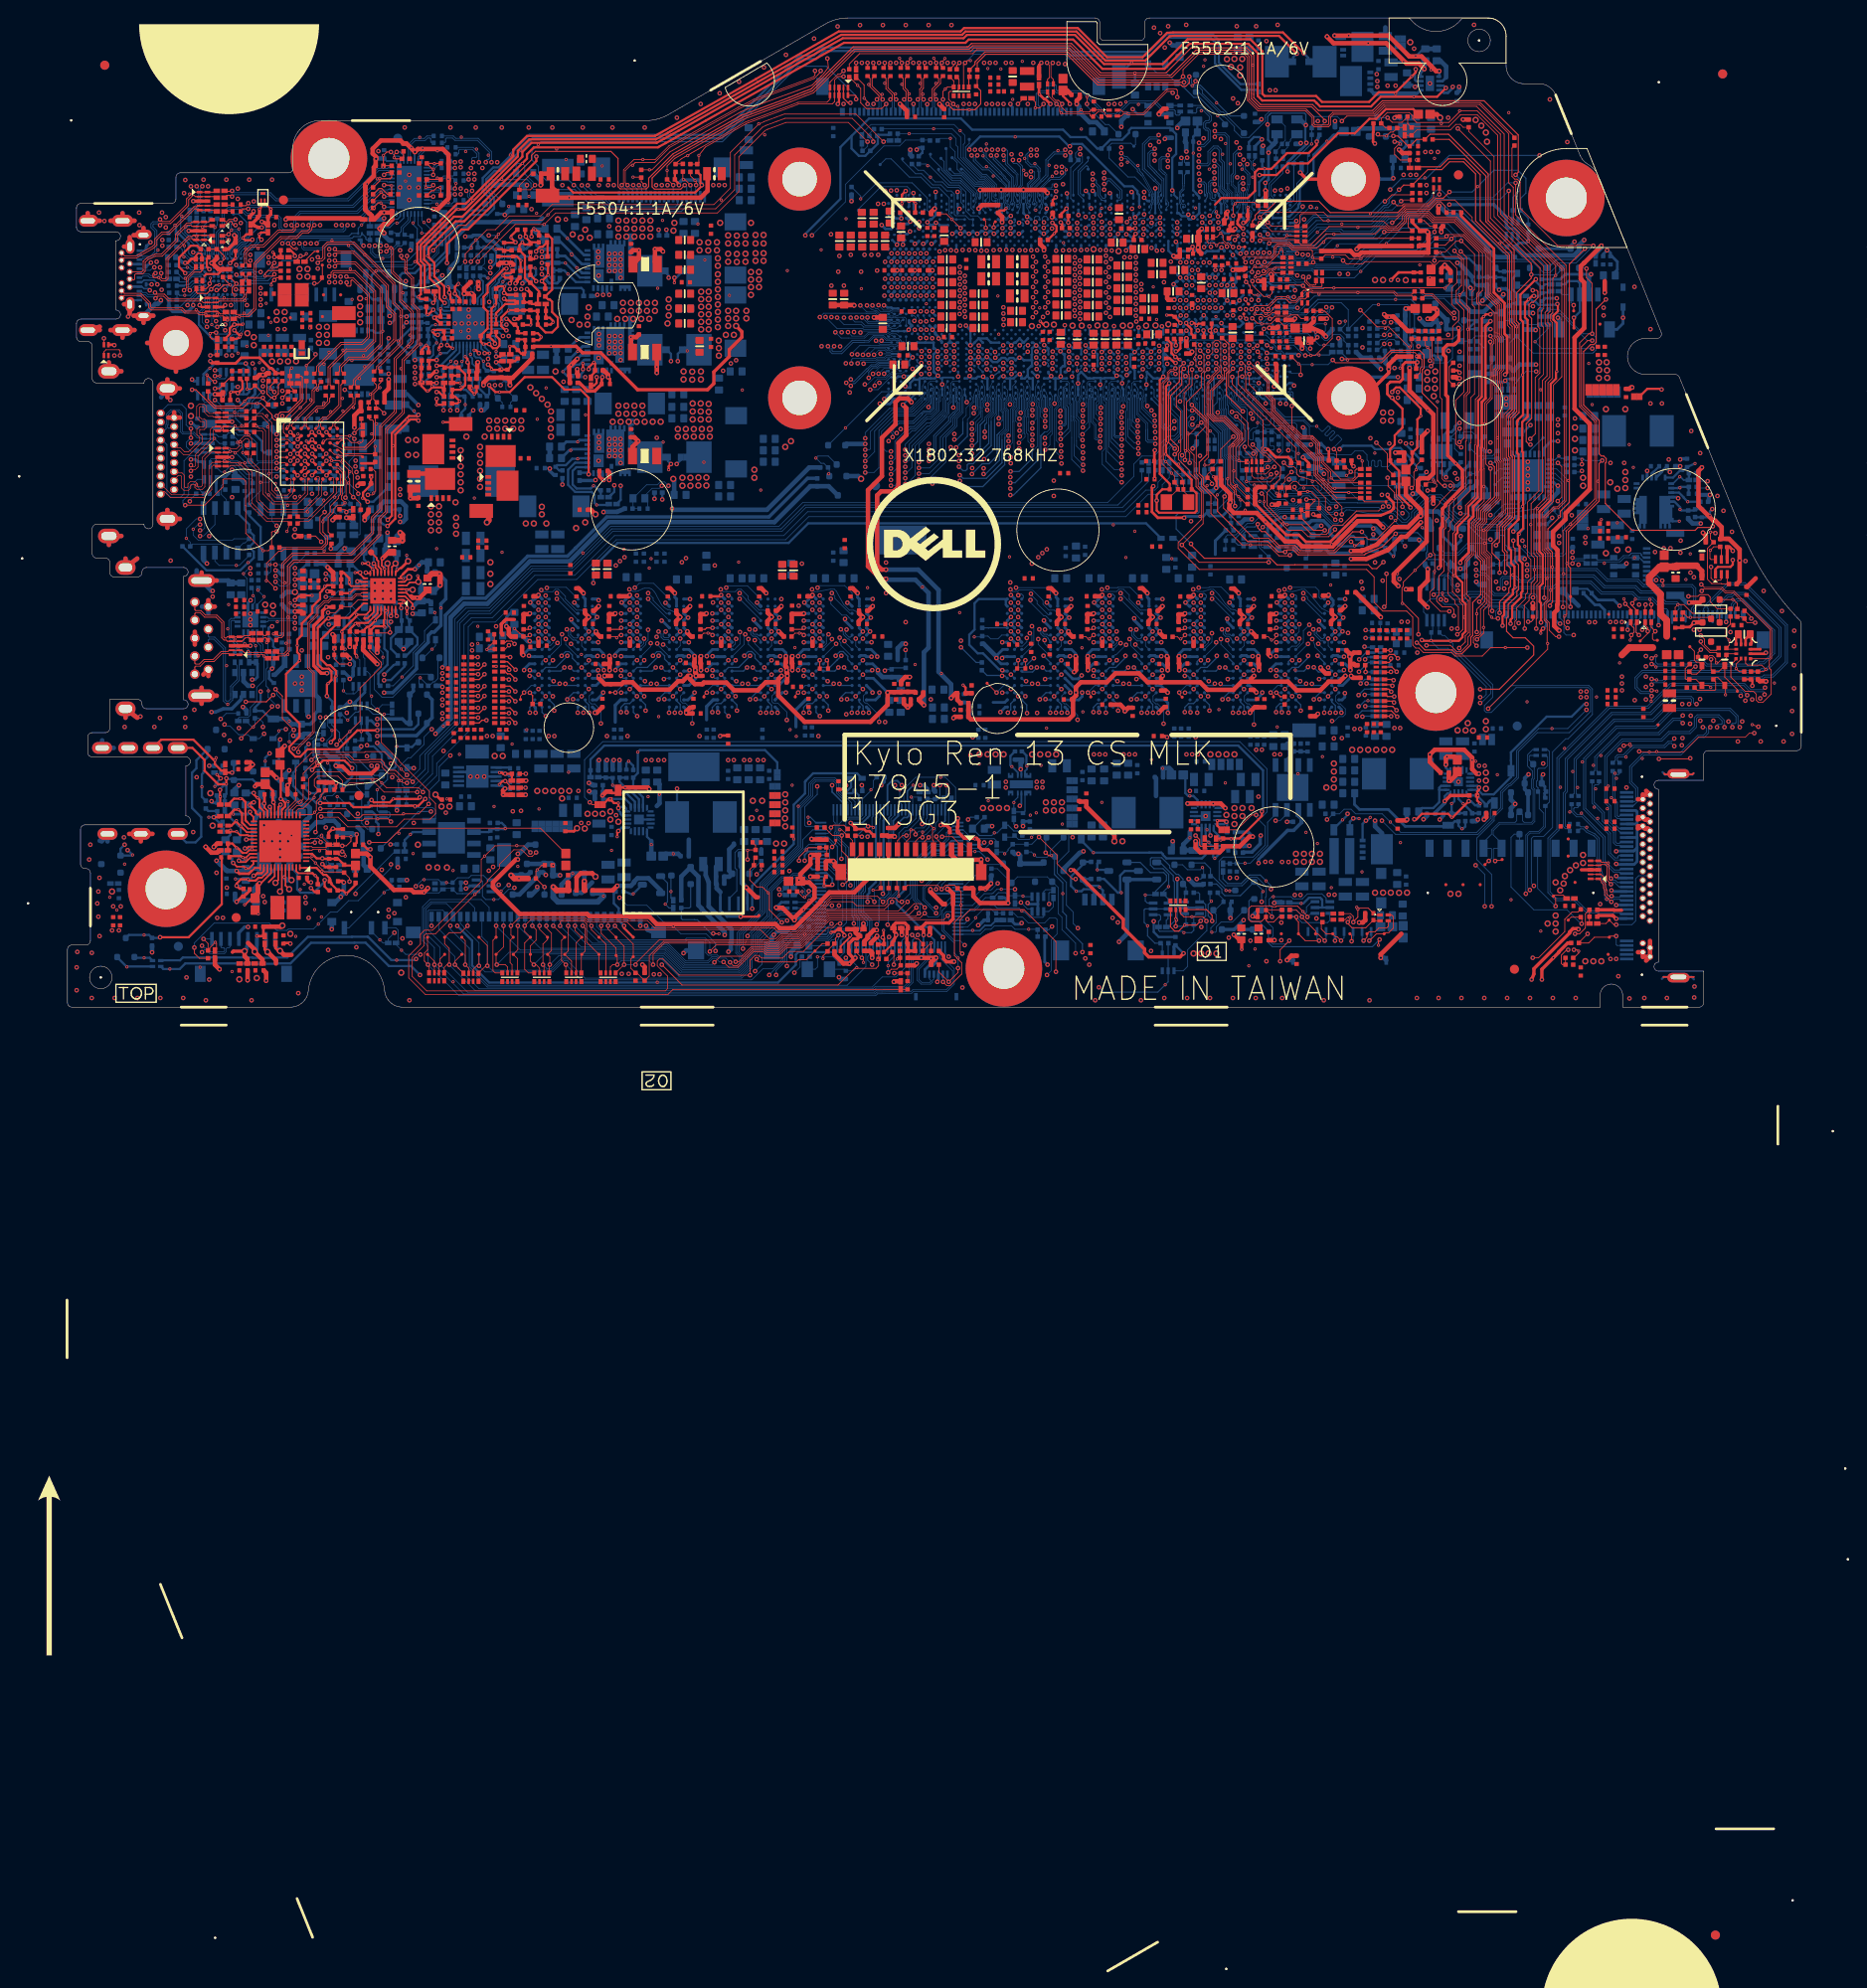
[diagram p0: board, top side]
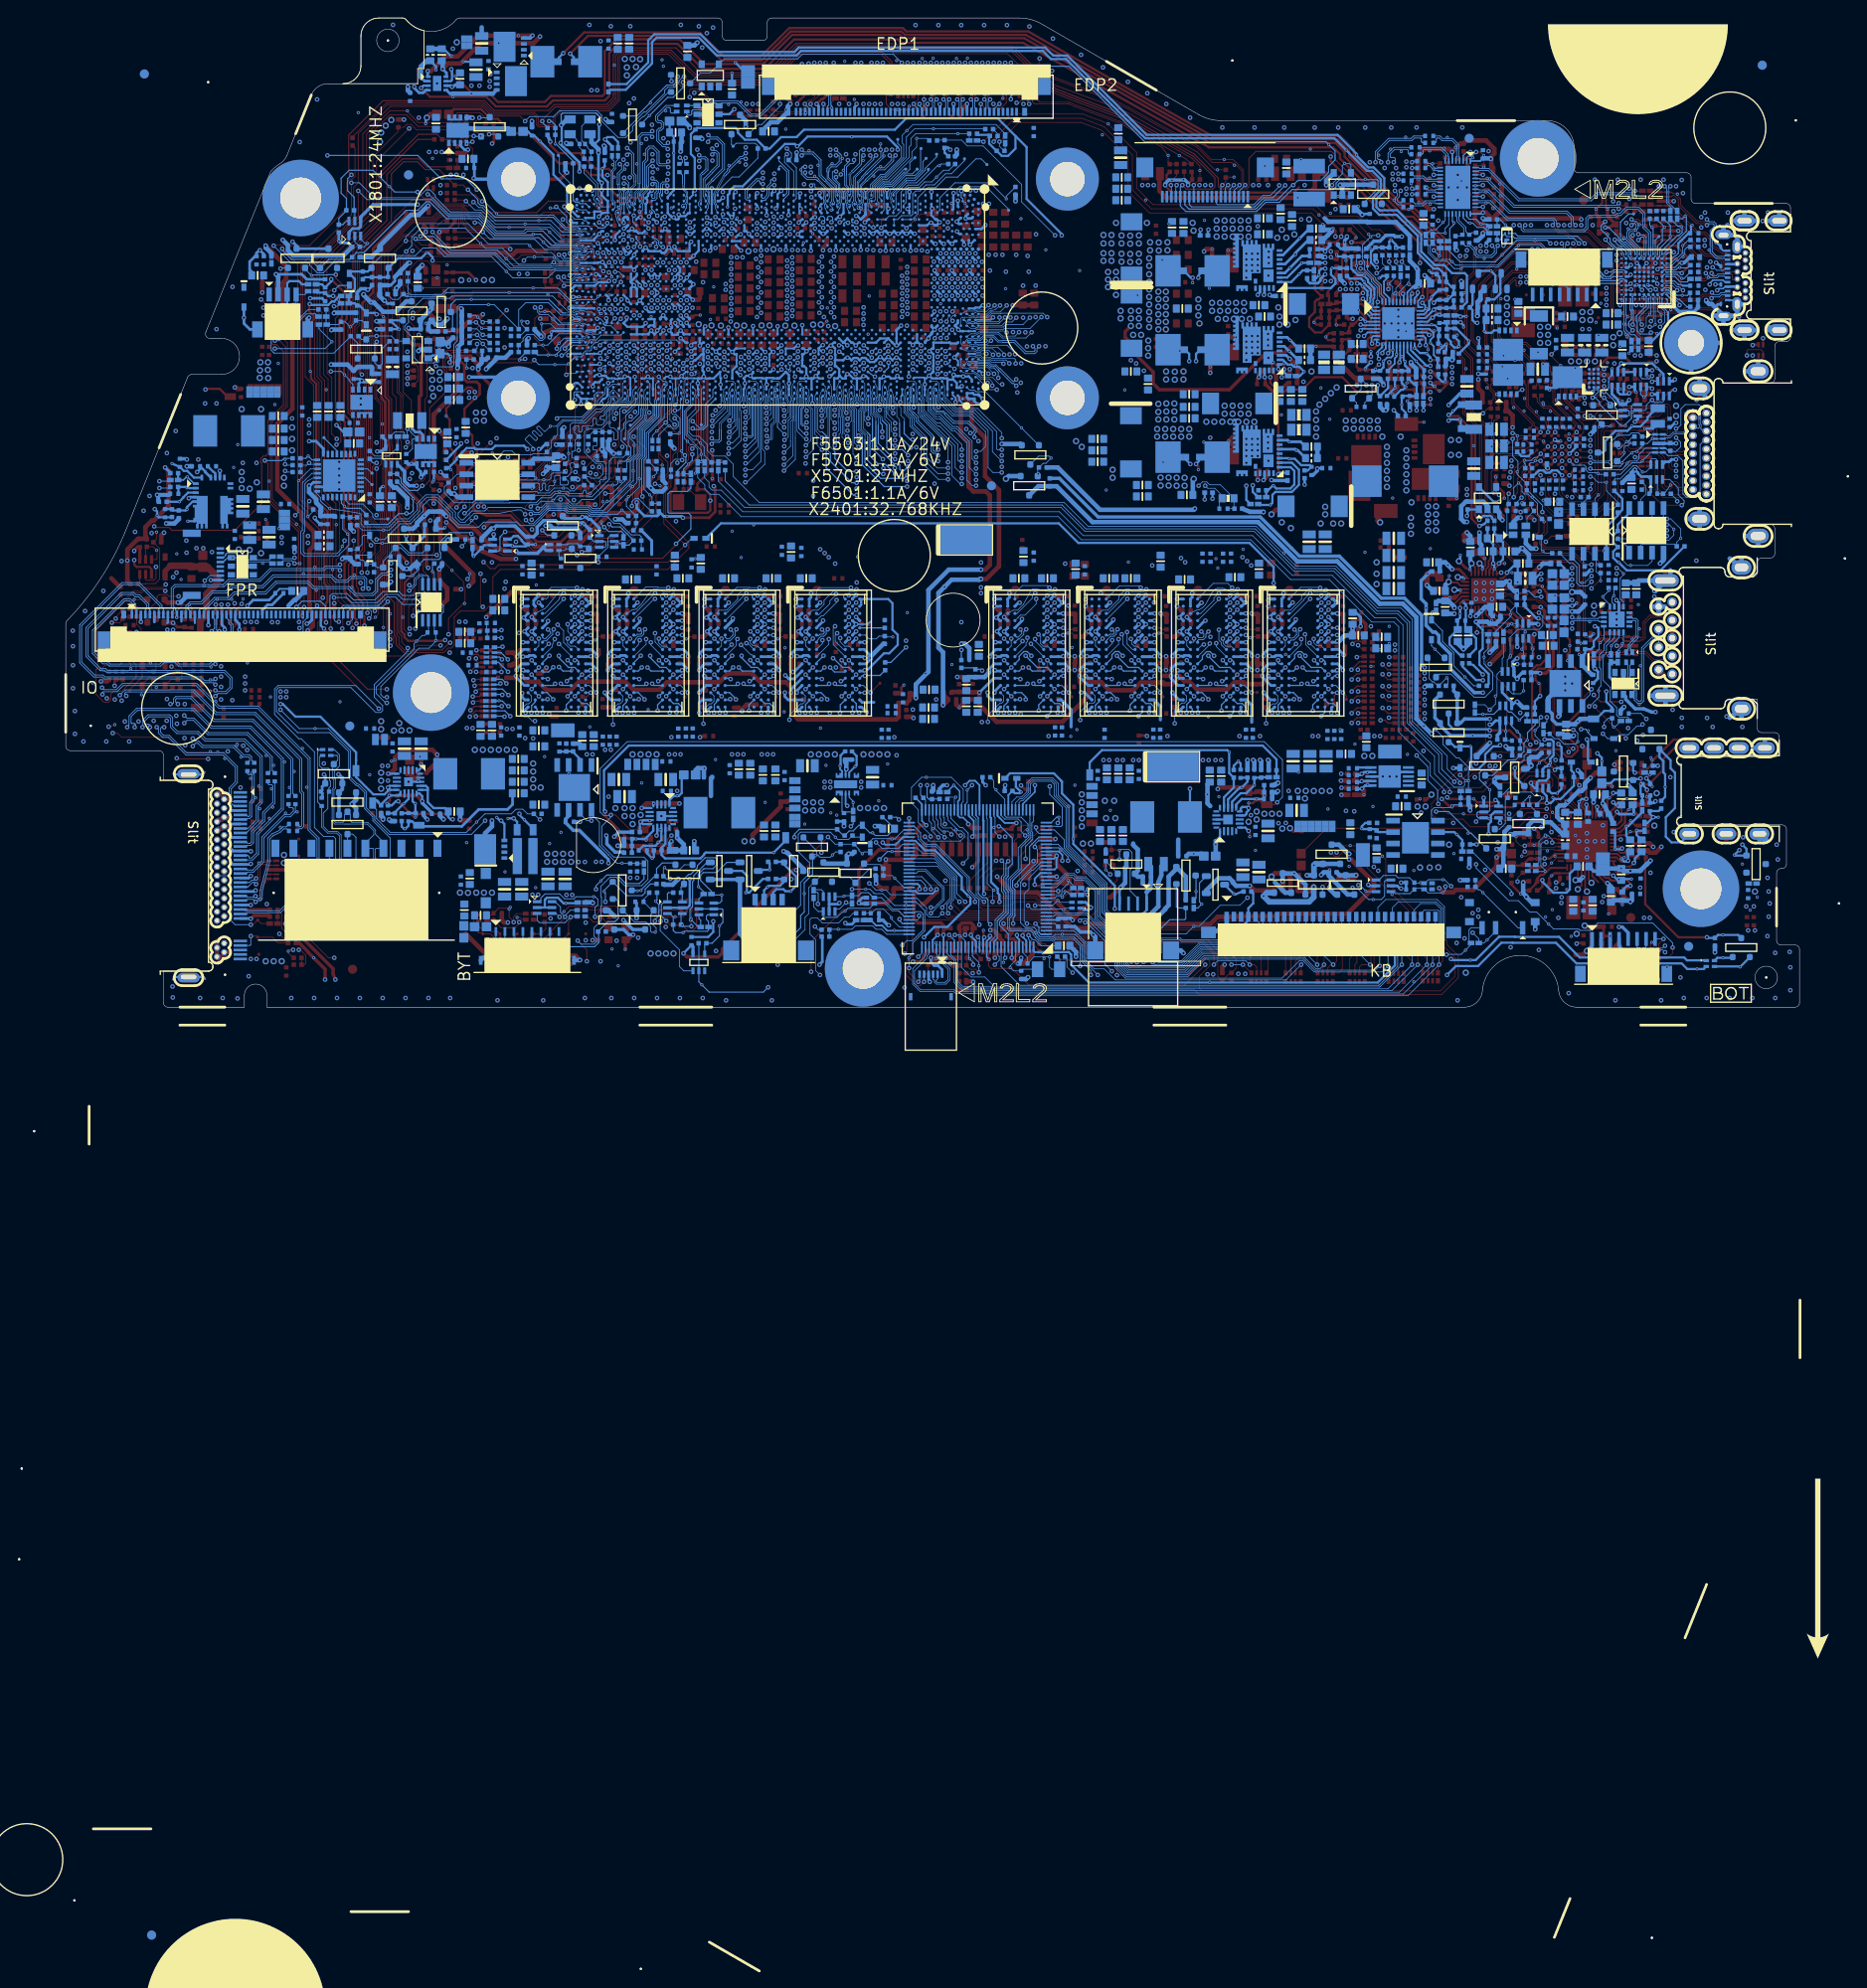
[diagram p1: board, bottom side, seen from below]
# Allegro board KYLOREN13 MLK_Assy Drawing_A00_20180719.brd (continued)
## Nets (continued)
3D3V_S0: C2601.1 C2602.1 C4005.1 C5748.1 D5702.A D9201.A DB1.10 F5502.1 F5504.1 L5701.1 PR4609.1 Q2414.G Q2601.2 Q2601.5 R402.1 R507.1 R1606.2 R1608.2 R1718.1 R1818.2 R1820.1 R2005.1 R2010.1 R2035.1 R2038.1 R2043.1 R2044.1 R2045.1 R2046.1 R2048.1 R2049.1 R2053.1 R2107.1 R2109.1 R2110.1 R2430.1 R2489.1 R2603.1 R2604.1 R2609.1 R2749.1 R2751.1 R2914.1 R4005.1 R5504.1 R5505.2 R5509.1 R5515.1 R5517.1 R5518.1 R5752.2 R6113.1 R6302.1 R6305.1 R6306.1 R6405.1 R6502.1 R7001.1 R9127.1 R9211.1 RN401.1(A) RN401.2(A) RN403.1(A) RN403.2(A) RN1602.3(B) RN1602.4(B) RN1802.1(A) RN1802.2(A) RN1813.1(A) RN1813.2(A) RN1813.3(A) RN1813.4(A) RN2007.3(B) RN2007.4(B) RN2008.3(B) RN2008.4(B) RN2602.1(A) RN2602.2(A) RN2703.1(A) RN2703.2(A) U2601.1 U4001.13 U4001.14
3D3V_S5: AFTP6607.1 C2416.1 C2421.1 C5502.1 C6102.1 C6103.1 C6502.1 C6702.1 C7208.1 D4302.2 EC8921.1 EC8922.1 EC8923.1 EC8924.1 EC8925.1 EC8926.1 ED4304.2 ED4305.2 ED4306.2 FC8938.1 FC8940.1 FC8941.1 FC8942.1 FC8943.1 G5701.2 HALL1.3 IOBD1.38 IOBD1.39 L7101.1 PC5110.1 PC5303.1 PC5314.1 PG4507.2 PG4508.2 PG4509.2 PG4520.2 PG4521.2 PG4526.2 PR4435.1 PR4450.2 PR4472.1 PR4479.1 PR4486.2 PR5104.1 PR5208.1 PR5302.1 PR5310.1 PU5101.15 PU5301.5 PU5301.9 PU5303.5 PU5303.9 Q2416.2 Q2416.5 Q6101.S Q6502.S R506.1 R1703.1 R1910.1 R2003.1 R2050.1 R2406.2 R2416.2 R2434.1 R2442.1 R2446.1 R2456.2 R2465.1 R2496.2 R2514.1 R2520.1 R2522.1 R2607.1 R4004.1 R4031.1 R4042.1 R4304.1 R4378.1 R6101.1 R6111.1 R7215.2 R7224.1 R7243.1 R7424.1 R7427.1 R9126.1 R9143.1 RN2405.5(B) RN2405.6(B) RN2405.7(B) RN2405.8(B) RN7206.1(A) RN7206.2(A) U2502.5 U4001.1 U4001.2 U4008.5 U4302.2 U5501.5 U7201.B1 U7201.H1
3D3V_S5_KBC: C2410.1 C2411.1 C2412.1 C2413.1 C2414.1 C2420.1 C2422.1 C2429.1 DB3.1 EC2402.1 EC2403.1 Q2417.2 Q2417.5 R2407.2 R2414.1 R2415.2 R2424.1 R2443.1 R2446.2 R2452.2 R2480.1 R2608.1 R4032.1 RN2402.1(A) RN2402.2(A) RN2403.1(A) RN2403.2(A) RN2403.3(A) RN2403.4(A) RN2404.1(A) RN2404.2(A) RN2404.3(A) RN2404.4(A) RN2409.1(A) RN2409.2(A) RN2409.3(A) RN2409.4(A) RN2410.1(A) RN2410.2(A) RN2410.3(A) RN2410.4(A) RN2411.1(A) RN2411.2(A) RN2411.3(A) RN2411.4(A) RN2412.1(A) RN2412.2(A) RN2412.3(A) RN2412.4(A) RN2413.1(A) RN2413.2(A) U2401.5 U2401.19 U2401.22 U2401.43 U2401.65 U2401.82 U2401.103 U2401.115
3D3V_S5_PCH: BIOS1.8 C2501.1 C2502.1 R303.1 R405.1 R406.1 R1103.1 R1502.1 R1504.1 R1506.1 R1508.1 R1510.1 R1522.1 R1526.1 R1551.1 R1554.1 R1801.2 R2041.1 R2516.2 R2519.1 R2522.2 R9148.1 R9805.1 RN1601.1(A) RN1601.2(A) RN1601.3(A) RN1601.4(A) RN1807.1(A) RN1807.2(A) RN1807.3(A) RN1807.4(A) RN1811.3(B) RN1811.4(B)
3D3V_SEN_S0: C5515.1 EC5506.1 F5504.2 R5515.2 TCBD1.1
3D3V_SSD: AFTP6304.1 C6304.1 C6305.1 C6306.1 C6307.1 C6308.1 C6317.1 C6318.1 R6302.2 R6303.1 R6306.2 R6307.1 SSD1.2 SSD1.4 SSD1.12 SSD1.14 SSD1.16 SSD1.18 SSD1.70 SSD1.72 SSD1.74
3D3V_TBT: C7210.1 U7201.H2
3D3V_TP_VDD: AFTP6531.1 C6505.1 Q6502.D R6502.2 R6503.1 R6511.1 RN6501.1(A) RN6501.2(A) RN6503.1(A) RN6503.2(A) TP1.8
3D3V_TPAN_VDD: C5516.1 C5517.1 C5518.1 R5508.2 TCBD1.20
3D3V_TPM_VHIO: C9109.1 C9112.1 C9113.1 R9126.2 R9127.2 R9140.1 R9149.2 U9102.8 U9102.22
3D3V_TPM_VSB: C9106.1 C9108.1 R9143.2 U9102.1
3D3V_VCCDSW: C2224.1 CPU1.BR24 CPU1.BT23 R1519.1 R1524.1 R1707.1 R1721.1 R2516.1 RN1701.1(A) RN1701.2(A) U2502.1
3D3V_VCCPRIM: C1113.1 C1123.1 C2202.1 C2203.1 C2204.1 C2205.1 C2206.1 C2207.1 CPU1.BP23 CPU1.BT20 CPU1.BV23 CPU1.BW23 CPU1.CB16 CPU1.CB22 CPU1.CB23 CPU1.CC22 CPU1.CC23 CPU1.CD22 CPU1.CD23 CPU1.CP29 R1103.2 R1701.1 R1731.1
3D3V_VCCPRTC: C2221.1 C2222.1 CPU1.BR23 R2204.2
3D3V_WLAN: AFTP6113.1 C6101.1 C6104.1 C6105.1 C6106.1 FC6101.1 IOBD1.32 IOBD1.33 IOBD1.34 IOBD1.35 IOBD1.36 Q6101.D R6101.2 R6106.1 R6109.1 R6113.2
65982D_BUSPWR: R7204.2 R7236.1 U7201.F10
65982D_DBG_CTL1: RN7202.2(A) U7201.E4
65982D_DBG_CTL2: RN7202.1(A) U7201.D5
65982D_DEBUG1: R7220.2 U7201.L2
65982D_DEBUG2: R7221.2 U7201.K2
65982D_DIG_AUD_N: R7241.2 U7201.K3
65982D_DIG_AUD_P: R7242.2 U7201.L3
65982D_GND: C7212.2 U7201.H7
65982D_GPIO2: R7231.2 U7201.D10
65982D_GPIO3: R7208.2 U7201.G11
65982D_GPIO5: R7213.2 U7201.E10
65982D_GPIO8: R7222.2 R7223.1 U7201.H6
65982D_HPD_CON: R7227.2 U7201.C10
65982D_HRESET: R7202.1 U7201.D6
65982D_I2C_ADDR: R7201.2 U7201.F1
65982D_LDO_1V8A: C7203.2 U7201.K1
65982D_LDO_1V8D: C7202.2 U7201.A2
65982D_LDO_BMC: C7201.2 U7201.E1
65982D_LSRX: TP7202.1 U7201.K4
65982D_LSTX: R7237.2 U7201.L4
65982D_MRESET: R7214.2 U7201.E11
65982D_RESET_N: R7229.1 U7201.F11
65982D_ROSC: R7206.1 U7201.G2
65982D_SBU1_R: TP7203.1 U7201.K8
65982D_SBU2_R: TP7204.1 U7201.L8
65982D_UART_RX: R7244.2 U7201.E2 U7201.F2
+DC_IN: C4301.1 C4302.1 EL4301.2 EL4302.2 PU4301.1 PU4301.2 PU4301.3 Q4305.2 R4307.1 R4376.1
+DC_IN_C: AFTP4303.1 AFTP4305.1 AFTP4316.1 D4301.K DCIN1.6 DCIN1.7 DCIN1.8 EC4301.1 EC4302.1 EC4312.1 EC4313.1 EL4301.1 EL4302.1
+RTC_VCC: D2501.2 IOBD1.41 Q2505.G R2504.1
+SDC_IN: C4343.1 C7401.1 PC4401.1 PG4401.1 PR4401.1 PU4302.1 PU4302.2 PU4302.3 PU4401.16 Q4348.S Q7401.S R4318.1 R4370.1 R7404.1 R7406.1 R7411.1 U7418.1 U7418.2 U7418.3
+SDC_IN_SW: C4343.2 PU4302.4 R4318.2 R4333.1 R4368.1
+SDC_IN_SW_R1: Q4349.6 R4333.2
+V_VREF_PATH1: C1202.2 R1203.1
+V_VREF_PATH2: C1302.2 R1303.1
A_ZQ_RAM1: R1205.1 RAM1.F9
A_ZQ_RAM2: R1234.1 RAM2.F9
A_ZQ_RAM3: R1204.1 RAM3.F9
A_ZQ_RAM4: R1201.1 RAM4.F9
AC_DIS: Q4304.B Q4349.5 R4303.1 U2401.69
AC_IN#: D1701.K D4305.K PQ4415.6
AC_IN#_G: R4376.2 R4377.1 U4302.5
AC_PRESENT: CPU1.BU35 D1701.A EC1707.1 Q1702.6 RN1701.4(B)
ACOK#: PQ4415.2 PQ4415.3 PR4427.2
AD_IA: PC4432.1 PR4412.2 R2421.2 R2423.1
AD_OFF_L: Q4304.C Q4305.1
AD_OFF_R: C4301.2 PU4301.4 Q4305.3 R4307.2 R4308.1
ALERT#: R2603.2 U2601.6
ALWON: R4009.2 U2401.121
AMBER_LED_BAT: Q6402.C R6401.1
AUD_AGND: C2721.2 C2727.2 C2730.2 C2731.2 C2734.2 C2735.2 C2737.2 C2740.2 C2741.2 C2909.2 EC2709.1 EC2710.1 EC2711.1 EC2712.1 EC2713.1 EC2714.1 EC2905.2 EC2906.2 EC2907.2 EC2908.2 HPMIC1.MS R2739.1 R2747.2 R2905.2 U2701.22 U2701.37
AUD_HP1_JACK_L1: EC2907.1 R2907.2 R2911.1 R2922.2
AUD_HP1_JACK_L1_R: ED2903.2 HPMIC1.1 R2911.2
AUD_HP1_JACK_R1: EC2908.1 R2909.2 R2912.1 R2921.2
AUD_HP1_JACK_R1_R: ED2901.1 HPMIC1.2 R2912.2
AUD_HPJD_N: C2909.1 R2741.1 R2923.2
AUD_HPOUT_L: R2907.1 U2701.27
AUD_HPOUT_R: R2909.1 U2701.26
AUD_PC_BEEP_C: C2726.1 D2702.3 R2745.1
AUD_PC_BEEP_R: C2726.2 U2701.34
AUD_RING: R2908.1 RN2901.3(B) U2701.30
AUD_SELEEVE: R2910.1 RN2901.4(B) U2701.31
AUD_SENSE_A: C2746.1 R2741.2 R2742.2 U2701.48
AUD_SPK_L+: EC2904.1 ER2901.1 U2701.42
AUD_SPK_L+_C: AFTP2902.1 ER2901.2 SPK1.1
AUD_SPK_L-: EC2903.1 ER2902.1 U2701.43
AUD_SPK_L-_C: AFTP2901.1 ER2902.2 SPK1.2
AUD_SPK_R+: EC2902.1 ER2903.1 U2701.45
AUD_SPK_R+_C: AFTP2904.1 ER2903.2 SPK1.3
AUD_SPK_R-: EC2901.1 ER2904.1 U2701.44
AUD_SPK_R-_C: AFTP2903.1 ER2904.2 SPK1.4
AUD_VREF: C2737.1 U2701.38
AUDIO_47: R2744.2 U2701.47
AUX_EN_WOWL: CPU1.BT30 R2405.2 R6110.1
AUX_EN_WOWL_R: Q6102.G R6110.2
AUX_MODE: R2728.2 R2754.2 U2701.33
B_ZQ_RAM1: R1304.1 RAM5.F9
B_ZQ_RAM2: R1301.1 RAM6.F9
B_ZQ_RAM3: R1306.1 RAM7.F9
B_ZQ_RAM4: R1305.1 RAM8.F9
BAT1_LED#: Q2416.4 R2498.2 RN2405.2(A) U2401.106
BAT2_LED#: Q2416.1 R2495.1 RN2405.1(A) U2401.1
BAT_AMBER: ED6401.2 LED1.2 R6401.2
BAT_WHITE: ED6401.1 LED1.3 R6402.2
BATT_WHITE_LED#: Q2416.6 Q6403.D Q6404.4 R2495.2 R6422.2
BATT_WHITE_LED_R#: Q6401.B Q6404.3 R6422.1
BEEP: RN2702.1(A) U2401.45
BKLT_CTRL: D5502.3 R5502.1 R5545.2 RN5502.5(B)
BKLT_IN_EC: R2440.1 U2401.67
BLON_OUT_C: LCD1.23 R5544.1 RN5502.7(B)
BLUETOOTH_EN: AFTP6112.1 CPU1.CP14 D6101.K IOBD1.48 R2109.2 R6107.2
BLUETOOTH_EN_R: D6101.A R6106.2 R6107.1
BOARD_ID: C2408.1 R2443.2 R2444.1 R2494.1 U2401.111
BOARD_ID1: CPU1.CG12 R2009.1 R2010.2
BOARD_ID2: CPU1.CM14 R2005.2 R2008.1
BPM_CPU_N0: CPU1.U1 TP302.1
BPM_CPU_N1: CPU1.U2 TP303.1
BPM_CPU_N2: CPU1.U3 TP304.1
BPM_CPU_N3: CPU1.U4 TP307.1
BREATH_LED#: IOBD1.43 U2401.70
BT+: AFTP4312.1 AFTP4313.1 AFTP4314.1 BATT1.1 BATT1.2 BATT1.3 D4304.K EC4307.1 EC4308.1 PR4478.2 PR4495.2 PU4412.5 PU4412.6 PU4412.7 PU4412.8
BT_USB20_CON_N: AFTP6111.1 EL6603.4 IOBD1.19
BT_USB20_CON_P: AFTP6114.1 EL6603.1 IOBD1.20
BT_USB20_N: CPU1.CC3 EL6603.3
BT_USB20_P: CPU1.CC4 EL6603.2
CAD_SNK: R7118.2 U7101.29
CAP_LED: AFTP6538.1 KBBD1.4 R6513.2
CAP_LED#: Q2414.S R2489.2 U2401.93
CAP_LED#_R: Q2414.D R6512.1
CAP_LED_Q: Q6505.C R6513.1
CAP_LED_R#: Q6505.B R6512.2
CARD1_USB20_N: CPU1.CG8 IOBD1.17
CARD1_USB20_P: CPU1.CG9 IOBD1.16
CARD_CLKREQ_CPU_N: CPU1.CE31 RN1813.7(B)
CATERR#_CPU: CPU1.AA4 TP301.1
CBN: C2739.1 U2701.24
CBP: C2739.2 U2701.23
CCD_USB20_CON_N: ED5501.6 EL5501.1 LCD1.43
CCD_USB20_CON_P: ED5501.1 EL5501.4 LCD1.42
CCD_USB20_N: CPU1.CC1 EL5501.2
CCD_USB20_P: CPU1.CC2 EL5501.3
CFG3: CPU1.R3 R1517.1
CFG4: CPU1.J4 R1518.1
CFG_RCOMP: CPU1.AB5 R601.2
CHG_AMBER_LED#: Q2416.3 Q6404.1 R2498.1 R6421.1
CHG_AMBER_LED_R#: Q6402.B Q6404.6 R6421.2
CHGR_PSYS_IMVP: PR4413.1 PR4614.1 PU4401.30 PU4601.1
CLK_PCIE_PEG_REQ0_N: CPU1.CF32 RN1813.6(B)
CLK_PCIE_PEG_REQ2_N: CPU1.CF30 RN1802.4(B)
CLK_PCIE_PEG_REQ5_N: CPU1.CF31 RN1813.5(B)
CLK_TP_SIO: EC6501.1 RN6501.4(B) RN6502.1(A) U2401.78
CLKRUN#: CPU1.BY30 R1818.1
CMP_VIN0_R: C2612.1 C2613.1 R2494.2 R2608.2 R2609.2 R2610.1 U2401.20
CMP_VOUT0: R2602.2 R2607.2 R2615.2 U2401.85
CNV_RGI_DT: CPU1.CG19 R1515.2 R1516.1
CNV_WT_RCOMP: CPU1.CP32 CPU1.CR32 R2101.2
CPU_D4_TP: CPU1.CG23 TP1804.1
CPU_D6_TP: CPU1.CG20 TP1806.1
CPU_DP1_CTRL_CLK: CPU1.CC8 RN401.3(B)
CPU_DP1_CTRL_DATA: CPU1.CC9 RN401.4(B)
CPU_DP2_CTRL_CLK: CPU1.CH4 RN403.4(B)
CPU_DP2_CTRL_DATA: CPU1.CH3 RN403.3(B)
CPU_DP_HPD_P: Q401.2 Q401.3 R406.2
CPU_I2C_SCL_ISH: R2020.2 TCBD1.4 U7001.1
CPU_I2C_SCL_ISH0: CPU1.CH20 R2020.1 RN2007.2(A)
CPU_I2C_SCL_ISH1: CPU1.CJ22 RN2008.1(A)
CPU_I2C_SCL_P0: CPU1.CN11 EC6503.1 Q6504.1 R6505.1
CPU_I2C_SCL_P1: CPU1.CJ12 R5517.2 R5521.2 U5504.4 U5504.7
CPU_I2C_SCL_TP: AFTP6534.1 Q6504.6 R6505.2 RN6503.3(B) TP1.6
CPU_I2C_SCL_TS: R5521.1 TCBD1.18
CPU_I2C_SDA_ISH: R2021.2 TCBD1.3 U7001.4
CPU_I2C_SDA_ISH0: CPU1.CK22 R2021.1 RN2007.1(A)
CPU_I2C_SDA_ISH1: CPU1.CH22 RN2008.2(A)
CPU_I2C_SDA_P0: CPU1.CM11 EC6504.1 Q6504.4 R6506.1
CPU_I2C_SDA_P1: CPU1.CK12 R5518.2 R5522.2 U5504.5 U5504.6
CPU_I2C_SDA_TP: AFTP6535.1 Q6504.3 R6506.2 RN6503.4(B) TP1.7
CPU_I2C_SDA_TS: R5522.1 TCBD1.17
CPU_POPIRCOMP: CPU1.BP27 R304.2
CPU_SMB_ALERT#: CPU1.CJ15 R1551.2 R1552.1
CPU_SMB_ALERT#_P0: CPU1.CG15 R1504.2 R1505.1
CPU_SMB_ALERT#_P1: CPU1.CC34 R1555.1 R1801.1
CPU_SMB_SCL: CPU1.CK14 RN1807.7(B)
CPU_SMB_SCL_P0: CPU1.CH14 RN1807.5(B)
CPU_SMB_SCL_P1: CPU1.CN15 Q2601.3 R2459.2 RN1811.2(A)
CPU_SMB_SCL_THM: C2608.1 Q2601.4 RN2602.4(B) U2601.8
CPU_SMB_SDA: CPU1.CH15 RN1807.8(B)
CPU_SMB_SDA_P0: CPU1.CF15 RN1807.6(B)
CPU_SMB_SDA_P1: CPU1.CM15 Q2601.6 R2447.2 RN1811.1(A)
CPU_SMB_SDA_THM: C2609.1 Q2601.1 RN2602.3(B) U2601.7
CPVEE: C2741.1 U2701.25
CTL2: R3406.2 U3401.7
CTL3: R3402.2 U3401.8
DAT_TP_SIO: EC6502.1 RN6501.3(B) RN6502.2(A) U2401.79
DBC_EN_R: LCD1.6 R5503.1
DBC_PANEL_EN: CPU1.CA31 R2043.2 R5503.2
DC_IN_OFF: Q4349.3 R4369.2
DCBATOUT: EC4534.1 EC8908.1 EC8909.1 EC8910.1 EC8911.1 EC8912.1 EC8913.1 EC8914.1 EC8915.1 EC8916.1 EC8917.1 EC8943.1 EC8944.1 EC8945.1 EC8946.1 EC8947.1 EC8948.1 EC8949.1 EC8950.1 F5503.1 FC8906.1 FC8907.1 FC8914.1 FC8916.1 FC8917.1 FC8919.1 FC8920.1 PC4406.1 PC4407.1 PC4408.1 PC4409.1 PC4410.1 PC4411.1 PC4412.1 PC4413.1 PC4414.1 PC4418.1 PC4434.1 PC4437.1 PC4439.1 PD4407.A PG4405.2 PG4501.1 PG4502.1 PG4503.1 PG4504.1 PG4505.1 PG4506.1 PG4515.1 PG4516.1 PG4517.1 PG4518.1 PG5002.2 PG5003.2 PG5105.1 PG5110.1 PG5210.1 PG5212.1 PG5214.1 PL4702.1 PL4703.1 PL4803.1 PL4804.1 PR4407.1 PR4477.2 PR4509.1 PR4511.1 PR4612.1 PT4805.1 PU4401.3 PU4405.5 PU4405.6 PU4405.7 PU4405.8 R5511.1
DCBATOUT_CAMERA: C5521.1 C5522.1 LCD1.49 LCD1.50 R5511.2
DDR_VREF_S3: PC5123.1 PU5102.6
DMIC_SCL_CODEC: C2738.1 FC2701.1 R2721.1 RN5503.4(B)
DMIC_SCL_CODEC_R: R2721.2 U2701.5
DMIC_SCL_CON: EC5504.1 LCD1.46 RN5503.1(A) RN5504.2(A)
DMIC_SCL_PCH: CPU1.CP24 RN5504.3(B)
DMIC_SDA_CODEC: R2738.1 RN5503.3(B)
DMIC_SDA_CODEC_R: R2738.2 U2701.4
DMIC_SDA_CON: EC5503.1 LCD1.47 RN5503.2(A) RN5504.1(A)
DMIC_SDA_PCH: CPU1.CN24 RN5504.4(B)
DP1_AUX_ALS_N: C5741.2 U5701.C8
DP1_AUX_ALS_P: C5740.2 U5701.C7
DP1_AUX_C_N: C5739.2 C5741.1 R5763.1
DP1_AUX_C_P: C5738.2 C5740.1 R5752.1 R5762.1
DP1_AUX_CPU_N: C5739.1 CPU1.AC7
DP1_AUX_CPU_P: C5738.1 CPU1.AC6
DP1_HPD_CPU: Q401.5 R404.2 R7149.2 R7227.1
DP1_HPD_CPU_R: CPU1.CM6 Q401.6 R403.1 R404.1 R405.2
DP2_AUX_C2_N: R7239.2 U7201.J2
DP2_AUX_C2_P: R7238.2 U7201.J1
DP2_AUX_C_N: C7102.1 R7101.2 U7101.25
DP2_AUX_C_P: C7101.1 R7102.2 U7101.24
DP2_AUX_CPU_N: C7102.2 CPU1.AD4
DP2_AUX_CPU_P: C7101.2 CPU1.AD3
DP2_DDI_TX_C_N0: C7113.2 U7101.10
DP2_DDI_TX_C_N1: C7107.2 U7101.13
DP2_DDI_TX_C_N2: C7108.2 U7101.16
DP2_DDI_TX_C_N3: C7110.2 U7101.19
DP2_DDI_TX_C_P0: C7112.2 U7101.9
DP2_DDI_TX_C_P1: C7114.2 U7101.12
DP2_DDI_TX_C_P2: C7109.2 U7101.15
DP2_DDI_TX_C_P3: C7111.2 U7101.18
DP2_DDI_TX_N0: C7113.1 CPU1.AC4
DP2_DDI_TX_N1: C7107.1 CPU1.AC1
DP2_DDI_TX_N2: C7108.1 CPU1.AE4
DP2_DDI_TX_N3: C7110.1 CPU1.AE1
DP2_DDI_TX_P0: C7112.1 CPU1.AC3
DP2_DDI_TX_P1: C7114.1 CPU1.AC2
DP2_DDI_TX_P2: C7109.1 CPU1.AE3
DP2_DDI_TX_P3: C7111.1 CPU1.AE2
DPEQ0_A1: R7171.2 R7172.1 U7101.14
DPEQ1: R7147.2 R7170.1 U7101.2
EC_AGND: C2407.2 C2408.2 C2422.2 C2435.2 C2441.2 R2441.2 R2444.2 R2445.2 U2401.112
EDP_AUX_CON_N: C5511.1 LCD1.8
EDP_AUX_CON_P: C5510.1 LCD1.7
EDP_AUX_CPU_N: C5511.2 CPU1.AH4
EDP_AUX_CPU_P: C5510.2 CPU1.AH3
EDP_HPD_CON: LCD1.21 R5506.1 RN5502.8(B)
EDP_HPD_CPU: CPU1.CM7 R5506.2
EDP_RCOMP_CPU: CPU1.AM6 R401.2
EDP_TX_CON_N0: C5506.1 LCD1.19
EDP_TX_CON_N1: C5501.1 LCD1.16
EDP_TX_CON_N2: C5533.1 LCD1.13
EDP_TX_CON_N3: C5532.1 LCD1.10
EDP_TX_CON_P0: C5509.1 LCD1.20
EDP_TX_CON_P1: C5504.1 LCD1.17
EDP_TX_CON_P2: C5519.1 LCD1.14
EDP_TX_CON_P3: C5531.1 LCD1.11
EDP_TX_CPU_N0: C5506.2 CPU1.AG4
EDP_TX_CPU_N1: C5501.2 CPU1.AG2
EDP_TX_CPU_N2: C5533.2 CPU1.AJ4
EDP_TX_CPU_N3: C5532.2 CPU1.AJ2
EDP_TX_CPU_P0: C5509.2 CPU1.AG3
EDP_TX_CPU_P1: C5504.2 CPU1.AG1
EDP_TX_CPU_P2: C5519.2 CPU1.AJ3
EDP_TX_CPU_P3: C5531.2 CPU1.AJ1
EDP_VDD_EN: CPU1.CG11 D5501.1
EMMC_RCOMP: CPU1.CK15 R2108.1
EQ0: R7142.2 R7143.1 U7101.38
EQ1: R7140.2 R7141.1 U7101.35
ESPI_ALERT#: CPU1.BV28 R1821.2
ESPI_CLK: DB1.2 EC1801.1 R1805.2 U2401.57
ESPI_CPU_CLK_R: CPU1.BV32 R1805.1
ESPI_CPU_IO0: DB1.9 RN1806.1(A) U2401.59
ESPI_CPU_IO0_R: CPU1.CA29 RN1806.8(B)
ESPI_CPU_IO1: DB1.8 RN1806.4(A) U2401.60
ESPI_CPU_IO1_R: CPU1.BY29 RN1806.5(B)
ESPI_CPU_IO2: DB1.7 RN1806.3(A) U2401.61
ESPI_CPU_IO2_R: CPU1.BY27 RN1806.6(B)
ESPI_CPU_IO3: DB1.6 RN1806.2(A) U2401.62
ESPI_CPU_IO3_R: CPU1.BV27 RN1806.7(B)
ESPI_CS#: CPU1.CA28 DB1.5 U2401.58
ESPI_RESET#: CPU1.CA27 DB1.4 U2401.53
EXT_PWR_GATE#: CPU1.CC37 R1731.2
FAN1_PWM: EC2601.1 R2614.1 U2401.47
FAN1_TACH: D2403.A R2430.2 U2401.40
FAN_PWM1_C: AFTP2602.1 FAN1.4 R2614.2
FAN_TACH1: D2403.K EC2602.1 R2613.1
FAN_TACH1_C: AFTP2601.1 FAN1.3 R2613.2
FFS_INT1: CPU1.CG22 R7007.1
FFS_INT2: CPU1.CH12 R2044.2 R7008.1
FP1_USB20_CON_N: ED9202.6 FPR1.3 R9209.2
FP1_USB20_CON_P: ED9202.1 FPR1.4 R9210.2
FP1_USB20_N: CPU1.CG5 R9209.1
FP1_USB20_P: CPU1.CG6 R9210.1
FPR_SCAN#: FPR1.7 R2465.2 U2401.42
GPD11/LANPHYPC: CPU1.BU34 R1703.2
GPD_7: CPU1.BV35 R1524.2 R1525.1
GPP_B22_GSPI1_MOSI: CPU1.CA30 R1553.1
GPP_E0/SATAXPCIE0/SATAGP0: CPU1.CN8 RN1602.1(A)
GPP_E1/SATAXPCIE1/SATAGP1: CPU1.CM10 RN1602.2(A)
GPP_E3/CPU_GP0: CPU1.CE9 TP308.1
GPP_E23_STRAP: CPU1.CN4 TP402.1
GPP_H17_STRAP: CPU1.CP26 R1527.1
GPP_H21: CPU1.CF25 R1522.2 R1523.1
GPP_H23: CPU1.CM26 R1526.2 R1528.1
GPPC_H18_BOOTMPC: CPU1.CN27 R2119.1
GPPC_H18_VCCIO_LPM: R2119.2 R4040.2 R4042.2 U4008.2
GPU_THM_SMBCLK: R2459.1 U2401.12
GPU_THM_SMBDAT: R2447.1 U2401.11
GSEN2_INT1: R7005.2 R7007.2 U7001.12
GSEN2_INT1_C: R2001.2 R7005.1
GSEN2_INT1_ISH: CPU1.CA36 R2001.1
GSEN2_INT2: R7006.2 R7008.2 U7001.11
GSEN2_INT2_C: R2002.2 R7006.1
GSEN2_INT2_ISH: CPU1.CA35 R2002.1
GSEN_INT1: CPU1.BW34 TCBD1.5
GSEN_INT2: CPU1.CA37 TCBD1.6
GSENSOR_CS: R7004.1 U7001.2
GSENSOR_SDO: R7002.2 R7003.2 U7001.3
GYRO_DRDY: R2028.2 TCBD1.8
GYRO_DRDY_ISH: CPU1.BW37 R2028.1 R2051.1 R2052.2
GYRO_INT: R5524.1 TCBD1.7
GYRO_INT_C: R2027.2 R5524.2
GYRO_INT_ISH: CPU1.CA34 R2027.1
H_CPUPWRGD: CPU1.AR2 ED301.2 R1714.2
H_PECI: C2405.1 R2437.1 U2401.94
HDA_BITCLK_CODEC: EC1901.2 EC2701.1 R1920.1 U2701.14
HDA_BITCLK_CPU: CPU1.BN37 R1920.2
HDA_RST_N_CPU: CPU1.BL35 TP1903.1
HDA_SDIN0_CODEC: R2730.2 U2701.16
HDA_SDIN0_CPU: CPU1.BN35 R2730.1
HDA_SDOUT_CODEC: EC1903.1 R1921.1 U2701.17
HDA_SDOUT_CPU: CPU1.BN36 R1512.2 R1909.2 R1921.2
HDA_SPKR_R: D2702.2 RN2702.3(B)
HDA_SYNC_CODEC: R1908.1 U2701.15
HDA_SYNC_CPU: CPU1.BN34 R1908.2
HDMI_BOM_OPTION: R5703.2 U5701.C4 U5701.C5 U5701.D3 U5701.E3
HDMI_CEC: R5708.2 R5761.1 U5701.F2
HDMI_CEC_CON: ED5703.5 ED5703.6 HDMI1.13 R5761.2
HDMI_CEC_R: D5702.K R5708.1
HDMI_DDI_TX_ALS_N0: C5731.2 U5701.A7
HDMI_DDI_TX_ALS_N1: C5734.2 U5701.A5
HDMI_DDI_TX_ALS_N2: C5727.2 U5701.A3
HDMI_DDI_TX_ALS_N3: C5733.2 U5701.A1
HDMI_DDI_TX_ALS_P0: C5737.2 U5701.A8
HDMI_DDI_TX_ALS_P1: C5732.2 U5701.A6
HDMI_DDI_TX_ALS_P2: C5728.2 U5701.A4
HDMI_DDI_TX_ALS_P3: C5735.2 U5701.A2
HDMI_DDI_TX_CMC_N0: R5770.1 U5701.H3
HDMI_DDI_TX_CMC_N1: R5768.1 U5701.H5
HDMI_DDI_TX_CMC_N2: R5766.1 U5701.H7
HDMI_DDI_TX_CMC_N3: C5724.2 R5772.1 U5701.H1
HDMI_DDI_TX_CMC_P0: R5769.1 U5701.H4
HDMI_DDI_TX_CMC_P1: R5767.1 U5701.H6
HDMI_DDI_TX_CMC_P2: R5765.1 U5701.H8
HDMI_DDI_TX_CMC_P3: C5724.1 R5771.1 U5701.H2
HDMI_DDI_TX_CON_N0: ED5702.2 ED5702.9 HDMI1.9 R5770.2
HDMI_DDI_TX_CON_N1: ED5701.1 ED5701.10 HDMI1.6 R5768.2
HDMI_DDI_TX_CON_N2: ED5701.4 ED5701.7 HDMI1.3 R5766.2
HDMI_DDI_TX_CON_N3: ED5702.5 ED5702.6 HDMI1.12 R5772.2
HDMI_DDI_TX_CON_P0: ED5702.1 ED5702.10 HDMI1.7 R5769.2
HDMI_DDI_TX_CON_P1: ED5701.2 ED5701.9 HDMI1.4 R5767.2
HDMI_DDI_TX_CON_P2: ED5701.5 ED5701.6 HDMI1.1 R5765.2
HDMI_DDI_TX_CON_P3: ED5702.4 ED5702.7 HDMI1.10 R5771.2
HDMI_DDI_TX_N0: C5731.1 CPU1.AL5
HDMI_DDI_TX_N1: C5734.1 CPU1.AJ5
HDMI_DDI_TX_N2: C5727.1 CPU1.AF6
HDMI_DDI_TX_N3: C5733.1 CPU1.AE5
HDMI_DDI_TX_P0: C5737.1 CPU1.AL6
HDMI_DDI_TX_P1: C5732.1 CPU1.AJ6
HDMI_DDI_TX_P2: C5728.1 CPU1.AF5
HDMI_DDI_TX_P3: C5735.1 CPU1.AE6
HDMI_HPD_ALS: R5760.2 U5701.B1
HDMI_HPD_CON: ED5703.4 ED5703.7 HDMI1.19 R5749.1 R5764.1 U5701.G1
HDMI_HPD_CPU: CPU1.CN6 R5702.1 R5760.1
HDMI_SCL_CON: ED5703.1 ED5703.10 HDMI1.15 R5755.2 U5701.E1
HDMI_SCL_R: D5701.2 R5755.1
HDMI_SDA_CON: ED5703.2 ED5703.9 HDMI1.16 R5751.2 U5701.F1
HDMI_SDA_R: D5701.1 R5751.1
HOST_DEBUG_TX: DB3.5 R2480.2 R6801.1 U2401.81
HOST_DEBUG_TX_CON: DB1.11 R6801.2
HPDIN: R7121.2 U7101.32
HVA_GATE1: R7218.1 U7201.B9
HVA_GATE2: R7219.1 U7201.A9
HW_ACAV_IN: PG4408.2 PQ4415.5 U2401.128
HW_ACAVIN_NB: D4305.A Q4349.2 R4311.2 R4315.1 R4378.2 U2401.24 U4302.1
I2C_CLK_PD: R7114.2 RN7206.3(B) U7201.D2
I2C_CLK_PD_MUX: R7114.1 U7101.21
I2C_DATA_PD: R7116.2 RN7206.4(B) U7201.D1
I2C_DATA_PD_MUX: R7116.1 U7101.22
I2CEN: R7173.1 R7174.2 U7101.17
I_ADP: C2435.1 R2421.1 U2401.110
I_BATT: C2441.1 R2423.2 U2401.114
IC_DELAY: C4344.1 U4302.4
ICSP_CLK: DB3.2 U2401.101
ICSP_CLR: DB3.6 R2414.2 U2401.87
ICSP_DAT: DB3.3 U2401.102
ILIM_HI: R3404.2 U3401.16
ILIM_LO: R3403.2 U3401.15
ILIM_SEL: R3405.2 U3401.4
INPUT3VSEL: CPU1.BT27 R1519.2 R1520.1
IR_CAM_DET#: CPU1.CM22 R2046.2 R5510.2
IR_CAMERA_DET#_R: LCD1.44 R5510.1
ISH_KB_DISABLE: CPU1.BW35 Q2001.2
IST_TRIG: CPU1.CP36 TP620.1
ITP_PMODE: CPU1.W4 TP618.1
JACK_PLUG: ED2902.1 HPMIC1.5 R2923.1
JACK_PLUG_DET: ED2902.2 HPMIC1.6 R2905.1
JGND: AFTP4301.1 AFTP4302.1 DCIN1.1 DCIN1.2 DCIN1.3 EC4301.2 EC4302.2 EC4312.2 EC4313.2 EL4303.1 EL4304.1
KB_BL_CTRL#: AFTP6530.1 KBBL1.4 Q6501.D
KB_DET#: CPU1.CM12 KBBD1.30 R2045.2
KB_DISABLE_CPU_R: Q2001.5 Q2001.6 R2003.2
KB_LED_BL_DET: CPU1.CK36 R6507.1 R6508.1
KB_LED_DET_C: C6504.1 KBBL1.2 R6507.2
KB_LED_PWM: Q6501.G R6509.1 U2401.44
KBC_BEEP_R: D2702.1 RN2702.4(B)
KBC_PS2_SCL_TP: AFTP6532.1 RN6502.4(B) TP1.1
KBC_PS2_SDA_TP: AFTP6533.1 RN6502.3(B) TP1.2
KBC_PWRBTN#: AFTP6609.1 C6605.1 IOBD1.46 R2432.1
KBC_SMB_SCL_BAT: AFTP4311.1 BATT1.4 ED4306.3 RN4302.4(B)
KBC_SMB_SDA_BAT: AFTP4310.1 BATT1.5 ED4305.3 RN4302.3(B)
KSI0: AFTP6512.1 KBBD1.22 RN2403.8(B) U2401.98
KSI1: AFTP6501.1 KBBD1.24 RN2403.7(B) U2401.99
KSI2: AFTP6508.1 KBBD1.26 RN2404.6(B) U2401.6
KSI3: AFTP6509.1 KBBD1.23 RN2404.5(B) U2401.7
KSI4: AFTP6505.1 KBBD1.27 RN2403.6(B) U2401.104
KSI5: AFTP6506.1 KBBD1.25 RN2403.5(B) U2401.105
KSI6: AFTP6503.1 KBBD1.28 RN2404.8(B) U2401.107
KSI7: AFTP6502.1 KBBD1.29 RN2404.7(B) U2401.108
KSO0: AFTP6507.1 KBBD1.13 RN2411.8(B) U2401.2
KSO1: AFTP6511.1 KBBD1.15 RN2412.6(B) U2401.14
KSO2: AFTP6513.1 KBBD1.14 RN2412.5(B) U2401.15
KSO3: AFTP6518.1 KBBD1.16 RN2412.7(B) U2401.16
KSO4: AFTP6514.1 KBBD1.20 RN2409.7(B) U2401.37
KSO5: AFTP6510.1 KBBD1.21 RN2409.8(B) U2401.38
KSO6: AFTP6517.1 KBBD1.18 RN2409.5(B) U2401.39
KSO7: AFTP6515.1 KBBD1.19 RN2409.6(B) U2401.50
KSO8: AFTP6516.1 KBBD1.17 RN2412.8(B) U2401.46
KSO9: AFTP6504.1 KBBD1.7 R2452.1 R2453.2 U2401.68
KSO10: AFTP6523.1 KBBD1.5 RN2410.5(B) U2401.72
KSO11: AFTP6522.1 KBBD1.6 RN2410.6(B) U2401.74
KSO12: AFTP6519.1 KBBD1.12 RN2410.8(B) U2401.75
KSO13: AFTP6520.1 KBBD1.9 RN2411.5(B) U2401.76
KSO14: AFTP6521.1 KBBD1.8 RN2410.7(B) U2401.77
KSO15: AFTP6524.1 KBBD1.10 RN2411.6(B) U2401.86
KSO16: AFTP6539.1 KBBD1.11 RN2411.7(B) U2401.92
L_BKLT_CTRL: CPU1.CH11 D5502.1 R5502.2
L_BKLT_EN: CPU1.CK11 R2403.1 R2440.2 R2455.1
L_BKLT_EN_R: D2401.2 R2403.2
LAN_WAKE#: CPU1.BU32 R1707.2
LCD_BRIGHTNESS: EC5501.1 LCD1.22 R5545.1
LCD_TST: D5502.2 R5543.2 U2401.26
LCD_TST_C: LCD1.9 R5543.1
LCD_VCC_TEST_EN: D5501.2 U2401.113
LDO1_CAP: C2731.1 R2747.1 U2701.39
LDO2_CAP: C2734.1 U2701.21
LDO3_CAP: C2736.1 U2701.19
LID_CL_SIO#: D2402.K HALL1.4 RN2405.3(A) U2401.66 U6402.1
LID_CL_SIO_TAB#: C6701.1 HALL1.1 R2496.1 U2401.41
LINE1-L_C: C2907.2 R2922.1
LINE1-L_R: C2908.2 R2921.1
LINE1_L: C2907.1 U2701.36
LINE1_R: C2908.1 U2701.35
LPS_SW: C7401.2 R7402.1 R7403.1 R7404.2 U7418.4
LPS_SW_A: Q7406.6 R7402.2
LPS_SW_B: Q7401.D R7403.2
LPS_SW_C: Q7401.G R7405.1 R7406.2
LPS_SW_D: Q7406.3 R7405.2
LVDS_VDD_EN_R: D5501.3 RN5502.6(B) U5501.4
M2_PCIE_LED#: D6401.2 R6405.2 SSD1.10
M2_SSD_PEDET: AFTP6303.1 CPU1.CP10 R6305.2 SSD1.69
M_A_A0: CPU1.AC37 RAM1.P3 RAM2.P3 RAM3.P3 RAM4.P3 RN1203.3(A)
M_A_A1: CPU1.AC36 RAM1.P7 RAM2.P7 RAM3.P7 RAM4.P7 RN1205.4(A)
M_A_A2: CPU1.AC34 RAM1.R3 RAM2.R3 RAM3.R3 RAM4.R3 RN1203.4(A)
M_A_A3: CPU1.AC35 RAM1.N7 RAM2.N7 RAM3.N7 RAM4.N7 RN1206.3(A)
M_A_A4: CPU1.AA35 RAM1.N3 RAM2.N3 RAM3.N3 RAM4.N3 RN1206.2(A)
M_A_A5: CPU1.AB35 RAM1.P8 RAM2.P8 RAM3.P8 RAM4.P8 RN1205.2(A)
M_A_A6: CPU1.AA37 RAM1.P2 RAM2.P2 RAM3.P2 RAM4.P2 RN1205.1(A)
M_A_A7: CPU1.AA36 RAM1.R8 RAM2.R8 RAM3.R8 RAM4.R8 RN1204.3(A)
M_A_A8: CPU1.AB34 RAM1.R2 RAM2.R2 RAM3.R2 RAM4.R2 RN1203.1(A)
M_A_A9: CPU1.W36 RAM1.R7 RAM2.R7 RAM3.R7 RAM4.R7 RN1204.4(A)
M_A_A10: CPU1.Y31 RAM1.M3 RAM2.M3 RAM3.M3 RAM4.M3 RN1202.1(A)
M_A_A11: CPU1.W34 RAM1.T2 RAM2.T2 RAM3.T2 RAM4.T2 RN1203.2(A)
M_A_A12: CPU1.AA34 RAM1.M7 RAM2.M7 RAM3.M7 RAM4.M7 RN1206.4(A)
M_A_A13: CPU1.AC32 RAM1.T8 RAM2.T8 RAM3.T8 RAM4.T8 RN1204.2(A)
M_A_A14: CPU1.AC31 RAM1.L2 RAM2.L2 RAM3.L2 RAM4.L2 RN1202.2(A)
M_A_A15: CPU1.AB32 RAM1.M8 RAM2.M8 RAM3.M8 RAM4.M8 RN1207.2(A)
M_A_A16: CPU1.Y32 R1211.1 RAM1.L8 RAM2.L8 RAM3.L8 RAM4.L8
M_A_ACT_N: CPU1.V35 RAM1.L3 RAM2.L3 RAM3.L3 RAM4.L3 RN1207.3(A)
M_A_ALERT_N: CPU1.W37 R1208.1 RAM1.P9 RAM2.P9 RAM3.P9 RAM4.P9
M_A_BA0: CPU1.W32 RAM1.N2 RAM2.N2 RAM3.N2 RAM4.N2 RN1206.1(A)
M_A_BA1: CPU1.AB31 RAM1.N8 RAM2.N8 RAM3.N8 RAM4.N8 RN1205.3(A)
M_A_BG0: CPU1.V34 RAM1.M2 RAM2.M2 RAM3.M2 RAM4.M2 RN1202.3(A)
M_A_BG1: CPU1.W35 R1220.1
M_A_BG1_E9_1: R1212.1 RAM4.E9
M_A_BG1_E9_2: R1213.1 RAM3.E9
M_A_BG1_E9_3: R1214.1 RAM1.E9
M_A_BG1_E9_4: R1215.1 RAM2.E9
M_A_BG1_M9_R: R1220.2 R1221.2 R1224.1 RAM1.M9 RAM2.M9 RAM3.M9 RAM4.M9
M_A_CKE0: CPU1.U36 RAM1.K2 RAM2.K2 RAM3.K2 RAM4.K2 RN1207.1(A)
M_A_CLK: C1247.1 R1225.2 R1226.2
M_A_CLK0: C1285.1 CPU1.V31 R1225.1 RAM1.K7 RAM2.K7 RAM3.K7 RAM4.K7
M_A_CLK#0: C1285.2 CPU1.V32 R1226.1 RAM1.K8 RAM2.K8 RAM3.K8 RAM4.K8
M_A_CS#0: CPU1.AE32 RAM1.L7 RAM2.L7 RAM3.L7 RAM4.L7 RN1202.4(A)
M_A_DQ0: CPU1.A26 RAM4.C2
M_A_DQ1: CPU1.D26 RAM4.C8
M_A_DQ2: CPU1.D28 RAM4.D7
M_A_DQ3: CPU1.C28 RAM4.C7
M_A_DQ4: CPU1.B26 RAM4.A3
M_A_DQ5: CPU1.C26 RAM4.B8
M_A_DQ6: CPU1.B28 RAM4.C3
M_A_DQ7: CPU1.A28 RAM4.D3
M_A_DQ8: CPU1.B30 RAM4.H8
M_A_DQ9: CPU1.D30 RAM4.J7
M_A_DQ10: CPU1.B33 RAM4.H2
M_A_DQ11: CPU1.D32 RAM4.G2
M_A_DQ12: CPU1.A30 RAM4.H7
M_A_DQ13: CPU1.C30 RAM4.F7
M_A_DQ14: CPU1.B32 RAM4.J3
M_A_DQ15: CPU1.C32 RAM4.H3
M_A_DQ16: CPU1.J22 RAM3.J7
M_A_DQ17: CPU1.H25 RAM3.G2
M_A_DQ18: CPU1.G22 RAM3.H8
M_A_DQ19: CPU1.H22 RAM3.F7
M_A_DQ20: CPU1.F25 RAM3.J3
M_A_DQ21: CPU1.J25 RAM3.H2
M_A_DQ22: CPU1.G25 RAM3.H3
M_A_DQ23: CPU1.F22 RAM3.H7
M_A_DQ24: CPU1.D22 RAM3.C8
M_A_DQ25: CPU1.C22 RAM3.A3
M_A_DQ26: CPU1.C24 RAM3.D3
M_A_DQ27: CPU1.D24 RAM3.C3
M_A_DQ28: CPU1.A22 RAM3.C2
M_A_DQ29: CPU1.B22 RAM3.B8
M_A_DQ30: CPU1.A24 RAM3.D7
M_A_DQ31: CPU1.B24 RAM3.C7
M_A_DQ32: CPU1.H37 RAM2.C2
M_A_DQ33: CPU1.H34 RAM2.C8
M_A_DQ34: CPU1.K34 RAM2.C3
M_A_DQ35: CPU1.K35 RAM2.D7
M_A_DQ36: CPU1.H36 RAM2.B8
M_A_DQ37: CPU1.H35 RAM2.A3
M_A_DQ38: CPU1.K36 RAM2.C7
M_A_DQ39: CPU1.K37 RAM2.D3
M_A_DQ40: CPU1.N36 RAM2.H8
M_A_DQ41: CPU1.N34 RAM2.F7
M_A_DQ42: CPU1.R37 RAM2.G2
M_A_DQ43: CPU1.R34 RAM2.H2
M_A_DQ44: CPU1.N37 RAM2.H7
M_A_DQ45: CPU1.N35 RAM2.J7
M_A_DQ46: CPU1.R36 RAM2.H3
M_A_DQ47: CPU1.R35 RAM2.J3
M_A_DQ48: CPU1.G31 RAM1.C3
M_A_DQ49: CPU1.G32 RAM1.D3
M_A_DQ50: CPU1.H29 RAM1.B8
M_A_DQ51: CPU1.H28 RAM1.C8
M_A_DQ52: CPU1.G28 RAM1.C2
M_A_DQ53: CPU1.G29 RAM1.A3
M_A_DQ54: CPU1.H31 RAM1.C7
M_A_DQ55: CPU1.H32 RAM1.D7
M_A_DQ56: CPU1.L31 RAM1.H7
M_A_DQ57: CPU1.L32 RAM1.H8
M_A_DQ58: CPU1.N29 RAM1.H2
M_A_DQ59: CPU1.N28 RAM1.G2
M_A_DQ60: CPU1.L28 RAM1.J7
M_A_DQ61: CPU1.L29 RAM1.F7
M_A_DQ62: CPU1.N31 RAM1.H3
M_A_DQ63: CPU1.N32 RAM1.J3
M_A_DQS_DN0: CPU1.C27 RAM4.A7
M_A_DQS_DN1: CPU1.D31 RAM4.F3
M_A_DQS_DN2: CPU1.H24 RAM3.F3
M_A_DQS_DN3: CPU1.C23 RAM3.A7
M_A_DQS_DN4: CPU1.J35 RAM2.A7
M_A_DQS_DN5: CPU1.P34 RAM2.F3
M_A_DQS_DN6: CPU1.G30 RAM1.A7
M_A_DQS_DN7: CPU1.L30 RAM1.F3
M_A_DQS_DP0: CPU1.D27 RAM4.B7
M_A_DQS_DP1: CPU1.C31 RAM4.G3
M_A_DQS_DP2: CPU1.G24 RAM3.G3
M_A_DQS_DP3: CPU1.D23 RAM3.B7
M_A_DQS_DP4: CPU1.J34 RAM2.B7
M_A_DQS_DP5: CPU1.P35 RAM2.G3
M_A_DQS_DP6: CPU1.H30 RAM1.B7
M_A_DQS_DP7: CPU1.N30 RAM1.G3
M_A_ODT0: CPU1.AE31 RAM1.K3 RAM2.K3 RAM3.K3 RAM4.K3 RN1207.4(A)
M_A_PARITY: CPU1.W31 RAM1.T3 RAM2.T3 RAM3.T3 RAM4.T3 RN1204.1(A)
M_B_A0: CPU1.AG36 RAM5.P3 RAM6.P3 RAM7.P3 RAM8.P3 RN1304.4(A)
M_B_A1: CPU1.AG35 RAM5.P7 RAM6.P7 RAM7.P7 RAM8.P7 RN1306.2(A)
M_B_A2: CPU1.AF34 RAM5.R3 RAM6.R3 RAM7.R3 RAM8.R3 RN1307.3(A)
M_B_A3: CPU1.AG37 RAM5.N7 RAM6.N7 RAM7.N7 RAM8.N7 RN1306.4(A)
M_B_A4: CPU1.AE35 RAM5.N3 RAM6.N3 RAM7.N3 RAM8.N3 RN1303.3(A)
M_B_A5: CPU1.AF35 RAM5.P8 RAM6.P8 RAM7.P8 RAM8.P8 RN1303.2(A)
M_B_A6: CPU1.AE37 RAM5.P2 RAM6.P2 RAM7.P2 RAM8.P2 RN1303.1(A)
M_B_A7: CPU1.AC29 RAM5.R8 RAM6.R8 RAM7.R8 RAM8.R8 RN1307.4(A)
M_B_A8: CPU1.AE36 RAM5.R2 RAM6.R2 RAM7.R2 RAM8.R2 RN1307.1(A)
M_B_A9: CPU1.AB29 RAM5.R7 RAM6.R7 RAM7.R7 RAM8.R7 RN1304.3(A)
M_B_A10: CPU1.AG34 RAM5.M3 RAM6.M3 RAM7.M3 RAM8.M3 RN1305.2(A)
M_B_A11: CPU1.AC28 RAM5.T2 RAM6.T2 RAM7.T2 RAM8.T2 RN1307.2(A)
M_B_A12: CPU1.AB28 RAM5.M7 RAM6.M7 RAM7.M7 RAM8.M7 RN1306.3(A)
M_B_A13: CPU1.AK35 RAM5.T8 RAM6.T8 RAM7.T8 RAM8.T8 RN1304.2(A)
M_B_A14: CPU1.AJ35 RAM5.L2 RAM6.L2 RAM7.L2 RAM8.L2 RN1302.2(A)
M_B_A15: CPU1.AK34 RAM5.M8 RAM6.M8 RAM7.M8 RAM8.M8 RN1302.3(A)
M_B_A16: CPU1.AJ34 RAM5.L8 RAM6.L8 RAM7.L8 RAM8.L8 RN1305.3(A)
M_B_ACT_N: CPU1.W28 RAM5.L3 RAM6.L3 RAM7.L3 RAM8.L3 RN1305.4(A)
M_B_ALERT_N: CPU1.Y29 R1330.1 RAM5.P9 RAM6.P9 RAM7.P9 RAM8.P9
M_B_BA0: CPU1.AJ37 RAM5.N2 RAM6.N2 RAM7.N2 RAM8.N2 RN1306.1(A)
M_B_BA1: CPU1.AJ36 RAM5.N8 RAM6.N8 RAM7.N8 RAM8.N8 RN1303.4(A)
M_B_BG0: CPU1.W29 RAM5.M2 RAM6.M2 RAM7.M2 RAM8.M2 RN1302.1(A)
M_B_BG1: CPU1.Y28 R1339.1
M_B_BG1_E9_1: R1331.1 RAM6.E9
M_B_BG1_E9_2: R1332.1 RAM5.E9
M_B_BG1_E9_3: R1333.1 RAM8.E9
M_B_BG1_E9_4: R1334.1 RAM7.E9
M_B_BG1_M9_R: R1312.1 R1339.2 R1340.2 RAM5.M9 RAM6.M9 RAM7.M9 RAM8.M9
M_B_CKE0: CPU1.T28 RAM5.K2 RAM6.K2 RAM7.K2 RAM8.K2 RN1305.1(A)
M_B_CLK: C1370.1 R1313.2 R1314.2
M_B_CLK0: C1388.1 CPU1.AF29 R1313.1 RAM5.K7 RAM6.K7 RAM7.K7 RAM8.K7
M_B_CLK#0: C1388.2 CPU1.AF28 R1314.1 RAM5.K8 RAM6.K8 RAM7.K8 RAM8.K8
M_B_CS#0: CPU1.AL37 RAM5.L7 RAM6.L7 RAM7.L7 RAM8.L7 RN1302.4(A)
M_B_DQ0: CPU1.AN35 RAM6.A3
M_B_DQ1: CPU1.AN34 RAM6.B8
M_B_DQ2: CPU1.AR35 RAM6.D7
M_B_DQ3: CPU1.AR34 RAM6.C3
M_B_DQ4: CPU1.AN37 RAM6.C8
M_B_DQ5: CPU1.AN36 RAM6.C2
M_B_DQ6: CPU1.AR36 RAM6.D3
M_B_DQ7: CPU1.AR37 RAM6.C7
M_B_DQ8: CPU1.AU35 RAM6.J7
M_B_DQ9: CPU1.AU34 RAM6.H8
M_B_DQ10: CPU1.AW35 RAM6.H2
M_B_DQ11: CPU1.AW34 RAM6.F7
M_B_DQ12: CPU1.AU37 RAM6.J3
M_B_DQ13: CPU1.AU36 RAM6.H7
M_B_DQ14: CPU1.AW36 RAM6.G2
M_B_DQ15: CPU1.AW37 RAM6.H3
M_B_DQ16: CPU1.AJ29 RAM5.C8
M_B_DQ17: CPU1.AJ30 RAM5.B8
M_B_DQ18: CPU1.AM32 RAM5.C3
M_B_DQ19: CPU1.AM31 RAM5.D3
M_B_DQ20: CPU1.AM30 RAM5.C7
M_B_DQ21: CPU1.AM29 RAM5.D7
M_B_DQ22: CPU1.AJ31 RAM5.C2
M_B_DQ23: CPU1.AJ32 RAM5.A3
M_B_DQ24: CPU1.AR31 RAM5.J7
M_B_DQ25: CPU1.AR32 RAM5.H8
M_B_DQ26: CPU1.AV30 RAM5.H2
M_B_DQ27: CPU1.AV29 RAM5.G2
M_B_DQ28: CPU1.AR30 RAM5.H7
M_B_DQ29: CPU1.AR29 RAM5.F7
M_B_DQ30: CPU1.AV32 RAM5.H3
M_B_DQ31: CPU1.AV31 RAM5.J3
M_B_DQ32: CPU1.BA35 RAM8.C2
M_B_DQ33: CPU1.BA34 RAM8.D7
M_B_DQ34: CPU1.BC35 RAM8.C7
M_B_DQ35: CPU1.BC34 RAM8.A3
M_B_DQ36: CPU1.BA37 RAM8.B8
M_B_DQ37: CPU1.BA36 RAM8.C8
M_B_DQ38: CPU1.BC36 RAM8.D3
M_B_DQ39: CPU1.BC37 RAM8.C3
M_B_DQ40: CPU1.BE35 RAM8.J7
M_B_DQ41: CPU1.BE34 RAM8.F7
M_B_DQ42: CPU1.BG35 RAM8.H2
M_B_DQ43: CPU1.BG34 RAM8.J3
M_B_DQ44: CPU1.BE37 RAM8.H7
M_B_DQ45: CPU1.BE36 RAM8.H8
M_B_DQ46: CPU1.BG36 RAM8.G2
M_B_DQ47: CPU1.BG37 RAM8.H3
M_B_DQ48: CPU1.BA32 RAM7.C8
M_B_DQ49: CPU1.BA31 RAM7.B8
M_B_DQ50: CPU1.BD31 RAM7.D3
M_B_DQ51: CPU1.BD32 RAM7.C3
M_B_DQ52: CPU1.BA30 RAM7.C2
M_B_DQ53: CPU1.BA29 RAM7.A3
M_B_DQ54: CPU1.BD29 RAM7.D7
M_B_DQ55: CPU1.BD30 RAM7.C7
M_B_DQ56: CPU1.BG31 RAM7.H7
M_B_DQ57: CPU1.BG32 RAM7.J7
M_B_DQ58: CPU1.BK32 RAM7.J3
M_B_DQ59: CPU1.BK31 RAM7.H3
M_B_DQ60: CPU1.BG29 RAM7.F7
M_B_DQ61: CPU1.BG30 RAM7.H8
M_B_DQ62: CPU1.BK30 RAM7.H2
M_B_DQ63: CPU1.BK29 RAM7.G2
M_B_DQS_DN0: CPU1.AP35 RAM6.A7
M_B_DQS_DN1: CPU1.AV34 RAM6.F3
M_B_DQS_DN2: CPU1.AL31 RAM5.A7
M_B_DQS_DN3: CPU1.AU31 RAM5.F3
M_B_DQS_DN4: CPU1.BB35 RAM8.A7
M_B_DQS_DN5: CPU1.BF34 RAM8.F3
M_B_DQS_DN6: CPU1.BC31 RAM7.A7
M_B_DQS_DN7: CPU1.BH31 RAM7.F3
M_B_DQS_DP0: CPU1.AP34 RAM6.B7
M_B_DQS_DP1: CPU1.AV35 RAM6.G3
M_B_DQS_DP2: CPU1.AL30 RAM5.B7
M_B_DQS_DP3: CPU1.AU30 RAM5.G3
M_B_DQS_DP4: CPU1.BB34 RAM8.B7
M_B_DQS_DP5: CPU1.BF35 RAM8.G3
M_B_DQS_DP6: CPU1.BC30 RAM7.B7
M_B_DQS_DP7: CPU1.BH30 RAM7.G3
M_B_ODT0: CPU1.AL36 R1311.1 RAM5.K3 RAM6.K3 RAM7.K3 RAM8.K3
M_B_PARITY: CPU1.AE34 RAM5.T3 RAM6.T3 RAM7.T3 RAM8.T3 RN1304.1(A)
M_VREF_CA_DIMMA: C1201.1 C1203.1 C1236.1 C1286.1 R1202.1 R1222.2 R1223.2 RAM1.M1 RAM2.M1 RAM3.M1 RAM4.M1
M_VREF_CA_DIMMB: C1301.1 C1303.1 C1336.1 C1343.1 R1302.1 R1320.2 R1321.2 RAM5.M1 RAM6.M1 RAM7.M1 RAM8.M1
MASK_BASE_LEDS#: Q6404.2 Q6404.5 R6419.2 U6402.4
MASK_SATA_LED#: Q6403.G R6406.2 U2401.56
MCDP2800_D8: R5709.2 U5701.D8
MCDP2800_UART_TX: AFTP5701.1 U5701.D7
ME_FWP: FSW1.2 R1909.1 R9806.1
ME_FWP_EC: FSW1.3 R9806.2 U2401.80
ME_SUS_PWR_ACK_R: CPU1.BV34 R1708.1 R1738.2
MEC_XTAL1_R: C2425.1 U2401.123 X2401.1
MEC_XTAL2: C2424.1 R2461.2 U2401.125 X2401.2
MEM_CHA_EN: CPU1.CJ31 R2030.1 R2031.2
MEM_CHB_EN: CPU1.CJ27 R2032.1 R2033.2
MEM_CONFIG0: CPU1.CF27 R2015.1 R2016.2
MEM_CONFIG1: CPU1.CF29 R2017.1 R2018.2
MEM_CONFIG2: CPU1.CH27 R2022.1 R2029.2
MEM_CONFIG3: CPU1.CH28 R2011.2 R2012.1
MEM_CONFIG4: CPU1.CJ30 R2013.2 R2014.1
MESW1_B: FSW1.1 R9804.1 R9805.2
MIC2_VREFO_L: RN2901.2(A) U2701.28
MIC2_VREFO_R: RN2901.1(A) U2701.29
MIC_CAP: C2735.1 U2701.32
MIC_GND: LCD1.45 R5501.1
MODEL_ID: C2407.1 R2441.1 R2442.2 U2401.109
MSATA_DEVSLP_R: AFTP6301.1 R6301.2 SSD1.38
MUX_HPD_CON: R7149.1 U7101.23
NB_MODE#: Q2001.3 R2004.1 R2050.2 U2401.34
NB_MUTE#: R2743.2 U2401.119 U2701.2
NC_HDMI_RE_DRIVER_F7: C5701.1 U5701.F7
NC_SIO_SLP_S4#_EC: R2405.1 U2401.97
NC_U3_PD#_EC: R2404.1 R2406.1 U2401.96
NCT7718_DXN: C2606.2 C2607.2 Q2603.E U2601.3
NCT7718_DXP: C2606.1 C2607.1 Q2603.B Q2603.C U2601.2
NRB_BIT: CPU1.CE29 R1502.2 R1503.1
PANEL_BKEN: D2401.3 R5544.2
PANEL_BKEN_EC: D2401.1 U2401.117
PBAT_CHG_SMBCLK: EC4309.1 PU4401.22 RN2402.3(B) RN4302.1(A) U2401.9
PBAT_CHG_SMBDAT: EC4310.1 PU4401.21 RN2402.4(B) RN4302.2(A) U2401.8
PBAT_PRES1#: AFTP4309.1 BATT1.6 ED4304.3 R4327.2
PBAT_PRES#: EC4306.1 PR4409.2 R2415.1 R4327.1 U2401.29
PCH_BATLOW#: CPU1.BV36 R1721.2 R1722.1
PCH_DPWROK: CPU1.BP30 R1704.2
PCH_JTAG_TCK: CPU1.W6 TP315.1
PCH_PLTRST#: CPU1.BJ35 R1713.2
PCH_POPIRCOMP: CPU1.BW25 R305.2
PCH_RSMRST#: EC1712.1 R1702.2 TP2402.1 U2401.27
PCH_SATA_LED#: CPU1.CN7 D6401.1 R1606.1 R6420.1
PCIE_RCOMPN: CPU1.CE6 R1604.1
PCIE_RCOMPP: CPU1.CE5 R1604.2
PCIE_WAKE#: R2407.1 U2401.4
PCIE_WAKE#_CPU: CPU1.BU30 RN1701.3(B)
PD4403_A: PD4404.A PQ4408.B
PD4403_K: PD4404.K PR4477.1 PR4495.1
PD_IRQ1: R7224.2 U7201.C1
PD_OVP_TRIP_P1: R7209.2 R7243.2 U7201.C2
PD_VBUS_C_CTRL1: Q7405.2 Q7406.2 U7201.G10
PD_VBUS_C_CTRL1_A: Q7404.3 Q7405.1
PD_VBUS_C_CTRL1_R: Q7405.5 Q7405.6 R7407.1 R7426.2
PD_VBUS_C_EN#: Q7402.6 R7422.1 R7427.2 U7419.A3
PD_VBUS_C_EN_A: Q7402.2 Q7402.3 Q7405.3 R7409.1 R7425.2
PECI_CPU: CPU1.AR1 R2437.2
PIRQA#: CPU1.CC32 R2053.2 R9137.2
PLT_RST#_Q_TPM2: R9136.2 U9102.17
PLTRST#_CPU: AFTP6108.1 C1701.1 ED1701.1 IOBD1.44 R1713.1 R1715.1 R2616.1 R9136.1 SSD1.50
PM_PCH_PWROK: CPU1.BP31 R1706.2 RN1703.3(B)
PM_RSMRST#: CPU1.BR36 Q1701.6 Q1702.5 R1702.1 R1704.1 RN1703.4(B)
PM_RSMRST#_M: Q1702.2 Q1702.3 R1737.2
PM_SLP_S0#: CPU1.BJ37 R4040.1 R9141.2
PM_SLP_S3#: CPU1.BU36 D4003.K PR5126.1 Q4001.G R4010.1 R4018.1 U4008.1
PM_SLP_S4#: CPU1.BU27 PR5317.1 R4024.1
POWER_SW_IN#: C2427.1 R2432.2 R2451.2 U2401.127
PQ4302_B: Q4302.B R4302.2 R4309.1
PQ4348_D: Q4348.D R4368.2
PQ4405_2: PQ4405.2 PR4462.2 PR4463.1
PQ4405_3: PQ4405.3 PR4476.2
PQ4405_5: PC4438.1 PQ4405.5 PR4474.1
PQ4405_6: PC4438.2 PQ4405.6 PR4450.1
PQ4408_C: PQ4408.C PR4462.1 PR4475.1
PQ4408_E: PQ4408.E PR4436.1 PR4473.2
PQ4417_D: PQ4417.D PR4479.2 PR4483.1
PQ4418_2: PQ4418.2 PR4483.2 PR4488.1
PQ4418_3: PQ4418.3 PR4485.2
PQ4418_5: PC4445.1 PQ4418.5 PR4487.2
PQ4418_6: PC4445.2 PQ4418.6 PR4486.1
PRD_CC1: R7211.1 U7201.K9
PRD_CC2: R7212.1 U7201.K10
PRIM_PWRGD: PR5308.1 R4030.1 U2401.30
PROCHOT: Q2408.G R2417.1 R2418.1 U2401.83
PROCHOT#_CPU: ED2403.1 PQ4416.3 PR4476.1 PR4485.1 PR4603.2 PR4607.1 Q2408.D R301.2 R302.1 R2418.2
PROCHOT#_CPU_R: CPU1.Y4 R302.2
PROJECT_ID0: CPU1.CH23 R2113.2 R2114.1
PROJECT_ID1: CPU1.CK19 R2111.2 R2112.1
PROJECT_ID2: CPU1.CG17 R2117.2 R2118.1
PROJECT_ID3: CPU1.CN20 R2115.2 R2116.1
PS175_CEC_EN: R5756.2 R5757.2 U5701.E7
PS175_CSCL: R5739.2 U5701.E6
PS175_CSDA: R5738.2 U5701.F6
PS175_PD#: Q5705.3 R5736.2 R5744.1 U5701.C3
PS175_RST#: C5725.1 R5737.2 R5744.2 U5701.B8
PS_ID: D4302.3 R4304.2 R4305.2 U2401.36
PS_ID_R: AFTP4304.1 DCIN1.4 EC4311.1 R4317.1
PS_ID_R1: Q4301.S R4305.1 R4306.2
PS_ID_R2: D4303.1 D4303.2 Q4301.D R4306.1 R4309.2 R4317.2
PSID_DISABLE#_R_C: Q4301.G Q4302.C R4310.2
PTP_DIS#: AFTP6537.1 TP1.3 U2401.90
PU4348_G: Q4348.G R4369.1 R4370.2
PURE_HW_SHUTDOWN#: C2610.1 D4001.K Q2602.D R2615.1 R4014.2
PWR_0D6V_S3EN: PC5120.1 PR5125.2 PR5126.2 PU5102.7
PWR_0D6V_S5EN: PC5119.1 PR5114.2 PU5102.9
PWR_0D6V_VTT_CNTL: PC5121.1 PR5118.2 PU5102.10
PWR_1D0V_BT: PC5204.1 PU5201.20
PWR_1D0V_FB: PC5212.2 PR5202.2 PR5204.1 PU5201.5
PWR_1D0V_FB_A: PC5212.1 PG5223.2 PR5202.1
PWR_1D0V_PFM: PR5203.1 PU5201.3
PWR_1D0V_PG: PR5208.2 PR5209.2 PU5201.1
PWR_1D0V_PH: PC5204.2 PL5201.1 PU5201.10 PU5201.11 PU5201.16 PU5201.17 PU5201.18
PWR_1D0V_SS: PC5213.1 PU5201.22
PWR_1D0V_TON: PR5201.2 PU5201.6
PWR_1D8V_POK: PR5302.2 PR5308.2 PU5301.7
PWR_2D5V: PC5311.1 PC5312.1 PC5313.1 PR5319.1 PR5321.1 PU5303.3 PU5303.4
PWR_2D5V_FB: PC5311.2 PR5319.2 PR5320.1 PU5303.2
PWR_3D3V: PC4509.1 PC4510.1 PC4511.1 PC4512.1 PC4513.1 PC4525.1 PC4542.1 PC4543.1 PG4507.1 PG4508.1 PG4509.1 PG4520.1 PG4521.1 PG4526.1 PG4530.2 PL4501.2
PWR_3D3V_BOOT: PR4501.1 PU4501.1
PWR_3D3V_BOOT_A: PC4506.1 PR4501.2
PWR_3D3V_EN: PC4508.1 PR4508.1 PR4509.2 PU4501.11
PWR_3D3V_FB: PC4533.1 PU4501.13
PWR_3D3V_FB2: PC4533.2 PR4506.2
PWR_3D3V_LDO: PC4507.1 PG4519.1 PU4501.16 PU4501.17
PWR_3D3V_PH: PC4506.2 PL4501.1 PU4501.6 PU4501.19 PU4501.20
PWR_3D3V_VOUT: PG4530.1 PR4506.1 PU4501.14
PWR_3V_PG: PG4531.2 PR4505.2 PU4501.9 PU4501.10
PWR_5V: PC4514.1 PC4515.1 PC4516.1 PC4517.1 PC4518.1 PC4527.1 PC4528.1 PC4529.1 PG4510.1 PG4511.1 PG4512.1 PG4513.1 PG4522.1 PG4523.1 PG4524.1 PG4525.1 PG4527.2 PL4502.1
PWR_5V_BOOT: PR4502.1 PU4502.1
PWR_5V_BOOT_A: PC4521.1 PR4502.2
PWR_5V_EN: PC4530.1 PR4511.2 PR4512.1 PU4502.11
PWR_5V_EN1_R: PR4503.2 PR4504.1 PR4515.1 PR4530.1
PWR_5V_FB: PC4526.1 PR4551.1 PU4502.13
PWR_5V_FB_A: PC4526.2 PR4507.1
PWR_5V_LDO: PC4520.1 PG4528.1 PU4502.15
PWR_5V_PG: PG4529.2 PR4510.1 PU4502.9 PU4502.10
PWR_5V_PH: PC4521.2 PL4502.2 PU4502.6 PU4502.19 PU4502.20
PWR_5V_VCC: PC4524.1 PU4502.16 PU4502.17
PWR_5V_VOUT: PG4527.1 PR4507.2 PU4502.14
PWR_CHG_ACIN: PC4420.1 PR4404.2 PR4406.1 PU4401.19
PWR_CHG_ACOK: PG4408.1 PR4426.1 PR4429.2 PR4463.2 PR4488.2 PU4401.24
PWR_CHG_AIN: PD4408.3 PR4404.1
PWR_CHG_AMON: PR4412.1 PU4401.29
PWR_CHG_ASGATE: PU4401.13 TP4401.1
PWR_CHG_BATGONE: PC4430.1 PR4409.1 PU4401.25
PWR_CHG_BGATE: PC4429.1 PU4401.32 PU4412.4
PWR_CHG_BOOT1: PR4402.1 PU4401.12
PWR_CHG_BOOT2: PR4408.1 PU4401.4
PWR_CHG_BT1_R: PC4436.1 PR4402.2
PWR_CHG_BT2_R: PC4423.1 PR4408.2
PWR_CHG_COMP: PC4433.1 PR4411.1 PU4401.28
PWR_CHG_COMP_R: PC4431.1 PR4411.2
PWR_CHG_CSIN: PC4415.1 PC4417.2 PR4423.2 PU4401.14
PWR_CHG_CSIN_R: PG4402.2 PR4423.1
PWR_CHG_CSIP: PC4415.2 PC4416.2 PR4422.2 PU4401.15
PWR_CHG_CSIP_R: PG4401.2 PR4422.1
PWR_CHG_CSON: PC4425.2 PC4426.2 PR4425.1 PU4401.1
PWR_CHG_CSON_R: PG4406.1 PR4425.2
PWR_CHG_CSOP: PC4424.2 PC4425.1 PR4424.1 PU4401.2
PWR_CHG_CSOP_R: PG4405.1 PR4424.2
PWR_CHG_DCIN: PC4419.1 PR4403.1 PU4401.17
PWR_CHG_DCIN_R: PD4401.3 PD4407.K PR4403.2
PWR_CHG_HG1_R: PR4414.2 PU4403.4
PWR_CHG_HG2_R: PR4420.2 PU4405.4
PWR_CHG_LGATE1: PU4401.9 PU4404.4
PWR_CHG_LGATE2: PU4401.7 PU4406.4
PWR_CHG_OTGEN: PR4417.2 PU4401.20
PWR_CHG_OTGPG: PU4401.26 TP8304.1
PWR_CHG_PHASE1: PC4436.2 PL4401.1 PR4416.1 PU4401.10 PU4403.1 PU4403.2 PU4403.3 PU4404.5 PU4404.6 PU4404.7 PU4404.8
PWR_CHG_PHASE2: PC4423.2 PL4401.2 PU4401.6 PU4405.1 PU4405.2 PU4405.3 PU4406.5 PU4406.6 PU4406.7 PU4406.8
PWR_CHG_PROCHOT#: PQ4416.2 PR4435.2 PU4401.23
PWR_CHG_PROCHOT#_R: PQ4416.5 PQ4416.6 PR4472.2
PWR_CHG_PROG: PR4410.2 PU4401.27
PWR_CHG_SNB: PC4435.1 PR4416.2
PWR_CHG_UGATE1: PR4414.1 PU4401.11
PWR_CHG_UGATE2: PR4420.1 PU4401.5
PWR_CHG_VBAT1: PC4440.1 PR4478.1 PU4401.31
PWR_CHG_VBATIN: PC4427.1 PC4428.1 PG4406.2 PR4407.2 PU4412.1 PU4412.2 PU4412.3
PWR_CHG_VDDP: PC4421.1 PR4405.1 PU4401.8
PWR_DCBATOUT_1D0V: PC5209.1 PC5210.1 PC5211.1 PC5214.1 PC5216.1 PG5210.2 PG5212.2 PG5214.2 PR5201.1 PU5201.7 PU5201.8 PU5201.9
PWR_DCBATOUT_3D3V: PC4501.1 PC4502.1 PC4503.1 PC4504.1 PG4515.2 PG4516.2 PG4517.2 PG4518.2 PU4501.2 PU4501.3 PU4501.4 PU4501.5
PWR_DCBATOUT_5V: PC4505.1 PC4519.1 PC4522.1 PC4523.1 PG4501.2 PG4502.2 PG4503.2 PG4504.2 PG4505.2 PG4506.2 PU4502.2 PU4502.3 PU4502.4 PU4502.5
PWR_DCBATOUT_VCCGTA: PC4802.1 PC4803.1 PC4804.1 PC4805.1 PC4814.1 PC4815.1 PC4816.1 PC4817.1 PL4803.2 PL4804.2 PT4807.1 PU4801.8 PU4801.9 PU4801.10 PU4801.11 PU4801.33 PU4802.8 PU4802.9 PU4802.10 PU4802.11 PU4802.33
PWR_DCBATOUT_VCCSA: PC5002.1 PC5003.1 PC5004.1 PG5002.1 PG5003.1 PU5002.5 PU5002.6 PU5002.7 PU5002.8
PWR_DCBATOUT_VCORE: PC4702.1 PC4703.1 PC4704.1 PL4702.2 PL4703.2 PT4702.1 PU4701.8 PU4701.9 PU4701.10 PU4701.11 PU4701.33
PWR_DCBATOUT_VDDQ: PC5111.1 PC5115.1 PC5116.1 PG5105.2 PG5110.2 PU5101.2 PU5101.3 PU5101.4 PU5101.5
PWR_VCCGT_BOOTA: PR4804.2 PU4801.5
PWR_VCCGT_BOOTA_RC: PC4808.1 PR4804.1
PWR_VCCGT_BOOTB: PR4810.2 PU4802.5
PWR_VCCGT_BOOTB_RC: PC4811.1 PR4810.1
PWR_VCCGT_BOOTRA: PC4808.2 PU4801.7
PWR_VCCGT_BOOTRB: PC4811.2 PU4802.7
PWR_VCCGT_COMP: PC4610.2 PR4626.2 PU4601.4
PWR_VCCGT_COMP1: PC4612.1 PC4651.1 PR4626.1
PWR_VCCGT_FB: PR4630.2 PR4633.2 PR4636.2 PU4601.5
PWR_VCCGT_FB1: PC4614.1 PR4630.1
PWR_VCCGT_FB2: PC4615.2 PC4618.2 PC4619.1 PR4631.1 PR4633.1 PR4665.2
PWR_VCCGT_FB_RC: PC4618.1 PR4636.1
PWR_VCCGT_FCCM#: PR4806.1 PR4812.1 PU4601.11
PWR_VCCGT_FCCM#_RA: PR4806.2 PU4801.2
PWR_VCCGT_FCCM#_RB: PR4812.2 PU4802.2
PWR_VCCGT_IMON: PC4604.2 PR4608.2 PU4601.2
PWR_VCCGT_ISEN1: PC4625.1 PR4669.2 PR4821.1 PR4824.2 PU4601.9
PWR_VCCGT_ISEN2: PC4626.1 PR4669.1 PR4822.2 PR4823.1 PU4601.10
PWR_VCCGT_ISUMN: PC4625.2 PC4626.2 PC4630.2 PC4633.1 PR4642.2 PR4643.2 PR4645.2 PR4646.2 PR4647.2 PR4809.2 PR4815.2
PWR_VCCGT_ISUMN_GA: PG4809.2 PR4809.1 PR4822.1
PWR_VCCGT_ISUMN_GB: PG4815.1 PR4815.1 PR4824.1
PWR_VCCGT_ISUMN_P_1: PC4628.2 PC4653.2 PC4654.2 PR4647.1
PWR_VCCGT_ISUMN_P_2: PR4641.2 PR4646.1
PWR_VCCGT_ISUMN_RC: PC4623.1 PR4645.1
PWR_VCCGT_ISUMNB: PC4623.2 PR4642.1 PU4601.8
PWR_VCCGT_ISUMP: PC4628.1 PC4630.1 PC4653.1 PC4654.1 PR4641.1 PR4643.1 PR4808.1 PR4816.1 PU4601.7
PWR_VCCGT_ISUMP_GA: PG4808.2 PR4808.2 PR4821.2
PWR_VCCGT_ISUMP_GB: PG4813.1 PR4816.2 PR4823.2
PWR_VCCGT_NTC: PR4616.2 PU4601.3
PWR_VCCGT_NTC1: PR4616.1 PR4617.1 PR4621.2
PWR_VCCGT_PWMA: PR4802.1 PU4601.12
PWR_VCCGT_PWMA_RA: PR4802.2 PR4817.1 PU4801.1
PWR_VCCGT_PWMB: PR4811.1 PU4601.13
PWR_VCCGT_PWMB_RA: PR4811.2 PR4818.1 PU4802.1
PWR_VCCGT_RTN: PC4619.2 PC4622.1 PR4639.1 PR4666.2 PU4601.6
PWR_VCCGT_SNB1: PC4810.1 PR4805.2
PWR_VCCGT_SNB2: PC4813.1 PR4814.2
PWR_VCCGT_SWA: PG4808.1 PL4801.1 PR4805.1 PU4801.16 PU4801.17 PU4801.18 PU4801.19 PU4801.20 PU4801.21 PU4801.22 PU4801.23 PU4801.24 PU4801.25 PU4801.26
PWR_VCCGT_SWB: PG4813.2 PL4802.1 PR4814.1 PU4802.16 PU4802.17 PU4802.18 PU4802.19 PU4802.20 PU4802.21 PU4802.22 PU4802.23 PU4802.24 PU4802.25 PU4802.26
PWR_VCCGT_VCCDA: PC4809.1 PR4803.2 PU4801.3
PWR_VCCGT_VCCDB: PC4812.1 PR4813.2 PU4802.3
PWR_VCCSA_BST: PR5001.2 PU5001.2
PWR_VCCSA_BST_RC: PC5005.1 PR5001.1
PWR_VCCSA_COMP: PC4624.1 PR4640.1 PU4601.24
PWR_VCCSA_COMP_RC: PC4601.1 PR4640.2
PWR_VCCSA_DRVH: PU5001.1 PU5002.4
PWR_VCCSA_DRVL: PU5001.5 PU5003.4
PWR_VCCSA_FB: PR4632.2 PR4637.1 PR4638.2 PU4601.25
PWR_VCCSA_FB1: PC4621.2 PR4638.1
PWR_VCCSA_FB2: PC4616.2 PC4617.2 PC4620.1 PR4601.1 PR4637.2
PWR_VCCSA_FB_RC: PC4617.1 PR4632.1
PWR_VCCSA_FCCM: PU4601.29 PU5001.7
PWR_VCCSA_IMON: PC4629.2 PR4644.1 PU4601.23
PWR_VCCSA_ISUMN: PC4603.2 PC4605.1 PR4611.1 PR4613.1 PR4615.1 PR4618.2 PR4620.1 PR5004.2
PWR_VCCSA_ISUMN_P_1: PC4608.2 PR4613.2
PWR_VCCSA_ISUMN_P_2: PR4611.2 PR4625.2
PWR_VCCSA_ISUMN_R: PG5001.1 PR5004.1
PWR_VCCSA_ISUMN_RC: PC4611.1 PR4615.2
PWR_VCCSA_ISUMNB: PC4611.2 PR4620.2 PU4601.28
PWR_VCCSA_ISUMP: PC4605.2 PC4608.1 PR4618.1 PR4625.1 PR5003.2 PU4601.27
PWR_VCCSA_ISUMP_R: PG5011.1 PR5003.1
PWR_VCCSA_PWM: PU4601.30 PU5001.3
PWR_VCCSA_RTN: PC4613.1 PC4616.1 PR4602.1 PR4627.2 PU4601.26
PWR_VCCSA_SW: PC5005.2 PG5011.2 PL5001.1 PU5001.8 PU5002.1 PU5002.2 PU5002.3 PU5003.5 PU5003.6 PU5003.7 PU5003.8
PWR_VCORE_BOOT: PR4705.2 PU4701.5
PWR_VCORE_BOOT_RC: PC4707.1 PR4705.1
PWR_VCORE_BOOTR: PC4707.2 PU4701.7
PWR_VCORE_COMP: PC4639.1 PR4656.1 PU4601.16
PWR_VCORE_COMP1: PC4640.1 PR4656.2
PWR_VCORE_FB: PR4657.1 PR4658.1 PR4660.1 PU4601.17
PWR_VCORE_FB1: PC4641.1 PR4657.2
PWR_VCORE_FB2: PC4642.2 PC4643.2 PC4644.1 PR4660.2 PR4663.2 PR4667.1
PWR_VCORE_FB_RC: PC4643.1 PR4658.2
PWR_VCORE_FCCM#: PR4706.1 PU4601.21
PWR_VCORE_FCCM#_R: PR4706.2 PU4701.2
PWR_VCORE_IMON: PC4638.1 PR4661.1 PU4601.14
PWR_VCORE_ISUMN: PC4631.1 PC4634.1 PR4648.2 PR4649.1 PR4650.1 PR4651.2 PR4652.2 PR4701.2
PWR_VCORE_ISUMN_G: PG4708.1 PR4701.1
PWR_VCORE_ISUMN_P_1: PC4635.1 PC4652.1 PR4649.2
PWR_VCORE_ISUMN_P_2: PR4650.2 PR4653.2
PWR_VCORE_ISUMN_RC: PC4632.1 PR4651.1
PWR_VCORE_ISUMNA: PC4632.2 PR4648.1 PU4601.20
PWR_VCORE_ISUMP: PC4634.2 PC4635.2 PC4652.2 PR4652.1 PR4653.1 PR4708.2 PU4601.19
PWR_VCORE_ISUMP_G: PG4707.1 PR4708.1
PWR_VCORE_NTC: PR4662.1 PU4601.15
PWR_VCORE_NTC1: PR4654.1 PR4655.2 PR4662.2
PWR_VCORE_PROG1: PR4629.1 PU4601.32
PWR_VCORE_PROG2: PR4628.1 PU4601.31
PWR_VCORE_PWM: PR4702.1 PU4601.22
PWR_VCORE_PWM_R: PR4702.2 PR4712.1 PU4701.1
PWR_VCORE_RTN: PC4637.1 PC4642.1 PR4659.2 PR4668.1 PU4601.18
PWR_VCORE_SNB: PC4706.1 PR4703.2
PWR_VCORE_SW: PG4707.2 PL4701.1 PR4703.1 PU4701.16 PU4701.17 PU4701.18 PU4701.19 PU4701.20 PU4701.21 PU4701.22 PU4701.23 PU4701.24 PU4701.25 PU4701.26
PWR_VCORE_VCC: PC4607.1 PR4610.2 PU4601.34
PWR_VCORE_VCC_R: PC4708.1 PR4704.1 PU4701.3
PWR_VCORE_VIN: PC4606.1 PR4612.2 PU4601.33
PWR_VCORE_VRHOT#: PR4607.2 PU4601.38
PWR_VDDQ_BOOT: PR5102.1 PU5101.1
PWR_VDDQ_BOOT_A: PC5114.1 PR5102.2
PWR_VDDQ_FB: PC5113.2 PR5101.1 PR5107.2 PU5101.14
PWR_VDDQ_FB_A: PC5113.1 PG5113.1 PR5107.1
PWR_VDDQ_ILMT: PR5103.1 PR5106.2 PU5101.13
PWR_VDDQ_PG: PG5114.2 PR5104.2 PU5101.9 PU5101.10
PWR_VDDQ_PH: PC5114.2 PL5101.1 PU5101.6 PU5101.19 PU5101.20
PWR_VDDQ_VCC: PC5112.1 PR5103.2 PU5101.16 PU5101.17
Q502_G: Q501.D Q502.G R506.2
Q5705_2: C5777.1 Q5705.2 R5749.2
Q5705_5_6: Q5705.5 Q5705.6 R5747.1
Q6204_G: Q6504.2 Q6504.5 R6510.2
Q6205_Q: Q6503.D R6503.2
RESET_OUT#: C2614.1 ED1703.2 Q2602.G R1706.1 R2616.2 U2401.73
REXT: R5704.2 U5701.C6
REXT_R: R5704.1 R5705.2 R5734.1
RING2_R: EC2905.1 ED2901.2 HPMIC1.3 R2908.2
RSMRST_PWRGD#: D4002.K R4029.2 R4030.2 R4031.2 R4032.2 R4033.2
RTC_3P3_EN_D: Q2510.D R2511.1
RTC_3P3_EN_G: C2517.1 D2502.A Q2510.G R2567.2
RTC_AUX_S5: Q2507.D R1730.1 R2204.1 R2511.2 R2512.2 R2754.1 RN1801.1(A) RN1801.2(A)
RTC_DET#: CPU1.CP22 Q2505.D R1521.1 R1554.2
RTC_RST#: C1806.1 CPU1.BR34 ED1801.1 G1801.2 Q1802.D RN1801.4(B)
RTCRST_ON: D2502.K EC1804.1 Q1802.G Q2507.G R1816.1 R2518.1 R2567.1 U2401.31
SATA_PCIE_LED#: D6401.3 Q6403.S R6420.2
SD_RCOMP: CPU1.CK33 CPU1.CM34 R1901.1
SIO_EXT_SCI#: CPU1.CR8 R1608.1
SIO_EXT_SMI#: CPU1.CP7 R402.2
SIO_EXT_WAKE#: CPU1.CN12 R2041.2 U2401.116
SIO_PWRBTN#: CPU1.BU28 U2401.52
SIO_RCIN#: CPU1.BV29 R1820.2
SKTOCC#: CPU1.E1 TP619.1
SLEEVE_R: EC2906.1 ED2903.1 HPMIC1.4 R2910.2
SM_DRAMRST#: C501.1 R504.2 RAM1.P1 RAM2.P1 RAM3.P1 RAM4.P1 RAM5.P1 RAM6.P1 RAM7.P1 RAM8.P1
SM_DRAMRST#_CPU: CPU1.BU31 R504.1 R505.2
SM_INTRUDER#: CPU1.BR35 R1730.2
SM_PGCNTL: CPU1.C35 Q501.G
SM_RCOMP_0: CPU1.BN28 R501.1
SM_RCOMP_1: CPU1.BN27 R502.1
SM_RCOMP_2: CPU1.BN29 R503.1
SPI_CLK_CPU: CPU1.CH37 R2508.2 R9138.1
SPI_CLK_HDMI: R5743.1 U5701.D2 U5702.6
SPI_CLK_PD: U7201.A3 U7202.6
SPI_CLK_ROM: BIOS1.6 EC2503.1 R2508.1
SPI_CLK_TPM: R9138.2 U9102.19
SPI_CS2_TPM: R9130.2 R9140.2 R9148.2 U9102.20
SPI_CS_CPU_N0: BIOS1.1 CPU1.CG36 R2519.2
SPI_CS_CPU_N2: CPU1.CH34 R9130.1
SPI_CS_HDMI: R5740.2 U5701.C1 U5702.1
SPI_CS_PD: R7228.1 U7201.B3 U7202.1
SPI_HOLD_CPU: CPU1.CG34 R1510.2 R1511.1 R2503.2
SPI_HOLD_HDMI: R5742.2 U5702.7
SPI_HOLD_PD: R7226.1 U7202.7
SPI_HOLD_ROM: BIOS1.7 R2503.1
SPI_IRQ#_TPM2: R9137.1 R9139.2 R9149.1 U9102.18
SPI_SI_CPU: CPU1.CF36 R1506.2 R1507.1 R2509.2 R9133.1
SPI_SI_HDMI: U5701.D1 U5702.5
SPI_SI_PD: U7201.B4 U7202.5
SPI_SI_ROM: BIOS1.5 EC2501.1 R2509.1
SPI_SI_TPM: R9133.2 U9102.21
SPI_SO_CPU: CPU1.CF37 R2506.1 R9132.1
SPI_SO_HDMI: U5701.C2 U5702.2
SPI_SO_PD: R7230.1 U7201.A4 U7202.2
SPI_SO_ROM: BIOS1.2 EC2502.1 R2506.2
SPI_SO_TPM: R9132.2 U9102.24
SPI_WP_CPU: CPU1.CF34 R1508.2 R1509.1 R2507.1
SPI_WP_HDMI: R5741.1 U5701.E2 U5702.3
SPI_WP_PD: R7225.1 U7202.3
SPI_WP_ROM: BIOS1.3 R2507.2
SPK_DET#_CON: R2914.2 R2915.2 SPK1.8
SPK_ID: CPU1.CR14 R2110.2 R2915.1
SPK_SCL_CODEC: RN2703.3(B) SPK1.6 U2701.7
SPK_SDA_CODEC: RN2703.4(B) SPK1.7 U2701.6
SPKR: CPU1.CF35 R1501.1 RN2702.2(A)
SRTC_RST#: C1805.1 CPU1.BR37 ED1801.2 RN1801.3(B)
SSD_CLK_CPU_N: CPU1.BA1 SSD1.53
SSD_CLK_CPU_P: CPU1.BA2 SSD1.55
SSD_CLKREQ_CPU_N: CPU1.CE30 RN1802.3(B) SSD1.52
SSD_DEVSLP: CPU1.CM8 R6301.1 R6303.2 R6304.1
SSD_PCIE_RX_N1: CPU1.BG5 SSD1.29
SSD_PCIE_RX_N2: CPU1.BJ6 SSD1.17
SSD_PCIE_RX_N3: CPU1.BK6 SSD1.5
SSD_PCIE_RX_P1: CPU1.BG6 SSD1.31
SSD_PCIE_RX_P2: CPU1.BJ5 SSD1.19
SSD_PCIE_RX_P3: CPU1.BK5 SSD1.7
SSD_PCIE_TX_CON_N1: C6312.1 SSD1.35
SSD_PCIE_TX_CON_N2: C6314.1 SSD1.23
SSD_PCIE_TX_CON_N3: C6316.1 SSD1.11
SSD_PCIE_TX_CON_P1: C6311.1 SSD1.37
SSD_PCIE_TX_CON_P2: C6313.1 SSD1.25
SSD_PCIE_TX_CON_P3: C6315.1 SSD1.13
SSD_PCIE_TX_N1: C6312.2 CPU1.BL4
SSD_PCIE_TX_N2: C6314.2 CPU1.BL2
SSD_PCIE_TX_N3: C6316.2 CPU1.BM4
SSD_PCIE_TX_P1: C6311.2 CPU1.BL3
SSD_PCIE_TX_P2: C6313.2 CPU1.BL1
SSD_PCIE_TX_P3: C6315.2 CPU1.BM3
SSD_SATA_RX_N: CPU1.BE5 ED6301.4 ED6301.7 SSD1.43
SSD_SATA_RX_P: CPU1.BE6 ED6301.5 ED6301.6 SSD1.41
SSD_SATA_TX_CON_N: C6303.1 ED6301.2 ED6301.9 SSD1.47
SSD_SATA_TX_CON_P: C6302.1 ED6301.1 ED6301.10 SSD1.49
SSD_SATA_TX_N: C6303.2 CPU1.BJ4
SSD_SATA_TX_P: C6302.2 CPU1.BJ3
SSD_SCP#: R6307.2 R6308.1 U2401.21
SSD_SCP#_1: R6308.2 SSD1.8
SSEQ0_A0: R7145.2 R7146.1 U7101.11
SSEQ1: R7144.1 R7152.2 U7101.3
SUS_CLK: CPU1.BT32 EC1803.1 FC1801.1 R2461.1
SUSACK#_R: CPU1.BY32 R1708.2
SVID_ALERT#_CPU: PR4605.2 PR4623.1 R727.2 R728.2
SVID_ALERT#_CPU_R: CPU1.AA3 R728.1
SVID_ALERT#_VR: PR4623.2 PU4601.36
SVID_CLK_CPU: PR4606.2 PR4624.1 R723.2 R732.2
SVID_CLK_CPU_R: CPU1.AA1 R732.1
SVID_CLK_VR: PR4624.2 PU4601.37
SVID_DATA_CPU: PR4604.2 PR4622.1 R709.2
SVID_DATA_CPU_R: CPU1.AA2 R709.1 R726.2
SVID_DATA_VR: PR4622.2 PU4601.35
SYS_LED_MASK#: R2410.2 U2401.55
SYS_LED_MASK#_R: R2410.1 R2456.1 R6419.1 U6402.2
SYS_PRES1#: AFTP4315.1 BATT1.7 R4301.2
SYS_PWROK: CPU1.CR10 ED1702.1 R1717.2 U2401.28
SYSPWR_PRES: R2454.1 R2463.2 U2401.120
T_CRIT#: R2601.1 R2604.2 U2601.4
TBTA_SENSEN: R7217.2 U7201.A10
TBTA_SENSEP: R7216.2 U7201.B10
TCH_INTR#: ED5502.1 R5523.1 TCBD1.16
TCH_PNL_3D3V_5V: R5508.1 R5509.2 R5512.2 R5541.1 U5503.5
TEST_MODE_1: RAM4.N9 TP1201.1
TEST_MODE_2: RAM1.N9 TP1202.1
TEST_MODE_3: RAM3.N9 TP1203.1
TEST_MODE_4: RAM2.N9 TP1204.1
TEST_MODE_5: RAM6.N9 TP1301.1
TEST_MODE_6: RAM8.N9 TP1302.1
TEST_MODE_7: RAM5.N9 TP1303.1
TEST_MODE_8: RAM7.N9 TP1304.1
THERM_SYS_SHDN#: Q2602.S R2601.2 R2602.1
THERMTRIP#_CPU: CPU1.BJ1 ED301.1 R308.2 TP309.1
TOUCH_DETECT: R2102.1 R5504.2 TCBD1.13
TOUCH_DETECT_R: CPU1.CN14 R2102.2
TOUCH_PANEL_INTR#: CPU1.CN3 R5505.1 R5507.1 R5523.2 U5504.2 U5504.9
TOUCH_PANEL_PD#: CPU1.CC35 TCBD1.15 U5504.1 U5504.10
TOUCH_REPORT_SW: D2402.A TCBD1.14
TP_65982D_RESET_N: R7229.2 TP7205.1
TP_EN#: R6504.1 RN2405.4(A) U2401.49
TP_ON#_GATE: C6502.2 Q6502.G Q6503.G R6504.2
TP_TPM_GPIO1: TP9103.1 U9102.30
TP_TPM_GPIO3: TP9102.1 U9102.6
TP_TPM_PP: TP9101.1 U9102.4
TP_WAKE_KBC#: AFTP6536.1 CPU1.CB34 R303.2 R6511.2 TP1.4 U2401.33
TPM_GPIO0: R9141.1 U9102.29
TPM_GPIO4: TP9104.1 U9102.13
TPM_ID: CPU1.CK25 R1910.2 R1911.1
TPM_SPI_IRQ#: CPU1.CF20 R9139.1
TYPEC_DCIN1_EN#: Q7402.5 Q7406.5 R7401.1 U2401.63
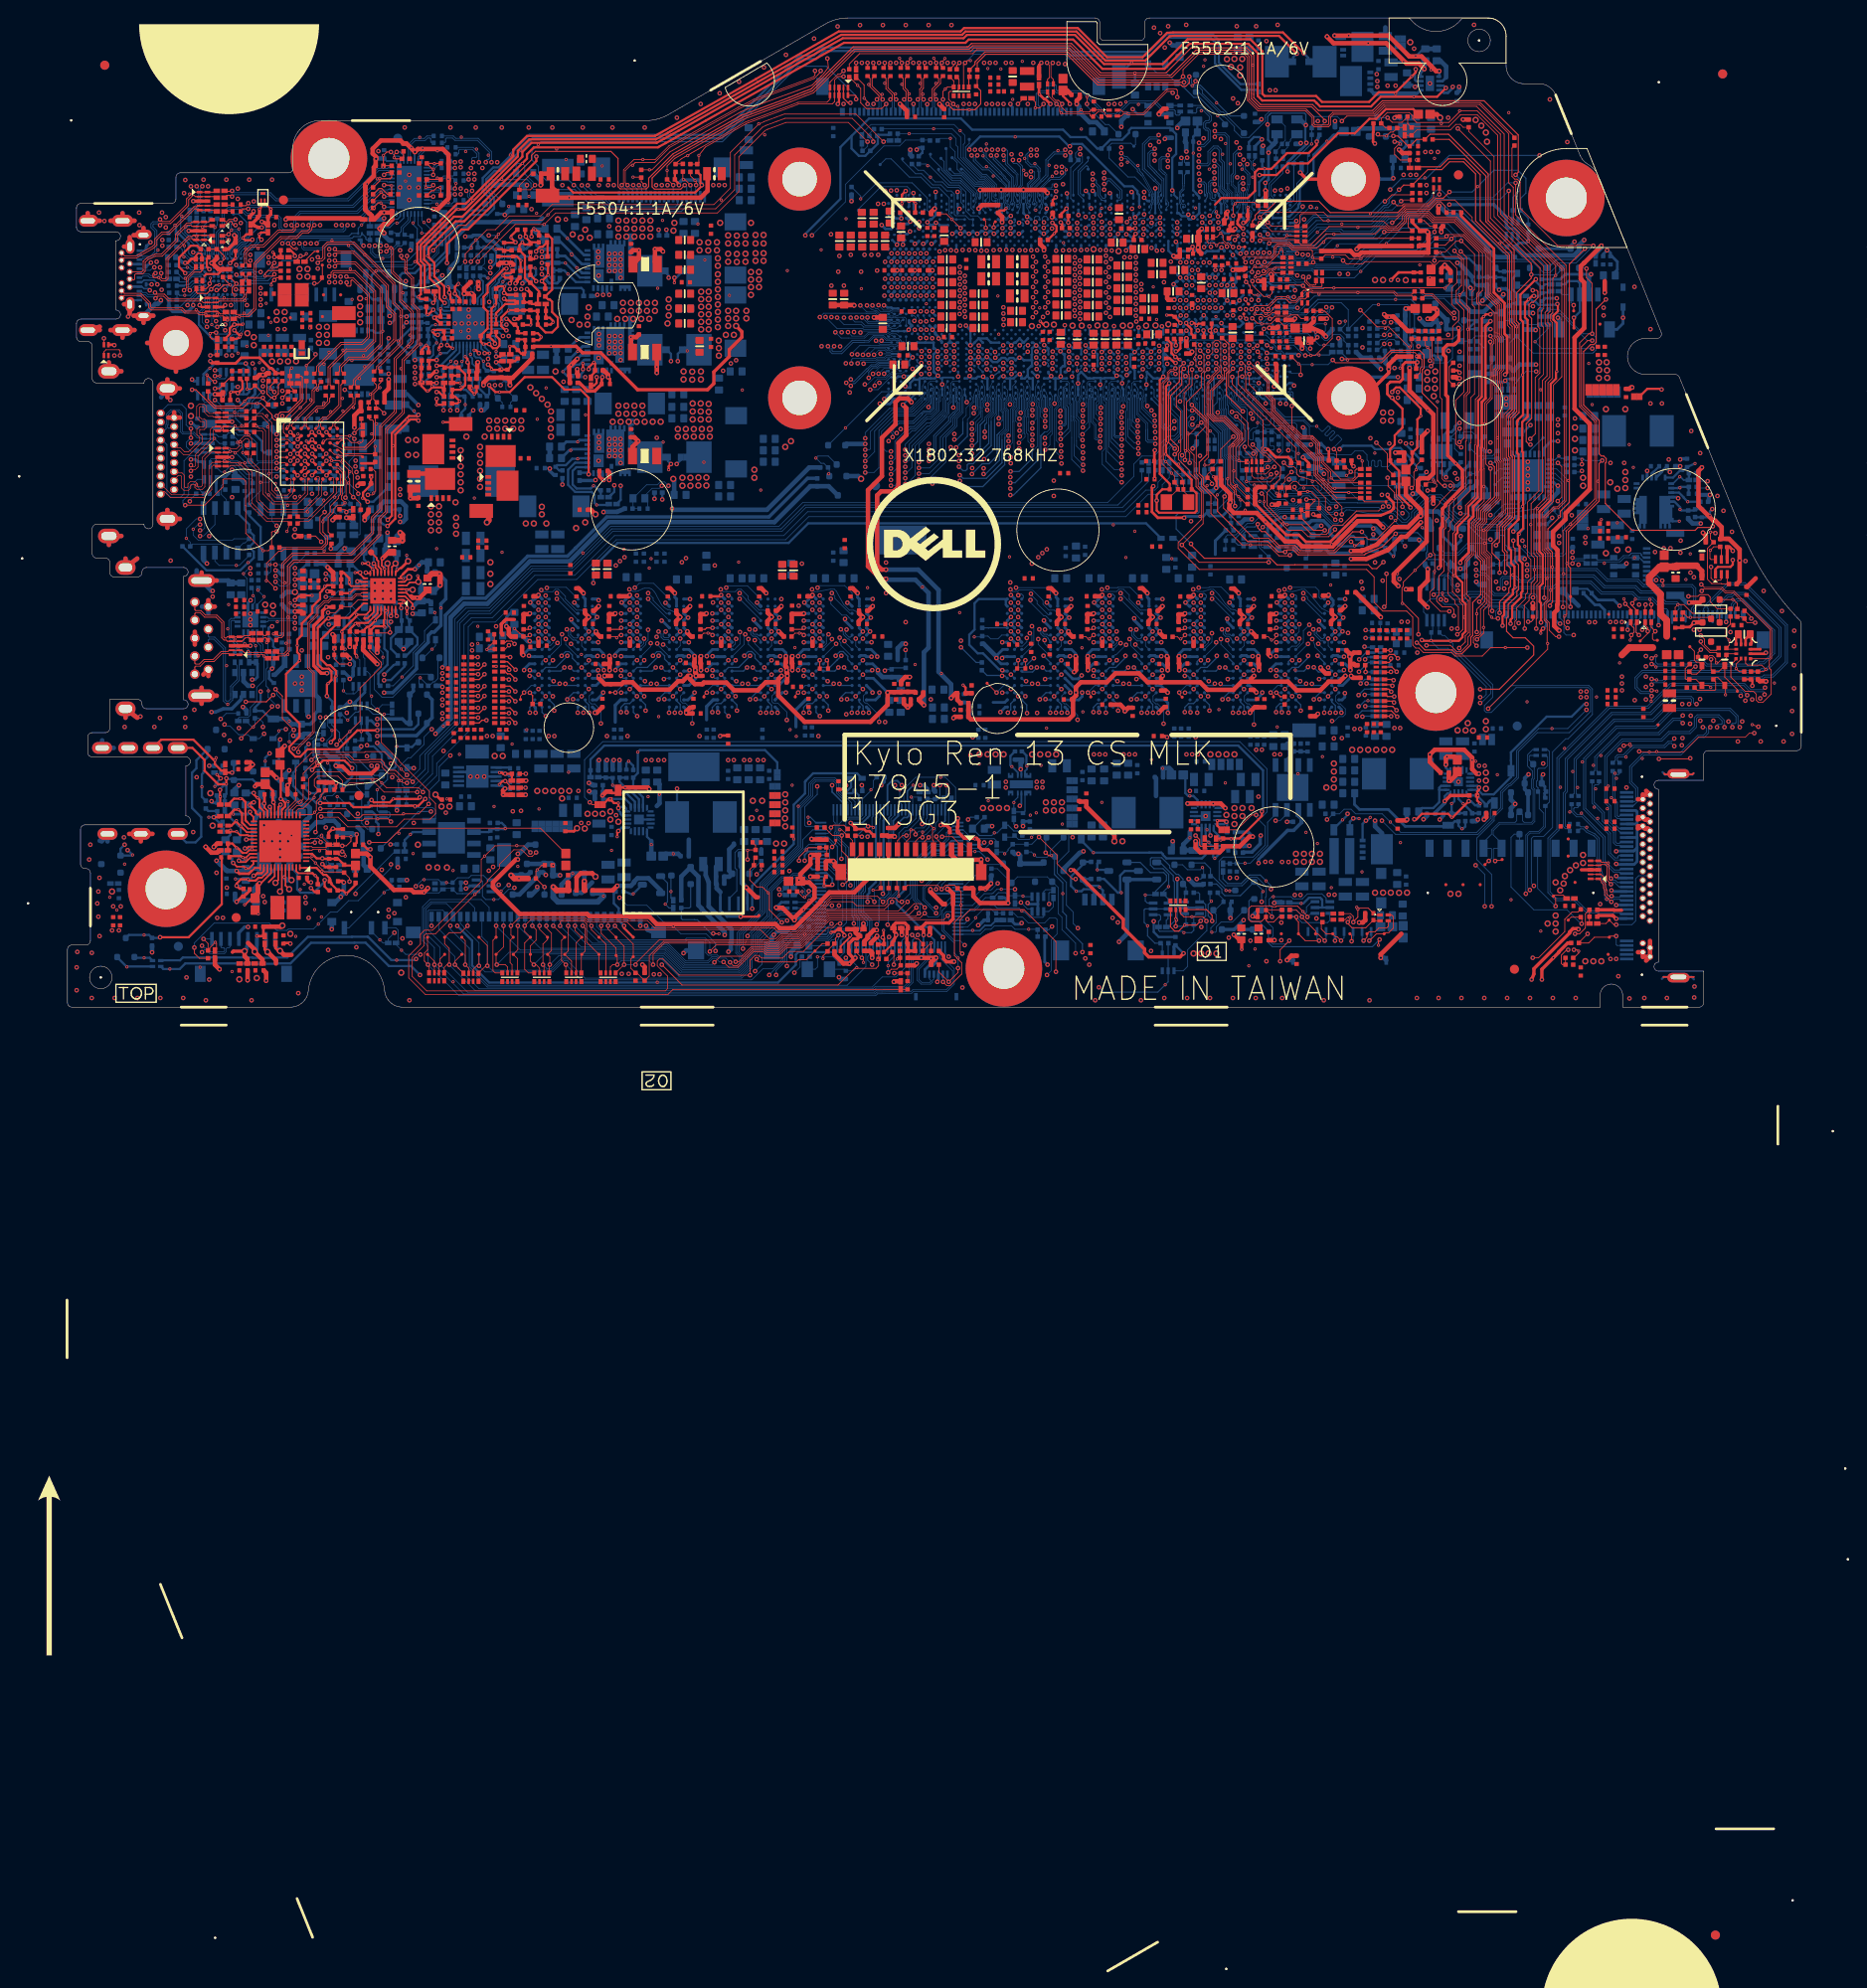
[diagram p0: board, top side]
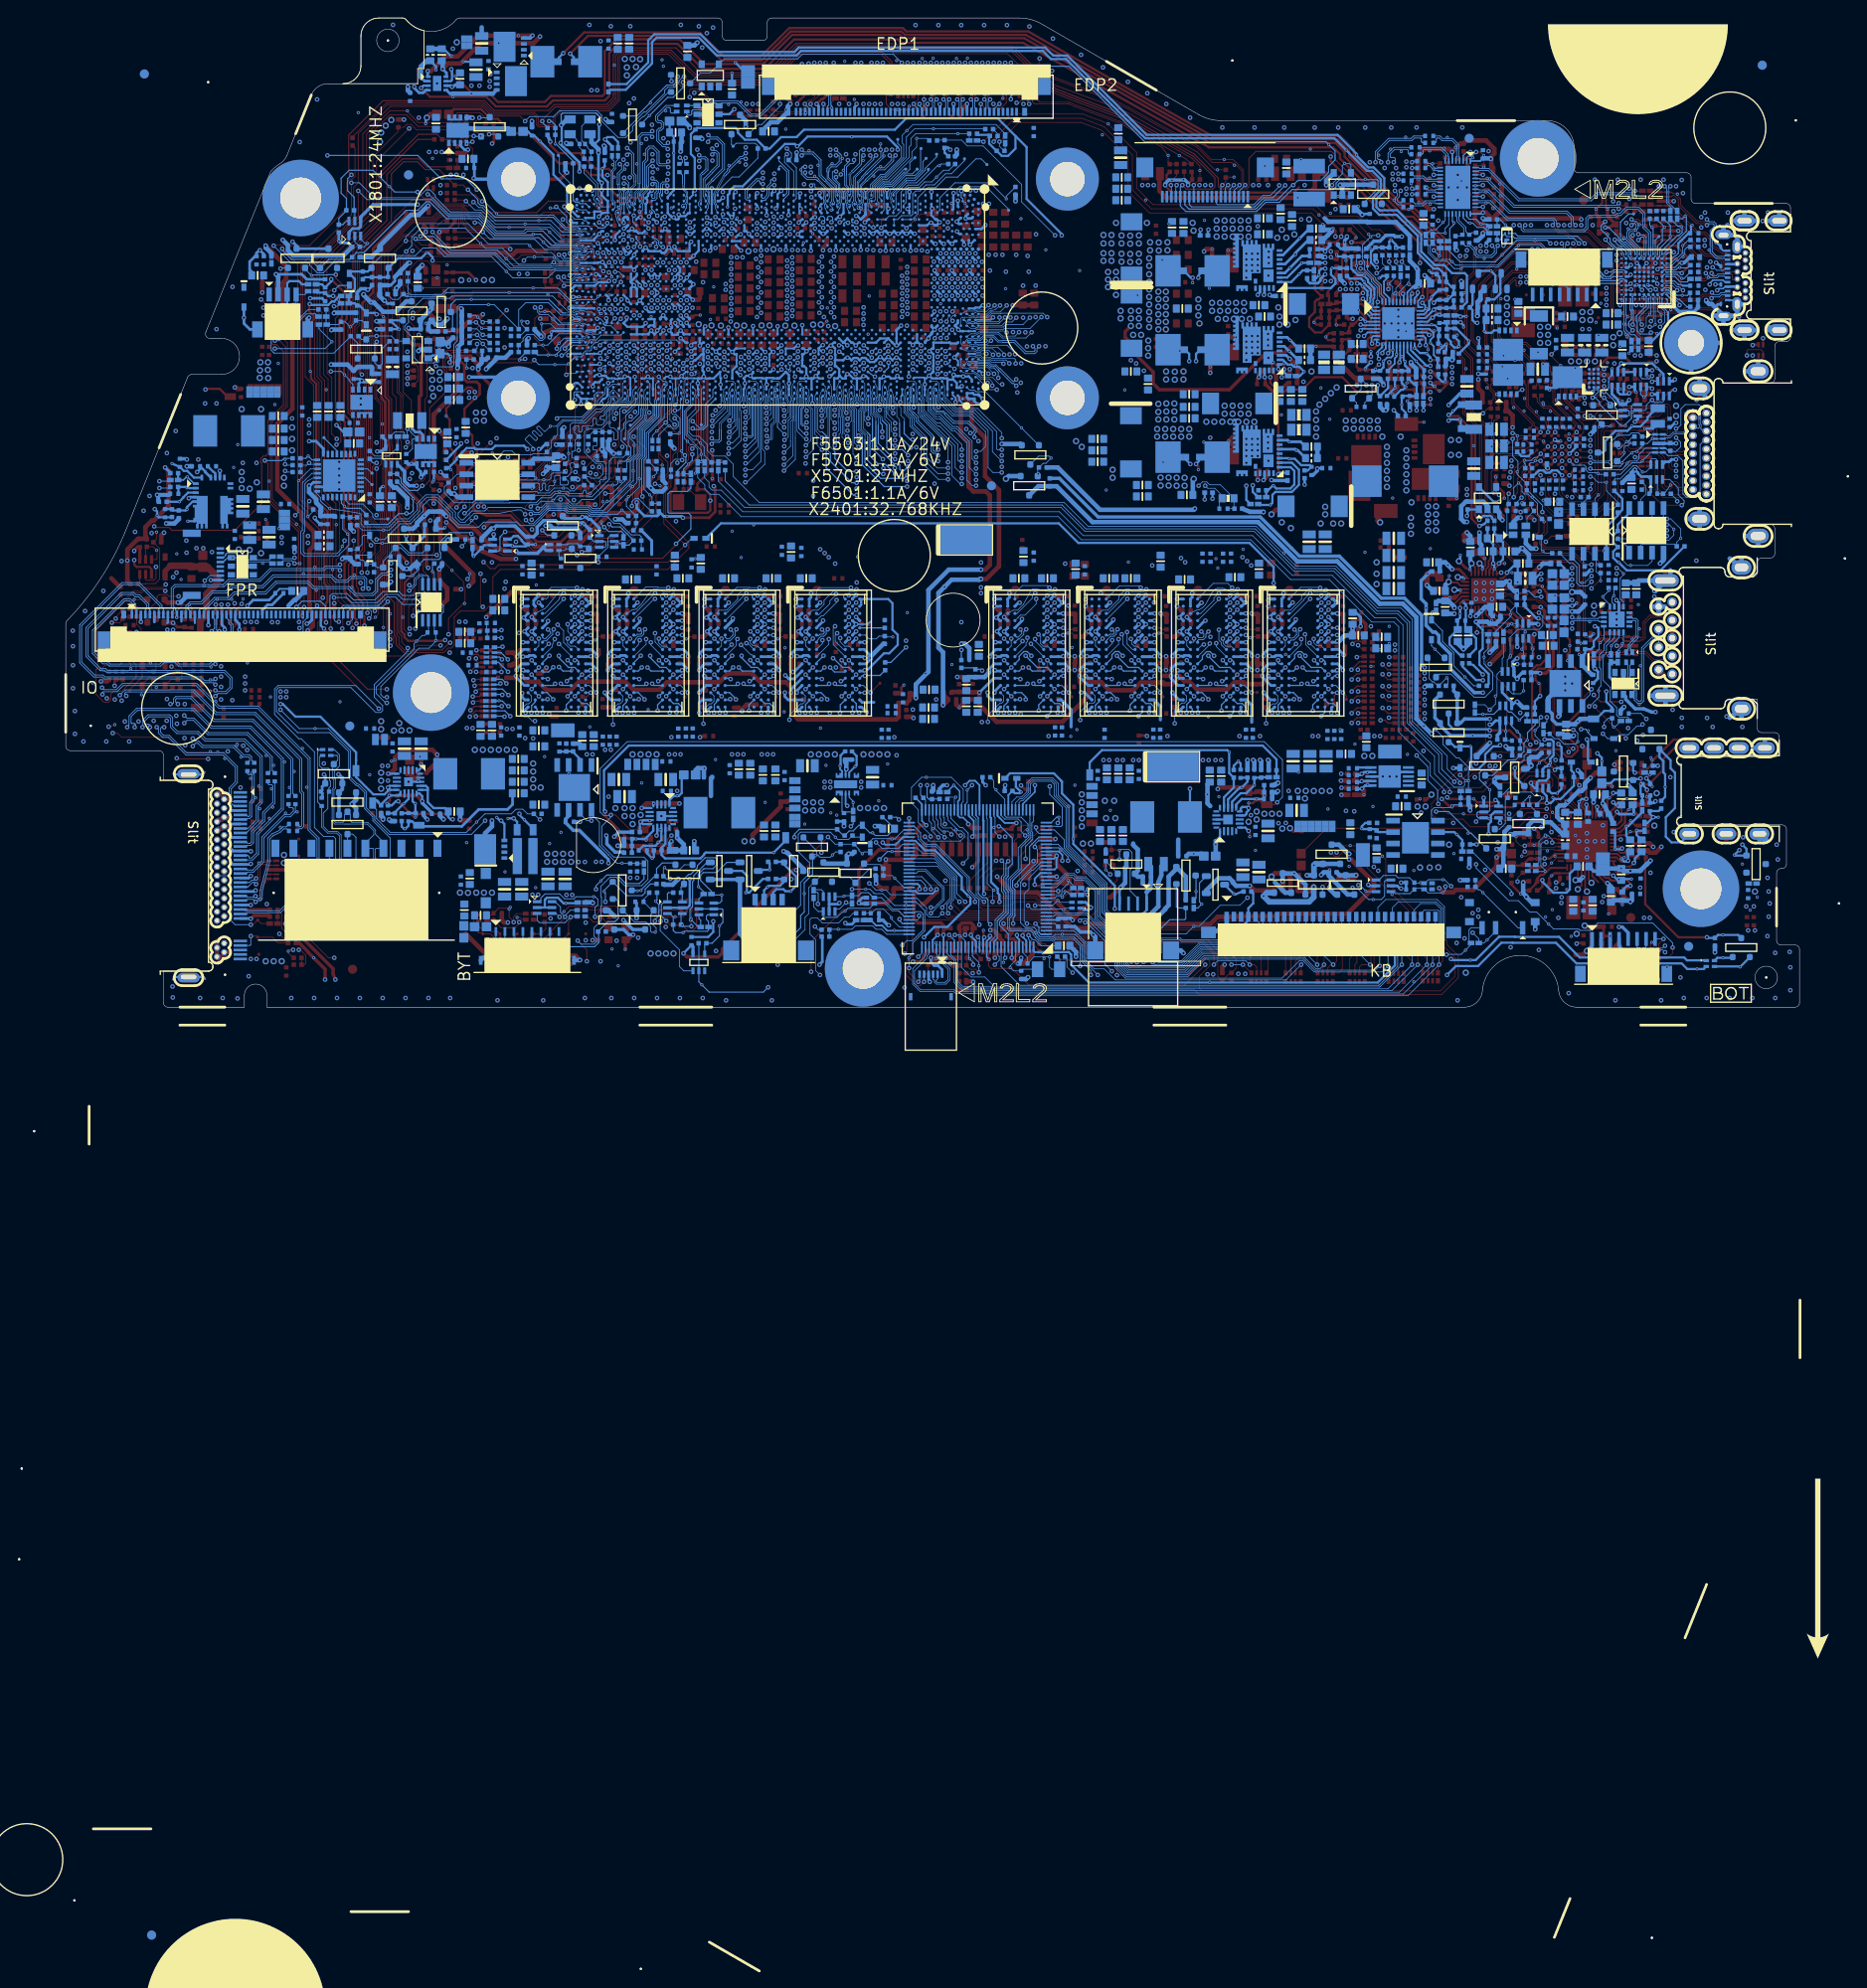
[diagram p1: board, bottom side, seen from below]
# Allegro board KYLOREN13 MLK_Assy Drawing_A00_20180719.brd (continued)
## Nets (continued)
TYPEC_SMBCLK: Q2417.1 R2468.2 RN2413.3(B) U2401.91
TYPEC_SMBCLK_Q: Q2417.6 R2468.1 R7220.1 U7201.B5
TYPEC_SMBDA: Q2417.4 R2467.2 RN2413.4(B) U2401.89
TYPEC_SMBDA_Q: Q2417.3 R2467.1 R7221.1 U7201.A5
U3_PD#_EC: IOBD1.40 R2404.2
UART_2_CRXD_DTXD: CPU1.CR12 R2048.2 R6803.1
UART_2_CRXD_DTXD_CON: DB1.14 R6803.2
UART_2_CTXD_DRXD: CPU1.CP12 R2049.2 R6802.1
UART_2_CTXD_DRXD_CON: DB1.13 R6802.2
UPD1_ALERT: R7215.1 R7235.1 U2401.32
UPD1_ALERT_R: R7235.2 U7201.B6
USB1_CC1: C7217.1 ED7304.2 R7211.2 U7201.L9 USB1.A5
USB1_CC2: C7218.1 ED7304.1 R7212.2 U7201.L10 USB1.B5
USB1_SBU1: ED7305.2 R7153.2 R7330.1 USB1.A8
USB1_SBU1_R: R7153.1 U7101.27
USB1_SBU2: ED7305.1 R7151.2 R7331.1 USB1.B8
USB1_SBU2_R: R7151.1 U7101.26
USB1_SSRX_CON_N1: ED7301.4 ED7301.7 R7120.2 USB1.B10
USB1_SSRX_CON_N2: ED7302.2 ED7302.9 R7123.2 USB1.A10
USB1_SSRX_CON_P1: ED7301.5 ED7301.6 R7119.2 USB1.B11
USB1_SSRX_CON_P2: ED7302.1 ED7302.10 R7122.2 USB1.A11
USB1_SSRX_MUX_N1: R7120.1 U7101.31
USB1_SSRX_MUX_N2: R7123.1 U7101.39
USB1_SSRX_MUX_P1: R7119.1 U7101.30
USB1_SSRX_MUX_P2: R7122.1 U7101.40
USB1_SSTX_CMC_N1: C7163.1 R7117.1
USB1_SSTX_CMC_N2: C7162.1 R7125.1
USB1_SSTX_CMC_P1: C7164.1 R7115.1
USB1_SSTX_CMC_P2: C7161.1 R7124.1
USB1_SSTX_CON_N1: ED7301.1 ED7301.10 R7117.2 USB1.A3
USB1_SSTX_CON_N2: ED7302.5 ED7302.6 R7125.2 USB1.B3
USB1_SSTX_CON_P1: ED7301.2 ED7301.9 R7115.2 USB1.A2
USB1_SSTX_CON_P2: ED7302.4 ED7302.7 R7124.2 USB1.B2
USB1_SSTX_MUX_N1: C7163.2 U7101.34
USB1_SSTX_MUX_N2: C7162.2 U7101.36
USB1_SSTX_MUX_P1: C7164.2 U7101.33
USB1_SSTX_MUX_P2: C7161.2 U7101.37
USB1_USB20_CON_N: EL6601.1 IOBD1.23
USB1_USB20_CON_P: EL6601.4 IOBD1.22
USB1_USB20_N: CPU1.CE3 EL6601.2
USB1_USB20_P: CPU1.CE4 EL6601.3
USB1_USB30_RX_N: CPU1.CB5 IOBD1.11
USB1_USB30_RX_P: CPU1.CB6 IOBD1.10
USB1_USB30_TX_N: CPU1.CA4 IOBD1.8
USB1_USB30_TX_P: CPU1.CA3 IOBD1.7
USB2_ID: CPU1.CE8 R1601.1
USB2_USB20_N: CPU1.CE1 U3401.2
USB2_USB20_P: CPU1.CE2 U3401.3
USB2_USB30_RX_CON_N: ED3501.1 ED3501.10 R3503.2 USB2.5
USB2_USB30_RX_CON_P: ED3501.2 ED3501.9 R3504.2 USB2.6
USB2_USB30_RX_N: CPU1.BY8 R3503.1
USB2_USB30_RX_P: CPU1.BY9 R3504.1
USB2_USB30_TX_CMC_N: C3501.2 R3501.1
USB2_USB30_TX_CMC_P: C3502.2 R3502.1
USB2_USB30_TX_CON_N: ED3501.4 ED3501.7 R3501.2 USB2.8
USB2_USB30_TX_CON_P: ED3501.5 ED3501.6 R3502.2 USB2.9
USB2_USB30_TX_N: C3501.1 CPU1.CA2
USB2_USB30_TX_P: C3502.1 CPU1.CA1
USB2_VBUSSENSE: CPU1.CC6 R1602.1
USB4_USB20_CMC_N1: EL7201.1 U7201.L6
USB4_USB20_CMC_N2: EL7202.1 U7201.L7
USB4_USB20_CMC_P1: EL7201.4 U7201.K6
USB4_USB20_CMC_P2: EL7202.4 U7201.K7
USB4_USB20_CON_N1: ED7303.1 ED7303.10 EL7201.2 USB1.A7
USB4_USB20_CON_N2: ED7303.4 ED7303.7 EL7202.2 USB1.B7
USB4_USB20_CON_P1: ED7303.2 ED7303.9 EL7201.3 USB1.A6
USB4_USB20_CON_P2: ED7303.5 ED7303.6 EL7202.3 USB1.B6
USB4_USB20_N: CPU1.CD3 U7201.K5
USB4_USB20_P: CPU1.CD4 U7201.L5
USB4_USB30_RX_C_N: C7106.2 U7101.4
USB4_USB30_RX_C_P: C7105.2 U7101.5
USB4_USB30_RX_N: C7106.1 CPU1.BW6
USB4_USB30_RX_P: C7105.1 CPU1.BW5
USB4_USB30_TX_C_N: C7104.2 U7101.7
USB4_USB30_TX_C_P: C7103.2 U7101.8
USB4_USB30_TX_N: C7104.1 CPU1.BW2
USB4_USB30_TX_P: C7103.1 CPU1.BW1
USB20_DN0_C: ED3503.1 EL3505.2 USB2.2
USB20_DP0_C: ED3503.6 EL3505.3 USB2.3
USB_ADT: PD4401.2 PD4408.2 R7410.1 U7418.5 U7418.6 U7418.7 U7418.8 U7419.A1 U7419.B1 U7419.C1 U7419.D1
USB_OC0#: CPU1.CK6 IOBD1.49 RN1601.5(B)
USB_OC1#: CPU1.CK5 RN1601.6(B) U3401.13
USB_OC2#: CPU1.CK8 RN1601.7(B)
USB_OC3#: CPU1.CK9 RN1601.8(B) U7201.B2
USB_PN0_R: EL3505.1 U3401.11
USB_POWERSHARE_VBUS_EN: U2401.71 U3401.5
USB_PP0_R: EL3505.4 U3401.10
USB_PWR_EN#: IOBD1.50 R2434.2 U2401.13
USB_PWR_SHR_EN#: R2401.1 U3401.6
USB_PWR_SHR_EN_L#: R2401.2 R2416.1 U2401.118
USBCOMP: CPU1.CC5 R1603.1
V_SM_VREF_CNTA: C1202.1 CPU1.F36 R1202.2
V_SM_VREF_CNTB: C1302.1 CPU1.E36 R1302.2
VCI_IN1#: R2497.1 U2401.126
VCREF0: C2409.1 R2424.2 R2448.1 U2401.25
VD_IN1_C: C2612.2 C2613.2 R2610.2 R2611.1
VR_CAP: C2418.1 U2401.18
VR_EN: PU4601.40 R4002.2
VR_RDY: PR4609.2 PU4601.39 TP4601.1
VRALERT#: CPU1.CC36 TP1708.1
VRAM_ID1: CPU1.CE27 R2034.1 R2035.2
VRAM_ID2: CPU1.CN23 R2037.1 R2038.2
VTT_CNTL: PR5125.1 Q502.D R507.2
WHITE_LED_BAT: Q6401.C R6402.1
WIFI_RF_EN: AFTP6110.1 CPU1.CG25 D6102.K IOBD1.47 R2107.2 R6108.2
WIFI_RF_EN_R: D6102.A R6108.1 R6109.2
WLAN_CLK_CPU_N: CPU1.BC1 IOBD1.14
WLAN_CLK_CPU_P: CPU1.BC2 IOBD1.13
WLAN_CLKREQ_CPU_N: AFTP6109.1 CPU1.CE32 IOBD1.45 RN1813.8(B)
WLAN_EN#: Q6102.D R6111.2 R6112.1
WLAN_EN_R#: C6102.2 Q6101.G R6112.2
WLAN_PCIE_RX_N: CPU1.BN6 IOBD1.4
WLAN_PCIE_RX_P: CPU1.BN5 IOBD1.5
WLAN_PCIE_TX_CON_N: C6107.1 IOBD1.2
WLAN_PCIE_TX_CON_P: C6108.1 IOBD1.1
WLAN_PCIE_TX_N: C6107.2 CPU1.BR4
WLAN_PCIE_TX_P: C6108.2 CPU1.BR3
XCLK_BIASREF: CPU1.CJ1 R1803.1
XDP_CLK_CPU_N: CPU1.AU1 TP1808.1
XDP_CLK_CPU_P: CPU1.AU2 TP1807.1
XDP_DBRESET#: CPU1.CN10 EC1706.1 R1701.2
XDP_PRDY#: CPU1.W1 TP306.1
XDP_PREQ#: CPU1.W2 TP305.1
XDP_TCLK: CPU1.P6 CPU1.T6 R317.1
XDP_TDI: CPU1.U5 CPU1.U6 TP311.1
XDP_TDO_CPU: CPU1.W5 CPU1.Y5 R310.1
XDP_TMS: CPU1.P5 CPU1.T5 TP313.1
XDP_TRST#: CPU1.AB6 CPU1.Y6 TP314.1
XTL_24M_X1_CPU: CPU1.CK3 R1839.1
XTL_24M_X1_R: C1807.1 R1839.2 R1841.1 X1801.3
XTL_24M_X2_CPU: CPU1.CK2 R1840.1
XTL_24M_X2_R: C1808.1 R1840.2 R1841.2 X1801.1
XTL_27M_X1_HDMI: C5729.1 R5750.1 U5701.E8 X5701.1
XTL_27M_X2_C: C5729.2 C5730.2 R5706.1 R5707.1
XTL_27M_X2_HDMI: R5748.1 R5750.2 U5701.F8
XTL_27M_X2_R: C5730.1 R5748.2 X5701.3
XTL_32K_X1_CPU: C1804.1 CPU1.BN31 R1815.1 X1802.1
XTL_32K_X2_CPU: C1803.1 CPU1.BN32 R1815.2 X1802.2

Pads without a net: CPU1 A34 A35 AA24 AA26 AB25 AC24 AC25 AC26 AD24 AD26 AE28 AE29 AF31 AF32 AG6 AG7 AH26 AJ27 AL1 AL2 AL3 AL4 AL34 AL35 AM3 AM4 AM7 AN1 AN2 AN3 AN4 AR3 AT3 AU3 AW2 AY3 AY9 B35 BB9 BB24 BC3 BC24 BC28 BD3 BE1 BE2 BH3 BH4 BJ34 BJ36 BK34 BK35 BK36 BL5 BL6 BL34 BL36 BL37 BN1 BN2 BN3 BN4 BN8 BN10 BP5 BP6 BP8 BP9 BP28 BP29 BP34 BP35 BR1 BR2 BR18 BT3 BT4 BT6 BT7 BT8 BT9 BT29 BT31 BU1 BU2 BU3 BU4 BU5 BU6 BU8 BU9 BU29 BU37 BV24 BV25 BV30 BW3 BW4 BW8 BW9 BW36 BY3 BY4 BY6 BY7 BY31 C34 CA32 CB8 CB9 CC27 CC29 CC30 CE28 CF12 CF17 CF22 CG1 CG2 CG3 CG4 CG14 CG35 CH5 CH6 CH7 CH8 CH9 CH17 CH19 CH25 CH29 CH30 CH32 CH35 CH36 CJ17 CJ20 CJ25 CJ29 CJ32 CK17 CK20 CK23 CK34 CL35 CL36 CM3 CM16 CM18 CM19 CM20 CM23 CM24 CM27 CM28 CM30 CM32 CM35 CN16 CN18 CN19 CN22 CN26 CN28 CN30 CN31 CN32 CN33 CN34 CN35 CN36 CP3 CP4 CP6 CP8 CP16 CP18 CP20 CP28 CP30 CP31 CP33 CP34 CR3 CR4 CR16 CR18 CR20 CR22 CR24 CR26 CR28 CR30 CR35 D34 D35 D37 F34 F37 G1 G2 G3 G4 H3 H4 J1 J2 J3 K12 K14 K15 K17 K18 K20 L1 L2 L3 L4 L5 L25 M3 M4 M24 M26 N1 N2 N3 N4 N5 P24 P26 R1 R2 R4 R24 R25 R26 T3 T4 T25 T29 T31 T32 U34 U35 U37 V24 V25 V28 V29 W3 W25 Y3 Y24 Y25; DB1 1 12; DCIN1 5; ED1701 2; ED1702 2; ED2403 2; ED3503 3 4; ED5501 3 4; ED5502 2; ED9202 3 4; HDMI1 14; IOBD1 25 31 37 42; KBBD1 2 3; KBBL1 3; LCD1 5 29 34 35 36 38 48; PU4501 15; PU4701 4 6 27 30 31 35; PU4801 4 6 27 30 31 35; PU4802 4 6 27 30 31 35; PU5101 12; RAM1 T7; RAM2 T7; RAM3 T7; RAM4 T7; RAM5 T7; RAM6 T7; RAM7 T7; RAM8 T7; SSD1 6 20 22 24 26 28 30 32 34 36 40 42 44 46 48 54 56 58 67 68; TCBD1 2 19; U2401 3 10 23 35; U2502 3; U2701 1 8 9 10 11 12; U3401 9; U5501 3; U5701 F3; U5704 7; U7201 F4 G4 L11; U9102 2 3 5 7 9 10 11 12 14 15 25 26 27 28 31

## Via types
v1: diameter 0.356, hole 0.178, TOP to BOTTOM, 1124 vias
v2: diameter 0.508, hole 0.254, TOP to BOTTOM, 3843 vias
v3: diameter 0.711, hole 0.406, TOP to BOTTOM, 466 vias

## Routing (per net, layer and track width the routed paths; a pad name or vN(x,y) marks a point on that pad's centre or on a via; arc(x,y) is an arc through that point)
1.8V_RUN_FB: length 4.9
  BOTTOM w0.254: PR5304.1 48.26,20.47 48.64,20.08 v1(48.64,19.83) 48.51,19.83 48.46,19.78 PC5305.2 47.14,19.78 PR5303.2 46.81,19.45 PU5301.2
1V_CPU_CORE: length 34.2
  TOP w0.381: v3(74.3,75.68) 74.93,75.05 74.93,74.44 73.53,73.04 73.53,72.28 71.82,70.57 71.82,69.3 71.12,68.6 63.36,68.6 59.25,72.7 57.24,72.7 56.52,73.42 v1(53.72,73.42) 51.82,73.42 PR4631.2
  BOTTOM w0.254: v2(113.16,90.7) 113.55,90.3 CPU1.AV2 ; v2(115.82,90.44) 115.99,90.28 CPU1.BB2 ; v2(111.05,90.42) 111.11,90.36 CPU1.AP2 ; v2(118.24,90.57) 118.43,90.37 CPU1.BF2 ; CPU1.BF9 CPU1.BE9
  vias: v1(70.82,83.03) v1(73.56,79.09) v1(86.51,87.6) v1(108.03,77.69) v1(110.67,84.93) v1(114.91,88.77) v2(107.28,83.39) v2(107.26,82.27) v2(107.28,81.18) v2(107.28,80.01) v2(107.28,78.87) v2(107.28,77.75) v2(107.26,76.66) v2(107.61,82.8) v2(107.61,81.74) v2(107.61,80.59) v2(107.61,79.45) v2(107.61,78.31) v2(107.61,77.19) v2(108.4,76.68) v2(108.63,83.39) v2(108.6,82.27) v2(108.63,81.18) v2(108.63,80.01) v2(108.63,78.87) v2(108.63,77.75) v2(108.91,77.14) v2(108.96,82.8) v2(108.96,81.74) v2(108.96,80.59) v2(108.96,79.45) v2(108.96,78.31) v2(109.39,86.51) v2(110.62,84.09) v2(111.3,84.1) v2(111.93,84.13) v2(112.18,87.15) v2(112.18,86.51) v2(112.18,85.88) v2(113.28,84.15) v2(113.99,87.17) v2(114.01,86.54) v2(113.99,85.88) v2(114.75,84.13) v2(114.93,87.25) v2(114.95,85.88) v2(115.39,83.49) v2(115.39,82.78) v2(115.36,81.66) v2(115.39,80.57) v2(115.39,79.4) v2(115.39,78.26) v2(115.39,77.14) v2(115.72,82.19) v2(115.72,81.13) v2(115.72,79.99) v2(115.72,78.84) v2(115.72,77.7) v2(115.84,87.12) v2(115.85,85.84) v2(115.84,76.68) v2(115.86,86.49) v2(115.94,83.13) v2(116.03,84.07) v3(68.45,70.63) v3(68.45,69.74) v3(69.42,70.6) v3(69.42,69.72) v3(70.23,84.98) v3(70.23,84.09) v3(70.41,79.49) v3(70.41,78.66) v3(70.41,77.82) v3(70.41,76.98) v3(70.41,76.14) v3(70.41,75.3) v3(70.38,70.63) v3(70.38,69.74) v3(71.2,84.96) v3(71.2,84.07) v3(71.25,79.49) v3(71.25,78.66) v3(71.25,77.82) v3(71.25,76.98) v3(71.25,76.14) v3(71.25,75.3) v3(72.16,84.98) v3(72.16,84.09) v3(72.26,83.2) v3(72.26,82.36) v3(72.26,81.43) v3(72.26,80.59) v3(72.26,79.75) v3(72.26,78.91) v3(72.26,78.07) v3(72.26,77.23) v3(72.26,76.4) v3(72.26,75.56) v3(73.41,85.74) v3(73.41,84.85) v3(73.41,83.71) v3(73.41,82.82) v3(73.41,77.36) v3(73.41,76.52) v3(73.41,75.68) v3(74.3,77.36) v3(74.3,76.52) v3(74.37,85.72) v3(74.37,84.83) v3(74.37,83.69) v3(74.37,82.8) v3(75.34,85.74) v3(75.34,84.85) v3(75.34,83.71) v3(75.34,82.82) v3(75.44,77.36) v3(75.44,76.52) v3(75.95,81.68) v3(75.95,80.84) v3(75.95,80) v3(75.95,79.14) v3(76.45,85.79) v3(76.45,84.85) v3(76.45,83.76) v3(76.45,82.92) v3(76.83,81.68) v3(76.83,80.84) v3(76.83,80) v3(77.34,85.79) v3(77.34,84.85) v3(77.34,83.76) v3(77.34,82.92) v3(111.68,75.72) v3(112.69,75.72) v3(114.01,84.2) v3(114.45,75.74) v3(115.33,75.74) v3(116.79,83.99) v3(117.26,75.72) v3(118.1,75.74)
1V_GT_CORE: length 11.1
  TOP w0.508: v2(108.88,90.46) 108.88,90.48 108.55,90.81 v2(106.23,90.81) v2(103.75,90.81) 101.42,90.81 v2(101.41,90.8)
  BOTTOM w0.203: CPU1.AF2 v2(106.23,90.81) ; CPU1.AB2 103.79,89.89 103.79,90.77 v2(103.75,90.81)
  BOTTOM w0.254: v2(108.88,90.46) 108.88,90.1 CPU1.AK2 ; CPU1.V2 101.41,89.96 v2(101.41,90.8)
  vias: v1(103.38,79.01) v1(107.59,88.56) v2(102.91,84.1) v2(103.6,84.15) v2(105,84.13) v2(105.79,84.09) v2(106.43,84.09) v2(107.74,84.1)
1V_VCCGT: length 32.9
  L4SGND w0.305: v2(45.09,66.31) 45.97,67.2 50.8,67.2 52.32,65.68 52.32,63.14 52.96,62.5 54.86,62.5 60.2,67.84 68.71,67.84 v3(69.47,67.07)
  BOTTOM w0.254: CPU1.K2 v2(96.46,90.58) ; CPU1.P2 v2(98.91,90.58) ; v2(45.09,66.31) 44.63,65.85 PR4663.1
  vias: v1(70.71,60.55) v1(74.98,68.57) v1(79.98,81.83) v1(83.74,84.14) v1(84.58,59.25) v1(88.21,79.82) v1(95.43,78.15) v2(84.88,80.16) v2(85.64,81.71) v2(85.77,83.46) v2(86.28,80.16) v2(87.04,83.59) v2(88.18,81.71) v2(88.56,83.59) v2(89.32,83.59) v2(89.96,81.84) v2(90.09,83.59) v2(90.85,82.81) v2(90.85,80.92) v2(90.77,79.99) v2(90.77,79.05) v2(91.56,83.75) v2(91.56,80.92) v2(91.56,79.99) v2(92.22,83.75) v2(92.2,82.81) v2(92.2,80.92) v2(92.22,79.99) v2(92.22,79.05) v2(92.86,83.75) v2(92.86,82.81) v2(92.86,80.92) v2(92.86,79.99) v2(92.86,79.05) v2(93.52,83.75) v2(93.52,80.92) v2(93.52,79.99) v2(94.16,83.74) v2(94.18,82.81) v2(94.18,80.92) v2(94.16,79.97) v2(94.16,79.03) v2(94.63,87.22) v2(94.63,86.54) v2(94.81,83.75) v2(94.81,82.81) v2(94.81,80.92) v2(94.81,79.99) v2(94.81,79.05) v2(95.45,83.75) v2(95.45,80.92) v2(95.45,79.99) v2(96.13,80.92) v2(96.13,79.05) v2(96.18,82.83) v2(96.16,79.99) v2(96.9,83.97) v2(97.53,84.1) v2(98.16,84.11) v2(99.46,84.13) v2(100.2,84.13) v2(100.88,84.1) v2(102.15,84.05) v3(67.82,64.23) v3(67.82,63.39) v3(68.33,58.82) v3(68.33,57.93) v3(68.71,64.23) v3(68.71,63.39) v3(69.22,58.82) v3(69.22,57.93) v3(69.47,66.19) v3(69.47,65.3) v3(69.6,64.23) v3(69.6,63.39) v3(70.1,58.84) v3(70.1,57.96) v3(70.36,67.07) v3(70.36,66.19) v3(70.36,65.3) v3(70.48,64.23) v3(70.48,63.39) v3(70.99,58.84) v3(70.99,57.96) v3(71.25,67.02) v3(71.25,66.13) v3(71.25,65.3) v3(71.37,64.23) v3(71.37,63.39)
1V_VCCIO: length 26.3
  TOP w0.254: v3(108.75,75.84) 108.45,75.84 v1(108.08,76.22)
  TOP w0.508: R401.1 108.07,84.79 108.5,84.35 v2(108.5,84.1)
  L6 w0.508: v2(108.5,84.1) 108.98,84.1 109.8,84.91 117.64,84.91 118.54,84.02 118.71,83.95 119.91,83.95 122.9,80.95 v2(122.9,80.32) 122.9,79.87 122.05,79.01 122.05,77.91 v3(119.86,75.72)
  BOTTOM w0.305: CPU1.BP16 123.22,80.63 v2(122.9,80.32) 123.34,79.88 CPU1.BP18
  vias: v1(151.13,66.31) v2(129.51,72.85) v2(132.94,75.36) v3(109.6,75.84) v3(146.18,66.06) v3(146.18,65.17) v3(147.07,66.06) v3(147.07,65.17)
1V_VCCIO_R:
  vias: v1(157.48,64.79)
1V_VCCSA:
  vias: v1(119.13,88.92) v1(120.65,80.03) v1(121.02,76.4) v1(125.35,88.79) v1(126.24,104.54) v1(131.7,104.67) v2(119.55,85.85) v2(120.49,85.85) v2(120.45,84.35) v2(121.41,85.85) v2(121.67,84.09) v3(120.9,75.74) v3(122.32,75.87) v3(128.83,105.33) v3(129.29,104.46) v3(129.67,105.35) v3(130.3,104.41) v3(130.3,103.52) v3(130.53,105.35)
1V_VCCST_CPU: length 162.7
  TOP w0.254: v2(132.45,92.45) 134.35,92.45 135.64,93.74 137.85,93.74 141.19,97.08 143.04,97.08 144.65,98.7 145.41,98.7 146.49,99.78 149.54,99.78 150.09,99.23 R4036.2 ; C806.1 125.06,84.43 v2(125.01,84.48) 124.68,84.15 C805.1
  L4SGND w0.127: v2(132.45,92.45) 131.17,91.17 131.17,85.06 130.84,84.73 130.43,84.73 130.13,85.03 130.13,85.42 129.88,85.66 128.83,85.66 127.16,83.99 125.45,83.99 125.01,84.42 v2(125.01,84.48)
  L4SGND w0.254: v2(123.16,85.03) 123.8,85.67 123.8,87.39 122.76,88.44 v2(122.76,90.75)
  L6 w0.254: v2(81.98,85.75) 81.14,86.6 78.73,86.6 76.72,88.61 54.7,88.61 52.77,86.68 49.76,86.68 48.64,85.56 48.64,85.01 47.62,83.99 47.62,82.44 47.37,82.19 v2(46.99,82.19)
  BOTTOM w0.203: CPU1.BP2 122.97,90.23 122.97,90.53
  BOTTOM w0.254: v2(46.99,82.19) 47.07,82.19 47.62,82.74 47.62,83.91 PC4602.1 47.09,84.4 PR4603.1 PR4606.1 45.59,85.06 v1(45.39,85.26) 44.83,84.7 PR4605.1 PR4604.1 ; R726.1 91.26,96.92 90.09,96.92 R727.1 90.04,96.72 90.04,95.95 89.24,95.14 R723.1 88.65,94.58 87.93,94.58 87.12,95.4 87.12,96.79 ; v2(125.01,84.48) 125.01,84.37 CPU1.BT11 CPU1.BR11 CPU1.BP11 123.34,84.86 v2(123.16,85.03) ; v2(81.98,85.75) 81.98,85.9 85.88,89.8 85.88,95.55 87.12,96.79 ; 87.12,96.79 89.06,98.73 99.28,98.73 100.52,97.49 110.62,97.49 111.44,96.67 113.16,96.67 114.43,95.4 R308.1 115.86,96.37 117.18,96.37 117.96,97.15 117.96,97.43 118.21,97.68 122.5,97.68 C801.2 123.19,97 123.19,94.79 122.76,94.36 v2(122.76,90.75) 122.97,90.53
1V_VCCST_CPU_R: length 2
  TOP w0.508: R4036.1 152.15,99.21 v3(152.53,98.82)
  BOTTOM w0.254: v1(152.65,98.16) 152.65,98.7 v3(152.53,98.82)
1V_VCCSTG: length 140.6
  TOP w0.254: v2(109.8,89.99) 109.47,89.67 C802.2
  L4SGND w0.254: v2(162.56,64.66) 163.8,65.91 163.8,75.96 163.17,76.6 162.63,76.6 162.14,77.09 162.14,82.99 158.47,86.66 158.47,97.43 156.18,99.71 142.93,99.71 142.34,100.3 132.46,100.3 132,100.75 132,106.39 130.38,108.02 122.3,108.02 121.93,107.64 v2(121.93,106.62) ; v2(100.2,95.28) 94.37,95.28 v2(94.36,95.27)
  L6 w0.254: v2(121.93,106.62) 121.81,106.62 121.74,106.54 121.68,106.54 119.81,104.67 116.88,104.67 112.65,100.43 112.65,96.92 v2(111.38,95.65) 111.51,95.65 112.01,95.14 112.01,90.58 111.24,89.81 109.98,89.81 v2(109.8,89.99)
  BOTTOM w0.254: v2(100.2,95.28) 100.2,95.52 101.41,96.73 105.27,96.73 v1(105.31,96.69) 105.35,96.73 110.21,96.73 111.28,95.65 v2(111.38,95.65) 111.63,95.9 112.73,95.9 117.43,91.2 118.36,91.2 118.89,90.68 118.89,90.41 CPU1.BG1 CPU1.BG2 CPU1.BG3 ; v2(162.56,64.66) 161.8,63.9 R4043.2 ; R310.2 94.95,94.9 95,94.9 R301.1 94.96,95.51 94.6,95.51 v2(94.36,95.27)
1V_VREF_CPU: length 5.5
  BOTTOM w0.203: U2401.95 100.55,8.49 v1(100.58,8.53) 100.62,8.49 101.36,8.49 101.94,9.07 102.6,9.07 C2406.1
  BOTTOM w0.508: R2402.2 C2406.1
3V5V_CT1: length 3
  BOTTOM w0.203: v1(106.6,26.79) 106.6,26.44 106.39,26.23 U4001.12
  BOTTOM w0.254: C4001.1 106.1,28.42 106.55,27.96 106.55,26.94 106.6,26.89 v1(106.6,26.79)
3V5V_CT2: length 3.2
  BOTTOM w0.203: 104.95,26.72 105.59,26.07 U4001.10
  BOTTOM w0.254: C4002.1 104.78,27.91 104.78,26.89 v1(104.94,26.73) 104.95,26.72
3V5V_S0_ON: length 5.6
  BOTTOM w0.127: U4001.3 106.39,21.78 C4003.1 106.05,21.68 105.26,21.68 R4010.2 v1(105.16,22.73) 105.16,22.87 105.59,23.31 U4001.5
3V_5V_DSW_OK: length 214.7
  TOP w0.102: v2(158.12,74.57) 158.12,74.49 158.5,74.1 158.5,73.76 158.31,73.57 158.31,70.09 158.31,67.64 157.68,67.01 157.68,62 157.61,61.92 157.61,60.34 v2(158.12,59.84) 158.12,56.58 156.79,55.26 156.79,54.29 156.24,53.73 156.24,50.28 155.6,49.64 155.6,49.63 155.5,49.53 155.5,45.81 155.87,45.45 155.87,41.36 155.63,41.12 155.63,40.3 154.81,39.49 154.38,39.49 153.67,40.2 151.01,40.2 v2(151,40.19)
  L4SGND w0.102: v2(40.48,30.88) 41.02,30.88 42.49,29.41 77,29.41 81.25,25.16 86.59,25.16 87.58,24.18 92.87,24.18 95.63,26.94 111.43,26.94 113.66,29.18 125.69,29.18 126.14,29.63 139.83,29.63 140.17,29.3 141.94,29.3 142.45,29.81 147.86,29.81 148.36,29.81 149.12,30.57 149.12,31.44 148.95,31.61 148.95,36.75 151,38.8 v2(151,40.19) ; v2(182.25,57.68) 182.07,57.5 182.07,56.64 183.57,55.13 183.57,54.94 183.58,54.94 183.58,54.6 183.57,54.59 183.57,54.53 182.89,53.85 182.64,53.85 182.09,53.31 180.87,53.31 180.12,54.06 171.16,54.06 170.95,54.27 169,56.22 167.72,56.22 166.83,57.1 166.41,57.1 160.85,57.1 v2(158.12,59.84)
  BOTTOM w0.102: v2(182.25,57.68) 181.15,57.68 PR5210.1 ; PR5306.1 v1(36.78,25.16) 36.78,26.64 37.85,27.7 38.14,27.7 39.62,29.19 39.62,30.02 v2(40.48,30.88) ; R2513.2 159.76,74.18 D2503.3 158.88,74.57 v2(158.12,74.57) 156.46,74.57 155.91,74.02 R2514.2 155.88,74 U2502.4
3V_5V_EN: length 34.6
  TOP w0.127: v2(125.35,19.07) 125.79,18.62 125.79,18 125.92,17.87 PR4516.1 PR4515.2
  L4SGND w0.127: v2(111.68,18.88) 113.05,18.88 114.64,17.29 125.22,17.29 125.79,17.86 125.79,18.62 125.35,19.06 v2(125.35,19.07)
  BOTTOM w0.127: v2(111.68,18.88) 111.68,19.21 111.14,19.75 R4006.1 106.25,19.07 R4014.1 105.59,19.58 105.16,19.58 104.52,20.21 D4001.A 103.3,19.37 v1(103,19.37) 102.69,19.07 101.32,19.07 C4009.1 101.83,21.1 R4009.1
3V_5V_POK#: length 6.1
  BOTTOM w0.254: R1726.2 141.55,51.2 143,51.2 143.13,51.33 Q1701.2 ; R1726.2 v1(140.46,51.4) ; R1726.2 141.55,51.4 141.99,51.83 141.99,51.92 142.4,52.34 142.88,52.34 143.24,51.98 Q1701.3
3V_5V_POK_C: length 3.6
  BOTTOM w0.254: Q1701.5 146.13,51.33 R1727.2 146.43,50.97 v1(147.32,50.08) 147.45,50.21 R1728.1
3V_5V_PWRGD: length 290.6
  TOP w0.102: v2(135.76,7.38) 134.75,6.37 v2(134.75,5.1) ; v2(166.17,44.45) 166.17,48.07 v1(166.24,48.15) 166.17,48.23 166.17,52.92 169.7,56.45 169.7,65.05 168.02,66.72 168.02,73.81 169.04,74.82 v2(169.42,74.82) 169.42,80.41 168.78,81.04 v2(168.78,82.06) ; v2(132.08,21.35) 131.57,21.35 129.92,19.7 PG4531.1 ; v2(58.04,22.75) 58.29,22.5 PG4529.1
  L4SGND w0.102: v2(148.62,51.21) 148.62,51.23 148.79,51.4 152.6,51.4 153.71,50.3 157.5,50.3 158.24,49.55 158.24,49.35 158.24,46.65 161.09,43.81 165.52,43.81 v2(166.17,44.45)
  L6 w0.102: v2(134.75,5.1) 136.33,3.51 162.43,3.51 162.48,3.56 165.15,3.56 165.15,3.56 169.32,7.72 169.32,10.06 167.74,11.64 167.74,13.6 168.64,14.5 169.11,14.5 170.82,16.21 170.82,16.83 170.82,17.77 171.51,18.47 171.51,26.22 173.74,28.44 173.74,30.75 172.26,32.23 172.26,37.56 167.51,42.31 167.51,42.91 166.24,44.18 166.24,44.38 v2(166.17,44.45)
  BOTTOM w0.102: ED1703.1 168.71,82.13 v2(168.78,82.06) ; D2503.1 160.22,73.78 R2513.1 162.86,72.66 169.48,72.66 169.58,72.76 169.59,72.76 169.82,73 169.82,74.41 v2(169.42,74.82) 168.4,74.82 165.71,77.51 R4033.1 ; v2(58.04,22.75) 57.45,23.34 57.45,27.48 59.47,29.49 130.27,29.49 133.27,26.49 133.27,21.68 132.89,21.3 132.13,21.3 v2(132.08,21.35) 132.08,21.1 133.08,20.1 133.08,18 131.75,16.67 128.4,16.67 127.97,16.23 127.97,14.19 128.66,13.49 130.53,13.49 131.47,14.43 132.18,14.43 133.2,13.41 133.2,12.29 133.12,12.21 133.12,11.25 133.17,11.21 133.17,9.6 133.96,8.81 133.96,7.89 133.68,7.61 133.68,7.26 133.93,7 135.38,7 v2(135.76,7.38) ; R1728.2 147.52,51.96 C1710.1 148.26,51.58 148.62,51.22 148.62,51.21 v2(148.62,51.21)
3V_S5_EN: length 0.9
  BOTTOM w0.254: PU4501.12 126.92,19.15 v2(127,19.07)
  vias: v1(126.62,19.7)
5V_AUX_S5: length 2
  TOP w0.305: PG4528.2 60.48,23.79 PR4510.2
  TOP w0.508: PR4510.2 59.87,23.94 v1(59.44,23.51)
5V_FAN_VCC: length 1.3
  TOP w0.508: AFTP2603.1 v2(170.81,79.39)
5V_HDMI_S0: length 3.5
  TOP w0.508: HDMI1.18 12.49,65.5 ; HDMI1.18 11.21,65.5 ; HDMI1.18 11.85,66.08
  BOTTOM w0.254: v1(17.2,64.28) 16.28,64.28 F5701.2
  vias: v3(13.72,65.68)
5V_KB_BL: length 10.1
  TOP w0.254: v2(74.8,10.05) 76.71,10.05 AFTP6529.1
  BOTTOM w0.254: KBBL1.1 72.55,10.78 73.28,10.05 v2(74.8,10.05)
  BOTTOM w0.279: 72.55,12.78 KBBL1.1
  BOTTOM w0.508: 72.55,12.78 72.14,13.2 72.14,13.66 C6501.1 C6506.1 72.06,15.59 F6501.2
5V_S0: length 342.8
  TOP w0.381: v2(167.89,8.65) 167.81,8.65 167.75,8.72 167.28,8.72 166.92,8.36 166.92,8.24 162.94,4.26 162.94,3.68 v2(162.69,3.07)
  TOP w0.508: v2(170.43,84.6) 170.43,84.59 168.54,82.7 168.52,82.7 168.15,82.32 168.15,80.92 168.22,80.84 168.22,80.81 168.53,80.51 168.53,75.46 167.46,74.39 167.46,66.49 169.14,64.81 169.14,57.54 166.46,54.87 166.46,54.21 165.07,52.82 165.07,51.27 165.56,50.79 165.56,50.17 165.58,50.14 165.58,44.77 165.53,44.72 165.53,44.14 165.2,43.81 165.2,42.36 165.71,41.85 v2(165.76,41.85)
  L3SGND w0.508: v2(31.03,32.7) 30.71,32.38 30.71,24.81 31.62,23.89 31.62,21.22 34.54,18.3 34.54,16.02 34.29,15.77 34.29,12.46 35.69,11.07 v2(35.69,10.81) ; v2(133.22,5.1) 133.22,6.57 133.2,6.6 133.2,10.69 v2(134.09,11.58) ; v2(172.49,28.57) 172.21,28.29 172.21,18.51 167.33,13.62 167.33,9.22 v2(167.89,8.65)
  L4SGND w0.508: v2(94.91,14.05) 95,14.14 98.19,14.14 98.72,13.61 100.04,13.61 101.1,12.54 103.83,12.54 105.02,13.73 105.69,13.73 106.25,13.18 110.36,13.18 111.49,12.04 118.05,12.04 119.06,11.03 122.1,11.03 122.11,11.04 127.99,11.04 128.83,11.88 131.95,11.88 132.41,12.34 133.32,12.34 v2(134.09,11.58) ; v2(31.03,32.7) 30.38,33.36 30.38,40.05 31.11,40.79 31.11,46.91 30.38,47.64 30.38,49.09 32.89,51.6 32.89,51.61 33.71,52.42 33.71,54.82 34.54,55.66 34.54,66.39 34.87,66.72 34.87,74.67 35.15,74.95 35.15,77.79 37.29,79.93 38.51,79.93 42.07,83.49 44.76,83.49 46.1,84.83 46.1,85.29 46.1,86.44 48.33,88.66 v2(51.56,88.66)
  L6 w0.305: v2(35.69,10.81) 34.92,11.58 33.77,11.58 32.03,13.32 30.49,13.32 30.17,13.64 30.17,14.06 29.49,14.75 29.49,18.78 28.85,19.42 28.48,19.42 25,22.9 25,25.16 23.29,26.87 22.56,26.87 20.57,28.85 20.57,31.01 17.95,33.63 17.95,48.79 15.75,50.99 v2(15.75,52.34)
  L6 w0.381: v2(133.22,5.1) 135.83,2.49 162.11,2.49 v2(162.69,3.07)
  L6 w0.508: v2(172.49,28.57) 171.17,29.89 171.17,36.62 165.99,41.79 165.82,41.79 v2(165.76,41.85)
  BOTTOM w0.254: D5701.3 21.84,61.61 21.59,61.87 21.59,62.88 20.45,64.03 19.12,64.03 18.63,64.51 17.68,64.51 16.89,65.3 16.89,65.53 15.88,66.54 F5701.1
  BOTTOM w0.508: v2(134.09,11.58) 134.16,11.65 134.88,11.65 R6510.1 ; F6501.1 70.91,15.61 70.91,14.66 71.25,13.86 71.25,11.18 73.79,8.64 73.79,7.22 73.7,7.14 73.7,6.41 v2(73.44,6.16) ; R2612.1 169.8,83.76 170.43,84.39 v2(170.43,84.6)
  vias: v1(28.22,10.02) v1(51.28,90.09) v1(52.12,88.21) v1(101.32,27.02) v2(35.69,10.05) v2(36.32,10.43) v3(13.72,66.82) v3(101.35,28.09) v3(102.23,28.09) v3(103.12,28.09) v3(104.01,28.09)
5V_S5: length 285
  TOP w0.305: v2(59.44,70) 59.36,69.92 PC4866.1
  TOP w0.381: PR4813.1 56.89,69.36 57.79,68.46 58.59,68.46 PC4866.1 ; PC4766.1 59.11,58.95 59.49,58.57 v2(59.56,58.57)
  TOP w0.508: v2(61.09,13.48) 60.58,12.97 R4310.1 ; v2(147.96,95.27) 148.34,94.89 C4031.1 ; PR5118.1 v2(50.9,23.59) ; PR4610.1 45.64,79.82 v2(45.69,79.77)
  L3SGND w0.508: v2(132.35,16) 132.35,15.37 128.96,11.98 121.56,11.98 v2(116.84,7.26) ; 173.62,49.8 179.57,49.8 180.69,50.92 180.69,52.63 179.78,53.54 179.78,58.49 178.82,59.45 v2(178.05,59.45) ; 55.63,79.77 51.95,79.77 49.92,77.74 48.39,77.74 46.35,79.77 v2(45.69,79.77) 45.19,80.28 38.11,80.28 37.32,79.49 31.6,79.49 31.11,79.01 ; 55.63,79.77 59.14,79.77 59.51,79.4 v2(59.51,79.14) ; 55.63,79.77 55.24,79.39 55.24,70.6 56.49,69.36 59.06,69.36 59.44,69.73 ; 55.63,79.77 55.56,79.84 55.56,82.12 53.72,83.97 v2(52.7,83.97) ; 59.44,69.73 59.44,65.42 54.99,60.98 v2(54.99,58.06) 55.12,57.93 59.05,57.93 59.56,58.44 v2(59.56,58.57) ; 59.44,69.73 v2(59.44,70) ; v2(147.96,95.27) 149.73,97.05 v2(149.73,102.25)
  L4SGND w0.305: v2(154.69,64.92) 155.06,64.92 155.27,65.12 161.67,65.12 162.66,66.11 162.66,69 162.06,69.61 v2(159.76,69.61)
  L4SGND w0.508: v2(149.73,102.25) 151.13,100.86 156.32,100.86 159.21,97.97 159.21,87.05 164.21,82.04 164.21,76.28 164.31,76.17 164.31,65.7 164.21,65.59 164.21,65.16 165.6,63.77 v2(165.61,63.77) ; v3(79.76,23.64) 77.47,25.93 57.28,25.93 56.64,26.56 50.66,26.56 50.26,26.15 50.26,24.11 50.78,23.59 v2(50.9,23.59)
  L6 w0.381: v2(21.46,79.27) 21.29,79.27 21.2,79.18 18.48,79.18 18.15,79.51 18.15,81.87 v2(18.75,82.47)
  BOTTOM w0.152: U7201.A11 20.03,78.67
  BOTTOM w0.203: v2(105.82,22.37) 105.99,22.55 U4001.4
  BOTTOM w0.279: 177.14,59.45 177.14,59.51 PC5202.1 177.72,59.78 v2(178.05,59.45)
  BOTTOM w0.305: R3406.1 21.11,38.17 21.11,36.67 20.83,36.39 v2(20.52,36.39) ; PC4877.1 52.2,84.59 52.7,84.08 v2(52.7,83.97) ; FC8933.1 C4043.1 159.6,69.45 v2(159.76,69.61) ; v2(132.35,16) 132.35,16.41 132.7,16.77 ; EC8929.1 168.45,45.97 169.72,44.7 170.23,44.7 170.8,44.13 IOBD1.30 ; v2(18.75,82.47) 19.04,82.17 U7201.H10 ; v2(22.73,37.61) 22.4,37.28 22.4,36.5 22.9,36.01 C5743.1 ; PR4704.2 v2(54.99,58.06) ; v2(159.76,69.61) 159.77,69.61 159.96,69.79 C4032.1 ; v2(159.76,69.61) 160.09,69.28 U4003.3 ; U4002.3 152.98,63.59 153.28,63.9 153.8,63.9 154.13,64.23 154.13,64.23 154.15,64.25 154.15,64.5 154.57,64.92 v2(154.69,64.92) ; v2(59.44,70) 59.45,70.01 PU4802.29 ; PC5001.1 149.38,102.48 149.61,102.25 v2(149.73,102.25) 149.86,102.38 PU5001.6 ; v2(59.56,58.57) 59.45,58.68 PU4701.29 ; v2(147.96,95.27) 148.34,95.27 148.77,95.7 U4006.3 ; 177.14,59.45 PU5201.21 ; v2(59.51,79.14) 59.45,79.2 PU4801.29
  BOTTOM w0.381: 132.7,16.77 135.57,19.64 136.25,19.64 137.11,20.5 PC5310.1 137.11,20.9 136.77,21.24 PU5303.6 ; R3405.1 22.86,37.74 v2(22.73,37.61) ; PR4803.1 52.96,84.22 v2(52.7,83.97) ; R3402.1 R3406.1 ; Q6402.E Q6401.E
  BOTTOM w0.508: v2(116.84,7.26) 117.73,8.15 Q6401.E ; U5704.6 26.67,32.4 v2(26.8,32.28) ; v2(61.09,13.48) 62.6,13.48 62.97,13.84 62.97,13.95 63.33,14.32 64.57,14.32 65.91,12.97 65.91,12.66
  vias: v1(22.07,78.2) v1(38.4,17.06) v1(80.52,24.66) v1(81.2,22.32) v1(102.31,22.93) v1(106.98,21.33) v1(131.27,4.59) v1(163.7,8.45) v2(21.46,79.9) v2(21.46,78.63) v2(21.46,78) v2(171.42,42.79) v2(172.06,42.79) v2(172.72,42.79) v3(21.97,44.72) v3(22.83,44.6) v3(22.83,43.72) v3(38.94,18.05) v3(79.73,20.97) v3(79.76,22.75) v3(79.76,21.86) v3(79.76,20.08) v3(101.73,22.12) v3(102.62,22.12) v3(103.5,22.12) v3(104.39,22.12) v3(164.47,9.29) v3(165.35,10.18) v3(165.35,9.29) v3(165.35,8.4)
5V_S5_EN: length 6.4
  BOTTOM w0.254: PR4504.2 59.77,25.55 PR4513.1 60.55,25.49 PC4531.1 v1(60.58,24.66) 61.47,23.77 62.1,23.77 63.05,22.82 PU4502.12
5V_USB30_VCCA: length 21.2
  TOP w0.508: 15.65,45.21 USB2.1 16.36,44.5
  L6 w0.381: v2(16,32.78) 16.72,33.5 16.72,43.43 USB2.1
  BOTTOM w0.381: v2(16,32.78) 16.43,32.78 17.32,33.15 18.26,33.15 19.3,34.19 19.3,34.49 ED3503.5
  BOTTOM w0.508: 14.94,44.5 USB2.1 ; USB2.1 15.65,43.79 ; USB2.1 16.36,44.5 ; USB2.1 15.65,45.21
  vias: v1(17.91,44.72) v2(16.13,45.61)
19V_AD+: length 56
  L6 w0.381: v2(35.69,70.38) 35.51,70.38 34.58,69.45 34.58,68.18 35.81,66.95 35.81,55.52 34.22,53.92 34.22,52.92 32.88,51.58 30.48,51.58 30.1,51.2 30.1,50.97 29.5,50.37 29.4,50.37 27.81,48.78 27.81,41.04 29.59,39.26 29.59,36.85 v2(34.42,32.02)
  BOTTOM w0.381: v2(34.42,32.02) 37.21,32.02 37.68,31.55 PD4401.1 PD4408.1 38.43,35.12 PR4473.1 ; v2(35.69,70.38) 35.64,70.33 34.78,70.33
  vias: v1(34.8,69.74)
19V_DCBATOUT:
  vias: v1(36.2,62.38) v3(37.85,63.01) v3(37.85,61.36) v3(38.73,63.01) v3(38.73,61.36)
19V_DCBATOUT_LCD:
  vias: v1(54.36,95.34) v1(77.47,96.92)
20V_VCCPD_VBUS: length 6.4
  L3SGND w0.508: USB1.B4 7.59,82.6 ; USB1.B4 7.33,83.01 ; USB1.B4 6.91,83.11 ; 7.44,80.24 USB1.B9 7.42,80
  BOTTOM w0.178: USB1.A4 8.28,80.05 8.5,79.83 8.96,79.83 v2(9.14,79.65)
  BOTTOM w0.305: USB1.B4 6.96,82.55 USB1.A9 ; USB1.A4 6.96,80.05 USB1.B9
  vias: v1(20.83,70.93) v1(21.34,71.61) v2(20.57,71.52) v3(22.73,71.75) v3(23.62,71.75) v3(24.51,71.75) v3(25.4,71.76)
20V_VCCPD_VBUS_L:
  vias: v1(19.94,73.42) v2(20.32,83.58) v2(20.32,82.95) v3(19.99,74.88) v3(20.7,74.44) v3(20.7,73.55)
+5V_AVDD: length 6.6
  TOP w0.203: v1(19.68,11.37) 19.74,11.37 20.47,12.11 R2705.1 ; v2(21.34,13.77) 21.5,13.77 22.62,14.89 U2701.40
  TOP w0.508: v2(21.34,13.77) 21.16,13.59 C2721.1 21.16,12.69 20.83,12.36 20.83,12.11
  BOTTOM w0.508: C2727.1 20.95,13.39 v2(21.34,13.77)
+5V_PVDD: length 1.9
  TOP w0.203: U2701.41 23.02,14.55 22.35,13.88
  vias: v1(25.86,13.07) v2(21.75,12.33) v2(21.92,11.68) v2(26.43,12.21) v2(26.47,11.58)
DVSS: length 4.7
  TOP w0.102: U2701.13 27.21,21.39 v1(27.46,21.65) 27.65,21.84 27.65,22.85 28.19,23.39 28.19,23.59 R2746.2
GND: length 1711.2
  TOP w0.203: 177.34,3.35 177.35,3.35 SSD1.77 180.69,3.35 180.7,3.35 ; 180.7,26 180.54,25.85 SSD1.76 177.52,25.85 177.42,25.95 ; C2428.2 85.9,6.75 86.96,7.81 v2(86.96,8)
  TOP w0.254: U5701.E4 26.76,61.09 26.39,61.45 v2(26.39,61.48) ; R720.2 110.36,88.07 v2(111.01,88.72) ; v2(14.68,78) 14.88,77.79 ED7301.3 ; U5701.D5 27.56,61.89 27.19,62.25 v2(27.19,62.28) ; v2(127.63,57.68) 127.68,57.73 127.68,58.43 127.58,58.52 EC1801.2 ; v2(185.04,49.68) 185.04,49.17 184.78,48.91 183.37,48.91 183.12,48.66 Q2001.1 ; v2(27.94,63.9) 28.35,63.49 U5701.B6 ; U5701.E5 27.56,61.09 27.19,61.45 v2(27.19,61.48) ; R7202.2 16.74,81.45 15.42,81.45 15.21,81.25 ; C2213.2 127.13,75.43 126.93,75.23 v2(126.93,75.17) 127.06,75.04 127.06,74.97 127.12,74.91 R305.1 ; U5504.3 U5504.8 85.72,100.48 v2(85.6,100.35) ; v2(33.66,17.54) 33.63,17.57 33.34,17.57 33.31,17.58 C4039.2 ; v2(25.58,63.09) U5701.B3 ; v2(121.76,70.05) 121.37,69.66 121.37,59.24 122.47,58.14 C1804.2 121.65,57.53 121.03,56.91 v2(121.03,56.28) 121.03,55.19 121.28,54.93 125.26,54.93 125.46,55.13 125.46,57.09 125.01,57.53 C1803.2 124.91,58.6 122.07,61.44 122.07,68.96 v2(122.42,69.32) ; U5701.D4 26.76,61.89 26.39,62.25 v2(26.39,62.28) ; U5701.G3 v2(26.39,59.9) ; v2(27.98,59.89) U5701.G6 ; C803.1 122.5,72.09 123,71.58 v2(123.13,71.58)
  TOP w0.305: v2(122.17,29.99) 122.05,29.99 121.92,30.12 EC8949.2 ; R5709.1 34.04,60.42 32.64,60.42 ; C2714.2 26.62,14.07 26.83,13.86 v2(27.06,13.86) ; EC8947.2 56.28,19.54 v3(56.62,19.88) ; R1511.2 142.67,60.32 v2(142.9,60.09) ; C1234.2 72.49,45.64 v2(72.63,45.79) ; EC8933.2 120.8,60.63 EC8934.2 120.77,61.82 v2(120.82,61.87) ; U7001.7 187.12,40.43 187.12,41.27 C7001.2 186.46,40.91 U7001.8 ; v2(28.32,15.89) 28.65,15.56 C2722.2 C2729.2 ; U7001.5 188.6,39.27 v2(188.72,39.39) ; v2(29.84,24.91) 29.82,24.88 29.82,24.33 EC2701.2 ; v3(40.89,23.61) 41.45,23.06 EC8946.2 ; v2(24.77,7.05) 24.69,7.13 24.08,7.13 EC2904.2 ; v2(147.07,80.79) 147.9,81.63 C1116.2 C1117.2 ; C5701.2 29.26,51.43 v2(29.26,50.95) ; EC6503.2 EC6504.2 132.22,9.99 131.79,9.99 v2(131.67,10.1) ; 107.95,104.44 107.95,104.67 v2(108.2,104.92) ; R1555.2 135.97,60.77 135.64,61.11 134.26,61.11 133.39,61.98 v2(133.09,61.98) ; v2(24.47,24.66) 24.71,24.9 C2744.2 ; 188.09,39.77 188.08,39.76 U7001.6 ; v2(86.51,24.63) 86.07,24.19 EC8950.2 ; v2(17.53,78) 17.32,77.79 ED7301.8 ; ED5701.8 v2(18.29,61.11) ; v2(60.07,70) 60.27,69.79 PC4866.2 ; FC2701.2 29.54,19.78 v2(29.49,19.83) 29.46,19.83 29.01,19.38 C2738.2 ; v2(72.52,30.12) 72.58,30.18 EC8948.2
  TOP w0.356: v2(185.04,50.69) 185.04,50.77 184.68,51.12 C6702.2 184.42,51.11 Q2001.4
  TOP w0.381: v2(147.45,98.8) 147.6,98.95 C2610.2 ; v2(49.66,76.47) 50.11,76.47 PC4614.2 ; ED6301.3 ED6301.8 168.22,15.26 ; C7212.1 18.58,84.93 17.86,84.22 R7223.2 ; C7217.2 20.24,87.85 20.68,88.28 v2(20.68,88.44) ; v2(20.32,40.15) ED3501.3 ED3501.8 ; C2414.2 98.04,19.83 97.66,20.21 v2(97.03,20.21) ; v2(172.09,9.82) 171.73,10.18 170.1,10.18 R6304.2 ; PR4417.1 29.35,46.18 29.13,46.18 29.12,46.2 v2(28.88,46.2) ; v2(51.05,79.77) 51.49,79.34 PC4633.2 ; v2(136.96,92.73) 137.69,92 H6.1 ; v2(18.29,65.04) ED5702.3 ED5702.8 ; v2(13.46,86.25) ED7303.8 ED7303.3 ; v2(30.71,13.86) 30.58,13.99 C2746.2 ; v2(13.97,89.55) ED7302.3 ED7302.8 ; v2(146.81,70.88) 146.81,70.48 144.03,67.7 H8.1 ; v2(49.78,80.41) 49.97,80.6 49.97,80.78 PC4610.1 ; v2(41.02,70.63) 40.85,70.63 40.34,70.12 PC4631.2 ; R1601.2 129.16,86.43 129.16,86.85 R1603.2
  TOP w0.508: C1268.2 77.8,43.81 78.23,43.38 v2(78.23,43.34) 77.77,42.88 C1229.2 ; R1212.2 50.68,43.63 C1206.2 51.29,43.66 v2(51.37,43.74) ; v2(29.84,24.91) 29.79,24.96 R2746.1 28.68,24.99 EC1901.1 ; v2(131.4,32.72) 131.4,32.82 131.91,33.33 C1323.2 132.19,33.32 EC8931.2 ; v2(79.03,41.74) 79.04,41.74 R1205.2 ; v2(31.88,64.41) 31.88,65.73 32.38,66.24 R5734.2 32.59,66.29 R5763.2 ; HDMI1.21 11.1,55.24 ; HDMI1.21 11.1,53.26 ; HDMI1.21 12.48,54.25 ; 16.08,82.67 16.59,83.18 C7210.2 ; 16.08,82.67 v2(16,82.67) ; 16.08,82.67 16.09,82.67 16.77,81.98 R7202.2 R7231.1 ; R7003.1 188.04,36.21 188.71,36.21 188.72,36.2 v2(188.73,36.2) ; v2(132.32,38.99) 132.32,38.17 C1324.2 132.4,38.09 v2(132.4,37.44) ; v2(109.84,46) 109.3,46.53 C1331.2 ; v2(125.13,45.79) 124.96,45.62 C1321.2 ; EC4306.2 30.99,39.13 v2(31.37,38.75) ; EC2714.2 20.32,27.2 v2(20.57,26.94) 20.07,26.43 EC2712.2 ; v2(102.62,13.73) 102.08,13.2 EC2402.2 ; v2(180.19,44.95) 181.35,44.95 Q6102.S ; C2602.2 v2(148.72,46.42) ; EC8903.2 93.27,99.58 v2(92.5,100.35) ; v2(25.27,43.96) 25.96,43.96 C5772.2 ; R601.1 101.64,89.12 v2(101.24,88.72) ; EC2902.2 22.07,3.8 v2(22.07,2.94) ; 3.58,75.23 USB1.13 3.58,75.6 ; 3.58,87.37 USB1.22 2.25,88.21 ; v2(89.61,76.64) 89.62,76.63 PC1056.2 ; v2(151.13,64.03) 150.5,63.39 R1553.2 ; v2(114.98,40.93) 114.98,40.93 C1314.2 ; R2448.2 83.59,18.61 C2409.2 82.73,18.64 v2(82.68,18.69) ; R1602.2 133.15,90.7 v2(133.11,90.74) ; USB2.11 14.9,35.49 ; USB2.11 14.9,33.71 ; USB2.11 16.58,34.6 ; R1523.2 v2(139.93,76.5) ; v2(142.47,38.94) 142.54,38.88 C1310.2 ; v2(142.47,38.94) 142.92,39.39 C1365.2 ; v2(142.47,38.94) 142.47,39.28 C1311.2 ; R5501.2 107.95,104.44 ; C1114.2 v2(124.96,77.67) ; v2(24.47,24.66) 24.43,24.62 EC1903.2 ; 4.78,75.23 USB1.14 ; USB1.14 7.45,75.23 ; USB1.14 6.12,74.39 ; v2(29.46,41.42) 29.64,41.24 PC4430.2 ; v2(70.39,38.99) 70.34,38.94 C1233.2 70.39,38.2 v2(70.39,37.44) ; v2(80.54,38.99) 80.54,38.94 80.49,38.89 C1227.2 80.54,38.2 v2(80.54,37.44) ; R1333.2 123.47,43.6 C1320.2 124.07,43.64 v2(124.17,43.74) ; R1505.2 132.98,80.78 R2108.2 132.84,80.68 v2(132.28,80.68) ; C1128.2 122.19,78.74 C2223.2 v2(122.98,78.59) ; v2(173.86,68.85) 173.74,68.85 173.58,68.7 PC5208.2 ; v2(30.99,54.37) 31.67,54.37 R5707.2 ; C2418.2 82.55,14.5 v2(82.55,14.49) ; v2(69.67,38.99) 69.67,38.3 C1217.2 69.63,37.94 69.75,37.81 v2(69.75,37.44) 69.75,37.18 69.83,37.1 v2(69.83,36.8) 69.83,36.81 C1236.2 ; EC8910.2 157.66,21.1 v2(157.4,20.85) ; EC8902.2 96.9,100.3 v2(96.9,100.35) ; v2(142.63,36.8) 142.84,36.59 C1357.2 ; v2(112.02,38.99) 112.02,38.94 112.06,38.9 C1332.2 112.06,37.44 v2(111.85,37.24) ; C1262.2 67.65,43.76 v2(68.08,43.34) 67.62,42.88 C1219.2 ; v2(122.9,83.46) 122.98,83.39 EC2201.2 C805.2 ; R5757.1 33.45,54.98 33.02,54.54 v2(33.02,54.12) ; C1313.2 120.11,42.87 v2(120.58,43.34) 120.23,43.68 C1341.2 ; C1305.2 140.05,45.72 v2(140.12,45.8) ; C1337.2 110.08,43.68 v2(110.43,43.34) 109.93,42.84 C1330.2 ; v2(72.64,40.94) 72.64,40.94 C1231.2 ; C802.1 109.47,87.84 v2(109.39,87.76) ; C1351.2 140.48,43.73 v2(140.88,43.34) 140.41,42.87 C1304.2 ; DB1.15 v2(101.52,16.4) 101.5,16.37 98.76,16.37 98.23,16.91 DB1.3 ; 17.22,68.24 R7408.2 ; 17.22,68.24 17.07,68.09 v2(16.38,68.09) ; 17.22,68.24 R7407.2 ; v2(91.91,18.94) 91.86,18.99 C2423.2 91.11,19.07 C2411.2 ; 8.86,73.8 HS1.1 12.05,70.61 ; v2(154.69,69.87) 154.42,69.87 154.3,70 153.97,70 ; 6.45,32.16 USB2.13 7.75,32.16 ; v2(91.82,2.81) 91.87,2.86 R2611.2 ; C2224.2 C2221.2 C2222.2 v2(147.55,61.61) ; v2(77.64,46) 77.1,46.53 C1228.2 ; 5.98,52.35 HDMI1.20 4.6,51.36 ; C1207.2 52.34,40.92 v2(52.33,40.93) ; v2(181.73,52.71) 182.04,52.4 R2004.2 ; 11.1,67.76 HDMI1.23 ; HDMI1.23 12.48,68.75 ; HDMI1.23 11.1,69.74 ; EC8932.2 143.16,46.09 v2(145.92,43.33) ; v2(60.2,58.57) 60.2,59.4 PC4766.2 ; 14.15,41.71 USB2.7 14.15,40.29 ; C6605.2 162.84,44.85 v2(162.81,44.87) ; v2(133.54,75.47) 134.39,75.47 R2114.2 ; v2(121.38,41.74) 121.38,41.56 121.79,41.15 R1305.2 ; v2(60.24,37.44) C1218.2 ; C1218.2 60.27,38.23 60.27,38.73 60.22,38.78 v2(60.22,39.01) ; C1218.2 60.16,38.13 C1211.2 ; C1208.2 58.81,32.72 v2(58.6,32.72) ; v2(94.11,77.3) 94.11,77.29 C1103.2 ; v2(113.36,38.99) 113.36,38.22 C1319.2 113.39,38.19 v2(113.39,37.44) ; C1315.2 119.45,46.53 v2(119.99,46) ; v2(20.02,2.99) EC2901.2 ; v2(122.25,37.44) 122.25,38.12 C1312.2 122.24,38.88 122.17,38.94 v2(122.17,38.99) ; USB1.21 6.12,88.21 ; USB1.21 7.45,87.37 ; USB1.21 4.78,87.37 ; 187.58,47.64 186.64,46.7 EC8924.2 ; PC1047.2 PC1063.2 87.38,78 v2(87.42,77.97) ; 6.45,49.84 USB2.12 7.75,49.84 ; C1303.2 131.82,35.26 v2(132.1,34.98) ; R1201.2 49.28,41.17 49.03,41.42 49.03,42.04 v2(48.77,42.31) ; v2(139.24,37.73) 139.24,37.63 139.8,37.08 C1301.2 ; PR4406.2 29.51,47.54 PC4420.2 v2(28.92,48.87) ; 8.45,86.56 USB1.20 7.36,85.78 ; C1325.2 130.26,42.87 v2(130.73,43.34) 130.26,43.81 C1346.2 ; v2(87.79,46) 87.25,46.53 C1222.2 ; 6.29,84.5 USB1.B1 6.91,85.54 ; v2(143.52,9.4) 143.93,9.4 EC6502.2 EC6501.2 ; 15.65,36.79 USB2.4 15.1,36.95 ; 4.6,71.64 HDMI1.22 5.98,70.65 ; v2(148.84,20.85) 148.74,20.74 EC8908.2 ; C1203.2 59.68,36.81 v2(59.68,36.8) ; v2(71,43.74) 70.92,43.66 C1235.2 70.33,43.63 R1215.2 ; 6.91,77.06 USB1.B12 6.29,78.1 ; EC8944.2 58.17,55.26 v3(58.67,54.76) ; C1213.2 62.34,45.64 v2(62.48,45.79) ; v2(52.33,45.79) 52.19,45.64 C1205.2 ; C1265.2 57.5,43.76 v2(57.93,43.34) 57.47,42.88 C1209.2 ; v2(82.78,40.93) 82.79,40.92 C1225.2 ; PC4651.2 48.08,82.7 v2(48.77,82.7) 49.33,82.7 PC4612.2 ; R1234.2 69.3,41.17 68.88,41.6 v2(68.88,41.74) ; C6505.2 v2(134.11,7.43) ; R2453.1 64.14,4.46 v2(63.88,4.72) ; EC8939.2 117.87,33.27 v2(117.49,32.89) 117.49,33.1 116.99,33.6 C1335.2 ; C1308.2 133.44,39.21 v2(133.66,38.99) ; v2(49.17,69.11) 49.15,69.13 49.15,69.66 PC4622.2 ; 14.9,48.29 USB2.10 16.58,47.4 ; v2(131.53,41.74) 132.08,41.19 R1306.2 ; C2218.2 137.19,73.62 v2(137.19,73.18) ; C806.2 125.71,83.99 125.71,84.12 125.62,84.2 v2(125.62,84.4) 125.67,84.46 PC1072.2 125.67,86.13 v2(126.03,86.49) ; USB1.15 9.54,76.83 ; USB1.15 8.45,76.04 ; USB1.15 7.36,76.83 ; EC8942.2 68.84,32.63 v2(68.75,32.72) 68.75,32.85 69.16,33.27 69.47,33.27 C1216.2 ; v2(122.24,34.95) 122.01,35.18 C1336.2 ; C1316.2 114.84,45.64 v2(114.98,45.79) ; PC4622.2 49.45,69.92 51.64,72.1 PC4615.1 ; PC4622.2 48.41,69.92 48.39,69.94 PR4639.2 46.8,69.94 46.23,69.37 v2(46.23,69.11) ; v2(123.51,38.99) 123.51,38.94 123.5,38.92 123.5,38.2 C1326.2 123.54,38.16 v2(123.54,37.44) ; v2(142.55,37.44) 142.55,38.11 C1310.2 ; C1210.2 50.51,39.24 v2(50.64,39.12) ; v2(146.81,70.88) 146.81,71.39 147.7,72.28 R1520.2 ; C1310.2 142.94,38.13 143.08,37.99 R1340.1 ; v2(125.13,40.93) 125.12,40.93 C1322.2 ; R1334.2 133.61,43.63 C1307.2 134.24,43.66 v2(134.32,43.74) ; v2(124.96,72.82) 124.75,72.61 R304.1 ; v2(121.28,99.21) 121.28,99.31 121.79,99.81 EC8907.2 ; C1201.2 79.98,36.17 v2(79.98,36.8) 79.98,37.1 79.9,37.18 v2(79.9,37.44) 79.9,37.75 79.78,37.87 C1230.2 79.82,38.3 v2(79.82,38.99) ; PC4812.2 56.72,70.29 56.64,70.36 v2(56.64,70.88) ; C5522.2 112.47,101.04 112.14,100.71 v2(112.14,100.35) ; R1214.2 80.48,43.66 C1220.2 81.77,43.69 v2(81.82,43.74) ; AFTP6525.1 145.92,5.86 v2(145.92,5.48) ; v2(138.94,32.58) 138.68,32.33 C1309.2 ; v2(130.14,46) 129.63,46.51 C1327.2 ; v3(116.33,18.43) 116.33,19.14 113.21,22.27 EC8917.2 112.5,22.83 EC8921.2 ; C1259.2 87.95,43.76 v2(88.38,43.34) 87.92,42.88 C1226.2 ; v2(129.48,81.9) 129.52,81.94 C2211.2 130.73,81.94 R2118.2 ; R1332.2 113.32,43.63 C1317.2 113.94,43.66 v2(114.02,43.74) ; C1106.2 v2(96.11,81.86) ; v2(152.65,86.12) 152.65,86.58 R2008.2 ; C2420.2 97.27,11.45 95.89,12.84 v2(95.89,13.1) ; v2(121.25,32.72) 121.89,33.35 C1318.2 ; C1104.2 v2(92.2,81.86) ; C2412.2 95.83,8.1 v2(95.76,8.02) ; v2(146.3,76.98) 146.56,76.73 147.33,76.73 148.21,75.85 148.21,75.84 148.92,75.13 R2034.2 ; PR4410.1 v2(31.37,40.02) ; R7409.2 21.01,69.92 21.34,70.25 v2(21.72,70.25) 21.98,70.25 22.16,70.43 R7422.2 ; DB1.16 85.27,15.67 85.27,16.07 v2(85.12,16.22) 85.09,16.24 84.37,16.24 C2429.2 C2410.2 ; PR4413.2 34.42,40.1 PC4432.2 34.42,39.95 v2(34.42,39.39) ; EC1706.2 152.32,88.97 v2(152.4,89.05) ; C1306.2 135.14,45.64 v2(135.28,45.79) ; v2(18.53,85.76) 18.67,85.62 C7212.1 ; R1304.2 111.64,41.17 111.23,41.59 v2(111.23,41.74) ; R1213.2 60.18,43.63 C1212.2 60.79,43.66 v2(60.87,43.74) ; v2(131.62,85.23) 131.67,85.27 R403.2 ; C1204.2 56.8,46.53 v2(57.34,46) ; v2(143.26,84.22) 143.59,84.56 R2009.2 ; v2(89.41,5.48) 89.41,6.04 C2413.2 89.2,6.24 R2454.2 ; R1601.2 129.55,86.3 v2(129.73,86.49) ; C1107.2 v2(94.18,81.86) ; R1516.2 v2(151.76,55.95) ; v2(62.48,40.93) 62.49,40.92 C1215.2 ; C1221.2 82.64,45.64 v2(82.78,45.79) ; v3(58.67,14.5) 58.29,14.88 57.02,14.88 56.57,14.42 R4302.1 ; v2(60.07,70) 60.07,70.26 59.7,70.63 59.69,70.63 59.56,70.76 PR4818.2 ; v2(135.51,5.23) 135.99,5.71 EC8920.2 ; v2(34.42,38.12) 32.84,39.69 PC4431.2 32.89,40.07 PC4433.2 ; PC4640.2 45.47,70.55 PC4639.2 45.54,71.6 v2(45.59,71.65) ; v2(35.69,69.74) 35.69,68.73 35.23,68.27 R5762.2 ; R317.2 95.96,88.32 v2(96.36,88.72) ; v2(67.49,46) 66.95,46.53 C1214.2 ; v2(58.73,41.74) 58.73,41.6 59.15,41.17 R1204.2 ; R2445.1 92.71,8.7 v2(92.71,8.02) ; C2216.2 152.65,82.06 v2(153.03,82.44) 153.67,81.81 R1552.2
  L2SGND w0.254: 180.64,26.23 180.26,25.85 SSD1.76 177.7,25.85 177.34,26.21 ; 177.42,3.12 177.65,3.35 SSD1.77 180.39,3.35 180.59,3.14
  L2SGND w0.508: 12.05,71.98 HS1.1 ; HS1.1 13.87,73.8 ; HS1.1 10.23,73.8 ; HS1.1 12.05,75.62 ; 14.9,46.51 USB2.10 ; USB2.10 14.9,48.29 ; USB2.10 16.58,47.4 ; USB1.14 7.45,75.23 ; USB1.14 4.78,75.23 ; USB1.14 6.12,74.39 ; 4.6,51.36 HDMI1.20 5.98,52.35 ; 6.91,83.53 USB1.B1 ; USB1.B1 6.29,84.5 ; USB1.B1 6.91,85.54 ; USB1.B12 6.91,79.07 ; USB1.B12 6.91,77.06 ; USB1.B12 6.29,78.1 ; USB2.4 15.65,38.21 ; USB2.4 14.94,37.5 ; USB2.4 15.65,36.79 ; USB2.4 16.36,37.5 ; USB1.21 6.12,88.21 ; USB1.21 7.45,87.37 ; USB1.21 4.78,87.37 ; 7.75,32.16 USB2.13 6.45,32.16 ; 11.85,56.92 HDMI1.2 ; HDMI1.2 12.49,57.5 ; HDMI1.2 11.21,57.5 ; 11.21,60.5 HDMI1.8 12.49,60.5 ; USB2.7 14.15,41.71 ; USB2.7 14.86,41 ; USB2.7 14.15,40.29 ; 3.58,75.23 USB1.13 3.58,75.6 ; USB1.20 9.54,85.78 ; USB1.20 8.45,86.56 ; USB1.20 7.36,85.78 ; 3.58,87.37 USB1.22 2.25,88.21 ; HDMI1.23 11.1,69.74 ; HDMI1.23 12.48,68.75 ; HDMI1.23 11.1,67.76 ; 14.9,33.71 USB2.11 ; USB2.11 14.9,35.49 ; USB2.11 16.58,34.6 ; 4.6,71.64 HDMI1.22 5.98,70.65 ; 10.99,65 HDMI1.17 10.99,65.29 ; 10.99,62 HDMI1.11 10.99,62.29 ; 7.36,76.83 USB1.15 ; USB1.15 8.45,76.04 ; USB1.15 9.54,76.83 ; 10.99,59 HDMI1.5 10.99,59.29 ; 11.1,53.26 HDMI1.21 ; HDMI1.21 11.1,55.24 ; HDMI1.21 12.48,54.25 ; 7.75,49.84 USB2.12 6.45,49.84
  L3SGND w0.254: SSD1.77 177.53,3.35 177.29,3.12 ; SSD1.77 179,2.17 179.02,2.15 ; SSD1.77 180.39,3.35 180.57,3.17 ; 180.62,26 180.47,25.85 SSD1.76 ; 178.99,26.94 179,26.94 SSD1.76 ; 177.24,25.93 177.32,25.85 SSD1.76
  L3SGND w0.381: H10.1 152.14,34.95 155.53,31.55 v3(155.59,31.55)
  L3SGND w0.508: 12.49,60.5 HDMI1.8 11.21,60.5 ; 6.45,32.16 USB2.13 7.75,32.16 ; 10.99,62 HDMI1.11 10.99,62.29 ; 7.36,85.78 USB1.20 8.45,86.56 ; 5.98,52.35 HDMI1.20 4.6,51.36 ; USB2.11 16.58,34.6 ; USB2.11 14.9,33.71 ; USB2.11 14.9,35.49 ; USB2.7 14.15,41.71 ; USB2.7 14.15,40.29 ; USB2.7 14.86,41 ; HDMI1.21 12.48,54.25 ; HDMI1.21 11.1,53.26 ; HDMI1.21 11.1,55.24 ; 5.98,70.65 HDMI1.22 4.6,71.64 ; 11.21,57.5 HDMI1.2 ; HDMI1.2 12.49,57.5 ; HDMI1.2 11.85,56.92 ; USB1.21 6.12,88.21 ; USB1.21 4.78,87.37 ; USB1.21 7.45,87.37 ; 6.45,49.84 USB2.12 7.75,49.84 ; USB2.4 16.36,37.5 ; USB2.4 15.65,38.21 ; USB2.4 14.94,37.5 ; USB2.4 15.65,36.79 ; 6.29,78.1 USB1.B12 ; USB1.B12 6.91,79.07 ; USB1.B12 6.91,77.06 ; 3.58,87.37 USB1.22 2.25,88.21 ; 7.36,76.83 USB1.15 8.45,76.04 ; 14.9,46.51 USB2.10 ; USB2.10 14.9,48.29 ; USB2.10 16.58,47.4 ; 3.58,75.6 USB1.13 3.58,75.23 ; 6.91,85.54 USB1.B1 6.29,84.5 ; 10.99,59 HDMI1.5 10.99,59.29 ; 10.41,67.76 HDMI1.23 11.1,67.76 ; 4.78,75.23 USB1.14 ; USB1.14 6.12,74.39 ; USB1.14 7.45,75.23 ; 10.99,65 HDMI1.17 10.99,65.29
  L4SGND w0.254: 180.85,25.9 180.8,25.85 SSD1.76 177.14,25.85 177.11,25.88 ; 180.75,3.14 180.54,3.35 SSD1.77 177.5,3.35 177.32,3.17
  L4SGND w0.508: 6.45,49.84 USB2.12 7.75,49.84 ; 3.58,75.23 USB1.13 3.58,75.6 ; HDMI1.21 12.48,54.25 ; HDMI1.21 11.1,55.24 ; HDMI1.21 11.1,53.26 ; USB1.21 7.45,87.37 ; USB1.21 6.12,88.21 ; USB1.21 4.78,87.37 ; 11.1,67.76 HDMI1.23 ; HDMI1.23 12.48,68.75 ; HDMI1.23 11.1,69.74 ; 14.9,48.29 USB2.10 14.9,46.51 ; 7.75,32.16 USB2.13 6.45,32.16 ; 15.65,36.79 USB2.4 ; USB2.4 14.94,37.5 ; USB2.4 15.65,38.21 ; USB2.7 14.86,41 ; USB2.7 14.15,41.71 ; USB2.7 14.15,40.29 ; HS1.1 12.05,75.62 ; HS1.1 10.23,73.8 ; HS1.1 12.05,71.98 ; 10.99,65.29 HDMI1.17 10.99,65 ; 12.49,60.5 HDMI1.8 11.21,60.5 ; USB1.20 9.54,85.78 ; USB1.20 8.45,86.56 ; USB1.20 7.36,85.78 ; HDMI1.2 12.49,57.5 ; HDMI1.2 11.21,57.5 ; HDMI1.2 11.85,56.92 ; 6.29,84.5 USB1.B1 6.91,85.54 ; 4.6,71.64 HDMI1.22 5.98,70.65 ; 4.78,75.23 USB1.14 4.78,74.39 ; 4.6,51.36 HDMI1.20 5.98,52.35 ; 3.58,87.37 USB1.22 2.25,88.21 ; 14.9,35.49 USB2.11 14.9,33.71 ; 6.29,78.1 USB1.B12 6.91,77.06 ; 10.99,62.29 HDMI1.11 10.99,62 ; 10.99,59 HDMI1.5 10.99,59.29
  L6 w0.254: 177.29,26.15 177.6,25.85 SSD1.76 180.49,25.85 180.75,26.1 ; 177.34,3.12 177.58,3.35 SSD1.77 180.51,3.35 180.77,3.09
  L6 w0.508: 6.29,84.5 USB1.B1 6.91,85.54 ; USB1.21 6.12,88.21 ; USB1.21 7.45,87.37 ; USB1.21 4.78,87.37 ; 4.6,51.36 HDMI1.20 5.98,52.35 ; 6.45,49.84 USB2.12 7.75,49.84 ; 14.94,37.5 USB2.4 ; USB2.4 15.65,36.79 ; USB2.4 15.65,38.21 ; 5.98,70.65 HDMI1.22 4.6,71.64 ; 2.25,88.21 USB1.22 3.58,87.37 ; 7.36,76.83 USB1.15 ; USB1.15 8.45,76.04 ; USB1.15 9.54,76.83 ; USB2.7 14.15,41.71 ; USB2.7 14.15,40.29 ; USB2.7 14.86,41 ; 10.99,62 HDMI1.11 10.99,62.29 ; 6.91,77.06 USB1.B12 ; USB1.B12 6.29,78.1 ; USB1.B12 6.91,79.07 ; 14.9,35.49 USB2.11 14.9,33.71 ; 10.41,67.76 HDMI1.23 11.1,67.76 ; 11.1,53.26 HDMI1.21 11.1,55.24 ; 3.58,75.23 USB1.13 3.58,75.6 ; 6.12,74.39 USB1.14 ; USB1.14 4.78,75.23 ; USB1.14 7.45,75.23 ; 10.23,73.8 HS1.1 ; HS1.1 12.05,75.62 ; HS1.1 12.05,71.98 ; 10.99,65.29 HDMI1.17 10.99,65 ; 7.36,85.78 USB1.20 ; USB1.20 8.45,86.56 ; USB1.20 9.54,85.78 ; 6.45,32.16 USB2.13 7.75,32.16 ; 14.9,48.29 USB2.10 14.9,46.51
  BOTTOM w0.076: CPU1.BP33 123.95,69.53 123.95,68.59 123.8,68.32 123.62,68.14 CPU1.BP36
  BOTTOM w0.09: CPU1.B29 90.34,72.59 v2(90.34,72.59)
  BOTTOM w0.102: CPU1.AB36 103.48,67.61 103.46,67.55 103.46,66.24 103.48,66.22 v2(103.48,65.43) ; v2(118.91,65.17) 118.58,65.5 CPU1.BF36 ; v2(112.78,63.65) 113.57,64.43 113.57,67.56 113.55,67.61 CPU1.AV36 ; v2(89.03,69.92) 89.03,70.56 89.5,71.03 89.93,71.03 90.24,71.34 91.55,71.34 CPU1.B31 ; CPU1.BB36 116.07,63.2 116.88,62.38 v2(117.14,62.38) ; CPU1.BD36 117.33,66.77 v2(117.31,66.75) ; CPU1.AP36 111.03,66.81 111.2,66.65 111.2,64.31 110.61,63.73 v2(110.35,63.73) ; CPU1.B27 90.65,73.85 v2(90.45,74.05) ; v2(105.91,66.03) 106,66.12 CPU1.AF36 ; CPU1.CL2 133.42,89.61 133.42,89.28 133.06,88.91 CPU1.CJ3
  BOTTOM w0.127: CPU1.J36 95.93,67.09 95.67,66.83 v2(95.67,66.67) ; v2(130.64,90.88) CPU1.CF2 CPU1.CF3 130.61,89.21 130.61,88.25 CPU1.CF4 ; CPU1.BL31 CPU1.BL30 ; v2(13.97,83.87) 14.57,83.87 U7201.L1 ; CPU1.G35 CPU1.G36 ; v2(9.35,80.3) USB1.17 ; v2(14.68,78) 14.68,78.58 U7201.A1
  BOTTOM w0.152: CPU1.BT33 CPU1.BT35 CPU1.BT36 ; v2(133.35,98.06) 133.35,98.34 133.35,98.95 133.56,99.16 133.56,99.17 133.72,99.33 137.45,99.33 137.6,99.18 v2(137.6,98) ; CPU1.T35 CPU1.T36 99.84,67.87 99.84,67.3 v2(99.92,67.21) ; v2(100.73,66.6) 100.95,66.82 100.95,67.89 CPU1.V36 ; v2(137.19,73.18) 137.18,73.18 136.5,73.86 CPU1.CP27 ; CPU1.BP3 CPU1.BP4
  BOTTOM w0.178: v2(104.84,42.54) 103.53,42.54 103.23,42.84 ; v2(97.03,20.21) 97.51,20.7 U2401.64 97.51,22.55 R7401.2 ; CPU1.CP15 135.64,81.42 135.66,81.45 135.99,81.45 136.5,81.45 v2(136.65,81.3) ; CPU1.CP11 136.44,83.94 v2(136.64,83.74)
  BOTTOM w0.18: CPU1.P36 98.45,66.62 v2(98.43,66.62) ; CPU1.AK36 108.65,67.77 108.65,66.35 v2(108.68,66.32) ; v2(89.61,76.64) 89.88,76.37 91.01,76.37 CPU1.B23
  BOTTOM w0.2: CPU1.C29 CPU1.B29 ; CPU1.B25 CPU1.C25 CPU1.D25
  BOTTOM w0.203: v2(124.23,70.11) 123.76,70.58 CPU1.BP32 ; v2(124.23,70.11) 124.23,70.06 124.03,69.86 CPU1.BP33 123.6,69.88 122.83,69.88 122.81,69.86 CPU1.BM33 122.42,69.8 v2(122.42,69.32) 122.42,68.72 CPU1.BM35 CPU1.BM36 ; v2(124.23,70.11) 124.48,69.86 CPU1.BT33 125.28,69.86 v2(125.47,70.05) 125.94,70.05 CPU1.BV33 ; CPU1.E31 93.51,71.8 v2(93.91,72.2) ; CPU1.BH28 120.06,73.18 v2(120.41,72.82) ; CPU1.BK4 CPU1.BK3 120.87,89.24 120.87,89.73 120.87,89.73 CPU1.BK2 120.87,90.98 v2(120.87,90.98) ; v2(90.73,70.37) 91.03,70.67 CPU1.A32 ; CPU1.AU29 CPU1.AU28 CPU1.AR28 ; v2(136.29,69.06) 136.29,69.14 136.09,69.34 CPU1.CR34 135.72,69.34 CPU1.CP35 ; CPU1.V30 100.51,72.16 v2(100.35,72.16) 100.16,72.16 CPU1.T30 ; v2(132.23,71.53) 131.93,71.23 CPU1.CH31 ; EC8929.2 168.88,46.47 167.77,46.47 C6104.2 ; 119.88,69.16 v2(119.89,69.17) ; 119.88,69.16 119.88,68.69 CPU1.BH35 ; 119.88,69.16 119.88,69.82 CPU1.BH33 119.93,69.95 CPU1.BH32 ; CPU1.BE29 CPU1.BE30 CPU1.BE31 ; CPU1.BY36 CPU1.BY35 CPU1.BY33 127.76,69.86 v2(127.96,70.05) 128.11,70.05 128.3,69.86 CPU1.CB33 ; CPU1.CJ35 132.43,68.37 132.44,68.36 132.44,68.09 132.43,68.09 CPU1.CJ36 132.43,67.92 132.77,67.59 CPU1.CK37 132.92,67.58 133.14,67.37 v2(133.14,67.08) ; v2(118.58,72.79) 118.61,72.79 119,73.18 CPU1.BG28 ; v2(91.91,18.94) 91.76,19.09 91.76,20.7 92.31,21.25 U2401.51 ; v2(96.72,70.16) 97.01,69.86 CPU1.L33 ; v2(126.75,71.52) 126.6,71.52 CPU1.BV31 ; v2(129.51,71.6) 129.14,71.23 CPU1.CC31 ; CPU1.AV25 v2(113.55,75.64) ; v2(82.55,14.49) U2401.17 ; CPU1.BY28 127.42,73.18 127.66,72.94 v2(127.67,72.94) ; v2(95.89,13.1) 96.04,12.95 96.04,12.9 96.32,12.62 97.94,12.62 98.22,12.89 U2401.84 ; v2(133.35,70.25) 133.38,70.28 133.71,70.28 CPU1.CM33 ; v2(95.76,8.02) 96.31,7.46 U2401.100 ; v2(124.96,72.82) 124.94,72.82 124.58,73.18 CPU1.BT28 ; CPU1.L33 97.28,69.95 98.36,69.95 CPU1.P33 ; CPU1.L33 v2(97.19,69.19) CPU1.L35 CPU1.L36 ; CPU1.AN25 v2(110.82,75.77) ; CPU1.AW31 CPU1.AW30 CPU1.AW29 114.2,72.8 114.08,72.8 ; CPU1.CF28 131,73.18 v2(131.31,72.87) ; v2(123.13,71.58) 122.83,71.88 CPU1.BN30 ; CPU1.BD36 CPU1.BD35 117.19,68.79 v2(117.19,69.32) 117.19,69.72 CPU1.BD33 ; v2(114.01,72.8) 114.08,72.8 ; 114.08,72.8 CPU1.AW28 ; CPU1.K30 96.23,71.88 CPU1.K29 ; v2(108.5,72.88) 108.53,72.92 108.73,72.92 CPU1.AL28 CPU1.AL29 ; USB1.19 8.74,84.5 8.74,84.32 8.47,84.05 USB1.A12 ; CPU1.AJ28 107.75,73.51 v2(107.64,73.51) ; v2(120.41,72.82) 120.77,73.18 CPU1.BK28 ; v2(120.41,72.82) 120.36,72.82 120.07,72.53 CPU1.BH29 ; CPU1.CN37 CPU1.CM37 ; CPU1.BD28 CPU1.BE28 ; CPU1.BC25 v2(116.28,75.67) ; CPU1.CC28 129.15,73.18 v2(129.5,73.53) ; CPU1.CE36 129.91,68.15 129.9,68.18 129.91,68.23 CPU1.CE35 CPU1.CE33 130.11,70.06 v2(130.53,70.06) 130.73,69.86 CPU1.CG33 131.24,69.79 131.59,69.79 131.68,69.88 131.96,69.88 131.98,69.86 CPU1.CJ33 ; CPU1.AH29 CPU1.AH28 ; USB1.A1 7.36,78.55 USB1.B12 ; CPU1.CN29 CPU1.CM29 133.44,72.6 133.34,72.7 v2(133.27,72.7) 132.78,73.18 CPU1.CJ28 ; v2(105.92,26.43) 105.99,26.36 U4001.11 ; U2401.124 86.71,7.51 86.96,7.76 v2(86.96,8) ; CPU1.AF27 106.12,73.83 v2(105.81,73.53) ; v2(133.32,71.48) 133.32,71.48 133.32,71.5 133.45,71.37 CPU1.CM31
  BOTTOM w0.254: v2(137.6,98) 137.54,97.94 137.54,96.16 v2(137.67,96.03) ; v2(101.54,84.05) CPU1.W10 ; v2(116.58,70.16) 117.03,70.16 CPU1.BD33 ; v2(116.58,70.16) 116.28,69.86 CPU1.BB33 116.02,69.9 115.26,69.9 115.22,69.86 CPU1.AY33 ; v2(116.58,70.16) 116.28,70.45 CPU1.BC32 ; v2(136.54,87.35) 136.32,87.13 CPU1.CR6 ; v2(97.61,73.53) 97.9,73.83 CPU1.N27 ; CPU1.BR16 123.64,80.98 v2(123.64,81.05) 123.34,81.36 CPU1.BP15 ; CPU1.Y35 CPU1.Y33 101.94,69.86 v2(101.75,70.05) 101.16,70.05 CPU1.V33 100.52,69.86 v2(100.25,70.13) 99.98,69.86 CPU1.T33 ; CPU1.AH29 107.13,72.49 107.13,71.92 CPU1.AH30 ; CPU1.BG4 119.09,88.21 v2(118.64,87.76) 118.43,87.96 CPU1.BF4 ; v2(110.36,70.08) 110.58,69.86 CPU1.AP33 ; v2(110.36,70.08) 110.36,70.98 110.61,71.23 CPU1.AN31 CPU1.AN30 110.79,71.9 110.79,72.51 CPU1.AN29 110.67,72.53 v2(110.33,72.87) ; v2(110.36,70.08) 110.14,69.86 CPU1.AM33 ; v2(121.76,70.05) 121.57,69.86 CPU1.BK33 120.65,69.86 CPU1.BH32 ; v2(121.76,70.05) 121.75,70.06 CPU1.BL32 121.9,70.73 121.9,71.09 CPU1.BL31 ; v2(121.76,70.05) 121.81,70.05 122.01,69.86 CPU1.BM33 ; CPU1.CB19 128.54,78.84 v2(128.87,78.51) ; CPU1.BA10 v2(115.4,84.1) ; CPU1.CC14 129.47,82.02 129.47,81.9 v2(129.48,81.9) 129.48,81.9 129.84,82.26 CPU1.CD14 129.92,82.23 CPU1.CF14 ; v2(115.84,72.82) 115.99,72.82 CPU1.BC29 ; 105.8,74.29 CPU1.AE27 105.19,73.83 v2(104.87,73.51) 104.55,73.83 CPU1.AC27 ; 105.8,74.29 CPU1.AE26 ; 105.8,74.29 CPU1.AF27 106.71,74.29 CPU1.AG26 ; CPU1.AB33 103.73,70.1 v2(104.01,70.1) 104.08,70.1 104.33,69.86 CPU1.AD33 ; v2(102.94,85.93) 102.65,86.22 CPU1.Y7 ; v2(113.12,85.88) 113.44,85.57 CPU1.AV8 ; CPU1.BY19 126.92,79.27 v2(126.92,79.38) 126.92,79.48 CPU1.BY18 ; CPU1.CC11 129.49,83.69 v2(129.49,83.57) 129.49,83.5 CPU1.CD12 ; 180.72,3.09 180.46,3.35 SSD1.77 177.37,3.35 177.16,3.14 ; CPU1.J6 96.12,86.87 96.39,87.14 96.49,87.14 v2(96.5,87.15) 96.51,87.15 96.52,87.14 96.65,87.14 CPU1.L6 CPU1.N6 ; CPU1.C9 92.3,84.84 v2(92.17,84.71) 91.67,85.2 CPU1.B9 ; v2(117.65,85.87) 117.76,85.87 117.82,85.8 117.93,85.8 CPU1.BE8 ; U5704.1 24.13,39.01 23.83,39.31 R5774.2 23.16,39.77 22.86,40.07 22.86,40.68 22.35,41.19 22.35,42.15 v2(22.73,42.31) ; CPU1.AC5 104.31,87.53 104.69,87.91 v2(104.82,87.91) ; CPU1.BW7 126.3,86.22 v2(126.03,86.49) 125.76,86.22 CPU1.BU7 ; CPU1.CE7 130,86.22 v2(129.73,86.49) 129.46,86.22 CPU1.CC7 129.03,86 128.55,86 CPU1.CB7 ; CPU1.AT36 CPU1.AT35 112.29,69.3 v2(112.29,69.3) 112.29,69.31 CPU1.AT33 112.29,70.23 CPU1.AU32 113.36,69.86 CPU1.AV33 114,69.86 114.05,69.9 114.77,69.9 CPU1.AY33 ; v2(128.87,78.51) 128.54,78.18 CPU1.CB20 ; v2(128.87,78.51) 129.19,78.19 CPU1.CC20 ; v2(113.92,90.7) 113.95,90.7 114.21,90.44 CPU1.AW1 ; CPU1.N27 98.25,73.83 v2(98.52,73.56) 98.79,73.83 CPU1.R27 ; CPU1.N27 CPU1.N25 ; v2(110.33,72.87) 110.64,73.18 CPU1.AN28 ; v2(110.33,72.87) 110.02,73.18 CPU1.AM28 ; CPU1.F4 94.02,88.68 CPU1.F3 CPU1.F2 94.02,90.43 v2(94,90.45) ; CPU1.CN5 134.9,87.68 CPU1.CM5 133.91,88.37 CPU1.CM4 133.24,88.4 CPU1.CK4 ; 181.36,42.69 181.3,42.75 IOBD1.9 ; CPU1.AV28 113.48,73.18 v2(113.12,73.53) ; CPU1.A36 91.69,68.04 CPU1.B36 CPU1.C36 92.51,67.75 CPU1.C37 ; PU4501.18 v2(126.47,21.23) ; CPU1.BN30 122.01,72.53 CPU1.BL29 ; CPU1.BF33 118.58,70.75 CPU1.BE31 ; CPU1.AN7 110.96,86.22 v2(111.3,85.88) 110.99,85.57 CPU1.AN8 ; 94.67,69.81 CPU1.G35 ; 94.67,69.81 94.57,69.72 94.08,69.72 CPU1.F33 ; 94.67,69.81 CPU1.G33 95.08,69.86 95.13,69.9 95.43,69.9 95.48,69.86 CPU1.J33 96.39,69.86 96.68,70.16 v2(96.72,70.16) 96.29,70.58 CPU1.K32 96.26,70.61 96.26,71.2 CPU1.K31 96.23,71.35 96.23,71.35 96.23,71.83 96.23,71.83 CPU1.K30 ; CPU1.CJ11 132.28,83.93 v2(132.28,83.82) ; CPU1.CR36 CPU1.CP37 ; CPU1.CP37 CPU1.CN37 v2(134.76,67.06) ; CPU1.CP37 135.41,67.04 v2(135.4,67.03) ; CPU1.BA6 115.11,86.58 v2(114.94,86.58) ; v2(109.3,70.11) 109.55,69.86 CPU1.AM33 ; v2(109.3,70.11) 109.22,70.11 108.97,69.86 CPU1.AK33 ; v2(109.3,70.11) 108.99,70.42 CPU1.AL32 ; CPU1.AY4 v2(114.77,87.99) ; CPU1.U7 100.91,85.93 v2(101.09,85.93) ; CPU1.AY33 114.81,69.22 v2(114.75,69.16) 114.81,69.11 CPU1.AY35 ; CPU1.CP13 CPU1.CN13 CPU1.CM13 133.57,82.68 133.52,82.73 133.52,82.74 133.42,82.74 133.05,82.74 v2(133.01,82.78) 132.61,82.38 CPU1.CJ14 ; CPU1.BW15 126.59,81.36 v2(126.89,81.05) 126.89,81.13 CPU1.BY15 127.54,81.17 v2(127.54,81.05) 127.89,81.4 CPU1.CA15 ; CPU1.F33 94.05,70.22 v2(94,70.27) 93.85,70.12 CPU1.E33 92.98,70.12 v2(92.93,70.07) CPU1.C33 91.97,69.74 CPU1.B34 ; CPU1.F33 93.64,69.34 CPU1.E35 ; CPU1.BL25 121.75,75.5 v2(121.61,75.64) ; v2(122.98,78.59) 122.98,78.6 CPU1.BP19 123.48,79.1 123.84,79.1 CPU1.BR19 ; CPU1.CJ23 132.51,76.1 132.51,76.46 v2(132.58,76.53) ; CPU1.CC25 CPU1.CB25 CPU1.CA25 127.89,74.87 v2(127.57,75.18) 127.57,75.09 CPU1.BY25 126.93,75.06 v2(126.93,75.17) 126.59,75.52 CPU1.BW24 ; CPU1.CC25 CPU1.CC24 ; CPU1.CC25 CPU1.CD25 ; v2(109.39,87.76) 109.41,87.78 109.59,87.78 CPU1.AM5 ; CPU1.AU10 v2(112.63,84.12) ; CPU1.BL29 121.81,72.59 121.81,73.12 CPU1.BL28 ; CPU1.BL29 121.79,72.49 121.79,71.88 CPU1.BL30 ; CPU1.CK4 133.03,88.27 CPU1.CJ4 CPU1.CJ3 CPU1.CJ2 132.46,89.56 CPU1.CK1 v2(133.11,90.74) 133.11,91.57 v2(133.1,91.59) ; CPU1.CK4 133.07,88.17 133.4,87.84 v2(133.41,87.84) ; CPU1.V30 101.15,72.24 v2(101.24,72.24) 101.34,72.24 CPU1.W30 102.06,72.24 v2(102.15,72.24) 102.26,72.24 CPU1.Y30 102.81,71.68 103.32,71.68 CPU1.AB30 103.55,71.88 103.8,72.14 104.18,72.14 CPU1.AC30 104.69,72.13 105.1,72.13 CPU1.AE30 105.6,72.14 105.76,72.14 v2(105.78,72.16) 105.81,72.14 106,72.14 CPU1.AF30 CPU1.AH30 ; 106.62,70.13 106.87,69.88 106.87,69.85 107.25,69.85 CPU1.AH33 CPU1.AH35 ; 106.62,70.13 106.62,70.1 106.37,69.85 106.01,69.85 CPU1.AF33 106,70.14 v2(105.81,70.33) 105.63,70.33 105.15,69.86 CPU1.AD33 ; 106.62,70.13 106.7,70.2 106.7,70.87 107.06,71.23 CPU1.AH31 CPU1.AH30 ; CPU1.V26 CPU1.Y26 102.61,73.84 CPU1.Y27 CPU1.AB27 ; CPU1.V26 101.25,74.29 CPU1.V27 100.49,73.53 v2(100.33,73.53) ; CPU1.V26 101.7,73.84 CPU1.W27 ; CPU1.CP19 v2(136.26,78.9) ; CPU1.V3 101.35,88.83 v2(101.24,88.72) 101.35,88.62 CPU1.V4 ; CPU1.D8 93.36,85.9 93.62,86.15 v2(93.62,86.18) ; CPU1.CN25 134.71,75.2 134,75.2 CPU1.CM25 133.89,75.12 v2(133.54,75.47) ; CPU1.AH27 107.32,73.83 v2(107.64,73.51) 107.5,73.51 CPU1.AH28 ; v2(127.53,90.74) 127.67,90.6 127.68,90.6 127.93,90.35 127.93,90.15 CPU1.CB2 128.05,89.74 128.05,89.38 CPU1.CB3 CPU1.CB4 ; CPU1.CB18 128.85,80.11 128.85,80.14 128.86,80.15 v2(128.86,80.19) 128.88,80.21 128.88,80.33 CPU1.CC16 ; CPU1.W7 101.72,86.22 v2(102.01,85.93) ; CPU1.E9 93.86,85.11 v2(94.16,84.81) ; v2(120.7,9.54) 120.7,8.35 121.26,7.79 C6401.2 ; CPU1.BA28 115.04,72.85 115,72.85 114.95,72.8 v2(114.93,72.8) ; v2(133.35,70.25) 133.28,70.25 133.19,70.16 132.68,70.16 CPU1.CJ33 ; CPU1.CC24 CPU1.CB24 128.21,75.92 v2(128.21,76) ; CPU1.CC24 CPU1.CD24 130.26,75.59 CPU1.CF23 130.31,76.35 v2(130.31,76.6) ; CPU1.K29 96.58,72.87 v2(96.69,72.87) 96.38,73.18 CPU1.K28 CPU1.K27 CPU1.H27 CPU1.G27 94.32,73.74 93.62,73.74 CPU1.E27 ; CPU1.AC10 v2(104.31,84.13) ; CPU1.CF19 130.27,78.72 130.27,78.56 v2(130.22,78.51) 129.84,78.13 CPU1.CD20 ; v2(108.53,73.56) 108.61,73.56 CPU1.AL28 ; CPU1.CN17 CPU1.CM17 133.84,80.16 133.46,80.54 132.42,80.54 v2(132.28,80.68) ; v2(128.22,84.4) 127.89,84.07 CPU1.CA11 ; 180.67,25.95 180.57,25.85 SSD1.76 177.5,25.85 177.24,26.1 ; 126.12,83.8 125.94,83.98 CPU1.BV11 125.94,84.09 v2(125.62,84.4) 125.29,84.07 CPU1.BU11 ; v2(29.84,24.91) 29.84,24.77 29.41,24.34 Q4349.1 29.17,24.95 28.96,25.16 28.19,25.16 27.87,25.48 Q4349.4 ; CPU1.BC8 116.45,85.57 116.73,85.85 v2(116.73,85.9) 116.73,85.93 117.02,86.22 CPU1.BD7 CPU1.BD6 ; CPU1.AF3 CPU1.AF4 v2(106.63,87.82) 106.78,87.82 CPU1.AG5 ; CPU1.BP25 CPU1.BR25 123.99,74.83 124.32,75.17 v2(124.33,75.17) 124.35,75.17 124.63,74.89 124.64,74.89 CPU1.BT25 124.69,74.7 125.23,74.7 CPU1.BU25 125.29,74.87 v2(125.6,75.18) 125.29,75.5 CPU1.BU24 125.42,75.73 125.42,76.3 CPU1.BU23 ; C1808.2 133.86,95.9 133.4,96.36 133.4,98.01 v2(133.35,98.06) ; CPU1.BY11 127.23,83.99 126.59,83.99 CPU1.BW11 ; v2(128.21,77.7) 128.21,77.6 CPU1.CA22 127.83,77.22 127.29,77.22 CPU1.BY22 ; PU4502.18 PU4502.21 ; CPU1.BU20 124.96,77.79 v2(124.96,77.67) ; v2(100.33,73.53) 100.18,73.53 CPU1.T27 ; v2(100.33,73.53) CPU1.U26 CPU1.U24 ; CPU1.AP3 111.11,88.83 v2(111.01,88.72) 111.11,88.62 CPU1.AP4 ; CPU1.CJ19 132.33,78.84 v2(132.33,78.54) ; v2(131.62,85.23) 131.62,85.23 131.59,85.27 131.59,85.73 CPU1.CG7 ; 9.32,77.69 9.32,77.85 9.06,78.1 USB1.16 ; CPU1.CP9 CPU1.CN9 CPU1.CM9 133.91,85.36 v2(133.38,85.9) 133.38,85.96 133.12,86.22 CPU1.CK7 ; CPU1.BB3 115.82,89.07 v2(115.82,88.74) ; CPU1.BN7 123.09,85.92 123.28,85.92 v2(123.29,85.9) 123.31,85.92 123.31,85.92 123.32,85.93 123.42,85.93 CPU1.BP7 ; CPU1.BT14 124.4,82.08 124.4,81.71 CPU1.BT15 ; CPU1.BR22 123.64,77.62 v2(123.64,77.7) ; CPU1.P4 98.91,88.48 v2(99.11,88.69) 98.91,88.9 CPU1.P3 ; CPU1.AD33 CPU1.AD35 ; CPU1.AT4 v2(112.33,88.01) ; CPU1.BT15 124.94,81.17 124.94,81.08 v2(124.96,81.06) 124.96,81.04 125.29,80.71 CPU1.BU16 ; CPU1.BT15 124.31,81.15 v2(124.31,81.03) 124.31,80.96 CPU1.BT16 ; CPU1.BE10 118.17,84.62 v2(117.62,84.07) ; CPU1.AV3 113.55,88.93 v2(113.73,88.75) ; PU5101.18 v2(154.56,25.04) ; CPU1.AM10 v2(109.85,84.04) ; v2(119.58,86.49) 119.75,86.49 CPU1.BJ7 ; CPU1.AM33 CPU1.AM35 ; CPU1.AG10 v2(107.08,84.1) ; CPU1.D25 93.31,75.11 v2(93.47,75.26) ; CPU1.K3 96.46,88.83 v2(96.36,88.72) 96.46,88.62 CPU1.K4 96.46,87.98 CPU1.J5 ; CPU1.AV6 113.43,86.87 v2(113.12,86.56) ; CPU1.P7 99.05,85.94 v2(99.23,85.94) ; v2(121.05,84.05) 120.94,84.16 CPU1.BK10 ; 178.3,42.68 IOBD1.15 ; v2(96.13,77.29) 96.13,77.14 CPU1.K22 ; CPU1.AK4 108.81,88.36 v2(108.81,88.72) 108.81,89.1 CPU1.AK3 ; v2(111.27,73.51) 111.4,73.51 CPU1.AR28 ; CPU1.CM21 CPU1.CN21 CPU1.CP21 135.45,77.64 135.61,77.7 136.26,77.7 136.27,77.7 v2(136.67,77.7) ; CPU1.BY5 127.29,87.52 v2(126.97,87.2) ; 179.8,42.85 IOBD1.12 ; CPU1.T7 99.98,85.93 v2(100.16,85.93) ; CPU1.AB3 CPU1.AB4 ; CPU1.C21 CPU1.B21 91.55,77.72 91.1,77.72 90.86,77.97 v2(90.72,77.97) ; CPU1.BL7 121.59,86.49 v2(121.43,86.49) 121.21,86.49 CPU1.BK7 ; CPU1.BP12 123.22,83.15 v2(122.9,83.46) 122.33,84.04 CPU1.BM9 ; CPU1.P10 v2(98.77,84.04) ; CPU1.BP4 123.48,88.23 123.82,87.89 124.32,87.89 124.46,88.03 124.51,88.03 v2(124.54,88.05) 124.54,87.98 124.54,87.98 124.54,87.62 CPU1.BT5 124.87,87.52 v2(125.09,87.74) 125.27,87.74 125.41,87.89 125.41,87.89 CPU1.BV4 CPU1.BV3 ; CPU1.BG25 v2(119.02,75.51) ; CPU1.BE28 118.19,73.18 v2(118.58,72.79) 118.32,72.53 CPU1.BE29
  BOTTOM w0.279: CPU1.BW11 126.39,83.8 126.12,83.8 ; PU5102.8 v2(46.3,25.62) ; PU5102.4 44.28,26.12 v2(44.78,25.62) ; CPU1.BY11 CPU1.CA11
  BOTTOM w0.305: DB3.4 96.77,3.05 96.75,3.03 96.75,2.91 v2(96.65,2.81) ; v2(113.39,37.44) 113.39,37.56 113.97,38.14 RAM5.K9 ; EC4309.2 164.13,23.34 164.13,23.77 EC4310.2 164.16,24.1 164.16,24.51 ED4305.1 163.81,25.71 v2(163.96,25.85) ; RAM6.H9 103.92,39.74 103.24,39.06 103.24,38.8 v2(103.22,38.79) 103.22,38.66 103.74,38.14 RAM6.K9 ; RAM8.K9 124.12,38.14 123.54,37.56 v2(123.54,37.44) ; RAM3.A8 62.48,45.74 v2(62.48,45.79) ; RAM5.A8 115.38,45.39 v2(114.98,45.79) ; RAM6.E1 v2(111.23,41.74) 111.23,41.74 RAM6.F1 ; v2(93.5,79.05) 93.5,79.18 CPU1.F18 ; RAM4.K1 59.02,38.14 59.6,37.56 v2(59.6,37.44) ; CPU1.CB11 128.54,84.07 128.32,84.29 128.32,84.3 v2(128.22,84.4) ; LCD1.15 v2(94,100.35) ; RAM5.H9 113.88,39.74 113.36,39.23 v2(113.36,38.99) ; PR4817.2 54.71,80.74 54.41,80.43 53.51,80.43 53.24,80.7 53.24,80.89 v2(52.7,81.43) ; CPU1.J15 96.11,81.72 v2(96.11,81.86) ; CPU1.U7 100.33,85.93 v2(100.16,85.93) ; RAM1.H1 89.29,39.74 89.97,39.06 v2(89.97,38.94) ; LCD1.18 95.5,100.29 v2(95.53,100.32) ; CPU1.B5 92,87.63 v2(92.65,87.63) 92.65,87.88 CPU1.C4 ; RAM8.E1 v2(131.53,41.74) 131.53,41.74 RAM8.F1 ; v2(119.99,46) 119.99,45.53 RAM5.A2 RAM5.B2 ; RAM4.E1 v2(58.73,41.74) 58.73,41.74 RAM4.F1 ; U9102.16 164.02,62.05 164.85,62.88 v2(165.61,62.88) ; 82.8,42.54 82.8,42.56 RAM1.D8 ; 82.8,42.54 v2(82.78,42.54) ; 82.8,42.54 82.8,42.52 RAM1.E8 ; v2(135.28,40.93) 135.29,40.93 RAM7.G8 ; RAM5.D8 115.04,42.6 115.04,42.59 v2(114.99,42.54) 114.99,42.53 RAM5.E8 ; RAM6.B2 RAM6.A2 109.84,45.53 v2(109.84,46) ; RAM4.N1 58.73,35.74 59.68,36.69 v2(59.68,36.8) ; RAM1.A8 83.18,45.39 v2(82.78,45.79) ; v2(86.4,43.13) 86.4,42.92 RAM1.E3 ; RAM1.K9 81.63,38.14 81.19,37.69 v2(81.19,37.44) ; v2(142.47,38.94) 142.47,39.06 141.79,39.74 RAM7.H1 ; RAM5.H1 121.77,39.74 122.17,39.34 v2(122.17,38.99) ; v2(69.83,36.8) 69.83,36.53 69.04,35.74 RAM3.N1 ; RAM3.D8 62.52,42.58 62.52,42.54 ; v2(50.74,37.44) 50.74,37.56 51.32,38.14 RAM4.K9 ; SSD1.45 171.75,12.85 171.63,12.97 v2(171.55,12.97) ; v2(93.5,82.82) 93.5,82.94 CPU1.F12 ; v2(99.83,75.72) CPU1.U24 ; v2(91.55,82.82) 91.55,82.94 CPU1.B12 ; C4013.2 147.29,93.29 FC8945.2 147.24,92.17 v2(147.32,92.09) ; EC2601.2 164.16,78.76 v2(165.48,78.76) ; RAM1.T1 89.05,33.07 v2(89.05,32.72) ; v2(157.23,78.5) 156.9,78.17 C2503.2 ; v2(71.04,37.44) 71.04,37.56 71.62,38.14 RAM2.K9 ; R4006.2 106.91,20.64 C4003.2 ; v2(162.27,59.06) 163.52,57.81 U9102.23 ; CPU1.C37 CPU1.B37 91.69,67.34 91.38,67.03 90.29,67.03 v2(90.26,67.06) ; v2(140.88,43.34) RAM7.D2 ; 33.29,30.5 PQ4418.4 33.76,31.83 34.21,31.39 v2(34.42,31.39) ; IOBD1.6 182.8,42.79 ; RAM7.B2 140.48,44.55 140.64,44.71 140.64,45.18 RAM7.A2 140.29,45.53 140.29,45.63 v2(140.12,45.8) ; v2(81.19,38.99) 81.19,39.13 81.8,39.74 RAM1.H9 ; v2(91.55,79.05) 91.55,79.18 CPU1.B18 ; v2(59.55,39.01) 59.55,39.28 59.08,39.74 RAM4.H1 ; IOBD1.18 v2(176.8,42.44) ; v2(79.98,36.8) 79.98,36.69 79.03,35.74 RAM2.N1 ; CPU1.AE7 104.95,85.93 v2(104.78,85.93) ; v2(90.47,86.89) 90.9,86.47 CPU1.B7 ; CPU1.AC5 103.79,88.04 CPU1.AB4 ; CPU1.CD11 130.11,83.72 v2(130.35,83.72) 130.47,83.85 130.47,84.01 130.66,84.2 CPU1.CF11 ; Q7404.4 v2(18.92,68.92) ; RAM7.T1 141.55,33.07 v2(141.55,32.72) ; v2(90.05,37.44) 90.05,37.56 89.47,38.14 RAM1.K1 ; v2(95.45,82.82) 95.45,82.94 CPU1.J12 ; v2(122.25,37.44) 122.25,37.56 121.67,38.14 RAM5.K1 ; v2(50.64,39.12) 50.64,39.17 51.21,39.74 RAM4.H9 ; v2(69.75,37.44) 69.75,37.65 69.26,38.14 RAM3.K1 ; v2(78.9,32.72) 78.9,33.07 RAM2.T1 ; v2(55.97,43.08) 55.97,42.9 RAM4.E3 ; RAM6.E8 104.84,42.53 v2(104.84,42.54) 104.89,42.59 104.89,42.6 RAM6.D8 ; RAM4.T1 58.6,33.07 v2(58.6,32.72) ; v2(18.29,59.71) 17.93,59.35 17.93,59.29 17.59,58.95 16.83,58.95 16.53,58.64 Q5705.1 16.53,57.23 C5777.2 ; RAM6.G8 104.84,40.93 v2(104.83,40.93) ; v2(172.09,9.82) 172.11,9.85 SSD1.57 ; v2(67.49,46) 67.49,45.53 RAM3.A2 RAM3.B2 ; v2(139.06,42.9) 139.06,42.76 RAM7.E3 ; EC8913.2 53.54,59.89 v2(53.59,59.84) ; RAM7.E8 135.29,42.53 v2(135.29,42.54) 135.34,42.59 135.34,42.6 RAM7.D8 ; v2(95.08,84.81) 95.24,84.81 CPU1.H9 ; CPU1.B15 92.2,81.71 v2(92.2,81.86) ; v2(93.47,75.26) 93.47,75.35 CPU1.F24 93.51,76.04 CPU1.E23 ; 174.41,20.34 174.41,18.81 ; 174.41,20.34 174.41,21.7 174.26,21.85 SSD1.9 ; 174.41,20.34 174.39,20.35 SSD1.15 ; 174.41,18.81 174.37,18.85 SSD1.21 ; 174.41,18.81 174.41,17.71 ; CPU1.D9 92.83,84.99 v2(92.83,84.71) ; CPU1.J6 95.88,86.87 v2(95.55,87.2) 95.87,87.52 CPU1.J5 ; RAM1.E1 v2(89.18,41.74) 89.18,41.74 RAM1.F1 ; v2(121.25,32.72) 121.25,33.07 RAM5.T1 ; v2(122.24,34.95) 122.27,34.95 121.48,35.74 RAM5.N1 ; RAM7.F1 141.68,41.74 v2(141.68,41.74) RAM7.E1 ; Q7404.1 16.81,70.76 v2(16.38,70.76) ; ED7305.3 32.64,85.14 32.64,84.85 v2(32.89,84.6) ; v2(62.48,42.54) 62.52,42.54 ; 62.52,42.54 62.52,42.5 RAM3.E8 ; Q7406.4 15.95,68.09 v2(16.38,68.09) ; v2(142.63,36.8) 142.63,36.69 141.68,35.74 RAM7.N1 ; RAM8.E8 125.14,42.53 v2(125.14,42.54) 125.19,42.59 125.19,42.6 RAM8.D8 ; v2(135.28,45.79) 135.68,45.39 RAM7.A8 ; v2(137.67,96.03) 137.67,95.89 137.01,95.23 136.96,95.23 135.57,93.84 v2(135.57,92.85) ; v2(69.67,38.99) 69.67,39.11 69.04,39.74 RAM3.H1 ; CPU1.Y7 102.18,85.93 v2(102.01,85.93) ; RAM4.B2 RAM4.A2 57.34,45.53 v2(57.34,46) ; v2(133.45,94.94) 133.45,91.94 v2(133.1,91.59) ; v2(60.07,70) 59.97,70.1 59.97,70.72 PU4802.28 ; C2604.2 171.98,81.7 172.21,81.93 172.21,82.82 171.6,83.43 C2603.2 171.45,83.79 171.15,84.09 v2(171.07,84.09) 170.64,83.66 C2605.2 ; CPU1.K9 96.16,84.81 v2(96.01,84.81) ; RAM5.G8 114.99,40.93 v2(114.98,40.93) ; CPU1.AB7 103.1,85.93 v2(102.94,85.93) ; v2(111.42,34.95) 111.42,35.15 RAM6.N1 ; SSD1.51 172.09,11.35 v2(172.09,11.34) ; v2(172.09,15.92) 172.15,15.85 SSD1.33 174.07,15.85 174.41,16.18 174.41,17.71 ; RAM8.E3 128.86,42.81 128.86,43.15 v2(128.86,43.15) ; v2(123.51,38.99) 123.51,39.24 124.01,39.74 RAM8.H9 ; 156.08,81.13 156.08,80.66 156.54,80.21 C1711.2 ; CPU1.D5 93.24,87.68 v2(93.64,87.27) 93.4,87.03 CPU1.D6 ; PU5001.4 152.65,101.88 152.94,101.59 153.39,101.59 153.92,102.13 v2(153.92,102.25) ; PC4877.2 51.28,84.57 50.98,84.27 PR4608.1 ; v2(79.82,38.99) 79.82,39.37 79.46,39.74 RAM2.H1 ; CPU1.P7 98.48,85.93 v2(98.32,85.93) ; RAM7.K9 134.27,38.14 133.69,37.56 v2(133.69,37.44) ; RAM6.A8 105.23,45.39 v2(104.83,45.79) ; CPU1.K24 96.43,75.59 v2(96.11,75.26) ; RAM3.E1 v2(68.88,41.74) 68.88,41.74 RAM3.F1 ; CPU1.AF7 105.87,85.93 v2(105.71,85.93) ; IOBD1.21 175.3,42.48 174.98,42.15 v2(174.98,41.94) ; R2030.2 146.38,72.03 R2014.2 ; RAM5.E1 v2(121.38,41.74) 121.38,41.74 RAM5.F1 ; v2(48.59,88.03) 48.49,88.13 EC8912.2 ; v2(95.45,79.05) 95.45,79.18 CPU1.J18 ; v2(94.18,81.86) 94.18,81.74 CPU1.F15 ; v2(132.1,34.98) 131.33,35.74 RAM8.N1 ; 174.41,17.71 174.05,17.35 SSD1.27 172.12,17.35 v2(172.09,17.31) ; v2(61.52,43.74) RAM3.C9 ; D2601.A v2(172.85,76.6) 172.85,75.96 172.18,75.3 FAN1.5 ; RAM1.B2 RAM1.A2 87.79,45.53 v2(87.79,46) ; v2(140.84,7.38) 140.85,7.39 TP1.5 ; PU5201.4 178.85,56.66 v2(178.97,56.54) ; v2(52.33,45.79) 52.58,45.54 52.58,45.49 RAM4.A8 ; v2(130.14,46) 130.14,45.53 RAM8.A2 RAM8.B2 ; v2(133.66,38.99) 133.66,39.18 134.22,39.74 RAM7.H9 ; RAM8.T1 131.4,33.07 v2(131.4,32.72) ; v2(125.13,45.79) 125.53,45.39 RAM8.A8 ; U4002.5 153.63,59.92 153.21,59.51 153.21,58.9 v2(153.18,58.87) ; CPU1.A36 91.23,68.04 v2(90.75,67.56) ; RAM8.H1 131.88,39.74 132.32,39.3 v2(132.32,38.99) ; C5736.2 14.29,64.46 13.84,64.92 v2(13.72,64.92) ; R1501.2 150.57,59.02 v2(151,59.45) ; RAM3.E3 66.12,42.9 66.06,42.9 66.06,42.94 v2(66.02,42.94) ; RAM6.K1 111.73,37.24 v2(111.85,37.24) ; v2(130.73,43.34) RAM8.D2 ; C1391.2 49.3,43.86 48.77,43.33 v2(48.77,42.31) ; EC8929.2 169.37,45.92 170.05,45.23 171.83,45.23 v2(172.47,44.6) ; v2(9.22,84.98) 8.79,84.55 8.79,84.5 ; v2(68.75,32.72) 68.75,33.07 RAM3.T1 ; RAM1.N1 89.45,35.07 v2(89.45,34.95) ; RAM4.G8 52.34,40.93 v2(52.33,40.93) ; PQ4416.4 33.04,34.96 31.99,33.91 PQ4418.1 31.54,33.93 v2(31.37,33.93) ; RAM7.C9 v2(134.32,43.74) ; v2(175.53,59.58) PU5201.19 ; LCD1.12 v2(92.5,100.35) ; Q401.1 161.18,86.11 160.78,86.51 160.09,86.51 159.88,86.72 Q401.4 ; v2(60.85,39.04) 60.85,39.24 61.35,39.74 RAM3.H9 ; SSD1.39 172.31,14.35 v2(172.09,14.57) ; CPU1.AL7 108.64,85.93 v2(108.48,85.93) 108.3,85.93 CPU1.AJ7 ; CPU1.E35 93.23,68.84 v2(93.08,68.99) ; RAM6.T1 111.1,33.07 v2(111.1,32.72) ; CPU1.T7 99.42,85.94 v2(99.23,85.94) ; v2(44.27,13.84) C2609.2 C2608.2 ; USB1.18 v2(9.27,82.72) ; v2(94.16,84.81) 94.31,84.81 CPU1.G9 ; CPU1.L27 97.14,73.94 v2(96.79,74.3) 96.79,74.45 CPU1.K25 96.43,74.93 v2(96.11,75.26) ; CPU1.E29 v2(93.91,72.2) ; PQ4416.1 31.73,37.73 31.9,37.9 31.9,38.34 31.49,38.75 v2(31.37,38.75) ; v2(96.11,75.26) 96.11,75.39 CPU1.J24 ; ED1702.3 ED1703.3 167,84.6 v2(167.45,85.04) ; v2(71.04,38.99) 71.04,39.11 71.67,39.74 RAM2.H9 ; RAM2.K1 79.32,38.14 79.9,37.56 v2(79.9,37.44) ; RAM4.D8 52.39,42.6 52.39,42.59 v2(52.34,42.54) 52.34,42.53 RAM4.E8 ; C9112.2 164.34,53.66 C9113.2 164.39,53.66 164.97,54.25 v2(164.97,54.37) ; v2(18.29,65.04) 17.97,65.36 Q7402.4 ; v2(62.48,40.93) 62.49,40.93 RAM3.G8 ; Q7406.1 14.03,69.55 v2(13.84,69.74) ; RAM5.C9 v2(114.02,43.74) ; v2(68.08,43.34) RAM3.D2 ; FPR1.8 v2(176.53,47.45) ; ED5703.8 14.4,62.63 R5764.2 14.3,62.63 v2(13.72,62.63) ; v2(120.58,43.34) RAM5.D2 ; v2(82.78,40.93) 82.79,40.93 RAM1.G8 ; v2(142.55,37.44) 142.55,37.56 141.97,38.14 RAM7.K1 ; Q7405.4 20.84,68.13 20.17,67.45 20.17,67.31 19.83,66.96 Q7402.1 19.42,66.96 v2(18.92,67.46) ; v2(112.02,38.99) 112.02,39.28 111.56,39.74 RAM6.H1 ; RAM8.K1 131.82,38.14 132.4,37.56 v2(132.4,37.44) ; v2(184.3,42.79) IOBD1.3 ; EC2602.2 165.86,80.87 166.42,81.43 v2(169.29,81.43) ; RAM6.E3 108.5,42.87 108.5,42.96 v2(108.5,42.96) ; PU4801.28 59.95,79.46 60.2,79.21 v2(60.2,79.14) ; RAM8.G8 125.14,40.93 v2(125.13,40.93) ; IOBD1.24 173.8,43.01 173.35,42.56 v2(173.35,41.93) ; v2(20.32,43.71) 20.07,43.96 U3401.14 20.07,44.93 v2(20.35,45.21) ; RAM8.C9 v2(124.17,43.74) ; v2(60.89,37.44) 60.89,37.56 61.47,38.14 RAM3.K9 ; CPU1.W7 101.25,85.93 v2(101.09,85.93) ; RAM4.C9 v2(51.37,43.74) ; v2(57.93,43.34) RAM4.D2 ; v2(110.43,43.34) RAM6.D2 ; v2(88.38,43.34) RAM1.D2 ; v2(13.72,60.85) 14.22,60.85 14.48,60.6 14.91,60.6 Q5705.4 ; v2(81.82,43.74) RAM1.C9
  BOTTOM w0.33: Q1702.1 133.36,53.24 134.33,54.21 134.56,54.21 134.8,54.45 v2(135.25,54.45) 135.41,54.3 137.16,54.3 ED1701.3 ; RAM2.C9 v2(71.65,43.74) ; RAM2.E8 v2(72.63,42.54) 73.03,42.93 RAM2.D8 ; v2(78.23,43.34) RAM2.D2 ; RAM2.G8 72.65,40.92 72.65,40.93 v2(72.64,40.94) ; RAM2.E1 78.63,42.13 v2(79.03,41.74) RAM2.F1 ; v2(76.25,43.05) 76.25,42.92 RAM2.E3 ; 127.54,50.28 127.54,51.82 R2051.2 ; v2(72.63,45.79) 72.63,45.74 RAM2.A8
  BOTTOM w0.356: v2(145.1,52.54) 145.1,52.1 Q1701.4 ; PQ4415.4 33.27,20.87 v2(33.27,20.48) ; PR4474.2 30.78,37.18 31.24,36.72 31.24,36.59 v2(31.37,36.47) 31.73,36.83 PQ4416.1 ; v2(153.54,89.17) 158.5,89.17 159.88,87.79 Q401.4 ; v2(20.07,8.91) 19.68,8.91 19.05,8.27 SPK1.5 ; PQ4405.4 31.38,40.17 31.37,40.15 v2(31.37,40.02) ; RAM5.E3 118.52,43 v2(118.52,43.19) ; 155.27,59.79 U4008.3 ; PQ4415.1 v2(35.09,23.26)
  BOTTOM w0.381: v2(34.8,84.6) 34.8,84.9 R7331.2 ; PQ4405.1 29.15,42.63 v2(29.03,42.51) ; PR4487.1 33.58,30.21 33.29,30.5 ; PC5213.2 179.27,60.93 v2(179.2,60.85) ; v2(46.23,69.11) 46.23,69.28 46.61,69.66 PC4638.2 ; EC2403.2 80.52,8.96 79.91,8.35 78.79,8.35 v2(78.49,8.04) ; v2(111.43,94.96) 111.46,94.94 R1714.1 ; H6.1 147.23,92 v2(147.32,92.09) ; PC5310.2 v2(135.51,20.59) ; C4007.2 153.18,58.93 v2(153.18,58.87) ; v2(86.49,5.48) 86.49,5.23 86.57,5.14 86.57,4.96 C2424.2 ; v2(153.67,57.93) 154.47,57.93 154.66,58.12 154.67,58.12 155,58.46 155,59.52 155.27,59.79 ; PR5101.2 152.91,21.3 152.72,21.1 152.72,21.09 v2(152.48,20.85) ; PC4708.2 54.05,59.12 53.59,59.58 v2(53.59,59.84) ; C2405.2 C2406.2 101.85,9.67 101.29,9.1 v2(101.19,9.1) ; v2(23.11,48.53) 23.29,48.53 23.72,48.1 R5743.2 ; PR4608.1 50.55,85.19 50.29,85.44 v2(50.29,85.62) ; PR4654.2 58.62,58.51 v2(58.67,58.57) ; v2(58.88,79.14) 58.8,79.14 58.67,79.01 PR4617.2 ; U4002.5 154.6,60.33 C4040.2 ; H8.1 144.65,70 v2(147.83,70)
  BOTTOM w0.457: PR5203.2 182.37,56.23 182.37,56.79 v2(182.5,56.91) 181.18,56.91 PC5215.2
  BOTTOM w0.508: R1803.2 132.76,95.62 v2(132.84,95.7) ; C5750.2 22.78,64.1 v2(23.24,63.65) ; 92.25,38.56 92.25,39.88 92.75,40.39 93.11,40.39 93.11,40.36 v2(93.14,40.36) ; ED6401.3 110.69,15.38 112.45,17.13 v2(112.89,17.32) ; v2(41.66,35.58) 41.53,35.71 PR4436.2 ; C2220.2 153.54,81.93 v2(153.03,82.44) ; 14.9,33.71 USB2.11 ; USB2.11 16.58,34.6 ; USB2.11 14.9,35.49 ; v2(124.33,95.06) 124.3,95.1 124.3,96.04 C2209.2 124.22,96.22 C2208.2 ; PC5002.2 146.43,108.86 ; PC4508.2 130.61,18.66 PR4508.2 v2(131.32,17.93) ; EC2501.2 132.7,61.52 132.95,61.77 132.95,61.78 132.95,61.84 v2(133.09,61.98) 133.01,62.05 R1507.2 ; KBBD1.1 v2(63.65,9.04) ; FSW1.5 29.73,11.62 v2(30.37,12.25) 30.37,12.33 30.71,12.67 v2(30.71,13.86) ; v2(30.78,50.97) 30.78,51 ; 30.78,51 30.94,51 31.29,50.64 PC4416.1 ; 30.78,51 30.07,50.28 PC4419.2 ; ED4306.1 160.39,23.04 v2(160.86,22.57) 160.39,22.11 ED4304.1 ; PC4641.2 45.85,66.44 v2(45.97,66.31) 46.23,66.31 46.61,66.69 PR4655.1 ; C3405.2 C3404.2 17.87,47.4 USB2.10 ; USB2.10 14.35,47.95 14.35,48.53 ; USB2.10 14.9,47.35 16,46.25 v2(16.13,46.25) ; 11.1,53.26 HDMI1.21 ; HDMI1.21 12.48,54.25 ; HDMI1.21 11.1,55.24 ; v2(37.59,80.66) 37.52,80.59 PC4603.1 ; PC4426.1 36.8,40.3 v2(37.34,39.77) 37.97,40.4 PC4424.1 ; PC4644.2 v2(43.31,66.31) ; Q4001.S 33.01,17.54 v2(33.66,17.54) ; Q4001.S 32.91,15.78 C2601.2 ; Q4001.S 32.91,18.03 32.78,18.15 32.78,19.48 C4037.2 ; v2(146.81,70.88) 146.81,71.21 146.45,71.58 R2014.2 145.94,71.96 FC8943.2 ; 10.41,67.76 HDMI1.23 11.1,69.74 ; C1807.2 136.93,95.9 v2(137.03,96) ; v2(136.96,92.73) 137.13,92.89 R5507.2 ; PC4507.2 122.81,17.57 v2(122.81,18.43) ; USB1.21 6.12,88.21 ; USB1.21 4.78,87.37 ; USB1.21 7.45,87.37 ; PC5301.2 36.68,15.58 v2(36.71,15.55) ; C2219.2 v2(140.84,98.44) ; KBBL1.6 78.26,7.82 v2(78.49,8.04) ; v2(19.49,33.36) 19.89,32.96 C6701.2 ; 6.12,74.39 USB1.14 ; USB1.14 7.45,75.23 ; USB1.14 4.78,75.23 ; v2(105.92,26.43) 105.92,27.1 106.05,27.22 C4001.2 C4002.2 ; v2(30.99,54.37) 31.31,54.37 31.82,53.87 X5701.4 ; v2(25.1,30.17) 25.15,30.12 C5742.2 26.04,30.12 26.29,30.37 C5744.2 ; 2.25,88.21 USB1.22 3.58,87.37 ; v2(36.6,21.86) 36.6,22.34 PC5306.2 36.78,22.52 PR5301.2 ; v2(102.74,20.11) 102.16,20.11 C4009.2 ; PR4621.1 51.05,80.92 v2(50.55,80.41) ; 7.75,49.84 USB2.12 6.45,49.84 ; U2502.2 153.28,73.05 153.42,72.92 v2(153.46,72.92) ; 6.29,84.5 USB1.B1 6.91,85.54 ; C1130.2 92.41,36.67 R1221.1 90.56,36.67 90.05,37.18 v2(90.05,37.44) ; X1801.2 136.96,98.63 v2(137.6,98) ; C5764.2 28.5,49.29 v2(28.92,48.87) ; KBBD1.31 65.43,8.2 64.46,8.6 v2(64.28,9.04) ; v2(161.93,49.8) 161.79,49.94 161.07,49.94 C2517.2 161.04,49.73 160.53,49.22 R2518.2 ; U4006.5 147.49,98.84 v2(147.45,98.8) ; C1711.2 157.71,80.21 R1719.2 157.73,79.25 R2116.2 157.78,79.01 157.27,78.5 v2(157.23,78.5) ; FAN1.2 169.05,81.18 v2(169.29,81.43) ; PR4475.2 33.73,40.07 v2(34.42,39.39) ; EC8925.2 132.36,98.34 v2(132.66,98.65) ; EC5505.1 49.23,88.66 v2(48.59,88.03) ; ED301.3 117.09,98.5 v2(117.09,97.81) ; v2(24.64,26.31) 24.21,25.88 R4315.2 ; PR4608.1 50.52,84.3 PC4604.1 49.05,84.3 PR4614.2 ; v2(180.19,44.95) 179.91,44.95 179.86,45.01 179.85,45.01 179.14,45.71 179.12,45.71 179.08,45.75 FPR1.9 ; 6.91,77.06 USB1.B12 6.29,78.1 ; PC4606.2 41,80.64 v2(41.66,81.3) ; R1509.2 137.46,64.23 v2(137.29,64.41) ; v2(150.67,20.87) 151.05,21.25 PC5110.2 ; v2(102.62,13.73) 102.62,14.57 R2417.2 ; PQ4417.S 35.87,27.9 v2(34.42,29.36) ; v2(46.99,82.82) 47.12,82.95 PC4602.2 ; v2(80.39,5.61) 80.39,6.14 C2427.2 ; v2(150.24,76.52) 150.24,76.46 150.87,75.84 151.55,75.84 Q2505.S 152.35,75.93 R2504.2 152.1,75.08 R1521.2 ; v2(139.32,53.49) 138.81,53.49 138.5,53.17 135.93,53.17 135.48,52.72 C1806.2 ; TP1.10 136.14,5.23 v2(135.51,5.23) ; v2(59.05,27.45) 58.98,27.37 PR4530.2 ; R7330.2 35.05,87.52 v2(35.18,87.65) ; EC1803.2 FC1801.2 126.31,58.51 125.98,58.18 ; v2(35.8,76.79) 35.8,76.81 35.76,76.85 R4303.2 35.76,78.35 R4308.2 35.44,78.68 35.44,79.4 Q4304.E ; PC5202.2 v2(179.2,60.09) ; PR4551.2 v2(61.34,27.45) ; PC4530.2 58.6,23.87 ; 58.6,23.87 58.09,23.87 v2(57.96,24) ; 58.6,23.87 PR4512.2 ; v2(18.29,59.71) 18.67,59.33 C7211.2 19.1,58.84 C7244.2 ; PC1065.2 67.41,58.59 v3(67.31,58.69) ; 7.75,32.16 USB2.13 6.45,32.16 ; 5.98,70.65 HDMI1.22 4.6,71.64 ; 7.36,76.83 USB1.15 ; USB1.15 8.45,76.04 ; USB1.15 9.75,78.12 10.04,78.12 10.38,78.46 v2(10.38,78.55) ; USB1.15 9.54,76.83 ; C801.1 122.06,96.59 v2(121.94,96.47) ; 125.98,57.68 126.36,57.3 127.24,57.3 v2(127.63,57.68) 127.89,57.94 R1722.2 ; v2(27.98,59.89) 28.07,59.98 C5755.2 ; R2517.2 v2(158.12,75.33) ; PC4531.2 60.58,27.32 v2(60.71,27.45) ; 5.98,52.35 HDMI1.20 4.6,51.36 ; C2501.2 139.12,59.94 C2502.2 139.19,59.67 v2(139.62,59.25) ; Q6503.S 132.34,10.76 v2(131.67,10.1) ; v2(43.18,71.65) 43.18,71.52 42.62,70.96 PC4637.2 42.6,70.73 PR4659.1 ; PC4621.1 38.53,71.98 v2(38.61,71.9) 38.73,72.03 PC4624.2 39.29,71.29 PC4601.2 ; U5704.1 24.13,37.99 23.06,36.92 C5743.2 ; D4303.3 51.18,18.05 50.16,17.04 v2(50.04,17.04) ; ED5502.3 51,91.38 v2(51.05,91.33) 50.8,91.08 U5503.2 ; 3.58,75.6 USB1.13 3.58,75.23 ; D4302.1 51.61,12.51 52.2,13.1 v2(52.2,13.35) ; FC8906.2 167.23,51.09 v2(167.23,50.56) ; v2(156.72,20.85) 156.59,20.72 156.56,20.72 156.51,20.67 PR5106.1 ; BIOS1.4 149.11,56.67 v2(149.48,57.04) 149.81,57.04 EC2502.2 ; v2(35.56,52.72) 35.56,51.56 35.36,51.36 PC4417.1 ; R7102.1 38.23,84.22 v2(38.1,84.09) ; G1801.1 154.38,48.71 v2(154.77,48.71) 155.12,48.71 155.63,49.22 EC1804.2 ; ED3503.2 19.56,36.21 20.07,35.71 v2(20.57,35.71) ; 7.36,85.78 USB1.20 8.45,86.56 ; PC4809.2 53.1,83.46 52.97,83.33 v2(52.7,83.33) ; R1527.2 141.4,74.14 v2(141.22,74.31) ; 58.29,13.86 57.14,12.71 Q4302.E ; 15.11,50.5 15.11,49.68 v2(15.49,49.29) ; 74.04,18.18 74.04,18.03 73.53,17.52 73.53,15.14 Q6501.S 73.53,14.5 C6506.2 C6501.2 ; C1710.2 150.14,51.96 v2(150.19,51.91) 150.56,51.54 Q2510.S ; v2(93.64,95.27) 93.64,94.72 R1517.2 ; 8.86,73.8 HS1.1 12.05,70.61 ; C1372.2 135.59,29.28 PR5320.2 ; FSW1.4 v2(29.37,8.65) ; v2(29.26,50.95) 29.84,50.95 30.41,51.52 X5701.2 ; v2(103.22,38.79) 103.22,38.94 101.8,40.36 R1301.2 ; v2(135.73,58.63) 135.76,58.63 135.82,58.69 135.93,58.69 135.96,58.73 EC2503.2 ; v2(157.4,20.85) 157.4,21.04 157.61,21.25 PR5105.2 ; PR5204.2 180.09,54.23 180.57,53.74 v2(181.48,53.74) ; v2(156.54,47.26) 156.54,47.26 156.54,47.26 156.85,46.95 Q1802.S ; v2(112.14,100.35) 112.39,100.09 112.39,99.97 112.4,99.97 LCD1.54 113.56,98.32 114.32,98.32 115.21,97.42 C5521.2 ; 156.08,81.13 155.65,81.56 R2112.2 155.49,81.76 154.56,82.7 v2(154.43,82.7) ; v2(31.37,33.93) 30.73,33.29 PR4426.2 ; PC4439.2 39.27,43.71 v2(38.35,43.71) ; v2(87.12,89.55) 87.12,90.26 R1518.2 ; v2(165.61,76.6) 165.75,76.45 FAN1.6 ; v2(68.45,6) 68.75,6.3 KBBL1.5 ; v2(88.64,62.58) 86.57,62.58 Q501.S ; v2(85.72,3.32) 85.93,3.12 C2425.2 ; v2(25.27,43.96) 24.56,43.96 24.05,44.47 24.05,44.52 C5748.2 ; X1801.4 134.24,96.82 134.24,96.11 C1808.2 133.45,95.32 v2(133.45,94.94) ; v2(163.17,71.39) 161.34,71.39 C4032.2 160.22,71.14 C2525.2 158.62,71.05 C4043.2 FC8933.2 ; C5502.2 122.79,106.85 v2(122.48,107.16) ; C4003.2 v2(106.17,20.11) ; v2(152.4,89.05) 153.42,88.03 154.31,88.03 157.73,84.6 ED1704.3 158.68,83.33 R1717.1 ; Q502.S 87.88,59 v3(88.18,58.7) ; PR4513.2 59.82,27.32 v2(59.94,27.45) ; R2455.2 105.23,17.04 v2(105.66,17.04) 105.85,16.85 Q2408.S 108.33,15.95 ED2403.3 ; v2(121.28,99.21) ED5501.2 ; R6509.2 77.09,17.54 ; v2(154.64,102.25) 154.64,101.85 EC8926.2 ; TP1.9 146.26,5.48 v2(145.92,5.48) ; U4302.3 33.35,54.96 33.35,54.51 33.27,54.43 33.27,54.37 v2(33.02,54.12) ; PR4661.2 46.63,69.82 PC4638.2 ; PC5112.2 148.82,20.87 v2(148.84,20.85) ; R2745.2 v2(9.4,6.09)
  vias: v1(14.73,4.44) v1(18.95,72.66) v1(20.4,28.49) v1(21.16,46.32) v1(21.21,10.36) v1(22.33,74.64) v1(24.89,19.07) v1(33.76,58.9) v1(37.06,70.93) v1(37.57,91.79) v1(41.02,50.95) v1(43.71,75.1) v1(47.4,22.29) v1(47.62,37.86) v1(49.02,88.97) v1(57.28,50.46) v1(61.82,50.87) v1(65.58,79.88) v1(66.12,87.42) v1(68.86,72.92) v1(70.05,87.01) v1(76.81,98.14) v1(77.04,57.45) v1(80.98,30.09) v1(97.1,37.08) v1(103.48,74.77) v1(103.71,104.23) v1(104.67,50.03) v1(118.59,52.88) v1(120.45,27.5) v1(122.71,49.83) v1(140.44,13.28) v1(143.26,11.09) v1(148.34,44.85) v1(151.89,94.3) v1(158.88,25.82) v1(160.15,99.38) v1(170.05,58.44) v1(172.21,53.82) v1(173.53,62.5) v2(1.02,4.42) v2(1.02,1.88) v2(1.09,6.14) v2(2.41,16.4) v2(2.7,6.03) v2(2.7,1.02) v2(3.31,11.52) v2(3.43,12.85) v2(3.43,10.05) v2(3.5,88.28) v2(3.56,14.37) v2(3.57,7.89) v2(4.1,87.35) v2(4.95,8.53) v2(5.21,72.4) v2(5.24,1.02) v2(5.71,8.53) v2(6.73,76.73) v2(7.78,1.02) v2(7.97,88.28) v2(8,86.89) v2(8.1,32.29) v2(10.29,82.19) v2(10.28,32.13) v2(10.32,1.02) v2(10.51,88.28) v2(10.54,85.24) v2(10.54,84.6) v2(10.46,79.7) v2(10.92,87.78) v2(10.92,86.63) v2(11.43,67.46) v2(11.46,49.61) v2(12.86,1.02) v2(12.95,90.44) v2(13.09,91.9) v2(13.08,32.14) v2(13.23,3.3) v2(13.72,91.2) v2(13.72,58.95) v2(14.1,33.04) v2(15.11,91.94) v2(15.38,0.76) v2(15.62,91.2) v2(15.75,3.07) v2(16.56,14.93) v2(16.64,9.92) v2(17.27,9.92) v2(17.4,30.24) v2(17.65,91.94) v2(17.65,72.41) v2(17.7,13.28) v2(18.03,29.61) v2(18.16,78) v2(18.29,72.41) v2(18.92,90.95) v2(18.92,89.81) v2(19.05,31.01) v2(19.26,87.13) v2(19.94,78) v2(20.19,91.94) v2(20.32,48.15) v2(20.32,43.07) v2(20.32,42.44) v2(20.46,0.76) v2(20.7,89.53) v2(21.72,70.88) v2(21.72,69.61) v2(21.72,68.98) v2(21.84,20.21) v2(21.84,18.43) v2(22.35,83.33) v2(22.35,82.7) v2(22.73,91.94) v2(22.73,18.43) v2(22.99,86.89) v2(23.37,75.33) v2(23.62,19.32) v2(23.62,18.43) v2(23.62,17.54) v2(23.62,16.66) v2(23.88,65.68) v2(24.13,75.33) v2(24.26,86.89) v2(24.51,18.43) v2(25.15,84.85) v2(25.27,56.66) v2(25.27,53.1) v2(25.27,48.79) v2(25.27,46.88) v2(25.27,42.06) v2(25.65,1.56) v2(26.16,86.89) v2(27.05,84.85) v2(27.18,83.08) v2(27.18,57.04) v2(28.07,86.89) v2(28.68,57.07) v2(28.96,38.88) v2(28.96,6.36) v2(29.08,84.22) v2(29.08,83.58) v2(29.08,82.95) v2(29.08,82.31) v2(29.08,80.54) v2(29.72,80.54) v2(29.84,86.89) v2(30.35,81.17) v2(30.35,80.54) v2(31.75,86.89) v2(32.02,60.72) v2(32,60.08) v2(32.11,59.45) v2(32.1,6.65) v2(32.24,58.83) v2(34.16,47.14) v2(34.16,46.25) v2(34.16,45.36) v2(34.54,95.11) v2(34.8,83.97) v2(35.05,47.14) v2(35.05,46.25) v2(35.05,45.36) v2(35.94,47.14) v2(35.94,46.25) v2(35.94,45.36) v2(36.96,91.08) v2(36.96,84.09) v2(36.96,57.55) v2(36.96,56.91) v2(37.22,7.64) v2(37.47,97.74) v2(37.59,12.21) v2(37.97,92.47) v2(37.97,91.08) v2(37.97,89.68) v2(38,0.76) v2(38.1,7.13) v2(38.61,71.14) v2(38.61,70.5) v2(38.61,69.87) v2(38.61,69.23) v2(38.99,91.08) v2(40.14,87.39) v2(41.66,37.1) v2(41.66,36.47) v2(41.66,34.94) v2(41.66,34.18) v2(41.66,33.55) v2(41.66,32.66) v2(41.66,32.02) v2(42.55,97.74) v2(43.05,75.96) v2(43.69,93.95) v2(43.69,93.31) v2(43.69,90.95) v2(43.69,90.32) v2(43.81,75.96) v2(44.58,77.49) v2(44.58,76.73) v2(44.58,75.96) v2(44.58,75.2) v2(44.58,74.44) v2(44.83,93.24) v2(44.96,91.33) v2(45.21,92.6) v2(45.21,91.97) v2(45.34,75.96) v2(45.36,97.73) v2(45.54,25.62) v2(46.1,93.24) v2(46.1,75.96) v2(46.61,30.12) v2(46.81,15.16) v2(47.24,30.12) v2(47.29,15.59) v2(47.62,42.31) v2(47.75,93.87) v2(48.26,97.73) v2(49.02,74.57) v2(49.15,79.77) v2(49.48,21.76) v2(49.78,79.77) v2(50.42,79.77) v2(50.39,21.81) v2(51.26,97.73) v2(53.47,30.12) v2(53.87,97.73) v2(54.1,30.12) v2(55.12,69.49) v2(55.37,87.52) v2(56.77,24.02) v2(57.08,20.46) v2(57.25,97.73) v2(57.53,70) v2(57.9,20.44) v2(59.02,81.28) v2(59.02,72.13) v2(59.02,60.7) v2(59.94,30.12) v2(60.07,91.33) v2(60.2,86.76) v2(60.2,83.71) v2(60.2,83.08) v2(60.2,82.44) v2(60.2,81.81) v2(60.2,74.57) v2(60.2,73.93) v2(60.2,73.3) v2(60.2,72.66) v2(60.2,63.14) v2(60.2,62.5) v2(60.2,61.87) v2(60.2,61.23) v2(60.55,97.73) v2(60.71,91.33) v2(60.83,83.71) v2(60.83,83.08) v2(60.83,82.44) v2(60.83,81.81) v2(60.83,74.57) v2(60.83,73.93) v2(60.83,73.3) v2(60.83,72.66) v2(60.83,63.14) v2(60.83,62.5) v2(60.83,61.87) v2(60.83,61.23) v2(60.93,49.07) v2(60.96,21.33) v2(61.38,49.56) v2(61.47,83.71) v2(61.47,83.08) v2(61.47,82.44) v2(61.47,81.81) v2(61.47,81.04) v2(61.47,74.57) v2(61.47,73.93) v2(61.47,73.3) v2(61.47,72.66) v2(61.47,71.9) v2(61.47,63.14) v2(61.47,62.5) v2(61.47,61.87) v2(61.47,61.23) v2(61.47,60.47) v2(61.89,49.99) v2(62.23,30.12) v2(64.14,97.73) v2(64.26,27.45) v2(64.9,27.45) v2(65.41,91.33) v2(65.66,27.45) v2(66.04,91.33) v2(66.29,27.45) v2(66.67,91.33) v2(67.72,98.82) v2(68.27,49.43) v2(68.73,49.89) v2(70.23,30.12) v2(70.36,100.35) v2(71.75,91.33) v2(71.92,49.07) v2(72.47,101.54) v2(72.85,70.71) v2(73.41,27.45) v2(73.71,71.52) v2(74.04,27.45) v2(74.3,71.87) v2(74.63,102.81) v2(75.18,27.45) v2(75.82,27.45) v2(76.71,27.45) v2(77.34,27.45) v2(77.39,104.41) v2(79.83,105.81) v2(81.6,49.28) v2(82.96,107.61) v2(83.44,30.12) v2(83.79,73.43) v2(84.84,85.87) v2(84.88,76.67) v2(85.57,108.96) v2(85.85,73.41) v2(86.02,74.98) v2(86.23,100.35) v2(86.28,76.61) v2(86.49,71.53) v2(86.53,69.37) v2(86.53,32.54) v2(86.92,68.29) v2(87.39,75.01) v2(87.67,76.63) v2(87.78,72.52) v2(88.06,109.11) v2(88.27,104.92) v2(88.64,61.31) v2(88.64,60.04) v2(89.56,100.35) v2(90.06,89.26) v2(90.17,104.92) v2(90.21,69.37) v2(90.6,109.11) v2(90.7,89.25) v2(90.85,90.7) v2(90.85,31.67) v2(90.95,49.4) v2(90.95,46.63) v2(90.95,46) v2(91.24,62.89) v2(91.51,90.73) v2(91.5,61.11) v2(91.5,59.84) v2(91.5,58.57) v2(92.08,104.92) v2(92.14,90.75) v2(92.58,64.24) v2(93.14,109.11) v2(93.09,61.31) v2(93.09,60.04) v2(93.09,58.77) v2(93.13,42.77) v2(93.98,104.92) v2(94.81,77.32) v2(95.47,77.29) v2(95.68,109.11) v2(95.72,62.58) v2(95.72,60.67) v2(95.89,104.92) v2(96.11,58.17) v2(97.79,104.92) v2(98.14,62.21) v2(98.22,109.11) v2(98.55,63.68) v2(98.53,33.06) v2(99.13,77.7) v2(99.13,77.01) v2(99.05,60.68) v2(99.15,82.25) v2(99.15,81.61) v2(99.15,80.95) v2(99.15,80.29) v2(99.15,79.63) v2(99.15,78.99) v2(99.15,78.33) v2(99.19,75.71) v2(99.15,58.47) v2(99.28,40.72) v2(99.57,100.35) v2(99.71,81.26) v2(99.71,80.59) v2(99.71,79.93) v2(99.71,79.3) v2(99.71,78.64) v2(99.71,77.98) v2(99.69,77.32) v2(99.74,76.68) v2(100.2,100.35) v2(100.5,64.24) v2(100.5,62.99) v2(100.5,61.52) v2(100.52,59.9) v2(100.58,29.99) v2(100.84,100.35) v2(100.84,95.27) v2(101.8,59.87) v2(101.92,63.32) v2(102.74,95.27) v2(103.38,95.27) v2(104.01,100.35) v2(103.99,77.75) v2(103.99,77.06) v2(104.02,76.43) v2(104.01,75.79) v2(104.27,104.92) v2(104.27,25.04) v2(104.27,24.4) v2(104.57,62.89) v2(104.82,60.43) v2(104.77,58.89) v2(104.77,57.62) v2(104.76,47.19) v2(104.9,104.92) v2(104.9,94.76) v2(105.75,62.06) v2(105.78,64.06) v2(105.94,94.76) v2(106.53,92.52) v2(106.71,100.35) v2(107.07,37.74) v2(107.21,65.74) v2(107.21,64.29) v2(107.21,63.01) v2(107.16,49.28) v2(107.7,95.27) v2(107.7,94.63) v2(107.74,32.69) v2(107.7,25.04) v2(107.7,24.4) v2(107.92,75.67) v2(107.87,49.99) v2(108.32,50.44) v2(108.33,25.04) v2(108.33,24.4) v2(108.63,64.49) v2(108.6,62.59) v2(108.82,50.87) v2(109.59,58.5) v2(109.59,56.79) v2(109.86,93.36) v2(109.86,92.73) v2(110.11,104.84) v2(110.45,60.41) v2(110.62,91.43) v2(111.93,83.31) v2(111.93,82.65) v2(111.93,81.99) v2(111.93,81.33) v2(111.93,80.7) v2(111.93,80.04) v2(111.91,79.4) v2(111.91,78.72) v2(111.93,78.08) v2(111.91,77.42) v2(111.93,76.78) v2(112.49,82.96) v2(112.49,82.3) v2(112.49,81.64) v2(112.49,81) v2(112.49,80.34) v2(112.49,79.68) v2(112.46,79.02) v2(112.52,78.38) v2(112.52,77.72) v2(112.52,77.09) v2(112.52,76.45) v2(112.82,62.31) v2(113.12,87.81) v2(113.09,5.42) v2(113.92,92.6) v2(113.97,87.82) v2(114.05,28.09) v2(114.2,0.76) v2(114.73,62.16) v2(114.68,28.09) v2(115.19,92.73) v2(115.19,90.82) v2(115.32,28.09) v2(115.7,100.35) v2(116.33,100.35) v2(116.73,72.8) v2(116.71,9.42) v2(117.09,95.52) v2(117.09,93.62) v2(117.35,28.09) v2(117.44,83.31) v2(117.98,28.09) v2(118.08,83.31) v2(118.29,88.71) v2(118.62,28.09) v2(118.71,83.34) v2(118.71,82.68) v2(118.71,82.02) v2(118.71,81.38) v2(118.71,80.72) v2(118.71,80.06) v2(118.71,79.43) v2(118.71,78.77) v2(118.71,78.13) v2(118.71,77.47) v2(118.71,76.81) v2(118.76,76.18) v2(119,61.47) v2(119.32,80.34) v2(119.32,79.71) v2(119.28,0.76) v2(120.32,95.78) v2(120.45,66.31) v2(120.4,6.24) v2(120.73,108.83) v2(120.8,94.06) v2(120.86,63.9) v2(121.84,80.54) v2(121.87,1.02) v2(122.3,108.98) v2(122.27,93.35) v2(122.47,95.28) v2(122.6,82.83) v2(124.3,109.14) v2(124.33,28.09) v2(124.41,1.02) v2(124.71,24.02) v2(124.84,53.99) v2(124.97,28.09) v2(125.35,29.99) v2(125.6,28.09) v2(125.73,94.63) v2(125.73,92.6) v2(125.88,90.59) v2(126.24,96.54) v2(126.95,1.02) v2(127.43,92.75) v2(127.51,98.04) v2(127.46,94.76) v2(127.81,66.07) v2(128.16,96.45) v2(129.16,14.37) v2(129.49,1.02) v2(129.92,108.98) v2(129.9,96.08) v2(129.92,14.37) v2(129.97,92.19) v2(130.68,94.16) v2(132.03,1.02) v2(132.08,108.98) v2(132.08,28.59) v2(132.33,23.39) v2(132.72,28.59) v2(133.22,107.33) v2(133.6,101.87) v2(134.11,28.09) v2(134.24,101.87) v2(134.17,90.73) v2(134.46,109.14) v2(134.75,28.09) v2(134.84,90.78) v2(134.97,1.02) v2(135.55,90.96) v2(136.19,56.34) v2(136.37,12.46) v2(137.01,12.46) v2(139.6,0.76) v2(140.16,12.49) v2(140.72,29.86) v2(140.79,12.49) v2(141.6,29.89) v2(143.89,75.46) v2(143.89,73.3) v2(144.68,0.76) v2(145.47,103.66) v2(145.54,102.89) v2(145.54,102.25) v2(146.69,102.38) v2(147.45,31.01) v2(147.57,102.38) v2(147.83,68.34) v2(147.83,67.71) v2(148.08,31.01) v2(148.23,42.82) v2(148.92,42.82) v2(149.94,1.02) v2(149.99,39.39) v2(150.88,95.01) v2(151.38,102.63) v2(151.51,95.01) v2(152.27,95.01) v2(152.35,1.02) v2(153.42,98.82) v2(154.89,1.02) v2(156.29,109.14) v2(156.49,49.29) v2(156.84,26.82) v2(156.84,25.16) v2(157.43,1.02) v2(157.48,26.82) v2(158.12,54.67) v2(158.74,47.26) v2(159.89,47.14) v2(159.97,1.02) v2(162.18,47.9) v2(162.27,60.58) v2(162.27,59.82) v2(162.27,58.3) v2(162.27,57.54) v2(162.51,1.02) v2(164.72,100.86) v2(165.05,1.02) v2(165.61,65.3) v2(165.61,64.66) v2(166.65,96.12) v2(167.5,65.41) v2(167.59,1.02) v2(167.89,49.17) v2(170.69,77.72) v2(170.69,76.85) v2(171.45,60.47) v2(171.45,5.35) v2(172.09,5.35) v2(172.32,3.43) v2(172.72,35.2) v2(172.97,60.47) v2(173.23,24.4) v2(173.56,0.97) v2(174.12,80.03) v2(174.62,44.72) v2(175.21,1.02) v2(175.39,39.01) v2(175.39,37.86) v2(175.39,36.72) v2(175.39,35.58) v2(175.39,34.18) v2(175.9,75.33) v2(175.9,67.07) v2(177.16,67.07) v2(177.72,1.02) v2(177.93,60.85) v2(179.22,50.49) v2(179.43,33.67) v2(179.37,29.1) v2(179.45,29.89) v2(180.29,31.49) v2(180.42,64.01) v2(180.37,32.37) v2(180.78,2.29) v2(180.75,1.07) v2(181.41,61.56) v2(181.41,34.23) v2(181.43,31.82) v2(182.88,31.82) v2(183.34,56.8) v2(184,55.15) v2(184.56,31.74) v2(184.95,52.81) v2(185.6,29.52) v2(186.08,31.74) v2(186.45,49.56) v2(186.44,34.05) v2(187.2,34.18) v2(188.09,34.31) v2(188.14,29.52) v2(188.47,46.25) v2(190.5,44.01) v2(190.68,29.52) v2(191.63,32.9) v2(191.63,30.36) v2(191.85,40.1) v2(191.85,37.99) v2(191.85,35.43) v2(191.87,41.83) v3(25.78,82.01) v3(25.78,81.17) v3(26.67,82.01) v3(26.67,81.17) v3(27.94,73.81) v3(28.83,73.81) v3(40.39,55.64) v3(40.39,54.76) v3(40.39,53.87) v3(40.39,52.98) v3(41.27,55.64) v3(41.27,54.76) v3(41.27,53.87) v3(41.27,52.98) v3(43.18,54.37) v3(43.18,53.49) v3(43.18,52.6) v3(46.86,65.17) v3(46.86,64.28) v3(47.75,65.17) v3(47.75,64.28) v3(48.64,65.17) v3(48.64,64.28) v3(49.53,65.17) v3(49.53,64.28) v3(50.42,65.17) v3(50.42,64.28) v3(56.52,53.23) v3(57.53,53.87) v3(57.47,19.84) v3(57.78,21.48) v3(58.62,21.48) v3(59.46,21.48) v3(60.33,21.74) v3(60.33,20.85) v3(60.58,65.04) v3(61.09,76.47) v3(61.21,87.39) v3(61.21,86.51) v3(61.21,85.62) v3(61.21,66.82) v3(61.21,65.93) v3(61.21,20.59) v3(61.47,65.04) v3(61.72,78.25) v3(61.72,77.36) v3(61.98,76.47) v3(62.1,87.39) v3(62.1,86.51) v3(62.1,85.62) v3(62.1,66.82) v3(62.1,65.93) v3(62.36,65.04) v3(62.61,78.25) v3(62.61,77.36) v3(62.87,76.47) v3(62.99,87.39) v3(62.99,86.51) v3(62.99,85.62) v3(62.99,66.82) v3(62.99,65.93) v3(63.25,65.04) v3(63.5,78.25) v3(63.5,77.36) v3(63.75,76.47) v3(63.88,87.39) v3(63.88,86.51) v3(63.88,85.62) v3(63.88,66.82) v3(63.88,65.93) v3(64.14,65.04) v3(64.39,78.25) v3(64.39,77.36) v3(64.64,76.47) v3(64.77,87.39) v3(64.77,86.51) v3(64.77,85.62) v3(65.02,65.04) v3(65.28,78.25) v3(65.28,77.36) v3(65.91,65.04) v3(66.67,75.96) v3(66.8,78.63) v3(66.8,77.74) v3(66.8,76.85) v3(67.33,86.27) v3(67.44,87.14) v3(72.36,74.06) v3(72.38,73.22) v3(72.38,72.38) v3(72.52,87.14) v3(73.15,74.69) v3(74.04,74.69) v3(75.95,87.14) v3(76.33,59.71) v3(76.33,58.82) v3(78.74,18.18) v3(79.63,18.18) v3(79.76,62.25) v3(80.39,62.88) v3(107.16,75.67) v3(117.22,18.43) v3(128.78,21.35) v3(129.67,22.12) v3(129.67,21.23) v3(129.67,20.34) v3(130.56,22.12) v3(130.56,21.23) v3(131.57,22.12) v3(139.88,24.4) v3(140.72,27.07) v3(140.72,26.18) v3(140.72,25.29) v3(140.72,24.4) v3(145.29,12.72) v3(146.18,12.72) v3(147.04,12.72) v3(147.96,12.71) v3(148.84,12.72) v3(154.46,30.75) v3(155.35,30.75) v3(156.18,30.72) v3(157.61,26.05) v3(157.61,25.16) v3(157.61,24.28) v3(165.35,13.86) v3(165.86,12.97) v3(166.24,13.73) v3(166.38,14.56) v3(166.96,15.22) v3(167.5,64.41) v3(167.5,63.14) v3(167.5,61.87) v3(167.61,15.75) v3(168.4,16.91) v3(168.4,16.02) v3(170.94,50.44) v3(171.42,58.31) v3(172.21,57.6) v3(172.21,50.81) v3(173.1,59.45) v3(173.1,58.57) v3(173.1,57.68) v3(173.43,50.84)
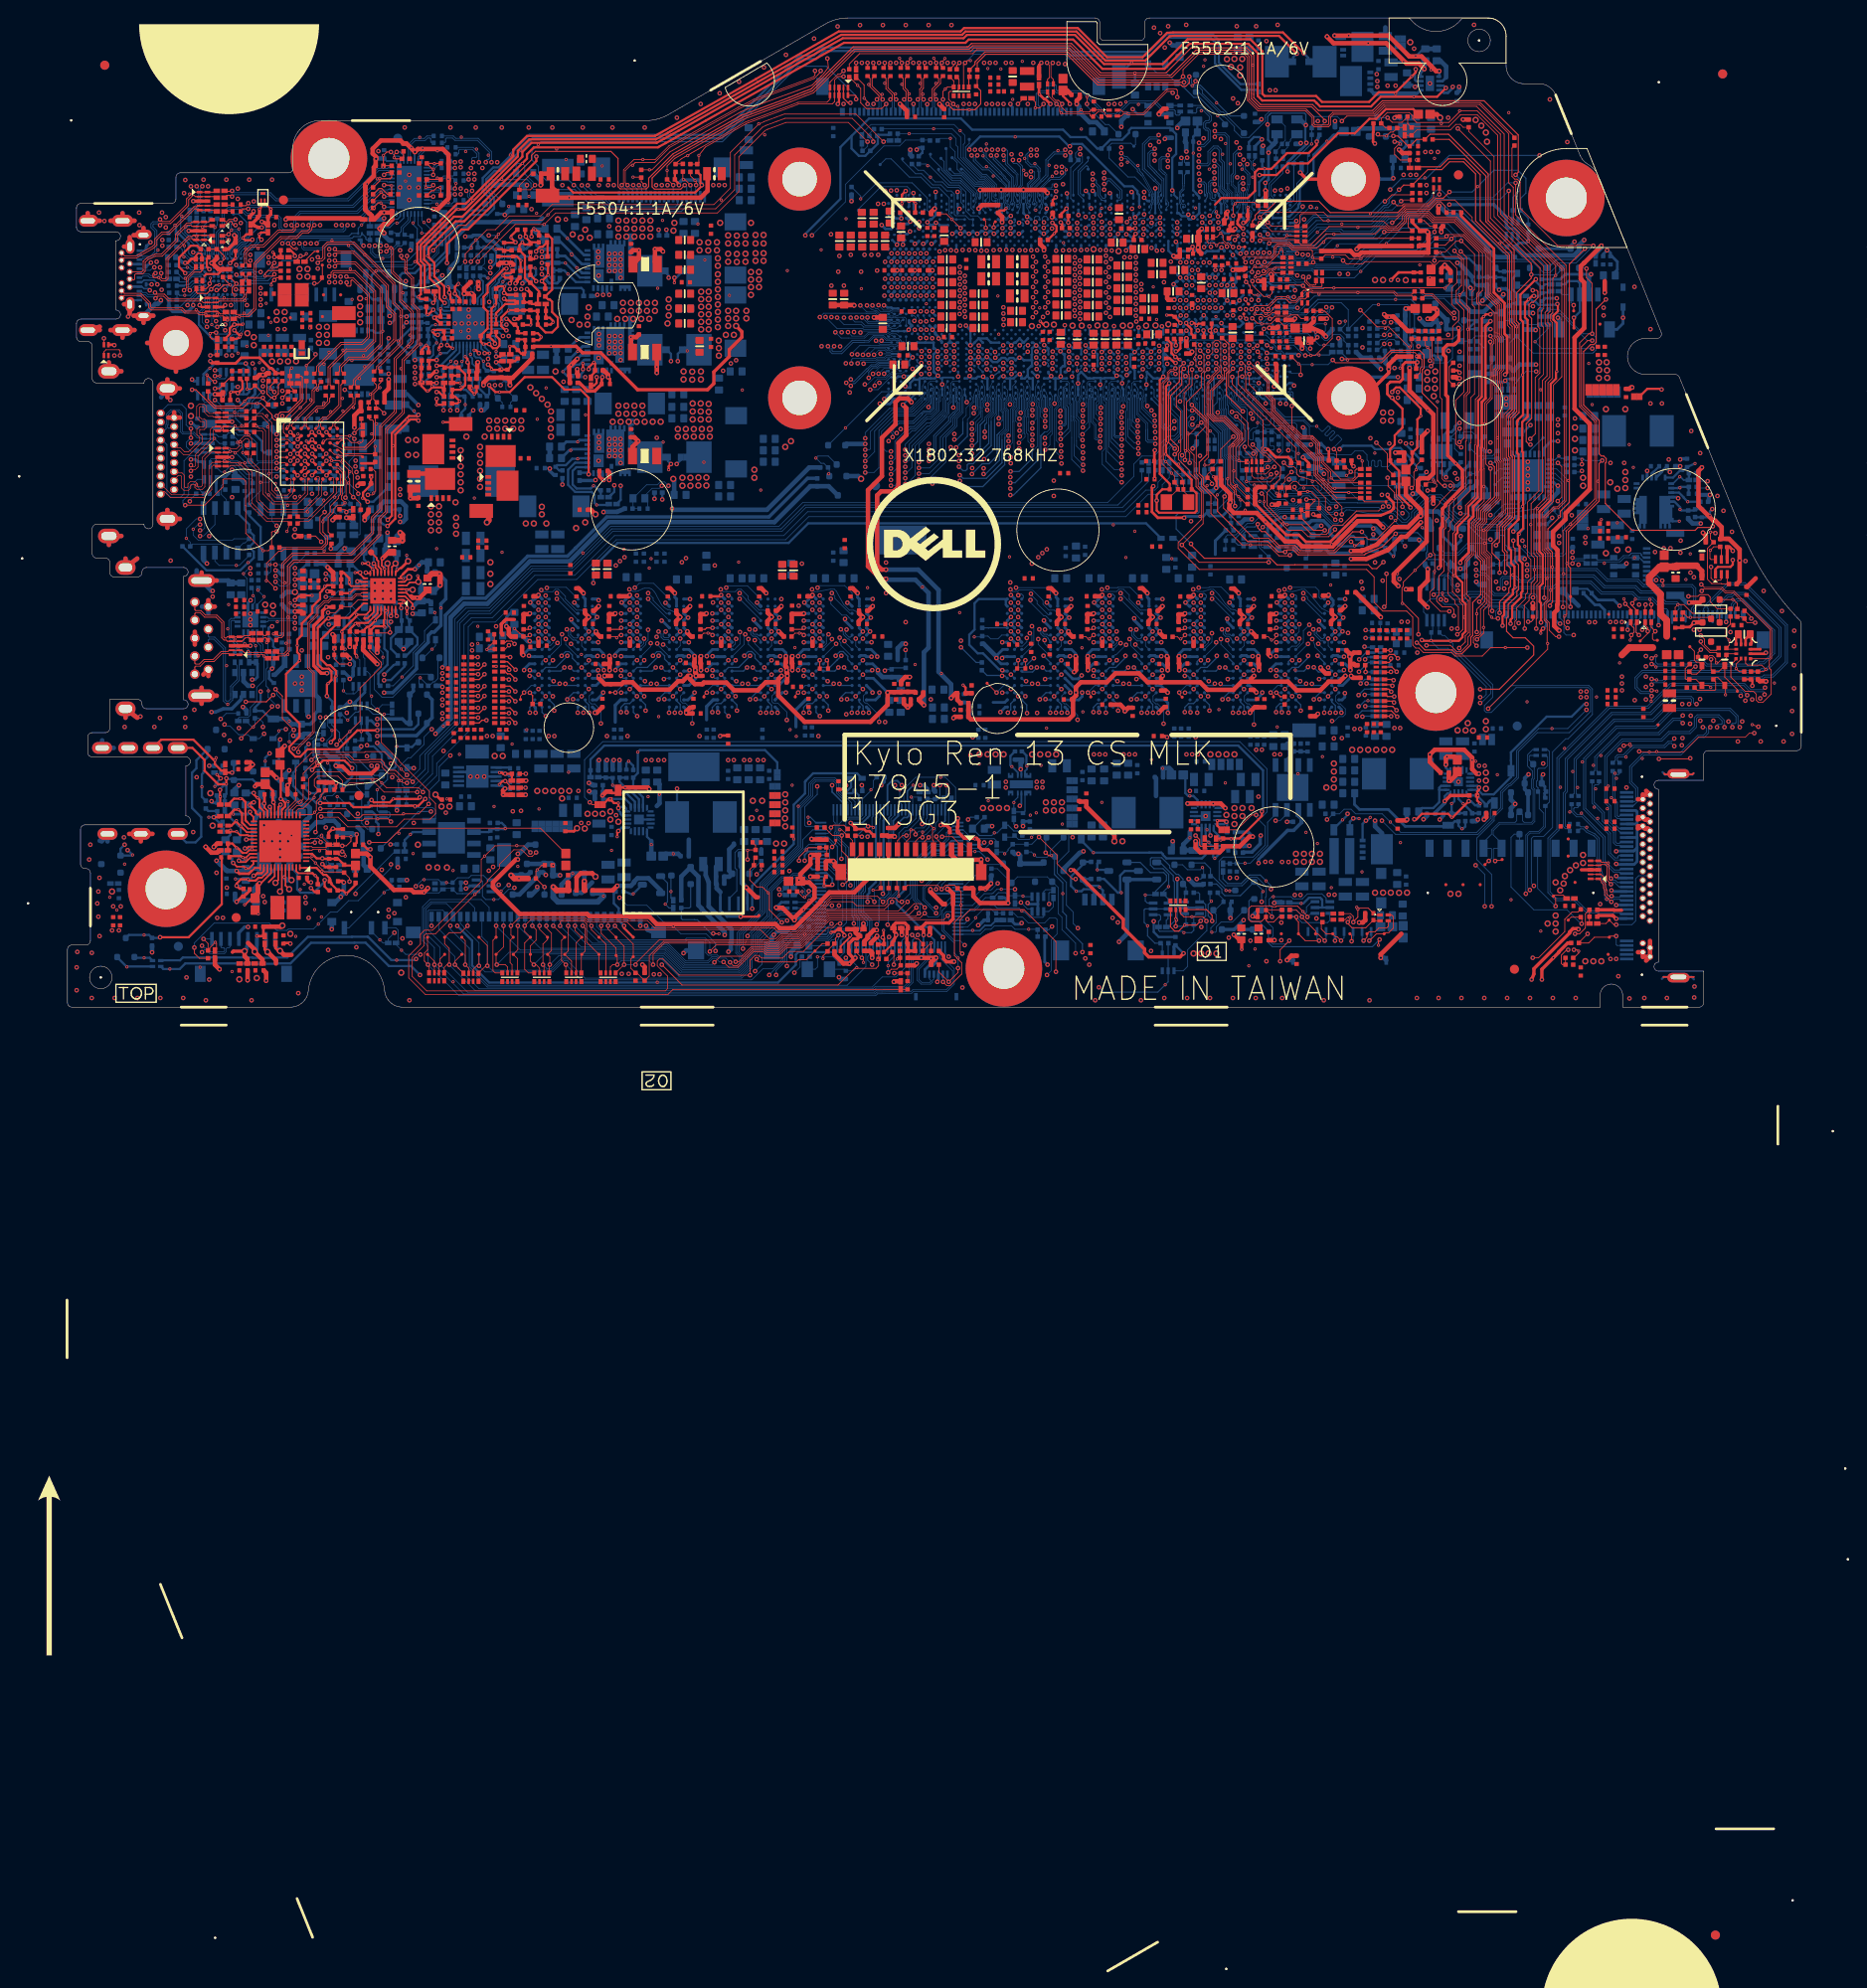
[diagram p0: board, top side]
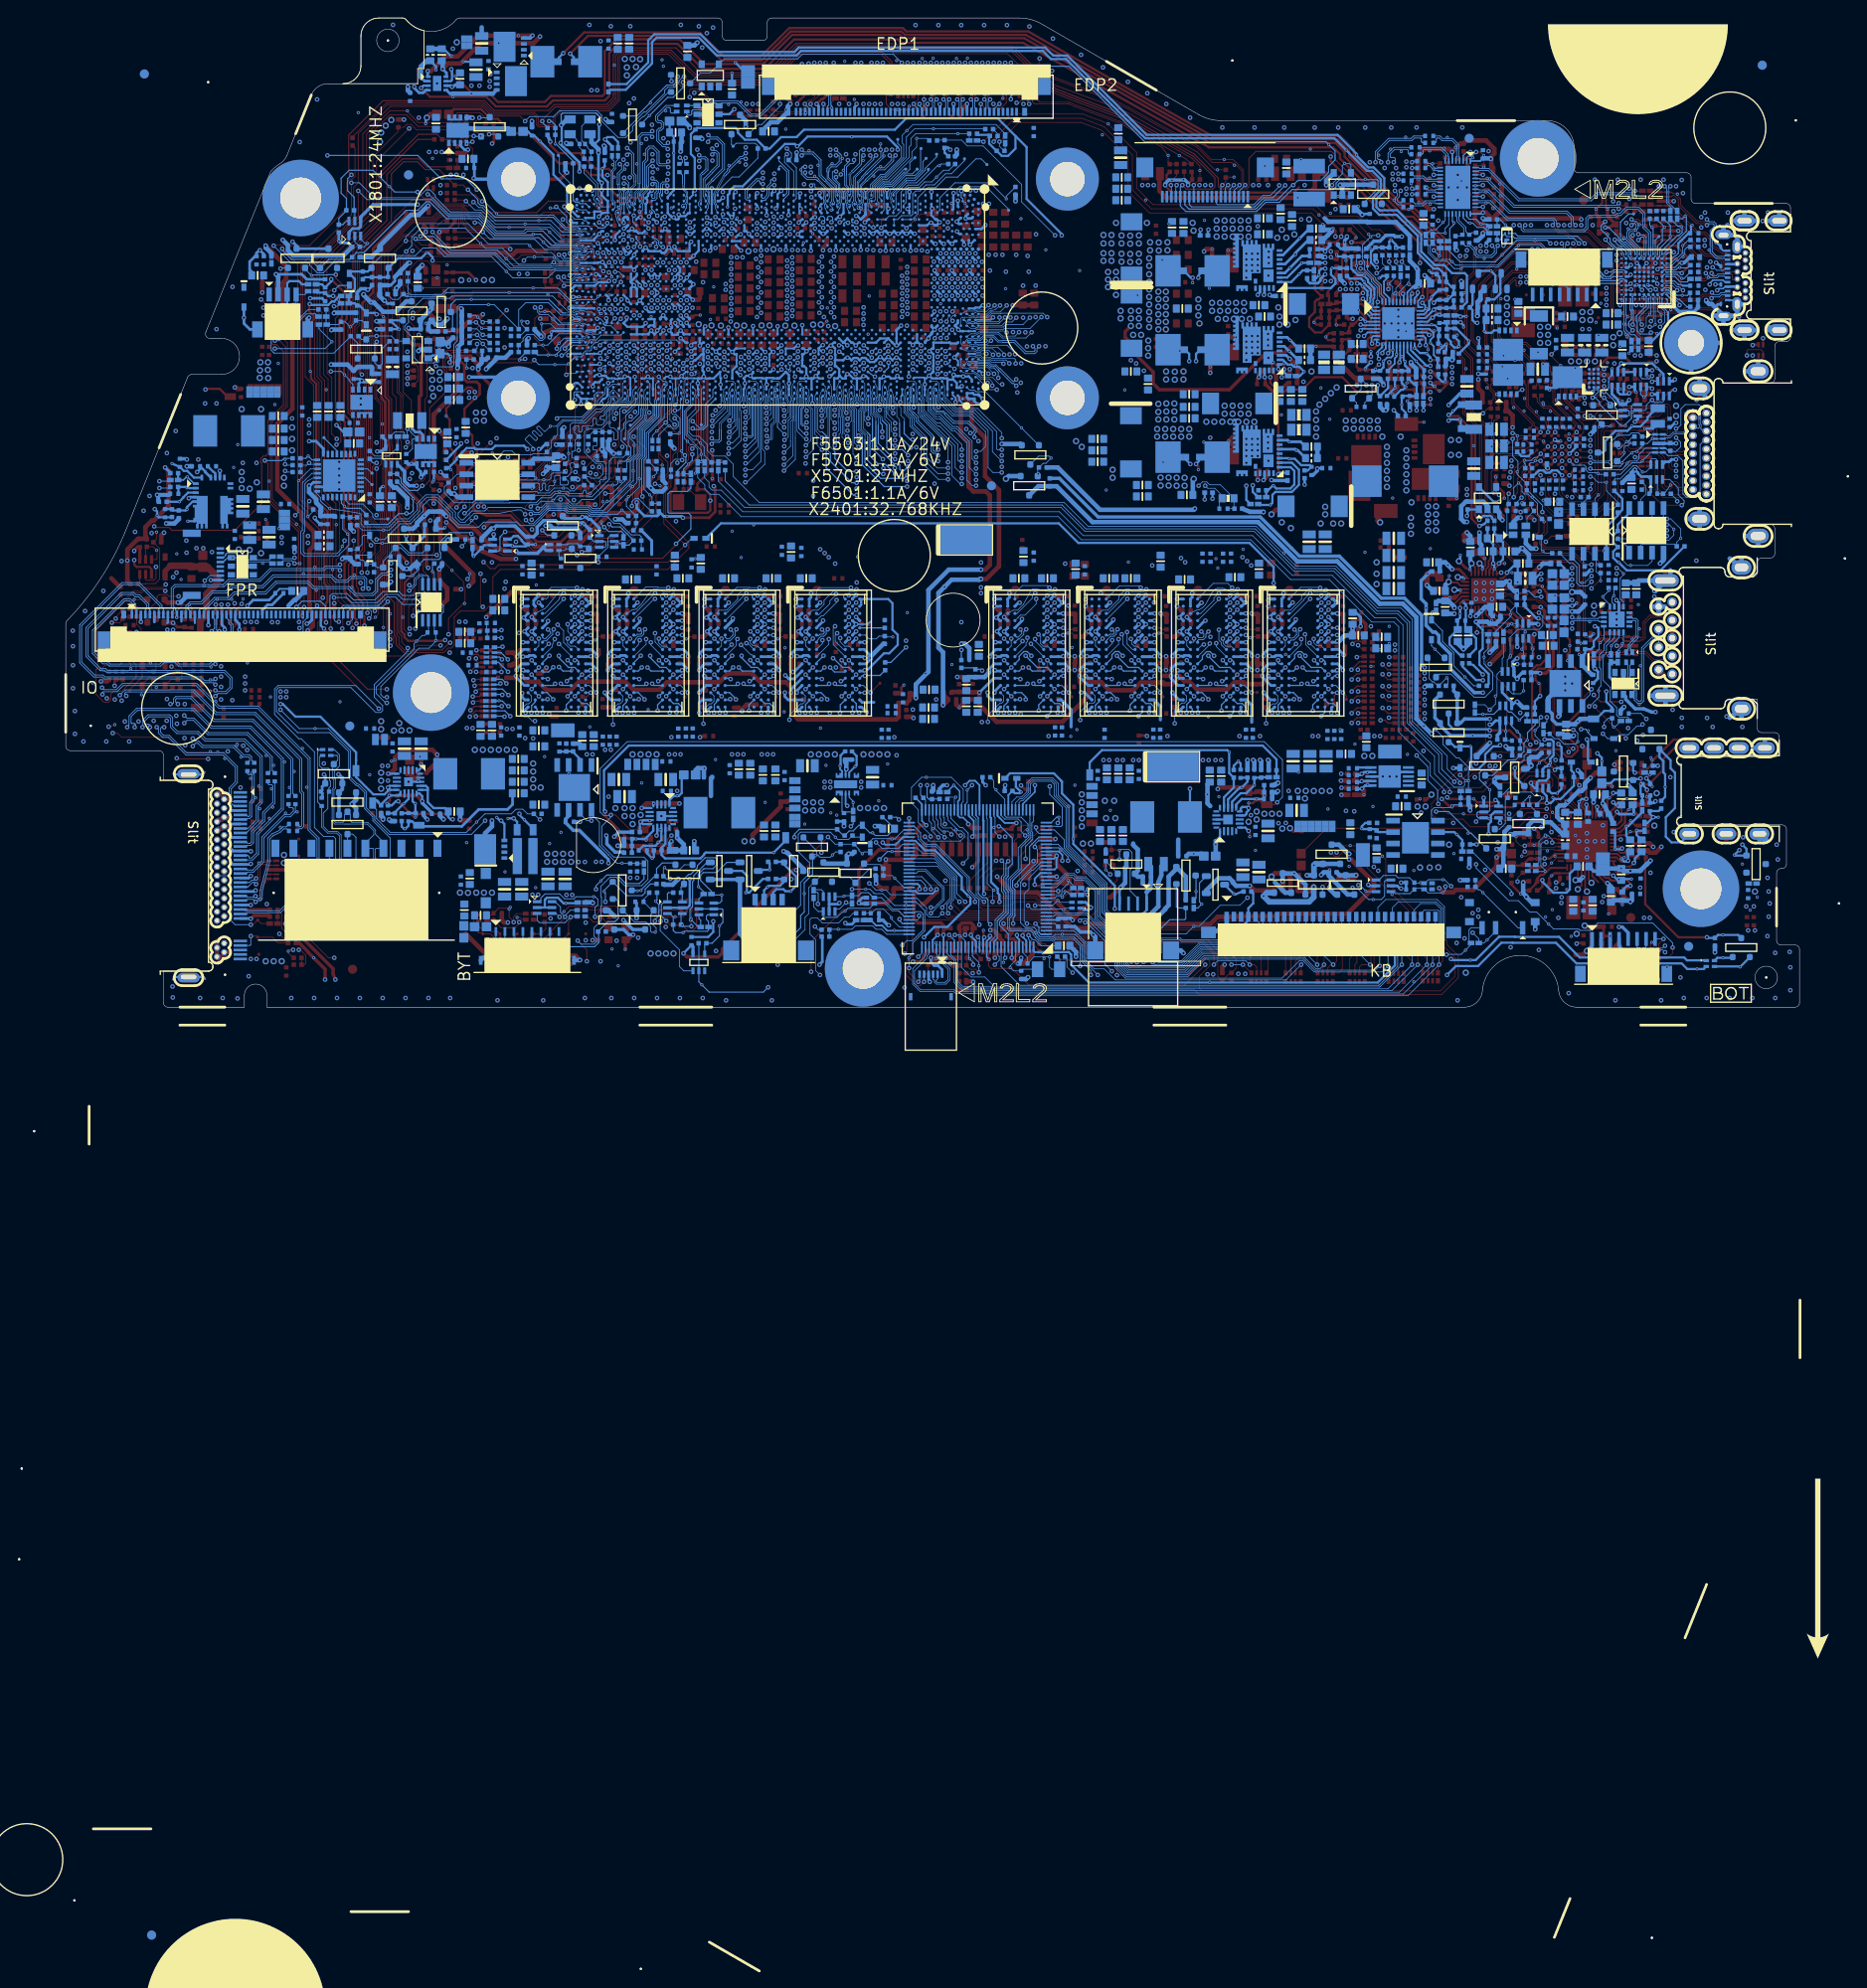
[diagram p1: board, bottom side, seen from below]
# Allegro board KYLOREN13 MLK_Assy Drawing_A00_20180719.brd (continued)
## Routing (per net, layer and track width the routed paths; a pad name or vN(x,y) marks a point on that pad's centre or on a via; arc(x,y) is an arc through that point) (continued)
V0.85A_VID0: length 3.8
  BOTTOM w0.102: CPU1.CB36 128.65,67.7 128.67,67.67 128.67,66.52 128.74,66.45 128.74,65.72 129.79,64.66 TP2201.1
V0.85A_VID1: length 6.4
  BOTTOM w0.076: CPU1.CB35 128.88,68.34 128.88,68.12 128.91,68.01 128.92,68 128.92,67.82 128.86,67.66 128.86,66.93
  BOTTOM w0.102: TP2202.1 130.45,63.25 130.45,64.77 130.09,65.13 129.8,65.13 128.98,65.94 128.98,66.81 128.86,66.93
VBUS_P_CTRL: length 13.8
  TOP w0.127: v1(16.92,70.12) v2(16.38,70.12)
  L4SGND w0.127: v2(16.38,70.12) 16.83,70.57 16.83,73.74 16.07,74.5 16.07,78.25 v2(17.5,79.69)
  BOTTOM w0.127: Q7404.2 17.65,70 17.48,69.82 16.69,69.82 v2(16.38,70.12) ; U7201.D7 17.77,79.96 v2(17.5,79.69)
VBUS_P_CTRL_R: length 5.7
  TOP w0.127: v2(16.38,68.73) 16.84,68.73 R7408.1 17.93,69.82 R7423.2
  BOTTOM w0.127: 17.27,67.84 17.4,67.84 17.65,68.09 Q7404.5 ; 17.27,67.84 v1(17.27,67.8) ; 17.27,67.84 17.14,67.84 17,67.98 Q7404.6 16.57,68.92 v2(16.38,68.73)
VCCCORE_SENSE: length 76.2
  TOP w0.254: R719.2 110.51,87.05 v2(110.37,87.19) ; PR4665.1 48.09,72.29 v2(47.62,72.29)
  L6 w0.254: v2(110.37,87.19) 110.37,86.63 109.75,86.02 109.5,86.02 108.87,85.4 97.66,85.4 97.38,85.67 91.33,85.67 90.37,84.71 85.59,84.71 71.25,70.37 71.25,69.14 70.33,68.22 55.57,68.22 51.63,72.16 47.75,72.16 v2(47.62,72.29)
  BOTTOM w0.254: CPU1.AN6 110.69,86.87 v2(110.37,87.19) ; v1(47.62,72.85) v2(47.62,72.29)
VCCDSW_ON: length 158.9
  TOP w0.102: v2(154.64,39.9) 155.32,40.57 155.32,41.26 155.66,41.61 155.66,45.14 155.3,45.51 155.3,49.61 155.4,49.72 155.4,49.73 156.03,50.36 156.03,53.82 156.59,54.37 156.59,55.41 157.42,56.24 157.42,59.82 157.4,59.84 157.4,62 157.48,62.08 157.48,67.09 158.11,67.72 158.11,70.01 158.1,70.01 158.1,73.63 158.09,73.64 v2(158.09,73.93)
  L6 w0.102: v2(158.24,11.19) 156.67,9.63 145.16,9.63 143.71,11.08 135.57,11.08 134.52,12.12 133.44,12.12 133.43,12.13 133.23,12.13 132.99,12.38 131.8,12.38 131.25,11.83 129.78,11.83 129.53,12.08 127.5,12.08 127.38,12.21 108.08,12.21 107.19,13.1 v2(105.28,13.1)
  BOTTOM w0.102: v2(158.09,73.93) 158.31,73.71 D2503.2 158.31,71.59 157.86,71.14 C2525.1 157.52,71.41 arc(157.49,71.45) 157.48,71.5 157.48,73.17 R2520.2 ; v2(105.28,13.1) v1(103.76,13.1) 103.27,13.1 102.87,12.7 102.86,12.69 102.73,12.6 101.87,12.6 100.56,11.29 U2401.88 ; v2(158.24,11.19) 158.24,14.75 156.59,16.4 156.59,18.78 158.52,20.71 158.52,21.13 159.44,22.04 159.44,23.83 160.17,24.56 160.42,24.67 161.21,25.46 161.21,28.39 163.32,30.5 166.88,30.5 169.23,32.85 169.23,35.26 168.97,35.51 160.97,35.51 158.2,32.75 157.65,32.75 157.44,32.95 157.44,33.51 158.37,34.44 158.37,35.83 154.64,39.56 v2(154.64,39.9)
VCCGT_SENSE: length 77.8
  TOP w0.254: v2(93.52,89.61) 93.93,89.61 v1(94.23,89.3) 94.23,89.29 94.23,88.33 R807.2
  L6 w0.254: v2(42.55,66.31) 42.04,66.82 40.51,66.82 40.01,67.33 40.01,78.33 43.69,82.02 43.69,83.03 43.99,83.33 45.71,83.33 47.75,85.37 47.75,85.93 49.39,87.57 52.4,87.57 54.33,89.5 77.37,89.5 78.89,87.97 87.03,87.97 88.9,89.84 93.28,89.84 v2(93.52,89.61)
  BOTTOM w0.254: v2(93.52,89.61) 93.52,88.96 CPU1.E3 ; v2(42.55,66.31) PR4667.2
VCCPD_VBUS_ACK: length 53.2
  TOP w0.127: v2(22.99,68.34) 22.91,68.34 v1(22.56,68.7) 22.56,69 R7424.2
  L6 w0.127: v2(33.27,27.88) 33.27,27.96 33.95,28.63 33.95,29.57 32.4,31.12 27.64,31.12 27.6,31.16 27.2,31.16 24.77,33.59 24.77,38.12 20.79,42.09 20.79,49.84 20.59,50.04 20.59,65.95 v2(22.99,68.34)
  BOTTOM w0.127: v2(22.99,68.34) 22.86,68.47 U7419.A2 ; v2(33.27,27.88) 33.32,27.88 33.33,27.88 PQ4417.G
VCCRTCEXT: length 2.4
  TOP w0.254: v2(123.67,76.02) 123.03,76.66 C2201.1 122.71,76.88 122.71,76.89 v1(122.14,76.89)
  BOTTOM w0.254: CPU1.BP24 123.34,75.69 v2(123.67,76.02)
VCCSA_SENSE: length 103
  TOP w0.254: v2(118.69,85.91) 118.62,85.85 118.62,85.81 118.48,85.67 R810.2
  L4SGND w0.254: v2(37.67,76.09) 37.8,76.22 38.38,76.22 40.13,77.97 40.13,78.76 40.64,79.27 40.97,79.27 43.26,81.55 45.73,81.55 46.48,82.3 46.48,83.03 48.01,84.56 48.01,85.98 49.14,87.11 51.9,87.11 52.81,88.03 53.96,88.03 54.44,88.51 69.57,88.51 70.54,89.48 73.47,89.48 74.65,90.66 74.65,90.91 80,96.26 86.18,96.26 87.17,95.27 92.05,95.27 93.09,96.31 114.06,96.31 116.08,94.29 116.08,93.41 116.76,92.73 116.76,86.81 117.21,86.36 118.05,86.36 118.5,85.91 118.62,85.91 118.62,85.91 v2(118.69,85.91)
  BOTTOM w0.254: PR4601.2 v2(37.67,76.09) 37.34,75.76 v1(37.34,75.56) ; v2(118.69,85.91) 118.79,85.91 CPU1.BG7
VCCST_PWRGD: length 127.9
  TOP w0.254: v2(158.12,76.98) 157.61,76.98 v1(157.35,76.73) 157.15,76.53 157.15,67.81 156.74,67.4 156.74,62.38 156.67,62.31 156.67,59.53 156.68,59.52 156.68,56.65 155.65,55.62 155.65,54.58 154.46,53.38 154.46,52.7 154.25,52.5 154.25,47.91 154.99,47.18 154.99,45.15 155.36,44.78 155.36,41.75 155,41.4 155,41.1 154.6,40.7 150.58,40.7 v2(150.5,40.79)
  L4SGND w0.254: v2(92.71,24.66) 95.3,27.25 111.3,27.25 113.53,29.48 125.56,29.48 126.02,29.94 139.65,29.94 140.23,30.52 142.21,30.52 142.62,30.12 147.98,30.12 148.23,30.12 148.82,30.7 148.82,31.31 148.65,31.48 148.65,36.88 150.5,38.73 v2(150.5,40.79)
  BOTTOM w0.203: v2(92.71,24.66) 92.21,25.15 91.61,25.15 91.11,24.66 U2401.48
  BOTTOM w0.254: ED1704.1 159.09,81.73 R1716.1 160.93,81.73 D4003.A 160.53,80.92 160.53,79.77 161.19,79.11 R4011.2 R4002.1 160.53,78.2 R4005.2 159.99,77.95 159.26,77.21 D4002.A 158.27,77.13 v2(158.12,76.98)
VCCST_PWRGD_R: length 50.7
  L4SGND w0.254: v2(119.63,89.93) 120.62,88.94 121.64,88.94 122.68,87.9 122.68,84.83 123.93,83.58 128.73,83.58 129.24,83.08 130.55,83.08 130.73,83.26 133.93,83.26 136.54,80.65 142.19,80.65 145.38,83.84 151.13,83.84 151.89,83.08 v2(151.89,82.95)
  BOTTOM w0.254: R1716.2 159.41,81.09 R1718.2 R1719.1 156.87,81.09 C1711.1 156.84,82.07 ED1704.2 155.71,83.2 153.16,83.2 v1(152.53,83.84) 152.4,83.84 151.89,83.33 v2(151.89,82.95) ; v2(119.63,89.93) 120,89.56 CPU1.BJ2
VCCSTG_EN_L1: length 4.9
  BOTTOM w0.102: R4018.2 158.32,61.23 156.75,61.23 U4008.4 155.75,62.22 R4039.1
VCCSTG_EN_R1: length 24.9
  L4SGND w0.102: v2(163.19,70.63) 163.3,70.53 163.3,66.13 161.93,64.76 155.8,64.76 155.32,64.28 v2(154.69,64.28)
  BOTTOM w0.102: U4003.4 160.74,69.19 161.16,69.61 161.16,69.74 v1(161.67,70.25) 162.05,70.63 v2(163.19,70.63) ; 156.59,63.39 156.08,63.9 155.12,63.9 155.02,63.8 155.02,63.52 R4039.2 154.71,63.57 154.71,64.25 v2(154.69,64.28) 153.63,63.22 U4002.4 154.03,63.15 154.13,63.05 154.13,62.05 154.72,61.46 C4040.1
VCCSTU_EN_R: length 5.8
  TOP w0.102: v2(147.46,96.16) 147.83,96.16 v1(148.08,95.9) 147.96,95.9 147.46,95.41 147.46,94.75 148.08,94.13 C4034.1 149.15,93.26 R4024.2
  BOTTOM w0.102: U4006.4 147.6,96.02 v2(147.46,96.16)
VDD: length 164.7
  TOP w0.203: PU4401.18 32.64,47.25 32.54,47.34 32.25,47.34 v2(32.21,47.3)
  TOP w0.254: v2(42.17,82.69) 42.17,84.79 43.79,86.4 44.5,86.4 52.1,94 v2(52.1,94.51)
  L4SGND w0.254: v2(118.36,99.76) 116.66,101.47 85.57,101.47 84.94,100.84 78.31,100.84 72.12,94.64 52.23,94.64 v2(52.1,94.51) ; v2(42.17,82.69) 36.53,77.04 36.53,66.16 35.22,64.85 35.22,55.33 34.42,54.53 34.42,52.14 31.5,49.21 31.5,47.77 31.96,47.3 v2(32.21,47.3)
  L6 w0.508: v2(35.18,34.94) 35.94,35.71 35.94,39.39 32.38,42.94 32.38,47.13 v2(32.21,47.3)
  BOTTOM w0.254: v2(118.36,99.76) 118.92,99.21 ED5501.5
  BOTTOM w0.381: v2(35.18,34.94) 36.13,34.94 38.79,37.6 38.79,39.23 40.08,40.53 40.08,41.29 40.46,41.67 40.75,41.67 41.49,42.41 v1(41.49,44.34) 41.49,44.81 42.04,45.36 42.04,47.39 41.02,48.41 PR4405.2
  BOTTOM w0.508: PC4422.1 32.87,47.03 32.6,47.3 v2(32.21,47.3) 32.21,46.75 31.7,46.25 PR4427.1 PR4429.1
VDDQ_EN: length 4
  BOTTOM w0.254: PG5112.2 158.17,22.98 158.14,22.95 158.06,22.95 157.91,22.81 157.91,22.73 PR5105.1 157.61,22.52 156.72,23.41 v1(156.72,23.51) 155.69,23.51 PU5101.11
VDDQ_PWRGD: length 66.1
  TOP w0.254: v2(163.73,42.74) 163.73,44.89 163.58,45.04 163.58,46.73 163.92,47.07 163.92,50.27 163.55,50.64 163.55,55.06 164.81,56.32 164.81,69.24 165.39,69.83 165.39,70.54 v1(165.48,70.63) 165.48,76.01 165.1,76.39 165.1,76.81 165.61,77.32 165.61,78.06 v2(165.54,78.13)
  L6 w0.254: v2(168.78,33.67) 167.89,33.67 167.16,34.41 167.16,37.31 162.69,41.77 162.69,42.26 163.17,42.74 v2(163.73,42.74)
  BOTTOM w0.254: PG5114.1 160.4,27.39 160.39,27.41 160.39,28.3 164.36,32.28 167.13,32.28 168.53,33.67 v2(168.78,33.67) ; v2(165.54,78.13) 165.44,78.02 163.47,78.02 163.09,78.4 162.83,78.4 162.22,79.01 R4011.1
VSSCORE_SENSE: length 77.4
  TOP w0.254: R720.1 111.2,87.89 v2(111.2,87.17) ; PR4666.1 48.29,71.72 47.69,71.72 v2(47.62,71.66)
  L6 w0.254: v2(111.2,87.17) 110.79,86.77 110.79,86.51 109.91,85.64 109.65,85.64 109.03,85.01 97.5,85.01 97.22,85.29 91.49,85.29 90.52,84.33 85.74,84.33 71.63,70.21 71.63,68.98 70.48,67.84 55.42,67.84 51.47,71.78 47.75,71.78 v2(47.62,71.66)
  BOTTOM w0.254: v1(48.26,70.91) 48.26,71.02 v2(47.62,71.66) ; v2(111.2,87.17) 110.85,87.52 CPU1.AN5
VSSGT_SENSE: length 79.2
  TOP w0.254: R808.1 92.71,88.46 v1(92.71,89.3) 92.71,90.25 v2(93.13,90.68)
  L6 w0.254: v2(41.78,66.31) 41.66,66.44 40.36,66.44 39.62,67.17 39.62,78.49 43.31,82.17 43.31,83.19 43.83,83.71 45.55,83.71 47.37,85.53 47.37,86.09 49.23,87.95 52.24,87.95 54.17,89.88 54.49,89.88 54.49,89.88 77.53,89.88 79.05,88.35 86.87,88.35 88.74,90.22 92.68,90.22 v2(93.13,90.68)
  BOTTOM w0.127: CPU1.D2 92.97,89.81 93.15,89.99 93.15,90.66 v2(93.13,90.68)
  BOTTOM w0.254: v2(41.78,66.31) PR4668.2
VSSSA_SENSE: length 102.9
  TOP w0.254: R809.1 118.61,86.51 118.62,86.53 v2(118.65,86.53)
  L4SGND w0.254: v2(37.67,76.73) 37.8,76.6 38.22,76.6 39.75,78.13 39.75,78.92 40.48,79.65 40.82,79.65 43.1,81.93 45.57,81.93 46.1,82.46 46.1,83.19 47.62,84.71 47.62,86.14 48.98,87.5 51.74,87.5 52.66,88.41 53.8,88.41 54.28,88.89 69.41,88.89 70.38,89.86 73.31,89.86 74.27,90.82 74.27,91.07 79.84,96.64 86.34,96.64 87.33,95.65 91.89,95.65 92.93,96.69 114.22,96.69 116.46,94.45 116.46,93.57 117.14,92.89 117.14,86.97 117.37,86.74 118.21,86.74 118.41,86.54 118.43,86.53 v2(118.65,86.53)
  BOTTOM w0.254: v1(37.03,76.75) 37.64,76.75 v2(37.67,76.73) 37.8,76.85 PR4602.2 ; CPU1.BE7 118.46,86.51 118.61,86.51 118.62,86.53 v2(118.65,86.53)
0D6V_PWR:
  vias: v1(43.56,28.09)
0D6V_VREF_S0:
  vias: v1(45.59,42.31) v1(45.59,40.4) v1(49.4,29.23) v1(51.03,30.83) v1(80.29,30.83) v1(108.79,31.01) v1(134.42,31.13) v1(144.5,34.05) v2(44.96,40.28) v2(44.96,39.64) v2(143,30.91) v2(143.64,30.91) v3(47.47,27.91) v3(48.36,27.91)
1D0V_PWR:
  vias: v1(169.42,66.95) v3(170.94,66.44) v3(173.1,66.44)
1D0V_S5: length 171.2
  L3SGND w0.381: v3(170.19,70.81) 170.13,70.81 169.82,70.5 169.77,70.5 168.43,69.16 168.43,62.02 169.16,61.28 169.16,56.71 171.92,53.95 178.06,53.95 179.19,52.82 179.19,51.89 v2(179.25,51.83)
  L4SGND w0.305: v2(106.02,9.34) 106.88,9.34 107.98,8.25 114.2,8.25 115.72,6.72 117.06,6.72 117.21,6.88 127.38,6.88 129.08,8.58 129.81,8.58 130.12,8.27 130.12,7.95 131.86,6.22 139.29,6.22 140.31,7.24 140.31,8.74 142.03,10.46 155.76,10.46 157.08,11.78 162.86,11.78 164.41,13.33 164.41,14.95 171.32,21.86 171.32,26.64 173.46,28.78 173.46,29.1 174.22,29.86 174.86,29.86 180.17,35.17 186.39,35.17 186.42,35.2 186.86,35.2 186.89,35.17 187.44,35.17 188.19,35.92 188.19,36.5 189.26,37.57 189.26,41.77 185.29,45.73 185.29,46.45 184.73,47 184.02,47 182.64,48.38 182.41,48.38 182.09,48.69 182.09,49.13 179.39,51.83 v2(179.25,51.83) ; 122.43,81.93 122.09,82.27 122.09,83.8 122.17,83.88 122.17,87.7 121.42,88.46 120.39,88.46 119.13,89.72 119.13,90.16 119.53,90.57 v2(119.63,90.57)
  BOTTOM w0.305: R2402.1 105.28,9.21 105.89,9.21 v2(106.02,9.34)
  BOTTOM w0.508: U4006.9 148.91,97.62 143.47,97.62 143.34,97.49 R2202.1 ; R2205.1 123.95,98.44 123.32,97.81 v2(123.32,97.68)
  vias: v1(125.6,82.7) v1(149.86,94.13) v1(152.22,67.28) v1(163.7,68.6) v1(169.04,71.52) v2(123.01,77.7) v2(123.64,78.54) v2(123.67,82.75) v2(124.31,82.76) v2(124.33,80.21) v2(124.34,79.37) v2(124.3,78.54) v2(124.96,82.75) v2(124.96,81.89) v2(124.96,80.19) v2(125.62,81.9) v2(125.6,78.54) v2(125.62,77.7) v2(126.23,78.54) v2(126.26,77.7) v2(126.89,80.21) v2(126.89,78.54) v2(126.92,77.7) v2(127.53,79.38) v2(127.54,78.54) v2(127.55,81.92) v2(127.58,80.21) v2(127.55,77.7) v2(128.23,81.91) v2(147.83,80.79) v2(148.46,92.47) v2(149.22,92.47) v2(149.86,92.47) v2(159.87,67.63) v2(159.87,66.95) v3(148.7,80.77) v3(151.1,70.53) v3(151.09,69.69) v3(151.11,68.75) v3(151.82,67.89) v3(151.92,69.7) v3(151.95,68.76) v3(151.99,70.63) v3(170.18,71.65) v3(170.15,69.89) v3(171.02,71.65) v3(171.07,70.76) v3(171.09,69.92)
1D0V_S5_EN: length 2.8
  BOTTOM w0.254: PC5215.1 180.14,57.78 PR5210.2 179.27,57.8 v1(179.17,57.7) 178.97,57.7 178.93,57.66 PU5201.2
1D0V_S5_PWRGD: length 34.6
  L4SGND w0.102: v2(169.42,73.17) 170.79,73.17 171.75,72.2 171.75,70.35 173.68,68.42 174.04,68.42 174.68,69.06 177.62,69.06 179.58,67.1 179.58,62.63 180.96,59.06 181.58,58.44 v2(182.25,58.44)
  BOTTOM w0.102: v2(182.25,58.44) 181.15,58.44 PR5209.1 ; v2(169.42,73.17) 163.83,73.17 v1(163.07,73.93) 164.52,75.38 R4029.1
1D0V_VCCA_XTAL: length 12.6
  BOTTOM w0.254: CPU1.CP5 135.78,87.84 136.77,88.83 136.77,89.15 136.93,89.31 136.93,90.98 138.46,92.5 138.46,94.71 v1(139.95,96.21) 140.59,96.84 C2219.1 141.3,97.3 R2202.2
1D0V_VCCAMPHYPLL: length 9
  BOTTOM w0.254: 125.09,94.88 C2209.1 125.09,96.72 C2208.1 125.55,98.44 R2205.2 ; 125.09,94.88 125.09,90.75 125.44,90.4 125.44,90.35 125.75,90.04 CPU1.BV2 ; 125.09,94.88 v1(125.09,94.89)
1D0V_VCCDSW: length 2.1
  TOP w0.254: v2(124.92,76.01) 125.2,76.01 125.43,75.79 v1(125.43,75.74) 125.48,75.74 125.68,75.94 C2213.1
  BOTTOM w0.254: v2(124.92,76.01) 124.91,76.01 124.91,75.85 124.66,75.59 CPU1.BT24
1D0V_VCCPRIM_MPHY:
  vias: v1(150.27,82.47) v1(151.38,81.04) v2(126.25,82.75) v2(126.89,82.73) v3(145.29,80.79) v3(146.18,80.79)
1D2V_HDMI: length 8.6
  TOP w0.508: v2(29.46,54.12) 29.79,54.45 R5706.2
  L4SGND w0.508: v2(29.46,54.12) 29.41,54.12 28.74,53.45 28.74,52.8 28.83,52.71 28.83,51.41 28.07,50.65 28.07,47.89 28.44,47.52 v2(28.7,47.52)
  vias: v1(28.57,46.75)
1D2V_HDMI_EN: length 37.5
  TOP w0.102: v2(23.11,46.53) 22.12,47.52 22.12,49.31 23.47,50.67 23.84,50.67 24.04,50.87 28.29,50.87 28.91,51.48 28.91,52.27 28.38,52.79 v1(28.38,53.93) 28.38,54.18 29.21,55.01 29.21,55.64 30.1,56.53 30.1,56.74 30.33,56.97 30.33,59.13 U5701.G8
  L6 w0.102: v2(28.08,32.2) 28.07,32.21 28.07,34.15 27.69,34.53 27.69,36.98 23.37,41.29 23.37,46.27 v2(23.11,46.53)
  BOTTOM w0.102: v2(28.08,32.2) 28.08,31.68 R5775.1
1D2V_HDMI_EN_R: length 13.7
  TOP w0.102: v2(25.15,30.8) 23.88,32.07 23.88,34.56 v2(23.11,35.32)
  BOTTOM w0.102: R5775.2 27.84,30.45 C5744.1 27.22,29.82 26.76,29.82 26.16,29.23 24.89,29.23 v1(24.64,29.48) 24.64,30.42 24.97,30.75 25.1,30.75 v2(25.15,30.8) ; v2(23.11,35.32) 23.26,35.17 23.26,34.74 24.13,33.88 U5704.8
1D2V_HDMI_FB:
  vias: v1(25.53,40.17)
1D2V_HDMI_R: length 0.6
  BOTTOM w0.254: v1(22.88,41.47) 23.19,41.17 23.37,41.17
1D2V_HDMI_VDD: length 22.1
  TOP w0.254: C5754.1 25.32,47.57 v2(25.27,47.52) ; v2(27.95,62.28) 27.98,62.28 U5701.D6 ; v2(27.19,60.72) 27.19,60.67 U5701.F5
  L6 w0.254: v2(27.95,62.28) 27.95,60.63 28.49,60.1 28.49,59.68 28.27,59.46 28.27,58.9 26.67,57.3 26.67,51.07 24.77,49.17 24.77,47.94 25.19,47.52 v2(25.27,47.52)
  BOTTOM w0.203: 30.1,61.23 29.77,61.56 C5756.1
  BOTTOM w0.254: 30.1,61.23 30.91,61.23 R5705.1 ; v2(25.27,47.52) 25.5,47.52 L5702.2
  vias: v1(28.45,62.88)
1D2V_HDMI_VDDA: length 21.4
  TOP w0.254: v2(25.27,45.23) 25.7,45.66 C5760.1 26.24,45.74 v1(27.18,45.74) ; U5701.F4 26.76,60.29 26.39,60.65 v2(26.39,60.68)
  L6 w0.254: v2(26.39,60.68) 27.69,59.38 27.69,58.85 26.29,57.45 26.29,51.3 24.38,49.39 24.38,46.12 v2(25.27,45.23)
  BOTTOM w0.254: L5703.2 25.88,45.23 v2(25.27,45.23)
1D2V_HDMI_VDDRX: length 21.7
  TOP w0.203: U5701.B4 27.16,63.86 v2(27.16,63.89)
  TOP w0.254: v2(27.16,63.89) 27.56,63.49 U5701.B5 ; v2(28.78,63.88) 29.17,63.49 U5701.B7
  L6 w0.254: v2(28.78,63.88) 29.29,63.37 29.29,58.4 27.08,56.18 27.08,49.83 25.4,48.15 v2(25.27,48.15)
  BOTTOM w0.254: v2(25.27,48.15) L5704.2 26.14,48.79 26.64,49.29 C5764.1
  vias: v1(25.61,63.67)
1D2V_HDMI_VDDTX: length 20.4
  TOP w0.254: U5701.G5 v2(27.18,59.09) ; C5772.1 25.35,44.67 v2(25.27,44.6) ; U5701.G7 v2(28.78,59.09)
  L6 w0.254: v2(25.27,44.6) 25.25,44.62 24.69,44.62 24,45.31 24,49.55 25.91,51.45 25.91,57.82 v2(27.18,59.09)
  BOTTOM w0.254: L5705.2 25.76,44.6 v2(25.27,44.6) 25.07,44.6 v1(24.77,44.9)
1D2V_HDMI_VIN: length 9.9
  BOTTOM w0.381: U5704.5 27.94,33.04 27.48,32.58 27.48,31.94 26.97,31.44 C5742.1
  BOTTOM w0.508: U5704.5 27.94,34.31 26.29,35.96 v2(26.04,35.96) ; G5701.1 24.38,32.02 v1(24.64,31.77) 24.97,31.44 C5742.1
  vias: v2(25.27,35.96) v2(26.04,36.72) v2(26.04,35.2)
1D2V_S3: length 188.7
  TOP w0.381: C1247.2 48.2,41.56 48.2,42.55 48.53,42.88 48.72,43.07 49.66,43.07
  TOP w0.508: R505.1 134.48,55.83 v2(133.83,55.83) ; R1222.1 92.63,36.22 93.08,36.68 v2(93.59,36.68) ; R1320.1 98.58,32.26 v2(98.45,32.12)
  L3SGND w0.508: 137.29,54.88 138.49,56.09 140.12,56.09 144.25,60.22 147.7,60.22 149.35,61.87 v2(149.35,62.63)
  L6 w0.254: v2(121.3,73.48) 121.4,73.48 122.2,72.69 v2(122.2,71.48) 122.24,71.43 122.24,69.85 121.96,69.57 121.56,69.57 121.06,70.07 v2(119.33,70.07)
  BOTTOM w0.09: CPU1.AD36 104.74,66.98 v2(104.72,66.96) ; CPU1.Y36 102.22,66.97 v2(102.21,66.96) ; CPU1.AH36 v2(107.26,66.99)
  BOTTOM w0.102: v2(114.83,66.61) 114.81,66.61 CPU1.AY36 ; CPU1.BH36 119.84,66.94 v2(119.99,66.79)
  BOTTOM w0.152: CPU1.AM36 109.68,67.91 v2(109.68,67.06)
  BOTTOM w0.203: CPU1.R32 v2(98.97,70.06)
  BOTTOM w0.254: CPU1.AH32 107.54,70.21 107.66,70.21 v2(107.79,70.08) ; RAM6.B9 104.27,44.7 104.27,45.18 RAM6.A9 101.25,45.34 100.79,44.87 100.79,41.95 100.2,41.37 100.2,40.25 101.14,39.31 101.73,39.31 103.5,37.53 103.78,37.53 v2(103.87,37.44) ; CPU1.AW32 114.3,70.58 v2(114.01,70.87) ; RAM5.B3 118.98,44.94 v2(118.98,44.94)
  BOTTOM w0.305: v2(125.13,41.75) 125.13,41.74 RAM8.F8 ; RAM7.R1 141.63,34.14 141.94,34.44 141.94,34.88 v2(141.94,34.88) ; v2(71.67,38.99) 71.72,38.94 RAM2.J9 ; RAM7.E7 136.1,42.52 136.09,42.52 v2(136.07,42.54) ; v2(52.01,32.71) 52.01,33.26 RAM4.T9 ; RAM8.E7 125.95,42.52 125.94,42.52 v2(125.92,42.54) ; RAM3.T9 62.08,32.81 v2(62.14,32.76) ; RAM7.D1 141.42,42.94 v2(141.76,43.28) 141.3,43.74 RAM7.C1 ; 111.23,43.36 110.85,43.74 RAM6.C1 ; 111.23,43.36 v2(111.31,43.28) ; 111.23,43.36 110.83,42.96 RAM6.D1 ; v2(141.97,45.34) RAM7.A1 ; RAM4.G1 v2(58.97,40.54) ; RAM8.B9 124.64,44.54 v2(124.23,44.96) 124.35,44.96 RAM8.A9 ; RAM3.L9 61.62,37.34 v2(61.52,37.44) ; RAM7.D9 v2(134.32,42.94) ; RAM3.L1 69.01,37.34 v2(69.12,37.44) ; v2(58.9,39.01) 58.82,38.94 RAM4.J1 58.2,39.07 57.66,39.07 RAM4.J2 ; RAM6.G9 v2(103.87,40.54) ; RAM5.C1 121,43.74 121.38,43.36 ; RAM7.L9 134.42,37.34 v2(134.32,37.44) ; RAM6.L9 103.97,37.34 v2(103.87,37.44) ; v2(125.93,40.95) 125.95,40.93 125.95,40.92 RAM8.G7 ; 68.88,43.36 68.5,43.74 RAM3.C1 ; 68.88,43.36 v2(68.96,43.28) ; 68.88,43.36 68.48,42.96 RAM3.D1 ; v2(69.67,34.95) 69.67,34.88 68.94,34.14 RAM3.R1 ; RAM6.E2 110.03,42.13 v2(110.43,41.73) 110.03,41.34 RAM6.F2 ; RAM5.G1 v2(121.54,40.54) ; RAM1.R1 89.78,34.14 90.21,34.57 v2(90.21,34.95) ; v2(52.33,41.75) 52.33,41.74 RAM4.F8 ; RAM7.T9 134.88,32.81 v2(134.93,32.76) ; RAM8.L9 124.27,37.34 v2(124.17,37.44) ; RAM6.G7 105.65,40.92 105.65,40.93 v2(105.63,40.95) ; RAM8.F2 130.33,41.34 v2(130.73,41.73) 130.33,42.13 RAM8.E2 ; RAM5.F2 120.18,41.34 v2(120.58,41.73) 120.18,42.13 RAM5.E2 ; RAM1.J2 88.11,39.07 88.65,39.07 RAM1.J1 v2(89.34,38.94) ; RAM1.B9 82.29,44.54 v2(81.88,44.96) 82,44.96 RAM1.A9 ; v2(122.27,32.7) 122.27,33.81 121.94,34.14 RAM5.R1 ; v2(83.57,42.54) 83.59,42.52 83.6,42.52 RAM1.E7 ; RAM3.G7 63.3,40.92 63.3,40.93 v2(63.28,40.95) ; v2(135.28,41.75) 135.28,41.74 RAM7.F8 ; RAM5.E7 115.8,42.52 115.79,42.52 v2(115.77,42.54) ; RAM4.L1 58.86,37.34 v2(58.97,37.44) ; RAM3.J8 RAM3.J9 61.56,38.94 v2(61.51,38.99) ; RAM8.G1 v2(131.69,40.54) ; v2(71.67,37.44) 71.77,37.34 RAM2.L9 ; RAM5.G9 v2(114.02,40.54) ; v2(53.12,42.54) 53.14,42.52 53.15,42.52 RAM4.E7 ; RAM3.E7 63.3,42.52 63.29,42.52 v2(63.27,42.54) ; RAM5.J2 120.31,39.07 120.85,39.07 RAM5.J1 121.49,38.94 v2(121.54,38.99) ; v2(59.52,34.95) 59.52,34.88 58.79,34.14 RAM4.R1 ; v2(140.08,44.94) RAM7.B3 ; v2(89.42,37.44) 89.31,37.34 RAM1.L1 ; v2(69.04,40.54) RAM3.G1 ; v2(51.35,40.67) 51.48,40.54 RAM4.G9 ; v2(129.12,44.95) RAM8.B3 ; 89.18,43.36 89.18,43.27 88.85,42.94 RAM1.D1 ; 89.18,43.36 v2(89.26,43.28) ; 89.18,43.36 88.8,43.74 RAM1.C1 ; v2(53.13,40.95) 53.15,40.93 53.15,40.92 RAM4.G7 ; RAM8.R1 132.08,34.14 132.76,34.82 v2(132.76,34.95) ; RAM1.E2 87.98,42.13 v2(88.38,41.73) 87.98,41.34 RAM1.F2 ; RAM6.F8 104.83,41.74 v2(104.83,41.75) ; RAM4.D1 58.45,42.94 v2(58.84,43.33) 58.84,43.38 58.49,43.74 RAM4.C1 ; RAM1.L9 81.92,37.34 v2(81.82,37.44) ; RAM5.A1 v2(121.67,45.34) ; v2(115.78,40.95) 115.8,40.93 115.8,40.92 RAM5.G7 ; RAM8.D1 131.13,42.96 131.53,43.36 ; RAM6.E7 105.65,42.52 105.64,42.52 v2(105.62,42.54) ; v2(114.98,41.75) 114.98,41.74 RAM5.F8 ; RAM7.B9 134.79,44.54 v2(134.38,44.96) 134.5,44.96 RAM7.A9 ; RAM4.L9 51.47,37.34 v2(51.37,37.44) ; 121.38,43.36 120.98,42.96 RAM5.D1 ; 121.38,43.36 v2(121.46,43.28) ; v2(112.69,36.86) 112.31,36.47 111.69,36.47 RAM6.L1 ; v2(79.82,34.95) 79.44,34.95 RAM2.R1 ; CPU1.AN32 110.97,70.58 v2(111.24,70.86) ; RAM5.T9 114.58,32.81 v2(114.64,32.76) ; 131.53,43.36 131.15,43.74 RAM8.C1 ; 131.53,43.36 v2(131.61,43.28) ; v2(89.47,45.34) RAM1.A1 ; RAM3.E2 67.68,42.13 v2(68.08,41.73) 67.68,41.34 RAM3.F2 ; v2(108.82,44.95) RAM6.B3 ; RAM1.G7 83.6,40.92 83.6,40.93 v2(83.58,40.95) ; RAM8.D9 v2(124.17,42.94) ; v2(124.78,32.76) 124.73,32.81 RAM8.T9 ; RAM1.F8 82.78,41.74 v2(82.78,41.75) ; RAM5.D9 v2(114.02,42.94) ; RAM3.B9 61.99,44.54 v2(61.58,44.96) 61.7,44.96 RAM3.A9 ; v2(62.48,41.75) 62.48,41.74 RAM3.F8 ; RAM6.R1 112.36,34.14 112.74,34.52 v2(112.74,34.95) ; RAM4.E2 57.53,42.13 v2(57.93,41.73) 57.53,41.34 RAM4.F2 ; RAM7.E2 140.48,42.13 v2(140.88,41.73) 140.48,41.34 RAM7.F2 ; RAM3.J2 67.81,39.07 68.35,39.07 RAM3.J1 68.53,38.99 v2(69.04,38.99) ; v2(79.27,37.44) 79.16,37.34 RAM2.L1 ; RAM7.G1 v2(141.84,40.54) ; RAM1.J8 RAM1.J9 81.87,38.94 v2(81.82,38.99) ; RAM5.A9 114.2,44.96 v2(114.08,44.96) 114.49,44.54 RAM5.B9 ; v2(111.52,45.34) RAM6.A1 ; RAM2.C1 78.65,43.74 v2(79.11,43.28) ; v2(141.84,38.94) RAM7.J1 141.15,39.07 140.61,39.07 RAM7.J2 ; RAM3.G9 v2(61.52,40.54) ; RAM2.J2 77.96,39.07 78.5,39.07 RAM2.J1 79.14,38.94 v2(79.19,38.99) ; v2(103.66,32.78) 104.22,33.34 RAM6.T9 ; RAM1.B3 86.79,44.93 v2(86.66,44.93) ; RAM7.L1 141.72,37.34 v2(141.83,37.46) ; RAM5.L1 121.51,37.34 v2(121.62,37.44) ; v2(131.69,38.99) 131.64,38.94 RAM8.J1 131,39.07 130.46,39.07 RAM8.J2 ; RAM8.L1 131.66,37.34 v2(131.77,37.44) ; v2(124.15,38.99) 124.2,38.94 RAM8.J9 RAM8.J8 ; RAM6.J8 RAM6.J9 104.01,38.94 v2(103.85,38.79) ; RAM1.G9 v2(81.82,40.54) ; v2(134.3,38.99) 134.35,38.94 RAM7.J9 RAM7.J8 ; v2(111.39,38.99) 111.34,38.94 RAM6.J1 110.7,39.07 110.16,39.07 RAM6.J2 ; PG5113.2 152.98,20.08 148.64,20.08 146.76,21.96 143.56,21.96 143,22.52 143,23.74 PC5104.1 ; RAM1.G1 v2(89.34,40.54) ; RAM7.G7 136.1,40.92 136.1,40.93 v2(136.08,40.95) ; RAM4.J8 RAM4.J9 51.38,38.94 v2(51.28,39.04) ; RAM3.A1 v2(69.17,45.34) ; RAM1.D9 v2(81.82,42.94) ; RAM6.D9 v2(104.83,43.34) ; RAM5.J8 RAM5.J9 114.05,38.94 v2(114,38.99) ; RAM7.G9 v2(134.32,40.54) ; RAM8.G9 v2(124.17,40.54) ; v2(117.7,70.23) 117.76,70.23 CPU1.BE32 ; v2(82.43,32.73) 82.38,32.79 RAM1.T9 ; RAM5.L9 114.12,37.34 v2(114.02,37.44) ; RAM3.D9 v2(61.52,42.94) ; RAM6.G1 v2(111.39,40.54) ; RAM4.D9 v2(52.33,43.34) ; v2(56.32,44.95) RAM4.B3 ; RAM8.A1 v2(131.82,45.34)
  BOTTOM w0.33: RAM2.D9 v2(71.67,42.94) ; v2(79.11,43.28) 78.77,42.94 RAM2.D1 ; RAM2.F8 73.04,41.34 v2(73.43,40.95) 73.83,40.55 RAM2.G7 ; RAM2.E2 77.83,42.13 v2(78.23,41.73) 77.83,41.34 RAM2.F2 ; v2(72.28,32.76) 72.23,32.81 RAM2.T9 ; RAM2.G9 v2(71.67,40.54) ; RAM2.J8 RAM2.J9 ; RAM2.G1 v2(79.21,40.54)
  BOTTOM w0.356: RAM4.A9 51.81,45.34 v2(51.43,44.96) 51.84,44.54 RAM4.B9 ; v2(66.45,44.93) 66.44,44.93 66.44,44.93 66.49,44.93 RAM3.B3 ; v2(59.02,45.21) 58.9,45.34 RAM4.A1 ; v2(76.62,44.95) RAM2.B3 ; RAM2.E7 73.82,42.14 v2(73.43,42.53)
  BOTTOM w0.508: C1391.1 49.66,41.32 C1394.1 50.52,41.29 51.15,40.67 v2(51.35,40.67)
  vias: v1(42.16,23.13) v1(57.1,39.18) v1(64.85,49.83) v1(65.68,32.28) v1(80.82,39.95) v1(88.9,46.6) v1(112.19,70.71) v1(112.73,39.92) v1(112.83,32.81) v1(115.75,70.76) v1(116.2,53.59) v1(127.94,33.06) v1(136.42,37.46) v1(140.36,46.91) v2(65.46,41.14) v2(71.73,44.96) v2(79.32,45.34) v2(81.25,44.6) v2(95.93,34.19) v2(110.32,65.65) v2(110.41,61.75) v2(112.84,60.96) v2(114.78,64.13) v2(114.98,43.33) v2(115.78,71.55) v2(115.78,41.75) v2(117.14,59.08) v2(117.17,64.32) v2(134.61,46.28) v2(135.28,43.34) v2(136.08,41.73) v2(137.99,41.48) v2(142.29,41.58) v2(143.89,46.5) v3(41.55,22.29) v3(42.44,22.29) v3(142.75,28.59) v3(143.64,28.59) v3(144.53,28.59) v3(145.41,28.59) v3(146.3,28.59) v3(147.19,28.59)
1D2V_VCCSFR_OC: length 40.9
  TOP w0.254: v2(122.19,73.51) 122.09,73.41 C803.2
  L4SGND w0.254: v2(148.72,62.63) 148.72,63.9 148.46,64.15 142.34,64.15 138.02,68.48 133.88,68.48 133.6,68.76 133.6,68.8 132.73,69.66 132.73,73.66 132.2,74.19 132.07,74.19 131.95,74.31 125,74.31 124.53,73.84 124.13,73.84 123.6,74.36 122.5,74.36 122.19,74.05 v2(122.19,73.51)
  BOTTOM w0.254: CPU1.BM26 122.21,73.52 v2(122.19,73.51) 121.87,73.83 CPU1.BL27 ; R4038.2 149.86,61.31 149.86,61.36 148.72,62.5 v2(148.72,62.63) ; C4007.1 151.74,58.59 v1(151.76,58.57)
1D8V_CPVDD: length 6
  TOP w0.203: v2(22.89,22.75) 22.89,22.65 23.02,22.51 U2701.20
  TOP w0.305: v2(22.89,22.75) 22.81,22.83 C2740.1 22.81,24.05 22.1,24.76 R2724.2
  TOP w0.508: v1(20.83,24.53) 21.06,24.76 R2724.2
  BOTTOM w0.508: C2730.1 v2(22.89,22.75)
1D8V_EN#: length 10.1
  BOTTOM w0.102: R4035.1 29.16,22.61 v1(28.55,23.22) 28.82,23.49 29.44,23.49 29.84,23.89 32.33,23.89 32.44,23.79 R4034.2 32.69,23.01 32.69,20.41 33.32,19.78 Q4001.D
1D8V_EN_R#: length 3.6
  BOTTOM w0.102: Q4002.G 29.17,21.62 R4035.2 29.97,22.52 v1(29.97,23.39) 30.1,23.39 30.48,23.01 30.48,23.01 30.73,22.75 C4038.2
1D8V_PWR:
  vias: v1(49.92,17.95)
1D8V_S0: length 222.4
  TOP w0.254: C4039.1 32.13,18.26 v2(32.13,19.2)
  TOP w0.508: R2724.1 22.62,26.08 v2(23.23,25.47)
  L4SGND w0.508: 124.58,14.25 123.51,15.32 113.04,15.32 112,16.37 108.18,16.37 106.88,17.67 104,17.67 103.45,17.11 92.58,17.11 91.76,16.3 90.78,16.3 90.06,15.58 87.25,15.58 86.79,15.12 85.81,15.12 85.64,14.95 85.44,14.95 83.64,13.16 83.64,12.39 82.96,11.7 68.53,11.7 67.21,10.38 48.62,10.38 44.54,14.47 44.25,14.47 39.9,18.81 35.87,18.81 34.81,19.87 33.57,19.87 32.89,19.2 v2(32.13,19.2) ; 124.58,14.25 125.21,14.88 125.81,14.88 127.59,16.66 131.06,16.66 132.18,17.77 139.99,17.77 140.65,17.11 145,17.11 145.53,17.11 146.8,18.39 160.63,18.39 166.76,24.53 166.76,25.41 166.76,25.41 166.76,28.98 157.95,37.79 156.75,37.79 155.28,39.26 155.28,40.16 154.91,40.53 154.42,40.53 153.16,41.79 153.16,41.83 151.21,43.78 150.07,43.78 149.54,44.32 149.21,44.32 v2(146.14,47.39) ; 124.58,14.25 v2(124.58,14.24)
  L6 w0.381: v2(131.59,54.22) 131.59,53.52 133.04,52.07 137.3,52.07 140.53,48.85 144.29,48.85 145.75,47.39 v2(146.14,47.39)
  BOTTOM w0.508: v2(124.58,14.24) 124.58,14.24 125.21,13.61 126.16,13.61 R6406.1 ; v2(23.23,25.47) 23.83,24.87 23.83,24.39 24.2,24.02 24.51,24.02 v1(25.78,22.75) 26.12,22.41 26.64,22.41 26.92,22.13 26.92,21.14 26.64,20.86 26.58,20.86 R2750.1 R2748.1 26.33,19.22 27.65,20.54 28.46,20.54 28.63,20.71 29.63,20.71 30.12,20.21 Q4002.D 31.63,19.32 31.75,19.2 v2(32.13,19.2) ; v2(131.59,54.22) 131.56,54.19 130.8,54.19 130.4,53.79 R2052.1
1D8V_S5: length 300.2
  TOP w0.381: v2(111.48,15.23) 111.84,15.23 117.31,9.76 117.31,8.82 119.68,6.44 119.68,6.04 120.14,5.58 123.62,5.58 v2(124.02,5.97)
  TOP w0.508: v2(50.04,16.4) 49.83,16.4 47.28,13.85 47.28,13.33 50.26,10.35 57.74,10.35 57.99,10.1 62.42,10.1 62.49,10.03 64.66,10.03 65.47,9.23 78.67,9.23 79.11,8.78 80.78,8.78 82.33,10.33 83.71,11.71 83.71,11.79 84.66,12.74 87.41,12.74 v2(89.17,14.5) ; R1104.2 v2(148.71,77.62) ; v2(147.87,46.8) 147.37,47.3 147.37,48.1 151.02,51.74 151.02,56.47 150.06,57.42 R1515.1 150.06,58.52 150.31,58.76 151.21,58.76 151.76,59.32 151.76,65.84 149.13,68.48 v2(149.13,71.01)
  L3SGND w0.254: v2(50.04,16.4) 49.95,16.4 49.07,17.29 37.97,17.29 33.78,21.48 v2(32.26,21.48)
  L4SGND w0.508: v2(89.17,14.5) 89.58,14.91 93,14.91 94.11,16.02 98.96,16.02 99.44,15.54 103.53,15.54 103.81,15.82 106.76,15.82 107.31,15.26 111.46,15.26 v2(111.48,15.23) 111.91,15.23 112.79,14.36 119.01,14.36 119.98,13.38 125.63,13.38 127.62,15.37 139.83,15.37 140.94,16.48 145.79,16.48 147.06,17.75 160.88,17.75 167.03,23.89 167.4,24.26 167.4,29.24 158.17,38.47 157,38.47 155.91,39.56 155.91,41.47 154.54,42.84 153.58,42.84 153.58,42.84 153.39,43.04 151.64,44.79 151.64,44.81 149.39,47.06 148.4,47.06 148.13,46.8 v2(147.87,46.8)
  L6 w0.305: 94.49,24.91 93.29,26.1 87.53,26.1 87.05,25.62 87.05,24.33 82.64,19.93 82.6,19.93 78.31,15.64 75.97,15.64 75.57,15.23 68.75,15.23 64.89,11.37 58.77,11.37 53.74,16.4 v2(50.04,16.4)
  L6 w0.381: v2(94.74,24.66) 94.49,24.91
  BOTTOM w0.254: v2(124.02,5.97) C6401.1
  BOTTOM w0.356: C6401.1 122.95,6.71 U6402.5
  BOTTOM w0.381: v2(94.74,24.66) 95.17,24.66 95.55,24.28 R2462.1
  BOTTOM w0.508: v2(148.71,77.62) 148.64,77.55 R2016.1 R2018.1 R2029.1 R2033.1 R2011.1 149.02,73.42 R2031.1 149.02,71.99 R2013.1 149.1,71.85 149.1,71.04 v2(149.13,71.01)
  vias: v1(50.04,15.64)
1D8V_S5_EN: length 6.7
  BOTTOM w0.102: PR5306.2 PR5301.1 37.67,23.23 PC5306.1 38.35,22.5 v1(38.61,22.24) 38.68,22.17 40.59,22.17 40.89,21.86 40.89,20.97 40.64,20.72 PU5301.8
1D8V_S5_KBC: length 7.8
  TOP w0.508: v2(92.37,20.34) 91.94,19.91 C2423.1
  BOTTOM w0.178: R2462.2 94.69,23.94 v1(93.98,24.66) 93.33,24 93.33,23.05 93.51,22.86 U2401.54 93.51,21.27 93.3,21.06 92.93,21.06 92.37,20.5 v2(92.37,20.34)
1D8V_VCCPRIM: length 82.3
  TOP w0.305: v2(124.08,54.37) 121.16,54.37 120.5,55.03 120.5,57.73 v2(120.65,57.88)
  TOP w0.508: v2(151.13,76.47) 151.66,76.47 152.2,77.01 v1(152.2,77.44) 152.01,77.62 R1104.1 ; v2(146.18,53.31) 145.5,53.99 143.36,53.99 140.54,51.17 137.19,51.17 136.65,51.71 136.61,51.71 136.58,51.73 135.31,51.73 132.14,54.91 129.61,54.91 129.1,55.41 129.1,55.98 v2(129.2,56.08) 129.2,56.48 129.2,56.48 129.2,57.01 128.19,58.02 128.19,58.64 128.14,58.68 R1821.1 ; R2113.1 136.24,76.35 v2(136.39,76.51)
  L4SGND w0.508: v2(146.18,53.31) 146.26,53.23 151.3,53.23 v2(152.15,54.07)
  L6 w0.508: v2(151.13,76.47) 150.75,76.09 150.75,71.47 150.01,70.73 150.01,64.29 150.48,63.82 150.48,61.76 150.24,61.51 150.24,59.2 151.76,57.68 151.76,57.09 152.4,56.45 152.4,54.5 152.15,54.25 v2(152.15,54.07)
  BOTTOM w0.254: v2(136.39,76.51) 136.36,76.47 135.73,76.47 135.57,76.4 CPU1.CP23 ; CPU1.CD19 CPU1.CD18 ; CPU1.CD15 CPU1.CD16 129.19,81.28 CPU1.CC15 ; 136.06,80.16 CPU1.CP17 ; CPU1.CC19 CPU1.CC18
  BOTTOM w0.305: v2(136.4,79.65) 136.4,79.83 136.06,80.16 ; v2(129.51,80.21) 129.51,80.12 CPU1.CC18 ; v2(129.51,80.21) 129.84,79.89 CPU1.CD18 ; v2(129.51,80.21) 129.84,80.54 CPU1.CD16 ; v2(124.08,54.37) 124.23,54.53 v1(125.83,54.53) 126.19,54.53 R1738.1 126.75,54.76 126.92,54.58 128.35,54.58 129.2,55.43 v2(129.2,56.08)
  BOTTOM w0.508: R2115.1 156,79.65 155.96,79.69 155.96,79.84 v2(155.89,79.9) 155.49,80.3 R2111.1
  vias: v1(120.8,58.72)
1D24V_VCCDPHY: length 2.3
  BOTTOM w0.254: CPU1.CA24 127.74,75.74 127.38,75.74 CPU1.BY24 CPU1.BY23 CPU1.CA23
1D24V_VCCDPHY_EC: length 4.9
  TOP w0.254: C2218.1 138.52,74.06 v2(138.88,74.42)
  BOTTOM w0.254: v2(138.88,74.42) 138.68,74.62 v1(138.68,75) 138.57,75.12 CPU1.CP25
2D5V_S3: length 20.9
  TOP w0.457: C1346.1 131.32,44.04 v2(131.82,44.54)
  TOP w0.508: C1341.1 121.17,44.04 v2(121.67,44.54) ; C1351.1 141.52,44.09 v2(141.97,44.54) ; C1262.1 68.69,44.06 v2(69.17,44.54) ; v2(79.32,44.54) 78.84,44.06 C1268.1 ; v2(59.02,44.54) 58.54,44.06 C1265.1 ; C1337.1 111.05,44.07 v2(111.52,44.54) ; C1259.1 88.99,44.06 v2(89.47,44.54)
  BOTTOM w0.305: v2(89.47,44.54) RAM1.B1 ; RAM8.B1 v2(131.82,44.54) ; v2(141.97,44.54) RAM7.B1 ; 102.84,33.86 104.15,33.86 RAM6.R9 ; v2(111.52,44.54) RAM6.B1
  BOTTOM w0.356: RAM2.R9 71.75,34.14 71.01,33.41 71.01,31.93 ; 60.86,31.66 60.86,33.54 61.46,34.14 RAM3.R9 ; RAM1.R9 82.04,34.14 80.94,33.05 80.94,31.14
  vias: v1(64.64,48.79) v1(74.57,49.45) v1(94.18,38.07) v1(99.14,43.83) v1(117.6,49.95)
2D5V_S3_EN: length 10.1
  BOTTOM w0.102: PU5303.8 134.23,21.42 133.35,20.54 133.35,17.94 132.33,16.92 132.33,16.91 131.42,15.99 v1(130.84,15.99) 130.81,15.97 PC5327.1 129.18,15.97 PR5309.1 PR5317.2
2D5V_S3_PWRGD: length 143.3
  TOP w0.102: PR5114.1 v2(50.89,24.38)
  L4SGND w0.102: v2(42.04,21.61) 45.9,17.75 52.32,17.75 54.89,15.18 75.76,15.18 76.67,16.1 80.88,16.1 81.14,15.84 82.19,15.84 83.44,17.09 83.44,19.13 84.67,20.36 85.98,20.36 86.39,19.96 87.94,19.96 89.08,21.1 98.45,21.1 98.75,21.41 100.48,21.41 101.07,20.82 107.72,20.82 107.97,20.57 108.89,20.57 111.02,18.43 113.16,18.43 114.54,17.05 125.54,17.05 126.98,18.48 128.57,18.48 130.88,20.8 134.16,20.8 v2(134.24,20.72) 134.62,21.1 139.7,21.1 v2(139.95,20.85)
  L6 w0.102: v2(50.89,24.38) 48,21.48 42.16,21.48 v2(42.04,21.61)
  BOTTOM w0.102: PU5303.7 135.5,21.47 134.75,20.72 v2(134.24,20.72) ; v2(139.95,20.85) 140,20.85 PR5310.2 141.35,21.48 141.86,21.99 142.62,21.99 143.13,21.48 146.08,21.48 v1(146.99,20.57) 148.16,19.4 156.57,19.4 158.12,20.95 158.12,21.94 PG5112.1
3D3V_1D8V_AVDD: length 8
  TOP w0.203: 27.1,17.03 U2701.3
  TOP w0.254: R2742.1 R2749.2 30.81,15.74 R2743.1 30.07,16.48 C2729.1 C2722.1 28.37,16.48 v2(28.32,16.53) 27.69,16.53 27.18,17.03 27.1,17.03 ; v2(27.05,13.23) 27.48,12.79 R2744.1
  vias: v1(26.31,13.66) v1(27.18,16.78)
3D3V_1D8V_AVDD_IO: length 9.6
  TOP w0.203: 23.88,21.99 23.82,21.93 U2701.18
  TOP w0.254: 23.88,21.99 23.88,21.99 24.18,22.29 24.18,22.71 23.81,23.08 23.75,23.08 v2(23.7,23.13) 23.7,25.19 C2744.1 23.8,26.74 R2751.2
  BOTTOM w0.254: v2(23.7,23.13) 24.21,23.13 v1(24.51,22.83) 24.51,21.76 C2745.1 R2750.2
3D3V_AUX_S5: length 272
  TOP w0.305: v2(158.12,76.22) 157.56,75.66 157.56,67.64 157.15,67.23 157.15,62.22 157.07,62.14 157.07,59.7 157.09,59.69 157.09,56.48 156.21,55.6 156.21,54.53 155.7,54.02 155.7,50.5 155.07,49.86 155.07,49.85 154.76,49.55 v2(154.76,49.37)
  TOP w0.508: R2728.1 16.63,18.18 v2(16.26,17.8) ; R2463.1 88.54,7.32 88.93,7.7 R2472.2 89.59,8.56 v2(89.92,8.56) ; v2(131.7,18.94) 131.32,18.94 130.25,17.87 PR4503.1 128.4,17.59 128.02,17.21 125.86,17.21 125.35,17.72 v2(125.35,18.43)
  L3SGND w0.508: v2(61.59,3.7) 60.83,2.94 38.61,2.94 37.82,3.73 37.82,4.13 37.39,4.56 37.25,4.56 33.16,8.65 31.88,8.65 29.84,10.69 18.51,10.69 15.92,13.27 15.92,17.47 v2(16.26,17.8) ; v2(116.13,9.92) 124.64,18.43 v2(125.35,18.43)
  L4SGND w0.305: 145.16,48.05 145.67,48.56 145.89,48.56 146.24,48.91 150.37,48.91 150.83,49.37 v2(154.76,49.37)
  L4SGND w0.508: v2(145.1,53.18) 144.84,53.18 144.46,52.8 144.46,52.54 144.42,52.5 144.42,48.51 145.16,47.77 ; 145.16,48.05 145.16,47.77 ; 145.16,47.77 145.16,47.47 148.95,43.68 149.28,43.68 149.81,43.15 150.95,43.15 152.53,41.57 152.53,41.53 153.02,41.04 153.02,40.62 156.54,37.1 157.74,37.1 166.13,28.71 166.13,25.15 166.13,24.79 160.37,19.03 146.54,19.03 145.26,17.75 140.92,17.75 140.23,18.43 132.21,18.43 v2(131.7,18.94) ; v2(61.59,3.7) 61.59,3.56 62.15,3.01 73.25,3.01 75.62,5.38 75.73,5.38 76.6,6.24 85.37,6.24 85.91,6.77 87.9,6.77 89.68,8.56 v2(89.92,8.56) 90.84,8.56 90.87,8.53 91.68,8.53 91.82,8.67 98.85,8.67 99.28,9.1 100.29,9.1 100.93,9.74 105.16,9.74 105.65,10.23 107.67,10.23 107.99,9.92 v2(116.13,9.92)
  BOTTOM w0.381: PG4519.2 125.53,18.26 v2(125.35,18.43) ; v2(131.7,18.94) 131.19,19.45 PR4505.1 ; v2(145.1,53.18) 144.81,53.46 142.71,53.46 141.52,52.27 R1726.1 140.65,52.27 140.27,52.65 140.27,53.34 139.56,54.06 138.23,54.06 137.98,53.8 135.18,53.8 v1(135.08,53.71) R1737.1
  BOTTOM w0.508: R2505.1 v2(158.12,76.22) ; R1727.1 146.43,52.1 145.35,53.18 v2(145.1,53.18)
3D3V_CAMERA_S0: length 1
  BOTTOM w0.279: LCD1.37 105,100 104.78,100.22 v2(104.78,100.35)
  vias: v1(105.03,100.86)
3D3V_ECVBAT: length 10.1
  TOP w0.381: R2472.1 87.74,7.57 87.34,7.57 86.82,7.05 C2428.1 86.82,5.96 87.3,5.48 v2(87.54,5.48)
  TOP w0.508: R2497.2 R2473.1 87.58,8.27 87.83,8.02 87.93,8.02 R2472.1 ; v2(87.54,5.48) v1(86.89,4.83) 86.87,4.84 86.22,4.84 85.22,5.85 R2451.1
  BOTTOM w0.178: U2401.122 87.51,5.5 v2(87.54,5.48)
3D3V_FLASH: length 67
  TOP w0.254: R7204.1 24.79,84.09 25.27,83.61 v2(25.27,83.46) ; v2(13.08,81.55) 12.39,82.24 12.39,83.28 13.72,84.6 14.43,84.6 R7222.1
  L6 w0.254: v2(18.29,56.66) 18.8,57.17 18.8,66.1 18.41,66.48 18.41,70.25 19.05,70.88 19.05,77.83 18.67,78.21 18.37,78.5 17.01,78.5 16.27,79.25 15.39,79.25 v2(13.08,81.55) 14.86,83.33 19.18,83.33 20.07,84.22 22.99,84.22 24.26,82.95 24.77,82.95 v2(25.27,83.46)
  BOTTOM w0.127: v2(13.08,81.55) 13.2,81.67 14.69,81.67 14.7,81.67 U7201.G1
  BOTTOM w0.254: R7230.2 15.44,48.53 19.2,48.53 v1(20.07,49.4) 20.09,49.42 20.19,49.42 20.7,49.93 20.7,50.61 R7225.2 20.7,51.63 20.7,52.39 R7228.2 20.19,53.61 18.92,54.88
3D3V_FPR_VDD: length 1.5
  BOTTOM w0.508: v2(173.23,49.29) 172.92,48.99 ED9202.5
  vias: v1(174.12,49.93) v1(180.31,50.36) v2(176.4,50.56)
3D3V_GSEN2: length 3
  TOP w0.254: 185.96,40.91 U7001.9 ; v2(187.22,35.71) 187.22,36.27 R7002.1 R7004.2 ; 185.4,41.17 U7001.10
  vias: v1(179.83,47.52) v2(180.34,48.28) v2(180.72,47.77) v2(184.78,41.67)
3D3V_HDMI_VDD: length 19.3
  TOP w0.254: U5701.B2 25.17,63.49 v2(24.78,63.88) ; U5701.G4 v2(26.38,59.09) ; U5701.G2 v2(25.58,59.09)
  L4SGND w0.254: v2(25.58,59.09) 24.26,60.41 24.26,63.36 v2(24.78,63.88)
  BOTTOM w0.254: 21.46,50.37 21.46,53.36 20.19,54.63 R5740.1 19.99,54.96 19.68,55.26 19.68,56.48 R5747.2 ; 29.57,59.02 29.29,59.3 29.29,59.3 28.99,59.6 28.99,59.6 28.96,59.63 28.44,59.63 28.19,59.38 27.77,59.38 27.51,59.63 26.92,59.63 v2(26.38,59.09)
  vias: v1(24.49,64.48)
3D3V_LCDVDD_R: length 1.1
  BOTTOM w0.254: v1(118.62,103.78) C5505.1
3D3V_LCDVDD_S0: length 1.6
  BOTTOM w0.254: 116.97,104.11 117.4,104.11 v1(118.24,104.95)
  vias: v1(102.26,104.29) v2(101.85,104.92) v2(102.11,100.35) v2(102.49,104.92) v2(102.74,100.35) v2(103.12,104.92) v2(103.38,100.35)
3D3V_LDO_SET: length 9.1
  TOP w0.102: R5541.2 51.51,92.6 50.22,91.31 R5542.1 51.44,90.82 v2(51.94,91.33)
  BOTTOM w0.102: U5503.4 49.85,93.55 50.04,93.74 v1(50.55,93.74) 50.8,93.49 50.8,92.6 51.94,91.46 v2(51.94,91.33)
3D3V_MUX: length 37.9
  TOP w0.508: v2(40.64,88.66) 41.15,88.66 42.34,89.86 R7174.1 R7171.1 R7145.1 42.34,94.71 41.71,95.34 C7117.2 38.94,95.34 v2(38.61,95.01) 37.67,95.95 R7152.1 37.01,96.28 34.82,96.28 33.91,95.37 33.91,94.84 34.29,94.46 v2(34.29,94.25) 34.24,94.2 R7147.1 34.04,93.29 34.04,92.35 33.1,91.41 R7142.1 R7140.1 R7121.1 R7118.1 33.1,88.58 33.52,88.16 33.58,88.16 33.81,87.93 33.81,87.87 33.83,87.85 L7101.2 34.09,87.52 34.85,88.28 v2(35.18,88.28) 35.89,88.28 C7116.2 36.07,87.52 35.56,87.01 35.18,87.01 v1(34.67,86.51) v2(35.18,86)
  BOTTOM w0.203: C7115.2 35.47,94.01 U7101.1 ; U7101.6 38.57,94.98 v2(38.61,95.01) ; v2(35.18,88.28) 35.32,88.14 U7101.28
  BOTTOM w0.508: R7101.1 35.74,85.18 35.18,85.74 v2(35.18,86) ; v2(34.29,94.25) 34.34,94.3 C7115.2
3D3V_RTC: length 211.1
  TOP w0.508: R2473.2 v2(88.44,9.29)
  L3SGND w0.508: v2(178.12,50.99) 178.1,51.01 178.1,51.35 178.08,51.37 178.08,52.88 177.57,53.38 171.69,53.38 166.73,58.34 166.73,65.94 165.62,67.05 164.77,67.05 160.43,71.39 160.43,78.33 v2(159.55,79.2)
  L4SGND w0.254: v2(88.44,9.29) 89.34,10.18 93.52,10.18 93.78,9.92 96.77,9.92 97.53,10.68 98.26,10.68 98.35,10.58 104.96,10.58 105.35,10.97 108.85,10.97 109.13,10.69 117.37,10.69 119.02,9.04 122.15,9.04 122.83,9.72 123.44,9.72 124.82,8.35 127.22,8.35 128.18,9.31 128.18,9.71 129.16,10.69 131.98,10.69 132.56,10.1 132.56,9.26 133.83,7.99 137.72,7.99 141.05,11.32 154.61,11.32 156.64,13.35 161.41,13.35 170.65,22.6 170.65,28.65 172.42,30.42 174.85,30.42 180.15,35.73 182.73,35.73 184.73,37.73 184.73,38.07 184.73,39.43 183.79,40.37 183.79,42.58 183.79,42.58 183.79,43.13 181.44,45.48 181.37,45.48 181.05,45.8 181.05,46.03 180.5,46.58 180.38,46.7 180.22,46.7 178.08,48.83 178.08,50.95 178.1,50.97 178.1,50.98 v2(178.12,50.99) 177.63,51.48 177.59,51.48 177.58,51.49 169.29,51.49 168.87,51.07 168.22,51.07 166.37,52.92 163.51,52.92 162.87,53.55 161.03,53.55 159.33,53.55 159.15,53.74 156.94,53.74 155.54,52.34 v2(154.81,52.34)
  BOTTOM w0.305: v2(154.81,52.34) 154.81,51.83 154.12,51.14 Q2507.S 152.79,52.35 152.79,53.55 R2512.1
  BOTTOM w0.508: D2501.3 154.81,78.42 155.97,77.26 C2503.1 157.38,77.26 158.43,78.31 v1(158.73,78.31) 159.55,79.13 v2(159.55,79.2)
3D3V_RTC_SYS: length 3.6
  BOTTOM w0.254: 155.61,75.33 156.5,76.22 R2505.2 156.45,76.3 D2501.1 ; 155.61,75.33 v1(155.6,75.32) ; 155.61,75.33 R2517.1
3D3V_S0: length 592
  TOP w0.254: v2(67.94,91.33) 67.82,91.46 67.82,91.58 67.49,91.91 R5504.1 67.49,92.73 R5518.1 ; 55.63,91.08 56.2,90.51 69.74,90.51 70.48,91.25 v2(70.48,91.33) 70.48,91.36 70.33,91.51 70.33,92.45 R5517.1 ; 127.51,89.17 128.23,89.9 131.15,89.9 131.95,90.7 131.95,92.75 132.33,93.13 133.76,93.13 135.51,94.89 137.92,94.89 138.81,95.78 v2(138.81,96.16)
  TOP w0.305: R2005.1 149.43,87.18 150.29,86.32 R2045.1 ; v2(145.27,95.95) 145.07,96.15 145.07,97.2 145.11,97.24 R2604.1 ; v2(146.69,56.91) 146.69,56.71 147.35,56.04 147.35,55.44 147.35,55.43 147.35,55.4 147.05,55.1 145.91,54.63 143.24,54.63 140.32,51.71 137.59,51.71 136.83,52.47 135.43,52.47 R1818.2
  TOP w0.381: DB1.10 91.23,16.23 v2(91.91,15.54) ; R6305.1 166.7,7.13 165.71,6.14 165.71,6.09 v1(165.1,5.48) 163.83,4.21 v2(163.83,3.07)
  TOP w0.508: 131.95,56.71 131.95,55.95 R1818.2 ; 131.95,56.71 131.95,57.47 R2043.1 132.26,57.78 R2053.1 ; 131.95,56.71 R1820.1 ; v2(94.36,4.84) 94.16,4.64 R2609.1 ; v2(24.14,29.01) 23.62,28.5 R2751.1 ; R2749.1 33.24,17.06 33.39,16.91 33.4,16.91 v2(33.66,16.66) 33.66,15.63 36.26,13.02 38.22,13.02 38.47,12.77 39.61,12.77 40.03,13.19 v2(40.03,13.23) ; R2010.1 150.24,84.64 151.21,84.64 ; 151.21,84.64 R2110.1 R2109.1 151.22,86.03 v2(151.13,86.12) 151,86.25 R2045.1 ; 151.21,84.64 R2048.1 151.21,83.84 143.77,83.84 143.52,83.58 142.99,83.58 142.56,84.02 R2044.1 ; v2(16.89,4.21) 16.38,4.72 R2914.1 ; v2(151.12,44.42) 150.27,45.27 C2602.1 150.27,46.53 151.15,47.41 v2(151.15,48.66) ; R5752.2 v3(25.27,52.34)
  TOP w0.559: 181.03,49.04 181.61,48.46 D9201.A
  TOP w0.762: 177.7,41.2 177.7,42.97 177.01,43.66 177.01,45.89 175.77,47.13 175.77,47.77 176.89,48.89 177.42,48.89 ; 181.03,49.04 178.79,49.04 R7001.1 177.52,48.94 177.47,48.89 177.42,48.89 ; 177.42,48.89 R9211.1 ; 172.72,39.13 173.53,39.95 176.15,39.95
  L3SGND w0.762: 24.1,28.98 24.1,28.35 26.86,25.6 26.95,25.6 28.96,23.59 28.96,20.38 28.7,20.13 v2(28.7,19.96) 28.7,19.58 28.73,19.55 28.73,19.52 29.17,19.07 30.6,19.07 33.02,16.66 v2(33.66,16.66) ; 24.1,28.98 v2(24.14,29.01) ; 24.1,28.98 22.16,28.98 18.73,32.4 18.73,44.72 19.75,45.74 19.8,45.74 20.03,45.97 20.66,45.97 20.89,45.74 24.7,45.74 24.96,45.99 25.15,45.99 v3(25.27,46.12)
  L4SGND w0.508: v2(41.66,37.74) 41.92,37.74 42.29,37.37 42.29,37.36 42.42,37.23 42.42,32.02 43.69,30.75 77.06,30.75 81.64,26.18 87,26.18 88.27,24.92 v2(88.27,24.66) 92.61,29 108.46,29 108.97,28.49 v3(108.97,28.09) ; v2(54.99,91.33) 54.84,91.18 53.51,91.18 52.9,90.57 47.54,90.57 44.2,87.23 44.2,87.17 44.2,87.17 v2(44.2,85.62) 44.18,85.63 40.53,85.63 38.73,83.84 38.73,83.57 37.98,82.82 36.92,82.82 33.25,79.15 33.25,75.74 32.79,75.28 32.79,67.73 32.74,67.68 32.74,67.68 31.11,66.05 31.11,58.61 28.94,56.43 27.97,56.43 26.04,54.5 26.04,53 25.84,52.81 25.84,52.78 25.41,52.34 v3(25.27,52.34) 26.04,51.58 26.04,46.63 25.53,46.12 v3(25.27,46.12) ; v2(44.27,13.18) 44.2,13.1 40.16,13.1 v2(40.03,13.23) ; 38.35,4.22 38.35,2.69 39.6,1.44 74.85,1.44 77.62,4.21 79,4.21 79.4,3.81 79.4,2.91 79.86,2.46 86.12,2.46 87.75,4.08 89.67,4.08 90.94,5.35 93.85,5.35 v2(94.36,4.84) ; 38.35,4.22 37.47,5.11 37.47,6.09 30.67,12.88 28.82,12.88 27.69,14.02 27.69,16.79 28.77,17.87 28.77,19.51 28.7,19.58 v2(28.7,19.96) ; 38.35,4.22 39.65,4.22 39.92,3.96 58.17,3.96 59.56,5.35 68.71,5.35 70.36,7 72.01,7 v2(73.03,8.02)
  L6 w0.381: v2(91.91,15.54) 87.79,15.54 87.35,15.98 87.35,19.93 88.27,20.85 v2(88.27,24.66)
  L6 w0.508: v3(125.12,5.96) 122.1,2.94 112.26,2.94 110.77,1.46 102.32,1.46 100.07,3.7 95.5,3.7 v2(94.36,4.84) ; v2(16.89,4.21) 19.14,1.96 22.73,1.96 27.03,6.26 27.03,9.7 v2(26.8,9.92) ; v2(44.27,13.18) 47.5,13.18 v2(47.92,13.59)
  BOTTOM w0.254: RN403.1 131.28,96.12 131.83,96.67 132.46,96.67 v2(132.72,96.41) 132.47,96.16
  BOTTOM w0.305: RN403.2 131.95,95.65 132.47,96.16 ; R1718.1 158.62,80.11 159.04,79.7 v2(159.08,79.7) ; v2(47.92,13.59) 47.81,13.48 Q2601.2 ; Q2601.5 44.7,13.48 44.4,13.18 v2(44.27,13.18)
  BOTTOM w0.381: v2(41.66,37.74) 42,38.08 42,43.55 43.89,45.43 46.46,45.43 51.13,50.11 55.57,50.11 56.46,51 56.46,51 58.77,53.31 59.92,54.46 77.94,54.46 82.23,58.76 83.3,58.76 R507.1 ; v2(159.08,79.7) 159.18,79.7 159.31,79.82 159.85,79.82 160.27,79.4 R4005.1 ; R2430.1 88.32,24.55 88.27,24.61 v2(88.27,24.66) ; PR4609.1 47.29,85.11 46.61,85.11 45.96,85.76 45.08,85.76 44.94,85.62 v2(44.2,85.62) ; R5505.2 139.12,96.91 v2(138.81,96.16) ; v2(67.94,91.33) 67.94,91.55 68.29,91.9 70.09,91.9 70.48,91.5 v2(70.48,91.33)
  BOTTOM w0.508: R2603.1 150.83,49.09 151.15,48.76 v2(151.15,48.66) ; R2489.1 68.2,14.5 69.24,15.55 ; 69.24,15.55 69.24,15.36 70.1,14.5 70.1,11.32 70.48,10.94 70.48,10.87 73.03,8.33 v2(73.03,8.02) ; 69.24,15.55 Q2414.G ; v3(25.27,46.12) 24.33,46.12 C5748.1
  vias: v1(27.47,10.83) v1(29.5,17.99) v1(55.4,94.18) v1(106.1,105.09) v1(108.18,26.87) v1(131.95,6.46) v1(145.26,61.56) v1(150.83,92.14) v1(152.65,75.99) v1(155.19,43.33) v1(172.47,38.25) v2(107.31,104.92) v2(131.44,7.38) v2(146.05,56.91) v2(151,91.33) v2(151,90.46) v2(153.42,74.69) v2(153.8,42.06) v2(165.74,51.58) v2(172.72,36.72) v2(172.72,35.96) v3(107.19,28.09) v3(108.08,28.09) v3(109.86,28.09) v3(125.96,5.96) v3(126.8,5.96) v3(127.66,5.96)
3D3V_S5: length 405.5
  TOP w0.178: RN7206.2 14.27,83.5 14.37,83.6 14.37,83.61 14.51,83.75 14.82,83.75 14.94,83.63 RN7206.1
  TOP w0.254: R7427.1 R7424.1
  TOP w0.305: R7424.1 23.11,70.54 22.67,70.99 22.5,70.99 21.34,72.15 19.3,72.15 18.67,71.52 16.71,71.52 R7215.2 ; C6102.1 179.35,42.16 R6111.1 180.26,42.23 v2(180.72,42.69) ; v2(5.21,73.55) 5.16,73.6 HALL1.3 ; RN7206.2 13.78,83.14 13.34,82.7 v2(13.08,82.7)
  TOP w0.381: R7215.2 16.05,71.6 v2(15.88,71.77) ; R2442.1 97.35,5.72 97.35,5.37 97.68,5.03 98.15,5.03 98.18,5.06 98.34,5.06 ; PR5104.1 153.67,23.51 v2(153.03,22.88) ; v2(28.83,37.1) 28.19,37.1 27.37,37.93 27.37,42.37 28.34,43.34 28.34,44.03 v2(28.76,44.45) 29.22,44.45 29.24,44.47 PR4435.1
  TOP w0.508: v2(180.72,42.69) 180.77,42.74 Q6101.S ; 183.67,52.04 C6702.1 184.61,52.04 185.8,50.85 v2(185.8,49.62) 185.8,47.34 R2050.1 ; 183.67,52.04 R2003.1 ; 183.67,52.04 183.77,52.14 183.77,52.35 183.8,52.38 183.8,53.33 183.08,54.06 182.87,54.06 181.23,55.69 181.23,59.58 v2(181.61,59.96) ; v2(142.62,49.8) 144.31,49.8 146.63,50.77 146.66,50.79 146.72,50.79 148.19,52.26 148.76,52.26 v2(150.37,53.87) ; L7101.1 32.64,87.52 32.51,87.65 24.38,87.65 v2(24.26,87.52) ; 98.34,5.06 v2(98.51,5.06) ; v2(155.07,98.62) 155.07,98.62 R2607.1
  L3SGND w0.508: v2(180.72,42.69) 182.47,42.69 183.95,44.16 183.95,47.19 185.8,49.04 v2(185.8,49.62) ; v2(125.98,8.91) 125.25,8.17 120.19,8.17 116.74,4.72 v2(113.54,4.72)
  L4SGND w0.381: v2(35.94,27.07) 34.8,28.21 33.75,28.21 33.43,28.53 33.04,28.53 32.64,28.93 v2(32.64,28.97)
  L4SGND w0.508: v2(98.51,5.06) 98.53,5.08 100.8,5.08 102.87,7.14 105.05,7.14 105.23,6.97 106.24,6.97 108.49,4.72 v2(108.9,4.72) v2(113.54,4.72) ; 156.21,71.39 156.21,69.74 157.43,68.52 158.97,68.52 158.97,68.52 161.17,68.52 161.52,68.16 161.52,66.54 161.01,66.03 151.59,66.03 148.27,69.36 148.21,69.36 148.2,69.37 147.11,69.37 146.33,70.15 145.95,70.53 145.95,70.88 v2(145.93,70.9) ; v2(13.08,82.7) 13.59,82.7 14.86,81.43 ; 13.72,76.6 11.05,76.6 8,73.55 v2(5.21,73.55) ; 19.81,81.54 20.95,82.69 20.95,82.83 22.09,83.97 24.54,83.97 24.67,84.09 27.82,84.09 28.32,84.59 28.32,85.5 27.95,85.87 24.37,85.87 23.62,86.62 23.62,87.15 23.99,87.52 v2(24.26,87.52) ; v2(32.64,28.97) 32.51,28.97 30.1,31.39 30.1,32.02 28.19,33.93 28.19,36.47 v2(28.83,37.1) ; v2(153.03,22.88) 153.92,21.99 158.47,21.99 v2(162.34,25.86) 163.55,27.07 v2(163.97,27.07) ; v2(35.89,18.08) 37.59,18.08 v3(40.13,15.54)
  L6 w0.381: v2(35.94,27.07) 37.76,28.89 37.76,35.57 42.04,39.85 42.51,39.85 54.36,51.71 63.5,51.71 v2(67.18,55.39)
  L6 w0.508: v2(142.62,49.8) 141.98,49.8 138.68,53.09 138.68,54.11 139.06,54.49 139.06,55.02 138.69,55.39 138.17,55.39 137.86,55.09 134.99,55.09 134.85,54.94 133.05,54.94 132.22,55.77 131.8,55.77 129.65,57.92 129.65,58.42 126,62.07 v2(125.02,62.07) ; v2(28.76,44.45) 29.59,45.28 29.59,47.33 31.93,49.68 32.88,49.68 33.14,49.93 33.66,49.93 35.81,52.09 35.82,52.09 36.2,52.46 36.2,53.15 v2(36.96,53.92) ; v2(21.46,35.07) 22.48,34.05 23.1,34.05 23.1,34.05 23.63,34.05 24,33.68 24,33.4 26.92,30.49 27.32,30.49 27.36,30.45 31.17,30.45 v2(32.64,28.97) 32.26,28.59 32.26,26.09 34.46,23.89 34.46,23 35.31,22.14 35.31,20.08 39.85,15.54 v3(40.13,15.54) ; v3(42.16,15.51) 42.88,16.22 48.94,16.22 50.28,14.88 52.96,14.88 v2(53.15,14.69)
  BOTTOM w0.127: U7201.H1 13.85,82.17 13.33,82.7 v2(13.08,82.7)
  BOTTOM w0.178: U7201.B1 13.97,78.37 v2(13.97,78)
  BOTTOM w0.254: v2(153.03,22.88) 153.03,23.44 153.34,23.74 PU5101.15 ; Q2416.2 Q2416.5 123.57,11.04 123.32,11.3 v2(123.32,14.24) ; v2(21.46,35.07) 21.46,33.93 20.83,33.29 R2416.2 20.88,32.91 21.69,32.91 G5701.2
  BOTTOM w0.305: PR5302.1 v2(35.89,18.08) ; v2(181.61,59.96) 181.03,59.38 PR5208.1 ; U4008.5 157.1,62.97 157.45,63.33 R4004.1 ; Q6502.S 129.22,11.56 C6502.1 ; v2(90.42,24.66) 90.78,25.01 R2496.2 ; v2(108.9,4.72) 108.58,5.03 108.58,7.77 R2406.2
  BOTTOM w0.381: v2(13.08,82.7) 12.83,82.7 12.19,83.33 C7208.1 ; R7243.1 R7224.1 11.35,77.64 11.71,77.28 13.4,77.28 13.97,77.86 v2(13.97,78) ; PR4479.1 PR4486.2 ; U4008.5 157.54,61.74 v2(158.04,61.74) ; v2(153.03,22.88) 153.03,22.67 151.97,21.61 PC5110.1 ; v2(28.83,37.1) 28.91,37.18 PR4450.2 29.79,37.13 PR4472.1
  BOTTOM w0.406: v2(162.34,25.86) 161.91,25.43 ED4305.2 161.91,24.22 ED4306.2 ED4304.2
  BOTTOM w0.508: v2(125.02,62.07) 125.48,62.53 R1703.1 ; v2(67.18,55.39) 67.31,55.26 77.72,55.26 82.42,59.96 R506.1 ; v2(32.64,28.97) 32.38,28.72 PR4486.2 ; v2(163.13,75.23) 163.08,75.28 R4031.1 ; v2(145.93,70.9) 144.83,72 FC8943.1 143.81,72.15 R1910.1 ; v2(53.15,14.69) 52.86,14.98 R4304.1 52.3,14.6 50.21,12.51 D4302.2 ; v2(36.96,53.92) 37.26,53.92 37.59,54.25 37.59,55.64 37.08,56.16 R4378.1 35.14,56.16 34.67,55.68 U4302.2 ; v2(96.27,24.66) 96.27,24.1 R2456.2 ; v2(154.7,55.51) 154.69,55.49 154.69,56.53 155.87,57.72 156.21,57.72 156.21,57.75 156.59,58.13 R4042.1 ; Q6502.S v2(129.22,9.89)
  vias: v1(42.11,13.84) v1(42.85,15.18) v1(107.65,21.58) v1(110.54,20.34) v1(126.39,105.25) v1(129.13,12.92) v1(137.62,19.42) v1(160.4,11.93) v1(169.9,34.46) v1(189.66,36.01) v2(80.21,15.13) v2(133.1,16.15) v2(133.73,16.15) v2(154.69,72.82) v2(154.69,71.27) v2(165.74,52.34) v2(166.73,42.79) v2(168.15,35.07) v2(168.15,34.44) v2(168.78,35.07) v2(168.78,34.44) v3(37.08,3.83) v3(41.1,15.51) v3(108.71,22.75) v3(108.71,21.86) v3(109.6,22.75) v3(109.6,21.86) v3(110.49,22.75) v3(110.49,21.86) v3(156.46,98.57) v3(157.1,97.94) v3(157.61,97.17) v3(157.73,96.16)
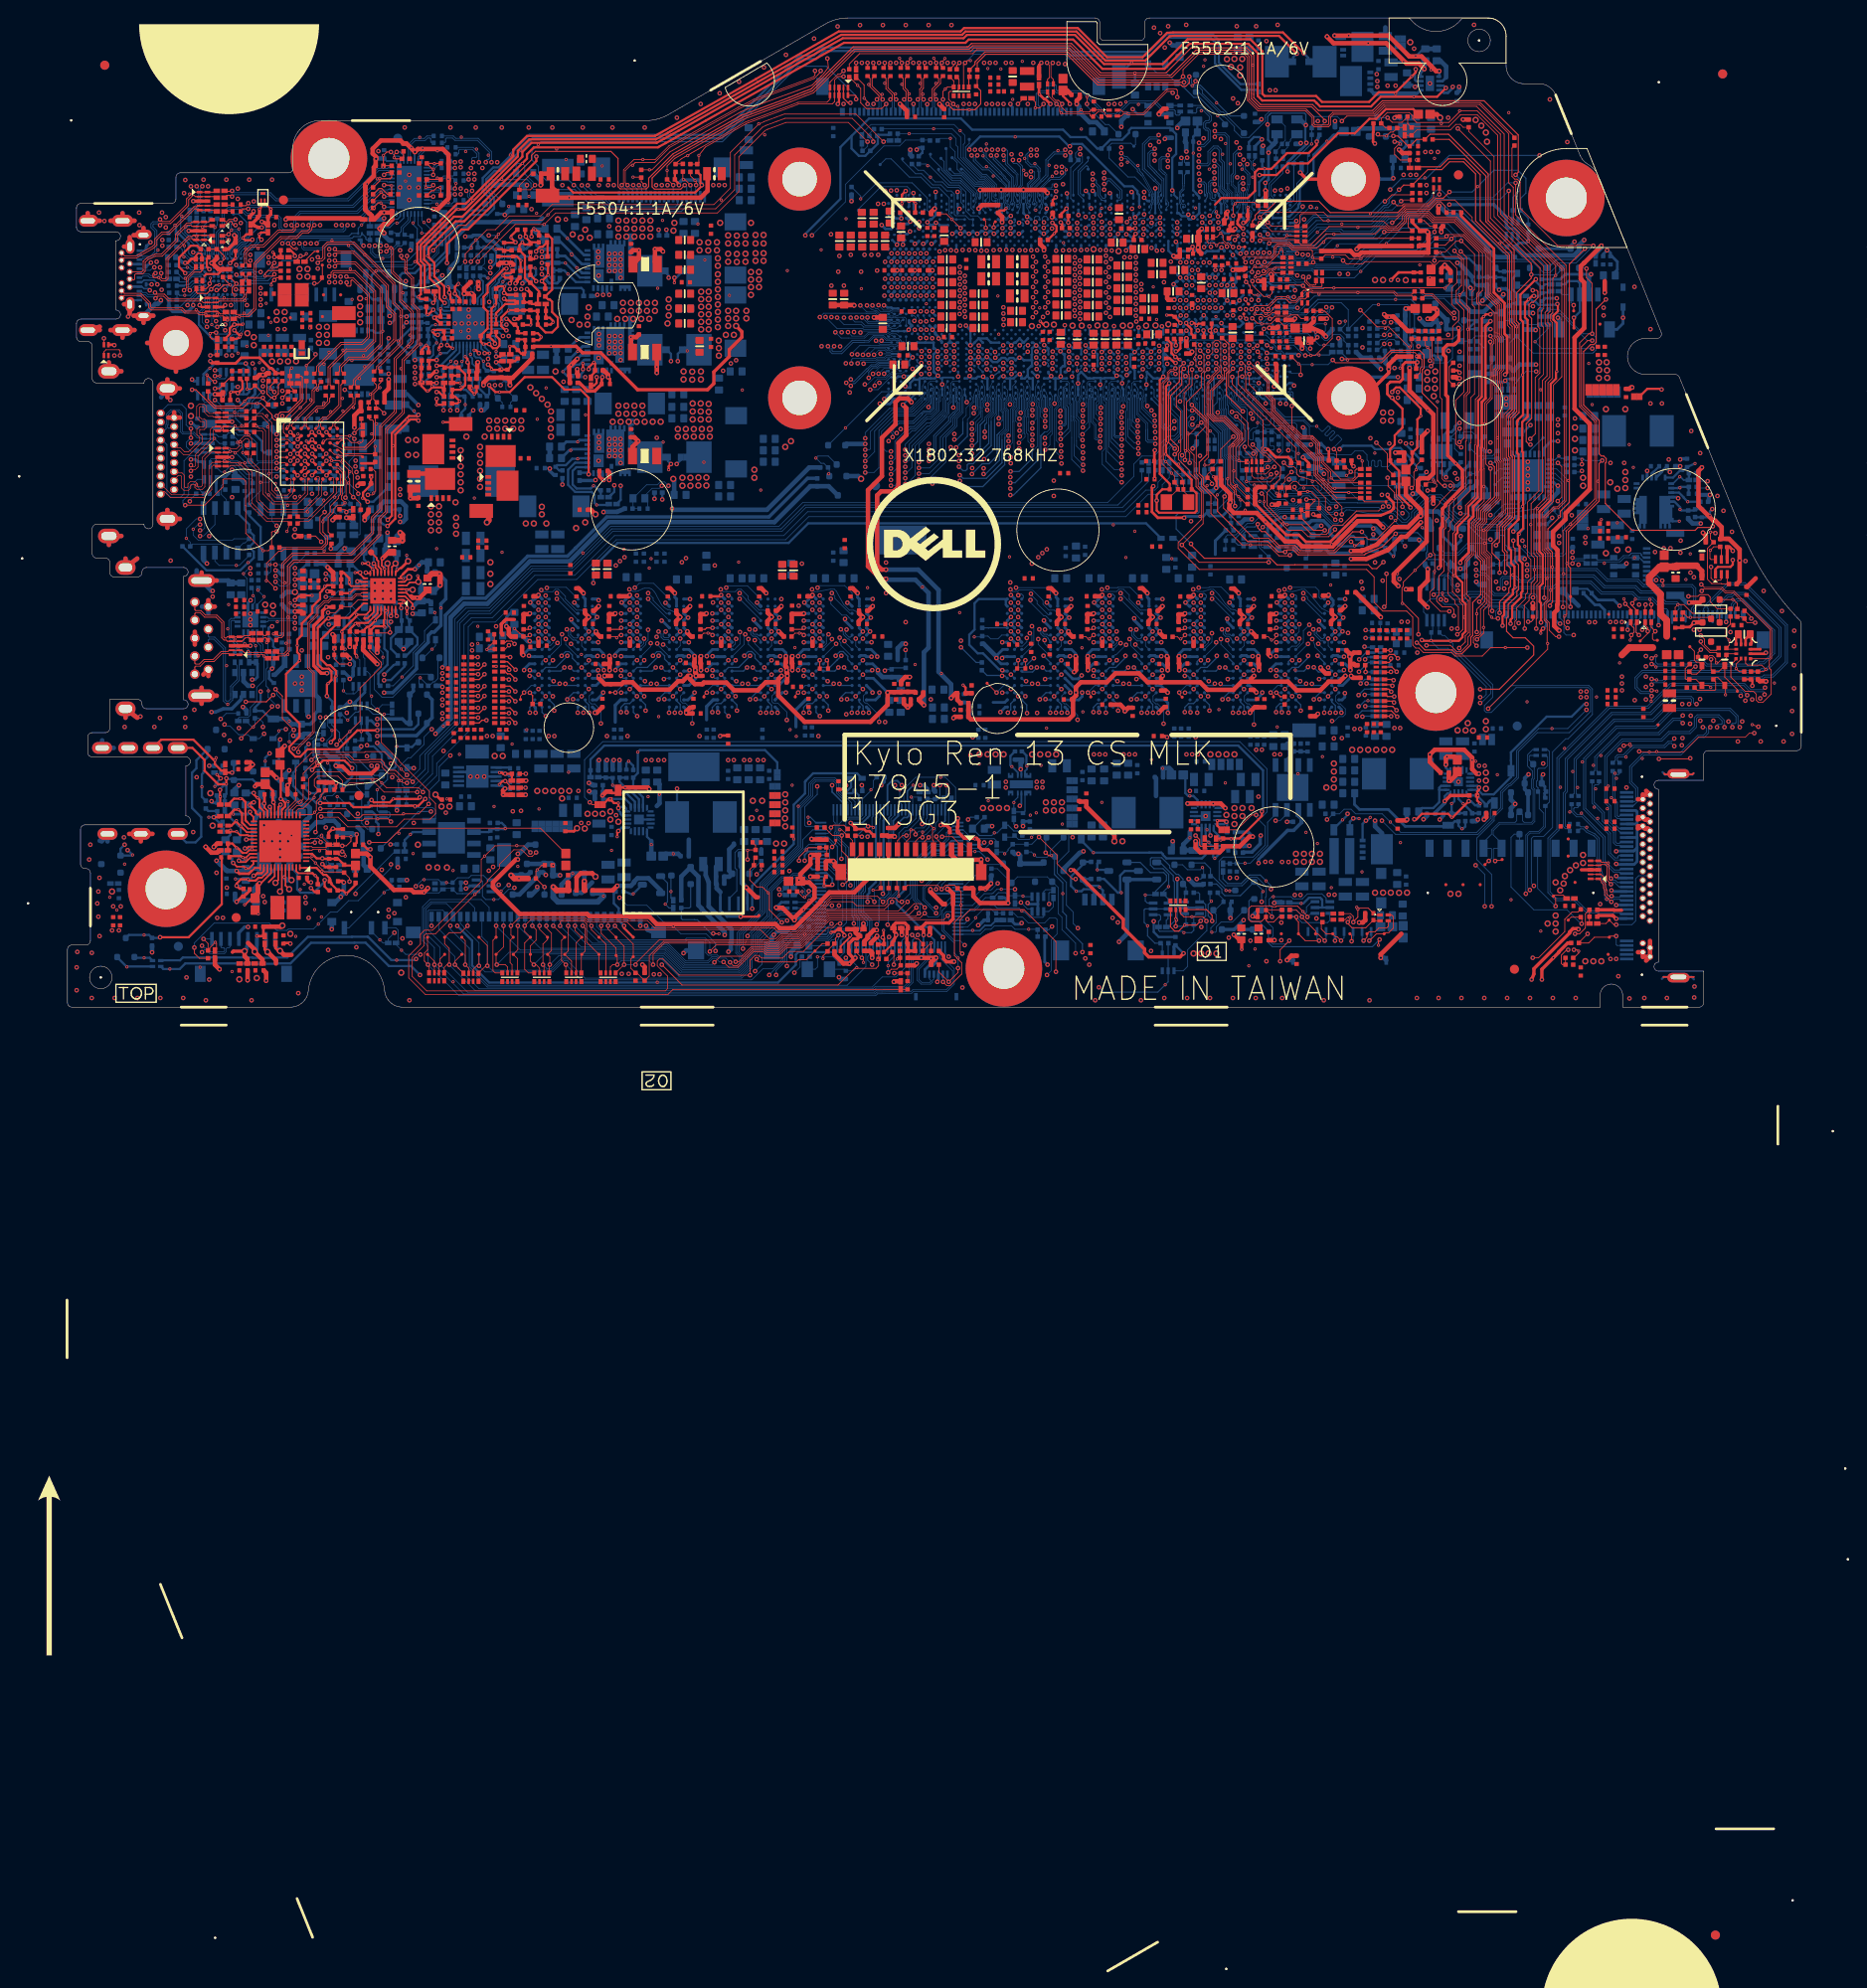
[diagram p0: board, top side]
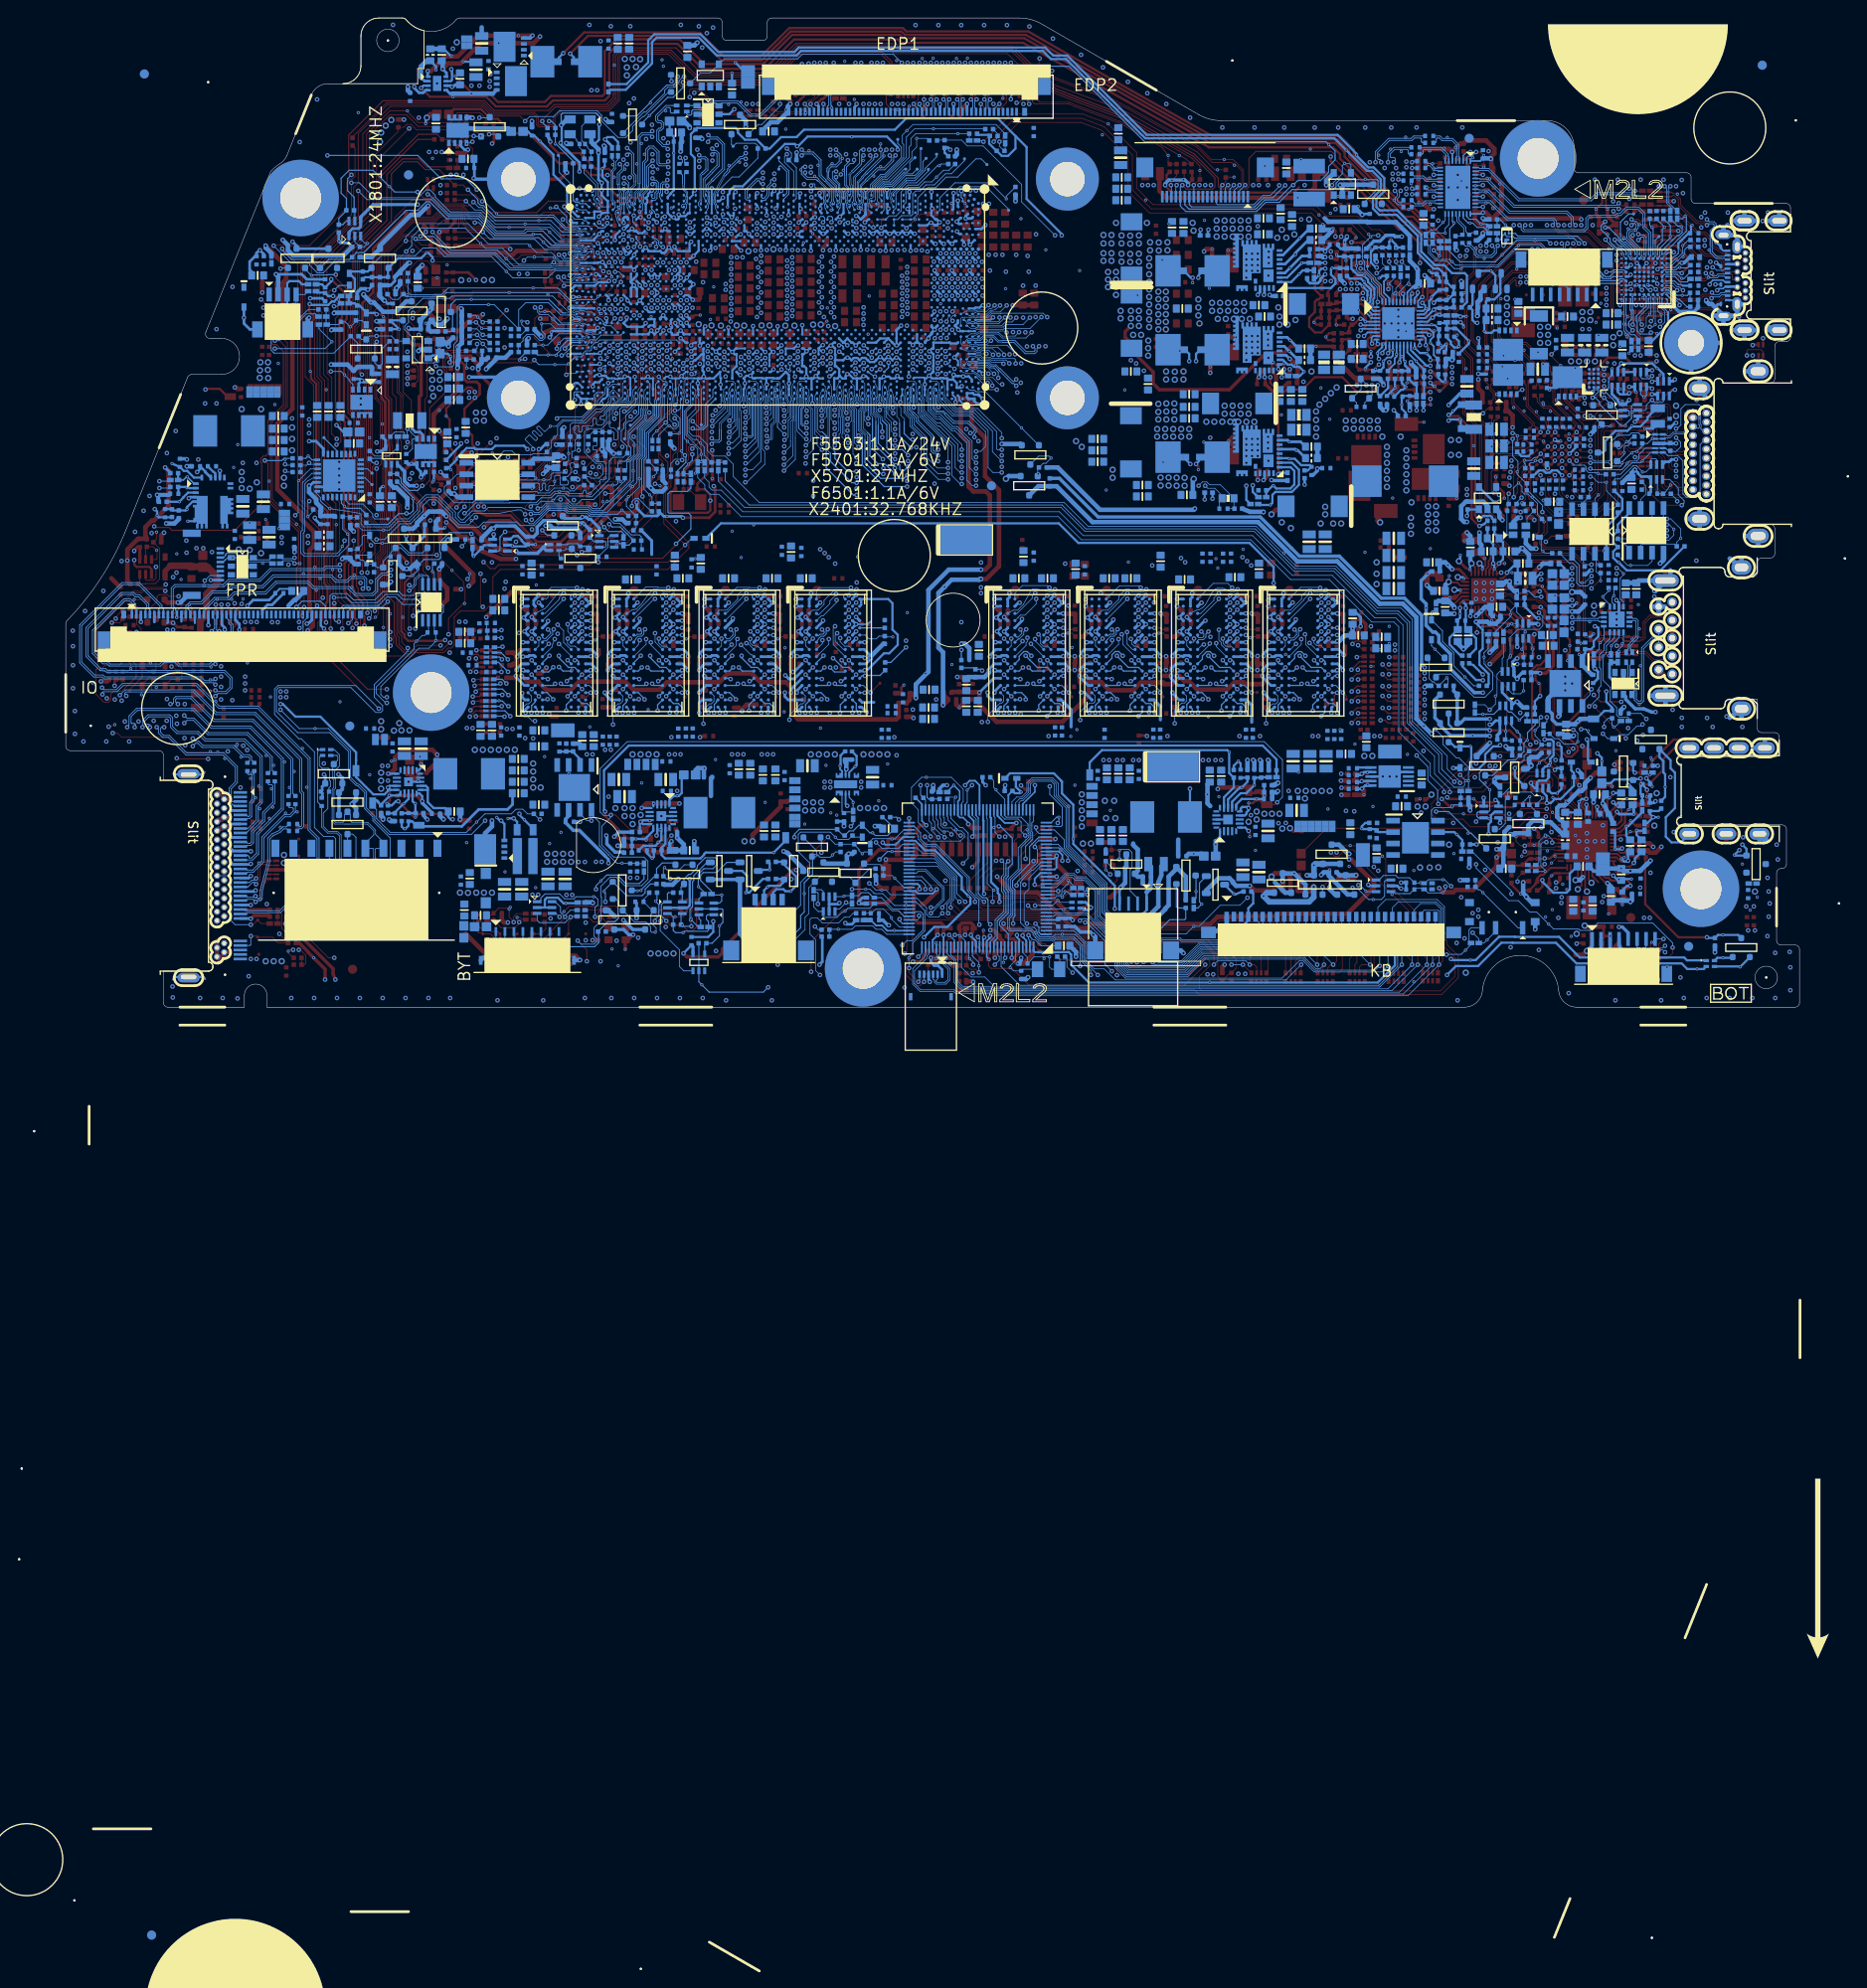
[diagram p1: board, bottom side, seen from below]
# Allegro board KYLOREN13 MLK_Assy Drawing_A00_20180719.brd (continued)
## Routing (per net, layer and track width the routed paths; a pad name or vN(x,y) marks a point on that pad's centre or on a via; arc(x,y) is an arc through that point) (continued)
3D3V_S5_KBC: length 438.6
  TOP w0.305: R2415.2 87.58,19.78 88.51,19.78 88.74,19.55 89.1,19.55 C2411.1
  TOP w0.381: v2(104.52,11.56) 104.52,15.26 102.3,17.48 101.62,17.48 101.28,17.82 101.28,18.5 101.02,18.76 99.64,18.76 C2414.1 98.88,19.53 98.88,20.02 98.93,20.07 v2(98.93,20.98) ; R2415.2 87.55,19.96 87.05,20.46 v2(87.02,20.46) ; C2420.1 98.4,9.8 97.96,9.35 95.4,9.35 94.92,8.87 C2412.1 ; v2(95.12,8.02) 95.12,8.58 C2412.1 ; C2412.1 C2422.1
  TOP w0.508: 80.77,9.7 80.77,9.92 83.01,12.16 83.01,13.28 82.42,13.86 81.56,13.86 R2446.2 81.43,14.78 82.55,15.89 v2(82.55,16.81) 82.65,16.91 R2424.1 83.36,16.76 C2429.1 C2410.1 ; 80.77,9.7 79.44,11.04 78.77,11.04 v2(78.74,11.07) ; 80.77,9.7 v2(80.77,9.67) ; R2443.1 v2(94.87,5.48) 96.47,5.48 ; v2(89.95,7.92) 89.95,7.82 89.28,7.16 C2413.1 ; v2(104.52,11.56) 101.41,11.56 100.66,12.31 100.66,13.12 100.56,13.23 100.53,13.2 EC2402.1 R2480.1 ; v2(96.52,5.48) 96.47,5.48 ; 96.47,5.48 95.96,4.97 R2414.1 ; v2(97.76,13.12) 97.79,13.12 97.81,13.1 97.89,13.1 98.4,12.59 C2420.1
  L3SGND w0.508: v2(97.76,13.12) 98.68,13.12 99.19,12.61 99.19,9.16 98.68,8.65 95.49,8.65 95.12,8.28 v2(95.12,8.02) 95.12,7.26 96.27,6.11 96.27,5.48 v2(96.52,5.48) ; v2(41.78,28.47) 41.78,27.7 42.38,27.1 48.93,27.1 51.31,29.48 100.19,29.48 100.32,29.36 100.85,29.36 101.61,30.12 114.94,30.12 116.2,28.85 116.2,27.58 115.52,26.89 115.52,16.84 112.16,13.48 108.58,13.48 v2(106.68,11.58) 106.68,11.46 106.21,10.99 105.09,10.99 v2(104.52,11.56) ; v2(80.77,9.67) 83.31,7.13 89.15,7.13 v2(89.95,7.92) 89.95,7.23 90.68,6.5 93.85,6.5 v2(94.87,5.48) ; v2(162.84,77.11) 167.44,72.51 171.11,72.51 171.14,72.48 171.43,72.48 171.86,72.05 171.86,71.17 171.96,70.92 171.96,69.11 173.1,67.96 177.67,67.96 179.45,66.19 179.45,63.77 180.42,62.81 180.42,55.82 182.18,54.06 182.18,53.16 182.37,52.97 182.37,52.46 182.25,52.33 182.25,51.58 178.56,47.9 178.56,31.01 173.81,26.25 173.81,25.49 173.85,25.27 173.86,25.24 173.86,18.19 172.32,16.66 171.44,16.66 168.09,13.31 168.09,11.25 169.54,9.8 169.54,7.63 163.59,1.67 115.82,1.67 115.55,1.4 113.93,1.4 113.7,1.16 97.16,1.16 95.89,2.43 95,2.43 94.49,1.92
  L4SGND w0.508: v2(82.55,16.81) 82.04,17.32 82.04,18.95 83.9,20.81 86.58,20.81 86.9,20.49 87,20.49 v2(87.02,20.46) ; v2(97.76,13.12) 98.3,12.59 99.53,12.59 100.59,11.52 104.48,11.52 v2(104.52,11.56) ; v2(41.78,28.47) 41.65,28.47 39.78,30.34 39.78,37.53 57.73,55.49 59.08,55.49 v2(59.56,55.01)
  BOTTOM w0.178: v1(90.04,5.29) 90.31,5.56 U2401.115
  BOTTOM w0.203: U2401.19 82.77,15.29 82.55,15.51 82.55,16.78 ; U2401.43 89.11,21.25 88.91,21.05 88.9,21.05 88.31,20.46 v2(87.02,20.46) ; v2(97.76,13.12) 97.76,13.47 97.99,13.69 U2401.82 ; 82.55,16.78 82.84,16.49 U2401.22 ; 82.55,16.78 v2(82.55,16.81) ; U2401.115 90.31,7.33 89.95,7.7 v2(89.95,7.92) ; U2401.5 82.47,9.69 R2407.2 ; v2(94.87,5.48) 94.91,5.48 95.11,5.68 U2401.103 95.11,8.01 v2(95.12,8.02) ; v2(98.93,20.98) U2401.65
  BOTTOM w0.305: RN2402.1 79.68,11 79.49,10.8 79,10.8 78.77,11.04 78.72,11.04 78.74,11.06 ; RN2413.2 104.31,11.49 104.38,11.56 v2(104.52,11.56) 104.52,11.77 104.12,12.16 RN2413.1 ; v2(78.74,11.07) 78.74,11.06 ; 78.74,11.06 79.33,11.65 RN2402.2 ; DB3.1 95.27,4.15 95.73,4.62 96.16,4.62 96.52,4.97 v2(96.52,5.48) ; v2(106.68,11.58) 106.81,11.45 107.82,11.45 ; Q2417.2 107.82,11.45 ; 107.82,11.45 Q2417.5
  BOTTOM w0.381: R2407.2 82.3,9.87 EC2403.1 80.98,9.87 v2(80.77,9.67)
  BOTTOM w0.508: v2(162.84,77.11) 162.79,77.16 R4032.1 ; v2(59.56,55.01) 59.59,55.03 61.07,55.03 R2608.1
  vias: v1(42.85,2.81) v1(65.53,2.76) v2(65.15,3.65) v2(65.79,3.65)
3D3V_S5_PCH: length 350.1
  TOP w0.254: v2(154.69,70.5) 154.46,70.73 R1526.1
  TOP w0.305: R1801.2 137.92,60.45 v2(137.29,61.09) ; v2(140.08,61.99) 140.16,61.92 R1510.1
  TOP w0.508: v2(139.83,74.52) 139.35,75 138.28,75.44 R1103.1 138.46,76.16 R1522.1
  L3SGND w0.305: v2(177.37,50.98) 177.37,51.38 177.29,51.45 177.29,52.55 176.99,52.85 171.46,52.85 166.18,58.13 166.18,65.73 165.65,66.26 164.69,66.26 157.27,73.69 153.2,73.69 152.94,73.42
  L3SGND w0.381: 152.35,73.86 152.35,74.92 153.49,76.07 153.49,77.38 153.83,77.72 154.6,77.72 156.53,79.64 156.53,80.41 155.96,80.98 153.56,80.98 152.46,82.08 152.46,83.91 150.77,85.61 150.56,85.83 150.56,86.57 151.64,87.65 152.76,87.65 152.82,87.71 164.81,87.71 165.4,87.12 166.65,87.12 v2(168.53,85.24)
  L3SGND w0.508: v2(154.69,70.5) 154.18,70.5 154.05,70.38 152.83,71.6 152.83,73.31 152.94,73.42 v2(150.11,73.42) 149.22,73.42 148.59,72.79 146.31,72.79 144.58,74.52 141.92,74.52 141.49,74.95 140.96,74.95 140.53,74.52 v2(139.83,74.52)
  L4SGND w0.305: v2(160.66,52.85) 162.56,52.85 164.36,51.05 165.96,51.05 166.01,51.1 167.45,51.1 168.74,49.8 172.98,49.8 173.01,49.83 176.63,49.83 176.94,50.13 176.94,50.67 177.24,50.97 177.35,50.97 v2(177.37,50.98) 177.62,50.73 177.62,48.72 180.16,46.18 180.33,46.18 180.65,45.87 180.65,45.64 181.2,45.08 181.27,45.08 183.39,42.96 183.39,40.2 184.3,39.29 184.3,37.97 182.64,36.31 180.16,36.31 174.68,30.83 172.25,30.83 170.19,28.77 170.19,23.36 160.89,14.06 143.15,14.06 139.73,10.64 133.05,10.64 132.56,11.12 129,11.12 128.26,10.37 118.43,10.37 117.67,11.13 111.11,11.13 110.08,12.16 105.72,12.16 105.05,11.49 105.05,11.34 104.7,10.99 100.37,10.99 99.76,11.6 94,11.6 93.16,10.76 88.09,10.76 85.89,8.55 85.22,8.55 84.16,7.49 76.73,7.49 76.1,8.12 76.1,8.13 75.79,8.44 74.23,8.44 73.83,8.84 69.27,8.84 66.64,6.22 40.36,6.22 38.96,4.82 38.51,4.82 38,5.33 38,6.27 39.24,7.51 43.68,7.51 44.98,8.81 44.98,9.26 43.81,10.43 40.51,10.43 37.72,13.23 v2(37.72,14.12)
  BOTTOM w0.305: R2519.1 139.35,62.55 139.91,61.99 v2(140.08,61.99) ; R406.1 161.28,84.92 162.12,84.92 v1(162.31,85.11) 162.27,85.15 162.31,85.18 R405.1 ; R303.1 131.72,61.54 v2(131.77,61.49)
  BOTTOM w0.508: v2(160.66,52.85) 161.03,53.22 161.04,53.22 R9148.1 ; R1502.1 140.54,75.23 v2(139.83,74.52) ; R1554.1 150.11,73.88 v2(150.11,73.42) 150.62,73.93 R2516.2 ; v2(137.29,61.09) 137.46,61.26 C2501.1 138.51,60.93 C2502.1 140.62,60.93 141.07,60.48 BIOS1.8 ; R406.1 161.78,83.52 167.39,83.52 167.96,84.1 167.96,84.67 v2(168.53,85.24) ; v2(131.77,61.49) 132.37,62.05 132.38,62.18 132.38,62.89 R1506.1 ; R1508.1 v2(138.18,62.5) ; R9805.1 v2(37.72,14.12)
  vias: v2(137.41,87.53) v2(141.35,81.48) v2(142.28,81.46)
3D3V_SEN_S0:
  vias: v1(59.41,93.46) v2(59.05,91.33)
3D3V_SSD: length 13.2
  TOP w0.381: 172.68,10.77 171.85,10.77 171.81,10.81 R6303.1
  TOP w0.508: 175.04,23.63 SSD1.4 174.51,23.1 ; SSD1.18 175.6,19.84 175.3,19.84 SSD1.16 ; SSD1.12 175.3,20.84 175.6,20.84 SSD1.14 ; SSD1.12 174.49,20.85 ; SSD1.12 174.51,21.1 ; 175.84,7.36 SSD1.70 SSD1.74 ; 175.04,5.57 SSD1.72 174.51,6.1 ; 175.41,5.17 SSD1.74 ; SSD1.74 175.31,5.6 ; SSD1.16 174.49,19.85 ; SSD1.16 174.51,20.1 ; 175.31,23.6 SSD1.2 175.41,24.03
  vias: v1(171.96,25.98) v3(168.66,5.1) v3(169.54,5.1) v3(170.43,5.1)
3D3V_TBT: length 2.1
  TOP w0.254: C7210.1 15.49,83.15 15.49,82.26 v2(15.77,81.98)
  BOTTOM w0.127: v2(15.77,81.98) 15.58,82.17 U7201.H2
3D3V_TP_VDD: length 6.9
  L4SGND w0.381: v2(134.87,9.39) 138.31,9.39 v2(138.78,9.86)
  BOTTOM w0.381: Q6502.D 129.64,8.63 v2(130.68,9.67)
  vias: v2(134.87,7.43)
3D3V_TPAN_VDD:
  vias: v1(72.64,89.68) v2(72.39,91.33) v2(73.03,91.33)
3D3V_TPM_VHIO: length 16.5
  L4SGND w1.016: v2(158.12,62.73) 158.78,62.73 160.03,61.47 162.78,61.47 165.61,58.64 v2(165.61,57.93)
  BOTTOM w0.305: v2(165.61,57.93) 165.52,57.93 165.14,58.31 U9102.22
  BOTTOM w0.508: v2(165.61,57.93) 165.61,57.21 164.82,56.41 164.82,56.04 164.29,55.51 R9149.2 164.29,55.11 164.34,55.06 C9113.1 164.34,54.58 C9112.1 162.81,54.58 R9140.1
  vias: v1(158.9,63.26) v1(162.59,53.61)
3D3V_TPM_VSB: length 1.2
  BOTTOM w0.254: C9106.1 157.73,57.6 157.48,57.85 v1(157.38,57.85)
3D3V_VCCDSW: length 84.4
  TOP w0.254: v2(147.19,67.71) 147.32,67.58 147.32,67.5 148.34,66.48 148.34,64.38 147.47,63.52 147.47,62.51 146.96,62 146.96,60.75 C2224.1 146.99,60.55 147.96,59.58 147.96,56.87 149.22,55.6 v2(149.22,55.52) ; v2(138.43,54.76) 138.61,54.58 R1524.1 ; v2(124.31,76.02) 124.31,75.91 124.88,75.34 124.88,74.8 R1707.1
  TOP w0.305: v2(147.19,67.71) 147.07,67.71 146.66,68.12 146.66,69.15 146.98,69.47 148.05,69.47 148.36,69.78 148.36,71.34 148.67,71.65 v2(149.99,71.65) 149.86,71.52 R1519.1
  L4SGND w0.254: v2(147.19,67.71) 146.43,67.71 143.76,70.38 137.59,70.38 137.23,70.74 137.2,70.74 133.41,74.53 132.22,74.53 132.06,74.69 125.41,74.69 125.09,75.01 125.09,75.12 124.31,75.89 v2(124.31,76.02) ; v2(138.43,54.76) 138.43,55.57 139.45,56.58 145.3,56.58 145.73,56.15 145.75,56.15 145.77,56.14 148.6,56.14 v2(149.22,55.52)
  L6 w0.254: v2(125.83,61.26) 126.1,61.26 129.14,58.21 129.14,57.71 131.59,55.26 132.01,55.26 133.33,53.94 137.62,53.94 v2(138.43,54.76)
  BOTTOM w0.254: 124.29,76 v2(124.31,76.02) ; 124.29,76 124.15,75.86 124.15,75.82 123.99,75.66 CPU1.BR24 ; 124.29,76 124.29,76.09 CPU1.BT23 ; U2502.1 152.2,72.1 151.89,72.41 151.24,72.41 R2516.1 150.21,72.6 149.91,72.31 v1(149.89,72.31) 149.89,71.75 v2(149.99,71.65)
3D3V_VCCPRIM: length 64.2
  TOP w0.305: v2(159.74,70.28) 159.97,70.51 159.97,74.52 159.68,74.81 159.68,78.22 158.5,79.4 158.5,84.27 154.86,87.9 R1701.1
  L4SGND w0.254: v2(159.74,70.28) 159.39,70.28 158.86,69.74 158.86,69.39 159.11,69.13 159.52,69.13 159.55,69.1 159.97,69.1 160,69.13 161.8,69.13 162.15,68.77 162.15,66.33 161.34,65.52 151.38,65.52 148.06,68.85 146.81,68.85 144.4,71.27 137.79,71.27 136.8,72.26 v2(136.8,72.43)
  L6 w0.305: v2(128.23,80.23) 128.23,80.22 128.21,80.2 128.21,78.42 128.82,77.81 128.82,76.93 128.87,76.88 v2(128.87,76.86)
  BOTTOM w0.254: v2(136.8,72.43) 136.63,72.43 136.46,72.6 CPU1.CP29
  BOTTOM w0.305: CPU1.BW23 126.59,76.54 v2(126.26,76.87) 126.26,76.81 125.94,76.49 CPU1.BV23 ; CPU1.CB16 128.24,80.33 128.24,80.24 v2(128.23,80.23) ; v2(123.7,76.86) 123.34,76.49 CPU1.BP23 ; v2(124.3,77.67) 124.3,77.78 CPU1.BT20
  vias: v1(127.61,76.73) v2(129.51,76.86)
3D3V_VCCPRTC: length 38.8
  TOP w0.254: R2204.2 149.43,60.44 C2221.1 C2222.1 149.99,62.17 149.99,65.3 v1(150.37,65.68) 150.37,66.52 148.04,68.85 147.62,68.85 147.19,68.43 v2(147.19,68.34)
  L4SGND w0.254: v2(124.32,76.84) 124.81,76.84 125.93,75.72 127.72,75.72 128.12,75.31 131.92,75.31 132.36,74.87 133.55,74.87 137.34,71.08 137.37,71.08 137.69,70.76 144.02,70.76 146.43,68.34 v2(147.19,68.34)
  BOTTOM w0.254: v2(124.32,76.84) 124.32,76.77 CPU1.BR23
3D3V_WLAN: length 2.4
  BOTTOM w0.508: C6104.1 166.22,46.14 167.13,45.23 167.26,45.23 167.89,44.6
  vias: v2(169.09,42.77) v2(169.72,42.77) v2(180.72,41.93) v2(181.36,41.93)
65982D_BUSPWR: length 8.2
  TOP w0.254: v1(22.83,83.87) 22.99,83.7 v2(22.99,83.33) R7236.1 R7204.2
  L6 w0.254: v2(22.99,83.33) 22.99,83.41 22.56,83.84 22.14,83.84 19.68,81.37 v2(18.77,81.37)
  BOTTOM w0.254: U7201.F10 18.97,81.17 v2(18.77,81.37)
65982D_DBG_CTL1: length 2.4
  TOP w0.127: RN7202.2 15.43,79.84 15.8,80.21 v2(15.8,80.38) 15.88,80.46 v1(15.88,80.99)
  BOTTOM w0.127: U7201.E4 16.09,80.67 v2(15.8,80.38)
65982D_DBG_CTL2: length 4.4
  TOP w0.127: RN7202.1 14.32,79.42 14.45,79.29 15.51,79.29 v2(15.97,79.75) 15.98,79.75 16.48,80.26 v1(16.87,80.26)
  BOTTOM w0.127: v2(15.97,79.75) 16.39,80.17 U7201.D5
65982D_DEBUG1: length 5.7
  BOTTOM w0.127: R7220.2 13.51,86.76 13.19,86.76 v1(13.15,86.71) 13.04,86.61 13.04,86.08 13.38,85.74 13.59,85.74 15.27,84.06 U7201.L2
65982D_DEBUG2: length 6.9
  BOTTOM w0.089: U7201.K2 15.05,83.39 15.05,83.74 15.03,83.75
  BOTTOM w0.127: R7221.2 13,87.6 v1(12.7,87.9) 12.57,87.78 12.57,86.21 15.03,83.75
65982D_DIG_AUD_N: length 5.3
  BOTTOM w0.127: U7201.K3 15.52,83.42 15.52,84.32 14.35,85.49 v1(14.35,85.62) 14.35,86.84 R7241.2
65982D_DIG_AUD_P: length 4.6
  BOTTOM w0.127: U7201.L3 15.77,84.58 15.24,85.11 15.24,86.43 v1(15,86.67) 15.88,87.55 R7242.2
65982D_GND: length 2.3
  TOP w0.254: C7212.2 v1(18.67,83.2) 18.53,83.07 18.49,83.07 18.08,82.67 v2(18.07,82.67)
  BOTTOM w0.254: U7201.H7 17.77,82.37 v2(18.07,82.67)
65982D_GPIO2: length 3.2
  TOP w0.127: v1(18.58,79.1) 18.58,79.12 18.3,79.41 18.3,79.92 18.76,80.38 v2(18.77,80.38) 18.03,81.11 R7231.2
  BOTTOM w0.127: v2(18.77,80.38) 18.97,80.17 U7201.D10
65982D_GPIO3: length 5.9
  TOP w0.127: v2(22.99,82.7) 22.73,82.44 v1(22.73,82.19) 23.32,82.19 R7208.2
  BOTTOM w0.127: U7201.G11 20.58,81.67 21.08,81.17 21.59,81.17 22.99,82.57 v2(22.99,82.7)
65982D_GPIO5: length 7.5
  TOP w0.127: R7213.2 23.66,81.84 22.31,81.84 21.95,81.48 v1(21.95,81.22) 22.78,81.22 v2(22.99,81.43)
  BOTTOM w0.127: v2(22.99,81.43) 22.28,80.71 20.2,80.71 19.99,80.92 19.52,80.92 U7201.E10
65982D_GPIO8: length 3.6
  TOP w0.127: v2(16.99,82.66) 17.4,83.07 v1(17.4,83.2) 17.4,83.47 16.65,84.22 R7223.1 R7222.2
  BOTTOM w0.127: v2(16.99,82.66) 17.27,82.38 U7201.H6
65982D_HPD_CON: length 25.1
  L6 w0.127: v2(18.72,79.75) 18.77,79.75 21.27,82.25 24.57,82.25 24.89,82.57 25.78,82.57 27.69,84.47 v2(27.69,84.85)
  BOTTOM w0.127: v2(27.69,84.85) 28.04,85.21 31.42,85.21 v1(33.03,83.59) 33.82,82.81 37.71,82.81 39.07,84.17 R7227.2 ; U7201.C10 18.8,79.67 v2(18.72,79.75)
65982D_HRESET: length 3.9
  TOP w0.127: R7202.1 17.27,81.04 v1(18.08,80.23) 17.35,80.23 16.78,79.67 v2(16.57,79.67)
  BOTTOM w0.127: U7201.D6 16.77,79.67 v2(16.57,79.67)
65982D_I2C_ADDR: length 3
  BOTTOM w0.127: R7201.2 12.46,80.57 13.25,80.57 13.84,81.17 U7201.F1
65982D_LDO_1V8A: length 5.4
  BOTTOM w0.127: 13.46,84.35 13.46,83.76 13.77,83.46 13.89,83.46 14.18,83.17 U7201.K1
  BOTTOM w0.254: v1(11.94,86.89) 12.06,86.76 12.06,86.07 C7203.2 12.32,86 13.46,84.85 13.46,84.35
65982D_LDO_1V8D: length 6
  BOTTOM w0.127: U7201.A2 15.27,77.88 14.61,77.21
  BOTTOM w0.254: C7202.2 16.31,74.08 14.78,75.61 14.78,75.63 14.61,75.81 14.61,77.21
65982D_LDO_BMC: length 2.8
  BOTTOM w0.127: 12.98,80.16 13.11,80.28 13.48,80.28 13.87,80.67 U7201.E1
  BOTTOM w0.254: C7201.2 12.98,80.16
65982D_LSRX: length 2.7
  BOTTOM w0.127: TP7202.1 16.03,85.21 16.03,83.42 U7201.K4
65982D_LSTX: length 4.1
  BOTTOM w0.127: U7201.L4 16.27,86.52 v1(16.38,86.63) 16.64,86.89 R7237.2
65982D_MRESET: length 5
  TOP w0.127: R7214.2 23.24,81.04 v2(22.99,80.79) 22.65,80.45 v1(22.65,80.22)
  BOTTOM w0.127: v2(22.99,80.79) 22.61,80.41 20.03,80.41 U7201.E11
65982D_RESET_N: length 8.8
  TOP w0.127: v1(26.54,83.71) 26.29,83.46 v2(25.91,83.46) 25.48,83.03 R7229.1
  BOTTOM w0.127: v2(25.91,83.46) 25.4,82.95 23.88,82.95 21.87,80.94 21.01,80.94 20.78,81.17 U7201.F11
65982D_ROSC: length 3.5
  BOTTOM w0.127: R7206.1 12.42,82.14 13.26,82.14 v1(13.31,82.19) 13.36,82.14 13.51,82.14 13.74,81.91 15.03,81.91 U7201.G2
65982D_SBU1_R: length 3
  BOTTOM w0.127: U7201.K8 18.03,83.41 18.03,84.04 19.36,85.36 TP7203.1
65982D_SBU2_R: length 6.3
  BOTTOM w0.127: TP7204.1 18.99,88.13 19.6,87.52 19.61,87.52 19.9,87.23 19.9,85.22 19.89,85.21 19.89,85.18 19.71,85.01 19.33,85.01 18.27,83.95 U7201.L8
65982D_UART_RX: length 4.3
  BOTTOM w0.127: U7201.E2 U7201.F2 15.03,81.41 13.58,81.41 13.13,80.97 v1(13.08,80.97) 13.04,80.93 12.86,80.93 R7244.2
+DC_IN: length 19.9
  TOP w0.508: v2(32.23,57.93) 32.46,58.16 32.84,58.16 R4376.1
  L6 w0.381: v2(32.23,57.93) 32.21,57.96 31.98,57.96 31.31,58.63 31.31,67.39 31.47,67.56 31.47,75.05 v3(32.51,76.09)
  vias: v1(31.62,78.63) v1(33.17,78.71) v3(32.51,78.76) v3(32.51,77.87) v3(32.51,76.98)
+DC_IN_C:
  vias: v1(26.92,75.46) v3(27.94,75.58) v3(27.94,74.69) v3(28.83,75.58) v3(28.83,74.69)
+RTC_VCC: length 54.5
  TOP w0.381: v2(152.37,48.81) 152.57,49.01 152.57,53.19 152.78,53.4 152.78,55.37 153.11,55.7 153.11,55.86 155,57.75 155,58.82 154.99,58.83 154.99,59.68 v1(154.25,60.42) 153.37,61.31 153.37,67.81 153.16,68.02 153.16,72.25 152.89,72.52 152.89,73.15 153.33,73.6 154.07,73.6 154.21,73.73 154.23,73.73 154.61,74.11 154.61,75.4 v2(154.56,75.46)
  L4SGND w0.381: v2(152.37,48.81) 153.05,48.14 155.03,48.14 155.97,47.2 155.97,47.03 156.78,46.22 157.15,46.22 157.9,45.47 157.9,44.55 157.73,44.38 157.73,43.3 159.56,41.48 164.4,41.48 165.51,42.59 165.84,42.59 v2(165.85,42.61)
  BOTTOM w0.305: v2(165.85,42.61) 165.71,42.61 165.3,43.02 IOBD1.41
  BOTTOM w0.381: R2504.1 154.43,75.33 v2(154.56,75.46)
  BOTTOM w0.508: R2504.1 153.21,76.24 D2501.2 152,77.58 Q2505.G
+SDC_IN: length 65.8
  TOP w0.203: v2(33.15,48.28) 33.22,48.2 PU4401.16
  TOP w0.457: v2(29.82,26.82) 29.87,26.76 30.52,26.76 31.33,25.95 33.78,25.95 34.42,26.59 v2(34.42,26.82)
  L4SGND w0.381: v2(38.99,66.9) 36.39,64.29 36.39,53.52 36.38,53.52 36.38,53.04 36.39,53.04 36.39,51.37 34.82,49.81 34.82,49.27 34.12,48.57 33.44,48.57 v2(33.15,48.28)
  L4SGND w0.508: v2(26.8,29.23) 26.88,29.15 27.62,29.15 29.73,27.04 29.73,26.93 29.82,26.84 v2(29.82,26.82)
  L6 w0.508: v2(34.42,26.82) 34.42,27.79 36.07,29.44 36.07,32.98 33.78,35.26 33.78,40.47 31.5,42.76 31.5,48.16 32.25,48.91 32.78,48.91 33.15,48.54 v2(33.15,48.28)
  BOTTOM w0.254: R4370.1 26.44,28.87 v2(26.8,29.23)
  BOTTOM w0.381: v2(38.99,66.9) 37.74,68.14 PC4401.1
  BOTTOM w0.508: C4343.1 29.11,27.78 29.84,27.78 R4318.1 30.05,27.15 29.82,26.92 v2(29.82,26.82) 29.86,26.82 30.21,26.47 Q4348.S
  vias: v1(28.45,66.95) v2(23.88,67.07)
+SDC_IN_SW: length 53.9
  L6 w0.102: v2(28.73,32.2) 28.73,33.77 28.07,34.43 28.07,36.98 25.4,39.64 25.4,39.9 25.84,40.34 25.84,48.14 27.38,49.68 27.38,55.21 28.8,56.63 28.86,56.63 30.81,58.59 v2(30.81,68.6)
  BOTTOM w0.102: v2(28.73,32.2) 28.83,32.1 28.83,32.09 28.88,32.04 28.88,31.26 v1(29.39,30.75) 29.39,30.17 28.83,29.61 28.83,29.33 C4343.2 ; C4343.2 27.86,29.15 R4333.1 ; C4343.2 29.29,28.52 29.97,28.52 R4318.2 30.61,27.88 30.61,27.45 30.86,27.2 31.75,27.2 32.13,26.82 32.13,24.45 32.94,23.64 R4368.1 ; v2(30.81,68.6) 30.99,68.6 31.41,68.18 PU4302.4
+SDC_IN_SW_R1: length 3
  BOTTOM w0.102: Q4349.6 29.17,26.87 v1(28.92,27.12) 28.53,27.51 28.26,27.51 27.84,27.93 R4333.2
+V_VREF_PATH1: length 2.1
  TOP w0.508: C1202.2 93.69,33.62 v1(93.36,33.29) 92.93,33.72 R1203.1
+V_VREF_PATH2: length 1.7
  TOP w0.254: C1302.2 99.8,35.5 v1(99.52,35.78)
  TOP w0.508: R1303.1 99.81,34.88 C1302.2
A_ZQ_RAM1: length 2.2
  TOP w0.102: v2(81.82,41.34) 81.61,41.55 v1(81.33,41.55) 81.33,41.55 80.84,41.55 R1205.1
  BOTTOM w0.102: RAM1.F9 v2(81.82,41.34)
A_ZQ_RAM2: length 2.2
  TOP w0.102: v2(71.67,41.34) 71.46,41.55 71.19,41.55 71.19,41.55 v1(71.18,41.55) 71.18,41.55 70.69,41.55 R1234.1
  BOTTOM w0.102: RAM2.F9 v2(71.67,41.34)
A_ZQ_RAM3: length 2.1
  TOP w0.102: v2(61.52,41.34) 61.33,41.34 v1(61.03,41.04) 60.89,41.17 R1204.1
  BOTTOM w0.102: RAM3.F9 v2(61.52,41.34)
A_ZQ_RAM4: length 2.7
  TOP w0.102: v1(49.66,42.06) R1201.1 51.21,41.17 v2(51.37,41.34)
  BOTTOM w0.102: RAM4.F9 v2(51.37,41.34)
AC_DIS: length 154.2
  L4SGND w0.254: v2(101.87,18.29) 101.68,18.1 92.16,18.1 91.56,17.49 88.08,17.49 86.48,15.89 85.5,15.89 85.33,15.72 85.12,15.72 83.39,13.99 83.37,13.99 82.94,13.55 82.58,13.55 79.62,13.55 79.37,13.81 78.78,13.81 77.4,12.44 68.22,12.44 66.91,11.13 49.05,11.13 44.84,15.33 44.46,15.33 40.22,19.58 36.25,19.58 34.58,21.24 34.58,23.28 34.1,23.77 33.37,23.77 30.45,26.69 30.45,27.21 28.32,29.35 v2(28.32,29.74) 28.28,29.78 27.51,29.78 24.77,32.53 24.77,38.28 26.04,39.55 v2(26.04,39.64)
  L6 w0.254: v2(26.04,39.64) 26.25,39.86 26.25,48.11 27.69,49.55 27.69,55.09 28.67,56.07 32.53,56.07 32.87,56.41 32.87,73.2 35.7,76.03 v2(35.81,76.03)
  BOTTOM w0.203: U2401.69 99.6,18.89 100.44,18.05 101.6,18.05 101.84,18.29 v2(101.87,18.29)
  BOTTOM w0.254: v2(35.81,76.03) 36.02,76.03 36.35,76.36 36.35,77.46 R4303.1 36.34,78.03 Q4304.B ; Q4349.5 28.52,26.46 28.24,26.74 28.07,26.74 v1(27.7,27.11) 27.7,27.59 27.33,27.96 27.33,29.51 27.56,29.74 v2(28.32,29.74)
AC_IN#: length 130.7
  TOP w0.254: v2(33.78,23.01) 34.04,22.75 35.81,22.75 v1(36.2,23.13) 38.96,23.13 v2(39.14,23.31)
  L4SGND w0.254: v2(23.63,29.74) 23.74,29.74 23.79,29.69 23.82,29.69 24.76,29.3 25.41,29.3 26.63,28.09 27.43,28.09 28.72,26.79 28.72,26.37 29.44,25.65 30.15,25.65 30.34,25.45 32.79,23.01 v2(33.78,23.01)
  L6 w0.254: v2(39.14,23.31) 37.51,23.31 35.84,24.97 35.51,25.31 35.51,25.78 35.84,26.12 36.21,26.12 38.35,28.26 38.35,35.15 41.45,38.25 41.91,38.25 50.78,47.12 v2(58.44,47.12)
  BOTTOM w0.254: v2(58.44,47.12) 58.44,48.89 61.12,51.58 80.14,51.58 82.31,53.75 119.85,53.75 D1701.K ; D4305.K 23.25,27.22 23.5,27.48 23.5,29.49 23.62,29.61 23.62,29.73 v2(23.63,29.74) ; v2(33.78,23.01) 33.69,23.01 33.44,22.75 PQ4415.6
AC_IN#_G: length 6.5
  TOP w0.254: R4377.1 R4376.2 33.73,58.06 32.84,57.17 32.84,56.66 32.79,56.61 v1(32.79,56.56) 32.94,56.56 v2(33.35,56.15)
  BOTTOM w0.254: v2(33.35,56.15) 33.99,56.15 U4302.5
AC_PRESENT: length 38.3
  TOP w0.102: v2(125.98,64.95) 124.53,63.5 124.53,61.98 125.18,61.33 125.18,59.12 125.63,58.67 125.63,57.88 126.19,57.33 126.19,53.71 v2(123.83,51.35) 125.75,49.43 v2(133.47,49.43)
  BOTTOM w0.076: CPU1.BU35 125.58,68.79 125.67,68.53 125.67,68.53 125.74,68.35 125.74,68.12 125.71,68.03 125.71,67.79 125.77,67.62 125.77,67.21
  BOTTOM w0.102: v2(123.83,51.35) 123.09,52.09 D1701.A ; RN1701.4 127.46,63.52 v1(126.97,64.01) 126.21,64.76 126.02,64.95 v2(125.98,64.95) 125.98,64.99 125.77,65.2 125.77,67.2 125.77,67.21 ; Q1702.6 132.16,52.39 132.41,52.14 132.41,51.1 EC1707.1 v2(133.47,49.43)
ACOK#: length 34.7
  L6 w0.127: v2(28.7,45.59) 28.32,45.2 28.32,41.25 30.1,39.47 30.1,37.11 33.66,33.55 34.54,33.55 35.5,32.59 35.5,29.67 33.78,27.96 v2(33.78,26.82)
  BOTTOM w0.127: v2(33.78,26.82) 34.28,26.31 35.3,26.31 35.56,26.05 35.56,25.29 v1(34.42,24.15) 34.42,21.86 34.59,21.68 PQ4415.2 35.71,21.68 35.84,21.56 35.84,21.18 35.69,21.03 PQ4415.3 ; v2(28.7,45.59) 29.44,45.59 30.1,46.25 PR4427.2
AD_IA: length 112.2
  TOP w0.102: v2(66.04,4.72) 68.3,2.46 85.62,2.46 87.48,4.31 89.84,4.31 90.12,4.59 R2421.2 90.12,6.04 R2423.1 ; v2(27.56,19.45) 27.69,19.58 27.69,21.37 27.93,21.61 30.28,21.61 31.17,20.72 32.79,20.72 32.99,20.92 v1(34.47,20.92) 35.64,20.92 v2(35.94,20.62) ; PR4412.2 33.58,40.79 PC4432.1 33.58,39.59 34.85,38.32 34.85,37.79 32.51,35.45 32.51,31.77 v2(29.9,29.16)
  L4SGND w0.102: v2(29.9,29.16) 30.89,28.17 30.89,26.69 33.25,24.33 34.63,24.33 35.94,23.02 v2(35.94,20.62)
  L6 w0.102: v2(27.56,19.45) 28.04,18.96 28.66,18.96 29.03,18.59 29.03,14.56 29.72,13.87 29.72,13.45 30.3,12.87 31.02,12.87 32.72,11.17 32.72,10.29 36.56,6.44 39.68,6.44 40.18,5.94 64.81,5.94 v2(66.04,4.72)
AD_OFF_L: length 3.7
  BOTTOM w0.254: Q4305.1 33.8,81.31 v1(34.29,81.81) 35.41,81.81 Q4304.C
AD_OFF_R: length 9.5
  BOTTOM w0.254: PU4301.4 33.95,75.19 34.21,74.92 34.85,74.92 v1(35.03,75.1) 35.03,76.14 R4307.2 C4301.2 34.82,78.43 R4308.1 33.9,78.63 33.24,79.29 33.24,81.44 Q4305.3
ALERT#: length 2.5
  BOTTOM w0.102: U2601.6 151.69,48.21 v1(151.89,48.41) 151.89,49.09 R2603.2
ALWON: length 30.4
  TOP w0.127: v1(89.53,19.96) 89.41,20.08 88.96,20.08 v2(88.96,20.08)
  L6 w0.127: v2(88.96,20.08) 91.03,18.02 92.65,18.02 92.66,18.01 93.38,18.01 93.72,17.68 96.42,17.68 96.42,17.68 96.91,17.68 100.07,20.85 v2(100.08,20.85)
  BOTTOM w0.127: U2401.121 87.91,8.13 88.89,9.1 88.89,9.47 87.92,10.44 87.92,12.82 88.16,13.06 88.16,14.3 87.92,14.55 87.92,15.47 87.48,15.92 87.48,18.78 88.78,20.08 v2(88.96,20.08) ; R4009.2 100.33,21.1 v2(100.08,20.85)
AMBER_LED_BAT: length 7.3
  BOTTOM w0.254: Q6402.C 117.48,15.13 116.97,14.62 116.97,12.85 v1(117.09,12.72) 116.71,12.72 115.19,14.24 R6401.1
AUD_AGND: length 35.8
  TOP w0.203: 20.45,15.13 20.49,15.13 20.83,15.47 U2701.37 ; v2(21.86,22.62) 21.86,22.61 21.89,22.57 21.89,22.15 22.22,21.82 U2701.22
  TOP w0.305: C2740.2 21.89,22.67 21.86,22.64 v2(21.86,22.62) ; v2(18.8,11.7) 19.38,12.29 R2747.2 19.86,12.59 19.9,12.59 20.24,12.94 C2721.2 ; 20.45,15.13 20.14,14.83 19.1,14.83 v2(18.8,15.13)
  TOP w0.508: HPMIC1.MS 9.45,19.25 ; HPMIC1.MS 6.85,19.25 ; HPMIC1.MS 8.15,18.41
  L2SGND w0.508: HPMIC1.MS 9.45,19.25 ; HPMIC1.MS 8.15,18.41 ; HPMIC1.MS 6.85,19.25
  L3SGND w0.508: 6.85,19.25 HPMIC1.MS ; HPMIC1.MS 9.45,19.25 ; HPMIC1.MS 8.15,18.41
  BOTTOM w0.305: EC2908.2 16.64,23.44 EC2907.2 16.18,22.7 v2(16,22.88) ; v2(21.86,22.62) 21.84,22.64 21.84,23.06 21.56,23.34 C2730.2
  BOTTOM w0.381: C2909.2 22.86,15.11 21.89,15.11 R2739.1 ; EC2906.2 v2(15.75,26.82)
  BOTTOM w0.508: v2(21.86,22.62) 21.84,22.62 21.66,22.44 21.27,21.49 C2734.2 21.12,21.42 C2735.2 ; C2741.2 18.54,24.15 v2(19.05,24.66) ; R2739.1 21.49,15.41 C2737.2 19.53,15.13 v2(18.8,15.13) 17.73,15.13 EC2709.1 17.02,15.84 16.99,15.84 v2(16.56,16.27) ; C2727.2 20.75,11.88 C2731.2 19.63,11.83 18.92,11.83 v2(18.8,11.7) 18.62,11.88 EC2713.1
  vias: v1(5.49,10.79) v2(2.54,18.05) v2(5.08,11.19) v2(5.92,11.19) v2(6.35,31.13) v2(6.27,18.86) v2(9.65,31.13) v2(13.08,31.13) v2(13.97,19.45) v2(14.35,25.55)
AUD_HP1_JACK_L1: length 4.8
  TOP w0.254: R2907.2 16.84,21.1 v2(16.26,21.1)
  BOTTOM w0.254: R2911.1 15.65,21.79 EC2907.1 16.64,21.48 v2(16.26,21.1) ; v2(16.26,21.1) 16.89,20.47 R2922.2 ; v2(16.26,21.1) v1(15.7,21.1)
AUD_HP1_JACK_L1_R: length 20.3
  BOTTOM w0.254: R2911.2 14.93,23.36 v1(14.93,24.48) 14.93,25.87 15.11,26.05 15.11,27.32 15.56,27.77 ED2903.2 14.33,27.43 14.33,26.54 13.84,26.05 13.84,22.12 14.86,21.1 14.86,18.94 14.22,18.31 13.19,18.31 HPMIC1.1
AUD_HP1_JACK_R1: length 4.7
  TOP w0.254: v2(16.95,24.14) 16.95,23.41 v1(16.98,23.39) 16.98,23.35 16.97,23.34 R2909.2
  BOTTOM w0.254: R2921.2 EC2908.1 17.65,23.69 17.65,24.53 17.45,24.73 R2912.1 17.4,24.73 17.4,24.66 16.95,24.21 v2(16.95,24.14)
AUD_HP1_JACK_R1_R: length 50.9
  TOP w0.254: v1(16.61,25.82) v2(17.02,25.42)
  L4SGND w0.254: v2(17.02,25.42) 17.02,24.96 17.55,24.43 17.55,20.03 16.3,18.78 15.45,18.78 14.34,17.67 6.91,17.67 v2(6.68,17.44) ; HPMIC1.2 8.32,30.37 13.61,30.37 15.13,28.86 15.13,19.51 13.94,18.33 6.63,18.33 v2(6.35,18.05)
  BOTTOM w0.254: R2912.2 16.59,24.99 v2(17.02,25.42) ; v2(6.68,17.44) 6.71,17.44 v1(7.24,16.91) 7.17,16.84 ED2901.1 5.9,17.6 v2(6.35,18.05)
AUD_HPJD_N: length 31.2
  TOP w0.254: R2741.1 29.01,12.97 28.57,13.4 v2(28.57,14.12)
  L4SGND w0.254: v2(22.46,28.19) 23.38,28.19 23.39,28.19 24.36,28.19 24.37,28.19 25.09,28.19 25.15,28.13 25.15,28.13 25.45,27.83 25.46,27.83 26.42,26.87 27.39,26.87 27.69,26.57 27.69,25.83 31.04,22.48 31.04,16.71 28.57,14.24 v2(28.57,14.12)
  BOTTOM w0.254: v2(28.57,14.12) 28.57,13.94 27.35,12.72 27.26,12.72 25.88,12.72 25.53,13.07 25.53,14.83 C2909.1 ; R2923.2 v1(21.97,27.32) 21.97,27.7 v2(22.46,28.19)
AUD_HPOUT_L: length 4.6
  TOP w0.203: U2701.27 20.06,19.83 19.68,20.21
  TOP w0.254: 19.68,20.21 19.39,20.5 19.39,21.54 v1(19,21.94) 18.54,21.94 R2907.1
AUD_HPOUT_R: length 5.5
  TOP w0.203: U2701.26 20.3,20.23 19.94,20.59
  TOP w0.254: R2909.1 18.49,23.16 v1(19.2,23.16) 19.41,23.16 19.78,22.79 19.78,21.91 19.77,21.91 19.77,21.49 19.78,21.48 19.78,20.75 19.94,20.59
AUD_PC_BEEP_C: length 17.7
  TOP w0.254: C2726.1 17.14,16.58 17.14,11.45 13.46,7.77 v2(10.29,7.77)
  BOTTOM w0.254: v2(10.29,7.77) 10.21,7.69 R2745.1 9.07,8.02 v1(8.51,8.02) 6.82,8.02 D2702.3
AUD_PC_BEEP_R: length 3
  TOP w0.203: 19.43,16.63 v1(19.48,16.63) 19.85,16.63 20.26,17.03 U2701.34
  TOP w0.254: 19.43,16.63 19.28,16.78 18.11,16.78 C2726.2
AUD_RING: length 20.4
  TOP w0.203: U2701.30 19.87,18.63 v2(19.86,18.62)
  L6 w1.016: v2(19.86,18.62) 17.67,18.62 v3(16.13,20.17) 16.13,19.96 14.1,17.93 8.51,17.93 4.95,14.37 v3(4.95,12.85)
  vias: v1(4.7,12.21)
AUD_SELEEVE:
  vias: v1(16.37,24.52) v3(15.88,23.77)
AUD_SENSE_A: length 8.3
  TOP w0.203: 26.33,15.47 U2701.48
  TOP w0.254: 26.33,15.47 27.68,15.47 28.45,14.7 28.75,14.7 29.13,14.32 C2746.1 29.32,13.8 29.32,13.67 R2741.2 30.61,12.97 v1(30.99,12.59) 32,13.61 R2742.2
AUD_SPK_L+: length 9.4
  TOP w0.203: v3(23.11,13.82) 23.42,14.13 U2701.42
  L4SGND w1.016: v3(24.77,8.15) 24.69,8.07 23.47,8.07 22.89,8.65 22.89,12.18 22.63,12.43 22.63,13.33 v3(23.11,13.82)
  vias: v1(25.36,7.86)
AUD_SPK_L+_C: length 4.2
  TOP w0.305: v3(23.62,6.24) 23.43,6.24 23.11,6.56 ER2901.2
  TOP w0.508: AFTP2902.1 24.05,5.81 v3(23.62,6.24)
  BOTTOM w0.381: SPK1.1 23.05,6.81 v3(23.62,6.24)
AUD_SPK_L-: length 10.8
  TOP w0.203: U2701.43 23.82,13.04 v3(23.62,12.85)
  TOP w0.305: v1(21.03,7.89) ER2902.1 21.77,8.04 EC2903.1
  TOP w0.508: v3(23.88,9.06) 23.85,9.04 23.8,9.04 23.7,8.93 EC2903.1
  L6 w1.016: v3(23.62,12.85) 23.65,12.82 23.65,12.69 23.88,12.46 v3(23.88,9.06)
AUD_SPK_L-_C: length 4.2
  TOP w0.305: v3(22.23,6.14) 22.2,6.14 21.92,6.42 ER2902.2
  TOP w0.508: v3(22.23,6.14) 22.24,6.14 23.16,5.21 AFTP2901.1
  BOTTOM w0.381: SPK1.2 22.05,6.31 v3(22.23,6.14)
AUD_SPK_R+: length 16.5
  TOP w0.203: U2701.45 24.62,14.39 v3(24.89,14.12)
  L6 w1.016: v3(21.03,3.23) 23.05,5.25 24.22,5.25 25.76,6.79 25.76,11.03 25.54,11.24 25.54,12.58 25.63,12.67 25.63,13.51 25.02,14.12 v3(24.89,14.12)
  BOTTOM w0.508: v3(24.89,14.12) 24.41,14.12 v1(24.08,14.45)
AUD_SPK_R+_C: length 4.5
  TOP w0.508: AFTP2904.1 20.8,6.39 v3(20.8,6.16) 20.8,6.12 21.67,5.26 ER2903.2
  BOTTOM w0.381: v3(20.8,6.16) 21.05,6.41 SPK1.3
AUD_SPK_R-: length 18
  TOP w0.203: v3(24.64,13.1) 24.22,13.52 U2701.44
  L4SGND w1.016: v3(24.64,13.1) 24.64,11.34 25.1,10.22 26.29,9.04 26.29,7.32 24.12,5.15 20.92,5.15 19.1,3.33 v3(19.1,3.09)
  vias: v1(18.29,3.96)
AUD_SPK_R-_C: length 4.4
  TOP w0.381: v3(19.68,6.22) 18.44,6.22 AFTP2903.1
  TOP w0.508: v3(19.68,6.22) 19.68,5.66 19.99,5.35 ER2904.2
  BOTTOM w0.381: v3(19.68,6.22) 19.94,6.47 19.94,6.75 20.05,6.86 SPK1.4
AUD_VREF: length 4
  TOP w0.203: U2701.38 21.82,15.13 21.57,14.88
  TOP w0.254: 21.57,14.88 21.08,14.88 20.82,14.61 v2(20.69,14.61)
  BOTTOM w0.254: v1(18.67,14.24) 19.66,14.24 C2737.1 20.13,14.09 20.19,14.12 v2(20.69,14.61)
AUDIO_47: length 3.8
  TOP w0.203: 26.67,14.88 25.65,14.88 25.42,15.11 U2701.47
  TOP w0.254: R2744.2 27.81,14.34 v1(27.55,14.61) 27.48,14.67 27.43,14.67 27.23,14.88 26.67,14.88
AUX_EN_WOWL: length 122.1
  TOP w0.102: R6110.1 186.13,43.38 R2405.2 186.33,43.02 186.64,42.72 v2(187.53,42.72) ; v2(180.31,27.65) 180.24,27.58 v2(176.83,27.58) ; v2(162.2,39.95) v1(159.77,39.95) 158.14,39.95 157.2,39.01 154.18,39.01 153.81,39.38 153.35,39.38 153.34,39.39 150.67,39.39 150.16,39.9 149.81,39.9 149.48,40.23 149.48,43.33 148.79,44.01 146.15,44.01 145.19,44.97 145.19,47.8 144.35,48.63 125.76,48.63 123.42,50.97 123.42,51.61 125.98,54.17 125.98,57.24 125.4,57.83 125.4,58.62 124.69,59.33 124.69,59.61 123.44,60.85 123.44,61.48 123.7,61.73 123.7,66.19 123.21,66.68 123.21,67.82 124.64,69.24 124.64,70.28 124.55,70.36 124.55,71.17 v2(124.91,71.53)
  L4SGND w0.102: v2(174.14,34.1) 171.78,34.1 169.9,35.98 166.17,35.98 v2(162.2,39.95)
  L6 w0.102: v2(176.83,27.58) 176.83,31.41 v2(174.14,34.1) ; v2(180.31,27.65) 180.31,28.58 181.78,30.04 186.38,30.04 187.35,31.01 187.35,32.33 189.26,34.23 189.26,41.14 187.68,42.72 v2(187.53,42.72)
  BOTTOM w0.102: v2(124.91,71.53) 124.91,71.6 124.63,71.88 CPU1.BT30
AUX_EN_WOWL_R: length 2.8
  TOP w0.102: Q6102.G v1(185.04,45.28) 185.11,45.28 185.55,44.85 R6110.2
AUX_MODE: length 4.1
  TOP w0.203: 19.59,17.14 19.89,17.14 20.19,17.43 U2701.33
  TOP w0.254: R2754.2 R2728.2 18.31,18.18 v1(18.79,17.7) 18.89,17.7 19.46,17.14 19.59,17.14
B_ZQ_RAM1: length 2.2
  TOP w0.102: R1304.1 113.15,41.17 113.41,40.91 v1(113.54,40.91) 113.97,41.34 v2(114.02,41.34)
  BOTTOM w0.102: RAM5.F9 v2(114.02,41.34)
B_ZQ_RAM2: length 4
  BOTTOM w0.102: v1(100.75,41.14) 101.42,41.14 101.56,41.14 R1301.1 102.28,41.22 102.58,40.92 103.4,40.92 103.82,41.34 RAM6.F9
B_ZQ_RAM3: length 2.4
  TOP w0.102: R1306.1 133.41,41.17 v1(133.8,40.79) 134.07,40.9 134.19,41.02 v2(134.32,41.34)
  BOTTOM w0.102: RAM7.F9 v2(134.32,41.34)
B_ZQ_RAM4: length 2.2
  TOP w0.102: v2(124.17,41.34) 123.74,40.91 v1(123.7,40.91) 123.57,40.91 123.33,41.15 R1305.1
  BOTTOM w0.102: RAM8.F9 v2(124.17,41.34)
BAT1_LED#: length 36.7
  TOP w0.127: v2(123.14,8.98) 123.15,8.99 v1(123.15,9.82) RN2405.2
  L4SGND w0.127: v2(94.49,8.02) 94.93,7.57 96.11,7.57 96.76,8.22 99.03,8.22 99.47,8.66 101.38,8.66 101.64,8.92 101.64,8.94 101.89,9.2 105.25,9.2 105.84,9.79 107.49,9.79 107.82,9.45 113.93,9.45 115.25,8.13 122.29,8.13 v2(123.14,8.98)
  BOTTOM w0.127: U2401.106 93.91,7.44 v2(94.49,8.02) ; Q2416.4 124.28,10.25 R2498.2 124.1,8.98 v2(123.14,8.98)
BAT2_LED#: length 56.2
  TOP w0.127: v2(125.92,9.58) 125.45,9.12 v1(124.14,9.12) 123.48,8.45 123.04,8.45 122.56,8.93 RN2405.1
  L6 w0.127: v2(84.9,9.27) 85.32,8.84 86.3,8.84 87.19,9.73 89.75,9.73 90.01,9.73 90.69,9.05 90.69,8.98 91.2,8.46 101.25,8.46 101.95,9.16 105.58,9.16 105.84,8.9 106.2,8.9 106.21,8.91 107.61,8.91 108.82,7.7 116.3,7.7 117.02,8.43 124.76,8.43 v2(125.92,9.58)
  BOTTOM w0.127: U2401.1 84.3,8.09 84.52,8.31 84.52,8.89 v2(84.9,9.27) ; R2495.1 125.67,12.72 125.79,12.59 Q2416.1 126.17,11.69 126.47,11.4 126.47,10.13 126.36,10.03 126.36,10.03 v2(125.92,9.58)
BAT_AMBER: length 4.8
  BOTTOM w0.254: LED1.2 115.05,12.97 v1(114.68,13.35) 114.54,13.48 113.28,13.48 112.83,13.94 ED6401.2 112.89,14.24 R6401.2
BAT_WHITE: length 7.9
  BOTTOM w0.254: R6402.2 112.9,16.15 ED6401.1 112.83,15.84 111.51,14.52 111.51,13.47 v1(112.09,12.88) 112.69,12.88 112.9,13.1 113.69,13.1 114.05,12.73 LED1.3
BATT_WHITE_LED#: length 14.3
  BOTTOM w0.127: Q2416.6 124.14,12.58 R2495.2 124.28,13.35 Q6403.D 123.95,14.24 123.44,14.75 123.21,14.75 122.47,15.49 122.47,15.73 121.59,16.6 120.44,16.6 120.33,16.49 120.33,15.79 120.74,15.39 121.74,15.39 122.36,14.76 122.36,13.42 v1(122.34,13.39) 121.77,12.82 R6422.2 122.29,12.04 Q6404.4
BATT_WHITE_LED_R#: length 10.4
  BOTTOM w0.127: Q6404.3 120,11.56 119.76,11.8 v1(119.76,12.46) 120.8,12.46 R6422.1 120.9,12.87 122.11,14.08 122.11,14.65 121.81,14.96 120.32,14.96 119.19,16.08 Q6401.B
BEEP: length 95.4
  L4SGND w0.254: v2(88.9,11.7) 87.01,11.7 85.46,10.16 84.53,10.16 83.28,8.91 76.4,8.91 76.11,9.2 74.55,9.2 74.08,9.67 68.18,9.67 65.49,6.98 39.46,6.98 38.53,6.05 38.53,5.56 v2(38.73,5.35)
  BOTTOM w0.178: 89.91,21.1 U2401.45
  BOTTOM w0.254: 89.91,21.1 89.83,21.01 89.83,13.9 89.09,13.16 89.09,12.68 88.9,12.49 v2(88.9,11.7) ; v2(38.73,5.35) 38.61,5.23 v1(36.58,5.23) 35.99,5.23 33.41,7.81 33.36,7.81 33.35,7.82 31.62,7.82 31.6,7.81 26.71,7.81 24.42,5.52 22.86,5.52 22.82,5.48 20.61,5.48 20.57,5.52 12.82,5.52 12.5,5.2 10.39,5.2 RN2702.1
BKLT_CTRL: length 35.1
  TOP w0.127: v2(124.07,102.75) 114.54,102.75 111.16,106.13 101.94,106.13 100.84,105.03 100.84,104.74 R5502.1 R5545.2 100.15,103.29 RN5502.5
  BOTTOM w0.127: v2(124.07,102.75) 124.07,102.16 125.15,101.08 125.76,101.08 v1(127.8,99.05) 128.61,98.24 D5502.3
BKLT_IN_EC: length 5.2
  BOTTOM w0.102: R2440.1 103.25,18.43 102.96,18.72 100.87,18.72 v1(100.84,18.69) 100.53,18.69 99.52,19.69 U2401.67
BLON_OUT_C: length 5.9
  TOP w0.102: R5544.1 99.06,103.09 RN5502.7 99.06,102 98.81,101.75 98.04,101.75 97.92,101.62 97.92,100.86 v2(98.42,100.35) 98.68,100.09 v1(98.93,100.09)
  BOTTOM w0.102: LCD1.23 98,99.85 98.42,100.27 v2(98.42,100.35)
BLUETOOTH_EN: length 111
  TOP w0.102: AFTP6112.1 180.77,39.54 180.77,38.55 181,38.32 181.36,38.32 181.61,38.07 D6101.K 181.61,37.58 181.03,37 180.49,37 R6107.2 180.67,37.74 180.77,37.74 180.87,37.84 v2(180.9,37.84) ; v2(156.87,45.05) 157.27,45.45 157.27,49.62 156.72,50.17 156.72,53.51 157.28,54.06 157.28,55.06 158.8,56.58 158.8,60.41 158.62,60.58 158.62,69 158.51,69.11 158.51,70.17 158.51,70.84 158.72,71.06 158.72,74.16 158.55,74.34 158.55,75.01 158.55,77.16 157.71,78 157.12,78 156.79,78.32 156.79,79.2 157.23,79.64 157.23,83.77 155.16,85.84 153.42,85.84 v2(153.23,85.65) 153.01,85.42 R2109.2
  L4SGND w0.102: v2(156.87,45.05) 156.87,43.05 159.54,40.38 164.59,40.38 168.39,36.58 170.73,36.58 171.6,35.71 172.67,34.64 174.18,34.64 174.57,34.25 174.57,34.1 175.13,33.54 175.95,33.54 180.25,37.84 v2(180.9,37.84)
  BOTTOM w0.076: CPU1.CP14 135.46,82.07 135.65,82.26 arc(135.72,82.31) 135.8,82.33 136.03,82.33 136.18,82.17 138.59,82.17 138.64,82.12 138.86,82.12
  BOTTOM w0.102: v2(153.23,85.65) 151.79,85.65 149.96,83.81 144.9,83.81 143.21,82.12 138.87,82.12 138.86,82.12 ; IOBD1.48 161.8,44.26 161.63,44.43 157.49,44.43 v2(156.87,45.05)
BLUETOOTH_EN_R: length 5.1
  TOP w0.102: R6106.2 179.76,37.61 179.76,36.52 179.86,36.42 R6107.1 180.94,36.42 D6101.A 182.35,35.75 182.58,35.52 v1(182.59,35.52)
BOARD_ID: length 7.2
  TOP w0.102: v2(91.19,3.85) 91.54,4.21 92.15,4.21 R2494.1 92.51,4.72 R2443.2 R2444.1 92.51,6.98 C2408.1
  BOTTOM w0.102: v2(91.19,3.85) v1(91.19,4.59) 91.19,4.97 91.91,5.7 U2401.111
BOARD_ID1: length 22.4
  TOP w0.102: R2010.2 R2009.1 139.89,85.42 138.81,84.34 136.16,84.34 135.71,84.79 134.41,84.79 134.05,84.43 134.05,83.74 133.7,83.39 130.84,83.39 v1(130.71,83.25) 130.71,82.95 v2(130.9,82.75)
  BOTTOM w0.102: CPU1.CG12 131.31,83.16 v2(130.9,82.75)
BOARD_ID2: length 22.4
  TOP w0.102: R2005.2 150.75,87.39 151.38,86.76 R2008.1 151.97,86.2 v2(151.89,86.12)
  BOTTOM w0.076: CPU1.CM14 134.27,82.34 135.44,82.34 135.53,82.43 arc(135.59,82.44) 135.64,82.47 135.66,82.49 136.12,82.49 136.26,82.35 138.68,82.35
  BOTTOM w0.102: v2(151.89,86.12) 149.87,84.1 144.67,84.1 v1(143.73,83.17) 142.88,82.32 138.72,82.32 138.68,82.35
BPM_CPU_N0: length 7.1
  BOTTOM w0.102: TP302.1 95.89,94.47 97.16,93.2 97.16,92.98 98.3,91.84 99.24,91.84 99.31,91.76 99.33,91.76 100.69,90.41 CPU1.U1
BPM_CPU_N1: length 7
  BOTTOM w0.076: CPU1.U2 100.84,89.87 100.85,89.89 100.95,90.12 100.95,90.31 100.92,90.4 100.92,90.44 99.41,91.95 99.39,91.95
  BOTTOM w0.102: 99.39,91.95 99.23,92.12 98.29,92.12 97.41,93 97.41,93.95 TP303.1
BPM_CPU_N2: length 8.7
  BOTTOM w0.076: CPU1.U3 100.93,89.39 100.97,89.43 100.97,89.74 100.99,89.78 101,89.82 101.12,90.08 101.12,90.34 101.08,90.43 101.08,90.57 101.02,90.63 101.02,90.72 100.75,90.98
  BOTTOM w0.102: TP304.1 97.66,95.34 97.66,93.01 98.28,92.4 99.34,92.4 100.75,90.98
BPM_CPU_N3: length 7.1
  BOTTOM w0.102: TP307.1 96.8,92.91 98.12,91.59 99.22,91.59 100.4,90.41 100.4,89.82 100.4,89.82 100.4,88.78 100.69,88.49 CPU1.U4
BREATH_LED#: length 131.2
  TOP w0.254: v1(163.7,41.55) 163.7,41.8 v2(163.96,42.06)
  L6 w0.254: v2(97.28,7.77) 101.73,7.77 102.19,8.22 105.33,8.22 105.4,8.16 106.81,8.16 107.89,7.07 115.63,7.07 115.95,6.75 119.48,6.75 120.33,7.6 128.44,7.6 129.67,6.37 136.54,6.37 137.93,4.98 137.93,4.96 138.56,4.34 163.19,4.34 163.83,4.97 163.83,11.7 164.74,12.62 164.74,14.27 164.97,14.5 164.97,14.5 169.8,19.32 169.8,35.68 163.96,41.52 v2(163.96,42.06)
  BOTTOM w0.178: U2401.70 98.23,18.49 97.79,18.05
  BOTTOM w0.254: v2(163.96,42.06) 164.3,42.4 IOBD1.43 ; 97.79,18.05 97.16,17.42 96.06,17.42 93.09,14.45 93.09,13.1 92.13,12.13 92.13,11.47 94.68,8.91 96.14,8.91 v2(97.28,7.77)
BT+: length 154.1
  L4SGND w0.508: v2(35.94,42.82) 35.15,42.82 33.27,40.94 33.27,35.61 34.58,34.31 35.32,34.31 37.08,32.54 37.08,29.72 47.74,19.07 53.34,19.07 56.26,16.15 74.41,16.15 75.3,17.04 79.5,17.04 79.91,17.44 79.93,17.44 80.37,17.87 80.37,17.9 81.28,18.81 81.28,20.22 82.72,21.66 98.21,21.66 98.52,21.97 100.71,21.97 101.3,21.38 107.95,21.38 108.2,21.13 110.8,21.13 111.23,21.56 111.23,21.96 115.19,25.93 135.31,25.93 138.87,22.37 139.48,22.37 142.02,19.83 144.4,19.83 v2(145.29,20.72)
  BOTTOM w0.254: v2(35.94,42.82) 35.94,42.66 35.2,41.93 35.2,39.84 35.56,39.48 35.56,38.04 34.54,37.02 34.54,35.91 PR4495.2
  BOTTOM w0.508: PR4478.2 33.22,43.12 33.74,42.6 34.46,42.6 34.67,42.82 v2(35.94,42.82) ; v2(145.29,20.72) 145.29,20.08 146.05,19.32 PU4412.5
  vias: v1(148.11,18.28) v3(153.67,12.59) v3(154.56,12.59)
BT_USB20_CON_N: length 4.8
  TOP w0.102: EL6603.4 175.98,42.21 v2(176.43,41.76) 176.12,41.45 176.12,40.91 176.28,40.76 AFTP6111.1
  BOTTOM w0.102: IOBD1.19 176.3,43.27 176.12,43.1 176.12,42.07 v2(176.43,41.76)
BT_USB20_CON_P: length 4.7
  TOP w0.102: EL6603.1 175.3,42.45 175.62,42.12 175.62,41.79 v2(175.59,41.76) 175.59,41.52 AFTP6114.1
  BOTTOM w0.102: v2(175.59,41.76) 175.75,41.76 175.9,41.9 175.9,43.18 175.8,43.27 IOBD1.20
BT_USB20_N: length 95.8
  TOP w0.102: EL6603.3 v2(175.98,44.72) v1(175.82,45.31)
  L6 w0.089: v2(175.98,44.72) 175.98,44.05 175.68,43.74 171.33,43.74 167.93,47.14 166.34,47.14 164.05,49.43 164.05,50.3 160.33,54.02 160.33,72.07 160.06,72.34 160.06,79.32 154.93,84.45 154.3,84.45 154,84.75 151.31,84.75 150.55,85.51 144.92,85.51 144,86.43 140.13,86.43 138.23,88.33 136.11,88.33 135.27,89.17 131.72,89.17 131.42,89.48 130.12,89.48 129.62,89.98 127.07,89.98 126.82,90.23 126.82,93.68 127.07,93.93 127.3,93.93 v2(127.43,94.06)
  BOTTOM w0.076: CPU1.CC3 128.85,89.14 128.64,89.35 128.59,89.47 128.59,89.66 128.62,89.75 128.62,90.03 128.59,90.12 128.59,90.33 128.1,90.82 128.1,91.25 128.12,91.26
  BOTTOM w0.102: 128.12,91.26 128.12,93.36 127.43,94.05 v2(127.43,94.06)
BT_USB20_P: length 95.5
  TOP w0.102: v2(175.35,44.72) 175.3,44.68 EL6603.2
  L6 w0.089: v2(127.43,93.42) 127.43,93.45 127.15,93.74 127.01,93.6 127.01,90.31 127.15,90.17 129.7,90.17 130.2,89.67 131.5,89.67 131.8,89.36 135.35,89.36 136.19,88.52 138.31,88.52 140.21,86.62 144.08,86.62 145,85.7 150.63,85.7 151.39,84.94 154.08,84.94 154.38,84.64 155.01,84.64 160.25,79.39 160.25,72.42 160.52,72.15 160.52,54.1 164.24,50.38 164.24,49.51 166.42,47.33 168.01,47.33 171.41,43.93 175.6,43.93 175.79,44.13 175.79,44.29 175.62,44.47 175.49,44.47 175.35,44.61 v2(175.35,44.72)
  BOTTOM w0.076: 127.89,91.27 127.89,91.23 127.94,91.18 127.94,90.75 128.42,90.26 128.42,90.09 128.46,90 128.46,89.78 128.42,89.69 128.42,89.43 128.5,89.26 128.5,89.25 128.57,89.09 128.57,88.54 CPU1.CC4
  BOTTOM w0.102: 127.89,91.27 127.89,93.27 127.66,93.49 127.5,93.49 v2(127.43,93.42) v1(126.87,93.11)
CAD_SNK: length 2.5
  TOP w0.127: v2(35.18,88.92) 35.18,88.99 v1(34.82,89.35) 34.52,89.35 R7118.2
  BOTTOM w0.127: U7101.29 35.22,88.88 v2(35.18,88.92)
CAP_LED: length 6.1
  TOP w0.254: AFTP6538.1 61.85,8.78 v2(61.85,9.04)
  BOTTOM w0.254: v2(61.85,9.04) 61.25,9.63 KBBD1.4 61.25,10.98 60.71,11.52 60.71,12.64 R6513.2
CAP_LED#: length 41.7
  TOP w0.127: v2(71.75,8.18) 71.79,8.15 v1(72.39,8.15)
  L4SGND w0.127: v2(100,9.77) 98.91,9.77 98.51,9.38 93.56,9.38 93.3,9.64 89.73,9.64 89.47,9.38 89.47,9.37 87.32,7.22 85.72,7.22 85.19,6.69 75.5,6.69 73.69,8.5 72.07,8.5 v2(71.75,8.18)
  BOTTOM w0.127: Q2414.S 69.24,11.14 69.12,11.02 R2489.2 68.2,9.84 68.33,9.71 69.68,9.71 69.69,9.7 70,9.7 71.51,8.18 v2(71.75,8.18) ; U2401.93 99.7,9.29 100,9.59 v2(100,9.77)
CAP_LED#_R: length 2.9
  BOTTOM w0.127: Q2414.D 67.06,14.57 v1(67.06,12.85) 67.06,12.13 R6512.1
CAP_LED_Q: length 2.6
  BOTTOM w0.254: 63.88,13.61 v1(62.87,12.59) 62.7,12.52 61.82,12.89 R6513.1
CAP_LED_R#: length 4.6
  BOTTOM w0.127: R6512.2 66.85,11.02 v1(66.42,11.45) 66.67,11.7 66.67,13.79 65.91,14.56
CARD1_USB20_N: length 86.3
  L6 w0.089: v2(156.54,47.95) 156.83,48.24 157.09,48.24 157.47,48.62 157.47,50.44 156.95,50.96 156.95,77 152.62,81.34 151.14,81.34 149.6,82.87 143.03,82.87 141.94,83.96 139.68,83.96 138.19,85.45 135.03,85.45 134.04,84.46 131.52,84.46 131.21,84.78 131.21,85.34 v2(130.68,85.88)
  BOTTOM w0.102: 164.82,46.5 161.27,46.5 160.49,45.73 158.5,45.73 158,46.23 158,47.45 157.45,48 156.93,48 156.9,48.02 156.62,48.02 v2(156.54,47.95) ; 164.82,46.5 v1(164.82,46.32) ; 164.82,46.5 165.17,46.5 165.75,47.08 169.22,47.08 170.42,45.89 173.87,45.89 174.47,45.29 174.58,45.29 174.58,45.29 176.03,45.29 177.3,44.02 IOBD1.17 ; CPU1.CG8 v2(130.68,85.88)
CARD1_USB20_P: length 86.2
  L6 w0.089: v2(130.65,85.24) 130.93,85.24 131.02,85.15 131.02,84.7 131.45,84.27 134.11,84.27 135.1,85.26 138.11,85.26 139.6,83.77 141.86,83.77 142.95,82.68 149.52,82.68 151.06,81.15 152.54,81.15 156.76,76.92 156.76,50.88 157.28,50.36 157.28,48.7 157.01,48.43 156.67,48.43 v2(156.51,48.58)
  BOTTOM w0.102: v1(160.86,46.65) 160.98,46.53 ; 160.98,46.53 161.17,46.73 165.07,46.73 165.66,47.31 169.32,47.31 170.51,46.12 173.97,46.12 174.56,45.52 174.67,45.52 174.67,45.52 176.12,45.52 177.38,44.26 177.67,44.26 177.8,44.14 IOBD1.16 ; 160.98,46.53 160.4,45.96 158.6,45.96 158.23,46.32 158.23,47.54 157.54,48.23 157.02,48.23 156.67,48.58 v2(156.51,48.58) ; CPU1.CG9 v2(130.65,85.24)
CARD_CLKREQ_CPU_N: length 22.4
  TOP w0.102: v2(130.42,71.55) 130.64,71.55 130.87,71.33 130.87,70.3 130.93,70.23 130.93,68.64 138.11,61.46 138.15,61.46 138.72,60.89 138.72,59.19 140.74,57.17 v1(142.37,57.17) RN1813.7
  BOTTOM w0.102: CPU1.CE31 130.05,71.23 130.37,71.55 v2(130.42,71.55)
CATERR#_CPU: length 10.3
  BOTTOM w0.076: 103.25,91.36 103.25,90.74 103.5,90.49 103.52,90.43 103.52,89.78 103.55,89.71 103.55,89.41 103.5,89.31 103.5,88.64 CPU1.AA4
  BOTTOM w0.102: 103.25,91.36 102.08,92.52 101.66,92.52 99.8,94.39 99.8,95.55 100.2,95.96 TP301.1
CBN: length 3.4
  TOP w0.203: 20.91,21.57 21.08,21.39 U2701.24
  TOP w0.254: v2(20.7,22.75) 20.45,22.75 20.21,22.51 v1(20.21,22.44) 20.44,22.2 20.49,22.2 20.91,21.79 20.91,21.57
  BOTTOM w0.254: C2739.1 20.42,22.47 v2(20.7,22.75)
CBP: length 3.8
  TOP w0.203: 21.46,22.12 21.82,21.76 U2701.23
  TOP w0.254: v2(20.7,23.79) 20.7,23.64 21.08,23.26 v1(21.12,23.26) 21.35,23.03 21.35,22.23 21.46,22.12
  BOTTOM w0.254: C2739.2 v2(20.7,23.79)
CCD_USB20_CON_N: length 22.2
  BOTTOM w0.102: 119,100.45 119.77,100.45 ED5501.6 120.36,100.45 120.8,100.45 121.01,100.25 121.56,99.69 122.99,99.69 123.09,99.59 123.09,99.23 123.22,99.1 123.52,99.1 123.64,99.23 EL5501.1 ; 119,100.45 118.03,100.45 116.58,99 115.39,99 112.8,101.59 109.87,101.59 109.63,101.83 109.63,102.3 109.53,102.41 109.12,102.41 109.02,102.3 109.02,101.83 108.79,101.59 108.05,101.59 107.86,101.41 107.86,100.21 108,100.07 LCD1.43 ; 119,100.45 v1(119,100.3)
CCD_USB20_CON_P: length 21.7
  BOTTOM w0.102: EL5501.4 122.53,100.18 ED5501.1 122.27,99.92 121.66,99.92 120.9,100.68 117.93,100.68 117.72,100.46 ; 117.72,100.46 116.48,99.23 115.49,99.23 112.9,101.82 109.96,101.82 109.86,101.92 109.86,102.4 109.62,102.63 109.03,102.63 108.79,102.4 108.79,101.92 108.69,101.82 107.96,101.82 107.64,101.5 107.64,100.21 107.5,100.07 LCD1.42 ; 117.72,100.46 v1(117.6,100.58)
CCD_USB20_N: length 54.8
  L4SGND w0.089: v2(125.7,93.33) 125.48,93.55 123.37,93.55 123.16,93.76 123.16,96.81 123.85,97.5 123.85,97.81 123.03,98.63 122.9,98.63 122.44,98.18 122.16,98.18 121.8,98.54 121.8,98.82 122.25,99.28 122.25,99.41 121.92,99.74 120.66,99.74 120.57,99.65 120.57,98.41 120.37,98.21 119.86,98.21 119.66,98.41 119.66,100.06 119.11,100.6 118.31,100.6 117.96,100.95 117.96,101.35 118.16,101.55 120.12,101.55 120.32,101.35 120.32,100.89 120.41,100.81 120.88,100.81 120.96,100.89 120.96,101.35 121.17,101.55 121.68,101.55 121.88,101.35 121.88,100.89 121.97,100.81 122.38,100.81 123,100.19 123.12,100.19 123.68,100.74 123.96,100.74 124.33,100.38 124.33,100.1 123.77,99.54 123.77,99.41 124.71,98.47 124.71,98.25 124.8,98.16 126.14,98.16 126.34,97.96 126.34,97.45 126.14,97.25 125.06,97.25 124.38,96.58 124.38,95.86 124.47,95.77 125.37,95.77 125.49,95.77 v2(125.73,96.03)
  BOTTOM w0.076: CPU1.CC1 128.85,90.39 128.28,90.95
  BOTTOM w0.102: v1(125.98,99.59) 126.11,99.71 ; 126.11,99.71 125.87,99.95 125.58,99.95 125.48,99.85 125.48,99.46 125.35,99.33 124.93,99.33 EL5501.2 ; 126.11,99.71 126.87,98.95 126.87,98.6 126.77,98.49 126.47,98.49 126.24,98.26 126.24,97.66 126.47,97.43 126.64,97.43 126.75,97.33 126.75,96.35 126.21,95.82 125.94,95.82 v2(125.73,96.03) ; v2(125.7,93.33) 125.85,93.48 126.71,93.48 126.95,93.72 126.95,94.96 127.43,95.45 127.74,95.45 127.97,95.22 127.97,94.12 128.31,93.77 128.31,91.18 128.28,91.16 128.28,90.95
CCD_USB20_P: length 55.5
  L4SGND w0.089: v2(125.7,93.96) 125.48,93.74 123.44,93.74 123.35,93.84 123.35,96.73 124.04,97.42 124.04,97.89 123.1,98.82 122.82,98.82 122.37,98.37 122.24,98.37 121.99,98.62 121.99,98.75 122.44,99.2 122.44,99.48 122,99.93 120.58,99.93 120.38,99.73 120.38,98.49 120.3,98.4 119.94,98.4 119.85,98.49 119.85,100.13 119.19,100.79 118.39,100.79 118.15,101.03 118.15,101.27 118.24,101.36 120.04,101.36 120.13,101.27 120.13,100.82 120.33,100.61 120.95,100.61 121.16,100.82 121.16,101.27 121.24,101.36 121.6,101.36 121.69,101.27 121.69,100.82 121.89,100.61 122.3,100.61 122.92,100 123.2,100 123.76,100.55 123.88,100.55 124.14,100.3 124.14,100.18 123.58,99.62 123.58,99.33 124.52,98.39 124.52,98.17 124.72,97.97 126.06,97.97 126.15,97.88 126.15,97.53 126.06,97.44 124.98,97.44 124.19,96.66 124.19,95.78 124.39,95.58 125.37,95.58 125.5,95.58 v2(125.75,95.34)
  BOTTOM w0.076: 128.51,90.98 128.51,90.96 129.11,90.36 129.11,90.07 129.11,90.06 129.09,89.98 CPU1.CC2
  BOTTOM w0.102: EL5501.3 125.97,100.18 127.1,99.05 127.1,98.5 126.87,98.27 126.57,98.27 126.47,98.16 126.47,97.76 126.57,97.66 126.74,97.66 126.97,97.42 126.97,96.26 126.31,95.59 126,95.59 v2(125.75,95.34) ; 128.19,94.76 128.19,94.21 128.54,93.87 128.54,91.09 128.51,91.06 128.51,90.98 ; 128.19,94.76 128.19,95.31 127.83,95.67 127.34,95.67 126.72,95.06 126.72,93.81 126.62,93.71 125.95,93.71 v2(125.7,93.96) ; 128.19,94.76 v1(128.35,94.76)
CFG3: length 8.7
  BOTTOM w0.102: CPU1.R3 99.56,89.13 99.28,89.4 99.28,90.38 99.31,90.41 99.31,90.82 99.05,91.08 97.82,91.08 97.21,91.69 96.42,91.69 v1(95.89,92.22) 95.12,92.98 94.51,92.98 R1517.1
CFG4: length 12.3
  BOTTOM w0.102: CPU1.J4 95.54,88.53 95.54,89.9 93.85,91.59 89.92,91.59 v1(88.14,89.81) 88.14,90.11 R1518.1
CFG_RCOMP: length 3
  TOP w0.254: v1(104.29,88.74) 104.06,88.51 103.59,88.51 103.4,88.32 R601.2
  TOP w0.508: R601.2 103.85,87.81 v2(103.85,87.2)
  BOTTOM w0.254: CPU1.AB5 103.48,87.52 103.8,87.2 v2(103.85,87.2)
CHG_AMBER_LED#: length 9
  BOTTOM w0.127: Q2416.3 125.51,10.39 125.15,10.03 R2498.1 125.15,8.53 124.89,8.27 v1(124.05,8.27) 123.9,8.43 121.36,8.43 121.23,8.55 R6421.1 121.23,9.52 121.46,9.75 121.46,10.13 121.33,10.26 Q6404.1
CHG_AMBER_LED_R#: length 10.5
  BOTTOM w0.127: Q6402.B 121.4,16.08 122.87,14.61 122.87,14.06 123,13.93 123,11.16 123.29,10.87 123.29,9.72 123.24,9.67 v1(123.24,9.66) 123.23,9.66 123.19,9.62 123.06,9.62 122.35,8.91 R6421.2 122.1,9.64 122.29,9.84 Q6404.6
CHGR_PSYS_IMVP: length 58.8
  TOP w0.102: PR4413.1 34.57,41.57 35.79,41.57 v2(35.84,41.62) 35.84,42.18 35.51,42.51 35.51,43.63 35.65,43.77 PU4401.30
  L4SGND w0.102: v2(46.86,78.35) 44.43,78.35 41.2,75.13 40.31,75.13 38.15,72.97 38.15,68.75 39.47,67.43 39.47,64.74 39.09,64.36 37.62,64.36 36.96,63.7 36.96,58.44 37.44,57.96 37.44,54.91 37.74,54.6 37.8,54.6 37.95,54.45 37.95,50.64 38.58,50.01 38.58,49.5 36.65,47.57 36.65,44.14 37.01,43.78 37.01,42.16 36.42,41.57 35.89,41.57 v2(35.84,41.62)
  BOTTOM w0.102: PR4614.1 49.23,83.2 v1(49.23,82.38) 49.23,81.91 48.95,81.63 48.32,81.63 47.58,80.89 47.58,80.64 46.93,79.99 46.93,78.42 v2(46.86,78.35) 46.96,78.25 PU4601.1
CLK_PCIE_PEG_REQ0_N: length 20.6
  TOP w0.102: v2(131.32,70.34) 131.32,69.18 132.45,68.05 133.04,68.05 133.78,67.32 133.78,66.06 138.19,61.65 138.23,61.65 138.32,61.56 138.34,61.56 138.92,60.97 138.92,59.27 140.55,57.64 v1(140.83,57.64) 140.86,57.67 RN1813.6
  BOTTOM w0.102: CPU1.CF32 131.09,70.58 v2(131.32,70.34)
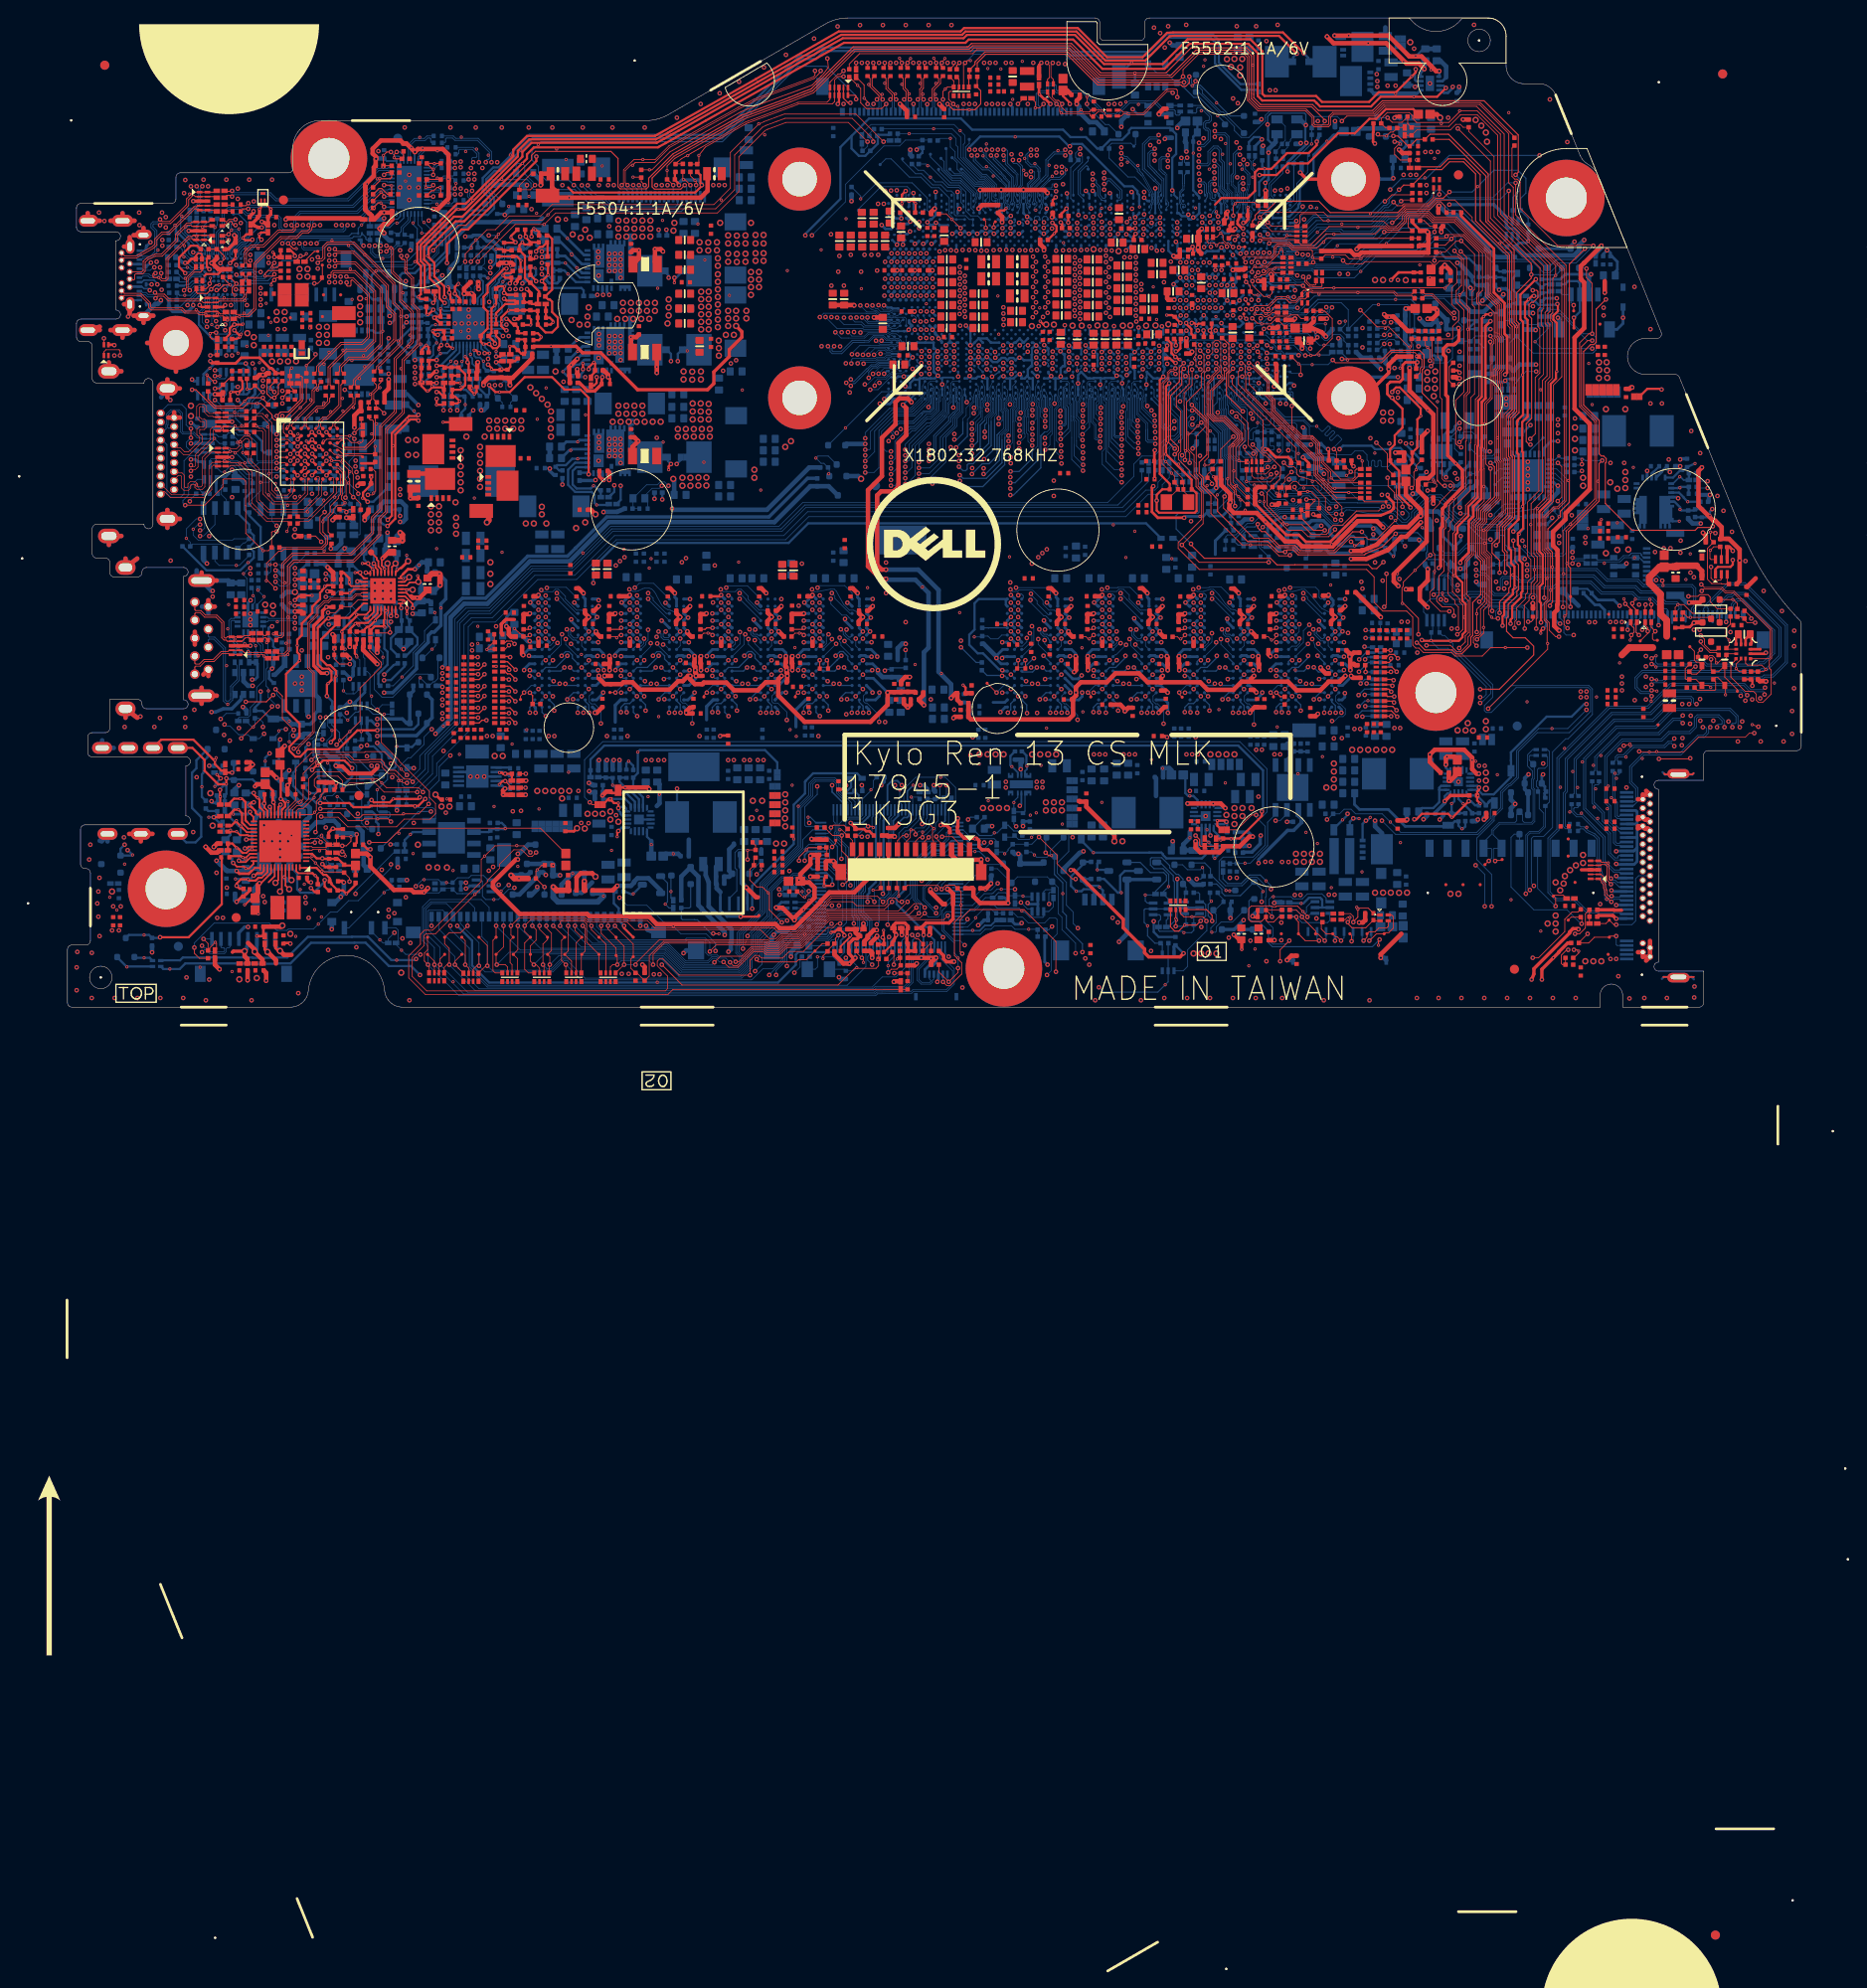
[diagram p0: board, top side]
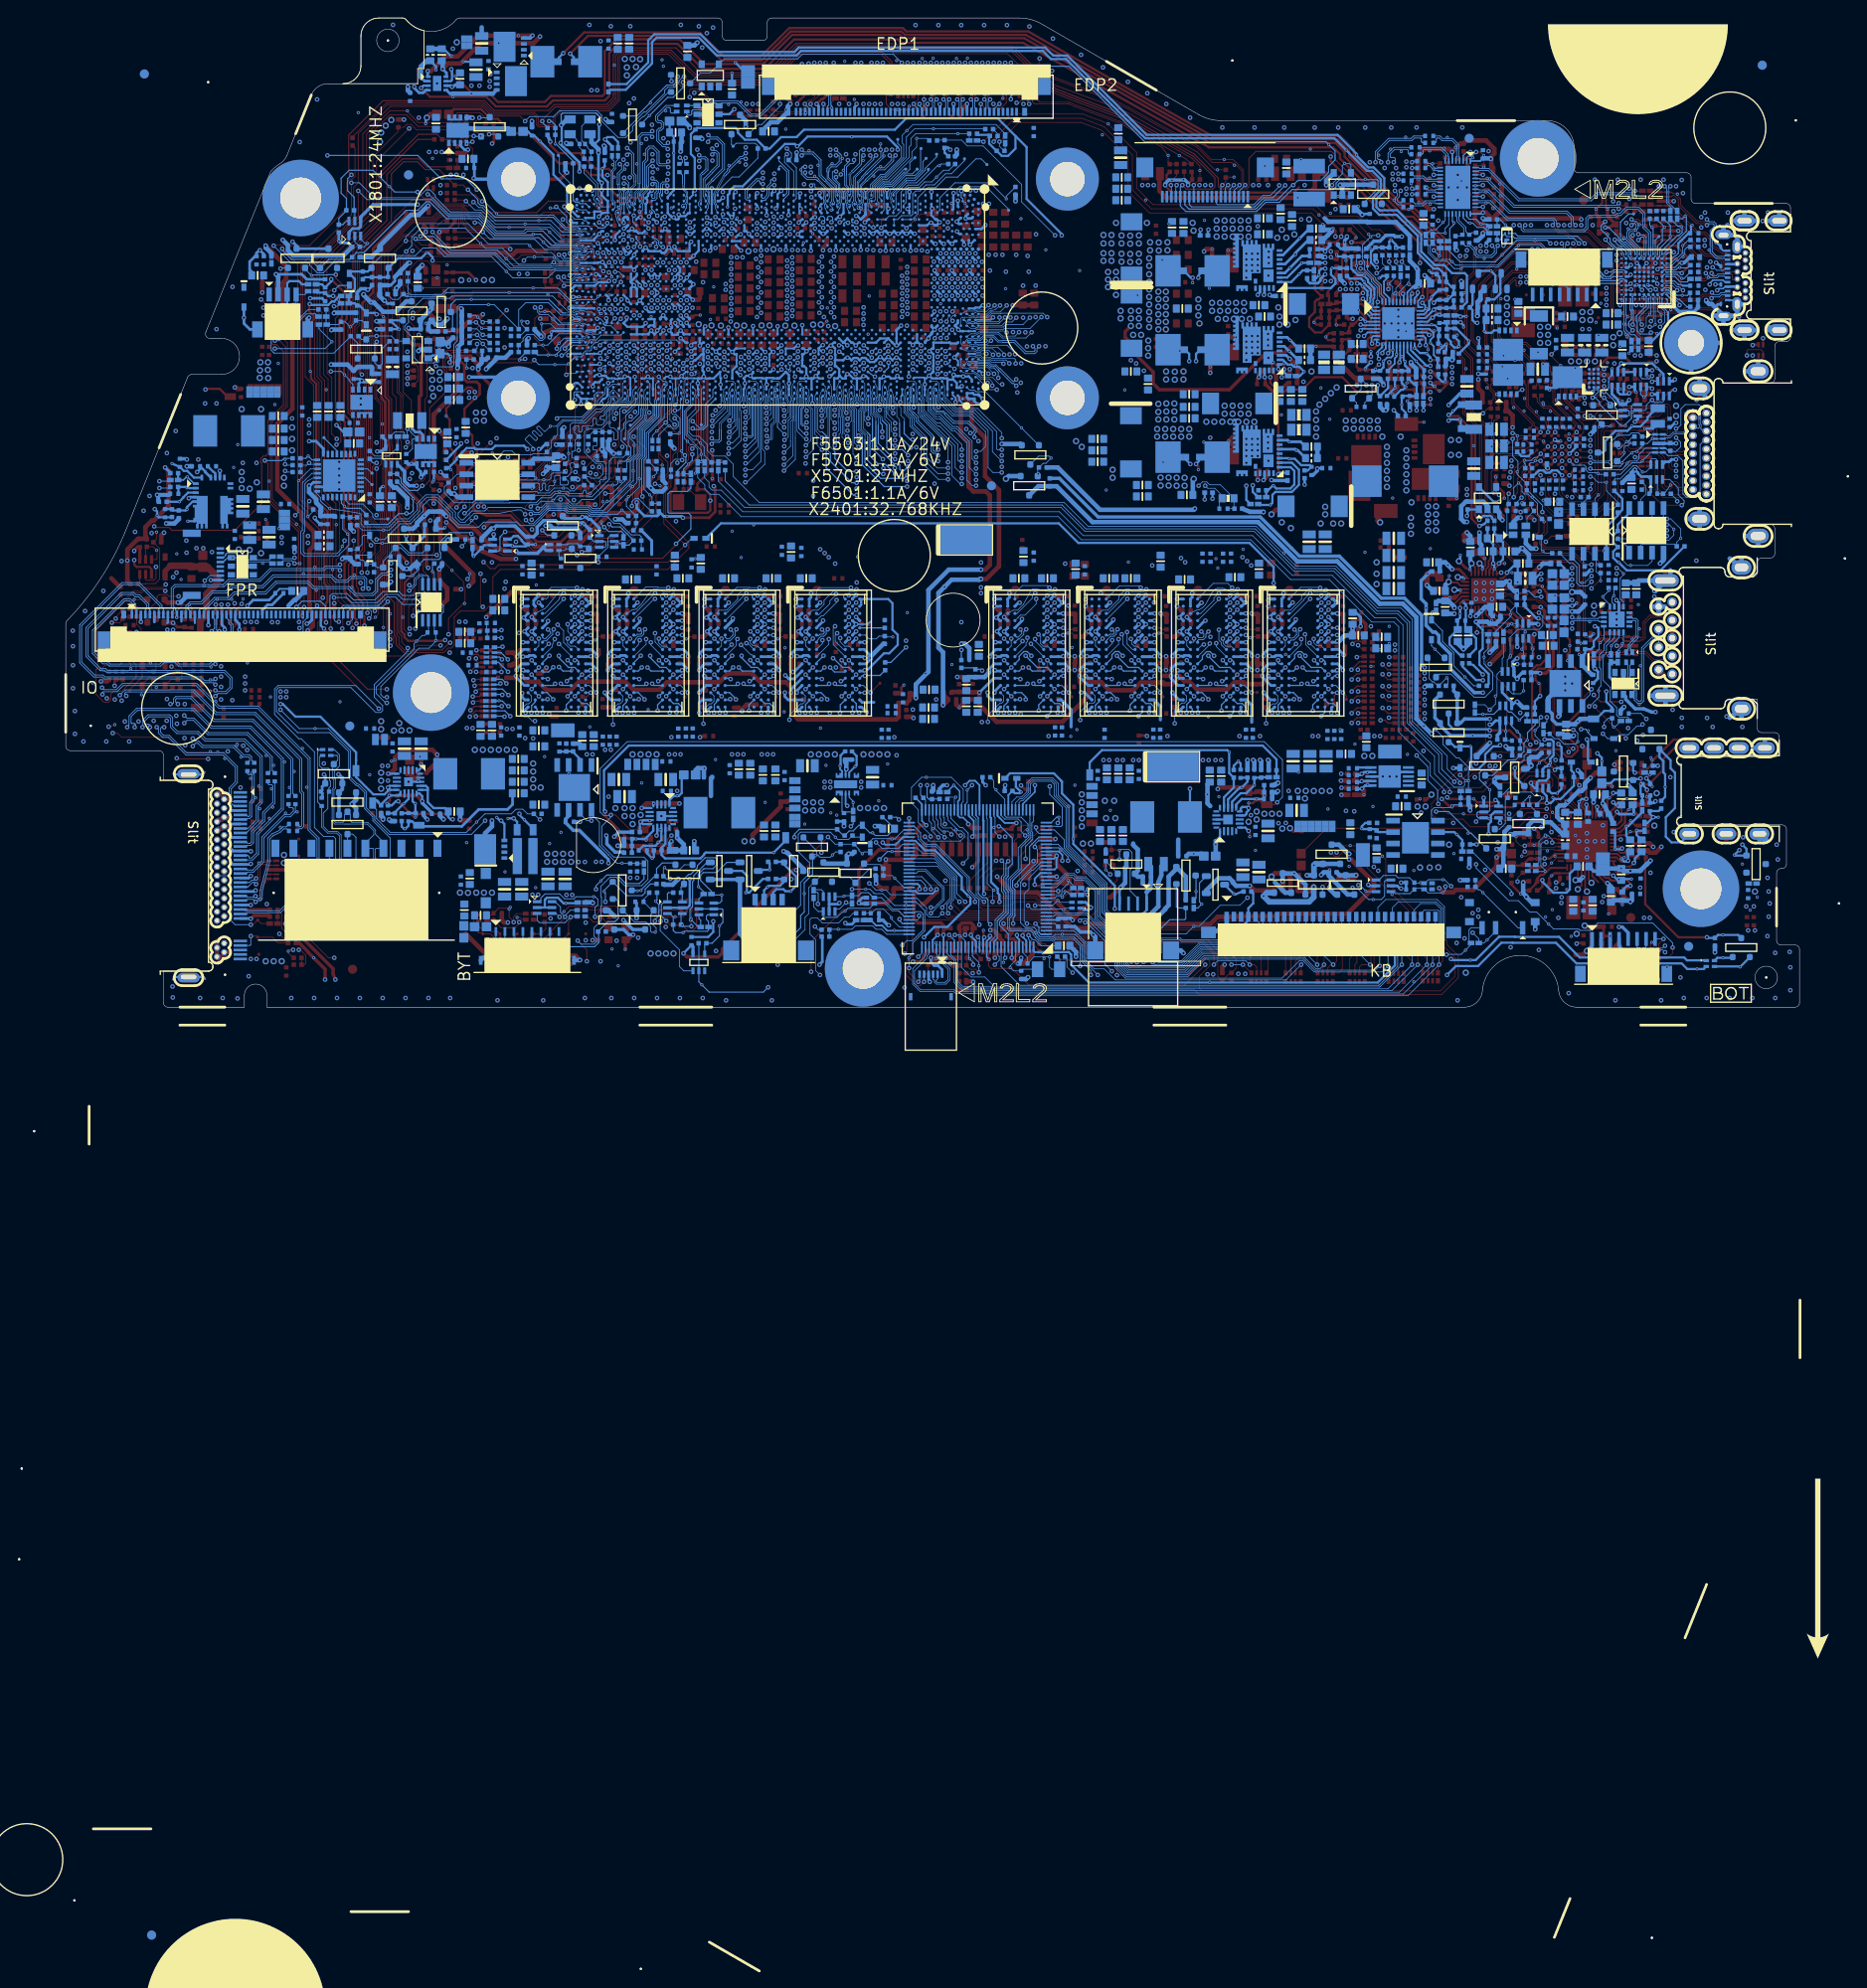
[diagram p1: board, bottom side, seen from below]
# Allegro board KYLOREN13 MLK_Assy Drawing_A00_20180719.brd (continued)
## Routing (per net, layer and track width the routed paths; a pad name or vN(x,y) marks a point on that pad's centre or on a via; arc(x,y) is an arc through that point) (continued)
CLK_PCIE_PEG_REQ2_N: length 21.5
  TOP w0.102: RN1802.4 143.56,59.12 142.9,58.46 140.76,58.46 v1(140.43,58.79) 140.36,58.86 140.36,59.48 139.33,60.51 139.33,61.14 138.95,61.52 138.95,62.59 138.24,63.3 137.14,63.3 134.16,66.28 134.16,67.48 133.5,68.13 133.5,69.52 131.45,71.57 v2(131.27,71.57)
  BOTTOM w0.102: v2(131.27,71.57) 130.96,71.88 CPU1.CF30
CLK_PCIE_PEG_REQ5_N: length 21.5
  TOP w0.102: v2(131.3,70.96) 131.79,70.96 133.31,69.44 133.31,68.05 133.97,67.4 133.97,66.2 137.06,63.11 138.15,63.11 138.75,62.51 138.75,61.44 139.13,61.06 139.13,60.03 v1(139.32,59.84) 139.7,59.84 140.08,59.45 140.08,58.44 140.26,58.26 RN1813.5
  BOTTOM w0.102: v2(131.3,70.96) 131.03,71.23 CPU1.CF31
CLK_TP_SIO: length 63
  TOP w0.089: RN6501.4 142.57,10.39 142.88,10.08 142.88,9.49 ; 142.88,9.49 v2(142.88,9.44) ; 142.88,9.49 143.38,10 v1(143.38,10.89) 143.49,11 144.55,11 EC6501.1 145.29,10.25 RN6502.1
  L6 w0.089: v2(96.52,10.43) 97.28,10.43 97.73,10.88 108.02,10.88 108.07,10.83 110.81,10.83 111.41,11.43 127.03,11.43 127.14,11.33 129.16,11.33 129.67,10.82 132.07,10.82 134.12,8.77 142.28,8.77 142.88,9.37 v2(142.88,9.44)
  BOTTOM w0.089: U2401.78 97.06,15.29 95.04,13.27 95.04,11.9 95.61,11.34 95.61,11.31 96.48,10.44 96.48,10.43 v2(96.52,10.43)
CLKRUN#: length 20.2
  TOP w0.102: R1818.1 130.96,55.9 v1(130.13,56.72) 129.84,57.02 129.84,57.27 129.84,57.46 129.74,57.56 129.74,57.56 129.53,57.77 129.53,57.77 129.24,58.07 129.24,62.18 130.18,63.12 130.18,63.6 128.5,65.28 127.38,65.28 126.81,65.85 126.81,69.26 127.34,69.79 127.34,70.03 128.03,70.72 128.03,71.06 127.63,71.47 v2(127.63,71.57)
  BOTTOM w0.102: CPU1.BY30 127.33,71.88 127.63,71.58 v2(127.63,71.57)
CMP_VIN0_R: length 185.5
  TOP w0.089: v2(52.07,17.19) 51.66,16.78 51.63,16.78 51.61,16.76 51.26,16.76 51.24,16.78 51.18,16.78 50.48,17.48 49.59,17.48 48.01,15.89 48.01,15.43 46.68,14.1 46.68,13.93 45.59,12.84 v1(45.28,12.53) 44.83,12.08 44.83,12.08 40.91,8.16 39.84,8.16 39.61,7.93 39.61,6.83 38.31,5.53 38.31,3.41 39.91,1.81 66.43,1.81 66.67,2.05 66.67,3.45 65.53,4.59 65.53,5.1 65.79,5.35 66.17,5.35 67.97,3.55 v2(75.84,3.55) 75.84,5.19 76.4,5.75 76.82,5.75 77.11,5.45 79.45,5.45 80.18,6.18 81.77,6.18 84.43,8.84 85.07,8.84 85.52,9.29 v2(85.85,9.29) ; v2(91.87,3.78) R2494.2 R2609.2 C2613.1
  L6 w0.089: v2(75.84,3.55) 76.71,2.69 86.65,2.69 87.39,3.43 91.52,3.43 v2(91.87,3.78) ; v2(66.78,57.93) 66.91,57.8 66.91,56.07 63.15,52.31 54.2,52.31 42.28,40.39 41.82,40.39 37.22,35.8 37.22,29.18 37.06,29.02 37.06,29.02 35.41,27.37 35.41,26.4 35.03,26.02 35.03,25.09 37.39,22.73 38.14,22.73 41.19,19.68 49.57,19.68 50.08,19.18 50.11,19.18 51.83,17.45 51.83,17.43 v2(52.07,17.19)
  BOTTOM w0.089: v2(66.78,57.93) 66.35,58.36 65.86,58.36 65.55,58.04 64.34,58.04 R2610.1 62.84,55.44 R2608.2 C2612.1 ; v2(85.85,9.29) 86.15,9.59 86.15,12.6 85.62,13.12 85.62,14.34 84.27,15.69 U2401.20
CMP_VOUT0: length 169.1
  TOP w0.089: R2602.2 R2615.2 149.94,97.46 153.66,97.46 154.28,98.08 154.76,98.08 155.08,97.76 R2607.2 155.7,97.3 158.52,94.49 158.52,87.81 164.03,82.3 164.03,77.6 163.79,77.35 163.79,75.77 164,75.56 164,70.3 163.49,69.79 163.49,57.37 162.24,56.11 162.24,50.1 162.6,49.73 162.6,47.62 162.24,47.25 162.24,46.08 162.1,45.95 162.01,45.85 162.01,45.35 161,44.35 161,43.03 160.83,42.86 160.83,42.17 v2(160.78,42.13)
  L6 w0.089: v2(103.36,13.75) 107.12,13.75 108.23,12.64 127.53,12.64 127.64,12.53 129.66,12.53 129.92,12.28 131.12,12.28 131.62,12.79 133.14,12.79 133.39,12.53 134.68,12.53 135.73,11.48 143.89,11.48 145.33,10.04 154.96,10.04 156.54,11.62 159.38,11.62 162.59,14.84 162.59,15.04 167.8,20.24 167.8,31.39 165.61,33.57 165.61,33.59 165.58,33.63 165.58,35.41 165.25,35.74 165.25,36.16 160.78,40.63 v2(160.78,42.13)
  BOTTOM w0.089: U2401.85 101,12.49 101.5,13 v1(101.98,13) 102.61,13 102.74,13.13 102.74,13.13 v2(103.36,13.75)
CNV_RGI_DT: length 42.7
  TOP w0.089: R1515.2 151.18,58.31 151.87,58.31 v1(151.89,58.34) 151.89,58.31 152.15,58.06 152.15,57.85 R1516.1 151.71,57.42 151.16,57.42 v2(151.13,57.4)
  L6 w0.089: v2(151.13,57.4) 149.6,58.93 149.6,61.51 150.03,61.94 150.03,63.63 149.56,64.11 149.56,75.48 146.18,78.85 137.5,78.85 137.16,78.5 135.89,78.5 135.11,79.29 132.26,79.29 v2(131.57,78.59)
  BOTTOM w0.089: v2(131.57,78.59) 131.57,78.87 CPU1.CG19
CNV_WT_RCOMP: length 4.4
  TOP w0.089: v2(137.03,70.26) 137.03,71.25 v1(136.8,71.47) 136.04,72.24 R2101.2
  BOTTOM w0.089: CPU1.CP32 135.84,70.6 CPU1.CR32 136.03,70.41 136.87,70.41 v2(137.03,70.26)
CPU_D4_TP: length 1.3
  TOP w0.102: TP1804.1 130.71,76.75 v2(130.98,76.48)
  BOTTOM w0.102: CPU1.CG23 131.31,76.15 v2(130.98,76.48)
CPU_D6_TP: length 1.4
  TOP w0.102: v2(130.9,78.64) 130.9,78.43 TP1806.1
  BOTTOM w0.102: v2(130.9,78.64) 131.03,78.51 131.03,78.36 CPU1.CG20
CPU_DP1_CTRL_CLK: length 4.5
  TOP w0.089: v2(128.83,84.5) 128.83,84.53 128.44,84.92 127.98,84.92 v1(127.69,84.63) 127.41,84.9 126.75,84.9 126.61,85.04 RN401.3
  BOTTOM w0.089: CPU1.CC8 129.25,85.33 128.83,84.91 v2(128.83,84.5)
CPU_DP1_CTRL_DATA: length 3.9
  TOP w0.089: v2(129.51,84.46) 129.44,84.46 129,84.9 128.74,84.9 128.57,85.06 128.4,85.24 128.4,85.74 v1(128.14,86) 127.7,85.56 RN401.4
  BOTTOM w0.089: v2(129.51,84.46) 129.25,84.71 CPU1.CC9
CPU_DP2_CTRL_CLK: length 6.6
  BOTTOM w0.089: RN403.4 131.28,94.19 131.55,93.92 131.55,93.14 131.84,92.85 131.84,92.22 ; 131.84,92.22 131.84,89.69 131.6,89.45 131.6,88.85 CPU1.CH4 ; 131.84,92.22 v1(131.7,92.22)
CPU_DP2_CTRL_DATA: length 5.8
  BOTTOM w0.089: CPU1.CH3 131.86,89.44 132.03,89.61 132.03,92.93 131.74,93.22 131.74,93.59 ; 131.74,93.59 131.74,94.02 131.95,94.22 RN403.3 ; 131.74,93.59 v1(131.88,93.59)
CPU_DP_HPD_P: length 3.7
  BOTTOM w0.102: Q401.3 159.88,85.35 159.38,84.85 v1(159.13,84.85) 159.51,84.47 R406.2 160.53,85.03 Q401.2
CPU_I2C_SCL_ISH: length 205.4
  TOP w0.089: v2(62.23,91.33) 61.98,91.59 61.98,92.94 62.58,93.54 v1(62.79,93.54) 63.09,93.85 65.25,93.85 66.95,95.54 74.62,99.8 74.89,99.93 75.63,100.31 76.33,100.7 82.97,103.18 83.38,103.58 83.38,103.58 83.5,103.72 83.69,103.91 v2(83.69,104.03) ; U7001.1 185.19,38.4 184.82,38.03 184.82,36.68 186.41,35.1 187.32,35.1 187.63,34.79 187.63,34.13 187.88,33.88 188.39,33.88 189.31,34.79 189.31,37.46 189.1,37.66 189.1,38.51 189.36,38.76 189.36,42.04 185.19,46.21 184.28,46.21 183.85,46.64 181.86,46.64 v2(181.54,46.96) ; R2020.2 150.82,79.25 151.68,79.25 153.78,77.15 v2(154.07,77.15)
  L4SGND w0.089: v2(181.54,46.96) 181.46,46.88 181.12,46.88 180.67,47.33 180.51,47.33 178.78,49.07 178.78,51.56 178.55,51.79 178.22,52.12 170.35,52.12 169.79,52.68 169.79,52.69 168.93,53.55 163.91,53.55 163.27,54.18 159.89,54.18 159.89,54.18 159.59,54.18 154.57,59.2 154.31,59.2 v2(154.18,59.33) ; v2(83.69,104.03) 83.47,104.25 83.47,104.44 83.57,104.54 84.47,104.54 86.72,106.78 111.28,106.78 112.53,105.52 126.17,105.52 131.15,100.54 131.15,100.4 132.11,99.44 141.99,99.44 143.22,98.21 146.67,98.21 151.77,93.11 151.77,88.45 152.72,87.5 153.12,87.5 155.29,85.33 155.29,84.96 155.21,84.88 155.21,77.8 154.39,76.98 154.24,76.98 154.08,77.15 v2(154.07,77.15)
  L6 w0.089: v2(154.07,77.15) 154,77.15 153.71,76.86 153.71,76.37 153.73,76.35 153.73,74.98 153.99,74.72 153.99,61.15 154.5,60.65 154.5,59.48 154.41,59.39 154.24,59.39 v2(154.18,59.33)
  BOTTOM w0.089: TCBD1.4 62.8,90.76 v2(62.23,91.33)
CPU_I2C_SCL_ISH0: length 20.6
  TOP w0.089: v2(131.57,77.55) 131.97,77.95 133.4,77.95 134.38,78.94 135.59,78.94 v1(135.61,78.91) 136.02,78.5 136.45,78.5 136.85,78.9 137,78.9 137.16,79.06 RN2007.2 137.16,79.45 137.35,79.64 138.3,79.64 138.4,79.54 147.42,79.54 147.76,79.2 149.36,79.2 R2020.1
  BOTTOM w0.089: CPU1.CH20 131.57,77.68 v2(131.57,77.55)
CPU_I2C_SCL_ISH1: length 3
  TOP w0.089: RN2008.1 134.12,77.84 133.95,77.67 133.95,77.52 133.58,77.15 133.24,77.15 133.15,77.06 v1(133.15,77.06) 133.12,77.06 132.8,77.38 v2(132.8,77.55)
  BOTTOM w0.089: CPU1.CJ22 132.8,77.23 v2(132.8,77.55)
CPU_I2C_SCL_P0: length 140.2
  TOP w0.089: v2(133.83,10.04) 133.83,10.13 EC6503.1 133.2,10.81 R6505.1
  L3SGND w0.089: v2(133.83,10.04) 133.97,10.04 135.15,11.22 135.15,14.58 134.18,15.56 134.18,16.72 134.38,16.92 135.19,16.92 135.39,16.72 135.39,16.41 v2(135.67,16.13)
  L6 w0.089: v2(135.67,16.13) 135.41,15.87 135.41,15.73 136.33,14.81 152.97,14.81 153.33,14.45 158.72,14.45 160.13,15.86 160.13,16.06 165.34,21.27 165.34,28.92 162.78,31.48 162.78,35.5 158.53,39.75 158.53,41.57 158.23,41.88 158.23,42.48 155.31,45.4 154.4,45.4 153.71,46.08 153.71,47.9 153.99,48.18 153.99,55.58 154.1,55.68 154.1,58.11 153.85,58.36 153.6,58.6 153.6,59.05 152.6,60.05 152.6,64.23 153.19,64.82 153.19,71.54 152.79,71.94 152.79,76.99 152.53,77.24 150.61,79.17 150.24,79.17 149.4,80 140.34,80 137.47,82.88 137.47,83.39 v2(137.24,83.62)
  BOTTOM w0.076: CPU1.CN11 135.14,83.94 135.32,83.76 arc(135.4,83.71) 135.48,83.69 135.65,83.69 135.73,83.72 135.78,83.72 135.79,83.73 136.1,83.73 136.57,83.26 137.23,83.26 137.32,83.43 137.31,83.55 v2(137.24,83.62)
  BOTTOM w0.089: v2(133.83,10.04) 133.83,11.06 133.53,11.36 133.53,11.98 133.81,12.27 v1(133.99,12.27) 135.96,12.27 136.19,12.04 137.22,12.04 137.77,12.59 139.38,12.59 139.64,12.34 139.64,12.34 139.86,12.12 139.86,11.85 140,11.72 Q6504.1
CPU_I2C_SCL_P1: length 86.7
  TOP w0.089: R5521.2 R5517.2 70.15,93.85 v1(70.15,94.63) 70.88,95.57 75.43,98.17 75.45,98.18 75.68,98.27 80.55,100.08 81.14,100.31 81.23,100.35 84.98,100.35 85.22,100.59 U5504.7 U5504.4 85.22,103.01 85.61,103.4 v2(86.23,103.4)
  L4SGND w0.089: v2(132.92,83.83) 133.55,84.46 133.69,84.46 134.18,84.95 134.18,89.87 133.57,90.48 133.57,93.04 131.37,95.24 131.37,96.77 127.59,100.54 127.59,101.79 125.56,103.82 116.97,103.82 116.49,103.34 98.29,103.34 97.98,103.65 86.49,103.65 v2(86.23,103.4)
  BOTTOM w0.089: CPU1.CJ12 132.61,83.54 132.91,83.83 v2(132.92,83.83)
CPU_I2C_SCL_TP: length 10.9
  TOP w0.089: R6505.2 136.53,10.81 137.17,10.17 v2(137.17,10.03) 137.17,9.98 138.68,8.46 AFTP6534.1 138.94,8.15 v2(139.7,7.38)
  BOTTOM w0.089: Q6504.6 138.27,11.72 137.67,11.12 137.67,10.54 v2(137.17,10.03) 137.17,10.17 136.57,10.77 RN6503.3 ; TP1.6 139.85,7.53 v2(139.7,7.38)
CPU_I2C_SCL_TS: length 3
  TOP w0.089: R5521.1 69.22,92.37 v1(69.72,91.86) 69.85,91.74 v2(69.85,91.33)
  BOTTOM w0.089: v2(69.85,91.33) 69.8,91.28 TCBD1.18
CPU_I2C_SDA_ISH: length 194.8
  TOP w0.089: v2(154.11,76.54) 154.11,76.54 154.09,76.59 154.07,76.58 154.07,76.58 153.67,76.98 153.67,77 151.61,79.06 150.84,79.06 R2021.2 ; U7001.4 189.03,38.71 189.17,38.84 189.17,41.96 185.11,46.02 184.2,46.02 183.77,46.45 181.79,46.45 v2(181.59,46.25) ; v2(83.06,104.03) 83.06,103.53 82.87,103.34 76.25,100.87 75.54,100.47 74.53,99.97 66.83,95.7 65.31,94.18 v1(63.93,94.18) 62.94,94.18 61.79,93.02 61.79,91.52 v2(61.59,91.33)
  L4SGND w0.089: v2(154.43,58.69) 154.81,58.69 159.51,53.99 159.97,53.99 163.19,53.99 163.83,53.36 168.85,53.36 169.6,52.61 169.6,52.6 170.27,51.93 178.14,51.93 178.36,51.71 178.36,51.71 178.59,51.48 178.59,48.99 180.43,47.14 180.59,47.14 181.05,46.68 181.15,46.68 v2(181.59,46.25) ; v2(154.11,76.54) 154.22,76.54 155.4,77.72 155.4,84.8 155.48,84.88 155.48,85.41 153.2,87.69 152.8,87.69 151.96,88.53 151.96,93.19 146.75,98.4 143.3,98.4 142.06,99.63 132.18,99.63 131.34,100.48 131.34,100.62 126.25,105.71 112.61,105.71 111.36,106.97 86.64,106.97 84.4,104.73 83.49,104.73 83.28,104.52 83.28,104.25 v2(83.06,104.03)
  L6 w0.089: v2(154.11,76.54) 153.92,76.35 153.92,75.06 154.18,74.8 154.18,61.23 154.69,60.72 154.69,59.25 154.46,58.7 v2(154.43,58.69)
  BOTTOM w0.089: TCBD1.3 62.3,90.63 v2(61.59,91.33)
CPU_I2C_SDA_ISH0: length 18.7
  TOP w0.089: v2(133.41,77.55) 133.41,77.65 134.49,78.73 135.33,78.73 135.75,78.31 136.53,78.31 136.91,78.68 137.53,78.68 137.81,78.96 RN2007.1 137.81,79.36 137.9,79.45 138.22,79.45 138.33,79.35 138.94,79.35 139.07,79.22 v1(139.07,79.21) 139.21,79.35 147.35,79.35 147.68,79.01 149.43,79.01 R2021.1
  BOTTOM w0.089: CPU1.CK22 133.41,77.19 v2(133.41,77.55)
CPU_I2C_SDA_ISH1: length 4.1
  TOP w0.089: v2(132.19,77.55) 131.93,77.28 v1(131.93,77.01) 131.98,76.96 132.74,76.96 133,76.7 133.26,76.7 133.44,76.88 133.58,76.88 133.87,77.17 RN2008.2
  BOTTOM w0.089: CPU1.CH22 132.19,77.27 v2(132.19,77.55)
CPU_I2C_SDA_P0: length 143.7
  TOP w0.089: v2(137.78,10.02) 137.78,10.13 v1(137.29,10.61) 136.69,11.21 134.33,11.21 134.26,11.15 133.91,11.15 133.85,11.21 131.51,11.21 131.25,10.95 131.25,9.75 131.48,9.52 132.66,9.52 EC6504.1 133.17,9.67 133.39,9.45 134.02,9.45 134.62,10.05 R6506.1
  L3SGND w0.089: v2(134.96,16.13) 135.2,16.37 135.2,16.64 135.12,16.73 134.45,16.73 134.37,16.64 134.37,15.64 135.34,14.66 135.34,11.39 137.2,10.59 v2(137.78,10.02)
  L6 w0.089: v2(137.85,83.59) 137.66,83.4 137.66,82.95 140.42,80.19 149.48,80.19 150.32,79.36 150.69,79.36 152.67,77.38 152.98,77.07 152.98,72.02 153.38,71.62 153.38,64.74 152.79,64.15 152.79,60.13 153.8,59.13 153.8,58.68 153.86,58.61 154.29,58.19 154.29,58.03 154.29,55.6 154.19,55.5 154.19,48.1 153.9,47.82 153.9,46.16 154.48,45.59 155.39,45.59 158.42,42.56 158.42,41.95 158.72,41.65 158.72,39.83 162.97,35.58 162.97,31.56 165.53,29 165.53,21.19 160.32,15.98 160.32,15.78 158.8,14.26 153.25,14.26 152.89,14.62 136.25,14.62 135.22,15.65 135.22,15.87 v2(134.96,16.13)
  BOTTOM w0.076: CPU1.CM11 134.49,83.94 134.88,83.55 135.26,83.55 arc(135.28,83.55) 135.3,83.54 135.31,83.54 arc(135.33,83.54) 135.36,83.53 135.44,83.51 135.45,83.51 135.68,83.51 135.77,83.55 135.8,83.55 135.81,83.55 136.03,83.55 136.5,83.08 137.35,83.08 137.85,83.58 v2(137.85,83.59)
  BOTTOM w0.089: v2(137.78,10.02) 138.18,10.42 Q6504.4
CPU_I2C_SDA_P1: length 88.4
  TOP w0.089: v2(86.23,104.03) 85.85,103.65 85.6,103.65 84.73,102.78 U5504.5 U5504.6 84.73,100.87 84.39,100.54 81.19,100.54 81.07,100.49 80.48,100.25 75.61,98.44 75.35,98.35 69.21,94.83 v1(68.91,94.61) 68.84,94.62 68.2,94.25 67.84,93.94 67.59,93.69 ; 67.59,93.69 R5522.2 ; 67.59,93.69 R5518.2
  L4SGND w0.089: v2(133.55,83.82) 133.55,84.19 133.63,84.27 133.77,84.27 134.37,84.87 134.37,89.95 133.76,90.55 133.76,93.12 131.56,95.32 131.56,96.84 127.78,100.62 127.78,101.87 125.64,104.01 116.89,104.01 116.41,103.53 98.37,103.53 98.06,103.84 86.42,103.84 v2(86.23,104.03)
  BOTTOM w0.089: CPU1.CK12 133.26,83.54 v2(133.55,83.82)
CPU_I2C_SDA_TP: length 12
  TOP w0.089: v2(139.06,7.38) 137.54,7.38 AFTP6535.1 136.78,9.47 136.54,9.7 v2(136.54,10.02) 136.51,10.05 R6506.2
  BOTTOM w0.089: Q6504.3 140.27,9.64 140.03,9.4 137.16,9.4 v2(136.54,10.02) 136.46,10.1 RN6503.4 ; TP1.7 138.85,7.6 v2(139.06,7.38)
CPU_I2C_SDA_TS: length 3.3
  TOP w0.089: R5522.1 68.38,92.02 v1(68.45,91.94) 68.61,91.94 v2(69.22,91.33)
  BOTTOM w0.089: TCBD1.17 69.3,91.25 v2(69.22,91.33)
CPU_POPIRCOMP: length 1.8
  TOP w0.508: R304.2 124.33,73.48 v2(124.33,74.32)
  BOTTOM w0.254: CPU1.BP27 123.79,73.83 124.28,74.32 v2(124.33,74.32)
CPU_SMB_ALERT#: length 24.1
  TOP w0.102: R1551.2 135.76,80.23 137.2,80.23 v2(137.29,80.14) 137.59,79.84 139.55,79.84 139.64,79.93 153.01,79.93 v1(153.06,79.88) 153.67,80.49 R1552.1
  BOTTOM w0.076: 133.86,80.52 133.85,80.52 133.45,80.91 132.89,80.91 CPU1.CJ15
  BOTTOM w0.102: v2(137.29,80.14) 136.66,80.14 136.29,80.5 133.88,80.5 133.86,80.52
CPU_SMB_ALERT#_P0: length 5.5
  TOP w0.102: R1504.2 133.96,79.98 R1505.1 133.84,79.3 v1(133.5,78.96) 132.92,78.96 131.68,80.2 131.68,80.66 v2(131.67,80.67)
  BOTTOM w0.102: v2(131.67,80.67) 131.31,81.02 CPU1.CG15
CPU_SMB_ALERT#_P1: length 15.2
  TOP w0.102: v2(129.42,70.03) 129.42,69.22 136.53,62.12 136.53,60.77 R1555.1 137.03,60.27 v1(137.03,59.58) 137.08,59.53 137.67,59.53 R1801.1
  BOTTOM w0.102: CPU1.CC34 129.41,69.65 129.41,70.02 v2(129.42,70.03)
CPU_SMB_SCL: length 2.9
  TOP w0.089: v2(132.91,81.76) 133.18,81.76 133.47,82.06 134.11,82.06 v1(134.12,82.07) 134.24,82.19 RN1807.7
  BOTTOM w0.089: CPU1.CK14 133.26,82.12 v2(132.91,81.76)
CPU_SMB_SCL_P0: length 5.3
  TOP w0.089: RN1807.5 135.06,84.03 v1(134.87,84.22) 134.59,83.94 134.59,83.74 133.24,82.38 132.75,82.38 132.38,82.75 v2(132.28,82.75)
  BOTTOM w0.089: CPU1.CH14 131.96,82.44 v2(132.28,82.75)
CPU_SMB_SCL_P1: length 216
  TOP w0.089: RN1811.2 139.4,80.12 139.31,80.03 138.44,80.03 138.38,80.09 137.99,80.09 137.51,80.57 137.51,81.04 137.42,81.13 137.32,81.13 137.31,81.14 v2(137.31,81.15)
  L6 w0.089: v2(137.31,81.15) 137.52,80.92 137.52,80.56 138.63,79.46 149.17,79.46 150.01,78.62 150.38,78.62 152.15,76.85 152.24,76.76 152.24,71.71 152.64,71.31 152.64,65.04 151.76,64.17 151.76,58.48 152.33,57.91 152.33,57.66 152.97,57.02 152.97,52.42 153.45,51.93 153.45,48.41 153.17,48.13 153.17,45.86 154.17,44.86 155.08,44.86 157.68,42.26 157.68,41.65 157.99,41.34 157.99,39.44 162.24,35.2 162.24,31.25 164.79,28.7 164.79,21.5 159.58,16.29 159.58,16.08 158.5,15 153.55,15 153.2,15.35 141.92,15.35 139.39,17.88 135.08,17.88 133.96,16.76 132.21,16.76 131.16,15.72 113.33,15.72 111.28,17.78 103.71,17.78 103.19,17.26 101.01,17.26 98.41,14.66 95.17,14.66 95.17,14.66 94.66,14.66 94.65,14.66 94.11,14.66 93.71,14.27 90.19,14.27 89.62,13.7 88.64,13.7 88.2,14.15 87.13,14.15 86.7,14.58 83.69,14.58 83.05,15.21 81.73,15.21 79.62,13.1 v2(79.07,13.1) 78.89,12.87 78.46,12.87 78.26,12.67 76.44,12.67 75.81,12.04 67.81,12.04 65.77,10.01 53.48,10.01 49.82,13.66 49.12,13.66 v2(49.02,13.56)
  BOTTOM w0.076: v2(137.31,81.15) 136.96,80.8 136.51,80.8 136.12,81.2 135.75,81.2 135.63,81.16 135.45,81.16 135.22,81.24 CPU1.CN15
  BOTTOM w0.089: v2(49.02,13.56) 48.85,13.56 v1(48.18,12.9) 48.12,12.83 Q2601.3 ; v2(79.07,13.1) 79.27,12.9 79.5,12.9 R2459.2
CPU_SMB_SCL_THM: length 181.4
  L4SGND w0.089: v2(154.48,46.29) 154.53,46.34 154.72,46.34 154.97,46.09 154.97,43.86 156.76,42.07 157.02,41.81 157.02,40.74 168.19,29.57 168.19,23.55 161.56,16.91 147.34,16.91 146.12,15.68 141.56,15.68 140.45,14.57 132.27,14.57 131.09,13.4 127.41,13.4 126.57,12.56 119.68,12.56 118.68,13.56 114.75,13.56 112.12,13.56 110.99,14.69 106.88,14.69 106.32,15.25 104.04,15.25 103.71,14.92 99.26,14.92 98.73,15.45 94.37,15.45 92.97,14.06 88.95,14.06 88.45,14.56 86.05,14.56 85.41,13.93 85.41,13.13 82.66,10.37 76.01,10.37 75.44,10.94 68.56,10.94 65.54,7.91 48.02,7.91 44.85,11.09 40.78,11.09 39.11,12.76 39.11,13.19 39.11,13.19 v2(39.34,13.4)
  BOTTOM w0.089: U2601.8 152.99,47.79 153.08,47.88 153.31,47.88 153.75,47.44 153.75,46.9 154.36,46.29 v2(154.48,46.29) ; v2(39.34,13.4) 39.34,13 v1(39.62,12.72) 39.65,12.69 41.28,12.69 41.68,13.09 RN2602.4 41.82,13.2 42.66,13.2 42.76,13.14 C2608.1 42.82,13.07 43.29,12.61 43.91,12.61 43.91,12.62 44.91,12.62 45.12,12.83 Q2601.4
CPU_SMB_SDA: length 4.8
  TOP w0.089: v2(132.3,81.64) 131.98,81.31 v1(131.98,81.12) 132.41,81.12 132.65,81.36 133.08,81.36 133.31,81.6 133.31,81.63 133.55,81.86 133.86,81.86 134.12,81.6 RN1807.8
  BOTTOM w0.089: CPU1.CH15 131.96,81.3 v2(132.3,81.64)
CPU_SMB_SDA_P0: length 5.3
  TOP w0.089: RN1807.6 133.82,82.69 133.31,82.19 132.08,82.19 v1(131.93,82.34) 131.62,82.03 v2(131.62,81.69)
  BOTTOM w0.089: v2(131.62,81.69) 131.16,81.69 CPU1.CF15
CPU_SMB_SDA_P1: length 220.3
  TOP w0.089: v2(137.94,81.13) 137.7,80.89 137.7,80.65 138.07,80.28 138.46,80.28 138.52,80.22 138.64,80.22 138.73,80.31 RN1811.1
  L6 w0.089: v2(137.94,81.13) 137.71,80.91 137.71,80.64 138.71,79.65 149.25,79.65 150.09,78.81 150.46,78.81 152.28,76.99 152.43,76.84 152.43,71.79 152.83,71.39 152.83,64.96 151.96,64.09 151.96,58.55 152.52,57.99 152.52,57.74 153.16,57.1 153.16,52.49 153.64,52.01 153.64,48.33 153.36,48.05 153.36,45.94 154.25,45.05 155.16,45.05 157.87,42.34 157.87,41.73 158.18,41.42 158.18,39.52 162.43,35.27 162.43,31.33 164.98,28.77 164.98,21.42 159.77,16.22 159.77,16 158.57,14.81 153.47,14.81 153.12,15.16 141.84,15.16 139.31,17.69 135.15,17.69 134.04,16.57 132.28,16.57 131.24,15.53 113.25,15.53 111.2,17.59 103.79,17.59 103.26,17.07 101.09,17.07 98.49,14.47 95.09,14.47 95.09,14.47 94.73,14.47 94.73,14.47 94.18,14.47 93.79,14.08 90.26,14.08 89.7,13.51 88.56,13.51 88.12,13.96 87.05,13.96 86.62,14.39 83.61,14.39 82.97,15.02 81.81,15.02 79.28,12.49 v2(79.13,12.49) 78.94,12.68 78.54,12.68 78.34,12.48 76.52,12.48 75.89,11.85 67.89,11.85 65.85,9.82 53.4,9.82 49.95,13.26 v2(49.66,13.26)
  BOTTOM w0.076: v2(137.94,81.13) 137.35,80.54 136.53,80.54 136.03,81.03 135.77,81.03 135.66,80.99 135.42,80.99 135.15,81.09 135.14,81.1 135.07,81.12 134.54,81.12 CPU1.CM15
  BOTTOM w0.089: v2(49.66,13.26) 49.49,13.1 49.02,13.1 47.88,11.96 v1(47.37,11.96) 46.48,11.96 46.1,12.33 46.1,13.99 45.96,14.13 Q2601.6 ; v2(79.13,12.49) 79.34,12.71 79.59,12.71 R2447.2
CPU_SMB_SDA_THM: length 185.6
  L4SGND w0.089: v2(154.48,46.9) 154.48,46.85 154.64,46.69 155.16,46.17 155.16,43.94 156.83,42.26 156.84,42.26 157.21,41.89 157.21,40.82 168.38,29.65 168.38,23.47 161.64,16.72 147.42,16.72 146.2,15.49 141.64,15.49 140.53,14.38 132.35,14.38 131.17,13.21 127.48,13.21 126.65,12.37 119.6,12.37 118.6,13.37 114.83,13.37 112.04,13.37 110.91,14.5 106.8,14.5 106.25,15.06 104.12,15.06 103.79,14.73 99.18,14.73 98.65,15.26 94.45,15.26 93.05,13.87 88.87,13.87 88.37,14.37 86.13,14.37 85.6,13.85 85.6,13.05 82.74,10.18 75.93,10.18 75.36,10.75 68.64,10.75 65.61,7.72 47.94,7.72 44.77,10.9 40.71,10.9 38.92,12.68 38.92,13.2 v2(38.71,13.43)
  BOTTOM w0.089: v2(154.48,46.9) 154.48,46.8 154.35,46.67 154.25,46.67 153.94,46.98 153.94,47.52 153.39,48.07 153,48.07 152.89,47.95 152.46,47.95 152.34,47.84 U2601.7 ; Q2601.1 46.72,14.13 46.23,14.62 44.86,14.62 44.61,14.38 43.34,14.38 C2609.1 42.73,13.76 RN2602.3 41.62,13.76 41.22,14.16 v1(39.62,14.16) 39.44,14.16 v2(38.71,13.43)
CPVEE: length 4.3
  TOP w0.203: v2(20.28,21.7) 20.32,21.66 20.32,21.48 20.66,21.14 U2701.25
  BOTTOM w0.305: v2(20.28,21.7) 20.03,21.44 v1(18.42,21.44) 18.42,22.35 C2741.1
CTL2: length 2.8
  BOTTOM w0.102: U3401.7 20.07,41.03 20.9,40.2 v1(20.9,40.15) 20.89,40.14 20.95,39.62 R3406.2
CTL3: length 2.7
  BOTTOM w0.102: R3402.2 20.19,39.64 19.71,40.12 19.71,40.31 19.7,40.33 v1(19.7,40.37) 19.65,40.37 19.57,40.45 U3401.8
DAT_TP_SIO: length 61.3
  TOP w0.089: RN6502.2 145.18,9.6 EC6502.1 144.27,8.83 142.73,8.83 142.27,9.29 v2(142.27,9.44) 142.49,9.67 v1(142.49,9.97) 142.21,9.97 141.96,9.72 RN6501.3
  L6 w0.089: v2(96.52,11.07) 96.9,10.69 97.27,10.69 97.66,11.08 108.1,11.08 108.15,11.02 110.73,11.02 111.33,11.62 127.11,11.62 127.22,11.52 129.24,11.52 129.75,11.01 132.15,11.01 134.2,8.97 142.09,8.97 142.27,9.14 v2(142.27,9.44)
  BOTTOM w0.089: U2401.79 98.13,14.89 97.92,15.1 97.14,15.1 95.23,13.19 95.23,11.98 95.8,11.42 95.8,11.39 96.12,11.07 v2(96.52,11.07)
DBC_EN_R: length 4.7
  TOP w0.102: v2(88.9,100.35) 88.9,100.6 v1(88.52,100.98) 88.52,102.46 R5503.1
  BOTTOM w0.102: v2(88.9,100.35) 88.94,100.35 89.5,99.79 LCD1.6
DBC_PANEL_EN: length 151.4
  TOP w0.102: R2043.2 131.11,57.52 129.82,58.82 129.82,62.24 130.54,62.97 130.54,63.75 128.65,65.65 127.53,65.65 127.25,65.92 127.25,68.52 128.54,69.81 128.54,70.79 v2(128.63,70.88) ; v2(154.67,62.78) 154.71,62.78 155.19,63.26 155.19,67.83 155.19,68 155.6,68.41 155.6,77.52 154.69,78.44 v1(154.69,79.14) 155.13,79.58 155.13,83.07 154.61,83.59 154.55,83.59 v2(154.11,84.03) ; R5503.2 v2(87.63,104.92)
  L4SGND w0.102: v2(154.67,62.78) 151.47,62.78 150.03,61.33 148.51,61.33 147.8,62.04 146.53,62.04 146.2,62.38 146.2,63.21 145.8,63.62 145.19,63.62 v2(144.78,63.21) ; v2(87.63,104.92) 88.16,104.39 98.26,104.39 98.76,103.89 116.26,103.89 116.74,104.37 125.79,104.37 128.14,102.02 128.14,100.77 131.92,96.99 131.92,95.47 135.96,91.43 135.96,89.05 137,88.02 147.71,88.02 150.24,85.49 152.65,85.49 v2(154.11,84.03)
  L6 w0.102: v2(144.78,63.21) 144.58,63.01 139.19,63.01 138.81,63.39 135.38,63.39 128.63,70.14 v2(128.63,70.88)
  BOTTOM w0.102: v2(128.63,70.88) 128.48,70.88 CPU1.CA31
DC_IN_OFF: length 2.5
  BOTTOM w0.254: R4369.2 26.47,24.22 v1(26.92,23.77) 27.56,23.77 27.87,24.08 Q4349.3
DCBATOUT: length 83
  TOP w0.203: PU4401.3 37.51,45.65 38.35,44.8 v2(38.35,44.34)
  L3SGND w0.381: v2(121.41,108.22) 129.79,108.22 131.88,106.14 131.88,101.57 132.44,101.01 138.53,101.01 139.06,100.48 147.57,100.48 148.97,101.87 148.97,106.98 v3(149.2,107.21)
  L4SGND w1.016: v3(54.23,70.63) 54.23,80.03 54.48,80.28
  L6 w0.381: v2(121.41,108.22) 121.41,107.08 119.76,105.43 113.67,105.43 113.03,104.79 110.9,104.79 110.89,104.78 v2(110.85,104.78)
  BOTTOM w0.381: PD4407.A 37.76,26.56 v2(38.48,26.56) ; v2(132.59,19.07) 132.52,19 132.52,18.14 131.61,17.23 130.67,17.23 PR4509.1
  BOTTOM w0.508: PR4511.1 58.38,24.66 58.28,24.76 58.17,24.76 58.01,24.91 v2(57.94,24.91) ; v2(38.35,44.34) 38.35,44.47 39.01,45.13 PC4439.1 40.16,45.13 PR4477.2 ; PR4612.1 43.31,85.69 44.83,87.22 EC8912.1 47.98,87.22 47.99,87.23 48.05,87.27 52.38,87.27 52.76,87.65
  vias: v1(40.82,43.83) v1(48.29,50.54) v1(52.2,65.32) v1(52.4,22.01) v1(53.19,68.8) v1(53.39,88.03) v1(55.68,26.1) v1(136.73,25.93) v1(138.89,18.18) v1(162.18,33.93) v1(167,53.66) v1(168.96,53.18) v2(149.63,106.49) v2(168.66,52.22) v2(168.66,51.58) v3(46.99,49.42) v3(46.99,48.15) v3(46.99,47.01) v3(50.93,53.74) v3(51.44,68.85) v3(51.82,53.74) v3(52.07,68.22) v3(52.2,24.02) v3(52.7,67.58) v3(52.7,55.59) v3(52.7,54.76) v3(53.09,24.02) v3(53.21,53.74) v3(53.34,66.95) v3(53.72,66.19) v3(53.72,65.25) v3(53.7,64.31) v3(53.72,63.39) v3(53.98,24.02) v3(54.48,87.52) v3(54.86,24.02) v3(54.95,23.19) v3(55.75,24.02) v3(127,28.09) v3(127.89,28.09) v3(128.78,28.09) v3(129.67,28.09) v3(136.5,17.04) v3(136.5,16.15) v3(137.39,17.04) v3(137.39,16.15) v3(138.28,17.04) v3(138.28,16.15) v3(139.17,17.04) v3(139.17,16.15) v3(157.61,31.77) v3(157.61,30.88) v3(168.4,58.82) v3(168.4,57.93)
DCBATOUT_CAMERA: length 3
  TOP w0.254: R5511.2 110.62,101.24 111.38,100.48 v2(111.38,100.35)
  TOP w0.508: R5511.2 111.07,101.85 C5522.1
  vias: v1(112.65,97.55)
DDR_VREF_S3: length 1.6
  BOTTOM w0.279: PU5102.6 49.09,26.62 PC5123.1
DMIC_SCL_CODEC: length 180
  TOP w0.089: v2(108.84,104.92) 109.09,104.67 109.09,103.27 108.89,103.07 RN5503.4 ; v2(30.53,17.93) 30.99,17.93 31.5,18.43 v1(31.5,18.94) 30.68,18.94 FC2701.1 30.53,18.94 C2738.1 29.9,18.92 R2721.1
  L4SGND w0.089: v2(30.53,17.93) 30.16,18.29 30.16,22.31 25.22,27.25 25.21,27.25 24.86,27.61 22.23,27.61 21.88,27.95 21.88,28.66 23.48,30.25 23.48,31.86 22.33,33 22.33,35.16 23.93,36.76 23.93,56.87 25.37,58.31 27.27,58.31 28.48,59.52 29.12,59.52 29.59,59.99 29.59,66.42 31.4,68.23 31.4,68.84 31.05,69.19 31.05,79.06 32.07,80.07 32.07,81.63 31.55,82.15 31.55,84.56 29.42,86.7 29.42,88.44 32.89,91.92 32.89,95.26 34.14,96.51 71.09,96.51 77.29,102.71 84.17,102.71 87.13,105.68 108.98,105.68 109.07,105.59 109.07,105.15 v2(108.84,104.92)
DMIC_SCL_CODEC_R: length 3.9
  TOP w0.089: U2701.5 27.14,17.83 27.25,17.73 28.71,17.73 R2721.2 29.03,18.1 v1(28.19,18.94)
DMIC_SCL_CON: length 10.1
  TOP w0.089: RN5504.2 115.44,99.01 115.28,99.17 115.28,99.36 115.13,99.52 114.54,99.52 EC5504.1 113.7,98.98 113.62,99.08 113.63,99.18 113.55,99.28 110.49,99.28 v1(110.41,99.36) 110.25,99.52 110.25,100.04 110.16,100.13 110.11,100.13 v2(109.89,100.35) 109.89,100.37 109.03,101.23 109.03,101.54 RN5503.1
  BOTTOM w0.089: v2(109.89,100.35) 109.89,100.2 109.5,99.81 LCD1.46
DMIC_SCL_PCH: length 77.3
  TOP w0.089: v2(122.81,101.59) 122.65,101.75 122.19,101.75 119.59,99.14 117.78,99.14 117.68,99.24 117.32,99.24 117.09,99.01 RN5504.3
  L3SGND w0.089: v2(140.51,77.74) 140.34,77.93 140.34,77.98 141.19,78.82 149.28,78.82 151.42,80.97 151.42,84.24 150.41,85.26 150.06,85.64 150.06,86.78 151.49,88.21 152.62,88.21 153.02,88.61 153.02,93.09 152.35,93.76 147.6,93.76 146.7,94.66 146.7,97.28 145.93,98.05 144.5,98.05 143.99,97.54 139.19,97.54 138.39,98.34 138.39,99.13 137.62,99.9 131.57,99.9 130.37,101.11 130.05,101.11 129.91,100.96 v2(129.51,100.96)
  L6 w0.089: v2(129.51,100.96) 129.22,100.96 128.88,101.29 128.87,101.29 125.61,101.29 125.29,101.62 122.84,101.62 v2(122.81,101.59)
  BOTTOM w0.076: CPU1.CP24 135.46,75.73 135.57,75.83 135.64,75.91 arc(135.72,75.96) 135.82,75.98 136.1,75.98 136.25,75.82 136.88,75.82
  BOTTOM w0.089: 136.88,75.82 137.91,75.82 v1(138.53,76.45) 139.03,76.95 139.97,76.95 140.26,77.24 140.26,77.49 v2(140.51,77.74)
DMIC_SDA_CODEC: length 178.9
  TOP w0.089: RN5503.3 109.55,103.07 109.28,103.33 109.28,104.73 v2(109.47,104.92) ; v2(30.53,17.29) 30.61,17.29 30.86,17.04 v1(30.86,16.78) 30.39,16.78 30.26,16.92 30.14,16.92 R2738.1
  L4SGND w0.089: v2(30.53,17.29) 30.31,17.51 30.27,17.51 29.97,17.81 29.97,22.23 25.14,27.06 25.13,27.06 24.78,27.42 22.15,27.42 21.69,27.88 21.69,28.73 23.29,30.33 23.29,31.78 22.14,32.92 22.14,35.24 23.74,36.84 23.74,56.95 25.29,58.5 27.2,58.5 28.4,59.71 29.04,59.71 29.4,60.07 29.4,66.5 31.21,68.31 31.21,68.76 30.86,69.11 30.86,79.13 31.88,80.15 31.88,81.55 31.36,82.07 31.36,84.48 29.3,86.54 29.23,86.62 29.23,88.52 32.7,91.99 32.7,95.34 34.06,96.7 71.02,96.7 77.21,102.9 84.09,102.9 87.05,105.87 109.06,105.87 109.26,105.67 109.26,105.14 v2(109.47,104.92)
DMIC_SDA_CODEC_R: length 2.8
  TOP w0.089: R2738.2 28.66,17.54 28.02,17.54 ; v1(28.02,17.37) 28.02,17.54 ; 28.02,17.54 27.27,17.54 27.17,17.43 U2701.4
DMIC_SDA_CON: length 9.4
  TOP w0.089: RN5503.2 109.41,101.54 109.41,101.12 109.78,100.75 110.12,100.75 v2(110.52,100.35) 110.44,100.27 110.44,100.02 110.99,99.47 112.38,99.47 v1(112.62,99.71) 112.86,99.47 113.57,99.47 113.67,99.55 113.68,99.66 113.77,99.74 EC5503.1 115.69,99.71 RN5504.1
  BOTTOM w0.089: v2(110.52,100.35) 110,99.83 LCD1.47
DMIC_SDA_PCH: length 78.9
  TOP w0.089: v2(123.32,101.11) 123.32,101.87 123.19,102 122.17,102 122.11,101.94 119.51,99.33 117.86,99.33 117.76,99.43 117.32,99.43 117.09,99.66 RN5504.4
  L3SGND w0.089: v2(130.04,100.44) 130.04,100.83 130.13,100.92 130.29,100.92 131.5,99.71 137.54,99.71 138.2,99.05 138.2,98.27 139.12,97.35 144.07,97.35 144.58,97.86 145.85,97.86 146.51,97.2 146.51,94.58 147.52,93.57 152.27,93.57 152.83,93.01 152.83,88.69 152.55,88.4 151.41,88.4 149.87,86.86 149.87,85.56 150.27,85.13 151.23,84.17 151.23,81.04 149.2,79.01 141.11,79.01 140.15,78.06 140.15,78.02 v2(139.88,77.77)
  L6 w0.089: v2(130.04,100.44) 130.03,100.45 129.46,100.45 128.8,101.1 128.79,101.1 125.53,101.1 125.21,101.43 123.51,101.43 123.32,101.23 v2(123.32,101.11)
  BOTTOM w0.076: 136.8,76.01 136.31,76.01 136.17,76.16 135.83,76.16 arc(135.6,76.11) 135.4,75.98 135.02,75.98 134.85,75.81 CPU1.CN24
  BOTTOM w0.089: v2(139.88,77.77) 140.07,77.57 140.07,77.32 139.99,77.23 139.47,77.23 v1(139.42,77.28) 138.86,77.28 137.59,76.01 136.8,76.01
DP1_AUX_ALS_N: length 8.4
  TOP w0.102: v1(33.81,63.7) 33.97,63.7 ; 33.97,63.7 33.97,63.16 33.01,62.2 30.65,62.2 30.55,62.3 30.55,62.44 30.75,62.64 30.75,62.86 30.62,62.98 30.4,62.98 30.11,62.69 U5701.C8 ; 33.97,63.7 33.97,65.14 33.87,65.25 33.63,65.25 33.53,65.35 C5741.2
DP1_AUX_ALS_P: length 8.4
  TOP w0.102: U5701.C7 29.7,62.39 30.6,61.97 33.1,61.97 34.2,63.07 34.2,64.81 ; 34.2,64.81 34.2,65.51 C5740.2 ; 34.2,64.81 v1(34.34,64.81)
DP1_AUX_C_N: length 3.8
  TOP w0.102: 33.79,68.09 33.79,67.54 R5763.1 33.45,66.59 C5741.1 ; 33.79,68.09 33.79,68.27 34.33,68.81 34.33,69.15 34.06,69.42 C5739.2 ; 33.79,68.09 v1(33.66,68.09)
DP1_AUX_C_P: length 25.9
  TOP w0.102: 34.56,68.83 34.56,68.71 34.02,68.18 34.02,67.54 R5762.1 34.29,67.12 C5740.1 34.65,66.52 v2(35.18,65.98) ; 34.56,68.83 34.56,69.15 34.82,69.42 C5738.2 ; 34.56,68.83 v1(34.72,68.83) ; R5752.1 27.56,52.34 v2(28.19,51.71)
  L6 w0.089: v2(28.19,51.71) 28.32,51.83 28.32,53.99 29.84,55.52 33.53,55.52 35.18,57.17 v2(35.18,65.98)
DP1_AUX_CPU_N: length 111.5
  TOP w0.102: 31.22,84.78 31.75,84.78 36.14,80.38 36.14,78.21 36.98,77.37 36.98,73.81 34.34,71.17 34.34,70.91 C5739.1 ; 31.22,84.78 28.96,84.78 28.6,84.42 28.6,83.21 28.29,82.9 28.02,82.9 v2(27.81,82.7) ; 31.22,84.78 v1(31.22,84.63)
  L6 w0.089: v2(27.81,82.7) 27.94,82.82 28.31,82.82 28.47,82.66 28.47,80.28 28.85,79.89 38.75,79.89 40.83,81.97 40.83,82.97 42.86,85 44.92,85 49.28,89.37 52.52,89.37 53.85,90.7 77.96,90.7 79.48,89.17 82.83,89.17 84.95,91.29 94.67,91.29 98.01,87.95 102.25,87.95 103.5,86.71 103.5,86.26 v2(103.88,85.88)
  BOTTOM w0.102: v2(103.88,85.88) 104.22,86.22 CPU1.AC7
DP1_AUX_CPU_P: length 111.6
  TOP w0.102: v2(27.81,83.33) 28.02,83.13 28.19,83.13 28.37,83.3 28.37,84.51 28.86,85.01 29.39,85.01 ; v1(29.39,85.18) 29.39,85.01 ; 29.39,85.01 31.84,85.01 36.37,80.48 36.37,78.3 37.21,77.46 37.21,73.72 34.57,71.07 34.57,70.89 C5738.1
  L6 w0.089: v2(27.81,83.33) 28.13,83.01 28.38,83.01 28.66,82.74 28.66,80.36 28.93,80.09 38.68,80.09 40.64,82.05 40.64,83.05 42.78,85.19 44.84,85.19 49.2,89.56 52.44,89.56 53.77,90.89 78.04,90.89 79.56,89.36 82.75,89.36 84.87,91.48 94.75,91.48 98.09,88.14 102.33,88.14 103.87,86.6 103.87,86.58 v2(103.9,86.56)
  BOTTOM w0.102: v2(103.9,86.56) 103.9,86.56 104.2,86.87 CPU1.AC6
DP1_HPD_CPU: length 157.8
  TOP w0.127: v2(160.91,92.47) 161.21,92.77 161.21,96.9 157.4,100.7 146.1,100.7 145.02,99.62 139.01,99.62 138.34,100.28 132.57,100.28 131.81,101.05 131.81,101.41 131.81,105.81 131.04,106.58 124.85,106.58 122.07,103.81 114.81,103.81 111.55,107.07 100.44,107.07 100.08,106.7 99.96,106.7 87.31,106.7 82.63,102.01 81.79,101.7 81.14,101.44 80.17,101.05 74.87,99.08 67.27,94.8 64.58,92.1 64.58,91.18 64.31,90.91 61.42,90.91 61.18,91.16 61.18,94.29 60.39,95.08 52.01,95.08 51.56,94.63 51.56,94.16 44.27,86.86 43.41,86.86 v2(40.64,84.09)
  BOTTOM w0.127: v2(160.91,92.47) 161.33,92.05 161.33,90.71 160.6,89.98 R404.2 160.53,88.46 Q401.5 ; v2(40.64,84.09) v1(40.01,83.46) 39.93,83.53 R7227.1 R7149.2
DP1_HPD_CPU_R: length 44.8
  TOP w0.127: v2(153.56,90.57) 152.87,89.88 152.05,89.88 151.2,89.03 148.58,89.03 148.45,88.91 148.45,88.91 147.82,88.28 140.31,88.28 139.04,89.55 134.37,89.55 133.35,88.54 132.52,88.54 131.96,87.97 131.96,87.63 131.67,87.34 R403.1 132.2,86.84 v2(132.48,87.12)
  BOTTOM w0.127: CPU1.CM6 133.45,86.56 132.82,86.56 132.64,86.74 132.64,86.74 132.48,86.91 v2(132.48,87.12) ; v2(153.56,90.57) 156.08,90.57 v1(156.68,91.17) 158.5,92.98 161.16,92.98 162.05,92.09 162.05,90.44 161.47,89.86 R404.1 161.47,88.49 162.31,87.65 R405.2 161.85,86.94 161.46,87.33 Q401.6
DP2_AUX_C2_N: length 4.5
  BOTTOM w0.102: R7239.2 12.44,84.47 12.75,84.16 12.75,83.72 12.88,83.59 13.02,83.45 ; 13.02,83.45 13.5,82.97 13.63,82.97 14.18,82.42 15.02,82.42 U7201.J2 ; 13.02,83.45 v1(12.93,83.36)
DP2_AUX_C2_P: length 4.2
  BOTTOM w0.102: R7238.2 12.34,85.24 v1(12.98,84.6) 12.98,83.81 13.04,83.75 13.12,83.68 13.59,83.2 13.72,83.2 14.27,82.64 14.74,82.64 U7201.J1
DP2_AUX_C_N: length 3.7
  BOTTOM w0.102: U7101.25 37.77,87.9 37.84,87.82 37.84,87.42 37.08,86.66 37.08,86.2 C7102.1 36.6,85.82 36.37,86.05 R7101.2
DP2_AUX_C_P: length 3.6
  BOTTOM w0.102: U7101.24 38.17,87.87 38.07,87.77 38.07,87.32 37.31,86.56 37.31,85.97 C7101.1 37.62,85.67 R7102.2
DP2_AUX_CPU_N: length 90.9
  L6 w0.089: v2(103.25,94.63) 103.45,94.43 103.45,94.28 103.38,94.2 102.88,94.2 102.81,94.13 102.81,93.55 101.98,92.73 99.47,92.73 96.35,95.84 91.77,95.84 91.35,95.42 85.14,95.42 83.4,97.16 78.72,97.16 75.97,94.4 53.07,94.4 52.43,93.77 48.97,93.77 44.56,89.36 38.75,89.36 36.21,86.82 35.26,86.82 33.79,85.36 33.79,85.1 33.88,85.01 34.07,85.01 34.16,84.92 v2(34.16,84.6)
  BOTTOM w0.076: 104.27,93.1 104.28,93.09 104.28,93.04 105.08,92.24 105.08,89.73 105.08,89.66 105.08,89.58 105.27,89.39 105.27,89.13 CPU1.AD4
  BOTTOM w0.102: v2(103.25,94.63) 103.1,94.48 103.1,94.27 104.27,93.1 ; v2(34.16,84.6) 33.91,84.35 33.91,83.89 34.26,83.53 35.69,83.53 35.91,83.75 35.91,84.11 36.03,84.23 ; v1(35.94,84.32) 36.03,84.23 ; 36.03,84.23 C7102.2
DP2_AUX_CPU_P: length 90.9
  L6 w0.089: v2(102.62,94.63) 102.62,93.63 101.9,92.92 99.55,92.92 96.43,96.03 91.69,96.03 91.27,95.61 85.22,95.61 83.48,97.35 78.64,97.35 75.89,94.59 52.99,94.59 52.35,93.96 48.9,93.96 44.49,89.55 38.67,89.55 36.13,87.01 35.18,87.01 33.6,85.44 33.6,84.68 v2(33.53,84.6)
  BOTTOM w0.076: CPU1.AD3 104.94,89.17 104.83,89.17 104.75,89.24 104.75,89.42 104.92,89.59 104.92,89.66 104.92,89.73 104.92,92.17 104.15,92.94 104.11,92.94
  BOTTOM w0.102: v1(35.03,83.18) 35.03,83.3 ; 35.03,83.3 34.17,83.3 33.68,83.79 33.68,84.45 v2(33.53,84.6) ; 35.03,83.3 35.79,83.3 36.13,83.65 36.13,84.01 36.67,84.55 37.11,84.55 C7101.2 ; 104.11,92.94 103.47,93.58 102.87,94.18 102.87,94.38 v2(102.62,94.63)
DP2_DDI_TX_C_N0: length 2.1
  BOTTOM w0.102: U7101.10 40.18,92.88 40.27,92.96 40.56,92.96 41.12,93.52 41.3,93.52 C7113.2
DP2_DDI_TX_C_N1: length 3.6
  BOTTOM w0.102: v1(42.32,91.99) 42.32,92.12 ; 42.32,92.12 42.82,92.12 C7107.2 ; 42.32,92.12 41.88,92.12 41.52,91.76 40.28,91.76 40.2,91.68 U7101.13
DP2_DDI_TX_C_N2: length 1.8
  BOTTOM w0.102: U7101.16 40.39,90.48 40.48,90.56 41.33,90.56 C7108.2
DP2_DDI_TX_C_N3: length 3.6
  BOTTOM w0.102: 41.05,89.36 41.48,89.36 41.82,89.03 42.96,89.03 C7110.2 ; 41.05,89.36 40.48,89.36 40.39,89.28 U7101.19 ; 41.05,89.36 v1(41.05,89.22)
DP2_DDI_TX_C_P0: length 2.2
  BOTTOM w0.102: C7112.2 41.33,93.74 41.02,93.74 40.88,93.6 ; 40.88,93.6 v1(40.77,93.72) ; 40.88,93.6 40.47,93.19 40.28,93.19 40.19,93.28 U7101.9
DP2_DDI_TX_C_P1: length 3.6
  BOTTOM w0.102: v1(41.1,92.12) 41.1,91.99 ; 41.1,91.99 41.43,91.99 41.78,92.35 42.85,92.35 C7114.2 ; 41.1,91.99 40.28,91.99 40.2,92.08 U7101.12
DP2_DDI_TX_C_P2: length 1.8
  BOTTOM w0.102: C7109.2 41.29,90.79 40.48,90.79 40.39,90.88 U7101.15
DP2_DDI_TX_C_P3: length 3.7
  BOTTOM w0.102: C7111.2 42.71,89.26 42.32,89.26 ; v1(42.32,89.4) 42.32,89.26 ; 42.32,89.26 41.91,89.26 41.58,89.59 40.48,89.59 40.39,89.68 U7101.18
DP2_DDI_TX_N0: length 73.4
  L6 w0.089: v2(100.46,94.63) 100.72,94.37 100.72,94.21 100.55,94.04 100.39,94.04 96.42,98.01 84.68,98.01 83.99,98.7 78.1,98.7 75.31,95.92 44.07,95.92 42.41,94.25 42.41,93.61 42.59,93.43 42.86,93.43 v2(43.05,93.24)
  BOTTOM w0.076: 103.64,91.77 103.66,91.75 103.7,91.75 104.21,91.25 104.21,90.66 104.02,90.47 104.02,90.1 104.04,90.02 104.05,90 104.05,89.78 104.02,89.68 104.02,89.43 104.12,89.19 104.14,89.16 104.16,89.09 104.16,88.71 104.32,88.56 CPU1.AC4
  BOTTOM w0.102: 103.64,91.77 102.97,92.44 ; 102.97,92.44 102.38,93.03 101.66,93.03 100.66,94.02 100.66,94.43 v2(100.46,94.63) ; 102.97,92.44 v1(102.87,92.35) ; C7113.1 v2(43.05,93.24)
DP2_DDI_TX_N1: length 72.8
  L6 w0.089: v2(101.47,95.27) 101.77,94.97 101.77,93.93 101.25,93.41 100,93.41 96.1,97.31 84.45,97.31 83.75,98.01 78.36,98.01 75.61,95.26 45.16,95.26 44.17,94.27 44.17,93.19 43.81,92.83 43.81,92.46 44.04,92.23 44.31,92.23 v2(44.58,91.97)
  BOTTOM w0.076: CPU1.AC1 104.54,90.31 104.54,91.62 104.04,92.13 104.04,92.2 103.69,92.54 103.65,92.54 103.64,92.56
  BOTTOM w0.102: v1(101.73,94.58) 101.85,94.58 ; 101.85,94.58 101.85,94.89 v2(101.47,95.27) ; 101.85,94.58 101.85,94.34 102.78,93.41 102.78,93.42 103.64,92.56 ; C7107.1 44.45,91.84 v2(44.58,91.97)
DP2_DDI_TX_N2: length 83.4
  L6 w0.089: v2(105.74,94.1) 105.52,94.32 105.52,96.19 104.57,97.14 99.56,97.14 97.5,99.2 97.36,99.34 96.24,99.34 96.24,99.34 96.12,99.34 95.63,99.34 85.45,99.34 84.71,100.08 77.56,100.08 74.72,97.24 43.2,97.24 41.08,95.12 41.08,91.35 42.05,90.39 42.98,90.39 v2(43.05,90.32)
  BOTTOM w0.076: CPU1.AE4 105.81,88.74 105.85,88.87 105.85,89.09 105.87,89.13 105.89,89.17 106,89.43 106,89.69 105.96,89.78 105.96,90 106,90.09 106,90.45 105.81,90.63 105.81,91.01 106.09,91.29 106.09,92.45 106.12,92.48 106.12,92.5
  BOTTOM w0.102: v2(105.74,94.1) 105.74,93.81 106.12,93.43 106.12,92.98 ; 106.12,92.98 106.12,92.5 ; 106.12,92.98 v1(106.25,92.98) ; C7108.1 v2(43.05,90.32)
DP2_DDI_TX_N3: length 81.2
  L6 w0.089: v2(44.96,90.7) 44.53,91.13 44.39,91.13 43.63,91.89 43,91.89 41.94,92.96 41.94,94.58 43.74,96.39 75.08,96.39 77.87,99.17 84.41,99.17 85.11,98.48 96.9,98.48 99.18,96.2 103.8,96.2 104.48,95.53 104.48,95.21 104.34,95.07 104.21,95.07 v2(104.01,95.27)
  BOTTOM w0.076: 105.28,92.92 105.3,92.91 105.3,92.87 105.62,92.55 105.55,91.35 105.43,91.23 105.43,90.36 CPU1.AE1
  BOTTOM w0.102: v2(44.96,90.7) 44.68,90.42 44.68,90.15 44.93,89.9 44.93,89.68 ; C7110.1 44.28,89.16 44.63,89.16 44.93,89.46 44.93,89.68 ; v1(45.06,89.68) 44.93,89.68 ; 105.28,92.92 104.44,93.76 104.44,95.17 104.29,95.32 104.06,95.32 v2(104.01,95.27)
DP2_DDI_TX_P0: length 73.4
  L6 w0.089: v2(101.09,94.63) 100.91,94.45 100.91,94.13 100.63,93.85 100.31,93.85 96.34,97.82 84.6,97.82 83.91,98.51 78.18,98.51 75.39,95.73 44.15,95.73 42.6,94.18 42.6,93.69 42.67,93.62 42.8,93.62 v2(43.05,93.87)
  BOTTOM w0.076: CPU1.AC3 104.44,88.71 104.52,88.63 104.63,88.63 104.72,88.72 104.72,89.05 104.51,89.26 104.36,89.26 104.26,89.29 104.18,89.47 104.18,89.66 104.22,89.75 104.22,90.03 104.2,90.07 104.18,90.12 104.18,90.4 104.37,90.59 104.37,91.31 103.82,91.87 103.82,91.92 103.8,91.93
  BOTTOM w0.102: v2(101.09,94.63) 100.89,94.43 100.89,94.12 101.75,93.26 102.11,93.26 ; C7112.1 42.93,94 v2(43.05,93.87) ; 102.11,93.26 102.48,93.26 103.8,91.93 ; 102.11,93.26 v1(102.11,93.39)
DP2_DDI_TX_P1: length 73.3
  L6 w0.089: v2(44.58,92.6) 44.4,92.42 44.12,92.42 44.01,92.54 44.01,92.75 44.36,93.11 44.36,94.19 45.24,95.06 75.69,95.06 78.44,97.82 83.67,97.82 84.37,97.12 96.02,97.12 99.92,93.22 101.33,93.22 101.96,93.85 101.96,95.12 v2(102.11,95.27)
  BOTTOM w0.076: 103.8,92.72 103.8,92.67 104.2,92.27 104.2,92.19 104.71,91.69 104.71,90.14 104.46,89.57 CPU1.AC2
  BOTTOM w0.102: v1(102.11,95.9) v2(102.11,95.27) 102.08,95.24 102.08,94.43 103.8,92.72 ; v2(44.58,92.6) C7114.1
DP2_DDI_TX_P2: length 83.9
  TOP w0.102: v1(43.16,91.51) v2(43.05,90.95)
  L6 w0.089: v2(43.05,90.95) 43.05,91.08 42.9,91.23 42.7,91.23 42.57,91.1 42.57,90.67 42.48,90.58 42.13,90.58 41.27,91.43 41.27,95.04 43.28,97.05 74.8,97.05 77.64,99.89 84.63,99.89 85.37,99.15 95.71,99.15 96.2,99.15 96.32,99.15 97.28,99.15 99.48,96.95 104.49,96.95 105.33,96.11 105.33,94.21 105.24,94.13 v2(105.05,94.13)
  BOTTOM w0.076: CPU1.AE3 105.54,88.91 105.46,88.99 105.46,89.16 105.53,89.22 105.69,89.22 105.76,89.29 105.83,89.47 105.83,89.66 105.8,89.75 105.8,90.03 105.83,90.12 105.83,90.38 105.64,90.56 105.64,91.08 105.92,91.36 105.92,92.45 105.89,92.48 105.89,92.5
  BOTTOM w0.102: 105.89,92.5 105.89,93.34 105.49,93.74 105.13,93.74 105,93.87 105,94.07 v2(105.05,94.13) ; C7109.1 42.77,90.81 42.91,90.81 v2(43.05,90.95)
DP2_DDI_TX_P3: length 81.3
  L6 w0.089: v2(44.32,90.7) 44.32,90.92 43.55,91.7 42.92,91.7 41.74,92.88 41.74,94.66 43.66,96.58 75,96.58 77.79,99.37 84.49,99.37 85.18,98.67 96.98,98.67 99.26,96.39 103.88,96.39 103.94,96.34 103.94,96.33 104.67,95.61 104.67,95.13 104.41,94.88 104.26,94.88 v2(104.01,94.63)
  BOTTOM w0.076: 105.12,92.76 105.14,92.75 105.17,92.75 105.43,92.48 105.38,91.43 105.25,91.3 105.25,90.15 CPU1.AE2
  BOTTOM w0.102: 104.22,94.07 104.22,93.66 105.12,92.76 ; 104.22,94.07 104.22,94.43 v2(104.01,94.63) ; 104.22,94.07 v1(104.04,94.07) ; v2(44.32,90.7) 44.45,90.56 44.45,90.06 44.7,89.81 44.7,89.55 44.54,89.39 44.28,89.39 C7111.1
DPEQ0_A1: length 4.2
  TOP w0.127: v2(40.64,91.33) 40.39,91.08 v1(39.83,91.08) 39.83,91.86 R7172.1 R7171.2
  BOTTOM w0.127: U7101.14 40.59,91.28 v2(40.64,91.33)
DPEQ1: length 4.7
  TOP w0.127: v2(35.94,95.01) 35.48,95.01 v1(35.1,94.63) R7147.2 R7170.1
  BOTTOM w0.127: U7101.2 36.97,94.38 36.81,94.54 36.41,94.54 v2(35.94,95.01)
EC_AGND: length 11.5
  TOP w0.203: C2435.2 90.75,6.11 C2441.2
  TOP w0.305: 91.64,7.21 C2441.2
  TOP w0.381: 91.64,7.21 91.81,7.37 v2(92.08,8.02) 92.08,8.18 91.86,8.4 91.86,8.69 R2445.2 91.77,9.08 92.05,9.35 93.04,9.35 93.4,9 C2422.2 93.28,8.67 93.28,7.9 v1(93.29,7.89) 93.27,7.87 93.27,7.13 C2408.2 93.4,6.27 R2444.2 R2441.2 94.16,6.27 C2407.2
  BOTTOM w0.203: v2(92.08,8.02) 92.08,7.89 91.72,7.54 91.72,7.54 91.58,7.4 91.58,7.4 91.51,7.33 U2401.112
EDP_AUX_CON_N: length 4.8
  TOP w0.102: C5511.1 89.41,103.19 89.41,102.35 90.4,101.36 ; 90.4,101.36 v1(90.53,101.41) ; 90.4,101.36 90.4,101.03 v2(90.58,100.86)
  BOTTOM w0.102: LCD1.8 90.5,99.83 90.39,99.94 90.39,100.69 90.55,100.86 v2(90.58,100.86)
EDP_AUX_CON_P: length 4.9
  TOP w0.102: C5510.1 89.18,103.17 89.18,102.51 ; 89.18,102.51 89.18,102.25 90.06,101.38 90.17,101.26 90.17,101.08 v2(89.94,100.86) ; 89.18,102.51 v1(89.03,102.51)
  BOTTOM w0.102: v2(89.94,100.86) 89.94,100.83 90.16,100.61 90.16,99.99 90,99.83 LCD1.7
EDP_AUX_CPU_N: length 42.7
  TOP w0.102: v2(89.53,104.92) 89.66,104.79 C5511.2
  L6 w0.089: v2(89.53,104.92) 89.31,105.14 89.31,106.98 89.79,107.46 105.06,107.46 106.67,105.86 106.67,103.93 107.79,102.8 107.79,99.87 110.13,97.53 110.13,95.25 110.33,95.05 110.45,95.05 v2(110.87,94.63)
  BOTTOM w0.076: CPU1.AH4 107.45,88.82 107.71,89.09 107.71,89.39 107.53,89.58 107.53,89.66 107.53,89.73 107.53,90.99 108.26,91.73 108.3,91.73 108.32,91.74
  BOTTOM w0.102: v2(110.87,94.63) 110.71,94.79 109.7,94.79 108.94,94.04 108.94,93.54 ; v1(109.07,93.54) 108.94,93.54 ; 108.94,93.54 108.94,92.36 108.32,91.74
EDP_AUX_CPU_P: length 42.7
  TOP w0.102: C5510.2 v2(88.9,104.92)
  L6 w0.089: v2(88.9,104.92) 89.12,105.14 89.12,107.06 89.71,107.65 105.14,107.65 106.86,105.94 106.86,104.01 107.98,102.88 107.98,99.95 110.32,97.61 110.32,95.33 110.41,95.24 110.85,95.24 v2(110.87,95.27)
  BOTTOM w0.076: CPU1.AH3 107.38,89.17 107.27,89.17 107.19,89.24 107.19,89.42 107.36,89.59 107.36,89.66 107.36,89.73 107.36,91.06 108.14,91.84 108.14,91.89 108.16,91.9
  BOTTOM w0.102: 110.06,95.02 110.62,95.02 v2(110.87,95.27) ; 110.06,95.02 109.6,95.02 108.71,94.13 108.71,92.46 108.43,92.18 108.16,91.9 ; 110.06,95.02 v1(110.06,95.17)
EDP_HPD_CON: length 5.1
  TOP w0.102: R5506.1 98.48,102.91 RN5502.8 97.76,102.23 v1(97.54,102) 97.28,101.75 v2(97.28,100.86)
  BOTTOM w0.102: v2(97.28,100.86) 97.33,100.81 97.33,100.17 97,99.84 LCD1.21
EDP_HPD_CPU: length 57.1
  TOP w0.102: R5506.2 98.48,104.64 v2(98.48,104.92)
  L4SGND w0.102: v2(138.15,88.92) 137.56,88.33 136.95,88.33 136.15,89.13 136.15,91.53 132.12,95.56 132.12,97.08 128.35,100.86 128.35,102.1 125.88,104.57 123.66,104.57 123.66,104.57 123.49,104.57 123.49,104.57 116.62,104.57 116.14,104.1 99.22,104.1 98.48,104.84 v2(98.48,104.92)
  BOTTOM w0.102: CPU1.CM7 134.58,86.81 136.58,86.81 137,87.23 137,87.84 138.07,88.92 v2(138.15,88.92) 138.27,88.79 v1(138.81,88.79)
EDP_RCOMP_CPU: length 3.1
  TOP w0.254: v2(109.43,87.15) 109.44,87.15 109.45,87.15 109.49,87.15 109.9,86.74 109.9,86.21 v1(109.64,85.95) R401.2
  BOTTOM w0.254: CPU1.AM6 109.72,86.87 109.44,87.15 v2(109.43,87.15)
EDP_TX_CON_N0: length 4.7
  TOP w0.102: C5506.1 96.79,103.18 96.79,102.74 96.59,102.54 ; 96.59,102.54 96.09,102.04 96.09,101.06 v2(95.89,100.86) ; 96.59,102.54 v1(96.49,102.63)
  BOTTOM w0.102: LCD1.19 96,99.84 96.12,99.95 96.12,100.62 v2(95.89,100.86)
EDP_TX_CON_N1: length 4.5
  TOP w0.102: 94.88,102.63 94.88,103.18 C5501.1 ; 94.88,102.63 94.88,102.18 94.69,101.99 94.69,101.06 v2(94.49,100.86) ; 94.88,102.63 v1(94.74,102.63)
  BOTTOM w0.102: v2(94.49,100.86) 94.64,100.7 94.64,99.98 94.5,99.84 LCD1.16
EDP_TX_CON_N2: length 4.6
  TOP w0.102: C5533.1 92.85,103.18 92.85,102.53 ; v1(92.71,102.53) 92.85,102.53 ; 92.85,102.53 92.85,102.04 93.17,101.73 93.17,101.06 v2(92.96,100.86)
  BOTTOM w0.102: LCD1.13 93,99.84 93.14,99.98 93.14,100.68 v2(92.96,100.86)
EDP_TX_CON_N3: length 4.7
  TOP w0.102: 90.94,102.66 90.94,102.04 91.64,101.35 91.64,101.06 v2(91.44,100.86) ; 90.94,102.66 90.94,103.18 C5532.1 ; 90.94,102.66 v1(90.81,102.66)
  BOTTOM w0.102: LCD1.10 91.5,99.85 91.63,99.98 91.63,100.66 v2(91.44,100.86)
EDP_TX_CON_P0: length 4.7
  TOP w0.102: 96.32,101.41 96.32,101.94 97.02,102.64 97.02,103.18 C5509.1 ; 96.32,101.41 v1(96.44,101.41) ; 96.32,101.41 96.32,101.06 v2(96.52,100.86)
  BOTTOM w0.102: LCD1.20 96.5,99.85 96.34,100 96.34,100.68 v2(96.52,100.86)
EDP_TX_CON_P1: length 4.5
  TOP w0.102: v2(95.12,100.86) 94.92,101.06 94.92,101.44 ; 94.92,101.44 94.92,101.9 95.11,102.09 95.11,103.18 C5504.1 ; 94.92,101.44 v1(95.05,101.44)
  BOTTOM w0.102: LCD1.17 95,99.83 94.87,99.95 94.87,100.6 v2(95.12,100.86)
EDP_TX_CON_P2: length 4.6
  TOP w0.102: C5519.1 93.08,103.18 93.08,102.14 93.4,101.82 93.4,101.47 ; v2(93.6,100.86) 93.4,101.06 93.4,101.47 ; v1(93.52,101.47) 93.4,101.47
  BOTTOM w0.102: v2(93.6,100.86) 93.37,100.63 93.37,99.96 93.5,99.84 LCD1.14
EDP_TX_CON_P3: length 4.7
  TOP w0.102: C5531.1 91.17,103.18 91.17,102.14 91.87,101.44 ; v2(92.08,100.86) 91.87,101.06 91.87,101.44 ; 91.87,101.44 v1(92,101.47)
  BOTTOM w0.102: LCD1.11 92,99.83 91.86,99.97 91.86,100.64 v2(92.08,100.86)
EDP_TX_CPU_N0: length 48.3
  TOP w0.102: C5506.2 v2(96.52,104.92) v1(96.27,105.43)
  L6 w0.089: v2(96.52,104.92) 96.74,105.14 96.74,105.35 96.94,105.55 100.52,105.55 100.86,105.2 100.86,104.24 100.66,104.04 97.52,104.04 97.4,103.92 97.4,103.04 97.2,102.84 96.62,102.84 96.42,103.04 96.42,103.95 96.33,104.04 95.89,104.04 95.8,103.95 95.8,102.56 96.01,102.34 97.86,102.34 97.99,102.47 97.99,103.25 98.19,103.45 101.34,103.45 101.54,103.25 101.54,102.69 101.34,102.49 99.07,102.49 98.97,102.39 98.97,102.04 99.06,101.95 101.15,101.95 101.54,101.56 101.54,99.67 101.93,99.27 105.47,99.27 108.33,96.41 108.33,92.65 107.97,92.29 107.13,92.29 v2(107.06,92.22)
  BOTTOM w0.076: v2(107.06,92.22) 107.06,91.89 106.64,91.47 106.64,90.65 106.46,90.47 106.46,90.06 106.48,90.03 106.49,90 106.49,89.78 106.46,89.68 106.46,89.43 106.52,89.29 106.56,89.19 106.59,89.13 106.61,89.09 106.61,88.84 106.63,88.79 106.63,88.79 106.63,88.77 106.7,88.69 CPU1.AG4
EDP_TX_CPU_N1: length 47.9
  TOP w0.102: C5501.2 v2(94.61,104.92)
  L6 w0.089: v2(94.61,104.92) 94.61,102.58 94.53,102.49 94.11,102.49 94.02,102.58 94.02,103.88 93.82,104.08 93.24,104.08 93.04,103.88 93.04,102.58 92.95,102.49 92.53,102.49 92.44,102.58 92.44,103.88 92.24,104.08 91.69,104.08 91.49,103.88 91.49,102.53 91.4,102.44 90.99,102.44 90.9,102.53 90.9,103.88 90.7,104.08 90.05,104.08 89.83,103.86 89.83,101.65 90.03,101.45 98.19,101.45 98.87,100.78 98.87,98.67 99.16,98.38 99.83,98.38 100.04,98.58 100.04,99.19 100.12,99.28 100.54,99.28 100.63,99.19 100.63,98.61 100.86,98.38 104.82,98.38 106.24,96.97 106.24,95.16 106.55,94.85 106.85,94.85 v2(107.06,94.63)
  BOTTOM w0.076: CPU1.AG2 106.9,89.57 107.15,90.14 107.15,91.2 108.04,92.09 108.04,92.79 108.07,92.82 108.07,92.84
  BOTTOM w0.102: 107.49,93.59 107.68,93.59 108.07,93.2 108.07,92.84 ; 107.49,93.59 107.09,93.59 106.71,93.97 106.71,94.56 106.78,94.63 v2(107.06,94.63) ; 107.49,93.59 v1(107.49,93.72)
EDP_TX_CPU_N2: length 48
  TOP w0.102: v1(92.46,105.43) v2(92.71,104.92) 92.71,104.49 C5533.2
  L6 w0.089: v2(92.71,104.92) 92.71,106.05 92.91,106.25 93.67,106.25 93.87,106.05 93.87,105.83 94,105.71 94.34,105.71 94.47,105.83 94.47,106.05 94.67,106.25 95.24,106.25 95.44,106.05 95.44,105.83 95.61,105.67 95.88,105.67 96.04,105.83 96.04,106.05 96.24,106.25 100.98,106.25 101.19,106.05 101.19,105.83 101.27,105.75 105.07,105.75 105.54,105.28 105.54,104.36 105.27,104.09 102.35,104.09 102.26,104.01 102.26,103.31 102.4,103.17 102.82,103.17 103.02,102.97 103.02,102.39 102.82,102.19 102.4,102.19 102.31,102.1 102.31,101.21 102.4,101.12 106.05,101.12 106.28,100.89 106.28,99.71 108.99,97 108.99,92.19 109.15,92.04 110.97,92.04 111.25,91.75 111.25,91.21 110.7,90.65 v2(109.85,90.65)
  BOTTOM w0.076: CPU1.AJ4 108.25,88.74 108.29,88.78 108.29,89.09 108.31,89.13 108.33,89.17 108.44,89.43 108.44,89.69 108.41,89.78 108.41,90 108.44,90.09 108.44,90.58 108.71,90.86 109.48,90.86 v2(109.85,90.65)
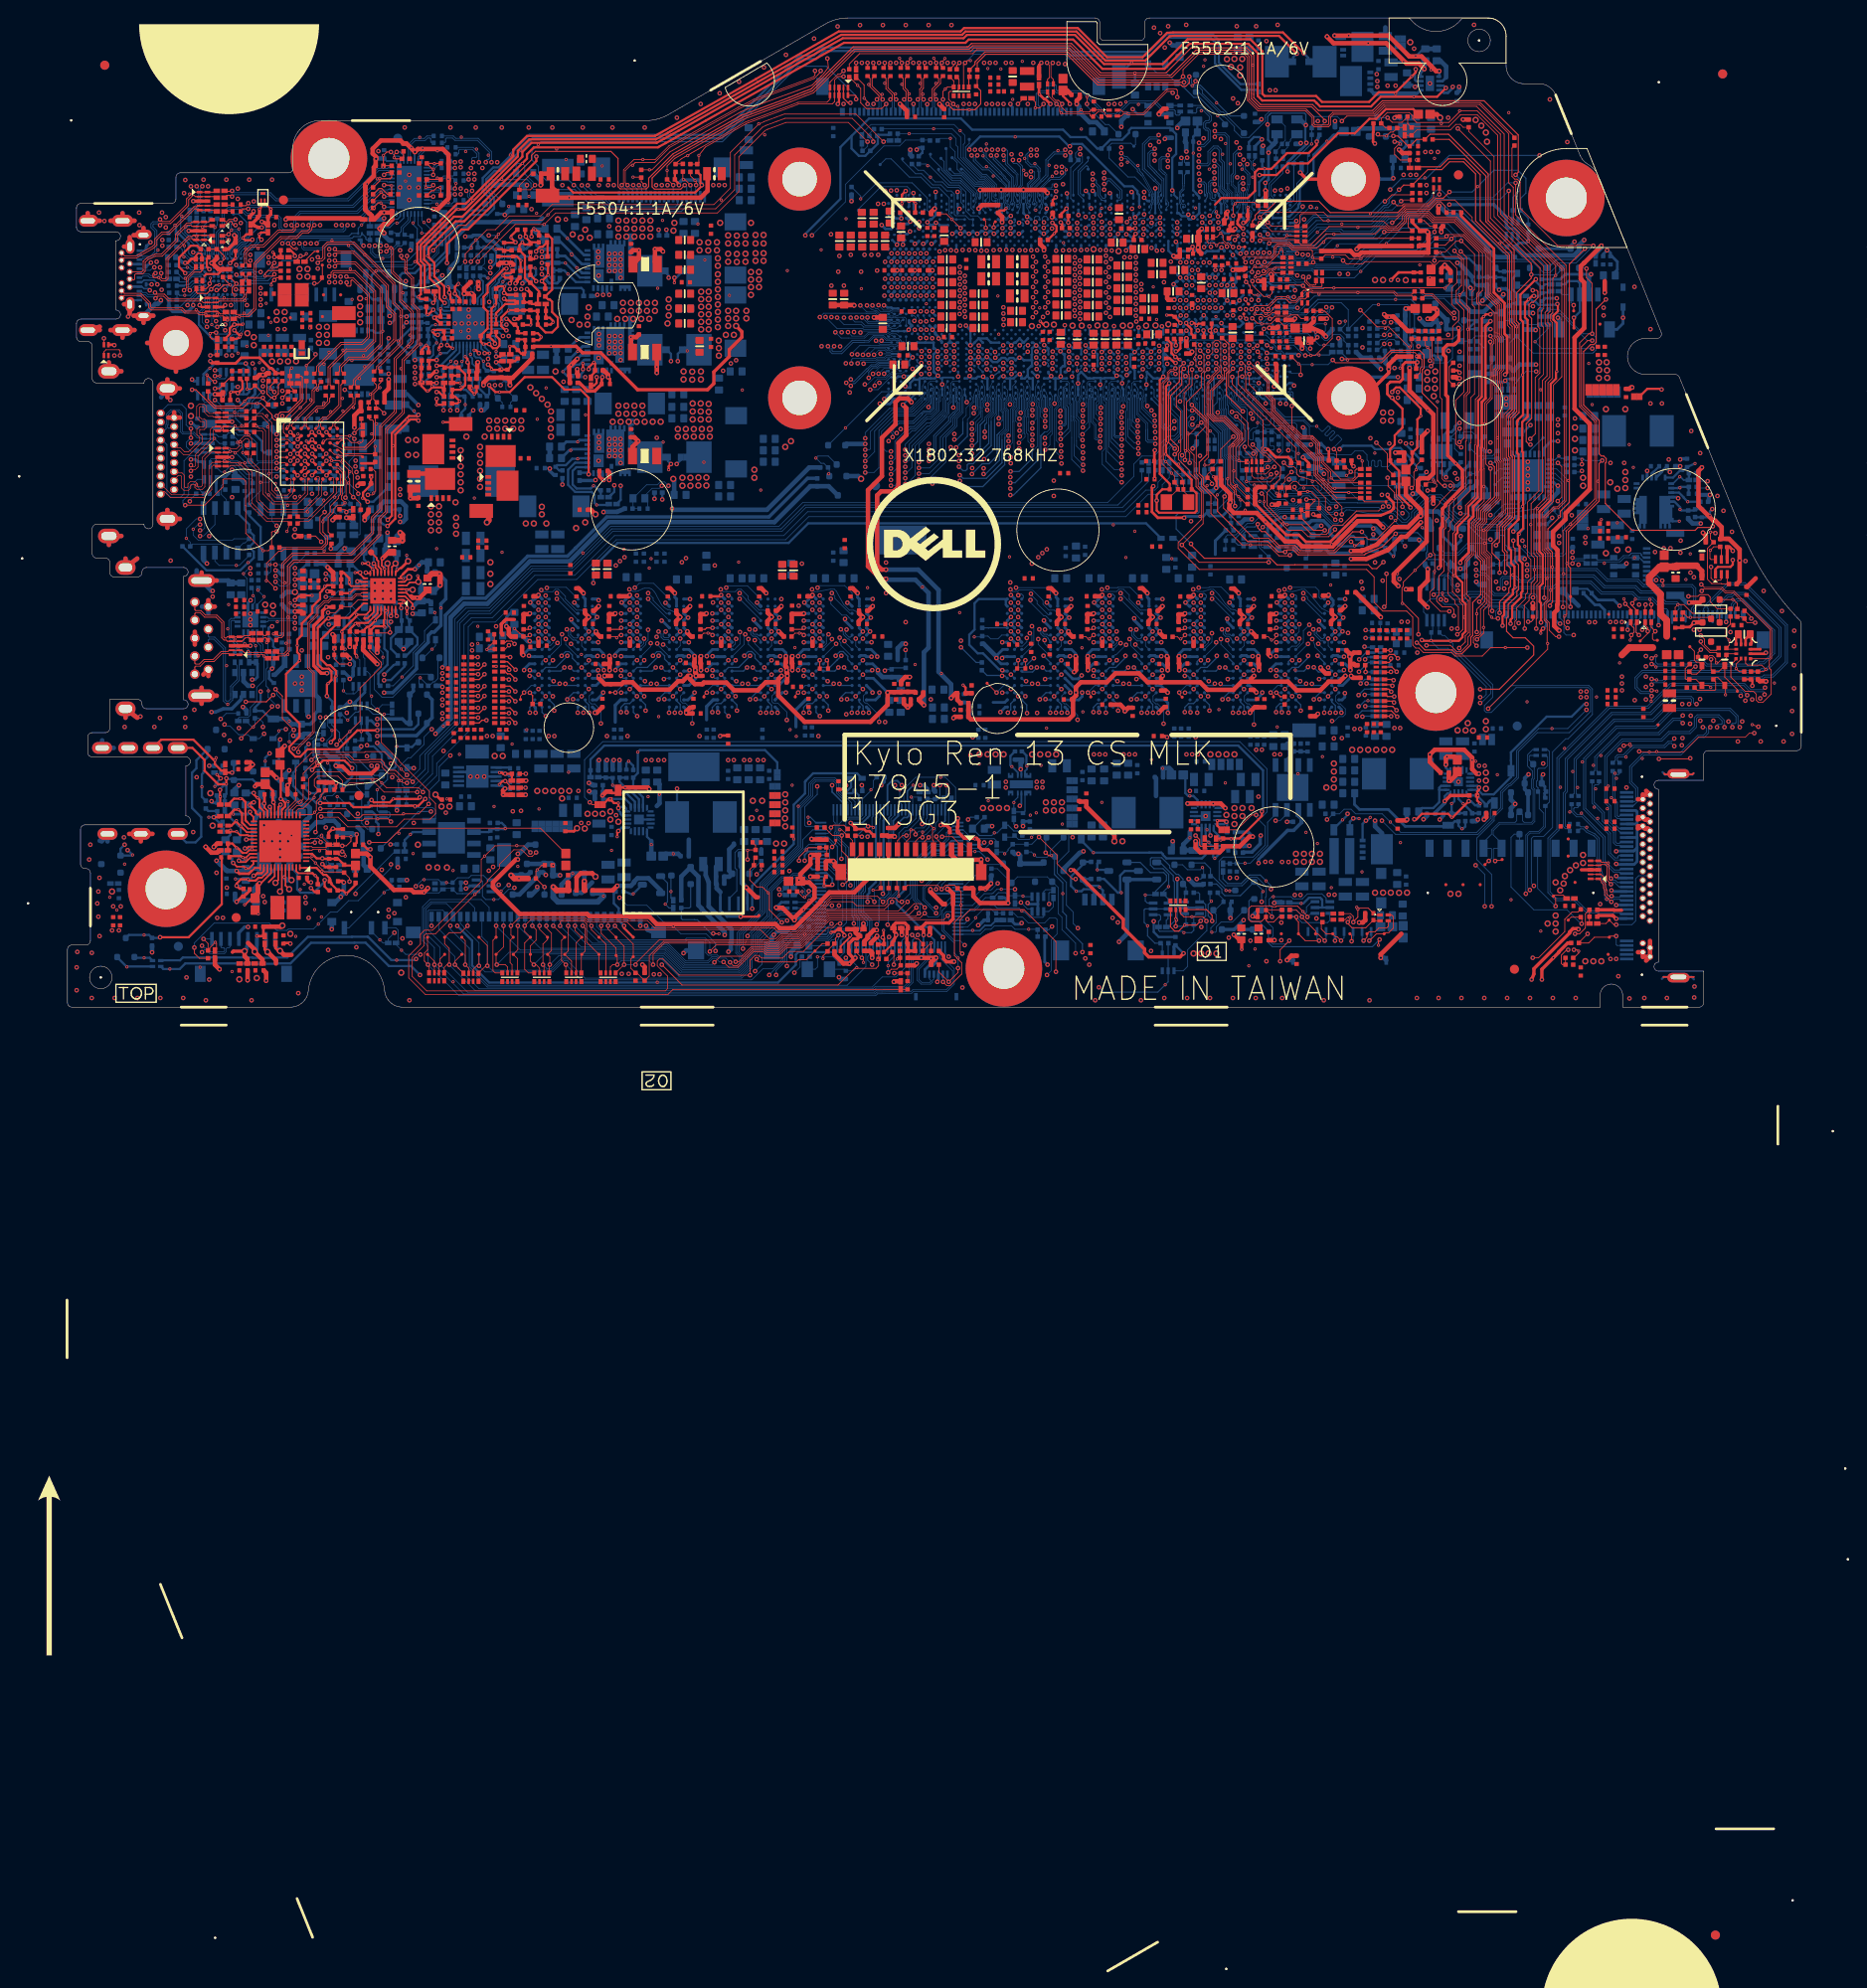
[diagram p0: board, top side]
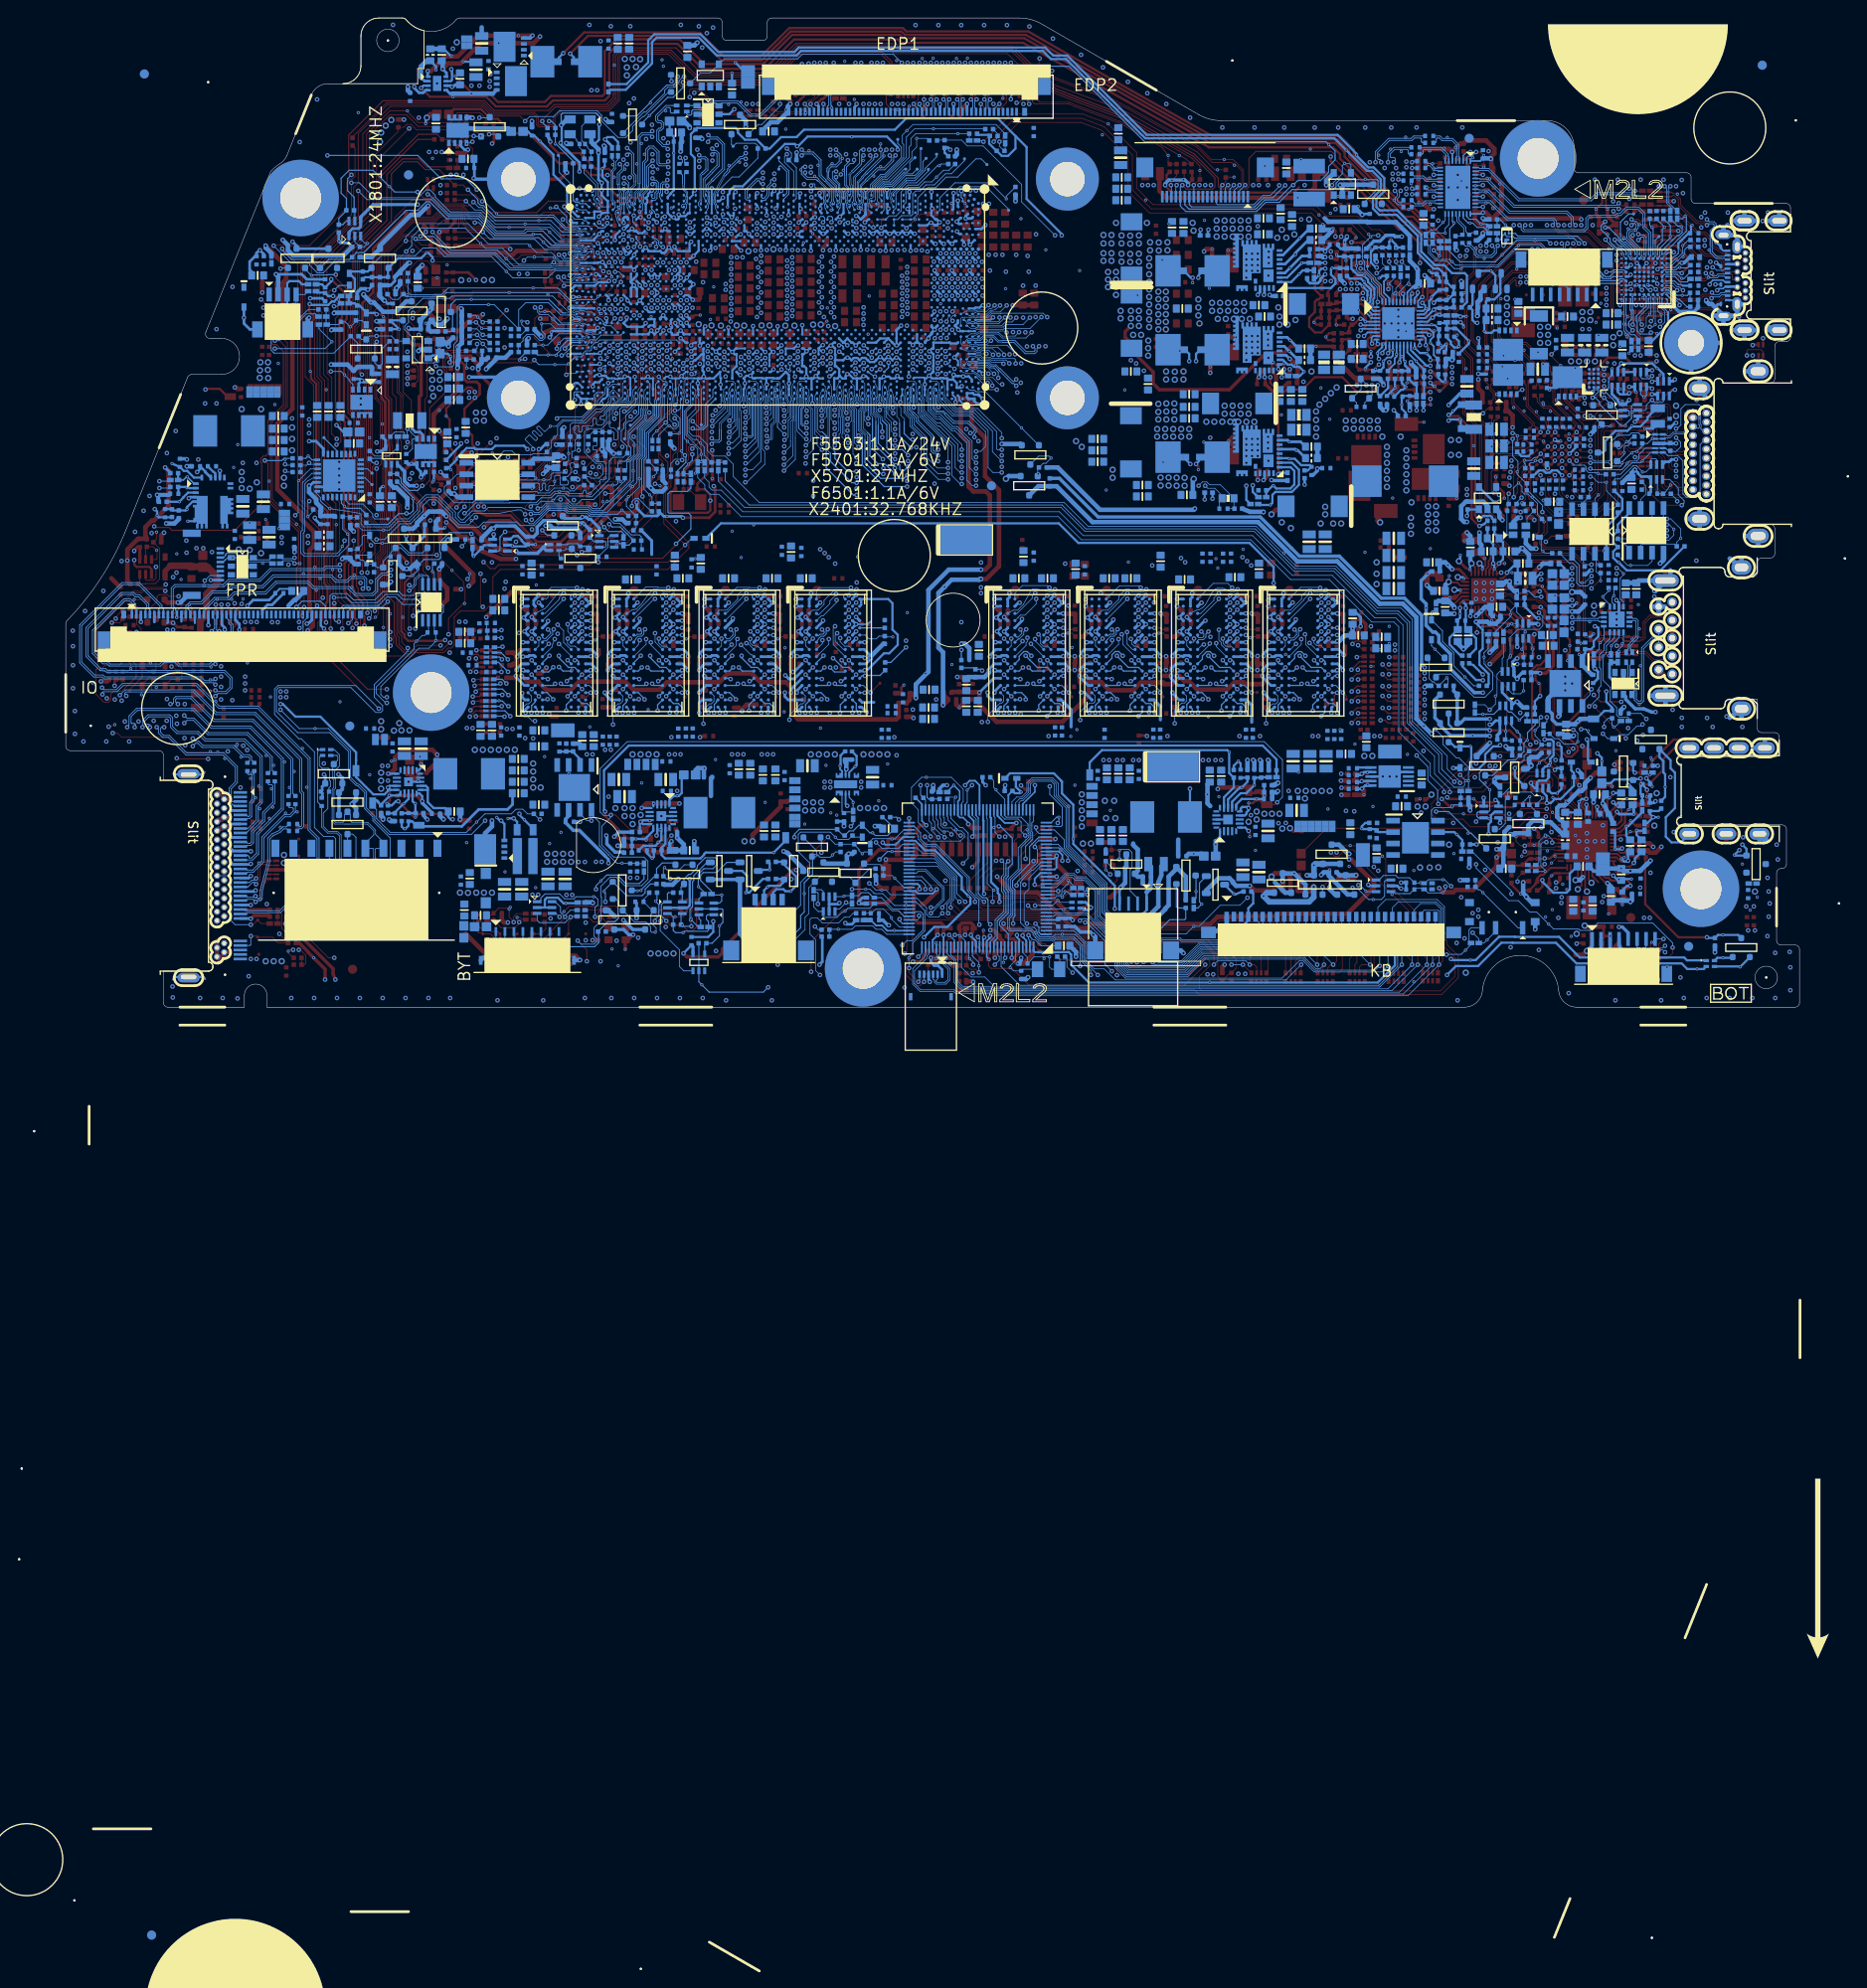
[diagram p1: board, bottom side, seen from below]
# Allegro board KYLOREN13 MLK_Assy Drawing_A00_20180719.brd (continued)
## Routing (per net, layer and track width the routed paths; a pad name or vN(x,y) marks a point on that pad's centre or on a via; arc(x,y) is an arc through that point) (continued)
EDP_TX_CPU_N3: length 48.9
  TOP w0.102: C5532.2 90.81,104.49 v2(90.81,104.92)
  L6 w0.089: v2(90.81,104.92) 90.81,106.57 91.2,106.96 101.58,106.96 101.78,106.76 101.78,106.68 101.87,106.59 102.29,106.59 102.38,106.68 102.38,106.76 102.58,106.96 103.15,106.96 103.36,106.76 103.36,106.68 103.44,106.59 103.86,106.59 103.95,106.68 103.95,106.76 104.15,106.96 104.81,106.96 106.2,105.58 106.2,103.55 106,103.35 103.85,103.35 103.76,103.26 103.76,101.94 103.89,101.81 104.28,101.81 104.37,101.9 104.37,102.64 104.57,102.84 105.15,102.84 105.35,102.64 105.35,101.9 105.44,101.81 105.82,101.81 105.92,101.91 105.92,102.61 106.17,102.86 107.01,102.86 107.32,102.55 107.32,99.6 109.66,97.27 109.66,94.4 110,94.06 110.93,94.06 111.17,93.82 111.17,93.14 110.95,92.92 110.68,92.92 v2(110.49,92.73)
  BOTTOM w0.076: 108.97,91.98 108.96,91.96 108.96,91.92 107.74,90.7 107.74,90.07 CPU1.AJ2
  BOTTOM w0.102: v2(110.49,92.73) 110.49,92.47 110.22,92.19 109.42,92.19 ; v1(109.42,92.32) 109.42,92.19 ; 109.42,92.19 109.19,92.19 108.97,91.98
EDP_TX_CPU_P0: length 48.3
  TOP w0.102: v1(97.49,105.4) v2(97.16,104.92) 97.01,104.78 97.01,104.63 C5509.2
  L6 w0.089: v2(97.16,104.92) 96.93,105.14 96.93,105.27 97.02,105.36 100.44,105.36 100.67,105.12 100.67,104.32 100.58,104.23 97.44,104.23 97.21,104 97.21,103.12 97.12,103.03 96.7,103.03 96.61,103.12 96.61,104.03 96.41,104.23 95.81,104.23 95.61,104.03 95.61,102.48 95.94,102.15 97.94,102.15 98.18,102.39 98.18,103.17 98.27,103.26 101.26,103.26 101.35,103.17 101.35,102.77 101.26,102.68 98.99,102.68 98.78,102.47 98.78,101.96 98.98,101.76 101.07,101.76 101.35,101.48 101.35,99.59 101.85,99.08 105.39,99.08 108.14,96.33 108.14,92.73 107.89,92.48 107.43,92.48 v2(107.06,92.86)
  BOTTOM w0.076: v2(107.06,92.86) 107.39,92.86 107.47,92.78 107.47,92.07 106.8,91.4 106.8,90.61 106.79,90.57 106.62,90.4 106.62,90.14 106.64,90.07 106.66,90.03 106.66,89.75 106.62,89.66 106.62,89.47 106.67,89.36 106.77,89.26 106.93,89.26 107.01,89.18 107.01,89.04 CPU1.AG3
EDP_TX_CPU_P1: length 48
  TOP w0.102: v2(95.25,104.92) 95.17,104.84 95.17,104.57 C5504.2
  L6 w0.089: v2(107.06,95.27) 106.83,95.04 106.63,95.04 106.43,95.24 106.43,97.05 104.9,98.57 100.94,98.57 100.82,98.68 100.82,99.27 100.62,99.47 100.05,99.47 99.84,99.27 99.84,98.66 99.76,98.57 99.24,98.57 99.06,98.75 99.06,100.86 98.27,101.64 90.11,101.64 90.02,101.73 90.02,103.78 90.13,103.89 90.62,103.89 90.71,103.8 90.71,102.45 90.91,102.25 91.48,102.25 91.68,102.45 91.68,103.8 91.77,103.89 92.16,103.89 92.25,103.8 92.25,102.5 92.45,102.3 93.03,102.3 93.23,102.5 93.23,103.8 93.32,103.89 93.74,103.89 93.83,103.8 93.83,102.5 94.03,102.3 94.61,102.3 94.81,102.5 94.81,104.51 94.9,104.6 95.16,104.6 95.25,104.69 v2(95.25,104.92)
  BOTTOM w0.076: 107.84,92.84 107.84,92.82 107.87,92.79 107.87,92.15 106.98,91.27 106.98,90.68 CPU1.AG1
  BOTTOM w0.102: 107.84,92.84 107.84,93.11 107.58,93.36 106.99,93.36 106.48,93.88 106.48,94.3 ; v1(106.35,94.3) 106.48,94.3 ; 106.48,94.3 106.48,94.66 106.63,94.81 106.63,94.81 107.06,95.24 v2(107.06,95.27)
EDP_TX_CPU_P2: length 48
  TOP w0.102: v1(93.68,105.4) v2(93.34,104.92) 93.14,104.71 93.14,104.57 C5519.2
  L6 w0.089: v2(93.34,104.92) 93.34,105.17 93.26,105.26 93.13,105.26 92.97,105.26 92.9,105.33 92.9,105.97 92.99,106.06 93.59,106.06 93.68,105.97 93.68,105.76 93.92,105.52 94.42,105.52 94.66,105.76 94.66,105.97 94.75,106.06 95.17,106.06 95.25,105.97 95.25,105.76 95.53,105.48 95.96,105.48 96.23,105.76 96.23,105.97 96.32,106.06 100.91,106.06 100.99,105.97 100.99,105.76 101.2,105.56 104.99,105.56 105.35,105.2 105.35,104.44 105.19,104.29 102.27,104.29 102.07,104.08 102.07,103.23 102.32,102.98 102.74,102.98 102.83,102.89 102.83,102.47 102.74,102.38 102.32,102.38 102.12,102.18 102.12,101.13 102.32,100.93 105.97,100.93 106.09,100.81 106.09,99.63 108.8,96.92 108.8,92.12 109.07,91.85 110.89,91.85 111.06,91.67 111.06,91.29 110.62,90.84 110.31,90.84 110.25,90.9 110.25,91.24 110.08,91.42 109.95,91.42 v2(109.82,91.29)
  BOTTOM w0.076: v2(109.82,91.29) 109.64,91.47 109.47,91.47 109.39,91.39 109.39,91.11 109.3,91.02 108.64,91.02 108.27,90.65 108.27,90.12 108.24,90.03 108.24,89.75 108.28,89.66 108.28,89.47 108.18,89.24 108.17,89.22 CPU1.AJ3
EDP_TX_CPU_P3: length 48.8
  TOP w0.102: C5531.2 91.23,104.57 91.23,104.71 v2(91.44,104.92)
  L6 w0.089: v2(110.49,93.36) 110.74,93.11 110.87,93.11 110.98,93.22 110.98,93.74 110.86,93.87 109.92,93.87 109.47,94.33 109.47,97.19 107.13,99.52 107.13,102.47 106.93,102.67 106.25,102.67 106.11,102.53 106.11,101.83 105.9,101.62 105.36,101.62 105.16,101.82 105.16,102.56 105.07,102.65 104.65,102.65 104.56,102.56 104.56,101.82 104.36,101.62 103.81,101.62 103.57,101.86 103.57,103.34 103.77,103.54 105.92,103.54 106.01,103.62 106.01,105.5 104.73,106.77 104.23,106.77 104.14,106.69 104.14,106.6 103.94,106.4 103.37,106.4 103.16,106.6 103.16,106.69 103.08,106.77 102.66,106.77 102.57,106.69 102.57,106.6 102.37,106.4 101.79,106.4 101.59,106.6 101.59,106.69 101.5,106.77 91.28,106.77 91,106.49 91,105.39 91.08,105.3 91.35,105.3 91.44,105.21 v2(91.44,104.92)
  BOTTOM w0.076: CPU1.AJ1 107.9,90.47 107.9,90.63 109.07,91.8 109.12,91.8 109.13,91.82
  BOTTOM w0.102: v1(110.97,93.03) 110.9,93.03 ; 110.9,93.03 110.9,93.26 110.79,93.36 v2(110.49,93.36) ; 110.9,93.03 110.9,92.55 110.31,91.97 109.28,91.97 109.13,91.82
EDP_VDD_EN: length 25
  TOP w0.102: v1(124.97,102.38) 125.34,102.75 v2(125.34,102.88)
  L4SGND w0.102: v2(125.34,102.88) 125.34,101.92 130.75,96.51 130.75,94.99 130.81,94.93 130.81,94.89 132.85,92.84 132.85,92.23 132.07,91.45 132.07,84.89 v2(130.98,83.8)
  BOTTOM w0.102: v2(125.34,102.88) 125.39,102.93 D5501.1 ; CPU1.CG11 131.31,84.08 131.03,83.8 v2(130.98,83.8)
EMMC_RCOMP: length 1.2
  TOP w0.508: R2108.1 133.83,81.34 v2(133.73,81.43)
  BOTTOM w0.254: v2(133.73,81.43) 133.71,81.43 133.5,81.43 CPU1.CK15
EQ0: length 5.1
  TOP w0.127: v2(35.18,92.47) 35.43,92.73 R7143.1 36.02,92.19 35.86,92.04 34.75,92.04 v1(34.7,92.09) 34.7,91.81 R7142.2
  BOTTOM w0.102: U7101.38 35.18,92.48 v2(35.18,92.47)
EQ1: length 5.2
  TOP w0.127: v2(35.18,91.33) 35.94,91.33 v1(36.02,91.25) 36.02,90.44 R7141.1 35.56,90.32 34.91,90.96 34.61,90.96 R7140.2
  BOTTOM w0.102: U7101.35 35.23,91.28 v2(35.18,91.33)
ESPI_ALERT#: length 44.3
  TOP w0.089: v2(129.54,63.39) 128.14,61.99 R1821.2
  L6 w0.089: v2(148,47.56) 147.55,48.02 147.55,49.28 145.99,50.84 145.07,50.84 143.06,52.84 143.06,55.43 140.46,58.03 138.71,58.03 136.93,59.81 136.92,59.81 136.85,59.88 135.78,59.88 134.67,58.77 133.43,58.77 132.46,59.73 132.46,59.98 129.54,62.9 v2(129.54,63.39) 129.39,63.39 126.34,66.44 126.34,72.5 v2(126.74,72.9)
  BOTTOM w0.089: v1(147.78,48.16) 147.78,47.79 v2(148,47.56) ; CPU1.BV28 126.51,73.18 126.74,72.95 v2(126.74,72.9)
ESPI_CLK: length 146.7
  TOP w0.089: DB1.2 99.23,18.04 98.32,18.94 v2(97.18,18.94) ; v2(127.17,58.14) 127.17,58.32 EC1801.1 126.67,59.2 R1805.2
  L6 w0.089: v2(127.17,58.14) 127.87,58.14 128.14,57.87 128.14,56.26 132.83,51.57 136.29,51.57 139.58,48.28 144.02,48.28 144.04,48.26 144.04,48.26 147.96,44.34 147.96,43.7 147.42,43.16 147.42,42.48 147.9,42 147.9,42 149.49,40.41 149.49,36.62 149.06,36.19 149.06,33.71 149.5,33.27 149.5,30.42 148.57,29.49 142.55,29.49 142.02,28.96 140.04,28.96 138.34,30.66 126.28,30.66 125.96,30.99 124.74,30.99 124.25,30.5 121.74,30.5 121.34,30.09 105.99,30.09 105.03,29.13 103.52,29.13 103.44,29.22 103.44,29.8 103.35,29.89 103.17,29.89 103.08,29.8 103.08,29.22 102.99,29.13 102.81,29.13 102.72,29.22 102.72,29.8 102.64,29.89 102.46,29.89 102.37,29.8 102.37,29.22 102.28,29.13 102.1,29.13 102.01,29.22 102.01,29.8 101.92,29.89 101.75,29.89 101.66,29.8 101.66,29.22 101.57,29.13 99.87,29.13 99.62,28.87 99.49,28.87 98.97,29.39 98.85,29.39 98.72,29.27 98.72,29.14 99.24,28.62 99.24,28.5 99.11,28.37 98.99,28.37 98.47,28.89 98.34,28.89 98.22,28.77 98.22,28.64 98.74,28.12 98.74,27.99 98.61,27.87 98.48,27.87 97.96,28.39 97.84,28.39 97.71,28.26 97.71,28.14 98.23,27.62 98.23,27.49 98.11,27.37 97.98,27.37 97.46,27.89 97.34,27.89 97.21,27.76 97.21,27.63 97.73,27.11 97.73,26.99 97.6,26.86 97.48,26.86 96.96,27.38 96.83,27.38 96.71,27.26 96.71,27.13 97.23,26.61 97.23,26.49 96.95,26.21 96.82,26.21 96.12,26.9 96,26.9 95.87,26.78 95.87,26.65 96.57,25.95 96.57,25.83 96.44,25.7 96.32,25.7 95.62,26.4 95.5,26.4 95.37,26.27 95.37,26.15 96.07,25.45 96.07,25.33 95.94,25.2 95.82,25.2 95.12,25.9 94.99,25.9 94.87,25.77 94.87,25.65 95.56,24.95 95.56,24.82 91.46,20.72 91.46,20.1 92.92,18.64 93.68,18.64 94.01,18.31 96.55,18.31 v2(97.18,18.94)
  BOTTOM w0.089: U2401.57 94.71,21.2 94.64,21.12 94.64,20.81 93.42,19.59 93.14,19.59 92.79,19.24 92.79,18.89 93.24,18.44 96.68,18.44 v2(97.18,18.94) ; v2(127.17,58.14) v1(126.62,57.93)
ESPI_CPU_CLK_R: length 12.8
  TOP w0.089: R1805.1 126.82,60.22 v1(126.36,60.22) 126.36,60.69 126.79,61.11 126.79,65.34 126.35,65.78 126.35,70.49 v2(126.75,70.89)
  BOTTOM w0.089: v2(126.75,70.89) 126.43,70.58 CPU1.BV32
ESPI_CPU_IO0: length 146
  TOP w0.089: v2(134.35,59.36) 134.35,59.22 134.34,59.21 134.34,59.05 133.64,58.35 131.06,58.35 v1(131,58.41) 131.01,58.43 RN1806.1 ; DB1.9 92.23,18.51 92.79,19.07 v2(93.22,19.07)
  L6 w0.089: v2(93.22,19.07) 93,19.07 91.81,20.25 91.81,20.57 94.84,23.59 97.61,23.59 101.46,27.45 104.14,27.45 106.37,29.68 121.88,29.68 122,29.56 122.35,29.56 122.86,30.08 124.84,30.08 125.17,30.42 125.53,30.42 125.99,29.95 138.05,29.95 139.79,28.21 140.82,28.21 142.6,26.44 142.6,22.92 143.86,21.65 150.35,21.65 150.36,21.66 155.92,21.66 156.25,21.98 156.56,21.98 158.49,23.91 158.49,27.2 155.7,29.99 151.16,29.99 149.85,31.29 149.85,33.42 149.41,33.86 149.41,36.04 149.85,36.47 149.85,38.1 151.84,40.1 151.84,40.81 149.99,42.67 149.99,42.94 149.26,43.67 149.26,46.85 148.54,47.57 148.54,48.79 147.9,49.43 147.9,49.43 146.03,51.3 145.19,51.3 144.25,52.24 144.25,53.1 143.41,53.94 143.41,55.67 140.7,58.39 138.91,58.39 137.13,60.17 135.54,60.17 134.74,59.36 v2(134.35,59.36)
  BOTTOM w0.089: v2(93.22,19.07) 93.4,19.07 94.25,19.91 95.13,19.91 95.39,20.17 95.39,20.87 95.51,20.99 U2401.59
ESPI_CPU_IO0_R: length 14.1
  TOP w0.089: v2(129.87,65.63) 130.81,64.69 130.81,62.88 130.15,62.22 v1(130.15,60.72) 130.26,60.61 RN1806.8
  L4SGND w0.089: v2(129.87,65.63) 129.87,66.06 128.71,70.24 128.23,70.72 128.23,71.8 v2(128.59,72.16)
  BOTTOM w0.089: CPU1.CA29 128.22,72.53 v2(128.59,72.16)
ESPI_CPU_IO1: length 137.3
  TOP w0.089: DB1.8 93.23,18.42 93.65,18.84 93.65,19.63 v1(93.73,19.7) 94.02,19.7 94.23,19.49 v2(94.23,19.19) ; v2(133.38,60.01) 133.08,59.72 RN1806.4
  L6 w0.089: v2(133.38,60.01) 133.38,61.26 134.44,62.32 136.5,62.32 137.31,61.51 138.7,61.51 144.13,56.09 144.13,54.85 145.63,53.35 145.63,52.71 148.62,49.72 149.32,49.02 149.32,47.92 149.97,47.27 149.97,43.96 150.7,43.23 150.7,42.96 152.56,41.11 152.56,38.8 155.42,35.94 155.42,33.31 157.08,31.66 157.08,29.75 159.2,27.62 159.2,23.61 156.86,21.27 156.54,21.27 156.09,20.82 154.86,20.82 154.34,20.29 144.1,20.29 143.54,20.85 143.54,20.91 141.44,23.01 136.82,23.01 130.86,28.97 122.76,28.97 122.64,28.85 121.7,28.85 121.59,28.97 106.66,28.97 104.38,26.69 101.71,26.69 97.03,22.01 95.02,22.01 93.82,20.81 93.82,19.87 94.23,19.45 v2(94.23,19.19)
  BOTTOM w0.089: U2401.60 95.91,20.89 95.74,20.72 95.74,20.02 95.28,19.56 94.6,19.56 v2(94.23,19.19)
ESPI_CPU_IO1_R: length 15.5
  TOP w0.089: RN1806.5 133.41,60.61 v1(133.55,60.75) 133.55,60.85 133.1,61.31 132.89,61.31 v2(131.7,62.5)
  L4SGND w0.089: v2(127.66,72.28) 127.66,72.26 127.18,71.77 127.18,70.91 127.29,70.46 127.51,70 128.07,68.34 128.97,66.22 128.99,65.93 129.14,65.57 130.75,63.43 131.45,62.53 v2(131.7,62.5)
  BOTTOM w0.089: v2(127.66,72.28) 127.64,72.3 127.64,72.3 127.41,72.53 CPU1.BY29
ESPI_CPU_IO2: length 139.1
  TOP w0.089: v1(95.02,19.45) v2(95,18.87) 94.67,18.87 94.23,18.43 DB1.7 ; RN1806.3 132.1,59.33 132.19,59.24 133.17,59.24 133.95,60.02 v2(134.11,60.02)
  L6 w0.089: v2(95,18.87) 94.89,18.76 94.06,18.76 93.78,19.04 93.78,19.41 93.47,19.72 93.47,20.96 94.87,22.36 96.88,22.36 101.58,27.07 104.26,27.07 106.52,29.32 121.74,29.32 121.85,29.21 122.5,29.21 122.61,29.32 137.19,29.32 138.92,27.6 140.93,27.6 142.11,26.42 142.11,22.9 143.72,21.3 156.06,21.3 156.39,21.63 156.71,21.63 158.85,23.76 158.85,27.48 156.72,29.61 156.72,31.52 155.04,33.19 155.04,35.81 152.2,38.65 152.2,40.96 150.34,42.82 150.34,43.09 149.62,43.81 149.62,47 148.9,47.72 148.9,48.94 148.26,49.58 146.08,51.76 145.24,51.76 144.63,52.37 144.63,53.28 143.77,54.14 143.77,55.94 139.12,60.6 136.4,60.6 135.71,61.28 135.08,61.28 134.11,60.31 v2(134.11,60.02)
  BOTTOM w0.089: U2401.61 96.3,21.9 96.3,20.77 96.1,20.57 96.1,19.87 95.43,19.2 95.33,19.2 v2(95,18.87)
ESPI_CPU_IO2_R: length 15.7
  TOP w0.089: RN1806.6 132.1,61.26 132.17,61.33 132.17,61.66 131.93,61.89 131.74,61.89 131.19,62.44 131.19,64.92 129.97,66.13 v2(129.39,66.13)
  L4SGND w0.089: v2(129.39,66.13) 128.47,70.23 128.03,70.67 128.03,71.85 128.14,71.96 128.14,73.12 v2(127.68,73.58)
  BOTTOM w0.089: CPU1.BY27 127.43,73.83 v2(127.68,73.58)
ESPI_CPU_IO3: length 142
  TOP w0.089: DB1.6 95.23,18.4 v2(95.69,18.87) ; v2(133.73,59.2) 133.31,58.78 v1(132.72,58.78) 131.86,58.78 131.6,59.04 RN1806.2
  L6 w0.089: v2(95.69,18.87) 95,19.56 94.63,19.56 94.18,20.01 94.18,20.66 95,21.48 97,21.48 101.85,26.33 104.53,26.33 106.81,28.61 121.44,28.61 121.56,28.5 122.79,28.5 122.91,28.61 130.52,28.61 136.48,22.65 140.6,22.65 141.69,21.56 141.69,21.43 143.18,19.94 154.77,19.94 155.23,20.4 157.55,20.4 158.05,20.89 159.33,23.21 159.56,23.44 159.56,27.77 158.12,29.22 158.12,30.64 158.13,30.66 158.13,31.99 157.83,32.3 157.37,32.3 155.78,33.89 155.78,36.08 152.91,38.95 152.91,41.25 151.05,43.11 151.05,43.38 150.33,44.11 150.33,47.87 149.91,48.29 149.91,49.24 147.04,52.11 147.04,53.05 146.35,53.74 145.74,53.74 144.48,55 144.48,56.24 138.75,61.97 137.49,61.97 136.75,62.71 134.42,62.71 132.97,61.26 132.97,59.73 133.5,59.2 v2(133.73,59.2)
  BOTTOM w0.089: v2(95.69,18.87) 96.45,19.63 96.45,20.42 96.71,20.68 U2401.62
ESPI_CPU_IO3_R: length 15.5
  TOP w0.089: v2(130.81,62.25) 130.81,61.84 131.6,61.05 RN1806.7
  L4SGND w0.089: v2(126.79,73.53) 126.31,73.06 126.31,70.76 126.58,70.49 126.91,70.49 127.06,70.34 127.18,70.05 127.83,68.33 128.76,66.18 128.78,65.85 128.97,65.42 130.09,63.84 130.87,62.49 v2(130.81,62.25)
  BOTTOM w0.089: CPU1.BV27 126.49,73.83 v2(126.79,73.53)
ESPI_CS#: length 151.7
  TOP w0.089: v2(94.96,20.34) 95.76,20.34 v1(96.27,19.83) 96.12,19.68 96.12,18.58 96.23,18.47 DB1.5
  L6 w0.089: v2(94.96,20.34) 95.34,20.72 97.25,20.72 102.15,25.62 105.71,25.62 106.92,26.83 131.22,26.83 136.19,21.87 140.38,21.87 140.98,21.27 140.98,21.14 142.89,19.23 155.06,19.23 155.52,19.68 157.84,19.68 160.04,21.88 160.04,22.91 160.27,23.14 160.27,28.07 158.83,29.51 158.83,30.35 158.85,30.37 158.85,33.16 157.11,34.9 156.8,34.9 156.49,35.2 156.49,36.38 153.62,39.24 153.62,41.55 151.76,43.4 151.76,44.38 151.04,45.1 151.04,48.17 150.66,48.55 150.66,51.12 150.97,51.43 150.97,52.23 150.51,52.69 149.89,52.69 147.45,55.14 145.96,55.14 145.62,55.47 145.62,60.18 146.25,60.8 146.25,63.12 145.36,64.01 137.04,64.01 133.07,67.97 133.07,69.44 132.64,69.87 131.57,69.87 131.11,69.41 130.33,69.41 130,69.74 130,71.68 129.24,72.43 129.03,72.43 v2(128.59,72.87)
  BOTTOM w0.089: v2(94.96,20.34) 95.03,20.41 95.03,21.01 95.11,21.1 U2401.58 ; CPU1.CA28 128.29,73.18 v2(128.59,72.87)
ESPI_RESET#: length 161.5
  TOP w0.089: DB1.4 97.23,18.06 96.54,18.74 v2(96.54,18.96)
  L6 w0.089: v2(96.54,18.96) 95.59,19.91 94.78,19.91 94.53,20.16 94.53,20.51 95.09,21.07 97.1,21.07 102,25.98 104.68,25.98 105.89,27.19 131.43,27.19 136.33,22.29 140.46,22.29 141.33,21.42 141.33,21.28 143.03,19.58 154.92,19.58 155.37,20.04 157.7,20.04 159.68,22.03 159.68,23.06 159.91,23.29 159.91,27.92 158.47,29.36 158.47,30.49 158.49,30.51 158.49,32.13 157.97,32.66 157.51,32.66 156.13,34.04 156.13,36.23 153.27,39.1 153.27,41.4 151.41,43.26 151.41,43.53 150.68,44.26 150.68,48.02 150.3,48.4 150.3,51.27 150.62,51.58 150.62,52.09 150.37,52.34 148.77,52.34 147.96,53.15 147.44,53.15 146.5,54.09 145.89,54.09 144.84,55.14 144.84,56.64 138.27,63.21 135.3,63.21 128.45,70.06 128.45,70.38 128.19,70.63 128.19,73.16 v2(128.57,73.53)
  BOTTOM w0.089: CPU1.CA27 128.27,73.83 v2(128.57,73.53) ; v2(96.54,18.96) 96.54,19.13 97.91,20.5 97.91,21.94 98.68,22.7 98.68,24.4 97.54,25.54 v1(97.03,25.54) 94.25,25.54 92.93,24.21 92.93,22.84 93.11,22.65 U2401.53
EXT_PWR_GATE#: length 11.6
  TOP w0.127: R1731.2 128.35,74.35 129.05,73.64 129.05,72.26 v1(129.16,72.15) 129.05,72.05 129.05,70.71 128.78,70.44 128.78,68.01 v2(130.6,66.19)
  BOTTOM w0.127: v2(130.6,66.19) 130.29,66.19 129.3,67.18 CPU1.CC37
FAN1_PWM: length 159.1
  TOP w0.254: v2(162.94,79.01) 162.73,79.01 v1(162.35,78.64) 161.95,78.24 161.95,76.63 162.24,76.34 162.24,65.61 161.65,65.01 161.65,61.73 161.75,61.63 161.75,53.21 161.16,52.63 161.16,51.38 161.34,51.2 161.34,49.65 161.67,49.32 161.67,46.19 161.53,46.05 161.53,45.55 160.53,44.55 160.53,43.23 160.35,43.05 v2(160.35,42.61)
  L6 w0.254: v2(160.35,42.61) 160.27,42.54 160.27,40.46 164.77,35.97 164.77,33.73 167.32,31.17 167.32,20.44 162.12,15.23 162.12,15.03 159.18,12.1 156.34,12.1 154.76,10.52 145.53,10.52 144.09,11.96 135.93,11.96 134.15,13.73 131.99,13.73 131.7,13.73 130.72,12.76 130.11,12.76 129.86,13.01 127.83,13.01 127.73,13.11 108.43,13.11 107.28,14.26 103.14,14.26 103.12,14.24 101.09,14.24 99.34,12.49 94,12.49 93.93,12.57 90.63,12.57 v2(90.6,12.59)
  BOTTOM w0.203: 90.71,20.76 U2401.47
  BOTTOM w0.254: v2(162.94,79.01) 163.5,79.01 EC2601.1 163.91,79.34 163.96,79.39 164.69,79.39 R2614.1 ; v2(90.6,12.59) 90.68,12.67 90.68,20.72 90.71,20.76
FAN1_TACH: length 5.2
  BOTTOM w0.203: U2401.40 87.91,23.56 R2430.2
  BOTTOM w0.254: D2403.A 87.07,25.32 87.07,24.47 86.62,24.02 86.61,24.02 v1(86.49,23.89) 86.61,23.77 87.2,23.77 R2430.2
FAN_PWM1_C: length 3.4
  TOP w0.102: AFTP2602.1 v2(167.36,78)
  BOTTOM w0.102: v2(167.36,78) 167.05,78.31 FAN1.4 166.08,79.18 R2614.2
FAN_TACH1: length 190.8
  TOP w0.254: v2(159.46,42.39) 159.46,43.42 159.64,43.6 159.64,44.92 160.6,45.88 160.6,46.38 160.78,46.56 160.78,48.96 160.41,49.33 160.41,50.74 160.15,51 160.15,53.1 161.24,54.19 161.24,61.42 161.08,61.58 161.08,65.09 161.14,65.14 161.14,65.22 161.73,65.82 161.73,76.13 161.44,76.42 161.44,79.16 v2(163.15,80.88)
  L6 w0.254: v2(76.08,10.94) 76.81,11.67 79.56,11.67 81.3,13.4 82.88,13.4 83.18,13.1 86.26,13.1 86.7,12.65 89.95,12.65 90.39,13.1 90.81,13.1 90.84,13.07 95.14,13.07 95.67,13.61 97.53,13.61 97.55,13.63 99.34,13.63 100.47,14.77 108.44,14.77 109.48,13.72 127.84,13.72 128.04,13.52 130.59,13.52 131.32,14.24 134.47,14.24 135.67,13.05 143.71,13.05 145.74,11.02 154.55,11.02 156.13,12.6 158.97,12.6 161.61,15.24 161.61,15.44 166.82,20.65 166.82,30.96 164.26,33.51 164.26,35.76 159.77,40.25 159.77,42.13 159.51,42.39 v2(159.46,42.39)
  BOTTOM w0.254: v2(163.15,80.88) 163.15,80.63 EC2602.1 164.19,80.31 R2613.1 ; D2403.K 87.73,25.98 82.85,25.98 82.04,25.16 82.04,25.13 81.95,25.04 81.95,23.74 80.7,22.49 v1(80.7,18.69) 80.7,18.13 76.58,14.01 76.58,13.99 76.08,13.49 v2(76.08,10.94)
FAN_TACH1_C: length 7.8
  TOP w0.254: AFTP2601.1 v2(167.39,76.6)
  BOTTOM w0.254: v2(167.39,76.6) 168.05,77.26 FAN1.3 168.05,80.41 167.8,80.66 166.75,80.66 166.4,80.31 R2613.2
FFS_INT1: length 101.8
  TOP w0.102: R7007.1 183.21,39.39 182.5,39.39 181.49,40.4 v2(181.49,40.62) ; v1(152.78,45.99) 152.78,45.74 153.2,45.32 v2(153.2,45.2)
  L4SGND w0.102: v2(181.49,40.62) 183.03,39.08 183.03,38.48 182.79,38.24 182.46,38.24 182.45,38.25 180.37,38.25 175.87,33.75 175.21,33.75 174.78,34.18 174.78,35.27 172.89,37.16 168.3,37.16 164.85,40.61 159.62,40.61 157.16,43.07 157.16,44.62 157.28,44.73 157.28,45.22 156.99,45.51 156.68,45.51 155.14,47.04 155.14,47.21 154.85,47.5 154.11,47.5 153.2,46.6 v2(153.2,45.2)
  L6 w0.102: v2(153.2,45.2) 153.2,45.27 152.81,45.67 152.81,48.28 153.09,48.56 153.09,51.78 151.26,53.61 151.26,54.64 150.63,55.26 150.62,55.26 147.65,58.23 147.65,60.52 147.02,61.16 147.02,61.71 147.68,62.38 147.68,63.19 148.71,64.22 148.71,70.24 148.06,70.9 148.06,75.99 146,78.05 142.8,78.05 142.09,77.34 137.13,77.34 136.91,77.11 131.19,77.11 130.94,77.36 v2(130.94,77.54)
  BOTTOM w0.102: v2(130.94,77.54) 130.94,77.42 CPU1.CG22
FFS_INT2: length 148
  TOP w0.102: R7008.1 183.31,44.26 182.52,45.05 182.52,45.59 182.28,45.83 181.34,45.83 181.16,45.64 v2(180.11,45.64) ; v2(131.59,82.78) 132.01,83.2 133.78,83.2 134.24,83.66 134.24,84.35 134.49,84.6 135.64,84.6 136.09,84.15 138.19,84.15 138.33,84.02 138.33,83.33 v1(138.35,83.3) 138.49,83.16 139.31,83.16 R2044.2 139.75,83.58 141.99,83.58 142.42,83.15 143.7,83.15 143.95,83.41 151.84,83.41 151.86,83.39 154.53,83.39 154.89,83.03 154.89,80.18 154.31,79.6 154.31,78.32 155.17,77.46 155.17,68.34 154.25,67.43 154.25,62.6 154.36,62.5 154.37,62.5 154.52,62.35 154.71,62.35 v2(154.86,62.2)
  L4SGND w0.102: v2(180.11,45.64) 180.11,45.76 177.42,48.46 165.2,48.46 162.28,51.38 159.82,51.38 158.55,52.65 157.2,52.65 155.94,51.39 154.42,51.39 153.78,52.03 153.78,52.98 154.46,53.66 155.4,53.66 156.03,54.3 156.03,55.84 155.16,56.71 150.85,56.71 149.76,57.8 149.76,57.84 149.52,58.08 149.18,58.08 148.76,57.66 139.34,57.66 136.02,60.98 134.58,60.98 133.75,61.81 133.75,62.18 131.07,64.86 131.07,66.11 131.32,66.36 139.3,66.36 143.05,62.6 144.75,62.6 145.36,63.21 145.85,63.21 145.95,63.11 145.95,62.34 147.16,61.13 150.11,61.13 151.18,62.2 v2(154.86,62.2)
  BOTTOM w0.102: v2(131.59,82.78) 131.96,83.15 CPU1.CH12
FP1_USB20_CON_N: length 6.7
  BOTTOM w0.102: FPR1.3 175.11,49.95 174.88,50.18 174.88,50.22 174.88,50.22 174.88,50.32 174.77,50.42 173.76,50.42 173.58,50.24 173.58,50.23 173.52,50.17 172.89,50.17 172.42,49.7 172.04,49.7 ED9202.6 171.57,49.7 170.03,49.7 R9209.2
FP1_USB20_CON_P: length 6.4
  BOTTOM w0.102: v1(170.76,49.32) 170.76,49.47 ; 170.76,49.47 172.52,49.47 172.98,49.94 ED9202.1 174.67,49.94 174.88,49.73 174.88,49.72 174.98,49.62 174.98,49.62 175.15,49.45 FPR1.4 ; 170.76,49.47 169.85,49.47 R9210.2
FP1_USB20_N: length 80.6
  L6 w0.089: v2(130.29,93.66) 130.29,93.32 130.42,93.19 130.76,93.19 132.09,91.86 132.81,91.86 132.93,91.99 134.48,91.99 134.99,91.47 138.15,91.47 141.21,88.41 154.22,88.41 158.77,83.86 158.77,83.46 162.05,80.18 162.05,73.16 162.55,72.65 162.55,68.6 163.01,68.15 163.01,54.56 164.7,52.87 165.9,52.87 167.38,51.39 167.38,51.02 167.69,50.7 167.69,49.87 167.63,49.81 167.35,49.81 v2(167.23,49.93)
  BOTTOM w0.076: CPU1.CG5 131.28,87.7 131.31,87.81 130.94,88.18 130.94,88.6 130.86,88.77 130.86,89.05 130.9,89.14 130.91,89.17 130.93,89.22 130.93,89.26 130.91,89.29 130.86,89.45 130.86,89.65 130.89,89.82 130.89,89.96 130.86,90.13 130.86,90.34 131.02,90.79 131.02,90.79 131.02,90.81 131.04,90.82 131.04,90.86 131.04,90.86 131.16,91.4 131.16,91.41 131.13,91.43 131.13,91.45
  BOTTOM w0.102: 131.13,91.45 131.13,92.53 130.65,93.01 130.65,93.11 ; v1(130.51,93.11) 130.65,93.11 ; 130.65,93.11 130.65,93.52 130.51,93.66 v2(130.29,93.66) ; v2(167.23,49.93) 167.33,49.83 168.58,49.83 R9209.1
FP1_USB20_P: length 81.7
  L6 w0.089: v2(131.09,93.66) 131.09,93.13 132.16,92.05 132.73,92.05 132.85,92.18 134.56,92.18 135.07,91.66 138.23,91.66 141.29,88.6 154.3,88.6 158.96,83.94 158.96,83.53 162.24,80.26 162.24,73.24 162.74,72.73 162.74,68.68 163.2,68.23 163.2,54.63 164.78,53.06 165.98,53.06 167.57,51.47 167.57,51.09 167.88,50.78 167.88,49.79 167.71,49.62 167.55,49.62 v2(167.23,49.29)
  BOTTOM w0.076: CPU1.CG6 131.38,87.4 131.42,87.5 131.46,87.66 131.48,87.77 131.5,87.87 131.52,87.89 131.57,88.11 131.57,88.15 131.57,88.38 131.41,88.54 131.11,88.65 131.04,88.82 131.04,89.01 131.07,89.08 131.08,89.12 131.08,89.13 131.1,89.19 131.1,89.29 131.08,89.35 131.04,89.48 131.04,89.63 131.07,89.81 131.07,89.97 131.04,90.15 131.04,90.3 131.2,90.75 131.22,90.82 131.22,90.83 131.34,91.38 131.34,91.41 131.36,91.43 131.36,91.45
  BOTTOM w0.102: 131.36,91.45 131.36,92.62 130.88,93.11 130.88,93.45 v2(131.09,93.66) ; R9210.1 168.5,49.6 167.53,49.6 v2(167.23,49.29) v1(166.62,49.29)
FPR_SCAN#: length 141.9
  TOP w0.102: R2465.2 85.01,19.07 v2(86.03,19.07) 86.03,17.37 86.7,16.69 86.7,14.03 86.6,13.92 86.58,13.92 86.26,13.61 v2(86.13,13.61) ; v2(177.2,47.39) 177.29,47.3 v1(177.29,46.86)
  L4SGND w0.102: v2(177.2,47.39) 177.2,46.46 180.27,43.4 181.26,43.4 181.79,42.87 181.79,42.31 182.47,41.63 182.47,39.99 183.51,38.94 183.51,38.3 182.39,37.18 179.88,37.18 174.33,31.63 171.88,31.63 168.95,28.7 168.95,23.23 161.04,15.32 146.54,15.32 146.35,15.13 141.79,15.13 140.68,14.02 132.78,14.02 131.41,12.64 127.72,12.64 126.88,11.8 119.37,11.8 118.36,12.81 111.8,12.81 110.67,13.94 106.57,13.94 106.01,14.5 104.36,14.5 104.23,14.37 99.03,14.37 98.5,14.9 94.61,14.9 93.21,13.51 88.72,13.51 88.26,13.96 86.49,13.96 v2(86.13,13.61)
  BOTTOM w0.102: v2(177.2,47.39) 176.64,47.95 FPR1.7 ; v2(86.03,19.07) 86.49,19.53 86.49,20.56 86.82,20.9 88.32,20.9 88.71,21.3 U2401.42
GPD11/LANPHYPC: length 7.7
  BOTTOM w0.076: 125.19,65.86 125.35,66.03 125.35,67.04 125.07,67.33 125.07,67.71 125.14,67.91 125.14,68.47 125.15,68.53 125.22,68.61 125.22,69.27 CPU1.BU34
  BOTTOM w0.102: 125.19,65.86 124.86,65.86 124.4,65.4 124.4,63.86 v1(124.49,63.76) 124.56,63.69 125.47,63.69 R1703.2
GPD_7: length 24.3
  TOP w0.102: R1524.2 139.06,56.41 138.18,57.3 v1(137.79,57.3) 137.11,57.3 R1525.1 136.34,57.66 v2(136.34,57.79)
  L4SGND w0.102: v2(126.75,70.04) 127.13,69.66 127.66,68.26 128.42,66.49 128.42,63.93 131.76,60.6 134.19,60.6 135.2,59.58 135.2,58.54 135.94,57.81 135.94,57.79 v2(136.34,57.79)
  BOTTOM w0.102: v2(126.75,70.04) 126.75,69.99 126.27,69.51 125.96,69.51 125.83,69.39 125.83,69.13 125.84,69.12 125.84,69.09 126.01,68.92 126.05,68.92 126.13,68.83 CPU1.BV35
GPP_B22_GSPI1_MOSI: length 34.4
  TOP w0.102: R1553.1 149.86,60.17 v1(149.86,59.71) 149.61,59.45 149.61,57.93 v2(149.35,57.68)
  L4SGND w0.102: v2(149.35,57.68) 149.06,57.39 138.69,57.39 136.2,59.89 135.19,59.89 134.89,60.19 134.87,60.19 134.27,60.79 134.18,60.79 133.39,61.57 132.92,61.57 132.64,61.85 132.64,62.92 130.3,65.26 130.3,65.92 130.19,66.02 130.19,69.26 130.02,69.43 130.02,70.15 129.63,70.54 129.34,70.54 129.1,70.77 129.1,71.06 v2(128.63,71.53)
  BOTTOM w0.102: v2(128.63,71.53) 128.28,71.88 CPU1.CA30
GPP_E0/SATAXPCIE0/SATAGP0: length 20.4
  TOP w0.102: v2(147.35,89.45) 147.75,89.05 148.28,89.05 148.36,89.12 148.36,89.12 148.49,89.25 151.08,89.25 151.8,89.96 RN1602.1
  BOTTOM w0.076: 136.09,86.12 135.84,86.12 arc(135.75,86.07) 135.65,86.05 135.42,86.05 arc(135.33,86.06) 135.25,86.11 135.19,86.17 134.85,86.17 CPU1.CN8
  BOTTOM w0.102: 136.09,86.12 137.49,86.12 138.76,87.39 v1(140.08,87.39) 144.92,87.39 146.37,88.84 146.74,88.84 v2(147.35,89.45)
GPP_E1/SATAXPCIE1/SATAGP1: length 21.8
  TOP w0.102: v2(152.43,90.3) 152.45,90.32 RN1602.2
  BOTTOM w0.076: 137.43,85.09 135.74,85.09 135.6,84.95 135.51,84.95 135.43,84.86 134.27,84.86 CPU1.CM10
  BOTTOM w0.102: v2(152.43,90.3) 152.28,90.3 150.03,88.05 146.64,88.05 144.79,86.2 141.77,86.2 141.54,86.43 139.22,86.43 v1(138.89,86.1) 137.88,85.09 137.43,85.09
GPP_E3/CPU_GP0: length 1.2
  TOP w0.102: v2(130.16,84.41) 130.22,84.47 TP308.1
  BOTTOM w0.102: CPU1.CE9 130.18,84.43 130.16,84.41 v2(130.16,84.41)
GPP_E23_STRAP: length 8.3
  BOTTOM w0.102: CPU1.CN4 134.85,88.58 135.58,88.58 135.74,88.75 135.94,88.75 136.6,89.41 136.6,91.53 137.79,92.73 137.79,94.51 TP402.1
GPP_H17_STRAP: length 6
  BOTTOM w0.102: R1527.1 v1(139.62,73.55) 139.12,73.55 137.85,74.82 135.53,74.82 CPU1.CP26
GPP_H21: length 16.5
  TOP w0.102: R1522.2 R1523.1 139.68,77.36 140.26,76.78 140.54,76.5 140.54,74.3 138.64,72.41 v1(138.15,72.41) v2(137.54,72.41)
  BOTTOM w0.102: CPU1.CF25 130.96,74.67 133.17,74.67 133.71,74.13 134.04,74.13 134.06,74.15 134.36,74.15 134.53,73.98 134.53,73.79 134.77,73.55 136.26,73.55 136.79,73.03 136.79,73.01 137.02,72.78 137.04,72.78 137.4,72.41 v2(137.54,72.41)
GPP_H23: length 43.1
  TOP w0.102: v2(154.69,69.23) 154.58,69.13 R1528.1 153.52,69.58 153.52,71.14 R1526.2
  L4SGND w0.102: v2(138.09,73.17) 143.13,73.17 144.91,71.39 146.05,71.39 146.38,71.06 146.38,70.7 146.65,70.43 148.01,70.43 148.26,70.18 148.26,70.15 151.94,66.46 160.84,66.46 161.09,66.72 161.09,67.88 160.89,68.09 158.79,68.09 158.79,68.09 157.25,68.09 157.2,68.14 155.78,68.14 v2(154.69,69.23)
  BOTTOM w0.076: 136.4,74.31 136.09,74.31 136.03,74.25 135.79,74.25 arc(135.75,74.26) 135.71,74.27 arc(135.64,74.31) 135.57,74.32 135.5,74.32 arc(135.44,74.31) 135.38,74.27 arc(135.34,74.26) 135.3,74.25 135,74.25 134.9,74.35 134.9,74.52 134.76,74.66 134.58,74.72 134.24,74.72 133.94,74.42 CPU1.CM26
  BOTTOM w0.102: v2(138.09,73.17) 138.09,73.51 v1(137.84,73.76) 137.29,74.31 136.4,74.31
GPPC_H18_BOOTMPC: length 6.7
  BOTTOM w0.076: CPU1.CN27 135.07,74.04 135.2,74.04 arc(135.27,74.05) 135.34,74.08 arc(135.4,74.1) 135.46,74.11 135.64,74.11 arc(135.68,74.11) 135.71,74.09 135.71,74.09 136.23,74.09 136.24,74.09
  BOTTOM w0.127: 136.24,74.09 136.87,74.09 137.67,73.3 137.67,73 138.21,72.46 v1(139.06,72.46) 140.21,72.46 R2119.1
GPPC_H18_VCCIO_LPM: length 33.5
  TOP w0.127: v2(153.03,57.93) 152.78,57.93 152.26,58.45 152.26,58.49 152.21,58.54 152.21,66.55 150.54,68.22 150.54,70.8 150.74,71 150.74,72.48 150.24,72.98 147.07,72.98 146.11,72.03 v2(141.6,72.03)
  BOTTOM w0.127: R2119.2 141.48,72.79 142.24,72.03 v1(142.24,71.9) 141.73,71.9 v2(141.6,72.03) ; U4008.2 156.44,59.4 R4042.2 R4040.2 155.83,59.17 155.38,58.73 155.38,58.3 154.83,57.74 154.82,57.74 154.5,57.42 153.54,57.42 v2(153.03,57.93)
GPU_THM_SMBCLK: length 4.7
  BOTTOM w0.089: R2459.1 80.7,13.53 v1(81.28,14.12) 81.28,13.73 81.97,13.05 81.97,12.58 82.05,12.49 U2401.12
GPU_THM_SMBDAT: length 3.6
  BOTTOM w0.089: U2401.11 82.79,12.09 82.58,12.3 81.93,12.3 81.64,12.6 v1(81.64,12.85) 81.41,12.85 81.03,12.46 R2447.1
GSEN2_INT1: length 4.7
  TOP w0.102: U7001.12 184.46,39.27 R7007.2 184.33,38.73 184.23,38.63 183.77,38.63 183.39,38.25 v1(183.24,38.25) 183.13,38.35 183.13,38.71 182.79,39.05 182.46,39.05 182.28,38.88 R7005.2
GSEN2_INT1_C: length 77.8
  TOP w0.102: v2(181.49,39.72) 181.18,39.41 R7005.1 ; v2(140.84,53.08) 140.84,52.98 140.14,52.28 137.86,52.28 137.16,52.98 135.64,52.98 132.97,55.64 v1(132.97,56.15) 132.97,56.79 132.79,56.96 132.79,56.98 v2(132.7,57.07)
  L4SGND w0.102: v2(181.49,39.72) 181.21,39.44 169.27,39.44 168.48,40.23 168.48,41.72 167.89,42.31 167.89,42.82 166.57,44.14 166.57,44.7 164.36,46.91 160.73,46.91 159.95,47.69 158.83,47.69 158.5,48.02 158.5,49.59 157.58,50.5 153.94,50.5 152.91,51.53 152.91,53.21 154.12,54.42 155.12,54.42 155.3,54.6 155.3,55.53 154.86,55.96 152.97,55.96 152.22,55.21 150.04,55.21 148.51,53.69 146.41,53.69 146.36,53.75 145.78,53.75 143.5,56.03 140.06,56.03 139.79,55.76 139.79,54.03 140.74,53.08 v2(140.84,53.08)
  BOTTOM w0.102: v2(132.7,57.07) 131.92,57.07 130.53,58.46 R2001.2
GSEN2_INT1_ISH: length 10.1
  BOTTOM w0.076: 129.41,64.28 128.32,65.37 128.32,65.75 128.4,65.83 128.4,66.31 128.21,66.5 128.21,67.34 128.27,67.49 128.27,67.68 128.26,67.69 128.22,67.79 128.22,68.01 CPU1.CA36
  BOTTOM w0.102: R2001.1 130.31,59.86 130.31,60.53 129.49,61.35 v1(129.49,62.45) 129.49,62.77 129.95,63.22 129.95,63.74 129.41,64.28
GSEN2_INT2: length 5.1
  TOP w0.102: R7008.2 184.76,43.38 184.76,42.54 184.28,42.06 184.28,41.14 v1(184.63,40.78) 184.63,40.2 R7006.2 184.46,39.76 U7001.11
GSEN2_INT2_C: length 76.1
  TOP w0.102: v2(181.48,41.29) 181.9,40.88 181.9,40.28 182.53,39.64 183.21,39.64 R7006.1
  L4SGND w0.102: v2(140.98,55.62) 143.27,55.62 145.53,53.36 145.53,52.1 144.86,51.43 144.86,49.07 144.96,48.96 145.62,48.96 145.72,49.07 145.72,49.83 146.1,50.21 148.61,50.21 149.36,50.96 152.39,50.96 153.28,50.07 157.4,50.07 157.94,49.54 157.94,46.67 161.13,43.48 166.65,43.48 167.69,42.44 167.69,42.22 168.28,41.64 168.28,38.47 169.09,37.65 174.08,37.65 174.29,37.43 178.64,37.43 180.09,38.88 181.23,38.88 181.9,39.55 181.9,39.89 181.57,40.22 181.32,40.22 181.08,40.46 181.08,40.9 v2(181.48,41.29)
  BOTTOM w0.102: v2(140.98,55.62) 140.78,55.82 140.23,55.82 139.85,56.2 138.6,56.2 137.99,56.81 137.29,56.81 136.38,55.91 135.81,55.91 135.32,56.4 133.99,56.4 132.38,58.01 v1(131.88,58.01) 131.5,58.01 131.29,58.21 R2002.2
GSEN2_INT2_ISH: length 11.1
  BOTTOM w0.076: CPU1.CA35 128.34,68.54 128.4,68.39 128.4,67.8 128.42,67.75 128.43,67.71 128.43,66.51 128.56,66.38 128.56,65.51
  BOTTOM w0.102: 128.56,65.51 130.14,63.94 130.14,62.42 129.88,62.16 129.88,61.27 130.5,60.65 131.06,60.65 v1(131.17,60.55) 131.29,60.42 R2002.1
GSEN_INT1: length 315.3
  L4SGND w0.102: v2(62.87,91.33) 61.44,89.91 53.86,89.91 53.38,89.43 48.01,89.43 45.34,86.76 45.34,86.59 45.34,86.59 45.34,85.15 44.45,84.25 41.76,84.25 38.98,81.48 37.22,81.48 34.39,78.65 34.39,75.26 34.11,74.98 34.11,67.04 33.64,66.57 33.64,57.22 33.78,57.08 33.78,55.97 33.53,55.72 31.29,55.72 31.27,55.73 31.23,55.77 30.12,55.77 27.43,53.08 27.43,32.16 28.33,31.26 29.06,31.26 31.69,28.63 31.69,28.3 39.9,20.08 40.43,20.08 44.67,15.84 45.05,15.84 49.26,11.64 66.48,11.64 68.71,13.86 78.11,13.86 78.56,14.32 79.58,14.32 79.83,14.06 82.37,14.06 82.73,14.06 82.98,14.31 82.98,14.56 83.02,14.6 83.02,15.03 85.18,17.19 85.22,17.19 86.03,18 88.82,18 90.19,19.37 92.3,19.37 93.04,18.64 93.4,18.64 93.65,18.89 93.65,19.37 94,19.73 94.31,19.73 94.64,19.39 97.34,19.39 97.51,19.22 106.59,19.22 107.37,18.43 109.76,18.43 110.65,17.54 111.72,17.54 113.31,15.96 126,15.96 127.41,17.37 128.99,17.37 131.33,19.7 133.26,19.7 133.79,19.17 140.39,19.17 141.18,18.38 145,18.38 146.28,19.66 160.1,19.66 165.49,25.05 165.49,28.45 157.48,36.47 156.25,36.47 152.38,40.34 152.38,40.78 151.89,41.27 151.89,41.31 150.69,42.51 149.66,42.51 149.53,42.39 147.78,42.39 144.53,45.64 144.53,47.36 143.32,48.57 143.32,51.87 141.48,53.71 140.71,53.71 140.45,53.98 140.45,54.48 140.77,54.8 v2(140.97,54.8)
  BOTTOM w0.102: v2(140.97,54.8) 140.93,54.76 139.95,54.76 139.12,55.59 137.02,55.59 136.71,55.29 134.58,55.29 134.25,54.96 132.54,54.96 v1(129.67,57.83) 129.17,58.32 129.17,60.85 128.7,61.32 128.7,64.2 127.19,65.71 127.19,67.46 127.1,67.55 127.1,69.22 CPU1.BW34 ; v2(62.87,91.33) 63.3,90.9 TCBD1.5
GSEN_INT2: length 310.3
  L4SGND w0.102: v2(63.5,91.33) 61.87,89.71 53.94,89.71 53.46,89.22 48.1,89.22 45.55,86.67 45.55,85.06 44.53,84.05 41.84,84.05 39.07,81.27 37.3,81.27 34.59,78.57 34.59,75.18 34.32,74.9 34.32,66.96 33.85,66.49 33.85,57.31 33.99,57.17 33.99,55.89 33.61,55.52 33.45,55.52 33.44,55.52 31.25,55.52 31.16,55.56 31.14,55.57 30.2,55.57 27.64,53 27.64,33.87 29.21,32.3 29.21,31.4 31.89,28.72 31.89,28.38 33.03,27.25 34.99,27.25 37.08,25.15 37.08,24.12 40.26,20.95 40.79,20.95 45.03,16.71 48.06,16.71 50.67,14.09 50.67,12.97 51.18,12.46 59.69,12.46 59.82,12.59 66.04,12.59 67.94,14.5 76.26,14.5 76.41,14.34 76.75,14.34 76.9,14.5 78.45,14.5 78.48,14.52 79.66,14.52 79.69,14.5 81.94,14.5 82.37,14.93 82.55,14.93 85.01,17.39 85.13,17.39 85.94,18.2 88.74,18.2 90.12,19.59 93.22,19.59 93.68,20.05 94.28,20.05 94.73,19.59 97.42,19.59 97.59,19.42 109.06,19.42 110.74,17.75 111.8,17.75 113.39,16.16 125.91,16.16 127.32,17.57 128.91,17.57 131.25,19.91 133.34,19.91 133.87,19.37 140.48,19.37 141.27,18.59 144.92,18.59 146.19,19.86 160.02,19.86 165.29,25.14 165.29,28.37 157.39,36.26 156.17,36.26 152.18,40.25 152.18,40.69 151.69,41.18 151.69,41.22 150.6,42.31 149.75,42.31 149.62,42.18 147.69,42.18 144.32,45.55 144.32,47.28 143.12,48.48 143.12,51.79 141.42,53.49 140.62,53.49 140.21,53.9 v2(140.21,55.42)
  BOTTOM w0.102: TCBD1.6 63.8,91.03 v2(63.5,91.33) ; CPU1.CA37 128,66.45 128.22,66.24 128.22,65.9 128.14,65.82 128.14,65.3 129.15,64.29 129.15,64.27 129.13,64.25 129.13,61.43 129.92,60.64 129.92,58.5 132.22,56.2 v1(132.49,56.2) 133.3,55.39 134.1,55.39 134.42,55.7 136.55,55.7 136.85,56 139.28,56 139.77,55.52 140.11,55.52 v2(140.21,55.42)
GSENSOR_CS: length 2.4
  TOP w0.102: U7001.2 185.96,38.66 185.42,38.12 v1(185.42,37.61) 185.75,37.28 R7004.1
GSENSOR_SDO: length 4.8
  TOP w0.102: R7002.2 R7003.2 188.47,37.28 v1(188.72,37.53) 188.26,37.99 186.69,37.99 186.46,38.22 U7001.3
GYRO_DRDY: length 300.6
  L4SGND w0.102: v2(57.81,91.31) 56.61,90.11 53.78,90.11 53.29,89.63 47.93,89.63 45.14,86.84 45.14,86.5 45.14,85.23 44.36,84.45 41.67,84.45 38.92,81.7 37.16,81.7 34.19,78.74 34.19,75.35 33.91,75.07 33.91,67.12 33.44,66.65 33.44,57.82 32.74,57.12 32.74,56.79 31.93,55.97 29.81,55.97 29.33,55.49 28.35,55.49 27.18,54.31 27.18,32.51 27.23,32.46 27.23,32.07 28.31,30.99 28.84,30.99 29.04,30.99 31.48,28.55 31.48,28.22 39.82,19.88 40.35,19.88 44.59,15.64 44.97,15.64 49.17,11.44 66.79,11.44 68.2,12.85 77.38,12.85 78.65,14.12 79.49,14.12 79.75,13.86 82.46,13.86 82.81,13.86 83.19,14.23 83.19,14.43 83.22,14.47 83.22,14.94 85.27,16.99 85.3,16.99 86.11,17.8 91.43,17.8 92.04,18.41 101.07,18.41 101.38,18.72 106.8,18.72 107.29,18.23 109.68,18.23 110.57,17.34 111.64,17.34 113.22,15.75 126.08,15.75 127.49,17.16 129.31,17.16 131.65,19.5 133.17,19.5 133.71,18.97 140.31,18.97 141.1,18.18 145.08,18.18 146.36,19.46 160.19,19.46 165.7,24.97 165.7,28.53 157.56,36.67 156.34,36.67 152.59,40.42 152.59,40.86 152.1,41.35 152.1,41.39 150.77,42.72 149.63,42.72 149.1,43.25 148.77,43.25 144.73,47.29 144.73,47.45 143.52,48.65 143.52,52.11 v2(141.51,54.12)
  BOTTOM w0.102: R2028.2 130.79,55.23 v1(130.86,55.23) 131.33,54.76 134.33,54.76 134.66,55.09 136.8,55.09 137.1,55.39 139.03,55.39 140.7,53.72 141.12,53.72 v2(141.51,54.12) ; TCBD1.8 64.8,89.3 64.66,89.16 60.64,89.16 59.61,90.19 58.8,90.19 57.81,91.18 v2(57.81,91.31)
GYRO_DRDY_ISH: length 16.7
  BOTTOM w0.102: R2051.1 129.27,53.27 R2052.2 R2028.1 130.35,55.66 v1(130.35,56.36) 128.91,57.8 128.91,60.85 128.51,61.24 128.51,64.12 127,65.63 127,67.38 126.79,67.59 CPU1.BW37
GYRO_INT: length 3.3
  TOP w0.102: v2(64.14,91.33) 63.75,91.71 R5524.1 63.7,92.22 v1(62.84,92.22)
  BOTTOM w0.102: TCBD1.7 64.3,91.17 v2(64.14,91.33)
GYRO_INT_C: length 167.5
  TOP w0.102: v2(154.49,97.62) 158.12,94 158.12,87.65 163.63,82.14 163.63,77.76 163.39,77.52 163.39,75.61 163.6,75.39 163.6,70.46 163.09,69.95 163.09,63.7 v2(162.53,63.14) ; v2(84.44,105.41) 84.45,105.35 84.54,104.41 84.05,103.76 83.74,103.44 83.74,103.43 83.15,102.85 83.15,102.84 82.74,102.44 77.5,100.52 74.83,99.48 66.93,95.01 64.95,93.03 v1(64.67,93.03) R5524.2 ; R2027.2 146.66,59.78 146.66,61.49 v2(145.44,62.71)
  L4SGND w0.102: v2(84.44,105.41) 86.37,107.33 111.51,107.33 112.76,106.08 122.29,106.08 123.14,106.93 131.04,106.93 131.7,106.27 131.7,100.63 132.34,99.99 142.21,99.99 142.95,99.26 149.05,99.26 150.68,97.62 v2(154.49,97.62) ; v2(145.44,62.71) 145.44,61.36 145.86,60.93 148.78,60.93 150.36,60.93 151.22,61.79 155.12,61.79 157.18,63.85 160.49,63.85 161.21,63.14 v2(162.53,63.14)
GYRO_INT_ISH: length 39
  TOP w0.102: R2027.1 147.65,57.93 147.65,56.74 148.34,56.06 v2(148.34,55.59)
  BOTTOM w0.102: CPU1.CA34 127.73,69.27 127.73,67.18 127.38,66.83 127.38,65.79 128.91,64.26 128.91,61.39 129.59,60.7 v1(129.59,59.58) 129.59,58.51 132.94,55.16 134.16,55.16 134.49,55.49 136.63,55.49 136.93,55.8 139.2,55.8 140.04,54.96 140.56,54.96 140.8,55.2 141.26,55.2 142.02,55.52 145.7,55.52 146.09,55.13 147.51,55.13 148.49,54.15 148.69,54.15 149.05,54.5 149.05,54.88 v2(148.34,55.59)
H_CPUPWRGD: length 17.8
  TOP w0.102: v1(113.28,101.16) v2(113.28,100.35)
  L6 w0.102: v2(113.28,100.35) 113.03,100.09 113.03,95.9 v2(112.52,95.4)
  BOTTOM w0.102: v2(112.52,95.4) 112.01,94.89 112.01,94.43 R1714.2 111.47,93.27 111.47,89.86 CPU1.AR2 ; v2(113.28,100.35) 113.28,100.09 115.32,98.06 115.71,98.06 ED301.2
H_PECI: length 6.2
  BOTTOM w0.089: R2437.1 C2405.1 103.1,10.43 102.6,10.93 101.8,10.93 100.91,10.03 v1(100.91,9.92) 100.91,9.8 100.01,8.89 U2401.94
HDA_BITCLK_CODEC: length 125.2
  TOP w0.089: U2701.14 25.42,21.8 25.68,22.07 26.19,22.07 v1(27.41,23.28) 27.41,23.54 EC1901.2 27.43,24.58 27.43,25.29 27.81,25.67 30.05,25.67 30.56,25.16 EC2701.1 31.31,24.9 34.17,24.9 35.18,23.89 v2(38.86,23.89)
  BOTTOM w0.089: v2(38.86,23.89) 38.86,24.23 40.56,25.92 40.56,27.88 44.06,31.38 44.06,42.45 44.87,43.26 47.2,43.26 51.93,47.98 56.36,47.98 60.78,52.4 79.59,52.4 82.24,55.05 117.42,55.05 119.82,57.45 120.83,57.45 121.17,57.79 121.17,58.32 121.67,58.82 R1920.1
HDA_BITCLK_CPU: length 8.2
  BOTTOM w0.076: 122.97,67.02 CPU1.BN37
  BOTTOM w0.089: 122.97,67.02 122.97,66.92 123.74,66.14 123.74,63.58 122.02,61.86 122.02,61.43 v1(122.02,61.43) 122.02,61.42 122.02,61.41 122.02,60.88 R1920.2
HDA_RST_N_CPU: length 4.3
  BOTTOM w0.089: TP1903.1 122.02,68.62 CPU1.BL35
HDA_SDIN0_CODEC: length 3.9
  TOP w0.089: U2701.16 24.62,21.9 25.59,22.87 v1(25.94,22.87) 26.19,23.11 R2730.2
HDA_SDIN0_CPU: length 130.6
  TOP w0.089: v2(37.72,24.91) 37.34,24.91 v1(37.08,25.16) 36.28,25.97 35.64,25.97 34.94,26.67 34.94,27.03 34.74,27.24 33.61,27.24 33.56,27.2 31.48,27.2 30.92,27.76 28,27.76 27.28,27.04 27.26,27.04 26.19,25.97 R2730.1
  BOTTOM w0.076: 122.32,66.95 122.32,67.54 122.56,67.78 122.65,67.94 122.65,68.57 CPU1.BN35
  BOTTOM w0.089: v2(37.72,24.91) 37.72,25.04 39.15,26.47 39.15,27.9 43.05,31.8 43.05,43.11 44.27,44.34 46.85,44.34 51.51,49 55.94,49 60.36,53.41 79.05,53.41 81.7,56.06 115.58,56.06 118.49,58.98 118.49,60.34 119.38,61.23 120.74,61.23 121.36,61.85 121.36,62.5 122.3,63.44 122.95,63.44 123.39,63.87 123.39,65.26 122.32,66.33 122.32,66.95
HDA_SDOUT_CODEC: length 127.1
  TOP w0.089: U2701.17 24.22,21.85 25.35,22.98 EC1903.1 25.35,26.52 27.14,28.3 33.02,28.3 33.1,28.38 35.23,28.38 36.37,27.25 36.37,27.15 v1(37.08,26.43) v2(37.72,25.8)
  BOTTOM w0.089: R1921.1 120.14,58.44 117.22,55.52 82.05,55.52 79.4,52.87 60.59,52.87 56.17,48.45 51.73,48.45 47.01,43.73 44.67,43.73 43.59,42.65 43.59,31.58 40.09,28.07 40.09,26.16 38.37,24.45 37.42,24.45 37.21,24.66 37.21,25.29 v2(37.72,25.8)
HDA_SDOUT_CPU: length 11
  BOTTOM w0.076: CPU1.BN36 122.81,67.95 122.81,67.9 122.71,67.72 122.71,66.41
  BOTTOM w0.089: 122.71,66.41 123.56,65.56 123.56,63.68 122.97,63.08 122.55,63.08 v1(122.12,62.65) 121.67,62.2 121.67,61.29 R1512.2 R1921.2 R1909.2
HDA_SPKR_R: length 4.4
  BOTTOM w0.254: D2702.2 5.52,5.54 v1(6.6,4.46) 6.66,4.52 RN2702.3
HDA_SYNC_CODEC: length 125.3
  TOP w0.089: v2(39.5,23.89) 39.01,24.38 35.45,24.38 v1(34.92,24.9) 34.46,25.37 31.01,25.37 30.25,26.14 27.56,26.14 26.8,25.38 26.8,23.13 26.06,22.4 25.5,22.4 25.02,21.92 U2701.15
  BOTTOM w0.089: v2(39.5,23.89) 39.5,24.2 41.03,25.73 41.03,27.08 44.53,30.58 44.53,42.26 45.06,42.79 47.53,42.79 52.26,47.51 56.56,47.51 60.98,51.93 79.79,51.93 82.36,54.5 117.6,54.5 120.08,56.98 120.63,56.98 121.02,56.98 121.64,57.6 121.64,58.03 122.43,58.82 R1908.1
HDA_SYNC_CPU: length 10.2
  BOTTOM w0.089: R1908.2 122.43,62.02 122.89,62.48 123.19,62.48 v1(123.57,62.86) 123.92,63.21 123.92,66.22 123.21,66.92 123.21,67.42 123.23,67.43 123.23,69.27 CPU1.BN34
HDMI_BOM_OPTION: length 8.6
  TOP w0.254: U5701.C5 27.54,62.69 v2(27.18,63.05) 26.81,62.69 U5701.C4 ; U5701.E3 25.95,61.09 v2(25.55,61.49) 25.95,61.89 U5701.D3
  L4SGND w0.254: v2(27.18,63.05) 26.63,63.6 25.37,63.6 25.07,63.3 25.07,61.96 v2(25.55,61.49)
  BOTTOM w0.254: v2(27.18,63.05) 27.01,62.88 v1(26.54,62.88) ; v2(25.55,61.49) 24.92,62.11 R5703.2
HDMI_CEC: length 26.2
  TOP w0.102: v2(25.57,60.72) 25.57,60.68 U5701.F2
  L6 w0.102: v2(23.11,47.26) 23.62,47.77 23.62,49.8 24.74,50.92 24.74,57.52 25.15,57.93 25.15,60.3 v2(25.57,60.72)
  BOTTOM w0.102: R5761.1 22.3,59.2 v1(22.4,59.3) 22.48,59.38 23.42,59.38 23.72,59.68 23.72,60.04 23.9,60.22 25.07,60.22 v2(25.57,60.72) ; R5708.2 26.62,50.39 25.52,49.29 25.17,49.29 24.77,48.89 24.77,47.15 24.41,46.8 23.58,46.8 v2(23.11,47.26)
HDMI_CEC_CON: length 21.3
  BOTTOM w0.102: HDMI1.13 10.55,63 11.05,62.5 11.05,57.04 11.43,56.66 12.57,56.66 12.95,57.04 12.95,60.7 13.54,61.28 14.66,61.28 15,61.63 ED5703.6 ED5703.5 16.53,61.63 v1(17.47,60.69) 17.69,60.47 18.64,60.47 19.91,59.2 R5761.2
HDMI_CEC_R: length 2.8
  BOTTOM w0.102: R5708.1 28.27,50.44 v1(28.52,50.69) 28.7,50.87 28.7,52 D5702.K
HDMI_DDI_TX_ALS_N0: length 5
  TOP w0.102: 30.72,66.12 31.72,67.12 31.72,67.71 C5731.2 ; 30.72,66.12 29.49,64.88 29.49,64.6 U5701.A7 ; 30.72,66.12 v1(30.61,66.24)
HDMI_DDI_TX_ALS_N1: length 6.7
  TOP w0.102: 29.33,66.07 30.15,66.89 30.15,69.29 C5734.2 ; 29.33,66.07 v1(29.24,66.16) ; 29.33,66.07 28.81,65.55 28.37,65.55 27.91,65.09 27.91,64.59 27.62,64.29 U5701.A5
HDMI_DDI_TX_ALS_N2: length 5.5
  TOP w0.102: 28.61,67.04 v1(28.5,67.15) ; 28.61,67.04 28.91,67.33 28.91,67.74 C5727.2 ; 28.61,67.04 28.35,66.77 27.69,66.77 26.31,65.4 26.31,64.62 U5701.A3
HDMI_DDI_TX_ALS_N3: length 6.8
  TOP w0.102: U5701.A1 24.66,64.57 24.66,64.78 27.18,67.3 27.18,67.48 ; 27.18,67.48 v1(27.03,67.48) ; 27.18,67.48 27.18,68.52 27.69,69.03 27.69,69.21 C5733.2
HDMI_DDI_TX_ALS_P0: length 5
  TOP w0.102: 31.66,66.73 29.72,64.79 29.72,64.55 U5701.A8 ; 31.66,66.73 31.95,67.02 31.95,67.66 C5737.2 ; 31.66,66.73 v1(31.78,66.62)
HDMI_DDI_TX_ALS_P1: length 6.8
  TOP w0.102: 30.38,67.63 30.38,69.13 C5732.2 ; 30.38,67.63 30.38,66.79 28.91,65.32 28.47,65.32 28.14,65 28.14,64.52 U5701.A6 ; 30.38,67.63 v1(30.56,67.63)
HDMI_DDI_TX_ALS_P2: length 5.5
  TOP w0.102: 27.57,66.33 27.78,66.54 28.44,66.54 29.13,67.23 29.13,67.63 C5728.2 ; 27.57,66.33 26.54,65.3 26.54,64.53 26.54,64.52 U5701.A4 ; 27.57,66.33 v1(27.69,66.21)
HDMI_DDI_TX_ALS_P3: length 6.8
  TOP w0.102: 27.66,68.68 v1(27.77,68.56) ; 27.66,68.68 27.91,68.94 27.91,69.21 C5735.2 ; 27.66,68.68 27.41,68.43 27.41,67.2 24.89,64.69 24.89,64.57 U5701.A2
HDMI_DDI_TX_CMC_N0: length 15.6
  TOP w0.076: 25.93,56.66 25.48,56.2 22.96,56.2 22.01,57.15 22.01,64.03 21.73,64.31 21.33,64.31 21.09,64.56 20.86,64.56 R5770.1 ; 25.93,56.66 v1(25.83,56.76) ; 25.93,56.66 26.4,57.13 26.4,58.55 26.27,58.69 U5701.H3
HDMI_DDI_TX_CMC_N1: length 16.1
  TOP w0.076: 27.09,56.11 v1(26.97,56.23) ; 27.09,56.11 27.93,56.95 27.93,58.53 27.99,58.59 27.99,58.87 27.91,58.95 27.71,58.95 27.58,58.81 U5701.H5 ; 27.09,56.11 26.29,55.31 22.35,55.31 21.32,56.35 21.32,59.8 20.42,60.7 20.42,61.28 R5768.1
HDMI_DDI_TX_CMC_N2: length 7.5
  TOP w0.076: R5766.1 25.81,54.27 26.65,54.27 28.59,56.22 ; 28.59,56.22 v1(28.47,56.33) ; 28.59,56.22 29.57,57.19 29.57,58.76 29.49,58.84 29.33,58.84 U5701.H7
HDMI_DDI_TX_CMC_N3: length 14.6
  TOP w0.076: U5701.H1 24.43,58.74 24.71,58.74 24.84,58.62 24.84,57.63 C5724.2 24.74,57.32 24.74,57.19 24.44,56.89 23.27,56.89 22.69,57.46 22.69,64.95 22.05,65.6 ; v1(22.15,65.7) 22.05,65.6 ; 22.05,65.6 21.69,65.96 20.98,65.96 R5772.1
HDMI_DDI_TX_CMC_P0: length 15.7
  TOP w0.076: v1(24.46,55.75) 24.46,55.9 ; 24.46,55.9 22.83,55.9 21.7,57.03 21.7,63.91 21.61,64 20.86,64 R5769.1 ; 24.46,55.9 25.6,55.9 26.71,57 26.71,58.62 U5701.H4
HDMI_DDI_TX_CMC_P1: length 16.3
  TOP w0.076: 26.56,55.15 26.42,55.01 22.23,55.01 21.01,56.22 21.01,59.68 20.12,60.57 20.12,61.38 R5767.1 ; 26.56,55.15 28.23,56.83 28.23,58.4 28.38,58.55 U5701.H6 ; 26.56,55.15 v1(26.67,55.03)
HDMI_DDI_TX_CMC_P2: length 7.5
  TOP w0.076: 29.58,56.77 26.77,53.97 25.81,53.97 R5765.1 ; 29.58,56.77 29.87,57.07 29.87,58.58 U5701.H8 ; 29.58,56.77 v1(29.69,56.66)
HDMI_DDI_TX_CMC_P3: length 14.6
  TOP w0.076: 22.39,64.46 22.39,64.83 21.56,65.65 20.98,65.65 R5771.1 ; 22.39,64.46 22.39,57.33 23.14,56.58 24.56,56.58 25.04,57.07 25.04,57.27 C5724.1 25.15,57.47 25.15,58.65 U5701.H2 ; 22.39,64.46 v1(22.25,64.46)
HDMI_DDI_TX_CON_N0: length 19.2
  TOP w0.076: R5770.2 19.66,64.43 18.62,64.43 ; v1(18.62,64.58) 18.62,64.43 ; 18.62,64.43 18.14,64.43 18.05,64.52 ED5702.2 ED5702.9 16.47,64.52 16.38,64.43 16.13,64.43 15.88,64.18 15.88,63.05 14.2,61.37 14.2,60.14 14.1,60.04 13.89,60.04 v2(13.72,60.22)
  L6 w0.076: HDMI1.9 10.72,60.63 10.88,60.63 11.24,60.27 11.24,59.65 11.23,59.64 11.23,59.36 11.24,59.35 11.24,58.65 11.23,58.64 11.23,58.36 11.24,58.35 11.24,57.75 11.22,57.73 11.22,57.27 11.59,56.9 12.24,56.9 12.76,57.43 12.76,59.44 13.27,59.95 13.45,59.95 v2(13.72,60.22)
HDMI_DDI_TX_CON_N1: length 16.6
  TOP w0.076: v1(18.9,62.76) 19.05,62.76 ; 19.05,62.76 19.05,62.88 19.61,63.44 20.17,63.44 20.47,63.14 20.47,62.66 R5768.2 ; 19.05,62.76 19.05,62.3 18.77,62.02 18.14,62.02 18.05,62.11 ED5701.10 ED5701.1 16.49,62.11 16.41,62.02 15.92,62.02 14.96,61.06 14.96,57.94 14.82,57.8 14.53,57.8 14.45,57.88 14.45,58.13 14.2,58.39 13.64,58.39 13.39,58.13 13.39,57.8 13.31,57.73 13.06,57.73 12.98,57.8 12.98,59.1 12.72,59.36 11.99,59.36 HDMI1.6
HDMI_DDI_TX_CON_N2: length 22.7
  TOP w0.076: R5766.2 24.49,54.27 22.25,54.27 20.5,56.02 20.5,59.45 19.6,60.36 ; v1(19.71,60.47) 19.6,60.36 ; 19.6,60.36 19.45,60.5 18.14,60.5 18.05,60.58 ED5701.7 ED5701.4 16.45,60.58 16.38,60.52 16.08,60.52 15.72,60.16 15.72,57.62 15.03,56.93 11.56,56.93 10.49,58 HDMI1.3
HDMI_DDI_TX_CON_N3: length 15.4
  TOP w0.076: R5772.2 19.66,65.96 18.57,65.96 ; 18.57,65.96 v1(18.57,66.11) ; 18.57,65.96 17.88,65.96 17.8,66.04 ED5702.5 ED5702.6 16.24,66.04 16.15,65.95 15.77,65.95 15.47,66.26 15.47,66.72 15.17,67.02 14.63,67.02 14.35,66.74 14.35,65.48 14.76,65.07 15.09,65.07 15.16,64.99 15.16,64.57 15.08,64.48 14.63,64.48 14.38,64.23 14.38,63.59 14.68,63.29 14.68,62.94 13.44,61.69 13.01,61.69 12.55,62.15 12.2,62.15 HDMI1.12
HDMI_DDI_TX_CON_P0: length 19.2
  TOP w0.076: 16.18,63.19 16.18,64.05 16.26,64.13 16.41,64.13 16.49,64.04 ED5702.10 ED5702.1 18.05,64.04 18.14,64.13 19.66,64.13 R5769.2 ; 16.18,63.19 v1(16.33,63.19) ; 16.18,63.19 16.18,62.92 14.5,61.25 14.5,60.01 14.22,59.73 13.87,59.73 v2(13.72,59.58)
  L6 w0.076: v2(13.72,59.58) 13.61,59.68 13.38,59.68 13.03,59.33 13.03,57.32 12.35,56.64 11.48,56.64 10.96,57.16 10.96,57.84 10.97,57.86 10.97,58.24 10.96,58.25 10.96,58.75 10.97,58.76 10.97,59.24 10.96,59.25 10.96,59.75 10.97,59.76 10.97,60.16 10.77,60.37 10.56,60.37 10.35,60.15 HDMI1.7
HDMI_DDI_TX_CON_P1: length 16.4
  TOP w0.076: 18.62,61.71 18.14,61.71 18.05,61.63 ED5701.9 ED5701.2 16.5,61.63 16.41,61.71 16.05,61.71 15.27,60.93 15.27,57.81 14.95,57.5 14.4,57.5 14.15,57.75 14.15,58.01 14.07,58.08 13.77,58.08 13.69,58.01 13.69,57.68 13.44,57.42 12.93,57.42 12.67,57.68 12.67,58.97 12.6,59.05 12.3,59.05 11.85,58.6 HDMI1.4 ; 18.62,61.71 v1(18.62,61.56) ; 18.62,61.71 18.9,61.71 19.35,62.17 19.35,62.76 19.74,63.14 20.04,63.14 20.17,63.01 20.17,62.65 R5767.2
HDMI_DDI_TX_CON_P2: length 23.5
  TOP w0.076: v1(24.38,52.86) R5765.2 24.49,53.97 22.12,53.97 20.19,55.9 20.19,59.33 19.33,60.19 18.14,60.19 18.05,60.11 ED5701.6 ED5701.5 16.44,60.11 16.33,60.22 16.21,60.22 16.03,60.04 16.03,57.5 15.15,56.62 11.44,56.62 10.76,57.3 10.65,57.3 HDMI1.1
HDMI_DDI_TX_CON_P3: length 15.3
  TOP w0.076: HDMI1.10 12.2,61.85 12.42,61.85 12.88,61.38 13.56,61.38 14.99,62.81 14.99,63.42 14.68,63.72 14.68,64.1 14.76,64.18 15.2,64.18 15.47,64.44 15.47,65.12 15.21,65.37 14.88,65.37 14.66,65.6 14.66,66.62 14.76,66.72 15.04,66.72 15.16,66.59 15.16,66.13 15.65,65.65 16.15,65.65 16.24,65.56 ED5702.7 ED5702.4 17.79,65.56 17.88,65.65 19.66,65.65 R5771.2
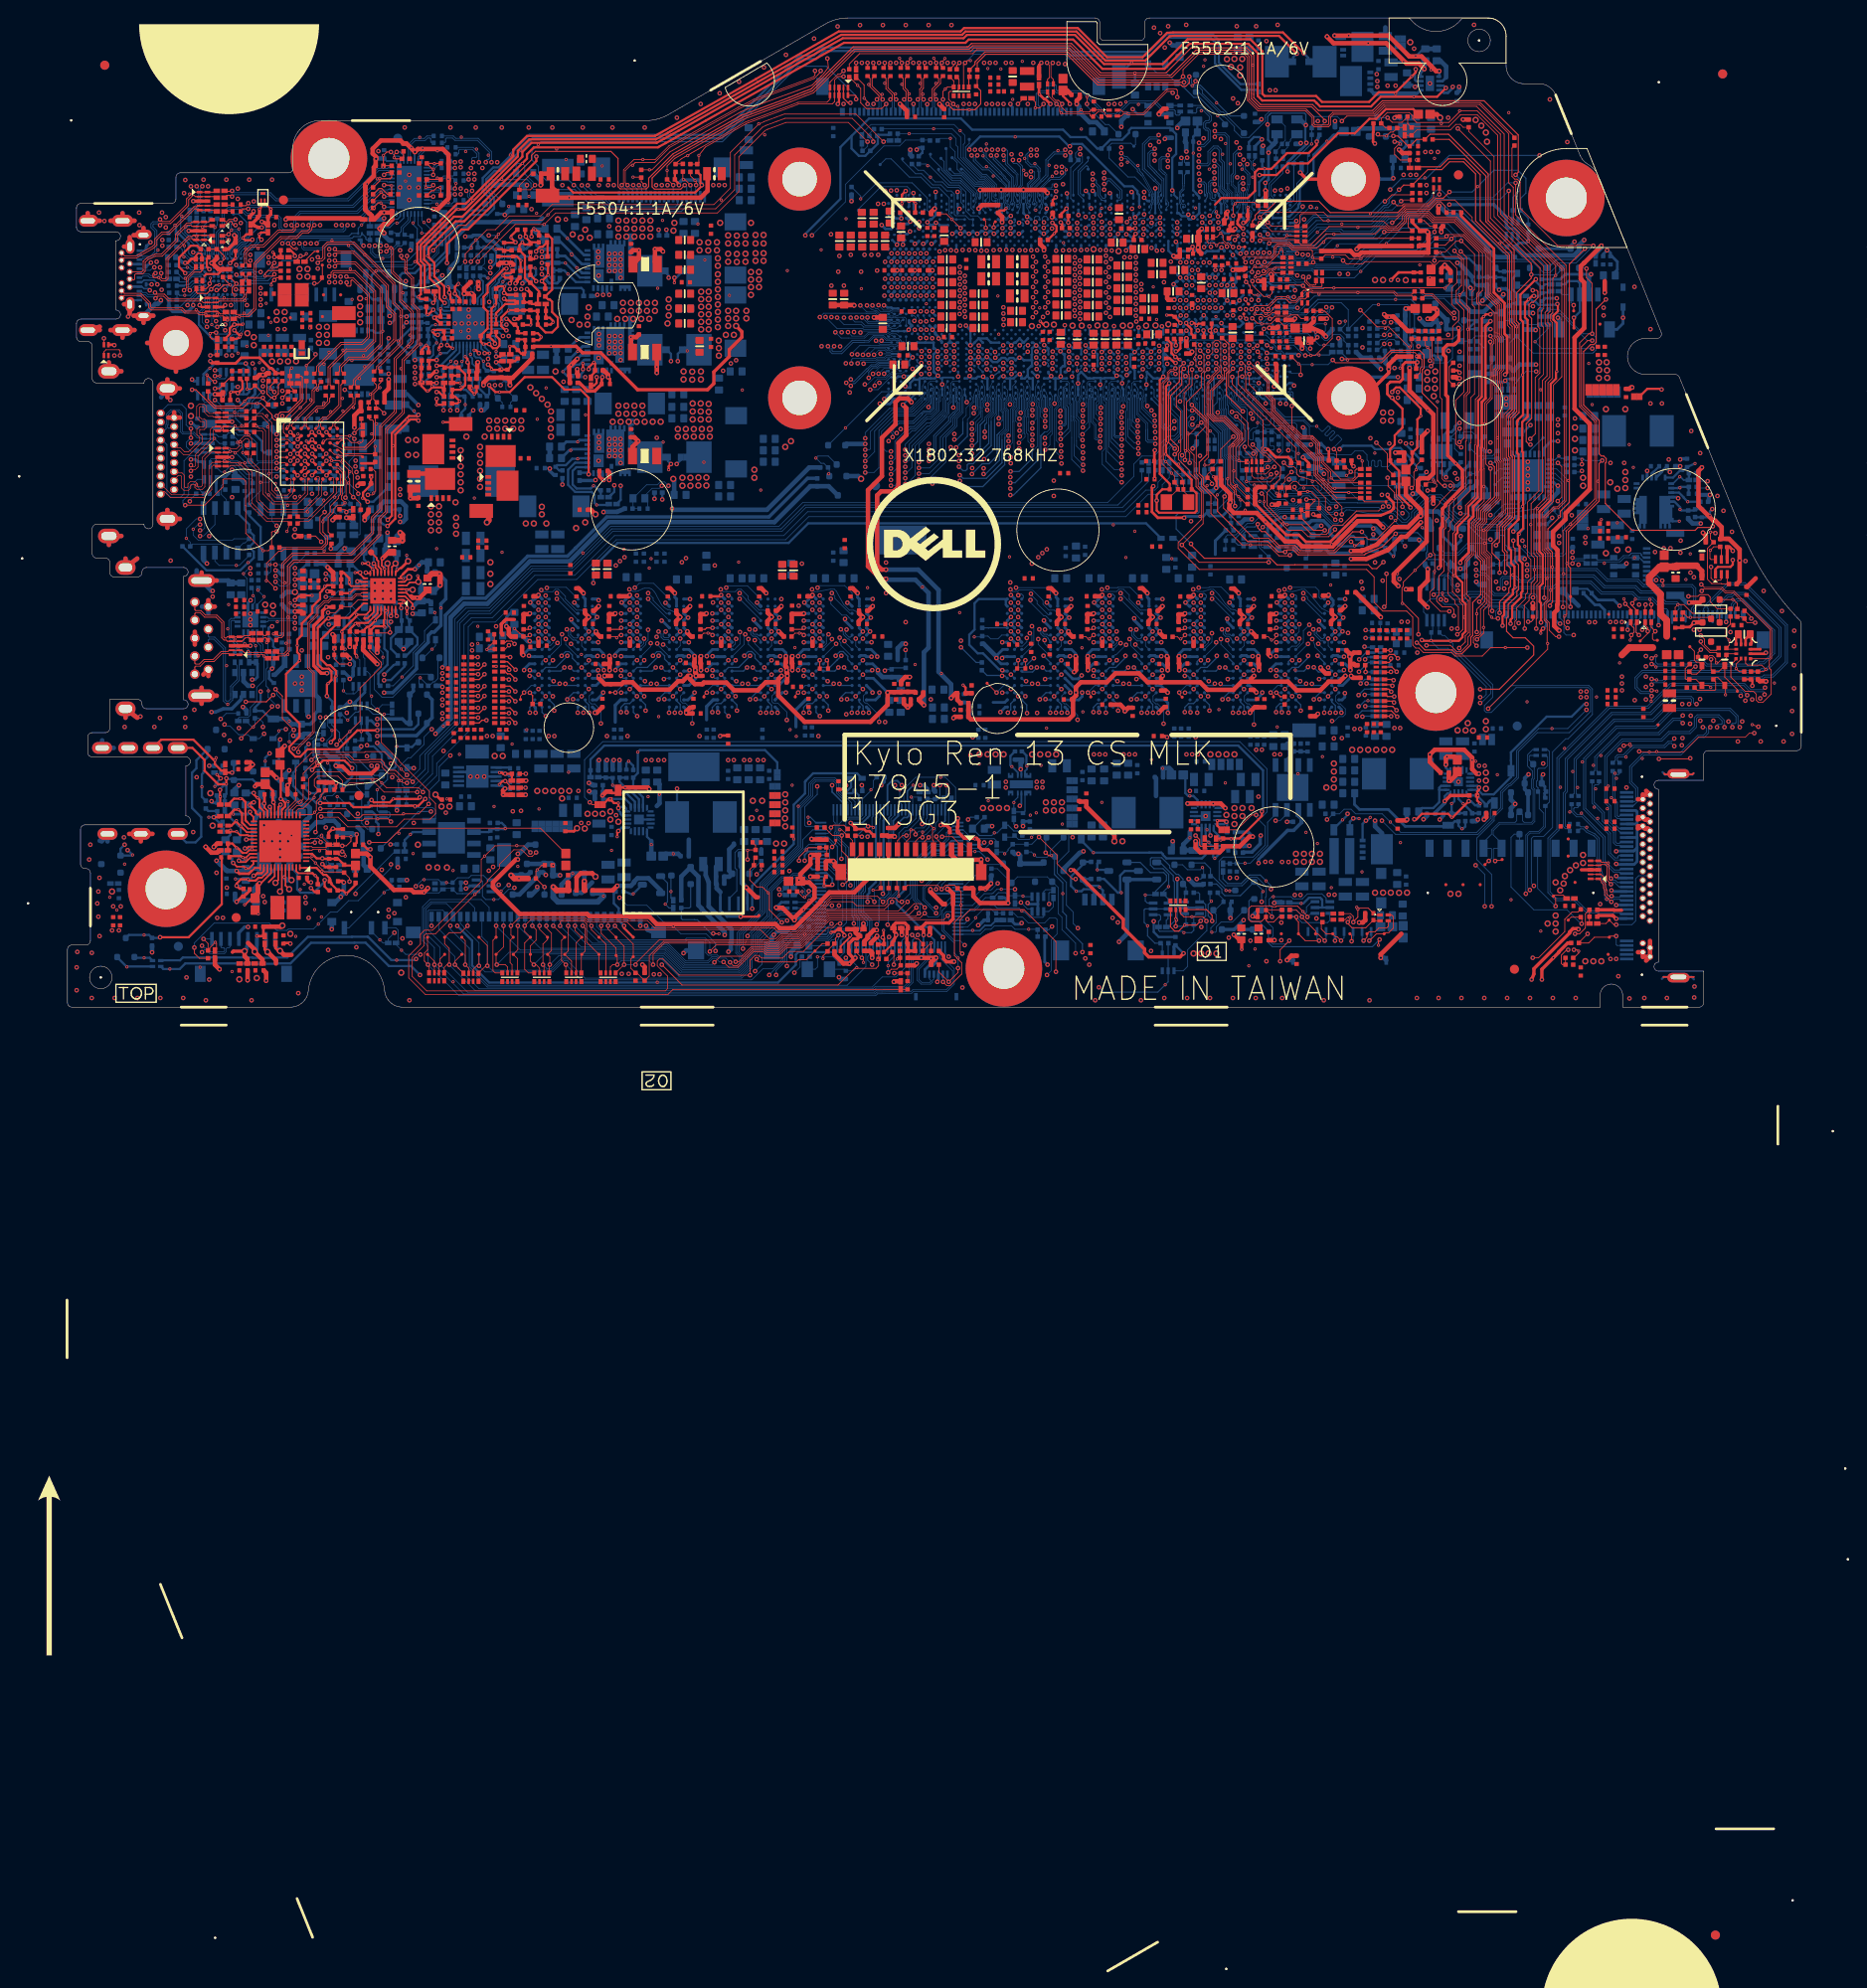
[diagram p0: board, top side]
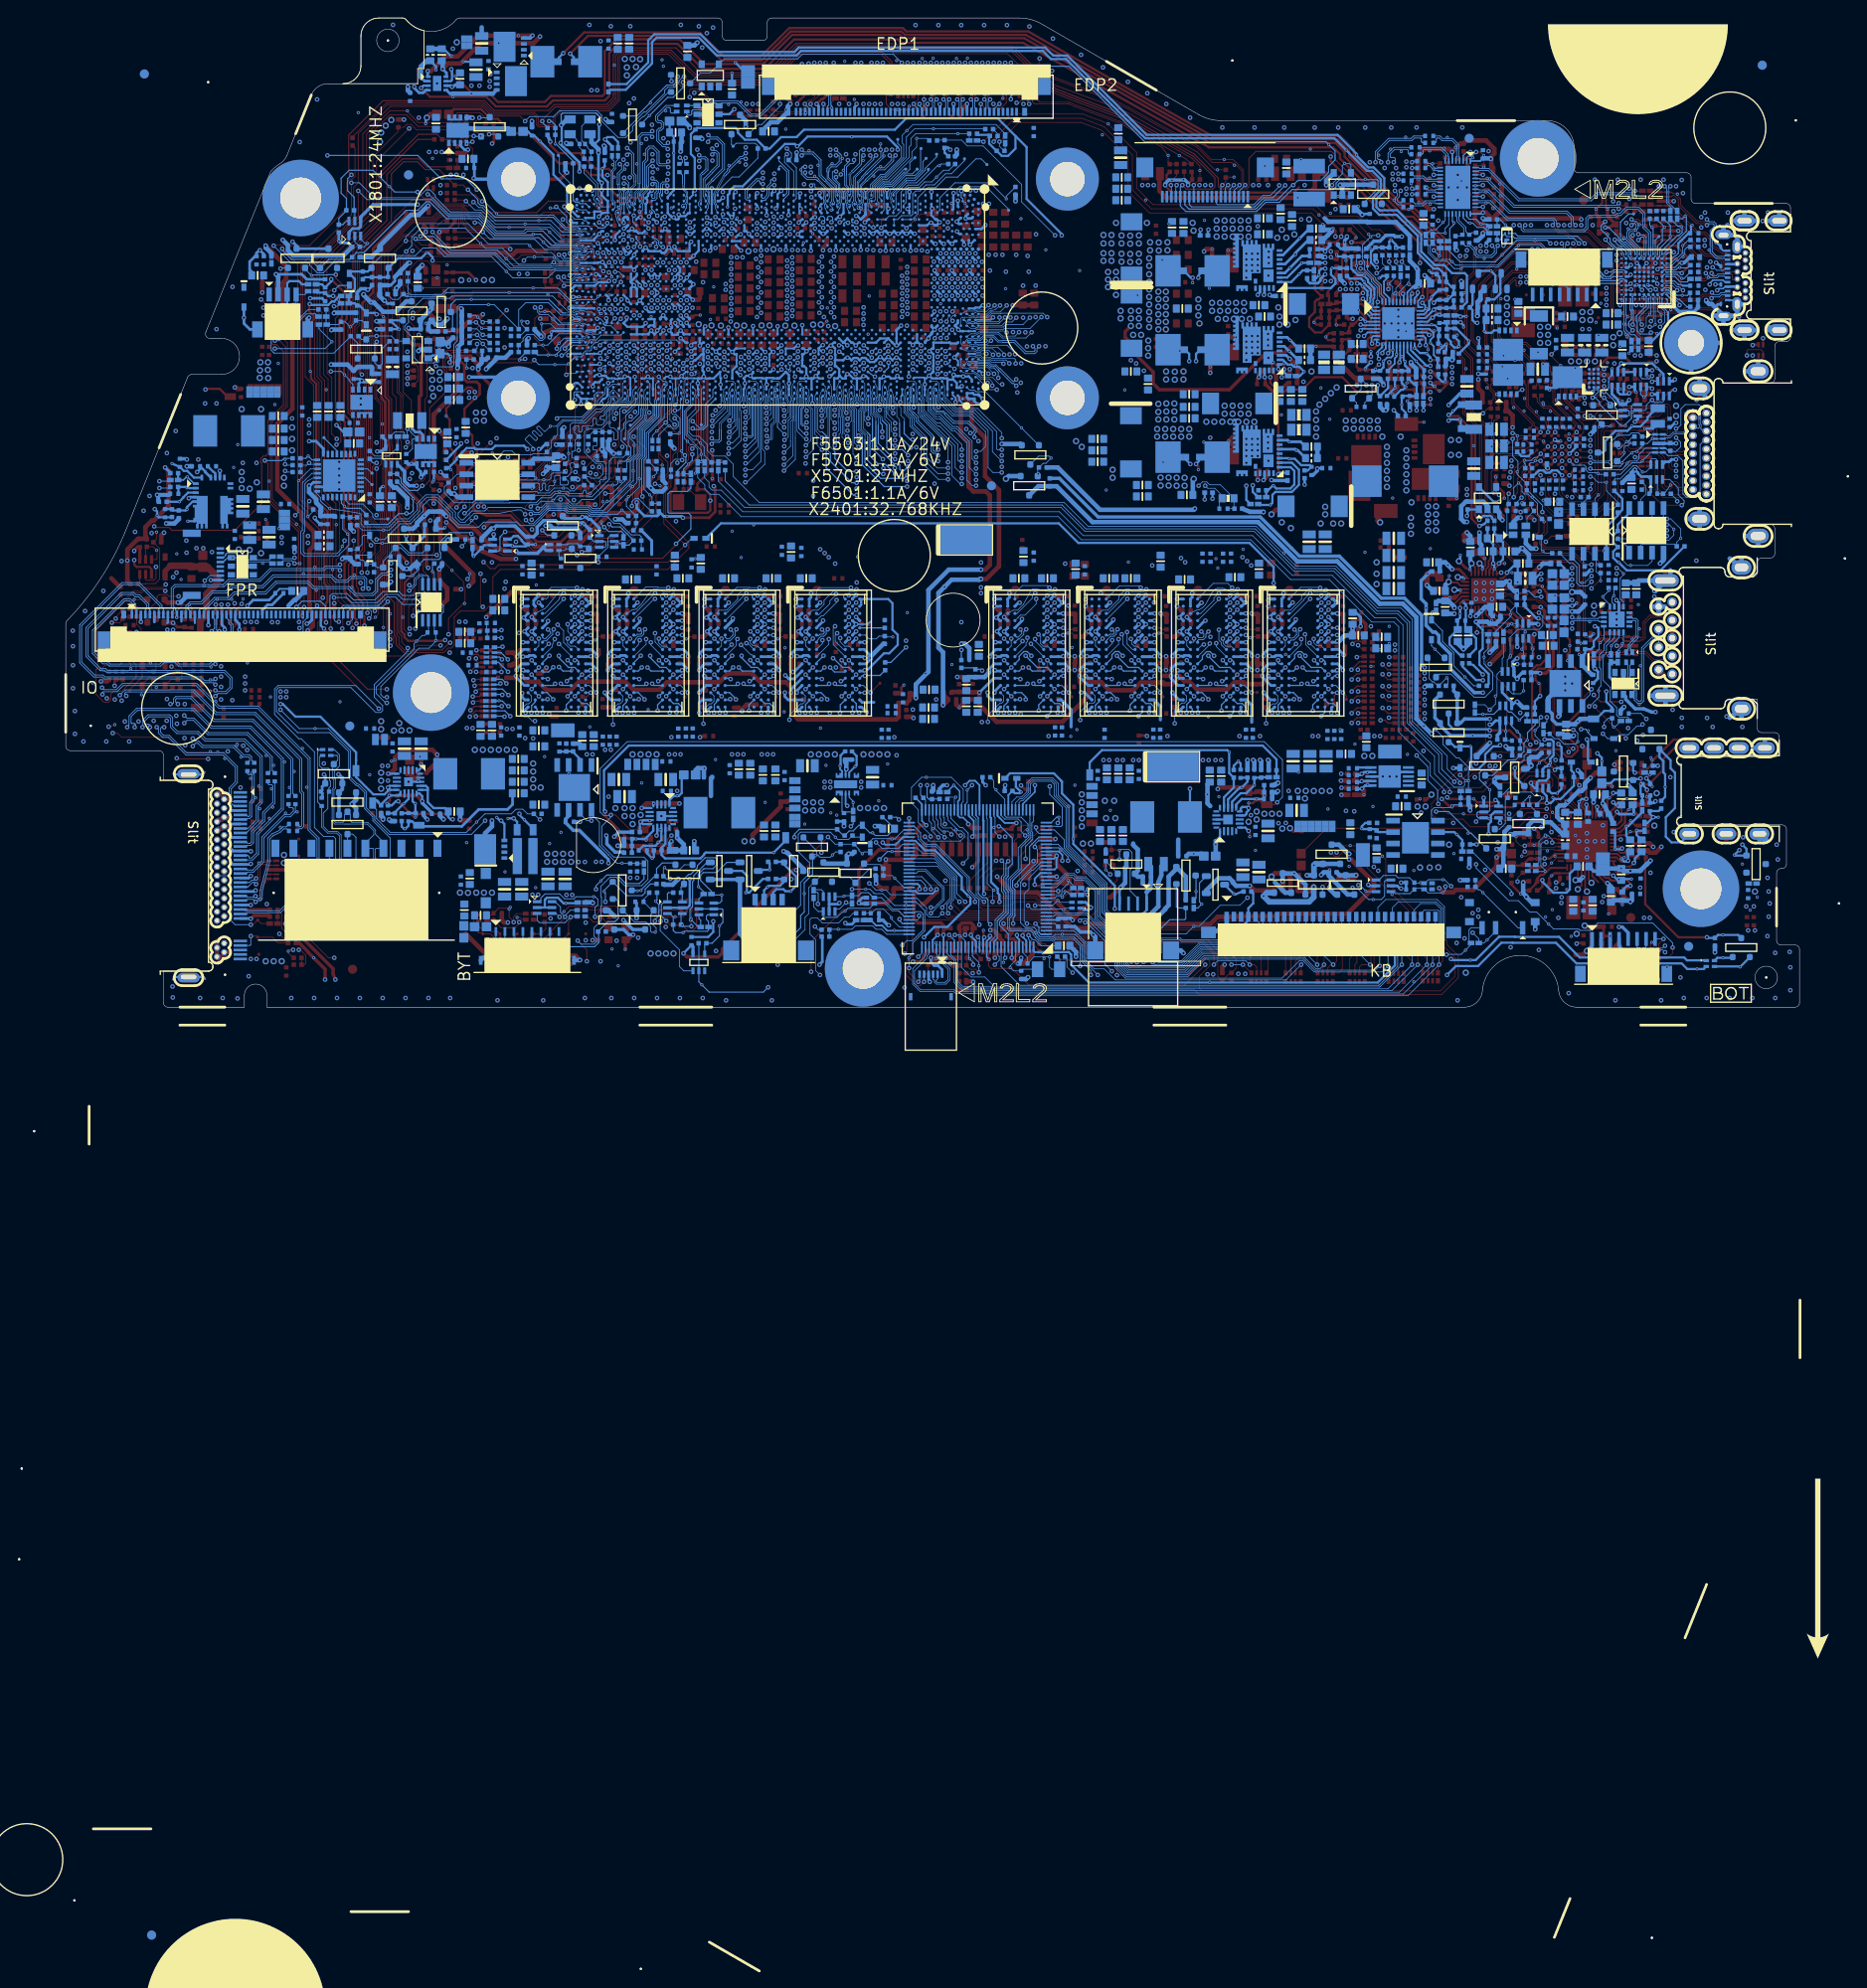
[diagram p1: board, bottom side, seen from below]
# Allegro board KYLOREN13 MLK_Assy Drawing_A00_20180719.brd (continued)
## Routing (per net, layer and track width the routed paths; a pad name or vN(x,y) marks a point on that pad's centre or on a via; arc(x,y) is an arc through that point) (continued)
HDMI_DDI_TX_N0: length 112.3
  TOP w0.102: 33.12,71.06 36.25,74.18 36.25,76.96 35.43,77.77 35.43,80.08 31.75,83.76 29.9,83.76 v2(29.72,83.58) ; 33.12,71.06 31.75,69.68 31.75,69.13 C5731.1 ; 33.12,71.06 v1(33.02,71.16)
  L6 w0.089: v2(108.5,87.2) 108.32,87.2 108.23,87.29 108.23,87.55 108.33,87.65 108.64,87.65 108.72,87.74 108.72,87.86 107.44,89.15 106.93,89.15 104.16,91.92 99.32,91.92 96.99,94.25 85.26,94.25 83.03,96.48 78.99,96.48 76.25,93.74 53.34,93.74 52.71,93.11 49.25,93.11 44.8,88.66 41.51,88.66 40.9,88.05 39.94,88.05 36.33,84.44 36.33,83.99 35.68,83.33 33.78,83.33 33.39,83.72 29.86,83.72 v2(29.72,83.58)
  BOTTOM w0.102: v2(108.5,87.2) 108.31,87.4 108.31,87.67 108.48,87.85 108.76,87.85 108.93,87.68 CPU1.AL5
HDMI_DDI_TX_N1: length 109.4
  TOP w0.102: C5734.1 30.23,70.66 30.23,71.2 31.26,72.23 32.89,72.23 ; 32.89,72.23 33.28,72.23 34.72,73.67 34.72,79.77 31.93,82.57 29.97,82.57 v2(29.72,82.31) ; 32.89,72.23 v1(32.89,72.38)
  L6 w0.089: v2(29.72,82.31) 29.93,82.53 38.01,82.53 38.84,83.36 38.84,84.9 41.94,88 45.1,88 49.52,92.43 52.97,92.43 53.62,93.08 76.56,93.08 79.22,95.75 82.83,95.75 84.99,93.59 96.59,93.59 98.92,91.25 104.06,91.25 106.84,88.48 107.1,88.48 107.29,88.29 107.68,87.9 107.68,87.76 107.59,87.67 107.3,87.67 107.21,87.58 107.21,87.31 107.3,87.22 v2(107.56,87.22)
  BOTTOM w0.102: v2(107.56,87.22) 107.44,87.34 107.44,87.72 107.57,87.85 107.91,87.85 108.01,87.75 CPU1.AJ5
HDMI_DDI_TX_N2: length 109.8
  TOP w0.102: C5727.1 28.96,69.13 28.96,71.11 30.72,72.87 ; v2(29.72,81.17) 29.51,81.37 29.51,81.53 29.59,81.6 31.88,81.6 34.01,79.47 34.01,74.08 33.05,73.12 30.97,73.12 30.72,72.87 ; 30.72,72.87 v1(30.61,72.99)
  L6 w0.089: v2(105.73,87.15) 105.73,86.87 105.89,86.71 106.11,86.71 106.22,86.82 106.22,87.35 106,87.58 106,88.47 104.59,89.88 98.64,89.88 95.71,92.81 84.76,92.81 82.49,95.09 79.57,95.09 76.91,92.42 53.81,92.42 53.19,91.8 49.83,91.8 45.34,87.32 42.19,87.32 39.5,84.63 39.5,83.08 38.28,81.86 30.55,81.86 30.33,81.64 29.55,81.64 29.46,81.55 29.46,81.37 29.67,81.17 v2(29.72,81.17)
  BOTTOM w0.102: CPU1.AF6 106.2,86.91 106.2,87.06 106.02,87.24 105.82,87.24 v2(105.73,87.15)
HDMI_DDI_TX_N3: length 108.5
  TOP w0.102: 29.16,72.66 30.35,73.86 32.67,73.86 33.3,74.48 33.3,79.16 31.68,80.79 31.57,80.79 31.5,80.71 31.5,80.21 31.39,80.1 31.11,80.1 31.01,80.21 v2(31.01,80.51) ; 29.16,72.66 27.69,71.19 27.69,70.66 C5733.1 ; 29.16,72.66 v1(29.06,72.76)
  L6 w0.089: v2(104.79,87.22) 104.95,87.22 105.23,87.51 105.23,88.45 104.46,89.22 104.03,89.22 103.94,89.13 103.94,88.13 103.74,87.93 103.16,87.93 102.96,88.13 102.96,88.93 102.67,89.22 98.61,89.22 95.81,92.01 84.62,92.01 82.21,94.42 79.93,94.42 77.27,91.76 53.98,91.76 52.41,90.2 49.16,90.2 45.62,86.66 42.49,86.66 41.62,85.78 41.62,85.66 41.92,85.35 41.92,85.07 41.52,84.66 41.23,84.66 40.93,84.97 40.8,84.97 40.16,84.33 40.16,82.52 38.82,81.17 36.92,81.17 36.83,81.08 36.83,80.76 36.63,80.56 36.05,80.56 35.85,80.76 35.85,81.08 35.76,81.17 35.34,81.17 35.25,81.08 35.25,80.76 35.05,80.56 34.48,80.56 34.28,80.76 34.28,81.08 34.19,81.17 33.77,81.17 33.68,81.08 33.68,80.76 33.48,80.56 32.9,80.56 32.7,80.76 32.7,81.08 32.61,81.17 32.22,81.17 31.95,80.9 31.43,80.9 31.34,80.82 31.34,80.68 31.25,80.59 31.09,80.59 v2(31.01,80.51)
  BOTTOM w0.102: CPU1.AE5 105.31,87.44 105.31,87.27 105.21,87.17 104.85,87.17 v2(104.79,87.22)
HDMI_DDI_TX_P0: length 112.3
  TOP w0.102: 32.33,69.94 36.47,74.08 36.47,77.06 35.66,77.87 35.66,80.17 31.84,83.99 29.95,83.99 v2(29.72,84.22) ; 32.33,69.94 31.98,69.59 31.98,69.13 C5737.1 ; 32.33,69.94 v1(32.44,69.84)
  L6 w0.089: v2(29.72,84.22) 30.02,83.91 33.47,83.91 33.86,83.52 35.6,83.52 36.14,84.07 36.14,84.52 39.86,88.24 40.82,88.24 41.43,88.85 44.72,88.85 49.17,93.3 52.63,93.3 53.26,93.93 76.17,93.93 78.91,96.67 83.11,96.67 85.34,94.44 97.07,94.44 99.4,92.11 104.24,92.11 107.01,89.34 107.52,89.34 108.92,87.94 108.92,87.03 v2(108.48,86.59)
  BOTTOM w0.102: CPU1.AL6 v2(108.48,86.59)
HDMI_DDI_TX_P1: length 109.5
  TOP w0.102: 31.6,72 v1(31.6,71.85) ; 31.6,72 31.36,72 30.45,71.1 30.45,70.66 C5732.1 ; 31.6,72 33.38,72 34.95,73.58 34.95,79.87 32.02,82.8 29.87,82.8 v2(29.72,82.95)
  L6 w0.089: v2(107.54,86.54) 107.98,86.98 107.98,87.39 107.87,87.5 107.87,87.98 107.18,88.67 106.91,88.67 104.14,91.44 99,91.44 96.67,93.78 85.07,93.78 82.91,95.94 79.14,95.94 76.48,93.27 53.54,93.27 52.89,92.62 49.44,92.62 45.02,88.19 41.86,88.19 38.65,84.98 38.65,83.43 37.93,82.72 29.95,82.72 v2(29.72,82.95)
  BOTTOM w0.102: CPU1.AJ6 v2(107.54,86.54)
HDMI_DDI_TX_P2: length 109.8
  TOP w0.102: 31.42,81.83 31.97,81.83 34.24,79.56 34.24,73.98 33.15,72.89 31.06,72.89 29.18,71.01 29.18,69.13 C5728.1 ; 31.42,81.83 29.5,81.83 29.29,81.62 29.29,81.37 v2(29.08,81.17) ; 31.42,81.83 v1(31.42,82.01)
  L6 w0.089: v2(106.65,87.2) 106.19,87.66 106.19,88.54 104.67,90.07 98.72,90.07 95.79,93 84.84,93 82.57,95.28 79.49,95.28 76.83,92.61 53.73,92.61 53.11,91.99 49.75,91.99 45.27,87.51 42.11,87.51 39.31,84.71 39.31,83.16 38.2,82.05 30.47,82.05 30.25,81.83 29.47,81.83 29.27,81.63 29.27,81.36 v2(29.08,81.17)
  BOTTOM w0.102: CPU1.AF5 106.48,87.2 v2(106.65,87.2)
HDMI_DDI_TX_P3: length 108.5
  TOP w0.102: C5735.1 27.91,70.66 27.91,71.1 28.38,71.56 ; 28.38,71.56 30.44,73.63 32.77,73.63 33.53,74.39 33.53,79.26 31.77,81.02 31.14,81.02 v2(30.99,81.17) ; 28.38,71.56 v1(28.5,71.44)
  L6 w0.089: v2(30.99,81.17) 31.07,81.09 31.87,81.09 32.14,81.36 32.69,81.36 32.89,81.16 32.89,80.83 32.98,80.75 33.4,80.75 33.49,80.83 33.49,81.16 33.69,81.36 34.27,81.36 34.47,81.16 34.47,80.83 34.56,80.75 34.98,80.75 35.06,80.83 35.06,81.16 35.26,81.36 35.84,81.36 36.04,81.16 36.04,80.83 36.13,80.75 36.55,80.75 36.64,80.83 36.64,81.16 36.84,81.36 38.74,81.36 39.97,82.59 39.97,84.41 40.72,85.16 41.01,85.16 41.31,84.85 41.44,84.85 41.73,85.15 41.73,85.27 41.43,85.58 41.43,85.86 42.41,86.85 45.54,86.85 49.08,90.39 52.33,90.39 53.9,91.95 77.19,91.95 79.85,94.62 82.29,94.62 84.7,92.2 95.89,92.2 98.69,89.41 102.75,89.41 103.15,89 103.15,88.21 103.24,88.12 103.66,88.12 103.75,88.21 103.75,89.21 103.95,89.41 104.54,89.41 105.42,88.53 105.42,87.43 105.31,87.32 105.31,87.08 v2(104.79,86.56)
  BOTTOM w0.102: v2(104.79,86.56) CPU1.AE6
HDMI_HPD_ALS: length 7.3
  TOP w0.102: U5701.B1 24,63.87 24,64.73 v1(25.87,66.6) 26.54,67.28 R5760.2
HDMI_HPD_CON: length 30.2
  TOP w0.102: v2(23.24,59.84) 24.03,59.84 U5701.G1 ; v2(13.72,64.28) v2(13.72,63.26)
  L6 w0.102: v2(13.72,63.26) 13.97,63.26 14.35,62.88 14.35,56.97 v2(13.59,56.2)
  BOTTOM w0.102: v2(13.72,64.28) 13.59,64.28 13.18,64.69 13.18,66.46 12.7,66.95 11.18,66.95 10.35,66.12 HDMI1.19 ; R5749.1 13.59,56.33 v2(13.59,56.2) ; v2(13.72,63.26) 13.21,62.76 13.21,62.25 13.72,61.74 14.27,61.74 R5764.1 14.55,61.82 14.85,62.11 ED5703.7 ED5703.4 17.13,62.11 17.41,61.82 17.42,61.82 17.86,61.38 17.86,60.93 18.11,60.67 18.9,60.67 v1(19.14,60.43) 19.3,60.27 19.3,60.19 19.35,60.14 19.35,60.09 19.74,59.71 23.11,59.71 v2(23.24,59.84)
HDMI_HPD_CPU: length 154.2
  TOP w0.102: R5760.1 v1(26.54,71.29) 27.56,72.31 v2(27.56,72.54)
  L4SGND w0.102: v2(137.25,88.95) 136.56,89.65 136.56,93.23 133.4,96.39 133.4,96.7 130.78,99.31 130.78,100.35 125.97,105.16 112.38,105.16 111.3,106.24 86.91,106.24 83.94,103.26 77.06,103.26 70.87,97.07 33.85,97.07 32.13,95.34 32.13,92.09 28.83,88.79 28.83,86.38 30.86,84.35 30.86,82.06 31.52,81.4 31.52,80.3 29.77,78.55 29.77,73.75 28.55,72.54 v2(27.56,72.54)
  BOTTOM w0.102: v2(27.56,72.54) 27.05,73.04 R5702.1 ; CPU1.CN6 134.83,87.38 135.06,87.38 135.23,87.55 136.1,87.55 137.25,88.7 v2(137.25,88.95)
HDMI_SCL_CON: length 21.3
  TOP w0.089: U5701.E1 23.26,61.09 v2(23.24,61.11)
  BOTTOM w0.089: v2(23.24,61.11) 22.8,60.66 21.17,60.66 21.08,60.75 21.08,62.65 v1(20.14,63.59) 20.09,63.54 18.93,63.54 18.68,63.79 17.88,63.79 R5755.2 16.76,63.39 16.53,63.63 ED5703.1 ED5703.10 14.84,63.63 14.67,63.45 14.47,63.45 14.06,63.87 12.88,63.87 12.76,63.98 12.76,66.01 12.4,66.38 11.48,66.38 10.99,65.88 10.99,64.77 10.93,64.71 10.93,64.45 10.98,64.3 10.92,64.19 HDMI1.15
HDMI_SCL_R: length 3
  BOTTOM w0.089: D5701.2 20.27,62.12 20.15,62 20.02,62 v1(19.2,62.82) 19.16,62.86 19.05,62.86 18.52,63.39 R5755.1
HDMI_SDA_CON: length 19.8
  TOP w0.089: v2(23.24,60.47) 24.19,60.47 U5701.F1
  BOTTOM w0.089: HDMI1.16 11.27,64.31 11.16,64.36 11.12,64.48 11.12,64.63 11.18,64.69 11.18,65.8 11.56,66.19 12.32,66.19 12.57,65.93 12.57,63.9 12.8,63.68 13.98,63.68 14.39,63.26 14.86,63.26 14.97,63.15 ED5703.9 ED5703.2 16.37,63.15 16.89,62.63 R5751.2 17.48,62.32 17.58,62.22 17.6,62.22 v1(18.08,61.74) 18.54,61.74 19.75,60.53 19.75,60.26 19.9,60.11 20.85,60.11 21.21,60.47 v2(23.24,60.47)
HDMI_SDA_R: length 3.2
  BOTTOM w0.089: D5701.1 20.23,60.66 19.48,61.41 v1(19.48,61.61) 19.48,62.27 19.38,62.37 19.06,62.37 18.8,62.63 R5751.1
HOST_DEBUG_TX: length 23
  TOP w0.102: v2(97.28,2.81) 97.69,2.41 98.09,2.41 99.36,3.68 99.36,4.93 98.55,5.73 98.55,9.43 99.29,10.17 v1(99.29,11.35) 99.29,12.82 R2480.2 98.55,13.55 97.58,13.55 v2(97.13,13.1) 96.7,13.53 93.32,13.53 R6801.1
  BOTTOM w0.102: U2401.81 97.64,14.09 97.13,13.58 v2(97.13,13.1) ; DB3.5 97.27,2.82 v2(97.28,2.81)
HOST_DEBUG_TX_CON: length 6.1
  TOP w0.102: DB1.11 90.23,16.04 92.15,14.11 R6801.2 92.35,13.02 v1(92.35,12.34)
HPDIN: length 2.9
  TOP w0.127: v2(35.18,90.06) 35.18,90.21 v1(34.82,90.57) 34.82,90.47 33.96,89.6 R7121.2
  BOTTOM w0.127: U7101.32 35.2,90.08 v2(35.18,90.06)
HVA_GATE1: length 6.6
  TOP w0.254: R7218.1 17.53,74.29 18.03,74.8 18.03,75.41 18.46,75.84 v2(18.54,75.84) 19.44,75.84 v1(19.49,75.9)
  BOTTOM w0.127: U7201.B9 18.53,78.93 18.53,78.22 18.58,78.17 18.58,77.55 18.46,77.43 18.46,75.92 v2(18.54,75.84)
HVA_GATE2: length 5.8
  TOP w0.254: R7219.1 18.74,74.24 19.08,74.38 v1(19.18,74.48) 19.18,74.57 v2(18.54,75.2)
  BOTTOM w0.127: U7201.A9 18.77,78.35 18.82,78.3 18.82,77.48 18.67,77.34 18.67,76.42 18.97,76.12 18.97,75.66 18.54,75.23 v2(18.54,75.2)
HW_ACAV_IN: length 95
  TOP w0.254: PG4408.2 29.26,41.93 29.25,41.93 28.19,40.87 28.19,38.63 28.83,37.99 29.2,37.99 29.85,37.34 v1(29.85,36.79) 29.72,36.67 29.72,29.89 v2(29.26,29.43)
  L4SGND w0.254: v2(43.31,9.04) 42.32,10.03 39.06,10.03 35.43,13.65 35.43,15.47 34.54,16.36 v2(34.54,19.24)
  L6 w0.254: v2(34.54,19.24) 34.54,21.52 33.27,22.79 33.27,24.15 29.26,28.16 v2(29.26,29.43)
  BOTTOM w0.203: U2401.128 85.11,6.26 84.96,6.11 84.58,6.11
  BOTTOM w0.254: PQ4415.5 33.91,21.68 34.29,21.3 34.29,20.59 34.54,20.34 v2(34.54,19.24) ; 84.58,6.11 81.2,6.11 80.93,5.84 80.93,5.36 80.93,5.35 80.93,4.7 78.96,2.73 46.86,2.73 44.96,4.63 44.96,7.38 v2(43.31,9.04)
HW_ACAVIN_NB: length 131.6
  TOP w0.254: v2(28.09,22.67) 31.32,22.67 31.78,22.22 33.53,22.22 33.68,22.37 v1(38.61,22.37) 38.99,22.37 v2(39.75,23.13)
  L4SGND w0.254: v2(81.92,16.27) 81.92,16.36 81.49,16.78 80.89,16.78 80.51,16.4 76.54,16.4 75.65,15.51 54.99,15.51 52.4,18.1 47.77,18.1 42.87,23.01 40.47,23.01 40.34,23.13 v2(39.75,23.13) 40.16,23.54 40.16,23.66 40.16,25.72 36.45,29.43 36.45,32.28 35.05,33.67 34.16,33.67 32.51,35.32 32.51,44.72 33.53,45.74 33.53,47.39 34.14,48 36.37,48 37.06,48.68 37.06,51.94 37.47,52.34 37.47,54.25 37.13,54.58 v2(36.96,54.58)
  L6 w0.254: v2(35.69,74.31) 36.45,73.55 36.45,55.14 36.96,54.64 v2(36.96,54.58)
  BOTTOM w0.203: v2(81.92,16.27) 81.92,16.91 82.3,17.29 U2401.24
  BOTTOM w0.254: v2(36.96,54.58) 36.88,54.66 R4378.2 35.65,55.3 U4302.1 ; R4311.2 35.61,74.24 v2(35.69,74.31) ; D4305.A 25.36,26.31 25.07,26.02 R4315.1 25.07,24.59 26.53,23.13 27.18,23.13 27.64,22.67 v2(28.09,22.67) 28.09,23.46 28.52,23.9 Q4349.2
I2C_CLK_PD: length 44
  TOP w0.089: v2(12.95,79.65) 13.21,79.9 13.21,81.04 14.27,82.1 RN7206.3
  L6 w0.089: v2(12.95,79.65) 13.18,79.87 13.18,80.19 12.45,80.92 12.45,83.22 13.71,84.49 19.44,84.49 19.81,84.85 23.26,84.85 23.88,84.23 25.65,84.23 25.96,84.54 25.96,84.67 v2(25.78,84.85)
  BOTTOM w0.089: v2(25.78,84.85) 26.04,84.59 26.04,84.34 26.24,84.14 28.27,84.14 28.78,84.64 31.09,84.64 33.49,82.24 37.41,82.24 v1(37.59,82.06) 38.35,82.06 39.18,82.89 40.34,82.89 41.24,83.78 41.24,84.64 R7114.2 ; U7201.D2 15.03,80.41 14,80.41 13.63,80.05 13.42,80.05 13.42,80.04 13.4,80.04 13,79.65 v2(12.95,79.65)
I2C_CLK_PD_MUX: length 3.6
  BOTTOM w0.089: R7114.1 40.95,86.37 40.42,86.37 39.62,87.18 v1(39.62,87.19) 39.6,87.19 39.37,87.42 U7101.21
I2C_DATA_PD: length 42.4
  TOP w0.089: RN7206.4 14.94,81.82 14.78,81.66 14.09,81.66 13.4,80.96 13.4,79.84 v2(13.59,79.65)
  L6 w0.089: v2(13.59,79.65) 13.37,79.87 13.37,80.27 12.64,81 12.64,83.14 13.79,84.29 19.52,84.29 19.88,84.66 23.18,84.66 23.8,84.04 25.73,84.04 26.15,84.47 26.15,84.59 v2(26.42,84.85)
  BOTTOM w0.089: v2(13.59,79.65) 14.1,80.16 14.76,80.16 U7201.D1 ; R7116.2 41.05,84.64 41.05,83.86 40.27,83.08 38.86,83.08 v1(38.61,82.82) 38.22,82.43 33.57,82.43 31.17,84.83 28.7,84.83 28.19,84.33 26.32,84.33 26.23,84.42 26.23,84.67 v2(26.42,84.85)
I2C_DATA_PD_MUX: length 3.8
  BOTTOM w0.089: U7101.22 38.97,86.93 39.37,86.53 v1(39.37,86) 40.56,86 R7116.1
I2CEN: length 4.3
  TOP w0.127: R7174.2 41.48,91 v1(41.4,91.08) 41.06,91.08 40.69,90.71 40.45,90.71 R7173.1 40.06,90.06 v2(40.64,90.06)
  BOTTOM w0.127: U7101.17 40.62,90.08 v2(40.64,90.06)
I_ADP: length 4.7
  TOP w0.102: v2(91.82,4.72) 91.82,5.94 C2435.1 90.98,5.45 R2421.1
  BOTTOM w0.102: v2(91.82,4.72) 91.82,4.97 v1(92.2,5.35) 92.31,5.46 U2401.110
I_BATT: length 3.4
  TOP w0.254: R2423.2 90.68,6.95 C2441.1 90.73,7.6 v2(90.59,7.74) 90.68,7.84 v1(90.68,8.53)
  BOTTOM w0.203: U2401.114 90.71,7.62 v2(90.59,7.74)
IC_DELAY: length 4.9
  TOP w0.102: v2(33.38,56.91) 33.91,56.91 34.01,57.02 v1(34.01,57.12) 34.24,57.35 34.24,59.48 33.93,59.78 C4344.1
  BOTTOM w0.102: v2(33.38,56.91) 33.72,57.25 U4302.4
ICSP_CLK: length 6.7
  BOTTOM w0.089: v1(95.96,5.4) 95.81,5.4 ; 95.81,5.4 95.81,5.81 95.91,5.92 U2401.101 ; 95.81,5.4 94.61,4.21 94.61,3.07 94.93,2.75 95.82,2.75 95.92,2.85 95.92,2.98 95.77,3.13 DB3.2
ICSP_CLR: length 14.5
  TOP w0.102: v2(98.95,4.34) 98.95,3.85 v2(97.92,2.81) 96.82,3.9 R2414.2
  BOTTOM w0.102: v2(98.95,4.34) 98.95,5.37 98.96,5.38 v1(98.96,5.45) 98.96,5.58 98.53,6.01 98.53,7.13 97.19,8.47 97.19,10.72 98.16,11.69 U2401.87 ; DB3.6 97.77,2.96 v2(97.92,2.81)
ICSP_DAT: length 7.1
  BOTTOM w0.089: DB3.3 96.27,3.13 96.12,2.98 96.12,2.77 95.9,2.56 94.85,2.56 94.42,2.99 94.42,4.29 95.62,5.48 95.62,5.81 95.51,5.92 U2401.102
ILIM_HI: length 2.6
  BOTTOM w0.102: R3404.2 21.21,46.25 v1(21.84,45.61) 21.84,45.48 21.07,44.71 U3401.16
ILIM_LO: length 2.3
  BOTTOM w0.102: R3403.2 20.62,46.4 v1(20.62,45.71) 20.83,45.51 20.83,44.98 20.57,44.72 U3401.15
ILIM_SEL: length 3.6
  BOTTOM w0.102: U3401.4 21.72,42.23 21.72,40.93 v1(22.14,40.5) 22.26,40.38 22.26,39.78 R3405.2
INPUT3VSEL: length 30.9
  TOP w0.102: R1519.2 150.29,70.5 150.29,70.93 150.5,71.14 150.5,71.95 R1520.1 149.71,72.74 147.17,72.74 146.02,71.6 140.89,71.6 v2(140.59,71.9)
  BOTTOM w0.102: v2(140.59,71.9) 140.08,71.39 v1(138.3,71.39) 136.91,71.39 136.27,72.03 136.25,72.03 136.02,72.25 135.36,72.25 135.13,72.48 135.13,72.67 134.89,72.92 134.37,72.92 134.24,73.04 134.24,73.42 133.83,73.84 133.6,73.84 133.32,74.12 124.78,74.12 CPU1.BT27
IR_CAM_DET#: length 105.9
  TOP w0.102: R2046.2 150.88,73.55 v1(151.13,73.3) 151.38,73.04 v2(151.38,71.83) ; v2(105.61,100.35) R5510.2
  L4SGND w0.102: v2(105.61,100.35) 106.17,100.91 116.46,100.91 v2(117,100.36)
  L6 w0.102: v2(151.38,71.83) 151.56,72.01 151.56,76.65 149.95,78.26 149.86,78.26 149.02,79.09 137.61,79.09 136.54,80.16 130.3,80.16 129,81.46 126.97,81.46 124.89,83.53 123.41,83.53 121.96,84.98 118.47,84.98 118.03,85.41 117.54,85.41 117.14,85.81 117.14,86.33 116.71,86.76 116.71,88.43 114.78,90.36 114.78,94.1 115.7,95.01 115.7,99.05 v2(117,100.36)
  BOTTOM w0.076: CPU1.CM22 134.21,77.23 134.87,77.23 135.03,77.39 135.5,77.39 arc(135.59,77.4) 135.66,77.45 136.16,77.45 136.3,77.31 136.85,77.31 137.16,77.62
  BOTTOM w0.102: 137.16,77.62 138.56,79.01 149.73,79.01 150,78.75 152.96,78.75 154.09,77.62 154.29,77.62 154.56,77.35 154.56,76.09 154.99,75.66 154.99,75.28 153.89,74.18 153.89,72.12 153.35,71.58 151.71,71.58 151.45,71.83 v2(151.38,71.83)
IR_CAMERA_DET#_R: length 3.2
  TOP w0.102: R5510.1 107.54,100.55 v1(107.54,99.92) 108.03,99.92 v2(108.46,100.35)
  BOTTOM w0.102: LCD1.44 108.48,99.5 108.48,100.32 v2(108.46,100.35)
ISH_KB_DISABLE: length 86.9
  TOP w0.102: v2(182.63,48.91) 182.63,47.67 182.87,47.43 183.44,47.43 183.45,47.44 183.68,47.44 183.77,47.53 Q2001.2 ; v2(128.57,56.74) 128.46,56.63 128.46,55.45 131.82,52.09 133.49,52.09 134.53,51.05 136.3,51.05 136.86,50.49 140.83,50.49 142.55,52.22 144.27,52.22 144.53,51.96 145.44,51.96 v1(147.57,54.09) 147.78,54.3 147.78,56.33 147.45,56.66 147.45,57.17 146.75,57.87 146.75,58.76 v2(146.69,58.82)
  L4SGND w0.102: v2(146.69,58.82) 146.75,58.88 149.85,58.88 150.18,58.55 152.16,58.55 153.34,59.73 154.55,59.73 154.67,59.62 159.74,54.55 163.76,54.55 164.36,53.94 169.05,53.94 170.51,52.48 179.21,52.48 182.63,49.07 v2(182.63,48.91)
  BOTTOM w0.076: CPU1.BW35 126.57,68.67 126.57,68.47 126.53,68.35 126.53,68.12 126.55,68.06 126.55,67.76 126.53,67.7 126.53,67.16 126.75,66.95
  BOTTOM w0.102: v2(128.57,56.74) 128.65,56.83 128.65,60.84 128.32,61.17 128.32,64.04 126.75,65.61 126.75,66.95
IST_TRIG: length 6
  TOP w0.102: v2(136.09,67.46) 135.35,68.2 TP620.1
  BOTTOM w0.102: v2(136.09,67.46) 136.18,67.56 136.18,67.91 136.18,67.91 136.18,68.18 136.18,68.26 136.08,68.36 136,68.36 135.39,68.36 CPU1.CP36
ITP_PMODE: length 7.5
  BOTTOM w0.102: CPU1.W4 101.74,88.53 101.74,90.47 101.75,90.48 101.75,90.56 101.82,90.63 101.82,90.97 101.58,91.2 100.82,91.2 99.44,92.59 98.56,92.59 TP618.1
JACK_PLUG: length 13
  TOP w0.254: v2(17.65,25.42) v1(17.65,24.78) 17.63,24.76 16.74,24.76 15.24,26.26 15.24,27.45 13.89,28.8 HPMIC1.5
  BOTTOM w0.254: R2923.1 20.98,24.88 20.57,25.29 18.55,25.29 ED2902.1 18.38,25.34 17.73,25.34 v2(17.65,25.42)
JACK_PLUG_DET: length 12.1
  TOP w0.254: HPMIC1.6 10.41,29.71 13.99,29.71 16.26,27.45 v1(16.38,27.45) 16.38,26.99 17.09,26.28 17.37,26.28 R2905.1 17.6,26.05 v2(18.29,26.05)
  BOTTOM w0.254: ED2902.2 18.49,26.25 v2(18.29,26.05)
JGND:
  vias: v1(22.61,76.09) v3(23.24,77.23) v3(23.24,76.35) v3(24.13,77.23) v3(24.13,76.35)
KB_BL_CTRL#: length 7.5
  TOP w0.508: v2(75.44,13.29) 76.52,12.21 AFTP6530.1
  BOTTOM w0.279: KBBL1.4 75.55,12.99 75.44,13.1 v2(75.44,13.29)
  BOTTOM w0.508: Q6501.D 74.8,15.63 74.93,15.5 74.93,13.79 v2(75.44,13.29)
KB_DET#: length 247.9
  TOP w0.102: v2(156.59,41.67) v1(156.59,43.71) 156.59,44.2 157.47,45.08 157.47,49.7 156.92,50.25 156.92,53.42 157.48,53.98 157.48,54.98 159,56.5 159,60.49 158.83,60.67 158.83,69.09 158.71,69.2 158.71,70.26 158.71,70.26 158.71,70.76 158.93,70.97 158.93,74.25 158.75,74.43 158.75,74.93 158.75,77.78 157.57,78.96 157.57,83.71 154.09,87.19 151.64,87.19 151.01,87.83 149.1,87.83 148.97,87.69 148.97,86.71 R2045.2 149.3,86.12 v2(146.3,86.12)
  L4SGND w0.102: v2(34.92,15.26) 34.92,13.73 39.62,9.04 v2(40.45,9.04)
  L6 w0.102: v2(156.59,41.67) 156.59,41.64 157.18,41.06 157.18,39.46 161.67,34.96 161.67,30.76 163.5,28.93 163.5,21.34 158.81,16.65 156.78,16.65 156.52,16.4 141.67,16.4 139.63,18.45 134.84,18.45 133.72,17.33 131.97,17.33 131.18,16.54 114.67,16.54 111.9,19.31 102.28,19.31 101.17,18.2 100.9,18.2 97.92,15.23 95.4,15.23 95.4,15.23 94.42,15.23 94.42,15.23 93.87,15.23 93.48,14.84 92.48,14.84 92.44,14.88 89.4,14.88 89.35,14.93 87.42,14.93 86.4,15.94 86.4,16.65 86.17,16.89 85.05,16.89 83.73,15.57 81.58,15.57 79.51,13.51 78.58,13.51 78.11,13.04 76.29,13.04 75.79,12.53 67.78,12.53 65.63,10.38 53.64,10.38 49.99,14.02 44.69,14.02 44.15,14.57 39.29,14.57 38.99,14.88 35.31,14.88 v2(34.92,15.26)
  BOTTOM w0.076: 137.96,84.18 135.71,84.18 135.71,84.18 arc(135.68,84.19) 135.64,84.2 135.46,84.2 arc(135.4,84.19) 135.34,84.16 arc(135.27,84.13) 135.2,84.13 arc(135.13,84.14) 135.07,84.17 arc(135.03,84.19) 134.98,84.2 134.96,84.22 134.36,84.22 134.36,84.22 134.12,84.22 134.11,84.22 133.94,84.05 133.94,83.4 CPU1.CM12
  BOTTOM w0.102: v2(146.3,86.12) 145.49,85.31 140.54,85.31 139.4,84.18 137.96,84.18 ; KBBD1.30 v2(40.45,9.04)
KB_DISABLE_CPU_R: length 4.3
  TOP w0.102: Q2001.5 183.77,51.02 R2003.2 182.93,51.15 v1(182.55,50.77) 182.5,50.72 182.5,49.85 182.61,49.74 Q2001.6
KB_LED_BL_DET: length 235.9
  TOP w0.102: v2(79.37,9.42) 77.98,10.81 77.98,12.59 v1(77.85,12.72) 77.22,13.35 76.58,13.35 75.82,14.12 75.82,15.31 R6508.1 76.28,16.43 R6507.1
  L4SGND w0.102: v2(76.41,4) 76.8,4 77.44,4.64 79.2,4.64 80.95,2.89 85.94,2.89 88.1,5.05 88.41,5.05 88.67,5.31 88.67,5.35 89.33,6.01 98.82,6.01 99.17,6.37 101.41,6.37 102.62,7.58 105.23,7.58 105.41,7.4 106.42,7.4 107.27,6.55 113.23,6.55 116.28,3.5 139.91,3.5 143.1,6.69 143.1,7.83 143.59,8.31 143.98,8.31 144.62,8.96 162.69,8.96 163.9,7.74 167.68,7.74 170.81,10.87 170.81,19.13 172.8,21.12 172.8,25.82 174.42,27.45 175.19,27.45 178.39,30.65 180.52,30.65 180.95,31.08 180.95,31.95 181.28,32.27 187.94,32.27 190.73,35.07 190.73,42.38 186.78,46.33 186.78,47.13 185.22,48.68 184.42,48.68 184,49.11 184,49.65 179.79,53.85 171.08,53.85 170.6,54.33 168.92,56.02 167.63,56.02 166.75,56.9 159.99,56.9 155.3,61.59 151.31,61.59 150.44,60.72 148.86,60.72 144.53,60.72 139.84,65.41 v2(138.07,65.41)
  BOTTOM w0.102: CPU1.CK36 133.65,68.29 133.69,68.24 133.86,68.07 133.86,68.07 133.95,67.99 133.95,67.84 133.81,67.71 133.81,67.46 133.81,67.04 135.27,65.58 137.89,65.58 v2(138.07,65.41) ; v2(79.37,9.42) 79.22,9.42 77.18,7.38 77.18,4.78 v2(76.41,4)
KB_LED_DET_C: length 11.6
  TOP w0.102: v2(75.56,16.4) v1(75.56,17.42) 75.62,17.47 R6507.2 76.45,17.98 C6504.1
  BOTTOM w0.102: v2(75.56,16.4) v1(75.56,17.42) 75.46,17.52 74.52,17.52 74.17,17.17 74.17,15.47 74.37,15.27 74.37,12.92 73.55,12.1 KBBL1.2
KB_LED_PWM: length 21.4
  L4SGND w0.102: v2(76.58,14.75) 79.98,14.75 80.03,14.7 81.86,14.7 82.29,15.13 82.45,15.13 84.43,17.11 84.43,17.84 85,18.41 88.37,18.41 v2(88.9,18.94)
  BOTTOM w0.102: U2401.44 89.51,21.21 89.39,21.09 89.39,19.44 v2(88.9,18.94) ; Q6501.G 75.75,14.89 R6509.1 v1(77.09,15.26) v2(76.58,14.75)
KBC_BEEP_R: length 2.2
  BOTTOM w0.254: RN2702.4 9.14,5.48 v1(8.51,5.48) 7.52,5.48 D2702.1
KBC_PS2_SCL_TP: length 6.3
  TOP w0.089: RN6502.4 147.12,10.25 147.32,10.05 147.32,8.78 146.81,8.27 146.43,8.27 AFTP6532.1 145.44,8.15 144.68,7.38 v2(144.65,7.38)
  BOTTOM w0.089: v2(144.65,7.38) 144.85,7.58 TP1.1
KBC_PS2_SDA_TP: length 5.3
  TOP w0.089: RN6502.3 146.76,8.98 146.56,8.78 145.7,8.78 145.3,8.38 144.63,8.38 AFTP6533.1 144.4,7.77 v2(144.02,7.38)
  BOTTOM w0.089: v2(144.02,7.38) 143.85,7.55 TP1.2
KBC_PWRBTN#: length 144.5
  TOP w0.102: v2(76.58,5.33) 76.58,5.23 76.78,5.02 80.98,5.02 81.23,5.28 82.09,5.28 AFTP6609.1 83.87,7.05 R2432.1 ; v2(162.31,42.82) 162.31,42.82 162.64,42.82 162.84,43.02 C6605.1
  L6 w0.102: v2(162.31,42.82) 162.39,42.74 162.39,41.64 166.84,37.19 166.84,34.15 169.09,31.9 169.09,19.7 163.88,14.5 163.88,12.93 156,5.05 138.86,5.05 136.94,6.96 133.63,6.96 132.78,7.82 130.43,7.82 129.77,8.48 129.29,8.48 127.65,10.11 126.63,10.11 126.53,10.22 118.18,10.22 116.11,8.15 109.47,8.15 107.64,9.98 101.14,9.98 100.11,8.95 92.29,8.95 91.06,10.18 89.93,10.18 80.52,10.18 v2(79.96,9.62)
  BOTTOM w0.102: v2(76.58,5.33) 76.98,5.72 76.98,7.59 79.21,9.82 79.76,9.82 v2(79.96,9.62) ; v2(162.31,42.82) 162.31,42.82 162.64,42.82 162.8,42.98 IOBD1.46
KBC_SMB_SCL_BAT: length 21.1
  TOP w0.089: AFTP4311.1 157.91,16.24 v2(157.93,16.24)
  BOTTOM w0.089: v2(157.93,16.24) 158.25,16.57 158.25,17.56 158.17,17.65 BATT1.4 157.35,18.33 158.23,19.21 158.23,19.68 159.08,20.53 160.85,20.53 161.04,20.72 161.04,21.4 ED4306.3 161.67,21.38 161.67,20.72 161.86,20.53 162.67,20.53 162.85,20.71 162.85,24.14 162.67,24.31 162.67,25.33 162.79,25.44 162.79,26.23 162.23,26.79 162.23,28.03 162.81,28.61 RN4302.4
KBC_SMB_SDA_BAT: length 19
  TOP w0.089: v2(158.64,16.24) 158.7,16.3 159.31,16.3 AFTP4310.1
  BOTTOM w0.089: RN4302.3 162.51,27.96 162.42,27.87 162.42,27.44 ED4305.3 162.98,26.88 162.98,25.36 162.86,25.25 162.86,24.39 163.04,24.21 163.04,20.63 162.75,20.34 159.16,20.34 158.42,19.6 158.42,19.14 159.35,18.21 BATT1.5 158.53,17.65 158.45,17.56 158.45,16.43 v2(158.64,16.24)
KSI0: length 85.2
  TOP w0.089: RN2403.8 40.18,4.59 v2(40.06,4.72) 39.66,5.12 39.66,6 40.01,6.35 AFTP6512.1
  BOTTOM w0.089: U2401.98 97.11,5.83 97.16,5.78 97.16,5.64 98.53,4.27 98.53,2.56 97.72,1.74 94,1.74 93.8,1.54 93.15,1.54 90.01,1.48 89.99,1.46 89.81,1.28 43.5,1.28 v2(40.06,4.72) 40.06,6.79 39.45,7.4 39.45,11.15 40.26,11.96 45.97,11.96 46.85,11.08 KBBD1.22
KSI1: length 80.3
  TOP w0.089: RN2403.7 40.77,4.71 v2(40.77,4.72) 40.77,5.1 AFTP6501.1
  BOTTOM w0.089: KBBD1.24 45.25,11.03 44.58,11.7 40.37,11.7 39.64,10.98 39.64,7.75 40.77,6.62 v2(40.77,4.72) 44.02,1.47 89.73,1.47 89.89,1.63 89.93,1.67 90.5,1.68 93.13,1.73 93.72,1.73 93.92,1.93 97.64,1.93 98.34,2.64 98.34,4.04 96.95,5.43 96.95,5.69 96.71,5.92 U2401.99
KSI2: length 53
  TOP w0.089: RN2404.6 45.08,4.21 45.47,4.59 v2(45.72,4.59) AFTP6508.1
  BOTTOM w0.089: U2401.6 82.89,10.09 82.72,10.27 79.26,10.27 76.78,7.79 76.78,6.14 76.07,5.43 76.07,4.38 74.91,3.22 57.5,3.22 55.58,5.14 55.16,5.14 53.93,3.91 46.4,3.91 v2(45.72,4.59) 45.72,7.16 44.02,8.86 44.02,8.92 43.65,9.29 KBBD1.26
KSI3: length 53.7
  TOP w0.089: RN2404.5 45.67,3.78 46.48,4.59 v2(46.65,4.59) 46.65,6.83 AFTP6509.1
  BOTTOM w0.089: U2401.7 83.66,10.46 79.34,10.46 79.18,10.46 76.58,7.86 76.58,6.21 75.88,5.51 75.88,4.46 74.83,3.41 67.95,3.41 66.03,5.33 55.08,5.33 53.85,4.1 47.14,4.1 v2(46.65,4.59) 46.65,7.21 46.05,7.82 KBBD1.23
KSI4: length 71.9
  TOP w0.089: AFTP6505.1 41.4,5.35 v2(41.4,4.72) 41.27,4.59 41.27,3.82 RN2403.6
  BOTTOM w0.089: U2401.104 94.71,5.96 93.94,5.18 93.94,2.74 93.12,1.92 89.85,1.86 89.65,1.66 44.46,1.66 v2(41.4,4.72) 41.4,6.62 39.83,8.19 39.83,10.9 40.45,11.51 42.1,11.51 42.85,10.76 KBBD1.27
KSI5: length 65.6
  TOP w0.089: RN2403.5 41.86,4.41 42.16,4.72 v2(42.42,4.72) 42.42,6.52 41.91,7.03 AFTP6506.1 42.42,8.27 43.69,8.27 v2(44.45,9.04)
  BOTTOM w0.089: U2401.105 94.31,5.83 93.75,5.26 93.75,2.82 93.04,2.11 89.83,2.11 89.57,1.85 45.29,1.85 v2(42.42,4.72) ; v2(44.45,9.04) KBBD1.25
KSI6: length 68.3
  TOP w0.089: AFTP6503.1 43.05,5.1 v2(43.05,4.72) 43.43,4.34 43.43,4.32 RN2404.8
  BOTTOM w0.089: U2401.107 93.51,2.85 92.96,2.3 89.76,2.3 89.49,2.04 45.73,2.04 v2(43.05,4.72) 43.05,5.61 40.02,8.63 40.02,10.67 40.12,10.77 41.7,10.77 42.05,10.42 KBBD1.28
KSI7: length 64
  TOP w0.089: RN2404.7 44.58,4.33 v2(44.2,4.72) 44.2,7.38 AFTP6502.1
  BOTTOM w0.089: U2401.108 93.11,4.42 92.05,3.35 90.53,3.35 89.41,2.23 46.65,2.23 46.58,2.3 46.57,2.3 44.2,4.68 v2(44.2,4.72) 44.2,5.73 41.25,8.68 KBBD1.29
KSO0: length 39.6
  TOP w0.089: v2(53.98,9.04) AFTP6507.1 54.9,7.42 54.9,5.19 v2(55.37,4.72) 55.37,3.85 RN2411.8
  BOTTOM w0.089: U2401.2 82.06,8.49 82.06,8.5 81.77,8.5 81.77,8.49 80.6,8.49 79.33,7.22 79.33,5.23 78.37,4.26 77.27,4.26 76.07,3.07 75.99,3.03 57.06,3.03 v2(55.37,4.72) ; KBBD1.13 54.05,9.11 v2(53.98,9.04)
KSO1: length 47.6
  TOP w0.089: v2(52.45,9.04) 52.45,8.66 AFTP6511.1 53.34,7.51 52.83,7 v2(52.83,4.72) 52.96,4.59 RN2412.6
  BOTTOM w0.089: v2(52.45,9.04) KBBD1.15 ; U2401.14 82.59,13.29 81.42,14.46 80.87,14.46 80.52,14.12 79.48,14.12 78.29,12.92 78.29,9.84 76.38,7.92 76.38,6.27 75.69,5.59 75.69,4.54 74.75,3.6 68.03,3.6 66.11,5.52 55,5.52 53.77,4.29 53.26,4.29 v2(52.83,4.72)
KSO2: length 46.4
  TOP w0.089: v2(53.21,9.04) 53.21,8.78 53.78,8.22 53.78,6.3 AFTP6513.1 53.59,5.61 v2(53.59,4.72) 53.54,4.67 RN2412.5
  BOTTOM w0.089: v2(53.59,4.72) 54.59,5.71 66.19,5.71 68.11,3.79 74.67,3.79 75.5,4.62 75.5,5.66 76.18,6.35 76.18,8 78.1,9.92 78.1,13 79.41,14.31 80.33,14.31 80.68,14.65 81.5,14.65 82.46,13.69 U2401.15 ; v2(53.21,9.04) 53.25,9.07 KBBD1.14
KSO3: length 48.6
  TOP w0.089: RN2412.7 52.45,4.33 52.07,4.72 v2(51.82,4.72) 51.44,5.1 AFTP6518.1 51.44,6.8 52.07,7.43 52.07,8.61 v2(51.65,9.04)
  BOTTOM w0.089: U2401.16 83.04,14.09 83.01,14.07 82.37,14.07 81.6,14.85 80.6,14.85 80.25,14.5 79.33,14.5 77.91,13.08 77.91,10.08 75.99,8.16 75.99,6.43 75.31,5.74 75.31,4.7 74.59,3.98 68.24,3.98 66.31,5.9 53,5.9 v2(51.82,4.72) ; v2(51.65,9.04) KBBD1.16
KSO4: length 66.6
  TOP w0.089: v2(48.45,9.04) 48.45,6.69 AFTP6514.1 47.62,4.79 v2(47.7,4.72) 48.64,4.72 48.9,4.46 RN2409.7
  BOTTOM w0.089: v2(48.45,9.04) KBBD1.20 ; U2401.37 86.71,22.73 86.49,22.96 86.28,22.96 85.47,23.77 85.47,24.75 85.13,25.09 83.15,25.09 82.82,24.77 82.82,23.47 81.5,22.15 81.5,17.77 77.32,13.59 77.32,10.63 74.8,8.12 74.8,6.92 74.63,6.75 74.63,6.17 75.05,5.74 75.05,4.71 74.52,4.17 68.32,4.17 66.39,6.09 49.08,6.09 v2(47.7,4.72)
KSO5: length 67.4
  TOP w0.089: RN2409.8 47.52,3.8 47.28,4.05 47.28,7.42 AFTP6510.1 v2(47.62,9.04)
  BOTTOM w0.089: KBBD1.21 47.65,9.06 v2(47.62,9.04) 50.32,6.34 66.42,6.34 68.39,4.36 74.44,4.36 74.86,4.79 74.86,5.67 74.44,6.09 74.44,6.83 74.61,7 74.61,8.19 77.13,10.71 77.13,13.67 81.31,17.85 81.31,22.23 82.61,23.53 82.61,24.82 83.07,25.28 85.21,25.28 85.66,24.83 85.66,23.85 86.36,23.15 86.66,23.15 87.11,22.7 U2401.38
KSO6: length 64.8
  TOP w0.089: v2(50.04,9.04) 50.04,6.37 AFTP6517.1 49.99,5.4 RN2409.5
  BOTTOM w0.089: KBBD1.18 50.05,9.05 v2(50.04,9.04) 52.54,6.53 66.5,6.53 68.47,4.55 74.36,4.55 74.67,4.87 74.67,5.59 74.25,6.01 74.25,6.91 74.42,7.08 74.42,8.27 76.93,10.79 76.93,13.75 81.12,17.93 81.12,22.31 82.37,23.56 82.37,24.86 82.99,25.48 85.28,25.48 85.85,24.91 85.85,23.93 86.44,23.34 86.99,23.34 87.51,22.82 U2401.39
KSO7: length 61.7
  TOP w0.089: v2(90.61,11.7) 90,12.32 84.84,12.32 84.14,11.62 84.14,11.54 83.98,11.38 82.76,10.16 82.76,10.16 80.96,8.36 78.93,8.36 78.49,8.8 65.29,8.8 65.26,8.83 65.23,8.83 64.45,9.61 62.31,9.61 62.25,9.67 57.82,9.67 57.56,9.92 50.16,9.92 v2(49.28,9.04) 49.28,8.02 AFTP6515.1 49.18,7.42 49.18,4.94 49.4,4.72 RN2409.6
  BOTTOM w0.089: U2401.50 91.91,21.32 91.48,20.89 91.48,12.51 90.68,11.7 v2(90.61,11.7) ; v2(49.28,9.04) 49.25,9.06 KBBD1.19
KSO8: length 60.2
  TOP w0.089: RN2412.8 51.21,3.8 50.8,4.21 50.8,7.13 AFTP6516.1 50.8,8.4 v2(50.8,9.04) 51.5,9.73 57.48,9.73 57.76,9.46 62.19,9.46 63.04,8.61 76.99,8.61 77.99,7.61 78.71,7.61 79.25,8.15 81.02,8.15 82.95,10.08 84.08,11.21 84.33,11.46 84.33,11.54 84.92,12.13 89.24,12.13 v2(89.66,11.7)
  BOTTOM w0.089: v2(50.8,9.04) 50.85,9.09 KBBD1.17 ; U2401.46 90.31,20.96 90.25,20.9 90.25,13.72 89.66,13.13 v2(89.66,11.7)
KSO9: length 55.6
  TOP w0.089: v2(91.62,11.7) 90.77,10.86 84.49,10.86 84.26,10.85 83.33,9.92 81.18,7.77 79.45,7.77 78.72,7.05 78.02,7.05 77.78,7.29 75.4,7.29 75.39,7.3 66.23,7.3 64.64,5.72 64.64,3.45 R2453.2 63.27,3.8 R2452.1 62.61,4.31 62.61,5.35 AFTP6504.1 62.87,7 v2(60.83,9.04)
  BOTTOM w0.089: KBBD1.7 58.8,10 58.8,8.94 59.13,8.61 60.41,8.61 v2(60.83,9.04) ; U2401.68 98.14,19.29 97.92,19.07 97.92,18.66 97.14,17.88 96,17.88 92.48,14.37 92.48,13 92.45,12.97 92.45,12.94 92.3,12.79 92.3,12.77 91.62,12.09 v2(91.62,11.7)
KSO10: length 52.4
  TOP w0.089: v2(63.12,4.72) 63.12,4.84 65.77,7.49 75.47,7.49 75.48,7.48 77.85,7.48 78.1,7.24 78.65,7.24 79.37,7.96 81.1,7.96 83.14,10 83.14,10 84.18,11.04 84.18,11.04 84.52,11.38 84.52,11.46 84.77,11.71 87.24,11.71 87.67,11.28 90.84,11.28 91.06,11.5 91.06,11.83 91.36,12.13 91.93,12.13 92.35,11.7 v2(92.71,11.7) ; v2(60.07,9.04) 60.07,8.65 AFTP6523.1 60.96,7.64 61.85,6.75 v2(61.85,4.72) 61.82,4.72 RN2410.5
  BOTTOM w0.089: U2401.72 98.04,17.69 97.43,17.08 96.15,17.08 93.62,14.55 93.62,14.08 93.62,14.08 93.62,12.61 v2(92.71,11.7) ; v2(60.07,9.04) 60.07,9.42 60.45,9.8 KBBD1.5 ; v2(63.12,4.72) v2(61.85,4.72)
KSO11: length 53.2
  TOP w0.089: v2(65.07,4.72) 65.07,5.87 66.31,7.11 75.31,7.11 75.32,7.1 77.7,7.1 77.94,6.86 78.8,6.86 79.53,7.58 81.26,7.58 83.52,9.84 84.34,10.66 84.5,10.67 92.31,10.67 v2(93.34,11.7) ; RN2410.6 60.32,4.46 60.58,4.72 v2(61.09,4.72) 61.09,5.61 AFTP6522.1 60.96,6.54 59.31,8.19 v2(59.31,9.04)
  BOTTOM w0.089: v2(61.09,4.72) 61.51,5.14 64.64,5.14 v2(65.07,4.72) ; v2(93.34,11.7) 93.81,12.17 93.81,14.16 93.81,14.47 96.23,16.89 U2401.74 ; v2(59.31,9.04) 59.65,9.38 KBBD1.6
KSO12: length 64.1
  TOP w0.089: v2(94.32,11.07) 93.54,10.29 84.5,10.29 83.9,9.68 81.37,7.15 79.63,7.15 78.96,6.48 77.78,6.48 77.54,6.72 76,6.72 74.94,5.66 72.56,5.66 v2(71.88,4.98) ; v2(54.74,9.04) 54.74,9.45 54.83,9.54 57.4,9.54 57.69,9.26 57.69,7.23 AFTP6519.1 59.05,3.98 RN2410.8
  BOTTOM w0.089: v2(94.32,11.07) 94.32,11.58 94,11.9 94,14.23 94,14.24 94,14.39 96.1,16.49 U2401.75 ; v2(71.88,4.98) 71.65,4.74 68.55,4.74 66.58,6.72 57.05,6.72 v2(54.74,9.04) 54.85,9.15 KBBD1.12
KSO13: length 58.6
  TOP w0.089: v2(74.25,5.05) 74.59,5.05 76.08,6.53 77.46,6.53 77.75,6.24 79,6.24 79.71,6.96 81.45,6.96 84.09,9.6 84.58,10.1 94.27,10.1 v2(94.61,10.43) ; RN2411.5 57.1,5.81 AFTP6520.1 57.5,6.21 57.5,8.79 v2(57.25,9.04)
  BOTTOM w0.089: KBBD1.9 v2(57.25,9.04) 58.99,7.29 68.68,7.29 68.87,7.47 70.81,7.47 70.91,7.37 70.91,6.04 71.2,5.76 71.5,5.76 71.52,5.79 72.22,5.79 72.37,5.63 73.66,5.63 v2(74.25,5.05) ; U2401.76 95.97,16.09 94.19,14.31 94.19,11.98 94.74,11.43 94.74,10.57 v2(94.61,10.43)
KSO14: length 57.2
  TOP w0.089: v2(58.21,9.04) 58.21,8.61 AFTP6521.1 59.82,7 RN2410.7 ; v2(71.37,6.18) 71.37,6.21 72.07,6.91 74.87,6.91 74.88,6.92 75.23,6.92 75.25,6.91 77.62,6.91 77.86,6.67 78.88,6.67 79.56,7.34 81.29,7.34 83.71,9.76 83.71,9.76 84.42,10.47 84.5,10.48 93.06,10.48 94.08,11.49 94.82,11.49 v2(95.25,11.07)
  BOTTOM w0.089: U2401.77 98.89,15.65 95.79,15.65 94.38,14.23 94.38,12.06 95.25,11.19 v2(95.25,11.07) ; v2(71.37,6.18) 71.37,6.19 71.37,7.18 70.89,7.67 68.79,7.67 68.6,7.48 59.76,7.48 v2(58.21,9.04) 58.05,9.2 KBBD1.8
KSO15: length 55.7
  TOP w0.089: v2(56.39,9.04) 56.39,8.53 AFTP6524.1 56.51,7.13 RN2411.6 ; v2(95.25,10.43) 94.72,9.9 84.66,9.9 84.28,9.53 84.28,9.52 81.53,6.77 79.82,6.77 79.1,6.05 77.67,6.05 77.38,6.34 76.15,6.34 74.44,4.62 73.98,4.62 v2(73.62,4.98)
  BOTTOM w0.089: U2401.86 98.06,12.09 97,11.04 97,10.31 96.7,10.01 95.68,10.01 v2(95.25,10.43) ; v2(73.62,4.98) 73.16,5.44 72.29,5.44 72.14,5.6 71.6,5.6 71.13,5.13 68.71,5.13 66.74,7.1 58.32,7.1 v2(56.39,9.04) 56.45,9.1 KBBD1.10
KSO16: length 55.3
  TOP w0.089: RN2411.7 56.01,5.09 AFTP6539.1 55.63,6.24 v2(55.63,9.04) ; v2(97.83,10.17) 97.37,9.71 84.74,9.71 84.47,9.45 81.6,6.58 79.9,6.58 79.18,5.86 77.59,5.86 77.3,6.15 76.23,6.15 74.52,4.43 73.48,4.43 v2(72.9,5.02)
  BOTTOM w0.089: v2(72.9,5.02) 72.45,5.02 72.06,5.4 71.68,5.4 71.21,4.93 68.63,4.93 66.66,6.91 57.75,6.91 v2(55.63,9.04) 55.63,9.29 55.65,9.31 KBBD1.11 ; U2401.92 98.02,9.69 97.83,9.89 v2(97.83,10.17)
L_BKLT_CTRL: length 60.5
  TOP w0.127: v2(124.65,103.39) 124.65,102.71 124.25,102.31 123.88,102.31 123.73,102.46 114.47,102.46 111.06,105.87 102.04,105.87 101.09,104.92 R5502.2
  L4SGND w0.127: v2(124.65,103.39) 125.46,103.39 125.86,102.99 125.86,101.74 130.99,96.61 130.99,95.09 133.07,93.01 133.07,92.16 132.38,91.48 132.38,90.65 132.92,90.11 132.92,84.97 132.67,84.73 132.59,84.73 131.67,83.8 v2(131.67,83.8)
  BOTTOM w0.127: D5502.1 129.18,99.02 127.72,100.48 v1(127.69,100.48) 127.69,100.63 125.88,102.44 125.16,102.44 124.9,102.7 124.9,103.15 v2(124.65,103.39) ; v2(131.67,83.8) 131.67,83.97 CPU1.CH11
L_BKLT_EN: length 169.5
  TOP w0.102: v2(107.95,18.9) 109.96,16.9 109.96,15.94 111.66,14.24 112,14.24 v2(112.01,14.23) ; v2(133.52,84.86) 133.64,84.98 135.79,84.98 136.24,84.53 138.46,84.53 139.85,85.92 145.32,85.92 145.92,86.53 146.47,86.53 146.68,86.33 147.85,86.33 148.77,87.24 148.77,87.8 148.87,87.9 149,88.03 151.09,88.03 151.73,87.39 154.18,87.39 157.77,83.8 157.77,79.1 158.95,77.92 158.95,74.84 158.95,74.84 158.95,74.51 159.13,74.33 159.13,70.89 158.92,70.68 158.92,70.34 158.92,69.28 159.03,69.17 159.03,60.75 159.21,60.57 159.21,56.38 157.68,54.85 157.68,53.9 157.12,53.34 157.12,50.41 157.68,49.86 157.68,44.89 157.01,44.22 157.01,41.51 156.76,41.27 156.45,41.27 156.21,41.03 156.21,40.5 v2(156.57,40.15)
  L4SGND w0.102: v2(156.57,40.15) 157.1,40.15 167.83,29.42 167.83,24.08 167.21,23.46 167.21,23.46 161.06,17.32 147.24,17.32 145.97,16.05 141.41,16.05 140.3,14.93 132.08,14.93 130.9,13.76 127.26,13.76 126.44,12.95 119.8,12.95 118.83,13.92 112.32,13.92 v2(112.01,14.23)
  BOTTOM w0.102: R2440.2 103.94,17.24 v1(104.14,17.04) 104.52,17.42 104.52,17.54 105.03,18.05 R2455.1 R2403.1 107.15,18.1 v2(107.95,18.9) ; v2(133.52,84.86) 133.26,84.61 CPU1.CK11
L_BKLT_EN_R: length 5.5
  BOTTOM w0.102: D2401.2 109.22,17.39 109.22,17.04 108.84,16.66 107.7,16.66 v1(107.44,16.91) 107.11,17.24 R2403.2
LAN_WAKE#: length 3.8
  TOP w0.102: R1707.2 125.39,73.43 125.39,72.45 125.25,72.31 v1(125.25,72.05) 125.25,71.9 125.39,71.75 125.39,71.27 125.8,70.87 v2(125.88,70.87)
  BOTTOM w0.102: v2(125.88,70.87) 125.59,70.58 CPU1.BU32
LCD_BRIGHTNESS: length 8.5
  TOP w0.127: v2(97.79,100.35) 98.42,99.71 v1(100.2,99.71) 100.84,99.71 101.47,100.35 101.47,101.82 EC5501.1 101.09,102.46 R5545.1
  BOTTOM w0.127: v2(97.79,100.35) 97.79,100.14 97.5,99.85 LCD1.22
LCD_TST: length 315.5
  TOP w0.102: R5543.2 86.87,104.79 88.01,105.94 100.58,105.94 101.02,106.37 111.26,106.37 114.61,103.02 123.57,103.02 v2(123.95,103.4) 123.95,104.16 125.68,105.89 130.75,105.89 131.11,105.52 131.11,101.7 131.11,100.76 132.28,99.59 137.55,99.59 138.3,98.83 138.3,98.05 138.55,97.81 140.11,97.81 140.34,98.03 140.34,98.87 140.67,99.21 145.2,99.21 146.28,100.28 156.91,100.28 160.15,97.05 160.15,91.59 160.66,91.08 160.66,87.68 166.31,82.03 166.31,56.33 165.56,55.58 165.13,55.58 164.06,54.51 164.06,50.85 164.49,50.42 164.49,45.32 164.08,44.91 164.08,42.99 164.41,42.66 164.41,40.45 v1(164.47,40.4) 164.47,39.77 v2(157.86,33.17)
  L4SGND w0.102: v2(75.57,7.91) 76.55,6.93 85.09,6.93 85.62,7.46 87.22,7.46 89.23,9.47 89.23,9.48 89.63,9.88 93.4,9.88 93.66,9.62 98.07,9.62 98.65,10.2 105.01,10.2 105.47,10.66 107.85,10.66 108.17,10.35 117.05,10.35 118.67,8.73 122.27,8.73 122.96,9.42 123.32,9.42 124.69,8.04 127.38,8.04 128.5,9.16 130.94,9.16 133.12,6.98 137.29,6.98 141.33,11.02 154.74,11.02 156.77,13.05 161.92,13.05 162.35,13.48 v2(162.94,13.48)
  BOTTOM w0.102: D5502.2 130.72,97.13 128.4,99.46 128.18,99.46 126.11,101.53 126.11,101.86 125.78,102.19 125.06,102.19 124.5,102.75 124.5,102.93 124.04,103.4 v2(123.95,103.4) ; v2(75.57,7.91) 75.57,8.02 77.72,10.16 77.72,13.42 82.39,18.09 U2401.26 ; v2(162.94,13.48) 162.66,13.76 162.66,18.74 162.89,18.97 164.02,18.97 165.01,19.97 165.01,28.35 166.47,29.81 166.74,29.81 169.44,32.52 169.44,35.34 169.06,35.73 160.43,35.73 v2(157.86,33.17)
LCD_TST_C: length 7.6
  TOP w0.102: R5543.1 v1(87.8,102.42) 88.14,102.08 88.14,100.48 88.77,99.84 90.46,99.84 v2(90.97,100.35)
  BOTTOM w0.102: LCD1.9 91,100.32 v2(90.97,100.35)
LCD_VCC_TEST_EN: length 220.6
  TOP w0.102: v2(163.2,42.05) 163.2,43.11 163.27,43.19 163.27,46.86 163.61,47.2 163.61,50.15 163.25,50.51 163.25,55.19 164.5,56.45 164.5,69.37 165.01,69.88 165.01,76.05 164.8,76.26 164.8,76.94 165.04,77.18 165.04,80.98 v1(165.35,81.3) 165.35,82.4 159.64,88.12 159.64,97.01 156.57,100.08 146.36,100.08 145.28,99 142.16,99 v2(141.6,98.44)
  L4SGND w0.102: v2(91.29,7.79) 91.75,7.33 98.49,7.33 99.13,7.98 99.57,8.42 101.51,8.42 102.06,8.96 105.79,8.96 105.84,8.91 106.85,8.91 107.84,7.92 113.8,7.92 116.34,5.38 128.8,5.38 129.04,5.61 v2(129.04,7.72)
  L6 w0.102: v2(129.04,7.72) 129.99,6.76 136.86,6.76 138.78,4.84 156.09,4.84 156.21,4.97 163.22,4.97 163.32,5.07 163.32,11.79 164.34,12.81 164.34,14.29 164.5,14.46 165.69,15.65 165.69,15.66 166.5,16.46 166.5,16.46 166.94,16.91 166.95,16.91 169.5,19.45 169.5,35.53 163.2,41.82 v2(163.2,42.05)
  BOTTOM w0.102: U2401.113 91.11,7.66 91.22,7.77 91.26,7.77 v2(91.29,7.79) ; v2(141.6,98.44) 141.1,98.95 138.43,98.95 137.79,99.59 133.6,99.59 133.1,99.08 133.1,98.83 133.1,98.44 131.28,96.63 130.42,96.63 129.67,97.38 129.67,97.82 128.54,98.95 128.4,98.95 125.67,101.68 D5501.2
LDO1_CAP: length 7
  TOP w0.203: 21.46,14.37 21.59,14.37 22.22,15 U2701.39
  TOP w0.254: R2747.1 19.13,13.15 v2(18.8,13.48) 18.8,13.73 19.26,14.2 v1(20.07,14.2) 20.2,14.06 20.91,14.06 21.21,14.37 21.46,14.37
  BOTTOM w0.254: C2731.1 19.68,12.97 19.18,13.48 v2(18.8,13.48)
LDO2_CAP: length 1.8
  TOP w0.203: v2(22.48,22.25) 22.48,22.24 22.62,22.1 U2701.21
  BOTTOM w0.254: v2(22.48,22.25) 22.45,22.22 22.45,21.76 C2734.1
LDO3_CAP: length 2.2
  TOP w0.203: v2(23.67,22.5) 23.42,22.25 U2701.19
  BOTTOM w0.254: C2736.1 23.67,21.74 v2(23.67,22.5)
LID_CL_SIO#: length 207.4
  TOP w0.102: HALL1.4 v2(4.05,74.31) ; v2(126.55,9.56) 126.52,9.59 126.52,9.68 126.16,10.04 v1(124.94,10.04) 124.04,10.04 123.65,10.43 RN2405.3
  L6 w0.102: v2(17.45,31.41) 17.45,32.78 17.29,32.94 17.29,48.52 13.16,52.65 13.16,55.09 14.61,56.53 14.61,63.26 14.1,63.77 13.12,63.77 12.74,64.15 12.74,69.7 9.52,72.92 5.23,72.92 4.06,74.08 4.05,74.13 v2(4.05,74.31) ; v2(126.55,9.56) 126.52,9.59 126.52,9.68 126.18,10.01 118.27,10.01 116.2,7.94 108.92,7.94 107.09,9.77 106.73,9.77 105.48,9.77 101.25,9.77 100.18,8.7 91.59,8.7 v2(91.13,9.16) 90.32,9.97 89.85,9.97 81.97,9.97 80.99,9 72.21,9 72.13,9.09 67.77,9.09 65.99,7.3 41.61,7.3 40.28,8.63 40.28,8.63 40.04,8.87 40.04,8.87 35.9,13.01 34.52,13.01 31.43,16.1 31.43,16.4 31.43,16.4 31.43,18.3 31.15,18.58 31.15,20.42 29.94,21.63 27.92,21.63 25.66,23.9 25.66,26.36 21.84,30.18 v2(21.84,30.37)
  BOTTOM w0.102: v2(126.55,9.56) 126.55,9.54 126.6,9.49 126.6,8.51 124.46,6.37 124.46,4.51 123.98,4.04 U6402.1 ; v2(17.45,31.41) 17.62,31.23 18.06,31.23 19.02,30.27 19.51,30.27 19.52,30.26 20.05,30.26 20.47,29.84 D2402.K 21.31,29.84 v2(21.84,30.37) ; v2(91.13,9.16) 91.19,9.22 91.19,11.93 92.1,12.85 92.1,12.87 92.26,13.03 92.26,14.42 95.91,18.08 97.06,18.08 97.66,18.69 97.66,19.38 98.38,20.09 U2401.66
LID_CL_SIO_TAB#: length 167.1
  TOP w0.102: HALL1.1 4.05,72.81 4.28,73.04 5.74,73.04 5.84,72.94 v2(5.84,72.41)
  L6 w0.102: v2(79.94,4.56) 75.29,4.56 74.85,4.13 64.8,4.13 64.52,4.41 64.52,5.12 63.97,5.67 40.17,5.67 39.6,6.24 36.47,6.24 32.69,10.03 32.61,10.03 32.51,10.13 32.51,10.91 31.75,11.68 29.92,11.68 29.51,12.08 29.51,13.56 29.01,14.06 29.01,14.29 28.83,14.47 28.83,18.51 28.58,18.76 27.59,18.76 26.57,19.78 26.57,20.68 24.54,22.71 24.54,23.84 23.93,24.45 23.93,25.58 23.1,26.41 22.37,26.41 21.15,27.62 20.97,27.62 18.9,29.69 18.9,29.88 18.05,30.73 17.55,30.73 17.02,31.26 v2(17.02,32.02) 17.08,32.09 17.08,48.43 12.67,52.84 12.67,56.12 14.15,57.59 14.15,61.14 12.53,62.75 12.53,69.62 9.74,72.41 v2(5.84,72.41)
  BOTTOM w0.102: v2(17.02,32.02) 17.63,32.63 C6701.1 ; R2496.1 89.53,25.16 89.53,24.4 v1(89.28,24.15) 89.28,24.07 88.31,23.1 U2401.41 88.31,21.28 88.14,21.1 86.49,21.1 85.72,20.34 85.72,19.34 85.62,19.24 85.62,18.9 86.81,17.71 86.81,15.32 87.92,14.2 87.92,13.16 87.63,12.87 87.63,10.31 88.01,9.92 88.01,8.85 88.01,8.68 87.78,8.45 85.38,8.45 85.17,8.24 85.17,8.05 84.91,7.75 84.57,7.41 82.82,7.41 82.69,7.54 80.64,7.54 79.94,6.83 v2(79.94,4.56)
LINE1-L_C: length 2.2
  BOTTOM w0.254: C2907.2 18.11,19.14 v1(18.11,19.66) 18.06,19.6 R2922.1
LINE1-L_R: length 4.3
  BOTTOM w0.254: C2908.2 19.24,19.01 v1(19.24,20.11) 19.02,20.11 17.48,21.66 R2921.1
LINE1_L: length 4.6
  TOP w0.203: U2701.36 20.66,15.9 20.17,15.41 v1(19.81,15.41) 19.61,15.61 18.82,15.61 v2(18.41,16.02)
  BOTTOM w0.254: C2907.1 18.29,16.53 18.29,16.15 v2(18.41,16.02)
LINE1_R: length 3.9
  TOP w0.203: v2(19.05,16.27) 19.2,16.12 19.81,16.12 20.32,16.63 U2701.35
  BOTTOM w0.254: C2908.1 19.05,17.04 v2(19.05,16.27) 19.14,16.19 19.5,16.19 v1(19.79,16.48)
LPS_SW: length 5.6
  TOP w0.127: v1(24.92,71.01) 24.71,70.81 R7402.1 24.71,69.36 R7403.1 24.8,69.27 24.8,68.89 C7401.2 24.54,68.42 R7404.2 24.51,68.34 v2(23.88,67.71)
  BOTTOM w0.127: v2(23.88,67.71) 24.02,67.85 U7418.4
LPS_SW_A: length 19.5
  TOP w0.127: v2(13.84,68.6) 14.27,68.6 16.32,66.55 19.5,66.55 20.03,67.07 v1(21.08,67.07) 21.46,67.07 22.73,65.8 22.73,65.51 23.01,65.23 24.06,65.23 24.32,65.49 24.32,65.58 26.1,67.36 26.1,70 25.97,70.12 R7402.2
  BOTTOM w0.127: v2(13.84,68.6) 14.05,68.6 14.46,68.18 Q7406.6
LPS_SW_B: length 8
  TOP w0.127: v2(23.24,65.68) 23.67,66.11 23.68,66.11 23.69,66.12 24.53,66.12 25.54,67.14 25.55,67.14 25.87,67.46 25.87,69.07 R7403.2
  BOTTOM w0.127: v2(23.24,65.68) 22.91,65.68 Q7401.D 21.8,64.56 v1(20.99,64.56)
LPS_SW_C: length 9.8
  TOP w0.127: R7405.1 15.62,67.58 16.42,66.78 19.14,66.78 v1(19.68,67.33) 20.07,67.71 v2(21.72,67.71) 21.72,67.58 22.3,67 R7406.2
  BOTTOM w0.127: v2(21.72,67.71) 21.02,67.01 Q7401.G
LPS_SW_D: length 2.9
  TOP w0.127: v2(16.38,69.49) 16.26,69.49 v1(15.49,70.25) 15.49,69.41 R7405.2
  BOTTOM w0.127: v2(16.38,69.49) 16.32,69.55 Q7406.3
LVDS_VDD_EN_R: length 28.7
  TOP w0.102: RN5502.6 99.56,104.74 v2(99.75,104.92) 100,105.17 v1(100.33,105.17)
  BOTTOM w0.102: D5501.3 122.13,103.78 121.06,103.78 U5501.4 119.48,105.35 111.33,105.35 110.79,105.89 100.71,105.89 v2(99.75,104.92)
M2_PCIE_LED#: length 64.3
  TOP w0.127: v1(145.67,6.88) 145.67,7.38 v2(145.8,7.51)
  L4SGND w0.089: 174.12,20.95 174.77,21.6 SSD1.10
  L4SGND w0.127: v2(145.8,7.51) 147.38,5.92 170.75,5.92 174.12,9.3 174.12,20.95
  BOTTOM w0.127: D6401.2 131.51,12.02 131.28,11.79 131.28,10.32 131.23,10.26 131.23,9.92 131.65,9.49 132.41,9.49 R6405.2 133.44,8.34 133.44,7.16 133.88,6.71 145,6.71 v2(145.8,7.51)
M2_SSD_PEDET: length 129.3
  TOP w0.102: v2(160.15,90.7) 160.15,87.9 166.04,82.01 166.04,70.04 165.11,69.12 165.11,56.19 163.86,54.93 163.86,50.77 164.22,50.4 164.22,46.76 164.08,46.62 v2(164.08,45.48) ; v2(172.09,7.89) 171.45,7.89 AFTP6303.1 169.67,7.77 169.04,7.13 R6305.2 167.94,7.18 v2(168.91,8.15)
  L6 w0.102: v2(168.91,8.15) 168.91,10.18 167.54,11.56 167.54,13.68 168.56,14.71 169.02,14.71 170.61,16.3 170.61,16.91 170.61,16.92 170.61,17.86 171.31,18.55 171.31,26.35 173.53,28.57 173.53,30.57 172.06,32.05 172.06,37.25 167.16,42.16 167.16,42.97 166.9,43.23 166.7,43.23 164.9,45.03 164.54,45.03 v2(164.08,45.48)
  BOTTOM w0.076: 138.23,84.86 135.82,84.86 135.81,84.85 arc(135.72,84.83) 135.65,84.78 135.46,84.59 CPU1.CP10
  BOTTOM w0.102: v2(160.15,90.7) 159.18,89.73 151.99,89.73 150.11,87.85 146.72,87.85 144.87,86 141.59,86 141.36,86.23 139.6,86.23 138.23,84.86 ; v2(172.09,7.89) 172.09,6.95 172.19,6.85 SSD1.69
M_A_A0: length 103.3
  TOP w0.14: RN1203.3 45.74,32.66 v2(46.33,33.25)
  L4SGND w0.142: v2(46.33,33.25) 49.1,33.25 49.36,33.51 50.34,33.51 50.59,33.76 55.1,33.76 v2(55.54,34.19) 55.98,33.75 65.25,33.75 v2(65.69,34.19) 66.13,33.75 75.4,33.75 v2(75.84,34.19) 76.28,33.75 80.97,33.75 80.98,33.76 85.55,33.76 v2(85.99,34.19) 86.41,33.77 93.93,33.77 94.19,34.02 94.19,34.22 93.64,34.77 93.64,34.97 93.84,35.17 94.04,35.17 94.59,34.62 94.79,34.62 94.99,34.82 94.99,35.03 94.44,35.57 94.44,35.78 94.64,35.98 94.84,35.98 95.39,35.43 95.59,35.43 95.79,35.63 95.79,35.83 95.25,36.38 95.25,36.58 95.45,36.78 95.65,36.78 96.2,36.23 96.4,36.23 96.6,36.43 96.6,36.64 96.05,37.18 96.05,37.38 96.25,37.59 96.45,37.59 97,37.04 97.2,37.04 97.98,37.82 97.98,50.38 102.45,54.86 102.45,58.73 101.95,59.23 v2(101.8,59.23)
  BOTTOM w0.076: CPU1.AC37 103.97,67.42 103.97,66.45 104.22,66.2 104.22,64.2 103.55,63.53 103.55,63.37
  BOTTOM w0.14: RAM2.P3 76.53,34.94 75.84,34.25 v2(75.84,34.19) ; RAM4.P3 56.23,34.94 55.54,34.25 v2(55.54,34.19) ; RAM3.P3 66.38,34.94 65.69,34.25 v2(65.69,34.19) ; RAM1.P3 86.44,34.94 85.99,34.48 v2(85.99,34.19) ; 103.55,63.37 103.55,60.77 102.01,59.23 v2(101.8,59.23)
M_A_A1: length 98.3
  TOP w0.14: v2(49.76,35.07) 49.17,35.66 RN1205.4
  L6 w0.142: v2(49.76,35.07) 49.88,35.07 50.88,34.08 53.47,34.08 v2(53.93,34.54) 54.77,34.54 55.23,35 57.47,35 58.32,34.15 62.64,34.15 62.71,34.08 63.62,34.08 v2(64.08,34.54) 64.92,34.54 65.38,35 67.62,35 68.47,34.15 72.79,34.15 72.86,34.08 73.77,34.08 v2(74.23,34.54) 75.07,34.54 75.53,35 77.77,35 78.69,34.08 83.92,34.08 v2(84.38,34.54) 85.22,34.54 85.67,34.99 87.93,34.99 88.42,34.5 91.32,34.5 91.58,34.76 91.58,35.61 92.73,36.75 92.73,38.87 92.87,39.01 93.17,39.01 93.31,38.87 93.31,37.67 93.41,37.57 94.4,37.57 94.86,38.02 94.86,38.36 94.72,38.51 94.15,38.51 94,38.66 94,38.92 94.14,39.07 94.99,39.07 95.17,39.24 95.17,39.52 95.02,39.66 93.84,39.66 93.69,39.8 93.69,40.11 93.82,40.23 95.02,40.23 95.17,40.37 95.17,54.33 98.71,57.87 98.71,58.28 98.7,58.28 98.7,58.67 v2(99.14,59.11)
  BOTTOM w0.076: CPU1.AC36 104.13,68.19 104.29,67.9 104.29,67.9 104.39,67.7 104.39,67.44 104.13,67.18 104.13,66.52 104.41,66.25 104.41,64.15 103.84,63.58 103.84,63.02
  BOTTOM w0.14: v2(64.08,34.54) RAM3.P7 ; v2(99.14,59.11) 99.32,58.92 99.34,58.92 99.51,58.75 102.1,58.75 103.84,60.49 103.84,63.02 ; v2(53.93,34.54) RAM4.P7 ; v2(84.38,34.54) RAM1.P7 ; v2(74.23,34.54) RAM2.P7
M_A_A2: length 102.3
  TOP w0.14: RN1203.4 v2(45.62,33.25)
  L6 w0.142: v2(100.5,59.23) 100.5,56.46 96.01,51.97 96.01,37.25 95.86,37.11 95.44,37.11 95.29,36.97 95.29,36.68 95.44,36.54 95.86,36.54 96.01,36.4 96.01,35.79 95.64,35.42 95.43,35.42 94.57,36.28 94.37,36.28 94.17,36.08 94.17,35.88 95.03,35.02 95.03,34.82 94.83,34.61 94.63,34.61 93.76,35.48 93.56,35.48 93.36,35.28 93.36,35.08 94.23,34.21 94.23,34.01 93.97,33.76 93.36,33.76 93.22,33.9 93.22,34.34 93.08,34.48 92.79,34.48 92.65,34.34 92.65,33.9 92.51,33.76 87.08,33.76 v2(86.62,34.22) 86.62,34.17 86.21,33.76 86.17,33.76 85.9,33.49 78.34,33.49 78.07,33.76 76.92,33.76 v2(76.47,34.22) 76.47,34.17 75.79,33.49 72.62,33.49 72.55,33.56 68.12,33.56 67.92,33.76 66.78,33.76 v2(66.32,34.22) 66.32,34.17 65.64,33.49 62.47,33.49 62.4,33.56 57.97,33.56 57.77,33.76 56.62,33.76 v2(56.17,34.22) 56.17,34.17 55.49,33.49 48.29,33.49 48.07,33.71 46.08,33.71 v2(45.62,33.25)
  BOTTOM w0.076: CPU1.AC34 103.87,69.27 103.87,68.15 103.91,68.03 103.91,67.79 103.8,67.49 103.8,66.38 104.04,66.14 104.04,64.32 103.56,63.84
  BOTTOM w0.14: v2(86.62,34.22) 86.62,34.22 86.7,34.14 RAM1.R3 ; RAM2.R3 76.55,34.14 v2(76.47,34.22) ; v2(100.5,59.23) 101.64,60.38 102.41,60.38 103.29,61.27 103.29,63.58 103.56,63.84 ; RAM4.R3 56.25,34.14 56.17,34.22 v2(56.17,34.22) ; RAM3.R3 66.4,34.14 66.32,34.22 v2(66.32,34.22)
M_A_A3: length 103.9
  TOP w0.14: RN1206.3 45.74,35.07 v2(46.33,35.66)
  L4SGND w0.142: v2(99.16,57.84) 99.16,53.85 96.49,51.18 96.49,45.59 95.3,44.41 95.3,44.21 96.41,43.1 96.41,42.9 96.21,42.7 96.01,42.7 94.9,43.81 94.7,43.81 94.42,43.53 94.42,43.33 95.47,42.28 95.47,42.08 95.27,41.88 95.06,41.88 94.02,42.93 93.82,42.93 93.62,42.72 93.62,42.52 94.34,41.8 94.34,41.6 94.14,41.4 93.94,41.4 93.22,42.12 93.02,42.12 92.22,41.32 92.22,37.21 91.01,36 89.91,36 89.76,35.86 89.76,35.55 89.62,35.41 89.34,35.41 89.2,35.55 89.2,35.86 89.05,36 86.36,36 85.98,36.38 85.58,36.38 v2(85.14,35.94) 84.96,35.76 83.02,35.76 82.97,35.8 78.84,35.8 78.54,36.1 77.65,36.1 77.54,35.99 76.22,35.99 75.82,36.39 75.43,36.39 74.99,35.94 v2(74.99,35.94) 74.81,35.76 74.12,35.76 74.08,35.8 71.57,35.8 71.52,35.76 68.73,35.76 68.55,35.94 68.39,36.1 67.5,36.1 67.35,35.94 66.12,35.94 65.67,36.39 65.28,36.39 64.84,35.94 v2(64.84,35.94) 64.66,35.76 62.72,35.76 62.67,35.8 62.29,35.8 62.24,35.76 58.58,35.76 58.24,36.1 57.35,36.1 57.24,35.99 55.92,35.99 55.52,36.39 55.13,36.39 54.69,35.94 v2(54.69,35.94) 54.51,35.76 52.57,35.76 52.52,35.8 52.14,35.8 52.09,35.76 51.05,35.76 50.89,35.92 46.59,35.92 v2(46.33,35.66)
  BOTTOM w0.076: CPU1.AC35 104.45,68.57 104.45,67.94 104.56,67.74 104.56,67.37 104.3,67.11 104.3,66.59 104.58,66.31 104.58,64.07 104.17,63.66 104.17,63.33 104.17,63.33 104.17,63.28
  BOTTOM w0.14: v2(99.16,57.84) 101.71,57.84 104.14,60.27 104.14,63.25 104.17,63.28 ; RAM2.N7 74.79,35.74 v2(74.99,35.94) ; v2(64.84,35.94) 64.64,35.74 RAM3.N7 ; v2(54.69,35.94) 54.49,35.74 RAM4.N7 ; v2(85.14,35.94) 84.94,35.74 RAM1.N7
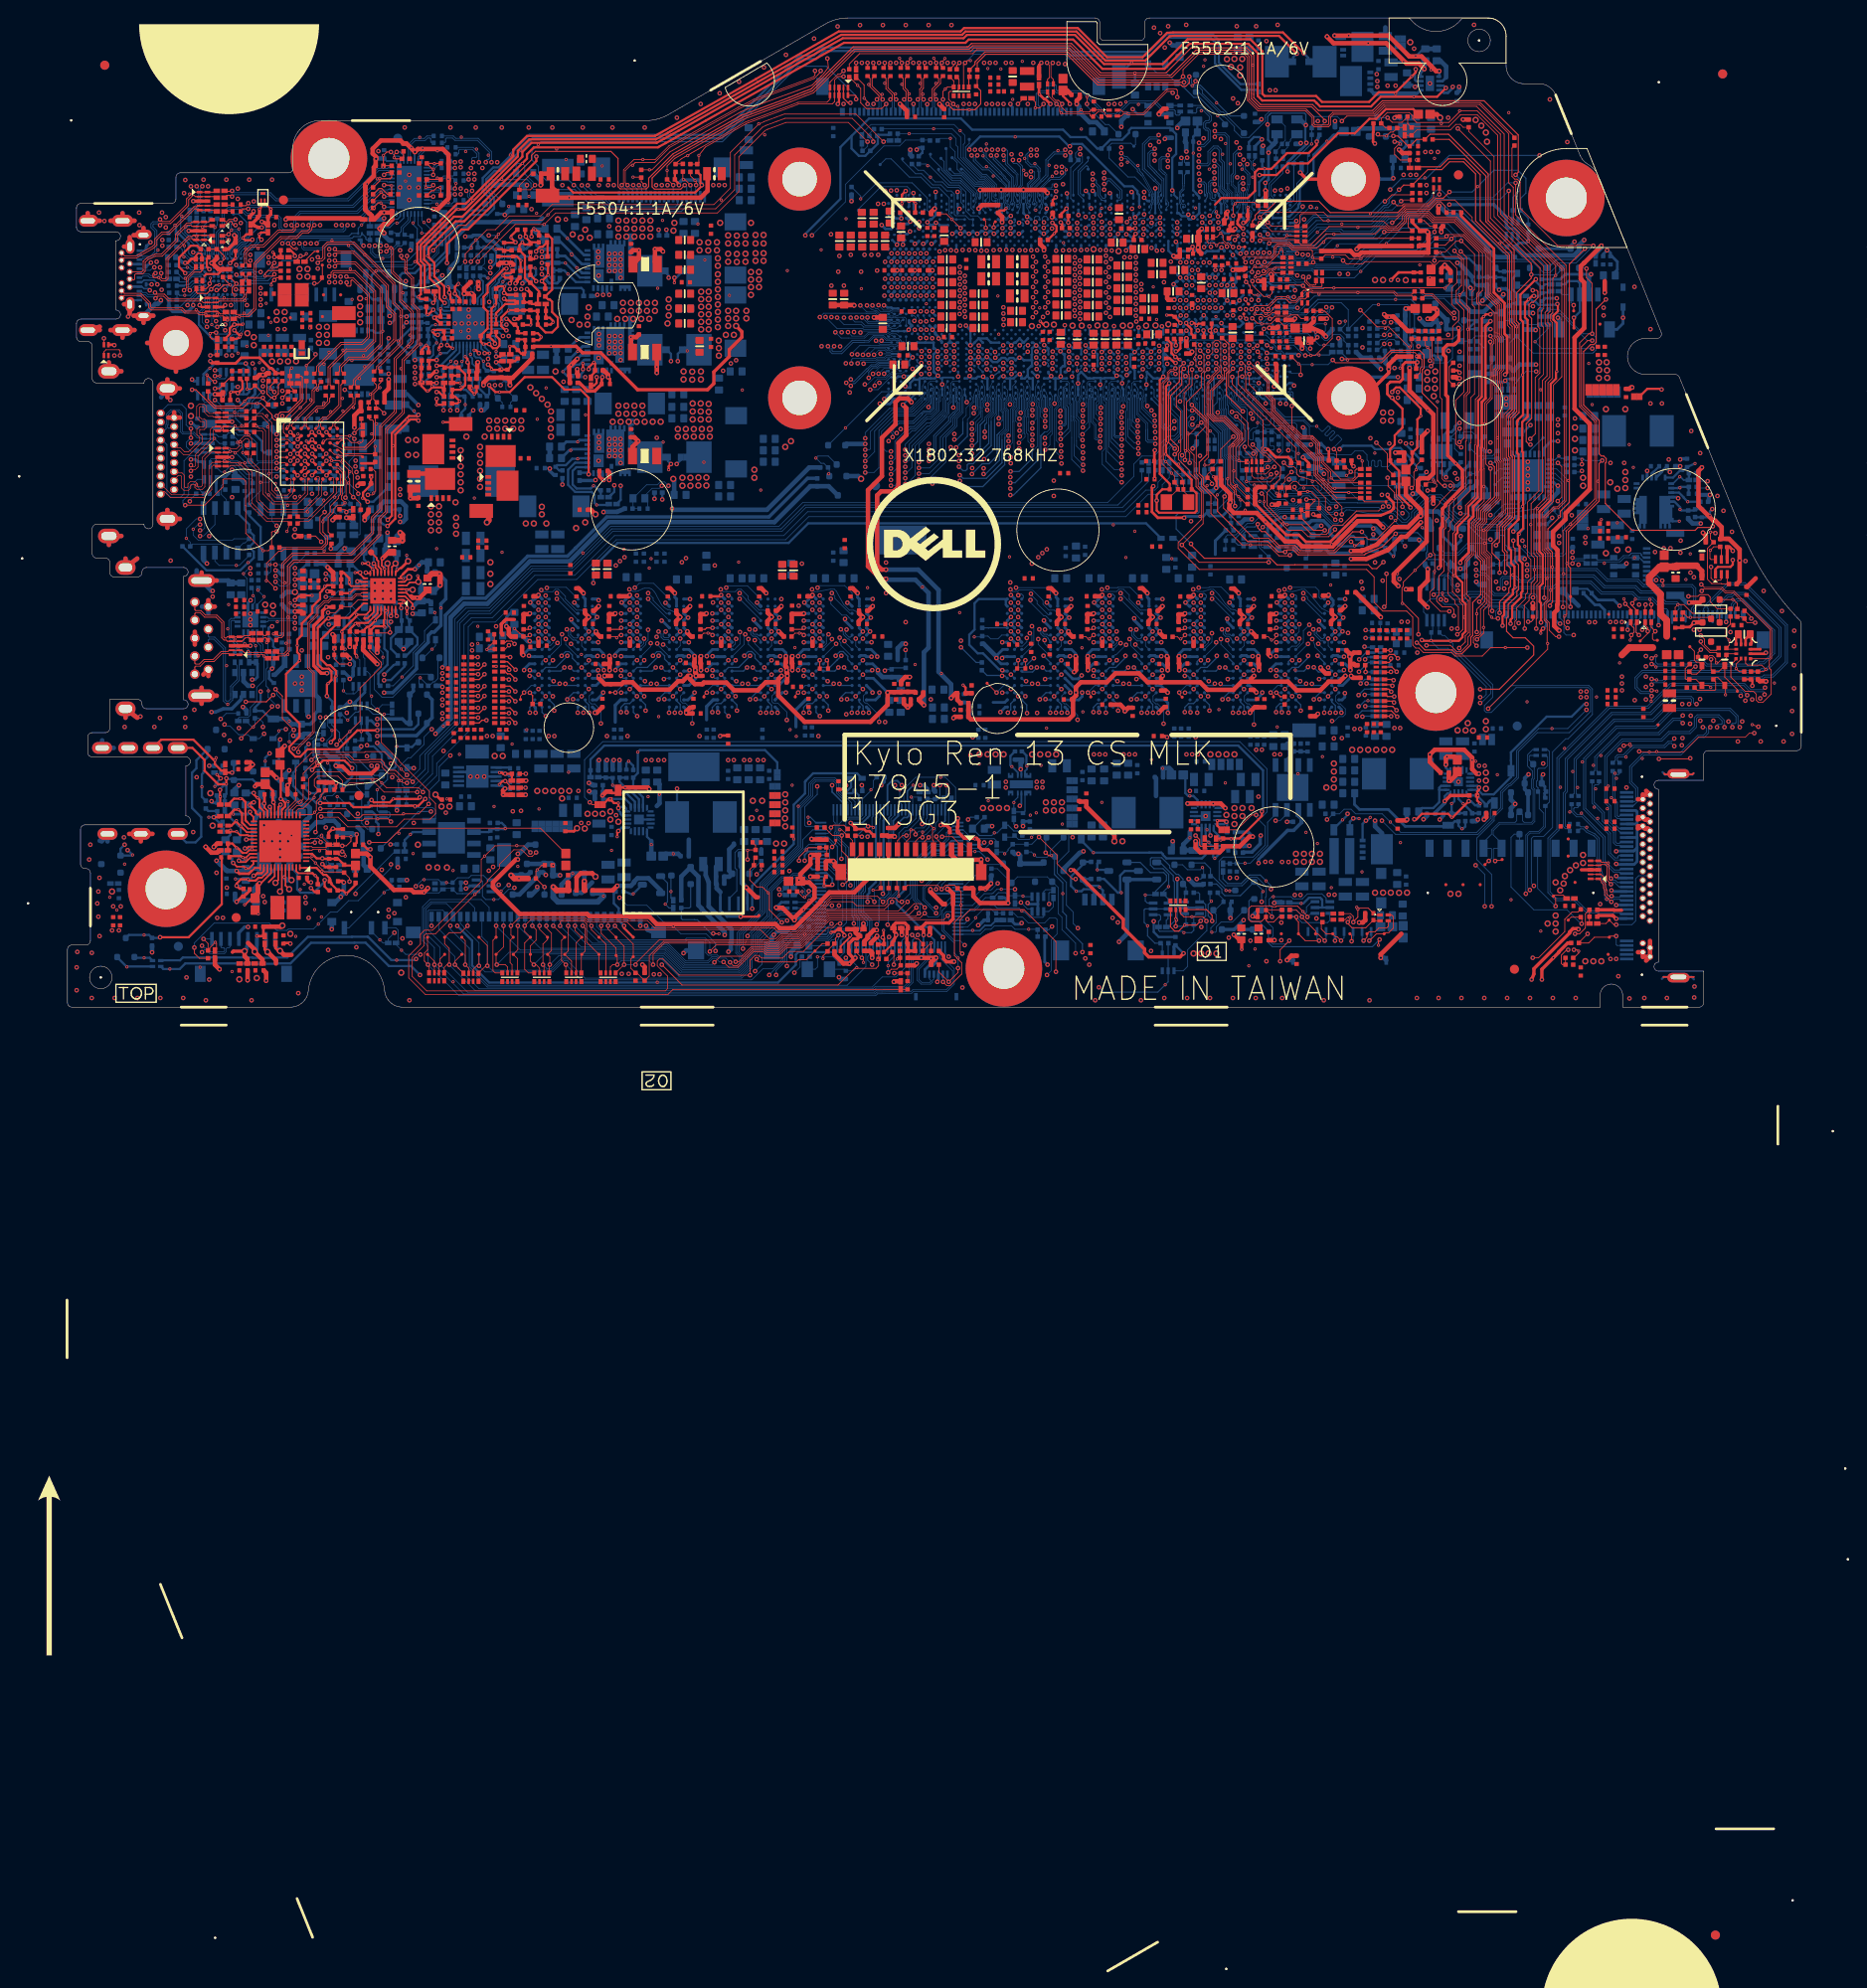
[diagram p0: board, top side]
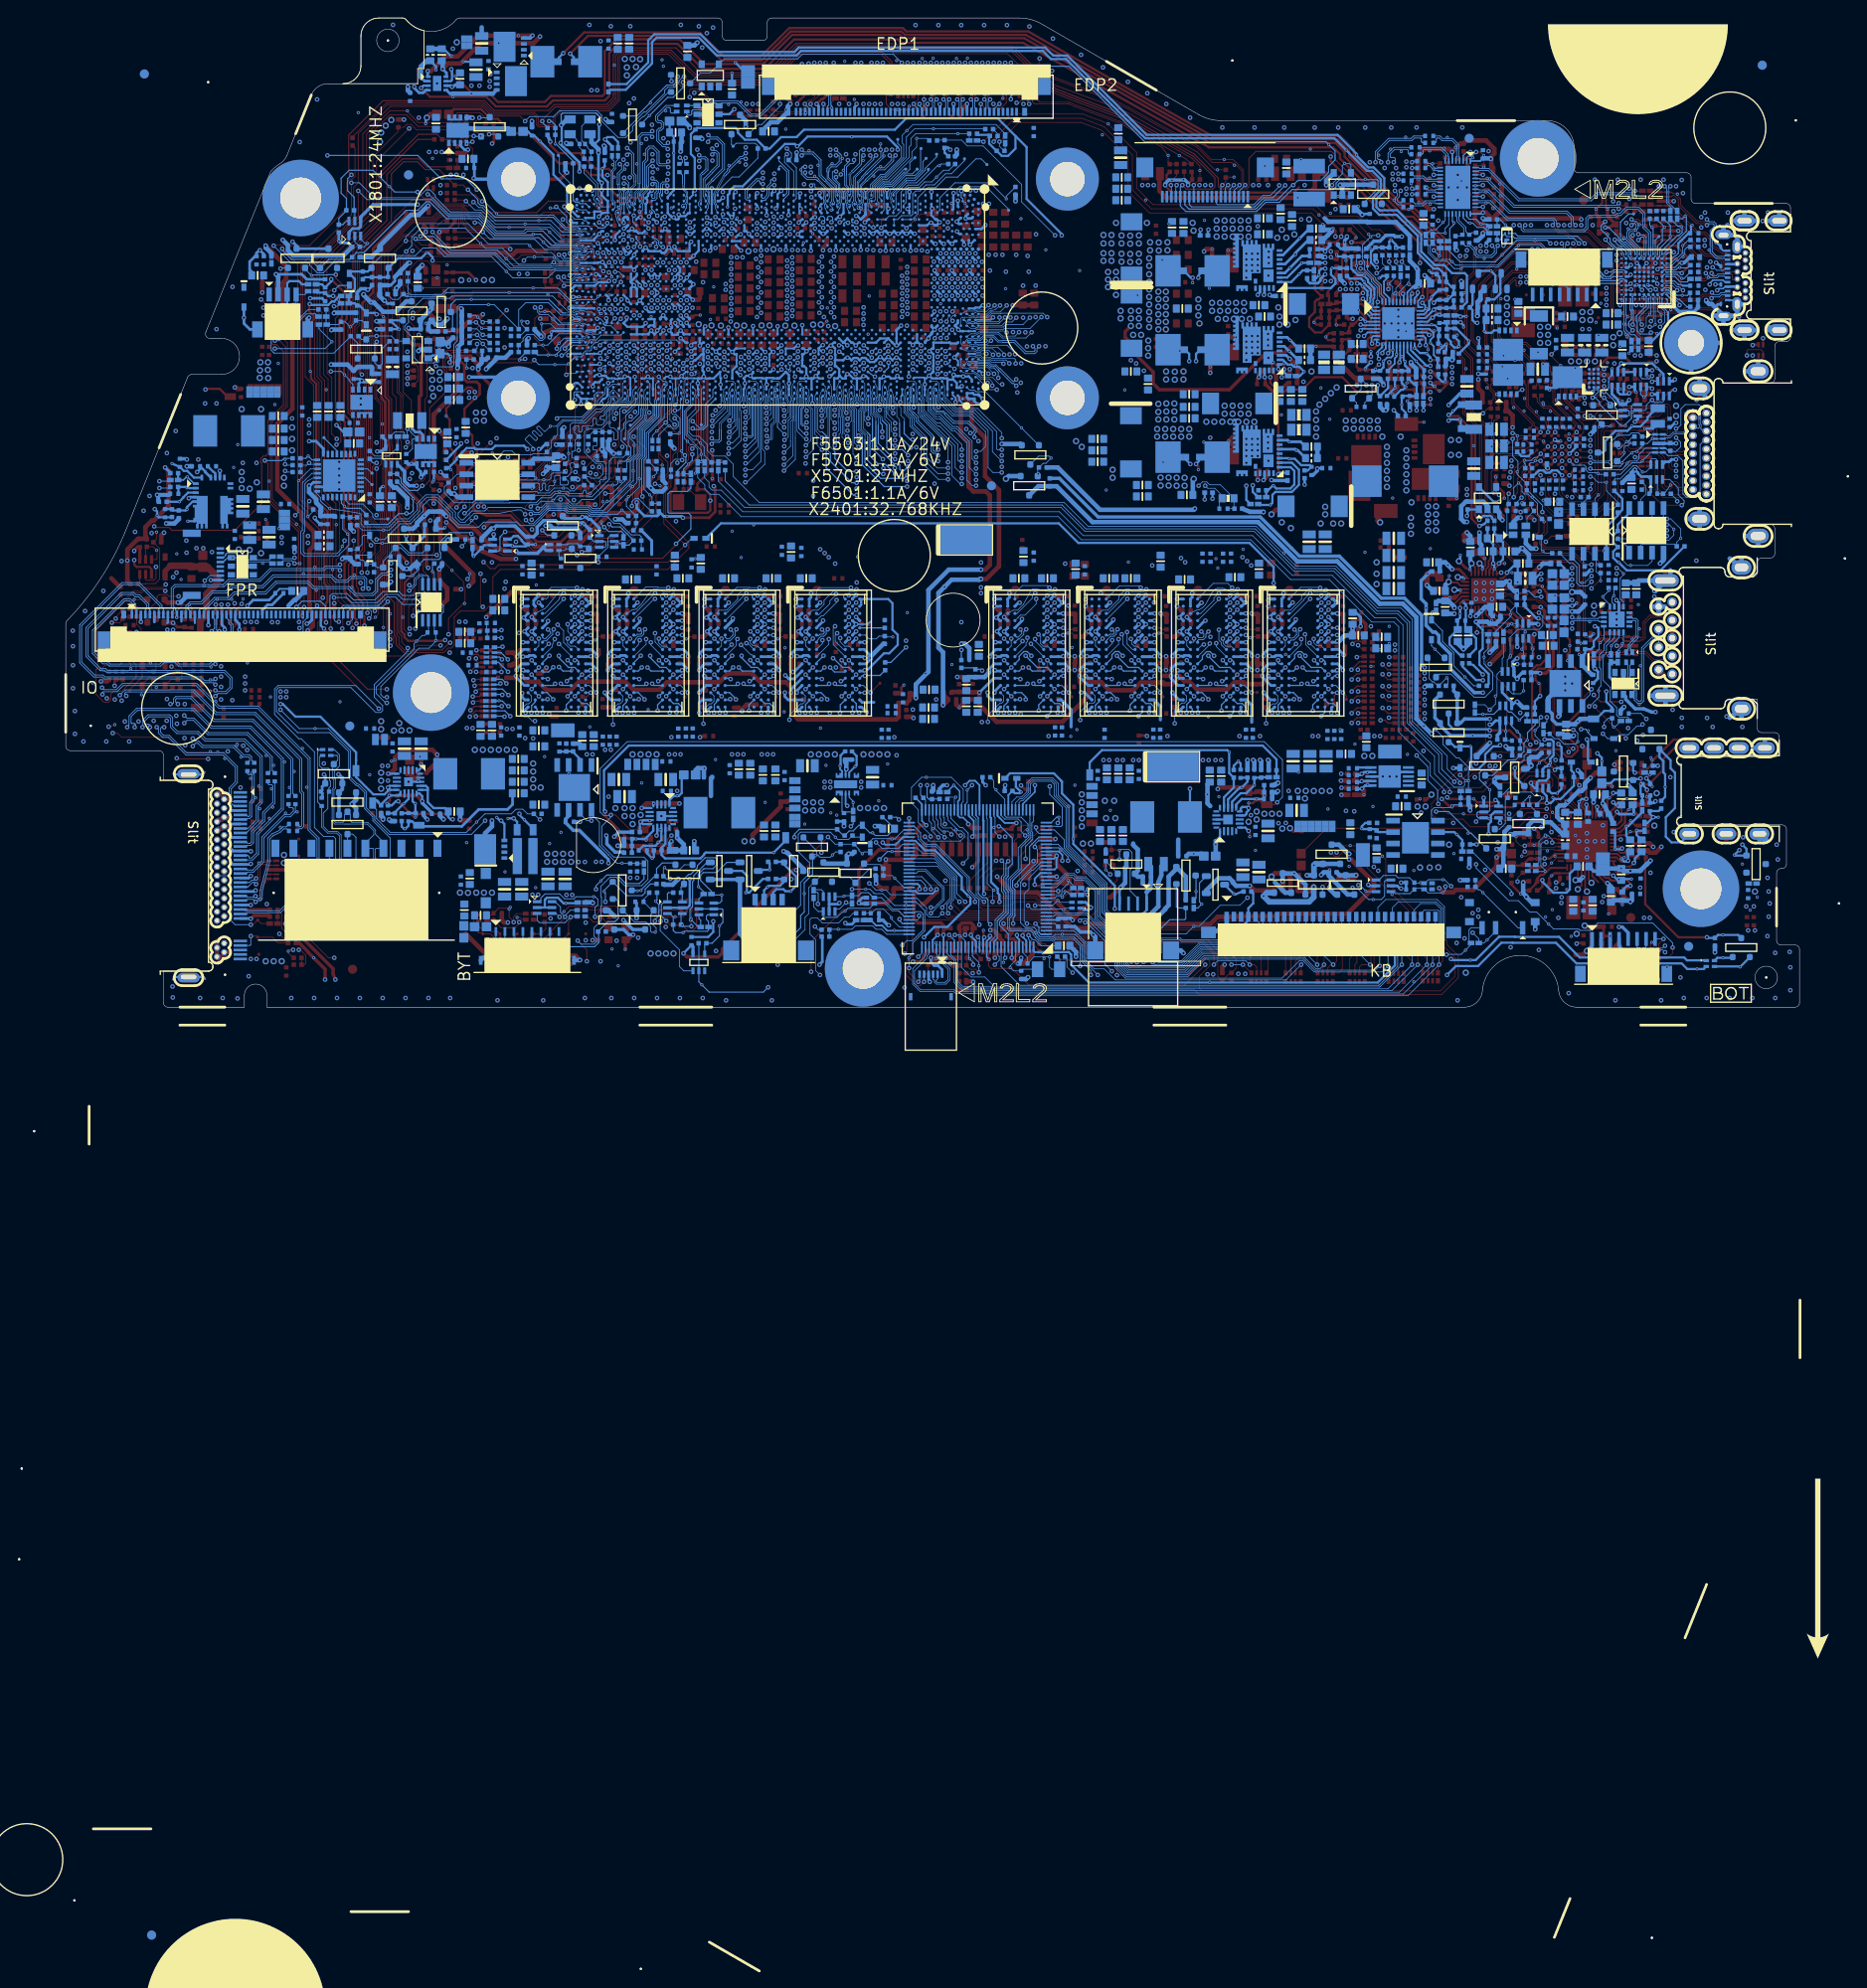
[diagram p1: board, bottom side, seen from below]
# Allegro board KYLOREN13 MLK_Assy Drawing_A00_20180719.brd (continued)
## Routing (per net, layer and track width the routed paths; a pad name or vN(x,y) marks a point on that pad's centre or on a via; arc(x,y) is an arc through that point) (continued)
M_A_A4: length 103
  TOP w0.14: RN1206.2 v2(45.62,34.57)
  L6 w0.142: v2(45.62,34.57) 46.25,35.2 46.64,35.2 47.36,35.92 50.37,35.92 50.52,35.76 52.09,35.76 52.14,35.8 53.62,35.8 53.95,35.47 54.88,35.47 55.32,35.92 v2(55.32,35.92) 55.55,35.69 56.44,35.69 56.55,35.8 58.12,35.8 58.17,35.76 62.24,35.76 62.29,35.8 62.67,35.8 63,35.47 65.03,35.47 65.47,35.92 v2(65.47,35.92) 65.7,35.69 66.59,35.69 66.7,35.8 68.27,35.8 68.32,35.76 72.39,35.76 72.44,35.8 72.82,35.8 73.15,35.47 75.18,35.47 75.62,35.92 v2(75.62,35.92) 75.85,35.69 76.74,35.69 76.85,35.8 78.42,35.8 78.75,35.48 82.26,35.48 82.59,35.8 82.97,35.8 83.3,35.47 85.33,35.47 85.77,35.92 v2(85.77,35.92) 85.97,35.73 86.92,35.73 87.03,35.84 90.6,35.84 91.86,37.11 91.86,40.72 92.78,41.63 94.26,41.63 94.4,41.77 94.4,44.26 94.26,44.4 93.31,44.4 93.17,44.54 93.17,44.83 93.31,44.97 94.26,44.97 94.4,45.11 94.4,45.4 94.26,45.54 93.31,45.54 93.17,45.68 93.17,45.97 93.31,46.11 94.26,46.11 94.4,46.25 94.4,49.97 94.26,50.11 93.24,50.11 93.1,50.26 93.1,50.54 93.24,50.68 94.26,50.68 94.4,50.83 94.4,54.64 97.99,58.22 97.99,60.52 98.13,60.67 98.43,60.67 v2(99.05,60.05)
  BOTTOM w0.076: 102.64,65.08 102.64,65.48 103.11,65.96 103.11,67.63 103.05,67.79 103.05,68.03 103.1,68.14 103.1,68.33 102.93,68.79 CPU1.AA35
  BOTTOM w0.14: 102.64,65.08 102.64,62.38 100.63,60.38 100.11,60.38 99.97,60.24 99.97,59.77 99.81,59.61 99.49,59.61 v2(99.05,60.05) ; v2(55.32,35.92) 55.51,35.74 RAM4.N3 ; v2(65.47,35.92) 65.66,35.74 RAM3.N3 ; v2(85.77,35.92) 85.96,35.74 RAM1.N3 ; RAM2.N3 75.81,35.74 v2(75.62,35.92)
M_A_A5: length 96.7
  TOP w0.14: v2(49.76,33.99) 49.17,34.57 RN1205.2
  L4SGND w0.142: v2(49.76,33.99) 49.96,34.19 51.73,34.19 51.85,34.07 52.66,34.07 52.7,34.11 v2(53.13,34.54) 53.6,34.07 54.12,34.07 54.73,34.68 56.36,34.68 56.63,34.41 56.63,34.37 56.93,34.07 62.81,34.07 62.85,34.11 v2(63.28,34.54) 63.75,34.07 64.27,34.07 64.88,34.68 66.51,34.68 66.78,34.41 66.78,34.37 67.09,34.06 72.95,34.06 v2(73.43,34.54) 73.9,34.07 74.42,34.07 75.03,34.68 76.66,34.68 76.93,34.41 76.93,34.37 77.23,34.07 83.11,34.07 83.15,34.11 v2(83.58,34.54) 84.03,34.09 84.59,34.09 85.17,34.67 86.81,34.67 87.08,34.39 87.08,34.39 87.39,34.08 92.23,34.08 97.62,39.48 97.62,50.53 102.08,54.99 102.08,55.38 101.93,55.52 100.82,55.52 100.68,55.66 100.68,56.05 100.82,56.19 101.95,56.19 102.1,56.33 102.1,56.61 101.95,56.76 100.77,56.76 100.63,56.9 100.63,57.18 100.77,57.33 101.95,57.33 102.1,57.47 102.1,57.75 101.95,57.89 101.3,57.89 101.16,58.04 101.16,63.96 101.97,64.77 v2(103.46,64.77)
  BOTTOM w0.076: v2(103.46,64.77) 103.87,65.18 103.87,65.26 103.88,65.27 103.88,65.59 103.87,65.6 103.87,65.7 103.88,65.71 103.88,66.06 103.87,66.06 103.87,66.08 103.64,66.31 103.64,67.52 103.75,67.82 103.75,68 103.58,68.46 CPU1.AB35
  BOTTOM w0.14: RAM1.P8 v2(83.58,34.54) ; RAM3.P8 v2(63.28,34.54) ; v2(73.43,34.54) RAM2.P8 ; RAM4.P8 v2(53.13,34.54)
M_A_A6: length 100.6
  TOP w0.14: RN1205.1 v2(49.05,33.99)
  L6 w0.142: v2(49.05,33.99) 49.51,34.45 49.95,34.45 50.62,33.78 54.43,33.78 55.33,34.68 56.98,34.68 v2(57.13,34.54) 57.41,34.54 58.08,33.86 62.52,33.86 62.59,33.78 64.58,33.78 65.48,34.68 67.13,34.68 v2(67.28,34.54) 67.56,34.54 68.23,33.86 72.67,33.86 72.74,33.78 74.73,33.78 75.63,34.68 77.28,34.68 v2(77.43,34.54) 77.71,34.54 78.46,33.78 84.88,33.78 85.78,34.68 87.43,34.68 v2(87.58,34.54) 87.97,34.14 91.71,34.14 92.57,35 92.57,35.2 92.29,35.48 92.29,35.68 92.49,35.88 92.7,35.88 92.98,35.6 93.18,35.6 93.49,35.92 93.49,36.09 93.11,36.47 93.11,36.86 93.44,37.19 93.8,37.19 94.18,36.81 94.38,36.81 95.62,38.05 95.62,52.09 96.72,53.19 96.72,53.39 95.83,54.29 95.83,54.49 96.03,54.69 96.23,54.69 97.12,53.8 97.32,53.8 97.53,54 97.53,54.2 96.63,55.09 96.63,55.29 96.83,55.49 97.04,55.49 97.93,54.6 98.13,54.6 98.33,54.8 98.33,55 97.44,55.9 97.44,56.1 97.64,56.3 97.84,56.3 98.73,55.4 98.93,55.4 99.14,55.61 99.14,55.81 98.24,56.7 98.24,56.9 98.44,57.1 98.64,57.1 99.54,56.21 99.74,56.21 99.99,56.46 99.99,60.38 v2(100.5,60.89)
  BOTTOM w0.076: CPU1.AA37 102.94,67.47 102.94,66.04 102.37,65.47 102.37,64.69
  BOTTOM w0.14: v2(87.58,34.54) RAM1.P2 ; v2(67.28,34.54) RAM3.P2 ; 102.37,64.69 102.37,62.64 100.62,60.89 v2(100.5,60.89) ; v2(57.13,34.54) RAM4.P2 ; RAM2.P2 v2(77.43,34.54)
M_A_A7: length 99.1
  TOP w0.14: RN1204.3 v2(49.05,32.66)
  L4SGND w0.142: 81.8,32.74 v2(81.8,32.72) ; 81.8,32.74 82.46,33.4 94.15,33.4 95.61,34.86 95.81,34.86 95.99,34.68 96.2,34.68 96.4,34.89 96.4,35.09 96.22,35.27 96.22,35.47 96.42,35.67 96.62,35.67 96.82,35.46 97.03,35.46 97.23,35.66 97.23,35.87 97.02,36.07 97.02,36.27 97.22,36.47 97.42,36.47 97.63,36.27 97.83,36.27 98.03,36.47 98.03,36.67 97.83,36.88 97.83,37.08 98.34,37.59 98.34,50.23 102.81,54.71 102.81,63.04 v2(101.92,63.93) ; 81.8,32.74 81.56,32.74 80.9,33.4 72.27,33.4 v2(71.65,32.77) 71.48,32.94 71.48,32.96 71.03,33.41 62.13,33.41 61.95,33.22 61.94,33.22 61.67,32.95 61.67,32.94 v2(61.5,32.77) 61.5,32.93 61.02,33.41 51.97,33.41 51.61,33.05 51.61,32.95 v2(51.37,32.72) 51.16,32.93 51.16,32.98 50.96,33.18 50.55,33.18 50.5,33.13 49.52,33.13 v2(49.05,32.66)
  BOTTOM w0.076: CPU1.AA36 102.83,68.17 102.67,67.84 102.61,67.78 102.57,67.7 102.57,67.69 102.56,67.69 102.56,67.43 102.77,67.22 102.77,66.49 102.77,66.49 102.77,66.11 102.15,65.49 102.15,64.93
  BOTTOM w0.14: v2(101.92,63.93) 101.92,64.7 102.15,64.93 ; RAM3.R8 62.47,33.73 61.92,33.73 61.5,33.32 v2(61.5,32.77) ; RAM2.R8 72.62,33.73 72.08,33.73 71.65,33.3 v2(71.65,32.77) ; v2(51.37,32.72) 51.37,33.32 51.78,33.73 52.32,33.73 RAM4.R8 ; v2(81.8,32.72) 81.83,32.72 81.83,32.72 81.8,32.75 81.8,33.32 82.22,33.73 82.77,33.73 RAM1.R8
M_A_A8: length 107.1
  TOP w0.14: v2(46.55,31.88) 46.05,31.88 45.74,31.57 RN1203.1
  L6 w0.142: v2(46.55,31.88) 46.7,32.02 49.95,32.02 50.1,31.88 53.59,31.88 55.92,32.59 56.5,33.18 57.52,33.18 57.97,32.74 v2(57.97,32.72) 57.97,32.7 58.41,32.25 58.79,32.25 58.84,32.29 62.61,32.29 63.11,32.8 63.49,32.8 63.81,32.48 65.96,32.48 66.65,33.18 67.67,33.18 68.12,32.74 v2(68.12,32.72) 68.12,32.7 68.52,32.29 68.53,32.29 68.56,32.26 68.94,32.26 68.97,32.29 72.62,32.29 73.13,32.8 73.64,32.8 74.01,32.44 76.06,32.44 76.8,33.18 77.82,33.18 78.27,32.74 v2(78.27,32.72) 78.27,32.7 78.71,32.25 79.1,32.25 79.55,32.7 80.4,32.7 80.85,32.25 82.86,32.25 83.41,32.8 83.79,32.8 84.11,32.48 85.71,32.48 86.41,33.18 87.97,33.18 88.42,32.74 v2(88.42,32.72) 88.42,32.71 88.86,32.26 89.25,32.26 89.54,32.54 92.3,32.54 92.58,32.82 93.2,32.82 93.47,32.54 93.77,32.54 94.04,32.82 94.34,32.82 94.61,32.54 94.97,32.54 96.82,34.39 96.82,50.64 97.27,51.1 97.27,51.3 97.02,51.54 97.02,51.74 97.23,51.94 97.43,51.94 97.67,51.7 97.87,51.7 98.07,51.9 98.07,52.1 97.78,52.4 97.78,52.6 97.98,52.8 98.18,52.8 98.48,52.51 98.68,52.51 98.88,52.71 98.88,52.91 98.58,53.2 98.58,53.4 98.78,53.6 98.99,53.6 99.28,53.31 99.48,53.31 99.68,53.51 99.68,53.71 99.39,54.01 99.39,54.21 99.59,54.41 99.79,54.41 100.08,54.11 100.29,54.11 100.49,54.32 100.49,54.52 100.24,54.76 100.24,54.96 100.44,55.16 100.65,55.16 100.89,54.92 101.09,54.92 101.34,55.17 101.34,60.74 101.49,60.88 v2(101.85,60.88)
  BOTTOM w0.076: 103.01,65.34 103.01,65.58 103.28,65.84 103.28,67.66 103.22,67.82 103.22,68 103.26,68.11 103.26,68.36 103.22,68.48 103.22,68.95 CPU1.AB34
  BOTTOM w0.14: v2(68.12,32.72) 68.09,32.75 68.09,33.64 67.68,34.04 RAM3.R2 ; v2(88.42,32.72) 88.42,33.17 88.41,33.18 88.41,33.46 87.98,33.88 RAM1.R2 ; v2(57.97,32.72) 57.94,32.75 57.94,33.57 57.53,33.98 RAM4.R2 ; 103.01,65.34 103.01,62.05 v2(101.85,60.88) ; RAM2.R2 77.83,33.95 78.24,33.54 78.24,32.75 v2(78.27,32.72)
M_A_A9: length 97.7
  TOP w0.14: RN1204.4 49.17,33.25 v2(49.76,32.66)
  L6 w0.142: v2(100.5,62.38) 101.21,63.09 101.21,63.98 101.59,64.36 102.13,64.36 102.38,64.11 102.38,63.07 100.95,61.64 100.95,56.38 96.39,51.82 96.39,35.61 94.09,33.31 88.26,33.31 88.12,33.45 86.27,33.45 85.76,32.94 v2(84.54,32.94) 84.28,33.2 78.22,33.2 77.94,33.47 76.68,33.47 76.16,32.94 v2(74.39,32.94) 74.13,33.2 72.5,33.2 72.43,33.27 68,33.27 67.79,33.47 66.53,33.47 66.01,32.94 v2(64.24,32.94) 63.98,33.2 62.35,33.2 62.28,33.27 57.85,33.27 57.64,33.47 56.38,33.47 55.86,32.94 v2(54.09,32.94) 53.85,33.19 50.29,33.19 v2(49.76,32.66)
  BOTTOM w0.076: 101.14,64.73 101.18,64.84 101.65,65.31 101.65,66.2 101.64,66.21 101.64,66.54 101.65,66.55 101.65,67.21 101.72,67.29 101.88,67.44 101.88,67.7 101.76,67.92 101.76,67.93 101.62,68.18 101.62,68.18 CPU1.W36
  BOTTOM w0.14: v2(84.54,32.94) 84.54,33.58 RAM1.R7 ; RAM3.R7 64.24,33.58 v2(64.24,32.94) ; RAM4.R7 54.09,33.58 v2(54.09,32.94) ; v2(100.5,62.38) 100.67,62.38 101.14,62.84 101.14,64.73 ; RAM2.R7 74.39,33.58 v2(74.39,32.94)
M_A_A10: length 97.2
  TOP w0.14: RN1202.1 48.63,37.29 48.89,37.03 49.2,37.03 49.76,36.47 v2(49.76,36.4)
  L4SGND w0.142: v2(103.09,70.89) 103.16,70.82 103.16,69.88 101.71,68.43 100.54,68.43 99.33,67.22 99.33,62.16 98.93,61.75 98.22,61.75 97.73,61.27 97.73,60.62 97.87,60.48 98.48,60.48 98.63,60.34 98.63,60.05 98.48,59.91 97.87,59.91 97.73,59.77 97.73,59.48 97.87,59.34 98.48,59.34 98.63,59.2 98.63,58.92 98.48,58.77 97.87,58.77 97.73,58.63 97.73,58.35 97.87,58.2 98.48,58.2 98.63,58.06 98.63,57.78 98.48,57.64 97.87,57.64 97.73,57.49 97.73,57.21 97.87,57.07 98.48,57.07 98.63,56.92 98.63,56.64 98.48,56.5 97.87,56.5 97.73,56.35 97.73,56.07 97.87,55.93 98.48,55.93 98.63,55.79 98.63,55.5 98.48,55.36 97.87,55.36 97.73,55.22 97.73,54.93 97.87,54.79 98.43,54.79 98.57,54.65 98.57,54.36 98.43,54.22 97.87,54.22 97.73,54.08 97.73,52.93 96.11,51.31 96.11,46.64 91.84,42.36 91.84,37.72 90.57,36.45 v2(86.57,36.45) 86.34,36.68 83.92,36.68 83.32,36.08 78.97,36.08 78.87,36.18 78.6,36.45 v2(76.42,36.45) 76.19,36.68 73.77,36.68 73.18,36.1 71.45,36.1 71.4,36.05 68.85,36.05 68.45,36.45 v2(66.27,36.45) 66.04,36.68 63.62,36.68 63.03,36.1 61.3,36.1 61.25,36.05 58.7,36.05 58.3,36.45 v2(56.12,36.45) 55.89,36.68 53.47,36.68 52.88,36.1 51.32,36.1 51.02,36.4 v2(49.76,36.4)
  BOTTOM w0.14: RAM1.M3 86.66,36.54 v2(86.57,36.45) ; v2(56.12,36.45) 56.21,36.54 RAM4.M3 ; v2(66.27,36.45) 66.36,36.54 RAM3.M3 ; RAM2.M3 76.51,36.54 v2(76.42,36.45) ; CPU1.Y31 v2(103.09,70.89)
M_A_A11: length 101.3
  TOP w0.14: RN1203.2 v2(45.62,32.16)
  L6 w0.142: v2(87.78,32.72) 87.78,32.71 ; 87.78,32.71 87.8,32.69 88.5,31.99 89.4,31.99 89.57,32.16 95.58,32.16 97.17,33.76 97.17,50.5 101.7,55.02 101.7,58.46 102.35,59.11 102.35,61.39 102.99,62.03 102.99,64.29 102.39,64.89 102.39,65.19 103.72,66.51 103.72,66.71 103.43,66.99 103.23,66.99 102.59,66.35 v2(102.2,66.35) ; 87.78,32.71 87.78,32.7 86.96,31.87 80.82,31.87 80.28,32.41 79.67,32.41 79.22,31.96 78.37,31.96 77.8,32.52 77.8,32.54 77.63,32.71 ; 77.63,32.71 77.63,32.7 76.81,31.87 70.19,31.87 70.18,31.88 69.98,31.88 69.88,31.99 69.09,31.99 69.06,31.96 68.22,31.96 67.48,32.69 67.48,32.7 ; 77.63,32.71 v2(77.63,32.72) ; 67.48,32.7 66.66,31.87 59.84,31.87 59.73,31.99 58.94,31.99 58.91,31.96 58.08,31.96 57.78,32.26 57.78,32.26 57.51,32.53 57.51,32.53 57.33,32.71 ; 67.48,32.7 v2(67.48,32.72) ; 57.33,32.71 v2(57.33,32.72) ; 57.33,32.71 57.15,32.53 57.15,32.53 56.88,32.26 56.88,32.26 55.73,31.11 46.67,31.11 v2(45.62,32.16)
  BOTTOM w0.076: CPU1.W34 101.62,69.53 101.92,68.91 101.92,67.96 102.04,67.74 102.04,67.38 102.03,67.37 101.81,67.15 101.81,66.73 v2(102.2,66.35)
  BOTTOM w0.14: v2(77.63,32.72) 77.63,33.14 RAM2.T2 ; v2(67.48,32.72) 67.48,33.14 RAM3.T2 ; v2(57.33,32.72) 57.33,33.14 RAM4.T2 ; RAM1.T2 v2(87.78,32.72)
M_A_A12: length 99.2
  TOP w0.14: RN1206.4 v2(45.62,35.66)
  L6 w0.142: v2(99.05,61.32) 99.05,61.52 98.91,61.66 97.77,61.66 97.63,61.52 97.63,58.44 94.02,54.83 94.02,51.42 93.86,51.26 92.89,51.26 92.74,51.12 92.74,49.82 92.99,49.57 93.75,49.57 93.9,49.43 93.9,48.91 93.75,48.77 93.49,48.77 93.34,48.63 93.34,48.34 93.49,48.2 93.86,48.2 94.01,48.06 94.01,46.74 93.86,46.6 92.89,46.6 92.74,46.45 92.74,43.77 92.97,43.54 93.74,43.54 93.97,43.31 93.97,42.52 93.67,42.22 92.65,42.22 91.46,41.02 91.46,38.65 91.32,38.51 90.83,38.51 90.69,38.36 90.69,38.08 90.83,37.94 91.32,37.94 91.46,37.8 91.46,37.29 90.37,36.2 90.01,36.2 89.87,36.34 89.87,36.79 89.72,36.93 89.44,36.93 89.3,36.79 89.3,36.34 89.16,36.2 86.98,36.2 86.78,36 86.37,36 85.98,36.39 84.64,36.39 v2(84.47,36.22) 84.34,36.1 82.47,36.1 82.42,36.05 78.66,36.05 78.62,36.1 76.73,36.1 76.62,35.99 76.23,35.99 75.82,36.4 74.5,36.4 v2(74.32,36.22) 74.19,36.1 72.32,36.1 72.27,36.05 68.51,36.05 68.47,36.1 66.58,36.1 66.47,35.99 66.08,35.99 65.67,36.4 64.35,36.4 v2(64.17,36.22) 64.04,36.1 62.17,36.1 62.12,36.05 58.29,36.05 57.89,36.45 56.78,36.45 56.32,35.99 55.93,35.99 55.52,36.4 54.2,36.4 v2(54.02,36.22) 53.89,36.1 52.02,36.1 51.97,36.05 51.03,36.05 50.22,36.86 46.86,36.86 46.52,36.52 46.48,36.52 v2(45.62,35.66)
  BOTTOM w0.076: 101.9,65.18 101.95,65.23 101.95,65.53 102.61,66.19 102.61,67.16 102.4,67.37 102.4,67.73 102.4,67.73 102.4,67.75 102.48,67.88 102.49,67.9 102.52,67.94 102.52,68.88 102.83,69.53 CPU1.AA34
  BOTTOM w0.14: RAM1.M7 v2(84.47,36.22) ; 101.9,65.18 101.42,64.69 101.42,62.21 101.16,61.95 99.69,61.95 v2(99.05,61.32) ; RAM3.M7 64,36.22 v2(64.17,36.22) ; v2(74.32,36.22) 74.15,36.22 RAM2.M7 ; RAM4.M7 53.85,36.22 v2(54.02,36.22)
M_A_A13: length 96.8
  TOP w0.14: v2(49.76,31.57) 49.17,32.16 RN1204.2
  L4SGND w0.142: v2(104.9,70.96) 104.47,70.52 104.47,69.83 103.98,69.34 103.98,64.06 103.19,63.27 103.19,54.59 98.7,50.08 98.7,36.12 94.84,32.26 89.66,32.26 89.42,32.01 83.92,32.01 v2(83.6,32.33) 83.41,32.33 83.03,31.96 80.69,31.96 80.24,32.41 79.67,32.41 79.22,31.96 73.83,31.96 v2(73.45,32.33) 73.12,32 69.11,32 69.06,31.96 63.68,31.96 v2(63.3,32.33) 62.97,32 58.96,32 58.91,31.96 53.53,31.96 v2(53.15,32.33) 52.59,31.78 50.41,31.78 50.28,31.65 49.84,31.65 v2(49.76,31.57)
  BOTTOM w0.14: CPU1.AC32 v2(104.9,70.96) ; RAM1.T8 83.18,32.76 v2(83.6,32.33) ; v2(63.3,32.33) 62.88,32.76 RAM3.T8 ; v2(73.45,32.33) 73.03,32.76 RAM2.T8 ; RAM4.T8 52.73,32.76 v2(53.15,32.33)
M_A_A14: length 99.5
  TOP w0.14: RN1202.2 48.88,37.88 49.08,37.68 v2(49.08,37.49)
  L4SGND w0.142: v2(49.08,37.49) 49.57,37.99 51.96,37.99 52.67,37.28 56.67,37.28 v2(57.13,37.74) 57.3,37.91 62.19,37.91 62.82,37.28 66.82,37.28 v2(67.28,37.74) 67.45,37.91 72.34,37.91 72.97,37.28 76.97,37.28 v2(77.43,37.74) 77.6,37.91 82.49,37.91 83.12,37.28 87.12,37.28 v2(87.58,37.74) 87.79,37.95 90,37.95 91.36,39.31 91.36,42.42 91.47,42.54 91.47,42.74 91.03,43.18 91.03,43.38 91.23,43.59 91.43,43.59 91.88,43.14 92.08,43.14 92.28,43.34 92.28,43.54 91.83,43.99 91.83,44.19 92.03,44.39 92.23,44.39 92.68,43.94 92.88,43.94 93.08,44.15 93.08,44.35 92.64,44.79 92.64,44.99 92.84,45.2 93.04,45.2 93.49,44.75 93.69,44.75 93.89,44.95 93.89,45.15 93.44,45.6 93.44,45.8 93.64,46 93.84,46 94.29,45.55 94.49,45.55 94.69,45.75 94.69,45.96 94.25,46.4 94.25,46.6 94.45,46.81 94.65,46.8 95.1,46.36 95.3,46.36 95.75,46.81 95.75,47.47 95.61,47.61 95,47.61 94.86,47.75 94.86,48.04 95,48.18 95.61,48.18 95.75,48.32 95.75,48.61 95.61,48.75 95,48.75 94.86,48.89 94.86,49.18 95,49.32 95.61,49.32 95.75,49.46 95.75,49.75 95.61,49.89 95,49.89 94.86,50.03 94.86,50.31 95,50.46 95.61,50.46 95.75,50.6 95.75,51.46 97.37,53.07 97.37,62.04 97.97,62.64 98.72,62.64 99.03,62.95 99.03,67.24 100.9,69.11 101.41,69.11 102.23,69.93 102.23,70.26 102.61,70.64 102.61,71.01 103.18,71.58 v2(103.98,71.58)
  BOTTOM w0.14: RAM2.L2 v2(77.43,37.74) ; v2(57.13,37.74) RAM4.L2 ; v2(67.28,37.74) RAM3.L2 ; CPU1.AC31 v2(103.98,71.58) ; v2(87.58,37.74) RAM1.L2
M_A_A15: length 99.3
  TOP w0.14: RN1207.2 v2(45.62,36.99)
  L6 w0.142: v2(102.74,70.05) 102.74,68.93 102.88,68.78 103.53,68.78 103.68,68.64 103.68,68.19 103.53,68.05 102.16,68.05 102.01,68.19 102.01,69.02 101.87,69.16 101.59,69.16 101.45,69.02 101.45,68.28 101.21,68.05 100.73,68.05 100.55,67.87 100.55,67.11 100.22,66.78 100.22,66.02 100.01,65.81 99.81,65.81 99.35,66.26 99.15,66.26 98.95,66.06 98.95,65.86 99.41,65.4 99.41,65.2 99.21,65 99.01,65 98.55,65.46 98.35,65.46 98.14,65.26 98.14,65.06 98.6,64.6 98.6,64.4 98.4,64.2 98.2,64.2 97.74,64.66 97.54,64.66 97.34,64.45 97.34,64.25 97.8,63.79 97.8,63.59 97.23,63.02 97.23,58.59 93.64,55 93.64,52.55 92.39,51.3 92.39,49.37 92.86,48.89 92.86,47.87 92.39,47.39 92.39,42.81 91,41.43 91,39.33 90.16,38.49 89.64,38.49 89.24,38.09 87.92,38.09 87.81,38.19 87.39,38.19 86.47,37.28 86.27,37.28 85.97,36.98 84.18,36.98 84.15,36.95 v2(82.78,36.95) 82.78,37.14 82.01,37.91 79.04,37.91 78.74,37.61 77.95,37.61 77.62,37.28 76.12,37.28 75.82,36.98 74.03,36.98 74,36.95 v2(72.63,36.95) 72.63,37.14 71.86,37.91 68.85,37.91 68.44,37.49 67.69,37.49 67.47,37.28 65.97,37.28 65.67,36.98 62.52,36.98 v2(62.48,36.95) 62.48,37.14 61.71,37.91 58.8,37.91 58.8,37.91 58.62,37.91 58.18,37.47 57.51,37.47 57.32,37.28 55.82,37.28 55.52,36.98 52.37,36.98 v2(52.33,36.95) 52.33,37.14 51.52,37.95 50.22,37.95 50.22,37.95 46.86,37.95 46.52,37.61 46.25,37.61 v2(45.62,36.99)
  BOTTOM w0.14: v2(72.63,36.95) 73.03,36.55 RAM2.M8 ; v2(62.48,36.95) 62.51,36.91 62.51,36.9 RAM3.M8 ; RAM4.M8 52.36,36.9 52.36,36.91 v2(52.33,36.95) ; RAM1.M8 82.81,36.9 82.81,36.91 v2(82.78,36.95) ; CPU1.AB32 v2(102.74,70.05)
M_A_A16: length 108.3
  TOP w0.14: R1211.1 v2(45.58,38.89)
  L4SGND w0.142: v2(102.15,70.87) 101.77,70.48 101.57,70.48 96.21,65.12 96.21,63.93 96.59,63.55 96.59,55.67 90.98,50.06 90.97,50.06 89.84,48.94 88.78,48.94 88.64,48.79 88.64,48.51 88.78,48.37 89.84,48.37 89.99,48.22 89.99,47.94 89.84,47.8 88.78,47.8 88.64,47.66 88.64,47.37 88.78,47.23 89.84,47.23 89.99,47.09 89.99,46.8 89.84,46.66 88.78,46.66 88.64,46.52 88.64,46.23 88.78,46.09 89.84,46.09 89.99,45.95 89.99,44.12 89.83,43.96 89.83,40.39 88.86,39.42 88.37,39.42 88.21,39.59 88.21,40.3 88.06,40.44 87.78,40.44 87.64,40.3 87.64,39.56 87.5,39.42 86.13,39.42 85.99,39.28 v2(85.99,39.04) 85.04,39.99 76.79,39.99 v2(75.84,39.04) 75.84,39.06 74.91,39.99 66.64,39.99 v2(65.69,39.04) 65.69,39.06 64.76,39.99 56.49,39.99 v2(55.54,39.04) 55.54,39.06 54.61,39.99 49.96,39.99 49.71,39.73 46.43,39.73 v2(45.58,38.89)
  BOTTOM w0.14: RAM1.L8 83.58,37.74 84.69,37.74 85.53,38.58 85.54,38.58 85.81,38.85 85.81,38.86 v2(85.99,39.04) ; v2(75.84,39.04) 75.84,39.01 74.58,37.74 73.43,37.74 RAM2.L8 ; RAM3.L8 63.28,37.74 64.43,37.74 65.69,39.01 v2(65.69,39.04) ; v2(55.54,39.04) 55.54,39.02 54.26,37.74 53.13,37.74 RAM4.L8 ; CPU1.Y32 v2(102.15,70.87)
M_A_ACT_N: length 103.7
  TOP w0.14: v2(46.33,38.08) 45.74,37.49 RN1207.3
  L2SGND w0.089: v2(98.75,62.18) 98.04,61.47 98.04,57.91 95.57,55.45 95.57,52.92 95.66,52.83 96.05,52.83 96.14,52.74 96.14,52.56 96.05,52.47 95.66,52.47 95.57,52.38 95.57,52.2 95.66,52.12 96.05,52.12 96.14,52.03 96.14,51.85 96.05,51.76 95.66,51.76 95.57,51.67 95.57,51.49 95.66,51.4 96.05,51.4 96.14,51.32 96.14,51.14 96.05,51.05 95.66,51.05 95.57,50.96 95.57,50.78 95.66,50.69 96.05,50.69 96.14,50.6 96.14,50.43 96.05,50.34 95.66,50.34 95.57,50.25 95.57,50.07 95.66,49.98 96.05,49.98 96.14,49.89 96.14,49.72 96.05,49.63 95.66,49.63 95.57,49.54 95.57,49.36 95.66,49.27 96.05,49.27 96.14,49.18 96.14,49 96.05,48.92 95.66,48.92 95.57,48.83 95.57,48.65 95.66,48.56 96.05,48.56 96.14,48.47 96.14,48.29 96.05,48.2 95.66,48.2 95.57,48.11 95.57,47.94 95.66,47.85 96.05,47.85 96.14,47.76 96.14,47.58 96.05,47.49 95.66,47.49 95.57,47.4 95.57,47.23 95.66,47.14 96.05,47.14 96.14,47.05 96.14,46.87 96.05,46.78 95.66,46.78 95.57,46.69 95.57,46.51 95.66,46.43 96.05,46.43 96.14,46.34 96.14,46.16 96.05,46.07 95.66,46.07 95.57,45.98 95.57,45.8 95.66,45.71 96.05,45.71 96.14,45.63 96.14,45.45 96.05,45.36 95.66,45.36 95.57,45.27 95.57,45.09 95.66,45 95.75,45 95.83,44.91 95.83,44.79 90.42,39.37 88.93,39.37 88.84,39.28 88.84,39.05 88.75,38.96 88.57,38.96 88.48,39.05 88.48,39.26 88.39,39.35 87.95,39.35 87.87,39.26 87.87,38.29 87.78,38.2 87.6,38.2 87.51,38.29 87.51,39.26 87.42,39.35 87.23,39.35 87.14,39.26 87.14,38.71 87.03,38.6 86.16,38.6 86.07,38.51 86.07,38.33 86.16,38.25 87.05,38.25 87.14,38.16 87.14,37.87 87.01,37.74 v2(86.29,37.74)
  L6 w0.142: v2(46.33,38.08) 46.59,38.33 50.25,38.33 50.34,38.24 51.87,38.24 51.9,38.2 52.83,37.28 55.4,37.28 55.84,37.72 v2(55.84,37.74) 56.47,37.74 57.01,38.28 57.54,38.28 57.74,38.08 58.12,38.08 58.25,38.2 61.99,38.2 62.92,37.28 65.55,37.28 66,37.72 v2(66,37.74) 66.62,37.74 67.11,38.23 67.63,38.23 67.96,37.9 68.34,37.9 68.65,38.2 72.08,38.2 73,37.28 75.7,37.28 76.14,37.72 v2(76.14,37.74) 76.77,37.74 77.29,38.25 77.64,38.25 77.89,38 78.53,38 78.73,38.2 82.26,38.2 83.19,37.28 85.85,37.28 86.29,37.72 v2(86.29,37.74)
  BOTTOM w0.076: CPU1.V35 100.86,68.46 100.7,68.01 100.7,67.82 100.74,67.7 100.74,67.23 100.3,66.79 100.3,65.6 100,65.3 100,64.86
  BOTTOM w0.14: RAM2.L3 76.54,37.34 v2(76.14,37.74) ; RAM3.L3 66.39,37.34 v2(66,37.74) ; v2(86.29,37.74) 86.69,37.34 RAM1.L3 ; RAM4.L3 56.24,37.34 v2(55.84,37.74) ; 100,64.86 100,63.43 v2(98.75,62.18)
M_A_ALERT_N: length 87.4
  TOP w0.14: v2(51.37,34.94) 51.68,34.63 R1208.1
  L2SGND w0.089: v2(81.82,34.94) 81.85,34.91 83.3,34.91 83.39,35 87.04,35 88,35.97 90.06,35.97 94.32,40.22 94.32,40.35 93.84,40.82 93.84,40.95 93.97,41.07 94.09,41.07 94.57,40.6 94.69,40.6 94.82,40.72 94.82,40.85 94.34,41.33 94.34,41.45 94.47,41.58 94.59,41.58 95.07,41.1 95.2,41.1 95.32,41.23 95.32,41.35 94.85,41.83 94.85,41.95 94.97,42.08 95.1,42.08 95.57,41.6 95.7,41.6 95.82,41.73 95.82,41.86 95.35,42.33 95.35,42.46 95.47,42.58 95.6,42.58 96.08,42.11 96.2,42.11 96.33,42.23 96.33,42.36 96.1,42.58 96.1,42.71 96.23,42.83 96.36,42.83 96.58,42.61 96.7,42.61 97.5,43.41 97.5,55.17 99.94,57.61 99.94,63.04 v2(100.5,63.6)
  L4SGND w0.142: v2(51.37,34.94) 52.07,34.94 52.14,34.88 52.52,34.88 52.65,35 57.61,35 58.13,34.49 61.08,34.49 61.52,34.93 v2(61.52,34.94) 62.22,34.94 62.29,34.88 62.67,34.88 62.8,35 67.76,35 68.28,34.49 70.84,34.49 71.23,34.49 71.5,34.76 71.5,34.76 71.67,34.93 v2(71.67,34.94) 72.37,34.94 72.44,34.88 72.82,34.88 72.95,35 77.91,35 78.45,34.46 81.35,34.46 81.37,34.49 81.38,34.49 81.65,34.76 81.65,34.77 v2(81.82,34.94)
  BOTTOM w0.076: v2(100.5,63.6) 100.93,64.03 100.93,65.02 101.48,65.57 101.48,66.13 101.47,66.14 101.47,66.61 101.48,66.61 101.48,67.45 CPU1.W37
  BOTTOM w0.14: v2(51.37,34.94) RAM4.P9 ; RAM3.P9 v2(61.52,34.94) ; RAM2.P9 v2(71.67,34.94) ; RAM1.P9 v2(81.82,34.94)
M_A_BA0: length 99.8
  TOP w0.14: v2(46.33,34.57) 45.74,33.99 RN1206.1
  L6 w0.142: v2(46.33,34.57) 46.56,34.57 47.52,35.54 50.33,35.54 50.45,35.42 51.6,35.42 52.14,34.88 52.79,34.88 53.1,35.18 55,35.18 55.16,35.34 v2(57.93,35.34) 58.79,34.48 62.27,34.48 62.98,35.18 65.15,35.18 65.31,35.34 v2(68.08,35.34) 68.94,34.48 72.42,34.48 73.13,35.18 75.3,35.18 75.46,35.34 v2(78.23,35.34) 79.09,34.48 82.57,34.48 83.28,35.18 85.45,35.18 85.61,35.34 v2(88.38,35.34) 88.47,35.43 90.72,35.43 92.27,36.98 92.27,40.31 92.96,41 94.3,41 94.79,41.48 94.79,54.51 98.34,58.07 98.34,58.95 98.95,59.56 99.17,59.56 99.69,60.08 99.69,64.8 100.35,65.46 101.11,65.46 101.57,65.91 101.57,67.15 101.97,67.55 104.45,67.55 104.74,67.84 104.74,69.19 104.44,69.49 103.9,69.49 102.91,70.48 102.37,70.48 102.33,70.44 101.98,70.44 101.72,70.69 101.72,71.1 101.22,71.6 v2(101.22,71.61)
  BOTTOM w0.14: v2(68.08,35.34) RAM3.N2 ; CPU1.W32 101.22,71.06 101.22,71.61 v2(101.22,71.61) ; RAM2.N2 v2(78.23,35.34) ; v2(57.93,35.34) RAM4.N2 ; v2(88.38,35.34) RAM1.N2
M_A_BA1: length 93
  TOP w0.14: RN1205.3 v2(49.05,35.07)
  L4SGND w0.142: v2(103.98,70.89) 103.57,70.49 103.57,69.96 101.36,67.74 101.27,67.74 99.63,66.1 99.63,53.71 96.89,50.98 96.89,42.72 96.05,41.88 96.05,41.68 96.33,41.4 96.33,41.2 96.13,41 95.93,41 95.65,41.28 95.45,41.28 95.09,40.92 94.69,40.92 94.55,40.78 94.55,40.27 94.4,40.13 94.12,40.13 93.98,40.27 93.98,40.78 93.83,40.92 92.96,40.92 92.65,40.62 92.65,35.51 91.64,34.5 88.38,34.5 87.54,35.34 v2(82.78,35.34) 82.7,35.42 78.81,35.42 78.42,35.8 77.78,35.8 77.31,35.34 v2(72.63,35.34) 72.55,35.42 68.66,35.42 68.27,35.8 67.63,35.8 67.16,35.34 v2(62.48,35.34) 62.4,35.42 58.51,35.42 58.12,35.8 57.48,35.8 57.01,35.34 v2(52.33,35.34) 52.25,35.42 50.53,35.42 50.41,35.54 49.51,35.54 v2(49.05,35.07)
  BOTTOM w0.14: v2(72.63,35.34) RAM2.N8 ; CPU1.AB31 v2(103.98,70.89) ; RAM3.N8 v2(62.48,35.34) ; RAM4.N8 v2(52.33,35.34) ; RAM1.N8 v2(82.78,35.34)
M_A_BG0: length 99.5
  TOP w0.14: v2(49.79,37.49) 48.9,38.38 RN1202.3
  L2SGND w0.089: v2(100.7,65.99) 101.14,66.42 101.14,67.68 101.22,67.77 101.97,67.77 102.14,67.93 102.14,68.82 102.05,68.91 101.87,68.91 101.78,68.82 101.78,68.49 101.69,68.41 101.52,68.41 101.43,68.49 101.43,68.8 101.34,68.89 101.16,68.89 101.07,68.8 101.07,68.49 100.98,68.41 100.53,68.41 99.31,67.18 99.31,66.03 99.19,65.92 98.53,65.92 98.44,65.83 98.44,65.65 98.53,65.56 99.22,65.56 99.31,65.47 99.31,65.32 99.19,65.21 98.53,65.21 98.44,65.12 98.44,64.94 98.53,64.85 99.22,64.85 99.31,64.76 99.31,64.61 99.19,64.49 98.53,64.49 98.44,64.41 98.44,64.23 98.53,64.14 99.22,64.14 99.31,64.05 99.31,62.14 98.35,61.18 98.35,57.8 96.45,55.89 96.45,55.18 96.36,55.09 95.97,55.09 95.88,55 95.88,54.82 95.97,54.73 96.36,54.73 96.45,54.64 96.45,54.47 96.36,54.38 95.97,54.38 95.88,54.29 95.88,54.11 95.97,54.02 96.36,54.02 96.45,53.93 96.45,53.76 96.36,53.67 95.97,53.67 95.88,53.58 95.88,53.4 95.97,53.31 96.36,53.31 96.45,53.22 96.45,44.68 90.2,38.43 89.2,38.43 88.38,37.62 v2(88.38,36.94)
  L6 w0.142: v2(88.38,36.94) 86.35,36.94 86.09,36.69 84.3,36.69 84.27,36.66 84.25,36.66 83.99,36.4 82.33,36.4 82.27,36.34 78.84,36.34 v2(78.23,36.94) 76.2,36.94 75.94,36.69 74.15,36.69 74.12,36.66 74.1,36.66 73.84,36.4 72.18,36.4 72.12,36.34 68.69,36.34 v2(68.08,36.94) 66.05,36.94 65.79,36.69 63.32,36.69 62.99,36.37 62.05,36.37 62.01,36.32 58.56,36.32 v2(57.93,36.94) 55.9,36.94 55.64,36.69 53.85,36.69 53.82,36.66 53.8,36.66 53.54,36.4 51.88,36.4 51.82,36.34 51.15,36.34 50.01,37.49 v2(49.79,37.49)
  BOTTOM w0.076: v2(100.7,65.99) 101.14,66.43 101.14,66.74 101.15,66.75 101.15,67.61 101.22,67.79 101.22,68.03 101.19,68.1 101.18,68.12 101.18,68.34 101.22,68.44 101.22,68.96 CPU1.V34
  BOTTOM w0.14: v2(57.93,36.94) RAM4.M2 ; v2(68.08,36.94) RAM3.M2 ; RAM2.M2 v2(78.23,36.94) ; v2(88.38,36.94) RAM1.M2
M_A_BG1: length 40.3
  L4SGND w0.142: v2(100.5,64.87) 100.05,64.42 100.05,53.47 98.34,51.75 97.26,50.68 97.26,41.17 94.98,38.88 94.98,37.95 94.79,37.76 94.56,37.76 94.39,37.94 94.39,38.7 94.23,38.85 93.9,38.85 93.78,38.73 93.78,37.91 93.68,37.81 93.31,37.81 93.17,37.96 93.17,39.64 v2(93.12,39.69)
  BOTTOM w0.076: CPU1.W35 101.52,68.79 101.39,68.45 101.39,68.44 101.35,68.31 101.35,68.16 101.35,68.15 101.39,68.03 101.39,67.79 101.32,67.58 101.32,66.68 101.31,66.67 101.31,66.07 101.32,66.06 101.32,65.89 100.5,65.08 v2(100.5,64.87)
  BOTTOM w0.14: v2(93.12,39.69) 93.13,39.69 R1220.1
M_A_BG1_E9_1: length 1.3
  TOP w0.14: R1212.1 51.2,41.97 v2(51.37,42.14)
  BOTTOM w0.14: RAM4.E9 v2(51.37,42.14)
M_A_BG1_E9_2: length 2
  TOP w0.14: R1213.1 61.35,41.97 v2(61.52,42.14)
  BOTTOM w0.14: RAM3.E9 v2(61.52,42.14)
M_A_BG1_E9_3: length 2
  TOP w0.14: R1214.1 81.65,41.97 v2(81.82,42.14)
  BOTTOM w0.14: RAM1.E9 v2(81.82,42.14)
M_A_BG1_E9_4: length 2
  TOP w0.14: R1215.1 70.85,41.97 71.02,42.14 v2(71.67,42.14)
  BOTTOM w0.14: RAM2.E9 v2(71.67,42.14)
M_A_BG1_M9_R: length 53.1
  TOP w0.14: v2(49.05,36.4) 48.97,36.47 R1224.1
  L4SGND w0.142: v2(90.82,37.39) 90.82,37.08 90.65,36.91 89.08,36.91 88.58,37.41 88.19,37.41 87.77,36.98 83.47,36.98 82.97,36.49 82.12,36.49 v2(81.8,36.81) 81.75,36.81 81.29,36.35 79.08,36.35 78.69,36.75 78.69,37.13 78.42,37.4 78.05,37.4 77.63,36.98 73.41,36.98 72.9,36.47 71.99,36.47 v2(71.65,36.81) 71.18,36.34 69.01,36.34 68.66,36.69 68.66,37.03 68.28,37.41 67.89,37.41 67.47,36.98 63.17,36.98 62.67,36.49 61.82,36.49 v2(61.5,36.81) 61.03,36.34 58.86,36.34 58.51,36.69 58.51,37.03 58.13,37.41 57.74,37.41 57.32,36.98 53.02,36.98 52.52,36.49 51.67,36.49 v2(51.35,36.81) 51.29,36.86 49.51,36.86 v2(49.05,36.4)
  BOTTOM w0.14: RAM4.M9 51.65,36.82 51.36,36.82 v2(51.35,36.81) ; RAM2.M9 71.91,36.54 v2(71.65,36.81) ; v2(61.5,36.81) 61.76,36.54 RAM3.M9 ; R1220.2 91.73,37.69 R1221.2 90.97,37.53 v2(90.82,37.39) ; v2(81.8,36.81) 81.81,36.82 82.1,36.82 RAM1.M9
M_A_CKE0: length 96.8
  TOP w0.14: RN1207.1 45.74,36.4 v2(46.33,36.99)
  L4SGND w0.142: v2(98.55,63.07) 97.63,63.07 96.97,62.41 96.97,53.8 95.99,52.82 95.79,52.82 95.22,53.38 95.02,53.38 94.82,53.18 94.82,52.98 95.39,52.42 95.39,52.21 95.19,52.01 94.98,52.01 94.42,52.58 94.22,52.58 94.02,52.38 94.02,52.18 94.58,51.61 94.58,51.41 94.38,51.21 94.18,51.21 93.61,51.77 93.41,51.77 93.21,51.57 93.21,51.37 93.78,50.81 93.78,50.6 93.52,50.35 92.26,50.35 92.12,50.21 92.12,49.92 92.26,49.78 93.81,49.78 93.95,49.64 93.95,48.97 91.75,46.78 91.75,46.58 92.18,46.16 92.18,45.96 90.56,44.34 90.56,38.88 90.16,38.49 88.43,38.49 v2(88.38,38.54) 88.03,38.89 87.02,38.89 86.64,38.51 85.2,38.51 84.47,37.78 83.03,37.78 82.45,38.37 78.4,38.37 v2(78.23,38.54) 77.94,38.25 74.8,38.25 74.32,37.78 72.88,37.78 72.3,38.37 68.25,38.37 v2(68.08,38.54) 67.79,38.25 64.65,38.25 64.17,37.78 63.04,37.78 62.81,38.01 62.81,39 62.67,39.14 62.11,39.14 61.96,39 61.96,38.58 61.82,38.43 58.04,38.43 v2(57.93,38.54) 57.62,38.23 54.73,38.23 54.28,37.78 52.87,37.78 52.29,38.35 47.26,38.35 46.33,37.42 v2(46.33,36.99)
  BOTTOM w0.076: CPU1.U36 100.31,68.01 100.54,67.79 100.58,67.68 100.58,67.3 99.86,66.58 99.86,65.76 99.49,65.39 99.49,65.05
  BOTTOM w0.14: RAM2.K2 v2(78.23,38.54) ; 99.49,65.05 99.49,63.73 98.82,63.07 v2(98.55,63.07) ; v2(68.08,38.54) RAM3.K2 ; RAM4.K2 57.79,38.14 57.93,38.28 v2(57.93,38.54) ; v2(88.38,38.54) RAM1.K2
M_A_CLK: length 3.1
  TOP w0.102: C1247.1 47.42,40.61 R1226.2 47.33,40.54 46.61,39.82 v1(46.61,39.73) 46.99,39.78 R1225.2
M_A_CLK0: length 88.3
  TOP w0.102: v2(49.05,40.21) 48.62,39.78 R1225.1
  TOP w0.14: C1285.1 84.51,38.42 v2(84.38,38.54)
  L6 w0.089: v2(84.38,38.54) 83.8,38.08 83.43,38.08 81.91,39.6 75.01,39.6 74.58,39.17 v2(74.23,38.54) 73.64,38.07 73.29,38.09 73.29,38.1 73.25,38.1 72.98,38.36 72.98,38.4 71.78,39.6 64.89,39.6 64.39,39.1 v2(64.08,38.54) 63.55,38.12 63.07,38.12 61.57,39.62 54.43,39.62 54.26,39.46 54.26,38.87 v2(53.93,38.54) 53.49,38.1 52.95,38.1 52.68,38.36 52.68,38.42 51.47,39.64 49.72,39.64 49.15,40.21 v2(49.05,40.21)
  L6 w0.137: v2(84.38,38.54) 84.38,39.01 84.9,39.52 89.55,39.52 90.2,40.17 90.2,41.56 91.79,43.15 91.79,51.55 92.99,52.75 92.99,55.13 95.55,57.68 95.55,58.45 96.41,59.31 96.41,64.44 97.1,65.13 97.1,65.91 101.06,69.87 101.06,70.82 v2(100.35,71.53)
  BOTTOM w0.14: v2(74.23,38.54) RAM2.K7 ; RAM4.K7 v2(53.93,38.54) ; CPU1.V31 v2(100.35,71.53) ; RAM3.K7 v2(64.08,38.54) ; RAM1.K7 v2(84.38,38.54)
M_A_CLK#0: length 87.5
  TOP w0.102: v2(49.67,40.35) 49.36,40.67 48.8,40.67 48.68,40.54 R1226.1
  TOP w0.14: v2(83.58,38.54) 83.58,37.62 C1285.2
  L6 w0.089: v2(83.58,38.54) 83.23,38.54 81.99,39.79 74.93,39.79 74.3,39.16 73.72,39.16 73.43,38.88 v2(73.43,38.54) 73.11,38.54 71.86,39.79 64.81,39.79 64.04,39.01 63.42,39.01 63.28,38.88 v2(63.28,38.54) 63.19,38.45 63.01,38.45 61.64,39.81 54.35,39.81 54.07,39.54 54.07,39.15 53.98,39.07 53.22,39.07 53.13,38.98 v2(53.13,38.54) 52.83,38.54 51.55,39.83 49.8,39.83 49.67,39.96 v2(49.67,40.35)
  L6 w0.137: v2(83.58,38.54) 83.58,38.97 83.72,39.11 84.15,39.11 84.8,39.76 89.45,39.76 89.96,40.27 89.96,41.66 91.55,43.25 91.55,51.65 92.76,52.85 92.76,55.03 92.76,55.23 95.31,57.78 95.31,58.54 96.17,59.41 96.17,64.54 96.86,65.22 96.86,66 100.82,69.97 100.82,70.72 100.67,70.87 v2(100.32,70.87)
  BOTTOM w0.14: v2(73.43,38.54) RAM2.K8 ; v2(63.28,38.54) 63.05,38.54 62.88,38.38 RAM3.K8 ; v2(53.13,38.54) 52.87,38.54 52.73,38.41 RAM4.K8 ; v2(100.32,70.87) 100.65,70.87 100.79,70.73 CPU1.V32 ; RAM1.K8 v2(83.58,38.54)
M_A_CS#0: length 94.2
  TOP w0.14: RN1202.4 48.91,38.96 48.99,38.89 v2(49.19,38.89)
  L2SGND w0.089: v2(85.66,37.74) 86.42,36.98 86.81,36.98 87.27,36.52 88.56,36.52 88.84,36.8 88.84,37.47 89.24,37.87 90.02,37.87 93.05,40.89 93.38,40.89 96.97,44.49 96.97,55.4 98.67,57.1 98.67,59.24 98.97,59.54 99.31,59.54 99.62,59.86 99.62,64.56 100.37,65.3 100.65,65.3 101.67,66.32 101.67,66.98 102.1,67.41 102.56,67.41 104.9,69.75 v2(104.9,70.35)
  L6 w0.142: v2(49.19,38.89) 50.16,38.89 50.51,38.53 51.99,38.53 52.78,37.74 v2(55.21,37.74) 55.21,37.76 55.65,38.2 56.52,38.2 57.34,39.01 58.13,39.01 58.64,38.51 62.25,38.51 63.02,37.74 v2(65.36,37.74) 65.36,37.76 65.8,38.2 66.67,38.2 67.51,39.04 68.3,39.04 68.83,38.51 72.31,38.51 73.07,37.74 v2(75.51,37.74) 75.51,37.76 75.95,38.2 76.82,38.2 77.66,39.04 78.45,39.04 78.99,38.51 82.44,38.51 83.21,37.74 v2(85.66,37.74)
  BOTTOM w0.14: RAM1.L7 85.26,37.34 v2(85.66,37.74) ; CPU1.AE32 v2(104.9,70.35) ; RAM2.L7 75.11,37.34 v2(75.51,37.74) ; RAM3.L7 64.96,37.34 v2(65.36,37.74) ; v2(55.21,37.74) 54.81,37.34 RAM4.L7
M_A_DQ0: length 62.8
  L4SGND w0.089: v2(52.64,46.34) 52.64,46.56 52.84,46.76 52.84,46.76 53.09,47.01 60.04,53.95 67.78,53.95 69,55.17 70.25,55.17 73.29,58.22 73.29,60.65 77.13,64.49 77.13,69.37 80.03,72.26 80.16,72.26 80.33,72.09 80.45,72.09 80.58,72.22 80.58,72.34 80.41,72.51 80.41,72.64 82.08,74.31 85.24,74.31 85.32,74.4 v2(85.32,74.98)
  BOTTOM w0.076: 86.81,74.34 88.59,74.34 89.03,74.79 90.95,74.79 CPU1.A26
  BOTTOM w0.089: 86.81,74.34 85.97,74.34 v2(85.32,74.98) ; v2(52.64,46.34) 52.83,46.16 53.93,46.16 54.2,46.43 54.55,46.43 55.33,45.64 55.33,45.34 56.57,44.1 57.17,44.1 RAM4.C2
M_A_DQ1: length 62.9
  L4SGND w0.089: v2(52.33,44.14) 51.86,44.61 51.86,45.14 51.51,45.49 51.51,46.26 52.85,47.59 59.79,54.54 67.54,54.54 68.76,55.76 70.01,55.76 72.71,58.46 72.71,60.89 76.52,64.71 76.52,69.6 82.67,75.74 88.14,75.74 v2(89.84,74.05)
  BOTTOM w0.076: v2(89.84,74.05) 89.88,74.05 90.27,73.65 91.29,73.65 91.47,73.59 91.65,73.59 91.76,73.63 92.01,73.63 92.2,73.56 92.2,73.56 92.22,73.56 93.03,73.56 93.18,73.71 CPU1.D26
  BOTTOM w0.089: v2(52.33,44.14) RAM4.C8
M_A_DQ2: length 63.1
  L4SGND w0.089: v2(89.62,72.48) 89.89,72.48 90.06,72.31 90.06,71.86 89.97,71.77 89.08,71.77 88.82,72.03 86.39,72.03 84.91,70.55 84.91,66.52 79.7,61.3 79.57,61.3 78.63,62.24 78.51,62.24 78.38,62.12 78.38,61.99 79.32,61.05 79.32,60.92 79.19,60.8 79.07,60.8 78.13,61.74 78,61.74 77.88,61.61 77.88,61.49 78.82,60.55 78.82,60.42 71.22,52.82 69.98,52.82 68.76,51.61 61.01,51.61 55.57,46.16 55.57,45.65 54.54,44.62 54.06,44.62 53.57,44.14 53.57,43.43 53.48,43.34 v2(53.14,43.34)
  BOTTOM w0.076: v2(89.62,72.48) 90.13,72.99 90.8,72.99 91.01,72.77 91.39,72.77 91.64,72.91 92.58,72.91 CPU1.D28
  BOTTOM w0.089: RAM4.D7 53.53,42.95 v2(53.14,43.34)
M_A_DQ3: length 63
  L4SGND w0.089: v2(87.17,72.54) 86.47,72.54 84.56,70.63 84.56,66.57 81.34,63.36 81.21,63.36 80.44,64.13 79.96,64.13 77.39,61.56 77.39,61.43 78.33,60.49 78.33,60.37 78.21,60.24 78.08,60.24 77.14,61.18 77.01,61.18 76.89,61.06 76.89,60.93 77.82,60 77.82,59.88 77.69,59.75 77.56,59.75 76.64,60.68 76.51,60.68 75.44,59.61 75.44,58.62 75.96,58.1 75.96,57.97 71.1,53.12 69.86,53.12 68.64,51.9 60.89,51.9 55.24,46.25 55.24,45.63 54.54,44.93 53.93,44.93 v2(53.13,44.14)
  BOTTOM w0.076: 89.21,73.54 90.15,73.54 90.2,73.49 91.26,73.49 91.44,73.42 91.71,73.42 91.73,73.44 91.77,73.45 92.01,73.45 92.43,73.3 CPU1.C28
  BOTTOM w0.089: 89.21,73.54 88.05,73.54 87.17,72.66 v2(87.17,72.54) ; RAM4.C7 v2(53.13,44.14)
M_A_DQ4: length 61.1
  L4SGND w0.089: v2(86.72,75) 86.72,74.12 86.55,73.94 83.11,73.94 83.03,73.85 83.03,73.72 82.94,73.63 82.76,73.63 82.67,73.72 82.67,73.85 82.58,73.94 82.12,73.94 81.41,73.23 81.41,71.65 81.32,71.56 79.74,71.56 77.42,69.24 77.42,64.37 73.58,60.53 73.58,58.1 70.37,54.88 69.12,54.88 67.9,53.66 60.16,53.66 53.26,46.77 v2(53.26,46.58)
  BOTTOM w0.076: 87.14,74.58 87.17,74.56 88.57,74.56 88.96,74.95 91,74.95 91.33,74.77 91.68,74.59 CPU1.B26
  BOTTOM w0.089: v2(86.72,75) 87.14,74.58 ; v2(53.26,46.58) 53.32,46.64 55.43,46.64 RAM4.A3
M_A_DQ5: length 61.8
  L4SGND w0.089: v2(88.11,74.95) 87.65,75.41 84.71,75.41 84.62,75.32 84.62,74.81 84.54,74.72 84.36,74.72 84.27,74.81 84.27,75.32 84.18,75.41 84,75.41 83.91,75.32 83.91,74.81 83.82,74.72 83.65,74.72 83.56,74.81 83.56,75.32 83.47,75.41 82.76,75.41 76.83,69.48 76.83,64.6 73,60.77 73,58.34 70.13,55.47 68.88,55.47 67.66,54.25 59.92,54.25 52.97,47.3 52.97,47.3 51.86,46.19 51.86,45.64 52.33,45.17 v2(52.33,44.94)
  BOTTOM w0.076: v2(88.11,74.95) 88.28,75.12 91.04,75.12 91.59,74.82 92.05,74.82 CPU1.C26
  BOTTOM w0.089: RAM4.B8 v2(52.33,44.94)
M_A_DQ6: length 62.2
  L4SGND w0.089: v2(54.37,46) 54.37,46.21 60.65,52.48 68.39,52.48 69.61,53.7 70.86,53.7 74.76,57.61 74.76,60.04 79.17,64.45 79.17,65.51 79.08,65.6 78.75,65.6 78.66,65.69 78.66,68.8 80.24,70.38 83.5,70.38 83.59,70.29 83.59,69.17 83.68,69.08 83.88,69.08 83.97,69.17 83.97,70.87 87.26,74.16 88.8,74.16 88.99,73.97 v2(88.99,72.48)
  BOTTOM w0.076: CPU1.B28 91.83,73.2 91.55,73.05 91.55,73.05 91.35,72.94 91.08,72.94 90.86,73.16 89.67,73.16 89.35,72.84
  BOTTOM w0.089: v2(54.37,46) 55.09,45.28 55.09,45.22 56.57,43.74 RAM4.C3 ; v2(88.99,72.48) 89.35,72.84
M_A_DQ7: length 61.8
  L4SGND w0.089: v2(88.38,72.48) 88.38,73.64 88.29,73.73 88.12,73.73 88.03,73.64 88.03,73.18 87.94,73.09 87.76,73.09 87.67,73.18 87.67,73.64 87.58,73.73 87.41,73.73 87.32,73.64 87.32,73.18 87.18,73.04 86.56,73.04 84.26,70.75 84.26,66.69 82.03,64.46 81.9,64.46 81.36,65 81.24,65 81.11,64.87 81.11,64.75 81.65,64.21 81.65,64.08 81.44,63.87 81.28,63.87 80.26,64.89 80.03,64.89 75.06,59.92 75.06,57.49 70.98,53.41 69.73,53.41 68.52,52.19 60.77,52.19 55.02,46.44 55.02,45.72 54.67,45.36 v2(54.37,45.36)
  BOTTOM w0.076: 89.59,73.32 91.11,73.32 CPU1.A28
  BOTTOM w0.089: RAM4.D3 56.73,43.01 v2(54.37,45.36) ; v2(88.38,72.48) 88.38,72.63 89.08,73.32 89.59,73.32
M_A_DQ8: length 56.4
  L4SGND w0.089: v2(87.8,71.53) 86.91,70.64 86.82,70.64 85.84,69.66 85.84,66.12 71.62,51.91 70.37,51.91 69.17,50.71 61.42,50.71 55.89,45.18 55.89,44.96 53.98,43.05 53.98,40.91 v2(53.98,40.91)
  BOTTOM w0.076: 89.4,71.89 89.82,71.89 89.96,72.03 90.82,72.03 91.03,72.24 91.35,72.24 91.83,72.04 CPU1.B30
  BOTTOM w0.089: v2(87.8,71.53) 88.16,71.89 89.4,71.89 ; v2(53.98,40.91) 53.98,40.49 53.67,40.19 53.18,40.19 RAM4.H8
M_A_DQ9: length 57.3
  L4SGND w0.089: v2(89.5,70.36) 88.91,70.36 88.18,69.64 88.18,66.38 72.24,50.44 70.98,50.44 68.85,48.3 62.06,48.3 59.4,45.64 58.85,45.64 58.45,45.25 58.45,44.66 57.19,43.4 57.19,42.82 56.56,42.19 56.56,41.79 56.19,41.43 v2(54.95,41.43)
  BOTTOM w0.076: CPU1.D30 93.18,71.23 92.96,71.01 92.29,71.01 92.04,71.1 91.73,71.1 91.66,71.08 91.45,71.08 91.42,71.09 91.36,71.12 91.31,71.14 90.29,71.14 89.52,70.36 v2(89.5,70.36)
  BOTTOM w0.089: v2(54.95,41.43) 54.87,41.35 54.87,40.28 RAM4.J7
M_A_DQ10: length 56.2
  L4SGND w0.089: v2(89.2,68.61) 89.28,68.52 89.28,66.22 89.39,66.11 90.38,66.11 90.47,66.02 90.47,65.18 90.38,65.09 89.65,65.09 89.56,65 89.56,64.83 89.65,64.74 90.38,64.74 90.47,64.65 90.47,64.47 90.38,64.38 87.42,64.38 72.59,49.55 71.36,49.55 71.18,49.38 71.18,48.44 70.17,47.43 62.43,47.43 60.13,45.13 60.13,43.21 59.14,42.21 57.8,42.21 57.49,41.9 57.49,41.3 v2(57.14,40.94)
  BOTTOM w0.089: RAM4.H2 57.14,40.13 v2(57.14,40.94) ; CPU1.B33 91.44,70 90.05,68.61 v2(89.2,68.61)
M_A_DQ11: length 55.4
  L4SGND w0.089: v2(89.69,69.05) 89.69,66.48 89.78,66.39 90.7,66.39 90.86,66.24 90.86,64.2 90.7,64.05 87.5,64.05 70.59,47.14 62.55,47.14 60.44,45.03 60.44,42.85 59.32,41.74 59.32,41.62 59.54,41.4 59.54,41.27 59.32,41.05 59.19,41.05 58.97,41.26 58.85,41.26 58.53,40.94 v2(57.93,40.94)
  BOTTOM w0.076: v2(89.69,69.05) 89.69,69.47 90.02,69.79 90.95,69.79 91.27,70.11 91.41,70.26 91.69,70.39 91.7,70.39 92.59,70.39 CPU1.D32
  BOTTOM w0.089: RAM4.G2 v2(57.93,40.94)
M_A_DQ12: length 55.6
  L4SGND w0.089: v2(88.46,71.49) 88.46,71.19 87.52,70.26 86.85,70.26 86.13,69.53 86.13,66 71.75,51.62 70.49,51.62 69.29,50.41 66.13,50.41 66.04,50.32 66.04,50.07 65.95,49.98 65.64,49.98 65.55,50.07 65.55,50.32 65.46,50.41 61.64,50.41 60.15,48.92 60.15,48.18 54.44,42.47 v2(54.44,40.46)
  BOTTOM w0.076: 89.55,71.64 89.8,71.64 90.03,71.87 91.12,71.87 CPU1.A30
  BOTTOM w0.089: RAM4.H7 53.72,39.74 v2(54.44,40.46) ; v2(88.46,71.49) 88.61,71.64 89.55,71.64
M_A_DQ13: length 55.9
  L4SGND w0.089: v2(53.13,41.73) 53.59,42.19 53.59,43.15 55.68,45.23 55.68,45.27 57.29,46.88 57.29,46.99 61.3,51 69.04,51 70.24,52.2 71.5,52.2 85.55,66.24 85.55,69.97 v2(87.1,71.52)
  BOTTOM w0.076: CPU1.C30 92.18,72.34 91.54,72.34 91.39,72.4 90.96,72.4 90.76,72.2 89.89,72.2 89.77,72.07 89.63,72.07
  BOTTOM w0.089: RAM4.F7 53.19,41.68 53.18,41.68 v2(53.13,41.73) ; 89.63,72.07 87.24,72.07 87.1,71.92 v2(87.1,71.52)
M_A_DQ14: length 54.9
  L4SGND w0.089: v2(55.36,40.89) 56.08,40.89 57.06,41.88 57.06,42.25 57.61,42.79 58.19,42.79 58.36,42.96 58.36,43.7 58.57,43.91 59.38,43.91 59.47,44 59.47,45.3 62.18,48.01 68.97,48.01 71.09,50.13 72.34,50.13 87.46,65.25 88.34,65.25 88.44,65.34 88.44,69.04 v2(88.59,69.2)
  BOTTOM w0.076: v2(88.59,69.2) 88.9,69.2 89.66,69.96 90.88,69.96 91.1,70.18 91.1,70.18 91.13,70.21 91.32,70.4 91.61,70.54 91.87,70.69 CPU1.B32
  BOTTOM w0.089: RAM4.J3 55.36,40.31 v2(55.36,40.89)
M_A_DQ15: length 54.5
  L4SGND w0.089: v2(90.12,70.38) 90.12,70.16 88.69,68.73 88.69,67.94 88.93,67.7 88.93,65.83 89.18,65.58 89.18,64.93 89.09,64.84 87.46,64.84 72.47,49.84 71.21,49.84 69.09,47.72 62.3,47.72 59.82,45.24 59.82,43.71 58.54,42.43 57.72,42.43 57.28,41.99 57.28,41.69 v2(55.95,40.36)
  BOTTOM w0.076: CPU1.C32 92.26,70.84 92.07,70.91 92.07,70.92 92.01,70.94 91.76,70.94 91.7,70.92 91.69,70.91 91.68,70.9 91.43,70.9 91.4,70.92 91.4,70.92 91.28,70.97 90.72,70.97 v2(90.12,70.38)
  BOTTOM w0.089: RAM4.H3 56.57,39.74 v2(55.95,40.36)
M_A_DQ16: length 60.6
  L6 w0.089: v2(64.81,40.44) 64.81,40.44 64.81,41.46 64.94,41.59 64.94,42.91 66.13,44.09 66.9,44.09 67.32,44.51 67.32,45.56 67.06,45.81 67.06,46.26 70.63,49.83 74.71,49.83 78.03,53.16 78.03,68.36 83.59,73.91 88.66,73.91 89.52,74.77 90.93,74.77 92.1,75.94 93.78,75.94 94,75.72 95.54,75.72 96.11,76.29 v2(96.11,76.35)
  BOTTOM w0.089: RAM3.J7 64.81,40.07 64.81,40.43 v2(64.81,40.44) ; CPU1.J22 v2(96.11,76.35)
M_A_DQ17: length 62.5
  L6 w0.089: v2(95.42,74.35) 95.02,73.95 92.88,73.95 90.68,71.75 89.67,71.75 88.65,70.73 86.82,70.73 86.63,70.54 86.5,70.54 86.38,70.65 86.26,70.65 86.13,70.53 86.13,70.4 86.25,70.28 86.25,70.16 86.12,70.03 86,70.03 85.88,70.15 85.75,70.15 85.63,70.03 85.63,69.9 85.75,69.78 85.75,69.66 85.64,69.55 85.64,66.88 79.81,61.05 79.81,52.09 78.54,50.82 78.54,50.69 78.86,50.37 78.86,50.25 78.73,50.12 78.6,50.12 78.29,50.44 78.16,50.44 77.96,50.25 77.96,50.12 78.98,49.1 78.98,48.98 78.8,48.8 78.68,48.8 78.07,49.41 77.94,49.41 77.82,49.28 77.82,49.16 78.43,48.55 78.43,48.42 78.3,48.3 78.18,48.3 77.56,48.91 77.44,48.91 77.31,48.78 77.31,48.66 77.92,48.05 77.92,47.92 77.8,47.79 77.67,47.79 77.06,48.41 76.94,48.41 76.81,48.28 76.81,48.15 77.36,47.61 77.36,47.48 77.23,47.35 77.08,47.35 76.54,47.88 76.42,47.88 75.88,47.35 72.03,47.35 71.92,47.24 69.91,45.23 69.91,42.34 69.82,42.25 67.58,42.25 67.49,42.16 67.49,41.14 v2(67.29,40.94)
  BOTTOM w0.089: RAM3.G2 67.38,40.54 67.29,40.63 v2(67.29,40.94) ; CPU1.H25 v2(95.42,74.35)
M_A_DQ18: length 59.6
  L6 w0.089: v2(64.07,40.94) 64.01,41 64.01,43.2 66.37,45.56 66.37,46.96 68.28,48.87 68.47,48.87 70.02,50.42 74.46,50.42 77.45,53.4 77.45,68.62 83.33,74.5 88.4,74.5 89.36,75.46 90.2,75.46 91.41,76.66 94.3,76.66 v2(94.79,76.18)
  BOTTOM w0.089: v2(64.07,40.94) 64.03,40.9 64.03,40.38 63.75,40.1 63.16,40.1 62.88,39.82 RAM3.H8 ; CPU1.G22 v2(94.79,76.18)
M_A_DQ19: length 59.5
  L6 w0.089: v2(95.42,76.2) 95.42,76.77 95.33,76.86 90.81,76.86 89.89,75.94 89.06,75.94 88.56,75.44 85.02,75.44 84.38,74.8 83.2,74.8 77.16,68.76 77.16,53.52 74.34,50.71 68.89,50.71 66.08,47.9 66.08,45.57 64.54,44.04 63.75,43.39 63.75,42.31 63.28,41.84 v2(63.28,41.74)
  BOTTOM w0.089: CPU1.H22 v2(95.42,76.2) ; v2(63.28,41.74) RAM3.F7
M_A_DQ20: length 62.8
  L6 w0.089: v2(94.15,75.26) 94.1,75.26 93.69,75.67 92.42,75.67 91.25,74.49 89.64,74.49 88.83,73.69 86.73,73.69 85.97,72.93 85.33,72.93 85.24,72.84 85.24,72.52 85.15,72.43 85,72.43 84.88,72.55 84.88,72.84 84.79,72.93 84.62,72.93 84.53,72.84 84.53,71.9 84.44,71.81 84.26,71.81 84.17,71.9 84.17,72.84 84.08,72.93 83.91,72.93 83.82,72.84 83.82,71.9 83.73,71.81 83.55,71.81 83.46,71.9 83.46,72.74 83.37,72.82 82.92,72.82 78.33,68.24 78.33,52.95 74.9,49.52 70.8,49.52 67.91,46.64 67.91,44.54 67.06,43.69 66.13,43.69 65.59,43.15 65.59,42.31 65.16,41.87 65.16,41.43 65.03,41.31 65.03,40.96 65.53,40.46 v2(65.53,40.4)
  BOTTOM w0.089: v2(94.15,75.26) CPU1.F25 ; RAM3.J3 65.53,40.29 v2(65.53,40.4)
M_A_DQ21: length 61.5
  L6 w0.089: v2(68.08,40.94) 68.2,41.06 70.35,41.06 70.43,41.15 70.43,41.37 70.35,41.46 69.56,41.46 69.47,41.55 69.47,41.72 69.56,41.81 70.13,41.81 70.22,41.9 70.22,45.12 71.05,45.95 71.17,45.95 71.28,45.85 71.41,45.85 71.53,45.97 71.53,46.1 71.43,46.2 71.43,46.33 71.55,46.46 71.68,46.46 71.78,46.35 71.91,46.35 72.04,46.47 72.04,46.6 71.93,46.71 71.93,46.83 72.15,47.06 78.05,47.06 78.23,46.88 78.35,46.88 78.48,47 78.48,47.13 78.09,47.52 78.09,47.65 78.21,47.78 78.34,47.78 78.73,47.38 78.86,47.38 78.98,47.51 78.98,47.63 78.59,48.03 78.59,48.15 78.71,48.28 78.84,48.28 79.24,47.88 79.36,47.88 79.49,48.01 79.49,48.13 79.09,48.53 79.09,48.65 79.3,48.86 79.3,51.05 80.12,51.86 80.12,60.94 86.11,66.93 86.11,67.31 86.19,67.4 86.46,67.4 86.55,67.49 86.55,67.66 86.46,67.75 86.19,67.75 86.11,67.84 86.11,69.6 87.02,70.51 88.69,70.51 89.6,71.42 90.68,71.42 93,73.74 95.99,73.74 96.08,73.83 v2(96.08,74.32)
  BOTTOM w0.089: CPU1.J25 v2(96.08,74.32) ; RAM3.H2 68.08,40.14 v2(68.08,40.94)
M_A_DQ22: length 59.7
  L6 w0.089: v2(94.76,74.35) 92.8,74.35 90.54,72.08 89.62,72.08 88.56,71.02 85.74,71.02 85.21,70.49 85.21,66.86 81.63,63.29 81.51,63.29 81.27,63.53 81.14,63.53 81.02,63.4 81.02,63.27 81.26,63.04 81.26,62.91 79.51,61.16 79.51,52.37 77.09,49.96 77.09,49.83 77.4,49.53 77.4,49.4 77.27,49.28 77.14,49.28 76.84,49.58 76.72,49.58 76.59,49.45 76.59,49.33 76.89,49.03 76.89,48.9 76.77,48.77 76.64,48.77 76.34,49.08 76.21,49.08 76.09,48.95 76.09,48.83 76.39,48.52 76.39,48.4 76.26,48.27 76.14,48.27 75.84,48.57 75.71,48.57 75.58,48.45 75.58,48.32 75.89,48.02 75.89,47.9 75.76,47.77 75.64,47.77 75.33,48.07 75.21,48.07 74.78,47.64 71.91,47.64 71.91,47.64 71.89,47.64 70.14,45.89 70.01,45.89 69.69,46.21 69.56,46.21 69.44,46.09 69.44,45.96 69.76,45.64 69.76,45.51 69.61,45.36 69.61,42.96 69.49,42.84 67.54,42.84 66.98,42.28 66.98,41.24 66.8,41.06 66.32,41.06 66.19,40.93 v2(66.19,40.28)
  BOTTOM w0.089: v2(66.19,40.28) 66.34,40.28 RAM3.H3 ; CPU1.G25 v2(94.76,74.35)
M_A_DQ23: length 59.3
  L6 w0.089: v2(94.1,76.25) 94.07,76.28 91.96,76.28 90.76,75.08 89.39,75.08 88.51,74.21 83.47,74.21 77.74,68.48 77.74,53.28 74.58,50.12 70.51,50.12 68.4,48.01 68.28,48.01 68.13,48.16 68,48.16 67.88,48.03 67.88,47.91 68.02,47.76 68.02,47.64 67.9,47.51 67.77,47.51 67.63,47.66 67.5,47.66 67.38,47.53 67.38,47.4 67.52,47.26 67.52,47.13 66.77,46.38 66.77,45.69 66.97,45.49 66.97,44.76 66.62,44.4 65.83,44.4 64.52,43.08 v2(64.52,41.93)
  BOTTOM w0.089: RAM3.H7 63.73,39.74 64.26,40.28 64.26,40.53 64.52,40.78 v2(64.52,41.93) ; CPU1.F22 94.07,76.84 94.28,76.62 94.28,76.44 v2(94.1,76.25)
M_A_DQ24: length 59.5
  L6 w0.089: v2(62.48,44.14) 62.09,44.14 62,44.23 62,45.13 61.21,45.92 61.21,48.18 67.37,54.34 71.75,54.34 72.56,55.15 72.56,65.54 73.11,66.09 73.11,69.72 82.86,79.48 83.35,79.48 88.63,79.48 v2(90.12,78)
  BOTTOM w0.076: 90.41,77.7 90.67,77.44 91.4,77.44 91.59,77.34 92.53,77.34 92.53,77.33 CPU1.D22
  BOTTOM w0.089: v2(90.12,78) 90.41,77.7 ; RAM3.C8 v2(62.48,44.14)
M_A_DQ25: length 59.7
  L6 w0.089: v2(63.05,46.61) 63.35,46.91 63.35,49.05 67.75,53.46 72.36,53.46 73.48,54.57 73.48,65.14 74.07,65.73 74.07,66.71 74.16,66.8 74.41,66.8 74.5,66.89 74.5,67.07 74.41,67.15 74.16,67.15 74.07,67.24 74.07,67.42 74.16,67.51 74.41,67.51 74.5,67.6 74.5,67.78 74.41,67.87 74.16,67.87 74.07,67.95 74.07,68.13 74.16,68.22 74.41,68.22 74.5,68.31 74.5,68.49 74.41,68.58 74.26,68.58 74.17,68.67 74.17,68.84 74.26,68.93 74.41,68.93 74.5,69.02 74.5,69.88 83.02,78.39 87.67,78.39 v2(88.1,77.97)
  BOTTOM w0.076: 89.79,77.23 89.85,77.23 90.32,76.76 91.35,76.76 91.41,76.79 91.71,76.79 91.77,76.76 92,76.76 92.16,76.82 92.16,76.82 92.27,76.86 CPU1.C22
  BOTTOM w0.089: 89.79,77.23 88.83,77.23 v2(88.1,77.97) ; v2(63.05,46.61) 63.52,47.08 65.14,47.08 RAM3.A3
M_A_DQ26: length 59.5
  L6 w0.089: v2(64.52,45.36) 64.96,45.8 64.96,48.58 68.37,51.99 73.9,51.99 75.02,53.11 75.02,61.37 75.11,61.46 75.89,61.46 75.98,61.55 75.98,61.72 75.89,61.81 75.11,61.81 75.02,61.9 75.02,62.08 75.11,62.17 75.89,62.17 75.98,62.26 75.98,62.43 75.89,62.52 75.11,62.52 75.02,62.61 75.02,62.79 75.11,62.88 75.89,62.88 75.98,62.97 75.98,69.27 82.72,76.01 83.2,76.01 83.67,76.01 84.24,76.57 v2(84.24,76.67)
  BOTTOM w0.076: CPU1.C24 92.08,75.42 91.63,75.42 91.4,75.3 88.48,75.3 88.37,75.41
  BOTTOM w0.089: RAM3.D3 64.52,45.3 v2(64.52,45.36) ; v2(84.24,76.67) 85.5,75.41 88.37,75.41
M_A_DQ27: length 60.1
  L6 w0.089: v2(83.6,76.67) 83.6,76.35 83.55,76.3 83.33,76.3 82.6,76.3 75.68,69.39 75.68,64.84 75.6,64.75 75.04,64.75 74.96,64.66 74.96,64.48 75.04,64.39 75.6,64.39 75.68,64.3 75.68,64.13 75.6,64.04 74.82,64.04 74.73,63.95 74.73,63.77 74.82,63.68 75.6,63.68 75.68,63.59 75.68,63.41 75.6,63.33 74.82,63.33 74.73,63.24 74.73,53.23 73.78,52.28 68.25,52.28 64.53,48.56 64.53,46.01 v2(64.52,46)
  BOTTOM w0.076: 89.8,77.03 90.24,76.59 91.35,76.59 91.44,76.62 91.68,76.62 91.77,76.59 92,76.59 92.16,76.65 92.74,76.65 93.06,76.65 93.18,76.52 CPU1.D24
  BOTTOM w0.089: 89.8,77.03 89.79,77.04 88.77,77.04 88.71,77.1 84.03,77.1 v2(83.6,76.67) ; RAM3.C3 66.53,43.74 65.07,45.19 65.07,45.45 v2(64.52,46)
M_A_DQ28: length 58.8
  L6 w0.089: v2(62.43,46.42) 63.01,49.13 67.63,53.75 72.17,53.75 73.17,54.75 73.17,65.32 73.77,65.92 73.77,69.03 74.26,70.04 82.97,78.76 87.58,78.76 88.22,78.49 v2(88.83,77.96)
  BOTTOM w0.076: CPU1.A22 90.3,77.02 89.92,77.39 89.76,77.41 89.64,77.42 89.34,77.53 89.23,77.6 v2(88.83,77.96)
  BOTTOM w0.089: v2(62.43,46.42) 62.84,46.18 63.17,46.18 63.47,46.27 63.94,46.5 64.14,46.55 64.65,46.55 64.92,46.45 65.16,46.21 65.38,45.91 65.46,45.71 66.01,44.69 66.32,44.39 66.68,44.17 66.98,44.1 67.26,43.98 RAM3.C2
M_A_DQ29: length 58.5
  L6 w0.089: v2(62.48,44.94) 62.48,45.14 62.01,45.6 62.01,46.01 61.92,46.09 61.66,46.09 61.57,46.18 61.57,46.36 61.66,46.45 61.92,46.45 62.01,46.54 62.01,46.72 61.92,46.81 61.66,46.81 61.57,46.9 61.57,47.07 61.66,47.16 62.14,47.16 62.23,47.25 62.23,47.43 62.14,47.52 61.66,47.52 61.57,47.61 61.57,47.78 61.66,47.87 61.92,47.87 62.01,47.96 62.01,48.56 67.49,54.04 71.96,54.04 72.87,54.95 72.87,65.43 73.4,65.97 73.4,69.6 82.98,79.19 83.23,79.19 83.23,79.19 88.22,79.19 v2(89.44,77.97)
  BOTTOM w0.076: 89.95,77.59 90.04,77.59 90.36,77.28 91.36,77.28 91.61,77.14 CPU1.B22
  BOTTOM w0.089: 89.95,77.59 89.82,77.59 v2(89.44,77.97) ; RAM3.B8 v2(62.48,44.94)
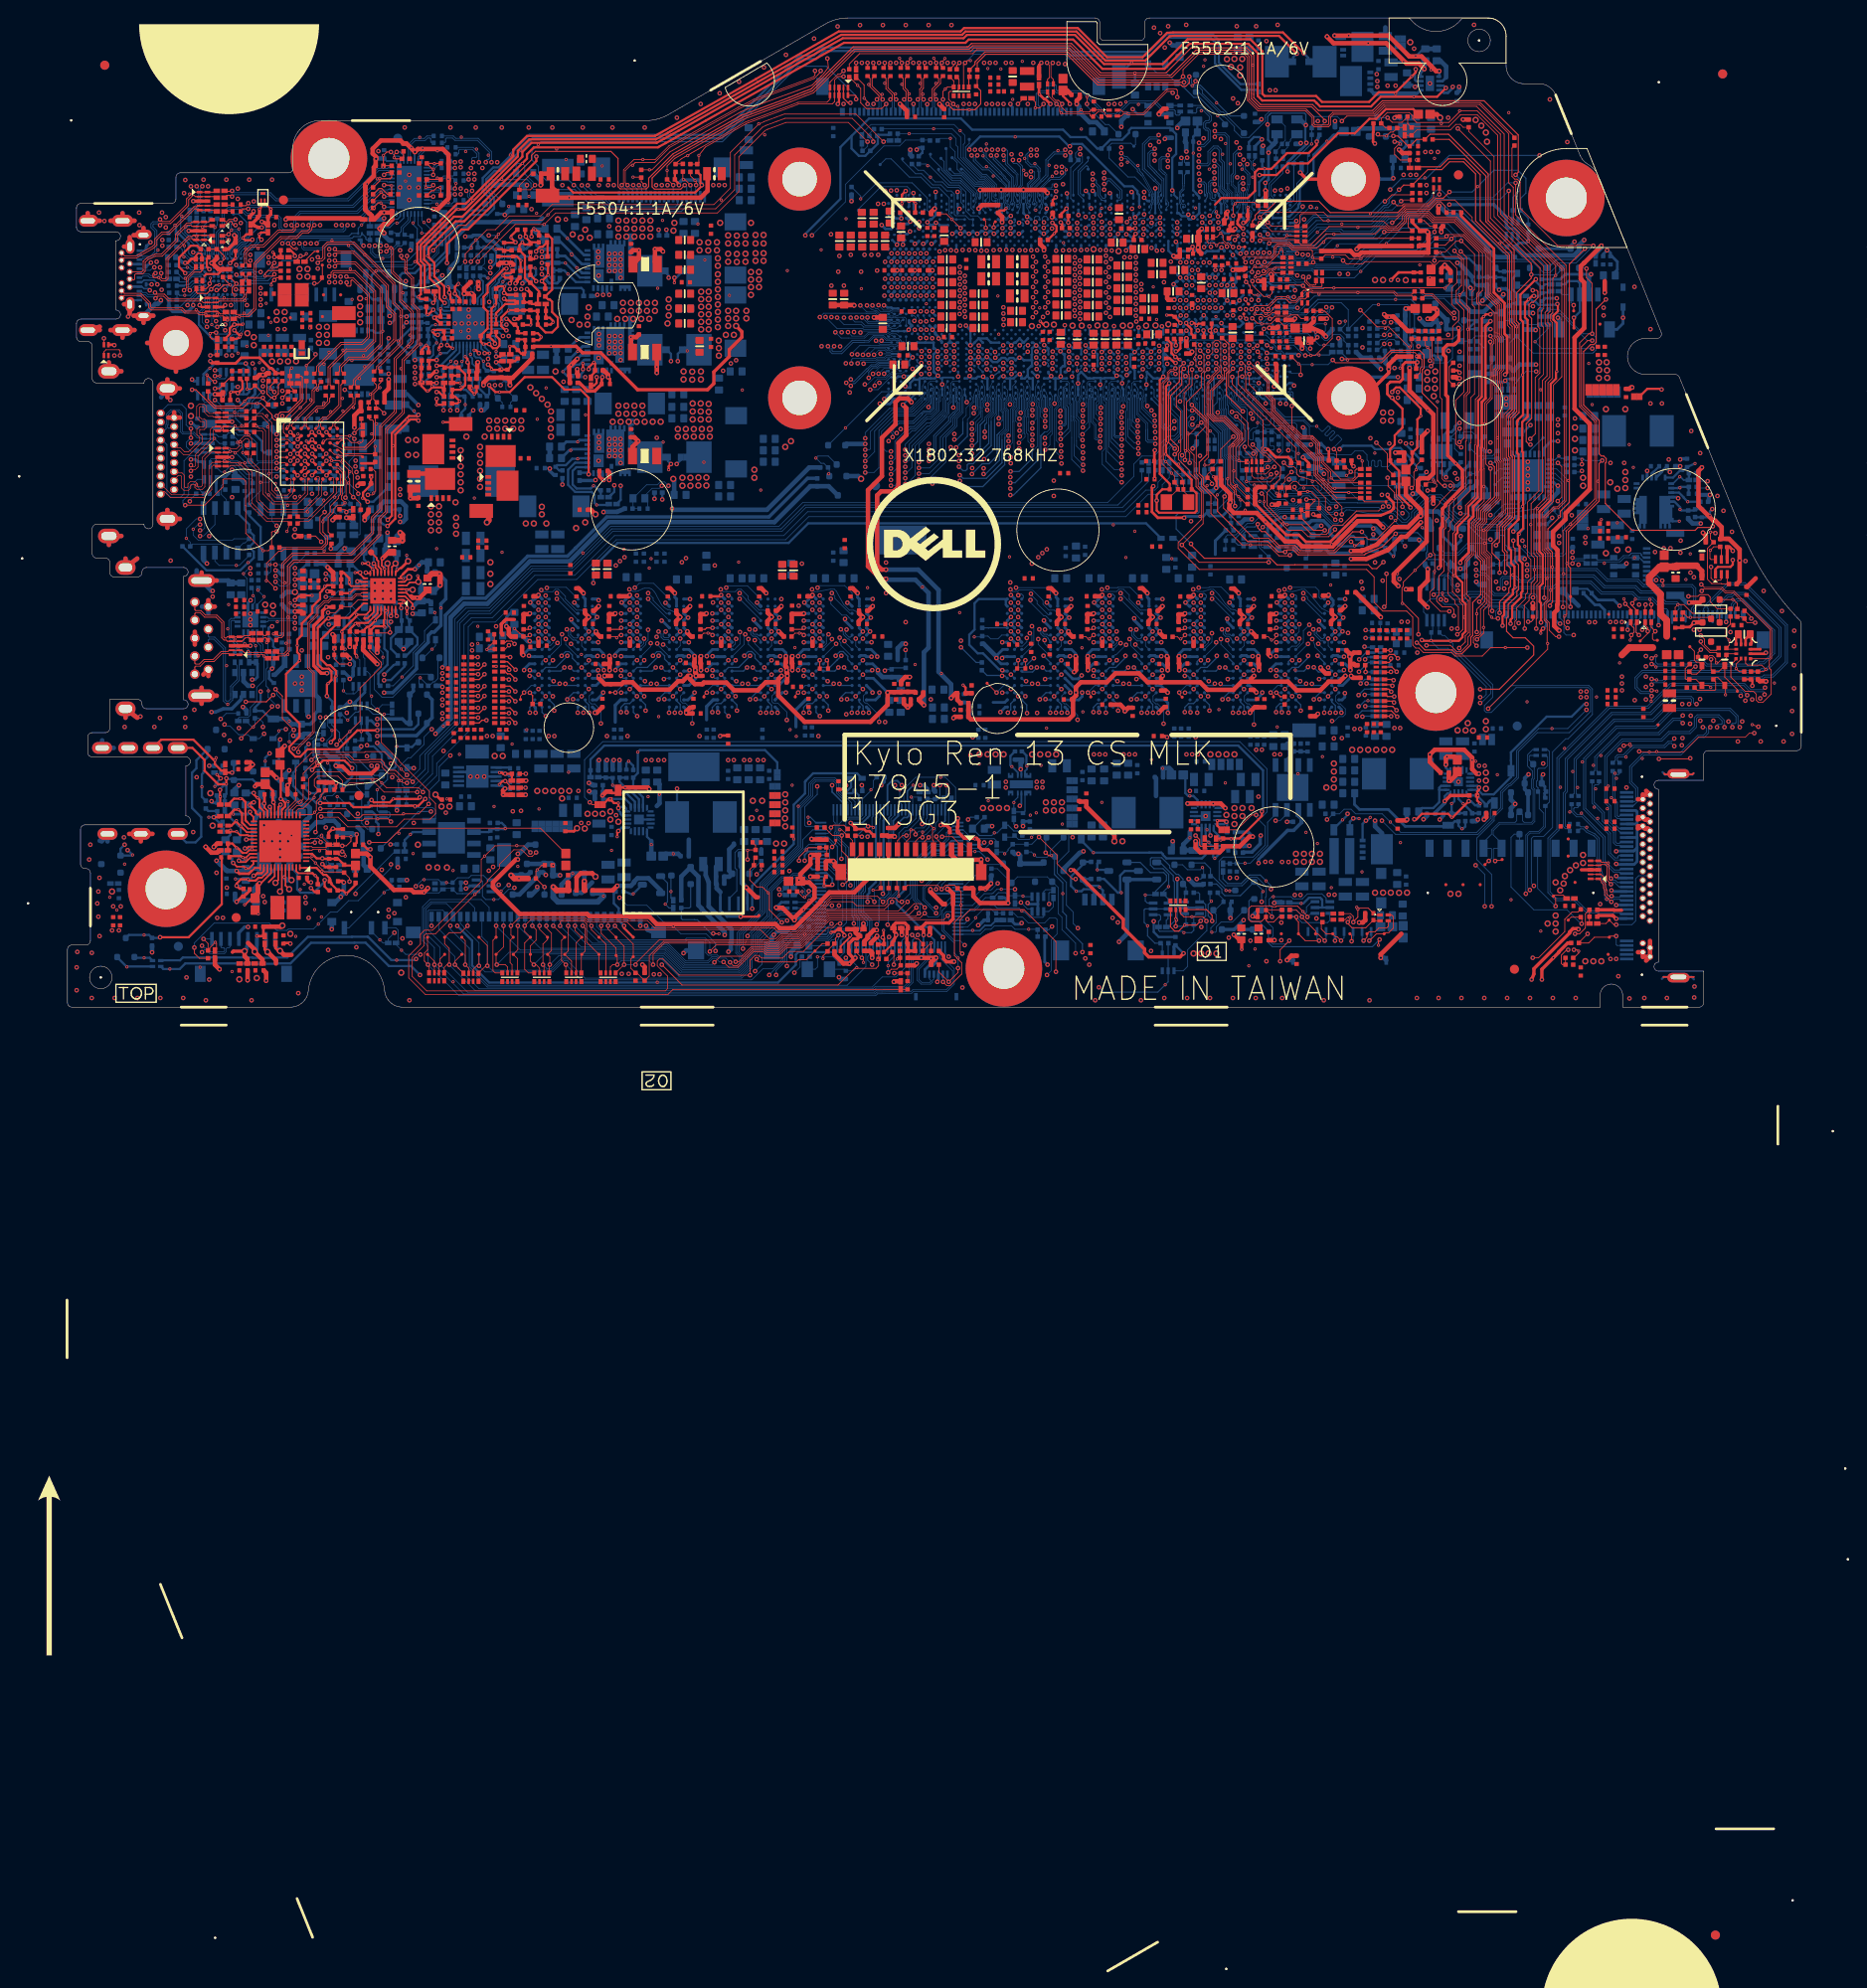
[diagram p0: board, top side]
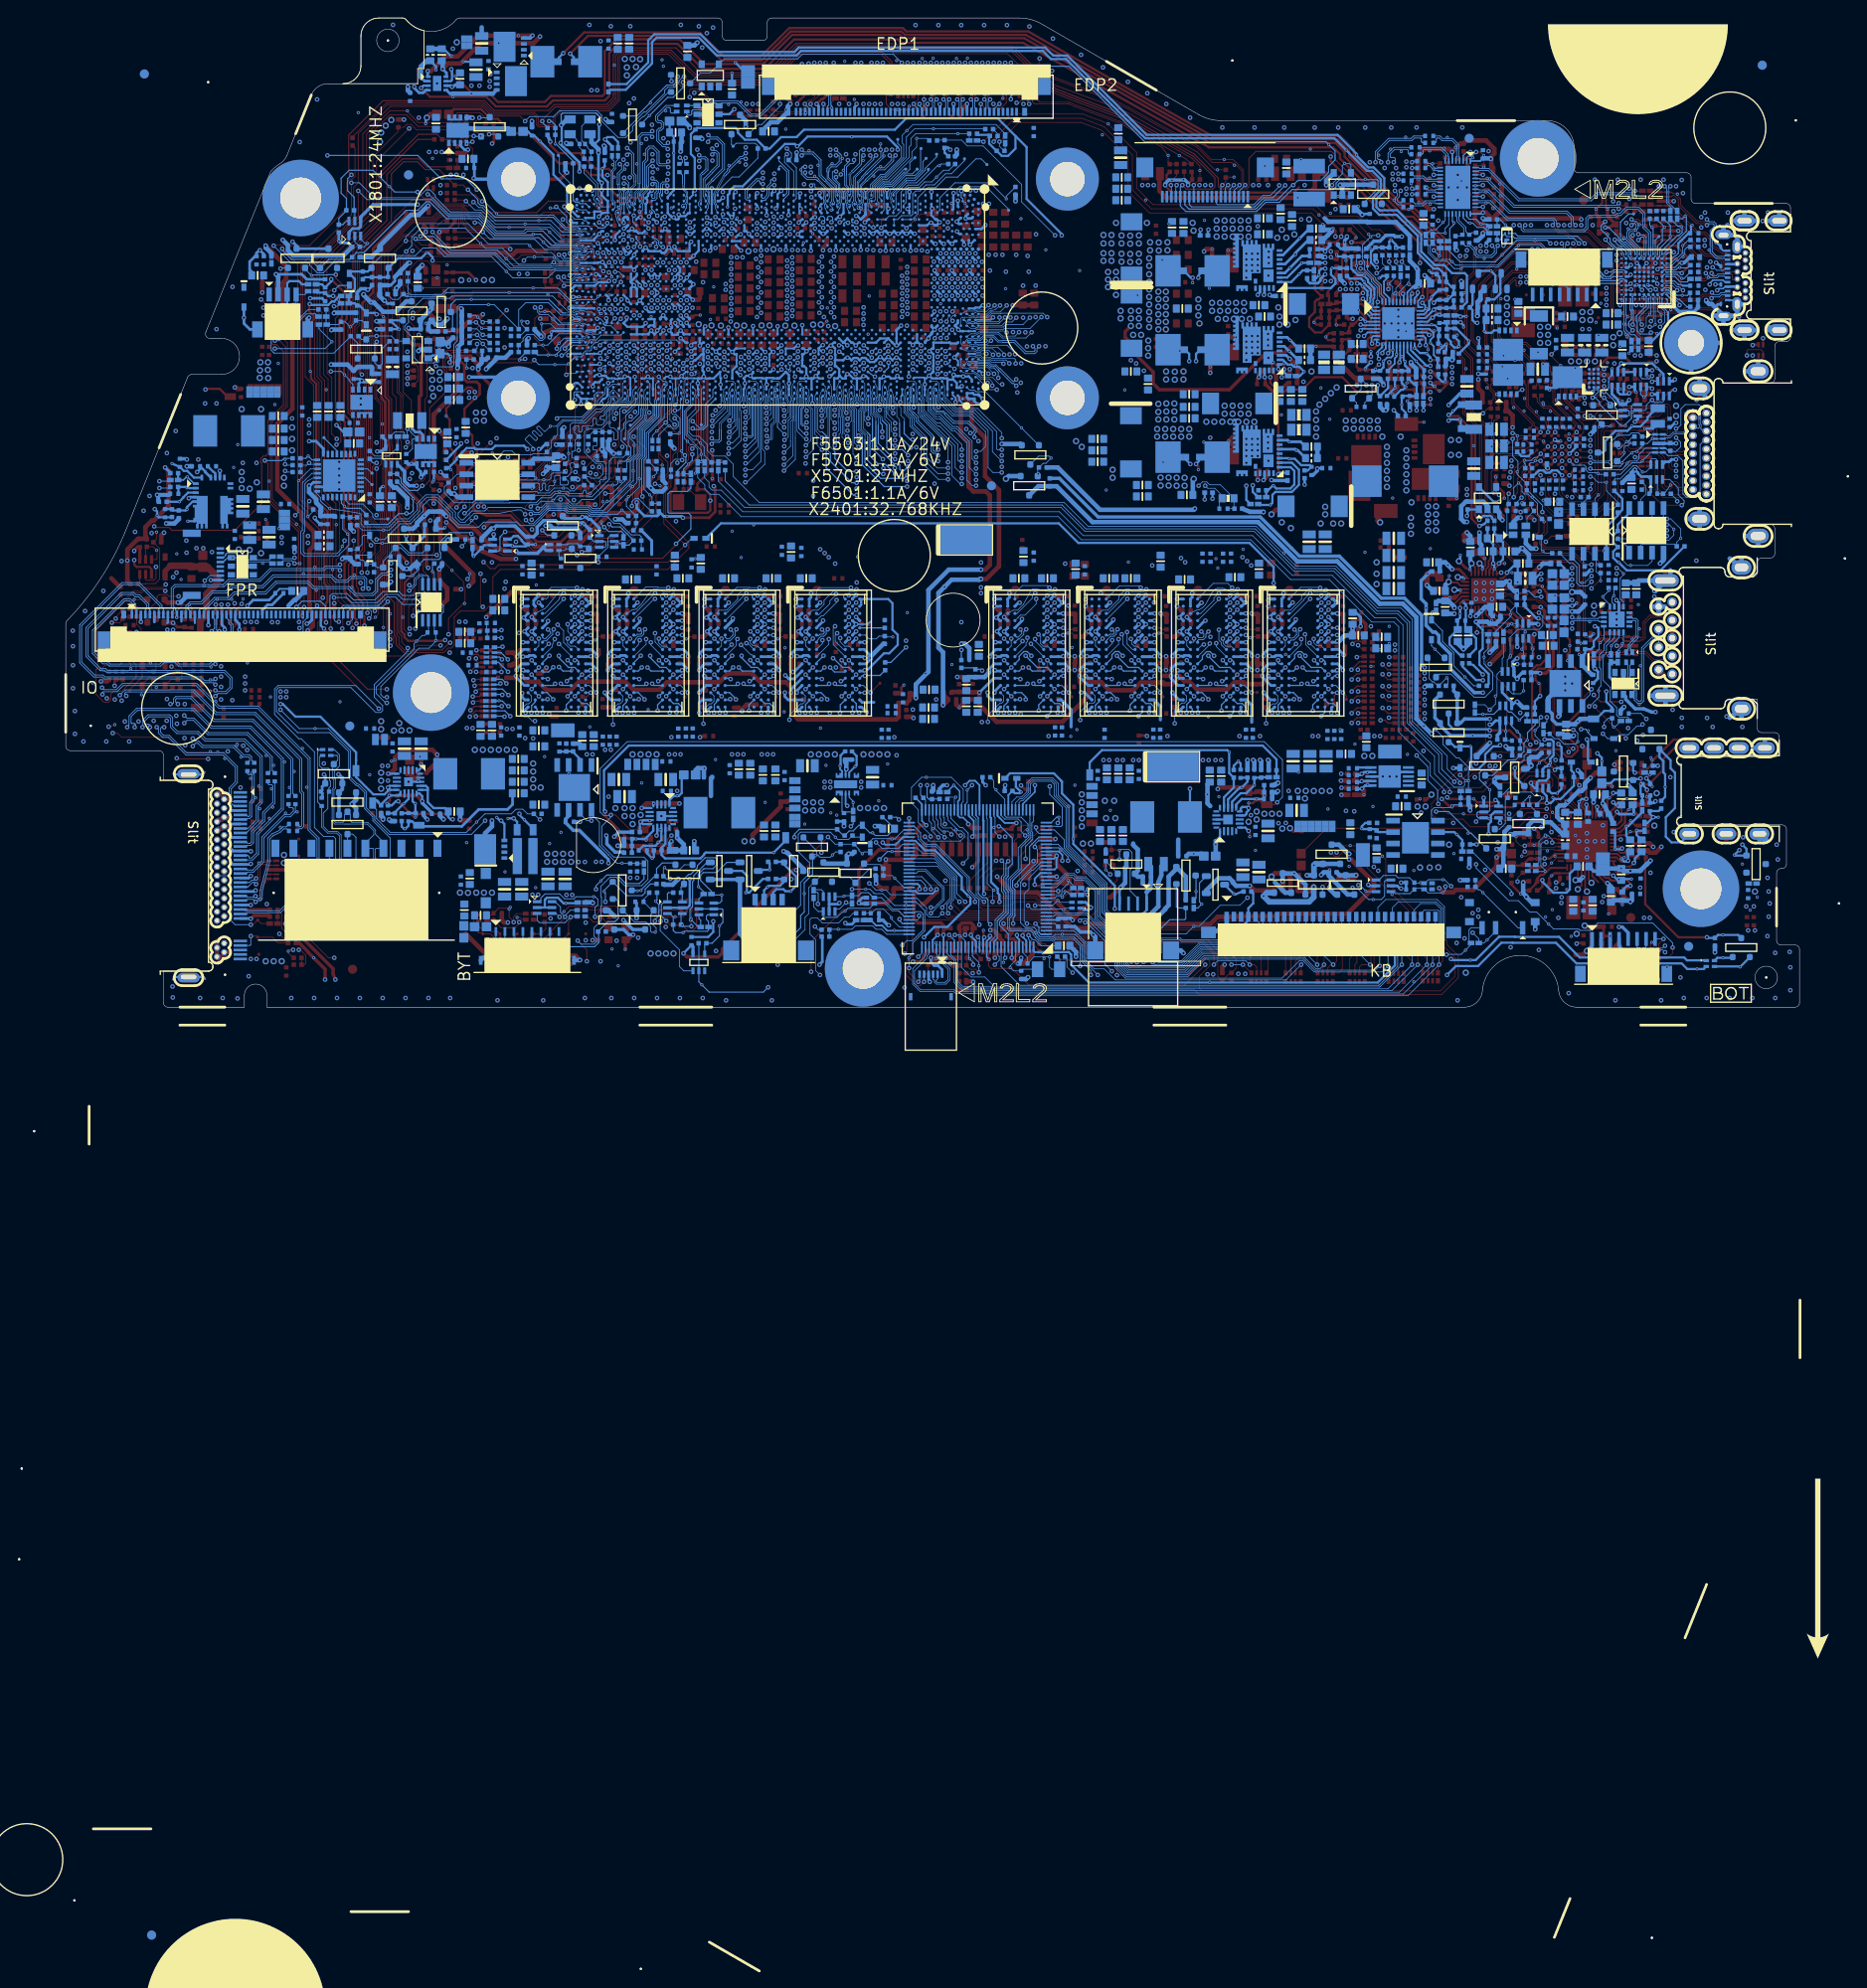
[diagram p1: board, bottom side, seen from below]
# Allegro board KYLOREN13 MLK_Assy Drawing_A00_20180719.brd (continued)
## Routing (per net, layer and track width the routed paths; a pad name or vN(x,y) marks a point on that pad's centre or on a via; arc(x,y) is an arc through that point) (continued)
M_A_DQ30: length 58.2
  L6 w0.089: v2(87.03,76.61) 86.37,75.95 84.54,75.95 84.01,75.43 82.96,75.43 76.56,69.02 76.56,60.71 76.47,60.62 75.72,60.62 75.61,60.51 75.61,58.14 75.81,57.94 76.47,57.94 76.56,57.85 76.56,57.56 76.47,57.47 75.7,57.47 75.61,57.38 75.61,57.21 75.7,57.12 76.47,57.12 76.56,57.03 76.56,56.85 76.47,56.76 75.7,56.76 75.62,56.67 75.62,56.5 75.7,56.41 76.47,56.41 76.56,56.32 76.56,53.82 74.07,51.33 68.57,51.33 65.57,48.33 65.57,45.51 64.45,44.39 64.24,44.39 63.75,43.9 63.75,43.8 v2(63.29,43.34)
  BOTTOM w0.076: 88.52,75.84 88.64,75.73 91.21,75.73 CPU1.A24
  BOTTOM w0.089: 88.52,75.84 88.24,76.13 87.51,76.13 v2(87.03,76.61) ; v2(63.29,43.34) 63.68,42.95 RAM3.D7
M_A_DQ31: length 59.2
  L6 w0.089: v2(63.28,44.14) 63.83,44.68 64.44,44.68 65.25,45.49 65.25,48.43 68.46,51.63 73.96,51.63 75.32,52.99 75.32,53.83 75.43,53.94 76.16,53.94 76.25,54.03 76.25,54.21 76.16,54.3 75.43,54.3 75.32,54.41 75.32,54.6 75.41,54.69 76.17,54.69 76.26,54.78 76.26,54.95 76.17,55.04 75.41,55.04 75.32,55.13 75.32,55.31 75.41,55.4 76.17,55.4 76.26,55.49 76.26,55.66 76.17,55.75 75.41,55.75 75.32,55.84 75.32,60.91 75.41,61 76.18,61 76.27,61.09 76.27,69.15 82.84,75.72 83.08,75.72 83.08,75.72 83.89,75.72 84.42,76.24 85.15,76.24 v2(85.51,76.61)
  BOTTOM w0.076: 88.45,75.58 88.47,75.56 90.99,75.56 91.09,75.46 91.36,75.46 91.41,75.49 91.66,75.62 CPU1.B24
  BOTTOM w0.089: 88.45,75.58 88.2,75.83 86.29,75.83 v2(85.51,76.61) ; RAM3.C7 v2(63.28,44.14)
M_A_DQ32: length 40.2
  L4SGND w0.089: v2(72.58,46.42) 72.58,47.4 85.85,60.67 v2(88.64,60.67)
  BOTTOM w0.076: CPU1.H37 94.98,67.28 94.93,67.19 94.11,66.38
  BOTTOM w0.089: RAM2.C2 77.47,44.1 76.85,44.1 75.63,45.32 75.63,45.66 74.86,46.43 74.48,46.43 74.23,46.17 73.25,46.17 73.25,46.17 72.83,46.17 v2(72.58,46.42) ; v2(88.64,60.67) 89.68,61.71 89.68,64.01 91.78,66.11 93.85,66.11 94.11,66.38
M_A_DQ33: length 40.7
  L4SGND w0.089: v2(72.63,44.14) 72.48,43.99 72.15,43.99 72.06,44.08 72.06,44.38 71.97,44.47 71.34,44.47 71.25,44.56 71.25,46.89 86.59,62.23 86.6,62.23 87.35,62.99 87.48,62.99 87.57,62.9 87.57,62.32 87.66,62.23 87.84,62.23 87.92,62.32 87.92,63.12 88.02,63.21 v2(88.64,63.21)
  BOTTOM w0.076: 93.93,66.79 94.82,67.68 95,68.01 95,68.96 CPU1.H34
  BOTTOM w0.089: v2(72.63,44.14) RAM2.C8 ; v2(88.64,63.21) 88.64,63.83 88.82,64.01 91.33,66.52 93.66,66.52 93.93,66.79
M_A_DQ34: length 42.6
  L4SGND w0.089: v2(74.69,46) 74.75,46.06 74.75,47.48 84.72,57.45 86.85,57.45 86.94,57.36 86.94,57.13 87.02,57.04 87.2,57.04 87.29,57.13 87.29,57.36 87.38,57.45 87.56,57.45 87.65,57.36 87.65,57.13 87.74,57.04 87.91,57.04 88,57.13 88,57.36 88.09,57.45 88.65,57.45 90.62,59.42 90.62,61.41 90.96,61.75 v2(91.5,61.75)
  BOTTOM w0.076: CPU1.K34 95.85,69.54 95.61,69.3 95.61,68.62 95.64,68.56 95.64,68.56 95.71,68.35 95.71,68.12 95.67,68 95.67,67.82 95.71,67.7 95.71,67.28 95.27,66.84
  BOTTOM w0.089: 95.27,66.84 94.13,65.7 92.2,65.7 90.45,63.95 90.45,62.27 90.97,61.75 v2(91.5,61.75) ; v2(74.69,46) 75.39,45.3 75.39,45.22 76.87,43.74 RAM2.C3
M_A_DQ35: length 41.7
  L4SGND w0.089: v2(91.5,57.94) 90.41,57.94 86.88,54.41 86.59,54.41 86.5,54.5 86.5,55.35 86.41,55.44 86.23,55.44 86.15,55.35 86.15,54.5 86.06,54.41 82.91,54.41 75.76,47.26 75.76,45.53 74.85,44.62 74.62,44.62 73.87,43.87 73.87,43.78 v2(73.44,43.34)
  BOTTOM w0.076: CPU1.K35 96.87,68.59 96.87,67.98 97.01,67.73 97.01,67.36 96.83,67.19 96.83,66.22 95.97,65.36 95.52,65.36
  BOTTOM w0.089: v2(73.44,43.34) 73.83,42.95 RAM2.D7 ; v2(91.5,57.94) 91.93,57.94 92.54,58.55 92.54,62.75 93.85,64.05 94.22,64.05 95.52,65.36
M_A_DQ36: length 40.2
  L4SGND w0.089: v2(88.64,61.94) 87.91,61.94 87.83,61.85 87.83,61.05 87.74,60.96 87.56,60.96 87.47,61.05 87.47,61.85 87.38,61.94 87.2,61.94 87.11,61.85 87.11,61.15 87.03,61.06 86.85,61.06 86.76,61.15 86.76,61.5 86.67,61.59 86.36,61.59 72.15,47.38 72.15,46.69 72.06,46.6 71.89,46.6 71.81,46.52 71.81,46.34 71.89,46.25 72.06,46.25 72.15,46.16 72.15,45.98 72.06,45.89 71.92,45.89 71.83,45.8 71.83,45.63 71.92,45.54 72.06,45.54 72.15,45.45 72.15,45.03 72.24,44.94 v2(72.63,44.94)
  BOTTOM w0.076: 94.02,66.59 94.88,67.45 95.28,68.18 CPU1.H36
  BOTTOM w0.089: v2(72.63,44.94) RAM2.B8 ; 94.02,66.59 93.74,66.31 91.57,66.31 89.23,63.96 89.23,62.03 89.14,61.94 v2(88.64,61.94)
M_A_DQ37: length 41.3
  L4SGND w0.089: v2(88.64,59.4) 88.15,59.89 86.58,59.89 86.49,59.8 86.49,59.58 86.4,59.49 86.23,59.49 86.14,59.58 86.14,59.8 86.05,59.89 85.87,59.89 85.78,59.8 85.78,59.58 85.69,59.49 85.52,59.49 85.37,59.63 85.22,59.63 73.2,47.6 v2(73.2,46.61)
  BOTTOM w0.076: 94.35,66.24 95.54,67.44 95.54,67.68 95.5,67.79 95.5,68.03 95.54,68.14 95.54,68.33 95.47,68.53 95.47,68.53 95.38,68.79 CPU1.H35
  BOTTOM w0.089: 94.35,66.24 93.99,65.88 91.97,65.88 90.17,64.08 90.17,59.95 89.62,59.4 v2(88.64,59.4) ; v2(73.2,46.61) 73.4,46.81 75.56,46.81 RAM2.A3
M_A_DQ38: length 41
  L4SGND w0.089: v2(91.5,59.21) 91.27,59.21 87.79,55.73 85.58,55.73 85.49,55.64 85.49,55.22 85.4,55.14 85.22,55.14 85.13,55.22 85.13,55.64 85.05,55.73 84.87,55.73 84.78,55.64 84.78,55.1 84.69,55.01 84.51,55.01 84.42,55.1 84.42,55.64 84.33,55.73 84.04,55.73 83.95,55.64 83.95,54.85 83.86,54.76 83.69,54.76 83.6,54.85 83.6,55.14 83.51,55.23 83.32,55.23 75.43,47.34 75.43,45.51 74.85,44.93 74.23,44.93 v2(73.43,44.14)
  BOTTOM w0.076: CPU1.K36 96.58,68.17 96.85,67.68 96.85,67.43 96.67,67.25 96.67,66.29 95.98,65.61 95.51,65.61
  BOTTOM w0.089: 95.51,65.61 94.19,64.28 93.67,64.28 92.25,62.86 92.25,59.96 v2(91.5,59.21) ; v2(73.43,44.14) RAM2.C7
M_A_DQ39: length 40.3
  L4SGND w0.089: v2(74.69,45.36) 75.12,45.8 75.12,47.44 83.2,55.52 83.22,55.52 83.75,56.06 85.4,56.06 85.49,56.15 85.49,56.76 85.58,56.85 85.75,56.85 85.84,56.76 85.84,56.15 85.93,56.06 86.11,56.06 86.2,56.15 86.2,56.76 86.29,56.85 86.47,56.85 86.56,56.76 86.56,56.15 86.64,56.06 87.71,56.06 90.98,59.33 90.98,59.96 v2(91.5,60.48)
  BOTTOM w0.076: 95.35,65.78 95.43,65.86 95.96,65.86 96.49,66.39 96.49,67.49 CPU1.K37
  BOTTOM w0.089: 95.35,65.78 94.08,64.51 93.58,64.51 91.94,62.87 91.94,60.92 v2(91.5,60.48) ; v2(74.69,45.36) 77.03,43.02 RAM2.D3
M_A_DQ40: length 44
  L4SGND w0.089: v2(74.3,40.91) 74.3,43.07 76.19,44.97 76.19,45.13 76.62,45.57 76.62,46.78 81.32,51.47 83.49,51.47 83.58,51.56 83.58,51.83 83.67,51.92 83.85,51.92 83.94,51.83 83.94,51.56 84.02,51.47 84.32,51.47 84.41,51.56 84.41,51.98 84.49,52.07 84.67,52.07 84.76,51.98 84.76,51.56 84.85,51.47 85.03,51.47 85.12,51.56 85.12,51.98 85.21,52.07 85.93,52.07 90.37,56.52 90.4,56.53 91.1,56.53 92.35,57.78 92.35,59.93 v2(93.09,60.67)
  BOTTOM w0.076: CPU1.N36 97.8,68.18 97.47,67.57 97.47,66.26 97.02,65.82
  BOTTOM w0.089: v2(93.09,60.67) 93.43,60.67 93.52,60.76 93.52,62.53 95.53,64.54 95.75,64.54 97.02,65.82 ; RAM2.H8 73.19,39.74 73.55,40.1 73.94,40.1 74.18,40.34 74.18,40.8 v2(74.3,40.91)
M_A_DQ41: length 43.7
  L4SGND w0.089: v2(93.09,61.94) 92.36,61.94 92.06,61.64 92.06,57.9 90.98,56.82 90.26,56.82 85.8,52.36 83.41,52.36 83.29,52.24 83.29,51.82 83.23,51.77 83,51.77 82.94,51.83 82.94,52.28 82.85,52.37 82.66,52.37 82.57,52.28 82.57,51.87 82.48,51.78 82.25,51.78 82.16,51.87 82.16,52.27 82.07,52.36 81.8,52.36 76.29,46.86 76.29,45.69 73.86,43.26 73.86,42.16 v2(73.43,41.74)
  BOTTOM w0.076: CPU1.N34 97.48,68.88 97.48,68.78 97.48,68.78 97.48,68.53 97.48,68.53 97.48,67.94 97.3,67.62 97.3,66.36 96.36,65.42
  BOTTOM w0.089: v2(73.43,41.74) RAM2.F7 ; v2(93.09,61.94) 93.09,62.52 95.46,64.9 95.84,64.9 96.36,65.42
M_A_DQ42: length 43.9
  L4SGND w0.089: v2(94.61,59.91) 95.33,59.19 95.33,56.62 91.94,53.23 90.41,53.23 85.85,48.67 83.97,48.67 83.46,48.16 83.33,48.16 82.95,48.54 82.82,48.54 82.7,48.41 82.7,48.29 83.08,47.91 83.08,47.78 82.95,47.66 82.83,47.66 82.45,48.04 82.32,48.04 82.19,47.91 82.19,47.79 82.58,47.4 82.58,47.28 82.45,47.15 82.33,47.15 81.94,47.53 81.82,47.53 81.69,47.41 81.69,47.28 82.07,46.9 82.07,46.78 80.07,44.77 80.07,43.09 79.21,42.24 78.13,42.24 77.79,41.9 77.79,41.3 v2(77.44,40.94)
  BOTTOM w0.089: CPU1.R37 99.18,67.51 99.18,66.23 98.37,65.42 98.37,64.7 96.99,63.32 96.99,61.09 95.81,59.91 v2(94.61,59.91) ; RAM2.G2 77.83,40.55 v2(77.44,40.94)
M_A_DQ43: length 44.2
  L4SGND w0.089: v2(78.23,40.94) 78.84,40.94 80.37,42.48 80.37,44.66 82.78,47.07 83.31,47.07 83.4,47.16 83.4,47.51 83.49,47.6 83.67,47.6 83.75,47.51 83.75,47.16 83.84,47.07 84.66,47.07 84.99,47.39 84.99,47.52 84.68,47.83 84.68,47.96 84.8,48.08 84.93,48.08 85.24,47.77 85.41,47.77 90.24,52.6 91.71,52.6 95.62,56.5 95.62,59.53 v2(94.61,60.54)
  BOTTOM w0.076: 97.67,65.56 97.67,65.69 97.97,65.99 97.97,66.98 98.22,67.24 98.22,67.7 98.18,67.82 98.18,68 98.22,68.12 98.22,68.35 98.14,68.6 98.14,69.31 98.16,69.33 98.36,69.54 CPU1.R34
  BOTTOM w0.089: RAM2.H2 78.23,40.14 v2(78.23,40.94) ; 97.67,65.56 94.61,62.5 v2(94.61,60.54)
M_A_DQ44: length 43.6
  L4SGND w0.089: v2(93.09,59.4) 92.64,58.96 92.64,57.65 91.22,56.24 90.5,56.24 85.45,51.18 84.4,51.18 84.31,51.09 84.31,50.86 84.23,50.78 84.05,50.78 83.96,50.86 83.96,51.09 83.87,51.18 83.69,51.18 83.6,51.09 83.6,50.81 83.51,50.72 83.34,50.72 83.25,50.81 83.25,51.09 83.16,51.18 82.98,51.18 82.89,51.09 82.89,50.81 82.8,50.72 82.62,50.72 82.54,50.81 82.54,51.09 82.45,51.18 82.27,51.18 82.18,51.09 82.18,50.81 82.09,50.72 81.91,50.72 81.82,50.81 81.82,51.09 81.74,51.18 81.44,51.18 77,46.73 77,45.37 77.04,45.33 77.04,44.77 74.68,42.41 74.68,41.72 v2(74.72,41.67)
  BOTTOM w0.076: CPU1.N37 97.64,67.42 97.64,66.17 97.24,65.78 97.24,65.71
  BOTTOM w0.089: 97.24,65.71 95.72,64.19 95.67,64.19 93.83,62.34 93.83,59.96 93.27,59.4 v2(93.09,59.4) ; RAM2.H7 74.11,39.74 74.72,40.35 v2(74.72,41.67)
M_A_DQ45: length 43.7
  L4SGND w0.089: v2(75.31,41.42) 75.31,41.42 75.31,42.72 77.44,44.85 77.44,45.49 77.21,45.72 77.21,46.47 79.51,48.77 79.64,48.77 79.78,48.62 79.91,48.62 80.03,48.75 80.03,48.87 79.86,49.05 79.86,49.17 81.12,50.43 81.52,50.43 85.11,50.43 90.63,55.94 91.35,55.94 93.09,57.69 v2(93.09,58.13)
  BOTTOM w0.076: 97.46,65.66 97.46,65.73 97.8,66.08 97.8,67.09 98.06,67.35 98.06,67.68 98.02,67.79 98.02,68.03 98.06,68.14 98.06,68.32 97.89,68.79 CPU1.N35
  BOTTOM w0.089: v2(75.31,41.42) 75.31,41.42 75.17,41.28 75.17,40.28 RAM2.J7 ; 97.46,65.66 97.46,65.62 94.18,62.34 94.18,59.06 93.25,58.13 v2(93.09,58.13)
M_A_DQ46: length 44.8
  L4SGND w0.089: v2(76.37,40.77) 77.49,41.89 77.49,41.9 78.13,42.55 78.98,42.55 79.76,43.32 79.76,44.97 80.14,45.35 80.14,45.48 79.8,45.82 79.8,45.95 79.93,46.08 80.05,46.08 80.4,45.73 80.52,45.73 80.65,45.86 80.65,45.98 80.3,46.33 80.3,46.45 80.43,46.58 80.55,46.58 80.81,46.32 80.94,46.32 81.06,46.45 81.06,46.57 80.81,46.83 80.81,46.96 82.81,48.96 85.72,48.96 91.24,54.47 92.76,54.47 95.04,56.74 95.04,58.85 v2(94.61,59.27)
  BOTTOM w0.076: 98.62,65.41 99.36,66.16 99.36,67.7 99.18,68.04 99.18,68.15 CPU1.R36
  BOTTOM w0.089: 98.62,65.41 98.62,64.6 97.28,63.27 97.28,60.81 95.75,59.27 v2(94.61,59.27) ; v2(76.37,40.77) 76.37,40.4 RAM2.H3
M_A_DQ47: length 44.2
  L4SGND w0.089: v2(75.66,40.89) 76.19,41.43 76.5,41.43 77.93,42.85 78.34,42.85 78.67,43.18 78.67,45.29 82.63,49.25 85.6,49.25 91.12,54.76 92.64,54.76 94.61,56.73 v2(94.61,58.64)
  BOTTOM w0.076: CPU1.R35 99.11,68.89 99.42,68.58 99.42,67.94 99.53,67.74 99.53,66.07 98.84,65.39
  BOTTOM w0.089: v2(94.61,58.64) 95.67,58.64 97.6,60.56 97.6,63.31 98.84,64.56 98.84,65.39 ; RAM2.J3 75.66,40.31 v2(75.66,40.89)
M_A_DQ48: length 41.1
  L6 w0.089: v2(93.9,70.92) 93.33,70.35 93.33,69.91 92.99,69.56 92.84,69.56 91.74,68.46 91.74,67.96 90.4,66.62 89.66,66.62 83.95,60.91 83.95,58.12 83.48,57.66 83.48,54.85 83.57,54.76 83.88,54.76 83.97,54.67 83.97,54.5 83.88,54.41 83.57,54.41 83.48,54.32 83.48,54.14 83.57,54.05 83.88,54.05 83.97,53.96 83.97,53.79 83.88,53.7 83.57,53.7 83.48,53.61 83.48,53.43 83.57,53.34 83.88,53.34 83.97,53.25 83.97,53.07 83.88,52.98 83.57,52.98 83.48,52.9 83.48,52.72 83.57,52.63 83.88,52.63 83.97,52.54 83.97,52.36 83.88,52.27 83.57,52.27 83.48,52.18 83.48,52.01 83.57,51.92 83.88,51.92 83.97,51.83 83.97,51.65 83.88,51.56 83.57,51.56 83.48,51.47 83.48,51.3 83.57,51.21 83.88,51.21 83.97,51.12 83.97,50.94 83.88,50.85 83.57,50.85 83.48,50.76 83.48,50.58 83.57,50.5 83.88,50.5 83.97,50.41 83.97,50.23 83.88,50.14 83.57,50.14 83.48,50.05 83.48,49.87 83.57,49.78 83.88,49.78 83.97,49.7 83.97,49.52 83.88,49.43 83.57,49.43 83.48,49.34 83.48,49.16 83.57,49.07 83.88,49.07 83.97,48.98 83.97,48.81 83.88,48.72 83.57,48.72 83.48,48.63 83.48,48.34 84.93,46.89 v2(84.93,46.01)
  BOTTOM w0.089: RAM1.C3 86.94,43.74 85.26,45.42 85.26,45.68 v2(84.93,46.01) ; CPU1.G31 v2(93.9,70.92)
M_A_DQ49: length 43
  L6 w0.089: v2(94.86,70.35) 94.86,70.35 93.9,69.39 92.92,69.39 91.92,68.38 91.92,67.89 90.29,66.27 89.72,66.27 84.85,61.41 84.85,61.16 84.75,61.06 84.54,61.06 84.45,60.97 84.45,60.74 84.54,60.65 84.92,60.65 85.01,60.56 85.01,60.39 84.92,60.3 84.35,60.3 84.26,60.21 84.26,60.03 84.35,59.94 84.92,59.94 85.01,59.85 85.01,59.68 84.92,59.59 84.35,59.59 84.26,59.5 84.26,59.32 84.35,59.23 84.92,59.23 85.01,59.14 85.01,58.96 84.92,58.87 84.35,58.87 84.26,58.79 84.26,58.61 84.35,58.52 84.92,58.52 85.01,58.43 85.01,58.25 84.92,58.16 84.35,58.16 84.26,58.07 84.26,57.78 84.17,57.69 83.98,57.69 83.89,57.6 83.89,57.43 83.98,57.34 84.17,57.34 84.26,57.25 84.26,57.07 84.17,56.98 83.86,56.98 83.78,56.89 83.78,56.72 83.86,56.63 84.17,56.63 84.26,56.54 84.26,56.36 84.17,56.27 83.86,56.27 83.78,56.18 83.78,56 83.86,55.92 84.17,55.92 84.26,55.83 84.26,55.65 84.17,55.56 83.86,55.56 83.78,55.47 83.78,55.29 83.86,55.2 84.17,55.2 84.26,55.12 84.26,48.31 84.26,48.07 85.36,46.97 85.36,45.82 84.91,45.36 v2(84.82,45.36)
  BOTTOM w0.089: v2(94.86,70.35) CPU1.G32 ; v2(84.82,45.36) 84.82,44.79 86.05,43.56 86.57,43.56 86.82,43.31 86.82,43.3 RAM1.D3
M_A_DQ50: length 42
  L6 w0.089: v2(82.78,44.94) 82.78,45.17 80.85,47.09 80.85,47.79 80.77,47.88 80.4,47.88 80.31,47.97 80.31,48.15 80.4,48.24 80.77,48.24 80.85,48.32 80.85,48.5 80.77,48.59 80.4,48.59 80.31,48.68 80.31,48.86 80.4,48.95 80.77,48.95 80.85,49.04 80.85,49.21 80.77,49.3 80.4,49.3 80.31,49.39 80.31,49.57 80.4,49.66 80.77,49.66 80.95,49.84 80.95,50.22 80.89,50.29 80.65,50.29 80.56,50.38 80.56,50.56 80.65,50.64 81.02,50.64 81.08,50.71 81.08,60.57 88.71,68.2 89.61,68.2 91.36,69.94 91.36,70.76 93.89,73.3 95.07,73.3 95.37,72.99 95.37,72.67 v2(95.78,72.26)
  BOTTOM w0.089: CPU1.H29 v2(95.78,72.26) ; RAM1.B8 v2(82.78,44.94)
M_A_DQ51: length 42.1
  L6 w0.089: v2(82.78,44.14) 82.31,44.61 82.31,45.14 81.62,45.84 81.49,45.84 81.36,45.71 81.23,45.71 81.11,45.83 81.11,45.96 81.24,46.09 81.24,46.22 81.11,46.34 80.99,46.34 80.86,46.21 80.73,46.21 80.61,46.34 80.61,46.46 80.74,46.59 80.74,46.72 80.61,46.84 80.48,46.84 80.35,46.71 80.23,46.71 80.1,46.84 80.1,46.97 80.23,47.1 80.23,47.22 80,47.45 80,50.62 80.79,51.41 80.79,60.69 88.08,67.98 88.08,69.53 89.32,70.78 90.99,70.78 93.68,73.47 95.2,73.47 v2(95.78,72.9)
  BOTTOM w0.089: CPU1.H28 v2(95.78,72.9) ; v2(82.78,44.14) RAM1.C8
M_A_DQ52: length 41.2
  L6 w0.089: v2(82.73,46.42) 81.15,48.01 81.15,49.51 81.37,49.73 81.37,60.45 88.72,67.79 89.46,67.79 91.69,70.02 91.69,70.84 93.74,72.9 94.9,72.9 v2(94.91,72.89)
  BOTTOM w0.089: v2(94.91,72.89) 94.91,72.89 CPU1.G28 ; RAM1.C2 87.37,44.1 86.89,44.1 86.24,44.75 85.43,46.22 85.2,46.44 84.77,46.44 83.37,46.17 82.98,46.17 v2(82.73,46.42)
M_A_DQ53: length 42.8
  L6 w0.089: v2(94.89,72.24) 94.44,71.8 93.26,71.8 91.92,70.45 91.92,70 89.4,67.49 88.83,67.49 81.68,60.34 81.68,51.89 81.77,51.8 82.19,51.8 82.28,51.71 82.28,51.54 82.19,51.45 81.77,51.45 81.68,51.36 81.68,51.18 81.77,51.09 82.19,51.09 82.28,51 82.28,50.82 82.19,50.74 81.77,50.74 81.68,50.65 81.68,50.43 81.77,50.34 82.17,50.34 82.26,50.25 82.26,50.01 82.17,49.92 82.07,49.92 81.98,49.83 81.98,49.65 82.07,49.56 82.17,49.56 82.26,49.48 82.26,48.87 82.17,48.78 81.57,48.78 81.48,48.69 81.48,48.51 81.57,48.43 82.15,48.43 82.26,48.31 82.26,48.13 82.17,48.04 81.98,48.04 81.89,47.96 81.89,47.78 81.98,47.69 82.26,47.69 v2(83.35,46.61)
  BOTTOM w0.089: v2(83.35,46.61) 83.58,46.84 86.35,46.84 87.18,46.01 RAM1.A3 ; CPU1.G29 v2(94.89,72.24)
M_A_DQ54: length 42.2
  L6 w0.089: v2(83.58,44.14) 84.38,44.93 84.99,44.93 85.67,45.62 85.67,47.19 84.55,48.31 84.55,53.34 84.64,53.43 85.21,53.43 85.3,53.52 85.3,53.7 85.21,53.79 84.64,53.79 84.55,53.88 84.55,54.05 84.64,54.14 85.21,54.14 85.3,54.23 85.3,54.41 85.21,54.5 84.64,54.5 84.55,54.59 84.55,54.76 84.64,54.85 85.21,54.85 85.3,54.94 85.3,55.12 85.21,55.21 84.64,55.21 84.55,55.3 84.55,55.48 84.64,55.56 85.21,55.56 85.3,55.65 85.3,55.83 85.21,55.92 84.64,55.92 84.55,56.01 84.55,56.19 84.64,56.28 85.21,56.28 85.3,56.36 85.3,56.54 85.21,56.63 84.64,56.63 84.55,56.72 84.55,56.9 84.64,56.99 85.21,56.99 85.3,57.08 85.3,57.25 85.21,57.34 85.05,57.34 84.96,57.43 84.96,57.61 85.05,57.7 85.21,57.7 85.3,57.79 85.3,61.44 89.9,66.04 90.42,66.04 92.93,68.56 93.71,68.56 95.34,70.19 95.34,70.55 v2(95.76,70.97)
  BOTTOM w0.089: v2(95.76,70.97) 95.75,70.96 CPU1.H31 ; RAM1.C7 v2(83.58,44.14)
M_A_DQ55: length 42.9
  L6 w0.089: v2(95.77,70.35) 95.77,70.34 93.71,68.28 92.9,68.28 90.49,65.86 90.15,65.86 85.59,61.31 85.59,53.07 85.5,52.99 84.97,52.99 84.88,52.9 84.88,52.72 84.97,52.63 85.5,52.63 85.59,52.54 85.59,52.36 85.5,52.27 84.97,52.27 84.88,52.19 84.88,52.01 84.97,51.92 85.5,51.92 85.59,51.83 85.59,51.65 85.5,51.56 84.97,51.56 84.88,51.47 84.88,51.3 84.97,51.21 85.5,51.21 85.59,51.12 85.59,50.94 85.5,50.85 84.97,50.85 84.88,50.76 84.88,50.59 84.97,50.5 85.5,50.5 85.59,50.41 85.59,50.23 85.5,50.14 84.97,50.14 84.88,50.05 84.88,49.87 84.97,49.79 85.5,49.79 85.59,49.7 85.59,49.52 85.5,49.43 84.97,49.43 84.88,49.34 84.88,49.16 84.97,49.07 85.5,49.07 85.59,48.99 85.59,48.81 85.5,48.72 85.02,48.72 84.93,48.63 84.93,48.45 85.02,48.36 85.5,48.36 85.59,48.27 85.59,47.88 85.98,47.49 85.98,45.62 85.07,44.7 84.85,44.7 84.12,43.97 84.12,43.43 84.03,43.34 v2(83.59,43.34)
  BOTTOM w0.089: RAM1.D7 83.98,42.95 v2(83.59,43.34) ; CPU1.H32 v2(95.77,70.35)
M_A_DQ56: length 45.3
  L6 w0.089: v2(84.95,40.89) 84.99,40.93 84.99,43 86.48,44.5 86.86,44.5 87.13,44.77 87.13,48.27 87.04,48.36 86.85,48.36 86.76,48.45 86.76,48.63 86.85,48.72 87.04,48.72 87.13,48.81 87.13,48.98 87.04,49.07 86.85,49.07 86.76,49.16 86.76,49.34 86.85,49.43 87.04,49.43 87.13,49.52 87.13,49.7 87.04,49.78 86.85,49.78 86.76,49.87 86.76,50.05 86.85,50.14 87.04,50.14 87.13,50.23 87.13,50.41 87.04,50.5 86.85,50.5 86.76,50.58 86.76,50.76 86.85,50.85 87.04,50.85 87.13,50.94 87.13,51.12 87.04,51.21 86.85,51.21 86.76,51.3 86.76,51.47 86.85,51.56 87.04,51.56 87.13,51.65 87.13,51.83 87.04,51.92 86.85,51.92 86.76,52.01 86.76,52.18 86.85,52.27 87.04,52.27 87.13,52.36 87.13,52.54 87.04,52.63 86.85,52.63 86.76,52.72 86.76,52.9 86.85,52.98 87.04,52.98 87.13,53.07 87.13,53.25 87.04,53.34 86.85,53.34 86.76,53.43 86.76,53.61 86.85,53.7 87.04,53.7 87.13,53.78 87.13,53.96 87.04,54.05 86.85,54.05 86.76,54.14 86.76,54.32 86.85,54.41 87.04,54.41 87.13,54.5 87.13,54.67 87.04,54.76 86.85,54.76 86.76,54.85 86.76,55.03 86.85,55.12 87.04,55.12 87.13,55.21 87.13,55.38 87.04,55.47 86.85,55.47 86.76,55.56 86.76,55.74 86.85,55.83 87.04,55.83 87.13,55.92 87.13,56.27 89.6,58.75 89.6,63.83 91.53,65.76 92.93,65.76 95.95,68.78 96.56,68.78 96.77,68.99 96.77,69.37 97.29,69.89 97.29,69.89 97.3,69.9 97.3,70.99 v2(96.72,71.58)
  BOTTOM w0.089: v2(84.95,40.89) 84.95,40.71 RAM1.H7 ; CPU1.L31 v2(96.72,71.58)
M_A_DQ57: length 46.4
  L6 w0.089: v2(84.56,41.42) 84.58,41.44 84.58,43.22 86.2,44.84 86.2,45.13 86.81,45.73 86.81,47.8 86.47,48.15 86.47,56.6 86.56,56.69 87.08,56.69 87.17,56.78 87.17,56.95 87.08,57.04 86.58,57.04 86.47,57.16 86.47,57.33 86.56,57.42 87.1,57.42 87.19,57.51 87.19,57.69 87.1,57.78 86.56,57.78 86.47,57.87 86.47,58.05 86.56,58.14 87.1,58.14 87.19,58.22 87.19,58.4 87.1,58.49 86.56,58.49 86.47,58.58 86.47,58.89 86.56,58.98 87.53,58.98 87.62,58.89 87.62,57.7 87.71,57.61 87.98,57.61 89.22,58.85 89.22,63.89 92.95,67.62 94.38,67.62 96.52,69.76 96.88,69.76 97.12,69.99 97.12,70.54 v2(96.74,70.92)
  BOTTOM w0.089: v2(84.56,41.42) 84.56,41.4 84.33,41.17 84.33,40.69 84.33,40.68 84.33,40.4 84.04,40.1 83.54,40.1 RAM1.H8 ; CPU1.L32 v2(96.74,70.92)
M_A_DQ58: length 44.2
  L6 w0.089: v2(87.59,40.94) 87.59,41.93 88.16,42.49 89.4,42.49 90.21,43.31 90.21,51.23 90.05,51.39 89.74,51.39 89.65,51.48 89.65,51.66 89.74,51.75 90.05,51.75 90.14,51.84 90.14,52.02 90.05,52.11 89.92,52.11 89.83,52.19 89.83,52.37 89.92,52.46 90.05,52.46 90.14,52.55 90.14,54.14 93.57,57.56 93.57,62.33 93.66,62.42 94.04,62.42 94.13,62.51 94.13,62.69 94.04,62.78 93.66,62.78 93.57,62.87 93.57,63.5 93.72,63.65 93.85,63.65 94.34,63.16 94.47,63.16 94.59,63.28 94.59,63.41 94.1,63.91 94.1,64.03 94.25,64.18 94.38,64.18 94.64,63.92 94.77,63.92 94.9,64.04 94.9,64.17 94.63,64.44 94.63,64.56 99.43,69.37 99.43,71.93 99.15,72.21 v2(98.52,72.21)
  BOTTOM w0.089: CPU1.N29 v2(98.52,72.21) ; RAM1.H2 87.59,40.13 87.59,40.94 v2(87.59,40.94)
M_A_DQ59: length 44
  L6 w0.089: v2(98.52,72.87) 99.38,72.87 99.69,72.57 99.69,69.37 96.39,66.07 96.39,65.81 95.32,64.75 95.32,62.7 95.23,62.61 94.72,62.61 94.63,62.52 94.63,62.34 94.72,62.26 95.23,62.26 95.32,62.17 95.32,61.99 95.23,61.9 94.11,61.9 94.02,61.81 94.02,61.63 94.11,61.54 95.23,61.54 95.32,61.46 95.32,61.24 95.15,61.07 94.27,61.07 94.15,60.96 94.15,57.73 90.44,54.03 90.44,51.49 90.53,51.4 90.53,43.19 89.51,42.18 88.21,42.18 87.95,41.91 87.95,41.38 v2(88.38,40.94)
  BOTTOM w0.089: RAM1.G2 v2(88.38,40.94) ; CPU1.N28 v2(98.52,72.87)
M_A_DQ60: length 42.1
  L6 w0.089: v2(97.63,72.87) 97.2,72.44 97.2,71.45 97.68,70.97 97.68,69.04 97.1,68.45 95.93,68.45 92.91,65.43 91.64,65.43 90.06,63.86 90.06,58.75 87.45,56.13 87.45,46.28 87.36,46.19 87.36,44.51 87.01,44.17 86.71,44.17 85.77,43.23 85.37,42.21 85.37,40.87 85.41,40.84 v2(85.41,40.37)
  BOTTOM w0.089: RAM1.J7 v2(85.41,40.37) ; CPU1.L28 v2(97.63,72.87)
M_A_DQ61: length 43.1
  L6 w0.089: v2(83.58,41.74) 84.07,42.22 84.07,43.08 84.33,43.34 84.33,43.58 86.48,45.73 86.48,47.68 86.18,47.98 86.18,59.29 86.26,59.38 87.64,59.38 87.72,59.47 87.72,59.65 87.64,59.73 86.53,59.73 86.44,59.82 86.44,60 86.53,60.09 87.59,60.09 87.67,60.18 87.67,60.36 87.59,60.45 86.83,60.45 86.74,60.53 86.74,60.76 86.83,60.85 88.04,60.85 88.15,60.97 88.15,63.32 88.5,63.67 88.72,63.67 92.91,67.86 94.01,67.86 96.29,70.15 96.29,71.84 v2(96.69,72.24)
  BOTTOM w0.089: CPU1.L29 v2(96.69,72.24) ; v2(83.58,41.74) RAM1.F7
M_A_DQ62: length 44.6
  L6 w0.089: v2(86.33,40.67) 86.54,40.67 87.29,41.42 87.29,42.03 88.16,42.9 88.59,42.9 88.81,43.12 88.81,43.53 89.02,43.74 89.38,43.74 89.9,44.26 89.9,49.54 89.36,50.08 89.36,52.94 89.45,53.03 89.76,53.03 89.85,53.11 89.85,53.29 89.76,53.38 89.45,53.38 89.36,53.47 89.36,53.65 89.45,53.74 89.76,53.74 89.85,53.83 89.85,54 89.76,54.09 89.45,54.09 89.36,54.18 89.36,54.64 89.56,54.85 89.69,54.85 90,54.54 90.13,54.54 90.25,54.66 90.25,54.79 89.94,55.1 89.94,55.23 90.07,55.35 90.19,55.35 90.5,55.04 90.63,55.04 90.76,55.17 90.76,55.29 90.44,55.6 90.44,55.73 90.57,55.86 90.7,55.86 91.01,55.54 91.13,55.54 91.64,56.05 92.96,57.37 92.96,57.61 92.6,57.96 92.6,63.04 95.83,66.27 96,66.27 98.57,68.84 98.57,70.23 99.15,70.82 99.15,71.62 99.07,71.71 98.7,71.71 v2(98.52,71.53)
  BOTTOM w0.089: v2(86.33,40.67) 86.33,40.59 RAM1.H3 ; CPU1.N31 v2(98.52,71.53)
M_A_DQ63: length 46.1
  L6 w0.089: v2(98.52,70.84) 98.32,70.64 98.32,68.85 97.05,67.58 96.02,67.58 94.58,66.15 94.58,65.53 92.14,63.09 92.14,57.89 92.46,57.57 92.46,57.44 92.23,57.21 92.11,57.21 91.84,57.48 91.71,57.48 91.48,57.25 91.48,57.12 91.77,56.83 91.77,56.7 91.65,56.58 91.52,56.58 91.23,56.87 91.1,56.87 90.98,56.74 90.98,56.62 91.31,56.29 91.31,56.16 91.18,56.04 91.06,56.04 90.72,56.37 90.6,56.37 89.05,54.81 89.05,54.37 88.96,54.28 88.74,54.28 88.65,54.19 88.65,54.01 88.74,53.92 88.96,53.92 89.05,53.83 89.05,53.66 88.96,53.57 88.74,53.57 88.65,53.48 88.65,53.3 88.74,53.21 88.96,53.21 89.05,53.12 89.05,52.95 88.96,52.86 88.74,52.86 88.65,52.77 88.65,52.59 88.74,52.5 88.96,52.5 89.05,52.41 89.05,52.23 88.96,52.15 88.74,52.15 88.65,52.06 88.65,51.88 88.74,51.79 88.96,51.79 89.05,51.7 89.05,51.52 88.96,51.43 88.74,51.43 88.65,51.35 88.65,51.17 88.74,51.08 88.96,51.08 89.05,50.99 89.05,50.81 88.96,50.72 88.74,50.72 88.65,50.63 88.65,50.46 88.74,50.37 88.96,50.37 89.05,50.28 89.05,49.94 89.58,49.4 89.58,46.08 89.03,45.52 89.03,44.62 87.45,43.04 87.45,42.6 87,42.15 87,41.78 86.72,41.5 86.25,41.5 v2(85.8,41.05)
  BOTTOM w0.089: v2(85.8,41.05) 85.8,40.63 85.94,40.49 85.94,40.18 RAM1.J3 ; CPU1.N32 v2(98.52,70.84)
M_A_DQS_DN0: length 63.3
  L4SGND w0.089: v2(84.5,73.43) 84.5,72.4 84.24,72.14 83.51,72.14 83.29,71.92 83.29,71.15 83.19,71.06 82.87,71.06 82.78,71.15 82.78,72.8 82.58,73 82.11,73 81.91,72.8 81.91,71.15 81.82,71.06 79.95,71.06 77.98,69.09 77.98,64.22 74.08,60.32 74.08,57.89 70.57,54.39 69.33,54.39 68.11,53.17 60.36,53.17 53.76,46.56 53.76,45.62 53.52,45.39 53.24,45.39 53.13,45.49 53.13,45.69 53.13,45.69 v2(53.13,45.73)
  BOTTOM w0.076: CPU1.C27 92.32,73.81 92.42,73.85 92.46,73.98 92.42,74.07 92.29,74.12 92.13,74.12 92,74.07 91.77,74.07 91.65,74.11 91.47,74.11 91.35,74.07 90.99,74.07 90.61,74.46 89.61,74.46 89.05,73.9 88.57,73.9 88.53,73.86 88.52,73.86
  BOTTOM w0.102: 88.52,73.86 87.28,73.86 86.04,72.61 84.96,72.61 84.73,72.85 84.73,73.2 v2(84.5,73.43) ; v2(53.13,45.73) 53.13,45.69 53.13,45.69 53.13,45.51 53.31,45.34 RAM4.A7
M_A_DQS_DN1: length 56.4
  L4SGND w0.089: v2(87.04,69.75) 87.28,69.51 87.55,69.51 87.8,69.26 87.8,67.75 87.55,67.51 86.91,67.51 86.82,67.41 86.82,65.72 72.03,50.93 70.78,50.93 68.65,48.8 67.47,48.8 67.27,49 67.27,49.28 67.18,49.37 66.86,49.37 66.78,49.28 66.78,49 66.57,48.8 61.86,48.8 59.15,46.09 58.87,46.09 56.81,44.03 56.81,43.03 56.12,42.34 v2(56.12,41.95)
  BOTTOM w0.076: 88.82,70.95 88.87,70.95 89.29,71.37 89.79,71.37 90.1,71.68 91.23,71.68 91.41,71.75 91.46,71.77 91.66,71.77 91.79,71.72 91.98,71.72 92.09,71.76 92.33,71.76 92.54,71.69 92.64,71.47 92.77,71.33 CPU1.D31
  BOTTOM w0.102: v2(56.12,41.95) 55.9,41.77 55.9,41.38 56.26,41.01 56.63,41.01 56.73,41.12 RAM4.F3 ; v2(87.04,69.75) 87.28,69.51 87.39,69.51 87.97,70.09 88.82,70.95
M_A_DQS_DN2: length 60.1
  L6 w0.089: v2(66.47,41.73) 66.2,42 66.2,42.22 68.47,44.49 68.47,46.18 69.28,46.99 69.42,46.99 69.76,46.65 70.07,46.65 70.41,46.99 70.41,47.28 70.07,47.62 70.07,47.78 70.3,48.01 70.44,48.01 70.83,47.61 71.13,47.61 71.7,48.18 72.63,48.18 72.83,48.38 72.83,48.75 72.92,48.84 73.24,48.84 73.33,48.75 73.33,48.38 73.53,48.18 74.52,48.18 79.01,52.66 79.01,62.35 79.55,62.88 79.55,63.17 79.09,63.62 79.09,63.77 79.32,63.99 79.45,63.99 80.04,63.41 80.32,63.41 80.69,63.77 80.69,64.05 80.38,64.36 80.38,64.52 80.59,64.73 80.75,64.73 81.39,64.1 81.75,64.1 84.71,67.07 84.71,70.7 87.17,73.15 90.81,73.15 92.24,74.59 94.35,74.59 94.55,74.79 94.98,74.79 v2(95.45,75.26)
  BOTTOM w0.102: v2(66.47,41.73) 66.19,41.45 66.19,41.2 66.33,41.05 66.78,41.05 66.88,41.16 RAM3.F3 ; CPU1.H24 95.45,75.4 v2(95.45,75.26)
M_A_DQS_DN3: length 58.3
  L6 w0.089: v2(88.89,76.63) 88.66,76.86 88.66,77.23 88.46,77.43 86.86,77.43 86.77,77.52 86.77,77.69 86.57,77.89 86.09,77.89 85.89,77.69 85.89,77.52 85.8,77.43 85.49,77.43 85.4,77.52 85.4,77.69 85.2,77.89 84.72,77.89 84.52,77.69 84.52,77.52 84.43,77.43 84.11,77.43 84.02,77.52 84.02,77.69 83.82,77.89 83.35,77.89 83.15,77.69 83.15,77.21 82.98,77.04 82.37,77.04 75,69.67 75,65.56 74.87,65.44 74.47,65.44 74.03,65 74.03,54.39 73.59,53.95 73.59,53.66 73.84,53.41 73.84,53.31 73.59,53.06 73.49,53.06 73.24,53.31 72.95,53.31 72.61,52.96 67.96,52.96 63.85,48.86 63.85,45.52 63.67,45.34 63.48,45.34 63.28,45.53 v2(63.28,45.74)
  BOTTOM w0.076: v2(88.89,76.63) 88.89,76.26 89,76.15 91.16,76.15 91.35,76.15 91.47,76.1 91.64,76.1 91.78,76.15 91.98,76.15 92.11,76.1 92.3,76.1 92.41,76.14 92.46,76.24 92.42,76.36 92.38,76.38 CPU1.C23
  BOTTOM w0.102: v2(63.28,45.74) 63.28,45.55 63.49,45.34 RAM3.A7
M_A_DQS_DN4: length 40.5
  L4SGND w0.089: v2(91.68,63.34) 92,63.34 92.14,63.19 92.14,62.79 91.81,62.46 90.7,62.46 89.77,61.53 89.77,59.54 88.37,58.13 87.26,58.13 87.17,58.22 87.17,58.54 86.97,58.74 86.17,58.74 85.96,58.53 85.96,58.22 85.87,58.13 84.43,58.13 74.06,47.76 74.06,45.54 73.81,45.29 73.68,45.29 73.43,45.54 v2(73.43,45.74)
  BOTTOM w0.076: CPU1.J35 95.91,68.58 95.91,68.72 95.94,68.77 96.06,68.81 96.16,68.76 96.21,68.63 96.21,68.48 96.15,68.33 96.15,68.12 96.2,68 96.2,67.82 96.12,67.62 96.12,66.57 95.8,66.24 95.12,66.24 94.91,66.04 94.87,66 94.84,66 94.83,65.99
  BOTTOM w0.102: v2(73.43,45.74) 73.61,45.74 73.83,45.52 RAM2.A7 ; 94.83,65.99 93.92,65.09 92.3,65.09 91.6,64.39 91.46,64.25 91.46,63.91 91.68,63.69 v2(91.68,63.34)
M_A_DQS_DN5: length 43.6
  L4SGND w0.089: v2(95.72,61.31) 95.43,61.31 95.34,61.4 95.34,61.69 95.28,61.75 94.4,61.75 94.1,61.45 94.1,56.92 92.44,55.26 90.91,55.26 85.4,49.75 81.43,49.75 80.97,49.29 80.97,48.5 78.29,45.82 78.29,44.22 76.28,42.22 76.28,42.09 v2(76.42,41.95)
  BOTTOM w0.076: CPU1.P34 98.45,69.12 98.58,68.99 98.8,68.89 98.88,68.68 98.88,68.44 98.84,68.33 98.84,68.14 98.88,68.03 98.88,67.79 98.86,67.73 98.84,67.68 98.84,67.32 98.99,67.17 98.99,66.38 98.63,66.02 98.63,65.97 98.62,65.96
  BOTTOM w0.102: v2(95.72,61.31) 95.95,61.54 96.24,61.54 96.48,61.77 96.48,63.4 98.14,65.06 98.14,65.48 98.46,65.8 98.62,65.96 ; RAM2.F3 76.95,41.26 76.81,41.26 76.64,41.43 76.25,41.43 76.15,41.53 76.15,41.74 76.21,41.8 76.21,41.8 76.37,41.95 v2(76.42,41.95)
M_A_DQS_DN6: length 41.7
  L6 w0.089: v2(83.58,45.74) 83.58,45.62 83.81,45.39 83.94,45.39 84.3,45.75 84.3,46.43 82.79,47.94 82.79,52.23 82.69,52.33 82.42,52.33 82.19,52.56 82.19,53.02 82.42,53.25 82.69,53.25 82.78,53.33 82.78,53.79 82.69,53.87 82.4,53.87 82.18,54.09 82.18,54.55 82.41,54.77 82.68,54.77 82.79,54.88 82.79,55.2 82.69,55.29 82.4,55.29 82.19,55.5 82.19,55.98 82.42,56.21 82.69,56.21 82.78,56.29 82.78,56.63 82.68,56.73 82.39,56.73 82.19,56.92 82.19,57.41 82.42,57.63 82.69,57.63 82.78,57.71 82.78,58.06 82.68,58.15 82.39,58.15 82.18,58.36 82.18,58.82 82.41,59.04 83.09,59.04 83.2,59.16 83.2,59.5 83.11,59.6 82.59,59.6 82.38,59.8 82.38,60.29 82.59,60.49 83.11,60.49 83.2,60.58 83.2,61.16 89.15,67.11 89.37,67.11 92.23,69.97 92.23,70.49 93.32,71.58 94.16,71.58 94.78,70.96 94.99,70.96 95.14,71.1 95.14,71.31 v2(94.88,71.58)
  BOTTOM w0.102: CPU1.G30 94.41,71.67 94.62,71.47 94.77,71.47 v2(94.88,71.58) ; v2(83.58,45.74) RAM1.A7
M_A_DQS_DN7: length 43.7
  L6 w0.089: v2(86.57,41.95) 86.57,42.34 87.08,42.86 87.08,43.37 88.44,44.72 88.44,46.27 88.58,46.42 88.86,46.42 89.06,46.61 89.06,47.54 88.85,47.74 88.25,47.74 88.14,47.86 88.14,48.16 88.23,48.25 88.85,48.25 89.06,48.46 89.06,49.14 88.8,49.4 88.27,49.4 88.14,49.53 88.14,54.67 88.64,55.18 88.64,55.48 88.28,55.85 88.28,55.97 88.52,56.22 88.67,56.22 89.01,55.87 89.35,55.87 89.68,56.2 89.68,56.51 89.31,56.88 89.31,57 89.56,57.25 89.7,57.25 90.05,56.89 90.37,56.89 90.77,57.29 90.77,59.04 90.77,59.05 90.77,63.46 92.08,64.77 92.89,64.77 95.9,67.78 96.97,67.78 98.05,68.86 98.05,71.59 98.06,71.6 98.06,71.81 v2(97.63,72.24)
  BOTTOM w0.102: v2(86.57,41.95) 86.57,41.88 86.43,41.74 86.43,41.51 86.82,41.12 86.96,41.1 87.1,41.18 RAM1.F3 ; CPU1.L30 v2(97.63,72.24)
M_A_DQS_DP0: length 63.3
  L4SGND w0.089: v2(85.18,73.43) 84.69,72.94 84.69,72.32 84.32,71.95 83.59,71.95 83.48,71.84 83.48,71.07 83.27,70.87 82.79,70.87 82.59,71.07 82.59,72.73 82.51,72.81 82.19,72.81 82.1,72.73 82.1,71.07 81.9,70.87 80.03,70.87 78.17,69.01 78.17,64.14 74.27,60.24 74.27,57.81 70.65,54.2 69.41,54.2 68.19,52.98 60.44,52.98 53.95,46.48 53.95,45.54 53.6,45.2 53.38,45.2 v2(53.12,44.94)
  BOTTOM w0.076: 88.52,74.08 88.54,74.08 88.56,74.06 88.98,74.06 89.55,74.62 90.67,74.62 91.06,74.24 91.33,74.24 91.44,74.28 91.68,74.28 91.79,74.24 91.98,74.24 92.1,74.28 92.32,74.28 92.54,74.2 92.59,74.09 92.64,73.99 92.77,73.85 CPU1.D27
  BOTTOM w0.102: RAM4.B7 53.15,44.92 53.14,44.92 v2(53.12,44.94) ; v2(85.18,73.43) 84.96,73.2 84.96,72.94 85.06,72.84 85.94,72.84 87.19,74.08 88.52,74.08
M_A_DQS_DP1: length 56.4
  L4SGND w0.089: v2(87.04,69.03) 87.33,69.32 87.47,69.32 87.61,69.18 87.61,67.83 87.48,67.7 86.84,67.7 86.63,67.49 86.63,65.8 71.95,51.12 70.7,51.12 68.57,48.99 67.55,48.99 67.46,49.08 67.46,49.36 67.26,49.56 66.78,49.56 66.58,49.36 66.58,49.08 66.5,48.99 61.78,48.99 59.07,46.28 58.79,46.28 56.62,44.11 56.62,43.11 55.92,42.41 55.92,42.41 v2(55.48,41.98)
  BOTTOM w0.076: 88.99,70.79 88.99,70.79 88.99,70.84 89.36,71.2 89.86,71.2 90.17,71.52 91.26,71.52 91.47,71.6 91.49,71.6 91.63,71.6 91.77,71.56 92,71.56 92.12,71.6 92.3,71.6 92.42,71.56 92.46,71.46 92.42,71.34 92.32,71.29 CPU1.C31
  BOTTOM w0.102: 88.99,70.79 88.85,70.65 88.06,69.86 87.48,69.28 87.29,69.28 v2(87.04,69.03) ; RAM4.G3 56.48,40.79 56.17,40.79 55.67,41.28 55.67,41.79 v2(55.48,41.98)
M_A_DQS_DP2: length 60.1
  L6 w0.089: v2(65.68,41.73) 66.01,42.06 66.01,42.3 68.28,44.57 68.28,46.1 68.28,46.1 68.28,46.26 69.2,47.18 69.5,47.18 69.84,46.84 69.99,46.84 70.22,47.07 70.22,47.2 69.88,47.54 69.88,47.86 70.22,48.2 70.52,48.2 70.91,47.8 71.06,47.8 71.62,48.37 72.55,48.37 72.64,48.46 72.64,48.83 72.84,49.03 73.32,49.03 73.52,48.83 73.52,48.46 73.61,48.37 74.44,48.37 78.82,52.74 78.82,62.43 79.35,62.96 79.35,63.09 78.9,63.54 78.9,63.85 79.24,64.18 79.53,64.18 80.12,63.6 80.25,63.6 80.5,63.85 80.5,63.98 80.19,64.28 80.19,64.6 80.51,64.93 80.83,64.93 81.46,64.29 81.67,64.29 84.52,67.15 84.52,70.77 87.09,73.34 90.73,73.34 92.16,74.78 94.27,74.78 94.47,74.98 94.53,74.98 v2(94.84,75.29)
  BOTTOM w0.102: v2(65.68,41.73) 65.96,41.45 65.96,41.1 66.24,40.83 66.78,40.83 66.88,40.72 RAM3.G3 ; v2(94.84,75.29) 94.84,75.36 CPU1.G24
M_A_DQS_DP3: length 58.3
  L6 w0.089: v2(63.28,44.94) 63.48,45.15 63.75,45.15 64.04,45.44 64.04,48.78 68.04,52.77 72.68,52.77 73.03,53.12 73.16,53.12 73.41,52.87 73.67,52.87 74.03,53.23 74.03,53.49 73.78,53.74 73.78,53.87 74.22,54.31 74.22,64.92 74.55,65.25 74.95,65.25 75.19,65.48 75.19,69.59 82.45,76.85 83.06,76.85 83.34,77.13 83.34,77.62 83.43,77.7 83.75,77.7 83.83,77.62 83.83,77.44 84.03,77.24 84.51,77.24 84.71,77.44 84.71,77.62 84.8,77.7 85.12,77.7 85.21,77.62 85.21,77.44 85.41,77.24 85.88,77.24 86.08,77.44 86.08,77.62 86.17,77.7 86.49,77.7 86.58,77.62 86.58,77.44 86.78,77.24 88.39,77.24 88.47,77.15 88.47,76.82 v2(88.28,76.63)
  BOTTOM w0.076: v2(88.28,76.63) 88.93,75.98 91.16,75.98 91.32,75.98 91.44,75.93 91.67,75.93 91.81,75.98 91.95,75.98 92.08,75.94 92.33,75.94 92.53,76.01 92.64,76.23 92.7,76.29 CPU1.D23
  BOTTOM w0.102: v2(63.28,44.94) RAM3.B7
M_A_DQS_DP4: length 40.5
  L4SGND w0.089: v2(92.13,63.79) 92.13,63.47 92.33,63.27 92.33,62.71 91.89,62.27 90.78,62.27 89.96,61.45 89.96,59.46 88.45,57.94 87.18,57.94 86.98,58.14 86.98,58.46 86.89,58.55 86.25,58.55 86.15,58.45 86.15,58.14 85.95,57.94 84.51,57.94 74.25,47.69 74.25,45.46 73.88,45.1 73.71,45.1 v2(73.43,44.94)
  BOTTOM w0.076: 94.99,65.83 94.99,65.88 95.19,66.08 95.87,66.08 96.29,66.5 96.29,67.59 96.36,67.79 96.36,68.03 96.32,68.14 96.32,68.3 96.37,68.45 96.37,68.66 96.29,68.88 CPU1.J34
  BOTTOM w0.102: v2(92.13,63.79) 91.91,63.79 91.69,64 91.69,64.16 92.39,64.86 94.02,64.86 94.99,65.83 ; v2(73.43,44.94) RAM2.B7
M_A_DQS_DP5: length 43.6
  L4SGND w0.089: v2(95.72,61.94) 94.32,61.94 93.91,61.53 93.91,57 92.36,55.45 90.83,55.45 85.32,49.94 81.35,49.94 80.78,49.37 80.78,48.58 78.1,45.9 78.1,44.3 75.78,41.99 v2(75.78,41.98)
  BOTTOM w0.076: 98.46,66.12 98.47,66.14 98.52,66.14 98.82,66.44 98.82,67.1 98.67,67.26 98.67,67.7 98.69,67.77 98.71,67.82 98.71,68 98.67,68.12 98.67,68.35 98.71,68.47 98.71,68.65 98.67,68.77 98.57,68.81 98.49,68.78 98.45,68.74 CPU1.P35
  BOTTOM w0.102: 98.46,66.12 97.91,65.57 97.91,65.16 96.25,63.5 96.25,61.87 96.15,61.76 95.9,61.76 v2(95.72,61.94) ; v2(75.78,41.98) 75.92,41.84 75.92,41.44 76.16,41.2 76.55,41.2 77.03,40.72 RAM2.G3
M_A_DQS_DP6: length 41.8
  L6 w0.089: v2(95.75,71.58) 95.33,71.16 95.33,71.02 95.07,70.76 94.7,70.76 94.08,71.39 93.4,71.39 92.42,70.41 92.42,69.89 89.45,66.92 89.23,66.92 83.39,61.09 83.39,60.5 83.19,60.3 82.66,60.3 82.58,60.21 82.58,59.88 82.66,59.79 83.19,59.79 83.39,59.58 83.39,59.08 83.17,58.85 82.49,58.85 82.37,58.74 82.37,58.44 82.47,58.34 82.76,58.34 82.97,58.13 82.97,57.64 82.77,57.44 82.5,57.44 82.38,57.33 82.38,57 82.47,56.92 82.76,56.92 82.97,56.71 82.97,56.21 82.77,56.02 82.5,56.02 82.38,55.9 82.38,55.58 82.48,55.49 82.77,55.49 82.98,55.28 82.98,54.8 82.76,54.58 82.49,54.58 82.37,54.47 82.37,54.17 82.48,54.06 82.77,54.06 82.97,53.87 82.97,53.25 82.77,53.05 82.5,53.05 82.38,52.94 82.38,52.64 82.5,52.52 82.77,52.52 82.98,52.31 82.98,48.02 84.49,46.51 84.49,45.67 84.02,45.2 83.83,45.2 v2(83.57,44.94)
  BOTTOM w0.102: RAM1.B7 v2(83.57,44.94) ; v2(95.75,71.58) CPU1.H30
M_A_DQS_DP7: length 43.7
  L6 w0.089: v2(97.63,71.6) 97.76,71.6 97.86,71.5 97.86,68.94 96.89,67.97 95.82,67.97 92.81,64.96 92,64.96 90.58,63.54 90.58,59.05 90.58,59.05 90.58,57.36 90.29,57.08 90.13,57.08 89.78,57.44 89.48,57.44 89.12,57.08 89.12,56.8 89.49,56.44 89.49,56.27 89.27,56.06 89.09,56.06 88.74,56.41 88.44,56.41 88.08,56.05 88.08,55.77 88.45,55.4 88.45,55.26 87.95,54.75 87.95,49.45 88.19,49.21 88.72,49.21 88.87,49.07 88.87,48.54 88.77,48.44 88.15,48.44 87.95,48.24 87.95,47.78 88.17,47.55 88.77,47.55 88.87,47.46 88.87,46.69 88.78,46.61 88.5,46.61 88.25,46.35 88.25,44.8 86.89,43.45 86.89,42.94 v2(85.93,41.98)
  BOTTOM w0.102: v2(97.63,71.6) 97.91,71.88 CPU1.N30 ; RAM1.G3 86.83,40.89 86.71,40.9 86.2,41.41 86.2,41.71 v2(85.93,41.98)
M_A_ODT0: length 101
  TOP w0.14: RN1207.4 v2(45.62,38.08)
  L2SGND w0.089: v2(85.35,39.04) 85.35,39.45 85.68,39.78 89.92,39.78 92.35,42.21 92.35,42.79 95.12,45.55 95.12,55.78 97.35,58.01 97.35,66.12 100.88,69.65 104.16,69.65 104.41,69.9 104.41,71.15 v2(104.9,71.63)
  L4SGND w0.142: v2(45.62,38.08) 46.9,39.35 49.86,39.35 50.21,39.7 54.24,39.7 v2(54.9,39.04) 54.9,39.02 55.35,38.58 56.48,38.58 57.48,39.57 64.52,39.57 v2(65.05,39.04) 65.05,39.02 65.5,38.58 66.63,38.58 67.75,39.7 74.54,39.7 v2(75.2,39.04) 75.2,39.02 75.65,38.58 76.78,38.58 77.9,39.7 84.69,39.7 v2(85.35,39.04)
  BOTTOM w0.14: v2(85.35,39.04) 85.54,39.22 85.54,39.23 85.8,39.49 85.81,39.49 85.83,39.51 86.18,39.51 86.71,38.99 86.71,38.61 RAM1.K3 ; RAM2.K3 76.4,38.77 76.4,39.15 76.03,39.51 75.64,39.51 75.2,39.07 v2(75.2,39.04) ; RAM3.K3 66.35,38.67 66.35,39.03 65.88,39.5 65.5,39.5 65.05,39.05 v2(65.05,39.04) ; v2(54.9,39.04) 54.9,39.05 55.35,39.5 55.73,39.5 56.1,39.13 56.1,38.77 RAM4.K3 ; CPU1.AE31 v2(104.9,71.63)
M_A_PARITY: length 95.8
  TOP w0.14: RN1204.1 v2(49.05,31.57)
  L2SGND w0.089: v2(87.15,32.72) 87.15,33.26 89.43,35.54 90.15,35.54 97.81,43.19 97.81,54.92 101.29,58.4 101.29,64.85 105.31,68.87 105.31,71.79 105.04,72.06 103.58,72.06 103.08,71.55 v2(102.13,71.55)
  L4SGND w0.142: v2(49.05,31.57) 49.51,32.04 50.13,32.04 50.25,32.16 52.12,32.16 52.76,32.8 53.34,32.8 53.66,32.48 54.47,32.48 54.7,32.72 v2(56.7,32.72) 56.7,32.7 57.14,32.25 58.79,32.25 58.84,32.29 62.33,32.29 62.83,32.8 63.49,32.8 63.81,32.48 66.61,32.48 v2(66.85,32.72) 66.85,32.7 67.29,32.25 68.94,32.25 68.99,32.29 72.48,32.29 72.98,32.8 73.64,32.8 73.96,32.48 74.77,32.48 75,32.72 v2(77,32.72) 77,32.7 77.44,32.25 79.1,32.25 79.55,32.7 80.36,32.7 80.81,32.25 82.61,32.25 83.16,32.8 83.79,32.8 84.18,32.41 85.13,32.41 85.74,33.02 86.84,33.02 v2(87.15,32.72)
  BOTTOM w0.14: RAM4.T3 56.7,33.31 v2(56.7,32.72) ; RAM2.T3 77.03,32.75 v2(77,32.72) ; CPU1.W31 v2(102.13,71.55) ; v2(66.85,32.72) 66.85,33.31 RAM3.T3 ; RAM1.T3 v2(87.15,32.72)
M_B_A0: length 96.4
  L4SGND w0.142: v2(107.22,63.61) 106.78,64.05 106.78,65.53 106.64,65.68 106.33,65.68 106.22,65.56 106.22,63.62 106.29,63.55 106.29,55.84 106.43,55.7 106.95,55.7 107.1,55.55 107.1,55.19 106.96,55.05 106.43,55.05 106.29,54.91 106.29,54.63 106.43,54.48 106.96,54.48 107.1,54.34 107.1,54.06 106.96,53.91 106.43,53.91 106.29,53.77 106.29,53.49 106.43,53.35 106.96,53.35 107.1,53.2 107.1,52.25 106.86,52.01 106.66,52.01 106.19,52.48 105.99,52.48 105.75,52.24 105.75,52.01 106.21,51.56 106.21,51.35 102.14,47.28 102.14,35.41 103.75,33.8 107.65,33.8 v2(108.04,34.19) 108.48,33.75 108.75,33.75 108.76,33.76 117.75,33.76 v2(118.19,34.19) 118.63,33.75 118.9,33.75 118.91,33.76 127.9,33.76 v2(128.34,34.19) 128.78,33.75 129.05,33.75 129.06,33.76 138.05,33.76 v2(138.49,34.19) 138.93,33.75 139.2,33.75 139.21,33.76 143.13,33.76 v2(143.46,33.43)
  BOTTOM w0.076: v2(107.22,63.61) 106.75,64.08 106.75,64.95 106.82,65.02 106.82,65.57 106.81,65.57 106.81,65.9 106.81,65.9 106.81,66.43 106.67,66.57 106.67,67.2 106.91,67.44 106.91,67.7 106.79,67.93 106.79,67.93 106.65,68.18 CPU1.AG36
  BOTTOM w0.14: RAM7.P3 139.18,34.94 138.49,34.25 v2(138.49,34.19) ; v2(118.19,34.19) 118.19,34.25 118.88,34.94 RAM5.P3 ; RAM6.P3 108.73,34.94 108.04,34.25 v2(108.04,34.19) ; v2(143.46,33.43) 143.57,33.43 144.14,34.01 RN1304.4 ; v2(128.34,34.19) 128.34,34.25 129.03,34.94 RAM8.P3
M_B_A1: length 98.6
  L6 w0.142: v2(143.46,34.67) 143.22,34.43 140.99,34.43 140.42,35 138.18,35 137.72,34.54 v2(136.88,34.54) 136.42,34.08 135.51,34.08 135.4,34.18 132.89,34.18 132.73,34.35 130.92,34.35 130.27,35 128.03,35 127.57,34.54 v2(126.73,34.54) 126.27,34.08 125.36,34.08 125.25,34.18 120.94,34.18 120.12,35 117.88,35 117.42,34.54 v2(116.58,34.54) 116.12,34.08 115.21,34.08 115.1,34.18 110.79,34.18 109.97,35 107.73,35 107.27,34.54 v2(106.43,34.54) 105.98,34.09 105.42,34.09 100.48,39.03 100.48,39.39 100.62,39.53 101.25,39.53 101.39,39.67 101.39,39.96 101.25,40.1 100.62,40.1 100.48,40.24 100.48,40.53 100.62,40.67 101.25,40.67 101.39,40.81 101.39,41.1 101.25,41.24 100.62,41.24 100.48,41.38 100.48,41.67 100.62,41.81 101.25,41.81 101.39,41.95 101.39,42.23 101.25,42.38 100.62,42.38 100.48,42.52 100.48,42.8 100.62,42.95 101.25,42.95 101.39,43.09 101.39,43.37 101.25,43.51 100.62,43.51 100.48,43.66 100.48,43.94 100.62,44.08 101.25,44.08 101.39,44.23 101.39,44.51 101.25,44.65 100.62,44.65 100.48,44.79 100.48,45.08 100.62,45.22 101.25,45.22 101.39,45.36 101.39,45.65 101.25,45.79 100.62,45.79 100.48,45.93 100.48,46.22 100.62,46.36 101.25,46.36 101.39,46.5 101.39,46.79 101.25,46.93 100.62,46.93 100.48,47.07 100.48,47.36 100.62,47.5 101.25,47.5 101.39,47.64 101.39,47.92 101.25,48.07 100.62,48.07 100.48,48.21 100.48,48.49 100.62,48.64 101.25,48.64 101.39,48.78 101.39,49.06 101.25,49.2 100.62,49.2 100.48,49.35 100.48,49.67 100.62,49.81 101.04,49.81 101.19,49.95 101.19,51.21 104.31,54.33 104.31,59.64 104.64,59.97 104.97,59.97 105.27,60.28 105.27,62.24 v2(105.72,62.69)
  BOTTOM w0.076: v2(105.72,62.69) 105.73,62.69 106.39,63.35 106.39,63.68 106.34,63.73 106.34,65.53 106.48,65.67 106.48,66.28 106.34,66.42 106.34,67.55 106.43,67.79 106.43,68.03 106.39,68.14 106.39,68.33 106.43,68.44 106.43,68.45 106.55,68.79 CPU1.AG35
  BOTTOM w0.14: v2(143.46,34.67) 144.12,35.34 RN1306.2 ; v2(106.43,34.54) RAM6.P7 ; v2(116.58,34.54) RAM5.P7 ; v2(126.73,34.54) RAM8.P7 ; RAM7.P7 v2(136.88,34.54)
M_B_A2: length 100.1
  TOP w0.14: RN1307.3 147.25,33.42 147.68,32.99 v2(147.68,32.99)
  L6 w0.142: v2(105.82,63.41) 105,62.59 105,62.08 103.52,60.61 103.52,54.61 98.68,49.76 98.68,48.36 98.82,48.21 99.15,48.21 99.31,48.06 99.31,47.67 99.16,47.52 98.82,47.52 98.68,47.38 98.68,45.51 98.84,45.34 99.67,45.34 99.76,45.25 99.76,44.87 99.67,44.77 98.82,44.77 98.68,44.63 98.68,44.37 98.84,44.2 99.67,44.2 99.76,44.11 99.76,43.73 99.67,43.64 98.82,43.64 98.68,43.49 98.68,43.23 98.84,43.07 99.67,43.07 99.76,42.97 99.76,42.59 99.67,42.5 98.82,42.5 98.68,42.36 98.68,42.02 98.84,41.85 99.62,41.85 99.76,41.72 99.76,41.42 99.62,41.29 98.82,41.29 98.68,41.14 98.68,38.37 103.51,33.54 108.02,33.54 108.67,34.19 v2(108.67,34.22) 109.29,34.22 109.43,34.07 109.96,34.07 110.43,33.6 114.86,33.6 114.97,33.49 116.87,33.49 117.05,33.67 118.31,33.67 118.82,34.18 v2(118.82,34.22) 119.27,34.22 119.61,33.88 120.3,33.88 120.58,33.6 125.01,33.6 125.12,33.49 128.29,33.49 128.97,34.17 v2(128.97,34.22) 129.42,33.76 131.03,33.76 131.19,33.6 135.16,33.6 135.27,33.49 138.43,33.49 139.12,34.19 v2(139.12,34.22) 139.45,33.89 145.94,33.89 146.84,32.99 v2(147.68,32.99)
  BOTTOM w0.076: CPU1.AF34 106.26,68.95 106.26,68.47 106.22,68.35 106.22,68.12 106.26,68 106.26,67.82 106.18,67.58 106.18,66.33 106.31,66.2 106.31,65.73 106.18,65.6 106.18,63.77 v2(105.82,63.41)
  BOTTOM w0.14: v2(139.12,34.22) 139.12,34.22 139.2,34.14 RAM7.R3 ; RAM5.R3 118.9,34.14 118.82,34.22 v2(118.82,34.22) ; v2(108.67,34.22) 108.67,34.22 108.75,34.14 RAM6.R3 ; RAM8.R3 129.05,34.14 128.97,34.22 v2(128.97,34.22)
M_B_A3: length 99.1
  L4SGND w0.142: v2(107.19,62.4) 107.46,62.13 107.46,61.68 107.32,61.53 106.79,61.53 106.65,61.39 106.65,61.11 106.79,60.97 107.32,60.97 107.46,60.82 107.46,60.54 107.32,60.4 106.79,60.4 106.65,60.25 106.65,59.97 106.79,59.83 107.32,59.83 107.46,59.69 107.46,59.4 107.32,59.26 106.79,59.26 106.65,59.12 106.65,58.83 106.79,58.69 107.32,58.69 107.46,58.55 107.46,58.26 107.32,58.12 106.79,58.12 106.65,57.98 106.65,57.69 106.79,57.55 107.32,57.55 107.46,57.41 107.46,57.13 107.32,56.98 106.79,56.98 106.65,56.84 106.65,56.56 106.79,56.41 107.32,56.41 107.46,56.27 107.46,52.1 105.74,50.38 105.74,50.18 106.1,49.82 106.1,49.62 105.9,49.42 105.7,49.42 105.34,49.77 105.14,49.77 104.94,49.57 104.94,49.37 105.3,49.01 105.3,48.81 105.1,48.61 104.89,48.61 104.54,48.97 104.33,48.97 104.01,48.65 104.01,48.45 104.32,48.14 104.32,47.94 104.12,47.74 103.92,47.74 103.61,48.05 103.41,48.05 102.57,47.2 102.57,46.75 102.71,46.61 103.68,46.61 103.85,46.43 103.85,46.18 103.68,46 102.68,46 102.5,45.82 102.5,45.43 102.64,45.29 103.01,45.29 103.16,45.15 103.16,44.74 103.02,44.6 102.66,44.6 102.5,44.44 102.5,44.06 102.64,43.92 103.26,43.92 103.4,43.77 103.4,43.4 103.26,43.26 102.64,43.26 102.5,43.11 102.5,36.46 103.15,35.8 106.28,35.8 106.31,35.77 107.02,35.77 v2(107.19,35.94) 107.19,35.94 107.63,36.39 108.02,36.39 108.42,35.99 110.01,35.99 110.12,36.1 110.74,36.1 111.08,35.76 114.74,35.76 114.79,35.8 116.43,35.8 116.48,35.76 117.16,35.76 v2(117.34,35.94) 117.34,35.94 117.78,36.39 118.17,36.39 118.57,35.99 120.16,35.99 120.27,36.1 120.89,36.1 121.23,35.76 124.89,35.76 124.94,35.8 126.58,35.8 126.62,35.76 127.31,35.76 v2(127.49,35.94) 127.49,35.94 127.93,36.39 128.32,36.39 128.72,35.99 130.31,35.99 130.42,36.1 131.04,36.1 131.43,35.71 131.76,35.71 131.79,35.73 132.41,35.73 132.43,35.71 134.99,35.71 135.09,35.8 136.73,35.8 136.77,35.76 137.46,35.76 v2(137.64,35.94) 137.64,35.94 138.08,36.39 138.47,36.39 138.87,35.99 140.46,35.99 140.57,36.1 141.19,36.1 141.55,35.74 143.47,35.74 v2(143.69,35.96)
  BOTTOM w0.076: v2(107.19,62.4) 106.72,62.87 106.72,63.65 106.57,63.81 106.57,65.52 106.64,65.59 106.64,66.36 106.51,66.49 106.51,67.44 CPU1.AG37
  BOTTOM w0.14: v2(117.34,35.94) 117.14,35.74 RAM5.N7 ; v2(137.64,35.94) 137.44,35.74 RAM7.N7 ; v2(107.19,35.94) 106.99,35.74 RAM6.N7 ; RN1306.4 144.15,36.42 v2(143.69,35.96) ; RAM8.N7 127.29,35.74 v2(127.49,35.94)
M_B_A4: length 102.1
  TOP w0.14: v2(147.22,35.71) 147.1,35.83 RN1303.3
  L2SGND w0.089: v2(107.82,35.92) 107.41,35.51 105.32,35.51 104.78,36.04 103.57,36.04 101.04,38.57 101.04,49.69 106.27,54.92 106.27,56.52 106.13,56.65 105.31,56.65 105.22,56.74 105.22,56.92 105.31,57.01 106.13,57.01 106.22,57.1 106.22,57.27 106.13,57.36 105.31,57.36 105.22,57.45 105.22,57.63 105.31,57.72 106.13,57.72 106.22,57.81 106.22,57.99 106.13,58.07 105.31,58.07 105.22,58.16 105.22,58.34 105.31,58.43 106.13,58.43 106.22,58.52 106.22,58.7 106.13,58.79 105.31,58.79 105.22,58.87 105.22,59.05 105.31,59.14 106.13,59.14 106.22,59.23 106.22,59.41 106.13,59.5 105.31,59.5 105.22,59.59 105.22,59.76 105.31,59.85 106.13,59.85 106.22,59.94 106.22,60.12 106.13,60.21 105.31,60.21 105.22,60.3 105.22,60.47 105.31,60.56 106.13,60.56 106.22,60.65 106.22,60.83 106.13,60.92 105.31,60.92 105.22,61.01 105.22,61.19 105.31,61.27 106.13,61.27 106.22,61.36 106.22,64.26 v2(105.78,64.69)
  L6 w0.142: v2(147.22,35.71) 147.02,35.51 143.2,35.51 142.95,35.76 141.57,35.76 141.56,35.76 141.52,35.8 140.69,35.8 140.58,35.69 138.5,35.69 v2(138.27,35.92) 138.27,35.92 137.83,35.47 135.8,35.47 135.47,35.8 135.09,35.8 135.04,35.76 130.97,35.76 130.92,35.8 129.35,35.8 129.24,35.69 128.35,35.69 v2(128.12,35.92) 128.12,35.92 127.68,35.47 125.65,35.47 125.32,35.8 124.94,35.8 124.89,35.76 120.82,35.76 120.77,35.8 119.2,35.8 119.09,35.69 118.2,35.69 v2(117.97,35.92) 117.97,35.92 117.53,35.47 115.5,35.47 115.17,35.8 114.79,35.8 114.74,35.76 110.67,35.76 110.62,35.8 109.05,35.8 108.94,35.69 108.05,35.69 v2(107.82,35.92)
  BOTTOM w0.076: v2(105.78,64.69) 105.32,65.16 105.32,66.25 105.63,66.57 105.63,67.62 105.57,67.79 105.57,68.03 105.61,68.14 105.61,68.63 CPU1.AE35
  BOTTOM w0.14: RAM7.N3 138.46,35.74 v2(138.27,35.92) ; v2(107.82,35.92) 108.01,35.74 RAM6.N3 ; v2(128.12,35.92) 128.31,35.74 RAM8.N3 ; v2(117.97,35.92) 118.16,35.74 RAM5.N3
M_B_A5: length 101
  TOP w0.14: RN1303.2 146.81,35.33 147.08,35.05 v2(147.09,35.05)
  L2SGND w0.089: v2(105.78,65.38) 105.31,64.91 105.31,61.98 104.84,61.51 104.65,61.51 104.01,60.86 104.01,54.66 103.79,54.45 103.66,54.45 102.63,55.48 102.51,55.48 102.38,55.35 102.38,55.22 103.41,54.19 103.41,54.07 103.29,53.94 103.16,53.94 102.13,54.97 102.01,54.97 101.88,54.85 101.88,54.72 102.91,53.69 102.91,53.57 102.78,53.44 102.66,53.44 101.63,54.47 101.5,54.47 101.38,54.34 101.38,54.22 102.41,53.19 102.41,53.06 102.28,52.94 102.16,52.94 101.13,53.97 101,53.97 100.87,53.84 100.87,53.72 101.9,52.68 101.9,52.56 100.39,51.05 100.39,37.59 101.23,36.75 101.95,36.75 103.29,35.41 104.09,35.41 104.96,34.54 v2(105.63,34.54)
  L4SGND w0.142: v2(105.63,34.54) 106.1,34.07 106.62,34.07 107.23,34.68 108.86,34.68 109.13,34.41 109.13,34.37 109.43,34.07 115.31,34.07 v2(115.78,34.54) 116.25,34.07 116.77,34.07 117.38,34.68 119.01,34.68 119.28,34.41 119.28,34.37 119.58,34.07 125.46,34.07 v2(125.93,34.54) 126.4,34.07 126.92,34.07 127.53,34.68 129.16,34.68 129.43,34.41 129.43,34.37 129.73,34.07 135.61,34.07 v2(136.08,34.54) 136.55,34.07 137.07,34.07 137.68,34.68 139.31,34.68 139.58,34.41 139.58,34.37 139.88,34.07 146.32,34.07 147.09,34.84 147.09,35.05 v2(147.09,35.05)
  BOTTOM w0.076: v2(105.78,65.38) 105.76,65.38 105.49,65.65 105.49,66.18 105.8,66.49 105.8,67.65 105.73,67.82 105.73,68 105.9,68.46 CPU1.AF35
  BOTTOM w0.14: RAM7.P8 v2(136.08,34.54) ; RAM6.P8 v2(105.63,34.54) ; RAM5.P8 v2(115.78,34.54) ; RAM8.P8 v2(125.93,34.54)
M_B_A6: length 97.7
  TOP w0.14: RN1303.1 146.46,34.74 146.69,34.51 v2(147.42,34.51)
  L6 w0.142: v2(104.79,61.09) 103.93,60.22 103.93,54.51 99.76,50.34 99.76,49.2 99.9,49.05 99.98,49.05 100.12,48.91 100.12,48.63 99.98,48.48 99.9,48.48 99.76,48.34 99.76,48.06 99.9,47.92 99.98,47.92 100.12,47.77 100.12,46.53 99.98,46.39 99.17,46.39 99.04,46.26 99.04,45.96 99.17,45.82 99.98,45.82 100.12,45.68 100.12,39.72 99.07,38.68 99.07,38.48 99.37,38.18 99.57,38.18 100.09,38.71 100.29,38.71 100.49,38.51 100.49,38.3 99.97,37.78 99.97,37.58 100.17,37.38 100.37,37.38 100.9,37.9 101.1,37.9 101.3,37.7 101.3,37.5 100.78,36.98 100.78,36.78 101.03,36.52 101.23,36.52 101.72,37.01 101.92,37.01 102.12,36.81 102.12,36.61 101.63,36.12 101.63,35.92 101.83,35.72 102.03,35.72 102.52,36.21 102.73,36.21 102.93,36.01 102.93,35.8 102.44,35.31 102.44,35.11 103.74,33.81 106.35,33.81 106.69,34.15 107.3,34.15 107.82,34.67 109.49,34.67 v2(109.63,34.54) 109.91,34.54 110.55,33.89 114.98,33.89 115.09,33.78 116.75,33.78 116.93,33.96 117.26,33.96 117.98,34.68 119.63,34.68 v2(119.78,34.54) 120.06,34.54 120.7,33.89 125.13,33.89 125.24,33.78 127.23,33.78 128.13,34.68 129.78,34.68 v2(129.93,34.54) 130.41,34.06 131.37,34.06 131.53,33.89 131.9,33.89 135.28,33.89 135.39,33.78 137.38,33.78 138.28,34.68 139.93,34.68 v2(140.08,34.54) 140.46,34.16 143.8,34.16 143.89,34.24 146.62,34.24 146.89,34.51 v2(147.42,34.51)
  BOTTOM w0.076: v2(104.79,61.09) 104.79,61.09 105.17,61.47 105.17,65.07 105.15,65.09 105.15,66.37 105.46,66.67 105.46,67.47 CPU1.AE37
  BOTTOM w0.14: v2(129.93,34.54) RAM8.P2 ; v2(109.63,34.54) RAM6.P2 ; v2(119.78,34.54) RAM5.P2 ; v2(140.08,34.54) RAM7.P2
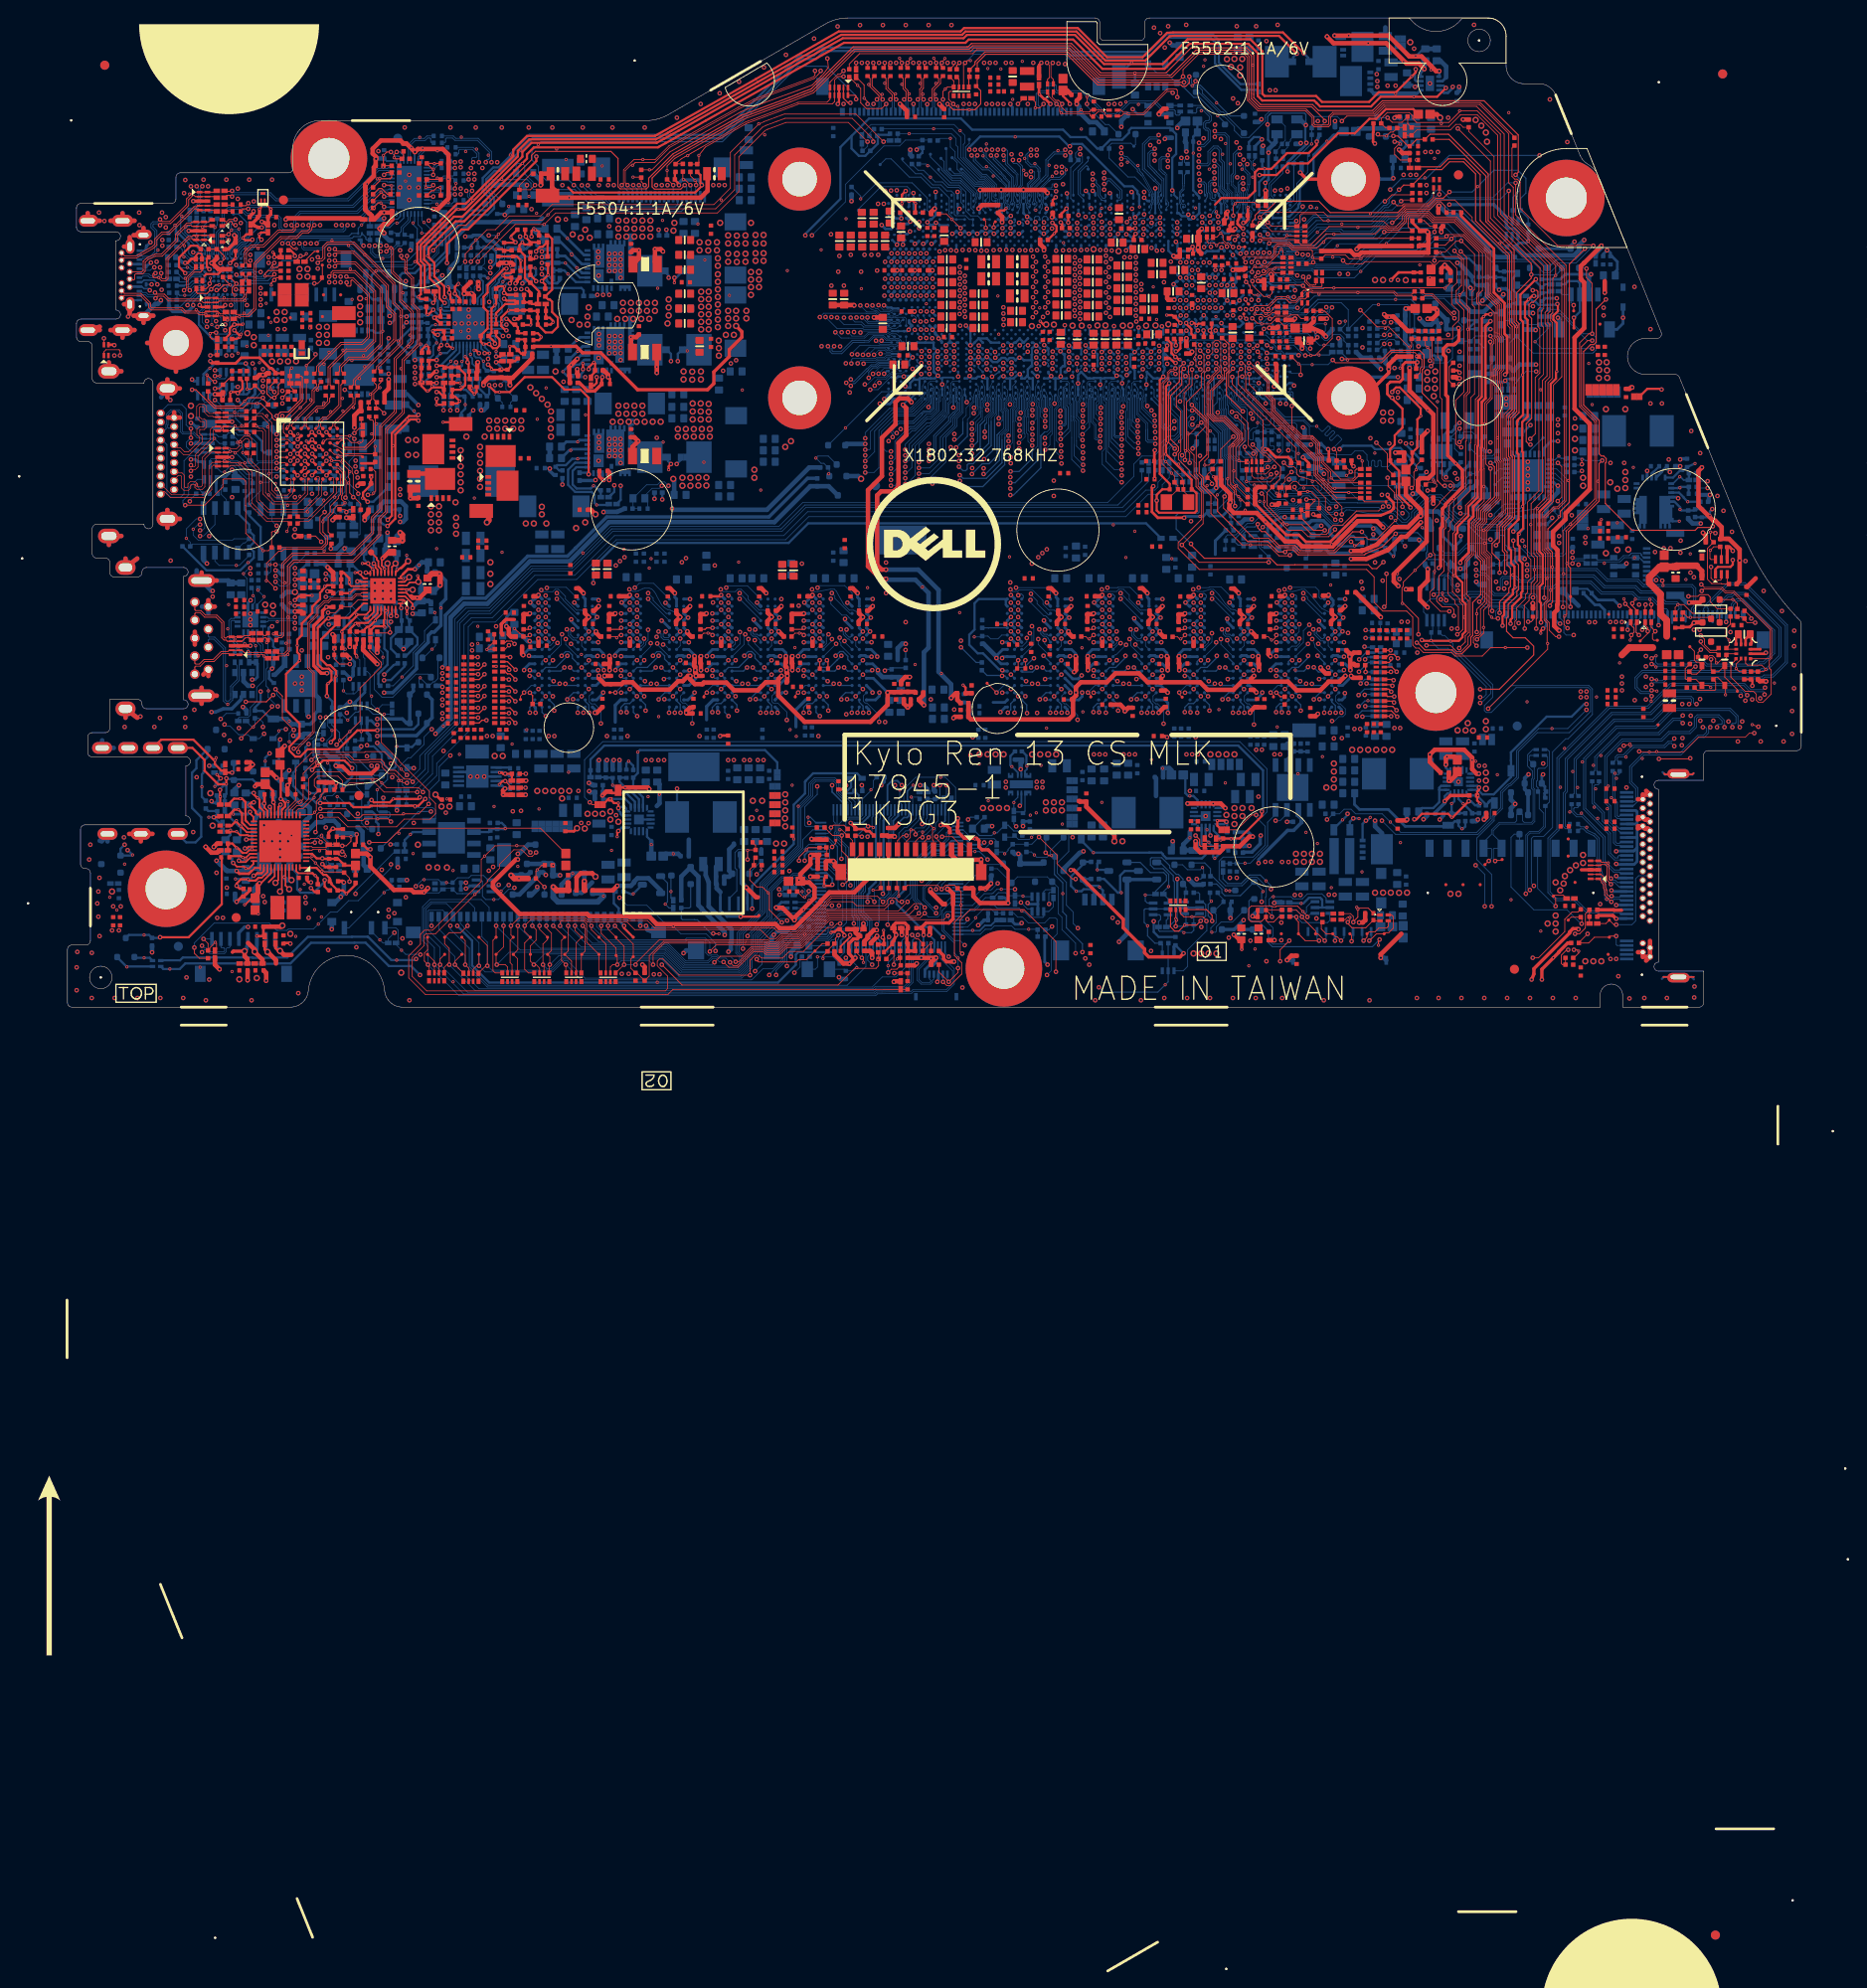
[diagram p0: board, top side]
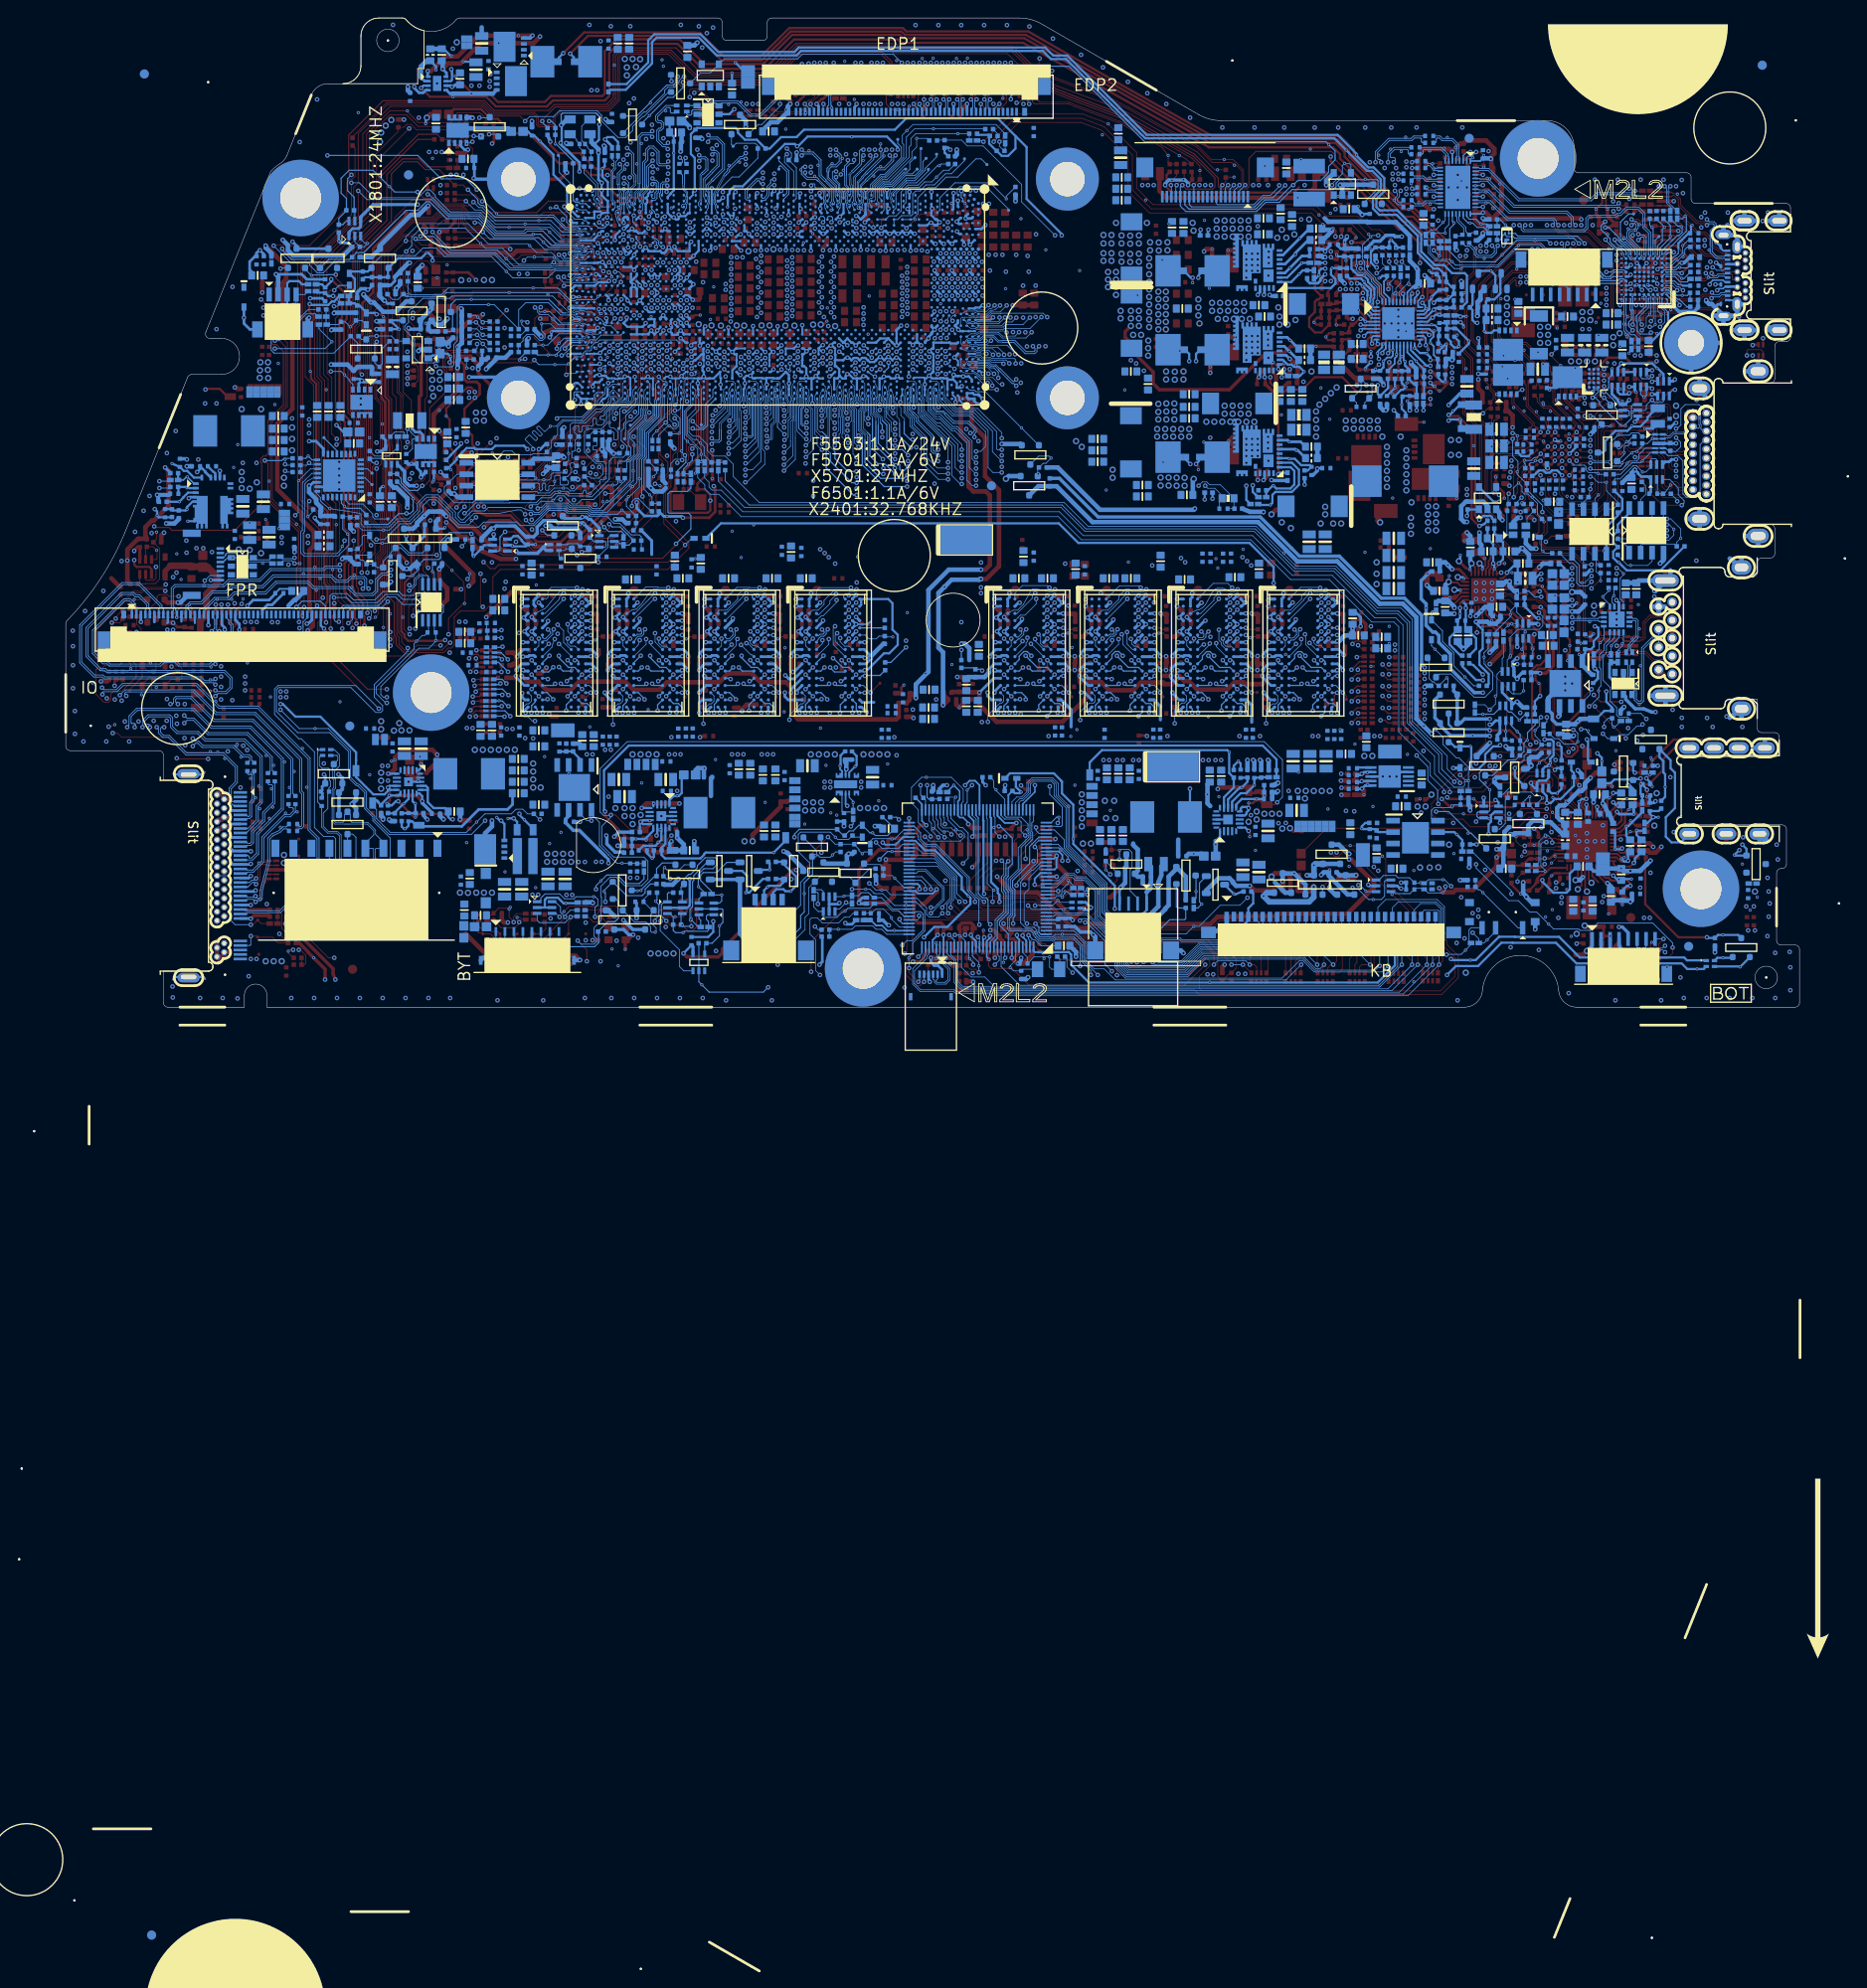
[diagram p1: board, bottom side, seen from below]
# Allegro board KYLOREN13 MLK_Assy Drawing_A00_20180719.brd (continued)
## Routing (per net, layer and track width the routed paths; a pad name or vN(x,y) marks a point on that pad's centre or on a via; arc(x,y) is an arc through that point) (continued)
M_B_A7: length 107.9
  TOP w0.14: v2(147.4,33.85) 147.25,34 146.85,34 146.84,34 RN1307.4
  L4SGND w0.142: v2(147.4,33.85) 147.09,33.55 145.2,33.55 144.61,32.96 143.26,32.96 142.75,33.47 139.33,33.47 139.32,33.46 134.98,33.46 v2(134.3,32.78) 134.3,32.79 133.61,33.47 129.18,33.47 129.17,33.46 128.42,33.46 128.25,33.3 128.25,32.96 128.09,32.79 127.76,32.79 127.59,32.96 127.59,33.3 127.43,33.46 124.83,33.46 v2(124.15,32.78) 124.15,32.79 123.46,33.47 119.03,33.47 119.02,33.46 114.68,33.46 v2(114,32.78) 114,32.8 113.33,33.47 108.88,33.47 108.87,33.46 105.24,33.46 v2(104.49,32.72) 103.9,33.3 103.74,33.3 101.78,35.26 101.78,47.43 105.27,50.92 105.27,53.87 105.41,54.01 105.79,54.01 105.93,54.16 105.93,54.44 105.79,54.58 105.41,54.58 105.27,54.73 105.27,55.01 105.41,55.15 105.79,55.15 105.93,55.3 105.93,55.58 105.79,55.72 105.41,55.72 105.27,55.86 105.27,56.15 105.41,56.29 105.79,56.29 105.93,56.43 105.93,56.72 105.79,56.86 105.41,56.86 105.27,57 105.27,57.29 105.41,57.43 105.79,57.43 105.93,57.57 105.93,57.86 105.79,58 105.41,58 105.27,58.14 105.27,58.42 105.41,58.57 105.79,58.57 105.93,58.71 105.93,58.99 105.79,59.14 105.41,59.14 105.27,59.28 105.27,59.56 105.41,59.7 105.79,59.7 105.93,59.85 105.93,60.13 105.79,60.27 105.41,60.27 105.27,60.42 105.27,60.7 105.41,60.84 105.79,60.84 105.93,60.98 105.93,61.27 105.79,61.41 105.41,61.41 105.27,61.55 105.27,68.95 106.24,69.92 106.24,72.31 105.68,72.87 v2(104.9,72.87)
  BOTTOM w0.14: v2(104.49,32.72) 104.81,33.04 104.81,33.72 RAM6.R8 ; v2(114,32.78) 114,33.32 114.42,33.73 114.97,33.73 RAM5.R8 ; CPU1.AC29 v2(104.9,72.87) ; v2(134.3,32.78) 134.3,33.32 134.72,33.73 135.27,33.73 RAM7.R8 ; RAM8.R8 125.12,33.73 124.57,33.73 124.15,33.32 v2(124.15,32.78)
M_B_A8: length 99.5
  TOP w0.14: RN1307.1 147.06,32.33 v2(147.08,32.31)
  L6 w0.142: v2(147.08,32.31) 146.48,31.72 142.29,31.72 142.29,31.72 141.83,31.72 140.92,32.64 v2(140.92,32.72) 140.92,32.74 140.47,33.18 138.88,33.18 137.88,32.18 131.28,32.18 130.77,32.7 v2(130.77,32.72) 130.77,32.74 130.32,33.18 129.3,33.18 128.38,32.25 121.06,32.25 120.62,32.7 v2(120.62,32.72) 120.62,32.74 120.17,33.18 119.15,33.18 118.23,32.25 113.2,32.25 112.76,32.68 111.74,32.68 111.31,32.25 110.91,32.25 110.47,32.7 v2(110.47,32.72) 110.47,32.72 110.02,33.17 108.98,33.17 108.02,32.21 103.59,32.21 102.4,33.41 102.4,33.61 102.56,33.77 102.56,33.98 102.36,34.18 102.16,34.18 101.99,34.01 101.79,34.01 101.59,34.21 101.59,34.41 101.76,34.58 101.76,34.78 101.56,34.98 101.35,34.98 101.19,34.82 100.99,34.82 100.79,35.02 100.79,35.22 100.95,35.38 100.95,35.59 100.75,35.79 100.55,35.79 100.38,35.62 100.18,35.62 99.98,35.82 99.98,36.02 100.15,36.19 100.15,36.39 99.95,36.59 99.74,36.59 99.58,36.43 99.38,36.43 99.18,36.63 99.18,36.83 99.34,36.99 99.34,37.19 99.14,37.4 98.94,37.4 98.77,37.23 98.57,37.23 98.32,37.48 98.32,49.91 103.14,54.74 103.14,60.83 v2(104.56,62.26)
  BOTTOM w0.076: CPU1.AE36 105.35,68.18 105.2,67.92 105.2,67.91 105.09,67.7 105.09,67.43 105.28,67.23 105.28,67.2 105.28,66.73 104.99,66.44 104.99,65.02 105.01,65 105.01,62.7 v2(104.56,62.26)
  BOTTOM w0.14: RAM5.R2 120.34,33.98 120.34,33.88 120.59,33.64 120.59,32.75 v2(120.62,32.72) ; v2(140.92,32.72) 140.89,32.75 140.89,33.5 140.48,33.91 RAM7.R2 ; v2(110.47,32.72) 110.44,32.75 110.44,33.64 110.03,34.04 RAM6.R2 ; v2(130.77,32.72) 130.74,32.75 130.74,33.49 130.33,33.9 RAM8.R2
M_B_A9: length 95.6
  L4SGND w0.142: v2(106.62,32.66) 105.95,31.99 103.3,31.99 101.06,34.23 101.06,51.16 104.11,54.2 104.11,63.65 104.3,63.84 104.3,68.64 105.33,69.67 105.33,71.8 104.97,72.16 v2(103.09,72.16)
  L6 w0.142: v2(144.2,33.43) 143.73,32.96 143.29,32.96 142.77,33.47 138.8,33.47 138.78,33.45 138.76,33.45 138.48,33.17 137.26,33.17 v2(137.04,32.94) 136.78,33.2 135.15,33.2 135.04,33.31 130.76,33.31 130.6,33.47 128.87,33.47 128.34,32.94 v2(126.89,32.94) 126.63,33.2 125,33.2 124.89,33.31 120.46,33.31 120.29,33.47 119.03,33.47 118.94,33.38 117.17,33.38 v2(116.74,32.94) 116.48,33.2 114.85,33.2 114.74,33.31 110.31,33.31 110.14,33.47 108.88,33.47 108.58,33.17 107.13,33.17 v2(106.62,32.66)
  BOTTOM w0.14: v2(116.74,32.94) 116.74,33.58 RAM5.R7 ; RAM6.R7 106.59,33.58 106.59,32.7 v2(106.62,32.66) ; CPU1.AB29 v2(103.09,72.16) ; RN1304.3 144.22,33.42 v2(144.2,33.43) ; v2(126.89,32.94) 126.89,33.58 RAM8.R7 ; v2(137.04,32.94) 137.04,33.58 RAM7.R7
M_B_A10: length 99.9
  TOP w0.14: v2(147.69,37.27) 147.16,37.79 RN1305.2
  L4SGND w0.142: v2(147.69,37.27) 147.52,37.1 147.52,37.07 147.25,36.8 147.22,36.8 147.2,36.78 147.16,36.78 147.05,36.67 144.77,36.67 144.57,36.48 143.37,36.48 142.94,36.05 141.68,36.05 141.28,36.45 v2(139.07,36.45) 138.84,36.68 136.42,36.68 135.83,36.1 134.97,36.1 134.92,36.05 131.5,36.05 131.1,36.45 v2(128.92,36.45) 128.69,36.68 126.27,36.68 125.68,36.1 123.95,36.1 123.9,36.05 121.35,36.05 120.95,36.45 v2(118.77,36.45) 118.54,36.68 116.12,36.68 115.53,36.1 113.8,36.1 113.75,36.05 111.2,36.05 110.8,36.45 v2(108.62,36.45) 108.4,36.67 105.95,36.67 105.5,36.22 103.4,36.22 102.77,36.85 102.77,39.12 102.91,39.26 102.91,39.27 103.48,39.27 103.63,39.41 103.63,39.83 103.45,40.01 103.18,40.01 103.04,40.15 103.04,41.11 103.18,41.25 104.13,41.25 104.34,41.46 104.34,41.87 104.2,42.01 103.09,42.01 102.94,42.16 102.94,42.69 103.08,42.84 104.2,42.84 104.34,42.98 104.34,46.22 104.29,46.27 104.29,47.4 104.82,47.93 105.02,47.93 106.28,46.67 106.48,46.67 106.85,47.04 106.85,47.3 105.73,48.41 105.73,48.74 106.74,49.75 106.74,50.18 107.82,51.26 107.82,65.79 108.1,66.07 108.1,66.75 106.69,68.16 106.48,68.16 106.04,67.72 106.04,67.52 v2(107.22,66.35)
  BOTTOM w0.076: CPU1.AG34 106.95,68.91 106.95,67.97 107.08,67.74 107.08,67.36 106.84,67.12 106.84,66.73 v2(107.22,66.35)
  BOTTOM w0.14: v2(139.07,36.45) 139.16,36.54 RAM7.M3 ; v2(108.62,36.45) 108.71,36.54 RAM6.M3 ; RAM8.M3 129.01,36.54 v2(128.92,36.45) ; RAM5.M3 118.86,36.54 v2(118.77,36.45)
M_B_A11: length 100.3
  TOP w0.14: RN1307.2 147.11,32.91 v2(147.75,32.28)
  L6 w0.142: v2(130.13,32.72) 130.13,32.7 ; 130.13,32.7 130.96,31.87 139.46,31.87 140.28,32.7 140.28,32.71 ; 130.13,32.7 129.4,31.96 120.73,31.96 120.43,32.26 120.43,32.26 120.16,32.53 120.16,32.53 119.98,32.71 ; 119.98,32.71 119.98,32.65 119.29,31.96 113.07,31.96 112.64,32.39 111.87,32.39 111.43,31.96 110.57,31.96 110,32.52 110,32.54 109.83,32.71 ; 119.98,32.71 v2(119.98,32.72) ; v2(103.98,72.87) 103.98,72.85 104.49,72.34 104.9,72.34 105.35,71.88 105.35,65.86 104.03,64.54 104.03,62.46 102.79,61.21 102.79,59.56 102.78,59.56 102.78,54.91 97.96,50.09 97.96,37.26 103.39,31.83 108.97,31.83 109.83,32.7 109.83,32.71 ; v2(140.28,32.72) 140.28,32.71 ; 140.28,32.71 140.45,32.54 140.45,32.52 141.61,31.36 146.84,31.36 v2(147.75,32.28) ; 109.83,32.71 v2(109.83,32.72)
  BOTTOM w0.14: RAM7.T2 140.28,33.14 v2(140.28,32.72) ; v2(109.83,32.72) 109.83,33.14 RAM6.T2 ; RAM5.T2 119.98,33.14 v2(119.98,32.72) ; v2(130.13,32.72) 130.13,33.14 RAM8.T2 ; CPU1.AC28 v2(103.98,72.87)
M_B_A12: length 97.4
  L2SGND w0.089: v2(106.52,36.22) 106.43,36.31 103.75,36.31 101.35,38.71 101.35,49.54 101.56,49.76 101.69,49.76 102,49.45 102.12,49.45 102.25,49.58 102.25,49.7 101.94,50.01 101.94,50.14 102.06,50.26 102.19,50.26 102.5,49.95 102.62,49.95 102.75,50.08 102.75,50.2 102.44,50.51 102.44,50.64 102.57,50.76 102.69,50.76 103,50.46 103.13,50.46 103.25,50.58 103.25,50.71 102.94,51.02 102.94,51.14 103.07,51.27 103.2,51.27 103.51,50.96 103.63,50.96 103.76,51.08 103.76,51.21 103.45,51.52 103.45,51.64 103.57,51.77 103.7,51.77 104.01,51.46 104.13,51.46 104.26,51.59 104.26,51.71 103.95,52.02 103.95,52.15 104.08,52.27 104.2,52.27 104.51,51.96 104.64,51.96 104.76,52.09 104.76,52.22 104.45,52.52 104.45,52.65 104.58,52.78 104.7,52.78 105.01,52.47 105.14,52.47 105.27,52.59 105.27,52.72 104.96,53.03 104.96,53.15 105.08,53.28 105.21,53.28 105.44,53.05 105.57,53.05 105.69,53.17 105.69,53.3 105.46,53.53 105.46,53.66 105.59,53.78 105.71,53.78 105.84,53.65 105.97,53.65 106.09,53.78 106.09,53.9 105.96,54.03 105.96,54.16 106.6,54.79 106.6,72.18 105.4,73.37 105.4,73.54 105.04,73.91 104.36,73.91 v2(103.98,73.53)
  L6 w0.142: v2(106.52,36.22) 106.7,36.4 108.02,36.4 108.43,35.99 108.82,35.99 108.93,36.1 110.82,36.1 110.86,36.05 114.62,36.05 114.67,36.1 116.54,36.1 v2(116.67,36.22) 116.85,36.4 118.17,36.4 118.58,35.99 118.97,35.99 119.08,36.1 120.97,36.1 121.01,36.05 124.77,36.05 124.82,36.1 126.69,36.1 v2(126.82,36.22) 127,36.4 128.32,36.4 128.73,35.99 129.12,35.99 129.23,36.1 131.12,36.1 131.16,36.05 134.92,36.05 134.97,36.1 136.84,36.1 v2(136.97,36.22) 137.15,36.4 138.47,36.4 138.88,35.99 139.27,35.99 139.38,36.1 141.64,36.1 141.68,36.05 141.69,36.05 142.94,36.05 143.37,36.47 143.83,36.47 v2(144.35,35.96)
  BOTTOM w0.14: RAM6.M7 106.35,36.22 v2(106.52,36.22) ; RAM8.M7 126.65,36.22 v2(126.82,36.22) ; RAM5.M7 116.5,36.22 v2(116.67,36.22) ; RN1306.3 144.49,35.84 144.36,35.96 v2(144.35,35.96) ; RAM7.M7 136.65,36.54 v2(136.97,36.22) ; CPU1.AB28 v2(103.98,73.53)
M_B_A13: length 102.1
  L4SGND w0.142: v2(104.77,56.9) 104.77,54.28 103.08,52.6 103.08,52.4 103.42,52.06 103.62,52.06 104.22,52.67 104.42,52.67 104.63,52.47 104.63,52.27 104.02,51.66 104.02,51.46 104.56,50.92 104.56,50.72 104.36,50.52 104.16,50.52 102.68,51.99 102.48,51.99 102.28,51.79 102.28,51.59 103.76,50.11 103.76,49.91 103.56,49.71 103.35,49.71 101.88,51.19 101.68,51.19 101.42,50.93 101.42,50.27 101.57,50.13 101.98,50.13 102.13,49.99 102.13,49.71 101.98,49.56 101.57,49.56 101.42,49.42 101.42,49.14 101.57,48.99 102.24,48.99 102.38,48.85 102.38,48.57 102.24,48.43 101.57,48.43 101.42,48.28 101.42,34.38 103.54,32.26 104.78,32.26 v2(105.23,32.72) 105.67,33.15 108.98,33.15 109,33.18 112.3,33.18 113.18,32.29 114.96,32.29 v2(115.38,32.72) 115.71,32.39 118.36,32.39 119.15,33.18 122.45,33.18 123.33,32.29 125.11,32.29 v2(125.53,32.72) 125.86,32.39 128.51,32.39 129.3,33.18 131.6,33.18 133.93,32.29 135.26,32.29 v2(135.68,32.72) 136.01,32.39 137.22,32.39 138.01,33.18 141.95,33.18 142.8,32.33 v2(143.26,32.33)
  BOTTOM w0.076: CPU1.AK35 108.71,68.37 108.79,68.15 108.91,67.81 108.91,66.7 109.1,66.51 109.1,64.17 108.83,63.91 108.58,63.91
  BOTTOM w0.14: v2(115.38,32.72) RAM5.T8 ; RN1304.2 143.85,32.92 v2(143.26,32.33) ; v2(125.53,32.72) RAM8.T8 ; 108.58,63.91 108.15,63.48 108.15,59.93 105.47,57.25 105.47,57.25 105.12,56.9 v2(104.77,56.9) ; v2(105.23,32.72) RAM6.T8 ; RAM7.T8 v2(135.68,32.72)
M_B_A14: length 94.2
  L4SGND w0.142: v2(144.19,38.63) 143.68,38.13 142.46,38.13 142.4,38.18 141.59,38.18 141.31,37.91 140.25,37.91 v2(140.08,37.74) 139.62,37.28 135.62,37.28 134.99,37.91 130.1,37.91 v2(129.93,37.74) 129.47,37.28 125.47,37.28 124.84,37.91 119.95,37.91 v2(119.78,37.74) 119.32,37.28 115.31,37.28 115.17,37.41 114.71,37.41 114.21,37.91 114.05,37.91 109.8,37.91 v2(109.63,37.74) 109.18,37.29 106.75,37.29 106.44,37.59 104.45,37.59 104.31,37.73 104.31,38.84 104.49,39.01 106.22,39.01 106.39,39.19 106.39,39.53 106.2,39.73 104.54,39.73 104.31,39.95 104.31,40.29 104.51,40.48 105.87,40.48 106.14,40.75 106.14,43.98 106.44,44.27 106.7,44.27 106.85,44.13 106.85,43.16 106.99,43.02 107.27,43.02 107.42,43.16 107.42,44.13 107.56,44.27 108.13,44.27 108.32,44.47 108.32,45.36 108.18,45.5 107.65,45.5 107.51,45.64 107.51,45.93 107.65,46.07 108.18,46.07 108.32,46.21 108.32,46.5 108.18,46.64 107.65,46.64 107.51,46.78 107.51,47.06 107.65,47.21 108.18,47.21 108.32,47.35 108.32,47.63 108.18,47.78 107.65,47.78 107.51,47.92 107.51,48.2 107.65,48.34 108.18,48.34 108.32,48.49 108.32,48.84 107.41,49.75 107.41,50.3 108.18,51.06 108.18,52.28 108.32,52.42 108.72,52.42 108.86,52.56 108.86,52.84 108.72,52.99 108.32,52.99 108.18,53.13 108.18,53.41 108.32,53.56 108.72,53.56 108.86,53.7 108.86,53.98 108.72,54.12 108.32,54.12 108.18,54.27 108.18,54.55 108.32,54.69 108.72,54.69 108.86,54.84 108.86,55.12 108.72,55.26 108.32,55.26 108.18,55.4 108.18,64.65 v2(108.63,65.1)
  BOTTOM w0.076: CPU1.AJ35 107.96,68.79 108.09,68.45 108.09,68.44 108.13,68.33 108.13,68.14 108.09,68.03 108.09,67.79 108.22,67.43 108.22,66.65 108.11,66.54 108.11,65.62 v2(108.63,65.1)
  BOTTOM w0.14: RN1302.2 144.45,38.89 v2(144.19,38.63) ; v2(109.63,37.74) RAM6.L2 ; v2(119.78,37.74) RAM5.L2 ; v2(129.93,37.74) RAM8.L2 ; v2(140.08,37.74) RAM7.L2
M_B_A15: length 100.8
  L2SGND w0.089: v2(104.83,36.95) 104.83,37.83 104.74,37.92 102.66,37.92 101.65,38.93 101.65,47.19 102.24,47.77 102.24,47.9 101.78,48.35 101.78,48.48 101.9,48.61 102.03,48.61 102.49,48.15 102.61,48.15 102.74,48.27 102.74,48.4 102.28,48.86 102.28,48.98 102.41,49.11 102.53,49.11 102.99,48.65 103.12,48.65 103.24,48.78 103.24,48.9 102.78,49.36 102.78,49.49 102.91,49.61 103.03,49.61 103.49,49.15 103.62,49.15 103.74,49.28 103.74,49.4 103.29,49.86 103.29,49.99 103.41,50.11 103.54,50.11 104,49.66 104.12,49.66 104.25,49.78 104.25,49.91 103.79,50.37 103.79,50.49 103.91,50.62 104.04,50.62 104.5,50.16 104.62,50.16 104.75,50.28 104.75,50.41 104.29,50.87 104.29,50.99 104.42,51.12 104.54,51.12 105,50.66 105.13,50.66 105.25,50.79 105.25,50.91 104.79,51.37 104.79,51.5 104.92,51.62 105.05,51.62 105.5,51.16 105.63,51.16 105.76,51.29 105.76,51.42 105.3,51.87 105.3,52 105.42,52.13 105.55,52.13 106.01,51.67 106.13,51.67 106.26,51.79 106.26,51.92 105.8,52.38 105.8,52.5 105.93,52.63 106.05,52.63 106.51,52.17 106.64,52.17 106.76,52.3 106.76,52.42 106.3,52.88 106.3,53.01 106.43,53.13 106.55,53.13 107.01,52.67 107.14,52.67 107.43,52.96 107.43,53.09 106.93,53.59 106.93,62.09 106.79,62.22 106.79,65.11 107.01,65.32 107.65,65.32 107.72,65.39 107.72,66.13 107.81,66.22 108.15,66.22 v2(108.65,65.71)
  L6 w0.142: v2(104.83,36.95) 104.87,36.98 108.02,36.98 108.32,37.28 110.07,37.28 110.29,37.5 110.82,37.5 111.22,37.91 114.21,37.91 114.48,37.63 114.48,37.44 v2(114.98,36.95) 116.35,36.95 116.38,36.98 118.17,36.98 118.47,37.28 119.97,37.28 120.22,37.53 120.98,37.53 121.35,37.91 124.36,37.91 124.63,37.63 124.63,37.44 v2(125.13,36.95) 126.5,36.95 126.53,36.98 128.32,36.98 128.62,37.28 130.12,37.28 130.32,37.47 131.13,37.47 131.57,37.91 134.51,37.91 134.78,37.63 134.78,37.44 v2(135.28,36.95) 136.65,36.95 136.68,36.98 138.47,36.98 138.77,37.28 140.27,37.28 141.04,38.04 142.94,38.04 v2(143.53,38.63)
  BOTTOM w0.076: CPU1.AK34 108.34,69.03 108.25,68.94 108.25,68.49 108.25,68.48 108.25,68.47 108.29,68.35 108.29,68.12 108.25,68 108.25,67.82 108.38,67.46 108.38,66.58 108.27,66.48 108.27,66.1 108.65,65.72 v2(108.65,65.71)
  BOTTOM w0.14: RAM6.M8 104.86,36.9 104.86,36.91 v2(104.83,36.95) ; v2(143.53,38.63) 144.29,39.39 RN1302.3 ; RAM5.M8 115.02,36.9 115.02,36.91 v2(114.98,36.95) ; RAM7.M8 135.68,36.55 v2(135.28,36.95) ; v2(125.13,36.95) 125.16,36.91 125.16,36.9 RAM8.M8
M_B_A16: length 108.4
  TOP w0.14: RN1305.3 146.86,38.29 147.07,38.5 v2(147.07,38.74)
  L2SGND w0.089: v2(107.21,64.92) 107.62,64.51 107.62,61.28 107.33,61 107.33,60.78 107.41,60.71 107.91,60.71 107.99,60.62 107.99,60.36 107.91,60.27 107.32,60.27 107.23,60.19 107.23,60.01 107.32,59.92 107.93,59.92 108.02,59.83 108.02,59.65 107.93,59.56 107.32,59.56 107.23,59.47 107.23,59.3 107.32,59.21 107.93,59.21 108.02,59.12 108.02,58.94 107.93,58.85 107.32,58.85 107.23,58.76 107.23,58.59 107.32,58.5 107.93,58.5 108.02,58.41 108.02,58.23 107.93,58.14 107.32,58.14 107.23,58.05 107.23,57.87 107.32,57.79 107.93,57.79 108.02,57.7 108.02,57.52 107.93,57.43 107.32,57.43 107.23,57.34 107.23,57.16 107.32,57.07 107.93,57.07 108.02,56.99 108.02,56.81 107.93,56.72 107.32,56.72 107.23,56.63 107.23,56.45 107.32,56.36 107.93,56.36 108.02,56.27 108.02,56.1 107.93,56.01 107.32,56.01 107.23,55.92 107.23,55.74 107.32,55.65 107.93,55.65 108.02,55.56 108.02,55.39 107.93,55.3 107.32,55.3 107.23,55.21 107.23,55.03 107.32,54.94 107.93,54.94 108.02,54.85 108.02,54.67 107.93,54.59 107.32,54.59 107.23,54.5 107.23,54.32 107.32,54.23 107.93,54.23 108.02,54.14 108.02,53.1 102.23,47.31 102.23,38.96 102.86,38.33 104.59,38.33 105.25,38.99 107.16,38.99 v2(107.38,38.76)
  L4SGND w0.142: v2(147.07,38.74) 145.96,38.74 145.11,39.59 140.45,39.59 139.44,38.58 138.31,38.58 v2(137.85,39.04) 137.19,39.7 130.25,39.7 129.14,38.58 128.16,38.58 v2(127.7,39.04) 127.04,39.7 120.22,39.7 119.11,38.58 118.01,38.58 v2(117.55,39.04) 116.89,39.7 110.03,39.7 108.91,38.58 107.86,38.58 107.68,38.76 v2(107.38,38.76)
  BOTTOM w0.076: CPU1.AJ34 107.86,69.53 107.57,68.92 107.57,67.97 107.5,67.86 107.46,67.78 107.44,67.74 107.44,67.38 107.68,67.13 107.68,66.82 107.61,66.75 107.61,65.33 v2(107.21,64.92)
  BOTTOM w0.14: v2(107.38,38.76) 107.34,38.76 106.32,37.74 105.63,37.74 RAM6.L8 ; RAM5.L8 115.78,37.74 116.47,37.74 117.55,38.83 v2(117.55,39.04) ; RAM8.L8 125.93,37.74 126.62,37.74 127.7,38.83 v2(127.7,39.04) ; RAM7.L8 136.08,37.74 136.77,37.74 137.85,38.83 v2(137.85,39.04)
M_B_ACT_N: length 101.5
  TOP w0.14: RN1305.4 146.56,38.88 146.87,39.19 147.39,39.19 v2(147.83,38.75)
  L6 w0.127: v2(147.83,38.75) 147.19,38.12 146.43,38.12 145.41,39.14
  L6 w0.142: v2(101.26,73.51) 101.26,73.79 101.95,74.47 103.05,74.47 103.2,74.62 103.2,74.81 103.34,74.96 103.62,74.96 103.76,74.81 103.76,74.62 103.91,74.47 105.94,74.47 106.24,74.17 106.24,72.67 106.6,72.31 106.6,61.51 106.42,61.34 106.42,53.14 102.54,49.25 102.54,38.83 103.06,38.3 104.26,38.3 105.28,37.29 107.9,37.29 108.34,37.74 v2(108.34,37.74) 108.97,37.74 109.44,38.2 109.82,38.2 109.82,38.2 109.92,38.2 110.28,37.85 110.66,37.85 111.02,38.2 114.47,38.2 115.4,37.28 118.05,37.28 118.5,37.72 v2(118.5,37.74) 119.12,37.74 119.66,38.28 119.98,38.28 120.34,37.92 120.9,37.92 121.18,38.2 124.55,38.2 125.48,37.28 128.2,37.28 128.64,37.72 v2(128.64,37.74) 129.27,37.74 129.79,38.25 130.22,38.25 130.55,37.92 131.08,37.92 131.36,38.2 134.71,38.2 135.64,37.28 138,37.28 v2(138.48,37.76) 138.9,38.18 139.24,38.18 140.06,39 141.12,39 141.65,38.48 142.67,38.48 143.33,39.14 145.41,39.14
  BOTTOM w0.14: RAM8.L3 129.04,37.34 v2(128.64,37.74) ; RAM6.L3 108.74,37.34 v2(108.34,37.74) ; v2(118.5,37.74) 118.89,37.34 RAM5.L3 ; RAM7.L3 139.58,37.24 139,37.24 v2(138.48,37.76) ; CPU1.W28 v2(101.26,73.51)
M_B_ALERT_N: length 85.4
  TOP w0.14: v2(134.32,34.94) 134.77,34.49 R1330.1
  L2SGND w0.089: v2(102.18,72.9) 102.48,73.2 103.23,73.2 103.47,72.96 103.47,72.82 103.81,72.47 105.21,72.47 105.3,72.56 105.95,72.56 106.42,72.09 106.42,67.51 105.03,66.13 105.03,62.16 103.65,60.78 103.65,57.05 102.98,56.38 102.98,56.25 103.61,55.62 103.61,55.49 103.48,55.37 103.36,55.37 102.73,56 102.6,56 100.09,53.49 100.09,37.46 103.02,34.53 103.46,34.53 v2(103.87,34.94)
  L4SGND w0.142: v2(134.32,34.94) 134.32,34.63 134.18,34.49 130.63,34.49 130.11,35 125.63,35 125.51,34.88 124.23,34.88 v2(124.17,34.94) 124.17,34.93 123.73,34.49 123,34.49 122.99,34.49 122.61,34.49 122.61,34.49 122.46,34.49 122.08,34.49 122.07,34.49 120.62,34.49 120.1,35 115.35,35 115.19,34.84 114.12,34.84 v2(114.02,34.94) 114.02,34.93 113.48,34.39 110.67,34.39 110.06,35 105.15,35 105.02,34.88 103.93,34.88 v2(103.87,34.94)
  BOTTOM w0.14: RAM8.P9 v2(124.17,34.94) ; RAM6.P9 v2(103.87,34.94) ; RAM7.P9 v2(134.32,34.94) ; RAM5.P9 v2(114.02,34.94) ; CPU1.Y29 v2(102.18,72.9)
M_B_BA0: length 94.4
  L6 w0.142: v2(144.14,34.7) 143.63,35.2 143.05,35.2 142.81,35.44 142.03,35.44 141.93,35.34 v2(140.88,35.34) 138.11,35.34 137.95,35.18 136.06,35.18 135.36,34.48 133.43,34.48 133.22,34.69 133.22,35.08 133.22,35.14 132.91,35.46 130.85,35.46 v2(130.73,35.34) 130.72,35.34 130.72,35.33 130.72,35.34 127.96,35.34 127.8,35.18 125.91,35.18 125.21,34.48 121.83,34.48 120.97,35.34 120.6,35.34 120.59,35.33 120.59,35.34 v2(120.58,35.34) 120.58,35.34 117.81,35.34 117.65,35.18 115.76,35.18 115.06,34.48 111.01,34.48 110.43,35.05 110.43,35.28 110.46,35.31 110.46,35.34 v2(110.43,35.34) 110.43,35.34 105.57,35.34 104.95,35.97 104.05,35.97 101.75,38.27 101.75,49.68 102.12,50.06 102.12,50.26 101.55,50.84 101.55,51.04 101.75,51.24 101.95,51.24 102.53,50.67 102.73,50.67 102.93,50.87 102.93,51.07 102.34,51.65 102.34,51.86 102.54,52.06 102.75,52.06 103.33,51.47 103.53,51.47 103.73,51.67 103.73,51.87 103.15,52.46 103.15,52.66 103.35,52.86 103.55,52.86 104.14,52.27 104.34,52.27 104.54,52.48 104.54,52.68 104.02,53.2 104.02,53.4 104.22,53.6 104.42,53.6 104.94,53.08 105.14,53.08 105.68,53.62 105.68,54.28 105.54,54.42 104.94,54.42 104.79,54.56 104.79,54.85 104.94,54.99 105.54,54.99 105.68,55.13 105.68,55.51 105.54,55.66 104.88,55.66 104.74,55.8 104.74,56.08 104.88,56.22 105.51,56.22 105.68,56.39 105.68,56.68 105.54,56.82 105.36,56.82 105.22,56.96 105.22,57.25 105.36,57.39 105.54,57.39 105.68,57.53 105.68,58.11 105.54,58.25 v2(104.77,58.25)
  BOTTOM w0.076: 107.69,61.54 107.94,61.8 107.94,66.61 108.02,66.69 108.02,67.43 CPU1.AJ37
  BOTTOM w0.14: v2(104.77,58.25) 104.77,58.27 105.3,58.27 107.69,60.66 107.69,61.54 ; v2(140.88,35.34) RAM7.N2 ; RAM8.N2 130.72,35.35 130.72,35.34 v2(130.73,35.34) ; RN1306.1 144.2,34.75 144.15,34.7 v2(144.14,34.7) ; v2(110.43,35.34) RAM6.N2 ; RAM5.N2 v2(120.58,35.34)
M_B_BA1: length 102.9
  TOP w0.14: RN1303.4 147.24,36.42 147.33,36.33 v2(147.35,36.33)
  L2SGND w0.089: v2(104.79,59.52) 104.34,59.07 104.34,56.3 104.43,56.21 105.87,56.21 105.96,56.13 105.96,55.95 105.87,55.86 104.43,55.86 104.34,55.77 104.34,55.59 104.43,55.5 105.87,55.5 105.96,55.41 105.96,55.24 105.87,55.15 104.43,55.15 104.34,55.06 104.34,54.4 104.77,53.97 104.77,53.85 104.64,53.72 104.52,53.72 104.07,54.17 103.94,54.17 103.82,54.04 103.82,53.92 104.26,53.47 104.26,53.34 104.14,53.22 104.01,53.22 103.57,53.67 103.44,53.67 103.32,53.54 103.32,53.41 103.76,52.97 103.76,52.84 103.64,52.72 103.51,52.72 103.06,53.16 102.94,53.16 102.81,53.04 102.81,52.91 103.26,52.46 103.26,52.34 103.13,52.21 103.01,52.21 102.56,52.66 102.44,52.66 102.31,52.53 102.31,52.41 102.76,51.96 102.76,51.84 102.63,51.71 102.5,51.71 102.06,52.16 101.93,52.16 101.81,52.03 101.81,51.9 102.25,51.46 102.25,51.33 102.13,51.21 102,51.21 101.56,51.65 101.43,51.65 101.3,51.53 101.3,51.4 101.75,50.96 101.75,50.83 101.62,50.7 101.5,50.7 101.05,51.15 100.93,51.15 100.71,50.93 100.71,37.72 101.37,37.06 102.08,37.06 103.4,35.74 104.43,35.74 v2(104.83,35.34)
  L4SGND w0.142: v2(104.83,35.34) 109.78,35.34 110.24,35.8 110.62,35.8 110.89,35.53 111.01,35.42 114.9,35.42 v2(114.98,35.34) 119.92,35.34 120.39,35.8 120.77,35.8 121.16,35.42 125.05,35.42 v2(125.13,35.34) 130.07,35.34 130.54,35.8 130.92,35.8 131.31,35.42 131.88,35.42 131.91,35.44 132.29,35.44 132.31,35.42 135.2,35.42 v2(135.28,35.34) 140.22,35.34 140.69,35.8 141.07,35.8 141.43,35.45 144.85,35.45 145.72,36.31 147.33,36.31 147.35,36.33 v2(147.35,36.33)
  BOTTOM w0.076: 107.18,61.72 107.78,62.32 107.78,66.68 107.85,66.75 107.85,67.2 107.61,67.44 107.61,67.71 107.64,67.76 107.73,67.93 107.73,67.94 107.85,68.19 107.87,68.23 CPU1.AJ36
  BOTTOM w0.14: RAM6.N8 v2(104.83,35.34) ; RAM8.N8 v2(125.13,35.34) ; RAM5.N8 v2(114.98,35.34) ; 107.18,61.72 107.18,60.96 105.73,59.51 104.8,59.51 v2(104.79,59.52) ; RAM7.N8 v2(135.28,35.34)
M_B_BG0: length 92.3
  L6 w0.142: v2(101.24,72.87) 101.54,72.87 102.63,73.97 105.24,73.97 105.38,73.82 105.38,73.21 106.37,72.22 106.37,63.02 106.32,62.96 106.32,61.79 106.04,61.52 106.04,53.42 102.15,49.53 102.15,38.51 102.74,37.92 104.08,37.92 104.33,37.67 104.33,36.73 104.62,36.45 105.68,36.45 105.93,36.69 108.14,36.69 108.4,36.94 v2(110.43,36.94) 111.04,36.34 114.47,36.34 114.53,36.4 116.19,36.4 116.45,36.66 116.47,36.66 116.5,36.69 118.29,36.69 118.55,36.94 v2(120.58,36.94) 121.19,36.34 124.62,36.34 124.68,36.4 126.34,36.4 126.6,36.66 126.62,36.66 126.65,36.69 128.44,36.69 128.7,36.94 v2(130.73,36.94) 131.34,36.34 134.77,36.34 134.83,36.4 136.49,36.4 136.75,36.66 136.77,36.66 136.8,36.69 138.59,36.69 138.85,36.94 v2(140.88,36.94) 141.2,36.94 141.81,36.34 142.82,36.34 143.09,36.61 143.09,37.08 143.27,37.26 v2(143.5,37.26)
  BOTTOM w0.14: v2(140.88,36.94) RAM7.M2 ; v2(110.43,36.94) RAM6.M2 ; v2(130.73,36.94) RAM8.M2 ; CPU1.W29 v2(101.24,72.87) ; v2(143.5,37.26) 144.54,38.3 RN1302.1 ; v2(120.58,36.94) RAM5.M2
M_B_BG1: length 49.4
  L2SGND w0.089: v2(103.07,72.8) 103.61,72.25 105.12,72.25 106.24,71.13 106.24,69.29 102.58,65.63 102.58,57.96 98.65,54.03 98.65,42.16 98.56,42.07 97.73,42.07 97.64,41.98 97.64,41.8 97.73,41.71 98.56,41.71 98.65,41.62 98.65,41.45 98.56,41.36 97.45,41.36 97.36,41.27 97.36,41.09 97.45,41 98.59,41 98.68,40.91 98.68,40.63 98.59,40.53 97.31,40.53 97.21,40.43 97.21,40.06 97.29,39.98 v2(99.28,39.98)
  BOTTOM w0.14: v2(99.28,39.98) 100.97,38.3 R1339.1 ; CPU1.Y28 102.68,73.18 v2(103.07,72.8)
M_B_BG1_E9_1: length 2.8
  BOTTOM w0.14: RAM6.E9 102.35,42.14 102.34,42.14 R1331.1
M_B_BG1_E9_2: length 1.3
  TOP w0.14: R1332.1 113.85,41.97 v2(114.02,42.14)
  BOTTOM w0.14: RAM5.E9 v2(114.02,42.14)
M_B_BG1_E9_3: length 1.3
  TOP w0.14: v2(124.17,42.14) 123.98,41.94 R1333.1
  BOTTOM w0.14: RAM8.E9 v2(124.17,42.14)
M_B_BG1_E9_4: length 1.3
  TOP w0.14: R1334.1 134.15,41.97 v2(134.32,42.14)
  BOTTOM w0.14: RAM7.E9 v2(134.32,42.14)
M_B_BG1_M9_R: length 52.8
  TOP w0.14: R1340.2 144.24,37.95 v2(144.24,37.24)
  L4SGND w0.142: v2(144.24,37.24) 143.77,36.77 143.24,36.77 143.09,36.62 143.09,36.61 142.82,36.34 141.81,36.34 141.36,36.78 141.36,37.12 141.08,37.41 140.69,37.41 140.27,36.98 135.97,36.98 135.47,36.49 134.62,36.49 v2(134.3,36.81) 133.83,36.34 131.66,36.34 131.31,36.69 131.31,37.03 130.93,37.41 130.54,37.41 130.12,36.98 125.82,36.98 125.32,36.49 124.47,36.49 v2(124.15,36.81) 123.68,36.34 121.51,36.34 121.16,36.69 121.16,37.03 120.78,37.41 120.39,37.41 119.97,36.98 115.67,36.98 115.17,36.49 114.32,36.49 v2(114,36.81) 113.53,36.34 111.36,36.34 111.01,36.69 111.01,37.03 110.63,37.41 110.24,37.41 109.82,36.98 105.52,36.98 105.02,36.49 104.17,36.49 v2(103.85,36.81)
  BOTTOM w0.14: v2(134.3,36.81) 134.31,36.82 134.6,36.82 RAM7.M9 ; R1312.1 v2(144.24,37.24) ; v2(124.15,36.81) 124.16,36.82 124.45,36.82 RAM8.M9 ; RAM6.M9 104.15,36.82 103.86,36.82 v2(103.85,36.81) 103.8,36.86 102.18,36.86 R1339.2 ; RAM5.M9 114.26,36.54 v2(114,36.81)
M_B_CKE0: length 92.5
  TOP w0.14: RN1305.1 147,37.2 v2(147.05,37.25)
  L4SGND w0.142: v2(147.05,37.25) 147.05,37.24 147.01,37.2 146.25,37.2 144.64,38.82 144.64,38.82 144.38,39.09 144.37,39.09 144.34,39.12 143.33,39.12 142.69,38.48 141.65,38.48 141.58,38.54 v2(140.88,38.54) 140.59,38.25 137.45,38.25 136.97,37.78 135.96,37.78 135.53,38.2 135.53,39.03 135.39,39.18 134.98,39.18 134.76,38.96 134.76,38.56 134.56,38.37 130.9,38.37 v2(130.73,38.54) 130.44,38.25 127.31,38.25 126.83,37.78 125.38,37.78 124.8,38.37 120.75,38.37 v2(120.58,38.54) 120.32,38.28 117.16,38.28 116.63,37.74 114.85,37.74 114.23,38.37 110.6,38.37 v2(110.43,38.54) 110.2,38.31 107.2,38.31 106.93,38.57 106.93,39.1 107.41,39.57 108.43,39.57 109.18,40.33 109.18,41.13 109.27,41.22 109.27,56.2 109.11,56.37 109.11,66.5 106.62,68.98 106.62,72.25 105.77,73.1 105.64,73.1 105.38,73.36 105.38,73.6 105.02,73.96 101.11,73.96 100.76,73.61 100.76,73.24 v2(100.35,72.82)
  BOTTOM w0.14: v2(110.43,38.54) RAM6.K2 ; CPU1.T28 v2(100.35,72.82) ; v2(130.73,38.54) RAM8.K2 ; v2(140.88,38.54) RAM7.K2 ; v2(120.58,38.54) RAM5.K2
M_B_CLK: length 1.7
  BOTTOM w0.102: R1313.2 R1314.2 145.87,41.88 C1370.1
M_B_CLK0: length 102.9
  TOP w0.102: v2(106.43,38.54) C1388.1
  L6 w0.089: v2(144.24,41.02) 144.24,41.28 144.09,41.43 143.77,41.43 142.19,39.84 139.9,39.84 139.73,39.67 136.77,39.67 136.45,39.36 136.45,38.98 v2(136.88,38.54) 136.31,38.09 135.89,38.09 134.41,39.57 127.47,39.57 126.94,39.05 v2(126.73,38.54) 126.14,38.07 125.75,38.07 124.25,39.57 117.32,39.57 116.79,39.04 v2(116.58,38.54) 116.03,38.1 116.02,38.1 115.62,38.1 114.09,39.62 107.51,39.62 v2(106.43,38.54)
  L6 w0.137: v2(106.7,72.82) 106.88,72.64 106.88,69.72 107.34,69.26 111.36,69.26 112.03,68.59 112.03,66.15 111.9,66.02 111.39,66.02 111.26,66.15 111.26,67.98 110.95,68.29 107.96,68.29 107.68,68.01 107.68,60.33 107.09,59.74 107.09,52.7 103.08,48.68 103.08,43.14 103.36,42.86 103.89,42.86 104.06,42.69 104.06,41.54 103.92,41.4 103.37,41.4 103.08,41.11 103.08,39.76 103.36,39.49 104.49,39.49 104.63,39.35 104.63,38.81 104.63,38.52 105.12,38.02 105.75,38.02 v2(106.43,38.54)
  BOTTOM w0.102: v2(144.24,41.02) 144.26,41.03 R1313.1
  BOTTOM w0.14: RAM8.K7 v2(126.73,38.54) ; RAM7.K7 v2(136.88,38.54) ; RAM6.K7 v2(106.43,38.54) ; RAM5.K7 v2(116.58,38.54) ; CPU1.AF29 v2(106.7,72.82)
M_B_CLK#0: length 103.1
  TOP w0.102: C1388.2 105.63,37.74 v2(105.63,38.54)
  L6 w0.089: v2(144.24,41.89) 143.98,41.62 143.69,41.62 142.11,40.03 139.82,40.03 139.65,39.86 136.69,39.86 136.26,39.44 136.26,38.72 v2(136.08,38.54) 135.71,38.54 134.49,39.76 127.39,39.76 126.71,39.08 126.1,39.08 125.93,38.91 v2(125.93,38.54) 125.55,38.54 124.33,39.76 117.24,39.76 116.56,39.08 115.95,39.08 115.78,38.91 v2(115.78,38.54) 115.44,38.54 114.17,39.81 107.43,39.81 106.68,39.06 105.72,39.06 105.56,38.9 105.56,38.62 v2(105.63,38.54)
  L6 w0.137: v2(106.72,73.53) 106.99,73.53 107.12,73.4 107.12,69.81 107.44,69.49 111.46,69.49 112.27,68.68 112.27,66.05 111.99,65.78 111.29,65.78 111.02,66.05 111.02,67.88 110.85,68.05 108.06,68.05 107.92,67.91 107.92,60.23 107.33,59.64 107.33,52.6 103.32,48.58 103.32,43.24 103.46,43.1 103.99,43.1 104.3,42.79 104.3,41.44 104.02,41.16 103.47,41.16 103.32,41.01 103.32,39.86 103.46,39.73 104.59,39.73 104.87,39.45 104.87,38.71 104.87,38.62 105.22,38.26 105.5,38.26 105.63,38.4 v2(105.63,38.54)
  BOTTOM w0.102: v2(144.24,41.89) 144.31,41.82 R1314.1
  BOTTOM w0.14: RAM5.K8 v2(115.78,38.54) ; RAM7.K8 135.68,38.41 135.82,38.54 v2(136.08,38.54) ; v2(125.93,38.54) 125.67,38.54 125.53,38.41 RAM8.K8 ; v2(106.72,73.53) 106.4,73.53 106.26,73.39 CPU1.AF28 ; RAM6.K8 v2(105.63,38.54)
M_B_CS#0: length 99.7
  L2SGND w0.089: v2(108.6,63.25) 108.29,63.25 108.2,63.16 108.2,61.64 108.76,61.09 108.76,53.39 108.08,52.72 108.08,52.57 108.21,52.44 108.21,52.31 108.05,52.15 107.93,52.15 107.81,52.27 107.64,52.27 107.51,52.14 107.51,52.02 107.89,51.64 107.89,51.51 107.77,51.38 107.64,51.38 107.26,51.77 107.13,51.77 107.01,51.64 107.01,51.52 107.45,51.07 107.45,50.94 107.33,50.82 107.2,50.82 106.75,51.26 106.63,51.26 106.5,51.14 106.5,51.01 106.95,50.57 106.95,50.44 106.82,50.32 106.7,50.32 106.25,50.76 106.13,50.76 106,50.64 106,50.51 106.45,50.06 106.45,49.94 106.32,49.81 106.19,49.81 105.75,50.26 105.62,50.26 105.5,50.13 105.5,50.01 105.94,49.56 105.94,49.44 105.82,49.31 105.69,49.31 105.25,49.76 105.12,49.76 104.99,49.63 104.99,49.5 105.44,49.06 105.44,48.93 105.31,48.81 105.19,48.81 104.74,49.25 104.62,49.25 104.49,49.13 104.49,49 104.94,48.56 104.94,48.43 104.81,48.3 104.69,48.3 104.24,48.75 104.11,48.75 103.99,48.62 103.99,48.5 104.43,48.05 104.43,47.93 104.31,47.8 104.18,47.8 103.74,48.25 103.61,48.25 103.49,48.12 103.49,48 103.93,47.55 103.93,47.42 103.81,47.3 103.68,47.3 103.57,47.41 103.45,47.41 103.32,47.28 103.32,47.16 103.43,47.05 103.43,46.92 102.61,46.1 102.6,46.07 102.6,39.71 102.99,39.32 104.3,39.32 104.5,39.52 107.62,39.52 107.81,39.33 107.81,37.84 v2(107.71,37.74)
  L6 w0.142: v2(107.71,37.74) 107.71,37.76 108.15,38.2 109.02,38.2 109.84,39.01 110.66,39.01 111.17,38.51 114.7,38.51 115.47,37.74 v2(117.86,37.74) 117.86,37.76 118.3,38.2 119.14,38.2 120.04,39.11 120.68,39.11 121.28,38.51 124.76,38.51 125.53,37.74 v2(128.01,37.74) 128.01,37.76 128.45,38.2 129.32,38.2 130.14,39.01 130.98,39.01 131.49,38.51 134.99,38.51 135.76,37.74 137.8,37.74 v2(137.85,37.79) 138.63,38.58 139.09,38.58 139.94,39.42 142.88,39.42 143.5,40.04 v2(144.12,40.04)
  BOTTOM w0.076: v2(108.6,63.25) 108.6,63.3 109.26,63.96 109.26,66.65 109.07,66.84 109.07,67.49 CPU1.AL37
  BOTTOM w0.14: RAM7.L7 137.4,37.34 v2(137.85,37.79) ; RAM8.L7 127.61,37.34 v2(128.01,37.74) ; RN1302.4 144.18,39.98 v2(144.12,40.04) ; RAM5.L7 117.46,37.34 v2(117.86,37.74) ; RAM6.L7 106.13,37.24 107.23,37.24 107.71,37.71 v2(107.71,37.74)
M_B_DQ0: length 31.8
  L6 w0.089: v2(110.41,61.11) 110.14,61.11 110.05,61.02 110.05,57.92 109.96,57.83 109.38,57.83 109.29,57.74 109.29,57.56 109.38,57.47 109.96,57.47 110.05,57.39 110.05,56.45 109.96,56.36 109.44,56.36 109.29,56.21 109.29,52.05 105.71,48.46 105.71,46.92 v2(105.4,46.61)
  BOTTOM w0.076: 109.68,62.64 109.68,66.47 110.12,66.91 110.12,67.2 109.95,67.36 109.95,67.74 110.06,67.94 110.06,68.57 CPU1.AN35
  BOTTOM w0.089: RAM6.A3 109.23,46.29 108.91,46.61 v2(105.4,46.61) ; 109.68,62.64 109.68,61.84 v2(110.41,61.11)
M_B_DQ1: length 29.3
  L6 w0.089: v2(110.36,63.11) 109.47,62.22 109.47,60.47 109.47,60.47 109.47,60.25 108.71,59.49 108.71,52.32 104.32,47.94 104.32,45.68 104.83,45.17 v2(104.83,44.94)
  BOTTOM w0.076: CPU1.AN34 111.12,69.54 111.15,69.5 111.33,69.32 111.33,68.58 111.25,68.36 111.25,68.11 111.3,68 111.3,67.82 111.25,67.71 111.25,67.06 111.38,66.93 111.38,63.99 111.22,63.82
  BOTTOM w0.089: RAM6.B8 v2(104.83,44.94) ; 111.22,63.82 110.51,63.11 v2(110.36,63.11)
M_B_DQ2: length 31.2
  L6 w0.089: v2(105.63,43.33) 105.63,43.43 106.78,44.57 107.25,44.57 107.66,44.99 107.66,45.25 108.1,45.68 108.1,47.17 112.84,51.91 112.84,52.2 112.75,52.29 112.24,52.29 112.15,52.38 112.15,52.56 112.24,52.65 112.75,52.65 112.84,52.73 v2(112.84,59.6)
  BOTTOM w0.076: 111.58,63.28 111.58,65.13 111.55,65.16 111.55,65.68 111.56,65.69 111.56,66.99 111.42,67.13 111.42,67.68 111.46,67.79 111.46,68.03 111.45,68.07 111.42,68.14 111.42,68.33 111.59,68.79 CPU1.AR35
  BOTTOM w0.089: v2(112.84,59.6) 111.58,60.86 111.58,63.28 ; v2(105.63,43.33) 105.64,43.33 RAM6.D7
M_B_DQ3: length 31.8
  L6 w0.089: v2(107.05,45.92) 107.05,47.43 111.27,51.64 111.27,52.31 111.18,52.4 110.78,52.4 110.69,52.49 110.69,52.67 110.78,52.75 111.18,52.75 111.27,52.84 111.27,53.02 111.18,53.11 110.8,53.11 110.71,53.2 110.71,53.38 110.8,53.47 111.18,53.47 111.27,53.55 111.27,59.36 111.65,59.74 111.65,61.88 v2(112.78,63.01)
  BOTTOM w0.076: CPU1.AR34 111.95,68.99 111.95,68.04 112.11,67.74 112.11,67.36 112.05,67.3 112.05,65.49
  BOTTOM w0.089: v2(107.05,45.92) 107.05,45.82 107.74,45.14 107.74,44.83 108.97,43.6 109.09,43.6 RAM6.C3 ; 112.05,65.49 112.37,65.17 112.37,63.36 112.72,63.01 v2(112.78,63.01)
M_B_DQ4: length 30
  L6 w0.089: v2(104.83,44.14) 104.36,44.61 104.36,45.14 103.98,45.52 103.98,47.37 103.98,48.03 108.41,52.46 108.41,55.87 108.32,55.96 108.18,55.96 108.1,56.05 108.1,56.23 108.18,56.32 108.32,56.32 108.41,56.41 108.41,56.59 108.32,56.68 108.08,56.68 107.99,56.76 107.99,56.94 108.08,57.03 108.32,57.03 108.41,57.12 108.41,57.3 108.32,57.39 108.08,57.39 107.99,57.48 107.99,57.65 108.08,57.74 108.32,57.74 108.41,57.83 108.41,58.01 108.32,58.1 108.08,58.1 107.99,58.19 107.99,58.36 108.08,58.45 108.32,58.45 108.41,58.54 108.41,58.72 108.32,58.81 108.08,58.81 107.99,58.9 107.99,59.08 108.08,59.16 108.32,59.16 108.41,59.25 108.41,59.68 109.14,60.4 109.14,65.07 v2(110.32,66.26)
  BOTTOM w0.076: v2(110.32,66.26) 110.45,66.38 110.45,67.52 CPU1.AN37
  BOTTOM w0.089: v2(104.83,44.14) RAM6.C8
M_B_DQ5: length 31.5
  L6 w0.089: v2(104.78,46.42) 104.96,46.6 104.96,46.79 105.28,47.1 105.28,48.46 109,52.18 109,59.3 109.76,60.06 109.76,61.86 110.32,62.43 v2(110.41,62.43)
  BOTTOM w0.076: CPU1.AN36 110.38,68.18 110.12,67.7 110.12,67.43 110.28,67.27 110.28,66.84 109.84,66.4 109.84,62.99 v2(110.41,62.43)
  BOTTOM w0.089: RAM6.C2 109.67,44.1 109.05,44.1 108.39,44.76 108.39,45.19 107.23,46.35 105.74,46.35 105.57,46.18 105.02,46.18 v2(104.78,46.42)
M_B_DQ6: length 32
  L6 w0.089: v2(107,45.24) 107.49,45.72 107.49,47.43 111.56,51.5 111.56,56.62 111.65,56.71 111.94,56.71 112.03,56.8 112.03,56.98 111.94,57.07 111.65,57.07 111.56,57.15 111.56,57.33 111.65,57.42 112.03,57.42 112.12,57.51 112.12,57.69 112.03,57.78 111.65,57.78 111.56,57.87 111.56,58.04 111.65,58.13 112.03,58.13 112.12,58.22 112.12,58.4 112.03,58.49 111.65,58.49 111.56,58.58 111.56,58.75 111.65,58.84 112.03,58.84 112.12,58.93 112.12,60.91 v2(112.84,61.62)
  BOTTOM w0.076: 112.12,62.94 112.12,65.07 111.88,65.3 111.88,65.54 111.89,65.55 111.89,67.37 111.95,67.43 111.95,67.7 111.68,68.18 CPU1.AR36
  BOTTOM w0.089: v2(107,45.24) 107,44.96 108.48,43.48 108.69,43.48 108.79,43.37 108.8,43.37 RAM6.D3 ; v2(112.84,61.62) 112.82,61.62 112.12,62.33 112.12,62.94
M_B_DQ7: length 31.6
  L6 w0.089: v2(112.85,60.25) 112.41,59.81 112.41,56.36 112.32,56.27 111.94,56.27 111.85,56.18 111.85,56 111.94,55.91 112.32,55.91 112.41,55.82 112.41,55.64 112.32,55.56 111.94,55.56 111.85,55.47 111.85,55.29 111.94,55.2 112.32,55.2 112.41,55.11 112.41,54.93 112.32,54.84 111.94,54.84 111.85,54.76 111.85,54.58 111.94,54.49 112.32,54.49 112.41,54.4 112.41,54.22 112.32,54.13 111.94,54.13 111.85,54.04 111.85,53.87 111.94,53.78 112.2,53.78 112.29,53.69 112.29,53.51 112.2,53.42 111.94,53.42 111.85,53.33 111.85,51.34 107.79,47.28 107.79,45.7 107.43,45.34 107.43,45.07 107.17,44.8 106.3,44.8 v2(105.63,44.14)
  BOTTOM w0.076: 111.86,62.52 111.86,65.09 111.72,65.23 111.72,65.61 111.72,65.62 111.72,67.55 CPU1.AR37
  BOTTOM w0.089: v2(112.85,60.25) 111.86,61.25 111.86,62.52 ; RAM6.C7 v2(105.63,44.14)
M_B_DQ8: length 34.7
  L6 w0.089: v2(107.16,42.32) 107.16,42.53 108.58,43.95 108.82,44.05 110.26,45.49 110.26,46.21 112.77,48.72 112.77,49.14 114.53,50.9 114.53,61.18 114.04,61.67 114.04,65.1 v2(112.82,66.32)
  BOTTOM w0.076: CPU1.AU35 113,68.79 113.08,68.57 113.08,68.56 113.13,68.41 113.13,68.4 113.15,68.35 113.15,68.12 113.13,68.07 113.13,68.06 113.13,67.76 113.13,67.75 113.15,67.7 113.15,67.2 113.23,67.13 113.23,66.73 v2(112.82,66.32)
  BOTTOM w0.089: v2(107.16,42.32) 107.18,42.32 107.37,42.13 107.37,40.28 RAM6.J7
M_B_DQ9: length 34.9
  L6 w0.089: v2(112.82,65.05) 113.53,64.34 113.53,61.16 113.95,60.74 113.95,51.14 108.98,46.18 108.98,45.75 108.35,45.11 108.35,44.75 107.62,44.02 107.32,44.02 106.43,43.12 106.43,41.18 v2(106.59,41.01)
  BOTTOM w0.076: CPU1.AU34 112.9,69.53 112.61,68.93 112.61,67.99 112.57,67.92 112.47,67.74 112.47,67.73 112.41,67.62 112.4,67.61 112.4,67.42 112.22,67.23 112.22,65.65 v2(112.82,65.05)
  BOTTOM w0.089: v2(106.59,41.01) 106.59,40.97 106.6,40.96 106.6,40.6 106.1,40.1 105.59,40.1 RAM6.H8
M_B_DQ10: length 36.4
  L6 w0.089: v2(110.43,40.94) 110.74,41.25 111.28,41.25 111.86,40.67 113.28,40.67 113.56,40.95 113.56,43.39 113.47,43.48 113.39,43.48 113.3,43.57 113.3,43.74 113.39,43.83 113.47,43.83 113.56,43.92 113.56,44.1 113.47,44.19 113.39,44.19 113.3,44.28 113.3,44.45 113.39,44.54 113.47,44.54 113.56,44.63 113.56,44.81 113.47,44.9 113.39,44.9 113.3,44.99 113.3,45.17 113.39,45.25 113.47,45.25 113.56,45.34 113.56,45.67 116.67,48.78 116.67,60.47 116.5,60.64 116.5,64.47 114.96,66 v2(114.8,66)
  BOTTOM w0.076: CPU1.AW35 114.51,68.58 114.51,67.96 114.53,67.92 114.62,67.76 114.62,67.08 114.44,66.89 114.44,66.37 v2(114.8,66)
  BOTTOM w0.089: RAM6.H2 110.43,40.14 v2(110.43,40.94)
M_B_DQ11: length 34.9
  L6 w0.089: v2(112.82,64.41) 113.28,63.96 113.28,60.96 113.66,60.58 113.66,51.43 113.19,50.96 113.07,50.96 112.97,51.06 112.85,51.06 112.72,50.93 112.72,50.81 112.82,50.71 112.82,50.59 112.69,50.46 112.57,50.46 112.47,50.56 112.35,50.56 112.22,50.43 112.22,50.3 112.31,50.21 112.31,50.08 112.19,49.96 112.06,49.96 111.97,50.05 111.84,50.05 111.72,49.93 111.72,49.8 111.81,49.71 111.81,49.58 111.69,49.46 111.56,49.46 111.47,49.55 111.34,49.55 111.21,49.42 111.21,49.3 111.31,49.2 111.31,49.08 108.53,46.3 108.53,45.79 107.89,45.16 107.89,44.88 107.36,44.35 107.15,44.35 106.06,43.26 106.06,43.16 106.05,43.15 106.05,42.15 v2(105.63,41.74)
  BOTTOM w0.076: CPU1.AW34 113.46,69.54 113.26,69.33 113.26,68.54 113.28,68.5 113.28,68.49 113.32,68.38 113.32,68.08 113.31,68.08 113.3,68.03 113.3,67.79 113.31,67.76 113.33,67.71 113.39,67.53 113.39,64.99 v2(112.82,64.41)
  BOTTOM w0.089: v2(105.63,41.74) RAM6.F7
M_B_DQ12: length 34.4
  L6 w0.089: v2(107.86,40.89) 107.56,41.2 107.56,42.15 107.85,42.44 107.85,42.44 108.07,42.66 108.07,43.13 108.51,43.57 109.15,43.84 110.48,45.17 110.48,45.58 110.48,45.94 113.74,49.21 113.74,49.33 113.63,49.45 113.63,49.58 113.75,49.7 113.88,49.7 113.99,49.59 114.12,49.59 114.25,49.71 114.25,49.84 114.13,49.96 114.13,50.08 114.25,50.21 114.38,50.21 114.5,50.09 114.62,50.09 114.85,50.32 114.85,61.34 114.27,61.93 114.27,65.53 v2(112.83,66.97)
  BOTTOM w0.089: RAM6.J3 107.86,40.31 v2(107.86,40.89) ; v2(112.83,66.97) 112.9,67.03 CPU1.AU37
M_B_DQ13: length 34.4
  L6 w0.089: v2(112.82,65.68) 113.79,64.72 113.79,61.44 114.24,60.99 114.24,51.02 111.36,48.14 111.36,48.01 111.44,47.93 111.44,47.81 111.32,47.68 111.19,47.68 111.11,47.76 110.99,47.76 110.86,47.63 110.86,47.51 110.94,47.43 110.94,47.3 110.81,47.18 110.69,47.18 110.61,47.26 110.48,47.26 109.37,46.14 109.37,44.89 108.99,44.52 108.42,44.52 106.68,42.78 106.68,41.8 v2(106.94,41.55)
  BOTTOM w0.076: v2(112.82,65.68) 112.38,66.12 112.38,67.17 112.57,67.35 112.57,67.57 112.63,67.69 112.63,67.7 112.68,67.78 112.91,68.19 CPU1.AU36
  BOTTOM w0.089: v2(106.94,41.55) 106.94,41.55 107.15,41.33 107.15,40.67 106.22,39.74 RAM6.H7
M_B_DQ14: length 34.9
  L6 w0.089: v2(114.8,65.39) 116.3,63.9 116.3,60.54 116.36,60.47 116.36,49.03 112.77,45.44 112.77,41.42 112.68,41.33 111.91,41.33 111.82,41.42 111.82,42.05 111.61,42.25 110.22,42.25 109.99,42.03 109.99,41.03 109.9,40.94 v2(109.64,40.94)
  BOTTOM w0.076: v2(114.8,65.39) 114.27,65.93 114.27,67.13 114.45,67.32 114.45,67.72 114.43,67.76 114.2,68.18 CPU1.AW36
  BOTTOM w0.089: v2(109.64,40.94) 110.03,40.55 RAM6.G2
M_B_DQ15: length 34.6
  L6 w0.089: v2(108.57,40.77) 109.31,41.52 109.31,41.91 110.13,42.72 111.55,42.72 111.74,42.91 111.74,43.57 111.83,43.66 112.32,43.66 112.41,43.75 112.41,43.93 112.32,44.01 112.04,44.01 111.95,44.1 111.95,44.28 112.04,44.37 112.38,44.37 112.46,44.46 112.46,44.64 112.38,44.73 112.04,44.73 111.95,44.81 111.95,45.11 116.07,49.23 116.07,63.51 v2(114.79,64.78)
  BOTTOM w0.076: v2(114.79,64.78) 114.09,65.49 114.09,67.47 CPU1.AW37
  BOTTOM w0.089: RAM6.H3 108.57,40.4 v2(108.57,40.77)
M_B_DQ16: length 36.9
  L4SGND w0.089: v2(114.98,44.14) 114.51,44.61 114.51,45.13 113.87,45.77 113.74,45.77 113.38,45.41 113.26,45.41 113.13,45.54 113.13,45.66 113.49,46.02 113.49,46.15 113.36,46.27 113.24,46.27 113.01,46.04 112.88,46.04 112.76,46.17 112.76,46.29 112.99,46.52 112.99,46.65 112.86,46.77 112.74,46.77 112.5,46.54 112.38,46.54 112.25,46.67 112.25,46.79 112.48,47.03 112.48,47.15 112.36,47.28 112.23,47.28 112.05,47.1 111.93,47.1 111.8,47.22 111.8,47.35 111.98,47.53 111.98,47.65 110.49,49.15 110.49,59.13 109.92,59.69 109.92,66.24 109.21,66.96 109.21,67.12 106.86,69.46 106.86,72.04 v2(107.66,72.85)
  BOTTOM w0.089: RAM5.C8 v2(114.98,44.14) ; CPU1.AJ29 v2(107.66,72.85)
M_B_DQ17: length 37.4
  L4SGND w0.089: v2(114.98,44.94) 114.98,45.17 114.15,45.99 114.15,46.11 114.43,46.39 114.43,46.49 114.26,46.66 114.14,46.66 113.86,46.38 113.74,46.38 113.61,46.5 113.61,46.63 113.89,46.91 113.89,47.03 113.76,47.16 113.64,47.16 113.36,46.88 113.23,46.88 113.11,47.01 113.11,47.13 113.38,47.41 113.38,47.54 113.26,47.66 113.13,47.66 112.86,47.38 112.73,47.38 112.6,47.51 112.6,47.64 112.88,47.91 112.88,48.04 112.75,48.16 112.63,48.16 112.35,47.89 112.23,47.89 112.1,48.01 112.1,48.14 112.38,48.42 112.38,48.54 112.25,48.67 112.13,48.67 111.85,48.39 111.72,48.39 111.6,48.52 111.6,48.64 111.88,48.92 111.88,49.04 110.87,50.05 110.87,66.44 109.83,67.48 109.09,67.48 107.04,69.54 107.04,71.97 107.25,72.19 v2(107.64,72.19)
  BOTTOM w0.089: RAM5.B8 v2(114.98,44.94) ; CPU1.AJ30 v2(107.64,72.19)
M_B_DQ18: length 38
  L4SGND w0.089: v2(109.44,70.92) 108.9,70.38 108.9,69.94 109.51,69.34 109.88,69.34 111.78,67.44 112.93,67.44 113.33,67.04 113.33,55.97 113.24,55.88 112.92,55.88 112.83,55.79 112.83,55.61 112.92,55.52 113.24,55.52 113.33,55.44 113.33,55.26 113.24,55.17 112.92,55.17 112.83,55.08 112.83,54.9 112.92,54.81 113.24,54.81 113.33,54.72 113.33,54.55 113.24,54.46 112.92,54.46 112.83,54.37 112.83,54.19 112.92,54.1 113.24,54.1 113.33,54.01 113.33,53.84 113.24,53.75 112.92,53.75 112.83,53.66 112.83,53.48 112.92,53.39 113.24,53.39 113.33,53.3 113.33,53.12 113.24,53.04 112.92,53.04 112.83,52.95 112.83,52.77 112.92,52.68 113.24,52.68 113.33,52.59 113.33,52.41 113.24,52.32 112.92,52.32 112.83,52.24 112.83,52.06 112.92,51.97 113.24,51.97 113.33,51.88 113.33,51.59 117.06,47.86 117.06,46.04 v2(117.02,46)
  BOTTOM w0.089: v2(117.02,46) 117.74,45.28 117.74,45.27 119.27,43.74 RAM5.C3 ; CPU1.AM32 v2(109.44,70.92)
M_B_DQ19: length 38.2
  L4SGND w0.089: v2(109.44,71.58) 109.84,71.18 109.84,70.75 109.78,70.69 109.78,69.69 111.83,67.64 112.98,67.64 113.63,66.98 113.63,51.7 113.84,51.49 113.97,51.49 114.18,51.7 114.3,51.7 114.43,51.57 114.43,51.45 114.22,51.24 114.22,51.11 114.34,50.99 114.47,50.99 114.64,51.16 114.77,51.16 114.9,51.04 114.9,50.91 114.72,50.73 114.72,50.61 114.85,50.48 114.97,50.48 115.15,50.66 115.27,50.66 115.4,50.53 115.4,50.41 115.22,50.23 115.22,50.11 115.35,49.98 115.47,49.98 115.64,50.14 115.76,50.14 115.89,50.02 115.89,49.89 115.73,49.73 115.73,49.6 115.85,49.48 115.98,49.48 116.13,49.63 116.25,49.63 116.38,49.5 116.38,49.38 116.23,49.23 116.23,49.1 116.35,48.97 116.48,48.97 116.64,49.14 116.77,49.14 116.9,49.01 116.9,48.89 116.73,48.72 116.73,48.6 117.4,47.93 117.4,46.43 117.45,46.38 117.45,45.79 v2(117.02,45.36)
  BOTTOM w0.089: v2(117.02,45.36) 117.02,45.3 RAM5.D3 ; CPU1.AM31 v2(109.44,71.58)
M_B_DQ20: length 38.9
  L4SGND w0.089: v2(109.44,72.21) 110.02,71.63 110.02,70.68 109.96,70.61 109.96,69.77 111.89,67.84 113.03,67.84 113.92,66.94 113.92,52.49 114.39,52.03 114.52,52.03 114.74,52.25 114.87,52.25 114.99,52.13 114.99,52 114.77,51.77 114.77,51.65 114.89,51.52 115.02,51.52 115.24,51.75 115.37,51.75 115.5,51.62 115.5,51.5 115.27,51.27 115.27,51.15 115.4,51.02 115.52,51.02 115.75,51.25 115.87,51.25 116,51.12 116,50.99 115.77,50.77 115.77,50.64 115.9,50.52 116.02,50.52 116.25,50.74 116.38,50.74 116.5,50.62 116.5,50.49 116.28,50.27 116.28,50.14 116.4,50.01 116.53,50.01 116.75,50.24 116.88,50.24 117,50.11 117,49.99 116.78,49.76 116.78,49.64 116.99,49.43 117.11,49.43 117.24,49.56 117.36,49.56 117.49,49.43 117.49,49.31 117.36,49.18 117.36,49.05 117.68,48.73 117.68,48.73 117.69,48.73 117.69,45.43 117.19,44.93 116.86,44.93 116.06,44.14 v2(115.78,44.14)
  BOTTOM w0.089: CPU1.AM30 v2(109.44,72.21) ; RAM5.C7 v2(115.78,44.14)
M_B_DQ21: length 39.2
  L4SGND w0.089: v2(109.47,72.85) 110.24,72.08 110.24,70.77 110.76,70.24 110.76,69.22 111.96,68.01 113.11,68.01 114.22,66.9 114.22,53.31 114.42,53.11 114.55,53.11 114.78,53.34 114.91,53.34 115.03,53.21 115.03,53.09 114.8,52.86 114.8,52.73 114.93,52.6 115.05,52.6 115.23,52.78 115.36,52.78 115.48,52.66 115.48,52.53 115.3,52.35 115.3,52.23 115.43,52.1 115.56,52.1 115.74,52.28 115.86,52.28 115.99,52.16 115.99,52.03 115.81,51.85 115.81,51.72 115.93,51.6 116.06,51.6 116.21,51.75 116.34,51.75 116.46,51.63 116.46,51.5 116.31,51.35 116.31,51.22 116.45,51.08 116.62,51.08 116.8,51.26 116.93,51.26 117.06,51.14 117.06,51.01 116.85,50.81 116.85,50.68 117.98,49.55 117.98,46.13 117.9,46.05 117.9,45.34 117.26,44.7 117.05,44.7 116.31,43.96 116.31,43.87 v2(115.79,43.34)
  BOTTOM w0.089: v2(115.79,43.34) 116.18,42.95 RAM5.D7 ; CPU1.AM29 v2(109.47,72.85)
M_B_DQ22: length 36.6
  L4SGND w0.089: v2(107.66,71.53) 107.3,71.53 107.21,71.44 107.21,69.61 109.04,67.79 109.78,67.79 111.16,66.4 111.16,50.19 v2(114.93,46.42)
  BOTTOM w0.089: CPU1.AJ31 v2(107.66,71.53) ; v2(114.93,46.42) 115.17,46.18 116.58,46.18 116.83,46.43 117.35,46.43 117.98,45.79 117.98,45.34 119.22,44.1 120.09,44.1 120.18,44.01 RAM5.C2
M_B_DQ23: length 36.2
  L4SGND w0.089: v2(107.68,70.9) 107.68,70.89 107.39,70.6 107.39,69.69 108.99,68.09 109.73,68.09 111.51,66.31 111.51,50.29 111.86,49.93 111.98,49.93 112.07,50.02 112.2,50.02 112.33,49.9 112.33,49.77 112.24,49.68 112.24,49.56 112.36,49.43 112.49,49.43 112.58,49.52 112.7,49.52 112.83,49.39 112.83,49.27 112.74,49.18 112.74,49.05 112.86,48.93 112.99,48.93 113.07,49 113.19,49 113.32,48.88 113.32,48.75 113.24,48.68 113.24,48.55 113.37,48.42 113.49,48.42 113.64,48.57 113.77,48.57 113.89,48.45 113.89,48.32 113.74,48.17 113.74,48.05 113.87,47.92 114,47.92 114.14,48.07 114.27,48.07 114.39,47.94 114.39,47.82 114.25,47.67 114.25,47.54 114.37,47.42 114.5,47.42 114.65,47.57 114.77,47.57 114.9,47.44 114.9,47.31 114.75,47.17 114.75,47.04 114.95,46.85 115.31,46.85 v2(115.55,46.61)
  BOTTOM w0.089: CPU1.AJ32 107.7,70.84 107.69,70.89 v2(107.68,70.9) ; v2(115.55,46.61) 116.67,46.61 116.7,46.64 118.08,46.64 RAM5.A3
M_B_DQ24: length 38.3
  L4SGND w0.089: v2(111.31,71.59) 111.55,71.35 111.55,71.11 111.66,71.01 111.66,70.84 112.2,70.29 112.2,70.04 114.69,67.55 115.07,67.55 115.22,67.55 115.93,66.84 115.93,56.38 119.42,52.88 119.42,44.7 117.59,42.86 117.59,40.29 v2(117.62,40.25)
  BOTTOM w0.089: RAM5.J7 116.38,39.14 116.51,39.14 v2(117.62,40.25) ; CPU1.AR31 v2(111.31,71.59)
M_B_DQ25: length 38.2
  L4SGND w0.089: v2(111.62,70.05) 111.62,69.16 112.06,68.71 112.17,68.61 113.13,68.61 114.55,67.19 115.07,67.19 115.44,66.82 115.44,61.17 115.17,60.9 115.17,56.31 115.52,55.96 115.52,55.84 115.3,55.61 115.3,55.49 115.42,55.36 115.55,55.36 115.77,55.59 115.9,55.59 116.02,55.46 116.02,55.33 115.8,55.11 115.8,54.98 115.92,54.86 116.05,54.86 116.27,55.08 116.4,55.08 118.77,52.71 118.77,45.83 118.34,45.39 118.34,45.16 118.33,45.16 118.33,45.14 116.99,43.8 116.99,41.92 117,41.92 117,41.57 116.99,41.56 116.99,41.32 v2(116.59,40.92)
  BOTTOM w0.089: CPU1.AR32 111.73,70.18 111.6,70.05 v2(111.62,70.05) ; RAM5.H8 115.74,40.1 115.92,40.1 116.13,40.19 116.32,40.19 116.59,40.46 v2(116.59,40.92)
M_B_DQ26: length 41.1
  L4SGND w0.089: v2(119.79,40.94) 119.79,41.54 120.5,42.25 121.04,42.25 122.31,43.52 122.31,45.86 121.81,46.35 121.81,53.12 120.84,54.09 120.84,54.21 121.06,54.43 121.06,54.55 120.93,54.68 120.8,54.68 120.59,54.47 120.47,54.47 120.34,54.59 120.34,54.72 120.69,55.06 120.69,55.19 120.56,55.32 120.44,55.32 120.09,54.97 119.96,54.97 119.84,55.09 119.84,55.22 120.18,55.57 120.18,55.69 118.37,57.51 118.37,60.9 118.15,61.11 118.15,66.98 117.57,67.56 116.87,67.56 115.19,69.23 115.19,69.36 114.24,70.31 114.01,70.31 113.52,70.79 113.52,71.74 v2(113.1,72.16)
  BOTTOM w0.089: v2(119.79,40.94) 119.79,40.13 RAM5.H2 ; v2(113.1,72.16) 113.27,72.16 CPU1.AV30
M_B_DQ27: length 41.5
  L4SGND w0.089: v2(113.12,72.85) 114.45,71.53 114.45,70.36 115.32,69.49 115.32,69.48 115.37,69.43 115.37,69.31 116.94,67.73 117.65,67.73 118.41,66.97 118.41,61.27 118.66,61.01 118.66,57.63 122.14,54.15 122.14,53.86 122.23,53.77 122.54,53.77 122.62,53.68 122.62,53.51 122.54,53.42 122.23,53.42 122.14,53.33 122.14,53.15 122.23,53.06 122.54,53.06 122.62,52.97 122.62,52.79 122.54,52.71 122.23,52.71 122.14,52.62 122.14,52.44 122.23,52.35 122.54,52.35 122.62,52.26 122.62,52.08 122.54,51.99 122.23,51.99 122.14,51.91 122.14,51.73 122.23,51.64 122.54,51.64 122.62,51.55 122.62,51.37 122.54,51.28 122.23,51.28 122.14,51.19 122.14,46.76 122.53,46.38 122.53,42.29 121.18,40.94 v2(120.58,40.94)
  BOTTOM w0.089: v2(113.12,72.85) 113.44,72.53 CPU1.AV29 ; RAM5.G2 v2(120.58,40.94)
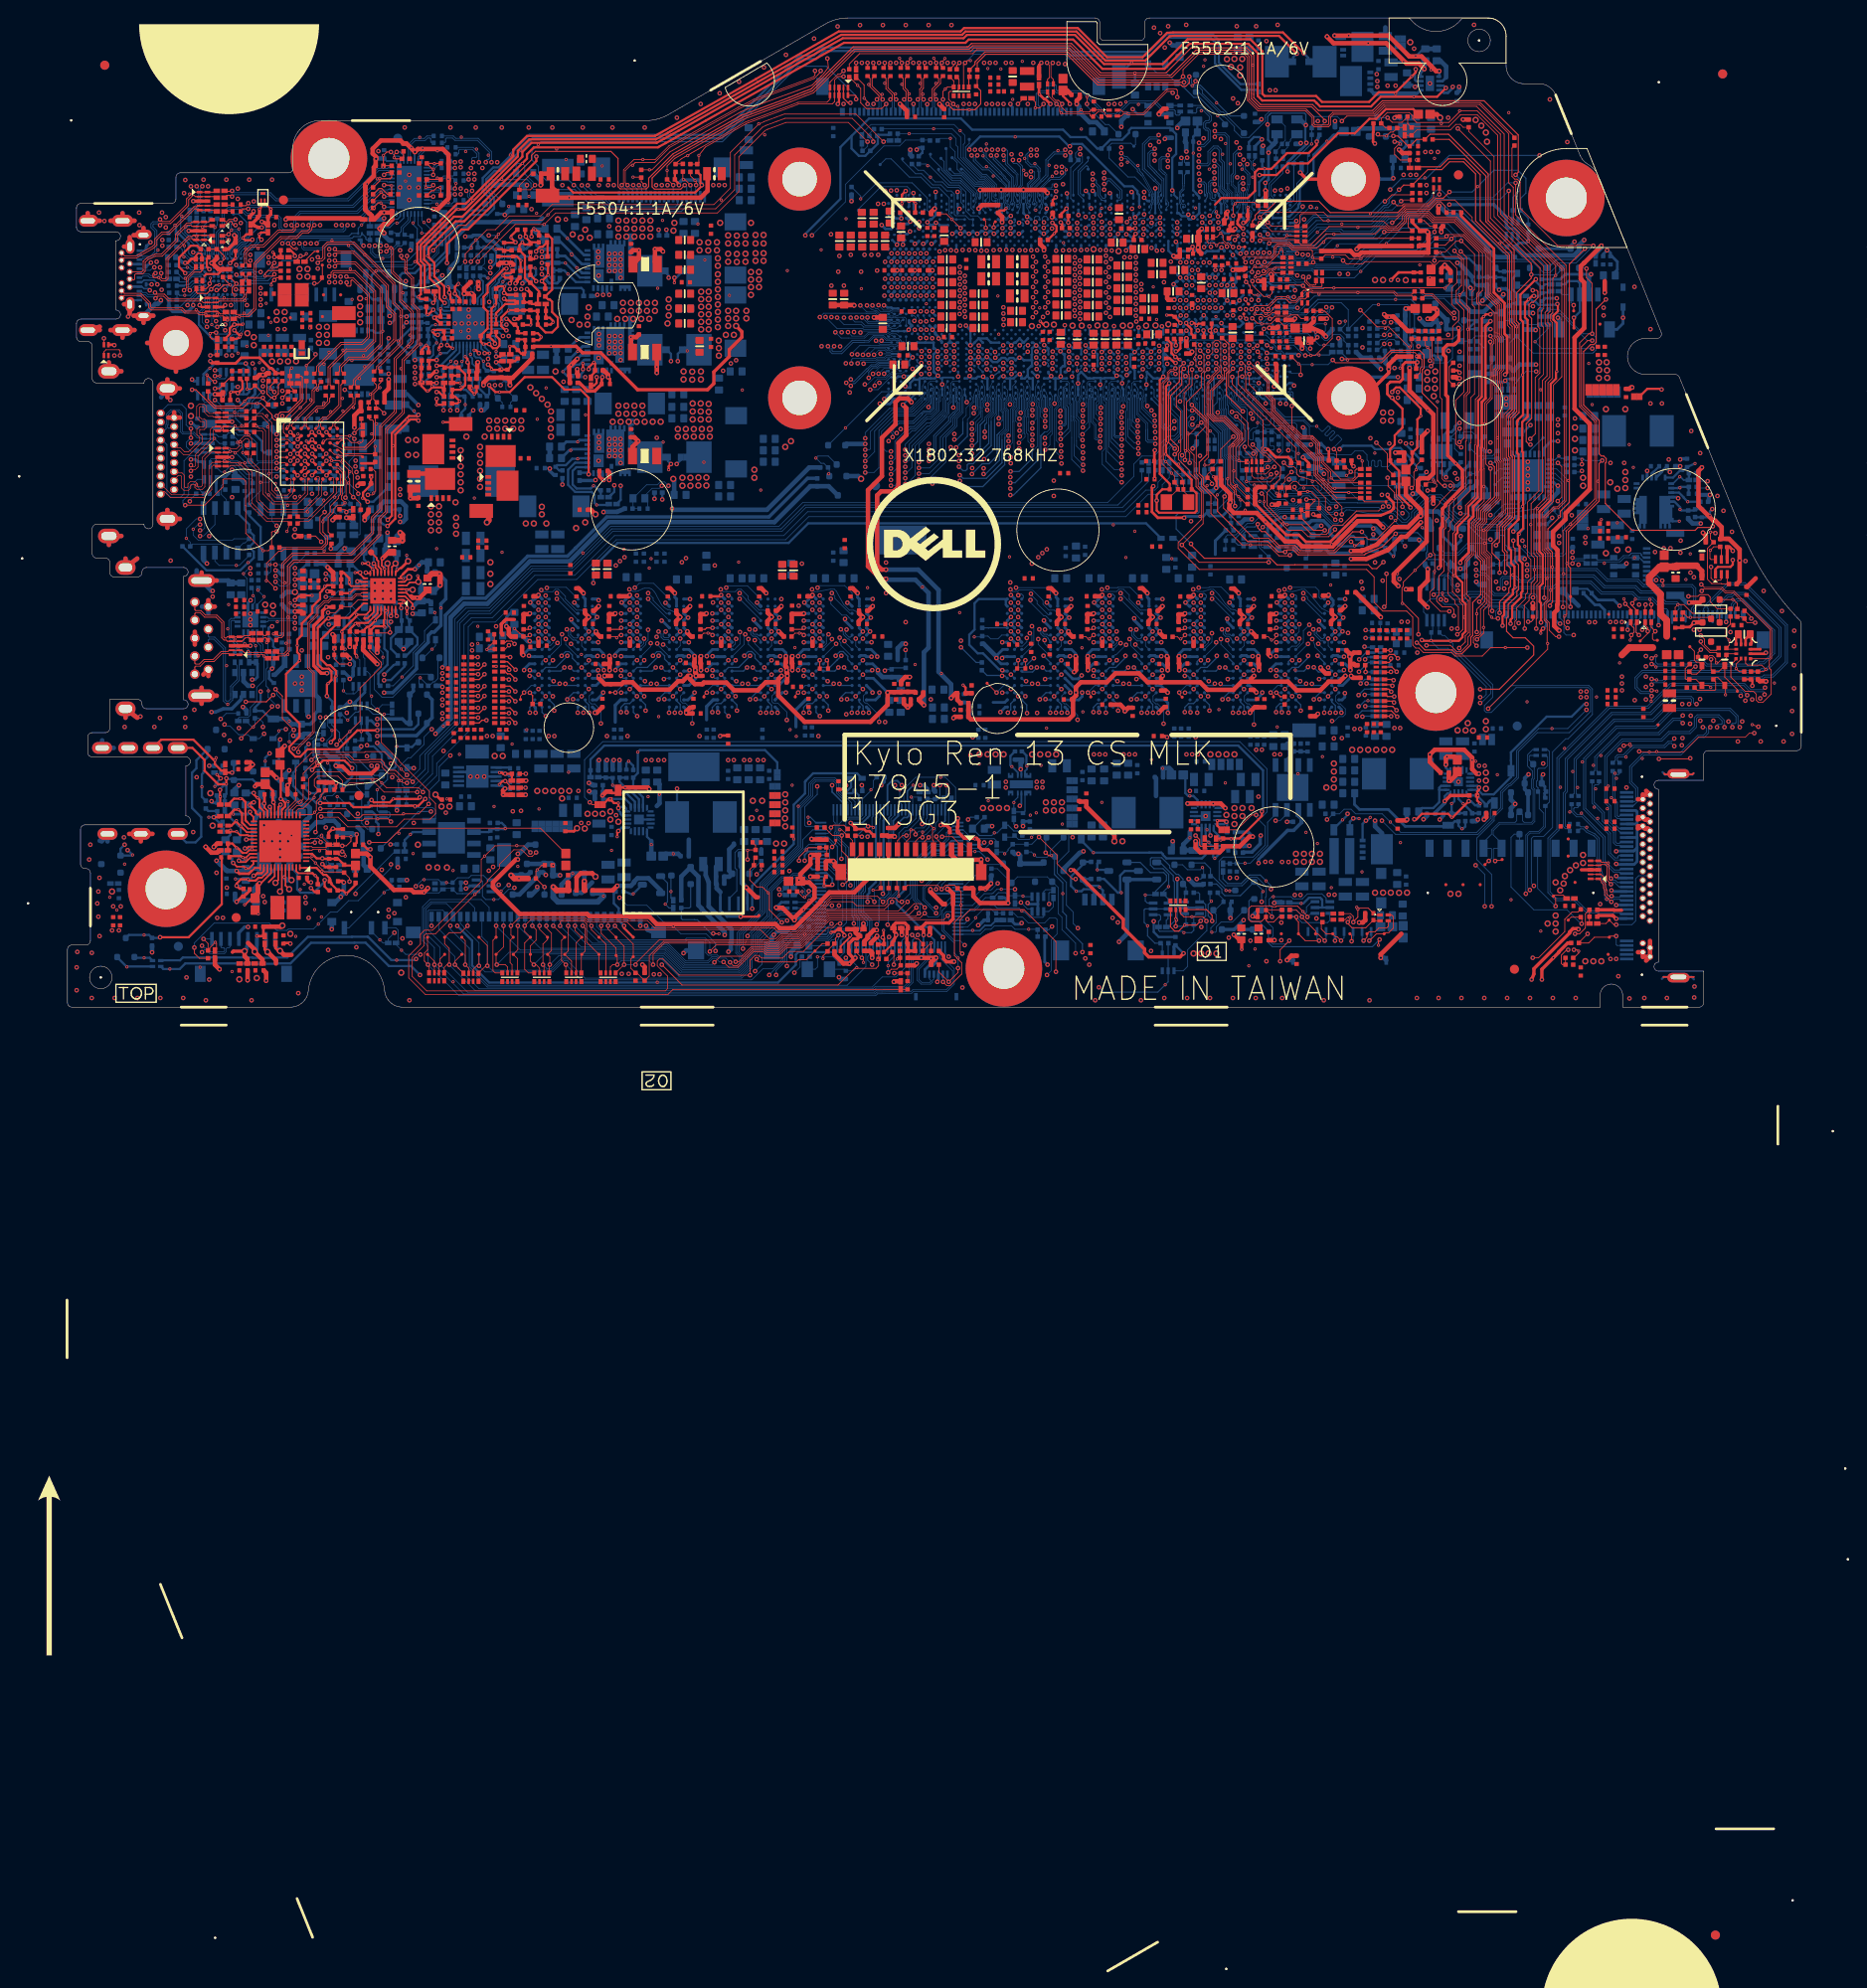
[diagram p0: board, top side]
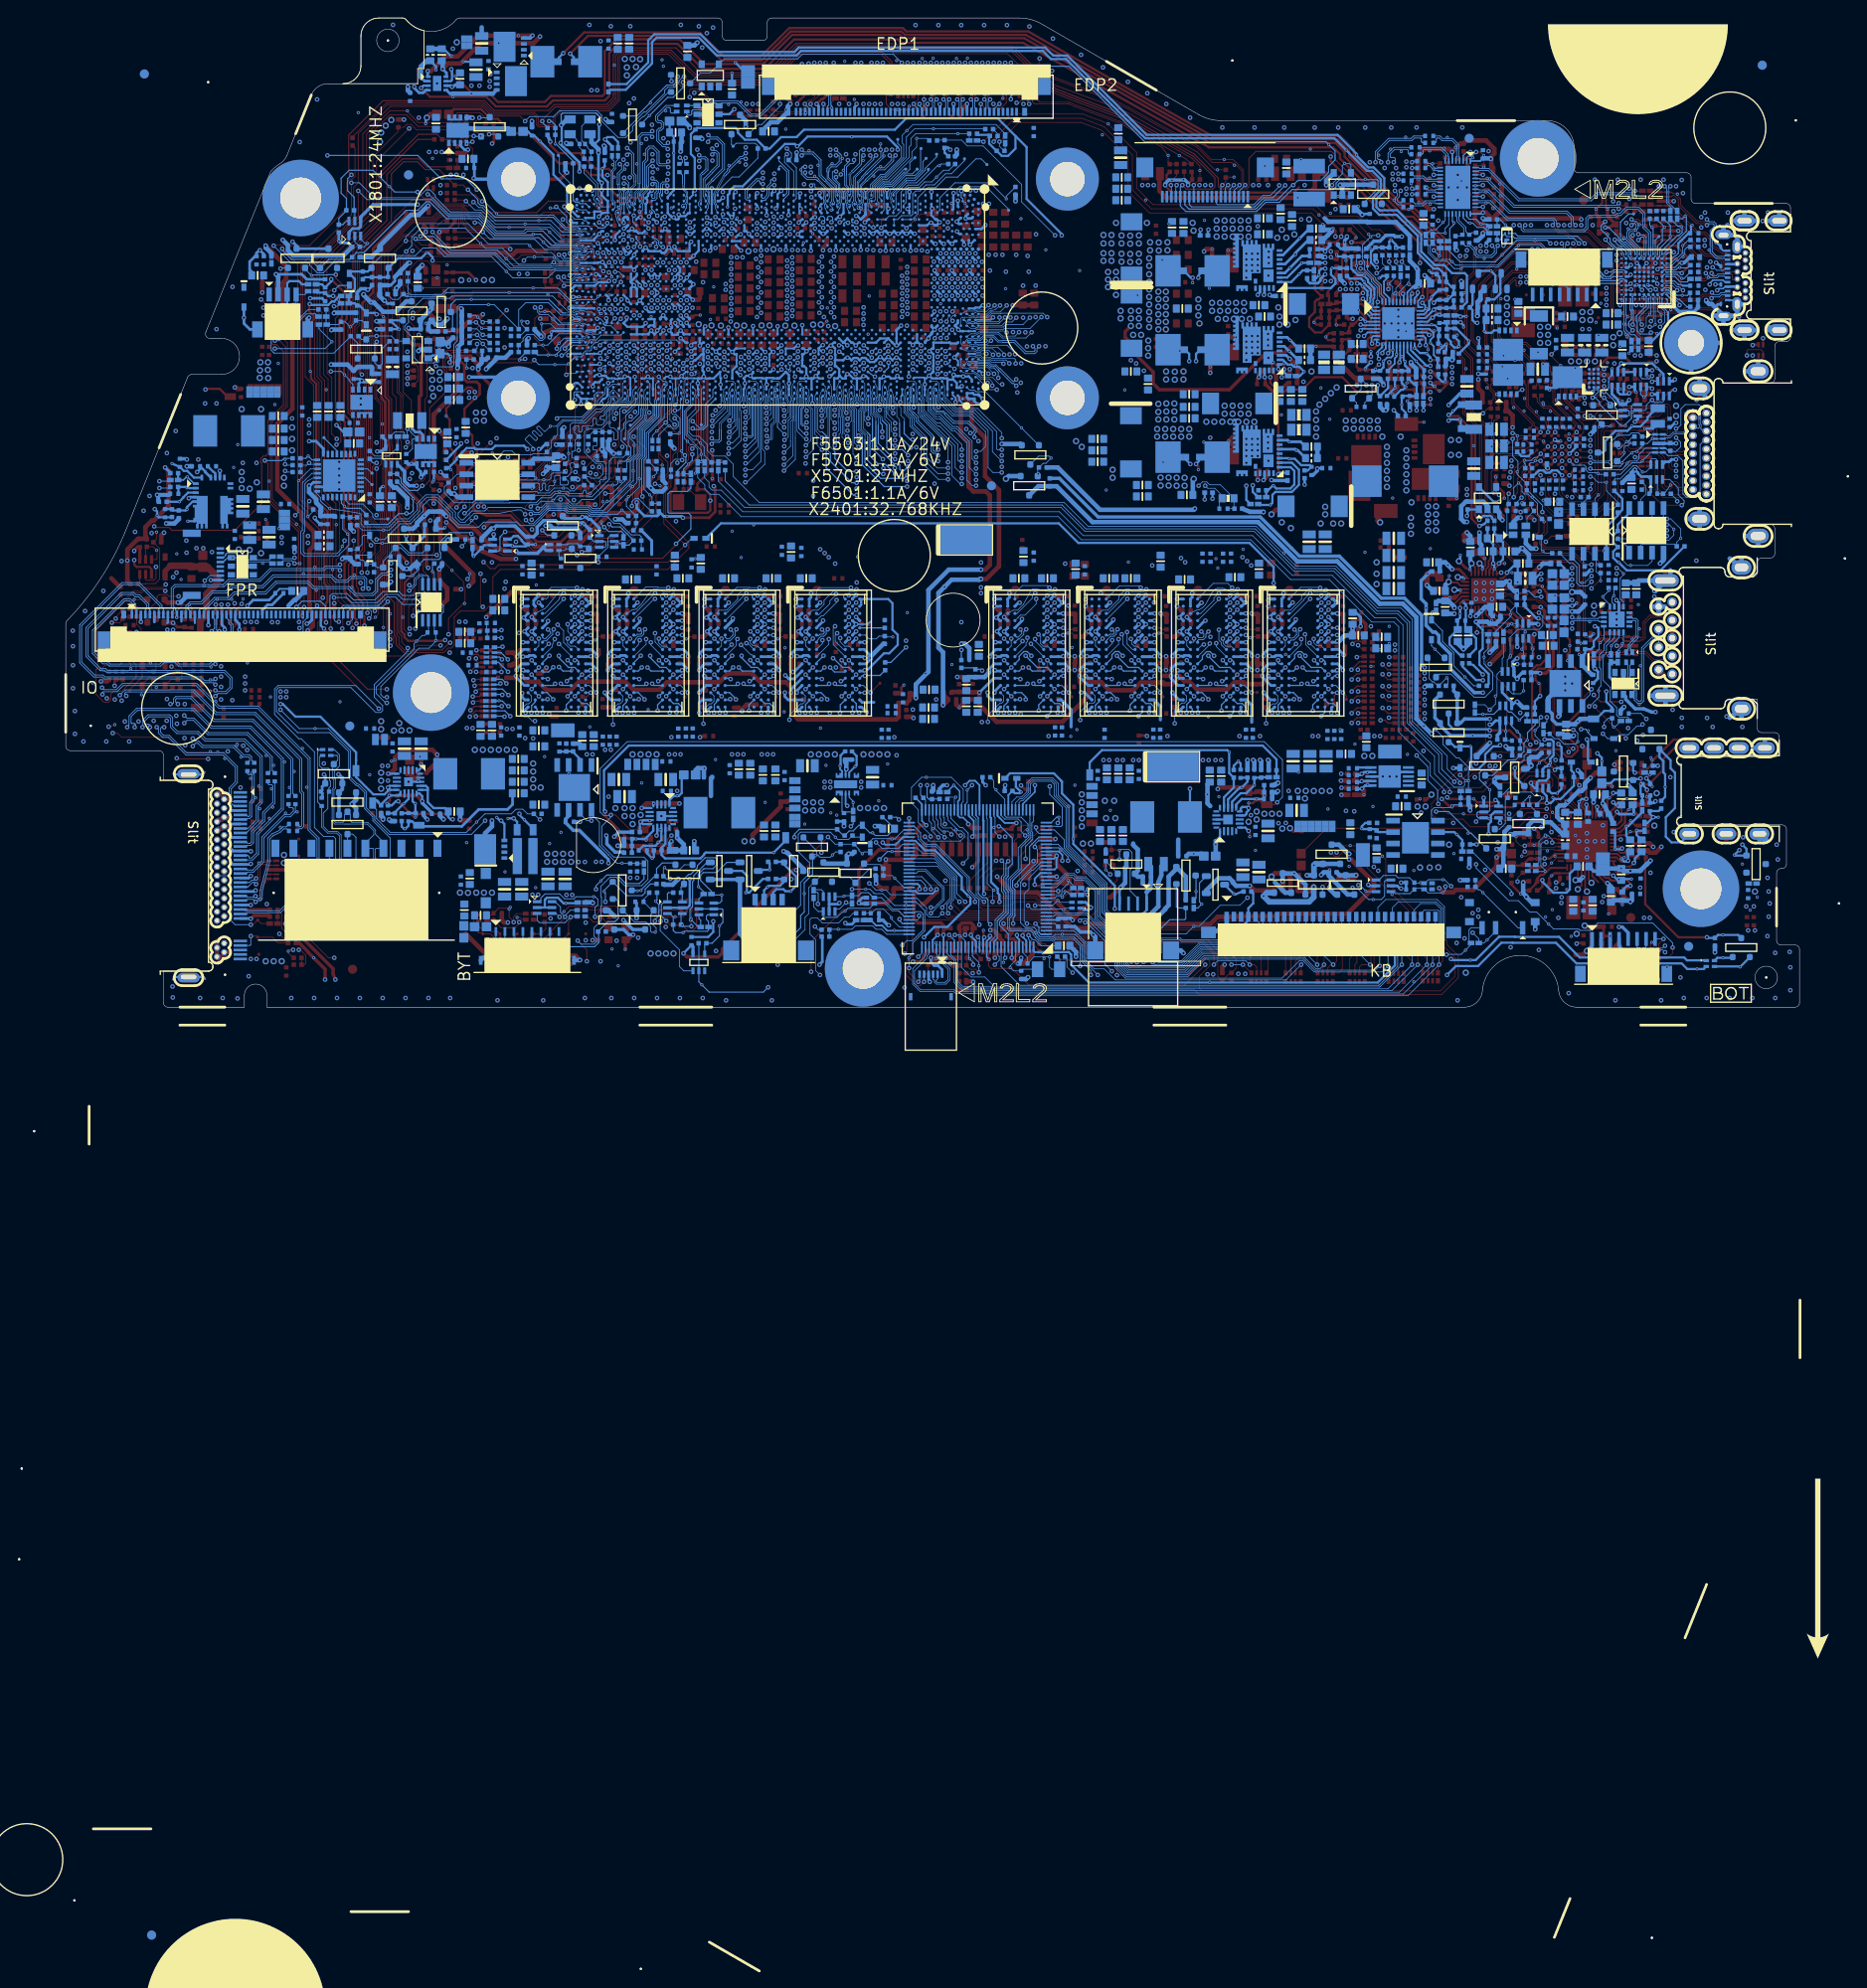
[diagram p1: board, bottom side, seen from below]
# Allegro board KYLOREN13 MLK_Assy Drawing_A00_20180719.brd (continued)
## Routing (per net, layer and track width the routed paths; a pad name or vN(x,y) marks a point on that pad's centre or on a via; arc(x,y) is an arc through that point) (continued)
M_B_DQ28: length 39.5
  L4SGND w0.089: v2(117.02,40.44) 117.05,40.44 117.24,40.63 117.24,43.38 117.57,43.71 117.57,43.71 118.56,44.7 118.56,45.21 118.56,45.21 119.07,45.72 119.07,52.83 115.46,56.43 115.46,60.68 115.7,60.92 115.7,66.81 115.14,67.37 114.62,67.37 113.2,68.78 112.24,68.78 111.89,69.14 111.89,69.68 112.02,69.81 112.02,70.22 111.79,70.45 111.08,70.45 110.84,70.69 110.84,71.76 v2(111.3,72.21)
  BOTTOM w0.089: v2(111.3,72.21) 111.63,71.88 CPU1.AR30 ; RAM5.H7 116.88,40.44 v2(117.02,40.44)
M_B_DQ29: length 40.1
  L4SGND w0.089: v2(116.57,41.74) 116.57,42.9 116.57,42.9 116.57,43.26 116.59,43.27 116.59,43.72 118.12,45.25 118.12,45.54 118.48,45.9 118.48,51.83 117.51,52.79 117.51,52.92 117.68,53.08 117.68,53.21 117.55,53.33 117.42,53.33 117.26,53.17 117.13,53.17 117.01,53.29 117.01,53.42 117.26,53.68 117.26,53.8 117.14,53.93 117.01,53.93 116.76,53.67 116.63,53.67 116.5,53.8 116.5,53.92 116.76,54.18 116.76,54.31 116.64,54.43 116.51,54.43 116.25,54.17 116.13,54.17 114.88,55.42 114.88,61.11 115.23,61.46 115.23,66.78 114.99,67.01 114.46,67.01 113.05,68.43 112.1,68.43 111.89,68.64 111.22,69.3 111.22,70.06 110.66,70.62 110.66,72.27 v2(111.27,72.87)
  BOTTOM w0.089: v2(116.57,41.74) 116.57,41.73 RAM5.F7 ; v2(111.27,72.87) 111.61,72.53 CPU1.AR29
M_B_DQ30: length 39.3
  L4SGND w0.089: v2(118.66,40.28) 118.66,40.76 121.03,43.12 121.03,43.44 121.29,43.71 121.44,43.71 122.1,44.36 122.1,45.53 121.51,46.12 121.51,53.01 119.37,55.14 119.37,55.37 119.63,55.63 119.63,55.75 119.5,55.88 119.38,55.88 119.13,55.63 119,55.63 118.88,55.76 118.88,55.88 119.12,56.13 119.12,56.26 118.08,57.3 118.08,60.88 117.9,61.06 117.9,66.83 117.9,66.98 117.5,67.38 116.79,67.38 115.41,68.76 115.36,68.76 114.59,68.76 114.33,69.02 114.33,69.67 113.14,70.85 v2(113.11,70.85)
  BOTTOM w0.089: v2(113.11,70.85) 113.39,70.58 CPU1.AV32 ; RAM5.H3 119.21,39.74 v2(118.66,40.28)
M_B_DQ31: length 40.1
  L4SGND w0.089: v2(113.09,71.47) 112.78,71.47 112.71,71.4 112.71,70.72 112.74,70.69 112.74,70.66 112.95,70.45 113.28,70.45 114.15,69.59 114.15,68.93 114.51,68.57 115.35,68.57 116.72,67.2 117.43,67.2 117.72,66.9 117.72,57.18 118.46,56.44 118.46,55.55 120.88,53.13 120.88,47.01 121.2,46.69 121.2,44.63 119.83,43.26 119.83,42.42 118.79,41.38 118.49,41.38 v2(118.01,40.89)
  BOTTOM w0.089: RAM5.J3 118.16,40.16 118.16,40.75 v2(118.01,40.89) ; v2(113.09,71.47) 113.11,71.44 113.34,71.44 CPU1.AV31
M_B_DQ32: length 33.9
  L6 w0.089: v2(125.08,46.42) 123.68,46.42 118.16,51.94 118.16,59.96 117.11,61.01 v2(117.11,61.11)
  BOTTOM w0.076: 115.92,62.08 115.72,62.28 115.72,67.55 115.64,67.8 115.64,68.02 115.64,68.02 115.64,68.03 115.68,68.14 115.68,68.33 115.59,68.57 115.59,68.58 115.51,68.79 CPU1.BA35
  BOTTOM w0.089: v2(117.11,61.11) 117.14,61.11 116.89,61.11 115.92,62.08 ; RAM8.C2 129.75,44.12 129.25,44.22 128.65,44.82 127.94,45.84 127.35,46.43 126.98,46.43 126.21,46.18 125.53,46.18 v2(125.08,46.42)
M_B_DQ33: length 34
  L6 w0.089: v2(125.94,43.34) 125.26,43.34 124.07,44.53 123.31,44.53 122.84,45 122.84,45.13 123.03,45.32 123.03,45.44 122.9,45.57 122.78,45.57 122.58,45.38 122.46,45.38 122.33,45.5 122.33,45.63 122.56,45.86 122.56,45.98 122.44,46.11 122.31,46.11 122.08,45.88 121.96,45.88 117.28,50.55 117.28,58.17 v2(117.14,58.32)
  BOTTOM w0.076: 114.98,61.49 114.98,61.75 115.23,62 115.23,66.88 115,67.11 115,67.75 115.04,67.83 115.04,67.84 115.1,67.94 115.1,68.89 CPU1.BA34
  BOTTOM w0.089: v2(117.14,58.32) 116.97,58.32 114.98,60.31 114.98,61.49 ; RAM8.D7 126.33,42.95 v2(125.94,43.34)
M_B_DQ34: length 33.5
  L6 w0.089: v2(117.15,66.15) 118.52,64.78 118.52,61.38 120.22,59.68 120.22,54.12 123.9,50.44 124.54,50.44 124.89,50.09 124.89,49.96 124.76,49.83 124.76,49.7 124.89,49.58 125.01,49.58 125.15,49.71 125.27,49.71 125.74,49.24 125.87,49.24 126.07,49.44 126.2,49.44 126.32,49.31 126.32,49.19 126.14,49.01 126.14,48.89 126.27,48.76 126.4,48.76 126.57,48.94 126.7,48.94 126.82,48.81 126.82,48.69 126.62,48.48 126.62,48.36 127.81,47.17 127.81,45.4 127.27,44.86 126.66,44.86 v2(125.93,44.14)
  BOTTOM w0.076: v2(117.15,66.15) 116.92,66.38 116.92,67.13 117.14,67.35 117.14,67.75 117.04,67.94 117.04,68.57 CPU1.BC35
  BOTTOM w0.089: RAM8.C7 v2(125.93,44.14)
M_B_DQ35: length 34.3
  L6 w0.089: v2(125.7,46.61) 125.36,46.94 124.77,46.94 124.68,47.03 124.68,47.42 124.59,47.5 124.41,47.5 124.32,47.42 124.32,47.03 124.24,46.94 123.69,46.94 118.45,52.18 118.45,60 117.51,60.94 117.51,61.37 v2(117.14,61.75)
  BOTTOM w0.076: CPU1.BC34 115.98,69.54 115.78,69.33 115.75,69.31 115.75,68.6 115.84,68.35 115.84,68.12 115.8,68 115.8,67.82 115.89,67.58 115.89,62.87 115.99,62.76
  BOTTOM w0.089: v2(117.14,61.75) 117.01,61.75 115.99,62.76 ; v2(125.7,46.61) 126.82,46.61 126.89,46.68 128.19,46.68 RAM8.A3
M_B_DQ36: length 32.2
  L6 w0.089: v2(117.11,60.42) 117.87,59.67 117.87,51.8 118.27,51.4 118.27,51.27 118.01,51.01 118.01,50.88 118.13,50.76 118.26,50.76 118.52,51.02 118.65,51.02 118.77,50.89 118.77,50.77 118.51,50.5 118.51,50.38 118.64,50.25 118.76,50.25 119.02,50.52 119.15,50.52 119.28,50.39 119.28,50.26 119.01,50 119.01,49.88 119.14,49.75 119.26,49.75 119.53,50.01 119.65,50.01 119.78,49.89 119.78,49.76 119.52,49.5 119.52,49.37 119.64,49.25 119.77,49.25 120.03,49.51 120.16,49.51 120.28,49.38 120.28,49.26 120.02,49 120.02,48.87 120.14,48.74 120.27,48.74 120.53,49.01 120.66,49.01 124.07,45.6 124.62,45.6 125.13,45.1 v2(125.13,44.94)
  BOTTOM w0.076: CPU1.BA37 115.56,67.44 115.56,61.73 115.66,61.62
  BOTTOM w0.089: v2(117.11,60.42) 116.86,60.42 115.66,61.62 ; RAM8.B8 v2(125.13,44.94)
M_B_DQ37: length 32.8
  L6 w0.089: v2(117.14,59.72) 117.58,59.28 117.58,50.74 119.88,48.44 120.72,48.44 120.93,48.23 120.93,48.11 120.67,47.85 120.67,47.72 120.8,47.6 120.92,47.6 121.18,47.85 121.3,47.85 121.43,47.73 121.43,47.6 121.17,47.35 121.17,47.22 121.3,47.1 121.43,47.1 121.68,47.35 121.81,47.35 121.93,47.23 121.93,47.1 121.68,46.84 121.68,46.72 121.8,46.59 121.93,46.59 122.18,46.85 122.31,46.85 123.77,45.38 124.4,45.38 124.7,45.09 124.7,44.57 v2(125.13,44.14)
  BOTTOM w0.076: CPU1.BA36 115.42,68.18 115.27,67.91 115.27,67.9 115.21,67.81 115.21,67.79 115.19,67.76 115.16,67.71 115.16,67.44 115.39,67.2 115.39,61.54
  BOTTOM w0.089: v2(117.14,59.72) 116.33,59.72 115.39,60.65 115.39,61.54 ; v2(125.13,44.14) RAM8.C8
M_B_DQ38: length 32
  L6 w0.089: v2(117.11,65.54) 118.28,64.37 118.28,61.37 119.93,59.72 119.93,54 123.56,50.36 123.56,49.54 124.07,49.04 125.53,49.04 127.6,46.97 127.6,45.79 v2(127.17,45.36)
  BOTTOM w0.076: CPU1.BC36 116.72,68.18 116.87,67.9 116.87,67.9 116.97,67.71 116.97,67.42 116.75,67.2 116.75,65.9 v2(117.11,65.54)
  BOTTOM w0.089: RAM8.D3 129.53,43.09 127.25,45.36 v2(127.17,45.36)
M_B_DQ39: length 31.5
  L6 w0.089: v2(117.13,64.93) 117.2,64.93 118.1,64.03 118.1,61.29 119.48,59.91 119.48,59.91 119.63,59.76 119.63,53.88 120.49,53.03 120.49,52.9 120.35,52.77 120.35,52.64 120.48,52.51 120.6,52.51 120.74,52.65 120.86,52.65 120.99,52.52 120.99,52.4 120.77,52.17 120.77,52.05 120.89,51.92 121.02,51.92 121.24,52.15 121.37,52.15 123.21,50.3 123.21,49.48 123.95,48.74 125.41,48.74 127.17,46.98 127.17,46.43 127.17,46.43 v2(127.17,46)
  BOTTOM w0.076: v2(117.13,64.93) 116.58,65.49 116.58,67.45 CPU1.BC37
  BOTTOM w0.089: v2(127.17,46) 127.89,45.28 127.89,45.27 129.42,43.74 RAM8.C3
M_B_DQ40: length 37
  L6 w0.089: v2(118.92,63.91) 120.19,62.64 120.19,61.46 121.88,59.77 121.88,59.22 122.97,58.13 122.97,54.44 124.1,53.32 125.62,53.32 129.33,49.61 129.33,45.36 129.54,45.15 129.54,44.74 127.64,42.83 v2(127.64,40.53)
  BOTTOM w0.076: CPU1.BE35 118.03,68.79 118.12,68.53 118.12,68.53 118.19,68.35 118.19,68.12 118.15,68.03 118.15,67.79 118.22,67.62 118.22,65.26
  BOTTOM w0.089: v2(127.64,40.53) 127.65,40.51 127.65,40.26 RAM8.J7 ; 118.22,65.26 118.22,64.61 v2(118.92,63.91)
M_B_DQ41: length 37.2
  L6 w0.089: v2(125.92,41.74) 126.35,42.17 126.35,43.15 126.36,43.17 126.36,43.54 128.31,45.49 128.31,48.34 128.1,48.55 127.98,48.55 127.69,48.27 127.57,48.27 127.44,48.39 127.44,48.52 127.72,48.8 127.72,48.93 126.42,50.23 126.42,50.41 126.75,50.74 126.75,50.89 126.43,51.21 125.29,52.35 123.65,52.35 121.68,54.32 121.68,56.95 122.09,57.36 122.09,57.71 121.77,58.03 121.09,58.03 121,58.12 121,59.51 119.55,60.96 119.55,61.51 v2(118.98,62.08)
  BOTTOM w0.076: 117.6,66.23 117.7,66.33 117.7,67.17 117.5,67.37 117.5,67.74 117.59,67.9 117.64,67.99 117.64,68.93 CPU1.BE34
  BOTTOM w0.089: RAM8.F7 125.93,41.74 v2(125.92,41.74) ; 117.6,66.23 117.6,62.95 118.48,62.08 v2(118.98,62.08)
M_B_DQ42: length 37.1
  L6 w0.089: v2(120.77,65.76) 121.2,65.76 121.87,65.09 121.87,64.68 122.57,63.97 122.57,61.29 123.52,60.34 123.7,60.34 125.09,58.95 125.09,56.92 131.46,50.55 131.46,48.55 132.77,47.23 132.77,41.75 132.23,41.2 130.99,41.2 v2(130.73,40.94)
  BOTTOM w0.076: CPU1.BG35 119.55,68.57 119.55,67.94 119.66,67.74 119.66,67.36 119.53,67.23 119.53,66.64
  BOTTOM w0.089: v2(120.77,65.76) 120.41,65.76 119.53,66.64 ; RAM8.H2 130.73,40.14 v2(130.73,40.94)
M_B_DQ43: length 37.8
  L6 w0.089: v2(128.16,40.89) 127.85,41.21 127.85,42.74 128.82,43.71 129,43.71 129.79,44.5 129.79,45.75 129.63,45.9 129.63,49.84 123.26,56.21 123.26,58.25 122.17,59.34 122.17,59.89 120.42,61.64 120.42,63.06 v2(118.93,64.56)
  BOTTOM w0.076: 118.4,65.77 118.4,67.61 118.32,67.82 118.32,68 118.36,68.12 118.36,68.35 118.29,68.56 118.29,69.32 118.29,69.33 118.5,69.54 CPU1.BG34
  BOTTOM w0.089: v2(128.16,40.89) 128.16,40.31 RAM8.J3 ; v2(118.93,64.56) 118.4,65.09 118.4,65.77
M_B_DQ44: length 35.5
  L6 w0.089: v2(118.95,63.3) 119.93,62.32 119.93,61.3 121.58,59.65 121.58,59.1 122.68,58.01 122.68,56.18 122.59,56.09 122.39,56.09 122.3,56 122.3,55.82 122.39,55.73 122.59,55.73 122.68,55.64 122.68,54.32 124.01,52.98 125.49,52.98 127.78,50.7 127.78,50.57 127.64,50.43 127.64,50.31 127.76,50.18 127.89,50.18 128.03,50.32 128.16,50.32 128.89,49.59 128.89,45.36 128.67,45.14 128.67,44.45 127.13,42.91 127.13,41.58 v2(127.16,41.55)
  BOTTOM w0.076: CPU1.BE37 118.05,67.47 118.05,65.35 118.01,65.31 118.01,65.26
  BOTTOM w0.089: 118.01,65.26 118.01,64.23 v2(118.95,63.3) ; v2(127.16,41.55) 127.16,40.57 RAM8.H7
M_B_DQ45: length 36.2
  L6 w0.089: v2(118.97,62.69) 119.75,61.91 119.75,61.16 121.29,59.63 121.29,58.98 122.38,57.89 122.38,57.23 121.98,56.83 121.98,54.61 123.89,52.69 125.37,52.69 127.22,50.84 127.22,49.89 128.6,48.51 128.6,45.37 126.74,43.51 v2(126.74,40.94)
  BOTTOM w0.076: CPU1.BE36 117.93,68.18 117.68,67.72 117.68,67.43 117.87,67.24 117.87,65.4 117.82,65.35 117.82,65.26
  BOTTOM w0.089: v2(126.74,40.94) 126.77,40.9 126.77,40.89 126.78,40.88 126.78,40.5 126.39,40.1 125.89,40.1 RAM8.H8 ; v2(118.97,62.69) 118.55,62.69 117.82,63.41 117.82,65.26
M_B_DQ46: length 36
  L6 w0.089: v2(129.94,40.94) 129.79,41.09 129.79,41.45 130.59,42.24 132.38,42.24 132.47,42.33 132.47,46.98 131.17,48.28 131.17,50.43 124.8,56.79 124.8,58.83 123.49,60.14 123.34,60.14 122.22,61.27 122.22,63.75 121.49,64.48 121.49,64.91 121.23,65.17 120.84,65.17 v2(120.82,65.15)
  BOTTOM w0.076: CPU1.BG36 119.23,68.18 119.39,67.9 119.39,67.9 119.49,67.71 119.49,67.42 119.35,67.29 119.35,66.52 119.83,66.04
  BOTTOM w0.089: RAM8.G2 130.33,40.55 v2(129.94,40.94) ; v2(120.82,65.15) 120.72,65.15 119.83,66.04
M_B_DQ47: length 35.5
  L6 w0.089: v2(120.82,64.54) 121.94,63.42 121.94,61.28 124.5,58.71 124.5,56.67 130.87,50.3 130.87,47.84 132.25,46.46 132.25,43.31 131.51,42.57 130.44,42.57 129.53,41.67 v2(128.87,40.77)
  BOTTOM w0.076: CPU1.BG37 119.18,67.53 119.18,66.19 119.59,65.77
  BOTTOM w0.089: v2(120.82,64.54) 119.59,65.77 ; v2(128.87,40.77) 129.05,40.22 RAM8.H3
M_B_DQ48: length 40.3
  L4SGND w0.089: v2(135.28,44.14) 134.98,44.44 133.94,44.44 132.66,45.72 132.66,45.84 132.82,46 132.82,46.13 132.69,46.25 132.56,46.25 132.41,46.1 132.28,46.1 132.16,46.22 132.16,46.35 132.31,46.51 132.31,46.63 132.19,46.76 132.06,46.76 131.9,46.6 131.78,46.6 131.65,46.73 131.65,46.85 131.81,47.01 131.81,47.13 131.68,47.26 131.56,47.26 131.4,47.1 131.28,47.1 131.15,47.23 131.15,47.35 131.31,47.51 131.31,47.64 131.18,47.76 131.06,47.76 130.9,47.61 130.77,47.61 130.65,47.73 130.65,47.86 130.8,48.01 130.8,48.14 130.68,48.27 130.55,48.27 130.4,48.11 130.27,48.11 125.62,52.76 125.62,54.22 119.58,60.27 119.58,65.2 118.84,65.94 118.84,67.1 117.72,68.22 116.97,68.22 115.6,69.59 115.6,70.22 v2(114.93,70.89)
  BOTTOM w0.089: CPU1.BA32 v2(114.93,70.89) ; RAM7.C8 v2(135.28,44.14)
M_B_DQ49: length 40.7
  L4SGND w0.089: v2(135.28,44.94) 133.38,46.84 132.52,46.84 129.57,49.79 129.44,49.79 129.31,49.65 129.18,49.65 129.06,49.78 129.06,49.9 129.19,50.04 129.19,50.16 129.07,50.29 128.94,50.29 128.81,50.16 128.68,50.16 128.55,50.28 128.55,50.41 128.69,50.54 128.69,50.67 128.56,50.79 128.44,50.79 128.3,50.66 128.18,50.66 128.05,50.78 128.05,50.91 128.19,51.05 128.19,51.17 128.06,51.3 127.94,51.3 127.8,51.16 127.67,51.16 127.55,51.29 127.55,51.41 127.68,51.55 127.68,51.67 127.56,51.8 127.43,51.8 127.3,51.66 127.17,51.66 127.05,51.79 127.05,51.92 127.18,52.05 127.18,52.18 127.06,52.3 126.93,52.3 126.79,52.17 126.67,52.17 126.54,52.29 126.54,52.42 126.68,52.55 126.68,52.68 126.55,52.81 126.43,52.81 126.29,52.67 126.17,52.67 126.04,52.8 126.04,52.92 126.18,53.06 126.18,53.18 125.91,53.44 125.91,54.49 119.8,60.6 119.8,65.37 119.12,66.06 119.12,67.07 117.77,68.42 117.02,68.42 115.82,69.61 115.82,69.76 115.82,70.61 v2(114.93,71.5)
  BOTTOM w0.089: CPU1.BA31 v2(114.93,71.5) ; RAM7.B8 v2(135.28,44.94)
M_B_DQ50: length 43
  L4SGND w0.089: v2(137.32,45.36) 137.61,45.36 137.75,45.51 137.75,46.18 137.63,46.31 137.63,47.18 135.72,49.09 135.29,49.09 133.68,50.7 133.1,50.7 127.73,56.06 127.61,56.06 127.49,55.95 127.37,55.95 127.24,56.08 127.24,56.2 127.36,56.32 127.36,56.44 127.23,56.57 127.11,56.57 126.99,56.45 126.87,56.45 126.74,56.58 126.74,56.7 126.85,56.82 126.85,56.94 126.73,57.07 126.6,57.07 126.49,56.96 126.36,56.96 126.24,57.08 126.24,57.21 126.35,57.32 126.35,57.45 126.23,57.57 126.1,57.57 125.98,57.46 125.86,57.46 125.73,57.58 125.73,57.71 125.85,57.83 125.85,57.95 125.72,58.08 125.6,58.08 125.48,57.96 125.36,57.96 125.23,58.09 125.23,58.21 125.35,58.33 125.35,58.45 125.22,58.58 125.09,58.58 124.98,58.46 124.85,58.46 124.73,58.59 124.73,58.72 124.84,58.83 124.84,58.96 124.7,59.1 124.57,59.1 124.46,58.98 124.33,58.98 122.12,61.19 122.12,66.44 120.2,68.37 119.58,68.37 118.38,69.57 118.38,70.43 118.1,70.71 118.1,71.12 v2(117.65,71.58)
  BOTTOM w0.089: v2(117.65,71.58) CPU1.BD31 ; RAM7.D3 137.32,45.3 v2(137.32,45.36)
M_B_DQ51: length 43
  L4SGND w0.089: v2(117.67,70.89) 118.2,70.36 118.2,69.49 119.53,68.17 120.14,68.17 121.92,66.39 121.92,60.98 127.45,55.45 127.58,55.45 127.69,55.57 127.82,55.57 127.94,55.44 127.94,55.32 127.83,55.2 127.83,55.08 127.95,54.95 128.08,54.95 128.19,55.07 128.32,55.07 128.45,54.94 128.45,54.81 128.33,54.7 128.33,54.57 128.46,54.45 128.58,54.45 128.7,54.56 128.82,54.56 128.95,54.44 128.95,54.31 128.83,54.2 128.83,54.07 128.96,53.95 129.08,53.95 129.2,54.06 129.33,54.06 129.45,53.93 129.45,53.81 129.34,53.69 129.34,53.57 129.46,53.44 129.59,53.44 129.7,53.56 129.83,53.56 129.95,53.43 129.95,53.31 129.84,53.19 129.84,53.07 129.96,52.94 130.09,52.94 130.21,53.05 130.33,53.05 130.46,52.93 130.46,52.8 130.34,52.69 130.34,52.56 130.47,52.44 130.59,52.44 130.71,52.55 130.83,52.55 130.96,52.43 130.96,52.3 130.84,52.18 130.84,52.06 130.97,51.93 131.1,51.93 131.21,52.05 131.34,52.05 131.46,51.92 131.46,51.8 131.35,51.68 131.35,51.56 131.47,51.43 131.6,51.43 131.71,51.55 131.84,51.55 131.97,51.42 131.97,51.29 131.85,51.18 131.85,51.05 131.98,50.93 132.1,50.93 132.22,51.04 132.34,51.04 132.47,50.92 132.47,50.79 132.35,50.68 132.35,50.55 132.56,50.34 133.63,50.34 135.17,48.8 135.57,48.8 137.32,47.05 v2(137.32,46)
  BOTTOM w0.089: v2(117.67,70.89) CPU1.BD32 ; v2(137.32,46) 137.79,45.53 137.79,45.33 139.39,43.74 RAM7.C3
M_B_DQ52: length 42.6
  L4SGND w0.089: v2(135.23,46.42) 134.54,47.12 132.65,47.12 126.21,53.57 126.21,54.61 120.14,60.68 120.14,65.43 119.3,66.27 119.3,67.14 117.84,68.6 117.09,68.6 116,69.69 116,70.74 115.33,71.41 115.33,71.73 v2(114.93,72.14)
  BOTTOM w0.089: v2(135.23,46.42) 135.64,46.18 136.17,46.18 137.13,46.43 137.5,46.43 138.14,45.78 139.17,44.52 139.41,44.28 RAM7.C2 ; CPU1.BA30 v2(114.93,72.14)
M_B_DQ53: length 43
  L4SGND w0.089: v2(135.85,46.61) 134.88,47.57 134.01,47.57 133.92,47.66 133.92,47.99 133.83,48.08 133.65,48.08 133.56,47.99 133.56,47.66 133.48,47.57 133.3,47.57 133.21,47.66 133.21,48.07 133.12,48.16 132.94,48.16 132.85,48.07 132.85,47.71 132.76,47.63 132.56,47.63 126.5,53.69 126.5,54.74 120.73,60.51 120.73,61.31 120.57,61.46 120.48,61.46 120.4,61.55 120.4,65.42 119.51,66.31 119.51,67.2 117.86,68.85 117.09,68.85 116.18,69.76 116.18,71.83 v2(115.84,72.16)
  BOTTOM w0.089: CPU1.BA29 115.41,72.23 115.54,72.13 v2(115.84,72.16) ; v2(135.85,46.61) 135.88,46.64 138.7,46.64 139.06,46.27 139.06,45.53 139.26,45.34 RAM7.A3
M_B_DQ54: length 43.7
  L4SGND w0.089: v2(116.76,72.19) 117.21,72.64 117.79,72.64 118.51,71.92 118.51,70.81 118.74,70.58 118.74,69.74 119.73,68.75 120.32,68.75 122.58,66.49 122.58,61.3 122.86,61.02 123.18,61.02 124.27,59.92 124.71,59.92 125.43,59.2 127.24,57.39 127.29,57.39 129.53,55.14 129.94,55.14 130.14,55.35 130.64,55.35 131.17,54.82 131.17,53.51 131.77,52.91 132.72,52.91 134.49,51.14 134.49,50.72 135.53,49.68 135.96,49.68 138.3,47.33 138.3,45.44 137.14,44.27 136.92,44.27 136.52,43.87 136.52,43.78 v2(136.09,43.34)
  BOTTOM w0.089: CPU1.BD29 v2(116.76,72.19) ; v2(136.09,43.34) 136.48,42.95 RAM7.D7
M_B_DQ55: length 43.4
  L4SGND w0.089: v2(136.08,44.14) 136.88,44.93 137.49,44.93 137.97,45.41 137.97,47.25 135.84,49.38 135.41,49.38 133.53,51.27 133.4,51.27 133.24,51.1 133.11,51.1 132.89,51.33 132.89,51.45 133.22,51.79 133.22,51.91 133.1,52.04 132.97,52.04 132.66,51.73 132.48,51.73 132.36,51.85 132.36,51.98 132.62,52.24 132.62,52.36 132.49,52.49 132.37,52.49 132.11,52.23 131.98,52.23 130.63,53.59 130.63,53.71 130.8,53.88 130.8,54.01 130.67,54.13 130.54,54.13 130.37,53.96 130.25,53.96 130.12,54.09 130.12,54.24 130.27,54.39 130.27,54.51 130.14,54.64 130.02,54.64 129.86,54.48 129.73,54.48 125.14,59.08 124.59,59.63 124.13,59.63 123.04,60.72 122.91,60.72 122.35,61.28 122.35,66.46 120.27,68.55 119.68,68.55 118.56,69.67 118.56,70.51 118.33,70.73 118.33,71.53 v2(117.62,72.24)
  BOTTOM w0.089: v2(117.62,72.24) CPU1.BD30 ; RAM7.C7 v2(136.08,44.14)
M_B_DQ56: length 44.2
  L4SGND w0.089: v2(137.99,42.49) 137.99,43.41 139.65,45.07 139.65,46.34 139.74,46.43 139.92,46.43 140,46.52 140,46.7 139.92,46.79 139.74,46.79 139.65,46.88 139.65,47.06 139.74,47.14 139.92,47.14 140,47.23 140,47.41 139.92,47.5 139.74,47.5 139.65,47.59 139.65,49.05 135.41,53.29 134.73,53.29 124.48,63.53 124.48,67.01 123.76,67.73 122.65,67.73 120.43,69.95 120.43,70.63 v2(119.47,71.58)
  BOTTOM w0.089: v2(137.99,42.49) 137.33,41.82 137.33,40.53 136.53,39.74 RAM7.H7 ; v2(119.47,71.58) 119.13,71.23 CPU1.BG31
M_B_DQ57: length 43.9
  L4SGND w0.089: v2(119.49,70.88) 119.79,70.88 120.25,70.42 120.25,69.88 123.03,67.1 123.24,67.1 124.18,66.16 124.18,63.49 126.29,61.38 126.29,61.29 126.86,60.72 126.86,60.59 126.75,60.49 126.75,60.36 126.88,60.24 127,60.24 127.11,60.34 127.24,60.34 127.36,60.22 127.36,60.09 127.24,59.97 127.24,59.85 127.37,59.72 127.49,59.72 127.61,59.84 127.74,59.84 134.64,52.93 135.35,52.93 139.36,48.93 139.36,45.38 137.52,43.55 137.52,40.68 v2(137.84,40.36)
  BOTTOM w0.089: RAM7.J7 136.48,39 v2(137.84,40.36) ; CPU1.BG32 119.19,70.58 v2(119.49,70.88)
M_B_DQ58: length 44.1
  L4SGND w0.089: v2(138.31,40.89) 139.29,41.57 139.71,41.99 140.15,43.26 141.26,44.36 141.26,49.11 130.69,59.68 130.02,59.68 126.44,63.26 126.44,66.91 124.45,68.9 122.27,68.9 121.28,69.89 v2(121.28,70.87)
  BOTTOM w0.089: CPU1.BK32 v2(121.28,70.87) ; RAM7.J3 138.63,39.99 138.56,40.3 v2(138.31,40.89)
M_B_DQ59: length 44.6
  L4SGND w0.089: v2(121.3,71.55) 121.61,71.24 121.61,71.1 122.16,70.55 122.16,70.17 123.17,69.16 124.51,69.16 126.62,67.05 126.62,63.5 130.11,60.01 130.77,60.01 141.55,49.23 141.55,46.58 142.4,45.73 142.4,43.31 141.65,42.56 140.8,42.56 138.98,40.75 v2(138.98,40.37)
  BOTTOM w0.089: v2(138.98,40.37) 139.61,39.74 RAM7.H3 ; v2(121.3,71.55) 120.98,71.23 CPU1.BK31
M_B_DQ60: length 44.9
  L4SGND w0.089: v2(136.88,42.55) 136.88,43.55 138.77,45.45 138.77,47.71 137.79,48.69 137.79,48.82 137.86,48.9 137.86,49.02 137.74,49.15 137.61,49.15 137.53,49.07 137.41,49.07 137.2,49.28 137.2,49.4 137.44,49.65 137.44,49.77 137.32,49.9 137.19,49.9 136.95,49.66 136.82,49.66 136.7,49.78 136.7,49.91 136.94,50.15 136.94,50.28 136.82,50.4 136.69,50.4 136.55,50.26 136.42,50.26 136.3,50.39 136.3,50.51 136.44,50.65 136.44,50.78 136.31,50.9 136.19,50.9 136.08,50.8 135.95,50.8 128,58.75 127.15,58.75 123.57,62.33 123.57,66.13 122.99,66.72 122.91,66.72 120.06,69.57 119.26,69.57 118.92,69.92 118.92,70.65 118.71,70.86 118.71,72.06 v2(119.47,72.82)
  BOTTOM w0.089: RAM7.F7 136.86,41.72 136.86,42.51 136.88,42.53 v2(136.88,42.55) ; v2(119.47,72.82) 119.18,72.53 CPU1.BG29
M_B_DQ61: length 44.4
  L4SGND w0.089: v2(119.5,72.21) 118.97,71.69 118.97,70.99 119.09,70.87 119.09,70.71 119.32,70.48 119.53,70.48 119.96,70.05 119.96,69.92 122.98,66.9 123.14,66.9 123.87,66.17 123.87,62.59 127.39,59.07 128.1,59.07 134.87,52.3 135.57,52.3 139.06,48.81 139.06,45.4 137.3,43.64 137.3,41.82 136.87,41.39 v2(136.87,40.94)
  BOTTOM w0.089: v2(136.87,40.94) 136.9,40.92 136.9,40.41 136.59,40.1 136.04,40.1 RAM7.H8 ; CPU1.BG30 119.17,71.88 v2(119.5,72.21)
M_B_DQ62: length 45.4
  L4SGND w0.089: v2(140.09,40.94) 140.44,41.29 140.44,41.9 140.71,42.17 142.53,42.17 142.66,42.3 142.66,45.9 141.84,46.72 141.84,49.35 130.83,60.37 130.17,60.37 126.87,63.67 126.87,67.15 124.61,69.41 123.17,69.41 122.34,70.24 122.34,70.62 121.79,71.17 121.79,71.72 v2(121.3,72.21)
  BOTTOM w0.089: v2(140.09,40.94) 140.09,40.13 RAM7.H2 ; v2(121.3,72.21) 120.97,71.88 CPU1.BK30
M_B_DQ63: length 45.9
  L4SGND w0.089: v2(140.88,40.94) 141.09,40.74 141.42,40.74 141.83,41.15 142.16,41.15 142.47,40.84 142.81,40.84 142.97,41 142.97,46.03 142.18,46.81 142.18,49.43 130.89,60.72 130.25,60.72 127.13,63.85 127.13,67.23 124.71,69.64 123.19,69.64 122.63,70.2 122.63,71.78 121.53,72.87 v2(121.33,72.87)
  BOTTOM w0.089: RAM7.G2 v2(140.88,40.94) ; v2(121.33,72.87) 121.18,72.87 CPU1.BK29
M_B_DQS_DN0: length 30.7
  L6 w0.089: v2(105.64,45.76) 105.94,45.47 106.07,45.47 106.28,45.67 106.28,47.62 109.8,51.15 109.8,54.06 110.02,54.27 110.36,54.27 110.46,54.37 110.46,54.69 110.34,54.81 110.07,54.81 109.85,55.03 109.85,55.49 110.06,55.7 110.45,55.7 110.56,55.81 110.56,59.68 111.01,60.12 111.01,62.88 111.65,63.52 111.65,64.12 111.19,64.57 110.55,64.57 v2(110.32,64.34)
  BOTTOM w0.076: v2(110.32,64.34) 110.56,64.57 110.8,64.57 110.99,64.77 110.99,66.49 110.81,66.66 110.81,67.71 110.77,67.82 110.77,68 110.81,68.12 110.81,68.35 110.77,68.47 110.77,68.65 110.81,68.77 110.91,68.81 110.99,68.78 111.03,68.74 CPU1.AP35
  BOTTOM w0.102: v2(105.64,45.76) 105.79,45.91 106,45.91 106.2,45.71 106.2,45.51 RAM6.A7
M_B_DQS_DN1: length 34.6
  L6 w0.089: v2(114.75,63.46) 115.16,63.05 115.16,62.69 115.57,62.27 115.57,49.5 115.18,49.11 114.8,49.11 114.6,48.91 114.6,48.53 114.3,48.23 113.93,48.23 113.67,47.98 113.67,47.6 113.32,47.26 112.76,47.26 112.45,46.95 112.45,46.39 111.99,45.92 111.46,45.92 110.9,45.37 110.9,44.49 109.84,43.43 109.84,43.04 109.46,42.66 109.08,42.66 108.62,42.2 v2(108.62,41.95)
  BOTTOM w0.076: CPU1.AV34 113.55,69.04 113.63,68.96 113.81,68.96 113.95,68.83 113.95,68.79 113.99,68.66 113.99,68.43 113.98,68.41 113.95,68.33 113.95,68.14 113.98,68.06 113.99,68.04 113.99,67.78 113.98,67.76 113.97,67.75 113.92,67.62 113.92,65.09 114.3,64.71 114.3,63.24 114.35,63.19 114.48,63.19 v2(114.75,63.46)
  BOTTOM w0.102: RAM6.F3 109.15,41.26 109.01,41.26 108.84,41.43 108.51,41.43 108.37,41.57 108.37,41.71 v2(108.62,41.95)
M_B_DQS_DN2: length 36.7
  L4SGND w0.089: v2(115.78,45.74) 115.78,45.52 115.99,45.32 116.28,45.32 116.37,45.41 116.37,46.67 116.1,46.94 116.1,47.22 116.35,47.47 116.35,47.6 116.12,47.82 116,47.82 115.75,47.57 115.46,47.57 115.13,47.91 115.13,48.19 115.38,48.44 115.38,48.57 115.15,48.79 115.03,48.79 114.78,48.54 114.49,48.54 114.16,48.88 114.16,49.16 114.41,49.41 114.41,49.54 114.18,49.76 114.06,49.76 113.81,49.51 113.52,49.51 113.15,49.89 113.15,50.17 113.4,50.42 113.4,50.54 113.17,50.77 113.05,50.77 112.8,50.52 112.52,50.52 112.15,50.89 112.15,66.24 109.76,68.63 109.17,68.63 108.41,69.39 108.41,70.73 108.74,71.05 108.74,71.44 108.71,71.46 108.65,71.53 v2(108.53,71.53)
  BOTTOM w0.102: CPU1.AL31 108.99,71.47 108.82,71.64 108.64,71.64 v2(108.53,71.53) ; v2(115.78,45.74) 115.94,45.89 116.15,45.89 116.36,45.69 116.36,45.52 RAM5.A7
M_B_DQS_DN3: length 39.2
  L4SGND w0.089: v2(118.77,41.95) 118.48,42.24 118.48,42.47 118.57,42.56 118.98,42.56 119.35,42.93 119.35,43.49 120.83,44.97 120.83,46.37 120.38,46.82 120.38,52.92 117.68,55.63 117.68,55.75 117.87,55.95 117.87,56.23 117.53,56.57 117.25,56.57 117.06,56.37 116.93,56.37 116.64,56.67 116.64,66.79 115.22,68.21 114.58,68.21 113.81,68.97 113.81,69.31 112.57,70.55 112.57,70.62 111.98,71.2 111.98,71.33 v2(112.16,71.5)
  BOTTOM w0.102: v2(118.77,41.95) 118.51,41.7 118.51,41.35 118.95,40.92 119.19,40.92 119.38,41.1 RAM5.F3 ; v2(112.16,71.5) 112.16,70.98 112.3,70.84 112.47,70.84 112.64,71.01 CPU1.AU31
M_B_DQS_DN4: length 32.9
  L6 w0.089: v2(117.14,63.08) 117.39,63.33 117.59,63.33 117.7,63.22 117.7,61.03 118.95,59.78 118.95,53.59 119.11,53.44 119.11,52.3 120.77,50.64 121,50.64 121.11,50.64 121.42,50.95 121.53,50.95 121.77,50.71 121.77,50.58 121.47,50.28 121.47,49.98 123.43,48.02 124.99,48.02 126.54,46.47 126.54,45.57 126.45,45.48 126.19,45.48 v2(125.93,45.74)
  BOTTOM w0.076: CPU1.BB35 116.07,68.72 116.13,68.79 116.19,68.81 116.29,68.77 116.34,68.62 116.34,68.5 116.28,68.32 116.28,68.15 116.33,68 116.33,67.82 116.25,67.59 116.25,63.47 116.42,63.3 116.92,63.3 v2(117.14,63.08)
  BOTTOM w0.102: v2(125.93,45.74) 126.15,45.95 126.33,45.95 126.54,45.75 126.54,45.55 RAM8.A7
M_B_DQS_DN5: length 36.6
  L6 w0.089: v2(128.92,41.95) 128.92,42.31 130.52,43.91 130.52,45.26 130.73,45.47 131.23,45.47 131.47,45.71 131.47,46.3 131.14,46.63 130.46,46.63 130.37,46.72 130.37,50.1 123.98,56.49 123.98,58.51 122.86,59.63 122.86,59.7 122.86,59.7 122.86,59.85 121.56,61.15 121.56,62.52 v2(120.87,63.21)
  BOTTOM w0.076: CPU1.BF34 118.97,68.62 118.97,68.14 119.01,68.03 119.01,67.81 119.01,67.79 118.98,67.65 118.97,67.63 118.97,65.93 120.01,64.89 120.01,64.13 120.04,64.09 120.04,64.08
  BOTTOM w0.102: v2(120.87,63.21) 120.66,62.99 120.12,62.99 120.04,63.07 120.04,64.08 ; RAM8.F3 129.45,41.26 129.31,41.26 129.14,41.43 128.76,41.43 128.64,41.55 128.64,41.73 128.87,41.95 v2(128.92,41.95)
M_B_DQS_DN6: length 42.1
  L4SGND w0.089: v2(136.08,45.74) 136.08,45.52 136.28,45.33 136.45,45.33 136.69,45.57 136.69,46.67 136.69,46.71 135.31,48.09 134.68,48.09 134.42,48.35 134.42,48.58 134.28,48.72 132.16,48.72 130.96,49.93 130.96,50.21 131.22,50.47 131.22,50.6 131,50.82 130.87,50.82 130.61,50.56 130.33,50.56 129.99,50.9 129.99,51.18 130.22,51.41 130.22,51.54 129.99,51.76 129.87,51.76 129.64,51.53 129.35,51.53 129.02,51.87 129.02,52.15 129.22,52.36 129.22,52.48 129,52.71 128.87,52.71 128.67,52.5 128.38,52.5 128.05,52.84 128.05,53.12 128.27,53.34 128.27,53.46 128.04,53.69 127.92,53.69 127.7,53.47 127.41,53.47 127.03,53.85 127.03,54.19 127.27,54.43 127.27,54.67 121.3,60.63 121.3,66.09 119.84,67.55 119.54,67.55 117.06,70.03 117.06,70.87 116.95,70.98 116.82,70.98 v2(116.71,70.87)
  BOTTOM w0.102: CPU1.BC31 116.22,71.15 116.23,71.01 116.41,70.85 v2(116.71,70.87) ; v2(136.08,45.74) 136.16,45.81 136.45,45.81 136.55,45.71 136.55,45.41 RAM7.A7
M_B_DQS_DN7: length 44.3
  L4SGND w0.089: v2(120.39,71.53) 120.39,71.23 120.8,70.82 120.8,70.11 122.51,68.39 124.33,68.39 125.58,67.14 125.58,63.4 134.98,54 135.67,54 140.76,48.91 140.76,44.54 139.9,43.68 139.16,43.68 138.62,43.14 138.62,42.48 138.71,42.39 138.97,42.39 139.07,42.29 v2(139.07,41.95)
  BOTTOM w0.102: CPU1.BH31 119.93,71.1 120.07,70.96 120.25,70.96 120.39,71.1 v2(120.39,71.53) ; v2(139.07,41.95) 138.77,41.66 138.77,41.51 139.25,41.03 139.26,41.03 139.37,40.92 139.49,40.92 139.68,41.11 RAM7.F3
M_B_DQS_DP0: length 30.7
  L6 w0.089: v2(110.32,64.98) 110.55,64.76 111.27,64.76 111.84,64.19 111.84,63.44 111.2,62.8 111.2,60.04 110.75,59.6 110.75,55.73 110.53,55.51 110.13,55.51 110.04,55.41 110.04,55.11 110.15,55 110.42,55 110.65,54.77 110.65,54.29 110.44,54.08 110.1,54.08 109.99,53.98 109.99,51.07 106.47,47.54 106.47,45.59 106.15,45.28 105.98,45.28 v2(105.63,44.93)
  BOTTOM w0.076: v2(110.32,64.98) 110.56,64.74 110.73,64.74 110.82,64.83 110.82,66.42 110.64,66.59 110.64,67.68 110.6,67.79 110.6,68.03 110.64,68.14 110.64,68.33 110.6,68.44 110.6,68.68 110.68,68.89 110.89,68.98 111.03,69.13 CPU1.AP34
  BOTTOM w0.102: v2(105.63,44.93) 105.64,44.93 RAM6.B7
M_B_DQS_DP1: length 34.6
  L6 w0.089: v2(114.75,62.82) 115.38,62.2 115.38,49.58 115.1,49.3 114.72,49.3 114.41,48.99 114.41,48.61 114.22,48.42 113.85,48.42 113.48,48.06 113.48,47.68 113.24,47.45 112.68,47.45 112.26,47.03 112.26,46.46 111.91,46.11 111.38,46.11 110.71,45.45 110.71,44.57 109.65,43.51 109.65,43.12 109.38,42.86 109,42.86 108.53,42.39 108.39,42.39 v2(107.98,41.98)
  BOTTOM w0.076: CPU1.AV35 113.55,68.7 113.63,68.78 113.74,68.78 113.77,68.76 113.77,68.74 113.81,68.63 113.81,68.5 113.8,68.49 113.8,68.46 113.8,68.44 113.77,68.37 113.77,68.36 113.77,68.1 113.77,68.09 113.81,67.98 113.81,67.84 113.8,67.81 113.77,67.73 113.77,67.72 113.77,67.72 113.75,67.66 113.75,65.01 114.12,64.64 114.12,63.16 114.28,63.01 114.55,63.01 114.57,62.99 114.58,62.99 v2(114.75,62.82)
  BOTTOM w0.102: RAM6.G3 108.95,41 108.75,41.2 108.41,41.2 108.14,41.47 108.14,41.82 v2(107.98,41.98)
M_B_DQS_DP2: length 36.6
  L4SGND w0.089: v2(108.53,72.19) 108.85,71.86 108.93,71.67 108.93,70.97 108.6,70.65 108.6,69.47 109.25,68.82 109.84,68.82 112.34,66.32 112.34,50.97 112.59,50.71 112.72,50.71 112.97,50.97 113.25,50.97 113.59,50.62 113.59,50.35 113.34,50.09 113.34,49.97 113.6,49.7 113.73,49.7 113.98,49.95 114.26,49.95 114.6,49.62 114.6,49.33 114.35,49.08 114.35,48.96 114.57,48.73 114.7,48.73 114.95,48.98 115.23,48.98 115.57,48.65 115.57,48.36 115.32,48.11 115.32,47.99 115.54,47.76 115.67,47.76 115.92,48.01 116.2,48.01 116.54,47.68 116.54,47.39 116.29,47.14 116.29,47.02 116.56,46.74 116.56,45.33 116.36,45.13 115.96,45.13 v2(115.78,44.94)
  BOTTOM w0.102: v2(115.78,44.94) RAM5.B7 ; CPU1.AL30 v2(108.53,72.19)
M_B_DQS_DP3: length 39.2
  L4SGND w0.089: v2(112.18,72.19) 111.76,71.76 111.76,71.16 112.38,70.54 112.38,70.47 113.62,69.23 113.62,68.9 114.5,68.02 115.14,68.02 116.45,66.71 116.45,56.59 116.85,56.18 117.14,56.18 117.33,56.38 117.45,56.38 117.68,56.15 117.68,56.03 117.49,55.83 117.49,55.55 120.19,52.85 120.19,46.74 120.64,46.29 120.64,45.05 119.16,43.56 119.16,43.01 118.9,42.75 118.49,42.75 118.29,42.55 118.29,42.14 v2(118.13,41.98)
  BOTTOM w0.102: v2(118.13,41.98) 118.28,41.83 118.28,41.26 118.85,40.69 119.23,40.69 RAM5.G3 ; CPU1.AU30 v2(112.18,72.19)
M_B_DQS_DP4: length 32.8
  L6 w0.089: v2(125.93,44.94) 126.27,45.29 126.53,45.29 126.73,45.49 126.73,46.55 125.07,48.21 123.51,48.21 121.66,50.06 121.66,50.2 121.96,50.5 121.96,50.79 121.61,51.14 121.35,51.14 121.03,50.83 120.93,50.83 120.92,50.83 120.85,50.83 119.3,52.38 119.3,53.51 119.14,53.67 119.14,59.86 117.89,61.11 117.89,63.3 117.67,63.52 117.34,63.52 v2(117.14,63.71)
  BOTTOM w0.076: v2(117.14,63.71) 116.89,63.46 116.49,63.46 116.41,63.54 116.41,67.57 116.5,67.79 116.5,68.03 116.44,68.18 116.44,68.29 116.51,68.47 116.51,68.65 116.47,68.76 116.42,68.89 116.2,68.99 116.07,69.12 CPU1.BB34
  BOTTOM w0.102: v2(125.93,44.94) RAM8.B7
M_B_DQS_DP5: length 36.7
  L6 w0.089: v2(128.28,41.98) 128.32,41.98 130.33,43.99 130.33,45.33 130.66,45.66 131.15,45.66 131.28,45.79 131.28,46.22 131.06,46.44 130.38,46.44 130.18,46.64 130.18,50.02 123.79,56.41 123.79,58.43 122.67,59.55 122.67,59.62 122.67,59.77 121.37,61.07 121.37,62.44 121.12,62.7 120.99,62.7 v2(120.87,62.58)
  BOTTOM w0.076: 119.81,64.08 119.81,64.09 119.83,64.11 119.83,64.82 118.8,65.85 118.8,67.65 118.8,67.69 118.84,67.83 118.85,67.85 118.85,68 118.84,68.01 118.81,68.12 118.81,68.34 118.75,68.4 CPU1.BF35
  BOTTOM w0.102: v2(120.87,62.58) 120.69,62.76 120.02,62.76 119.81,62.97 119.81,64.08 ; RAM8.G3 129.25,41 129.05,41.2 128.66,41.2 128.41,41.45 128.41,41.85 v2(128.28,41.98)
M_B_DQS_DP6: length 42.1
  L4SGND w0.089: v2(136.08,44.94) 136.29,45.14 136.53,45.14 136.88,45.49 136.88,46.67 136.88,46.79 135.39,48.28 134.76,48.28 134.61,48.43 134.61,48.66 134.36,48.91 132.24,48.91 131.15,50.01 131.15,50.13 131.41,50.39 131.41,50.68 131.07,51.01 130.79,51.01 130.53,50.75 130.4,50.75 130.18,50.98 130.18,51.1 130.41,51.33 130.41,51.62 130.07,51.95 129.79,51.95 129.56,51.72 129.43,51.72 129.21,51.95 129.21,52.07 129.41,52.28 129.41,52.56 129.08,52.9 128.79,52.9 128.59,52.69 128.46,52.69 128.24,52.92 128.24,53.04 128.46,53.26 128.46,53.54 128.12,53.88 127.84,53.88 127.62,53.66 127.49,53.66 127.22,53.93 127.22,54.11 127.46,54.35 127.46,54.75 121.49,60.71 121.49,66.17 119.92,67.74 119.62,67.74 117.25,70.11 117.25,70.98 v2(116.68,71.55)
  BOTTOM w0.102: CPU1.BC30 v2(116.68,71.55) ; v2(136.08,44.94) 136.09,44.94 136.09,44.93 RAM7.B7
M_B_DQS_DP7: length 44.3
  L4SGND w0.089: v2(138.43,41.98) 138.43,43.22 139.08,43.87 139.82,43.87 140.57,44.62 140.57,48.83 135.59,53.81 134.91,53.81 125.39,63.32 125.39,67.06 124.25,68.2 122.43,68.2 120.61,70.03 120.61,70.75 120.04,71.31 119.99,71.44 119.99,71.61 120.08,71.86 v2(120.39,72.16)
  BOTTOM w0.102: CPU1.BH30 v2(120.39,72.16) ; RAM7.G3 139.53,40.69 139.27,40.69 139.16,40.8 139.16,40.8 138.54,41.42 138.54,41.87 v2(138.43,41.98)
M_B_ODT0: length 100.5
  TOP w0.14: v2(147.02,39.64) R1311.1
  L2SGND w0.089: v2(108.63,61.93) 108.97,61.93 109.06,61.84 109.06,61.62 109.15,61.53 109.35,61.53 109.44,61.44 109.44,61.27 109.35,61.18 109.15,61.18 109.06,61.09 109.06,60.91 109.15,60.82 109.35,60.82 109.44,60.73 109.44,60.55 109.35,60.47 109.15,60.47 109.06,60.38 109.06,60.2 109.15,60.11 109.2,60.11 109.29,60.02 109.29,59.84 109.2,59.75 109.15,59.75 109.06,59.67 109.06,59.49 109.15,59.4 109.25,59.4 109.34,59.31 109.34,59.13 109.25,59.04 109.15,59.04 109.06,58.95 109.06,58.07 109.15,57.98 109.58,57.98 109.67,57.89 109.67,57.72 109.58,57.63 109.15,57.63 109.06,57.54 109.06,56.3 109.15,56.21 109.58,56.21 109.67,56.12 109.67,55.95 109.58,55.86 109.15,55.86 109.06,55.77 109.06,55.59 109.15,55.5 109.58,55.5 109.67,55.41 109.67,55.23 109.58,55.15 109.15,55.15 109.06,55.06 109.06,54.88 109.15,54.79 109.58,54.79 109.67,54.7 109.67,54.52 109.58,54.43 109.15,54.43 109.06,54.35 109.06,54.17 109.15,54.08 109.58,54.08 109.67,53.99 109.67,53.81 109.58,53.72 109.15,53.72 109.06,53.63 109.06,53.46 109.15,53.37 109.58,53.37 109.67,53.28 109.67,53.1 109.58,53.01 109.15,53.01 109.06,52.92 109.06,52.75 109.15,52.66 109.58,52.66 109.67,52.57 109.67,52.39 109.58,52.3 108.91,52.3 108.5,51.89 108.5,51.75 108.73,51.51 108.73,51.39 108.61,51.26 108.48,51.26 108.41,51.34 108.28,51.34 105.62,48.68 105.62,48.55 105.67,48.5 105.67,48.38 105.55,48.25 105.42,48.25 105.37,48.3 105.24,48.3 105.12,48.18 105.12,47.96 105.28,47.8 105.28,47.65 105.15,47.52 105.02,47.52 104.81,47.74 104.68,47.74 104.14,47.2 104.14,47.07 104.38,46.83 104.38,46.7 104.25,46.58 104.13,46.58 103.88,46.82 103.76,46.82 103.41,46.47 103.41,46.32 103.61,46.11 103.61,45.99 103.48,45.86 103.36,45.86 103.14,46.08 103.02,46.08 102.81,45.87 102.81,45.55 102.9,45.46 103.08,45.46 103.17,45.37 103.17,45.19 103.08,45.1 102.9,45.1 102.81,45.02 102.81,42.49 102.92,42.38 103.16,42.38 103.24,42.29 103.24,42.12 103.16,42.03 102.93,42.03 102.84,41.94 102.84,41.76 102.93,41.67 103.16,41.67 103.24,41.58 103.24,41.41 103.16,41.32 102.93,41.32 102.84,41.23 102.84,41.05 102.93,40.96 103.21,40.96 103.29,40.87 103.29,40.69 103.21,40.61 102.9,40.61 102.81,40.51 102.81,39.88 103.12,39.57 103.42,39.57 103.51,39.66 103.51,39.99 103.6,40.08 103.78,40.08 103.87,39.99 103.87,39.86 103.96,39.77 107.73,39.77 v2(108.45,39.05)
  L4SGND w0.142: v2(108.45,39.05) 109.4,39.99 117,39.99 117.5,39.49 117.74,39.49 118.18,39.05 v2(118.6,39.05) 119.55,39.99 127.81,39.99 v2(128.75,39.05) 129.7,39.99 137.58,39.99 138.52,39.05 v2(138.9,39.05) 139.85,39.99 142.56,39.99 143.07,40.5 144.74,40.5 145.59,39.64 v2(147.02,39.64)
  BOTTOM w0.076: CPU1.AL36 109.28,68.13 109.42,67.86 109.42,67.44 109.24,67.25 109.24,66.91 109.43,66.72 109.43,63.67 109.16,63.4 109.16,62.46 v2(108.63,61.93)
  BOTTOM w0.14: v2(128.75,39.05) 129.53,38.27 RAM8.K3 ; RAM6.K3 109.23,38.27 v2(108.45,39.05) ; v2(118.6,39.05) 119.38,38.27 RAM5.K3 ; v2(138.9,39.05) 139.68,38.27 RAM7.K3
M_B_PARITY: length 92.5
  L2SGND w0.089: v2(104.56,63.5) 103.29,62.23 103.29,57.13 99.78,53.61 99.78,43.96 99.69,43.87 99.22,43.87 99.13,43.78 99.13,43.6 99.22,43.52 99.69,43.52 99.78,43.43 99.78,43.22 99.69,43.13 99.04,43.13 98.95,43.05 98.95,42.87 99.04,42.78 99.69,42.78 99.78,42.69 99.78,42.51 99.69,42.42 99.04,42.42 98.95,42.33 98.95,42.16 99.04,42.07 99.69,42.07 99.78,41.98 99.78,41.8 99.69,41.71 99.04,41.71 98.95,41.62 98.95,41.45 99.04,41.36 99.69,41.36 99.78,41.27 99.78,37.33 103.36,33.76 108.15,33.76 v2(109.2,32.72)
  L4SGND w0.142: 139.65,32.7 139.65,32.65 138.99,32 130.19,32 129.5,32.7 v2(129.5,32.72) 128.78,32 120.04,32 119.35,32.7 v2(119.35,32.72) 118.63,32 112.85,32 112.31,32.54 111.58,32.54 111.29,32.25 109.64,32.25 109.37,32.52 109.2,32.69 v2(109.2,32.72) ; 139.65,32.7 140.09,32.25 141.43,32.25 141.88,31.8 143.42,31.8 v2(143.89,32.28) ; 139.65,32.7 v2(139.65,32.72)
  BOTTOM w0.076: v2(104.56,63.5) 104.78,63.72 104.78,66.47 105.12,66.8 105.12,67.17 104.92,67.36 104.92,67.74 105.04,67.95 105.04,69.02 105.35,69.33 CPU1.AE34
  BOTTOM w0.14: RN1304.1 143.95,32.33 v2(143.89,32.28) ; v2(109.2,32.72) 109.2,33.31 RAM6.T3 ; v2(119.35,32.72) 119.35,33.31 RAM5.T3 ; v2(139.65,32.72) 139.65,33.31 RAM7.T3 ; RAM8.T3 129.5,33.31 v2(129.5,32.72)
M_VREF_CA_DIMMA: length 49.4
  TOP w0.508: C1201.1 78.99,36.45 v2(79.35,36.81) ; C1201.1 77.59,36.09 76.7,35.2 74.06,35.2 73.2,36.07 70.71,36.07 C1236.1 69.72,35.89 69.2,36.41 v2(69.2,36.81) 68.96,36.81 68.37,36.22 67.86,36.22 66.93,35.29 63.59,35.29 62.78,36.09 61.77,36.09 61.56,35.89 C1203.1 59.7,35.89 59.05,36.54 v2(59.05,36.81) ; C1201.1 78.99,34.62 81.91,31.7 89.22,31.7 91.13,33.6 v2(91.13,34.95) 91.18,35 C1286.1 92.6,35 R1222.2 R1223.2 94.15,35.03 R1202.1
  BOTTOM w0.305: RAM4.M1 58.78,36.54 v2(59.05,36.81) ; v2(91.13,34.95) 89.54,36.54 RAM1.M1 ; RAM2.M1 79.08,36.54 v2(79.35,36.81) ; RAM3.M1 68.93,36.54 v2(69.2,36.81)
M_VREF_CA_DIMMB: length 55.7
  TOP w0.508: v2(142,36.81) 141.35,36.16 C1301.1 139.2,35.2 136.57,35.2 135.6,36.17 C1303.1 ; C1336.1 120.03,36.09 119.04,37.08 116.45,37.08 115.46,36.09 112.59,36.09 112.06,35.56 v2(112.06,34.95) 112.06,34.62 C1343.1 111.74,34.08 111.74,32.45 111.25,31.97 100.4,31.97 R1320.2 R1321.2 R1302.1 ; C1336.1 121.53,36.64 v2(121.7,36.81) ; C1336.1 125.85,36.09 126.69,35.26 129.56,35.26 130.47,36.17 C1303.1 ; v2(131.85,36.81) 131.49,36.45 C1303.1
  BOTTOM w0.305: RAM5.M1 121.43,36.54 v2(121.7,36.81) ; RAM6.M1 112.06,35.31 v2(112.06,34.95) ; RAM8.M1 131.58,36.54 v2(131.85,36.81) ; RAM7.M1 141.73,36.54 v2(142,36.81)
MASK_BASE_LEDS#: length 8.8
  BOTTOM w0.127: U6402.4 121.65,6.92 R6419.2 120.83,7.1 120.02,7.92 v1(120.02,9.04) 119.63,9.42 119.63,10.81 119.74,10.91 Q6404.2 Q6404.5
MASK_SATA_LED#: length 46.7
  L4SGND w0.102: v2(125.48,14.24) 125.04,13.81 124.4,13.81 123.34,14.88 112.88,14.88 111.82,15.94 107.7,15.94 107.39,16.25 102.77,16.25 102.49,15.97 101.12,15.97 100.64,16.45 93.52,16.45 93.04,15.97 v2(92.95,15.97)
  BOTTOM w0.102: v2(92.95,15.97) 92.38,16.54 92.38,19.34 92.99,19.95 93.27,19.95 94.28,20.96 94.28,21.27 94.31,21.31 U2401.56 ; v2(125.48,14.24) 125.93,14.24 R6406.2 126.24,15.39 v1(126.11,15.51) 125.87,15.27 124.45,15.27 123.9,15.82 Q6403.G
MCDP2800_D8: length 5.3
  TOP w0.102: v1(34.19,62.3) R5709.2 34.14,61.49 30.56,61.49 30.43,61.61 30.43,61.61 30.16,61.89 U5701.D8
MCDP2800_UART_TX: length 3.9
  TOP w0.102: AFTP5701.1 32.64,61.28 30.25,61.28 30.12,61.42 29.64,61.42 29.18,61.87 U5701.D7
ME_FWP: length 147.9
  TOP w0.102: v2(38.35,25.04) 38.05,25.34 37.41,25.34 36.44,26.31 35.81,26.31 35.22,26.9 35.22,27.15 34.85,27.51 33.49,27.51 33.45,27.47 31.86,27.47 31.3,28.03 27.67,28.03 v2(27.11,27.46)
  L4SGND w0.102: v2(36.32,8.27) 36.75,8.7 36.75,10.61 33.94,13.43 30.53,13.43 30.28,13.68 30.28,15.08 31.62,16.43 31.62,23.74 30.58,24.78 30.02,25.34 29.16,25.34 28.41,26.09 28.41,26.67 27.62,27.46 v2(27.11,27.46)
  BOTTOM w0.102: R1909.1 119.38,58.46 116.71,55.79 81.93,55.79 79.28,53.14 60.47,53.14 56.05,48.72 51.62,48.72 46.89,44 44.56,44 43.32,42.76 43.32,31.69 39.75,28.12 39.75,26.43 v2(38.35,25.04) ; v2(36.32,8.27) 35.64,7.59 R9806.1 35.05,7.13 v1(34.71,7.47) 33.77,8.41 FSW1.2
ME_FWP_EC: length 70.7
  L4SGND w0.102: v2(96.52,13.1) 96.01,12.59 91.9,12.59 91.06,11.75 91.06,11.54 90.69,11.17 87.22,11.17 85.77,9.71 84.73,9.71 83.49,8.48 76.22,8.48 75.93,8.77 74.37,8.77 73.97,9.17 68.46,9.17 65.84,6.55 39.93,6.55 v2(39.22,5.83)
  BOTTOM w0.102: v2(96.52,13.1) 96.52,13.48 97.53,14.49 U2401.80 ; FSW1.3 35.28,8.82 36.5,8.82 36.73,8.59 36.73,7.36 R9806.2 36.5,6.95 37.08,6.37 37.08,6.35 v1(37.11,6.32) 37.17,6.27 37.19,6.27 37.59,5.86 39.19,5.86 v2(39.22,5.83)
ME_SUS_PWR_ACK_R: length 15.3
  BOTTOM w0.076: 126.49,66.69 126.37,66.82 126.37,67.73 126.39,67.79 126.39,68.03 126.37,68.09 126.37,68.38 126.39,68.44 126.39,68.96 CPU1.BV34
  BOTTOM w0.102: R1738.2 R1708.1 127.51,56.66 v1(127.76,56.91) 128.4,57.55 128.4,60.82 128.13,61.09 128.13,63.78 126.49,65.42 126.49,66.69
MEC_XTAL1_R: length 5.8
  BOTTOM w0.089: U2401.123 87.11,5.18 87.71,4.59 v1(87.71,4.39) 87.35,4.03 C2425.1 86.31,4.21 X2401.1
MEC_XTAL2: length 8.7
  BOTTOM w0.089: 85.78,4.86 85.78,5.53 86.31,6.07 U2401.125 ; 85.78,4.86 85.05,5.58 v1(83.34,5.58) 83.34,4.45 83.1,4.21 X2401.2 82.21,5.34 R2461.2 ; 85.78,4.86 C2424.1
MEM_CHA_EN: length 17.9
  TOP w0.102: v1(132.74,70.87) v2(133.29,70.87)
  L6 w0.102: v2(146.94,73.68) 145.92,72.66 139.95,72.66 139.06,71.77 134.2,71.77 v2(133.29,70.87)
  BOTTOM w0.102: v2(146.94,73.68) 146.94,73.22 R2030.1 R2031.2 ; CPU1.CJ31 132.93,71.23 v2(133.29,70.87)
MEM_CHB_EN: length 18.1
  TOP w0.102: v1(133.74,73.2) 133.4,73.54 v2(133.29,73.54)
  L6 w0.102: v2(146.94,74.69) 146.43,74.19 143.13,74.19 142.62,73.67 133.42,73.67 v2(133.29,73.54)
  BOTTOM w0.102: R2032.1 145.93,74.19 146.43,74.19 v2(146.94,74.69) 147.65,74.69 R2033.2 ; CPU1.CJ27 132.99,73.83 v2(133.29,73.54)
MEM_CONFIG0: length 19.2
  L6 w0.102: v2(146.3,76.09) 142.11,76.09 141.6,75.58 137.13,75.58 136.12,74.57 132.32,74.57 v2(131.31,73.56)
  BOTTOM w0.102: CPU1.CF27 131.04,73.83 v2(131.31,73.56) ; R2016.2 147.07,76.85 v1(146.87,76.66) v2(146.3,76.09) 146.22,76.18 R2015.1
MEM_CONFIG1: length 21.2
  L6 w0.102: v2(147.07,76.09) 146.66,75.68 145.95,75.68 145.75,75.89 142.54,75.89 141.99,75.33 137.15,75.33 136.19,74.38 132.52,74.38 131.79,73.65 131.79,72.72 v2(131.31,72.24)
  BOTTOM w0.102: v2(131.31,72.24) 131.02,72.53 CPU1.CF29 ; R2018.2 v2(147.07,76.09) 146.43,75.46 v1(146.43,75.41) 146.41,75.39 R2017.1
MEM_CONFIG2: length 18.4
  TOP w0.102: v1(131.75,73.2) 132.05,73.5 v2(132.21,73.5)
  L6 w0.102: v2(132.21,73.5) 132.66,73.94 140.08,73.94 140.91,74.77 146.23,74.77 v2(146.3,74.69)
  BOTTOM w0.102: R2029.2 147.74,75.37 146.98,75.37 v2(146.3,74.69) 146.21,74.6 R2022.1 ; v2(132.21,73.5) 131.88,73.83 CPU1.CH27
MEM_CONFIG3: length 19.6
  TOP w0.102: v2(132.25,72.82) 132.46,72.61 v1(132.46,72.2)
  L6 w0.102: v2(132.25,72.82) 132.82,72.82 133.1,73.1 133.44,73.1 134.57,71.96 137.99,71.96 139.12,73.09 142.8,73.09 143.43,73.73 146.27,73.73 v2(146.3,73.69)
  BOTTOM w0.102: CPU1.CH28 131.89,73.18 v2(132.25,72.82) ; R2011.2 147.4,74.19 146.8,74.19 v2(146.3,73.69) 145.64,73.03 R2012.1
MEM_CONFIG4: length 20.7
  L6 w0.102: v2(147.45,71.01) 147.45,71.23 147.35,71.33 135.32,71.33 133.83,69.84 133.18,69.84 132.89,70.14 132.89,71.73 v2(133.24,72.09)
  BOTTOM w0.102: CPU1.CJ30 133.04,71.88 v2(133.24,72.09) ; R2014.1 R2013.2 148.13,71.05 v1(148.08,71.01) v2(147.45,71.01)
MESW1_B: length 7.9
  BOTTOM w0.102: R9805.2 R9804.1 35.69,13.02 35.48,13.02 v1(35.18,12.72) 31.27,8.81 FSW1.1
MIC2_VREFO_L: length 3.7
  TOP w0.203: 19.5,19.86 19.92,19.44 20.66,19.44 U2701.28
  TOP w0.254: 19.5,19.86 18.77,20.58 v1(18.77,20.71) 18.22,20.17 RN2901.2
MIC2_VREFO_R: length 3
  TOP w0.203: U2701.29 20.14,19.03 20.06,19.11 19.88,19.11 19.18,19.11 v1(18.8,19.5) RN2901.1
MIC_CAP: length 3.9
  TOP w0.203: v2(19.71,17.64) 19.93,17.64 20.05,17.76 20.06,17.76 20.13,17.83 U2701.32
  BOTTOM w0.254: C2735.1 20.5,19.3 v1(20.5,17.57) 20.47,17.54 19.81,17.54 v2(19.71,17.64)
MIC_GND: length 3.7
  TOP w0.305: v2(109.22,100.35) 109.21,100.35 108.68,100.88 108.53,100.88 v1(108,101.41) 107.95,101.47 R5501.1
  BOTTOM w0.305: v2(109.22,100.35) 109,100.13 LCD1.45
MODEL_ID: length 6.7
  TOP w0.102: v2(93.85,8.02) 94.28,7.59 94.54,7.59 95.07,7.05 C2407.1 95.05,6.98 R2441.1 95.94,7.13 v1(95.96,7.13) R2442.2
  BOTTOM w0.102: U2401.109 92.71,7.39 93.34,8.02 v2(93.85,8.02)
MSATA_DEVSLP_R: length 11.2
  TOP w0.102: R6301.2 170.94,9.29 AFTP6301.1 171.83,9.16 v2(172.09,9.16)
  BOTTOM w0.089: SSD1.38 174.58,14.6 ; 174.24,9.57 174.12,9.44
  BOTTOM w0.102: 174.12,9.44 173.84,9.16 v2(172.09,9.16) ; 174.58,14.6 174.24,14.27 174.24,9.57
MUX_HPD_CON: length 3.4
  BOTTOM w0.127: R7149.1 38.86,85.31 38.86,86.51 38.4,86.97 v1(38.4,87.14) 38.57,87.31 U7101.23
NB_MODE#: length 197.9
  TOP w0.102: v2(183.11,52.67) 183,52.78 v1(182.56,52.78) 182.56,52 R2004.1 182.22,50.97 182.22,47.54 182.7,47.06 183.77,47.06 183.82,47.01 R2050.2 184.61,47.08 184.42,47.27 Q2001.3
  L4SGND w0.102: v2(183.11,52.67) 184.48,51.3 184.48,49.57 184.48,49.57 184.48,49.42 184.73,49.17 185.42,49.17 187.32,47.26 187.32,46.58 191.24,42.66 191.24,34.94 191.21,34.92 191.21,34.87 188.39,32.05 188.39,30.78 187.6,29.99 181.74,29.99 178.49,26.74 174.75,26.74 174.01,26 174.01,25.09 174.4,24.71 174.4,22.73 173.58,21.91 173.58,11.5 172.34,10.25 171.91,10.25 171.65,10 171.65,9.04 169.6,6.98 162.76,6.98 161.59,8.15 145.53,8.15 145.16,7.77 145.16,7.13 139.78,1.75 105.66,1.75 105.18,1.26 80.16,1.26 78.74,2.69 v2(78.74,3.57)
  BOTTOM w0.102: U2401.34 85.51,19.41 85.42,19.32 85.42,18.82 86.49,17.75 86.49,15.35 87.68,14.16 87.68,13.21 87.43,12.95 87.43,10.22 87.81,9.84 87.81,8.76 87.7,8.65 85.3,8.65 84.96,8.32 84.96,8.13 84.71,7.84 84.49,7.61 82.9,7.61 82.75,7.77 80.59,7.77 79.73,6.91 79.73,5.06 78.74,4.07 v2(78.74,3.57)
NB_MUTE#: length 73
  TOP w0.102: U2701.2 26.95,16.63 v1(27.56,16.02) 28.57,15 30.68,15 R2743.2 31.34,14.35 v2(31.34,13.95)
  L4SGND w0.102: v2(31.34,13.95) 34.41,13.95 39.74,8.63 42.14,8.63 v2(42.55,9.04)
  BOTTOM w0.102: v2(42.55,9.04) 42.55,8.65 44.65,6.55 44.65,4.51 46.73,2.43 86.64,2.43 88.71,4.51 U2401.119
NC_HDMI_RE_DRIVER_F7: length 10.2
  TOP w0.102: U5701.F7 29.58,59.89 30.08,59.89 30.54,59.43 30.54,56.89 30.45,56.81 30.45,56.43 30.85,56.04 v1(30.85,56.04) 30.58,55.77 29.99,55.77 29.53,55.32 29.53,54.95 28.96,54.38 28.96,52.79 C5701.1
NC_SIO_SLP_S4#_EC: length 133.6
  TOP w0.102: v1(187.2,31.39) v2(187.88,31.16) ; v2(187.1,43.17) 187.1,43.18 187.1,43.32 186.39,44.04 R2405.1
  L4SGND w0.102: v2(97.92,5.61) 97.92,4.29 99.14,3.07 99.76,3.07 101.36,1.47 105.1,1.47 106.27,2.63 115.19,2.63 115.87,1.95 139.69,1.95 143.59,5.84 143.59,7.63 143.79,7.83 144.18,7.83 144.82,8.48 162.49,8.48 163.76,7.21 168.94,7.21 171.45,9.72 171.45,10.29 171.75,10.6 172.38,10.6 173.28,11.5 173.28,21.9 174.09,22.71 174.09,24.67 173.74,25.02 173.74,26.01 174.66,26.94 178.31,26.94 181.57,30.21 186.08,30.21 187.03,31.16 v2(187.88,31.16)
  L6 w0.102: v2(187.1,43.17) 187.68,43.17 189.57,41.29 189.57,34.26 187.79,32.48 187.79,31.25 v2(187.88,31.16)
  BOTTOM w0.102: v2(97.92,5.61) 97.51,6.01 U2401.97
NC_U3_PD#_EC: length 10.2
  BOTTOM w0.102: U2401.96 101.42,8.09 101.98,8.65 102.62,8.65 103,9.04 104.9,9.04 105.28,8.65 v1(106.81,8.65) 107.75,8.65 R2404.1 R2406.1
NCT7718_DXN: length 218.2
  L4SGND w0.102: v2(47.5,69.11) 46.61,68.22 46.06,68.22 44.45,66.61 44.45,66.05 44.82,65.68 46.61,65.68 46.63,65.7 50.64,65.7 50.95,65.39 50.95,55.36 39.14,43.55 39.14,30.07 41.88,27.33 49.54,27.33 50.09,27.88 77.67,27.88 82.18,23.37 97.51,23.37 98.12,23.97 105.16,23.97 107.24,26.05 111.4,26.05 113.92,28.57 125.94,28.57 126.4,29.02 139.51,29.02 142.11,26.43 142.11,23.15 143.99,21.28 147.26,21.28 148.13,20.41 159.6,20.41 164.61,25.42 164.61,28.08 158.25,34.44 v2(156.97,34.44)
  BOTTOM w0.102: U2601.3 151.69,41.78 C2607.2 151.54,40.76 v1(151.51,40.73) 151.51,40.66 152.29,39.87 153.39,39.87 157.64,35.63 157.64,34.72 157.35,34.44 v2(156.97,34.44) ; C2606.2 48.31,67.16 Q2603.E 47.5,67.97 v2(47.5,69.11)
NCT7718_DXP: length 218.7
  L4SGND w0.102: v2(156.97,33.8) 158.6,33.8 164.4,28 164.4,25.51 160.45,21.56 144,21.56 142.32,23.24 142.32,26.51 139.6,29.23 126.31,29.23 125.85,28.77 113.83,28.77 111.34,26.28 107.18,26.28 106.7,25.8 95.19,25.8 93.16,23.77 82.35,23.77 77.48,28.64 42.6,28.64 41.8,27.85 41.66,27.85 39.34,30.16 39.34,43.22 51.16,55.03 51.16,65.47 50.72,65.91 46.55,65.91 46.52,65.88 44.91,65.88 44.65,66.13 44.65,66.53 46.14,68.01 47.04,68.01 v2(48.13,69.11)
  BOTTOM w0.102: v2(156.97,33.8) 157.1,33.8 158.15,34.85 158.15,35.57 153.94,39.78 153.94,40.39 v1(153.67,40.66) 153.03,41.29 152.78,41.29 C2607.1 152.34,41.73 U2601.2 ; v2(48.13,69.11) 48.13,69.21 48.72,69.8 Q2603.C 48.77,69.46 48.72,69.41 48.72,68.65 Q2603.B 49.23,67.16 C2606.1
NRB_BIT: length 16.2
  L6 w0.102: v2(141.35,76.09) 141.33,76.07 137.34,76.07 136.04,74.76 131.93,74.76 130.78,73.6 130.78,73.2 v2(130.4,72.82)
  BOTTOM w0.102: CPU1.CE29 130.11,72.53 v2(130.4,72.82) ; R1503.1 142.16,74.57 R1502.2 141.48,75.33 141.99,75.84 v1(141.99,76.22) 141.48,76.22 v2(141.35,76.09)
PANEL_BKEN: length 276.3
  TOP w0.127: v2(170.94,78.63) 169.86,77.55 169.86,73.87 169.6,73.61 169.23,73.61 168.47,72.85 168.47,66.91 170.19,65.18 170.19,61.47 170.43,61.23 170.69,61.23 170.98,60.94 170.98,60.55 170.88,60.46 170.88,55.96 173.86,52.98 180.85,52.98 181.17,53.29 182.69,53.29 v2(182.82,53.42) ; v2(99.11,104.92) 98.81,104.62 R5544.2
  L4SGND w0.127: v2(182.82,53.42) 182.63,53.23 182.63,52.21 184.24,50.6 184.24,49.21 184.52,48.93 185.32,48.93 187.07,47.17 187.07,46.38 190.97,42.48 190.97,41.63 190.97,34.97 188.04,32.03 187.56,32.03 185.98,30.45 181.47,30.45 179.27,28.24 176.55,28.24 175.49,27.18 174.56,27.18 173.49,26.11 173.49,26.09 173.46,26.05 173.46,24.96 173.77,24.65 173.77,23.5 173.04,22.76 173.04,21.02 172.77,20.76 172.77,11.4 172.21,10.84 171.42,10.84 169.99,9.4 169.99,8.59 168.89,7.5 163.8,7.5 162.59,8.72 144.72,8.72 144.08,8.07 143.88,8.07 143.69,8.07 143.34,7.73 143.34,6.33 140.27,3.26 116.16,3.26 113.3,6.11 v2(112.78,6.11) ; v2(170.94,78.63) 171.58,79.27 171.58,84.73 170.56,85.74 166.62,85.74 163.83,88.54 163.83,94.38 v2(163.58,94.63) ; v2(99.11,104.92) 99.69,104.34 116,104.34 116.48,104.81 123.76,104.81 125.98,104.81 128.59,102.2 128.59,101.05 132.78,96.86 132.9,96.86 133.16,96.6 133.16,96.27 136.35,93.08 136.35,89.26 137.08,88.53 137.43,88.53 137.73,88.83 137.73,89.09 137.97,89.34 145.48,89.34 v2(146.98,90.83)
  BOTTOM w0.127: D2401.3 109.66,16.68 109.66,14.75 110.59,13.82 v1(110.59,12.62) 110.59,10.58 110.99,10.18 110.99,8.82 112.78,7.03 v2(112.78,6.11) ; v2(146.98,90.83) 148.17,92.03 150.94,92.03 153.54,94.63 v2(163.58,94.63)
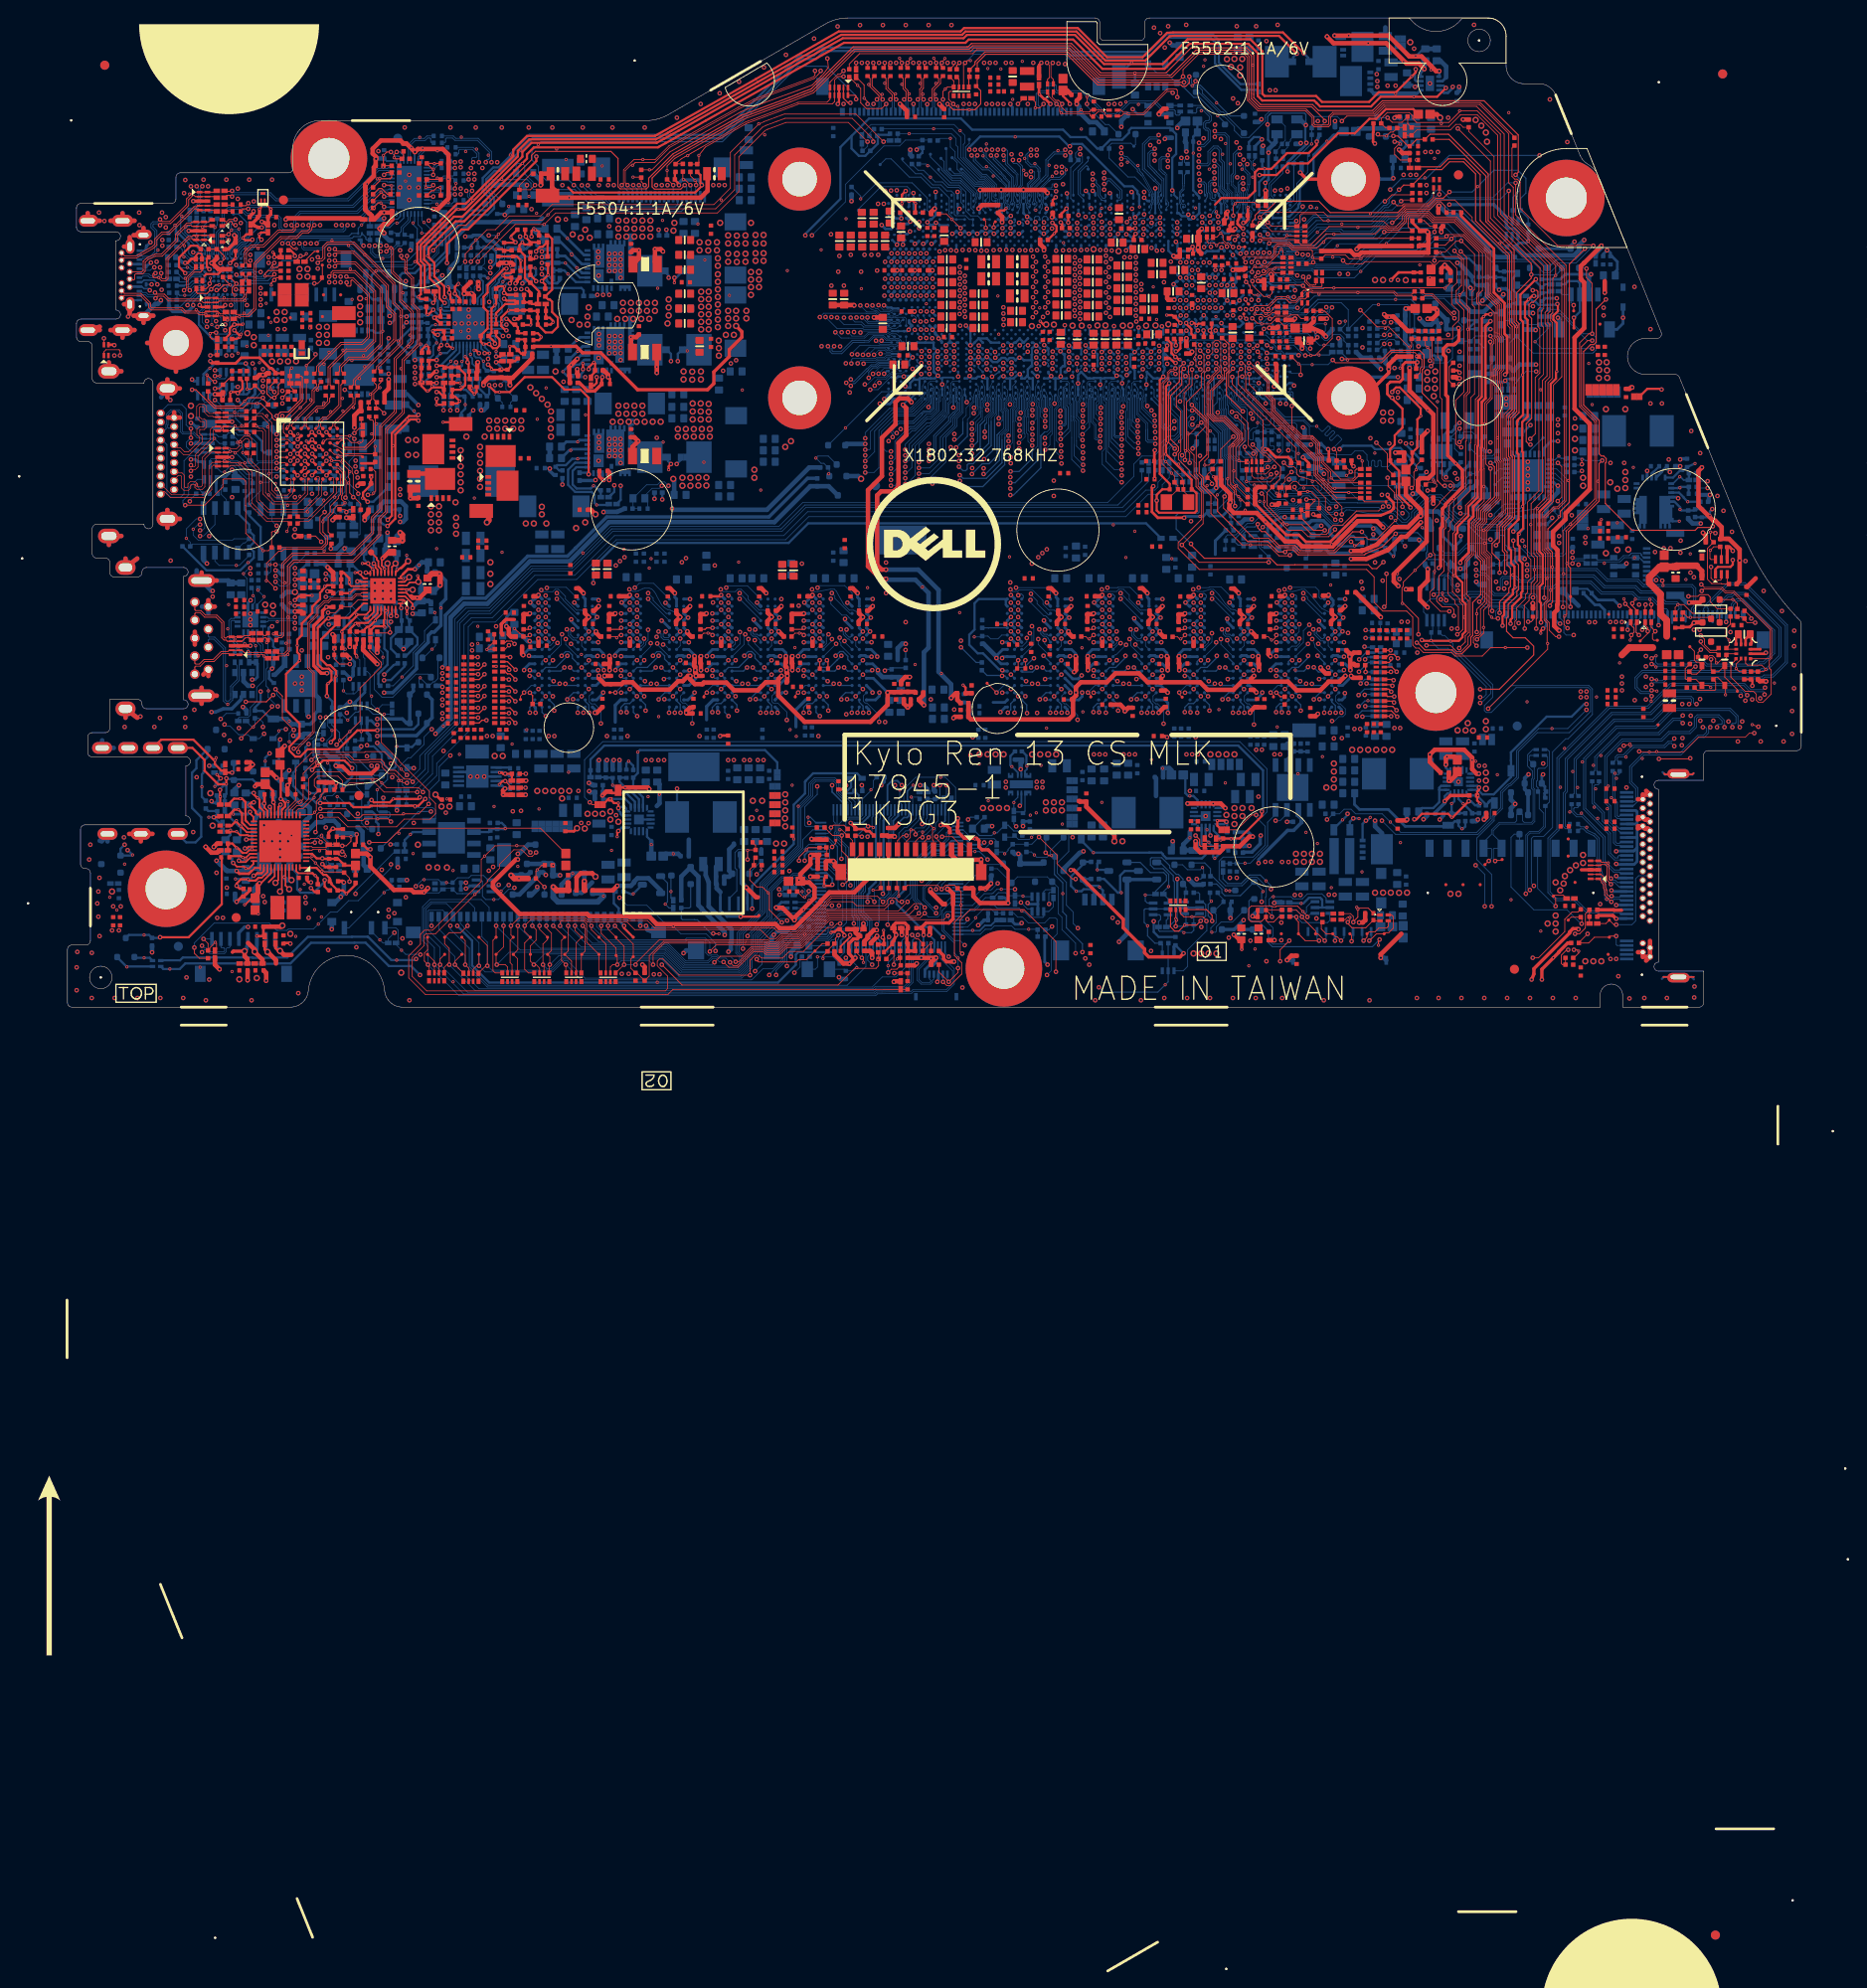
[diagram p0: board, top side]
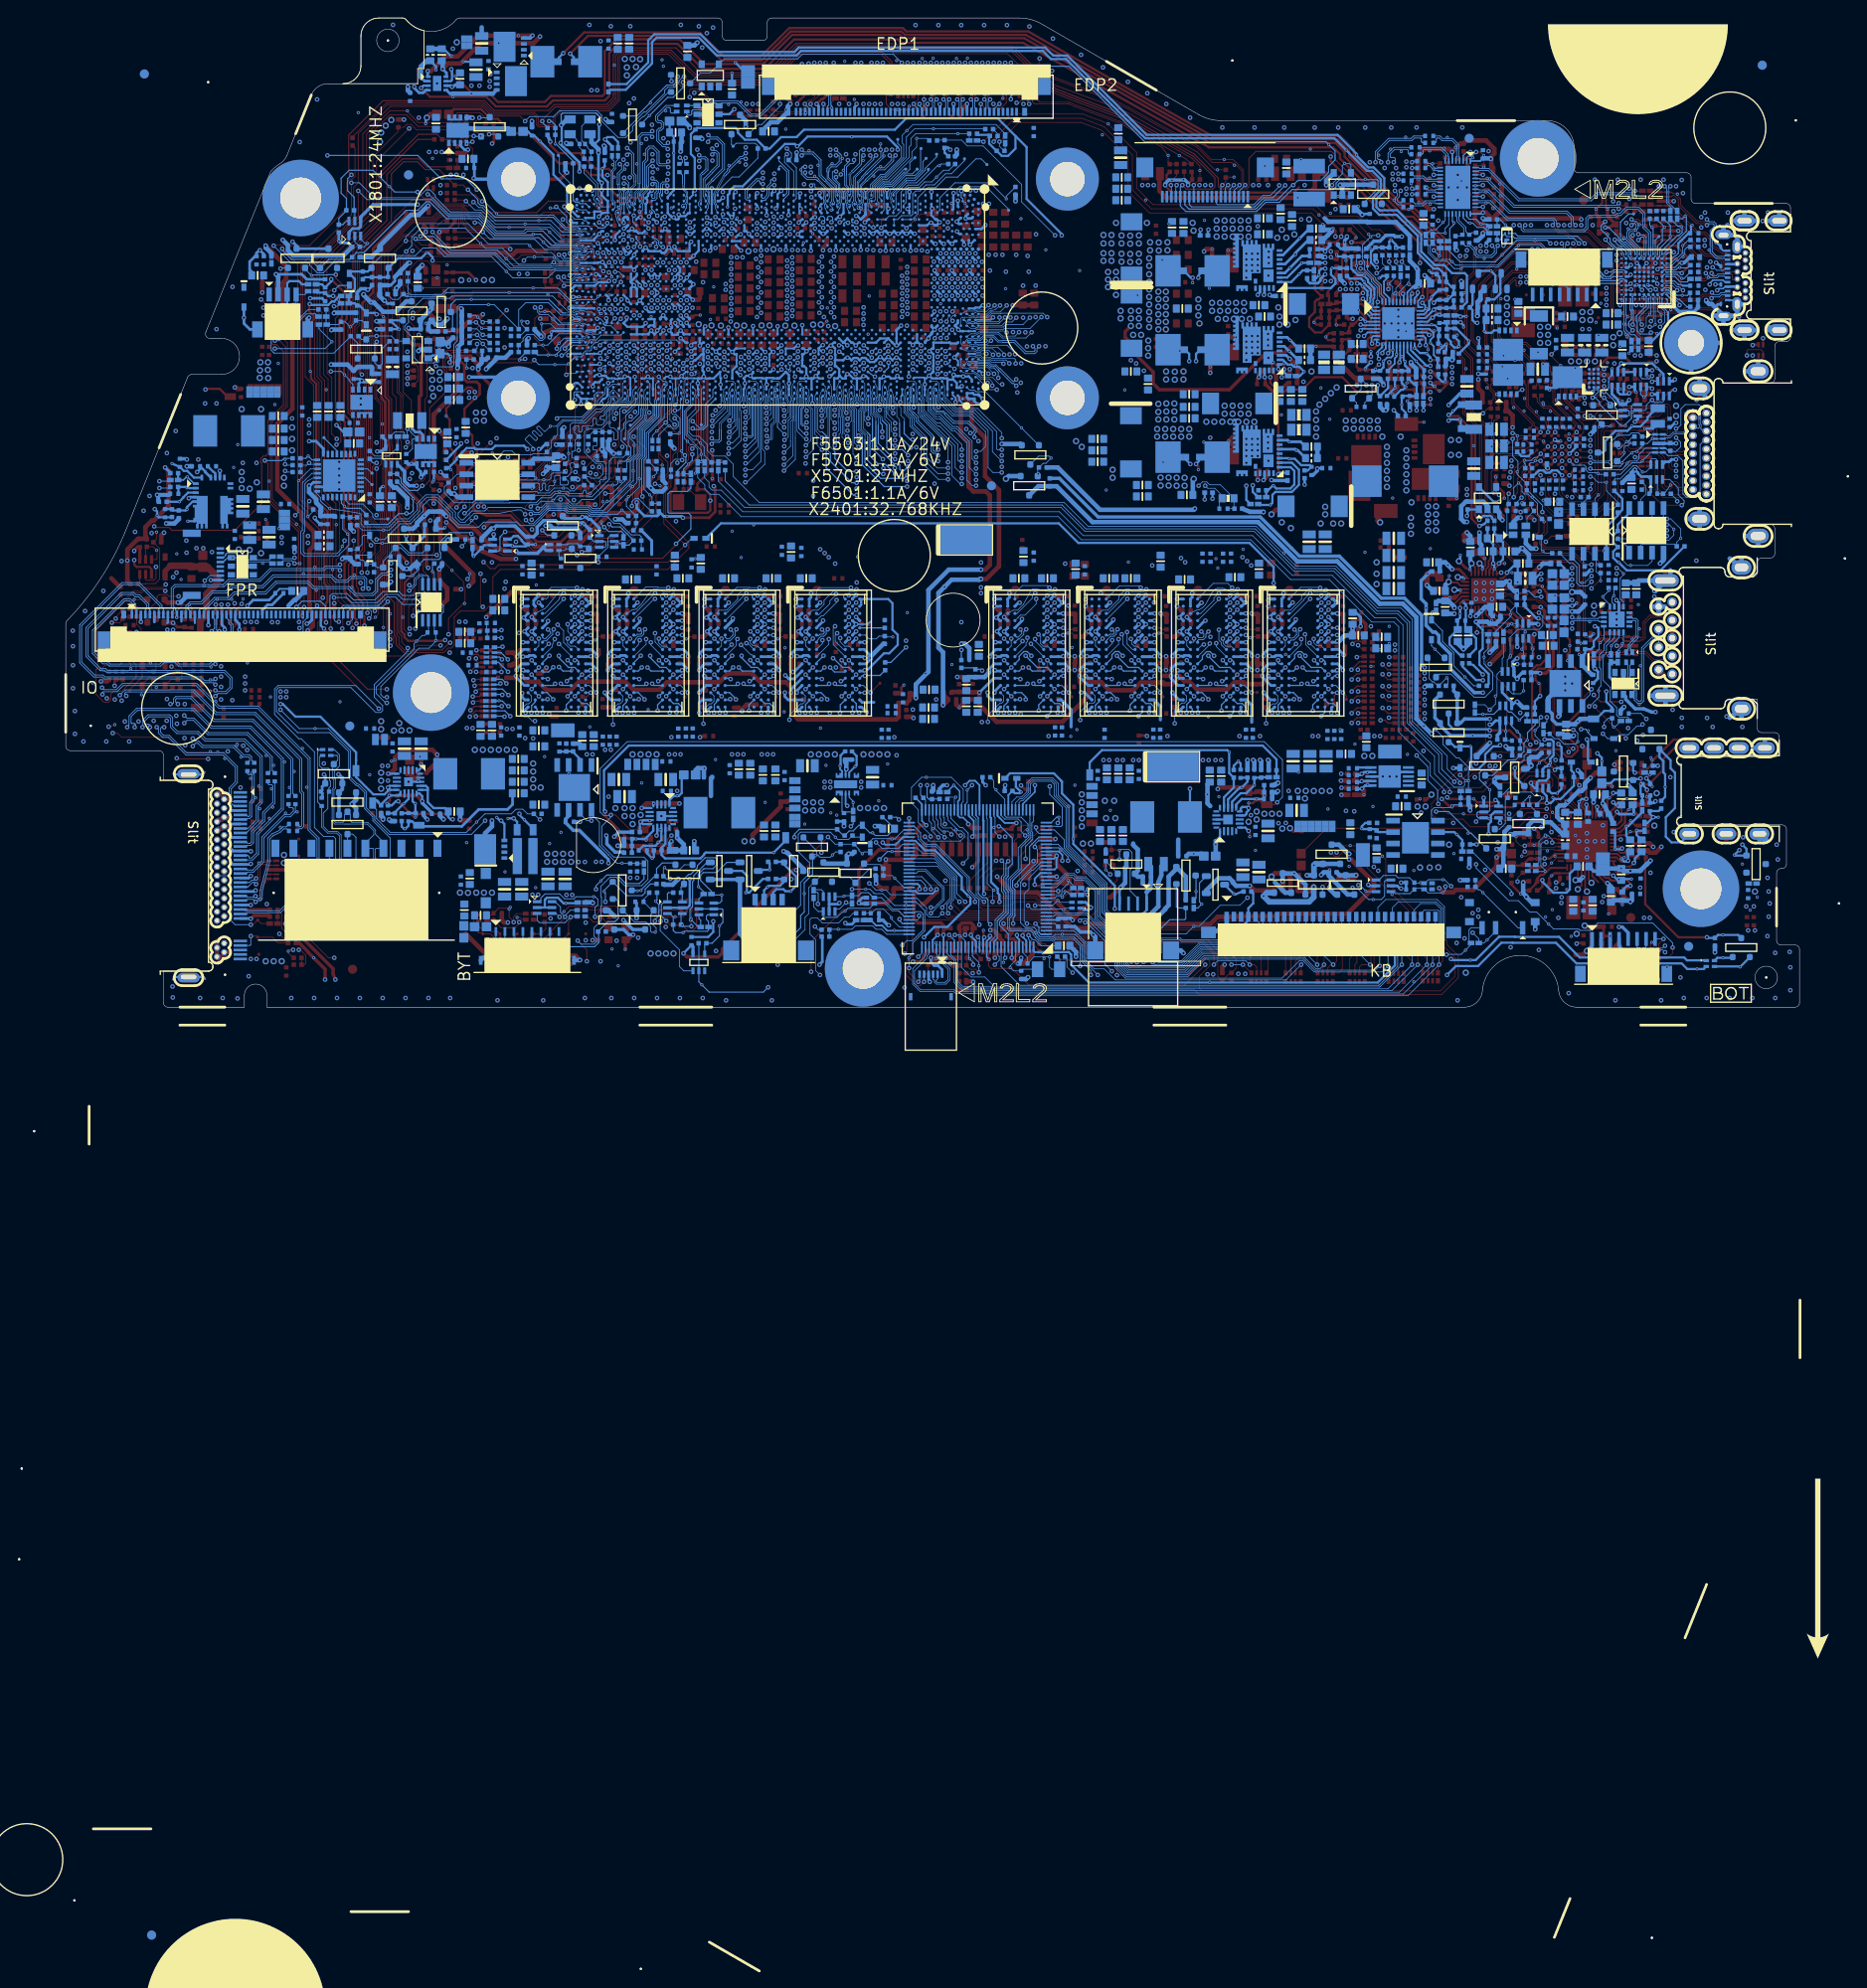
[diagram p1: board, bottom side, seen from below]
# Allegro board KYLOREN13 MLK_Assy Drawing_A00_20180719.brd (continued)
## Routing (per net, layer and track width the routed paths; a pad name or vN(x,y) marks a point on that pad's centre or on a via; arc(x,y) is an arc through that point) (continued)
PANEL_BKEN_EC: length 34.9
  TOP w0.127: v2(108.69,17.16) 109.02,16.83 v1(109.35,16.83)
  L4SGND w0.127: v2(87.92,16.22) 88.49,16.78 91.62,16.78 92.39,17.56 102.75,17.56 103.31,18.12 107.06,18.12 107.19,17.99 107.86,17.99 v2(108.69,17.16)
  BOTTOM w0.127: v2(87.92,16.22) 88.18,15.96 88.18,14.65 88.42,14.41 88.42,12.96 88.18,12.72 88.18,10.54 89.14,9.58 89.14,7.65 89.29,7.5 89.29,7.5 89.41,7.39 89.41,7.39 89.51,7.28 U2401.117 ; D2401.1 108.69,18.77 v2(108.69,17.16)
PBAT_CHG_SMBCLK: length 203
  TOP w0.089: v2(25.66,28.34) 25.66,28.77 27.41,30.52 27.41,37.17 26.87,37.72 26.87,42.57 27.84,43.55 27.84,44.23 28.56,44.95 29.01,44.95 29.29,45.23 31.59,45.23 32.1,45.74 32.61,45.74 32.71,45.65 PU4401.22
  L6 w0.089: v2(162.49,13.01) 162.49,12.48 156.51,6.5 138.56,6.5 136.83,8.23 133.31,8.23 133.06,8.48 131,8.48 130.07,9.41 130.07,9.64 128.93,10.78 126.91,10.78 126.81,10.88 111.63,10.88 110.97,10.22 107.91,10.22 107.79,10.34 98.9,10.34 97.87,9.31 92.44,9.31 91.21,10.54 90.08,10.54 85.67,10.54 84.95,11.26 v2(84.95,11.28) 84.95,11.42 84.86,11.51 81.18,11.51 80.04,10.37 79.72,10.37 79.12,9.77 75.69,9.77 75.34,9.42 73.66,9.42 73.31,9.77 67.94,9.77 65.84,7.66 46.69,7.66 41.74,12.61 39.78,12.61 39.74,12.65 36.94,12.65 36.22,13.37 34.67,13.37 31.79,16.25 31.79,18.63 31.52,18.91 31.52,20.57 29.05,23.03 29.05,23.54 26.32,26.27 26.32,27.98 25.96,28.34 v2(25.66,28.34)
  BOTTOM w0.089: v2(84.95,11.28) 84.93,11.29 U2401.9 82.98,11.29 v1(82.41,11.87) 82.19,11.65 RN2402.3 ; v2(162.49,13.01) 162.23,13.27 162.23,19.04 162.53,19.33 163.54,19.33 164.22,20.02 164.22,22.34 EC4309.1 164.65,22.79 164.65,28.41 164.44,28.61 RN4302.1
PBAT_CHG_SMBDAT: length 204.6
  TOP w0.089: v2(25.15,28.72) 25.38,28.72 25.47,28.81 25.47,28.85 27.22,30.6 27.22,37.09 26.68,37.64 26.68,42.65 27.65,43.62 27.65,44.31 28.48,45.14 28.94,45.14 29.21,45.42 31.51,45.42 32.03,45.93 32.58,45.93 32.69,46.05 PU4401.21
  L6 w0.089: v2(25.15,28.72) 25.48,28.72 25.5,28.74 25.83,28.74 26.51,28.05 26.51,26.35 29.24,23.62 29.24,23.11 31.71,20.64 31.71,18.99 31.98,18.71 31.98,16.33 34.75,13.57 36.3,13.57 37.02,12.84 39.82,12.84 39.85,12.8 41.82,12.8 46.77,7.85 65.76,7.85 67.86,9.96 73.39,9.96 73.74,9.61 75.26,9.61 75.61,9.96 79.04,9.96 79.64,10.56 79.96,10.56 81.1,11.7 85.09,11.7 85.35,11.45 85.6,11.45 85.72,11.32 v2(85.72,11.28) 85.72,10.82 85.81,10.73 90.16,10.73 90.16,10.73 91.28,10.73 92.52,9.5 97.79,9.5 98.82,10.53 107.87,10.53 107.99,10.41 110.89,10.41 111.55,11.07 126.89,11.07 126.99,10.97 129.01,10.97 130.26,9.72 130.26,9.49 131.08,8.67 133.13,8.67 133.39,8.42 136.91,8.42 138.64,6.69 156.43,6.69 160.19,10.44 162.17,12.43 162.17,12.51 162.08,12.6 v2(162.04,12.6)
  BOTTOM w0.089: v2(85.72,11.28) 85.31,10.86 84.3,10.86 84.27,10.89 U2401.8 81.87,10.89 v1(81.79,10.81) 81.61,11 RN2402.4 ; RN4302.2 164.27,27.96 164.46,27.77 164.46,26.84 164.16,26.54 163.47,26.54 163.33,26.4 163.33,25.2 163.22,25.09 163.22,24.54 163.4,24.36 EC4310.1 163.53,23.82 163.53,22.07 164.03,21.56 164.03,20.1 163.46,19.52 162.45,19.52 162.04,19.12 v2(162.04,12.6)
PBAT_PRES1#: length 20
  TOP w0.102: v2(168.25,9.26) 168.28,9.29 168.28,9.87 R4327.2 167.08,10 AFTP4309.1
  BOTTOM w0.102: BATT1.6 161.35,19.21 ED4304.3 160.75,19.22 160.4,18.86 160.4,13.35 162.94,10.81 166.62,10.81 168.17,9.26 v2(168.25,9.26)
PBAT_PRES#: length 217.6
  TOP w0.102: v2(31.37,38.12) 30.23,38.12 29.64,38.7 EC4306.1 29.64,39.77 29.67,39.79 PR4409.2 ; R2415.1 86.28,20.21 85.09,20.21 v2(84.84,19.96) ; R4327.1 167.84,10.56 167.17,10.56 166.37,9.76 166.37,8.39 163.45,5.48 v2(162.81,5.48)
  L4SGND w0.102: v2(146.05,20.72) 146.05,20.69 144.63,19.27 141.55,19.27 140.76,20.06 134.16,20.06 133.63,20.59 130.96,20.59 128.65,18.28 127.06,18.28 125.63,16.85 114.46,16.85 113.07,18.23 110.94,18.23 108.8,20.36 107.89,20.36 107.71,20.54 100.67,20.54 100.54,20.41 98.6,20.41 98.12,20.9 89.17,20.9 88.02,19.75 85.04,19.75 v2(84.84,19.96) 83.64,18.76 83.64,17.01 82.28,15.64 81.05,15.64 80.8,15.89 76.75,15.89 75.84,14.98 67.74,14.98 66.73,13.96 58.52,13.96 57.78,13.23 55.22,13.23 53.33,15.12 52.72,15.12 50.29,17.54 45.19,17.54 40.57,22.17 39.56,22.17 37.29,24.44 37.29,26.87 35.56,28.59 34.3,28.59 33.79,29.1 33.79,30.89 30.94,33.75 30.94,37.69 v2(31.37,38.12)
  L6 w0.102: v2(162.81,5.48) 163.07,5.73 163.07,11.83 164.08,12.84 164.08,14.33 164.3,14.54 165.49,15.73 165.49,15.74 166.29,16.54 166.29,16.55 166.86,17.11 166.87,17.11 169.29,19.54 169.29,32.53 v2(168.78,33.04)
  BOTTOM w0.102: v2(146.05,20.72) 147.57,19.2 156.72,19.2 158.32,20.8 158.32,21.21 159.23,22.13 159.23,23.94 160.02,24.72 160.3,24.84 161.01,25.55 161.01,28.49 163.47,30.96 v1(164.95,30.96) 166.7,30.96 v2(168.78,33.04) ; v2(84.84,19.96) 84.84,19.63 84.5,19.29 U2401.29
PCH_BATLOW#: length 10.2
  BOTTOM w0.102: v1(127.33,58.93) 127.33,58.97 127,59.3 R1721.2 127.03,59.78 R1722.1 127.89,63.76 126.13,65.51 CPU1.BV36
PCH_DPWROK: length 28.8
  TOP w0.127: v2(123.03,62.05) 122.35,62.73 122.35,68.31 123.54,69.5 123.54,71.06 v2(124.04,71.55)
  L6 w0.127: v2(123.03,62.05) 124.44,62.05 125.68,60.81 126.09,60.81 128.82,58.08 128.82,57.58 131.46,54.95 131.86,54.95 132.82,53.98 v2(132.82,53.33)
  BOTTOM w0.127: v1(133.12,53.92) 133.12,53.64 v2(132.82,53.33) 132.33,52.85 130.9,52.85 130.9,52.85 130.68,52.63 R1704.2 ; v2(124.04,71.55) 124.03,71.55 124.03,71.51 123.67,71.88 CPU1.BP30
PCH_JTAG_TCK: length 1.6
  TOP w0.102: v2(102.04,86.58) 102.04,87.34 TP315.1
  BOTTOM w0.102: CPU1.W6 101.76,86.87 102.04,86.59 v2(102.04,86.58)
PCH_PLTRST#: length 27.3
  TOP w0.102: v2(137.67,56.41) 138.43,56.41 v1(138.52,56.32) 138.52,56.17 138,55.64 R1713.2
  L6 w0.102: v2(137.67,56.41) 136.87,56.41 136.37,55.91 134.36,55.91 133.8,56.46 132.29,56.46 130.68,58.07 130.68,58.36 125.68,63.37 124.71,63.37 v2(122.99,65.09)
  BOTTOM w0.102: v2(122.99,65.09) 122.28,64.38 121.88,64.38 121.61,64.66 121.61,66.95 120.74,67.81 120.74,68.61 120.47,68.89 CPU1.BJ35
PCH_POPIRCOMP: length 1.3
  TOP w0.254: v2(126.23,75.18) 126.23,75.18 126.26,75.15 R305.2
  BOTTOM w0.203: CPU1.BW25 126.23,75.11 v2(126.23,75.18)
PCH_RSMRST#: length 193.2
  TOP w0.102: TP2402.1 85.37,18.2 v2(84.96,17.8)
  L4SGND w0.102: v2(158.12,51.96) 158.12,51.32 158.56,50.88 161.8,50.88 164.76,47.92 177.27,47.92 179.22,45.97 179.22,44.73 180.12,43.83 181.36,43.83 182.08,43.11 182.08,42.44 182.74,41.78 182.74,40.01 183.72,39.03 183.72,38.22 182.48,36.98 179.96,36.98 174.41,31.43 171.96,31.43 169.15,28.62 169.15,23.15 161.12,15.12 146.62,15.12 146.43,14.93 141.87,14.93 140.76,13.82 133.1,13.82 131.72,12.44 127.8,12.44 126.96,11.6 119.28,11.6 118.28,12.6 111.72,12.6 110.59,13.73 106.48,13.73 105.92,14.29 104.53,14.29 103.35,13.11 101.32,13.11 100.27,14.17 98.95,14.17 98.42,14.7 94.71,14.7 94.7,14.69 93.31,13.3 88.64,13.3 88.41,13.53 v2(87,13.53)
  BOTTOM w0.102: U2401.27 84.57,18.49 84.96,18.1 v2(84.96,17.8) 84.68,17.51 84.68,16.05 84.94,15.79 85.03,15.79 86.86,13.96 87,13.63 v2(87,13.53) ; v2(158.12,51.96) 157.23,51.96 155.48,53.7 154.34,53.7 152.96,55.08 152.96,55.72 152.3,56.38 151.51,56.38 149.94,54.81 149.94,54.24 149.03,53.33 146.77,53.33 146.21,53.89 142.53,53.89 142.15,53.51 140.62,53.51 138.95,55.19 137.19,55.19 136.88,54.88 134.75,54.88 134.42,54.55 132.54,54.55 131.83,53.84 131.83,53.84 131.72,53.74 131.08,53.74 129.81,52.47 128.91,52.47 128.69,52.26 R1702.2 128.69,50.93 EC1712.1
PCH_SATA_LED#: length 156
  TOP w0.127: v2(159.13,48.28) 159.13,49.63 158.29,50.46 158.29,51.5 158.86,52.06 158.86,53.51 160.03,54.69 160.03,60.92 159.87,61.08 159.87,65.72 160.53,66.37 160.53,75.63 160.24,75.92 160.24,83.57 156.46,87.35 156.46,92.58 155.12,93.92 153.57,93.92 152.7,93.06 151.16,93.06 R1606.1 148.46,91.33 v2(147.96,90.82)
  L6 w0.127: v2(159.13,48.28) 159.64,47.77 159.89,47.77 161.7,45.97 161.7,42.48 161.48,42.27 161.48,41.67 166.22,36.93 166.22,33.89 168.47,31.64 168.47,19.96 163.26,14.75 163.26,14.56 157.73,9.04 144.93,9.04 144.8,9.16 144.77,9.17 143.36,10.58 133.81,10.58 v2(132.69,11.7)
  BOTTOM w0.076: 136.03,86.39 135.87,86.39 135.74,86.26 arc(135.68,86.22) 135.62,86.21 135.42,86.21 arc(135.39,86.22) 135.37,86.23 135.14,86.47 CPU1.CN7
  BOTTOM w0.127: v2(132.69,11.7) 132.69,12.69 v1(132.84,12.85) 132.84,12.95 D6401.1 130.33,12.39 128.6,12.39 128.27,12.72 128.27,13.1 127.69,13.68 R6420.1 ; v2(147.96,90.82) 146.88,89.75 arc(146.85,89.71) 146.84,89.66 146.84,89.36 146.56,89.08 146.27,89.08 144.94,87.76 140.24,87.76 140.23,87.76 139.93,87.76 139.92,87.76 138.5,87.76 137.13,86.39 136.03,86.39
PCIE_RCOMPN: length 2.4
  TOP w0.305: R1604.1 130.02,87.37 130.02,87.01 130.52,86.51 v2(130.63,86.51)
  BOTTOM w0.305: v2(130.63,86.51) 130.48,86.63 130.44,86.63 130.28,86.78 CPU1.CE6
PCIE_RCOMPP: length 3.3
  TOP w0.305: v1(131.17,88.84) 131.17,87.98 R1604.2 131.15,87.94 131.17,87.52 130.89,87.18 v2(130.65,87.14)
  BOTTOM w0.305: v2(130.65,87.14) 130.69,87.18 130.69,87.61 130.53,87.78 130.3,87.78 130.3,87.77 130.18,87.65 CPU1.CE5
PCIE_WAKE#: length 1.5
  BOTTOM w0.102: R2407.1 82.73,9.29 U2401.4
PCIE_WAKE#_CPU: length 13.6
  L6 w0.102: v2(124.99,65.42) 125,65.42 125.52,65.94 125.52,68.99 124.87,69.64 124.87,70.15 124.5,70.51 124.5,71.78 124.96,72.24 v2(125.82,72.24)
  BOTTOM w0.102: v2(125.82,72.24) 125.77,72.24 125.42,71.88 CPU1.BU30 ; RN1701.3 126.79,63.52 125.73,64.58 v1(125.6,64.58) 125.47,64.58 125.17,64.28 124.86,64.28 124.59,64.55 124.59,65.02 v2(124.99,65.42)
PD4403_A: length 2.7
  BOTTOM w0.102: PQ4408.B 39.55,38.81 v1(40.51,39.77) 40.89,40.15 PD4404.A
PD4403_K: length 11.3
  BOTTOM w0.102: PR4477.1 40.79,44.04 40.89,43.93 PD4404.K 39.67,41.81 39.67,40.64 38.42,39.39 38.42,37.93 v1(37.17,36.68) 36.2,35.71 PR4495.1
PD_IRQ1: length 3.4
  BOTTOM w0.127: U7201.C1 14.58,79.67 14.54,79.63 14.52,79.63 13.53,78.63 13.34,78.63 12.52,77.82 R7224.2
PD_OVP_TRIP_P1: length 4.5
  BOTTOM w0.127: U7201.C2 15.03,79.91 14.45,79.91 13.63,79.09 13.04,79.09 v1(13.03,79.08) 12.45,79.08 R7209.2 12.17,78.61 R7243.2
PD_VBUS_C_CTRL1: length 20.7
  L6 w0.254: v2(21.46,81.68) 21.97,81.17 21.97,73.68 v2(19.81,71.52)
  BOTTOM w0.127: v2(21.46,81.68) 20.88,81.68 20.65,81.91 19.51,81.91 U7201.G10
  BOTTOM w0.254: Q7405.2 20.19,71.03 19.81,71.41 v2(19.81,71.52) 16.36,71.52 v1(15.82,70.99) 15.77,70.99 15.11,70.33 Q7406.2
PD_VBUS_C_CTRL1_A: length 1.2
  BOTTOM w0.254: Q7404.3 Q7405.1
PD_VBUS_C_CTRL1_R: length 6.5
  TOP w0.254: R7407.1 18.08,68.27 v1(18.16,68.34) 18.8,68.34 v2(18.92,68.22) 19.11,68.41 19.13,68.41 19.43,68.7 19.43,69.56 R7426.2
  BOTTOM w0.254: 19.54,68.09 19.94,68.09 20.19,68.34 Q7405.5 ; 19.54,68.09 19.05,68.09 v2(18.92,68.22) ; 19.54,68.09 Q7405.6
PD_VBUS_C_EN#: length 14.4
  TOP w0.127: R7422.1 22.16,69.37 22.16,68.15 22.61,67.71 v2(22.99,67.71) 23.43,68.15 23.43,69.12 R7427.2
  BOTTOM w0.127: Q7402.6 18.49,66.96 18.67,66.78 18.67,65.42 19.35,64.74 v1(19.35,64.61) 19.84,64.61 22.23,67 22.23,67.25 22.69,67.71 v2(22.99,67.71) 22.36,68.34 U7419.A3
PD_VBUS_C_EN_A: length 11.2
  TOP w0.127: R7425.2 19.94,69.23 19.96,69.21 v1(19.96,68.67) 20.45,68.67 R7409.1 21.54,68.34 v2(21.72,68.34)
  BOTTOM w0.127: Q7405.3 20.84,70.23 21.21,69.87 21.21,69.48 21.21,69.48 21.21,68.85 v2(21.72,68.34) 21.55,68.34 20.51,67.31 20.51,66.63 20.19,66.31 Q7402.2 19.05,66.31 18.92,66.19 18.92,65.8 19.07,65.66 Q7402.3
PECI_CPU: length 270.9
  TOP w0.089: v2(174.64,28.42) 174.65,28.42 174.73,28.34 v1(175.77,28.34) 179.58,28.34 181.23,29.99 186.44,29.99 186.89,30.45 v2(187.43,30.45)
  L6 w0.089: v2(174.64,28.42) 174.54,28.42 172.07,25.94 172.07,18.24 171.37,17.54 171.37,16.19 171.37,16.19 171.37,15.99 169.33,13.95 168.87,13.95 168.29,13.37 168.29,11.87 169.87,10.29 169.87,7.49 164.17,1.8 132.59,1.8 127.9,6.49 123.82,6.49 121.02,3.69 111.95,3.69 111.6,3.35 109.07,3.35 v2(108.84,3.57) ; v2(112.52,94.76) 112.67,94.76 114.17,96.26 114.17,100.73 117.42,103.97 120,103.97 121.89,105.86 121.97,105.86 122.73,106.62 130.68,106.62 131.39,105.91 131.39,102.78 132.81,101.36 140.34,101.36 141.16,100.55 144.85,100.55 145.61,101.31 151.32,101.31 151.64,100.99 151.77,100.86 156.44,100.86 161.52,95.78 161.52,91.15 167.2,85.47 167.63,85.47 168.4,84.69 168.78,84.69 172.42,81.05 172.42,74.93 171.77,74.29 171.77,69.56 170.11,67.89 170.11,60.04 170.41,59.73 170.41,57.98 174.32,54.07 178.05,54.07 178.98,53.14 181.55,53.14 181.56,53.15 181.91,53.15 182.16,52.9 182.16,51.95 184.45,49.67 184.45,49.5 187.85,46.11 187.85,45.5 187.85,44.19 190.12,41.91 190.12,34.03 188.34,32.25 188.34,30.88 187.91,30.45 v2(187.43,30.45)
  BOTTOM w0.089: R2437.2 105.16,10.43 105.59,10 105.96,10 105.96,9.99 106.13,9.99 106.76,9.37 108.58,9.37 109.14,9.92 109.78,9.92 109.96,9.75 109.96,8.12 109.32,7.49 109.32,4.06 v2(108.84,3.57) ; v2(112.52,94.76) 112.78,94.51 112.78,93.87 111.77,92.86 CPU1.AR1
PIRQA#: length 68.1
  TOP w0.102: v2(146.18,55.62) 145.69,55.14 143.24,55.14 141.66,53.55 140.66,53.55 140.13,53.03 140.13,52.8 139.88,52.55 138.23,52.55 137.16,53.61 v1(135.51,53.61) 135.43,53.61 133.29,55.75 133.29,56.01 133.3,56.02 133.3,56.29 133.29,56.3 133.29,57.19 R2053.2 133.89,57.86 134.36,58.33 134.36,58.34 134.7,58.68 134.7,59.06 134.79,59.14 134.79,60.02 133.24,61.57 132.92,61.57 132.68,61.81 132.68,62.14 132.84,62.3 132.84,65.17 129.01,69 129.01,70.39 129.51,70.88 v2(129.51,70.94)
  L4SGND w0.102: v2(168.28,59.58) 168.27,59.58 167.51,59.58 163.13,63.95 161.2,63.95 160.92,64.23 156.19,64.23 155.35,63.39 151.06,63.39 149.65,61.98 148.38,61.98 147.74,62.63 v2(146.88,62.63)
  L6 w0.102: v2(146.88,62.63) 146.61,62.36 146.61,60.99 147.12,60.48 147.12,56.71 146.18,55.77 v2(146.18,55.62)
  BOTTOM w0.102: R9137.2 168.15,59.45 v2(168.28,59.58) ; CPU1.CC32 129.41,70.94 v2(129.51,70.94)
PLT_RST#_Q_TPM2: length 2.1
  BOTTOM w0.127: R9136.2 165.96,60.98 v1(165.71,61.23) 165.29,60.81 U9102.17
PLTRST#_CPU: length 175
  TOP w0.127: v2(170.53,60.74) 170.18,60.39 170.18,56.22 166.78,52.82 166.78,49.01 167,48.79 AFTP6108.1 v2(167,44.47) ; R1713.1 137.62,54.96 137.39,54.96 C1701.1 137.08,54.55 R1715.1 138.46,52.98 v2(139.7,52.98) ; v2(159.77,48.28) 159.69,48.35 159.69,50.45 159.45,50.69 159.45,53.39 160.54,54.48 160.54,61.13 160.38,61.29 160.38,65.51 161.04,66.16 161.04,75.84 160.74,76.13 160.74,84.14 157.61,87.28 157.61,92.35 153.54,96.41 R2616.1
  L4SGND w0.127: v2(139.7,52.98) 139.83,53.1 139.83,53.65 139.55,53.93 139.55,55.95 139.87,56.27 143.69,56.27 145.97,53.99 146.46,53.99 146.51,53.93 148.41,53.93 149.94,55.45 152.12,55.45 152.87,56.2 154.96,56.2 155.54,55.63 155.54,54.5 155.21,54.17 154.21,54.17 153.16,53.13 153.16,51.67 154.09,50.74 158.02,50.74 159.26,49.51 v2(159.77,48.28) 160.81,47.24 164.7,47.24 167,44.94 v2(167,44.47)
  L6 w0.089: 173.46,11.6 SSD1.50
  L6 w0.127: 173.46,11.6 172.76,10.9 171.72,10.9 171.06,11.57 171.06,14.48 171.32,14.74 171.53,14.74 172.72,15.92 172.72,25.71 174.65,27.64 174.66,27.64 176.07,29.05 176.07,30.93 173.48,33.52 173.48,36.73 167.82,42.4 167.82,43.66 v2(167,44.47)
  BOTTOM w0.127: v2(170.53,60.74) 170.52,60.72 168.65,60.72 168.4,60.98 R9136.1 ; ED1701.1 139.14,52.42 v2(139.7,52.98) ; IOBD1.44 163.8,44.57 164.33,45.1 166.37,45.1 v2(167,44.47)
PM_PCH_PWROK: length 14.7
  TOP w0.127: v2(124.06,70.93) 123.81,70.68 123.81,69.16 122.57,67.91 122.57,63.11 123.45,62.23 123.45,61.84 v2(123.03,61.42)
  BOTTOM w0.127: v2(124.06,70.93) 124.05,70.93 124.05,70.92 123.73,71.23 CPU1.BP31 ; R1706.2 123.2,59.26 RN1703.3 124,59.79 v1(123.46,60.33) 123.03,60.76 v2(123.03,61.42)
PM_RSMRST#: length 44.9
  TOP w0.127: v2(132.26,53.66) 132.26,53.26 132.68,52.84 133.08,52.84 134.63,51.29 136.4,51.29 136.96,50.73 140.73,50.73 142.81,52.81 v2(143.83,52.81)
  L6 w0.127: v2(123.85,61.31) 124.85,61.31 125.56,60.6 125.95,60.6 128.57,57.98 128.57,57.47 131.38,54.67 131.78,54.67 132.04,54.41 132.04,53.89 v2(132.26,53.66)
  BOTTOM w0.076: 124.01,66.88 124.01,67.64 arc(124.03,67.73) 124.08,67.8 124.14,67.86 124.27,67.99 CPU1.BR36
  BOTTOM w0.127: Q1701.6 144.53,50.68 144.4,50.8 144.4,52.24 v2(143.83,52.81) ; 124.01,66.88 124.12,66.78 124.12,61.96 124.23,61.84 v1(124.23,61.79) 124.23,61.69 v2(123.85,61.31) 123.74,61.2 123.74,60.53 124.67,59.6 RN1703.4 ; Q1702.5 131.33,51.74 131.09,51.5 130.85,51.5 R1704.1 130.07,51.33 R1702.1 129.56,51.87 131.04,53.36 131.95,53.36 v2(132.26,53.66)
PM_RSMRST#_M: length 3.2
  BOTTOM w0.102: Q1702.3 132.72,51.09 132.61,51.2 132.61,51.61 132.75,51.74 Q1702.2 133.98,51.74 R1737.2
PM_SLP_S0#: length 57.6
  L4SGND w0.127: v2(145.29,49.42) 145.29,50.02 146.09,50.82 146.81,50.82 148.72,52.72 151.66,52.72 153.77,54.83 154.76,54.83 v2(154.79,54.86)
  L6 w0.127: v2(145.29,49.42) 145.1,49.23 144.2,49.23 143.18,50.25 142.44,50.25 140.21,52.48 140.21,54.5 138.88,55.83 136.94,55.83 136.64,55.53 134.81,55.53 134.66,55.39 133.58,55.39 132.75,56.22 132.19,56.22 130.09,58.32 130.09,58.61 125.92,62.78 124.51,62.78 v2(122.99,64.31)
  BOTTOM w0.127: v2(122.99,64.31) 122.86,64.18 121.8,64.18 121.33,64.65 121.33,66.71 CPU1.BJ37 ; R9141.2 159.09,53.64 156.83,53.64 155.65,54.83 154.81,54.83 v2(154.79,54.86) 154.76,54.83 154.38,54.83 154.05,55.16 v1(154.05,56.48) 154.05,56.61 154.93,57.49 154.93,57.49 155.64,58.19 155.64,58.2 R4040.1
PM_SLP_S3#: length 293.3
  TOP w0.127: v2(158.12,60.47) 158.56,60.03 158.56,56.68 157.04,55.16 157.04,54.16 156.48,53.61 156.48,50.07 157.03,49.52 157.03,45.84 156.15,44.96 156.15,41.3 155.93,41.09 155.93,40.27 154.91,39.25 154.28,39.25 153.84,39.69 150.83,39.69 150.03,40.49 v2(149.93,40.49) ; PR5126.1 v2(50.93,25.93) ; v2(162.56,62.5) 162.43,62.5 162.09,62.85 162.09,64.83 162.69,65.42 162.69,76.52 162.39,76.81 162.39,78.05 162.66,78.31 162.87,78.31 163.39,78.83 163.39,79.52 163.26,79.65 v2(162.81,79.65)
  L4SGND w0.127: v2(40.39,21.74) 40.61,21.74 45.4,16.95 48.16,16.95 51.09,14.02 51.09,13.19 51.56,12.72 58.17,12.72 58.42,12.97 66.08,12.97 67.84,14.74 75.94,14.74 76.85,15.65 80.7,15.65 80.95,15.4 82.38,15.4 83.88,16.91 83.88,17.11 83.88,17.99 85.41,19.51 89.34,19.51 89.66,19.83 93.12,19.83 93.58,20.29 94.38,20.29 94.77,19.89 96.08,19.89 96.84,20.66 97.21,20.66 98.2,19.66 104.99,19.66 v2(105.41,20.08) 105.83,19.66 109.16,19.66 110.84,17.99 112.97,17.99 114.36,16.6 125.73,16.6 127.16,18.04 128.75,18.04 131.06,20.35 133.53,20.35 134.06,19.82 140.66,19.82 141.45,19.03 144.73,19.03 145.81,20.11 159.63,20.11 164.85,25.32 164.85,28.18 157.26,35.77 156.03,35.77 151.73,40.07 151.73,40.51 151.24,41 151.24,41.04 150.42,41.86 149.93,41.86 149.67,41.6 149.67,40.8 149.93,40.53 v2(149.93,40.49) ; v2(158.12,60.47) 157.19,61.4 157.19,63.48 157.31,63.61 160.39,63.61 161.5,62.5 v2(162.56,62.5)
  L6 w0.127: v2(124.99,64.72) 125.69,64.03 126.45,64.03 133.14,57.34 140.62,57.34 142.68,55.28 142.68,52.61 144.83,50.46 145.84,50.46 147.17,49.13 147.17,46.12 148.34,44.95 148.34,43.55 147.79,43 147.79,42.63 148.05,42.37 148.06,42.37 149.93,40.5 v2(149.93,40.49) ; v2(50.93,25.93) 48.39,23.39 41.66,23.39 40.89,22.62 40.89,22.24 v2(40.39,21.74)
  BOTTOM w0.076: CPU1.BU36 125.31,68.06 125.31,67.88 125.23,67.68 125.23,67.4 125.52,67.11 125.52,65.25 v2(124.99,64.72)
  BOTTOM w0.127: v2(158.12,60.47) 158.5,60.47 158.88,60.85 R4018.1 158.83,60.98 157.43,60.98 157.1,60.64 U4008.1 ; Q4001.G 36.49,19.32 v1(36.83,19.32) 36.83,19.58 38.99,21.74 v2(40.39,21.74) ; v2(162.81,79.65) 162.28,80.18 161.16,80.18 D4003.K ; v2(105.41,20.08) 105.16,20.34 R4010.1
PM_SLP_S4#: length 211.5
  TOP w0.127: R4024.1 150.16,93.36 152.53,93.36 153.42,94.25 155.22,94.25 156.97,92.5 156.97,87.39 160.49,83.88 160.49,76.03 160.78,75.73 160.78,66.27 160.13,65.61 160.13,61.18 160.29,61.02 160.29,54.58 159.11,53.41 159.11,51.69 v2(158.74,51.31)
  L4SGND w0.127: v2(125.86,73.58) 125.41,73.13 125.41,70.74 125.98,70.17 125.98,69.18 127.39,67.77 127.39,64.68 131.75,60.32 131.75,60.3 134.96,57.09 145.24,57.09 145.88,56.46 155.07,56.46 155.79,55.74 155.79,54.4 155.31,53.92 154.37,53.92 153.54,53.08 153.54,51.93 154.32,51.15 156.08,51.15 157.34,52.41 158.3,52.41 158.74,51.97 v2(158.74,51.31) 158.92,51.14 162.18,51.14 165.14,48.18 177.35,48.18 179.55,45.98 179.55,44.84 180.3,44.09 181.61,44.09 182.36,43.34 182.36,42.58 183.02,41.92 183.02,40.07 183.96,39.13 183.96,38.12 182.54,36.7 180.02,36.7 174.51,31.18 172.06,31.18 169.39,28.52 169.39,23.05 161.22,14.88 146.72,14.88 146.53,14.69 142.05,14.69 140.87,13.51 134.14,13.51 v2(133.73,13.1)
  BOTTOM w0.127: v2(133.73,13.1) 133.73,13.48 v1(133.18,14.03) 132.54,14.67 131.34,14.67 131.09,14.43 131.09,14.4 130.43,13.73 128.91,13.73 128.4,14.24 PR5317.1 ; CPU1.BU27 125.6,73.83 v2(125.86,73.58)
POWER_SW_IN#: length 8.5
  TOP w0.102: v2(85.67,7.99) 85.67,7.99 85.35,7.67 85.35,7.19 R2451.2 84.45,6.29 R2432.2 83.95,5.68 v1(83.95,5.4)
  BOTTOM w0.102: U2401.127 85.51,7.4 85.67,7.56 v2(85.67,7.99) 85.17,7.49 84.94,7.49 84.28,6.83 C2427.1
PQ4302_B: length 11.3
  TOP w0.635: R4309.1 55.63,13.05 R4302.2 54.36,12.97 v2(53.98,13.35)
  BOTTOM w0.635: v2(53.98,13.35) 53.98,12.22 54.49,11.7 58.93,11.7 v1(59.56,12.34) 59.19,12.71 Q4302.B
PQ4348_D: length 2.4
  BOTTOM w0.508: Q4348.D 33.68,25.52 v1(33.91,25.29) 33.91,25.01 33.4,24.5 R4368.2
PQ4405_2: length 6.6
  BOTTOM w0.102: PR4462.2 33.73,41.76 32.13,43.36 32.13,43.63 ; 32.13,43.63 32.13,44.01 PR4463.1 31.42,43.88 30.73,43.2 PQ4405.2 ; 32.13,43.63 v1(32.12,43.63)
PQ4405_3: length 2.1
  BOTTOM w0.089: PQ4405.3 32.17,42.63 v1(32.36,42.43) 32.89,41.9 PR4476.2
PQ4405_5: length 3.1
  BOTTOM w0.102: PR4474.1 30.61,38.8 PC4438.1 30.68,39.59 v1(30.86,39.77) 30.73,39.9 PQ4405.5
PQ4405_6: length 3.2
  BOTTOM w0.102: PQ4405.6 30.08,40.64 29.72,40.28 29.72,39.85 v1(29.64,39.77) 29.64,39.01 PC4438.2 29.84,38.8 PR4450.1
PQ4408_C: length 14.6
  BOTTOM w0.102: PQ4408.C 40.05,37 38.71,37 36.15,34.44 34.95,34.44 34.09,35.29 34.09,37.18 35.05,38.14 v1(35.05,38.88) 35.05,39.38 34.59,39.84 PR4475.1 PR4462.1
PQ4408_E: length 6.1
  BOTTOM w0.102: PQ4408.E 41.15,38.62 41.15,36.5 40.79,36.14 40.63,36.14 40.2,35.71 PR4436.1 v1(39.19,36.59) 39.07,36.47 39.07,35.93 PR4473.2
PQ4417_D: length 9.3
  BOTTOM w0.127: PQ4417.D 34.55,25.75 34.54,25.74 34.09,25.74 32.37,27.46 31.56,27.46 PR4479.2 30.62,28.4 30.62,29.34 30.3,29.66 v1(30.25,29.66) 30.25,29.71 30.23,29.74 30.23,30.5 29.36,31.36 PR4483.1
PQ4418_2: length 4.3
  BOTTOM w0.127: PQ4418.2 32.64,33.11 32.31,32.78 32,32.78 31.14,31.92 v1(31.14,31.9) 31.11,31.9 30.48,32.53 PR4488.1 30.28,31.82 PR4483.2
PQ4418_3: length 3.4
  BOTTOM w0.127: PR4485.2 35.88,32.55 v1(35.18,32.55) 33.97,32.55 33.29,33.23 PQ4418.3
PQ4418_5: length 2.9
  BOTTOM w0.127: PC4445.1 32.59,29.61 PR4487.2 32.64,29.81 v1(32.64,30.63) PQ4418.5
PQ4418_6: length 3.5
  BOTTOM w0.127: PQ4418.6 31.99,31.24 v1(31.37,30.63) 31.04,30.29 PC4445.2 31.04,28.75 PR4486.1
PRD_CC1: length 5.4
  TOP w0.254: R7211.1 20.11,85.86 19.87,85.86 v1(19.48,85.47) 19.75,85.21 20.47,85.21 v2(20.54,85.27)
  BOTTOM w0.127: v2(20.54,85.27) 20.54,85.07 20.04,84.57 19.53,84.57 19.01,84.05 19.01,83.41 U7201.K9
PRD_CC2: length 5.1
  TOP w0.254: v2(21.55,85.27) 21.31,85.51 v1(21.31,85.87) 21.51,86.07 22.25,86.07 R7212.1
  BOTTOM w0.089: U7201.K10 19.49,83.39 19.49,83.7 19.5,83.7 19.5,83.71 19.93,84.14
  BOTTOM w0.127: 19.93,84.14 20.47,84.14 21.55,85.22 v2(21.55,85.27)
PRIM_PWRGD: length 262.1
  TOP w0.102: v2(109.83,3.93) 109.83,7.28 106.27,10.84 100.3,10.84 99.19,9.72 99.19,6.17 v2(99.42,5.94) ; v2(166.67,42.11) 166.29,42.49 166.29,43.38 v1(166.37,43.45) 166.57,43.66 166.57,48.88 166.54,48.91 166.54,52.92 169.9,56.28 169.9,65.13 168.22,66.81 168.22,73.37 168.91,74.06 v2(169.42,74.06)
  L6 w0.102: v2(32,12.59) 32.92,11.68 32.92,10.37 36.64,6.65 39.77,6.65 40.27,6.15 66.77,6.15 67.69,5.23 69.47,5.23 71.12,6.88 74.68,6.88 v2(75.06,6.5) 75.16,6.39 78.78,6.39 78.8,6.37 84.33,6.37 86.49,4.21 89.66,4.21 91.47,6.01 98.09,6.01 98.16,5.94 v2(99.42,5.94) ; v2(109.83,3.93) 111.4,3.93 111.72,4.25 120.78,4.25 123.57,7.04 128.12,7.04 129.51,5.66 136.3,5.66 138.19,3.76 163.77,3.76 166.34,6.34 166.34,8.49 167.13,9.27 167.13,14.01 168.24,15.11 168.76,15.11 169.93,16.27 169.93,17.74 170.41,18.23 170.41,35.91 165.13,41.19 165.13,42.59 165.68,43.15 166.04,43.15 166.29,42.89 166.29,42.49 v2(166.67,42.11)
  BOTTOM w0.102: v2(169.42,74.06) 168.88,74.06 165.9,77.03 164.87,77.03 R4030.1 ; U2401.30 82.8,19.69 81.7,18.6 81.7,17.69 77.51,13.51 77.51,10.55 75.06,8.09 v2(75.06,6.5) ; PR5308.1 36.38,17.29 32,12.91 v2(32,12.59)
PROCHOT: length 6.6
  BOTTOM w0.089: U2401.83 99.51,13.29 99.64,13.42 99.64,13.42 99.74,13.52 99.74,13.53 v1(100.54,14.32) 100.84,14.62 R2417.1 R2418.1 101.8,15.46 102.2,15.85 103.86,15.85 Q2408.G
PROCHOT#_CPU: length 270.2
  TOP w0.089: v2(34.42,33.04) 34.86,32.59 34.86,29.41 36.84,27.44 36.84,27.35 40.21,23.97 40.21,23.3 40.89,22.62 40.89,21.48 40.3,20.89 37.42,20.89 36.56,20.03 31.14,20.03 30.07,21.1 28.27,21.1 v2(28.19,21.18)
  L4SGND w0.089: v2(46.99,81.55) 46.87,81.55 44.58,79.26 44.58,79.17 41.01,75.6 40.11,75.6 37.67,73.16 37.67,68.55 38,68.23 38,66.78 35.77,64.55 35.77,54.99 34.98,54.2 34.98,51.91 32.05,48.99 32.05,48.13 32.77,47.42 32.77,45.76 31.96,44.95 31.96,34.86 33.78,33.04 v2(34.42,33.04)
  L6 w0.089: v2(46.99,81.55) 47.52,81.55 48.26,82.29 48.26,83.6 49.23,84.57 49.23,85.37 49.99,86.12 54.74,86.12 56.67,88.05 76.49,88.05 79.22,85.33 82.3,85.33 v2(82.72,85.75) ; v2(112.01,5.99) 106.85,5.99 105.86,6.97 104.79,7.42 102.76,7.42 102.61,7.42 101.61,6.42 99.36,6.42 98.94,6.59 91.11,6.59 91.08,6.56 89.42,6.56 89.07,6.9 85.13,6.9 84.27,7.76 84.21,7.76 83.44,8.53 72.01,8.53 71.93,8.61 70.95,8.61 69.16,6.83 41.41,6.83 40.09,8.15 40.08,8.15 39.57,8.67 39.57,8.67 35.7,12.54 34.33,12.54 30.96,15.91 30.96,16.6 30.96,18.1 30.68,18.38 30.68,20.22 29.77,21.13 28.24,21.13 v2(28.19,21.18)
  BOTTOM w0.089: v2(46.99,81.55) 46.84,81.55 46.28,82.11 PR4607.1 46.35,82.62 PR4603.2 ; PR4485.1 34.98,33.6 v2(34.42,33.04) 33.78,33.67 v1(33.78,34.56) 33.61,34.73 33.61,36.99 33.31,37.29 PQ4416.3 33.04,38.74 32.89,38.88 PR4476.1 ; R2418.2 103.32,15.39 Q2408.D 105.57,14.47 108.87,14.47 ED2403.1 109.44,13.93 110.1,13.27 110.1,10.37 110.5,9.97 110.5,8.62 112.01,7.1 v2(112.01,5.99) ; R302.1 95.78,96.33 R301.2 93.11,96.33 92.46,95.69 90.72,95.69 86.44,91.41 86.44,89.47 v2(82.72,85.75)
PROCHOT#_CPU_R: length 11.8
  BOTTOM w0.089: R302.2 96.93,96.52 v1(98.1,96.52) 98.1,95.56 98.63,95.03 98.63,94.33 101.19,91.77 101.82,91.77 102.45,91.13 102.45,89.54 102.31,89.39 102.31,88.85 CPU1.Y4
PROJECT_ID0: length 5.1
  TOP w0.102: v2(131.64,76.53) 131.69,76.53 132.24,75.98 132.62,75.98 v1(132.69,75.91) 133.72,75.91 134.16,76.35 R2113.2 134.51,76.35 135.3,75.57 R2114.1
  BOTTOM w0.102: CPU1.CH23 131.96,76.21 v2(131.64,76.53)
PROJECT_ID1: length 24.7
  BOTTOM w0.102: R2112.1 R2111.2 154.63,79.46 154.32,79.15 150.89,79.15 150.15,79.9 v1(140.72,79.9) 137.97,79.9 136.57,78.49 136.04,78.49 135.94,78.6 134.52,78.6 134.52,78.61 134.06,78.61 134.04,78.63 133.76,78.63 CPU1.CK19
PROJECT_ID2: length 3.5
  TOP w0.102: R2118.1 130.88,80.65 130.94,80.59 130.94,80.59 v2(130.96,80.57) 130.99,80.54 131.41,80.12 R2117.2 131.8,79.11 v1(132.26,79.11)
  BOTTOM w0.102: v2(130.96,80.57) 130.99,80.54 131.31,80.21 CPU1.CG17
PROJECT_ID3: length 23.9
  BOTTOM w0.102: CPU1.CN20 135,77.91 135.4,77.91 135.56,77.97 136.37,77.97 137.79,79.39 v1(143.38,79.39) 150.37,79.39 150.81,78.95 154.86,78.95 R2115.2 155.73,78.63 156.34,78.63 R2116.1
PS175_CEC_EN: length 14.8
  TOP w0.102: R5757.2 32.59,55.9 31.83,56.66 v2(31.75,56.66) 31.75,56.74 31.36,57.13 31.36,58.69 31.24,58.81 31.24,59.7 30.21,60.72 29.54,60.72 U5701.E7
  BOTTOM w0.102: R5756.2 29.11,54.74 29.11,55.95 30.18,57.02 30.58,57.02 30.84,57.27 30.84,57.85 v1(31.22,58.23) 31.75,57.7 v2(31.75,56.66)
PS175_CSCL: length 3.6
  TOP w0.089: U5701.E6 28.75,61.46 v2(28.75,61.49)
  BOTTOM w0.089: v2(28.75,61.49) 29.17,61.07 29.47,61.07 29.83,60.75 v1(30.56,60.75) 30.61,60.7 30.61,60.47 30.48,60.34 R5739.2
PS175_CSDA: length 2.6
  TOP w0.089: U5701.F6 28.38,60.3 v2(28.78,60.7)
  BOTTOM w0.089: v2(28.78,60.7) 28.8,60.72 v1(29.34,60.72) 29.59,60.47 29.92,60.47 30.01,60.38 30.01,60.18 R5738.2
PS175_PD#: length 42.3
  TOP w0.102: v2(13.08,55.77) 15.24,55.77 17.27,57.8 17.27,58.59 17.37,58.69 19.56,58.69 19.8,58.45 19.8,55.73 19.81,55.72 19.81,52.65 v1(21.74,50.72) 22.33,50.72 R5744.1 22.68,52.75 22.78,52.85 v2(23.24,52.85) ; v2(25.58,62.29) U5701.C3
  L6 w0.102: v2(25.58,62.29) 25.53,62.29 23.74,64.08 23.06,64.08 21.6,62.61 21.6,54.49 v2(23.24,52.85)
  BOTTOM w0.102: R5736.2 24.84,63.09 25.22,62.7 25.22,62.68 25.59,62.31 25.59,62.3 v2(25.58,62.29) ; Q5705.3 14.41,58.63 13.46,57.68 13.46,56.91 12.83,56.28 12.83,56.03 v2(13.08,55.77)
PS175_RST#: length 21
  TOP w0.102: R5744.2 28.21,51.07 28.7,51.57 28.7,52.09 28.05,52.74 28.05,54.49 v2(28.57,55.01) ; U5701.B8 31.53,63.49 v2(31.88,63.14)
  BOTTOM w0.102: v2(28.57,55.01) 28.57,55.77 30.23,57.42 C5725.1 30.28,57.45 R5737.2 30.35,58.18 31.37,59.2 v1(31.37,59.48) 31.29,59.56 31.29,60.65 31.88,61.23 v2(31.88,63.14)
PS_ID: length 81.9
  TOP w0.635: R4305.2 v1(50.16,14.29) 49.64,14.29 v2(49.28,14.66)
  L4SGND w0.508: v2(49.28,14.66) 47.66,16.27 44.85,16.27 40.61,20.52 40.08,20.52 36.08,24.52 v2(36.08,25.55)
  L6 w0.635: v2(36.08,25.55) 36.45,25.55 39.12,28.21 39.12,30.94 39.88,31.7 40.73,31.7 43.09,29.34 80.28,29.34 v2(84.96,24.66)
  BOTTOM w0.178: U2401.36 86.31,22.56 84.96,23.91 v2(84.96,24.66)
  BOTTOM w0.508: v2(49.28,14.66) 49.29,14.65 D4302.3 51.11,14.65 51.44,14.98
PS_ID_R: length 102.2
  TOP w0.102: AFTP4304.1 28.32,81.09 EC4311.1 28.27,80.87 27.81,80.41 v2(27.43,80.41) ; R4317.1 52.55,19.88 37.08,19.88 35.51,18.31 v2(33.53,18.31)
  L6 w0.102: v2(33.53,18.31) 33.53,20.12 33.71,20.3 33.71,21.15 31.04,23.82 30.33,23.82 28.31,25.83 28.31,28.32 26.98,29.66 26.49,29.66 26.42,29.74 24.8,29.74 24.66,29.88 24.66,30.35 24.7,30.39 24.7,31.32 24.13,31.9 23.38,31.9 19.7,35.57 19.7,35.74 19.7,69.48 27.43,77.21 v2(27.43,80.41)
  BOTTOM w0.102: DCIN1.4 25.65,79.77 26.29,80.41 v2(27.43,80.41)
PS_ID_R1: length 4.3
  TOP w0.102: v2(53,13.35) 52.06,14.29 R4305.1 52.04,15.11 v1(52.2,15.26) 52.7,15.77 R4306.2
  BOTTOM w0.102: v2(53,13.35) Q4301.S
PS_ID_R2: length 4.9
  BOTTOM w0.508: v2(54.74,14.65) Q4301.D ; D4303.2 D4303.1
  BOTTOM w0.635: D4303.1 53.81,15.92 v1(53.96,15.77) 53.95,15.76 Q4301.D
PSID_DISABLE#_R_C: length 6.1
  TOP w0.635: R4310.2 57.43,13.02 v2(57.43,13.99)
  BOTTOM w0.508: v2(57.43,13.99) Q4302.C v1(56.13,14.86) 54.9,13.62 Q4301.G
PTP_DIS#: length 55.5
  TOP w0.102: AFTP6537.1 142.68,7.96 v2(142.68,7.32)
  L4SGND w0.102: v2(99.69,6.89) 101.64,6.89 102.54,7.79 105.31,7.79 105.36,7.74 106.36,7.74 107.36,6.75 113.32,6.75 116.37,3.7 139.83,3.7 142.68,6.56 142.68,7.32 v2(142.68,7.32)
  BOTTOM w0.102: U2401.90 98.38,10.49 98.12,10.6 97.65,10.6 97.4,10.35 97.4,8.55 98.56,7.38 99.19,7.38 99.68,6.89 v2(99.69,6.89) ; v2(142.68,7.32) 142.85,7.49 TP1.3
PU4348_G: length 9.4
  TOP w0.254: v2(27.18,26.36) 27.64,26.82 v1(27.81,26.82) 28.4,27.41 30.78,27.41 v2(31.62,26.56)
  BOTTOM w0.254: v2(27.18,26.36) 26.97,26.56 R4370.2 26.47,26.54 R4369.1 ; v2(31.62,26.56) 31.62,25.61 Q4348.G
PURE_HW_SHUTDOWN#: length 185.7
  TOP w0.102: v2(146.69,98.82) 147.19,98.32 148.29,98.32 C2610.1 148.92,98.16 R2615.1 149.48,97.86 153.49,97.86 154.76,99.13 156.66,99.13 158.92,96.87 158.92,87.98 164.43,82.47 164.43,77.43 164.19,77.19 164.19,75.94 164.4,75.72 164.4,70.13 163.89,69.62 163.89,57.43 163.89,57.21 162.64,55.95 162.64,50.26 163,49.89 163,47.45 162.64,47.09 162.64,45.92 162.41,45.69 162.41,45.19 161.87,44.65 161.87,42.11 v2(161.93,42.06)
  L6 w0.102: v2(112.27,8.78) 112.27,9.31 113.48,10.52 126.66,10.52 126.76,10.42 127.77,10.42 129.41,8.78 129.9,8.78 130.56,8.12 132.9,8.12 133.16,7.87 136.68,7.87 138.41,6.13 156.66,6.13 163.58,13.05 163.58,14.62 168.78,19.83 168.78,31.78 166.54,34.03 166.54,37.06 161.93,41.68 v2(161.93,42.06)
  BOTTOM w0.102: D4001.K 105.05,18.89 R4014.2 105.66,18.64 106.88,18.64 v1(107.12,18.88) 107.68,19.44 111.01,19.44 111.25,19.2 111.25,17.29 109.98,16.02 109.98,14.88 111,13.86 111,11.32 111.76,10.56 111.76,9.29 v2(112.27,8.78) ; Q2602.D 145.61,98.81 146.67,98.81 v2(146.69,98.82)
PWR_0D6V_S3EN: length 3.9
  TOP w0.254: v1(48.01,26.05) 48.26,26.05 48.39,25.93 v2(48.64,25.93) PR5126.2 PR5125.2
  BOTTOM w0.254: PU5102.7 48.39,26.12 48.59,25.93 v2(48.64,25.93) 48.79,25.77 PC5120.1
PWR_0D6V_S5EN: length 3.5
  TOP w0.127: PR5114.2 49.37,24.38 v2(48.64,25.11)
  TOP w0.254: v2(48.64,25.11) 48.35,25.11 v1(47.98,24.74)
  BOTTOM w0.254: PU5102.9 48.63,25.12 v2(48.64,25.11) 48.74,25.01 PC5119.1
PWR_0D6V_VTT_CNTL: length 3.4
  TOP w0.508: v2(48.62,24.28) 48.4,24.06 v1(48.4,23.6) 49.37,23.6 PR5118.2
  BOTTOM w0.279: PU5102.10 48.27,24.62 v2(48.62,24.28) 48.64,24.25 PC5121.1
PWR_1D0V_BT: length 1.6
  BOTTOM w0.254: PC5204.1 176.23,59.45 176.18,59.45 176.03,59.3 PU5201.20
PWR_1D0V_FB: length 4
  BOTTOM w0.254: PU5201.5 178.56,56.16 179.2,55.53 179.2,55.31 ; v1(179.17,55.29) 179.2,55.31 ; 179.2,55.31 179.32,55.19 PR5204.1 180.72,55.19 PR5202.2 180.87,55.34 PC5212.2
PWR_1D0V_FB_A: length 20.8
  TOP w0.254: v2(177.13,68.62) 177.11,68.62 177.04,68.7 175.54,68.7 PG5223.2
  L4SGND w0.254: v2(177.13,68.62) 177.62,68.62 179.07,67.18 179.07,62.63 180.49,59.07 181.66,56.43 v2(182.75,55.34)
  BOTTOM w0.254: v2(182.75,55.34) 182.5,55.09 v1(182.5,54.63) 182.3,54.42 PC5212.1 180.87,54.42 PR5202.1
PWR_1D0V_PFM: length 3.7
  BOTTOM w0.254: PR5203.1 v1(180.04,56.15) 179.6,56.58 179.6,56.63 179.07,57.16 PU5201.3
PWR_1D0V_PG: length 3.2
  BOTTOM w0.178: PU5201.1 178.39,58.16 v1(179.15,58.92) 179.2,58.87 179.27,58.87 179.58,58.57 PR5209.2
  BOTTOM w0.254: PR5209.2 PR5208.2
PWR_1D0V_PH:
  vias: v1(173.99,59.96)
PWR_1D0V_SS: length 3.9
  BOTTOM w0.254: PU5201.22 178.4,58.84 179.15,59.58 179.53,59.58 PC5213.1 v1(180.84,60.39)
PWR_1D0V_TON: length 2.5
  BOTTOM w0.254: PU5201.6 178.2,54.15 PR5201.2 178.36,53.99 v1(179.1,53.99)
PWR_1D8V_POK: length 4.4
  BOTTOM w0.254: PU5301.7 38.35,19.45 v1(38.1,19.2) 37.47,18.56 PR5302.2 PR5308.2
PWR_2D5V:
  vias: v1(139.45,27.83)
PWR_2D5V_FB: length 3.4
  BOTTOM w0.254: PU5303.2 135.5,27.57 136.27,28.34 PR5320.1 PR5319.2 137.06,28.39 PC5311.2
PWR_3D3V:
  vias: v1(114.94,22.75)
PWR_3D3V_BOOT: length 4.3
  BOTTOM w0.254: PR4501.1 124.21,25.57 124.21,23.79 124.53,23.46 v1(124.71,23.46) 125.11,23.46 125.57,23 PU4501.1
PWR_3D3V_BOOT_A: length 2.6
  BOTTOM w0.508: PC4506.1 121.74,26.46 v1(121.67,26.53) 121.71,26.56 122.43,26.56 122.66,26.33 PR4501.2
PWR_3D3V_EN: length 4.9
  BOTTOM w0.254: PR4509.2 PR4508.1 129.74,18.66 PC4508.1 128.27,18.69 v1(128.14,18.56) 128.14,18.81 127.37,19.59 PU4501.11
PWR_3D3V_FB: length 4.4
  BOTTOM w0.254: PU4501.13 126.47,18.59 126.72,18.33 v1(126.82,18.33) 126.82,18.23 127.13,17.93 128.47,17.93 PC4533.1
PWR_3D3V_FB2: length 2.1
  BOTTOM w0.254: PC4533.2 128.07,17.11 v1(127.48,16.53) 127.3,16.71 PR4506.2
PWR_3D3V_LDO: length 3.3
  BOTTOM w0.508: PG4519.1 PC4507.1 123.98,18.08 v1(124.71,18.81) 124.71,19.5
PWR_3D3V_PH: length 7.4
  TOP w0.508: v2(124.46,22.62) v1(127.3,22.62) 128.14,22.62 v2(128.65,22.12)
  BOTTOM w0.254: PU4501.6 128.64,22.13 v2(128.65,22.12)
  BOTTOM w0.508: PC4506.2 120.95,25.42 120.95,23.46
PWR_3D3V_VOUT: length 18
  BOTTOM w0.254: PU4501.14 126.02,18.15 126.44,17.72 PR4506.1 126.44,16.91 126.06,16.53 122.11,16.53 121.73,16.91 121.73,16.99 121.54,17.17 120.21,17.17 120.2,17.16 v1(114,17.16) PG4530.1
PWR_3V_PG: length 5.7
  TOP w0.254: PG4531.2 127.76,20.16 v1(127.76,20.72) 128.65,20.72 v2(128.78,20.59)
  BOTTOM w0.254: PU4501.9 128.47,20.78 128.65,20.59 v2(128.78,20.59) ; PU4501.10 128.51,20.33 v2(128.78,20.59) ; v2(128.78,20.59) 128.85,20.52 PR4505.2
PWR_5V:
  vias: v1(76.58,21.86) v3(76.02,21) v3(76.15,22.93) v3(77.06,21) v3(77.19,22.93)
PWR_5V_BOOT: length 3
  BOTTOM w0.254: 64.87,18.46 64.4,18.93 PU4502.1
  BOTTOM w0.508: 64.87,18.46 v1(64.87,18.05) PR4502.1
PWR_5V_BOOT_A: length 2.1
  BOTTOM w0.508: PC4521.1 67.87,17.04 v1(67.31,17.04) 66.45,17.04 PR4502.2
PWR_5V_EN: length 5.2
  BOTTOM w0.254: PR4511.2 PR4512.1 59.51,23.87 PC4530.1 v1(60.33,23.13) 61.98,23.13 62.6,22.51 PU4502.11
PWR_5V_EN1_R: length 89.8
  TOP w0.254: v2(132.72,21.74) 132.72,21.24 130.22,18.74 129.34,18.74 v1(129.29,18.69) 129.24,18.74 PR4503.2 PR4515.1
  BOTTOM w0.254: v2(132.72,21.74) 132.84,21.86 132.84,26.31 130.09,29.06 59.65,29.06 58.12,27.53 PR4530.1 PR4504.1
PWR_5V_FB: length 5.1
  BOTTOM w0.254: PU4502.13 63.5,23.09 62.19,24.4 v1(61.98,24.4) 61.34,25.04 PR4551.1 62.08,25.49 PC4526.1
PWR_5V_FB_A: length 2.2
  BOTTOM w0.254: PC4526.2 62.1,27.07 v1(62.36,27.32) 62.87,26.82 PR4507.1
PWR_5V_LDO: length 3.5
  TOP w0.305: 62,24.4 PG4528.1
  TOP w0.508: 62,24.4 64.48,24.4 v2(64.64,24.24)
  vias: v1(64.52,23.39)
PWR_5V_PG: length 5.6
  TOP w0.254: PG4529.2 60.07,23.08 PR4510.1 60.73,22.68 60.73,22.67 v1(61.2,22.67) 61.21,22.67 61.21,22.63 61.21,22.62 v2(61.21,22.12)
  BOTTOM w0.254: PU4502.9 61.62,21.3 61.45,21.46 61.45,21.62 61.21,21.86 v2(61.21,22.12) 61.34,22.24 61.91,22.24 62.09,22.06 62.09,21.86 PU4502.10
PWR_5V_PH: length 17.3
  TOP w0.254: v1(61.09,18.94) 61.09,19.45 v2(61.21,19.58)
  L6 w1.016: v2(61.21,19.58) 66.55,19.58 67.73,20.76 v2(67.73,24.28)
  BOTTOM w0.254: PL4502.2 v2(67.73,24.28) ; PU4502.6 61.58,19.95 v2(61.21,19.58)
  BOTTOM w0.508: 69.04,18.61 PC4521.2
PWR_5V_VCC: length 2.9
  BOTTOM w0.508: 65.48,22.34 65.78,22.65 v1(65.78,23.64) 65.78,24.76 PC4524.1
PWR_5V_VOUT: length 24.1
  BOTTOM w0.254: PU4502.14 63.95,23.32 62.87,24.4 PR4507.2 63.37,26 v1(63.37,28.34) 63.59,28.55 77.51,28.55 78.87,27.2 PG4527.1
PWR_CHG_ACIN: length 5.2
  TOP w0.203: PU4401.19 33.02,46.78 31.53,46.78 31.32,46.98 31.32,47.21 v1(31.32,47.21)
  TOP w0.254: v1(31.32,47.21) 31.32,47.21 31.32,47.64 30.68,48.28 PC4420.1 30.4,48.25 PR4406.1 PR4404.2
PWR_CHG_ACOK: length 20.6
  TOP w0.203: PU4401.24 32.89,44.85 32.38,44.34
  TOP w0.254: v2(28.83,34.56) 28.83,35.83 v1(28.96,35.96) 29.34,36.34 29.34,37.31 29.04,37.61 28.31,37.61 27.81,38.11 27.81,42.14 28.87,43.2 v2(29.01,43.2) 29.06,43.25 PG4408.1 31.29,43.25 32.38,44.34
  BOTTOM w0.254: PR4488.2 PR4426.1 29.41,33.98 v2(28.83,34.56) ; PR4429.2 PR4463.2 30.56,44.54 29.21,43.2 v2(29.01,43.2)
PWR_CHG_AIN: length 39.6
  TOP w0.254: PR4404.1 29.41,46.88 28.85,46.88 28.3,46.33 28.3,46.27 28.07,46.04 28.07,45.35 27.21,44.49 27.21,43.81 26.04,42.63 26.04,41.32 25.53,40.81 25.53,39.43 25.78,39.18 v1(25.78,38.5) 24.28,37 24.28,33.01 25.78,31.51 25.78,30.07 24.65,28.93 24.65,28.51 25.32,27.83 25.87,27.83 26.69,28.65 30.11,28.65 32.21,30.75 v2(34.42,30.75)
  BOTTOM w0.254: v2(34.42,30.75) 34.54,30.88 38.46,30.88 38.99,31.41 PD4408.3
PWR_CHG_AMON: length 4.1
  TOP w0.203: PU4401.29 35.25,43.92 35.23,43.9 35.23,43.07 35.15,42.99
  TOP w0.254: PR4412.1 33.66,41.84 34.12,42.31 35.15,42.31 v1(35.25,42.21) 35.25,42.29 35.15,42.39 35.15,42.99
PWR_CHG_ASGATE: length 2.8
  TOP w0.203: PU4401.13 34.85,48.67 34.55,48.98 34.55,49.55 34.38,49.71 34.38,49.89 TP4401.1
PWR_CHG_BATGONE: length 6.3
  TOP w0.203: 32,43.33 32.28,43.6 33.17,43.6 33.65,44.08 PU4401.25
  TOP w0.254: PR4409.1 30.53,40.63 PC4430.1 30.56,41.61 v1(30.48,41.69) 30.48,41.8 32,43.33
PWR_CHG_BGATE: length 140.6
  TOP w0.203: PU4401.32 36.45,43.58 v2(36.58,43.45)
  L4SGND w0.254: v2(144.27,20.72) 144.02,20.47 142.39,20.47 139.85,23 139.13,23 135.57,26.56 114.89,26.56 111.84,23.51 107.6,23.51 106.97,22.89 98.54,22.89 97.95,22.29 82.46,22.29 80.64,20.48 80.64,19.45 79.98,18.79 78.46,18.79 77.34,17.67 75.04,17.67 74.15,16.78 56.52,16.78 53.35,19.96 47.75,19.96 37.83,29.87 37.83,33.01 35.39,35.45 35.05,35.45 33.91,36.59 33.91,40.66 35.41,42.16 36.22,42.16 36.58,42.51 v2(36.58,43.45)
  BOTTOM w0.254: v1(144.75,21.07) 144.4,20.72 v2(144.27,20.72) 143.91,20.35 PU4412.4 ; v2(36.58,43.45) 36.58,43.88 PC4429.1
PWR_CHG_BOOT1: length 3.2
  TOP w0.203: PU4401.12 35.25,48.74 34.92,49.06 34.92,49.78 v1(35,49.85)
  TOP w0.508: v1(35,49.85) 35.69,50.54 PR4402.1
PWR_CHG_BOOT2: length 3.6
  TOP w0.203: PU4401.4 37.64,46.05 38.05,45.64 38.2,45.64
  TOP w0.508: 38.2,45.64 38.35,45.48 v1(38.86,45.48) 39.14,45.48 PR4408.1
PWR_CHG_BT1_R: length 3.3
  TOP w0.635: v2(36.96,52.72) 37.21,52.47 v1(37.21,51.83) 37.19,51.86 PR4402.2
  BOTTOM w0.508: v2(36.96,52.72) 36.58,52.34 PC4436.1
PWR_CHG_BT2_R: length 3.8
  TOP w0.508: 41.4,48.07 v1(41.33,48.15)
  TOP w0.635: v1(41.33,48.15) 40.49,48.15 PR4408.2 ; v2(41.4,46.88) 41.4,48.07
  BOTTOM w0.508: PC4423.1 40.77,46.25 v2(41.4,46.88)
PWR_CHG_COMP: length 4.2
  TOP w0.203: PU4401.28 34.85,43.67 34.25,43.08 34.25,43 v1(34.2,42.95)
  TOP w0.254: PR4411.1 32.87,41.72 PC4433.1 32.89,41.86 33.3,42.26 33.51,42.26 v1(34.2,42.95)
PWR_CHG_COMP_R: length 2
  TOP w0.254: v1(32.11,39.06) 32.11,39.11 31.93,39.29 PC4431.1 32.13,40.23 PR4411.2
PWR_CHG_CSIN: length 6.1
  TOP w0.203: v2(34.04,49.29) 34.21,49.12 34.21,48.84 34.45,48.6 PU4401.14
  BOTTOM w0.254: v1(33.91,48.66) 33.91,49.17 v2(34.04,49.29) PC4417.2 34.04,51.43 PC4415.1 34.67,52.11 PR4423.2
PWR_CHG_CSIN_R: length 17.3
  TOP w0.254: v2(35.56,53.46) 35.62,53.46 36.42,54.27 36.42,63.62 38.1,65.3 38.86,65.3 v2(38.99,65.17)
  BOTTOM w0.254: PG4402.2 37.64,65.22 v1(37.72,65.3) 38.86,65.3 v2(38.99,65.17) ; PR4423.1 35.04,53.67 35.38,53.53 35.49,53.53 v2(35.56,53.46)
PWR_CHG_CSIP: length 6.5
  TOP w0.203: v2(33.4,49.29) 33.4,49.18 34.05,48.53 PU4401.15
  TOP w0.254: v1(32.77,49.29) v2(33.4,49.29)
  BOTTOM w0.254: PR4422.2 33.91,52.62 PC4415.2 32.94,51.66 PC4416.2 32.94,49.75 v2(33.4,49.29)
PWR_CHG_CSIP_R: length 17.6
  TOP w0.254: v2(38.99,65.8) 38.86,65.68 37.94,65.68 36.04,63.78 36.04,54.6 v2(35.59,54.15)
  BOTTOM w0.254: v2(38.99,65.8) 38.86,65.8 38.52,66.14 v1(38.52,66.25) 38.42,66.25 37.72,66.95 PG4401.2 ; PR4422.1 34.16,54.3 34.16,54.43 34.31,54.58 35.15,54.58 v2(35.59,54.15)
PWR_CHG_CSON: length 7.4
  TOP w0.203: PU4401.1 37.01,44.41 v2(37.08,44.34)
  BOTTOM w0.254: PR4425.1 35.94,39.82 35.94,40.99 36.8,41.85 PC4426.2 37.13,42.28 PC4425.2 37.08,42.99 v2(37.08,44.34) 37.08,44.72 v1(37.34,44.98)
PWR_CHG_CSON_R: length 124.3
  L4SGND w0.254: v2(142.88,20.97) 142.88,21.56 140.67,23.77 139.45,23.77 135.89,27.32 114.5,27.32 112.73,25.55 107.16,25.55 105.28,23.67 98.24,23.67 97.64,23.06 82.06,23.06 78.17,26.94 58.53,26.94 58.03,27.45 50.3,27.45 49.87,27.03 41.76,27.03 38.6,30.19 38.6,33.62 35.25,36.96 v2(35.2,36.96)
  BOTTOM w0.254: v2(35.2,36.96) 36.24,38 PR4425.2 ; PG4406.1 142.49,20.59 v2(142.88,20.97) 143.48,20.97 v1(143.51,20.95)
PWR_CHG_CSOP: length 8.6
  TOP w0.203: v2(37.72,44.34) 37.72,44.9 37.37,45.25 PU4401.2
  TOP w0.254: v1(37.72,43.71) v2(37.72,44.34)
  BOTTOM w0.254: v2(37.72,44.34) 37.72,43.27 PC4425.1 37.97,42.87 PC4424.2 38.89,41.04 38.89,40.29 37.66,39.06 PR4424.1
PWR_CHG_CSOP_R: length 124.5
  L4SGND w0.254: v2(35.18,36.31) 38.21,33.28 38.21,30.03 41.6,26.65 50.03,26.65 50.45,27.07 57.87,27.07 58.38,26.56 77.85,26.56 81.74,22.67 97.79,22.67 98.38,23.27 106.81,23.27 107.44,23.89 111.68,23.89 114.73,26.94 135.73,26.94 139.29,23.39 140.34,23.39 v2(142.24,21.48)
  BOTTOM w0.254: PG4405.1 140.89,20.01 141.68,20.8 v1(141.68,20.8) 141.69,20.8 142.24,21.35 v2(142.24,21.48) ; v2(35.18,36.31) 35.2,36.34 35.94,36.34 37.47,37.86 PR4424.2
PWR_CHG_DCIN: length 4.7
  TOP w0.203: PU4401.17 32.97,47.65 32.51,48.1 v2(32.51,48.28)
  TOP w0.254: v1(31.95,48.28) v2(32.51,48.28)
  BOTTOM w0.254: PR4403.1 31.32,49.22 PC4419.1 31.5,49.29 v2(32.51,48.28)
PWR_CHG_DCIN_R: length 32.6
  L4SGND w0.254: v2(28.7,48.15) 28.79,48.15 30.23,46.71 30.23,41.17 29.72,40.66 29.72,33.12 33.27,29.57 v2(33.27,29.1)
  BOTTOM w0.254: PD4401.3 38.82,29.44 38.29,28.91 37.83,28.91 PD4407.K 37.55,28.97 v1(36.58,28.97) 36.47,28.87 36.47,26.71 36.2,26.43 35.69,26.43 34.92,27.2 34.92,28.09 34.04,28.97 33.4,28.97 v2(33.27,29.1) ; v2(28.7,48.15) 28.83,48.15 29.34,47.64 PR4403.2
PWR_CHG_HG1_R: length 1.2
  TOP w0.254: v1(41.73,64.99) 42.65,64.99 PR4414.2
PWR_CHG_HG2_R:
  vias: v1(45.21,56.56)
PWR_CHG_LGATE1: length 12.4
  TOP w0.203: 37.08,48.79 36.96,48.79 36.45,48.28 PU4401.9
  TOP w0.305: v3(37.85,49.55) 37.08,48.79
  L6 w0.635: v3(43.12,56.09) 42.29,55.26 42.29,52.34 40.77,50.82 39.12,50.82 v3(37.85,49.55)
  BOTTOM w0.254: v3(37.85,49.55) 37.69,49.7 v1(37.69,50.21)
PWR_CHG_LGATE2: length 34.3
  TOP w0.203: PU4401.7 37.45,47.25 v3(37.97,47.77)
  L6 w0.635: v3(37.97,47.77) 37.85,47.77 37.21,47.14 37.21,45.87 37.85,45.23 40.77,45.23 50.72,55.19 50.72,62.76 50.09,63.39 v3(46.35,63.39)
  BOTTOM w0.254: v1(37.3,47.63) 37.44,47.77 v3(37.97,47.77)
PWR_CHG_OTGEN: length 2.9
  TOP w0.203: PU4401.20 31.82,46.45 v1(31.37,45.99)
  TOP w0.254: PR4417.2 v1(31.37,45.99)
PWR_CHG_OTGPG: length 1.7
  TOP w0.203: TP8304.1 33.05,43.22 33.37,43.22 34.05,43.91 PU4401.26
PWR_CHG_PHASE1: length 22.3
  TOP w0.203: PU4401.10 36.05,48.9 v3(36.45,49.29)
  TOP w0.508: PR4416.1 40.82,59.28 PU4404.5
  L6 w0.635: v3(36.45,49.29) 36.45,49.93 39.24,52.72 39.24,56.03 40.39,57.17 40.39,59.2 43.05,61.87 v3(43.69,61.87)
  BOTTOM w0.254: v3(36.45,49.29) 36.6,49.14 v1(36.6,48.63)
  BOTTOM w0.508: PC4436.2 36.58,49.42 v3(36.45,49.29)
  vias: v3(43.69,60.98) v3(43.69,60.09) v3(43.69,59.2) v3(43.69,58.31) v3(43.69,57.42)
PWR_CHG_PHASE2: length 17.4
  TOP w0.203: PU4401.6 37.68,46.85 38.02,47.19 38.91,47.19 v3(38.99,47.26)
  TOP w0.254: v1(38.91,47.92) 38.99,47.84 v3(38.99,47.26)
  L6 w0.635: v3(38.99,47.26) 45.47,53.74 45.47,57.42 v3(45.85,57.8)
  BOTTOM w0.508: v3(38.99,47.26) 39.34,46.91 PC4423.2
  vias: v3(45.85,62.25) v3(45.85,61.36) v3(45.85,60.47) v3(45.85,59.58) v3(45.85,58.69)
PWR_CHG_PROCHOT#: length 14.5
  TOP w0.089: v2(28.96,43.83) 29.77,43.83 PR4435.2 31.5,44.47 32.27,45.25 PU4401.23
  BOTTOM w0.089: v2(28.96,43.83) 28.53,43.41 28.53,42.37 28.93,41.97 31.29,41.97 32.15,41.11 v1(32.15,38.9) 32.48,38.58 32.48,37.66 32.38,37.56 PQ4416.2
PWR_CHG_PROCHOT#_R: length 4.4
  BOTTOM w0.089: PQ4416.6 31.73,34.83 31.72,34.82 ; PR4472.2 v1(30.66,35.15) 30.99,34.82 31.72,34.82 ; PQ4416.5 32.38,35.3 31.9,34.82 31.72,34.82
PWR_CHG_PROG: length 4.6
  TOP w0.203: 33.15,42.69 33.37,42.69 34.45,43.78 PU4401.27
  TOP w0.254: 33.15,42.69 32.08,42.69 v1(31.98,42.59) 31.37,41.98 PR4410.2
PWR_CHG_SNB: length 2.1
  TOP w0.508: PC4435.1 38.91,56.53 v1(38.1,56.53) 38.1,57.22 PR4416.2
PWR_CHG_UGATE1: length 20.2
  TOP w0.203: v3(35.56,49.29) 35.65,49.2 PU4401.11
  L6 w0.635: v3(44.32,63.39) 43.31,63.39 39.24,59.33 39.24,57.55 38.35,56.66 38.35,53.1 35.5,50.25 35.5,49.35 v3(35.56,49.29)
  BOTTOM w0.254: v3(35.56,49.29) 35.23,48.96 v1(35.23,48.68)
PWR_CHG_UGATE2: length 15.2
  TOP w0.203: v3(38.35,46.37) 38.28,46.45 PU4401.5
  TOP w0.635: PR4420.1 46.81,54.07 v3(46.61,53.87)
  L6 w0.635: v3(38.35,46.37) 39.88,46.37 46.61,53.1 v3(46.61,53.87)
  BOTTOM w0.254: v1(37.69,46.32) 38.3,46.32 v3(38.35,46.37)
PWR_CHG_VBAT1: length 4
  TOP w0.203: v2(35.94,43.45) 36.05,43.56 PU4401.31
  BOTTOM w0.508: PR4478.1 34.32,43.68 PC4440.1 34.92,44.47 v1(35.37,44.02) v2(35.94,43.45)
PWR_CHG_VBATIN:
  vias: v1(143.84,15.03)
PWR_CHG_VDDP: length 5
  TOP w0.203: 37.27,48.1 37.01,47.83 PU4401.8
  TOP w0.305: v2(38.61,48.66) 37.84,48.66 37.27,48.1
  BOTTOM w0.508: PR4405.1 39.98,48.43 39.98,49.29 PC4421.1 39.37,49.42 v1(39.07,49.12) v2(38.61,48.66)
PWR_DCBATOUT_1D0V:
  vias: v1(170.43,54.17)
PWR_DCBATOUT_3D3V:
  vias: v1(128.65,24.91)
PWR_DCBATOUT_5V:
  vias: v1(60.45,17.42)
PWR_DCBATOUT_VCCGTA:
  vias: v1(56.03,83.56) v2(58.98,83.94) v2(58.98,83.3) v2(58.98,82.67) v2(59.05,74.8) v2(59.05,74.16) v2(59.05,73.53) v3(56.01,76.35) v3(56.13,85.86) v3(56.9,75.84) v3(57.02,85.49) v3(57.53,86.38) v3(57.78,76.73) v3(57.78,75.84) v3(57.91,77.74) v3(58.03,85.49)
PWR_DCBATOUT_VCCSA: length 1.4
  BOTTOM w0.254: PC5003.1 147.12,105.05 v1(148.46,105.05)
PWR_DCBATOUT_VCORE:
  vias: v1(57.57,65.8) v2(59.05,63.37) v2(59.05,62.73) v2(59.05,62.1)
PWR_DCBATOUT_VDDQ:
  vias: v1(156.46,27.32)
PWR_VCCGT_BOOTA: length 4.6
  BOTTOM w0.305: PU4801.5 57.15,82.56 v1(56.01,83.71) 56.01,83.8 54.58,85.24 PR4804.2
PWR_VCCGT_BOOTA_RC: length 2.8
  BOTTOM w0.508: PR4804.1 52.94,85.24 51.99,86.18 v1(51.99,86.38) 52.93,86.38 PC4808.1
PWR_VCCGT_BOOTB: length 2.8
  BOTTOM w0.305: PU4802.5 57.25,73.42 v1(56.69,72.87) 56.67,72.87 55.7,71.9 PR4810.2
PWR_VCCGT_BOOTB_RC: length 1.3
  BOTTOM w0.508: PC4811.1 PR4810.1
PWR_VCCGT_BOOTRA: length 4.6
  BOTTOM w0.305: PC4808.2 54.46,86.51 v1(55.55,85.41) 57.4,83.56 PU4801.7
PWR_VCCGT_BOOTRB: length 2.6
  BOTTOM w0.305: PC4811.2 56.57,74.08 v1(56.59,74.08) 56.93,74.42 PU4802.7
PWR_VCCGT_COMP: length 8.5
  TOP w0.254: v2(49.15,80.41) 49.15,80.49 49.33,80.67 PC4610.2 48.64,81.04 v1(48.39,81.3) 48.64,81.55 49.23,81.55 PR4626.2
  BOTTOM w0.203: 48.01,79.09 48.03,79.06 48.03,78.51 48.27,78.27 48.27,77.27 47.56,76.56 PU4601.4
  BOTTOM w0.254: 48.01,79.09 48.01,79.55 48.86,80.41 v2(49.15,80.41)
PWR_VCCGT_COMP1: length 3.9
  TOP w0.254: PC4651.1 PC4612.1 49.94,83.41 v1(50.39,82.95) 50.34,82.9 PR4626.1
PWR_VCCGT_FB: length 5
  TOP w0.254: PR4636.2 50.16,74.87 PR4633.2 50.04,75.53 PR4630.2 49.53,75.84 48.9,76.47 v2(48.77,76.47)
  BOTTOM w0.203: PU4601.5 48.25,76.16 v1(48.26,76.17)
  BOTTOM w0.254: v2(48.77,76.47) 48.51,76.47 48.26,76.22 v1(48.26,76.17)
PWR_VCCGT_FB1: length 1.9
  TOP w0.254: PC4614.1 51.51,76.4 51.51,75.86 51.46,75.81 v1(51.46,75.79) 50.64,75.79 PR4630.1
PWR_VCCGT_FB2: length 5.3
  TOP w0.254: PR4665.2 49.15,72.59 v1(49.15,73.42) 49.61,73.42 PC4619.1 50.44,72.59 PC4615.2 50.88,72.74 PR4631.1 50.88,73.55 50.85,73.58 PC4618.2 50.85,74.19 50.09,74.19 PR4633.1
PWR_VCCGT_FB_RC: length 2.2
  TOP w0.254: PC4618.1 52.37,74.11 52.63,74.36 v1(52.63,74.47) 52.63,74.52 52.27,74.87 PR4636.1
PWR_VCCGT_FCCM#: length 38.3
  TOP w0.254: v1(57.28,71.52) v2(57.28,70.88)
  L4SGND w0.254: v2(52.7,82.7) 52.32,82.7 51.18,81.55 51.18,80.37 51.56,79.98 51.56,71.4 53.48,69.49 54.36,69.49 56.26,71.39 56.85,71.39 57.28,70.97 v2(57.28,70.88) 57.28,70.63 55.5,68.85 53.09,68.85 51.71,70.22 47.14,70.22 46.23,71.14 46.23,71.77 46.48,72.03 v2(46.74,72.03)
  BOTTOM w0.203: PU4601.11 46.38,73.32 46.84,72.86 46.84,72.13 v2(46.74,72.03)
  BOTTOM w0.254: PR4812.1 57.28,70.58 v2(57.28,70.88) ; v2(52.7,82.7) PR4806.1
PWR_VCCGT_FCCM#_RA: length 4
  BOTTOM w0.254: PU4801.2 56.93,81.06 v1(55.32,82.67) 55.3,82.7 PR4806.2
PWR_VCCGT_FCCM#_RB: length 4.4
  BOTTOM w0.254: PU4802.2 57.4,71.92 56.88,71.39 56.43,71.39 56.18,71.14 55.58,71.14 v1(55.04,70.6) 55.52,70.12 PR4812.2
PWR_VCCGT_IMON: length 9.8
  BOTTOM w0.203: PU4601.2 47.36,77.36 47.56,77.57 47.56,77.97 47.37,78.16 47.37,78.66 47.24,78.78 47.24,79.14
  BOTTOM w0.254: 47.24,79.14 47.24,79.87 47.95,80.57 47.95,80.82 48.45,81.32 49.07,81.32 49.78,82.03 PC4604.2 49.81,83.41 PR4608.2 51.26,83.41 v1(51.44,83.58)
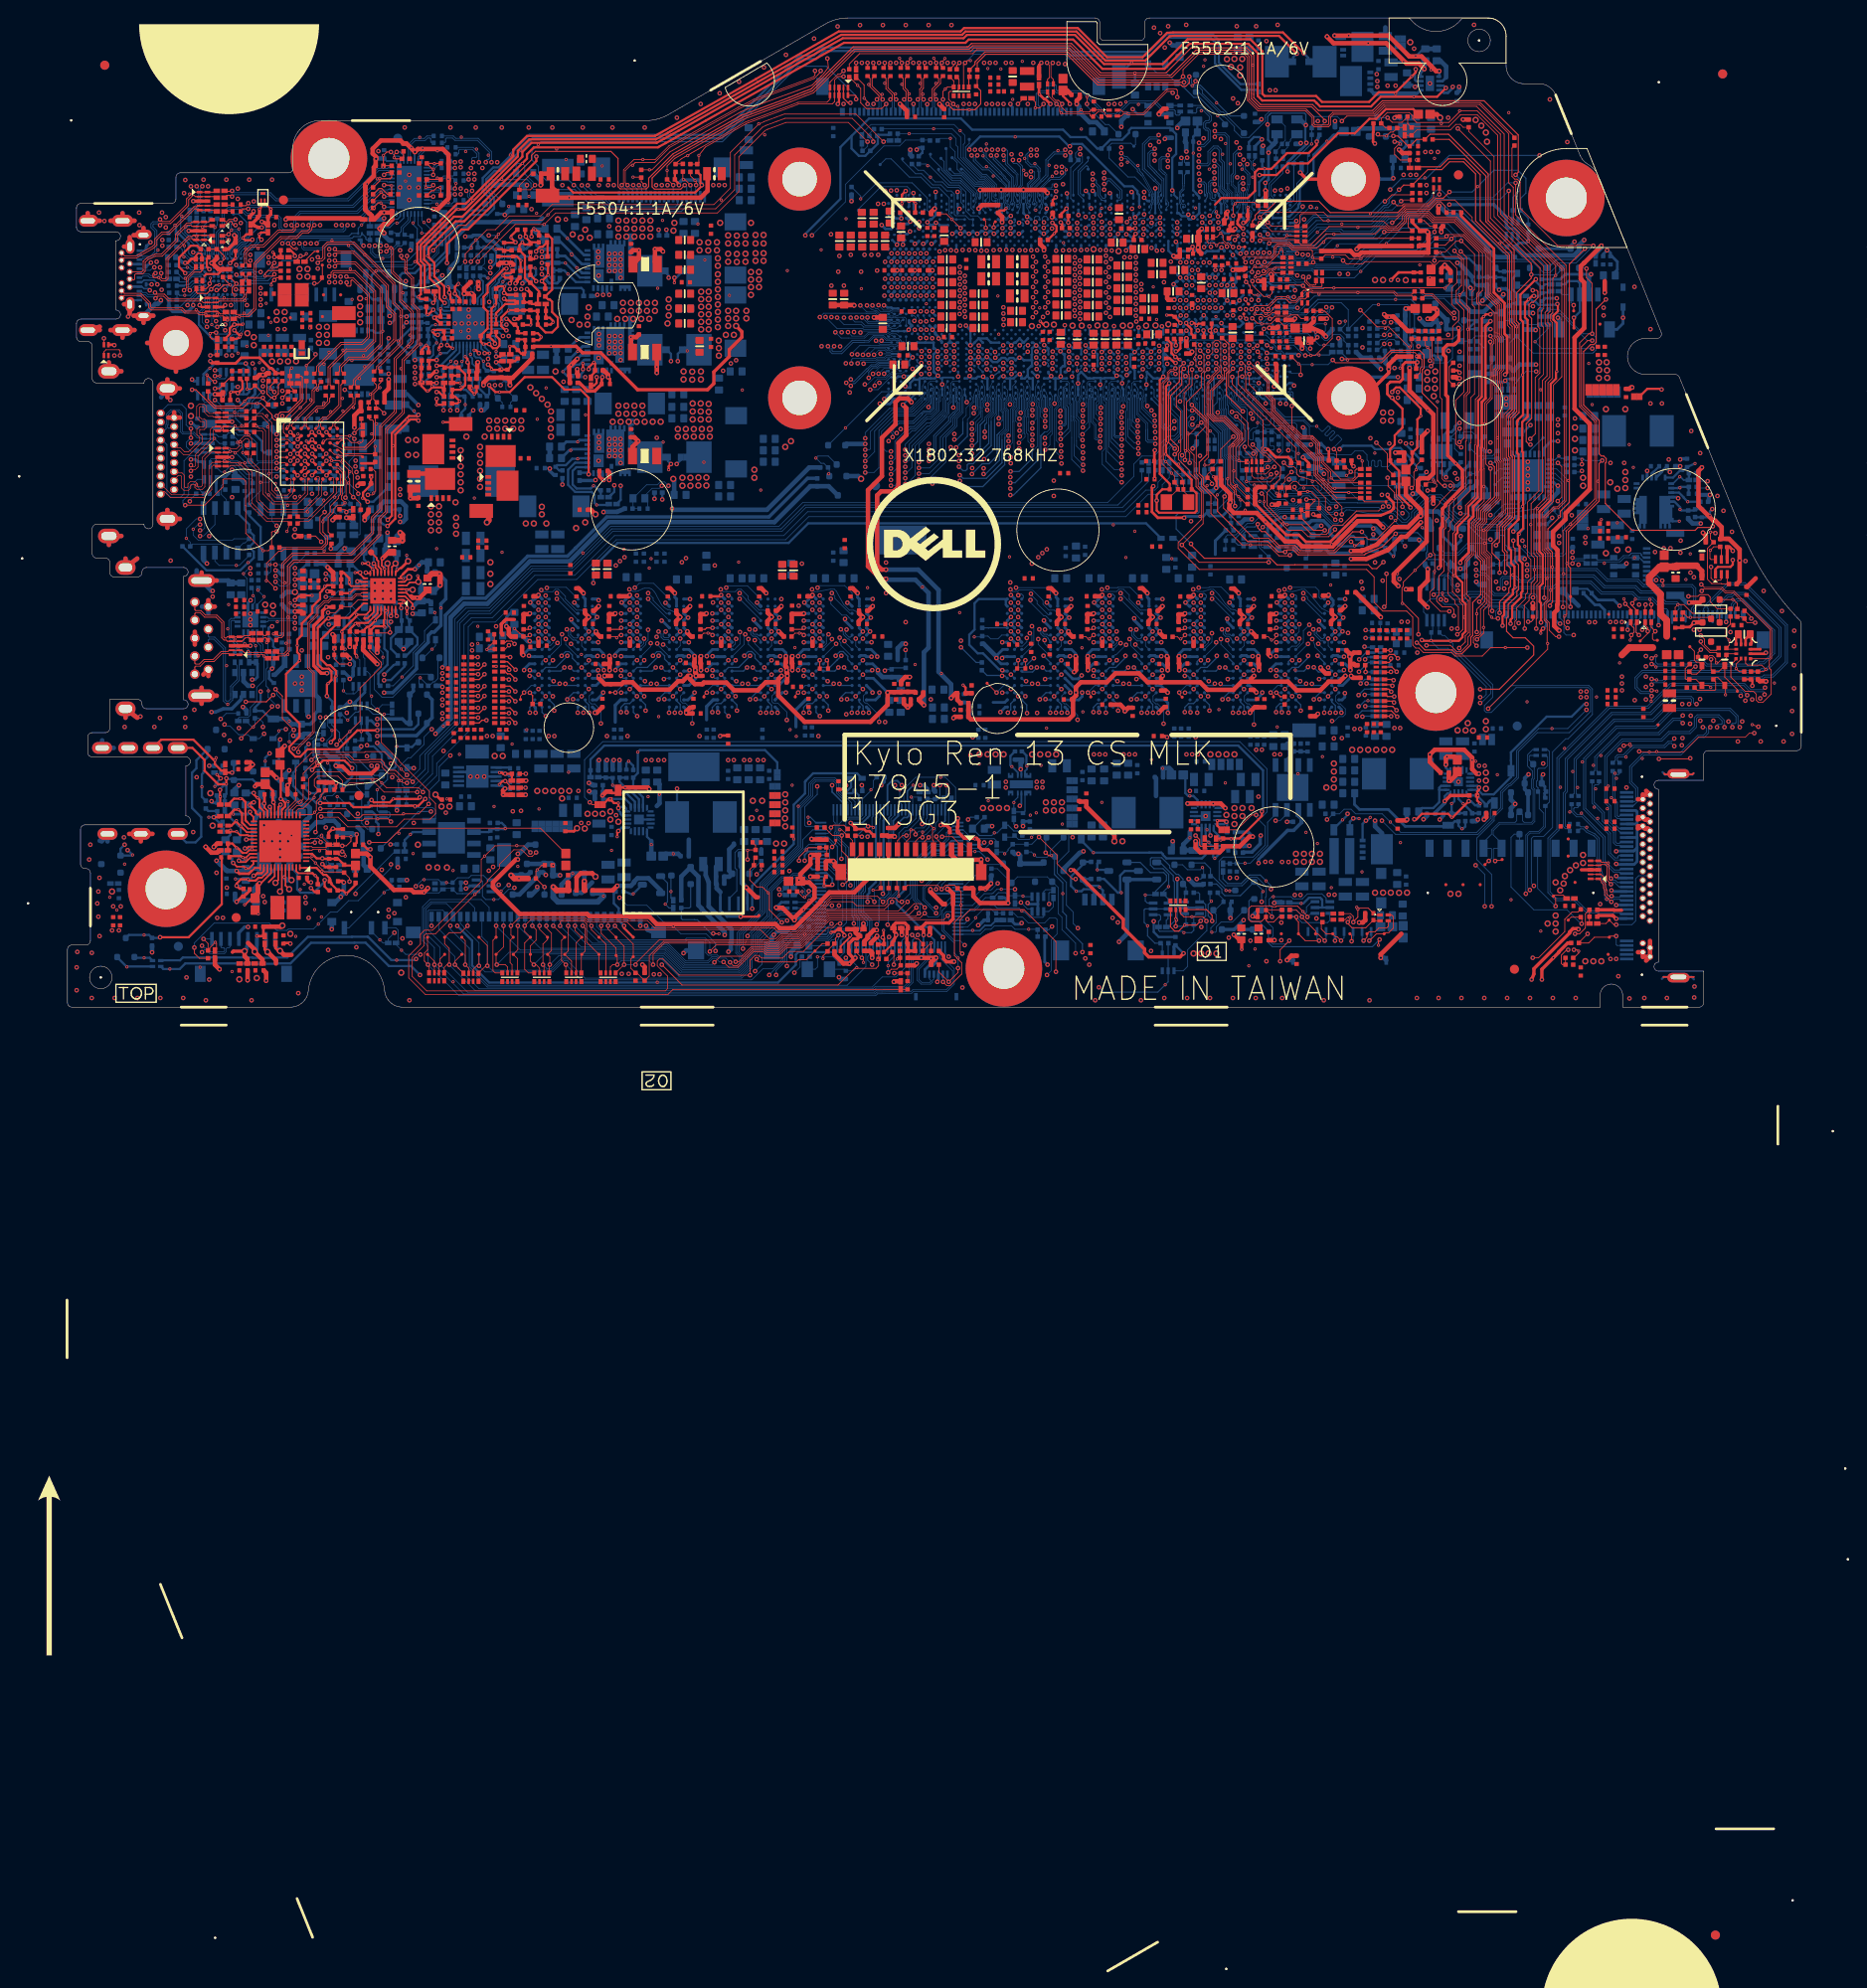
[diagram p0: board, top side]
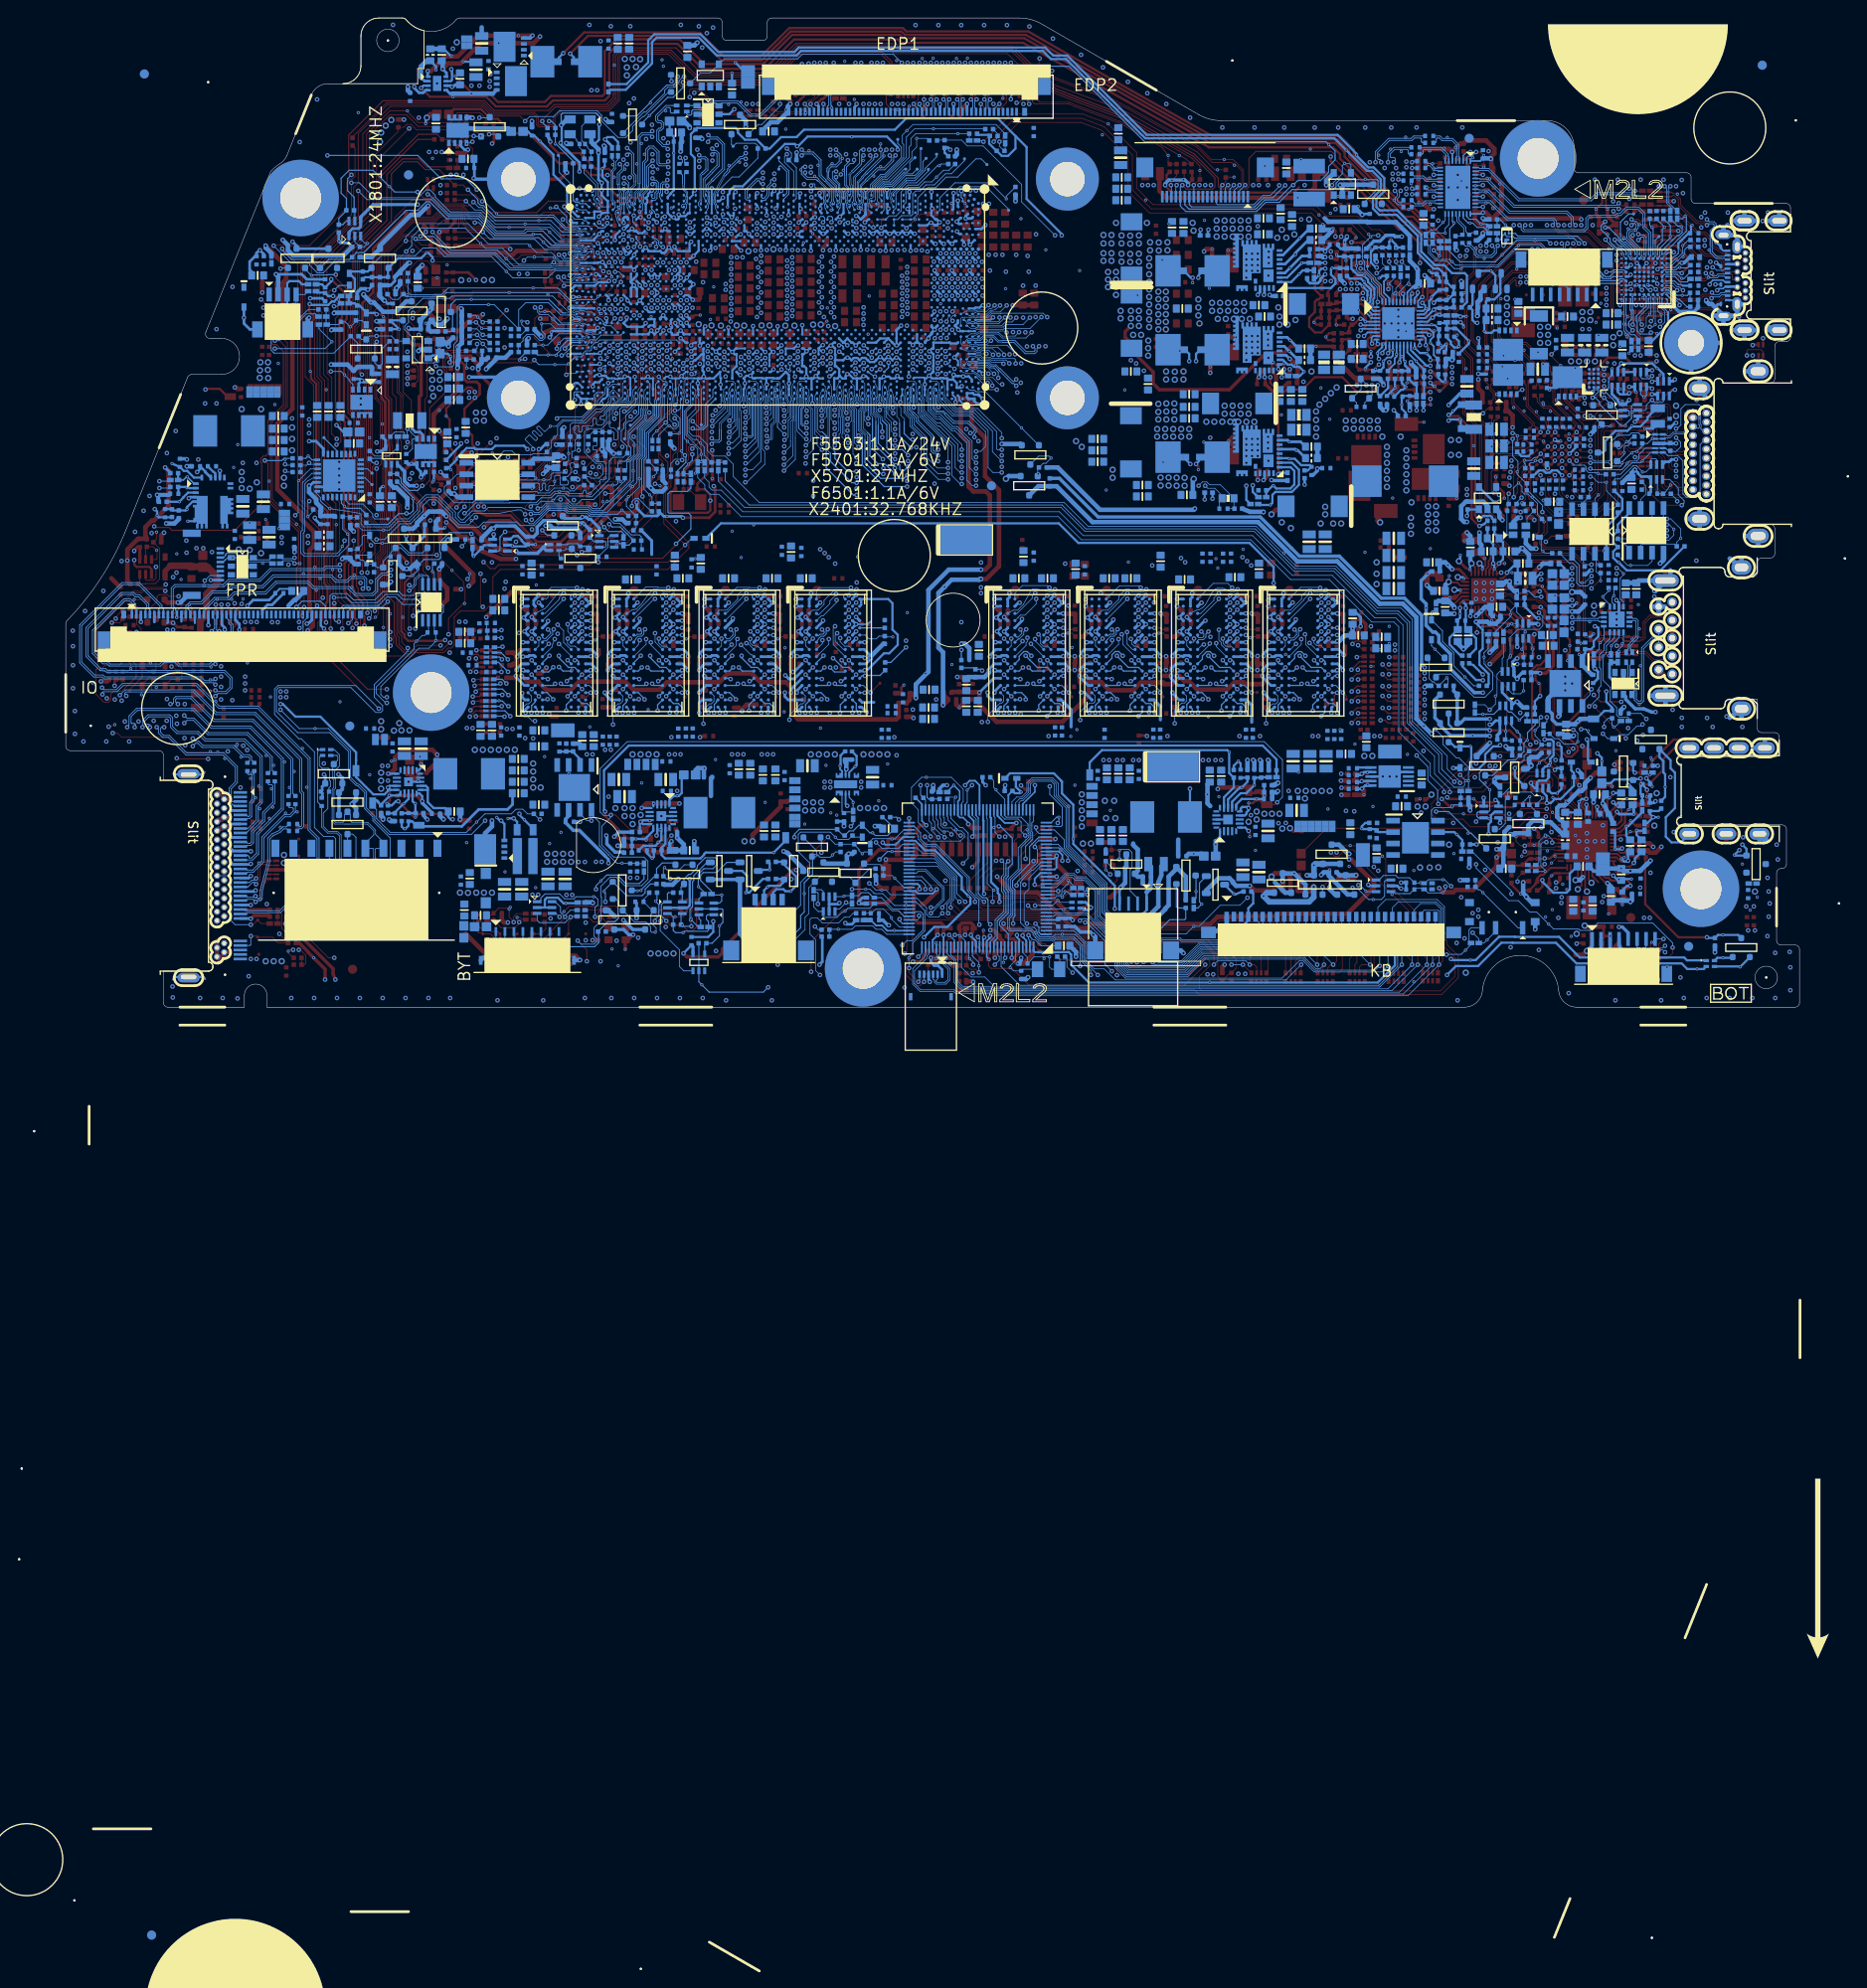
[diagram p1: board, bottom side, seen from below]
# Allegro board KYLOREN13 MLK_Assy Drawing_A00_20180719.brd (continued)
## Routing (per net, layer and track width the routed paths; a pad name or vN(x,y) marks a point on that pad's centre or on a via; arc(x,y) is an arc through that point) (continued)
PWR_VCCGT_ISEN1: length 24.3
  TOP w0.254: PR4821.1 53.34,84.93 PC4625.1 52.78,84.47 52.49,84.47 52.07,84.05 v2(52.07,83.97) ; PR4824.2 47.62,78.12 v1(47.5,78) 47.12,77.62 47.12,74.9 PR4669.2 47.5,73.86 v2(47.5,73.72)
  L4SGND w0.254: v2(52.07,83.97) 51.82,83.97 51.55,83.7 49.05,83.7 47.92,82.57 47.92,74.82 47.5,74.4 v2(47.5,73.72)
  BOTTOM w0.203: PU4601.9 47.37,74.56 47.56,74.38 47.56,73.78 v2(47.5,73.72)
PWR_VCCGT_ISEN2: length 19.9
  TOP w0.254: v2(48.77,82.06) 48.54,82.06 46.69,80.21 46.69,79.39 46.23,78.94 46.23,77.74 46.69,77.28 46.69,75.41 45.92,74.64 PR4669.1 45.92,73.93 46.18,73.68 v1(46.23,73.68) v2(46.86,73.68) 46.86,73.64 47.29,73.21 47.71,73.21 48.01,73.51 48.01,74.19 47.62,74.57 PR4823.1 ; PC4626.1 PR4822.2 51.87,83.13 v2(52.07,83.33)
  L4SGND w0.254: v2(48.77,82.06) 50.8,82.06 v2(52.07,83.33)
  BOTTOM w0.203: PU4601.10 46.96,73.78 v2(46.86,73.68)
PWR_VCCGT_ISUMN: length 32.5
  TOP w0.254: PR4815.2 50.72,78.38 PC4630.2 50.7,78.3 PR4643.2 51.61,78.12 PR4647.2 52.27,79.01 PC4633.1 52.4,79.52 PR4809.2 51.36,80.49 50.83,81.02 50.83,83.48 PR4645.2 50.22,84.65 v1(50.55,84.98) 50.8,84.73 51.36,84.73 PC4626.2 ; PC4625.2 51.61,84.98 PC4626.2 ; PC4626.2 51.44,85.02 50.93,85.53 v2(50.93,85.62) 50.85,85.69 PR4642.2
  L6 w0.254: v2(66.55,86.38) 66.29,86.12 66.29,85.23 65.69,84.63 58.56,84.63 58.44,84.5 51.92,84.5 50.93,85.49 v2(50.93,85.62)
  BOTTOM w0.254: PR4646.2 66.6,86.33 v2(66.55,86.38)
PWR_VCCGT_ISUMN_GA: length 21.8
  TOP w0.254: v1(67.44,80.49) v2(67.44,81.04) ; v2(52.07,80.66) 52.07,80.71 PR4809.1 PR4822.1
  L6 w0.254: v2(52.07,80.66) 52.07,80.58 52.49,80.16 56.6,80.16 58.51,78.25 60.74,78.25 61.35,78.86 66.14,78.86 67.44,80.16 v2(67.44,81.04)
  BOTTOM w0.254: PG4809.2 67.64,81.04 v2(67.44,81.04)
PWR_VCCGT_ISUMN_GB: length 31.7
  TOP w0.254: PR4824.1 47.88,80.08 v1(48.58,80.08) 48.51,80.02 v2(48.51,79.34) 48.65,79.34 48.85,79.14 PR4815.1
  L6 w0.254: v2(67.82,71.77) 67.82,70.85 66.07,69.11 57.02,69.11 55.63,70.5 55.63,71.25 49.39,77.49 48.9,77.49 48.01,78.38 48.01,78.92 48.43,79.34 v2(48.51,79.34)
  BOTTOM w0.254: PG4815.1 67.82,72.59 v2(67.82,71.77)
PWR_VCCGT_ISUMN_P_1: length 3.5
  TOP w0.254: PC4628.2 53.7,75.84 v1(53.95,76.09) 53.95,76.24 53.59,76.6 PC4654.2 PC4653.2 53.14,77.39 PR4647.1
PWR_VCCGT_ISUMN_P_2: length 18.9
  TOP w0.254: PR4641.2 52.4,86.17 51.86,86.4 v1(51.82,86.51) 51.56,86.25 v2(51.56,85.62)
  L6 w0.254: v2(65.68,86.38) 65.91,86.15 65.91,85.39 65.53,85.01 58.41,85.01 58.28,84.88 52.1,84.88 51.56,85.41 v2(51.56,85.62)
  BOTTOM w0.254: PR4646.1 65.74,86.33 v2(65.68,86.38)
PWR_VCCGT_ISUMN_RC: length 1.8
  TOP w0.254: PR4645.1 48.59,84.09 PC4623.1 48.31,84.22 v1(47.62,84.22)
PWR_VCCGT_ISUMNB: length 16.4
  TOP w0.254: PC4623.2 49.73,84.93 v2(49.78,84.98) v1(49.28,85.49) 49.28,85.67 PR4642.1
  L6 w0.254: v2(48.39,74.57) 47.62,75.33 47.62,80.2 49.78,82.36 v2(49.78,84.98)
  BOTTOM w0.203: PU4601.8 47.99,74.96 v2(48.39,74.57)
PWR_VCCGT_ISUMP: length 23.9
  TOP w0.254: PR4641.1 53.47,85.74 53.85,85.36 53.85,79.72 PR4808.1 53.42,78.63 53.59,78.63 53.85,78.38 53.85,77.23 54.48,76.6 54.48,75.6 53.85,74.96 53.12,74.96 PC4628.1 PC4654.1 PC4653.1 51.51,77.36 PR4643.1 50.7,77.44 PC4630.1 49.94,77.41 PR4816.1 v1(49.01,77.44) 48.21,76.63 48.21,75.66 48.67,75.2 v2(48.77,75.2)
  BOTTOM w0.203: v2(48.77,75.2) 48.61,75.36 PU4601.7
PWR_VCCGT_ISUMP_GA: length 20.6
  TOP w0.254: PR4821.2 53.39,82.46 v1(53.39,81.35) v2(52.7,80.66) 53.09,80.28 PR4808.2
  L6 w0.254: v2(66.8,81.04) 66.8,80.06 65.98,79.24 61.19,79.24 60.58,78.63 58.67,78.63 56.63,80.66 v2(52.7,80.66)
  BOTTOM w0.254: PG4808.2 66.47,81.6 66.8,81.27 v2(66.8,81.04)
PWR_VCCGT_ISUMP_GB: length 31.4
  TOP w0.254: PR4823.2 v1(47.62,76.75) 47.62,77.11 48.64,78.12 49.73,78.12 PR4816.2 49.71,78.5 48.77,78.5 48.56,78.71 v2(48.51,78.71)
  L6 w0.254: v2(48.51,78.71) 49.33,77.89 49.54,77.89 56.01,71.42 56.01,70.66 57.18,69.49 65.91,69.49 67.06,70.63 v2(67.06,71.77)
  BOTTOM w0.254: v2(67.06,71.77) 67.06,72.59 PG4813.1
PWR_VCCGT_NTC: length 6.9
  BOTTOM w0.203: 47.62,79.11 47.62,78.87 47.7,78.79 47.7,78.37 47.92,78.15 47.92,77.42 47.46,76.96 PU4601.3
  BOTTOM w0.254: 47.62,79.11 47.62,79.71 48.39,80.47 v1(48.39,80.61) 48.72,80.94 49.99,80.94 PR4616.2
PWR_VCCGT_NTC1: length 10.3
  BOTTOM w0.254: 51.93,82.1 52.06,81.98 52.06,81.39 51.56,80.89 51.56,80.41 52.07,79.9 57.1,79.9 57.35,79.65 PR4617.1 ; 51.93,82.1 51.92,82.11 PR4621.2 PR4616.1 ; 51.93,82.1 v1(51.94,82.1)
PWR_VCCGT_PWMA: length 23.3
  TOP w0.254: v1(46.91,72.66) v2(46.35,72.66)
  L4SGND w0.254: v2(46.35,72.66) 46.35,73.89 47.54,75.08 47.54,82.73 48.9,84.08 51.3,84.08 51.82,84.6 53.09,84.6 53.21,84.47 53.21,82.48 52.79,82.06 v2(52.7,82.06)
  BOTTOM w0.203: PU4601.12 45.98,73.17 46.35,72.79 v2(46.35,72.66)
  BOTTOM w0.254: PR4802.1 53.71,80.99 53.37,81.34 53.37,81.81 53.11,82.06 v2(52.7,82.06)
PWR_VCCGT_PWMA_RA: length 4.4
  BOTTOM w0.254: PR4802.2 PR4817.1 55.19,81.86 v1(55.6,81.45) 56.49,80.56 PU4801.1
PWR_VCCGT_PWMB: length 20.6
  TOP w0.254: v2(45.72,72.66) 45.39,72.99 v1(45.19,72.99) ; PR4811.1 58.5,69.06 58.8,69.36 v2(58.8,70)
  L4SGND w0.254: v2(45.72,72.66) 44.96,71.9 44.96,70.88 46.23,69.61 51.79,69.61 52.93,68.47 57.28,68.47 v2(58.8,70)
  BOTTOM w0.203: v2(45.72,72.66) 45.58,72.81 PU4601.13
PWR_VCCGT_PWMB_RA: length 3.6
  TOP w0.254: PR4811.2 58.17,70.12 58.62,70.58 PR4818.1 58.62,71.52 v1(58.49,71.65) 57.91,71.08 v2(57.91,70.88)
  BOTTOM w0.254: PU4802.1 57.9,71.29 57.9,70.89 v2(57.91,70.88)
PWR_VCCGT_RTN: length 13.5
  TOP w0.254: v2(46.74,71.39) 47.12,71.01 v1(47.12,70.88) 47.19,70.81 PR4639.1 48.16,70.83 PC4622.1 49.2,71.14 PR4666.2 49.73,71.77 PC4619.2
  L4SGND w0.254: v2(48.77,75.84) 49.02,75.84 49.53,75.33 49.53,74.19 48.13,72.79 48.13,71.44 47.7,71.01 47.3,71.01 46.81,71.21 v2(46.74,71.39)
  BOTTOM w0.203: PU4601.6 48.7,75.76 v2(48.77,75.84)
PWR_VCCGT_SNB1: length 2.8
  TOP w0.508: PC4810.1 62.81,84.09 v1(63.5,84.09) 63.5,83.2 PR4805.2
PWR_VCCGT_SNB2: length 2.7
  TOP w0.508: PR4814.2 62.61,72.97 v1(62.61,74.44) 63.2,74.44 PC4813.1
PWR_VCCGT_SWA: length 2.8
  TOP w0.508: v2(66.17,83.97) 65.91,84.22 v1(65.28,84.22) 65.28,82.8 PR4805.1
PWR_VCCGT_SWB: length 2.3
  TOP w0.508: PR4814.1 v1(65.48,71.14) v2(65.48,70.48)
PWR_VCCGT_VCCDA: length 4.9
  BOTTOM w0.305: PU4801.3 57.19,81.56 v1(56.6,82.15) 55.29,83.46 PC4809.1 54.43,84.19 PR4803.2
PWR_VCCGT_VCCDB: length 4.4
  TOP w0.508: PR4813.2 55.8,69.39 PC4812.1 55.75,70.17 55.75,71.14 v1(55.97,71.35) v2(56.64,72.03)
  BOTTOM w0.305: PU4802.3 57.03,72.42 v2(56.64,72.03)
PWR_VCCSA_BST: length 4.7
  BOTTOM w0.254: PR5001.2 151.51,104.51 v1(151.51,104.13)
  BOTTOM w0.305: 153.19,103.29 152.78,102.88 PU5001.2
  BOTTOM w0.508: 153.19,103.29 153.19,104.51 152.55,105.15 PR5001.2
PWR_VCCSA_BST_RC: length 2.7
  BOTTOM w0.254: v1(149.8,105.68) 149.86,105.68 150.65,106.47 PC5005.1
  BOTTOM w0.508: PR5001.1 PC5005.1
PWR_VCCSA_COMP: length 5.9
  BOTTOM w0.203: PU4601.24 41.14,75.36 40.67,74.89 40.67,74.49 41.02,74.14 v1(41.02,73.81) 40.64,73.42 40.64,72.46 PC4624.1
  BOTTOM w0.254: PC4624.1 40.21,71.27 PR4640.1
PWR_VCCSA_COMP_RC: length 2.2
  BOTTOM w0.254: PR4640.2 40.13,69.92 39.7,69.49 v1(39.37,69.49) PC4601.1
PWR_VCCSA_DRVH: length 15
  TOP w0.508: v2(140.79,107.94) v1(142.37,107.94) 146.78,107.94 149.1,105.63 150.46,105.63 151.54,104.55 151.54,104.54 152.07,104 v2(152.43,104)
  BOTTOM w0.305: PU5001.1 v2(152.43,104)
  BOTTOM w0.406: PU5002.4 141.06,107.67 v2(140.79,107.94)
PWR_VCCSA_DRVL: length 5.9
  BOTTOM w0.305: 149.73,101.49 149.95,101.49 PU5001.5
  BOTTOM w0.406: PU5003.4 145.19,101.49
  BOTTOM w0.508: 149.73,101.49 v1(147.57,101.49) 145.19,101.49
PWR_VCCSA_FB: length 4
  BOTTOM w0.203: PU4601.25 40.97,75.76 v1(40.89,75.84) 40.82,75.76 40.49,75.76 PR4637.1
  BOTTOM w0.254: PR4637.1 PR4632.2 40.13,74.49 PR4638.2
PWR_VCCSA_FB1: length 2.2
  BOTTOM w0.254: PR4638.1 39.32,73.68 v1(39.24,73.68) 39.24,72.99 PC4621.2
PWR_VCCSA_FB2: length 6.5
  BOTTOM w0.254: PC4620.1 36.74,73.72 v1(36.74,74.02) 38.13,75.41 PC4617.2 39.12,75.41 PR4637.2 PR4601.1 39.27,76.01 PC4616.2
PWR_VCCSA_FB_RC: length 3.5
  BOTTOM w0.254: PC4617.1 37.85,73.98 v1(37.85,73.42) 37.97,73.3 38.35,73.3 38.73,73.68 38.73,73.93 39.19,74.39 PR4632.1
PWR_VCCSA_FCCM: length 139
  TOP w0.254: v2(149.81,104.21) 149.81,103.85 v1(149.35,103.4) 147.61,101.66 145.71,101.66 144.63,100.58 139.4,100.58 138.74,101.24 133.02,101.24 132.77,101.49 132.77,106.21 131.44,107.54 124.45,107.54 121.7,104.78 115.18,104.78 111.95,108.02 99.94,108.02 99.57,107.65 86.14,107.65 67.93,97.4 67.35,97.07 67.06,96.91 66.34,96.51 66.33,96.51 65.52,96.06 65.46,96.03 51.56,96.03 50.55,95.01 50.55,94.49 43.88,87.83 42.94,87.83 39.62,84.51 39.62,83.06 40.26,82.42 40.26,80.97 41.35,79.88 41.35,78.73 41.83,78.25 v2(41.91,78.25)
  BOTTOM w0.203: PU4601.29 41.8,77.36 41.59,77.57 41.59,77.96 41.88,78.25 v2(41.91,78.25)
  BOTTOM w0.254: PU5001.7 149.86,102.88 149.73,103.02 149.73,104.13 v2(149.81,104.21)
PWR_VCCSA_IMON: length 4.1
  TOP w0.254: PR4644.1 41.86,75.05 PC4629.2 41.67,75.24 40.68,75.24 v1(40.58,75.14) 40.58,75.01 40.89,74.69 v2(41.15,74.69)
  BOTTOM w0.203: v2(41.15,74.69) 41.42,74.96 PU4601.23
PWR_VCCSA_ISUMN: length 119.1
  TOP w0.254: v2(40.64,78.25) 40.82,78.43 PR5004.2
  BOTTOM w0.254: v2(40.64,78.25) 40.31,78.58 PC4605.1 39.98,78.55 PR4618.2 39.12,78.55 PR4613.1 38.43,79.29 PC4603.2 38.68,80.03 PR4620.1 39.24,81.22 PR4615.1 40.08,82.06 40.54,82.06 40.55,82.07 40.68,82.07 42.42,83.8 42.42,85.7 44.75,88.03 46.69,88.03 47.4,88.73 47.4,89.94 46.52,90.82 46.52,91.96 47.48,92.92 48.07,92.92 v1(50.37,95.22) 51.69,96.54 72.7,96.54 81.5,105.34 83.17,105.34 84.07,106.24 110.95,106.24 111.44,105.75 120.32,105.75 122.28,107.71 127,107.71 127.51,107.21 127.51,104.84 130.43,101.92 132.11,101.92 PR4611.1
PWR_VCCSA_ISUMN_P_1: length 0.8
  BOTTOM w0.254: PR4613.2 37.52,79.24 PC4608.2
PWR_VCCSA_ISUMN_P_2: length 118.8
  BOTTOM w0.254: PR4625.2 36.96,78.33 36.96,81.3 37.21,81.55 38.61,81.55 39.5,82.44 40.39,82.44 40.39,82.45 40.53,82.45 42.04,83.96 42.04,85.86 44.72,88.54 46.66,88.54 47.02,88.89 47.02,89.78 46.14,90.66 46.14,92.12 47.32,93.3 47.91,93.3 49.21,94.6 v1(49.21,94.67) 49.25,94.71 49.25,94.83 51.33,96.92 72.54,96.92 81.36,105.73 82.93,105.73 83.82,106.62 111.2,106.62 111.69,106.13 120.16,106.13 122.12,108.1 127.25,108.1 127.93,107.42 127.93,104.96 130.33,102.56 PR4611.2
PWR_VCCSA_ISUMN_R: length 115.6
  TOP w0.254: PR5004.1 39.69,79.79 39.69,82.46 39.24,82.9 39.24,84.67 43.21,88.64 v1(43.43,88.64) 44.16,88.64 50.04,94.52 50.04,95.14 51.31,96.41 65.36,96.41 65.38,96.42 66.72,97.16 67,97.31 67,97.31 67.16,97.4 76.69,102.78 76.7,102.79 85.98,108.03 99.41,108.03 99.78,108.4 112.1,108.4 115.34,105.16 119.75,105.16 122.48,107.88 123,107.92 134.62,107.92 v2(136.6,105.94)
  BOTTOM w0.254: v2(136.6,105.94) 136.19,105.53 PG5001.1
PWR_VCCSA_ISUMN_RC: length 1.9
  BOTTOM w0.254: PC4611.1 40.01,81.12 PR4615.2 40.44,81.55 40.89,81.55 v1(41.15,81.81)
PWR_VCCSA_ISUMNB: length 4.7
  BOTTOM w0.203: 41.24,77.46 41.73,76.96 PU4601.28
  BOTTOM w0.254: 41.24,77.46 41.15,77.55 41.15,78.46 40.89,78.71 v1(40.89,78.88) 40.08,79.7 PC4611.2 39.98,79.72 PR4620.2
PWR_VCCSA_ISUMP: length 6.8
  TOP w0.254: PR5003.2 39.88,77.08 v1(40.01,76.95) 40.03,76.98 40.13,76.98 v2(40.64,77.49)
  BOTTOM w0.203: PU4601.27 41.56,76.56 41.05,77.08
  BOTTOM w0.254: PC4608.1 38.43,77.77 PR4625.1 38.67,77.74 38.72,77.69 PR4618.1 39.27,77.67 PC4605.2 40.46,77.67 v2(40.64,77.49) 41.05,77.08
PWR_VCCSA_ISUMP_R: length 118.9
  TOP w0.254: PR5003.1 39.22,78.68 v1(38.99,78.91) 39.09,79.01 39.09,79.04 39.27,79.22 39.27,82.34 38.86,82.74 38.86,84.83 43.31,89.27 44.25,89.27 49.53,94.55 49.53,95.27 51.06,96.79 65.26,96.79 65.33,96.83 76.46,103.09 76.48,103.11 85.71,108.41 99.25,108.41 99.62,108.78 112.26,108.78 115.5,105.55 119.47,105.55 122.18,108.26 122.84,108.3 135.05,108.3 v2(137.36,105.99)
  BOTTOM w0.254: v2(137.36,105.99) 137.87,105.48 PG5011.1
PWR_VCCSA_PWM: length 138.6
  TOP w0.254: v2(153.16,102.13) 152.18,101.15 v1(149.61,101.15) 145.92,101.15 144.84,100.07 139.19,100.07 138.79,100.47 138.53,100.73 132.76,100.73 132.26,101.23 132.26,106 131.23,107.03 124.66,107.03 121.88,104.25 115,104.25 111.73,107.51 100.15,107.51 99.78,107.14 86.28,107.14 70.91,98.5 68.18,96.96 67.6,96.63 67.34,96.48 66.48,96 66.46,96 65.77,95.62 65.6,95.52 51.82,95.52 51.05,94.76 51.05,94.28 44.09,87.32 43.15,87.32 40.13,84.3 40.13,83.32 40.77,82.69 40.77,81.18 41.86,80.09 41.86,78.94 v2(41.91,78.89)
  BOTTOM w0.203: PU4601.30 42.39,77.97 42.39,78.45 41.96,78.89 v2(41.91,78.89)
  BOTTOM w0.254: v2(153.16,102.13) 152.9,102.38 PU5001.3
PWR_VCCSA_RTN: length 5.9
  TOP w0.254: PR4627.2 41.4,75.96 v2(40.77,76.6) 40.89,76.73 PC4613.1 v1(41.45,77.62)
  BOTTOM w0.203: PU4601.26 41.33,76.16 40.89,76.6 v2(40.77,76.6)
  BOTTOM w0.254: v2(40.77,76.6) 40.44,76.93 PC4616.1 39.93,76.85 PR4602.1
PWR_VCCSA_SW: length 14.3
  TOP w0.508: v2(139.95,107.84) 139.95,107.82 140.67,107.1 v1(144.53,107.1) 146.53,107.1 148.79,104.84 150.16,104.84 v2(150.77,104.23)
  BOTTOM w0.305: v2(150.77,104.23) 150.34,103.8 PU5001.8
  BOTTOM w0.508: PC5005.2 150.77,105.05 v2(150.77,104.23)
PWR_VCORE_BOOT: length 3.3
  BOTTOM w0.305: PR4705.2 55.75,61.87 v1(55.92,61.87) 56.04,61.99 PU4701.5
PWR_VCORE_BOOT_RC: length 1.3
  BOTTOM w0.508: PC4707.1 PR4705.1
PWR_VCORE_BOOTR: length 3.2
  BOTTOM w0.305: PC4707.2 55.43,62.81 v1(56.69,62.81) 56.7,62.81 56.88,62.99 PU4701.7
PWR_VCORE_COMP: length 4.7
  TOP w0.254: PR4656.1 44.63,69.87 PC4639.1 44.58,70.68 44.58,71.52 v2(44.45,71.65) 44.45,72.03 v1(44.2,72.28)
  BOTTOM w0.203: v2(44.45,71.65) 44.37,71.73 44.37,73.02 44.38,73.02 PU4601.16
PWR_VCORE_COMP1: length 1.9
  TOP w0.254: PC4640.1 45.47,68.37 v1(45.21,68.12) 44.7,68.62 PR4656.2
PWR_VCORE_FB: length 4.6
  BOTTOM w0.203: v1(43.83,71.74) 43.98,71.88 PU4601.17
  BOTTOM w0.254: PR4657.1 PR4658.1 PR4660.1 43.43,70.88 43.83,71.28 v1(43.83,71.74)
PWR_VCORE_FB1: length 2.3
  BOTTOM w0.254: PR4657.2 v1(44.96,68.8) PC4641.1
PWR_VCORE_FB2: length 6.4
  BOTTOM w0.254: PR4660.2 42.85,69.23 PC4642.2 42.55,69.16 PR4667.1 43.28,67.89 PC4644.1 44.04,67.91 PC4643.2 44.2,67.76 v1(44.2,66.95) 44.2,66.48 43.76,66.05 PR4663.2
PWR_VCORE_FB_RC: length 2.8
  BOTTOM w0.254: PR4658.2 44.2,69.36 v1(43.74,68.91) 44.06,68.6 44.27,68.6 PC4643.1
PWR_VCORE_FCCM#: length 34.5
  TOP w0.254: v2(42.19,73.55) v1(42.8,73.22)
  L6 w0.254: v2(42.19,73.55) 42.16,73.53 42.16,71.22 42.76,70.63 44.11,70.63 45,69.74 51.54,69.74 56.26,65.02 56.26,59.12 57.9,57.47 61.01,57.47 v2(61.47,57.93)
  BOTTOM w0.203: PU4601.21 v2(42.19,73.55)
  BOTTOM w0.254: PR4706.1 61.47,56.36 v2(61.47,57.93)
PWR_VCORE_FCCM#_R: length 10.2
  BOTTOM w0.254: PR4706.2 60.05,55.8 v1(58.8,55.8) 58.57,56.03 58.57,56.91 58.24,57.24 56.41,57.24 55.63,58.03 55.63,59.71 56.41,60.49 PU4701.2
PWR_VCORE_IMON: length 4.5
  BOTTOM w0.203: PU4601.14 45.18,73.02 45.18,73.02 45.18,72.39 45.39,72.18 45.82,72.18 v1(46.23,71.77)
  BOTTOM w0.254: v1(46.23,71.77) 46.23,71.09 PC4638.1 46.63,70.68 PR4661.1
PWR_VCORE_ISUMN: length 42.8
  TOP w0.254: PR4651.2 39.32,71.8 PR4648.2 39.29,70.99 PC4631.1 39.24,70.07 39.24,69.44 PR4701.2 39.32,69.03 39.88,68.47 v1(40.01,68.47) 40.13,68.47 40.51,68.85 41.58,68.85 PC4634.1 ; PC4634.1 41.83,67.86 PR4652.2 41.78,67.84 41.27,68.34 v2(41.02,68.34) ; PC4634.1 41.86,68.62 PR4649.1
  L6 w0.254: v2(65.23,56.48) 64.77,56.03 53.94,56.03 52.1,57.87 52.1,64.92 49.43,67.58 44.45,67.58 43.89,68.14 41.22,68.14 v2(41.02,68.34)
  BOTTOM w0.254: PR4650.1 v2(65.23,56.48)
PWR_VCORE_ISUMN_G: length 40.5
  TOP w0.254: v2(41.02,69.36) PR4701.1
  L6 w0.254: v2(41.02,69.36) 41.1,69.36 41.36,69.61 43.78,69.61 45.18,68.22 49.81,68.22 52.6,65.42 52.6,58.29 54.31,56.58 62.1,56.58 63.58,58.06 65.45,58.06 65.83,58.44 66.04,58.44 67.69,60.09 v2(67.69,60.34)
  BOTTOM w0.254: v2(41.02,69.36) 40.64,68.98 v1(40.51,68.98) ; PG4708.1 68.15,60.8 v2(67.69,60.34)
PWR_VCORE_ISUMN_P_1: length 2.5
  TOP w0.254: PC4635.1 PC4652.1 42.72,70.12 PR4649.2 v1(43.64,69.36)
PWR_VCORE_ISUMN_P_2: length 37
  TOP w0.254: v2(41.02,67.58) 41.02,66.95 v1(41,66.93) 41.71,66.93 PR4653.2
  L6 w0.254: v2(66.09,56.41) 65.96,56.41 65.2,55.64 53.79,55.64 51.71,57.72 51.71,64.76 49.27,67.2 44.29,67.2 43.73,67.76 41.2,67.76 v2(41.02,67.58)
  BOTTOM w0.254: PR4650.2 v2(66.09,56.41)
PWR_VCORE_ISUMN_RC: length 2
  TOP w0.254: PC4632.1 40.13,73.3 v1(39.88,73.55) 39.37,73.04 PR4651.1
PWR_VCORE_ISUMNA: length 4.6
  TOP w0.254: v2(41.02,71.9) 40.21,71.9 PC4632.2 40.18,71.77 PR4648.1
  BOTTOM w0.203: 42.18,72.67 42.78,73.27 PU4601.20
  BOTTOM w0.254: 42.18,72.67 41.49,72.67 v1(41.43,72.61) 41.02,72.2 v2(41.02,71.9)
PWR_VCORE_ISUMP: length 12.7
  TOP w0.254: v2(41.02,71.27) 41.71,71.27 PR4708.2 41.94,71.09 PC4652.2 PC4635.2 44.2,70.33 44.2,69.11 43.69,68.6 PC4634.2 42.75,68.12 42.72,68.09 PR4652.1 43.08,67.84 v1(43.59,67.33) 43.33,67.07 PR4653.1
  BOTTOM w0.203: PU4601.19 43.18,72.99 42.97,72.79
  BOTTOM w0.254: v2(41.02,71.27) 41.45,71.27 42.97,72.79
PWR_VCORE_ISUMP_G: length 39.8
  TOP w0.254: v1(66.8,59.71) 66.8,60.09 v2(67.06,60.34) ; v2(41.02,70) 41.71,70 PR4708.1
  L6 w0.254: v2(41.02,70) 43.94,70 45.34,68.6 50.06,68.6 52.98,65.68 52.98,58.54 54.56,56.96 61.87,56.96 63.34,58.44 65.29,58.44 65.67,58.82 65.88,58.82 67.06,59.99 v2(67.06,60.34)
  BOTTOM w0.254: v2(67.06,60.34) 66.73,60.67 PG4707.1
PWR_VCORE_NTC: length 3.3
  BOTTOM w0.203: PR4662.1 45.75,70.73 44.98,71.49 44.98,72.08 44.78,72.28 v1(44.78,72.54) PU4601.15
PWR_VCORE_NTC1: length 26.3
  TOP w0.254: v2(57.91,59.2) 57.91,67.71 57,68.62 55.22,68.62 53.85,70 50.8,70 49.15,68.34 v1(48.01,68.34) 47.54,68.34 46.86,69.02 v2(46.86,69.11)
  BOTTOM w0.254: PR4654.1 57.73,59.38 v2(57.91,59.2) ; PR4662.2 45.72,69.79 45.72,68.78 PR4655.2 46.86,68.14 v2(46.86,69.11)
PWR_VCORE_PROG1: length 3.3
  TOP w0.254: PR4629.1 43.56,78.76 v2(43.05,79.27) 43.05,80.02 v1(43.45,80.41)
  BOTTOM w0.203: v2(43.05,79.27) 43.18,79.14 PU4601.32
PWR_VCORE_PROG2: length 3
  TOP w0.254: v1(42.29,80.03) 42.42,79.9 v2(42.42,79.39) 42.55,79.27 42.55,78.68 PR4628.1
  BOTTOM w0.203: PU4601.31 42.78,78.78 42.42,79.14 v2(42.42,79.39)
PWR_VCORE_PWM: length 34.7
  TOP w0.254: v2(41.53,73.55) 41.27,73.3 v1(41.27,73.04)
  L6 w0.254: v2(60.76,57.98) 58.24,57.98 56.77,59.45 56.77,65.23 51.75,70.25 45.21,70.25 44.32,71.14 42.97,71.14 42.67,71.44 42.67,73.32 42.7,73.34 42.7,73.76 42.4,74.06 41.98,74.06 41.53,73.61 v2(41.53,73.55)
  BOTTOM w0.203: PU4601.22 41.78,74.56 41.53,74.32 v2(41.53,73.55)
  BOTTOM w0.254: v2(60.76,57.98) 60.76,57.25 60.42,56.91 60.38,56.91 PR4702.1
PWR_VCORE_PWM_R: length 7.7
  BOTTOM w0.254: PR4702.2 PR4712.1 59.05,57.42 58.55,57.93 v1(58.45,57.93) 58.14,57.63 56.57,57.63 56.13,58.06 56.13,59.58 56.54,59.99 PU4701.1
PWR_VCORE_RTN: length 6.5
  BOTTOM w0.203: PR4659.2 41.73,69.26 PC4642.1 41.71,67.96 PR4668.1 ; PC4637.1 41.71,70.83 42.6,71.72 v1(42.6,71.77) 43.58,72.75 PU4601.18
  BOTTOM w0.254: PR4659.2 41.73,70.73 PC4637.1
PWR_VCORE_SNB: length 2.9
  TOP w0.508: PC4706.1 62.99,63.31 v1(63.42,62.88) 62.79,62.25 PR4703.2
PWR_VCORE_SW:
  vias: v1(66.19,62.78) v2(65.48,63.26)
PWR_VCORE_VCC: length 4.4
  TOP w0.508: PC4607.1 45.16,79.06 v1(44.96,79.27) v2(44.07,79.27) 44.07,79.82 PR4610.2
  BOTTOM w0.203: v2(44.07,79.27) 43.98,79.17 PU4601.34
PWR_VCORE_VCC_R: length 4.9
  BOTTOM w0.254: PU4701.3 56.76,60.99 v1(56.69,60.93) 56.08,60.93 55.37,60.22 54.41,60.22 PC4708.1 54.64,59.63 PR4704.1
PWR_VCORE_VIN: length 6.3
  BOTTOM w0.203: 42.77,80.03 42.97,80.03 43.58,79.42 PU4601.33
  BOTTOM w0.508: PR4612.2 43.31,82.92 42.55,82.16 v1(42.55,82.06) 42.42,81.93 42.42,80.51 PC4606.1 42.7,80.03 42.77,80.03
PWR_VCORE_VRHOT#: length 4.3
  BOTTOM w0.203: PR4607.2 45.85,80.97 46.18,80.64 46.18,79.37 45.58,78.77 PU4601.38
  BOTTOM w0.254: PR4607.2 46.37,81.25 46.62,80.99 v1(46.74,80.99)
PWR_VDDQ_BOOT: length 3.2
  TOP w0.508: PR5102.1 154.08,27.83 v1(153.29,27.83) 153.16,27.7 v2(153.16,26.94)
  BOTTOM w0.254: PU5101.1 153.42,26.33 153.16,26.59 v2(153.16,26.94)
PWR_VDDQ_BOOT_A: length 2.4
  TOP w0.508: PR5102.2 154.43,25.93 153.67,25.16 v1(153.49,25.16) PC5114.1
PWR_VDDQ_FB: length 3.9
  BOTTOM w0.254: PR5107.2 155.3,21.56 PC5113.2 PR5101.1 153.8,21.58 v1(153.8,22.62) 153.85,22.62 154.11,22.88 PU5101.14
PWR_VDDQ_FB_A: length 3.1
  BOTTOM w0.254: PG5113.1 154.15,20.64 PC5113.1 154.56,20.16 154.9,19.81 v1(154.95,19.81) 155.07,19.81 155.32,20.07 PR5107.1
PWR_VDDQ_ILMT: length 3.6
  BOTTOM w0.254: PR5103.1 156.82,21.53 PR5106.2 156.08,21.63 155.11,22.6 v1(155.09,22.6) 154.56,23.13 PU5101.13
PWR_VDDQ_PG: length 9.4
  TOP w0.254: v2(156.84,24.4) 156.84,24.15 156.64,23.95 PR5104.2 156.64,22.95 v1(156.97,22.62)
  BOTTOM w0.254: v2(156.84,24.4) 156.66,24.59 PU5101.9 ; v2(156.84,24.4) 156.58,24.14 PU5101.10 ; v2(156.84,24.4) 156.84,24.02 157.23,23.64 158.47,23.64 160.4,25.57 PG5114.2
PWR_VDDQ_PH: length 11
  TOP w0.508: v2(156.83,25.94) 156.59,25.94 156.08,26.44 v1(156.08,27.45) 156.08,27.7 155.19,28.59 151.92,28.59 v2(151.38,28.06) 151.38,27.25 PC5114.2
  BOTTOM w0.254: PU5101.6 v2(156.83,25.94)
PWR_VDDQ_VCC: length 15.8
  TOP w0.254: v2(149.66,20.87) 149.89,20.87 150.5,21.48 153.42,21.48 v1(153.8,21.1) 153.92,21.1 v2(155.7,22.88)
  BOTTOM w0.254: 152.42,24.15 152.43,24.14 PU5101.16 ; 152.42,24.15 152.42,24.38 152.64,24.59 PU5101.17 ; 152.42,24.15 152.42,22.77 151.76,22.12 150.52,22.12 PC5112.1 150.14,21.13 149.89,20.87 v2(149.66,20.87) ; PR5103.2 156.41,22.42 155.96,22.88 v2(155.7,22.88)
Q502_G: length 5.6
  BOTTOM w0.102: Q502.G 84.65,59.82 R506.2 84.05,60.42 83.74,60.42 v1(83.16,61) 83.39,61.23 84.53,61.23 Q501.D
Q5705_2: length 3.6
  BOTTOM w0.102: v1(14.33,58.01) 15.02,57.06 R5749.2 C5777.1 15.8,58.55 Q5705.2
Q5705_5_6: length 7.7
  BOTTOM w0.102: R5747.1 20.57,58.62 20.5,58.69 19.94,58.69 18.49,60.14 18.11,60.14 17.45,59.48 v1(17.45,59.45) 17.07,59.45 16.53,60 Q5705.6 16.53,60.84 16.42,60.94 15.98,60.94 15.88,60.84 Q5705.5
Q6204_G: length 6.6
  BOTTOM w0.254: 139.42,11.07 139.42,11.9 139.36,11.97 139.36,12 139.2,12.16 137.95,12.16 137.32,11.52 v1(137.08,11.52) 137.06,11.55 135.84,11.55 R6510.2 ; 139.42,11.07 Q6504.2 ; 139.42,11.07 Q6504.5
Q6205_Q: length 4.5
  TOP w0.381: v2(129.59,8.04) 130.15,7.49 R6503.2 130.48,7.43 v1(130.48,6.42)
  BOTTOM w0.381: v2(129.59,8.04) 130.07,8.04 130.66,8.63 Q6503.D
RESET_OUT#: length 223.2
  TOP w0.127: v2(146.23,49.45) 146.2,49.45 145.48,48.72 144.97,48.72 144.54,49.15 136.38,49.15 136.36,49.14 134.39,49.14 133.65,49.87 126.33,49.87 124.84,51.36 v2(124.84,51.48) ; v2(159.13,43.81) 159.13,45.04 160.16,46.07 160.16,46.57 160.34,46.75 160.34,48.77 159.96,49.14 159.96,50.56 159.7,50.82 159.7,53.28 160.79,54.37 160.79,61.23 160.64,61.39 160.64,65.4 161.29,66.06 161.29,75.94 161,76.24 161,79.35 162.65,81 v2(162.65,81.38) 162.65,82.6 157.86,87.38 157.86,92.58 153.46,96.98 151.4,96.98 R2616.2 149.91,96.41 C2614.1 148.97,95.65 147.83,96.79 v2(147.32,96.79)
  L4SGND w0.127: v2(159.13,43.81) 159.13,44.8 157.53,46.4 157.53,49.6 157.33,49.8 154.96,49.8 154.95,49.81 154.58,49.81 154.57,49.8 153.15,49.8 152.24,50.72 149.63,50.72 148.36,49.45 v2(146.23,49.45)
  L6 w0.127: v2(102.23,16.4) 102.33,16.31 111.59,16.31 112.99,14.9 135,14.9 135.91,13.99 152.5,13.99 152.86,13.63 159.06,13.63 160.95,15.52 160.95,15.72 166.16,20.93 166.16,30.02 163.6,32.58 163.6,35.48 159.11,39.98 159.11,41.8 158.79,42.11 158.79,42.72 158.51,43 158.51,43.37 158.95,43.81 v2(159.13,43.81)
  BOTTOM w0.127: v2(102.23,16.4) 101.34,17.29 v1(100.84,17.29) U2401.73 ; R1706.1 123.19,57.68 123.57,57.3 125.48,57.3 125.73,57.04 125.73,55.01 125.6,54.88 123.44,54.88 123.19,54.63 123.19,53.13 v2(124.84,51.48) ; Q2602.G 147.27,96.74 v2(147.32,96.79) ; v2(162.65,81.38) 163.49,81.38 163.53,81.35 165.4,81.35 166.06,82 ED1703.2
REXT: length 5.7
  TOP w0.102: R5704.2 32.82,62.86 32.69,62.73 v1(32.38,62.73) 31.52,62.73 31.06,63.19 30.25,63.19 30.17,63.11 28.8,63.11 U5701.C6
REXT_R: length 3.7
  TOP w0.102: R5734.1 32.64,64.74 R5704.1 32.56,64.31 32.41,64.31 v2(31.88,63.77)
  BOTTOM w0.102: R5705.2 31.37,63.44 v1(31.34,63.47) 31.65,63.77 v2(31.88,63.77)
RING2_R: length 3.1
  BOTTOM w0.508: 4.45,18.41 HPMIC1.3 ; HPMIC1.3 3.8,18.41 ; HPMIC1.3 4.35,19.25 3.58,18.48
  vias: v1(6.35,15.89)
RSMRST_PWRGD#: length 7
  BOTTOM w0.102: R4033.2 R4030.2 163.7,75.89 R4029.2 162.36,75.84 R4031.2 161.59,76.14 v1(161.04,75.58) 160.4,76.22 R4032.2 159.74,76.29 D4002.K
RTC_3P3_EN_D: length 2.2
  BOTTOM w0.254: v1(150.52,53.28) 150.65,53.16 Q2510.D
  BOTTOM w0.508: Q2510.D 151.51,53.94 R2511.1
RTC_3P3_EN_G: length 11
  BOTTOM w0.102: C2517.1 160.32,50.82 R2567.2 159.72,51.43 159.72,52.27 159.55,52.43 D2502.A 158.88,52.09 158.33,51.54 v1(157.48,51.54) 155.57,51.54 154.5,50.47 153.01,50.47 Q2510.G
RTC_AUX_S5: length 226.4
  TOP w0.508: v2(15.35,17.81) 15.35,17.81 15.99,17.17 16.64,17.17 16.76,17.29 16.84,17.29 R2754.1 ; R2204.1 148.72,56.9 149.22,56.41 149.23,56.41 150.37,55.27 v2(150.37,54.55) 150.16,54.55 148.94,53.33 147.45,53.33 147.35,53.23 147.32,53.23 145.46,51.37 143.92,50.73 R1730.1 143.81,50.69 v2(142.62,50.69)
  L3SGND w0.508: v2(62.36,3.7) 62.36,3.32 61.34,2.3 37.57,2.3 36.35,3.52 36.35,4.56 32.89,8.02 31.61,8.02 30.34,9.29 26.53,9.29 25.77,10.05 18.24,10.05 15.24,13.06 15.24,17.7 v2(15.35,17.81) ; v2(142.62,50.69) 142.88,50.69 144.53,49.04 144.53,43.71 148.59,39.64 148.59,34.39 153.37,29.61 155.7,29.61 158.34,26.97 158.34,23.97 152.3,17.93 133.22,17.93 132.59,17.29 125.47,17.29 122.68,14.51 122.68,14.24 116.46,8.02 103.75,8.02 99.44,3.71 v2(99.44,2.18)
  L6 w0.508: v2(99.44,2.18) 99.19,1.92 64.14,1.92 v2(62.36,3.7)
  BOTTOM w0.356: RN1801.2 139.27,50.75 139.6,51.07 139.27,51.4 RN1801.1
  BOTTOM w0.381: 139.6,51.07 140.23,50.44 142.37,50.44 v2(142.62,50.69)
  BOTTOM w0.508: v2(150.37,54.55) 150.88,55.06 R2511.2 152.3,55.06 v1(152.81,54.55) 152.86,54.55 153.59,53.82 R2512.2 154.05,53.16 Q2507.D
RTC_DET#: length 19.5
  BOTTOM w0.076: CPU1.CP22 135.27,77.08 135.51,77.08 135.65,77.22 arc(135.7,77.25) 135.75,77.27 arc(135.75,77.27) 135.75,77.27 arc(135.79,77.28) 135.82,77.28 135.91,77.28 arc(136.01,77.26) 136.1,77.2 136.18,77.13 137.14,77.13
  BOTTOM w0.127: 137.14,77.13 137.43,77.13 138.94,78.63 v1(147.57,78.63) 149.28,78.63 149.86,78.05 Q2505.D 149.67,77.05 149.67,75.32 R1554.2 149.78,75.08 R1521.1
RTC_RST#: length 55.1
  TOP w0.127: v2(147.58,52.59) 147.53,52.59 146.09,51.15 144.27,50.4 144.12,50.25 136.76,50.25 136.2,50.81 135.54,50.81 v2(135.31,50.57) 134.54,50.57 133.38,51.73 131.14,51.73 127.79,55.09 127.79,56.43 126.24,57.97 126.24,58.81 125.76,59.3 125.76,60.55 126.59,61.38 126.59,65.26 124.94,66.9 v2(124.94,66.9)
  BOTTOM w0.076: 124.7,67.51 124.7,67.74 124.57,67.97 124.57,68.91 CPU1.BR34
  BOTTOM w0.127: v2(124.94,66.9) 124.7,67.14 124.7,67.51 ; v2(147.58,52.59) 147.71,52.72 150.01,52.72 151.09,51.64 151.09,50.57 150.98,50.46 150.98,49.95 151.19,49.74 152.84,49.74 G1801.2 153.42,48.64 v1(154.12,47.94) 154.16,47.9 Q1802.D ; v2(135.31,50.57) 135.24,50.64 134.82,50.64 ED1801.1 134.53,51.07 134.65,51.2 C1806.1 135.77,51.49 136.85,51.49 136.94,51.4 RN1801.4
RTCRST_ON: length 112.3
  TOP w0.102: v2(151.43,50.23) 149.73,48.54 v1(149.73,48.53) 148.43,47.23 148.43,46.75 148.29,46.6 148.29,45.03 150.11,43.2 v2(150.11,41.42)
  L4SGND w0.102: v2(83.31,24.53) 83.87,23.98 93.07,23.98 95.1,26 106.61,26 107.1,26.48 111.26,26.48 113.75,28.97 125.77,28.97 126.23,29.43 139.75,29.43 140.08,29.1 142.5,29.1 142.53,29.13 142.62,29.13 143.1,29.61 147.77,29.61 148.45,29.61 149.33,30.49 149.33,31.52 149.15,31.69 149.15,36.67 151.49,39.01 151.49,40.41 150.99,40.91 150.99,40.95 150.52,41.42 v2(150.11,41.42)
  BOTTOM w0.102: v2(151.43,50.23) 154.59,50.23 155.38,51.02 Q2507.G 156.54,50.5 EC1804.1 156.87,50.06 157.38,49.55 Q1802.G 158.05,48.85 R1816.1 158.42,49.22 R2518.1 159.23,49.29 159.61,49.67 159.86,49.67 160.22,50.03 R2567.1 160.05,50.23 D2502.K ; v2(83.31,24.53) 83.31,23.64 81.93,22.26 81.93,20.21 82.08,20.06 82.59,20.06 82.63,20.09 U2401.31
SATA_PCIE_LED#: length 6.7
  BOTTOM w0.127: D6401.3 v1(128.73,12.97) 128.65,13.05 128.65,13.1 127.2,14.55 R6420.2 127,15.39 126.37,16.02 125.1,16.02 Q6403.S
SD_RCOMP: length 4.1
  TOP w0.508: v2(134.08,68.96) 134.33,69.21 v1(134.33,70.5) 134.33,71.37 R1901.1
  BOTTOM w0.254: CPU1.CK33 133.38,69.43 CPU1.CM34 134.08,69.18 v2(134.08,68.96)
SIO_EXT_SCI#: length 15.2
  TOP w0.089: R1608.1 148.31,89.68 v2(148.18,89.55)
  BOTTOM w0.089: v2(148.18,89.55) 147.2,88.57 146.48,88.57 144.92,87.01 v1(141.6,87.01) 138.89,87.01 137.69,85.81 CPU1.CR8
SIO_EXT_SMI#: length 15.5
  TOP w0.102: v2(146.38,89.53) 146.43,89.53 147.15,90.25 149.24,90.25 R402.2
  BOTTOM w0.102: CPU1.CP7 135.69,86.62 137.06,86.62 137.57,87.12 137.57,87.12 138.45,88 139.82,88 139.83,88 140.33,88 140.34,88 144.62,88 v1(144.78,88.16) 146.15,89.53 v2(146.38,89.53)
SIO_EXT_WAKE#: length 184.9
  TOP w0.102: v2(138.42,82.76) 138.27,82.6 R2041.2 ; v2(154.81,83.97) 155.46,83.32 155.46,77.95 155.81,77.61 155.81,68.31 155.44,67.93 155.44,62.93 155.36,62.85 155.36,58.99 155.37,58.97 155.37,57.6 153.48,55.71 153.48,54.39 153.15,54.06 153.15,53.25 152.95,53.04 152.95,48.46 152.39,47.9 152.39,45.83 152.15,45.59 152.15,45.1 152.77,44.48 153.75,44.48 154.04,44.19 154.04,44.12 154.05,44.11 v2(154.05,43.48)
  L6 w0.102: v2(154.05,43.48) 155.57,41.96 155.57,39.28 160.46,34.38 160.46,30.16 161.91,28.71 161.91,24.12 162.29,23.74 162.29,21.84 158.52,18.06 156.19,18.06 155.74,17.61 142.17,17.61 140.13,19.65 131.27,19.65 129.36,17.75 115.45,17.75 112.16,21.04 102.3,21.04 100.67,19.41 100.4,19.41 97.42,16.43 95.9,16.43 95.9,16.44 93.16,16.44 92.83,16.77 92.14,16.77 92.14,16.78 89.07,16.78 88.78,16.48 88.78,16.41 v2(88.65,16.27)
  BOTTOM w0.076: v2(138.42,82.76) 138.19,82.53 136.32,82.53 136.14,82.71 136.11,82.71 arc(135.81,82.78) 135.56,82.96 135.56,82.96 135.49,83.03 134.91,83.03 CPU1.CN12
  BOTTOM w0.102: v2(138.42,82.76) 138.55,82.76 138.78,82.52 142.32,82.52 144.11,84.31 146.01,84.31 v1(146.55,84.84) 148.26,86.56 153.18,86.56 154.2,85.53 154.2,84.57 v2(154.81,83.97) ; U2401.116 89.91,7.28 89.38,7.82 89.38,9.68 88.42,10.64 88.42,12.62 88.66,12.86 88.66,14.51 88.42,14.75 88.42,16.05 v2(88.65,16.27)
SIO_PWRBTN#: length 122
  TOP w0.102: v2(124.69,60.48) 124.69,61.55 124.34,61.91 124.34,67.21 125.98,68.85 125.98,70.4 126.28,70.7 126.28,72.52 v2(125.86,72.94)
  L4SGND w0.102: v2(143.76,47.26) 143.46,46.96 143.46,44.89 148.84,39.51 148.84,37.64 148.34,37.13 148.34,31.36 148.51,31.19 148.51,30.83 148.11,30.42 142.75,30.42 142.32,30.85 139.93,30.85 139.57,30.5 114.12,30.5 111.17,27.55 94.84,27.55 v2(91.95,24.66)
  L6 w0.102: v2(124.69,60.48) 124.78,60.39 125.68,60.39 126.75,59.33 126.75,58.33 126.74,58.32 126.74,57.96 126.75,57.96 126.75,56.46 132.96,50.25 133.81,50.25 136.8,47.26 v2(143.76,47.26)
  BOTTOM w0.102: CPU1.BU28 125.62,73.18 v2(125.86,72.94) ; U2401.52 92.71,22.52 92.48,22.75 v1(92.48,24.12) v2(91.95,24.66)
SIO_RCIN#: length 24.3
  TOP w0.089: v2(126.74,72.24) 127.25,72.75 127.25,73.81 127.51,74.06 127.89,74.06 128.14,73.81 128.14,71.31 128.22,71.24 128.22,70.36 128.36,70.22 128.36,69.89 127,68.53 127,65.92 127.46,65.46 128.57,65.46 130.36,63.68 130.36,63.05 129.51,62.19 129.51,58.29 v1(129.88,57.92) R1820.2
  BOTTOM w0.089: CPU1.BV29 126.45,72.53 v2(126.74,72.24)
SKTOCC#: length 7.7
  BOTTOM w0.102: TP619.1 87.88,88.66 90.38,91.16 93.31,91.16 93.59,90.88 93.59,90.35 CPU1.E1
SLEEVE_R: length 2.1
  BOTTOM w0.508: 3.85,29.64 HPMIC1.4 5.15,28.8
  vias: v1(16.51,27.7)
SM_DRAMRST#: length 163.4
  TOP w0.089: v2(146.56,48.15) 146.56,48.15 146.56,44.73 v2(146.3,44.47) ; v2(140.88,54.15) 140.04,54.99 140.03,54.99 139.78,55.24 139.78,56.57 138.43,57.93 137.05,57.93 136.59,58.39 136.17,58.39 135.64,57.85 R504.2 135.64,57.64 135.38,57.38 C501.1
  L6 w0.089: v2(140.88,54.15) 141.09,53.95 141.09,53.94 141.34,53.69 141.34,53.69 141.48,53.55 141.48,52.08 142.44,51.12 143.18,51.12 144.45,49.85 145.48,49.85 145.75,49.58 145.75,48.96 v2(146.56,48.15) ; v2(59.27,31.52) v2(69.42,31.52) 79.55,31.52 v2(79.93,31.9) 80.44,31.39 89.88,31.39 v2(90.19,31.7) 90.64,31.25 99.09,31.25 99.77,31.92 102.48,31.92 102.81,31.59 111.9,31.59 v2(112.24,31.93) 112.76,31.4 121.7,31.4 v2(121.79,31.49) 121.91,31.6 131.63,31.6 v2(131.84,31.39) 131.85,31.39 140.11,31.39 v2(140.51,31.79) 141.83,30.47 142.13,30.47 142.14,30.48 143.81,30.48 143.85,30.52 148.19,30.52 148.51,30.83 148.51,32.86 148.07,33.3 148.07,36.71 148.5,37.14 148.5,39.98 146.35,42.14 146.35,43.5 146.3,43.55 v2(146.3,44.47)
  BOTTOM w0.089: v2(112.24,31.93) 112.24,32.45 110.98,33.7 110.76,33.7 110.47,33.99 110.47,34.58 RAM6.P1 ; RAM8.P1 130.77,34.58 130.77,33.99 131.06,33.7 131.28,33.7 131.84,33.14 v2(131.84,31.39) ; RAM3.P1 68.12,34.58 68.12,33.99 68.15,33.98 68.34,33.79 68.6,33.79 68.63,33.78 68.67,33.78 69.42,33.02 v2(69.42,31.52) ; RAM5.P1 120.62,34.58 120.62,33.99 120.91,33.7 121.13,33.7 121.79,33.04 v2(121.79,31.49) ; v2(140.51,31.79) 140.8,31.79 141.29,32.28 141.73,32.28 141.99,32.53 141.99,33.14 141.43,33.7 141.21,33.7 140.92,33.99 140.92,34.58 RAM7.P1 ; RAM1.P1 88.43,34.59 88.43,34 88.64,33.79 88.82,33.79 90.19,32.43 v2(90.19,31.7) ; v2(59.27,31.52) 59.27,33 58.58,33.7 58.2,33.7 57.97,33.92 57.97,34.58 RAM4.P1 ; RAM2.P1 78.27,34.58 78.27,33.95 78.44,33.78 78.94,33.78 79.93,32.79 v2(79.93,31.9)
SM_DRAMRST#_CPU: length 24.8
  TOP w0.089: v2(136.02,59.45) 135.95,59.45 135.3,58.81 135.3,58.43 134.96,58.09 134.96,57.92 134.79,57.75 134.79,57.74 R504.1 134.62,57.57 R505.2
  L6 w0.089: v2(125.85,71.58) 125.48,71.2 125.48,70.61 125.87,70.22 125.87,65.63 126.38,65.12 126.38,64.97 133.18,58.17 135.87,58.17 136.3,58.6 136.3,59.17 v2(136.02,59.45)
  BOTTOM w0.089: CPU1.BU31 125.5,71.23 v2(125.85,71.58)
SM_INTRUDER#: length 32.2
  TOP w0.102: R1730.2 143.56,51.63 143.18,51.25 v1(143.02,51.25) 143.02,51.31 v2(142.62,51.71)
  L6 w0.102: v2(123.61,67.31) 123.61,65.52 125.31,63.82 125.51,63.82 131.46,57.87 131.46,57.59 132.38,56.67 132.92,56.67 133.07,56.81 140.81,56.81 142.24,55.38 142.24,52.29 142.62,51.91 v2(142.62,51.71)
  BOTTOM w0.076: CPU1.BR35 124.28,68.85 124.01,68.37 124.01,68.28 123.93,68.2 123.93,67.89 arc(123.87,67.78) 123.85,67.67 123.85,67.54 v2(123.61,67.31)
SM_PGCNTL: length 10.7
  BOTTOM w0.102: Q501.G v1(86.45,64.36) 90.47,68.38 91.51,68.38 91.69,68.56 92.21,68.56 CPU1.C35
SM_RCOMP_0: length 2.4
  TOP w0.254: R501.1 123.67,74.19 123.67,73.2 123.36,72.9 123.16,72.9 123.13,72.87 123.13,72.87 v2(123.16,72.87)
  BOTTOM w0.203: CPU1.BN28 122.82,73.18 123.13,72.87 123.13,72.87 v2(123.16,72.87)
SM_RCOMP_1: length 1.4
  TOP w0.254: R502.1 123.14,74.06 123.14,73.55 v2(123.16,73.53)
  BOTTOM w0.203: v2(123.16,73.53) 123.15,73.55 123.15,73.57 122.89,73.83 CPU1.BN27
SM_RCOMP_2: length 3.6
  TOP w0.254: R503.1 122.19,74.19 122.68,73.71 122.68,72.67 123.11,72.24 v2(123.11,72.24) 123.18,72.24 123.47,71.95 v1(123.62,71.95)
  BOTTOM w0.203: v2(123.11,72.24) 123.1,72.24 122.81,72.53 CPU1.BN29
SPI_CLK_CPU: length 14.4
  BOTTOM w0.089: CPU1.CH37 131.65,67.42 131.65,67.29 132.79,66.16 132.79,65.76 132.9,65.65 133.17,65.65 133.27,65.55 133.27,65.4 133.17,65.3 132.9,65.3 132.79,65.19 132.79,64.97 133.1,64.66 133.53,64.66 133.69,64.82 133.69,65.34 133.79,65.45 133.94,65.45 134.05,65.34 134.05,64.71 134.16,64.59 135.16,64.59 135.29,64.46 135.29,64 135.4,63.9 135.54,63.9 135.65,64 135.65,64.5 135.74,64.59 136.02,64.59 136.11,64.5 v1(136.11,64.29) 136.11,63.86 R9138.1 136.05,63 136.05,61.83 136.12,61.77 136.32,61.77 136.4,61.69 136.4,61.11 136.3,61 R2508.2
SPI_CLK_HDMI: length 18.3
  TOP w0.089: v2(23.11,49.17) v1(22.48,49.17) ; v2(24.77,61.45) 24.77,61.47 U5701.D2
  L6 w0.089: v2(23.11,49.17) 23.11,50.19 24.22,51.29 24.22,54.65 22.61,56.26 22.61,57.8 22.82,58.02 23.58,58.02 24.26,58.7 24.26,60.95 v2(24.77,61.45)
  BOTTOM w0.089: U5702.6 24,49.09 R5743.1 23.85,48.96 23.65,49.17 v2(23.11,49.17)
SPI_CLK_PD: length 32.5
  L6 w0.089: v2(15.49,76.22) 15.46,76.22 14.45,75.2 14.45,67.3 15.41,66.34 15.41,56.19 13.84,54.62 13.84,53.24 v2(14.73,52.34)
  BOTTOM w0.089: U7202.6 16.38,53.61 15.11,52.34 v2(14.73,52.34) ; v2(15.49,76.22) 15.37,76.35 v1(15.37,76.98) 15.49,77.11 15.54,77.11 15.77,77.33 U7201.A3
SPI_CLK_ROM: length 12.9
  BOTTOM w0.089: R2508.1 136.22,60.47 136.47,60.47 136.6,60.34 136.6,59.99 136.44,59.84 136.44,59.42 136.92,58.95 137.17,58.95 137.25,58.86 EC2503.1 137.09,58.73 136.83,58.46 136.83,58.12 136.92,58.03 137.63,58.03 137.72,58.12 137.72,58.98 137.81,59.07 138.24,59.07 138.33,58.98 v1(138.33,58.41) 138.33,58.08 138.47,57.94 138.87,57.94 138.98,57.83 138.98,57.5 139.08,57.4 139.23,57.4 139.33,57.5 139.33,58.11 139.44,58.22 139.59,58.22 139.69,58.11 139.69,57.53 139.79,57.42 139.94,57.42 140.04,57.53 140.04,58.15 140.11,58.21 140.54,58.21 140.81,57.94 BIOS1.6
SPI_CLK_TPM: length 42.6
  L4SGND w0.089: v2(167.15,54.65) 166.23,54.8 160.68,55.47 159.49,55.47 154.75,60.21 153.14,60.21 151.38,59.14 151.16,59.03 150.85,59.03 150.05,59.36 145.45,59.36 144.91,58.82 142.04,58.82 141.07,59.78 141.07,60.08 140.1,61.05 138.43,61.82 v2(135.65,61.87)
  BOTTOM w0.089: v2(167.15,54.65) 166.82,54.98 166.82,58.45 v1(166.76,58.51) 165.49,59.78 165.39,59.81 U9102.19 ; R9138.2 v2(135.65,61.87)
SPI_CS2_TPM: length 21
  BOTTOM w0.089: R9130.2 R9148.2 161.11,54.5 R9140.2 161.87,53.1 v1(161.32,52.55) 161.21,52.44 161.21,51.31 162.26,50.26 162.42,50.13 166.17,50.13 166.53,50.48 166.53,52.8 166.35,52.98 166.35,58.25 165.29,59.31 U9102.20
SPI_CS_CPU_N0: length 25.7
  BOTTOM w0.076: CPU1.CG36 131.17,67.99 131.71,68.53 131.93,68.53 132.14,68.32 132.14,67.94 132.36,67.53 132.36,67.25
  BOTTOM w0.089: 132.36,67.25 133.16,66.45 133.73,66.45 135.08,65.1 137.36,65.1 138,64.46 138,63.62 v1(138.33,63.29) 138.68,62.93 138.68,62.2 R2519.2 139.4,61.49 140.74,61.49 140.87,61.36 142.62,61.36 143.06,61.8 143.96,61.8 144.4,61.36 144.4,60.79 144.55,60.65 144.55,60.14 144.65,60.03 144.8,60.03 144.9,60.14 144.9,60.65 145.01,60.75 145.15,60.75 145.26,60.65 145.26,60.14 145.36,60.03 145.51,60.03 145.61,60.14 145.61,60.65 145.72,60.75 145.86,60.75 145.97,60.65 145.97,60.14 146.07,60.03 146.72,60.03 147.17,60.48 BIOS1.1
SPI_CS_CPU_N2: length 45.6
  L6 w0.089: v2(132.37,69.34) 132.37,67.01 135.73,63.65 145.21,63.65 145.75,63.11 145.89,62.97 145.89,61.13 145.19,60.43 145.19,55.36 146.11,54.45 147.04,54.45 v2(147.06,54.42)
  BOTTOM w0.089: R9130.1 159.72,53.01 v1(157.35,53.01) 156.69,53.01 155.7,53.99 154.44,53.99 153.33,55.1 153.33,55.86 152.53,56.65 151.4,56.65 149.66,54.92 149.66,54.35 148.92,53.61 147.88,53.61 v2(147.06,54.42) ; CPU1.CH34 v2(132.37,69.34)
SPI_CS_HDMI: length 11.9
  TOP w0.089: v2(23.24,62.38) 24.07,62.38 U5701.C1
  L6 w0.089: v2(23.24,58.95) 22.61,59.58 22.61,61.99 22.99,62.38 v2(23.24,62.38)
  BOTTOM w0.089: 21.46,55.33 20.69,55.33 R5740.2 20.19,56.11 21.46,57.38 v1(21.46,58.31) 22.4,58.31 23.03,58.95 v2(23.24,58.95)
SPI_CS_PD: length 37.9
  L6 w0.089: v2(14.73,53.61) 14.31,54.04 14.31,54.42 15.88,56 15.88,66.53 14.92,67.5 14.92,75.01 v2(15.49,75.58)
  BOTTOM w0.089: v2(14.73,53.61) 14.48,53.61 v1(13.97,53.1) 13.97,52.44 14.54,51.87 18.33,51.87 18.49,52.04 R7228.1 19.74,51.58 19.56,51.58 18.92,50.95 U7202.1 ; v2(15.49,75.58) 14.99,76.09 14.99,77.31 15.53,77.86 15.53,78.93 U7201.B3
SPI_HOLD_CPU: length 21.8
  TOP w0.089: R1510.2 141.02,61.69 v2(140.72,61.99) ; R1510.2 141.02,59.99 R2503.2 ; R1510.2 R1511.1
  BOTTOM w0.089: CPU1.CG34 131.91,69.21 132.18,68.94 132.55,68.94 132.71,68.77 132.71,68.18 132.89,68 132.91,68 133.57,67.34 133.57,67.02 135.32,65.28 137.43,65.28 138.18,64.53 v1(138.81,64.53) 139.36,63.98 139.49,63.98 140.05,64.54 140.18,64.54 140.3,64.42 140.3,64.29 139.74,63.73 139.74,63.6 139.87,63.48 139.99,63.48 140.55,64.04 140.68,64.04 140.8,63.91 140.8,63.79 140.24,63.23 140.24,63.1 140.37,62.97 140.5,62.97 141.06,63.54 141.18,63.54 141.56,63.15 141.56,63.02 140.72,62.18 v2(140.72,61.99)
SPI_HOLD_HDMI: length 3.5
  BOTTOM w0.089: U5702.7 22.61,50.25 22.61,48.41 22.43,48.23 R5742.2 v1(22.1,47.36)
SPI_HOLD_PD: length 3.3
  BOTTOM w0.089: R7226.1 17.1,57.94 17.1,56.96 17.65,56.41 17.65,55.45
SPI_HOLD_ROM: length 5.1
  TOP w0.089: v1(142.11,59.07) 142.19,59.07 v2(142.6,59.48) 142.11,59.96 R2503.1
  BOTTOM w0.089: BIOS1.7 141.95,59.21 142.29,58.87 143.32,58.87 143.41,58.96 143.41,59.27 143.32,59.36 142.71,59.36 v2(142.6,59.48)
SPI_IRQ#_TPM2: length 10.2
  TOP w0.089: v2(165.61,60.47) 166.03,60.04 166.03,56.67 v2(165.59,56.23)
  BOTTOM w0.089: v2(165.59,56.23) 165.74,56.08 v1(165.74,54.5) 165.15,55.09 R9149.1 ; R9137.1 R9139.2 165.86,60.22 v2(165.61,60.47) 165.45,60.31 U9102.18
SPI_SI_CPU: length 11.3
  BOTTOM w0.076: 131.51,66.93 131.23,67.21 130.49,67.21 130.26,67.44 130.26,67.68 130.34,67.88 130.34,68.06 CPU1.CF36
  BOTTOM w0.089: R9133.1 134.08,63.91 R2509.2 R1507.1 R1506.2 131.83,63.91 131.75,63.82 131.75,63.1 131.68,63.04 131.41,63.04 131.32,63.12 131.32,63.95 131.6,64.23 131.79,64.36 132.07,64.36 132.24,64.52 v1(132.24,64.94) 132.24,66.21 131.51,66.93
SPI_SI_HDMI: length 22.9
  TOP w0.089: v2(23.24,61.74) 24.23,61.74 U5701.D1
  L6 w0.089: v2(23.24,61.74) 23.67,61.31 23.67,58.77 23.39,58.49 22.63,58.49 22.14,58 22.14,56.07 23.75,54.45 23.75,51.49 22.48,50.22 22.48,48.53 v2(23.11,47.9)
  BOTTOM w0.089: v2(23.11,47.9) 23.86,47.15 v1(24.17,47.15) 24.38,47.15 24.47,47.24 24.47,49.13 25.27,49.93 U5702.5
SPI_SI_PD: length 31.3
  L6 w0.089: v2(14.73,52.98) 16.41,54.66 16.41,66.76 15.45,67.72 15.45,74.52 16.51,75.58 v2(16.64,75.58)
  BOTTOM w0.089: v2(14.73,52.98) 14.99,52.98 15.24,53.23 15.24,54.37 15.11,54.5 15.11,55.45 ; U7201.B4 16.03,78.93 v1(16.03,75.84) 16.28,75.58 v2(16.64,75.58)
SPI_SI_ROM: length 17
  BOTTOM w0.089: R2509.1 133.61,62.85 133.61,62.44 133.7,62.35 134,62.35 134.09,62.26 134.09,62 134,61.91 133.7,61.91 133.61,61.82 EC2501.1 133.62,61.22 133.91,61.22 134,61.13 134,60.94 133.65,60.59 132.78,60.59 132.61,60.42 132.61,58.85 132.9,58.57 133.02,58.57 133.07,58.62 133.2,58.62 133.33,58.49 133.33,58.37 133.27,58.32 133.27,58.19 v1(134.37,57.1) 134.4,57.07 134.72,57.07 134.8,57.16 134.8,57.33 134.89,57.42 135.07,57.42 135.16,57.33 135.16,57.16 135.25,57.07 136.67,57.07 136.93,57.32 138.35,57.32 138.81,56.86 140.88,56.86 141.07,56.67 BIOS1.5
SPI_SI_TPM: length 54.1
  L4SGND w0.089: v2(161.67,51.83) 161.16,52.34 160.05,52.34 159,53.39 157.08,53.39 155.61,51.92 154.64,51.92 154.31,52.25 154.31,52.6 154.5,52.79 155.84,53.14 156.79,54.09 156.79,55.95 155.33,57.41 152.83,57.41 151.68,57.88 150.14,58.21 149.74,58.61 148.97,58.61 146.53,58.21 145.32,58.35 141.31,58.35 140.21,59.45 140.21,59.86 139.93,60.14 138,61.49 135.84,61.49 135.82,61.47 134.97,61.47 v2(134.61,61.82)
  BOTTOM w0.089: v2(134.61,61.82) 134.59,61.85 R9133.2 ; U9102.21 165.13,58.81 165.75,58.48 166.08,58.14 166.08,52.87 166.26,52.69 166.26,50.59 166.06,50.39 162.52,50.39 162.44,50.46 162.13,50.77 v1(161.93,51.2) v2(161.67,51.83)
SPI_SO_CPU: length 16.3
  BOTTOM w0.089: CPU1.CF37 130.69,67.41 131.28,67.41 132.56,66.13 132.56,64.81 133.11,64.27 v1(134.68,64.27) 135.01,63.93 135.01,61.66 133.77,60.41 133.21,60.41 132.98,60.18 132.98,59.22 133.43,58.77 134.28,58.77 134.47,58.95 R9132.1 134.75,58.69 134.75,58.56 R2506.1
SPI_SO_HDMI: length 16.6
  TOP w0.089: U5701.C2 24.91,62.69 24.51,63.09 23.43,63.09 v2(23.24,63.01)
  L6 w0.089: v2(23.24,63.01) 23.23,63.01 21.87,61.65 21.87,54.86 v2(23.24,53.49)
  BOTTOM w0.089: v2(23.24,53.49) 22.73,53.99 U5702.2 22.73,56.53 v1(22.35,56.91)
SPI_SO_PD: length 35.2
  L6 w0.089: v2(14.73,54.25) 16.15,55.66 16.15,66.65 15.18,67.61 15.18,74.63 16.05,75.5 16.05,75.75 v2(16.51,76.22)
  BOTTOM w0.089: v2(16.51,76.22) 16.23,76.5 16.23,78.63 U7201.A4 ; v2(14.73,54.25) 14.31,54.25 13.21,53.15 v1(13.21,52.09) 13.64,51.66 R7230.1 13.89,51.45 17.53,51.45 17.65,51.33 17.65,50.5
SPI_SO_ROM: length 20.9
  BOTTOM w0.089: BIOS1.2 149.17,59.21 EC2502.1 150.59,57.78 150.59,57.15 149.49,56.05 147.43,56.05 147.19,56.3 143.46,56.3 142.48,57.28 140.3,57.28 140.15,57.13 138.92,57.13 138.37,57.67 v1(137.36,57.67) 136.9,57.67 136.59,57.36 136.16,57.36 135.54,57.99 R2506.2
SPI_SO_TPM: length 40
  TOP w0.089: v2(141.6,54.76) 141.6,55.6 138.97,58.23 138.67,58.53 138.38,58.53 136.84,58.99 136.83,58.99 136.61,59.21 136.61,59.7 136.26,60.05 135.6,60.05 v2(135.15,60.5)
  BOTTOM w0.089: v2(135.15,60.5) 135.02,60.37 R9132.2 ; v2(141.6,54.76) 142.09,55.24 142.49,55.24 144.56,54.85 147.3,54.85 148.28,53.87 148.8,53.87 149.35,54.42 149.35,54.99 151.13,56.76 151.29,56.92 152.65,56.92 153.59,55.97 153.59,55.21 154.55,54.26 155.81,54.26 156.71,53.36 159.55,53.36 159.83,53.64 159.83,54.73 159.96,54.86 161.54,55.14 161.62,55.14 v1(163.32,55.39) 164.13,56.03 164.34,56.24 164.34,56.64 164.75,57.05 U9102.24
SPI_WP_CPU: length 14.1
  BOTTOM w0.076: 132.08,67.2 132.08,67.7 132.05,67.76 131.93,67.88 131.63,67.88 131.36,67.61 130.91,67.61 130.78,67.74 130.78,69.26 130.77,69.28 CPU1.CF34
  BOTTOM w0.089: R2507.1 136.78,60.75 v1(136.78,61.51) 136.8,61.54 136.8,62.3 R1508.2 R1509.1 136.6,64.71 136.39,64.92 134.87,64.92 133.65,66.15 133.13,66.15 132.08,67.2
SPI_WP_HDMI: length 7.9
  TOP w0.089: v2(24.78,60.71) 24.8,60.71 U5701.E2
  L6 w0.089: v2(24.78,60.71) 24.78,58.39 23.94,57.55 v2(23.24,57.55)
  BOTTOM w0.089: U5702.3 24,56.1 R5741.1 v2(23.24,57.55) v1(23.11,58.18)
SPI_WP_PD: length 5.5
  BOTTOM w0.089: U7202.3 16.38,49.55 16.85,49.08 v1(18.76,49.08) 19.09,49.08 20.19,50.18 R7225.1
SPI_WP_ROM: length 11.9
  BOTTOM w0.089: R2507.2 137.24,59.5 137.39,59.35 138.53,59.35 138.73,59.15 138.73,58.74 138.9,58.57 139.4,58.57 139.42,58.59 v1(139.53,58.59) 139.56,58.57 142.36,58.57 142.99,57.94 BIOS1.3
SPK_DET#_CON: length 4.7
  TOP w0.102: v2(15.11,7.57) 15.62,7.07 R2915.2 15.69,6.47 16.42,7.19 v1(16.42,7.21) 16.56,7.07 16.56,6.47 R2914.2
  BOTTOM w0.102: v2(15.11,7.57) SPK1.8
SPK_ID: length 272
  TOP w0.102: v2(14.1,6.62) 14.1,5.99 14.66,5.43 R2915.1 ; v2(154.43,41.42) 154.51,41.42 155.05,41.97 155.05,44.65 154.69,45.02 154.69,45.36 153.89,46.15 153.89,47.98 153.95,48.04 153.95,52.63 154.15,52.83 154.15,53.54 155.35,54.73 155.35,55.74 156.38,56.77 156.38,59.39 156.36,59.4 156.36,62.44 156.44,62.51 156.44,67.52 156.85,67.94 156.85,77.98 156.59,78.24 156.59,79.29 156.84,79.54 156.84,83.86 155.07,85.64 154.04,85.64 v2(153.77,85.36) 153.77,85.34 153.09,84.66 R2110.2
  L6 w0.102: v2(35.94,15.87) 36.05,15.98 38.65,15.98 39.65,14.98 46.25,14.98 46.51,14.72 48.73,14.72 49.1,15.09 49.46,15.09 50.12,14.43 50.23,14.43 53.87,10.79 65.13,10.79 68.68,14.34 77.84,14.34 81.5,18 82.6,18 83.83,19.23 83.83,19.97 87.76,23.89 87.76,24.76 88.09,25.09 88.44,25.09 88.7,24.84 88.7,20.64 88.53,20.48 88.53,19.9 90.66,17.78 92.55,17.78 92.56,17.77 93.24,17.77 93.58,17.44 96.32,17.44 96.32,17.44 97.01,17.44 99.98,20.41 100.26,20.41 100.51,20.67 100.51,22.62 101.45,23.56 104.91,23.56 107.57,26.22 130.21,26.22 135.18,21.25 140.12,21.25 140.36,21.01 140.36,20.88 142.63,18.61 155.32,18.61 155.78,19.07 158.1,19.07 161.29,22.26 161.29,22.9 160.88,23.31 160.88,28.32 160.81,28.4 159.46,29.75 159.46,33.97 154.24,39.19 154.24,41.22 v2(154.43,41.42)
  BOTTOM w0.102: v2(153.77,85.36) 153.65,85.24 151.9,85.24 150.27,83.61 144.99,83.61 143.29,81.91 138.47,81.91 138.4,81.98 138.24,81.98 138.23,81.97 135.97,81.97 CPU1.CR14 ; v2(14.1,6.62) 14.1,7.13 16.3,9.34 22.43,9.34 23.24,8.53 23.33,8.53 24.39,8.53 24.54,8.68 27.33,8.68 v1(27.88,9.23) 29.21,10.56 29.97,10.56 31.24,11.83 32.31,11.83 35.94,15.46 v2(35.94,15.87)
SPK_SCL_CODEC: length 42.4
  TOP w0.089: v2(28.13,18.33) 28.13,18.5 27.89,18.74 27.04,18.74 26.94,18.63 U2701.7
  L6 w0.089: v2(28.13,18.33) 27.9,18.06 27.9,6.06 23.02,1.19 18.72,1.19 16.14,3.77 16.14,5.85 15.62,6.37 15.21,6.37 v2(14.95,6.11)
  BOTTOM w0.089: RN2703.3 29.26,15.08 v1(28.27,15.08) 28.27,15.24 28.75,15.72 28.75,18.08 28.49,18.33 v2(28.13,18.33) ; v2(14.95,6.11) 15.21,6.37 15.39,6.37 15.8,5.95 17.44,5.95 17.65,6.15 17.65,6.5 17.73,6.59 17.96,6.59 18.05,6.68 SPK1.6
SPK_SDA_CODEC: length 40.9
  TOP w0.089: U2701.6 27.11,18.23 27.15,18.28 v2(27.48,18.28)
  L6 w0.089: v2(14.95,6.82) 15.21,6.56 15.7,6.56 16.33,5.93 16.33,3.85 18.8,1.38 22.94,1.38 27.71,6.14 27.71,18.09 v2(27.48,18.28)
  BOTTOM w0.089: RN2703.4 28.96,16.14 28.96,18.41 v1(28.25,19.11) 27.98,19.11 27.48,18.61 v2(27.48,18.28) ; SPK1.7 17.05,6.68 17.14,6.59 17.37,6.59 17.45,6.5 17.45,6.23 17.37,6.14 15.88,6.14 15.46,6.56 15.21,6.56 v2(14.95,6.82)
SPKR: length 296.9
  L4SGND w0.254: v2(131.69,65.38) 135.27,65.38 137.26,63.39 140.13,63.39 141.35,62.17 v2(141.35,61.99) 141.79,61.99 143.85,59.94 150.77,59.94 151.62,60.79 154.99,60.79 159.73,56.05 164.85,56.05 165.3,55.6 166.85,55.6 167.22,55.23 168.59,55.23 170.75,53.07 179.45,53.07 183.21,49.31 183.21,48.78 184.12,47.87 184.84,47.87 185.98,46.72 185.98,46.01 189.94,42.05 189.94,35.39 187.71,33.17 179.25,33.17 175.17,29.08 174.55,29.08 174.14,28.67 174.14,28.64 174.13,28.63 174.13,28.48 172.01,26.36 172.01,21.58 170.02,19.59 170.02,16.27 166.09,12.34 164.69,12.34 161.9,9.54 144.38,9.54 143.73,8.9 142.74,8.9 142.1,8.26 142.1,7.25 139.44,4.59 116.3,4.59 113.56,7.33 107.6,7.33 106.61,8.33 105.6,8.33 105.55,8.37 102.3,8.37 101.4,7.47 99.45,7.47 98.58,6.6 89.09,6.6 88.48,5.99 86.23,5.99 85.7,5.45 81.13,5.45 80.77,5.1 80.07,5.1 79.95,5.23 77.2,5.23 76.56,4.59 75.95,4.59 73.58,2.22 40.52,2.22 v2(39.17,3.57)
  BOTTOM w0.076: CPU1.CF35 130.2,68.57 130.16,68.36 130.16,67.89 130.09,67.69 130.09,67.36 130.09,67.36 130.42,67.03 131.16,67.03 131.9,66.29 131.9,65.59 v2(131.69,65.38)
  BOTTOM w0.254: v2(39.17,3.57) 38.18,4.56 35.71,4.56 33.12,7.16 31.89,7.16 31.88,7.15 27.07,7.15 24.78,4.86 23.13,4.86 23.1,4.82 20.34,4.82 20.3,4.86 13.09,4.86 12.47,4.23 v1(11.38,4.23) 10.65,4.23 RN2702.2 ; v2(141.35,61.99) 141.73,62.38 144.91,62.38 145.29,61.99 147.14,61.99 147.27,62.12 148.1,62.12 149.2,61.03 149.2,60.83 150.15,59.89 R1501.1
SRTC_RST#: length 29.3
  TOP w0.102: v2(135.83,50.22) 135.75,50.14 134.63,50.14 133.4,51.36 v1(131.44,51.36) 130.53,51.36 127.05,54.84 127.05,56.83 126,57.87 126,58.71 125.43,59.29 125.43,63.47 126.39,64.43 126.39,65.12 125.22,66.29 v2(124.96,66.29)
  BOTTOM w0.102: CPU1.BR37 124.35,67.5 124.35,66.52 124.58,66.29 v2(124.96,66.29) ; C1805.1 137.85,50.1 RN1801.3 137.23,50.75 137.05,50.93 ED1801.2 136.43,50.92 135.83,50.33 v2(135.83,50.22)
SSD_CLK_CPU_N: length 195.4
  L6 w0.089: v2(188.57,34.74) 188.57,34.95 188.3,35.22 187.92,35.22 187.64,35.5 187.64,35.88 187.56,35.96 187.56,40.78 186.32,42.02 186.32,46.59 183.71,49.2 183.71,49.36 180.82,52.26 178.82,52.26 177.74,53.33 174.01,53.33 169.67,57.68 169.67,59.43 169.37,59.73 169.37,70.17 169.34,70.21 169.34,72.2 171.04,73.91 171.04,74.6 171.68,75.24 171.68,79.95 167.2,84.43 167.19,84.43 159.26,92.36 159.26,96.99 156.13,100.12 151.47,100.12 151.01,100.58 145.91,100.58 145.15,99.81 140.85,99.81 140.04,100.63 132.5,100.63 130.45,102.68 130.02,102.68 129.77,102.93 129.55,102.93 128.48,102.93 126.64,104.77 121.84,104.77 120.31,103.24 117.9,103.24 115.22,100.55 115.22,95.93 113.03,93.74 113.03,91.78 113.29,91.52 113.45,91.52 113.54,91.61 113.54,91.88 113.63,91.97 v2(113.92,91.97)
  BOTTOM w0.102: 165.72,24.43 165.72,19.67 164.73,18.68 164.73,12.83 165.49,12.06 167.53,12.06 168.88,10.71 172.5,10.71 172.64,10.85 SSD1.53 ; 165.72,24.43 165.72,27.59 171.35,33.22 175.67,33.22 178.18,35.73 186.26,35.73 186.94,35.04 188.47,35.04 188.57,34.94 v2(188.57,34.74) ; 165.72,24.43 v1(165.89,24.43) ; v2(113.92,91.97) 114.22,91.97 114.33,91.86 114.33,91.56 114.72,91.16 114.72,90.27 115.03,89.88 115.04,89.88 115.07,89.87 115.23,89.87 115.33,89.97 CPU1.BA1
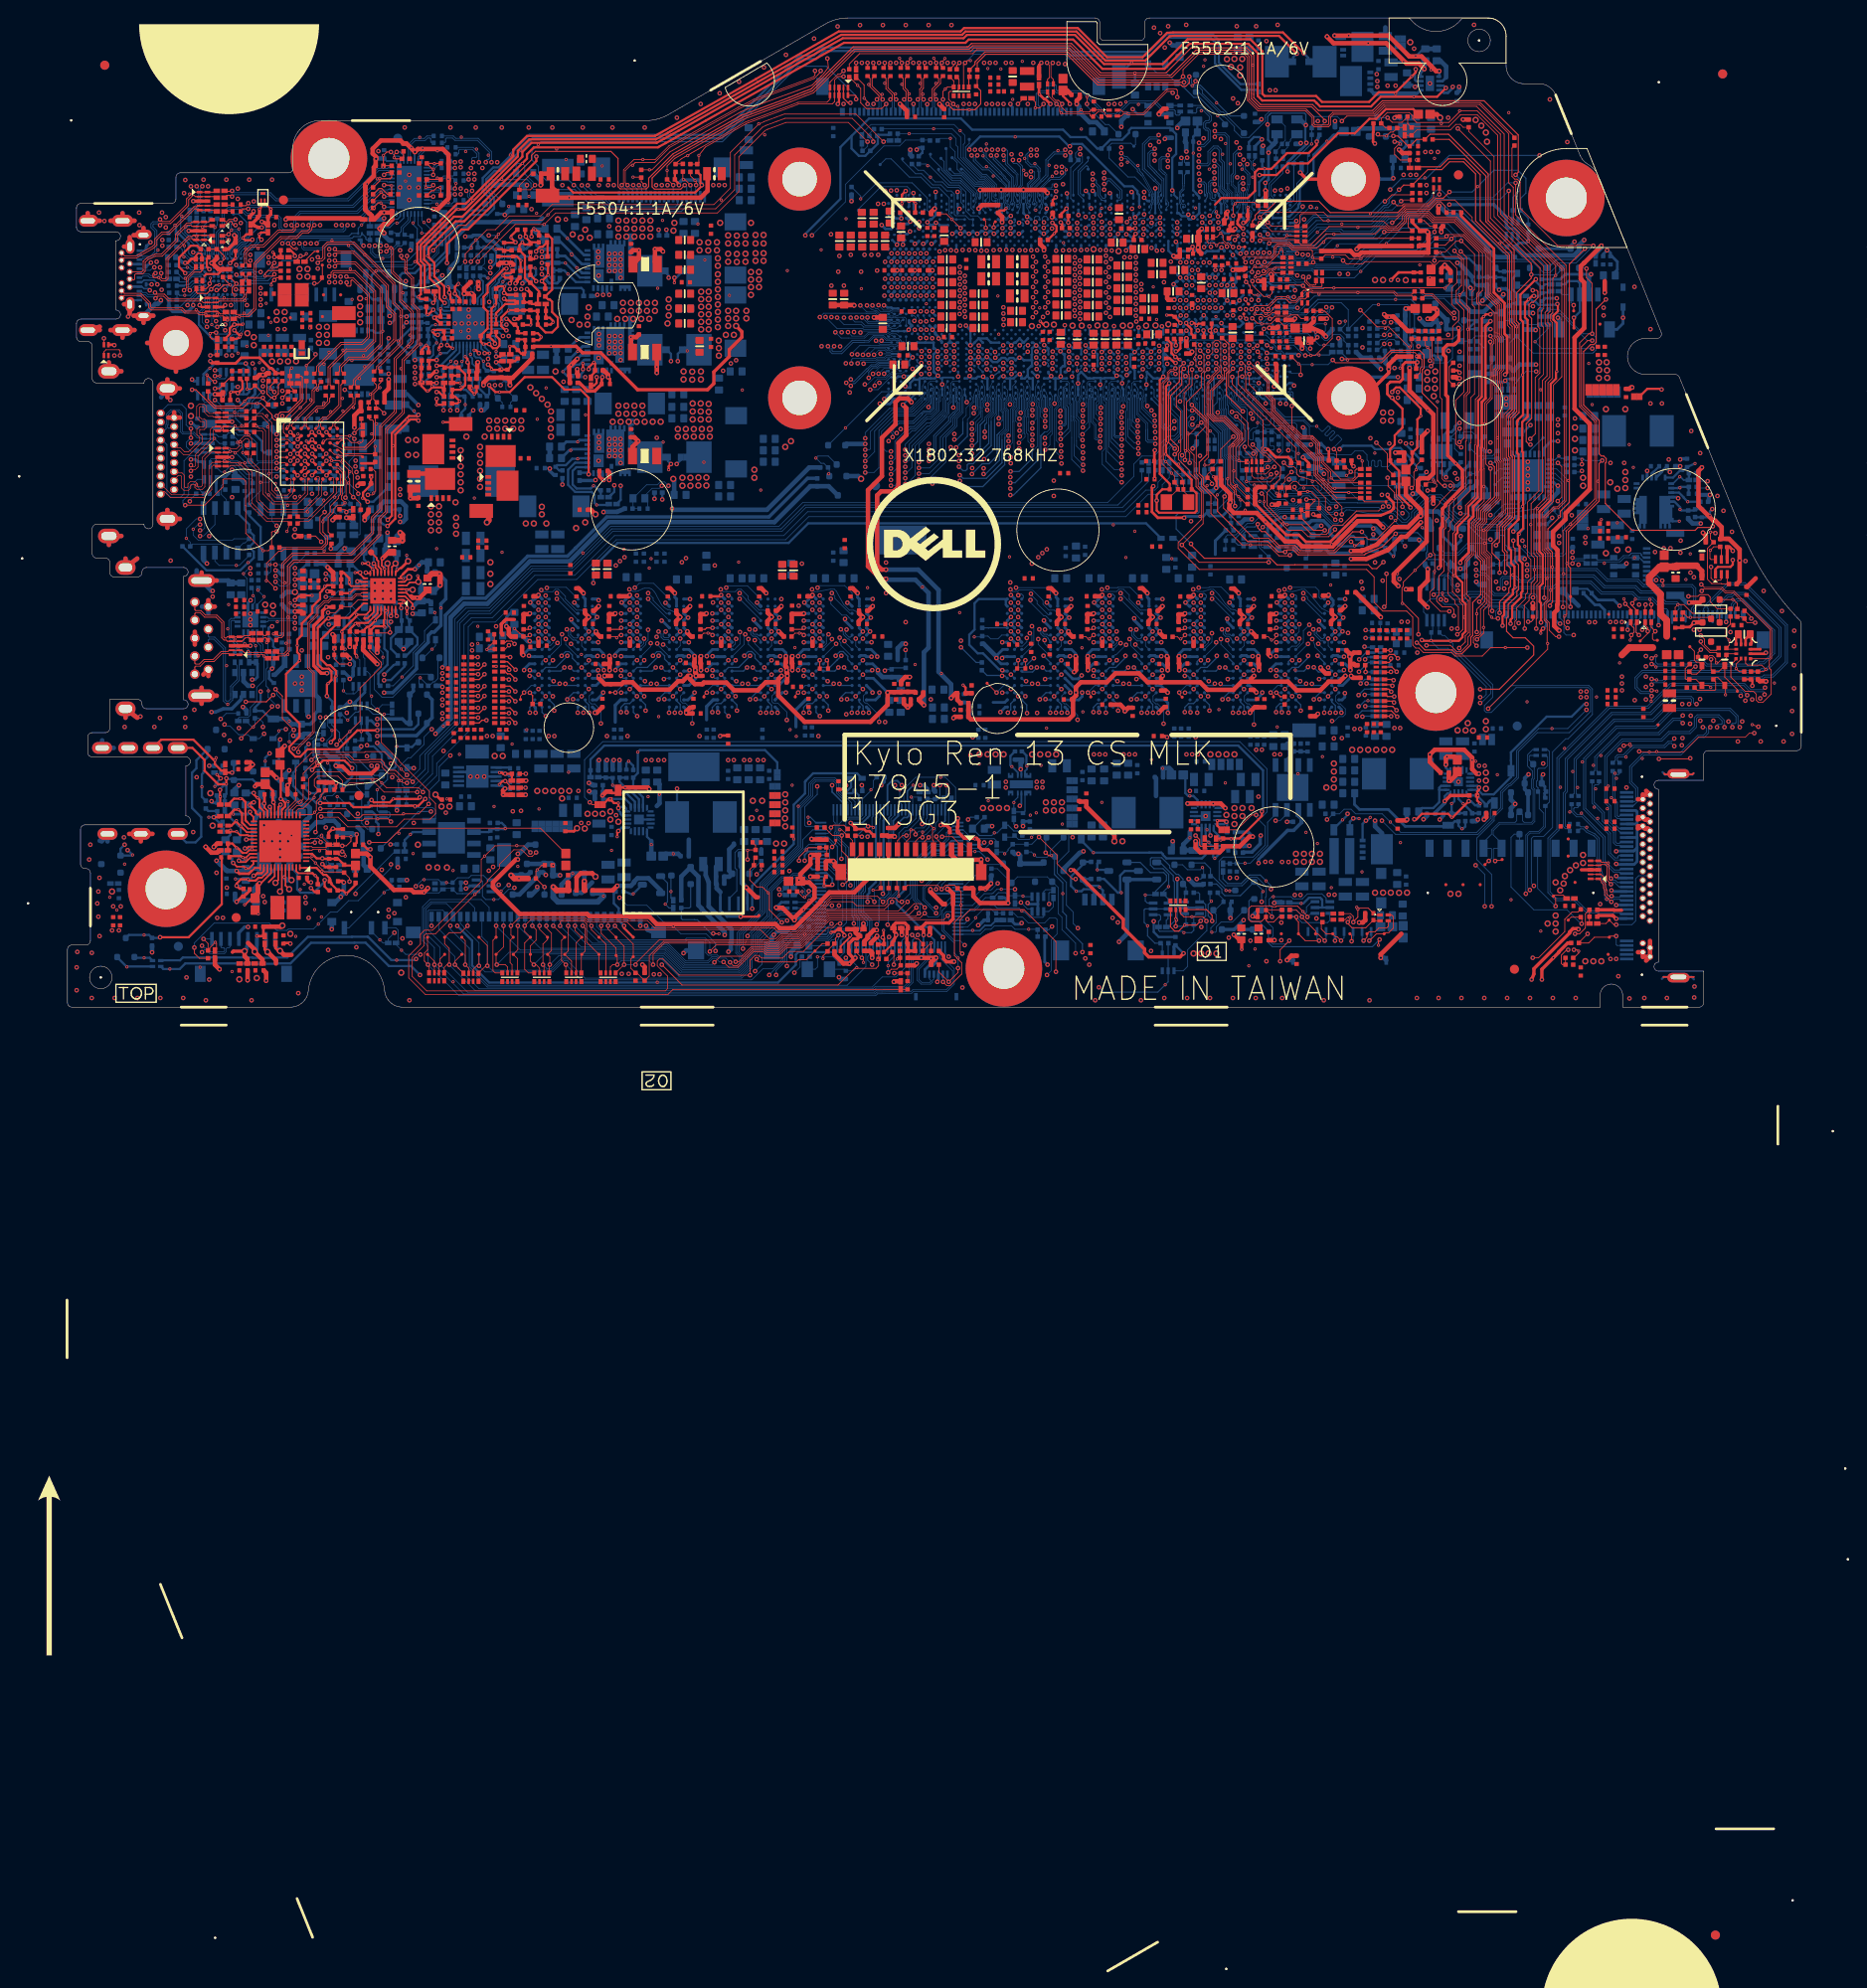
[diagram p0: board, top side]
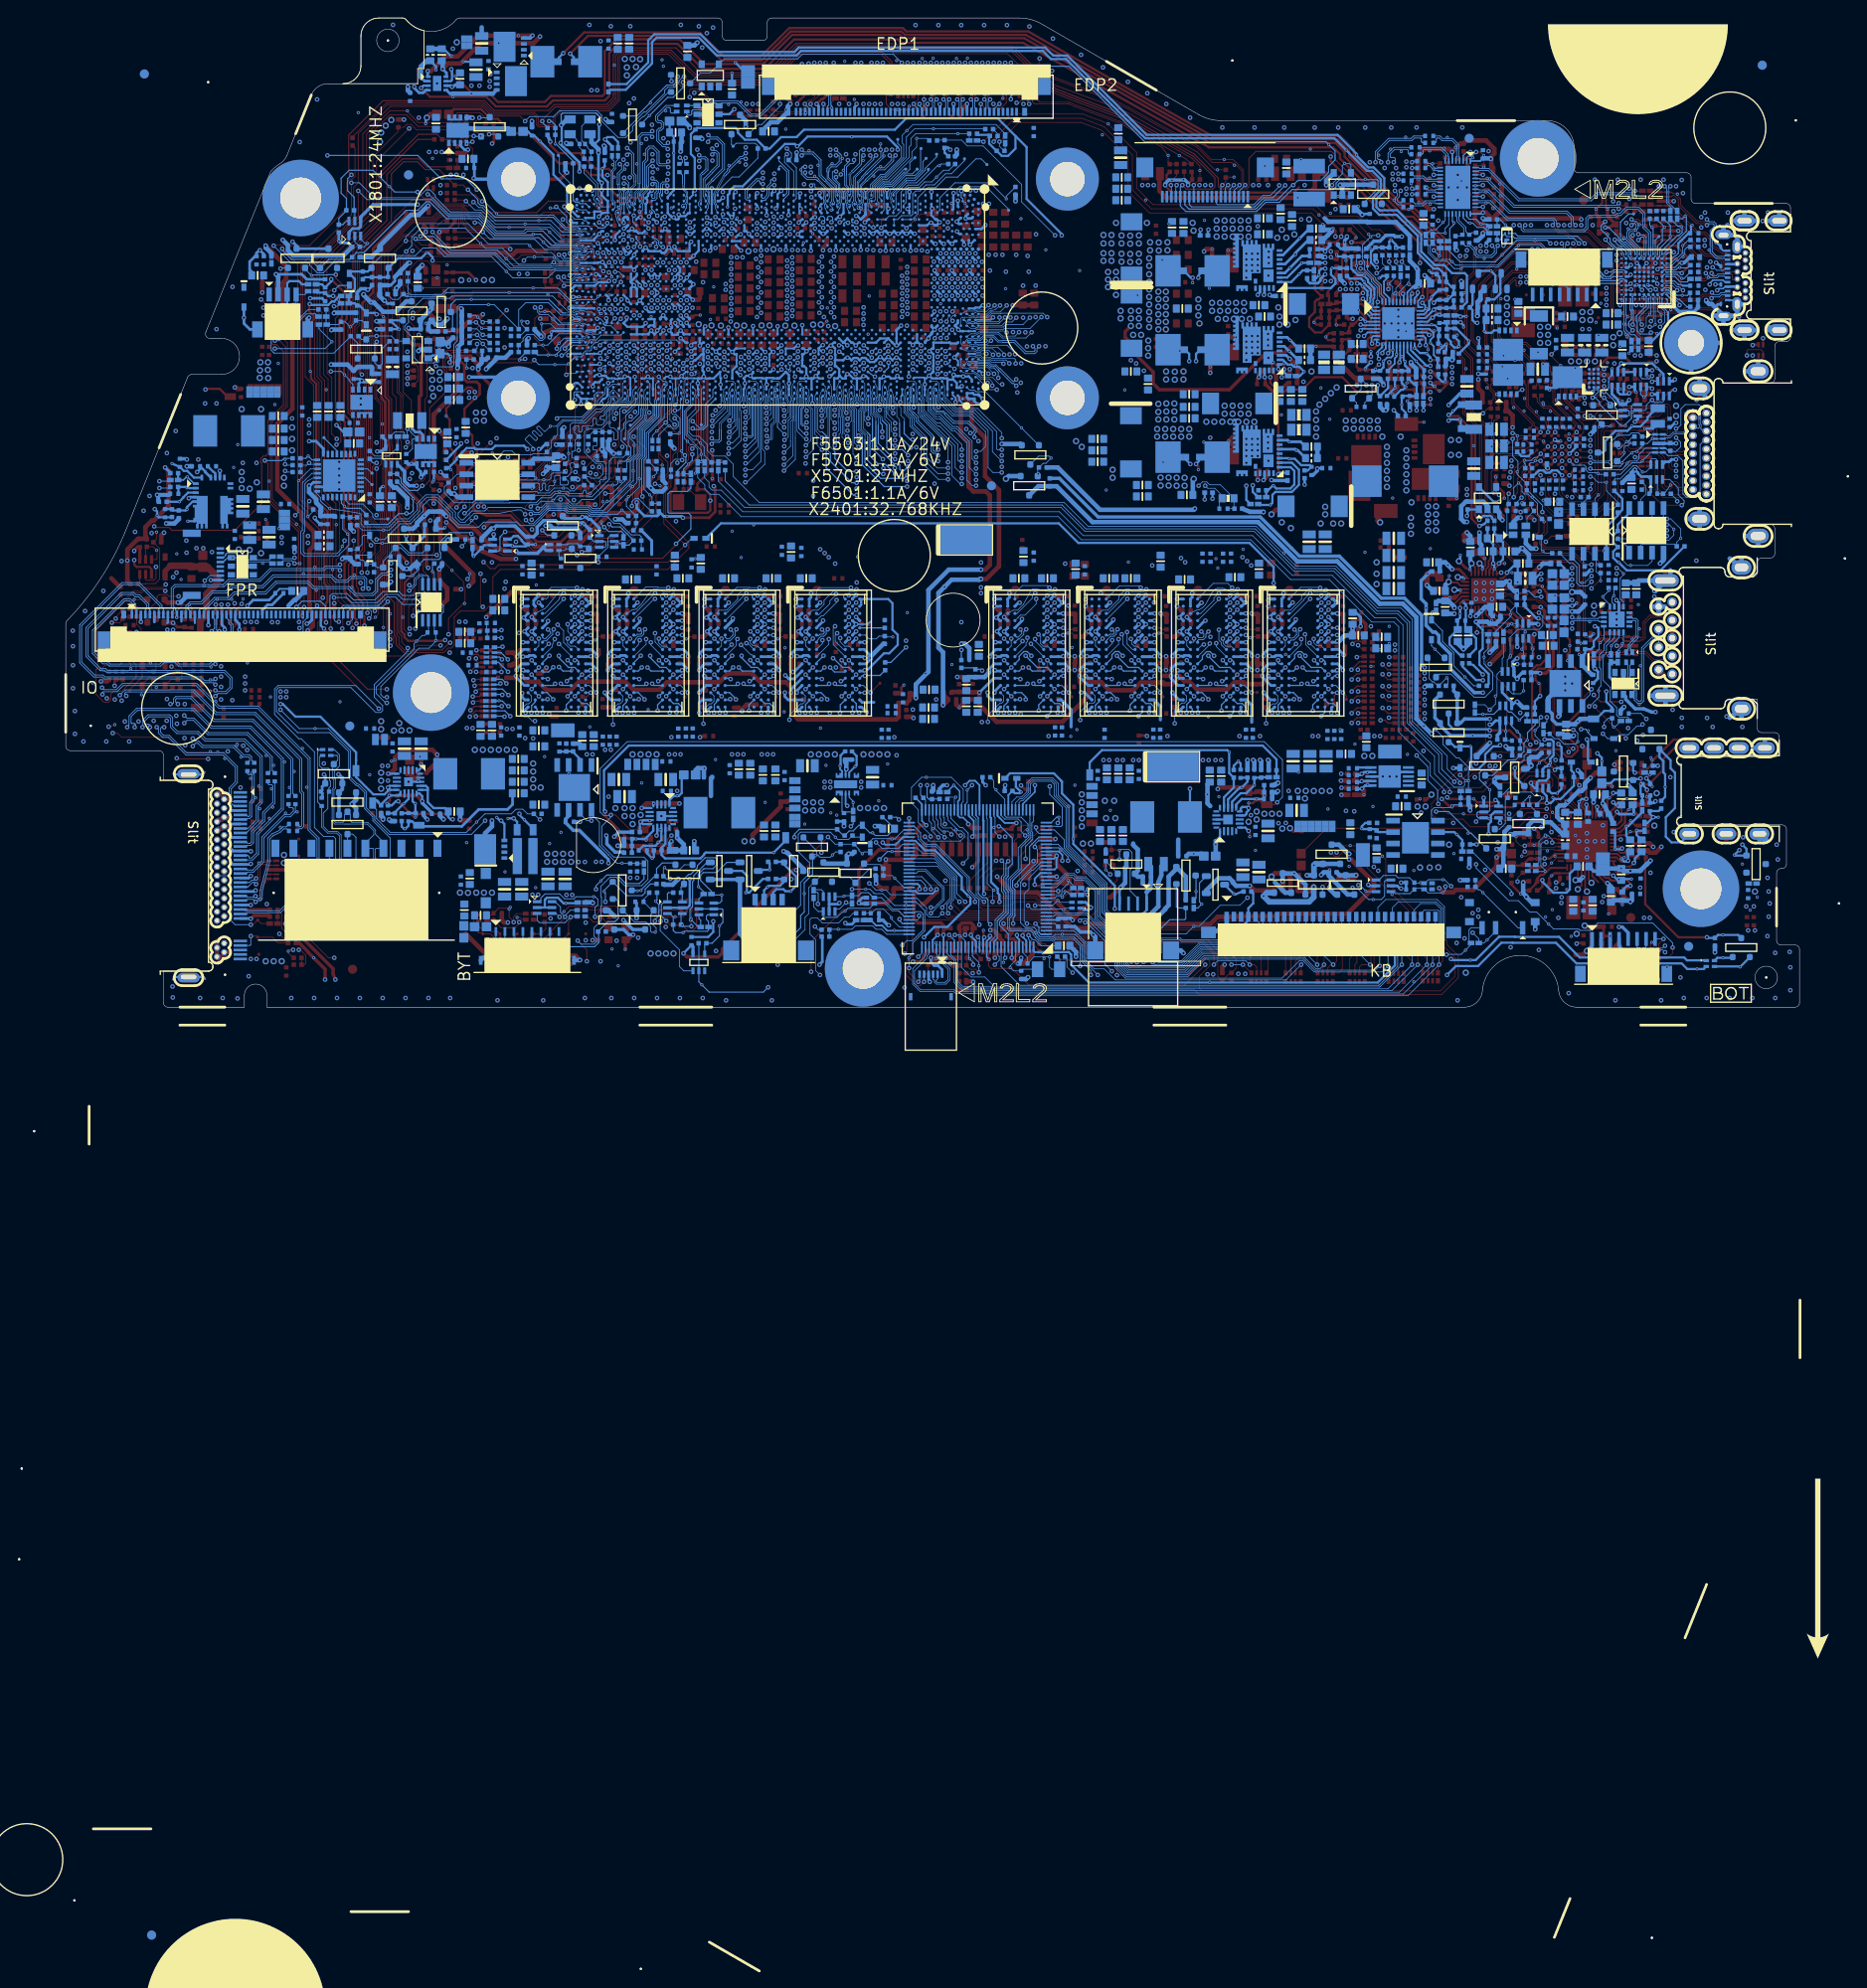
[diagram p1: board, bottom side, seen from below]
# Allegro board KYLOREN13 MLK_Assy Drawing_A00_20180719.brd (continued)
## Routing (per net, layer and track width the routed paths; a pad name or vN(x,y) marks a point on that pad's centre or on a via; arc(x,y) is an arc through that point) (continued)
SSD_CLK_CPU_P: length 195.5
  L6 w0.089: v2(188.62,35.5) 188.53,35.41 188,35.41 187.83,35.58 187.83,35.96 187.75,36.04 187.75,40.86 186.51,42.1 186.51,46.67 183.9,49.28 183.9,49.44 180.89,52.45 178.9,52.45 177.82,53.52 174.09,53.52 169.86,57.75 169.86,59.51 169.56,59.81 169.56,70.25 169.53,70.28 169.53,72.13 171.23,73.83 171.23,74.52 171.87,75.16 171.87,80.03 167.28,84.62 167.27,84.62 159.45,92.44 159.45,97.07 156.21,100.31 151.55,100.31 151.09,100.77 145.84,100.77 145.07,100.01 140.93,100.01 140.12,100.82 132.58,100.82 130.53,102.87 130.1,102.87 129.85,103.12 129.62,103.12 129.62,103.12 128.56,103.12 126.72,104.96 121.76,104.96 120.23,103.43 117.82,103.43 115.02,100.63 115.02,96.01 112.84,93.82 112.84,91.7 113.21,91.33 v2(113.92,91.33)
  BOTTOM w0.102: 166.45,28.64 171.26,33.44 175.57,33.44 177.95,35.83 178.09,35.96 186.35,35.96 187.04,35.27 188.39,35.27 v2(188.62,35.5) ; 166.45,28.64 v1(166.34,28.75) ; 166.45,28.64 165.5,27.68 165.5,19.77 164.5,18.77 164.5,12.73 165.4,11.83 167.43,11.83 168.78,10.48 172.46,10.48 172.59,10.35 SSD1.55 ; CPU1.BA2 114.9,89.67 114.9,89.67 114.85,89.74 114.85,89.74 114.5,90.19 114.5,91.07 114.23,91.33 v2(113.92,91.33)
SSD_CLKREQ_CPU_N: length 135
  TOP w0.102: v2(143.51,61.11) 143.87,60.75 v1(143.87,60.67) 143.87,59.95 RN1802.3 143.24,59.79 143.06,59.62 143.06,58.91 142.82,58.67 141.46,58.67 139.53,60.59 139.53,61.22 139.15,61.6 139.15,62.66 138.32,63.49 137.22,63.49 136.04,64.66 v2(136.04,66.79)
  L3SGND w0.102: SSD1.52 173.4,11.1 172.65,10.36 171.4,10.36 v2(170.31,11.45)
  L4SGND w0.102: v2(143.51,61.11) 144.09,60.52 150.52,60.52 151.39,61.39 155.22,61.39 159.91,56.7 166.58,56.7 167.47,55.81 168.83,55.81 170.99,53.65 179.69,53.65 183.79,49.55 183.79,49.03 184.34,48.48 185.14,48.48 186.57,47.05 186.57,46.25 190.53,42.29 190.53,35.15 187.96,32.58 181.23,32.58 180.75,32.1 180.75,31.33 180.41,30.99 178.44,30.99 175.11,27.66 174.32,27.66 172.59,25.93 172.59,21.34 170.6,19.35 170.6,15.66 168.29,13.35 168.29,12.18 169.03,11.44 170.3,11.44 v2(170.31,11.45) ; v2(136.04,66.79) 135.84,66.59 134.42,66.59 133.3,67.71 132.31,67.71 130.99,69.03 130.99,69.82 130.93,69.87 130.93,70.23 130.83,70.33 130.83,72.03 130.65,72.21 v2(130.37,72.21)
  BOTTOM w0.102: CPU1.CE30 130.29,72.21 v2(130.37,72.21)
SSD_DEVSLP: length 127.7
  TOP w0.102: v2(160.91,91.59) 160.91,88.02 166.51,82.43 166.51,56.25 165.64,55.38 165.21,55.38 164.26,54.42 164.26,50.94 164.74,50.45 164.74,48.95 164.76,48.94 164.76,45.29 164.29,44.82 164.29,43.08 164.64,42.72 164.64,41.88 165.36,41.16 v2(165.73,41.16) ; v2(167.51,8.15) 168.02,8.15 168.66,8.78 168.66,10.36 R6303.2 R6304.1 R6301.1
  L6 w0.102: v2(167.51,8.15) 167.33,8.33 167.33,13.92 168.32,14.91 168.94,14.91 170.41,16.38 170.41,17 170.41,17.94 170.61,18.14 170.61,36.28 v2(165.73,41.16)
  BOTTOM w0.076: 137.56,85.37 135.68,85.37 arc(135.64,85.41) 135.58,85.44 135.56,85.47 arc(135.53,85.48) 135.5,85.49 134.33,85.49 CPU1.CM8
  BOTTOM w0.102: v2(160.91,91.59) 160.02,91.59 158.37,89.93 153.49,89.93 152.63,90.8 152.17,90.8 151.59,90.21 151.59,90.01 149.87,88.3 146.59,88.3 144.93,86.63 v1(143.38,86.63) 138.82,86.63 137.56,85.37
SSD_PCIE_RX_N1: length 170.2
  L6 w0.089: v2(119.63,88.08) 119.75,88.08 119.84,87.99 119.84,87.71 119.75,87.62 119.54,87.62 119.39,87.7 119.28,87.81 119.17,88.02 119.17,91.13 118.57,91.73 118.57,98.03 120.99,100.44 128.51,100.44 129.35,99.61 130.79,99.61 132.76,97.63 133.22,97.44 133.8,96.86 133.8,96.41 134.98,95.23 137.87,95.23 138.37,95.72 138.37,96.51 138.92,97.07 145.09,97.07 145.43,97.41 145.44,97.41 146.18,98.14 148.79,98.14 150.39,96.54 152.28,96.54 153.44,95.38 153.44,94.46 167.81,80.09 167.81,76.36 167.35,75.91 167.35,69.02 166.78,68.45 166.78,57.55 172.9,51.43 173.71,51.43 175.92,49.22 178.09,49.22 178.5,48.81 180.45,48.81 182.04,47.23 182.04,45.27 183.3,44.01 183.3,35.01 185.46,32.85 185.46,31.6 185.32,31.46 185.09,31.46 185,31.37 v2(185,31.1)
  BOTTOM w0.102: CPU1.BG5 119.09,87.52 119.22,87.65 119.66,87.65 119.74,87.72 119.74,87.98 v2(119.63,88.08) ; v2(185,31.1) 184.9,31.2 184.9,31.41 185,31.51 185.29,31.51 185.39,31.62 185.39,32.26 184.69,32.96 178.49,32.96 176.5,30.98 172.14,30.98 170.4,29.25 168.69,27.54 168.69,22.08 169.92,20.86 ; 169.92,20.86 171.45,19.33 171.45,17.11 171.98,16.58 172.23,16.58 172.29,16.63 172.29,16.76 172.38,16.85 SSD1.29 ; 169.92,20.86 v1(170.03,20.97)
SSD_PCIE_RX_N2: length 157.8
  L6 w0.089: v2(183.29,31.1) 183.6,31.42 183.6,33.77 181.92,35.46 181.92,43.73 180.61,45.04 180.61,45.77 177.82,48.56 175.22,48.56 173.77,50 171.89,50 171.49,50.39 171.49,51.9 166.12,57.28 166.12,68.73 166.69,69.3 166.69,80.27 152.78,94.18 152.78,95.11 152.01,95.88 149.99,95.88 148.44,97.42 147.22,97.42 146.17,96.37 145.35,96.37 145.34,96.37 140.06,96.37 138.09,94.41 134.87,94.41 133.14,96.14 133.14,96.59 132.89,96.84 132.62,96.84 130.51,98.94 129.08,98.94 128.24,99.78 121.26,99.78 119.23,97.75 119.23,92.06 120.87,90.42 120.87,87.55 v2(120.47,87.15)
  BOTTOM w0.102: 171.04,24.55 171.04,22.8 171.49,22.36 171.49,20.78 172.41,19.85 SSD1.17 ; 171.04,24.55 v1(171.2,24.55) ; 171.04,24.55 171.04,27.78 172.82,29.56 177.16,29.56 178,30.4 180.31,30.4 181,31.09 181,32.07 181.18,32.25 183.41,32.25 183.85,31.81 183.85,31.5 183.78,31.43 183.4,31.43 183.29,31.31 v2(183.29,31.1) ; v2(120.47,87.15) 120.62,86.99 120.62,86.77 120.45,86.6 120.29,86.6 CPU1.BJ6
SSD_PCIE_RX_N3: length 144.4
  L6 w0.089: v2(181.71,31.1) 182.05,31.44 182.05,34.37 179.79,36.63 179.79,44.11 179.16,44.74 179.16,46.03 177.77,47.42 177.32,47.88 174.97,47.88 174.23,48.61 171.37,48.61 169.98,50 169.98,52.46 164.99,57.45 164.99,68.74 166.03,69.79 166.03,79.71 151.41,94.34 145.19,94.34 144.23,95.3 139.91,95.3 138.36,93.75 133.61,93.75 132.03,95.33 132.03,96.49 130.44,98.08 129.01,98.08 127.97,99.12 123.17,99.12 122.36,98.32 121.01,98.32 119.89,97.19 119.89,93.24 121.99,91.13 121.99,87.96 121.8,87.76 121.8,87.58 121.79,87.58 121.79,87.53 121.59,87.32 v2(121.41,87.12)
  BOTTOM w0.102: v2(181.71,31.1) 181.99,31.1 182.12,30.97 182.12,30.55 181.77,30.19 181.13,30.19 179.18,28.24 176.58,28.24 ; SSD1.5 174.15,22.85 174.25,22.96 174.25,24.26 173.58,24.94 173.58,26.73 175.08,28.24 176.58,28.24 ; v1(176.58,28.39) 176.58,28.24 ; CPU1.BK6 120.94,87.07 121.06,87.19 121.34,87.19 v2(121.41,87.12)
SSD_PCIE_RX_P1: length 170.2
  L6 w0.089: v2(119.53,87.22) 119.53,87.3 119.42,87.4 119.28,87.54 119.13,87.69 118.98,87.97 118.98,91.05 118.38,91.65 118.38,98.1 120.91,100.63 128.59,100.63 129.43,99.8 130.87,99.8 132.87,97.79 133.33,97.6 133.99,96.94 133.99,96.49 135.06,95.42 137.79,95.42 138.18,95.8 138.18,96.59 138.84,97.26 145.01,97.26 145.35,97.6 145.36,97.6 146.1,98.34 148.87,98.34 150.47,96.73 152.36,96.73 153.63,95.46 153.63,94.53 168,80.16 168,76.29 167.54,75.83 167.54,68.94 166.97,68.37 166.97,57.63 172.98,51.62 173.79,51.62 176,49.41 178.17,49.41 178.57,49 180.53,49 182.23,47.31 182.23,45.35 183.49,44.09 183.49,35.09 185.65,32.93 185.65,31.28 v2(185.82,31.1)
  BOTTOM w0.102: v2(185.82,31.1) 185.62,31.3 185.62,32.35 184.79,33.19 178.39,33.19 176.41,31.21 172.04,31.21 170.31,29.48 168.47,27.63 168.47,27.25 ; 168.47,27.25 168.47,21.99 171.22,19.23 171.22,17.01 171.88,16.35 SSD1.31 ; 168.47,27.25 v1(168.33,27.25) ; CPU1.BG6 v2(119.53,87.22)
SSD_PCIE_RX_P2: length 157.9
  L6 w0.089: v2(120.47,87.78) 120.67,87.99 120.67,90.34 119.04,91.98 119.04,97.83 121.18,99.97 128.32,99.97 129.16,99.14 130.59,99.14 132.7,97.03 132.97,97.03 133.33,96.67 133.33,96.22 134.95,94.6 138.01,94.6 139.98,96.56 145.42,96.56 145.43,96.56 146.09,96.56 147.15,97.61 148.52,97.61 150.07,96.07 152.09,96.07 152.97,95.19 152.97,94.26 166.88,80.35 166.88,69.22 166.31,68.65 166.31,57.35 171.68,51.98 171.68,50.47 171.97,50.19 173.85,50.19 175.3,48.75 177.89,48.75 180.8,45.85 180.8,45.12 182.11,43.81 182.11,35.54 183.79,33.85 183.79,31.43 v2(184.12,31.1)
  BOTTOM w0.102: v2(184.12,31.1) 184.08,31.14 184.08,31.91 183.51,32.48 181.08,32.48 180.77,32.17 180.77,31.18 180.21,30.63 177.91,30.63 177.07,29.79 172.73,29.79 170.81,27.87 170.81,22.71 171.26,22.27 171.26,22.04 ; SSD1.19 172.59,19.35 171.26,20.68 171.26,22.04 ; v2(120.47,87.78) CPU1.BJ5 ; 171.26,22.04 v1(171.09,22.04)
SSD_PCIE_RX_P3: length 144.5
  L6 w0.089: v2(121.39,87.74) 121.51,87.74 121.8,88.04 121.8,91.05 119.7,93.16 119.7,97.27 120.93,98.51 122.28,98.51 123.09,99.31 128.04,99.31 129.09,98.27 130.52,98.27 132.22,96.57 132.22,95.41 133.69,93.94 138.29,93.94 139.84,95.49 144.31,95.49 145.27,94.53 151.49,94.53 166.22,79.79 166.22,69.71 165.18,68.67 165.18,57.53 170.17,52.54 170.17,50.08 171.45,48.8 174.31,48.8 175.04,48.07 177.4,48.07 177.51,47.95 179.35,46.11 179.35,44.82 179.98,44.19 179.98,36.71 182.25,34.45 182.25,31.4 v2(182.54,31.1)
  BOTTOM w0.102: 174.89,27.72 173.81,26.64 173.81,25.03 174.48,24.36 174.48,22.86 173.97,22.35 SSD1.7 ; 174.89,27.72 175.18,28.01 179.27,28.01 181.23,29.96 181.86,29.96 182.35,30.46 182.35,30.92 v2(182.54,31.1) ; 174.89,27.72 v1(174.98,27.63) ; v2(121.39,87.74) 121.17,87.52 CPU1.BK5
SSD_PCIE_TX_CON_N1: length 11.6
  BOTTOM w0.102: 168.22,21.38 167.77,21.38 167.36,21.79 167.36,22.07 167.46,22.17 167.79,22.17 167.89,22.27 C6312.1 ; 168.22,21.38 v1(168.22,21.56) ; 168.22,21.38 168.39,21.38 170.87,18.9 170.87,16.25 171.88,15.23 172.47,15.23 172.58,15.35 SSD1.35
SSD_PCIE_TX_CON_N2: length 9.6
  BOTTOM w0.102: 169.65,24.25 169.65,24.61 169.75,24.71 170.08,24.71 170.18,24.81 C6314.1 ; 169.65,24.25 v1(169.8,24.25) ; 169.65,24.25 169.65,22.75 170.77,21.63 170.77,20.77 172.01,19.53 172.01,18.36 172.16,18.2 172.44,18.2 172.59,18.35 SSD1.23
SSD_PCIE_TX_CON_N3: length 6.8
  BOTTOM w0.102: C6316.1 172.47,25.98 172.34,25.85 172.03,25.85 171.93,25.75 171.93,25.42 ; SSD1.11 172.58,21.35 172.4,21.18 172.32,21.18 172.21,21.28 172.21,22.75 171.93,23.03 171.93,25.42 ; 171.93,25.42 v1(172.11,25.42)
SSD_PCIE_TX_CON_P1: length 11.6
  BOTTOM w0.102: 167.13,21.69 167.67,21.15 168.3,21.15 170.64,18.81 170.64,16.15 171.79,15 172.44,15 172.6,14.85 SSD1.37 ; 167.13,21.69 C6311.1 ; 167.13,21.69 v1(166.93,21.69)
SSD_PCIE_TX_CON_P2: length 9.6
  BOTTOM w0.102: 169.75,22.32 170.54,21.54 170.54,20.67 171.78,19.43 171.78,18.26 172.07,17.98 172.47,17.98 172.59,17.85 SSD1.25 ; 169.75,22.32 169.42,22.66 C6313.1 ; 169.75,22.32 v1(169.65,22.22)
SSD_PCIE_TX_CON_P3: length 6.7
  BOTTOM w0.102: SSD1.13 172.59,20.85 172.49,20.95 172.22,20.95 171.98,21.18 171.98,22.66 171.7,22.94 171.7,23.26 ; 171.7,23.26 v1(171.55,23.26) ; 171.7,23.26 C6315.1
SSD_PCIE_TX_N1: length 143.7
  L6 w0.089: v2(121.25,96.89) 121.15,96.89 121.06,96.8 121.06,96.52 120.94,96.4 120.76,96.4 120.57,96.59 120.57,96.94 121.22,97.59 122.57,97.59 123.44,98.46 127.69,98.46 128.73,97.42 130.17,97.42 130.26,97.33 131.37,96.22 131.37,95.83 131.37,95.06 133.15,93.28 139.26,93.28 140.62,94.64 143.95,94.64 144.91,93.68 151.05,93.68 164.33,80.4 164.33,56.56 167.65,53.24 168.26,53.24 169.32,52.19 169.32,49.52 170.92,47.92 173.98,47.92 175.36,46.55 176.86,46.55 178.5,44.91 178.5,44.47 179.13,43.84 179.13,36.24 180.79,34.58 180.79,34.18 180.71,34.1 180.23,34.1 180.14,34.01 180.14,33.72 v2(180.19,33.67)
  BOTTOM w0.076: CPU1.BL4 121.29,88.74 121.25,88.84 121.25,89.09 121.1,89.43 121.1,89.68 121.14,89.78 121.14,90 121.1,90.1 121.1,90.55 121.28,90.73 121.28,91.29 120.79,91.78 120.74,91.78 120.73,91.79
  BOTTOM w0.102: v2(180.19,33.67) 180.44,33.93 180.44,34.18 180.34,34.28 178.75,34.28 176.21,31.74 171.89,31.74 167.64,27.49 167.64,24.4 ; C6312.2 167.64,23.72 167.64,24.4 ; v1(167.79,24.4) 167.64,24.4 ; v2(121.25,96.89) 121.03,96.67 120.21,96.67 119.45,95.91 119.45,93.07 120.73,91.79
SSD_PCIE_TX_N2: length 131.3
  L6 w0.089: v2(120.81,94.74) 121.06,94.99 121.59,94.99 123.96,97.36 126.49,97.36 126.81,97.04 126.81,96.48 127.45,95.85 127.9,95.85 127.91,95.84 128.84,95.84 129.67,96.67 129.99,96.67 130.71,95.95 130.71,94.76 132.61,92.85 132.99,92.48 134.83,92.48 135.24,92.07 138.48,92.07 141.38,89.17 144.91,89.17 145.71,89.98 149.56,89.98 149.94,89.6 153.96,89.6 159.43,84.14 159.43,83.73 163.67,79.49 163.67,56.28 168.04,51.92 168.04,51.29 168.35,50.97 168.35,49.55 171,46.91 174.07,46.91 175.08,45.89 176.45,45.89 177.74,44.6 177.74,44.2 178.24,43.7 178.24,32.3 178.65,31.9 179.15,31.9 v2(179.48,31.56)
  BOTTOM w0.076: CPU1.BL2 121.55,89.57 121.79,90.14 121.79,91.99 121.79,92 121.79,92.02 121.78,92.02
  BOTTOM w0.102: 170.28,28.06 169.93,27.7 169.93,26.26 C6314.2 ; 170.28,28.06 172.5,30.27 176.87,30.27 178.47,31.87 179.17,31.87 v2(179.48,31.56) ; 170.28,28.06 v1(170.38,27.96) ; v2(120.81,94.74) 120.59,94.96 120.47,94.96 120.29,94.78 120.29,93.55 121,92.83 121,92.8 121.78,92.02
SSD_PCIE_TX_N3: length 134
  L6 w0.089: v2(122.27,94.02) 122.51,94.26 122.92,94.26 124.16,95.5 124.69,95.5 125.02,95.17 125.02,90.03 125.22,89.83 126.16,89.83 126.47,90.13 126.47,90.34 126.47,90.35 126.47,94.81 126.85,95.19 127.62,95.19 127.63,95.18 127.93,95.18 128.93,94.18 128.93,93.39 129.65,92.66 130.65,92.66 132.52,90.8 132.52,90.48 132.94,90.06 138.5,90.06 140.81,87.75 153.95,87.75 158.11,83.59 158.11,83.18 161.38,79.91 161.38,72.89 161.65,72.62 161.65,54.56 165.37,50.84 165.37,49.97 166.89,48.46 168.51,48.46 170.72,46.25 173.63,46.25 174.68,45.2 176.19,45.2 177.08,44.32 177.08,43.93 177.32,43.69 177.32,29.54 177.54,29.32 178.21,29.32 v2(178.54,29)
  BOTTOM w0.076: CPU1.BM4 122.09,88.82 122.36,89.09 122.36,89.39 122.17,89.58 122.17,89.66 122.17,89.73 122.17,92.5 121.96,92.71 121.96,92.7 121.95,92.7 121.94,92.71
  BOTTOM w0.102: v2(122.27,94.02) 122.04,94.25 121.65,94.25 121.52,94.12 121.52,93.12 121.94,92.71 ; 173.06,27.9 174.01,28.85 177.5,28.85 177.95,29.3 178.23,29.3 v2(178.54,29) ; 173.06,27.9 v1(173.18,27.78) ; 173.06,27.9 172.97,27.81 172.31,27.81 172.22,27.71 172.22,27.39 C6316.2
SSD_PCIE_TX_P1: length 143.7
  L6 w0.089: v2(181.01,33.67) 180.98,33.71 180.98,34.66 179.32,36.32 179.32,43.91 178.69,44.55 178.69,44.99 176.94,46.74 175.44,46.74 174.06,48.11 171,48.11 169.51,49.6 169.51,52.27 168.34,53.43 167.72,53.43 164.52,56.64 164.52,80.47 151.13,93.87 144.99,93.87 144.03,94.83 140.54,94.83 139.18,93.47 133.22,93.47 131.56,95.14 131.56,95.75 131.56,96.3 130.34,97.52 130.25,97.61 128.81,97.61 127.77,98.65 123.37,98.65 122.49,97.78 121.14,97.78 120.38,97.02 120.38,96.51 120.69,96.21 121.21,96.21 v2(121.28,96.14)
  BOTTOM w0.076: CPU1.BL3 121.5,88.97 121.36,89.26 121.27,89.47 121.27,89.66 121.3,89.75 121.3,90.03 121.29,90.07 121.27,90.12 121.27,90.48 121.44,90.66 121.44,91.36 120.88,91.92 120.9,91.94 120.9,91.95 120.89,91.96
  BOTTOM w0.102: 120.89,91.96 119.68,93.17 119.68,95.82 120.31,96.44 121.1,96.44 121.28,96.26 v2(121.28,96.14) ; 167.41,26.18 167.41,23.74 C6311.2 ; 167.41,26.18 v1(167.26,26.18) ; 167.41,26.18 167.41,27.59 171.8,31.97 176.11,31.97 178.65,34.51 180.43,34.51 180.67,34.28 180.67,33.83 180.82,33.67 v2(181.01,33.67)
SSD_PCIE_TX_P2: length 131.3
  L6 w0.089: v2(179.48,32.4) 179.16,32.09 178.73,32.09 178.44,32.38 178.44,43.62 178.44,43.62 178.44,43.77 177.93,44.28 177.93,44.68 176.53,46.08 175.16,46.08 174.15,47.1 171.08,47.1 168.54,49.63 168.54,51.05 168.23,51.37 168.23,52 163.86,56.36 163.86,79.57 159.62,83.81 159.62,84.22 154.04,89.79 150.02,89.79 149.64,90.17 145.63,90.17 144.83,89.36 141.46,89.36 138.56,92.26 135.32,92.26 134.91,92.67 133.07,92.67 132.69,93.04 130.9,94.84 130.9,96.03 130.07,96.86 129.59,96.86 128.76,96.03 127.99,96.03 127.98,96.04 127.53,96.04 127,96.56 127,97.12 126.57,97.55 123.88,97.55 121.51,95.18 121,95.18 v2(120.81,95.38)
  BOTTOM w0.076: 121.62,91.86 121.62,90.45 CPU1.BL1
  BOTTOM w0.102: 169.7,26.87 169.7,26.28 C6313.2 ; 169.7,26.87 169.7,27.79 172.4,30.5 176.78,30.5 178.38,32.1 179.18,32.1 v2(179.48,32.4) ; 169.7,26.87 v1(169.54,26.87) ; v2(120.81,95.38) 120.62,95.19 120.38,95.19 120.06,94.87 120.06,93.45 120.78,92.74 120.78,92.7 121.62,91.86
SSD_PCIE_TX_P3: length 134
  L6 w0.089: v2(178.54,29.84) 178.21,29.51 177.62,29.51 177.51,29.62 177.51,43.77 177.27,44.01 177.27,44.39 176.27,45.4 174.75,45.4 173.71,46.44 170.8,46.44 168.59,48.65 166.97,48.65 165.56,50.05 165.56,50.92 161.84,54.64 161.84,72.7 161.58,72.97 161.58,79.98 158.3,83.26 158.3,83.67 154.03,87.94 140.89,87.94 138.58,90.25 133.02,90.25 132.71,90.56 132.71,90.88 130.73,92.86 129.73,92.86 129.12,93.47 129.12,94.26 128.02,95.36 128,95.37 127.71,95.37 127.7,95.38 126.77,95.38 126.28,94.89 126.28,90.43 126.28,90.42 126.28,90.21 126.09,90.02 125.3,90.02 125.21,90.11 125.21,95.25 124.77,95.69 124.08,95.69 122.84,94.45 122.48,94.45 v2(122.27,94.66)
  BOTTOM w0.076: CPU1.BM3 122.05,89.45 121.99,89.51 121.99,89.66 121.99,89.73 121.99,92.42 121.9,92.52 121.74,92.58
  BOTTOM w0.102: 173.78,28.93 173.92,29.08 177.4,29.08 177.86,29.53 178.23,29.53 v2(178.54,29.84) ; 173.78,28.93 172.88,28.03 172.22,28.03 171.99,27.81 171.99,27.43 C6315.2 ; 173.78,28.93 v1(173.66,29.05) ; 121.74,92.58 121.3,93.03 121.3,94.22 121.56,94.48 122.09,94.48 v2(122.27,94.66)
SSD_SATA_RX_N: length 173.3
  TOP w0.102: v2(117.72,87.22) v1(118.05,87.68) ; v2(171.5,13.66) 171.31,13.85 171.31,13.87 171.07,14.11 171.07,15.63 170.9,15.8 170.84,15.86 170.47,15.86 170.38,15.76 ED6301.4 ED6301.7
  L6 w0.089: v2(117.72,87.22) 117.95,87.45 117.95,87.89 117.62,88.22 117.62,98.33 121.49,102.2 125.8,102.2 126.12,101.88 129.11,101.88 129.33,101.88 129.59,101.62 130.01,101.62 132.07,99.57 139.6,99.57 140.4,98.78 140.4,98 140.49,97.92 144.73,97.92 145.08,98.26 145.09,98.26 146.35,99.52 148.69,99.52 150.78,97.44 152.66,97.44 154.37,95.73 154.37,94.85 168.66,80.55 168.66,76.01 168.22,75.57 168.22,61.46 167.77,61.02 167.77,57.76 173.26,52.28 174.06,52.28 176.22,50.12 178.49,50.12 178.9,49.71 181.18,49.71 182.4,48.49 183.07,47.69 183.87,46.89 184.19,46.51 184.19,43.89 184.92,43.16 184.92,42.54 184.15,41.77 184.15,35.5 186.92,32.73 186.92,31.14 186.21,30.44 181.61,30.44 178.08,26.9 174.81,26.9 173.98,26.08 173.98,24.86 174.28,24.57 174.28,15.43 172.51,13.66 171.65,13.66 v2(171.5,13.66)
  BOTTOM w0.102: SSD1.43 172.41,13.35 171.9,13.87 171.71,13.87 v2(171.5,13.66) ; CPU1.BE5 v2(117.72,87.22)
SSD_SATA_RX_P: length 172.5
  TOP w0.102: v1(171.2,16.02) 171.12,15.91 ; 171.12,15.91 170.94,16.08 170.47,16.08 170.3,16.26 ED6301.5 ED6301.6 ; 171.12,15.91 171.3,15.73 171.3,14.49 v2(171.5,14.29)
  L6 w0.089: v2(118.64,87.15) 118.55,87.06 118.26,87.06 118.14,87.18 118.14,87.97 117.81,88.3 117.81,98.25 121.57,102.01 125.72,102.01 126.04,101.69 129.03,101.69 129.25,101.69 129.51,101.43 129.94,101.43 131.99,99.38 139.52,99.38 140.21,98.7 140.21,97.93 140.41,97.73 144.81,97.73 145.16,98.07 145.17,98.07 146.43,99.33 148.62,99.33 150.7,97.25 152.58,97.25 154.18,95.65 154.18,94.77 168.47,80.48 168.47,76.09 168.03,75.65 168.03,61.54 167.58,61.1 167.58,57.68 173.18,52.09 173.98,52.09 176.14,49.93 178.41,49.93 178.82,49.52 181.1,49.52 182.26,48.37 182.92,47.57 183.73,46.76 184,46.44 184,43.81 184.73,43.08 184.73,42.62 183.96,41.85 183.96,35.42 186.73,32.65 186.73,31.22 186.13,30.63 181.53,30.63 178,27.09 174.73,27.09 173.79,26.16 173.79,24.78 174.09,24.49 174.09,15.51 172.43,13.85 171.92,13.85 171.83,13.94 171.83,14.2 171.74,14.29 v2(171.5,14.29)
  BOTTOM w0.102: SSD1.41 172.24,13.85 171.99,14.1 171.7,14.1 v2(171.5,14.29) ; CPU1.BE6 118.17,87 118.41,87.23 118.55,87.23 v2(118.64,87.15)
SSD_SATA_TX_CON_N: length 16.5
  TOP w0.102: v2(171.58,12.34) 171.28,12.34 171.04,12.58 171.04,12.96 171.01,12.99 170.98,13.13 170.9,13.31 170.9,13.7 170.66,13.94 170.66,14.5 170.4,14.76 ED6301.2 ED6301.9
  BOTTOM w0.102: v1(168.81,19.98) 168.69,19.87 ; 168.69,19.87 168.95,19.61 169.73,19.25 170.21,18.77 170.21,16.2 170.53,14.94 171.04,12.97 171.04,12.13 171.11,12.06 171.3,12.06 v2(171.58,12.34) 171.7,12.21 172.47,12.21 172.61,12.35 SSD1.47 ; 168.69,19.87 168.53,20.03 168.15,20.03 C6303.1
SSD_SATA_TX_CON_P: length 16.3
  TOP w0.102: ED6301.10 ED6301.1 170.19,14.26 170.43,14.01 170.43,13.85 170.68,13.61 170.68,13.27 170.76,13.07 170.81,12.82 170.81,12.44 171.1,12.16 171.15,12.11 ; v1(171.02,11.98) 171.15,12.11 ; 171.15,12.11 v2(171.55,11.7)
  BOTTOM w0.102: C6302.1 168.07,19.8 168.43,19.8 168.81,19.42 169.6,19.06 169.64,19.02 169.98,18.68 169.98,16.17 170.81,12.94 170.81,12.03 171.02,11.83 171.42,11.83 v2(171.55,11.7) 171.83,11.98 172.47,11.98 172.6,11.85 SSD1.49
SSD_SATA_TX_N: length 165.8
  L6 w0.089: v2(185.93,34.59) 185.9,34.61 185.9,34.87 186,34.97 186.33,34.97 186.45,35.08 186.45,35.27 184.68,38.48 184.68,40.93 185.25,41.51 185.49,42.46 185.49,43.37 185.21,45.59 185.21,45.6 185.07,46.56 183.34,48.64 183.05,48.92 183.05,49.09 182.06,50.08 179.66,51.1 179.04,51.1 178.65,51.49 174.22,52.67 173.74,52.67 169.01,57.4 169.01,59.15 168.71,59.46 168.71,69.9 168.68,69.93 168.68,75.27 169.09,75.68 169.09,80.7 158.89,90.9 158.85,90.94 154.99,95.75 154.94,95.8 152.91,97.83 151.83,97.83 148.83,99.92 146.19,99.92 145.43,99.15 140.58,99.15 139.76,99.97 132.23,99.97 130.18,102.02 129.75,102.02 129.49,102.27 129.27,102.27 127.63,102.27 124.92,103.88 123.95,103.88 121.19,102.56 118.42,100.45 117.46,99.48 116.62,97.83 116.36,95.24 116.36,94.58 116.51,94.44 116.67,94.44 116.76,94.53 116.76,94.77 116.88,94.89 v2(117.09,94.89)
  BOTTOM w0.076: 119.48,92.57 119.49,92.56 119.49,92.51 119.51,92.49 119.51,92.47 119.57,92.41 120.54,90.65 120.64,90.39 120.64,90.09 120.61,90 120.61,89.78 120.64,89.69 120.64,89.43 120.53,89.17 120.51,89.13 120.49,89.09 120.49,88.81 CPU1.BJ4
  BOTTOM w0.102: v1(118.95,93.52) 118.83,93.4 ; 118.83,93.4 117.73,94.51 117.47,94.51 v2(117.09,94.89) ; 118.83,93.4 119.12,93.12 119.12,92.93 119.48,92.57 ; v2(185.93,34.59) 186.09,34.75 186.09,34.89 185.96,35.02 178.48,35.02 175.96,32.5 171.65,32.5 166.66,27.52 166.66,23.93 166.44,23.71 166.44,20.15 166.52,20.06 166.65,20.06 C6303.2
SSD_SATA_TX_P: length 165.8
  L6 w0.089: v2(117.09,94.25) 116.43,94.25 116.17,94.51 116.17,95.25 116.44,97.88 116.57,98.15 117.3,99.6 118.29,100.59 121.09,102.72 121.27,102.81 123.91,104.07 124.97,104.07 127.68,102.46 129.35,102.46 129.35,102.46 129.57,102.46 129.83,102.21 130.26,102.21 132.31,100.16 139.84,100.16 140.66,99.34 145.35,99.34 146.11,100.11 148.89,100.11 151.89,98.02 152.99,98.02 155.13,95.88 159,91.06 169.28,80.78 169.28,75.61 168.87,75.19 168.87,70.01 168.9,69.98 168.9,59.54 169.2,59.23 169.2,57.48 173.82,52.86 174.24,52.86 178.75,51.66 179.12,51.29 179.7,51.29 182.17,50.24 183.24,49.17 183.24,49 183.48,48.77 185.25,46.64 185.4,45.61 185.68,43.38 185.68,42.44 185.68,42.42 185.43,41.41 185.39,41.37 184.87,40.85 184.87,38.52 186.64,35.32 v2(186.64,34.66)
  BOTTOM w0.076: CPU1.BJ3 120.37,89.22 120.38,89.24 120.48,89.47 120.48,89.66 120.44,89.75 120.44,90.03 120.48,90.12 120.48,90.32 120.39,90.56 119.43,92.3 119.32,92.41
  BOTTOM w0.102: 117.91,94.01 117.66,94.26 117.63,94.28 117.12,94.28 v2(117.09,94.25) ; 117.91,94.01 v1(117.78,93.87) ; 117.91,94.01 118.89,93.02 118.89,92.84 119.32,92.41 ; C6302.2 166.67,19.83 166.43,19.83 166.21,20.05 166.21,23.8 166.43,24.02 166.43,27.61 171.55,32.73 175.87,32.73 178.38,35.25 186.06,35.25 v2(186.64,34.66)
SSD_SCP#: length 118.6
  TOP w0.102: v2(166.75,6.37) 166.59,6.37 165.99,5.77 165.99,4.84 166.12,4.72 R6307.2 R6308.1
  L4SGND w0.102: v2(77.98,3.57) 77.98,2.51 79.46,1.02 105.41,1.02 105.93,1.54 139.96,1.54 145.36,6.94 145.36,7.69 145.62,7.94 161.44,7.94 163.02,6.37 v2(166.75,6.37)
  BOTTOM w0.102: 81.92,8.07 80.46,8.07 79.53,7.14 79.53,5.14 77.98,3.59 v2(77.98,3.57) ; 81.92,8.07 82.73,8.07 82.99,7.81 84.4,7.81 84.51,7.92 84.51,7.96 84.76,8.21 84.76,8.56 85.06,8.86 86.03,8.86 86.55,9.38 86.55,13.84 86.49,13.99 86.31,14.17 86.31,14.22 85.31,15.22 85.16,15.22 84.28,16.09 U2401.21 ; 81.92,8.07 v1(81.92,8.1)
SSD_SCP#_1: length 22.3
  TOP w0.102: R6308.2 167.39,5.48 167.92,6.01 v1(167.92,6.22) 167.77,6.37 v2(167.39,6.37)
  L4SGND w0.102: v2(167.39,6.37) 169.87,6.37 173.79,10.29 173.79,21.35 174.53,22.1 SSD1.8
SSEQ0_A0: length 3.9
  TOP w0.127: R7145.2 R7146.1 40.56,93.11 v1(40.67,93.11) 40.67,92.5 v2(40.64,92.47)
  BOTTOM w0.127: v2(40.64,92.47) 40.64,92.48 U7101.11
SSEQ1: length 4.1
  TOP w0.127: v2(36.58,95.01) 36.3,94.73 v1(36.3,94.38) 36.42,94.25 R7144.1 37.34,94.43 R7152.2
  BOTTOM w0.127: v2(36.58,95.01) 36.96,95.01 37.37,94.6 U7101.3
SUS_CLK: length 186.2
  TOP w0.089: v2(124.96,70.84) 124.96,69.11 124.08,68.23 124.08,61.91 124.25,61.73 124.25,60.87 v2(124.16,60.79)
  L6 w0.089: v2(124.16,60.79) 124.16,60.43 125.92,58.67 125.92,56.72 132.79,49.85 133.65,49.85 136.49,47.01 141.35,47.01 143,45.36 146.02,45.36 146.92,44.45 146.92,44.43 147.02,44.33 147.02,42.31 148.59,40.75 148.59,40.75 149.1,40.24 149.1,36.79 148.67,36.35 148.67,33.55 149.1,33.11 149.1,30.58 148.44,29.92 144.09,29.92 144.06,29.89 142.39,29.89 141.86,29.36 140.21,29.36 138.68,30.88 126.62,30.88 126.3,31.2 123.01,31.2 122.87,31.06 120.47,31.06 120.4,31.13 99.82,31.13 99.34,30.65 86.77,30.65 85.65,29.53 85.65,24.37 83.03,21.75 82.28,21.75 80.01,19.48 77.97,19.48 74.91,16.42 67.96,16.42 63.7,12.16 v2(61.34,12.16) ; v2(80.77,3.83) 80.77,4.51 79.32,5.97 78.63,5.97 78.61,5.99 73.87,5.99 73.62,5.73 72.52,5.73 v2(72.01,6.24)
  BOTTOM w0.089: v2(124.16,60.79) 124.26,60.88 124.94,60.88 125.4,60.42 EC1803.1 FC1801.1 ; CPU1.BT32 124.7,70.58 v2(124.96,70.84) ; v2(72.01,6.24) 72.01,7.1 70.97,8.15 68.15,8.15 v1(67.31,8.98) 66.71,8.98 64.37,11.32 62.18,11.32 v2(61.34,12.16) ; R2461.1 81.41,5.4 81.41,5.16 81.4,5.16 81.4,4.46 v2(80.77,3.83)
SUSACK#_R: length 22.5
  TOP w0.102: v2(127.63,70.89) 127.63,70.62 127.15,70.15 127.15,69.87 126.62,69.34 126.62,65.93 126.62,65.93 126.62,65.77 127.3,65.09 128.42,65.09 129.98,63.52 129.98,63.2 129.03,62.25 129.03,58.82 v1(128.91,58.69) 128.91,58.11 129.32,57.69 129.32,57.69 129.63,57.38 129.63,57.19 129.64,57.18 129.64,56.3 129.63,56.3 129.63,55.78 v2(129.74,55.68)
  BOTTOM w0.102: v2(127.63,70.89) 127.32,70.58 CPU1.BY32 ; v2(129.74,55.68) 129.74,56.16 129.38,56.52 129.02,56.52 127.59,55.09 R1708.2
SVID_ALERT#_CPU: length 58
  TOP w0.089: v2(44.83,82.82) v1(47.88,85.87) 49.44,87.43 52.77,87.43 54.04,88.7 72.02,88.7 74.13,90.81 74.13,94.68 77.23,97.77 77.6,97.96 78.78,98.4 79.75,98.76 87.19,98.76 89.53,96.41 v2(89.53,96.16)
  BOTTOM w0.089: PR4605.2 v2(44.83,82.82) 44.83,82.62 PR4623.1 ; v2(89.53,96.16) 89.1,96.59 R727.2 89.1,97.05 R728.2
SVID_ALERT#_CPU_R: length 19
  BOTTOM w0.076: CPU1.AA3 103.13,88.99 103.21,89.08 103.29,89.24 103.38,89.44 103.38,89.68 103.37,89.73 103.22,89.87 103.07,89.87 102.86,90.08 102.86,91.2
  BOTTOM w0.089: 102.86,91.2 102.86,91.22 101.94,92.14 101.53,92.14 99.24,94.43 99.24,96.67 98.32,97.59 v1(96.24,97.59) 90.51,97.59 R728.1
SVID_ALERT#_VR: length 3.1
  BOTTOM w0.089: PR4623.2 44.32,80.41 44.86,79.88 v1(44.86,79.39) 44.78,79.31 PU4601.36
SVID_CLK_CPU: length 56.4
  TOP w0.089: v2(45.59,82.82) 49.73,86.96 v1(52.96,86.96) 52.97,86.96 54.24,88.23 72.21,88.23 74.6,90.62 74.6,94.48 77.51,97.39 77.79,97.53 79.84,98.29 86.77,98.29 v2(88.9,96.16)
  BOTTOM w0.089: PR4624.1 45.59,82.62 v2(45.59,82.82) PR4606.2 ; R732.2 88.27,95.22 R723.2 88.39,95.14 88.9,95.65 v2(88.9,96.16)
SVID_CLK_CPU_R: length 21
  BOTTOM w0.089: CPU1.AA1 103.13,90.56 103.04,90.65 103.04,91.3 102.02,92.32 101.6,92.32 99.54,94.38 99.54,95.85 99.72,96.03 99.72,96.86 v1(99.19,97.39) 98.51,98.06 89.28,98.06 88.27,97.05 R732.1
SVID_CLK_VR: length 3.4
  BOTTOM w0.089: PR4624.2 45.09,80.92 v1(45.67,80.33) 45.52,80.33 45.21,80.03 45.21,79.27 45.18,79.23 PU4601.37
SVID_DATA_CPU: length 59.8
  TOP w0.089: v2(44.2,82.82) 44.2,83.68 v1(44.86,84.34) 44.86,84.63 46.61,86.38 47.55,86.38 49.07,87.9 52.58,87.9 53.85,89.17 71.82,89.17 73.66,91.01 73.66,94.97 76.76,98.06 77.41,98.39 77.42,98.39 79.66,99.23 87.6,99.23 v2(90.68,96.16)
  BOTTOM w0.089: PR4604.2 44.07,82.95 v2(44.2,82.82) 43.56,82.19 PR4622.1 ; R709.2 90.81,96.28 v2(90.68,96.16)
SVID_DATA_CPU_R: length 16.7
  BOTTOM w0.089: R709.1 R726.2 v1(93.52,97.05) 98.2,97.05 98.74,96.51 98.74,95.77 98.94,95.56 98.94,94.39 101.39,91.95 101.89,91.95 102.69,91.14 102.69,89.71 102.83,89.56 CPU1.AA2
SVID_DATA_VR: length 3.6
  BOTTOM w0.089: PR4622.2 43.41,81.09 v1(43.41,80.28) 43.66,80.28 44.49,79.45 44.49,79.06 44.38,78.94 PU4601.35
SYS_LED_MASK#: length 2.5
  BOTTOM w0.089: U2401.55 93.91,23.17 v1(93.75,23.34) 94.49,23.34 R2410.2
SYS_LED_MASK#_R: length 92.8
  L3SGND w0.127: v2(114.6,2.2) 113.69,2.2 113.09,1.61 99.12,1.61 98.68,2.05 98.68,3.45 97.28,4.84 97.28,6.24 100.58,9.54 100.58,13.1 103.38,15.89 112.27,15.89 115.06,18.69 115.06,27.07 115.76,27.77 115.76,28.28 114.68,29.36 101.7,29.36 v2(100.33,27.98)
  L6 w0.127: v2(96.94,24.66) 100.24,27.96 100.3,27.96 v2(100.33,27.98)
  BOTTOM w0.127: v2(96.94,24.66) 96.94,23.3 96.75,23.11 R2456.1 96.37,23.13 R2410.1 ; R6419.1 122.3,7.08 U6402.2 122.3,2.81 v1(121.97,2.48) 121.16,1.67 115.14,1.67 v2(114.6,2.2)
SYS_PRES1#: length 10.2
  TOP w0.102: v2(165.35,11.22) 165.35,12.08 AFTP4315.1 165.2,12.44 166.22,12.44 R4301.2
  BOTTOM w0.102: BATT1.7 163.35,13.2 165.33,11.22 v2(165.35,11.22)
SYS_PWROK: length 219
  TOP w0.127: v2(168.6,84.27) 166.88,82.54 166.88,56.09 165.89,55.1 165.89,54.53 164.5,53.14 164.5,51.04 164.99,50.55 164.99,49.93 165.01,49.9 165.01,45 164.8,44.79 v2(164.72,44.6)
  L6 w0.127: v2(87.38,9.29) 89.62,7.05 90.88,7.05 90.91,7.08 99.26,7.08 99.51,7.33 101.83,7.33 102.41,7.91 102.56,7.91 104.89,7.91 106.13,7.39 106.97,6.56 115.25,6.56 116.59,5.23 121.13,5.23 123.19,7.28 128.24,7.28 129.63,5.9 136.4,5.9 138.29,4.01 163.67,4.01 166.1,6.44 166.1,8.59 166.89,9.37 166.89,14.11 168.14,15.35 168.63,15.35 169.42,16.15 169.42,18.24 170.17,18.99 170.17,35.81 164.72,41.25 v2(164.72,44.6)
  BOTTOM w0.127: v2(87.38,9.29) 87.38,9.93 87.19,10.12 87.19,13.05 87.44,13.31 87.44,14.06 85.56,15.94 85.56,16.41 85.55,16.42 85.55,17.86 84.51,18.89 U2401.28 ; CPU1.CR10 135.93,84.66 138.69,84.66 139.9,85.87 v1(140.72,85.87) 140.83,85.76 144.97,85.76 146.82,87.61 150.34,87.61 152.22,89.49 152.58,89.49 153.54,88.54 154.81,88.54 159.51,83.84 160.32,83.84 R1717.2 161.08,83.08 163.45,83.08 ED1702.1 164.54,82.13 165.48,83.08 167.57,83.08 168.6,84.11 v2(168.6,84.27)
SYSPWR_PRES: length 3.6
  TOP w0.102: R2463.2 R2454.1 87.68,6.06 v2(88.27,5.48) 88.44,5.3 v1(88.44,4.97)
  BOTTOM w0.102: U2401.120 88.31,5.53 v2(88.27,5.48)
T_CRIT#: length 87.9
  TOP w0.102: R2601.1 146.48,97.68 R2604.2 145.97,98.72 146.65,99.4 149.1,99.4 149.48,99.02 149.48,98.72 149.91,98.29 153.49,98.29 154.69,99.48 v1(154.69,99.59) 156.63,99.59 159.22,97 159.22,88.11 164.73,82.59 164.73,77.3 164.49,77.06 164.49,76.07 164.71,75.85 164.71,70 164.2,69.5 164.2,56.57 162.94,55.31 162.94,50.39 163.31,50.02 163.31,47.33 162.94,46.96 162.94,45.61 v2(162.84,45.51)
  BOTTOM w0.102: U2601.4 151.04,43.54 150.68,43.9 150.68,44.6 151.44,45.36 152.04,45.36 152.42,45.74 153.47,45.74 153.9,45.31 155.19,45.31 155.75,45.87 157.1,45.87 158.02,44.94 160.87,44.94 161.44,45.51 v2(162.84,45.51)
TBTA_SENSEN: length 5.7
  BOTTOM w0.102: U7201.A10 19.27,78.66 19.27,78.51 19.29,78.49 19.29,76.89 v1(19.1,76.7) 19.29,76.51 19.29,75.27 18.73,74.71 18.32,74.71 17.91,74.29 R7217.2
TBTA_SENSEP: length 5.8
  BOTTOM w0.089: U7201.B10 19.49,78.95 19.49,78.4
  BOTTOM w0.102: R7216.2 18.67,74.32 19.12,74.77 v1(19.3,74.77) 19.3,74.77 19.3,74.92 19.52,75.14 19.52,78.38 19.49,78.4
TCH_INTR#: length 123.6
  TOP w0.127: v2(68.58,91.33) 68.14,90.89 65.22,90.89 64.96,91.15 64.96,92.13 67.38,94.54 75.01,98.87 80.27,100.82 81.89,101.47 82.77,101.79 87.42,106.44 100.07,106.44 100.2,106.44 100.57,106.81 111.45,106.81 114.71,103.55 122.61,103.55 125.38,106.33 130.94,106.33 131.56,105.71 131.56,101.52 131.56,101.52 131.56,100.94 132.47,100.03 138.24,100.03 139.7,98.57 v2(139.7,98.44)
  BOTTOM w0.127: v2(139.7,98.44) 139.7,98.32 139.12,97.73 R5523.1 ; ED5502.1 48.32,89.46 46.84,90.95 46.84,91.83 46.95,91.94 48.24,91.94 v1(48.26,91.97) 48.28,91.94 51.1,91.94 51.5,91.55 51.5,91.14 51.79,90.85 56.38,90.85 57.81,89.43 59.31,89.43 60.33,88.41 68.2,88.41 68.8,89.01 TCBD1.16 68.8,91.11 v2(68.58,91.33)
TCH_PNL_3D3V_5V: length 26
  TOP w0.508: R5508.1 71.12,92.52 71.12,90.7 70.36,89.93 v1(55.75,89.93) 54.41,89.93 R5512.2 54.18,90.75 53.85,91.08 53.85,92.4 R5509.2 R5541.1 52.63,91.38 v2(52.58,91.33)
  BOTTOM w0.508: v2(52.58,91.33) 52.58,91.85 51.75,92.67 U5503.5
TEST_MODE_1: length 2.5
  TOP w0.102: v2(50.74,34.95) 50.34,34.55 TP1201.1
  BOTTOM w0.102: v2(50.74,34.95) 51.52,35.74 RAM4.N9
TEST_MODE_2: length 2.1
  TOP w0.102: v2(81.19,34.95) 80.87,34.64 TP1202.1
  BOTTOM w0.102: RAM1.N9 81.97,35.74 v2(81.19,34.95)
TEST_MODE_3: length 2.1
  TOP w0.102: TP1203.1 60.29,34.95 v2(60.89,34.95)
  BOTTOM w0.102: v2(60.89,34.95) 61.67,35.74 RAM3.N9
TEST_MODE_4: length 2.2
  TOP w0.102: v2(71.04,34.95) 70.72,34.63 TP1204.1
  BOTTOM w0.102: v2(71.04,34.95) 71.04,35.1 71.67,35.74 RAM2.N9
TEST_MODE_5: length 3
  TOP w0.102: TP1301.1 103.21,34.95 v2(103.24,34.95)
  BOTTOM w0.102: v2(103.24,34.95) 104.02,35.74 RAM6.N9
TEST_MODE_6: length 2.2
  TOP w0.102: v2(123.54,34.95) 123.54,34.76 TP1302.1
  BOTTOM w0.102: RAM8.N9 124.32,35.74 v2(123.54,34.95)
TEST_MODE_7: length 2.1
  TOP w0.102: TP1303.1 113.71,34.64 v2(113.39,34.95)
  BOTTOM w0.102: RAM5.N9 114.17,35.74 v2(113.39,34.95)
TEST_MODE_8: length 2.1
  TOP w0.102: TP1304.1 134,34.64 v2(133.69,34.95)
  BOTTOM w0.102: RAM7.N9 134.47,35.74 v2(133.69,34.95)
THERM_SYS_SHDN#: length 4.6
  TOP w0.102: v2(145.61,96.98) 145.8,96.79 v1(146.56,96.79) 146.99,97.22 147.29,97.22 R2601.2 147.8,97.73 R2602.1
  BOTTOM w0.102: v2(145.61,96.98) 144.84,96.98 Q2602.S
THERMTRIP#_CPU: length 12.2
  BOTTOM w0.102: CPU1.BJ1 120.21,90.5 120.06,90.77 118.61,92.23 117.84,92.23 115.75,94.33 R308.2 115.75,95.7 116.03,95.98 118.16,95.98 TP309.1 118.68,95.84 ED301.1
TOUCH_DETECT: length 114.3
  TOP w0.102: v2(67.31,91.33) 66.67,91.97 R5504.2 v1(66.62,92.96) 66.62,93.45 67.48,94.3 75.15,98.66 80.35,100.59 81.97,101.24 82.9,101.59 87.5,106.19 100.33,106.19 100.71,106.57 111.35,106.57 114.61,103.31 122.72,103.31 125.5,106.09 130.84,106.09 131.32,105.61 131.32,101.62 131.32,100.84 132.37,99.79 137.63,99.79 138.51,98.91 138.51,98.14 138.63,98.01 140.03,98.01 140.13,98.11 140.13,98.95 140.59,99.41 145.11,99.41 146.19,100.49 156.99,100.49 160.78,96.7 R2102.1
  BOTTOM w0.102: TCBD1.13 67.3,91.32 v2(67.31,91.33)
TOUCH_DETECT_R: length 56.8
  TOP w0.102: v2(169.54,84.6) 169.45,84.7 167.71,84.7 167.63,84.61 165.57,84.61 161.42,88.76 161.42,91.66 161.08,92 160.81,92 160.5,92.31 160.5,95.45 R2102.2
  BOTTOM w0.076: CPU1.CN14 134.89,81.99 135,81.89 arc(135.06,81.84) 135.14,81.82 135.3,81.82 arc(135.34,81.82) 135.38,81.84 arc(135.44,81.87) 135.5,81.88 135.57,81.88 arc(135.64,81.87) 135.71,81.84 135.9,81.79 138.32,81.79
  BOTTOM w0.102: v2(169.54,84.6) 167.63,82.68 165.64,82.68 165.53,82.58 165.53,82.43 164.7,81.59 164.02,81.59 162.77,82.84 158.23,82.84 157.56,83.51 153.8,83.51 152.96,84.35 151.51,84.35 150.57,83.41 145.36,83.41 v1(143.7,81.74) 142.98,81.03 139.08,81.03 138.32,81.79
TOUCH_PANEL_INTR#: length 77.6
  TOP w0.127: v2(87,100.48) 86.74,100.48 86.23,100.99 U5504.9 U5504.2
  L3SGND w0.127: v2(138.94,98.44) 138.94,99.36 137.79,100.5 131.8,100.5 126.36,105.94 122.29,105.94 122.23,105.87 113.73,105.87 112.78,106.83 87.5,106.83 85.47,104.79 85.47,102 v2(87,100.48)
  BOTTOM w0.127: CPU1.CN3 134.86,89.27 135.52,89.27 135.67,89.43 136,89.43 136.26,89.69 R5507.1 136.26,94 138.17,95.9 v1(138.25,95.9) R5505.1 R5523.2 138.25,98.01 138.68,98.44 v2(138.94,98.44)
TOUCH_PANEL_PD#: length 398.4
  TOP w0.127: v2(87.63,100.88) 87.63,101.18 87.5,101.31 U5504.10 U5504.1 ; v2(160.66,51.83) 160.66,51.14 160.85,50.94 160.85,49.51 161.23,49.14 161.23,46.38 161.05,46.2 161.05,45.7 160.08,44.73 160.08,43.42 159.9,43.24 159.9,41.76 160.63,41.04 161.98,41.04 162.92,40.1 162.92,39.13 159.11,35.32 v2(156.97,35.32)
  L4SGND w0.127: v2(131.48,65.95) 131.27,65.74 131.27,65.12 133.95,62.44 133.95,61.89 134.66,61.18 136.6,61.18 139.88,57.9 148.66,57.9 149.08,58.32 149.62,58.32 150,57.94 150,57.9 150.95,56.95 155.28,56.95 156.46,55.77 156.46,54.16 155.72,53.42 154.56,53.42 154.02,52.88 154.02,52.13 154.52,51.63 154.75,51.63 154.76,51.63 155.73,51.63 157.2,53.1 158.88,53.1 160.15,51.83 v2(160.66,51.83) ; v2(56.26,91.33) 55.28,90.35 53.68,90.35 53.19,89.87 47.83,89.87 44.9,86.94 44.9,86.4 44.9,85.33 44.26,84.7 40.61,84.7 39.43,83.51 39.43,83.29 38.11,81.96 37.07,81.96 33.95,78.84 33.95,75.45 33.6,75.1 33.6,67.2 33.2,66.79 33.2,57.92 32.78,57.5 32.43,57.5 32.42,57.49 30.98,57.49 29.23,55.73 28.25,55.73 26.92,54.4 26.92,34.78 26.35,34.21 26.35,32.09 27.69,30.75 28.94,30.75 31.24,28.45 31.24,28.08 38.48,20.85 v2(38.48,20.47)
  L6 w0.127: v2(38.48,20.47) 40.83,18.12 47.69,18.12 49.92,15.89 52.57,15.89 53.59,14.87 53.59,13.6 53.53,13.54 53.53,13.17 55.67,11.03 65.03,11.03 68.89,14.89 75.71,14.89 76.12,15.3 78.45,15.3 82.74,19.59 82.79,19.59 87.5,24.31 87.5,25.57 87.69,25.76 89.95,25.76 90.93,24.78 90.93,19.29 91.95,18.27 92.76,18.27 92.76,18.27 93.52,18.27 93.85,17.93 96.8,17.93 98.04,19.18 98.04,20.72 101.29,23.96 104.96,23.96 107.47,26.46 130.93,26.46 135.9,21.49 140.22,21.49 140.6,21.11 140.6,20.98 142.73,18.85 155.22,18.85 155.68,19.31 158,19.31 160.41,21.72 160.41,22.76 160.64,22.99 160.64,28.22 159.22,29.65 159.22,33.32 157.21,35.32 v2(156.97,35.32)
  BOTTOM w0.076: CPU1.CC35 129.62,68.57 129.62,67.94 129.73,67.74 129.73,67.47 130.36,66.84 131.1,66.84 131.49,66.45 131.49,65.96 v2(131.48,65.95)
  BOTTOM w0.127: TCBD1.15 68.3,89.15 67.82,88.66 60.43,88.66 59.41,89.68 58.04,89.68 56.39,91.33 v2(56.26,91.33) 55.75,91.84 53.21,91.84 52.32,92.73 52.32,93.41 51.61,94.13 51.61,95.14 v1(52.31,95.84) 52.63,96.16 72.77,96.16 81.15,104.54 84.33,104.54 87.63,101.24 v2(87.63,100.88)
TOUCH_REPORT_SW: length 97.9
  L4SGND w0.127: v2(24.27,30.88) 24.27,36.57 24.31,36.61 24.31,39.44 26.67,41.8 26.67,54.51 28.15,55.99 29.12,55.99 31.37,58.23 31.91,58.23 32.05,58.37 32.66,58.37 32.79,58.5 32.79,66.74 33.35,67.3 33.35,75.21 33.69,75.55 33.69,78.94 36.96,82.21 38,82.21 39.18,83.39 39.18,83.65 40.48,84.95 44.16,84.95 44.64,85.44 44.64,86.3 44.64,87.05 47.72,90.12 53.09,90.12 53.57,90.61 54.9,90.61 56.06,91.78 56.76,91.78 57.15,91.38 v2(57.15,91.31)
  BOTTOM w0.127: v2(57.15,91.31) 58.53,89.93 59.52,89.93 60.54,88.92 67.56,88.92 67.8,89.15 TCBD1.14 ; D2402.A 23.5,30.49 v1(23.5,30.7) 23.57,30.7 23.75,30.88 v2(24.27,30.88)
TP_65982D_RESET_N: length 2
  TOP w0.127: TP7205.1 27.43,83.97 26.34,82.87 R7229.2
TP_EN#: length 62.7
  TOP w0.127: RN2405.4 126.56,10.84 127.18,10.21 v2(127.18,9.57)
  L6 w0.127: v2(127.18,9.57) 127.15,9.54 127.15,9.42 125.91,8.17 117.13,8.17 116.4,7.45 108.71,7.45 107.63,8.53 105.85,8.53 105.52,8.86 102.01,8.86 101.36,8.21 97.1,8.21 96.22,7.33 90.8,7.33 90.77,7.3 89.94,7.3 89.47,7.77 89.47,8.75 v2(89.92,9.19)
  BOTTOM w0.127: v2(89.92,9.19) 90.17,9.45 90.17,11.88 90.2,11.91 90.2,11.99 90.36,12.15 90.79,12.15 91.25,12.61 91.25,21.04 91.51,21.3 U2401.49 ; v2(127.18,9.57) 127.15,9.6 127.15,9.75 126.75,10.15 126.75,11.4 127.1,11.75 v1(127.1,11.77) 127.09,11.77 126.95,11.91 R6504.1
TP_ON#_GATE: length 10.6
  BOTTOM w0.102: R6504.2 127.81,12.59 128.45,11.96 C6502.2 127.51,10.76 Q6502.G 127.32,10.62 127.64,10.31 127.64,9.39 127.05,8.8 127.05,8.43 v1(127.15,8.32) 127.56,8.32 127.66,8.43 127.66,8.93 128.18,9.46 129.44,9.46 Q6503.G
TP_TPM_GPIO1: length 6
  BOTTOM w0.102: U9102.30 161.52,56.26 161.16,55.9 159.64,55.9 158.55,54.81 158.55,54.49 158.29,54.24 156.85,54.24 TP9103.1
TP_TPM_GPIO3: length 1.4
  BOTTOM w0.102: U9102.6 159.11,59.81 TP9102.1
TP_TPM_PP: length 1.5
  BOTTOM w0.102: TP9101.1 159.38,58.81 U9102.4
TP_WAKE_KBC#: length 194
  TOP w0.102: v2(141.51,7.38) 141.08,7.82 140.92,7.82 AFTP6536.1 139.85,8.15 139.32,8.68 139.32,9.31 R6511.2
  L4SGND w0.102: v2(141.51,7.38) 141.51,9.43 142.21,10.13 156.41,10.13 v2(157.48,11.19)
  L6 w0.102: v2(148.34,54.88) 150.16,53.05 150.66,53.05 151.33,52.38 151.33,51.28 151.02,50.97 151.02,49.4 151.58,48.84 151.58,48.48 151.4,48.3 151.4,45.25 152.16,44.49 154.65,44.49 157,42.14 157,41.52 157.38,41.14 157.38,39.54 161.87,35.05 161.87,30.85 164.4,28.32 164.4,21.63 159.22,16.44 159.22,16.24 158.74,15.77 v2(156.46,15.77) 142.02,15.77 139.54,18.24 134.93,18.24 133.81,17.12 132.06,17.12 131.27,16.34 114.49,16.34 112.69,18.14 103.28,18.14 102.76,17.62 100.86,17.62 98.26,15.02 95.32,15.02 95.32,15.03 94.51,15.03 94.5,15.02 93.96,15.02 93.56,14.63 89.91,14.63 89.35,14.06 88.99,14.06 88.54,14.51 87.55,14.51 86,16.06 v2(86,16.49)
  BOTTOM w0.076: CPU1.CB34 128.65,69.03 128.99,68.69 129.05,68.54 129.05,68.12 129.07,68.07 129.08,68.03 129.08,67.79 129.05,67.7 129.05,67.11 130.04,66.12
  BOTTOM w0.102: v2(156.46,15.77) 157.48,14.75 v2(157.48,11.19) ; TP1.4 141.85,7.72 141.52,7.38 v2(141.51,7.38) ; U2401.33 85.11,20.66 85.31,20.46 85.31,19.5 85.22,19.41 85.22,18.64 86,17.85 v2(86,16.49) ; v2(148.34,54.88) 148.22,54.88 147.07,56.03 143.35,56.03 143.33,56.05 140.38,56.05 139.83,56.59 138.69,56.59 138.24,57.05 137.04,57.05 136.79,56.79 134.56,56.79 134.48,56.71 134.19,56.71 132.26,58.64 132.26,60.67 131.84,61.09 130.7,61.09 R303.2 130.3,61.6 130.3,62.31 130.94,62.95 130.94,64.03 130.64,64.33 130.64,64.85 130.43,65.06 130.43,65.73 130.04,66.12
TPM_GPIO0: length 4
  BOTTOM w0.127: U9102.29 162.02,55.99 v1(161.67,55.64) 161.45,55.42 159.92,55.42 159.26,54.76 R9141.1
TPM_GPIO4: length 2.4
  BOTTOM w0.127: TP9104.1 162.52,61.82 U9102.13
TPM_ID: length 13.7
  BOTTOM w0.076: 135.13,75.02 135,74.89 134.8,74.82 134.79,74.82 134.47,74.94 134.2,74.94 134.04,74.77 133.46,74.77 CPU1.CK25
  BOTTOM w0.089: 135.13,75.02 135.13,75.22
  BOTTOM w0.102: 135.13,75.22 135.29,75.38 138.23,75.38 138.77,75.92 v1(139.77,75.92) 139.77,75.15 139.39,74.77 139.39,74.38 139.68,74.09 140.01,74.09 140.66,74.74 141.4,74.74 141.83,74.31 141.83,74.03 R1911.1 142.37,73.5 142.37,72.84 R1910.2
TPM_SPI_IRQ#: length 58.3
  TOP w0.102: v1(168.28,60.85) v2(168.28,60.32)
  L4SGND w0.102: v2(148.08,62.86) 148.08,62.65 148.55,62.19 149.57,62.19 150.98,63.59 155.27,63.59 156.11,64.43 161,64.43 161.28,64.15 163.22,64.15 167.05,60.32 v2(168.28,60.32)
  L6 w0.102: v2(148.08,62.86) 148.08,63.21 148.91,64.05 148.91,70.33 148.26,70.98 148.26,76.07 146.08,78.25 138.18,78.25 138.04,78.11 130.83,78.11 v2(130.3,77.57)
  BOTTOM w0.102: CPU1.CF20 130.3,77.71 v2(130.3,77.57) ; R9139.1 168.17,60.22 v2(168.28,60.32)
TYPEC_DCIN1_EN#: length 135.7
  TOP w0.102: v2(40.13,22.57) 39.04,21.48 v1(37.34,21.48) 37.22,21.37 32.8,21.37 32.49,21.05 31.93,21.05 30.94,22.04 v2(28.09,22.04)
  L4SGND w0.102: v2(97.66,24.66) 96.58,23.57 82.27,23.57 77.39,28.44 43.03,28.44 v2(42.55,27.96)
  L6 w0.102: v2(28.09,22.04) 28.02,22.04 25.86,24.19 25.86,26.44 22.43,29.88 22.43,31.18 20.7,32.91 19.32,32.91 18.41,33.81 18.41,51.07 16.7,52.79 16.7,67.14 v2(16.38,67.46)
  BOTTOM w0.102: v2(40.13,22.57) 40.21,22.65 40.21,24.1 41.3,25.19 41.3,26.71 v2(42.55,27.96) ; Q7402.5 17.14,66.31 17.02,66.44 17.02,66.9 16.46,67.46 v2(16.38,67.46) 16.13,67.2 15.24,67.2 15.11,67.33 Q7406.5 ; U2401.63 97.11,23.01 R7401.1 97.66,23.56 v2(97.66,24.66)
TYPEC_SMBCLK: length 13.7
  BOTTOM w0.089: R2468.2 109.55,11.14 109.03,10.62 Q2417.1 108.47,10.06 108.38,9.97 106.95,9.97 106.38,10.54 106.19,10.54 v1(106.05,10.69) 105.75,10.98 103.32,10.98 RN2413.3 102.73,11.58 101.68,11.58 100.81,10.7 100.09,10.7 99.48,10.09 U2401.91
TYPEC_SMBCLK_Q: length 182.2
  L6 w0.089: v2(14.99,91.2) 14.76,90.98 14.76,88.55 12,85.79 12,79.6 12.79,78.81 15.84,78.81 18.12,76.53 18.12,75.62 17.92,75.42 17.75,75.42 v2(17.53,75.2) 17.23,74.9 17.23,71.98 17.85,71.36 17.85,53.61 19.21,52.25 19.21,35.55 23.56,31.2 23.56,30.68 24.25,30 24.25,29.77 24.65,29.37 26.03,29.37 27.95,27.45 27.95,25.68 30.37,23.26 30.37,22.75 32.98,20.14 32.98,16.13 34.85,14.27 36.84,14.27 37.5,13.61 37.97,13.61 38.39,14.02 41.38,14.02 47,8.4 65.45,8.4 67.99,10.94 75.26,10.94 75.69,10.5 78.81,10.5 79.41,11.11 79.73,11.11 80.87,12.25 85.63,12.25 86.6,11.28 90.39,11.28 93.55,11.28 93.97,11.7 103.56,11.7 104.04,12.18 106.94,12.18 107.66,11.46 v2(109.07,11.46)
  BOTTOM w0.089: Q2417.6 108.47,12.83 108.69,13.05 109.5,13.05 R2468.1 109.3,12.74 109.13,12.74 109.04,12.65 109.04,11.49 v2(109.07,11.46) ; U7201.B5 16.53,78.93 16.53,77.06 16.55,77.02 v1(16.64,76.98) 17.04,76.58 17.04,75.69 v2(17.53,75.2) ; v2(14.99,91.2) 14.77,90.98 14.77,89.33 14.35,88.92 R7220.1
TYPEC_SMBDA: length 9.2
  BOTTOM w0.089: Q2417.4 106.24,12.27 v1(106.17,12.34) 106.12,12.39 R2467.2 104.55,12.39 104.22,12.72 103.44,12.72 103.24,12.52 103.23,12.51 102.88,12.16 RN2413.4 102,12.16 100.73,10.89 U2401.89
TYPEC_SMBDA_Q: length 177.6
  L6 w0.089: v2(14.35,91.2) 14.57,90.98 14.57,88.63 11.81,85.87 11.81,79.52 12.71,78.62 15.76,78.62 17.93,76.45 17.93,75.7 17.84,75.61 17.75,75.61 v2(17.53,75.84) 17.04,75.35 17.04,71.9 17.66,71.28 17.66,53.53 19.02,52.17 19.02,35.47 23.37,31.12 23.37,30.6 24.06,29.92 24.06,29.7 24.57,29.18 25.95,29.18 27.76,27.37 27.76,25.6 30.18,23.18 30.18,22.67 32.79,20.06 32.79,16.05 34.77,14.08 36.76,14.08 37.42,13.42 38.05,13.42 38.46,13.83 41.3,13.83 46.92,8.21 65.53,8.21 68.07,10.75 75.18,10.75 75.61,10.31 78.89,10.31 79.49,10.92 79.81,10.92 80.95,12.06 85.55,12.06 86.52,11.09 90.31,11.09 90.82,11.09 90.82,11.09 93.63,11.09 94.05,11.51 103.64,11.51 104.12,11.99 105.51,11.99 105.87,11.63 v2(105.94,11.63)
  BOTTOM w0.089: v2(14.35,91.2) 14.57,90.98 14.57,89.41 13.62,88.46 R7221.1 ; v2(17.53,75.84) 17.68,75.99 17.68,76.24 v1(17.78,76.35) 17.78,76.73 16.77,77.73 U7201.A5 ; Q2417.3 107.17,10.75 107.03,10.9 106.67,10.9 v2(105.94,11.63) 105.84,11.52 R2467.1
U3_PD#_EC: length 99.4
  TOP w0.102: v1(173.61,29.23) 173.02,29.05 v2(172.92,29.05)
  L4SGND w0.102: v2(172.92,29.05) 171.74,29.05 170.99,28.3 170.99,22 164.08,15.09 164.08,13.46 162.75,12.13 156.14,12.13 154.82,10.81 141.41,10.81 137.37,6.77 133.04,6.77 130.86,8.95 128.84,8.95 127.28,7.38 122.45,7.38 121.95,7.89 115.15,7.89 113.83,9.21 109.65,9.21 v2(109.4,8.96)
  L6 w0.102: v2(167.36,41.34) 167.36,41.22 171.75,36.82 171.75,30.22 v2(172.92,29.05)
  BOTTOM w0.102: v2(167.36,41.34) 166.52,41.34 166.27,41.6 166.27,42.27 166.29,42.29 166.29,42.79 165.8,43.27 IOBD1.40 ; R2404.2 109.04,8.6 v2(109.4,8.96)
UART_2_CRXD_DTXD: length 178.7
  TOP w0.089: v2(88.27,18.94) 88.16,19.04 R6803.1 ; v2(154.43,42.06) 154.55,42.18 154.55,44.45 154.18,44.81 154.18,45.15 153.39,45.94 153.39,48.19 153.45,48.25 153.45,52.84 153.65,53.04 153.65,53.85 153.98,54.18 153.98,55.5 155.87,57.39 155.87,59.18 155.86,59.2 155.86,62.64 155.94,62.72 155.94,67.73 156.35,68.14 156.35,77.77 156.09,78.03 156.09,79.5 156.34,79.75 156.34,83.65 v2(154.86,85.13) 154.33,85.13 153.09,83.89 R2048.2
  L6 w0.089: v2(154.43,42.06) 155.07,41.42 155.07,39.07 159.96,34.18 159.96,29.95 160.87,29.04 161.33,28.59 161.39,28.53 161.39,23.87 161.79,23.47 161.79,22.05 158.31,18.57 155.99,18.57 155.53,18.11 142.38,18.11 140.33,20.15 135.31,20.15 134.66,20.8 134.66,20.9 133.26,22.3 132.45,22.3 129.03,25.72 107.77,25.72 105.12,23.06 101.66,23.06 101.09,22.5 101.09,20.54 100.46,19.91 100.19,19.91 97.21,16.93 96.11,16.93 96.11,16.94 93.37,16.94 93.04,17.27 92.35,17.27 92.35,17.28 90.43,17.28 89.37,18.33 88.87,18.33 v2(88.27,18.94)
  BOTTOM w0.089: CPU1.CR12 135.98,83.18 136.28,83.05 136.42,82.91 137.75,82.91 138.67,83.84 140.34,83.84 v1(141.1,84.6) 141.31,84.81 145.7,84.81 147.95,87.06 153.39,87.06 154.86,85.58 v2(154.86,85.13)
UART_2_CRXD_DTXD_CON: length 2.9
  TOP w0.089: DB1.14 87.23,18.51 R6803.2 86.03,19.7 v1(85.83,19.7)
UART_2_CTXD_DRXD: length 176.3
  TOP w0.089: v2(89.28,16.27) 89.86,15.69 89.92,15.55 91.24,14.24 R6802.1 ; v2(153.54,43.98) 152.56,43.98 151.38,45.16 151.38,46.12 151.88,46.62 151.88,48.1 151.93,48.15 151.93,50.33 151.72,50.54 151.72,55.22 152.47,55.97 152.47,56.13 154.1,57.75 154.1,58.11 153.76,58.44 152.99,58.44 152.72,58.71 152.72,67.55 152.51,67.76 152.51,71.98 152.25,72.25 152.25,74.11 R2049.2 152.43,74.24 153.81,74.24 153.92,74.35 153.92,75.64 154.63,76.35 154.63,77.29 153.8,78.12 153.8,79.91 154.37,80.48 154.37,82.1 153.59,82.89 152.43,82.89 152.07,82.52 151.72,82.52 151.42,82.82 144.15,82.82 143.9,82.57 142.12,82.57 v2(141.74,82.95)
  L6 w0.089: v2(89.28,16.27) 92.04,16.27 92.7,15.61 92.77,15.54 93.19,15.54 93.58,15.93 94.13,15.93 94.13,15.93 95.69,15.93 95.7,15.93 97.63,15.93 100.61,18.91 100.88,18.91 102.5,20.53 111.95,20.53 115.24,17.25 129.95,17.25 131.09,18.38 133.49,18.38 134.26,19.15 139.92,19.15 141.96,17.11 155.94,17.11 156.4,17.56 158.72,17.56 162.79,21.63 162.79,28.54 162.39,28.94 160.97,30.37 160.97,34.59 156.07,39.49 156.07,42.17 154.26,43.98 v2(153.54,43.98)
  BOTTOM w0.076: CPU1.CP12 135.46,83.29 135.65,83.1 arc(135.9,82.94) 136.19,82.88 136.21,82.88 136.35,82.74 137.83,82.74 137.91,82.82
  BOTTOM w0.089: 137.91,82.82 138.42,83.33 v1(140.59,83.33) 141.36,83.33 v2(141.74,82.95)
UART_2_CTXD_DRXD_CON: length 7.8
  TOP w0.089: v1(89.51,13) 90.14,13 R6802.2 90.37,14.39 89.37,15.39 87.78,15.39 87.4,15.77 87.4,16.3 88.23,17.12 DB1.13
UPD1_ALERT: length 124.5
  TOP w0.127: R7235.1 R7215.1 15.93,72.46 v2(15.88,72.41) ; v2(22.86,34.69) 22.1,33.93 v2(19.81,33.93)
  L6 w0.127: v2(15.88,72.41) 17.28,71 17.28,53.09 18.65,51.73 18.65,35.09 v2(19.81,33.93) ; v2(82.42,20.47) 80.77,18.81 78.41,18.81 78.07,18.47 78.07,18.22 75.43,15.58 68.61,15.58 64.74,11.71 58.91,11.71 53.88,16.74 51.09,16.74 49.47,18.37 41.34,18.37 38.29,21.42 36.42,21.42 35.75,22.08 35.75,23.23 32.85,26.12 32.85,28.13 33.13,28.4 33.33,28.4 33.72,28.79 33.72,29.48 32.3,30.89 27.54,30.89 27.5,30.93 27.11,30.93 24.45,33.59 24.45,33.87 23.63,34.69 v2(22.86,34.69)
  BOTTOM w0.127: U2401.32 83.16,20.49 82.55,21.1 v1(82.3,21.1) 82.3,20.59 v2(82.42,20.47)
UPD1_ALERT_R: length 8.4
  TOP w0.127: R7235.2 16.05,74.24 15.85,74.44 v1(15.85,74.85) 15.95,74.95 v2(16.51,74.95)
  BOTTOM w0.127: U7201.B6 17.23,79.13 17.03,78.93 17.03,77.88 18.12,76.79 18.12,76.2 18.03,76.11 18.03,75.12 17.7,74.78 16.68,74.78 v2(16.51,74.95)
USB1_CC1: length 27.2
  TOP w0.203: v1(21.34,88.66) 21.51,88.84 ED7304.2
  TOP w0.381: R7211.2 20.42,86.96 ; 20.42,86.96 20.52,86.96 20.73,86.87 20.79,86.81 21.23,86.63 v2(21.59,86.63) ; 20.42,86.96 21.11,87.65 21.11,87.72 C7217.1 21.34,87.95 v1(21.34,88.66)
  L4SGND w0.381: v2(9.98,80.3) 10.74,80.3 11.81,81.37 11.81,83.58 12.7,84.47 14.61,84.47 14.92,84.16 18.61,84.16 21.09,86.63 v2(21.59,86.63)
  BOTTOM w0.127: v2(21.59,86.63) 21.21,86.63 20.12,85.54 20.12,85.11 19.8,84.79 19.44,84.79 18.77,84.12 U7201.L9
  BOTTOM w0.178: v2(9.98,80.3) 9.98,80.41 9.62,80.77 8.49,80.77 8.27,80.55 USB1.A5
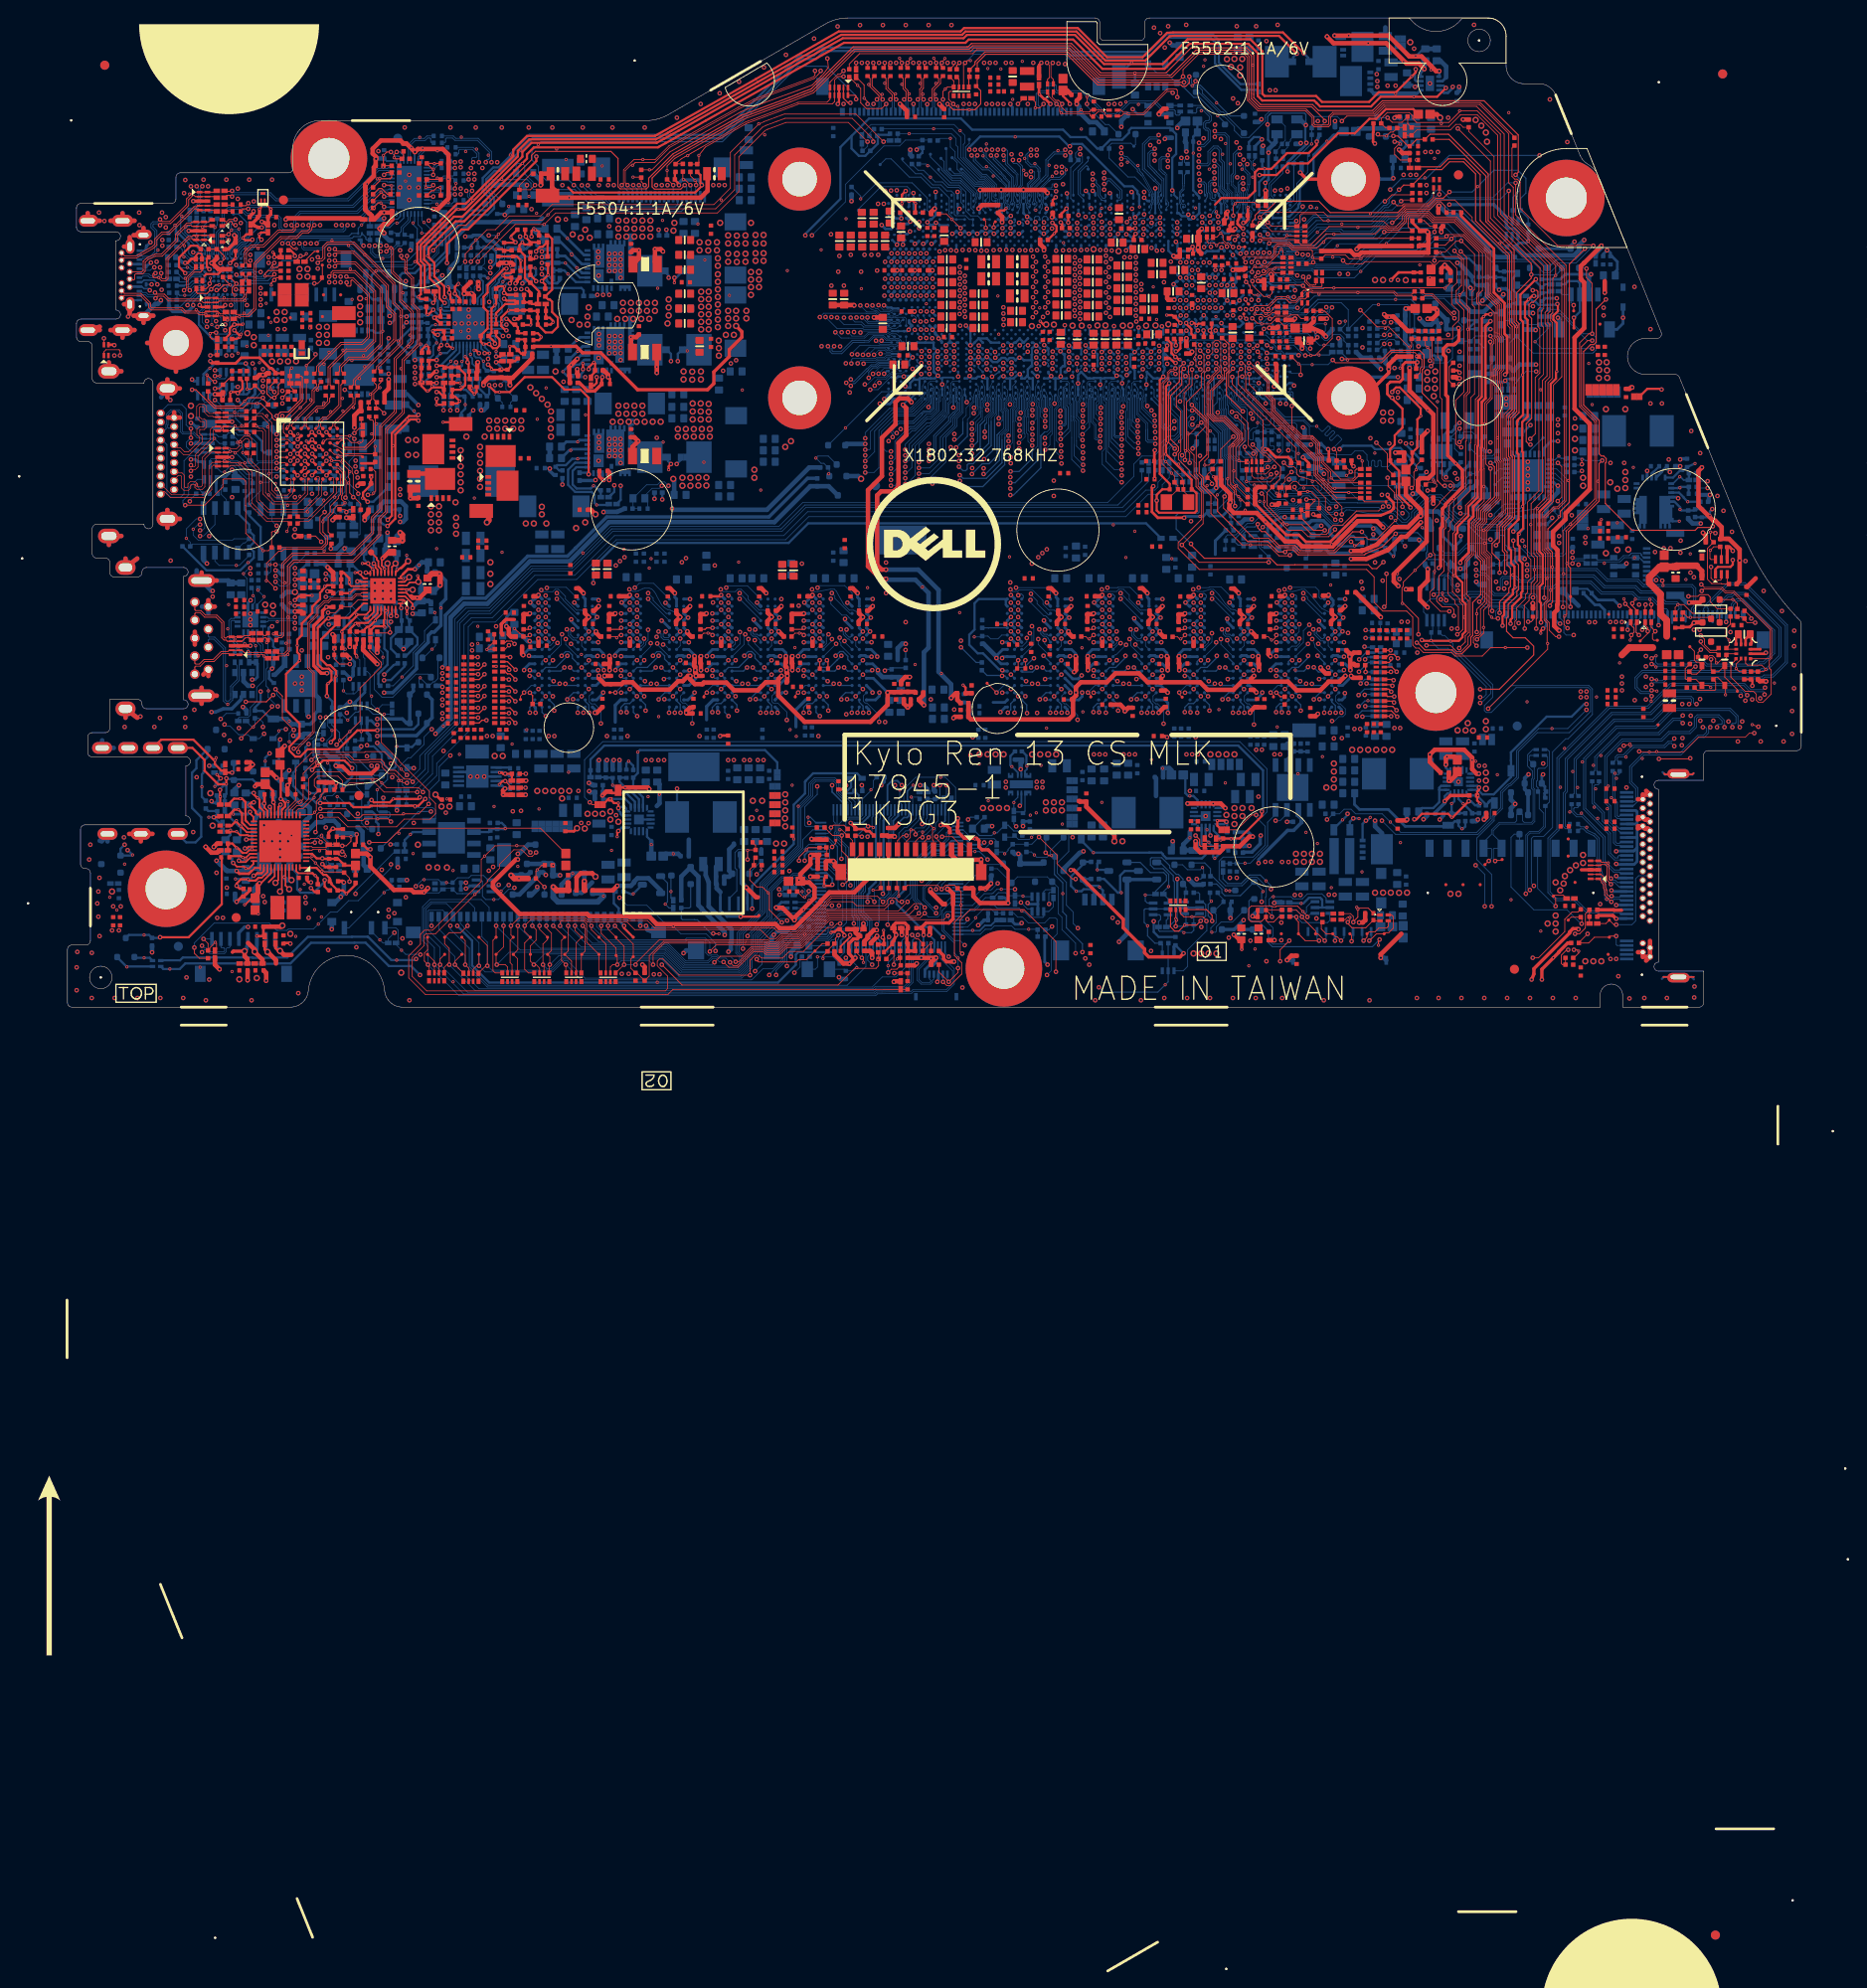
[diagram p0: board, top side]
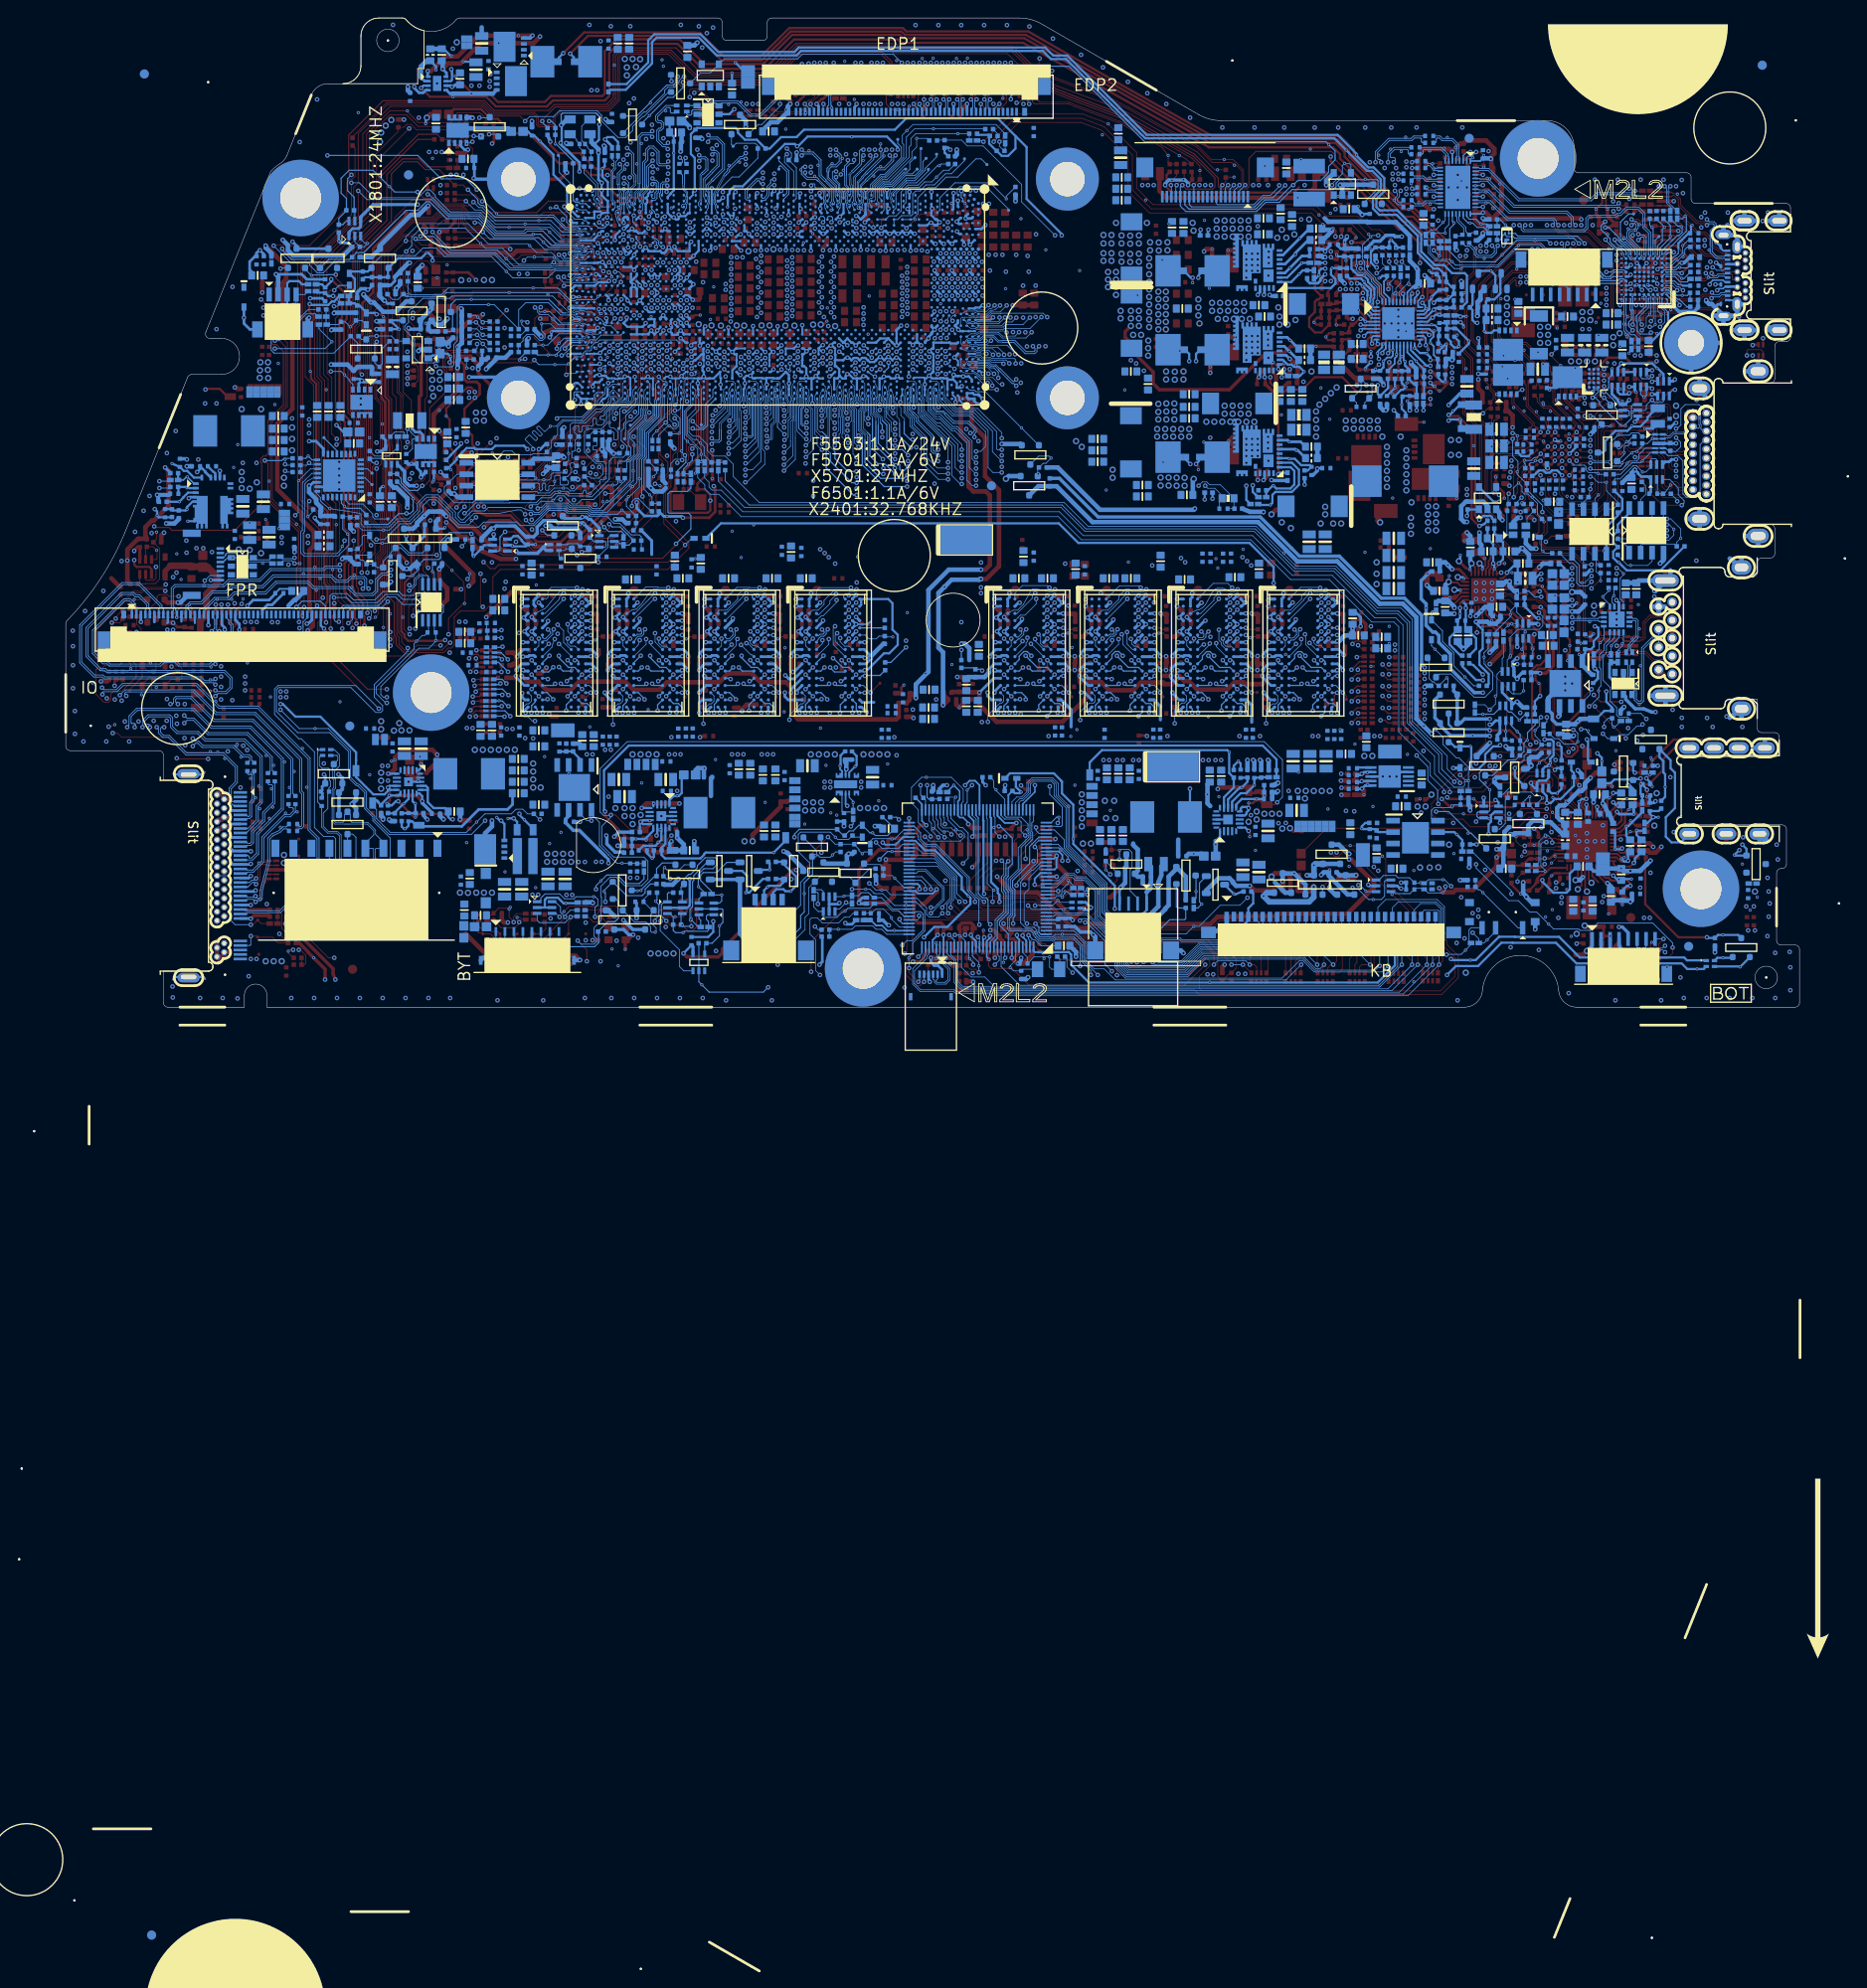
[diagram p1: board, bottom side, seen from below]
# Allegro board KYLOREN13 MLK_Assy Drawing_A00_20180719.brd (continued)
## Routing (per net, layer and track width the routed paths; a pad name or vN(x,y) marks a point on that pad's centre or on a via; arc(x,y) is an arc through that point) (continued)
USB1_CC2: length 32.6
  TOP w0.203: ED7304.1 21.92,89.35 v1(22.61,88.66)
  TOP w0.381: v2(21.59,87.27) 21.65,87.2 21.83,87.2 22.07,86.96 R7212.2 C7218.1 22.58,88.08 22.58,88.64 v1(22.61,88.66)
  L4SGND w0.089: 7.11,83.33 6.95,83.33 6.5,82.88 6.35,82.57 USB1.B5
  L4SGND w0.381: v2(21.59,87.27) 20.95,87.27 18.35,84.66 15.13,84.66 14.82,84.98 12.19,84.98 10.54,83.33 v2(9.91,82.82) 9.91,82.89 9.47,83.33 7.11,83.33
  L6 w0.089: 7.37,83.33 6.95,83.33 6.5,82.87 6.4,82.63 USB1.B5
  L6 w0.305: 7.37,83.33 9.53,83.33 9.91,82.95 v2(9.91,82.82)
  BOTTOM w0.127: v2(21.59,87.27) 21.59,87.25 21.77,87.08 21.77,87.08 22.03,86.82 22.03,86.38 21.04,85.39 21.04,85.02 20.38,84.36 19.7,84.36 19.27,83.93 U7201.L10
USB1_SBU1: length 38.3
  L4SGND w0.127: v2(9.65,82.2) 9.54,82.2 8.7,81.36 8.7,79.14 9.25,78.6 9.25,78.02 9.59,77.68 10.18,77.68 12.31,79.81 12.31,82.94 12.79,83.43 19.2,83.43 20.44,84.66 23.69,84.66 v2(23.88,84.85)
  BOTTOM w0.102: v2(9.65,82.2) 9.54,82.2 9.21,81.87 8.47,81.87 8.29,82.05 USB1.A8
  BOTTOM w0.127: R7153.2 R7330.1 33.29,87.52 v1(32.68,86.91) 32.31,86.54 ED7305.2 31.59,85.97 31.29,85.67 24.69,85.67 v2(23.88,84.85)
USB1_SBU1_R: length 3.3
  BOTTOM w0.127: R7153.1 34.72,87.01 v1(35.38,87.01) 35.43,87.01 35.97,87.55 36.68,87.55 36.97,87.84 U7101.27
USB1_SBU2: length 37
  TOP w0.127: v2(24.51,84.85) 24.83,84.54 24.83,84.54 25.1,84.27 v1(25.43,84.27)
  L4SGND w0.089: 6.53,79.67 6.45,79.82 6.36,79.99 6.31,80.07 USB1.B8
  L4SGND w0.102: 6.53,79.67 arc(6.59,79.59) 6.65,79.52
  L4SGND w0.127: v2(24.51,84.85) 24.09,84.43 20.54,84.43 19.3,83.2 12.93,83.2 12.54,82.8 12.54,79.71 10.27,77.45 9.49,77.45 9.02,77.93 9.02,78.5 8.26,79.27 6.9,79.27 6.65,79.52
  BOTTOM w0.127: v2(24.51,84.85) 25.1,85.44 31.63,85.44 31.81,85.62 32.51,85.62 32.72,85.82 ED7305.1 33.15,85.53 33.15,85.36 33.27,85.24 R7331.1 R7151.2
USB1_SBU2_R: length 4.1
  BOTTOM w0.127: U7101.26 37.37,87.68 36.8,87.11 v1(36.6,87.11) 36.3,87.11 35.81,86.63 35.1,86.63 R7151.1
USB1_SSRX_CON_N1: length 13.2
  TOP w0.102: R7120.2 17.39,77.02 16.98,77.02 16.71,77.29 ED7301.7 ED7301.4 15.32,77.29 15.19,77.16 14.73,77.16 14.55,77.34 14.3,77.34 ; 14.3,77.34 v1(14.3,77.49) ; 14.3,77.34 13.12,77.34 12.77,77.69 9.39,77.69 9.25,77.84 9.25,78.22 8.16,79.31 6.31,79.31 USB1.B10
USB1_SSRX_CON_N2: length 14.7
  TOP w0.102: R7123.2 16.47,90.05 ED7302.9 ED7302.2 14.21,90.05 14.08,90.19 13.93,90.19 13.46,89.72 13.46,89.07 11.46,87.06 10.46,87.06 v2(10.29,86.89)
  BOTTOM w0.102: v2(10.29,86.89) 10.13,87.04 9.6,87.04 9.5,86.94 9.5,86.71 9.93,86.28 9.93,84.12 ; 9.93,84.12 v1(10.06,84.12) ; 9.93,84.12 9.93,83.85 9.28,83.19 8.35,83.19 8.2,83.05 USB1.A10
USB1_SSRX_CON_P1: length 13
  TOP w0.102: R7119.2 17.28,76.79 ED7301.6 ED7301.5 15.35,76.79 15.22,76.93 14.63,76.93 14.45,77.11 13.03,77.11 12.67,77.46 9.3,77.46 9.02,77.74 9.02,78.12 8.06,79.08 6.29,79.08 USB1.B11
USB1_SSRX_CON_P2: length 14.8
  TOP w0.102: 13.66,90.24 13.84,90.42 14.08,90.42 14.21,90.55 ED7302.1 ED7302.10 16.44,90.55 R7122.2 ; 13.66,90.24 v1(13.56,90.34) ; 13.66,90.24 13.23,89.81 13.23,89.17 11.36,87.29 10.52,87.29 v2(10.29,87.52)
  BOTTOM w0.102: USB1.A11 8.21,83.55 8.34,83.42 9.18,83.42 9.7,83.94 9.7,86.18 9.27,86.61 9.27,87.03 9.51,87.27 10.03,87.27 v2(10.29,87.52)
USB1_SSRX_MUX_N1: length 26.6
  TOP w0.102: 19.63,76.97 v1(19.63,77.11) ; 19.63,76.97 20.05,76.97 20.7,77.62 20.7,82.64 23.68,85.62 25.4,85.62 26.04,86.25 26.7,86.25 26.92,86.48 26.92,86.76 v2(26.8,86.89) ; 19.63,76.97 18.73,76.97 R7120.1
  BOTTOM w0.102: v2(26.8,86.89) 27,87.09 27,87.34 27.3,87.64 32.37,87.64 34.33,89.6 35.69,89.6 35.76,89.68 U7101.31
USB1_SSRX_MUX_N2: length 20.7
  TOP w0.102: R7123.1 17.7,90.19 18.16,90.19 v2(18.29,90.06)
  BOTTOM w0.102: 33.19,91.56 34.59,92.96 35.59,92.96 35.67,92.88 U7101.39 ; 33.19,91.56 v1(33.3,91.46) ; 33.19,91.56 31.22,89.59 23.13,89.59 22.46,90.26 18.49,90.26 v2(18.29,90.06)
USB1_SSRX_MUX_P1: length 26.7
  TOP w0.102: v2(27.43,86.89) 27.15,86.61 27.15,86.38 26.79,86.02 26.13,86.02 25.49,85.39 23.77,85.39 20.93,82.54 20.93,77.52 20.15,76.74 18.73,76.74 R7119.1
  BOTTOM w0.102: 33.95,88.9 v1(34.06,88.79) ; 33.95,88.9 32.46,87.41 27.4,87.41 27.23,87.24 27.23,87.09 v2(27.43,86.89) ; 33.95,88.9 34.43,89.38 35.69,89.38 35.79,89.28 U7101.30
USB1_SSRX_MUX_P2: length 20.6
  TOP w0.102: R7122.1 17.5,90.64 18.23,90.64 v2(18.29,90.7)
  BOTTOM w0.102: U7101.40 35.65,93.28 35.56,93.19 35.08,93.19 ; v2(18.29,90.7) 18.49,90.49 22.56,90.49 23.23,89.82 31.13,89.82 34.49,93.19 35.08,93.19 ; 35.08,93.19 v1(35.08,93.34)
USB1_SSTX_CMC_N1: length 1.2
  TOP w0.102: R7117.1 19.7,80.8 19.7,81.21 C7163.1
USB1_SSTX_CMC_N2: length 0.9
  TOP w0.102: R7125.1 17.5,88.47 18.28,88.47 C7162.1
USB1_SSTX_CMC_P1: length 1.2
  TOP w0.102: R7115.1 19.93,80.75 19.93,81.21 C7164.1
USB1_SSTX_CMC_P2: length 0.9
  TOP w0.102: C7161.1 18.28,89.12 17.5,89.12 R7124.1
USB1_SSTX_CON_N1: length 13.3
  TOP w0.102: R7117.2 19.63,79.42 19.63,78.95 19.36,78.68 17.4,78.68 ; 17.4,78.68 16.76,78.68 16.65,78.79 ED7301.10 ED7301.1 15.11,78.79 15,78.68 11.31,78.68 10.78,79.22 9.91,79.22 v2(9.73,79.39) ; 17.4,78.68 v1(17.4,78.81)
  BOTTOM w0.102: v2(9.73,79.39) 9.47,79.14 8.99,79.14 8.74,79.39 8.36,79.39 8.2,79.55 USB1.A3
USB1_SSTX_CON_N2: length 13.2
  TOP w0.102: R7125.2 16.44,88.55 ED7302.6 ED7302.5 14.44,88.55 14.28,88.71 14.14,88.71 11.3,85.87 10.54,85.87 9.93,85.26 9.93,84.68 9.6,84.35 7.66,83.24 6.26,83.24 USB1.B3
USB1_SSTX_CON_P1: length 13.8
  TOP w0.102: 19.62,78.62 19.86,78.86 19.86,79.34 R7115.2 ; 19.62,78.62 19.46,78.45 16.87,78.45 16.71,78.29 ED7301.9 ED7301.2 15.07,78.29 14.91,78.45 11.21,78.45 10.68,78.99 10.01,78.99 v2(9.78,78.76) ; 19.62,78.62 v1(19.72,78.52)
  BOTTOM w0.102: v2(9.78,78.76) 9.63,78.91 8.9,78.91 8.64,79.16 8.33,79.16 8.22,79.05 USB1.A2
USB1_SSTX_CON_P2: length 13.3
  TOP w0.102: USB1.B2 6.35,83.47 7.6,83.47 9.46,84.54 9.7,84.78 9.7,85.36 10.45,86.1 11.21,86.1 14.04,88.94 14.37,88.94 14.49,89.05 ED7302.4 ED7302.7 16.47,89.05 R7124.2
USB1_SSTX_MUX_N1: length 22
  TOP w0.102: C7163.2 19.66,82.62 19.66,83.93 19.89,84.16 ; 19.89,84.16 20.4,84.68 21.72,84.68 23.38,86.34 24.98,86.34 25.1,86.45 25.1,86.68 v2(24.89,86.89) ; 19.89,84.16 v1(19.79,84.27)
  BOTTOM w0.102: U7101.34 35.66,90.88 35.58,90.8 34.52,90.8 32.15,88.42 25.8,88.42 25.15,87.78 25.15,87.14 v2(24.89,86.89)
USB1_SSTX_MUX_N2: length 18.4
  TOP w0.102: v2(20.08,88.69) 19.54,88.69 C7162.2
  BOTTOM w0.102: v2(20.08,88.69) 20.26,88.87 31.78,88.87 33.15,90.24 ; 33.15,90.24 34.68,91.77 35.47,91.77 35.57,91.68 U7101.36 ; 33.15,90.24 v1(33.25,90.14)
USB1_SSTX_MUX_P1: length 21.6
  TOP w0.102: 21.18,84.45 20.5,84.45 19.89,83.84 19.89,82.7 C7164.2 ; 21.18,84.45 21.82,84.45 23.48,86.11 25.07,86.11 25.32,86.36 25.32,86.68 v2(25.53,86.89) ; 21.18,84.45 v1(21.18,84.3)
  BOTTOM w0.102: v2(25.53,86.89) 25.37,87.04 25.37,87.68 25.89,88.2 32.24,88.2 34.62,90.57 35.59,90.57 35.68,90.48 U7101.33
USB1_SSTX_MUX_P2: length 18.4
  TOP w0.102: v2(20.09,89.33) 20.09,89.32 19.81,89.05 19.38,89.05 C7161.2
  BOTTOM w0.102: 34.51,91.92 34.59,92 35.48,92 35.56,92.08 U7101.37 ; 34.51,91.92 31.68,89.1 20.32,89.1 v2(20.09,89.33) ; 34.51,91.92 v1(34.4,92.03)
USB1_USB20_CON_N: length 4.8
  TOP w0.102: EL6601.1 173.7,42.47 174.07,42.1 174.07,41.65 v2(173.76,41.34) v1(173.64,40.78)
  BOTTOM w0.102: v2(173.76,41.34) 174.07,41.65 174.07,42.52 174.3,42.75 IOBD1.23
USB1_USB20_CON_P: length 4.2
  TOP w0.102: EL6601.4 174.3,42.68 174.3,41.65 v2(174.61,41.34)
  BOTTOM w0.102: IOBD1.22 174.8,43.26 174.53,42.99 174.53,42.65 174.3,42.42 174.3,41.65 v2(174.61,41.34)
USB1_USB20_N: length 85.1
  TOP w0.102: v1(172.95,45.36) v2(173.1,44.8) 173.7,44.21 EL6601.2
  L6 w0.089: v2(130.61,92.14) 129.97,91.51 129.97,90.71 130.48,90.2 131.64,90.2 132.31,89.54 138.09,89.54 138.55,89.08 138.55,89.08 140.53,87.09 144.27,87.09 144.81,86.55 154.05,86.55 157.45,83.15 157.45,82.9 160.72,79.63 160.72,72.61 160.99,72.35 160.99,54.29 164.71,50.57 164.71,49.7 166.61,47.8 168.21,47.8 170.48,45.52 173.1,45.52 173.31,45.31 173.31,45.01 v2(173.1,44.8)
  BOTTOM w0.076: CPU1.CE3 130.13,89.21 130.24,89.47 130.24,89.66 130.21,89.75 130.21,90.03 130.24,90.12 130.24,90.42 130.05,90.61 130.05,91.59 v2(130.61,92.14)
USB1_USB20_P: length 85.1
  TOP w0.102: v1(174.22,45.33) v2(173.88,44.86) 173.86,44.85 173.86,44.59 174.38,44.07 EL6601.3
  L6 w0.089: v2(130.63,91.51) 130.51,91.64 130.37,91.64 130.16,91.43 130.16,90.79 130.56,90.39 131.72,90.39 132.38,89.73 138.17,89.73 138.74,89.16 138.74,89.16 140.61,87.28 144.35,87.28 144.89,86.74 154.13,86.74 157.64,83.23 157.64,82.98 160.92,79.71 160.92,72.69 161.18,72.43 161.18,54.37 164.9,50.65 164.9,49.78 166.69,47.99 168.29,47.99 170.56,45.71 173.18,45.71 173.5,45.39 173.5,45.01 173.64,44.86 v2(173.88,44.86)
  BOTTOM w0.076: v2(130.63,91.51) 130.61,91.53 130.36,91.53 130.22,91.39 130.22,90.67 130.41,90.49 130.41,90.09 130.37,90 130.37,89.78 130.41,89.69 130.41,89.43 130.28,89.14 130.27,89.11 130.26,89.09 130.26,88.82 CPU1.CE4
USB1_USB30_RX_N: length 92.8
  L6 w0.089: v2(127.88,87.2) 127.68,87 127.47,87 127.11,86.64 127.11,85.85 127.46,85.5 128.68,85.5 129.33,86.16 129.33,86.65 130.22,87.54 130.92,87.54 132.14,86.31 134.8,86.31 135.16,85.95 138.08,85.95 139.6,84.43 142.15,84.43 143.06,83.53 149.61,83.53 151.33,81.81 152.81,81.81 157.42,77.2 157.42,51.15 158.94,49.64 160.11,49.64 160.99,48.76 161.95,48.76 v2(162.18,48.53)
  BOTTOM w0.102: v1(162.99,48.61) 162.99,48.76 ; 162.99,48.76 162.41,48.76 v2(162.18,48.53) ; 162.99,48.76 163.7,48.76 163.96,48.51 169.85,48.51 171.04,47.31 174.46,47.31 175.06,46.72 175.17,46.72 175.17,46.71 176.84,46.71 176.84,46.72 180.45,46.72 180.7,46.47 180.7,44.57 180.44,44.31 180.44,44.11 180.3,43.97 IOBD1.11 ; v2(127.88,87.2) 127.9,87.19 CPU1.CB5
USB1_USB30_RX_P: length 92.8
  L6 w0.089: v2(127.89,86.52) 127.89,86.67 127.75,86.81 127.55,86.81 127.3,86.56 127.3,85.93 127.54,85.69 128.6,85.69 129.14,86.23 129.14,86.73 130.14,87.73 131,87.73 132.22,86.51 134.87,86.51 135.23,86.14 138.16,86.14 139.68,84.62 142.23,84.62 143.14,83.72 149.69,83.72 151.41,82 152.89,82 157.61,77.27 157.61,51.23 159.02,49.83 160.19,49.83 161.06,48.95 161.96,48.95 v2(162.18,49.17)
  BOTTOM w0.102: 164.97,48.74 164.05,48.74 163.8,48.99 162.36,48.99 v2(162.18,49.17) ; 164.97,48.74 v1(164.97,48.89) ; 164.97,48.74 169.94,48.74 171.14,47.54 174.56,47.54 175.15,46.94 175.26,46.94 175.26,46.94 176.74,46.94 176.74,46.94 180.55,46.94 180.93,46.57 180.93,44.47 180.67,44.21 180.67,44.09 180.8,43.96 IOBD1.10 ; CPU1.CB6 128.15,86.88 127.9,86.66 v2(127.89,86.52)
USB1_USB30_TX_N: length 122.2
  TOP w0.102: v1(127.66,88.38) v2(127.84,87.85)
  L6 w0.089: v2(127.84,87.85) 127.63,88.05 127.63,88.17 127.82,88.35 133.55,88.35 135.19,86.7 138.08,86.7 139.67,85.11 143.26,85.11 144.18,84.19 150,84.19 150.76,83.43 152.83,83.43 154.18,82.08 154.32,82.08 158.54,77.86 158.54,71.83 158.47,71.75 158.47,64.48 158.54,64.41 158.54,52.12 160.25,50.41 162.07,50.41 162.73,49.75 162.73,48.88 165.79,45.81 167.39,45.81 170.15,43.05 170.15,41.77 174.68,37.24 174.68,36.39 174.98,36.1 175.78,36.1 176.02,35.86 v2(176.02,35.83)
  BOTTOM w0.102: IOBD1.8 181.8,44.28 181.95,44.43 181.95,44.65 184.46,47.16 186.41,47.16 186.55,47.03 191.11,42.46 191.11,38.25 189.53,36.67 188.59,36.67 188.39,36.47 177.72,36.47 177.3,36.05 176.24,36.05 v2(176.02,35.83) ; v2(127.84,87.85) 127.54,88.15 CPU1.CA4
USB1_USB30_TX_P: length 122.1
  TOP w0.102: v1(176.58,36.37) v2(176.02,36.47)
  L6 w0.089: v2(126.92,87.94) 127.13,87.94 127.74,88.54 133.63,88.54 135.27,86.89 138.16,86.89 139.75,85.3 143.33,85.3 144.26,84.38 150.08,84.38 150.84,83.62 152.91,83.62 154.26,82.27 154.4,82.27 158.73,77.93 158.73,71.75 158.66,71.67 158.66,64.56 158.73,64.49 158.73,52.2 160.33,50.6 162.15,50.6 162.92,49.83 162.92,48.96 165.87,46 167.46,46 170.34,43.13 170.34,41.85 174.87,37.32 174.87,36.47 175.06,36.29 175.84,36.29 v2(176.02,36.47)
  BOTTOM w0.102: CPU1.CA3 127.54,88.68 127.25,88.39 127.25,88.26 v2(126.92,87.94) ; IOBD1.7 182.3,44.29 182.18,44.41 182.18,44.55 184.56,46.93 186.32,46.93 186.39,46.86 190.88,42.37 190.88,38.35 189.43,36.9 188.5,36.9 188.3,36.7 177.63,36.7 177.21,36.28 176.21,36.28 v2(176.02,36.47)
USB2_ID: length 2.4
  TOP w0.102: R1601.1 129.34,85.74 v1(130.05,85.74) 130.05,85.58 v2(129.71,85.24)
  BOTTOM w0.102: CPU1.CE8 130.04,85.57 v2(129.71,85.24)
USB2_USB20_N: length 170.1
  L4SGND w0.089: v2(25.27,43.33) 25.09,43.15 24.83,43.15 24.59,43.38 24.59,56.6 25.6,57.6 28.24,57.6 30.29,59.65 30.29,66.19 32.06,67.96 32.06,67.98 32.11,68.02 32.11,70.72 31.71,71.12 31.71,78.78 32.73,79.8 32.73,82.06 32.21,82.58 32.21,85.81 34.67,88.26 34.67,93.64 35.28,94.25 39.06,94.25 39.99,95.19 71.64,95.19 77.84,101.39 84.71,101.39 85.34,102.02 122.99,102.02 123.54,101.47 123.91,101.47 126.81,98.57 126.81,96.46 128.2,95.06 129.91,95.06 v2(130.27,94.7)
  BOTTOM w0.076: CPU1.CE1 129.98,90.45 129.89,90.54 129.89,91.03 129.49,91.42 129.49,91.69 129.51,91.71
  BOTTOM w0.102: v2(25.27,43.33) 25.13,43.19 24.51,43.19 ; 24.51,43.19 22.36,43.19 22.22,43.32 U3401.2 ; 24.51,43.19 v1(24.51,43.33) ; v2(130.27,94.7) 130.09,94.89 129.94,94.89 129.77,94.71 129.77,92.58 129.51,92.33 129.51,91.71
USB2_USB20_P: length 171.9
  L4SGND w0.089: v2(25.27,42.69) 25.01,42.96 24.75,42.96 24.4,43.3 24.4,56.68 25.52,57.79 28.17,57.79 30.1,59.73 30.1,66.27 31.87,68.04 31.87,68.06 31.92,68.1 31.92,70.64 31.52,71.04 31.52,78.86 32.54,79.88 32.54,81.98 32.02,82.5 32.02,85.88 34.48,88.34 34.48,93.72 35.2,94.44 38.98,94.44 39.92,95.38 71.56,95.38 77.76,101.58 84.63,101.58 85.27,102.21 123.07,102.21 123.62,101.67 123.99,101.67 127,98.65 127,96.54 128.28,95.26 130.08,95.26 v2(130.27,95.45)
  BOTTOM w0.076: 129.29,91.72 129.29,91.71 129.31,91.69 129.31,91.34 129.71,90.96 129.71,90.04 129.98,89.78 CPU1.CE2
  BOTTOM w0.102: v2(25.27,42.69) 25.01,42.96 23.32,42.96 ; v1(23.32,42.82) 23.32,42.96 ; 23.32,42.96 22.36,42.96 22.22,42.82 U3401.3 ; v2(130.27,95.45) 130.09,95.27 130,95.27 129.54,94.8 129.54,92.68 129.29,92.42 129.29,91.72
USB2_USB30_RX_CON_N: length 9.9
  TOP w0.102: R3503.2 22.1,38.75 21.69,39.16 21.21,39.16 ; v1(21.21,39.03) 21.21,39.16 ; 21.21,39.16 19.12,39.16 ED3501.1 ED3501.10 18.02,39.15 17.88,39.29 17.17,39.29 16.28,38.4 15.26,38.4 14.75,37.89 14.25,37.89 14.15,37.78 USB2.5
USB2_USB30_RX_CON_P: length 9.9
  TOP w0.102: 20.07,39.39 19.66,39.39 19.4,39.65 ED3501.2 ED3501.9 17.97,39.65 17.83,39.51 17.07,39.51 16.19,38.63 15.16,38.63 14.65,38.11 14.25,38.11 14.15,38.22 USB2.6 ; 20.07,39.39 v1(20.07,39.52) ; 20.07,39.39 22.17,39.39 R3504.2
USB2_USB30_RX_N: length 165
  TOP w0.102: v1(24.49,39.18) 24.39,39.28 ; 24.39,39.28 24.66,39.54 24.66,48.91 25.2,49.45 31.83,49.45 34.81,52.43 34.81,54.24 35.56,54.99 35.56,64.15 37.41,66.01 37.41,71.85 39.12,73.55 39.12,77.49 38.46,78.15 38.46,81.01 37.72,81.75 v2(37.72,83.46) ; 24.39,39.28 24.14,39.02 23.43,39.02 R3503.1
  L4SGND w0.089: v2(126.29,84.44) 126.57,84.75 126.57,85.09 126.47,85.19 124.99,85.19 124.26,85.92 124.26,87.4 123.23,88.43 123.23,91.05 123.12,91.15 122.35,91.15 121.46,90.26 120.62,90.26 118.21,92.68 118.21,95.58 117.44,96.35 116.27,96.35 114.72,97.9 79.34,97.9 73.62,92.19 53.75,92.19 53.4,91.84 47.8,91.84 42.2,86.23 38.6,86.23 37.67,85.3 37.67,83.5 v2(37.72,83.46)
  BOTTOM w0.102: CPU1.BY8 127.2,85.36 127.01,85.36 126.77,85.12 126.77,85.04 126.78,85.04 126.78,84.8 126.77,84.77 126.64,84.64 126.64,84.64 126.45,84.44 v2(126.29,84.44)
USB2_USB30_RX_P: length 165
  TOP w0.102: v1(24.28,40.43) 24.43,40.43 ; 24.43,40.43 24.43,39.64 24.04,39.25 23.43,39.25 R3504.1 ; 24.43,40.43 24.43,49.01 25.1,49.68 31.74,49.68 34.58,52.52 34.58,54.34 35.33,55.09 35.33,64.25 37.19,66.1 37.19,71.94 38.89,73.65 38.89,77.39 38.23,78.05 38.23,80.92 37.49,81.65 37.49,82.97 37.39,83.08 37.19,83.08 37.08,83.18 v2(37.08,83.46)
  L4SGND w0.089: v2(127.05,84.47) 126.76,84.73 126.76,84.76 126.76,85.17 126.55,85.38 125.07,85.38 124.45,86 124.45,87.48 123.42,88.51 123.42,91.13 123.2,91.34 122.27,91.34 121.38,90.45 120.7,90.45 118.4,92.76 118.4,95.66 117.52,96.54 116.35,96.54 114.8,98.09 79.26,98.09 73.54,92.38 53.67,92.38 53.32,92.03 47.72,92.03 42.12,86.42 38.52,86.42 37.48,85.38 37.48,83.86 v2(37.08,83.46)
  BOTTOM w0.102: v2(127.05,84.47) 127,84.52 127,84.7 127,85.03 127.11,85.13 127.2,85.13 CPU1.BY9
USB2_USB30_TX_CMC_N: length 1.1
  TOP w0.102: C3501.2 22.02,41.04 21.87,41.04 21.62,40.79 R3501.1
USB2_USB30_TX_CMC_P: length 1.1
  TOP w0.102: C3502.2 22,41.27 21.87,41.27 21.59,41.55 R3502.1
USB2_USB30_TX_CON_N: length 9.7
  TOP w0.102: USB2.8 14.15,43.73 14.25,43.83 14.73,43.83 15.24,43.33 16.51,43.33 17.14,42.69 17.14,41.03 17.39,40.79 17.63,40.79 17.77,40.65 ED3501.7 ED3501.4 19.39,40.65 19.78,41.04 20.27,41.04 R3501.2
USB2_USB30_TX_CON_P: length 9.7
  TOP w0.102: USB2.9 14.15,44.17 14.25,44.06 14.82,44.06 15.33,43.55 16.6,43.55 17.37,42.78 17.37,41.13 17.49,41.01 17.63,41.01 17.77,41.15 ED3501.6 ED3501.5 19.47,41.15 19.59,41.27 20.24,41.27 R3502.2
USB2_USB30_TX_N: length 176.1
  TOP w0.102: 37.13,79.37 37.13,78.57 38.4,77.3 38.4,73.86 36.53,71.98 36.53,66.08 34.93,64.48 34.93,55.26 34.01,54.35 34.01,52.66 31.56,50.21 25.06,50.21 24.03,49.17 24.03,41.29 23.79,41.05 23.46,41.05 C3501.1 ; 37.13,79.37 v1(37.26,79.37) ; 37.13,79.37 37.13,80.81 36.22,81.72 36.22,84.27 35.98,84.5 35.53,84.5 v2(35.43,84.6)
  L4SGND w0.089: v2(35.43,84.6) 35.76,84.6 39.26,88.09 42.96,88.09 47.58,92.72 53.15,92.72 53.4,92.96 73.14,92.96 78.88,98.7 115.5,98.7 116.94,97.26 117.92,97.26 119.13,96.06 119.13,93.7 120.93,91.9 123.33,91.9 124.07,91.16 124.07,89.6 125.34,88.34 125.34,88.34 125.69,87.99 125.69,87.5 125.62,87.43 125.62,86.23 125.81,86.04 128.34,86.04 130.06,87.75 130.06,88.43 129.38,89.11 127.61,89.11 126.81,89.91 126.81,91.6 127.06,91.85 127.23,91.85 v2(127.46,92.08)
  BOTTOM w0.102: CPU1.CA2 127.46,89.64 127.17,89.64 126.95,89.86 126.95,90.37 126.8,90.52 126.8,91.17 126.8,91.63 127.03,91.87 127.25,91.87 v2(127.46,92.08)
USB2_USB30_TX_P: length 176.1
  TOP w0.102: 38.18,74.67 38.18,77.21 36.91,78.48 36.91,80.71 35.99,81.63 35.99,84.17 35.89,84.28 35.74,84.28 v2(35.43,83.97) ; 38.18,74.67 38.18,73.96 36.3,72.08 36.3,66.18 34.7,64.58 34.7,55.36 33.78,54.44 33.78,52.75 31.47,50.44 24.97,50.44 23.8,49.27 23.8,41.38 23.7,41.28 23.46,41.28 C3502.1 ; 38.18,74.67 v1(38.05,74.67)
  L4SGND w0.089: v2(127.46,91.44) 127.23,91.66 127.14,91.66 127,91.52 127,89.98 127.69,89.3 129.46,89.3 130.25,88.51 130.25,87.67 128.42,85.84 125.73,85.84 125.43,86.15 125.43,87.51 125.5,87.58 125.5,87.91 125.26,88.14 125.26,88.14 123.88,89.52 123.88,91.08 123.25,91.71 120.85,91.71 118.94,93.63 118.94,95.98 117.84,97.07 116.87,97.07 115.42,98.51 78.96,98.51 73.22,92.77 53.48,92.77 53.23,92.52 47.66,92.52 43.04,87.9 39.33,87.9 35.89,84.46 35.89,83.67 35.75,83.53 35.57,83.53 35.43,83.67 v2(35.43,83.97)
  BOTTOM w0.102: CPU1.CA1 127.54,89.96 127.44,89.87 127.26,89.87 127.18,89.95 127.18,90.46 127.03,90.62 127.03,91.26 127.02,91.26 127.02,91.54 127.13,91.64 127.26,91.64 v2(127.46,91.44)
USB2_VBUSSENSE: length 5.4
  TOP w0.102: R1602.1 131.9,89.43 129.92,89.43 v1(129.77,89.27) 129.53,89.04 v2(129.53,87.95)
  BOTTOM w0.102: CPU1.CC6 129.63,87.24 129.63,87.85 v2(129.53,87.95)
USB4_USB20_CMC_N1: length 3.5
  TOP w0.102: v2(17.91,85.24) 17.91,85.16 17.77,85.02 EL7201.1
  BOTTOM w0.102: U7201.L6 17.27,85.43 17.41,85.57 17.58,85.57 17.68,85.46 17.68,85.34 17.78,85.24 v2(17.91,85.24)
USB4_USB20_CMC_N2: length 7.3
  TOP w0.102: v2(18.67,86.89) 18.41,86.89 18.31,86.99 18.31,87.19 18.21,87.29 18.03,87.29 17.77,87.03 17.6,87.03 17.36,86.8 EL7202.1
  BOTTOM w0.102: 18.94,86.37 19.18,86.12 19.18,85.5 17.77,84.09 U7201.L7 ; 18.94,86.37 v1(19.05,86.47) ; 18.94,86.37 18.89,86.41 18.39,86.41 18.16,86.63 18.16,86.94 18.31,87.09 18.47,87.09 v2(18.67,86.89)
USB4_USB20_CMC_P1: length 4.7
  TOP w0.102: v1(18.22,86.34) v2(17.91,85.87) EL7201.4
  BOTTOM w0.102: U7201.K6 17.04,83.51 17.04,85.52 17.31,85.79 17.83,85.79 v2(17.91,85.87)
USB4_USB20_CMC_P2: length 8
  TOP w0.102: EL7202.4 17.36,87.48 17.58,87.26 17.68,87.26 17.94,87.52 v2(18.67,87.52)
  BOTTOM w0.102: 17.93,86.94 17.93,87.03 18.22,87.32 18.47,87.32 v2(18.67,87.52) ; 17.93,86.94 17.93,86.54 18.29,86.18 18.8,86.18 18.95,86.03 18.95,85.59 17.54,84.19 17.54,83.51 U7201.K7 ; 17.93,86.94 v1(17.78,86.94)
USB4_USB20_CON_N1: length 12.9
  TOP w0.102: v2(9.78,81.55) 9.6,81.55 9.5,81.45 9.5,81.17 9.6,81.07 10.08,81.07 10.46,80.69 10.94,80.69 11.18,80.92 11.18,83.06 13.51,85.4 13.81,85.4 13.95,85.25 ED7303.10 ED7303.1 15.58,85.25 15.81,85.02 EL7201.2
  BOTTOM w0.102: v2(9.78,81.55) 9.78,81.37 9.68,81.27 9.24,81.27 9.06,81.45 8.31,81.45 8.21,81.55 USB1.A7
USB4_USB20_CON_N2: length 13
  TOP w0.102: USB1.B7 7.02,80.79 7.37,80.79 7.47,80.89 7.47,81.37 7.57,81.47 8.35,81.47 8.64,81.76 8.64,82.77 8.96,83.07 9.77,83.43 10.52,83.43 12.24,85.16 12.24,85.78 13.35,86.89 13.69,86.89 13.83,86.75 ED7303.7 ED7303.4 16.03,86.75 EL7202.2
USB4_USB20_CON_P1: length 12.4
  TOP w0.102: v2(10.41,81.55) 10.41,81.06 10.56,80.92 10.85,80.92 10.95,81.02 10.95,83.15 13.42,85.62 13.83,85.62 13.95,85.75 ED7303.9 ED7303.2 15.72,85.75 EL7201.3
  BOTTOM w0.102: 10.03,81.17 9.91,81.04 9.14,81.04 8.97,81.22 8.38,81.22 8.21,81.05 USB1.A6 ; 10.03,81.17 v2(10.41,81.55) ; 10.03,81.17 v1(10.15,81.06)
USB4_USB20_CON_P2: length 12.4
  TOP w0.102: USB1.B6 8.26,81.7 8.41,81.85 8.41,82.87 8.83,83.26 9.72,83.66 10.42,83.66 12.01,85.25 12.01,85.88 13.25,87.11 13.69,87.11 13.83,87.25 ED7303.6 ED7303.5 15.68,87.25 EL7202.3
USB4_USB20_N: length 142.1
  L4SGND w0.089: v2(30.48,86.89) 30.48,88.84 33.36,91.72 33.36,95.05 34.36,96.04 71.29,96.04 77.49,102.24 84.36,102.24 84.99,102.87 123.35,102.87 123.89,102.33 124.26,102.33 128.27,98.32 128.27,97.28 127.91,96.92 127.7,96.92 v2(127.48,96.7)
  BOTTOM w0.076: 128.83,91.51 128.83,91.5 128.85,91.47 128.85,90.87 129.29,90.44 129.29,89.54 129.42,89.41 CPU1.CD3
  BOTTOM w0.102: 128.83,95.95 v1(128.68,95.95) ; 128.83,95.95 128.83,96.65 128.57,96.91 127.69,96.91 v2(127.48,96.7) ; 128.83,95.95 128.83,91.51 ; v2(30.48,86.89) 30.69,86.67 30.69,86.49 30.59,86.39 23.99,86.39 23.75,86.63 23.75,87.65 23.42,87.98 20.47,87.98 20.27,88.18 19.96,88.18 19.25,88.89 17.86,88.89 17.17,88.2 17.17,86.7 16.54,86.07 16.54,83.51 U7201.K5
USB4_USB20_P: length 142.1
  L4SGND w0.089: v2(127.48,97.33) 127.7,97.11 127.83,97.11 128.08,97.36 128.08,98.24 124.18,102.14 123.81,102.14 123.27,102.68 85.07,102.68 84.44,102.05 77.57,102.05 71.37,95.85 34.43,95.85 33.55,94.97 33.55,91.64 30.67,88.76 30.67,87.33 30.76,87.24 31.04,87.24 31.11,87.17 v2(31.11,86.89)
  BOTTOM w0.076: 129.06,91.51 129.03,91.48 129.03,90.95 129.46,90.52 129.46,89.61 129.68,89.4 129.68,89.09 129.42,88.82 CPU1.CD4
  BOTTOM w0.102: 129.06,93.69 129.06,96.74 128.66,97.14 127.68,97.14 v2(127.48,97.33) ; 129.06,93.69 129.06,91.51 ; 129.06,93.69 v1(129.21,93.69) ; U7201.L5 16.77,85.98 17.4,86.61 17.4,88.11 17.96,88.66 19.16,88.66 19.87,87.96 20.17,87.96 20.38,87.75 23.32,87.75 23.52,87.55 23.52,86.54 23.9,86.16 30.69,86.16 30.92,86.4 30.92,86.69 v2(31.11,86.89)
USB4_USB30_RX_C_N: length 5.2
  BOTTOM w0.102: C7106.2 39.93,96.79 39.65,96.51 39.14,96.51 ; 39.14,96.51 38.54,96.51 37.87,95.85 37.87,94.53 37.77,94.43 U7101.4 ; 39.14,96.51 v1(39.14,96.64)
USB4_USB30_RX_C_P: length 5.2
  BOTTOM w0.102: 38.1,95.52 v1(38.23,95.52) ; 38.1,95.52 38.1,95.75 38.63,96.28 39.74,96.28 40.02,96.56 40.26,96.56 40.36,96.46 40.36,96.13 40.46,96.03 C7105.2 ; 38.1,95.52 38.1,94.51 38.17,94.43 U7101.5
USB4_USB30_RX_N: length 98.5
  L4SGND w0.089: v2(126.08,87.18) 126.11,87.21 126.11,87.23 126.25,87.4 126.49,87.65 126.49,87.81 126.49,87.82 126.49,88.31 124.73,90.08 124.73,91.51 123.8,92.44 121.5,92.44 119.84,94.1 119.84,96.02 119.84,96.02 119.84,96.33 116.86,99.31 78.54,99.31 72.81,93.58 53.19,93.58 52.91,93.3 47.16,93.3 47.07,93.39 47.07,93.82 v2(47.12,93.87)
  BOTTOM w0.102: 43.76,96.53 45.65,96.53 47.12,95.06 v2(47.12,93.87) ; 43.76,96.53 v1(43.76,96.67) ; 43.76,96.53 43.14,96.53 42.88,96.79 C7106.1 ; CPU1.BW6 v2(126.08,87.18)
USB4_USB30_RX_P: length 98.5
  L4SGND w0.089: v2(126.09,87.84) 126.09,87.83 126.24,87.83 126.3,87.9 126.3,88.23 124.54,90 124.54,91.43 123.72,92.25 121.42,92.25 119.65,94.02 119.65,96.1 119.65,96.26 116.78,99.12 78.62,99.12 72.89,93.39 53.27,93.39 52.99,93.11 47.08,93.11 46.88,93.31 46.88,93.47 v2(46.48,93.87)
  BOTTOM w0.102: v2(46.48,93.87) 46.48,94.07 46.58,94.18 46.79,94.18 46.89,94.28 46.89,94.66 ; v2(126.09,87.84) 126.1,87.85 126.38,87.85 126.48,87.75 CPU1.BW5 ; 46.89,94.66 v1(46.76,94.66) ; 46.89,94.66 46.89,94.96 45.55,96.3 43.05,96.3 42.78,96.56 42.11,96.56 42.01,96.46 42.01,96.13 41.91,96.03 C7105.1
USB4_USB30_TX_C_N: length 4.4
  BOTTOM w0.102: v1(39.47,95.42) 39.57,95.32 ; 39.57,95.32 39.78,95.52 C7104.2 ; 39.57,95.32 39.04,94.78 39.04,94.53 38.97,94.46 U7101.7
USB4_USB30_TX_C_P: length 4.5
  BOTTOM w0.102: U7101.8 39.37,94.43 39.27,94.53 39.27,94.69 39.87,95.29 41.1,95.29 ; 41.1,95.29 41.73,95.29 41.83,95.19 41.83,94.86 41.94,94.76 C7103.2 ; 41.1,95.29 v1(41.1,95.14)
USB4_USB30_TX_N: length 101.3
  L4SGND w0.089: v2(45.72,93.87) 45.72,93.95 46.23,94.46 50.44,94.46 51.2,94.46 51.82,93.84 52.74,93.84 52.87,93.97 72.6,93.97 78.33,99.71 117.35,99.71 119.5,97.55 121.78,97.55 122.36,96.97 122.36,96.21 121.35,95.19 121.35,93.39 121.98,92.75 124.34,92.75 125.15,91.95 125.15,90.43 125.57,90 126.28,90 126.48,90.2 126.48,91.48 126.28,91.68 126.02,91.68 v2(125.8,91.9)
  BOTTOM w0.102: 45.36,95.24 45.72,94.88 v2(45.72,93.87) ; 45.36,95.24 v1(45.45,95.33) ; 45.36,95.24 45.08,95.52 C7104.1 ; CPU1.BW2 126.68,90.09 126.68,90.37 126.56,90.49 126.56,91.45 126.32,91.69 126.02,91.69 v2(125.8,91.9)
USB4_USB30_TX_P: length 101.4
  L4SGND w0.089: v2(125.8,91.27) 126.02,91.49 126.21,91.49 126.29,91.4 126.29,90.28 126.21,90.19 125.65,90.19 125.34,90.51 125.34,92.03 124.42,92.94 122.06,92.94 121.54,93.46 121.54,95.12 122.55,96.13 122.55,97.05 121.86,97.74 119.58,97.74 117.43,99.9 78.25,99.9 72.52,94.16 52.79,94.16 52.66,94.03 51.9,94.03 51.28,94.65 50.37,94.65 46.15,94.65 45.86,94.36 45.09,94.36 44.93,94.2 44.93,94.02 v2(45.09,93.87)
  BOTTOM w0.102: v1(44.25,95.06) 44.25,95.29 ; 44.25,95.29 44.98,95.29 45.49,94.79 45.49,94.51 45.39,94.4 45.03,94.4 44.93,94.3 44.93,94.03 v2(45.09,93.87) ; 44.25,95.29 43.59,95.29 43.48,95.19 43.48,94.86 43.38,94.76 C7103.1 ; v2(125.8,91.27) 125.8,91.36 125.9,91.46 126.23,91.46 126.33,91.36 126.33,90.3 CPU1.BW1
USB20_DN0_C: length 14.6
  BOTTOM w0.102: EL3505.2 18.58,38.23 18.85,37.97 18.85,37.58 18.61,37.35 ED3503.1 18.61,37.03 18.85,36.79 18.85,36.38 18.13,35.66 18.13,34.22 17.91,34 17.65,34 17.55,34.1 17.55,37.94 ; 17.55,37.94 v1(17.68,37.94) ; 17.55,37.94 17.55,39.91 16.35,41.11 15.75,41.11 15.65,41.22 USB2.2
USB20_DP0_C: length 14.9
  BOTTOM w0.102: 17.81,33.77 18,33.77 18.35,34.12 18.35,34.3 18.61,34.55 ED3503.6 18.61,34.88 18.35,35.13 18.35,35.57 19.08,36.29 19.08,37.99 19.26,38.18 EL3505.3 ; 17.81,33.77 17.56,33.77 17.32,34.01 17.32,39.82 16.26,40.89 15.75,40.89 15.65,40.78 USB2.3 ; 17.81,33.77 v1(17.81,33.65)
USB_ADT: length 61.7
  L6 w0.381: v2(23.88,68.47) 23.92,68.47 24.45,67.95 24.45,66.84 23.92,66.31 23.07,66.31 21.1,64.35 21.1,50.25 21.3,50.05 21.3,42.3 27.18,36.42 27.18,34.31 27.43,34.05 27.43,32 27.78,31.65 27.79,31.65 27.81,31.63 32.65,31.63 34.16,30.12 v2(34.42,30.12)
  BOTTOM w0.254: R7410.1 26.97,68.8 U7418.5
  BOTTOM w0.381: PD4408.2 40.51,34.16 40.51,32.15 39.94,31.58 PD4401.2 39.94,31.32 38.79,30.17 v1(36.32,30.17) 34.47,30.17 v2(34.42,30.12)
USB_OC0#: length 77.6
  TOP w0.089: v2(133.37,87.2) 133.8,86.77 RN1601.5 136.94,87.1 136.94,87.99 137.11,88.16 138.73,88.16 139.55,87.34 146.23,87.34 146.84,86.73 147.62,86.73 148.31,87.42 148.31,87.91 148.7,88.3 148.83,88.43 151.26,88.43 151.89,87.79 154.34,87.79 158.17,83.96 158.17,79.27 159.35,78.09 159.35,74.68 159.56,74.47 159.56,70.75 159.32,70.51 159.32,69.45 159.44,69.33 159.44,60.91 159.61,60.74 159.61,54.99 157.52,52.91 157.52,50.58 158.08,50.03 158.08,44.56 157.91,44.38 157.91,43.66 v1(158.24,43.33) 158.38,43.19 v2(158.95,43.19)
  BOTTOM w0.089: IOBD1.49 161.3,43.96 161.02,44.24 158.95,44.24 158.71,43.99 158.71,43.56 158.7,43.55 158.71,43.43 v2(158.95,43.19) ; v2(133.37,87.2) 133.04,86.87 CPU1.CK6
USB_OC1#: length 296.2
  TOP w0.089: v2(158.31,44.02) 158.27,44.06 158.27,50.16 157.71,50.71 157.71,52.83 159.8,54.91 159.8,60.82 159.64,60.98 159.64,65.88 160.29,66.53 160.29,75.46 160,75.75 160,83.48 156.08,87.39 156.08,87.75 154.16,89.67 152.14,89.67 151.29,88.82 148.67,88.82 148.54,88.7 148.53,88.7 147.68,87.84 140.04,87.84 139.55,88.33 133.08,88.33 132.49,87.74 ; 132.49,87.74 132.89,87.34 132.89,87.11 133.82,86.18 RN1601.6 ; 132.49,87.74 v2(132.49,87.74)
  L6 w0.089: v2(20.32,48.79) 19.89,48.36 19.89,35.66 23.27,32.28 24.24,32.28 26.66,29.86 27.06,29.86 28.55,28.36 28.55,27.05 32.77,22.83 32.77,22.59 33.9,21.46 33.9,18.88 34.52,18.26 34.52,15.09 34.99,14.62 38.96,14.62 39.21,14.38 41.66,14.38 46.57,9.46 66,9.46 67.99,11.45 75.99,11.45 76.63,12.09 79.38,12.09 81.32,14.03 86.27,14.03 86.59,13.71 86.59,13.36 86.88,13.08 89.77,13.08 90.24,13.55 95.02,13.55 95.5,14.03 97.36,14.03 97.38,14.06 98.8,14.06 100.51,15.77 111.8,15.77 112.9,14.67 127.5,14.67 128.22,13.94 130.26,13.94 130.98,14.67 134.65,14.67 135.85,13.47 148.83,13.47 149.48,12.83 149.48,12.6 150.63,11.45 154.26,11.45 156.21,13.4 159.16,13.4 161.18,15.42 161.18,15.62 166.39,20.83 166.39,30.78 163.84,33.34 163.84,35.58 159.34,40.08 159.34,41.9 159.03,42.21 159.03,42.7 159.64,43.31 159.64,44.21 159.51,44.34 158.62,44.34 v2(158.31,44.02)
  BOTTOM w0.089: v2(132.49,87.74) 132.72,87.74 CPU1.CK5 ; v2(20.32,48.79) 20.19,48.79 19.89,48.48 19.87,48.48 v1(19.56,48.16) 19.56,48.02 19.92,47.66 19.92,47.61 19.93,47.6 19.93,45.35 19.83,45.25 19.81,45.25 19.57,45.01 U3401.13
USB_OC2#: length 5
  TOP w0.102: RN1601.7 135.57,85.68 v1(135.51,85.74) 135.22,85.46 132.81,85.46 132.51,85.76 132.51,85.79 v2(132.5,85.81)
  BOTTOM w0.102: v2(132.5,85.81) 132.74,85.57 CPU1.CK8
USB_OC3#: length 322.3
  TOP w0.102: v2(132.5,85.16) 132.51,85.16 132.62,85.27 136.43,85.27 RN1601.8 136.69,85.09 137.06,84.72 138.17,84.72 140.18,86.73 146.56,86.73 146.76,86.53 147.77,86.53 148.56,87.33 148.56,87.89 148.72,88.05 148.83,88.15 148.91,88.23 151.18,88.23 151.81,87.6 154.26,87.6 157.98,83.88 157.98,79.18 159.16,78 159.16,74.76 159.16,74.59 159.33,74.42 159.33,70.8 159.12,70.59 159.12,70.43 159.12,70.43 159.12,69.37 159.24,69.25 159.24,60.83 159.41,60.66 159.41,55.07 157.33,52.99 157.33,50.5 157.88,49.94 157.88,44.64 157.35,44.11 v1(157.35,42.18) 157.35,41.57 156.65,40.86 v2(156.62,40.86) ; v2(22.73,33.42) 22.73,33.29 v2(19.3,29.86)
  L6 w0.102: v2(13.34,78) 13.97,77.36 13.97,71.14 13.18,70.36 13.18,66.46 13.44,66.21 13.94,66.21 14.86,65.29 14.86,56.31 13.36,54.82 13.36,52.73 17.49,48.6 17.49,33.02 17.85,32.66 17.85,31.32 v2(19.3,29.86) ; v2(156.62,40.86) 156.97,40.51 156.97,39.37 161.47,34.88 161.47,30.68 163.3,28.85 163.3,21.43 158.73,16.86 156.69,16.86 156.44,16.6 141.75,16.6 139.71,18.65 134.76,18.65 133.64,17.53 131.85,17.53 131.06,16.74 114.85,16.74 112.08,19.51 102.19,19.51 101.09,18.41 100.82,18.41 97.84,15.43 95.49,15.43 95.49,15.43 94.34,15.43 94.33,15.43 93.79,15.43 93.4,15.04 92.57,15.04 92.5,15.11 89.45,15.11 89.43,15.13 87.5,15.13 86.61,16.02 86.61,16.74 86.25,17.09 84.79,17.09 83.47,15.78 81.5,15.78 79.43,13.71 78.5,13.71 78.03,13.24 76.21,13.24 75.7,12.73 67.7,12.73 65.55,10.58 53.72,10.58 50.08,14.23 44.97,14.23 44.42,14.78 39.47,14.78 39.12,15.13 36.91,15.13 36.89,15.12 36.54,15.12 36.52,15.13 36.1,15.13 35.01,16.23 35.01,18.06 34.1,18.96 34.1,21.54 32.97,22.67 32.97,22.91 28.75,27.13 28.75,28.44 27.14,30.05 26.74,30.05 23.81,32.98 23.17,32.98 v2(22.73,33.42)
  BOTTOM w0.102: v2(13.34,78) 13.34,78.15 14.6,79.42 15.02,79.42 U7201.B2 ; CPU1.CK9 132.72,85.15 132.52,85.15 132.51,85.16 v2(132.5,85.16)
USB_PN0_R: length 5.1
  BOTTOM w0.102: 17.93,42.03 17.93,41.03 18.8,40.16 18.8,39.82 18.58,39.61 EL3505.1 ; 17.93,42.03 v1(17.81,42.03) ; 17.93,42.03 17.93,42.95 18.17,43.19 18.5,43.19 18.64,43.32 U3401.11
USB_POWERSHARE_VBUS_EN: length 109.4
  L4SGND w0.102: v2(102.62,18.31) 102.11,17.8 92.29,17.8 91.53,17.04 88.06,17.04 86.6,15.58 86.56,15.58 86.53,15.56 85.63,15.56 85.48,15.4 85.23,15.4 83.21,13.38 83.21,12.57 82.85,12.21 80.53,12.21 79.24,13.51 78.9,13.51 77.53,12.13 68.35,12.13 67.04,10.83 48.88,10.83 44.69,15.02 44.44,15.02 44.42,15.03 44.33,15.03 40.11,19.26 36.13,19.26 34.26,21.13 34.26,23.15 33.97,23.45 32.78,23.45 30.46,25.76 30.28,25.95 29.74,25.95 29.15,26.55 29.15,26.79 27.36,28.59 26.65,28.59 26.64,28.59 26.58,28.59 25.56,29.61 24.82,29.61 24.72,29.65 23.84,30.54 23.84,32.95 v2(23.37,33.42)
  BOTTOM w0.102: v2(23.37,33.42) 23.31,33.42 22.3,34.42 22.3,35.12 v1(22.33,35.15) 22.3,35.17 22.3,35.45 22.07,35.68 22.07,37.56 22.23,37.71 22.23,39.13 21.72,39.64 21.72,40.28 21.07,40.92 U3401.5 ; v2(102.62,18.31) 101.96,17.65 100.1,17.65 99.65,18.09 U2401.71
USB_PP0_R: length 4.8
  BOTTOM w0.102: EL3505.4 19.26,39.61 19.02,39.85 19.02,40.26 18.49,40.79 ; v1(18.59,40.89) 18.49,40.79 ; 18.49,40.79 18.16,41.12 18.16,42.86 18.26,42.96 18.53,42.96 18.66,42.82 U3401.10
USB_PWR_EN#: length 122.7
  TOP w0.102: R2434.2 81.71,12.21 v1(81.92,12.21) 82.37,12.67 v2(82.37,12.89)
  L6 w0.102: v2(82.37,12.89) 82.66,12.61 85.96,12.61 86.44,12.13 93.75,12.13 93.82,12.06 103.23,12.06 103.76,12.59 107.06,12.59 107.67,11.98 127.26,11.98 127.29,11.96 127.31,11.96 127.38,11.88 129.39,11.88 129.44,11.83 129.46,11.83 129.71,11.58 131.32,11.58 131.92,12.17 132.85,12.17 134.19,10.83 143.46,10.83 143.47,10.81 143.51,10.81 144.93,9.4 157.72,9.4 159.54,11.22 159.54,11.22 162.99,14.67 162.99,14.67 163,14.69 163,14.86 168.23,20.09 168.23,31.53 166.01,33.74 166.01,33.76 165.98,33.79 165.98,36.83 161.24,41.57 161.24,42.37 161.25,42.38 v2(161.25,42.67)
  BOTTOM w0.102: U2401.13 v2(82.37,12.89) ; v2(161.25,42.67) 161.19,42.67 160.8,43.05 IOBD1.50
USB_PWR_SHR_EN#: length 12.1
  BOTTOM w0.102: R2401.1 18.97,32.1 19.08,32.2 20.08,32.2 20.32,32.44 20.32,33.29 21.03,34 21.03,35.53 21.84,36.34 v1(21.84,39.01) 21.82,39.01 21.46,39.36 21.46,40.15 20.57,41.04 U3401.6
USB_PWR_SHR_EN_L#: length 91.5
  L6 w0.102: v2(21.72,31.13) 21.34,30.75 21.34,29.99 24.59,26.74 24.82,26.74 25.46,26.1 25.46,23.09 27.89,20.65 29.57,20.65 29.97,20.25 29.97,16.15 34.06,12.06 35.51,12.06 39.09,8.47 39.09,8.47 39.89,7.68 39.89,7.68 41.22,6.35 67.2,6.35 68.07,5.48 69.06,5.48 70.87,7.28 84.07,7.28 86.31,5.05 86.32,5.05 86.65,4.72 v2(89.41,4.72)
  BOTTOM w0.102: R2401.2 20.5,31.13 v1(20.65,31.13) 20.83,31.31 R2416.1 21.26,32.1 21.72,31.64 v2(21.72,31.13) ; U2401.118 89.11,5.82 88.92,5.62 88.92,5.21 v2(89.41,4.72)
USBCOMP: length 2
  TOP w0.508: R1603.1 128.54,87.49 128.78,87.72 v2(128.78,87.76) 128.78,88.16 128.78,88.28 v1(128.9,88.4)
  BOTTOM w0.254: v2(128.78,87.76) 128.78,87.76 128.8,87.74 129.03,87.74 CPU1.CC5
V_SM_VREF_CNTA: length 45.3
  TOP w0.483: 90.08,47.85 90.36,47.57 v2(90.95,47.57)
  TOP w0.508: v2(93.78,67.21) 93.36,67.63 92.42,67.63 92,67.21 92,64.76 90.5,63.26 90.5,59 88.95,57.45 88.95,48.98 90.08,47.85 ; R1202.2 95.09,34.67 C1202.1 94.61,34.11 v2(95.17,33.55)
  BOTTOM w0.203: CPU1.F36 94.09,68.01 93.78,67.7 v2(93.78,67.21)
  BOTTOM w0.508: v2(90.95,47.57) 91.06,47.57 91.14,47.49 94.21,47.49 95,46.7 v1(95,46.68) 95.02,46.68 95.67,46.03 95.67,39.94 95.17,39.43 v2(95.17,33.55)
V_SM_VREF_CNTB: length 44.1
  TOP w0.483: v2(90.95,48.61) 90.47,48.61
  TOP w0.508: v2(92.83,66.93) 93.19,66.57 93.19,63.54 92.33,62.68 92.33,57.83 91.82,57.32 91.78,57.32 91.76,57.3 90.41,57.3 89.97,56.86 89.97,49.12 90.47,48.61 ; v2(98.18,34.35) 98.18,34.36 98.69,34.87 C1302.1 98.88,34.14 R1302.2
  BOTTOM w0.203: CPU1.E36 93.35,67.78 93.35,67.46 93.26,67.37 93.26,67.36 v2(92.83,66.93)
  BOTTOM w0.508: v2(90.95,48.61) 94.53,48.61 96.79,46.34 96.79,37.26 98.18,35.87 v2(98.18,34.35)
VCI_IN1#: length 3.5
  TOP w0.254: v2(86.33,7.97) 86.33,8.13 R2497.1 85.56,8.65 85.27,8.37 84.93,8.37 v1(84.84,8.27)
  BOTTOM w0.203: v2(86.33,7.97) 86.33,7.81 85.91,7.4 U2401.126
VCREF0: length 8
  TOP w0.102: v2(81.28,16.27) 81.28,16.66 v1(82.1,17.48) 82.35,17.72 C2409.1 84.3,17.72 R2448.1 84.38,17.7 R2424.2
  BOTTOM w0.102: v2(81.28,16.27) 81.28,16.7 82.28,17.69 U2401.25
VD_IN1_C: length 155.8
  TOP w0.089: v2(51.44,17.19) 50.7,17.93 47.5,17.93 v1(46.35,16.78) 45.97,16.4 45.97,13.96 40.57,8.55 40.01,8.55 39.68,8.55 39.22,8.09 39.22,6.99 37.92,5.69 37.92,3.25 39.75,1.41 66.12,1.41 66.13,1.4 66.46,1.4 66.47,1.42 66.72,1.42 67.26,1.95 92.54,1.95 R2611.1 92.61,1.97 C2613.2
  L6 w0.089: v2(51.44,17.19) 51.44,17.29 49.94,18.78 41.53,18.78 37.97,22.34 37.22,22.34 34.64,24.92 34.64,26.18 35.02,26.56 35.02,27.54 36.67,29.19 36.67,29.2 36.83,29.36 36.83,35.96 41.66,40.79 42.12,40.79 54.04,52.7 62.99,52.7 66.52,56.23 66.52,57.45 v2(66.04,57.93)
  BOTTOM w0.089: C2612.2 64.47,56.23 R2610.2 64.16,56.85 64.96,57.64 65.75,57.64 v2(66.04,57.93)
VR_CAP: length 4.3
  TOP w0.254: C2418.1 84.07,14.29 v1(84.07,13.48) 84.86,13.48 v2(84.99,13.61)
  BOTTOM w0.203: U2401.18 84.35,14.89 84.99,14.26 v2(84.99,13.61)
VR_EN: length 215.1
  L4SGND w0.102: v2(27.81,82.06) 28.43,81.81 29.82,81.81 30.15,82.13 30.15,84.68 28.57,86.25 28.57,89.17 31.75,92.35 31.75,95.25 33.78,97.27 70.46,97.27 76.45,103.27 84.57,107.54 111.59,107.54 112.85,106.28 120.13,106.28 122.17,108.32 130.5,108.32 132.36,106.47 132.36,100.83 132.59,100.6 142.47,100.6 142.85,100.22 156.34,100.22 158.78,97.79 158.78,86.87 163.65,81.99 163.65,78.68 v2(162.84,77.87)
  L6 w0.102: v2(27.81,82.06) 27.97,81.9 27.97,80.1 28.76,79.32 38.85,79.32 41.31,81.77 41.31,82.77 43.06,84.52 45.11,84.52 46.33,85.74 v2(46.81,85.74)
  BOTTOM w0.102: R4002.2 162.13,78.2 162.46,77.87 v2(162.84,77.87) ; v2(46.81,85.74) 47.5,85.74 v1(47.67,85.57) 47.94,85.3 47.94,85.29 47.96,85.28 48.56,84.68 48.56,83.1 48.34,82.87 48.34,81.93 47.38,80.97 47.38,80.76 46.7,80.08 46.7,79.03 46.38,78.7 PU4601.40
VR_RDY: length 5.9
  BOTTOM w0.102: PR4609.2 48.01,83.28 TP4601.1 48.01,81.91 47.09,80.99 47.09,80.85 46.48,80.23 46.48,79.18 45.98,78.68 PU4601.39
VRALERT#: length 5
  BOTTOM w0.076: CPU1.CC36 129.3,68.18 129.46,67.9 129.46,67.9 129.56,67.7 129.56,67.38 129.74,67.21
  BOTTOM w0.102: TP1708.1 131.08,64.39 131.08,66.42 130.85,66.64 130.3,66.64 129.74,67.21
VRAM_ID1: length 24.5
  TOP w0.102: R2035.2 R2034.1 149.35,73.45 149.25,73.35 v1(149.17,73.35) 149.05,73.35 146.81,75.58 145.52,75.58 v2(143.66,77.44)
  L6 w0.102: v2(143.66,77.44) 143.15,76.93 137.94,76.93 137.94,76.93 135.96,74.95 131.81,74.95 v2(130.37,73.51)
  BOTTOM w0.102: v2(130.37,73.51) 130.05,73.83 CPU1.CE27
VRAM_ID2: length 30.7
  TOP w0.102: v2(151.51,71.22) 151.79,71.5 151.79,72 151.64,72.15 R2038.2
  BOTTOM w0.076: CPU1.CN23 135.12,76.38 135.32,76.58 arc(135.48,76.69) 135.68,76.73 135.97,76.73 136.15,76.91 136.72,76.91
  BOTTOM w0.102: 136.72,76.91 136.73,76.9 137.64,76.9 139,78.26 141.54,78.26 142.32,77.49 R2037.1 145.04,78.05 v1(145.67,78.05) 148.89,78.05 149.14,77.8 149.14,74.02 149.53,73.63 149.53,71.34 149.73,71.14 151.43,71.14 v2(151.51,71.22)
VTT_CNTL: length 78.2
  TOP w0.508: PR5125.1 v2(50.95,25.16)
  L6 w0.508: v2(40.89,30.37) 42.62,28.64 50.11,28.64 51.56,27.2 51.56,25.66 51.06,25.16 v2(50.95,25.16)
  BOTTOM w0.508: Q502.D 84.58,57.88 R507.2 82.54,57.88 78.56,53.89 60.16,53.89 55.81,49.54 51.37,49.54 46.66,44.82 44.08,44.82 42.57,43.31 42.57,32.04 v1(41.76,31.22) 40.9,30.37 v2(40.89,30.37)
WHITE_LED_BAT: length 2.3
  BOTTOM w0.254: R6402.1 114.43,15.97 v1(114.43,15.26) 115.57,15.26 Q6401.C
WIFI_RF_EN: length 114.6
  TOP w0.102: AFTP6110.1 185.55,35.27 184.15,36.67 D6102.K 183.48,37.28 R6108.2 182.63,37.53 v2(182.63,38.65) ; R2107.2 137.08,76.51 136.67,76.91 135.9,76.91 135.76,76.78 134.14,76.78 133.91,76.55 133.68,76.55 v2(133.6,76.48)
  L4SGND w0.102: v2(182.63,38.65) 180.41,38.65 178.99,37.23 173.64,37.23 173.5,37.37 168.58,37.37 165.05,40.89 159.62,40.89 157.37,43.15 157.37,44.54 157.48,44.65 157.48,45.3 157.02,45.76 156.71,45.76 155.37,47.1 155.37,47.27 154.94,47.71 153.56,47.71 152.6,46.74 v2(152.6,45.3)
  L6 w0.102: v2(152.6,45.3) 152.6,48.37 152.88,48.66 152.88,51.41 150.88,53.42 150.88,54.73 150.55,55.06 150.54,55.06 147.4,58.2 147.4,60.49 146.81,61.07 146.81,61.89 147.4,62.48 147.4,62.88 145.41,64.86 145.41,68.2 147.84,70.63 147.85,70.64 147.85,75.88 147.18,76.55 145.85,76.55 144.55,77.84 143.49,77.84 142.78,77.13 137.44,77.13 137.22,76.92 136,76.92 135.57,76.48 v2(133.6,76.48)
  BOTTOM w0.102: v2(133.6,76.48) 133.23,76.48 132.91,76.16 132.91,75.88 132.74,75.71 132.06,75.71 CPU1.CG25 ; v2(152.6,45.3) 152.6,45.18 153.03,44.75 155.19,44.75 156.01,45.56 156.97,45.56 157.86,44.67 157.86,44.67 157.9,44.64 161.81,44.64 162.3,44.14 IOBD1.47
WIFI_RF_EN_R: length 6.6
  TOP w0.102: R6109.2 181.11,35.19 183.03,35.19 183.13,35.29 183.13,36.16 R6108.1 183.11,36.64 183.36,36.64 184.15,35.86 D6102.A 184.23,35.67 v1(184.23,34.71)
WLAN_CLK_CPU_N: length 114.4
  L6 w0.089: v2(159.64,46.5) 159.64,46.23 159.55,46.14 159.28,46.14 159.19,46.06 159.19,45.83 158.99,45.63 156.37,45.63 155.19,46.8 155.19,50.7 155.39,50.9 155.39,76.42 151.99,79.83 150.51,79.83 148.98,81.36 143.72,81.36 143.02,80.66 141.18,80.66 138.92,82.92 138.92,83.09 137.87,84.14 136.48,84.14 134.5,82.16 130.36,82.16 130.08,82.45 127.88,82.45 126.59,83.74 123.47,83.74 121.97,85.23 118.53,85.23 118.09,85.67 118.09,86.02 117.13,86.98 117.13,90.71 115.94,91.9 115.63,91.9 115.54,91.81 115.54,91.53 115.47,91.46 v2(115.19,91.46)
  BOTTOM w0.102: v2(115.19,91.46) 115.44,91.46 115.52,91.53 115.52,91.71 115.62,91.81 115.8,91.81 116.95,90.66 116.95,89.96 116.9,89.91 116.78,89.91 116.65,90.04 CPU1.BC1 ; v2(159.64,46.5) 159.44,46.7 159.44,47.52 159.55,47.62 160.93,47.62 161.34,47.21 162.64,47.21 163.22,47.8 164.39,47.8 ; IOBD1.14 178.8,43.97 179.07,44.24 179.07,44.49 178.77,44.8 177.53,44.8 176.32,46 174.87,46 174.87,46 174.76,46 174.17,46.6 170.71,46.6 169.52,47.8 164.39,47.8 ; 164.39,47.8 v1(164.39,47.64)
WLAN_CLK_CPU_P: length 114.4
  L6 w0.089: v2(159,46.5) 159,45.91 158.92,45.82 156.45,45.82 155.38,46.88 155.38,50.62 155.58,50.82 155.58,76.5 152.07,80.02 150.59,80.02 149.05,81.55 143.64,81.55 142.94,80.85 141.26,80.85 139.11,83 139.11,83.17 137.95,84.33 136.4,84.33 134.42,82.35 130.44,82.35 130.16,82.64 127.96,82.64 126.67,83.93 123.55,83.93 122.05,85.42 118.61,85.42 118.29,85.75 118.29,86.1 117.32,87.06 117.32,90.79 116.02,92.09 v2(115.19,92.09)
  BOTTOM w0.102: CPU1.BC2 116.76,89.68 116.99,89.68 117.18,89.87 117.18,90.76 115.89,92.04 115.24,92.04 v2(115.19,92.09) ; v2(159,46.5) 159.22,46.71 159.22,47.61 159.45,47.85 160.6,47.85 ; 160.6,47.85 161.03,47.85 161.44,47.44 162.54,47.44 163.13,48.02 169.61,48.02 170.81,46.83 174.26,46.83 174.86,46.23 174.97,46.23 174.97,46.23 176.42,46.23 177.62,45.03 178.86,45.03 179.3,44.59 IOBD1.13 ; 160.6,47.85 v1(160.6,48.02)
WLAN_CLKREQ_CPU_N: length 54.4
  TOP w0.102: v2(146.81,55.62) 146.51,55.92 AFTP6109.1 144.13,56.15 RN1813.8 141.04,56.58 138.52,59.1 138.52,60.8 138.05,61.27 138.03,61.27 130.11,69.19 130.11,70.63 v2(130.4,70.92)
  L6 w0.102: v2(151.81,45.82) 151.89,45.91 151.89,52.11 150.75,53.26 150.34,53.26 148.79,54.81 148.79,55.82 148.59,56.03 147.22,56.03 v2(146.81,55.62)
  BOTTOM w0.102: IOBD1.45 163.3,45.66 163.02,45.94 161.39,45.94 160.69,45.25 158.3,45.25 157.38,46.17 155.63,46.17 155.2,45.74 154.03,45.74 153.72,46.04 152.03,46.04 v2(151.81,45.82) ; CPU1.CE32 130.06,70.58 v2(130.4,70.92)
WLAN_EN#: length 4.2
  TOP w0.102: Q6102.D 182.63,43.2 182.52,43.3 v1(180.34,43.3) 180.04,43.3 R6112.1 179.43,43.76 R6111.2
WLAN_EN_R#: length 7.8
  TOP w0.102: C6102.2 178.66,43.81 R6112.2 178.64,44.42 v1(178.94,44.72) 179.6,44.72 180.57,43.76 183.44,43.76 183.58,43.62 Q6101.G
WLAN_PCIE_RX_N: length 132.1
  TOP w0.102: v1(175.97,33.98) v2(176.02,34.56)
  L6 w0.089: v2(123.31,86.55) 123.48,86.72 124.22,86.72 125.15,85.79 126.3,85.79 127.63,84.46 127.63,84.16 128.82,82.97 130.45,82.97 130.66,83.18 133.96,83.18 135.47,84.69 138.09,84.69 140.75,82.02 149.25,82.02 150.78,80.49 152.26,80.49 156.05,76.7 156.05,50.44 155.85,50.24 155.85,47.08 156.28,46.65 157.12,46.65 158.42,47.95 158.42,48.81 158.58,48.97 159.71,48.97 161.84,46.84 163.83,46.84 165.52,45.15 167.11,45.15 168.38,43.89 168.38,42.55 174.01,36.92 174.01,35.8 174.95,34.85 175.55,34.85 175.62,34.79 175.62,34.64 175.69,34.56 v2(176.02,34.56)
  BOTTOM w0.102: IOBD1.4 183.8,44.16 183.64,44.31 183.64,44.71 184.52,45.59 184.93,45.59 185.19,45.84 186.41,45.84 190.17,42.08 190.17,39.05 190.1,38.98 188.73,37.61 188.2,37.61 188,37.41 174.96,37.41 174.18,36.63 174.18,35.45 174.79,34.84 175.74,34.84 v2(176.02,34.56) ; v2(123.31,86.55) 123.27,86.51 122.94,86.51 122.79,86.65 CPU1.BN6
WLAN_PCIE_RX_P: length 132.1
  TOP w0.102: v1(176.61,35.12) v2(176.02,35.2)
  L6 w0.089: v2(123.31,87.2) 123.6,86.91 124.3,86.91 125.23,85.98 126.38,85.98 127.82,84.54 127.82,84.24 128.9,83.16 130.37,83.16 130.58,83.37 133.88,83.37 135.39,84.88 138.17,84.88 140.83,82.21 149.33,82.21 150.86,80.68 152.34,80.68 156.24,76.78 156.24,50.36 156.04,50.16 156.04,47.16 156.36,46.84 157.04,46.84 158.23,48.03 158.23,48.89 158.5,49.16 159.79,49.16 161.91,47.03 163.91,47.03 165.6,45.34 167.19,45.34 168.57,43.97 168.57,42.63 174.2,36.99 174.2,35.88 175.03,35.04 175.87,35.04 v2(176.02,35.2)
  BOTTOM w0.102: IOBD1.5 183.3,44.14 183.42,44.25 183.42,44.81 184.43,45.81 184.84,45.81 185.09,46.07 186.5,46.07 190.4,42.17 190.4,38.95 188.83,37.38 188.3,37.38 188.1,37.18 175.06,37.18 174.41,36.53 174.41,35.55 174.88,35.07 175.9,35.07 v2(176.02,35.2) ; v2(123.31,87.2) CPU1.BN5
WLAN_PCIE_TX_CON_N: length 121
  TOP w0.102: v1(176.5,37.79) v2(176.02,38.12)
  L6 w0.089: v2(176.02,38.12) 175.83,38.31 174.67,38.31 170.81,42.17 170.81,43.33 167.66,46.47 166.07,46.47 163.39,49.16 163.39,50.03 162.35,51.07 160.53,51.07 159.2,52.39 159.2,64.79 159.13,64.86 159.13,71.48 159.2,71.55 159.2,78.64 154.72,83.12 154.07,83.12 153.1,84.09 151.04,84.09 150.27,84.85 144.56,84.85 143.64,85.77 139.86,85.77 137.69,87.93 135.12,87.93 134.25,88.8 129.51,88.8 129.17,89.15 124.65,89.15 123.77,90.02 v2(123.77,94.35)
  BOTTOM w0.102: v2(123.77,94.35) 123.88,94.24 123.88,93.9 C6107.1 ; v2(176.02,38.12) 176.36,38.12 176.59,37.89 180.1,37.89 180.49,38.27 181.72,38.27 182.1,37.89 187.8,37.89 188.05,38.14 188.54,38.14 189.69,39.29 189.69,41.88 186.21,45.36 185.45,45.36 184.86,44.77 184.86,44.22 184.8,44.16 IOBD1.2
WLAN_PCIE_TX_CON_P: length 120.9
  TOP w0.102: v1(176.52,39.03) v2(176.02,38.75)
  L6 w0.089: v2(176.02,38.75) 176.02,38.7 175.82,38.5 174.75,38.5 171,42.25 171,43.4 167.74,46.67 166.15,46.67 163.58,49.23 163.58,50.11 162.43,51.26 160.61,51.26 159.39,52.47 159.39,64.87 159.32,64.94 159.32,71.4 159.39,71.47 159.39,78.72 154.8,83.31 154.15,83.31 153.18,84.28 151.11,84.28 150.35,85.04 144.64,85.04 143.72,85.96 139.94,85.96 137.77,88.12 135.2,88.12 134.33,88.99 129.59,88.99 129.25,89.34 124.73,89.34 123.96,90.1 123.96,93.83 124.08,93.95 124.34,93.95 124.41,94.02 v2(124.41,94.38)
  BOTTOM w0.102: IOBD1.1 185.3,44.13 185.09,44.34 185.09,44.68 185.54,45.13 186.11,45.13 189.46,41.78 189.46,39.39 188.44,38.37 187.96,38.37 187.71,38.12 182.19,38.12 181.81,38.5 180.39,38.5 180.01,38.12 176.68,38.12 176.48,38.32 176.48,38.86 176.38,38.96 176.23,38.96 v2(176.02,38.75) ; v2(124.41,94.38) 124.38,94.38 124.11,94.11 124.11,93.89 124.31,93.69 C6108.1
WLAN_PCIE_TX_N: length 4.9
  BOTTOM w0.076: CPU1.BR4 123.73,88.74 123.69,88.84 123.69,89.09 123.66,89.15 123.65,89.19 123.54,89.43 123.54,89.68 123.58,89.78 123.58,90 123.54,90.1 123.54,90.55 123.82,90.83 123.82,90.84 123.89,90.91 123.89,91.32 123.92,91.34 123.92,91.48 123.89,91.51 123.89,91.53
  BOTTOM w0.102: 123.89,91.53 123.89,92.56 C6107.2
WLAN_PCIE_TX_P: length 4.9
  BOTTOM w0.076: 124.12,91.53 124.12,91.51 124.09,91.48 124.09,91.26 124.07,91.24 124.07,90.84 123.94,90.71 123.93,90.71 123.71,90.48 123.71,90.12 123.74,90.03 123.74,89.75 123.71,89.66 123.71,89.47 123.79,89.29 123.85,89.22 124.1,89.22 124.23,89.1 124.23,88.92 124.16,88.84 124.04,88.84 CPU1.BR3
  BOTTOM w0.102: 124.12,91.53 124.12,92.44 C6108.2
XCLK_BIASREF: length 4.2
  BOTTOM w0.254: CPU1.CJ1 132.42,91.67 133.02,92.27 v1(133.02,93.16) 132.76,93.42 R1803.1
XDP_CLK_CPU_N: length 4.3
  BOTTOM w0.102: TP1808.1 113.41,93.36 113.31,93.46 113.17,93.46 112.54,92.83 112.54,90.42 112.75,90.21 112.89,90.21 CPU1.AU1
XDP_CLK_CPU_P: length 5.5
  BOTTOM w0.102: TP1807.1 113.41,94.02 112.31,92.93 112.31,92.74 112.31,90.32 112.89,89.74 CPU1.AU2
XDP_DBRESET#: length 22.4
  TOP w0.102: v2(147.19,87.17) 147.29,87.17 147.78,87.65 147.78,87.66 148.62,88.5 148.62,88.5 148.75,88.63 151.37,88.63 152.22,89.48 152.58,89.48 153.03,89.02 153.03,88.49 EC1706.1 R1701.2
  BOTTOM w0.076: 137.81,84.43 136.13,84.43 arc(136.11,84.42) 136.08,84.41 arc(136.03,84.36) 135.95,84.34 135.79,84.34 arc(135.75,84.35) 135.71,84.36 arc(135.64,84.39) 135.57,84.4 135.5,84.4 arc(135.44,84.39) 135.38,84.36 arc(135.34,84.35) 135.3,84.34 135.14,84.34 arc(135.06,84.36) 135,84.41 arc(134.79,84.48) CPU1.CN10
  BOTTOM w0.102: v2(147.19,87.17) 146.74,87.17 145.08,85.51 140.11,85.51 v1(139.57,84.98) 139.02,84.43 137.81,84.43
XDP_PRDY#: length 6.3
  BOTTOM w0.102: CPU1.W1 102,90.54 102.01,90.55 102.01,91.04 101.66,91.39 100.9,91.39 99.52,92.78 99.18,92.78 98.86,93.1 98.86,93.82 TP306.1
XDP_PREQ#: length 5.4
  BOTTOM w0.102: CPU1.W2 102,89.69 102.27,89.96 102.27,91.05 101.74,91.58 101.02,91.58 99.49,93.11 TP305.1
XDP_TCLK: length 4.2
  TOP w0.102: v2(99.24,86.56) v1(98.28,87.52) 97.66,88.13 R317.1
  BOTTOM w0.102: CPU1.T6 99.55,86.87 v2(99.24,86.56) 98.93,86.87 CPU1.P6
XDP_TDI: length 12.7
  BOTTOM w0.102: CPU1.U6 CPU1.U5 100.21,87.52 99.79,87.93 98.69,87.93 98.54,88.08 98.54,88.39 98.54,90.34 98.21,90.68 97.73,90.68 97.05,91.36 96.14,91.36 94.89,92.6 94.23,92.6 92.79,94.05 TP311.1
XDP_TDO_CPU: length 11.7
  BOTTOM w0.102: CPU1.Y5 CPU1.W5 101.15,87.91 100.39,87.91 99.83,88.47 99.83,90.57 99.07,91.33 97.94,91.33 95.78,93.49 v1(95.58,93.49) 95.39,93.68 R310.1
XDP_TMS: length 13.5
  BOTTOM w0.102: CPU1.T5 CPU1.P5 98.58,87.52 97.96,88.14 97.96,88.45 97.98,88.47 97.98,89.91 96.83,91.05 95.99,91.05 94.82,92.22 93.55,92.22 91.52,94.25 90.93,94.25 TP313.1
XDP_TRST#: length 1.8
  TOP w0.102: TP314.1 102.92,87.08 v2(102.92,86.63)
  BOTTOM w0.102: CPU1.AB6 103.16,86.64 102.92,86.64 v2(102.92,86.63) 102.91,86.63 102.91,86.64 102.69,86.64 CPU1.Y6
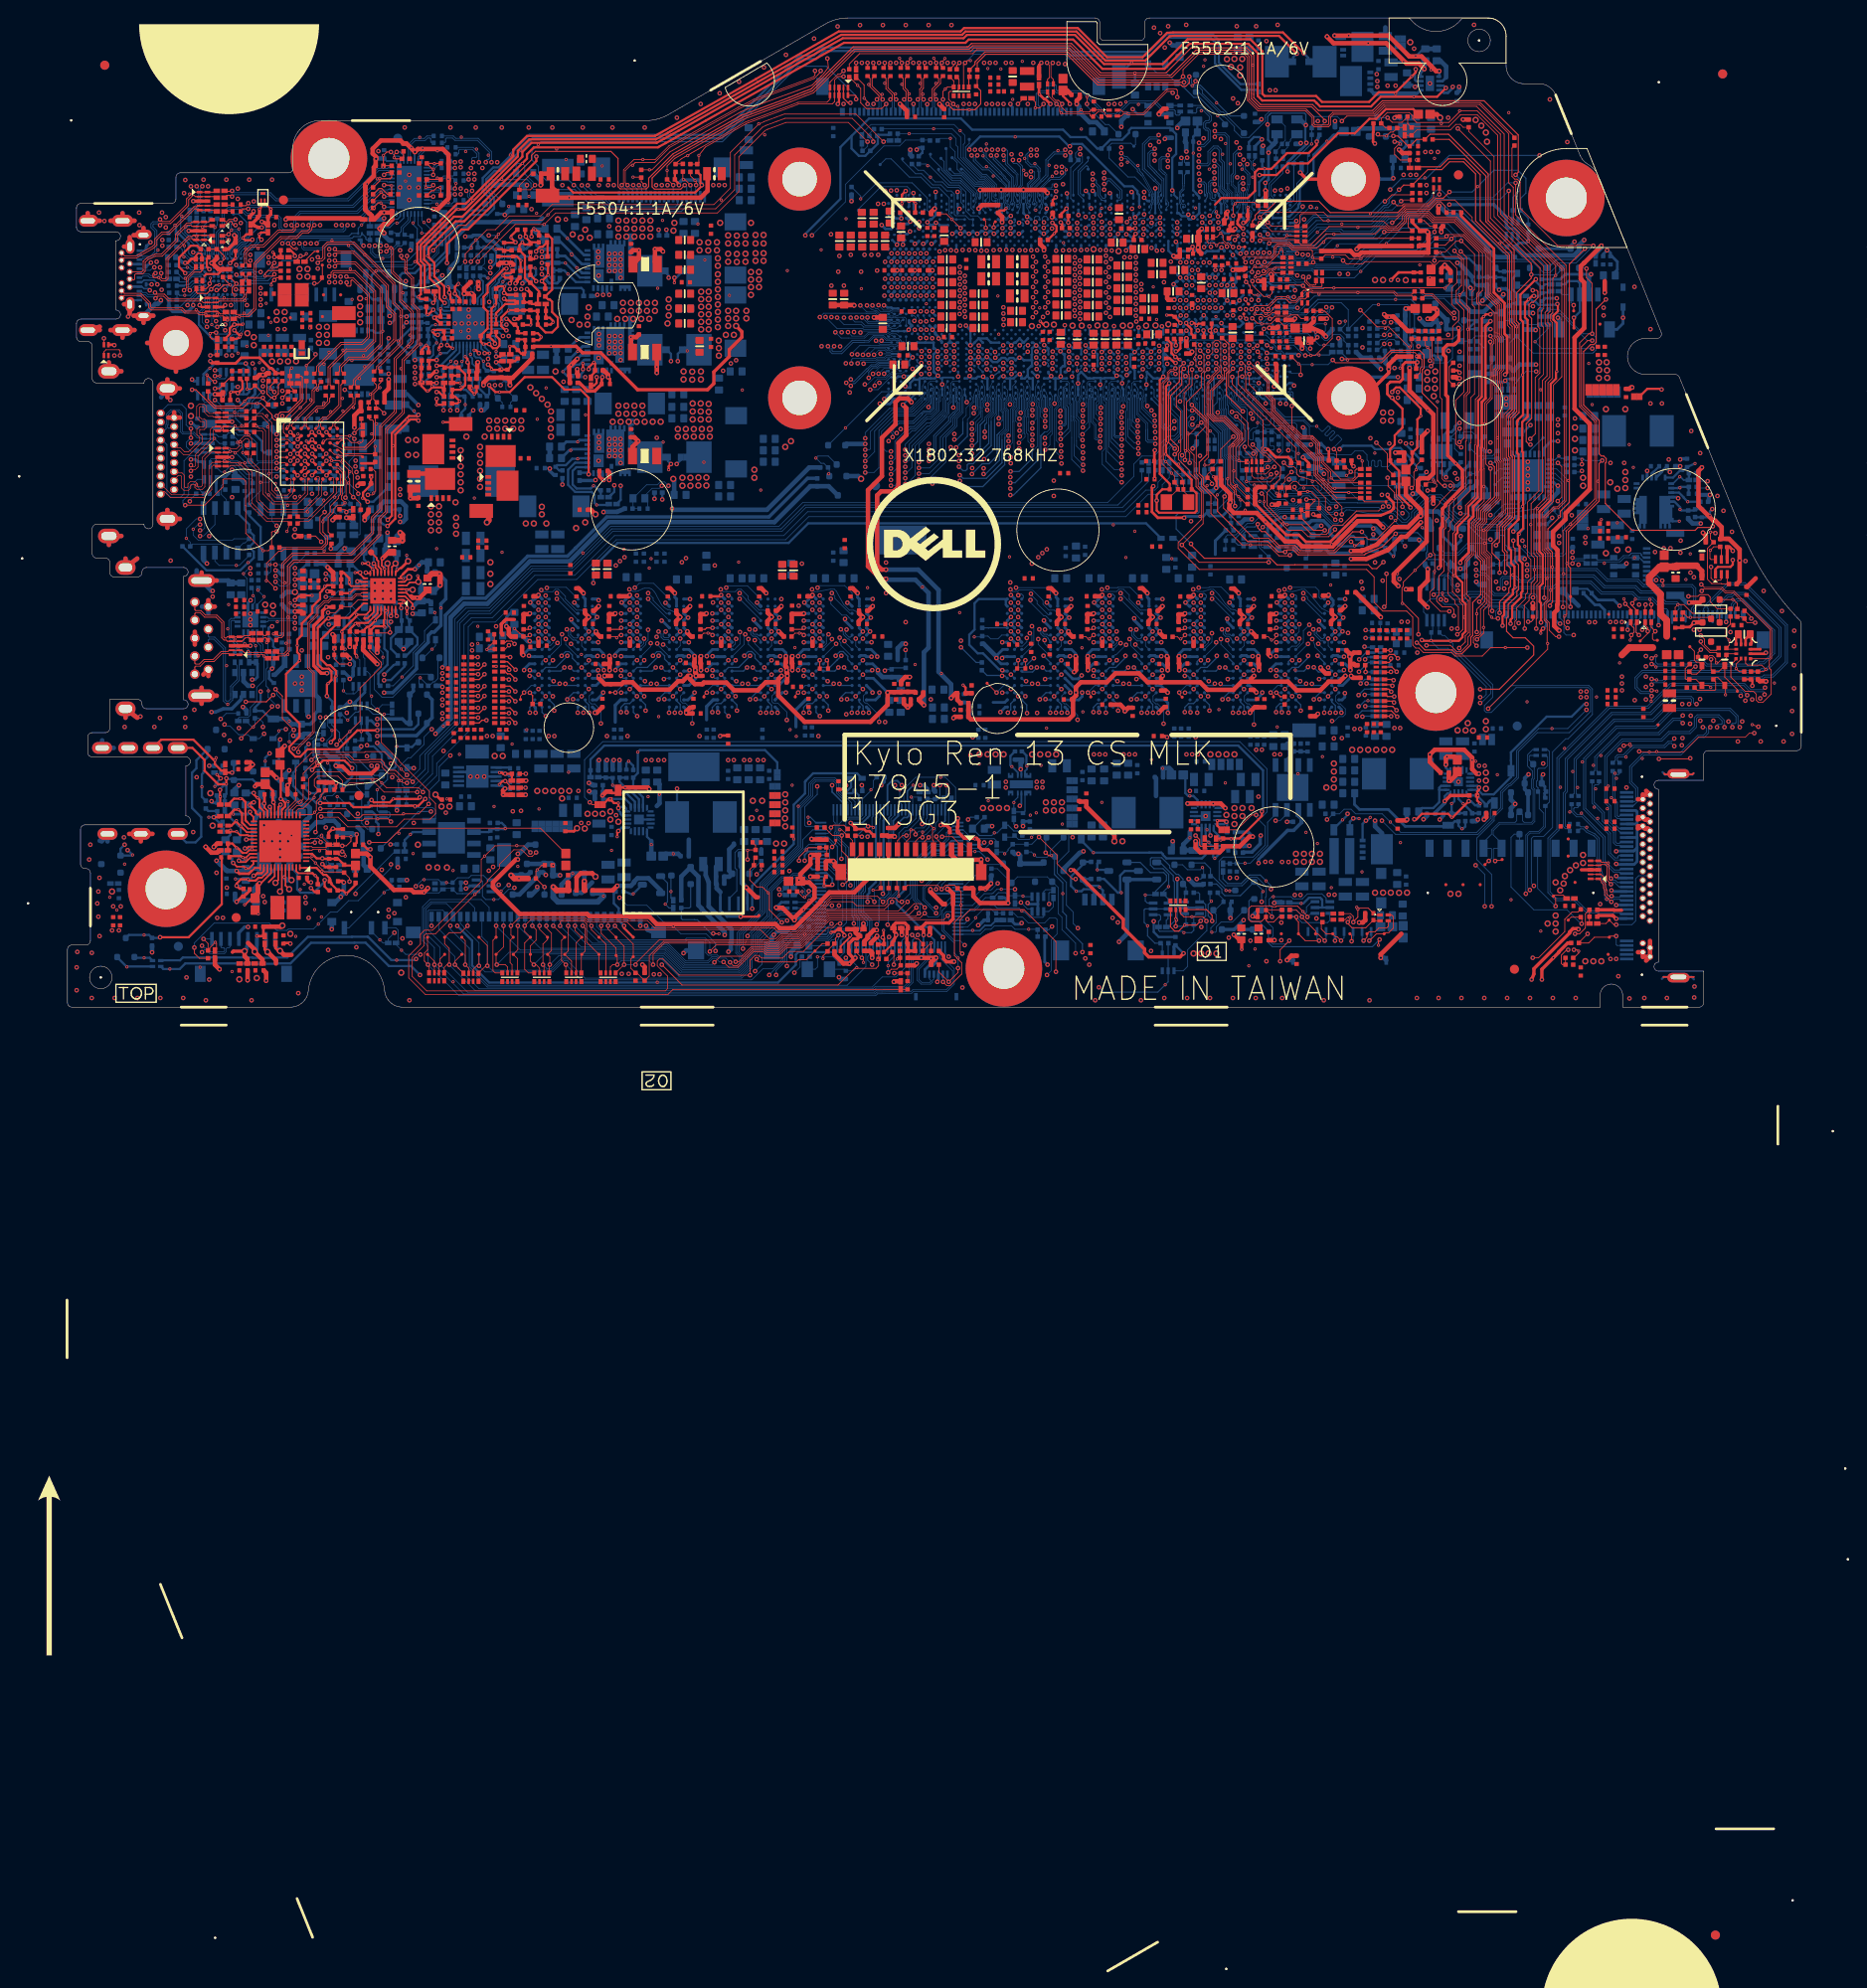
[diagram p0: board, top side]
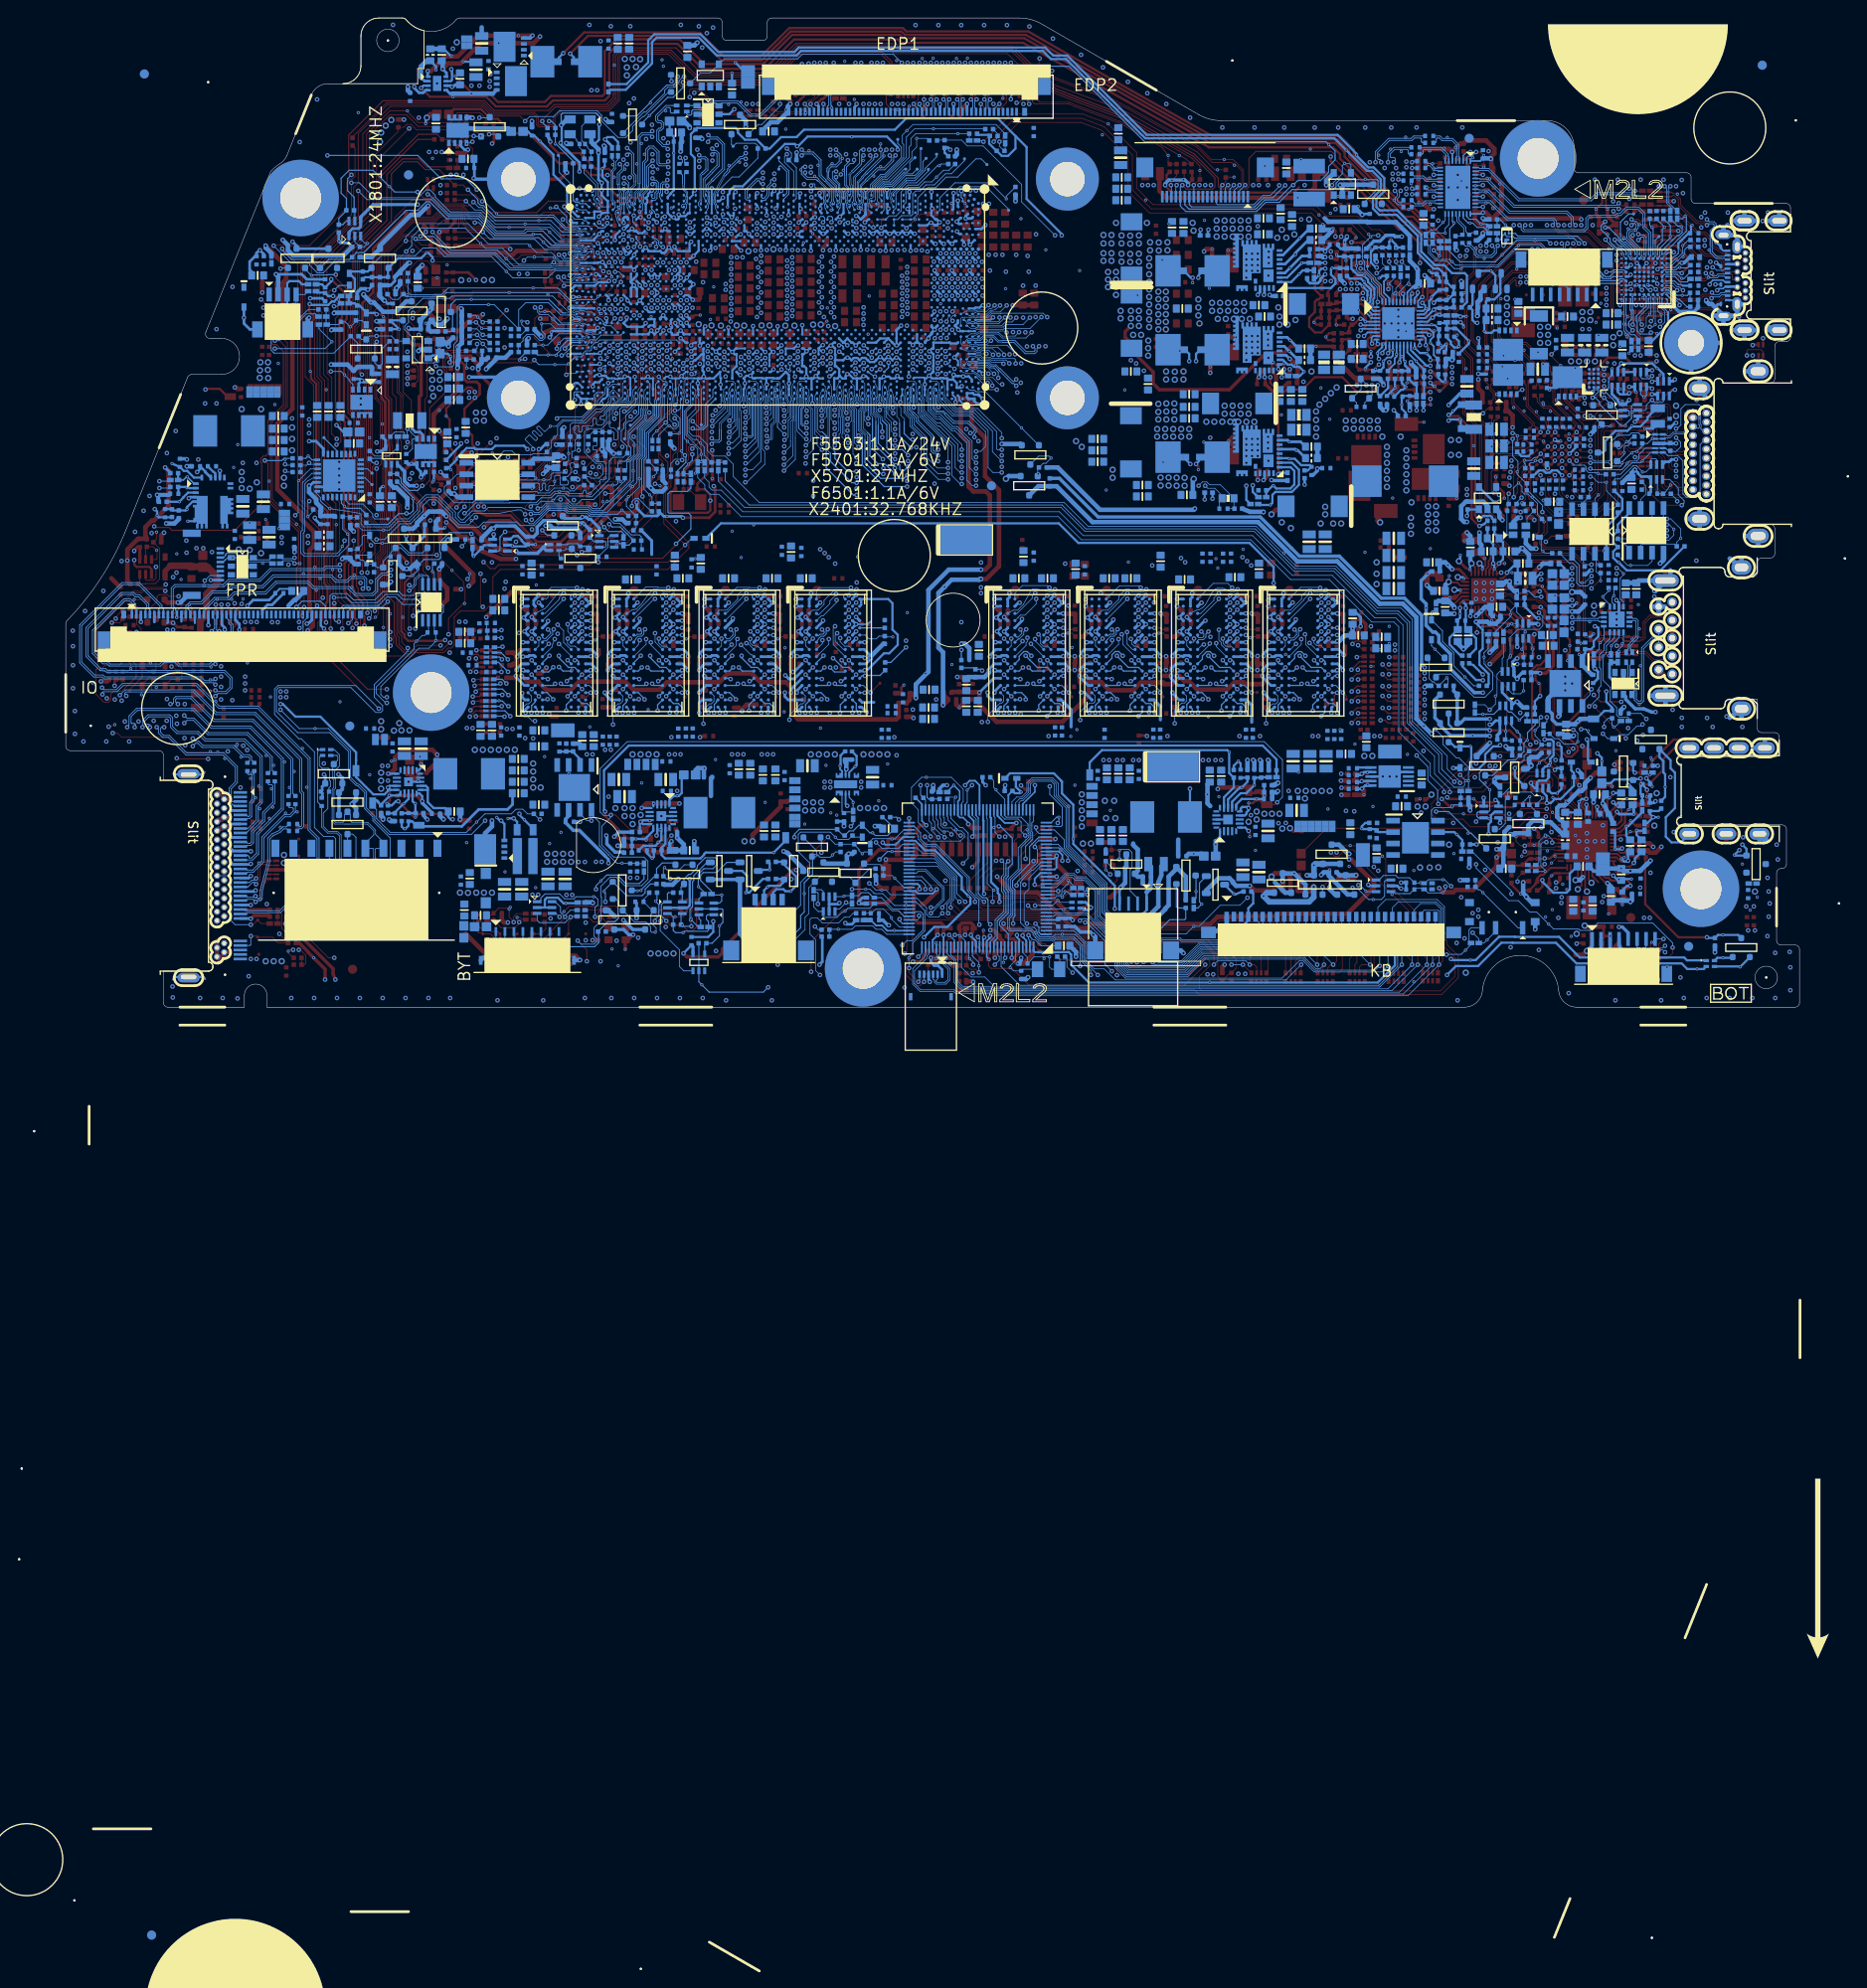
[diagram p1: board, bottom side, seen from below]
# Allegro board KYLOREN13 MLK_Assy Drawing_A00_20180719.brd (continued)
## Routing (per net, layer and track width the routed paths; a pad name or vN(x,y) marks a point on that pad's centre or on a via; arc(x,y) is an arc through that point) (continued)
XTL_24M_X1_CPU: length 5.5
  BOTTOM w0.089: R1839.1 135.04,92.64 133.75,91.35 133.75,90.17 133.82,90.1 133.82,90.1 133.99,89.93 133.99,89.72 133.6,89.34 133.6,89.02 CPU1.CK3
XTL_24M_X1_R: length 3.5
  BOTTOM w0.089: R1839.2 135.04,95 R1841.1 135.56,95.51 C1807.1 135.89,96.23 135.89,96.41 136.46,96.98 X1801.3
XTL_24M_X2_CPU: length 4.5
  BOTTOM w0.089: R1840.1 134.28,92.26 133.51,91.49 133.51,90.14 133.1,89.73 CPU1.CK2
XTL_24M_X2_R: length 5.3
  BOTTOM w0.089: R1840.2 134.28,95 R1841.2 134.68,95.49 134.68,95.63 C1808.1 134.95,95.94 135.32,96.31 135.32,97.87 134.56,98.63 X1801.1
XTL_27M_X1_HDMI: length 10.6
  TOP w0.089: v2(32.31,57.04) 32.31,57.22 31.76,57.77 31.76,59.2 31.64,59.33 31.64,59.86 30.41,61.09 U5701.E8
  BOTTOM w0.089: X5701.1 32.42,52.48 32.51,52.57 32.51,55.09 C5729.1 32.46,55.75 R5750.1 32.38,55.97 32.38,56.96 v2(32.31,57.04)
XTL_27M_X2_C: length 3.1
  TOP w0.089: R5706.1 30.81,55.31 30.99,55.14 v2(30.99,55.01) 31.29,55.31 R5707.1
  BOTTOM w0.089: C5729.2 31.11,55.14 v2(30.99,55.01) 30.86,55.14 C5730.2
XTL_27M_X2_HDMI: length 5.9
  TOP w0.089: v2(30.89,56.61) 30.89,56.61 30.96,56.68 30.96,58.53 30.84,58.65 30.84,59.45 30,60.29 U5701.F8
  BOTTOM w0.089: R5748.1 R5750.2 31.45,56.05 v2(30.89,56.61)
XTL_27M_X2_R: length 2.9
  BOTTOM w0.089: R5748.2 29.79,55.42 C5730.1 30.28,54.37 30.28,53.6 X5701.3
XTL_32K_X1_CPU: length 17.5
  TOP w0.089: X1802.1 122.1,56.25 C1804.1 123.39,57.94 R1815.1 123.01,59 v1(122.68,59.33) 121.63,60.38 121.63,69.34 122.21,69.93 122.21,70.51 122.53,70.83 122.97,70.83 v2(123.11,70.97)
  BOTTOM w0.089: v2(123.11,70.97) 122.84,71.23 CPU1.BN31
XTL_32K_X2_CPU: length 17.5
  TOP w0.089: v2(123.12,70.35) 123.12,70.39 122.86,70.65 122.61,70.65 122.39,70.44 122.39,69.85 121.81,69.27 121.81,60.84 v1(122.05,60.6) 123.87,58.78 R1815.2 124,58.19 C1803.1 124,57.35 124.57,56.78 X1802.2
  BOTTOM w0.089: v2(123.12,70.35) 122.99,70.22 122.71,70.22 122.63,70.3 122.63,70.55 CPU1.BN32

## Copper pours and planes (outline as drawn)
1V_CPU_CORE on TOP: outline of 90 points within 68.83,73.68 118.53,99.34 ; 69 cut-outs
1V_CPU_CORE on BOTTOM: 68.2,69.11 67.94,69.36 67.94,70.76 68.71,71.52 68.71,82.57 67.94,83.33 67.94,86.25 68.07,86.38 71.88,86.38 72.14,86.12 77.85,86.12 78.11,85.87 78.11,80.66 75.95,78.5 75.95,76.47 74.68,75.2 72.9,75.2 71.88,74.19 71.88,70.88 71.63,70.63 71.63,69.36 71.37,69.11 ; 4 cut-outs
1V_CPU_CORE on BOTTOM: 110.36,83.84 110.15,84.05 110.15,85.12 110.28,85.24 111.17,85.24 111.55,85.62 111.55,86.26 111.42,86.39 111.42,87.53 111.55,87.66 112.65,87.66 112.78,87.52 113.28,87.52 113.41,87.65 113.67,87.65 113.79,87.52 114.29,87.52 114.43,87.66 115.56,87.66 115.59,87.63 116.22,87.63 116.25,87.66 117.26,87.66 117.39,87.53 117.39,87.27 117.01,86.89 117.01,86.51 116.12,85.62 116.12,85.5 116.25,85.37 116.63,85.37 117.01,85.75 117.39,85.75 117.77,85.37 118.66,85.37 118.79,85.24 118.79,84.86 118.03,84.86 117.01,83.85 110.66,83.85 110.65,83.84
1V_CPU_CORE on BOTTOM: 110.48,73.48 110.15,73.81 110.15,75.59 110.79,76.23 118.53,76.23 118.79,75.97 118.79,74.63 119.2,74.22 119.2,73.58 119.09,73.48
1V_CPU_CORE on L3SGND: 89.58,76.61 82.18,76.61 74.68,69.11 68.2,69.11 67.94,69.36 67.94,70.76 68.71,71.52 68.71,85.83 79.04,96.16 114.55,96.16 116.33,94.38 116.33,90.62 116.38,90.58 116.38,85.5 117.26,84.61 117.26,77.5 118.53,76.23 118.53,75.59 118.28,75.34 111.42,75.34 110.66,76.1 110.62,76.1 110.37,76.35 108.58,76.35 108.33,76.1 106.93,76.1 105.54,74.7 91.48,74.7
1V_CPU_CORE on L4SGND: 89.58,76.61 82.18,76.61 74.68,69.11 68.2,69.11 67.94,69.36 67.94,70.76 68.71,71.52 68.71,85.83 72.41,89.53 73.26,89.53 74.8,91.08 74.8,91.92 79.04,96.16 114.55,96.16 116.38,94.34 116.38,85.5 117.26,84.61 117.26,84.6 118.49,83.37 118.49,76.27 118.53,76.23 118.53,75.59 118.51,75.56 118.51,75.22 117.99,74.7 91.48,74.7
1V_GT_CORE on TOP: 102.79,78.12 102.49,78.43 102.49,84.22 102.66,84.39 102.66,84.73 103.42,85.5 103.42,86.55 104.14,87.27 104.14,88.16 104.52,88.54 104.52,89.05 104.14,89.43 104.14,90.44 104.78,91.08 108.76,91.08 109.14,90.7 109.14,89.81 109.11,89.79 109.11,87 107.61,85.5 107.61,84.73 108.12,84.23 108.12,83.97 107.99,83.85 105.83,83.85 105.71,83.72 105.71,79.31 105.66,79.27 105.66,78.25 105.54,78.12
1V_GT_CORE on BOTTOM: 102.79,83.85 102.66,83.97 102.66,84.23 102.28,84.61 102.28,85.62 102.41,85.75 102.53,85.75 102.66,85.62 103.17,85.62 103.29,85.75 103.42,85.75 103.55,85.62 104.06,85.62 104.18,85.75 104.44,85.75 104.56,85.62 104.95,85.62 105.07,85.75 105.33,85.75 105.45,85.62 105.96,85.62 106.09,85.75 108.12,85.75 108.25,85.62 108.76,85.62 108.88,85.75 109.9,85.75 110.03,85.62 110.03,85.37 109.52,84.86 109.52,84.73 108.63,83.85
1V_VCCGT on TOP: 68.45,57.17 67.82,57.8 67.82,59.71 68.2,60.09 68.2,61.49 67.44,62.25 67.44,66.82 68.33,67.71 70.99,67.71 74.8,71.52 74.8,73.3 76.37,74.86 76.37,78.67 82.81,85.12 91.48,85.12 92.25,85.88 93.9,85.88 94.02,86 94.02,87.53 94.79,88.29 94.79,89.43 96.18,90.83 99.1,90.83 99.23,90.7 99.23,90.45 98.98,90.2 96.69,90.2 95.55,89.05 95.55,87.91 95.04,87.4 95.04,86.26 95.29,86 96.56,86 96.94,85.62 97.96,85.62 98.09,85.5 101.26,85.5 101.26,84.61 101.14,84.48 101.14,83.85 101.26,83.72 101.77,83.72 101.9,83.85 101.9,84.1 102.02,84.23 102.28,84.23 102.36,84.14 102.36,74.95 102.23,74.82 101.47,74.82 101.26,75.03 101.26,81.56 100.12,82.7 99.74,82.7 99.61,82.83 99.61,83.59 98.85,84.35 98.47,84.35 97.71,83.59 97.71,74.19 97.58,74.07 93.52,74.07 93.39,73.94 93.39,73.18 92.88,72.67 92.88,72.29 92.5,71.91 92.5,68.47 91.99,67.96 91.99,65.81 90.21,64.03 88.82,64.03 87.93,63.14 87.93,59.59 85.51,57.17 ; 59 cut-outs
1V_VCCGT on BOTTOM: 68.2,56.15 67.94,56.41 67.94,59.58 68.58,60.22 68.58,62.12 67.44,63.26 67.44,64.41 67.82,64.79 67.82,68.85 67.94,68.98 73.03,68.98 74.3,70.25 74.3,70.88 75.56,72.15 75.56,75.79 76.5,76.73 76.5,78.43 78.49,80.42 78.49,84.09 79.76,85.36 82.8,85.36 85.61,88.16 91.36,88.16 91.61,88.42 91.61,89.18 92.25,89.81 92.37,89.81 92.5,89.69 92.5,89.18 93.26,88.42 93.64,88.42 94.28,87.78 95.17,87.78 95.29,87.66 95.29,86.64 95.42,86.51 97.83,86.51 98.6,85.75 98.85,85.75 98.98,85.62 99.48,85.62 99.61,85.75 99.74,85.75 99.87,85.62 100.37,85.62 100.5,85.75 100.75,85.75 100.88,85.62 101.26,85.62 101.39,85.75 101.64,85.75 102.15,85.24 102.15,84.48 102.41,84.23 102.41,83.97 102.28,83.85 98.09,83.85 97.45,83.21 97.45,78.26 97.2,78 91.1,78 90.34,78.77 87.04,78.77 86.28,78 83.86,78 82.34,76.48 82.34,73.3 77.46,68.43 77.46,66.18 77.72,65.92 77.72,60.22 77.6,60.09 76.71,60.09 75.69,61.11 73.15,61.11 72.77,60.72 72.77,56.28 72.64,56.15 ; 24 cut-outs
1V_VCCGT on L2SGND: 68.45,57.17 67.82,57.8 67.82,59.71 68.2,60.09 68.2,61.49 67.44,62.25 67.44,66.82 68.33,67.71 70.99,67.71 74.8,71.52 74.8,73.3 76.37,74.86 76.37,78.67 83.19,85.49 98.16,85.49 98.17,85.5 101.22,85.5 101.22,85.49 101.47,85.49 102.36,84.6 102.36,76.1 100.33,74.07 94.23,74.07 93.36,73.2 93.36,73.15 92.88,72.67 92.88,72.29 92.5,71.91 92.5,69.37 91.99,68.86 91.99,65.81 90.33,64.15 88.77,64.15 87.88,63.26 87.88,59.54 85.51,57.17
1V_VCCIO on TOP: 109.52,74.57 109.39,74.7 108.2,74.7 108.12,74.78 108.12,75.46 108.23,75.57 108.23,75.89 108.08,76.04 108.08,76.09 108.2,76.22 108.84,76.22 109.09,75.97 110.03,75.97 110.66,75.34 110.66,74.57 ; 3 cut-outs
1V_VCCIO on TOP: 119.68,73.43 119.55,73.56 119.55,73.94 119.3,74.19 118.79,74.19 118.66,74.32 118.66,74.83 118.92,75.08 119.3,75.08 119.42,75.21 119.42,75.84 119.68,76.1 120.06,76.1 120.44,75.72 120.44,74.32 120.19,74.07 120.19,73.56 120.06,73.43 ; 1 cut-out
1V_VCCIO on BOTTOM: 108.96,73.61 108.37,74.19 108.37,75.92 108.68,76.23 109.73,76.23 110.11,75.84 110.11,73.75 109.98,73.61
1V_VCCIO on BOTTOM: 119.8,73.69 119.3,74.19 119.3,75.97 119.42,76.1 120.44,76.1 120.57,75.97 120.57,74.19 120.06,73.69
1V_VCCIO on BOTTOM: 151.76,64.15 151.38,64.53 145.92,64.53 145.67,64.79 145.67,66.19 146.18,66.69 153.16,66.69 153.8,66.06 153.8,64.41 153.54,64.15 ; 2 cut-outs
1V_VCCIO on L3SGND: 148,65.55 147.98,65.53 147.98,65.44 145.68,63.14 129.79,63.14 127.72,65.21 127.72,67.29 125.27,69.75 125.22,69.75 124.72,70.25 123.61,70.25 123.36,70.5 123.36,72.8 123.34,72.81 123.34,73.65 123.06,73.94 109.26,73.94 108.25,74.96 108.25,75.86 108.58,76.19 110.06,76.19 111.04,75.21 118.41,75.21 119.17,75.97 119.17,77.24 122.6,80.67 123.11,80.67 123.74,80.04 128.19,80.04 128.57,79.65 128.57,78.64 128.95,78.26 129.33,78.26 130.35,77.24 134.03,77.24 137.08,74.19 145.2,74.19 148,71.4
1V_VCCIO on L6: 108.37,74.19 108.76,73.81 122.09,73.81 122.73,73.18 125.27,73.18 126.03,73.94 128.44,73.94 129.2,73.18 129.2,72.8 129.46,72.54 129.96,72.54 130.09,72.67 130.09,73.81 131.35,75.08 133.1,75.08 133.27,75.25 133.27,75.72 133.01,75.97 132.63,75.97 132.38,76.23 131.23,76.23 131.11,76.35 129.71,76.35 129.46,76.61 128.95,76.61 128.31,77.24 127.93,77.24 127.55,77.62 121.2,77.62 119.04,75.46 110.66,75.46 109.88,76.24 108.56,76.24 108.37,76.06
1V_VCCIO_R on BOTTOM: 159.64,63.39 159.26,63.77 155.57,63.77 155.32,64.03 155.32,66.06 155.45,66.19 160.27,66.19 160.4,66.06 160.4,65.3 160.55,65.14 160.55,64.18 160.46,64.09 160.46,63.45 160.4,63.39 ; 3 cut-outs
1V_VCCSA on TOP: 120.78,75.5 120.06,76.23 119.93,76.23 119.93,76.86 120.06,76.99 120.06,79.53 119.8,79.78 119.8,80.42 119.04,81.18 119.04,85.37 118.79,85.62 118.79,86.64 118.53,86.89 118.53,96.03 119.4,96.89 119.4,96.9 121.84,99.34 121.92,99.34 124.97,102.39 124.97,104.54 126.11,105.68 128.26,105.68 128.27,105.68 130.68,105.68 130.94,105.43 130.94,99.71 133.48,97.17 133.48,96.41 134.24,95.65 134.24,94.13 133.6,93.49 132.08,93.49 131.7,93.11 131.7,90.82 131.06,90.19 128.14,90.19 127.51,89.55 126.03,89.55 125.65,89.17 125.65,86.13 124.99,85.47 124.99,85.13 124.57,84.71 124.22,84.71 122.98,83.46 121.33,83.46 121.2,83.34 121.2,80.8 121.46,80.54 121.46,77.88 122.65,76.68 122.65,75.64 122.51,75.5 ; 22 cut-outs
1V_VCCSA on BOTTOM: 119.68,83.46 118.92,84.23 118.92,85.75 119.3,86.13 121.58,86.13 122.09,85.62 122.09,83.85 121.71,83.46
1V_VCCSA on BOTTOM: 129.92,103.02 128.52,104.41 128.52,106.32 129.03,106.83 135.51,106.83 135.64,106.7 135.64,103.27 135.38,103.02 ; 4 cut-outs
1V_VCCSA on BOTTOM: 120.82,73.69 120.69,73.81 120.69,76.1 120.82,76.23 122.6,76.23 122.85,75.97 122.85,74.7 122.73,74.57 122.34,74.57 121.46,73.69
1V_VCCST_CPU_R on BOTTOM: 148.59,98.44 148.59,99.21 152.78,99.21 152.91,99.08 152.91,98.7 152.65,98.44
3V_S5_EN on TOP: 126.11,18.43 125.73,18.81 125.73,19.23 125.6,19.36 124.81,19.36 124.59,19.58 124.59,19.96 124.71,20.08 126.75,20.08 127.25,19.58 127.25,18.96 126.73,18.43 ; 3 cut-outs
5V_FAN_VCC on BOTTOM: 169.93,78.25 169.8,78.38 169.8,81.81 169.42,82.19 169.42,82.82 169.54,82.95 171.58,82.95 171.83,82.7 171.83,82.44 171.2,81.81 171.2,80.79 171.58,80.41 173.1,80.41 173.23,80.28 173.23,79.39 173.1,79.27 171.83,79.27 170.81,78.25 ; 4 cut-outs
5V_HDMI_S0 on TOP: 11.3,64.92 10.92,65.3 10.92,66.19 11.18,66.44 13.84,66.44 14.22,66.06 14.22,65.55 13.97,65.3 12.83,65.3 12.45,64.92
5V_HDMI_S0 on BOTTOM: 15.11,64.15 14.86,64.41 14.86,64.66 14.61,64.92 14.22,64.92 13.84,65.3 13.46,65.3 13.34,65.42 13.34,65.93 13.46,66.06 14.48,66.06 14.86,65.68 16.38,65.68 16.64,65.42 16.64,64.41 16.38,64.15 ; 1 cut-out
5V_S0 on TOP: 51.05,88.16 50.67,88.54 50.67,90.19 51.18,90.7 51.69,90.7 51.94,90.95 52.96,90.95 53.09,90.82 53.09,88.92 52.32,88.16 ; 2 cut-outs
5V_S0 on TOP: 26.29,7.89 24.77,9.42 20.45,9.42 20.32,9.54 20.32,11.07 20.45,11.19 21.49,11.19 21.79,10.89 26.39,10.89 27.48,11.98 30.73,11.98 31.34,12.59 36.58,12.59 37.72,11.45 37.72,9.8 35.81,7.89 ; 1 cut-out
5V_S0 on BOTTOM: 50.16,88.03 50.04,88.16 50.04,89.05 49.4,89.68 49.4,90.7 49.53,90.82 50.04,90.82 50.16,90.7 50.16,89.81 50.29,89.68 51.31,89.68 51.31,90.57 51.44,90.7 52.2,90.7 52.45,90.44 52.45,88.16 52.32,88.03 ; 2 cut-outs
5V_S0 on BOTTOM: 102.11,25.42 100.84,26.69 100.84,28.34 101.09,28.59 104.14,28.59 104.39,28.34 104.39,26.94 105.28,26.05 105.28,25.42
5V_S0 on BOTTOM: 14.99,65.8 14.61,66.19 13.46,66.19 13.34,66.31 13.34,66.95 13.59,67.2 14.86,67.2 14.99,67.07 16.51,67.07 16.64,66.95 16.64,66.19 16.26,65.8
5V_S0 on L3SGND: 110.62,26.31 111.51,25.42 111.51,21.74 110.87,21.1 97.28,21.1 88.01,11.83 79.38,11.83 75.31,7.77 40.64,7.77 36.58,11.83 35.43,11.83 35.18,11.58 35.18,7.38 38.1,4.46 76.71,4.46 80.77,8.53 94.97,8.53 96.62,10.18 96.62,12.49 102.18,18.05 112.78,18.05 114.87,20.15 114.87,27.13 113.03,28.97 101.22,28.97 100.71,28.47 100.71,26.56 100.97,26.31
5V_S0 on L4SGND: 13.46,67.33 14.1,67.33 16,65.42 16,52.22 15.75,51.96 14.99,51.96 14.73,52.22 14.73,65.04 13.21,66.57 13.21,67.07
5V_S5 on TOP: 170.94,40.53 170.66,40.81 170.66,43.71 171.17,44.21 172.59,44.21 172.97,43.83 172.97,42.69 172.85,42.56 172.34,42.56 172.21,42.44 172.21,40.79 171.96,40.53 ; 3 cut-outs
5V_S5 on TOP: 21.97,43.07 21.72,43.33 21.72,45.61 21.97,45.87 23.24,45.87 23.37,45.74 23.37,43.33 23.11,43.07 ; 2 cut-outs
5V_S5 on TOP: 118.36,1.8 112.78,7.38 111.89,7.38 107.57,11.7 107.57,12.59 101.35,18.81 101.09,18.81 100.84,19.07 99.95,19.07 98.55,20.47 82.17,20.47 81.24,19.54 79.29,19.54 78.74,20.08 78.74,23.89 79.38,24.53 100.84,24.53 102.74,22.62 107.82,22.62 107.95,22.5 107.95,18.56 109.09,17.42 109.09,16.53 119.13,6.5 119.96,6.5 121.18,5.28 132.92,5.28 132.97,5.23 147.7,5.23 151,8.53 162.05,8.53 164.34,10.81 165.46,10.81 165.76,11.12 165.76,11.47 165.86,11.58 166.65,11.58 166.78,11.45 166.78,10.48 166.29,10 166.29,8.7 162.69,5.1 153.42,5.1 150.11,1.8 ; 6 cut-outs
5V_S5 on TOP: 21.34,77.74 21.21,77.87 21.21,80.16 21.34,80.28 22.1,80.28 22.35,80.03 22.35,78 22.1,77.74 ; 2 cut-outs
5V_S5 on BOTTOM: 78.99,19.58 78.74,19.83 78.74,24.78 78.87,24.91 79.25,24.91 79.5,25.16 79.5,27.96 80.26,28.72 98.55,28.72 101.35,25.93 101.35,24.4 101.73,24.02 105.28,24.02 105.28,23.39 104.78,22.88 104.78,21.99 104.39,21.61 100.46,21.61 98.3,23.77 98.3,25.16 97.21,26.26 82.88,26.26 81.75,25.13 81.75,24.24 80.39,22.88 80.39,19.7 80.26,19.58 ; 2 cut-outs
5V_S5 on BOTTOM: 170.89,40.99 170.64,41.24 170.64,44.06 170.69,44.11 172.9,44.11 172.95,44.06 172.95,42.64 172.97,42.61 172.97,41.09 172.87,40.99
5V_S5 on BOTTOM: 37.34,16.15 37.24,16.25 37.24,16.73 37.39,16.88 37.69,16.88 38.56,17.75 38.56,18.33 38.73,18.51 40.89,18.51 41,18.41 41,17.9 40.92,17.82 39.65,17.82 37.97,16.15
5V_S5 on BOTTOM: 20.95,75.2 20.83,75.33 20.83,77.49 19.61,78.71 19.61,80.21 19.71,80.31 19.99,80.31 20.04,80.26 20.83,80.26 20.93,80.16 21.72,80.16 21.97,79.9 21.97,75.33 21.84,75.2 ; 2 cut-outs
5V_S5 on BOTTOM: 21.46,43.71 21.46,44.85 21.84,45.23 22.99,45.23 23.37,44.85 23.37,43.96 23.11,43.71
5V_S5 on L3SGND: 52.7,12.21 50.42,14.5 50.42,17.04 49.85,17.61 43.75,17.61 43.69,17.54 38.73,17.54 31.81,24.47 31.81,33.23 31.62,33.42 28.7,33.42 27.18,31.9 25.65,31.9 25.53,32.02 20.83,32.02 19.94,32.91 19.94,44.47 20.07,44.6 20.32,44.6 21.21,45.48 25.53,45.48 25.91,45.87 25.91,48.66 23.75,50.82 23.75,64.41 24.13,64.79 25.15,64.79 27.3,66.95 27.3,73.68 26.29,74.69 22.99,74.69 22.23,75.46 22.23,76.98 21.21,78 21.21,80.16 21.34,80.28 25.78,80.28 26.16,79.9 30.73,79.9 31.37,79.27 31.37,46.88 41.02,37.23 41.02,27.7 42.1,26.62 42.74,26.62 42.8,26.56 49.15,26.56 51.56,28.97 81.03,28.97 82.17,27.83 82.17,18.94 80.86,17.63 79.97,17.63 74.55,12.21 ; 1 cut-out
5V_S5 on L3SGND: 166.24,7.89 167,8.65 167,14.62 171.64,19.26 171.64,23.77 171.67,23.8 171.67,28.05 173.16,29.55 176.21,29.55 177.93,31.26 177.93,45.99 165.86,58.06 165.86,64.79 160.02,70.63 159.51,70.63 159.26,70.38 159.26,69.36 160.15,68.47 160.15,56.91 164.08,52.98 165.74,52.98 168.28,50.44 168.28,48.02 171.2,45.1 171.2,39.52 173.1,37.61 173.1,35.32 172.59,34.82 171.32,34.82 165.29,28.78 165.29,22.69 160.53,17.93 160.53,8.65 161.29,7.89
5V_S5 on L4SGND: 25.15,80.28 27.3,78.12 27.3,68.09 23.5,64.28 23.5,37.05 23.46,37.01 23.46,36.3 23.11,35.96 18.54,35.96 18.41,36.09 18.41,65.68 17.14,66.95 17.14,71.39 16.89,71.65 16.89,78.63 17.53,79.27 18.92,79.27 19.94,80.28
5V_USB30_VCCA on TOP: 18.03,43.33 17.4,43.96 15.49,43.96 14.73,44.72 14.73,45.61 14.99,45.87 18.67,45.87 19.05,45.48 19.05,43.45 18.92,43.33 ; 3 cut-outs
5V_USB30_VCCA on BOTTOM: 15.24,43.33 14.61,43.96 14.61,45.61 14.86,45.87 16.51,45.87 16.89,46.25 19.53,46.25 19.79,45.99 19.79,45.51 19.68,45.41 19.35,45.41 19.1,45.15 19.1,43.76 19.05,43.71 18.16,43.71 17.78,43.33 ; 2 cut-outs
19V_AD+ on BOTTOM: 29.59,68.98 29.34,69.23 29.34,71.52 29.46,71.65 30.23,71.65 30.48,71.9 30.48,74.06 30.73,74.31 34.8,74.31 35.05,74.06 35.05,69.74 34.8,69.49 34.54,69.49 34.04,68.98 ; 7 cut-outs
19V_DCBATOUT on TOP: 37.47,60.22 37.21,60.47 37.21,63.65 37.85,64.28 41.53,64.28 41.91,63.9 41.91,60.34 41.78,60.22
19V_DCBATOUT on BOTTOM: 33.99,59.71 33.78,59.91 33.78,64.79 33.93,64.94 36.8,64.94 37.08,64.66 37.08,63.77 37.21,63.65 39.37,63.65 39.62,63.39 39.62,60.98 39.37,60.72 38.1,60.72 37.44,60.06 35.46,60.06 35.1,59.71
19V_DCBATOUT_LCD on BOTTOM: 54.48,92.14 54.46,92.17 53.04,92.17 52.63,92.58 52.63,94.2 54.08,95.65 74.04,95.65 75.31,96.92 76.45,96.92 78.36,98.82 86.49,98.82 86.61,98.95 86.61,99.97 86.74,100.09 88.54,100.09 88.65,99.99 88.65,98.7 87.38,97.43 78.97,97.43 76.17,94.63 56.39,94.63 56.27,94.52 56.27,92.59 55.83,92.14 ; 4 cut-outs
20V_VCCPD_VBUS on TOP: 18.16,70.38 18.03,70.5 18.03,71.01 18.16,71.14 19.3,71.14 19.94,71.77 20.95,71.77 21.08,71.65 21.08,70.63 20.83,70.38 ; 1 cut-out
20V_VCCPD_VBUS on TOP: 22.61,71.27 21.46,72.41 21.46,72.79 21.59,72.92 26.42,72.92 26.54,72.79 26.54,71.65 26.16,71.27 ; 5 cut-outs
20V_VCCPD_VBUS on BOTTOM: 22.78,69.18 22.68,69.28 22.68,71.06 22.48,71.27 20.32,71.27 20.19,71.39 20.19,72.28 21.21,73.3 26.42,73.3 26.67,73.04 26.67,72.03 26.04,71.39 24,71.39 23.88,71.27 23.88,70.81 23.75,70.68 23.24,70.68 23.04,70.48 23.04,69.28 22.94,69.18
20V_VCCPD_VBUS on L3SGND: 7.37,81.68 7.37,80.41 6.99,80.03 6.99,79.65 9.53,77.11 9.53,76.22 8.76,75.46 8.76,72.28 11.05,70 12.06,70 12.57,69.49 12.57,67.46 15.11,64.92 24.89,64.92 27.05,67.07 27.05,73.55 26.29,74.31 22.23,74.31 20.95,73.04 19.81,73.04 18.92,73.93 18.92,84.47 17.14,86.25 10.29,86.25 9.65,85.62 9.65,84.85 9.4,84.6 8.89,84.6 8.51,84.22 7.49,84.22 6.6,83.33 6.6,82.44
20V_VCCPD_VBUS_L on TOP: 19.68,73.17 19.53,73.32 19.53,74.95 19.66,75.08 20.7,75.08 21.08,74.69 21.08,73.42 20.83,73.17
20V_VCCPD_VBUS_L on BOTTOM: 19.68,82.06 19.18,82.57 19.18,82.7 19.56,83.08 19.56,83.2 20.32,83.97 20.45,83.97 20.57,83.84 20.57,82.19 20.45,82.06
20V_VCCPD_VBUS_L on BOTTOM: 17.78,72.79 17.65,72.92 17.65,73.3 17.78,73.42 18.92,73.42 19.3,73.81 19.3,74.57 19.68,74.95 24.64,74.95 24.77,74.82 24.77,73.93 24.51,73.68 21.34,73.68 20.45,72.79 ; 2 cut-outs
20V_VCCPD_VBUS_L on L3SGND: 19.81,84.22 21.59,84.22 21.97,83.84 21.97,81.04 20.95,80.03 20.95,77.87 21.97,76.85 21.97,74.31 20.83,73.17 19.81,73.17 19.18,73.81 19.18,83.58
+5V_PVDD on TOP: 21.72,11.32 21.51,11.52 21.51,12.72 21.72,12.92 21.72,13.61 22.91,14.8 22.91,15.89 23.11,15.89 23.11,14.5 22.61,13.99 22.61,13.35 23.37,12.59 24.89,12.59 25.4,13.1 25.4,14.24 24.92,14.72 24.92,15.89 25.12,15.89 25.12,15.03 25.27,14.88 25.32,14.88 25.55,14.65 26.14,14.65 26.16,14.62 26.16,13.99 26.67,13.48 26.67,11.55 26.44,11.32
+5V_PVDD on BOTTOM: 21.69,11.32 21.54,11.47 21.54,12.46 21.67,12.59 26.29,12.59 26.67,12.21 26.67,11.45 26.54,11.32 ; 5 cut-outs
GND on TOP: 128.06,77.5 127.93,77.62 127.93,79.78 128.06,79.91 128.31,79.91 128.44,80.04 128.44,80.54 128.31,80.67 122.73,80.67 122.34,80.29 121.71,80.29 121.58,80.42 121.58,80.54 121.33,80.8 121.33,83.08 121.46,83.21 122.22,83.21 122.34,83.08 122.73,83.08 123.23,82.58 123.23,81.56 123.49,81.31 125.14,81.31 125.39,81.56 126.79,81.56 127.04,81.31 128.82,81.31 128.95,81.18 128.95,78.89 129.2,78.64 129.96,78.64 130.09,78.77 130.35,78.77 130.47,78.64 130.47,78.26 130.09,77.88 128.82,77.88 128.44,77.5 ; 4 cut-outs
GND on TOP: 144.83,41.57 144.75,41.65 144.75,43.6 145.03,43.88 148.29,43.88 149.22,42.94 149.22,41.67 149.12,41.57 ; 5 cut-outs
GND on TOP: 76.07,13.86 75.82,14.12 75.82,14.88 76.33,15.39 76.58,15.39 76.83,15.64 76.83,17.8 76.58,18.05 76.58,19.32 76.83,19.58 78.99,19.58 79.16,19.41 80.86,19.41 80.92,19.35 80.92,19.02 80.01,18.1 80.01,18.05 79.76,17.8 79.12,17.8 78.99,17.67 78.99,14.75 78.11,13.86 ; 10 cut-outs
GND on TOP: 48.39,87.78 48.13,88.03 48.13,88.74 49.66,90.26 49.83,90.26 49.86,90.24 50.14,90.24 50.16,90.26 50.42,90.26 50.42,88.82 49.82,88.22 49.21,88.22 48.77,87.78 ; 2 cut-outs
GND on TOP: 174.65,32.78 174.5,32.94 174.5,38.98 174.9,39.39 175.54,39.39 175.67,39.26 175.67,37.86 176.02,37.51 176.63,37.51 176.81,37.69 176.81,38.12 177.14,38.45 177.8,38.45 177.85,38.4 177.85,35.63 177.75,35.53 177.24,35.53 176.91,35.86 176.91,36.47 176.56,36.82 175.9,36.82 175.69,36.62 175.69,33.04 175.44,32.78 ; 5 cut-outs
GND on TOP: 172.59,40.66 172.47,40.79 172.47,42.18 172.59,42.31 173.35,42.31 173.61,42.06 173.61,41.04 173.23,40.66 ; 1 cut-out
GND on TOP: 41,49.7 38.1,52.6 38.1,55.52 38.61,56.03 39.12,56.03 40.01,56.91 41.91,56.91 41.91,56.15 43.56,54.5 43.56,53.1 44.45,52.22 45.85,52.22 45.97,52.09 45.97,50.82 45.85,50.69 44.42,50.69 44.2,50.46 44.2,49.8 44.09,49.7 ; 4 cut-outs
GND on TOP: 110.79,76.23 110.66,76.35 110.66,83.46 110.79,83.59 113.58,83.59 113.71,83.46 113.71,76.35 113.58,76.23 ; 10 cut-outs
GND on TOP: 149.86,94 149.73,94.13 149.73,95.9 149.86,96.03 151.76,96.03 152.53,95.27 152.53,94.25 152.27,94 ; 2 cut-outs
GND on TOP: 115.44,100.09 115.32,100.22 113.79,100.22 113.67,100.35 113.67,101.11 114.05,101.49 116.08,101.49 116.71,100.86 116.71,100.22 116.59,100.09 ; 1 cut-out
GND on TOP: 60.2,60.09 59.84,60.44 59.84,67.35 59.89,67.4 64.85,67.4 65.51,66.74 65.51,64.79 64.64,63.92 62.26,63.92 61.85,63.52 61.85,60.34 61.59,60.09 ; 2 cut-outs
GND on TOP: 99.31,100.09 98.81,100.6 98.55,100.6 98.17,100.98 98.17,101.49 100.33,101.49 100.58,101.75 100.97,101.75 101.09,101.62 101.09,100.22 100.97,100.09 ; 1 cut-out
GND on TOP: 17.4,72.15 17.14,72.41 17.14,73.68 17.27,73.81 19.18,73.81 19.3,73.68 19.3,72.66 18.8,72.15 ; 2 cut-outs
GND on TOP: 118.92,75.21 118.66,75.46 118.66,75.97 118.41,76.23 117.9,76.23 117.26,76.86 117.26,84.22 116.82,84.67 116.82,85.57 116.51,85.87 116.46,85.87 116.33,86 116.33,87.78 116.46,87.9 117.22,87.9 117.35,87.78 117.35,86.25 117.47,86.12 117.59,86.12 117.6,86.13 117.9,86.13 118.03,86 118.03,84.86 118.15,84.73 118.79,84.73 118.92,84.61 118.92,81.05 119.68,80.29 119.68,79.4 119.8,79.27 119.8,76.99 119.68,76.86 119.68,76.35 119.3,75.97 119.3,75.34 119.17,75.21 ; 19 cut-outs
GND on TOP: 151.26,29.36 147.96,32.66 147.96,38.37 149.22,39.64 150.11,39.64 150.37,39.39 153.54,39.39 153.92,39.01 155.07,39.01 156.59,37.48 156.59,31.01 157.1,30.5 157.1,29.74 156.72,29.36 ; 1 cut-out
GND on TOP: 43.18,29.74 41.4,31.51 41.4,37.1 42.29,37.99 42.55,37.99 42.67,37.86 42.67,31.01 43.31,30.37 48.9,30.37 49.02,30.24 49.02,29.86 48.9,29.74 ; 9 cut-outs
GND on TOP: 21.72,73.04 21.46,73.3 21.46,75.33 21.72,75.58 24.26,75.58 25.15,74.69 26.16,74.69 26.54,74.31 26.54,73.17 26.42,73.04 ; 5 cut-outs
GND on TOP: outline of 200 points within 0.51,0.51 192.14,109.39 ; 8 cut-outs
GND on TOP: 103.89,100.09 103.76,100.22 103.76,100.73 103.12,101.36 103.12,104.16 104.14,105.17 105.16,105.17 105.54,104.79 105.54,103.65 105.41,103.52 104.52,103.52 104.27,103.27 104.27,100.22 104.14,100.09 ; 5 cut-outs
GND on TOP: 78.66,48.79 78.02,49.43 78.02,49.81 78.53,50.32 81.2,50.32 81.96,49.56 81.96,49.05 81.7,48.79 ; 3 cut-outs
GND on TOP: 133.27,69.88 133.07,70.07 133.07,70.33 133.6,70.86 133.6,70.93 133.38,71.16 133.17,71.16 132.66,71.67 132.66,73.33 132.2,73.79 130.12,73.79 130.02,73.69 130.02,73.28 129.94,73.2 129.28,73.2 129.18,73.3 129.18,73.74 129.13,73.79 128.97,73.79 128.9,73.86 128.9,74.65 129,74.75 131.77,74.75 132.17,74.35 132.61,74.35 132.63,74.32 135.63,74.32 135.64,74.31 135.64,73.91 135.53,73.81 135.38,73.81 135,73.42 135,73.04 135.13,72.92 135.15,72.92 135.27,72.79 135.27,72.72 135.48,72.52 135.48,72.03 135.2,71.76 134.11,71.76 133.9,71.55 133.9,70.13 133.65,69.88 ; 5 cut-outs
GND on TOP: 121.6,48.86 120.99,49.47 120.99,53.27 119.63,54.63 119.63,56.03 119.76,56.15 120.02,56.15 120.14,56.03 120.14,54.88 121.03,53.99 124.33,53.99 124.71,54.37 124.94,54.37 125.19,54.12 125.19,53.62 123.21,51.64 123.21,50.97 123.4,50.78 123.4,49.26 123,48.86 ; 2 cut-outs
GND on TOP: 22.73,78.76 22.61,78.89 22.61,79.77 23.37,80.54 24,80.54 24.13,80.66 24.13,83.46 24.26,83.58 24.77,83.58 24.89,83.46 24.89,82.31 27.05,82.31 27.81,81.55 27.81,80.92 27.43,80.54 27.43,79.9 26.8,79.27 23.5,79.27 22.99,78.76 ; 3 cut-outs
GND on TOP: 167.13,10.94 167,11.07 167,12.46 166.88,12.59 165.61,12.59 164.97,13.23 164.97,14.37 166.5,15.89 166.5,20.34 166.62,20.47 168.28,20.47 168.78,19.96 168.78,12.34 167.39,10.94 ; 3 cut-outs
GND on TOP: 42.55,73.93 42.29,74.19 42.29,75.58 42.04,75.84 42.04,77.62 42.29,77.87 43.81,77.87 43.94,78 43.94,78.5 44.07,78.63 44.45,78.63 44.58,78.5 44.58,78 44.83,77.74 44.83,77.36 45.09,77.11 46.1,77.11 46.35,76.85 46.35,74.82 45.47,73.93 ; 7 cut-outs
GND on TOP: 171.58,17.16 171.45,17.29 171.45,18.69 170.81,19.32 170.81,24.53 170.94,24.66 171.2,24.66 171.32,24.53 171.32,20.21 171.45,20.08 171.45,19.58 172.34,18.69 172.34,17.29 172.21,17.16
GND on TOP: 32.08,58.57 31.75,58.9 31.75,59.99 31.62,60.11 31.62,60.85 31.75,60.98 32.69,60.98 33.02,60.65 33.02,58.82 32.77,58.57 ; 2 cut-outs
GND on TOP: 140.59,29.61 140.46,29.74 140.46,30.12 140.72,30.37 143.76,30.37 144.27,30.88 146.43,30.88 146.94,31.39 148.21,31.39 148.72,30.88 148.72,30.12 148.21,29.61 ; 3 cut-outs
GND on TOP: 171.83,33.42 171.7,33.55 171.7,35.32 171.83,35.45 172.97,35.45 173.1,35.32 173.1,35.07 172.47,34.44 172.47,33.55 172.34,33.42 ; 2 cut-outs
GND on TOP: 46.61,41.42 46.48,41.55 46.48,42.18 48.51,44.21 48.9,44.21 49.02,44.09 49.02,43.58 48.64,43.2 48.26,43.2 47.88,42.82 47.88,42.18 47.75,42.06 47.24,42.06 46.99,41.8 46.99,41.55 46.86,41.42
GND on TOP: 25.91,46.25 25.65,46.5 25.15,46.5 25.02,46.63 25.02,47.01 25.15,47.14 26.54,47.14 26.67,47.26 26.67,47.9 26.42,48.15 25.91,48.15 25.53,48.53 25.15,48.53 25.02,48.66 25.02,48.91 25.27,49.17 26.42,49.17 27.3,48.28 27.3,46.37 27.18,46.25 ; 3 cut-outs
GND on TOP: outline of 182 points within 1.51,29.23 114.19,109.39 ; 10 cut-outs
GND on TOP: 60.07,90.95 59.82,91.2 59.82,92.35 59.94,92.47 60.83,92.47 60.96,92.35 60.96,91.08 60.83,90.95 ; 1 cut-out
GND on TOP: 116.97,95.27 116.84,95.4 116.84,95.9 114.45,98.29 114.45,99.08 114.6,99.23 114.99,99.23 115.11,99.1 115.11,98.9 115.57,98.44 117.22,98.44 118.24,97.43 118.24,95.65 117.86,95.27
GND on TOP: 129.53,82.37 129.46,82.45 129.46,82.96 129.33,83.08 127.3,83.08 126.54,83.85 126.54,84.48 126.79,84.73 128.19,84.73 129.08,83.85 129.58,83.85 130.09,83.34 130.09,82.45 130.02,82.37 ; 2 cut-outs
GND on TOP: 35.81,89.05 35.69,89.17 35.69,89.68 35.81,89.81 36.32,89.81 36.45,89.93 36.45,91.2 36.58,91.33 36.58,93.62 36.7,93.74 37.47,93.74 37.59,93.87 37.59,94.38 37.72,94.51 38.73,94.51 38.99,94.76 39.5,94.76 39.62,94.63 39.62,94.25 39.37,94 39.37,89.68 38.73,89.05 ; 12 cut-outs
GND on TOP: 14.17,80.38 14.1,80.46 14.1,81.17 14.33,81.4 15.24,81.4 15.39,81.25 15.39,80.43 15.34,80.38
GND on TOP: 120.06,72.54 119.93,72.67 119.93,73.05 120.31,73.43 120.31,74.07 120.69,74.45 120.69,75.08 120.95,75.34 122.6,75.34 122.75,75.49 122.75,76.05 122.8,76.1 123.23,76.1 123.28,76.05 123.28,75.79 123.61,75.46 124.43,75.46 124.63,75.26 124.63,74.83 124.5,74.7 121.84,74.7 121.71,74.57 121.71,74.36 121.03,73.68 121.03,73.42 121.05,73.41 121.05,73.15 120.95,73.05 120.95,72.8 120.69,72.54 ; 2 cut-outs
GND on TOP: 134.49,95.78 133.58,96.69 133.58,97.15 133.1,97.63 133.1,98.82 133.6,99.33 137.41,99.33 137.92,98.82 137.92,95.9 137.79,95.78
GND on TOP: 50.29,59.84 50.16,59.96 50.16,62.63 49.78,63.01 47.75,63.01 47.62,63.14 47.62,63.77 47.5,63.9 46.74,63.9 46.48,64.15 46.48,65.3 47.8,66.62 50.14,66.62 50.22,66.54 50.22,66.01 50.8,65.42 50.8,59.96 50.67,59.84 ; 1 cut-out
GND on TOP: 188.09,39.13 187.83,39.39 187.83,40.66 187.58,40.91 186.56,40.91 186.44,41.04 186.44,41.93 186.31,42.06 185.8,42.06 185.67,42.18 185.67,42.94 185.8,43.07 185.93,43.07 186.06,43.2 187.58,43.2 189.1,41.67 189.1,39.26 188.98,39.13 ; 1 cut-out
GND on TOP: 170.81,49.8 170.59,50.02 170.59,50.47 170.55,50.51 170.55,51.24 170.84,51.53 170.84,54.07 171.01,54.24 172.04,54.24 172.59,53.69 172.59,50.31 172.09,49.8 ; 5 cut-outs
GND on TOP: 101.77,84.48 101.64,84.61 101.64,85.5 101.52,85.62 98.21,85.62 98.09,85.75 97.07,85.75 96.69,86.13 95.29,86.13 95.17,86.26 95.17,87.4 95.29,87.53 95.62,87.53 96.27,86.89 98.3,86.89 98.55,86.63 98.6,86.63 98.98,86.26 103.04,86.26 103.29,86 103.29,85.62 102.53,84.86 102.53,84.61 102.41,84.48 ; 3 cut-outs
GND on TOP: 124.59,20.34 124.46,20.47 124.46,21.23 124.84,21.61 126.62,21.61 126.75,21.48 126.75,20.72 126.36,20.34 ; 2 cut-outs
GND on TOP: outline of 164 points within 55.39,31.52 119.3,84.23 ; 57 cut-outs
GND on TOP: 60.71,71.65 59.82,72.54 59.82,74.82 60.71,75.71 60.71,80.41 59.94,81.17 59.94,86.76 60.96,87.78 65.28,87.78 65.53,87.52 72.77,87.52 72.9,87.39 72.9,87.01 72.39,86.51 68.83,86.51 68.58,86.25 68.58,74.31 69.72,73.17 70.76,73.17 71.27,73.68 71.63,73.68 73,75.05 74.3,75.05 74.42,74.92 74.42,74.57 72.9,73.04 72.9,72.28 72.64,72.03 68.96,72.03 65.66,75.33 62.36,75.33 61.85,74.82 61.85,71.77 61.72,71.65 ; 36 cut-outs
GND on TOP: 85.01,85.24 84.63,85.62 84.63,86.26 85.01,86.64 86.87,86.64 88.01,87.78 89.45,87.78 92.26,87.78 92.38,87.9 92.84,87.9 93.09,88.16 93.09,88.54 93.22,88.66 93.52,88.66 93.64,88.54 93.64,88.16 93.9,87.91 93.9,86.13 93.77,86 92.12,86 91.36,85.24 ; 19 cut-outs
GND on TOP: 135.94,54.12 135.64,54.42 135.64,54.78 135.1,55.31 135.1,56.15 135.23,56.28 135.61,56.28 135.89,56.56 137.11,56.56 137.24,56.43 137.24,56.15 136.6,55.52 136.6,54.35 136.37,54.12 ; 3 cut-outs
GND on BOTTOM: 16.64,71.77 16.26,72.15 16.26,73.17 16.38,73.3 17.02,73.3 17.4,72.92 17.4,72.79 17.53,72.66 19.18,72.66 19.3,72.79 20.07,72.79 20.19,72.66 20.19,72.03 19.94,71.77 ; 1 cut-out
GND on BOTTOM: 90.04,38.25 89.66,38.63 89.66,39.13 89.28,39.52 88.77,39.52 88.65,39.64 88.65,39.9 88.77,40.02 90.17,40.02 90.55,39.64 92.08,39.64 92.46,39.26 92.46,38.37 92.33,38.25 ; 4 cut-outs
GND on BOTTOM: 41.27,86.51 41.02,86.76 40.51,86.76 39.88,87.39 39.88,87.52 40.01,87.65 40.26,87.65 40.64,87.27 42.16,87.27 42.29,87.14 42.29,86.63 42.16,86.51
GND on BOTTOM: 151.13,97.17 151,97.3 151,97.81 151.13,97.94 152.91,97.94 153.16,98.19 153.16,98.95 153.29,99.08 153.67,99.08 153.8,98.95 153.8,97.68 153.29,97.17
GND on BOTTOM: 144.02,72.66 143.89,72.79 143.89,72.92 143.64,73.17 143.13,73.17 142.88,73.42 142.88,75.58 143.76,76.47 144.91,76.47 145.03,76.35 145.03,72.92 144.78,72.66 ; 8 cut-outs
GND on BOTTOM: 48.13,71.39 48.01,71.52 48.01,74.06 48.13,74.19 48.51,74.19 48.77,74.44 48.77,74.69 48.9,74.82 49.15,74.82 49.28,74.69 49.28,71.77 48.9,71.39 ; 2 cut-outs
GND on BOTTOM: 170.69,50.06 170.31,50.44 169.67,50.44 169.29,50.82 169.29,52.22 169.42,52.34 174.24,52.34 174.37,52.22 174.37,50.82 173.99,50.44 171.45,50.44 171.07,50.06 ; 1 cut-out
GND on BOTTOM: 28.83,38.5 28.7,38.63 28.7,39.26 27.94,40.02 27.94,41.88 27.64,42.18 26.97,42.18 26.92,42.23 26.92,42.64 27.1,42.82 28.19,42.82 28.32,42.69 28.32,42.44 28.96,41.8 29.46,41.8 29.72,41.55 29.72,41.04 29.46,40.79 29.46,38.75 29.21,38.5 ; 4 cut-outs
GND on BOTTOM: 16.51,9.54 16.26,9.8 16.26,9.92 17.4,11.07 25.78,11.07 25.92,10.93 25.92,10.22 25.25,9.54 ; 4 cut-outs
GND on BOTTOM: 77.72,44.34 77.47,44.6 77.47,45.36 75.82,47.01 74.8,47.01 74.55,47.26 74.55,48.15 74.68,48.28 76.33,48.28 76.45,48.15 76.45,47.52 77.34,46.63 77.6,46.63 78.23,45.99 78.23,44.47 78.11,44.34
GND on BOTTOM: 36.27,56.58 36.12,56.74 36.12,57.14 36.14,57.17 36.14,58.31 36.07,58.39 31.67,58.39 31.5,58.57 31.5,60.72 32,61.23 32,63.52 31.24,63.52 30.99,63.26 30.99,61.61 30.86,61.49 30.35,61.49 30.23,61.61 30.23,62.88 30.07,63.04 30.07,64.18 29.34,64.92 24.26,64.92 23.62,65.55 23.62,65.8 23.75,65.93 25.02,65.93 25.4,65.55 29.34,65.55 29.95,64.94 33.3,64.94 33.32,64.92 33.32,59.91 33.73,59.5 35.15,59.5 35.2,59.56 37.01,59.56 37.34,59.23 37.34,56.76 37.16,56.58 ; 5 cut-outs
GND on BOTTOM: 66.67,25.04 66.42,25.29 66.42,26.82 66.17,27.07 65.66,27.07 65.41,27.32 65.41,27.83 65.79,28.21 72.26,28.21 72.52,27.96 72.52,25.16 72.39,25.04
GND on BOTTOM: 21.18,16.25 21.06,16.38 21.06,17.47 21.41,17.82 21.41,20.49 21.54,20.62 21.59,20.62 21.79,20.82 21.84,20.82 22,20.97 25.02,20.97 25.27,20.72 25.27,16.4 25.12,16.25 ; 4 cut-outs
GND on BOTTOM: 172.59,23.26 172.47,23.39 172.47,24.15 172.97,24.66 173.35,24.66 173.99,24.02 173.99,23.39 173.86,23.26
GND on BOTTOM: 157.35,23.89 157.23,24.02 157.23,24.66 156.97,24.91 155.3,24.91 154.94,24.55 154.13,24.55 154.08,24.61 154.08,25.49 154.13,25.55 155.32,25.55 155.4,25.62 157.05,25.62 157.23,25.8 157.23,26.05 156.97,26.31 156.72,26.31 156.59,26.18 156.21,26.18 156.08,26.31 156.08,26.43 156.72,27.07 158.62,27.07 158.88,27.32 158.88,28.59 158.89,28.61 158.89,31.22 159.11,31.44 159.77,31.44 159.89,31.31 159.89,25.42 158.37,23.89 ; 1 cut-out
GND on BOTTOM: 97.03,31.51 96.9,31.64 96.9,35.78 97.05,35.93 97.71,35.93 97.87,35.78 97.87,34.05 98.12,33.8 98.55,33.8 98.93,34.18 100.2,34.18 100.84,33.55 100.84,32.53 100.71,32.4 98.17,32.4 98.04,32.28 98.04,31.9 97.66,31.51 ; 4 cut-outs
GND on BOTTOM: 147.7,63.26 147.45,63.52 147.45,64.03 147.7,64.28 151.38,64.28 151.51,64.15 151.51,63.9 151.13,63.52 149.73,63.52 149.48,63.77 148.84,63.77 148.72,63.65 148.72,63.39 148.59,63.26
GND on BOTTOM: 44.45,20.08 44.27,20.26 44.27,26.87 44.35,26.94 46.71,26.94 46.79,26.87 46.79,24.35 47.29,23.84 47.73,23.84 47.8,23.77 49.61,23.77 49.68,23.84 49.68,26.84 50.47,27.63 50.47,28.77 49.76,29.48 45.47,29.48 44.96,29.99 44.96,37.36 45.21,37.61 46.61,37.61 46.74,37.74 46.74,38.37 46.61,38.5 46.61,42.44 46.74,42.56 48.77,42.56 48.9,42.44 48.9,42.04 48.79,41.93 48.79,40.51 48.56,40.28 48.56,31.52 49.83,30.25 78.53,30.25 78.78,30.51 83.69,30.51 83.95,30.25 83.95,29.86 83.44,29.36 76.89,29.36 76.88,29.36 59,29.36 57.19,27.55 51.54,27.55 50.98,26.99 50.98,26.79 50.85,26.66 50.85,20.39 50.55,20.08 ; 29 cut-outs
GND on BOTTOM: outline of 174 points within 1.51,25.8 114.19,109.39 ; 15 cut-outs
GND on BOTTOM: 87.88,44.34 87.63,44.6 87.63,45.74 86.23,47.14 84.07,47.14 83.82,47.39 83.82,48.15 83.95,48.28 86.36,48.28 86.61,48.02 86.61,47.52 88.27,45.87 88.27,44.6 88.01,44.34
GND on BOTTOM: 20.19,47.14 20.07,47.26 20.07,48.28 20.19,48.41 21.34,48.41 21.46,48.28 21.46,47.26 21.34,47.14 ; 1 cut-out
GND on BOTTOM: 49.02,76.85 48.9,76.98 48.9,79.9 49.02,80.03 50.55,80.03 50.67,79.9 50.67,79.52 50.93,79.27 50.93,76.98 50.8,76.85
GND on BOTTOM: 158.62,47.01 158.5,47.14 158.5,47.77 157.99,48.28 157.99,48.53 158.12,48.66 158.62,48.66 158.75,48.53 158.75,47.9 158.85,47.8 158.85,47.06 158.8,47.01
GND on BOTTOM: 130.05,44.34 129.79,44.6 129.79,45.61 128.52,46.88 128.52,48.02 128.65,48.15 129.41,48.15 129.79,47.77 129.79,47.01 130.56,46.25 130.56,44.6 130.3,44.34 ; 1 cut-out
GND on BOTTOM: 115.32,99.97 113.67,101.62 113.67,103.14 113.79,103.27 115.32,103.27 115.44,103.14 115.44,102.25 115.95,101.75 119.13,101.75 119.25,101.62 120.52,101.62 120.65,101.75 120.65,102.76 120.78,102.89 121.28,102.89 121.41,102.76 121.41,101.24 121.16,100.98 117.47,100.98 116.46,99.97
GND on BOTTOM: 30.73,78 30.61,78.12 30.61,79.65 30.1,80.16 30.1,83.84 30.23,83.97 31.5,83.97 31.62,83.84 31.62,82.06 31.24,81.68 30.99,81.68 30.61,81.3 30.61,80.41 31.5,79.52 31.5,79.14 31.75,78.89 31.75,78.12 31.62,78
GND on BOTTOM: 58.5,59.96 58.45,60.01 58.45,61.33 58.5,61.38 59.44,61.38 59.94,61.89 59.94,64.92 60.71,65.68 60.71,68.47 60.58,68.6 58.55,68.6 58.17,68.22 54.86,68.22 54.74,68.34 54.74,69.49 55.12,69.87 57.02,69.87 57.4,70.25 57.66,70.25 58.29,69.61 66.67,69.61 67.56,68.73 67.56,65.04 67.17,64.65 67.07,64.65 67.06,64.64 62.23,64.64 62.1,64.51 62.1,63.87 61.85,63.62 61.85,60.06 60.96,60.06 60.96,60.77 59.97,60.77 59.59,60.39 59.59,60.01 59.54,59.96 ; 8 cut-outs
GND on BOTTOM: 26.12,61.22 26.01,61.33 26.01,62.45 26.14,62.58 27.3,62.58 27.43,62.45 27.43,61.33 27.32,61.22
GND on BOTTOM: 21.46,68.73 21.34,68.85 21.34,70.88 21.59,71.14 22.35,71.14 22.56,70.93 22.56,69.31 22.43,69.18 22.3,69.18 21.84,68.73
GND on BOTTOM: 58.8,13.23 58.17,13.86 58.17,14.75 58.42,15 62.36,15 62.61,14.75 62.61,13.99 62.48,13.86 61.59,13.86 60.96,13.23
GND on BOTTOM: 133.99,26.18 131.06,29.1 131.06,29.36 131.19,29.48 135.51,29.48 135.76,29.23 135.76,28.72 134.62,27.58 134.62,26.43 134.37,26.18 ; 5 cut-outs
GND on BOTTOM: 125.35,45.23 124.21,46.37 124.21,48.02 124.33,48.15 124.97,48.15 125.09,48.02 125.09,47.26 124.84,47.01 124.84,46.25 125.6,45.48 125.6,45.36 125.48,45.23
GND on BOTTOM: 115.44,2.3 114.05,3.7 114.05,6.62 111.76,8.91 111.76,11.83 112.52,12.59 113.16,12.59 113.28,12.46 113.28,11.19 113.54,10.94 115.57,10.94 115.82,11.19 115.82,12.46 115.95,12.59 116.46,12.59 117.22,11.83 117.22,9.16 116.46,8.4 116.46,7.1 116.56,7 117.35,7 117.86,7.51 120.02,7.51 120.9,6.62 120.9,4.84 121.28,4.46 121.54,4.46 121.79,4.21 121.79,3.19 120.9,2.3
GND on BOTTOM: 142.49,29.61 141.99,30.12 141.99,30.37 142.11,30.5 146.94,30.5 147.19,30.75 147.19,31.13 147.51,31.45 148.27,31.45 148.59,31.13 148.59,30.12 148.08,29.61 ; 2 cut-outs
GND on BOTTOM: 174.5,37.74 173.48,38.75 158.12,38.75 156.97,39.9 156.97,41.8 157.86,42.69 158.45,42.69 159.51,43.76 159.51,43.96 159.64,44.09 160.02,44.09 160.15,43.96 160.15,41.42 160.66,40.91 176.25,40.91 176.78,41.45 176.78,41.93 176.53,42.18 176.53,42.56 176.91,42.94 185.8,42.94 185.93,43.07 185.93,43.96 186,44.04 186.74,44.04 189.1,41.67 189.1,39.13 188.72,38.75 178.18,38.75 177.55,39.39 175.9,39.39 175.64,39.13 175.64,37.86 175.51,37.74
GND on BOTTOM: 120.02,44.34 119.63,44.72 119.63,45.61 118.49,46.75 118.24,46.75 117.73,47.26 117.73,47.9 117.98,48.15 118.62,48.15 119,47.77 119,47.14 119.38,46.75 119.76,46.75 120.52,45.99 120.52,44.6 120.27,44.34 ; 1 cut-out
GND on BOTTOM: 101.73,24.15 101.47,24.4 101.47,25.04 101.73,25.29 104.39,25.29 104.52,25.16 107.44,25.16 107.57,25.29 108.46,25.29 108.71,25.04 108.71,24.4 108.46,24.15 107.57,24.15 107.31,24.4 104.78,24.4 104.52,24.15 ; 1 cut-out
GND on BOTTOM: 124.59,23.77 124.46,23.89 124.46,26.31 123.7,27.07 120.9,27.07 120.4,26.56 116.2,26.56 115.7,26.05 115.7,25.93 115.57,25.8 110.74,25.8 110.49,26.05 110.49,27.7 111.25,28.47 125.86,28.47 125.98,28.34 125.98,27.83 125.78,27.63 125.78,26.84 125.73,26.79 125.73,23.89 125.6,23.77 ; 16 cut-outs
GND on BOTTOM: 32.64,43.96 32.51,44.09 32.51,45.99 32.89,46.37 33.78,46.37 34.04,46.63 34.04,47.39 34.29,47.64 36.45,47.64 36.83,47.26 36.83,44.98 36.58,44.72 35.31,44.72 34.8,45.23 34.04,45.23 33.53,44.72 33.53,44.09 33.4,43.96 ; 3 cut-outs
GND on BOTTOM: 90.34,88.42 89.71,89.05 89.71,90.07 90.72,91.08 92.25,91.08 92.63,90.7 92.63,90.58 92.88,90.32 92.88,90.07 92.25,90.07 91.43,89.26 91.43,88.49 91.36,88.42
GND on BOTTOM: 27.56,55.64 27.43,55.77 27.43,56.41 26.54,57.3 26.16,57.3 26.04,57.42 26.04,57.8 26.16,57.93 28.96,57.93 29.21,57.68 29.59,57.68 29.72,57.55 29.72,57.04 29.08,56.41 28.45,56.41 28.32,56.28 28.32,55.77 28.19,55.64 ; 4 cut-outs
GND on BOTTOM: 20.83,82.06 20.7,82.19 20.7,83.84 20.83,83.97 22.23,83.97 22.61,83.58 22.61,82.57 22.1,82.06
GND on BOTTOM: 161.04,62.12 160.78,62.38 160.78,65.04 160.53,65.3 160.53,65.93 160.66,66.06 168.66,66.06 168.78,65.93 168.78,65.17 168.66,65.04 166.88,65.04 165.99,64.15 163.45,64.15 162.12,62.82 162.12,62.57 161.67,62.12 ; 6 cut-outs
GND on BOTTOM: 109.86,44.34 109.73,44.47 109.73,45.36 109.47,45.61 109.47,46.75 109.09,47.14 109.09,47.9 109.35,48.15 109.98,48.15 110.36,47.77 110.36,44.6 110.11,44.34 ; 1 cut-out
GND on BOTTOM: 165.35,13.35 165,13.71 165,18.59 165.1,18.69 169.67,18.69 169.8,18.56 169.8,14.5 168.66,13.35
GND on BOTTOM: 19.81,75.2 19.68,75.33 19.68,78 19.81,78.12 20.07,78.12 20.57,77.62 20.57,75.33 20.45,75.2
GND on BOTTOM: 56.64,19.58 56.26,19.96 56.26,23.89 56.64,24.28 57.02,24.28 57.28,24.02 57.28,22.62 58.04,21.86 59.94,21.86 60.2,22.12 60.45,22.12 61.59,20.97 62.87,20.97 62.99,21.1 62.99,21.35 63.88,21.35 64.01,21.23 64.01,20.47 63.86,20.31 62.71,20.31 62.66,20.26 61.26,20.26 60.58,19.58 ; 4 cut-outs
GND on BOTTOM: 75.18,97.17 75.06,97.3 75.06,97.94 80.39,103.27 85.12,103.27 86.49,101.9 86.49,99.33 86.23,99.08 78.23,99.08 76.33,97.17 ; 1 cut-out
GND on BOTTOM: 98.85,71.15 98.72,71.27 98.72,73.18 98.6,73.3 97.33,73.3 95.8,74.83 95.8,75.21 95.55,75.46 95.55,75.84 95.67,75.97 96.18,75.97 96.44,76.23 96.44,76.61 95.93,77.11 93.26,77.11 92.75,77.62 92.75,77.75 92.88,77.88 96.56,77.88 96.82,77.62 96.82,74.7 97.58,73.94 99.1,73.94 99.23,73.81 99.23,71.27 99.1,71.15
GND on BOTTOM: 166.37,61.11 165.74,61.74 165.74,63.52 167.13,64.92 168.66,64.92 168.91,64.66 168.91,61.36 168.66,61.11 ; 2 cut-outs
GND on BOTTOM: 98.31,99.08 98.31,100.22 98.69,100.6 100.47,100.6 100.6,100.48 100.6,99.21 100.47,99.08
GND on BOTTOM: 40.46,22.98 40.26,23.18 40.26,24.78 40.61,25.14 42.42,25.14 42.49,25.06 42.49,24.3 41.17,22.98 ; 1 cut-out
GND on BOTTOM: 123.95,57.55 123.7,57.8 123.7,58.57 123.83,58.69 124.84,58.69 125.22,58.31 126.49,58.31 126.75,58.06 126.75,57.68 126.62,57.55
GND on BOTTOM: 118.66,87.53 118.15,88.04 117.39,88.04 117.14,87.78 116.25,87.78 116.22,87.76 115.51,87.76 115.49,87.78 114.43,87.78 114.29,87.65 113.79,87.65 113.67,87.78 113.41,87.78 113.28,87.65 112.9,87.65 112.77,87.78 111.17,87.78 110.66,88.29 110.66,89.05 111.04,89.43 111.68,88.8 112.95,88.8 113.45,89.31 114.22,89.31 114.47,89.05 115.11,89.05 115.49,89.43 115.87,89.43 116.5,88.8 117.14,88.8 117.77,89.43 118.53,89.43 118.79,89.18 118.79,88.93 119.3,88.42 119.3,88.04 118.79,87.53
GND on BOTTOM: 130.34,19.79 130.18,19.96 129.29,19.96 129.03,20.21 129.03,20.59 128.52,21.1 127.1,21.1 126.97,20.97 126.97,20.72 126.09,20.72 125.96,20.85 125.96,21.61 126.11,21.76 127.25,21.76 127.3,21.81 128.7,21.81 129.39,22.5 130.3,22.5 130.94,23.13 130.94,25.93 131.19,26.18 132.46,26.18 132.59,26.05 132.59,22.62 131.95,21.99 131.95,20.08 131.66,19.79
GND on BOTTOM: 173.99,55.39 173.35,56.03 169.42,56.03 168.91,55.52 168.53,55.52 168.4,55.64 168.4,56.28 169.42,57.3 169.42,59.58 169.67,59.84 173.35,59.84 173.48,59.71 173.48,57.68 173.86,57.3 173.99,57.3 174.04,57.35 174.7,57.35 174.75,57.3 174.75,55.52 174.62,55.39 ; 1 cut-out
GND on BOTTOM: 37.97,6.11 36.96,7.13 36.96,8.65 36.58,9.04 36.2,9.04 36.07,9.16 36.07,12.59 36.58,13.1 36.58,13.61 36.7,13.73 37.47,13.73 39.24,11.96 39.24,6.62 38.73,6.11 ; 1 cut-out
GND on BOTTOM: 114.05,17.54 113.28,18.31 113.28,19.2 113.41,19.32 116.84,19.32 117.6,18.56 117.6,18.05 117.09,17.54 ; 2 cut-outs
GND on BOTTOM: 152.4,28.85 152.15,29.1 152.15,29.74 151.51,30.37 150.37,30.37 148.34,32.4 148.34,37.23 149.48,38.37 153.42,38.37 156.59,35.2 156.59,28.97 156.46,28.85 ; 1 cut-out
GND on BOTTOM: 147.57,66.95 147.45,67.07 147.45,70.5 147.57,70.63 149.22,70.63 149.35,70.5 149.35,67.2 149.1,66.95 ; 2 cut-outs
GND on BOTTOM: outline of 89 points within 55.12,80.66 85.47,97.3 ; 14 cut-outs
GND on BOTTOM: 73.28,56.15 73.03,56.41 73.03,60.72 73.15,60.85 75.69,60.85 76.71,59.84 77.85,59.84 78.11,60.09 78.11,65.93 77.85,66.19 77.85,67.96 81.53,71.65 84.07,71.65 86.11,69.61 86.11,64.41 77.85,56.15 ; 8 cut-outs
GND on BOTTOM: 25.15,52.85 24.89,53.1 24.89,56.03 24.64,56.28 24.13,56.28 24,56.41 24,57.04 23.88,57.17 23.88,59.84 24,59.96 24.38,59.96 24.51,59.84 24.51,57.17 24.64,57.04 25.27,57.04 25.65,56.66 25.65,53.1 25.4,52.85
GND on BOTTOM: 140.46,21.99 140.34,22.12 140.34,23.01 139.57,23.77 139.57,26.94 140.21,27.58 140.21,31.26 140.34,31.39 141.48,31.39 141.8,31.07 141.8,29.93 142.13,29.6 142.13,23.27 142.11,23.26 142.11,22.24 141.86,21.99 ; 8 cut-outs
GND on BOTTOM: 42.8,45.71 42.42,46.09 42.42,47.64 40.89,49.17 40.89,50.06 40.51,50.44 38.73,50.44 38.23,50.95 38.23,54.76 39.5,56.03 42.42,56.03 45.09,53.36 45.09,46.14 44.65,45.71 ; 2 cut-outs
GND on BOTTOM: outline of 111 points within 59.44,37.74 151.38,53.36 ; 55 cut-outs
GND on BOTTOM: 59.94,57.17 59.82,57.3 59.82,58.06 59.94,58.18 59.94,58.69 59.82,58.82 59.82,59.58 60.07,59.58 60.07,59.07 60.45,58.69 60.45,57.3 60.33,57.17
GND on BOTTOM: 71.88,69.36 71.75,69.49 71.75,70.5 72.01,70.76 72.01,74.19 72.9,75.08 75.18,75.08 75.44,74.82 75.44,72.28 74.04,70.88 74.04,70.25 73.15,69.36 ; 3 cut-outs
GND on BOTTOM: 17.65,77.36 17.14,77.87 17.14,78.76 17.27,78.89 17.27,79.01 18.03,79.77 18.03,80.28 17.91,80.41 16.76,80.41 16.64,80.54 16.64,81.55 16.38,81.81 16.13,81.81 15.88,81.55 15.75,81.55 15.49,81.81 15.49,82.57 15.88,82.95 16.26,82.95 16.89,82.31 16.89,82.19 17.14,81.93 18.03,81.93 18.03,82.21 18.19,82.36 18.34,82.36 18.54,82.16 18.54,77.74 18.16,77.36
GND on BOTTOM: 51.94,50.44 51.82,50.56 51.82,51.33 52.2,51.71 55.63,51.71 55.88,51.96 55.88,53.87 55.63,54.12 55.63,56.66 55.88,56.91 57.91,56.91 58.17,56.66 58.17,55.77 59.05,54.88 59.05,54.25 55.24,50.44
GND on BOTTOM: 44.96,14.85 44.86,14.95 44.86,16.1 45.09,16.32 45.95,16.32 46.56,16.93 47.32,16.93 47.62,16.63 47.62,15.49 46.99,14.85 ; 2 cut-outs
GND on BOTTOM: 157.61,54.37 157.35,54.63 157.35,55.77 157.48,55.9 158.24,55.9 158.75,56.41 159.77,56.41 160.27,56.91 160.53,56.91 160.66,56.79 160.66,56.28 160.4,56.03 160.02,56.03 158.37,54.37
GND on BOTTOM: 129.03,14.12 128.78,14.37 128.78,15.26 128.91,15.39 130.94,15.39 131.06,15.26 131.06,14.5 130.68,14.12 ; 2 cut-outs
GND on BOTTOM: 145.67,9.67 145.41,9.92 145.41,10.15 145.19,10.38 142.67,10.38 140.84,12.21 140,12.21 139.5,12.72 137.67,12.72 137.16,12.21 136.4,12.21 136.14,12.46 136.14,14.12 136.27,14.24 139.95,14.24 141.1,13.1 144.53,13.1 145.11,13.68 146.89,13.68 147.29,14.09 148.16,14.09 148.26,13.99 149.1,13.99 149.86,13.23 149.86,11.58 149.35,11.07 146.94,11.07 146.53,10.66 146.53,9.85 146.35,9.67 ; 6 cut-outs
GND on BOTTOM: outline of 213 points within 0.51,0.51 192.14,109.39 ; 7 cut-outs
GND on BOTTOM: 175.13,48.28 174.75,48.66 173.99,48.66 173.86,48.79 173.86,49.17 173.99,49.29 174.62,49.29 174.88,49.04 176.02,49.04 176.78,49.8 176.78,50.95 176.3,51.43 176.3,52.16 176.5,52.37 176.91,52.37 177.65,53.1 179.58,53.1 180.21,52.47 180.21,50.44 178.05,48.28
GND on BOTTOM: 8.89,8.65 6.73,10.81 6.73,14.62 9.4,17.29 14.48,17.29 16.64,15.13 17.02,15.13 17.51,14.64 17.87,14.64 18.03,14.47 18.03,12.21 14.48,8.65 ; 3 cut-outs
GND on BOTTOM: 90.81,31.39 90.55,31.64 90.55,33.04 90.68,33.17 92.96,33.17 93.09,33.04 93.09,32.28 92.2,31.39 ; 2 cut-outs
GND on BOTTOM: 101.35,42.69 101.14,42.89 101.14,43.76 101.47,44.09 104.27,44.09 104.52,43.83 104.52,43.71 104.27,43.45 104.14,43.45 103.38,42.69 ; 1 cut-out
GND on BOTTOM: 58.5,71.42 58.45,71.47 58.45,72.79 58.5,72.84 59.44,72.84 59.94,73.35 59.94,75.96 59.69,76.22 59.69,77.11 60.33,77.74 60.33,78.5 60.58,78.76 66.29,78.76 66.55,79.01 67.69,79.01 68.33,78.38 68.33,76.09 67.82,75.58 66.42,75.58 65.91,76.09 62.23,76.09 62.1,75.96 62.1,75.33 61.85,75.08 61.85,71.52 60.96,71.52 60.96,72.23 59.97,72.23 59.59,71.85 59.59,71.47 59.54,71.42 ; 6 cut-outs
GND on BOTTOM: 67.44,44.34 67.18,44.6 67.18,45.71 65.68,47.21 63.75,47.21 63.73,47.24 63.25,46.75 62.36,46.75 62.1,46.5 62.1,46.25 62.23,46.12 62.61,46.12 62.99,45.74 62.99,45.23 62.87,45.1 62.74,45.1 62.23,45.61 61.98,45.61 61.47,46.12 61.47,46.88 61.72,47.14 62.61,47.14 62.87,47.39 62.87,48.15 62.99,48.28 63.63,48.28 63.64,48.27 66.41,48.27 66.65,48.02 68.07,48.02 68.2,47.9 68.2,44.6 67.94,44.34 ; 1 cut-out
GND on BOTTOM: 63.75,25.8 63.63,25.93 63.63,27.45 64.01,27.83 65.02,27.83 65.15,27.7 65.15,27.32 65.66,26.82 65.91,26.82 66.17,26.56 66.17,25.93 66.04,25.8 ; 1 cut-out
GND on BOTTOM: 109.73,68.34 109.6,68.47 109.6,69.11 109.35,69.36 108.58,69.36 108.33,69.61 108.33,71.14 108.46,71.27 108.71,71.27 109.6,70.38 109.98,70.38 110.11,70.5 110.11,72.66 109.73,73.04 109.73,73.3 109.86,73.42 110.87,73.42 111,73.3 111,71.14 110.62,70.76 110.62,70.5 110.74,70.38 111.12,70.38 111.25,70.25 111.25,69.74 111.12,69.61 110.62,69.61 110.49,69.74 110.24,69.74 109.98,69.49 109.98,68.47 109.86,68.34
GND on BOTTOM: 121.92,29.61 121.79,29.74 121.79,30.12 121.92,30.24 122.43,30.24 122.68,30.5 124.84,30.5 125.09,30.24 125.48,30.24 125.6,30.12 125.6,29.74 125.48,29.61
GND on BOTTOM: 72.9,25.93 72.77,26.05 72.77,27.45 73.15,27.83 77.6,27.83 78.23,27.2 78.23,26.05 78.11,25.93 ; 9 cut-outs
GND on BOTTOM: 106.05,98.95 105.92,99.08 105.92,100.48 106.05,100.6 106.93,100.6 107.16,100.37 107.16,99.05 107.06,98.95
GND on BOTTOM: 134.49,89.43 133.88,90.04 133.88,90.97 135.38,92.47 135.38,92.86 135.51,92.98 135.76,92.98 136.02,92.73 136.02,90.93 136.06,90.88 136.06,89.71 135.93,89.59 135.58,89.59 135.43,89.43
GND on BOTTOM: 145.41,102 145.16,102.25 144.53,102.25 144.4,102.38 144.4,104.29 144.65,104.54 145.92,104.54 146.3,104.16 149.35,104.16 149.48,104.03 149.48,103.27 149.35,103.14 148.21,103.14 147.96,102.89 147.96,102.25 147.7,102 ; 3 cut-outs
GND on BOTTOM: 27.94,69.36 27.81,69.49 27.81,71.9 27.94,72.03 27.94,72.92 27.05,73.81 25.02,73.81 24.89,73.93 24.89,74.82 25.02,74.95 26.67,74.95 27.43,74.19 29.72,74.19 30.1,73.81 30.1,72.03 29.97,71.9 29.34,71.9 29.21,71.77 29.21,69.49 29.08,69.36 ; 2 cut-outs
GND on BOTTOM: 105.64,73.3 105.17,73.76 105.17,75.57 105.2,75.59 105.2,75.84 105.33,75.97 107.99,75.97 108.24,75.73 108.24,75.32 108.27,75.29 108.27,74.63 108.2,74.55 107.33,74.55 106.9,74.12 106.74,74.12 105.92,73.3
GND on BOTTOM: 115.19,45.23 114.17,46.25 114.17,48.02 114.3,48.15 115.06,48.15 115.19,48.02 115.19,47.14 114.68,46.63 114.68,46.37 115.57,45.48 115.57,45.36 115.44,45.23 ; 1 cut-out
GND on BOTTOM: 100.2,29.74 100.08,29.86 100.08,30.24 100.2,30.37 102.23,30.37 102.36,30.24 102.36,29.86 102.23,29.74
GND on BOTTOM: 73.28,17.54 73.15,17.67 73.15,18.43 73.53,18.81 79.88,18.81 80.01,18.69 80.01,17.93 79.63,17.54 ; 4 cut-outs
GND on BOTTOM: 37.97,68.98 37.72,69.23 35.43,69.23 35.31,69.36 35.31,69.87 35.43,70 35.94,70 36.07,70.12 36.07,70.63 35.94,70.76 35.31,70.76 35.18,70.88 35.18,72.66 35.31,72.79 35.69,72.79 36.45,72.03 37.97,72.03 38.1,71.9 38.1,71.77 38.48,71.39 38.73,71.39 38.86,71.27 38.86,69.11 38.73,68.98 ; 3 cut-outs
GND on L2SGND: outline of 187 points within 0.51,0.51 192.02,109.39 ; 7 cut-outs
GND on L3SGND: 104.11,7.59 113.21,7.59 113.56,7.23 113.56,5.35 113.23,5.02 113.23,2.41 112.85,2.02 102.77,2.02 101.45,3.35 101.45,4.92
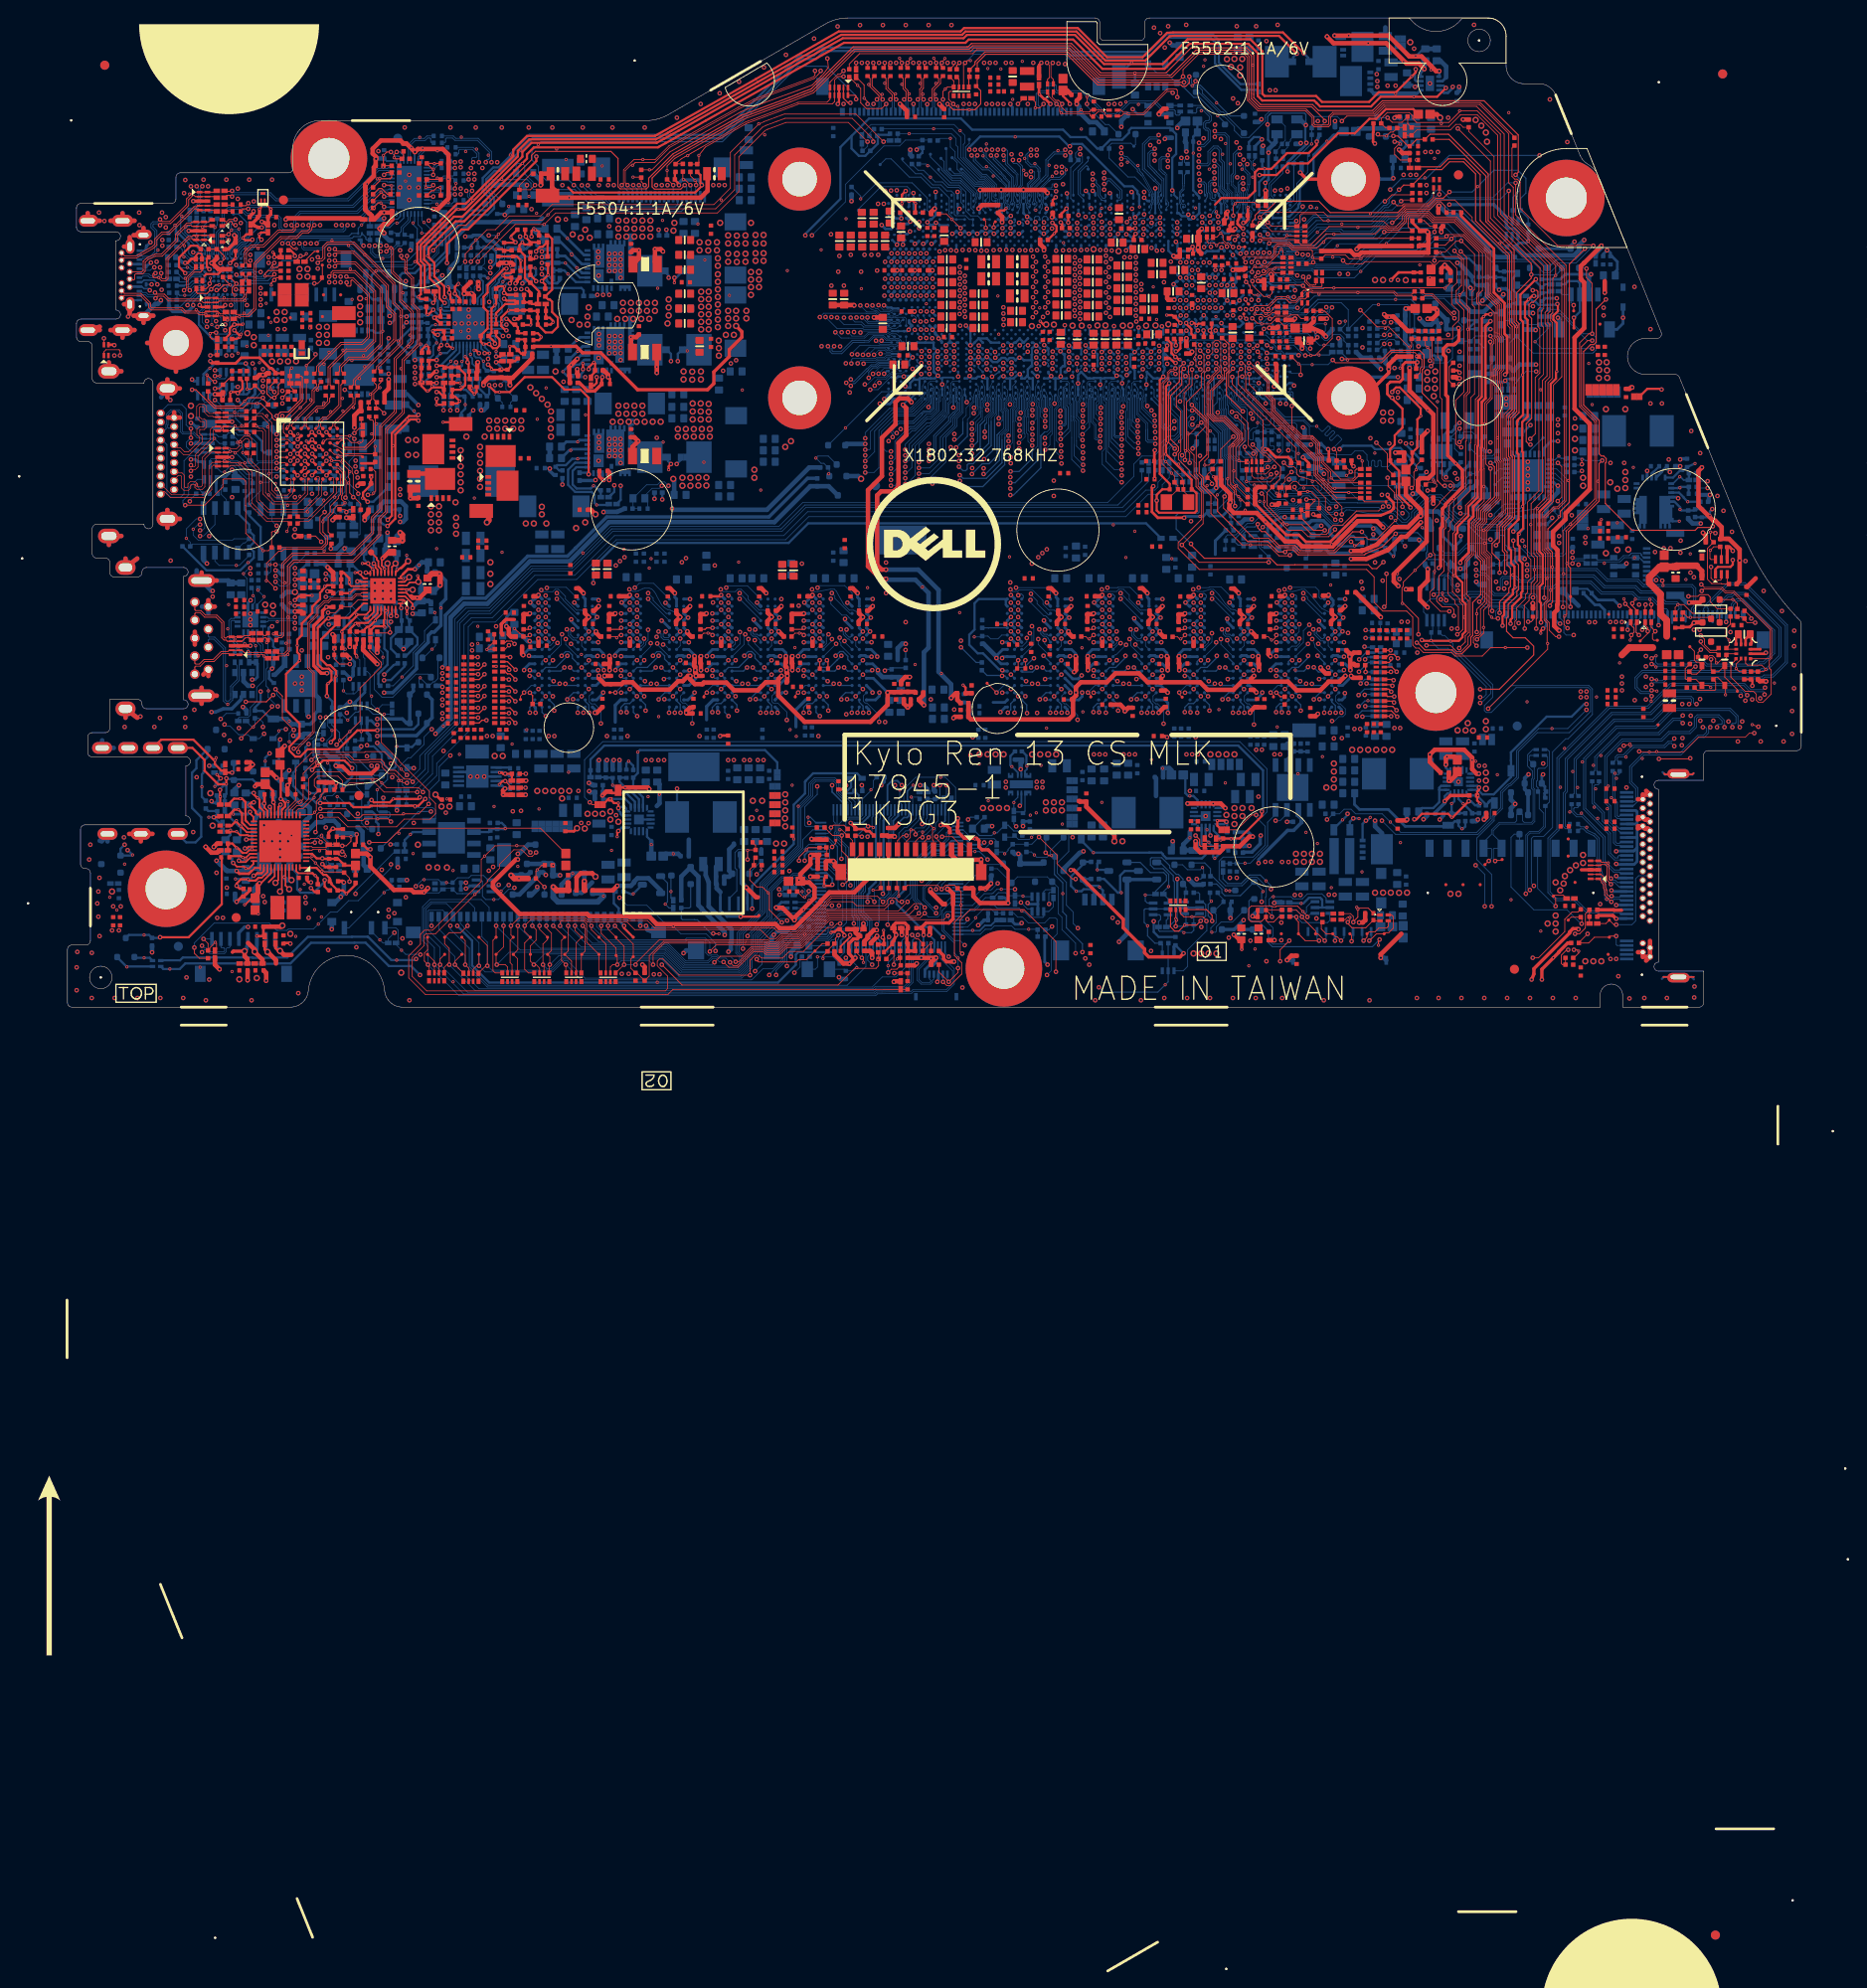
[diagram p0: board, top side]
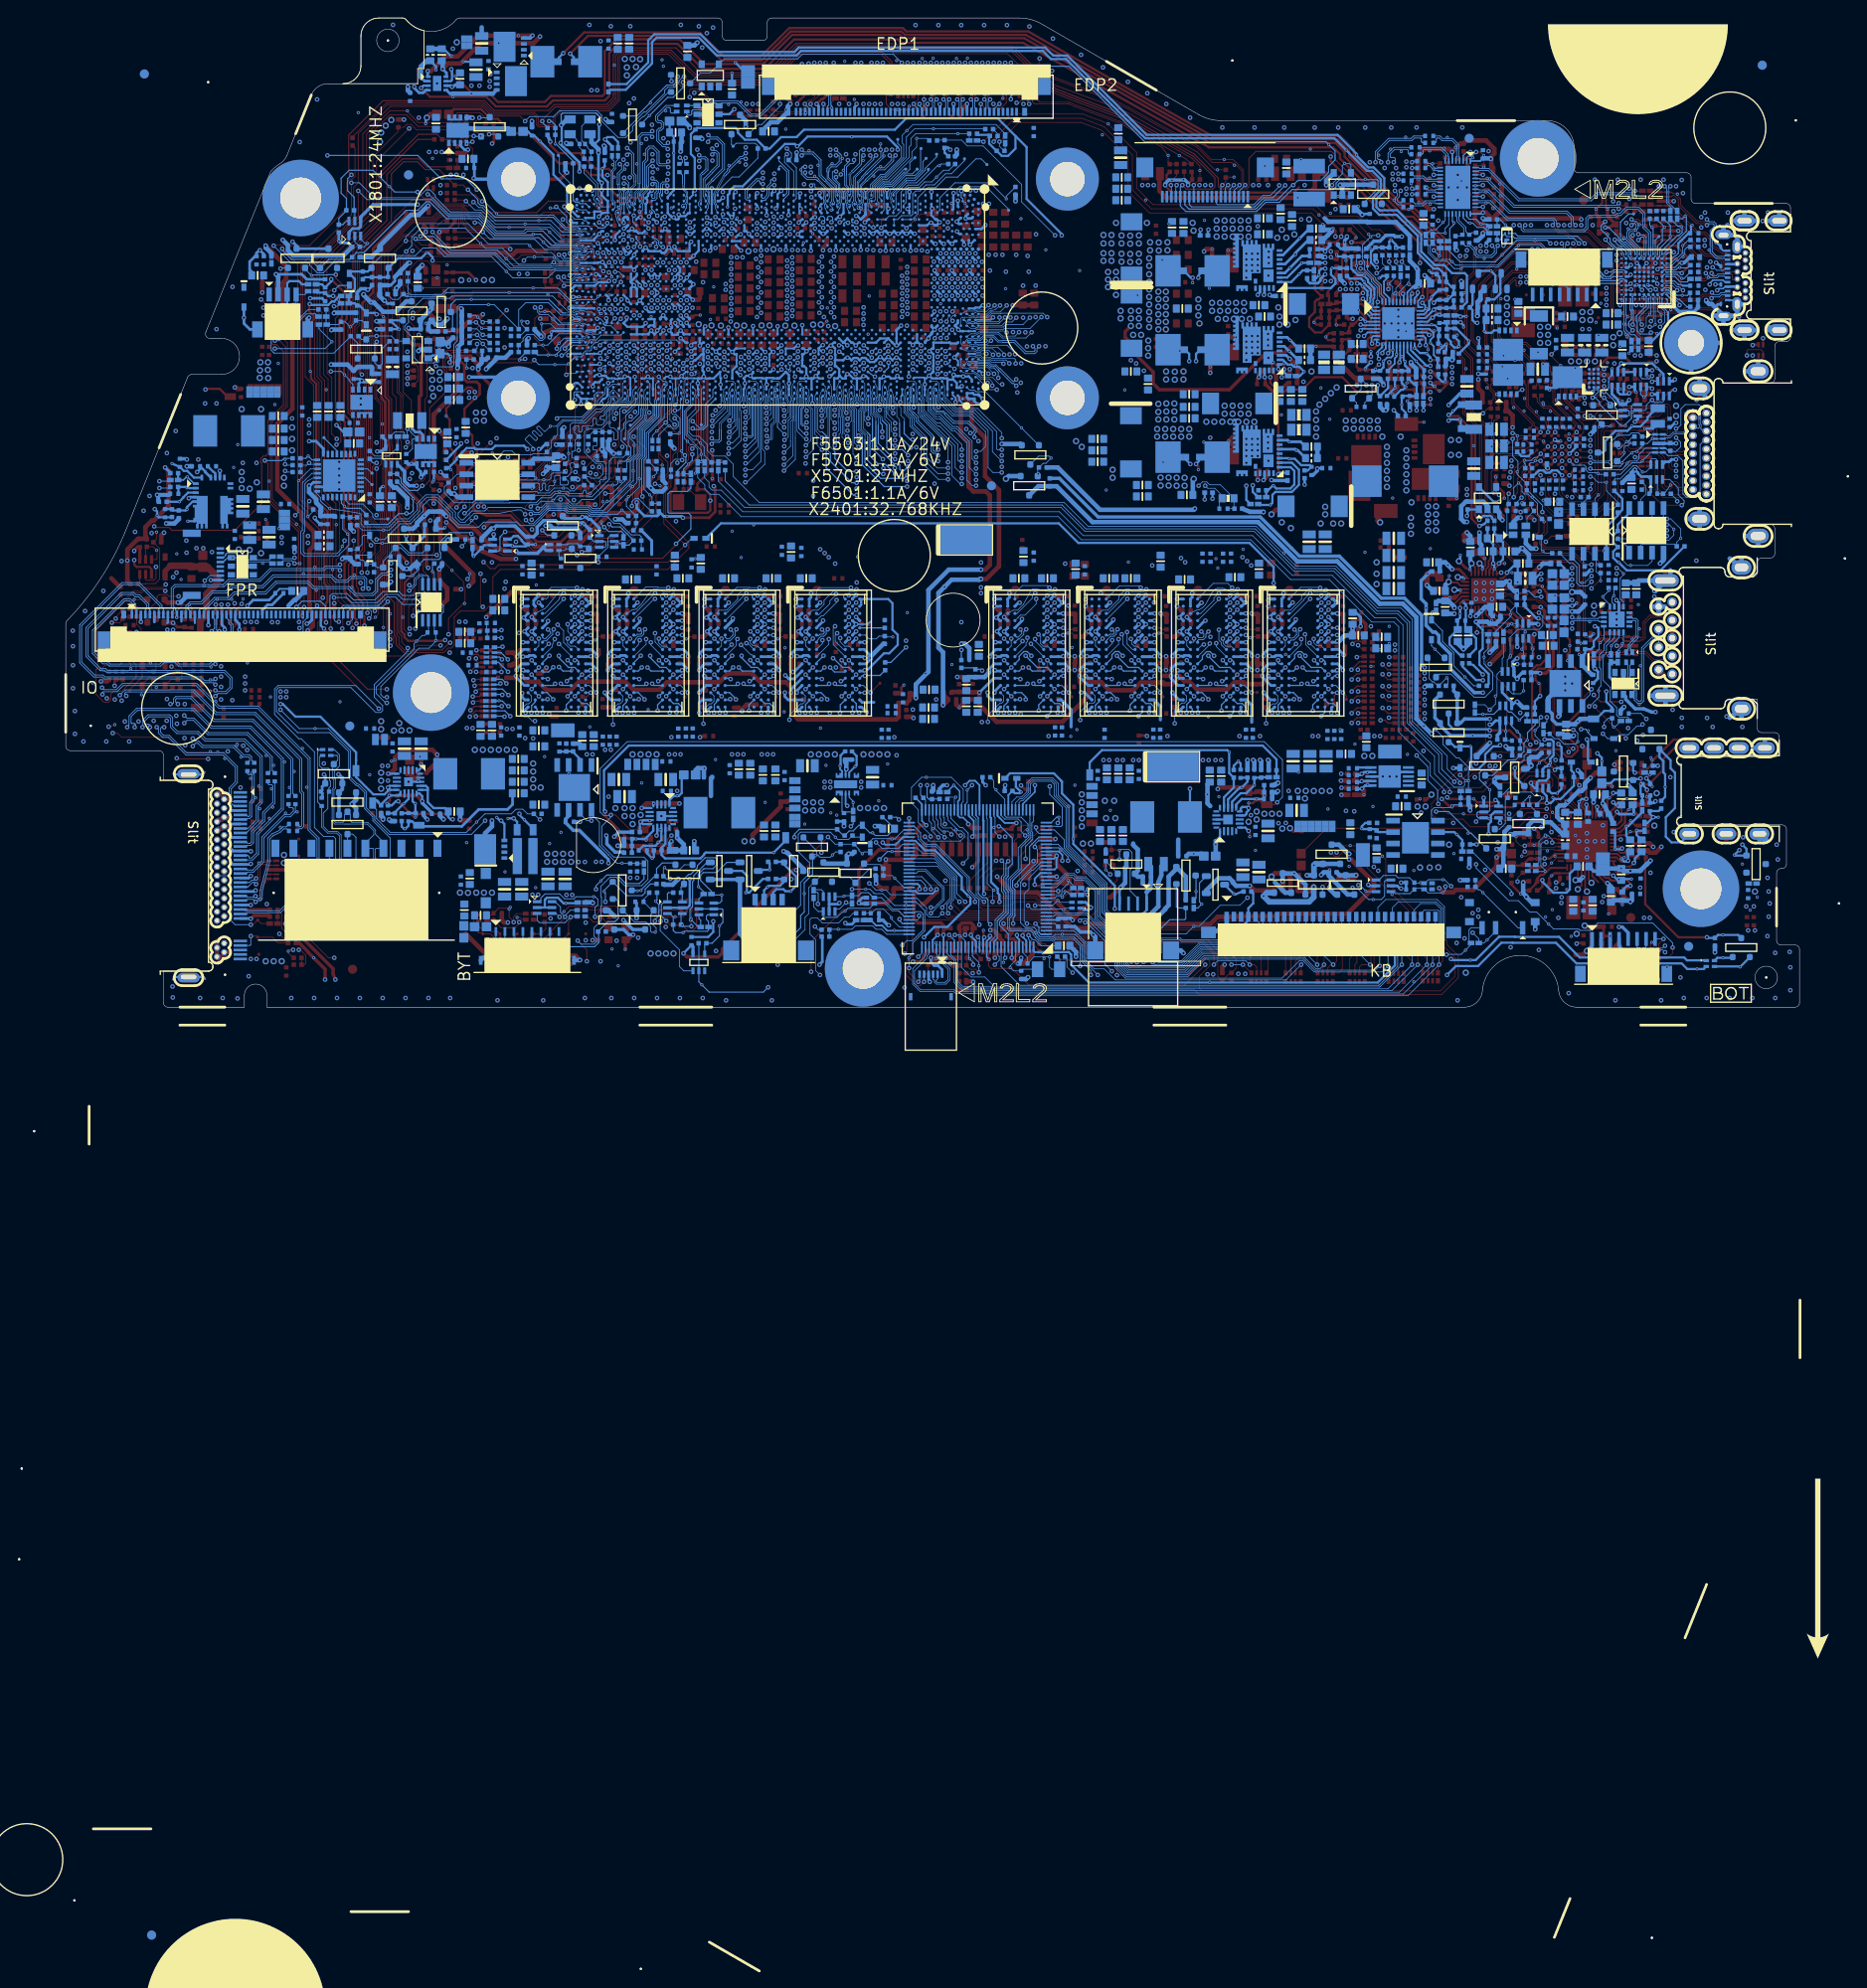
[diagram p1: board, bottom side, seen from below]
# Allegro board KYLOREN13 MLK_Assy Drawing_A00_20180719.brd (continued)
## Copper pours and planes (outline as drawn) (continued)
GND on L3SGND: 135.89,15.64 139.57,15.64 140.21,16.27 140.21,17.04 140.59,17.42 151.38,17.42 152.4,16.4 152.4,7.26 150.5,5.35 134.37,5.35 133.99,5.73 133.99,9.42 134.24,9.67 138.05,9.67 138.18,9.8 138.18,10.56 137.16,11.58 136.4,11.58 135.64,12.34 135.64,15.39
GND on L3SGND: outline of 388 points within 0.51,0.51 192.14,109.39 ; 1 cut-out
GND on L3SGND: 134.49,95.78 133.1,97.17 133.1,98.95 133.48,99.33 137.79,99.33 137.92,99.21 137.92,95.9 137.79,95.78
GND on L3SGND: 148.08,27.7 149.35,28.97 155.7,28.97 157.86,26.82 157.86,24.15 152.4,18.69 132.59,18.69 131.57,17.67 127.89,17.67 126.62,18.94 124.08,18.94 122.94,17.8 116.33,17.8 115.95,18.18 115.95,26.82 116.46,27.32 116.46,29.86 116.84,30.24 137.79,30.24 140.34,27.7
GND on L3SGND: 32.26,79.14 37.85,79.14 38.61,79.9 44.96,79.9 47.5,77.36 50.29,77.36 52.2,79.27 53.98,79.27 54.74,78.5 54.74,70.38 56.52,68.6 58.42,68.6 58.8,68.22 58.8,65.04 54.61,60.85 54.61,57.68 54.99,57.3 58.29,57.3 59.05,56.53 59.05,54.88 57.02,52.85 56.13,52.85 45.47,42.18 42.42,42.18 42.16,41.93 42.16,30.5 42.04,30.37 41.27,30.37 41.15,30.5 41.15,37.48 31.62,47.01 31.62,78.5
GND on L3SGND: 132.21,60.72 142.49,60.72 142.88,60.34 142.88,59.45 139.95,56.53 138.3,56.53 137.54,55.77 136.78,55.77 132.08,60.47 132.08,60.6
GND on L3SGND, L4SGND, L6: 56.26,19.7 56.26,20.47 57.66,21.86 58.8,21.86 61.59,24.66 74.55,24.66 75.31,23.89 75.31,18.56 74.42,17.67 60.96,17.67 59.18,19.45 56.52,19.45
GND on L3SGND, L4SGND, L6: 174.88,67.2 177.8,67.2 178.18,66.82 178.18,60.72 177.67,60.22 171.45,60.22 171.2,60.47 171.2,63.52
GND on L4SGND: 147.87,94.01 149.52,92.35 149.52,90.58 149.4,90.45 146.13,90.45 145.62,89.94 141.39,89.94 140.38,90.96 140.38,93.24 141.65,94.51 143.3,94.51 143.81,94.01
GND on L4SGND: outline of 290 points within 0.51,0.51 192.14,109.39 ; 5 cut-outs
GND on L4SGND: 135.08,95.65 135.04,95.69 134.58,95.69 133.22,97.05 133.22,98.95 133.48,99.21 137.54,99.21 137.92,98.82 137.92,95.9 137.67,95.65
GND on L4SGND: 132.84,24.66 117.09,24.66 115.95,23.51 115.95,18.18 116.33,17.8 122.94,17.8 125.09,19.96 129.67,19.96 131.32,21.61 132.59,21.61 133.22,22.24 133.22,24.28
GND on L4SGND: 60.45,67.2 65.79,67.2 66.29,66.69 66.29,60.6 65.41,59.71 60.83,59.71 59.82,60.72 59.82,66.57
GND on L4SGND: 59.56,87.52 59.56,81.43 60.2,80.79 65.02,80.79 65.41,81.17 65.41,87.52 65.02,87.9 59.94,87.9
GND on L4SGND: 60.71,79.01 67.18,79.01 67.44,78.76 67.44,72.92 65.79,71.27 60.83,71.27 59.82,72.28 59.82,78.12
GND on L5GND, L7GND: outline of 161 points within 0.51,0.51 192.14,109.39
GND on L6: 132.59,108.1 146.05,108.1 148.34,105.81 148.34,102.63 147.7,102 134.87,102 134.49,101.62 133.35,101.62 132.33,102.63 132.33,107.84
GND on L6: 60.07,87.78 65.15,87.78 65.41,87.52 65.41,85.87 64.9,85.36 60.33,85.36 59.82,85.87 59.82,87.52
GND on L6: 60.07,67.46 65.91,67.46 66.93,66.44 66.93,64.66 66.04,63.77 63.63,63.77 63.25,63.39 63.25,60.22 62.36,59.33 58.55,59.33 57.78,60.09 57.78,60.85 57.91,60.98 59.18,60.98 59.69,61.49 59.69,67.07
GND on L6: 59.69,84.09 61.98,84.09 62.23,83.84 62.23,80.66 61.85,80.28 59.94,80.28 59.56,80.66 59.56,83.97
GND on L6: 140.72,94.38 143.64,94.38 144.53,93.49 147.07,93.49 147.83,92.73 147.83,91.59 147.32,91.08 145.8,91.08 144.53,89.81 141.22,89.81 140.08,90.95 140.08,93.74
GND on L6: outline of 175 points within 0.51,0.51 192.14,109.39 ; 2 cut-outs
GND on L6: outline of 140 points within 1.51,31.88 114.19,109.39 ; 3 cut-outs
GND on L6: 135.05,95.65 135.03,95.67 134.47,95.67 133.1,97.05 133.1,98.82 133.5,99.23 137.59,99.23 137.92,98.9 137.92,95.9 137.67,95.65
GND on L6: 137.29,71.01 146.18,71.01 146.3,71.14 146.69,71.14 147.07,70.76 147.07,70.5 144.78,68.22 144.78,65.8 143.13,64.15 137.29,64.15 134.49,66.95 134.49,68.22
GND on L6: 61.47,78.5 66.29,78.5 66.8,79.01 67.31,79.01 67.56,78.76 67.56,72.92 66.04,71.39 60.96,71.39 59.94,72.41 59.94,76.98
GND on L6: 129.67,24.66 117.09,24.66 115.95,23.51 115.95,18.18 116.33,17.8 122.94,17.8 125.09,19.96 130.05,19.96 131.95,21.86 131.95,22.37
0D6V_PWR on BOTTOM: 41.66,25.44 41.48,25.62 41.48,26.48 41.54,26.55 41.54,26.7 44.07,29.23 45.21,29.23 45.34,29.1 45.34,27.5 45.24,27.4 44.27,27.4 44.09,27.22 44.09,26.54 43.99,26.43 42.72,26.43 42.7,26.41 42.7,25.85 42.77,25.77 44.04,25.77 44.09,25.72 44.09,25.47 44.07,25.44
0D6V_VREF_S0 on TOP: 43.48,30.51 42.8,31.18 42.8,38.5 45.47,41.17 46.86,41.17 46.99,41.04 46.99,39.52 47.24,39.26 47.8,39.26 47.92,39.13 47.92,31.39 48.18,31.14 99.36,31.14 99.74,31.52 143.13,31.52 143.63,32.02 144.15,32.02 144.4,32.28 144.4,41.17 144.65,41.42 149.22,41.42 149.35,41.29 149.35,40.79 149.1,40.53 146.43,40.53 145.92,40.02 145.92,32.02 146.3,31.64 146.3,31.26 146.05,31.01 144.15,31.01 143.64,30.51 ; 27 cut-outs
0D6V_VREF_S0 on BOTTOM: 45.95,27.3 45.72,27.53 45.72,29.23 45.85,29.36 49.61,29.36 50.27,28.69 50.27,27.7 49.86,27.3 ; 4 cut-outs
0D6V_VREF_S0 on BOTTOM: 142.57,30.55 142.37,30.75 141.99,30.75 141.86,30.88 141.86,31.64 142.11,31.9 145.54,31.9 145.67,32.02 145.67,40.53 145.49,40.71 145.49,42.03 145.64,42.18 148.08,42.18 148.21,42.06 148.21,40.02 148.08,39.9 148.08,39.26 147.96,39.13 147.7,39.13 147.31,38.74 147.31,36.99 146.79,36.47 146.79,32.17 147.07,31.9 147.07,31.01 146.81,30.75 144.07,30.75 143.87,30.55 ; 9 cut-outs
0D6V_VREF_S0 on BOTTOM: 44.96,39.13 44.7,39.39 44.7,41.8 45.34,42.44 46.35,42.44 46.48,42.31 46.48,39.26 46.35,39.13 ; 5 cut-outs
0D6V_VREF_S0 on L3SGND: 42.65,41.83 45.09,41.83 45.42,41.5 45.42,39.69 44.65,38.93 44.65,31.34 45.69,30.29 49.5,30.29 49.96,29.84 49.96,28.59 48.79,27.42 43.79,27.42 42.24,28.97 42.24,41.42
1D0V_PWR on TOP: 169.42,65.8 168.28,66.95 168.28,68.09 168.66,68.47 172.34,68.47 172.47,68.34 174.12,68.34 174.24,68.22 174.24,66.57 173.48,65.8 ; 2 cut-outs
1D0V_PWR on BOTTOM: 169.54,61 169.29,61.26 169.29,64.92 169.16,65.04 169.16,66.19 168.5,66.85 168.5,68.04 168.68,68.22 172.31,68.22 172.95,67.58 172.97,67.58 173.61,66.95 173.61,65.8 173.3,65.5 173.3,61.23 173.08,61 ; 6 cut-outs
1D0V_S5 on TOP: 168.28,68.85 168.15,68.98 168.15,69.49 168.66,70 168.66,72.79 168.78,72.92 171.07,72.92 171.96,72.03 171.96,70.76 172.59,70.12 172.59,68.98 172.47,68.85 ; 3 cut-outs
1D0V_S5 on TOP: 123.87,81.43 123.36,81.94 123.36,82.83 123.49,82.96 124,82.96 124.12,83.08 124.12,83.59 124.25,83.72 124.63,83.72 124.76,83.59 124.76,83.46 125.01,83.21 125.39,83.21 126.28,82.32 126.92,82.32 127.42,82.83 129.2,82.83 129.33,82.7 129.33,82.19 128.69,81.56 127.3,81.56 127.17,81.69 125.01,81.69 124.76,81.43 ; 4 cut-outs
1D0V_S5 on TOP: 147.83,79.9 147.45,80.28 147.45,80.92 147.7,81.17 152.65,81.17 153.03,80.79 153.03,80.28 152.65,79.9 ; 4 cut-outs
1D0V_S5 on TOP: 122.22,77.37 121.96,77.62 121.96,78 122.09,78.13 122.98,78.13 123.36,78.51 123.36,78.77 123.11,79.02 123.11,80.29 123.36,80.54 127.68,80.54 127.93,80.29 127.93,79.91 127.81,79.78 127.81,77.62 127.68,77.5 125.52,77.5 125.39,77.62 125.39,78.64 125.27,78.77 124.88,78.77 124.38,78.26 124.08,78.26 123.42,77.6 123.34,77.6 123.11,77.37 ; 6 cut-outs
1D0V_S5 on BOTTOM: 124.25,76.61 123.87,76.99 123.23,76.99 122.79,77.43 122.79,78.58 123.36,79.15 123.36,81.05 123.11,81.31 123.11,82.58 123.87,83.34 125.52,83.34 125.65,83.21 125.65,82.19 125.9,81.94 127.3,81.94 127.68,82.32 127.68,83.21 127.81,83.34 129.2,83.34 129.33,83.21 129.33,82.7 128.95,82.32 128.95,81.43 127.93,80.42 127.93,80.04 128.31,79.65 128.31,77.62 128.19,77.5 127.04,77.5 126.15,76.61
1D0V_S5 on BOTTOM: 153.67,66.31 153.16,66.82 149.86,66.82 149.73,66.95 149.73,70.5 150.24,71.01 152.4,71.01 154.31,69.11 159.38,69.11 159.64,68.85 159.64,68.22 159.77,68.09 161.04,68.09 161.29,68.34 161.29,69.36 162.18,70.25 163.45,70.25 163.96,70.76 163.96,71.06 165.18,72.28 171.32,72.28 172.21,71.39 172.21,70.5 172.59,70.12 172.59,68.6 172.47,68.47 168.4,68.47 168.15,68.22 168.15,66.57 167.89,66.31 ; 10 cut-outs
1D0V_S5 on BOTTOM: 148.08,92.22 147.83,92.47 147.83,93.49 148.21,93.87 148.21,94.63 149.22,95.65 149.22,96.41 148.97,96.67 147.96,96.67 147.83,96.79 147.83,98.19 147.96,98.32 150.24,98.32 150.5,98.06 150.5,92.35 150.37,92.22 ; 4 cut-outs
1D0V_S5 on L2SGND: 120.14,90.44 120.14,90.95 121.92,92.73 121.92,95.27 123.95,97.3 123.95,97.81 123.57,98.19 122.94,98.19 122.81,98.06 122.81,96.92 121.28,95.4 121.28,93.62 119.13,91.46 119.13,90.44 119.25,90.32 120.02,90.32
1D0V_S5 on L2SGND: 150.75,70.88 153.8,70.88 154.05,70.63 154.05,68.85 154.18,68.73 156.84,68.73 157.23,69.11 162.18,69.11 165.61,72.54 171.07,72.54 171.7,71.9 171.7,70.12 166.75,65.17 153.16,65.17 150.5,67.84 150.5,70.63
1D0V_S5 on L3SGND: 144.65,82.45 140.63,82.45 139.62,83.46 126.03,83.46 125.77,83.21 125.77,81.43 125.27,80.92 123.61,80.92 123.11,81.43 123.11,84.48 124.63,86 126.92,86 128.69,87.78 129.33,87.78 130.6,89.05 135.43,89.05 137.97,86.51 140.84,86.51 140.85,86.51 141.15,86.51 141.28,86.63 144.53,86.63 147.57,89.68 147.57,92.47 148.46,93.36 152.27,93.36 152.65,92.98 152.65,89.45 150.11,86.91 150.11,85.74 151.45,84.41 151.45,81.49 150.11,80.16 147.7,80.16 147.45,80.41 147.45,82.06 147.07,82.44 144.66,82.44
1D0V_S5 on L4SGND: 147.29,71.27 145.46,71.27 144.19,72.54 144.19,73.05 143.3,73.94 138.98,73.94 138.6,74.32 134.41,74.32 133.77,74.96 131.74,74.96 131.11,75.59 128.19,75.59 127.81,75.97 126.15,75.97 124.88,77.24 122.6,77.24 122.09,77.75 122.09,82.07 123.74,83.72 128.78,83.72 129.67,82.82 133.73,82.82 136.14,80.41 142.02,80.41 145.2,83.59 150.67,83.59 151.94,82.32 151.94,73.04 152.45,72.54 152.45,71.09 152.65,70.88 152.65,69.94 154.69,67.91 160.76,67.91 160.99,67.68 160.99,66.79 160.81,66.62 151.94,66.62
1D0V_VCCPRIM_MPHY on TOP: 144.91,80.16 144.65,80.41 144.65,82.19 145.16,82.7 151.76,82.7 152.15,82.31 152.15,81.68 152.02,81.55 151.13,81.55 150.75,81.93 147.32,81.93 146.69,81.3 146.69,80.54 146.3,80.16 ; 1 cut-out
1D0V_VCCPRIM_MPHY on BOTTOM: 152.15,79.27 150.24,81.17 146.81,81.17 146.69,81.04 146.69,80.66 146.3,80.28 144.91,80.28 144.78,80.41 144.78,81.43 145.92,82.57 151.76,82.57 152.65,81.68 152.65,80.66 152.91,80.41 153.92,80.41 154.18,80.16 154.18,79.39 154.05,79.27
1D0V_VCCPRIM_MPHY on BOTTOM: 125.9,82.07 125.77,82.19 125.77,83.21 125.9,83.34 127.3,83.34 127.42,83.21 127.42,82.19 127.3,82.07
1D0V_VCCPRIM_MPHY on L3SGND: 125.9,80.8 125.9,82.96 126.28,83.34 139.24,83.34 140.38,82.19 144.4,82.19 144.41,82.19 146.43,82.19 146.69,81.93 146.69,79.39 146.18,78.89 138.47,78.89 137.08,80.29 136.06,80.29 135.68,79.91 130.35,79.91 130.09,80.16 130.09,80.54 129.84,80.8 129.33,80.8 129.08,80.54 126.15,80.54
1D2V_HDMI on TOP: 27.56,46.37 27.43,46.5 27.43,47.52 27.69,47.77 28.83,47.77 28.96,47.64 28.96,47.26 28.07,46.37 ; 1 cut-out
1D2V_HDMI on BOTTOM: 25.78,42.56 25.65,42.69 25.65,43.33 25.91,43.58 26.8,43.58 27.05,43.83 27.05,48.53 27.18,48.66 28.19,48.66 28.32,48.53 28.32,48.02 28.57,47.77 28.83,47.77 28.96,47.64 28.96,46.75 28.32,46.12 28.32,43.07 28.19,42.94 27.05,42.94 26.67,42.56 ; 4 cut-outs
1D2V_HDMI_FB on BOTTOM: 25.15,37.74 25.02,37.86 25.02,39.26 24.89,39.39 24.64,39.39 24.38,39.64 24.38,39.9 24,40.28 23.44,40.28 23.34,40.38 23.34,40.81 23.44,40.91 25.53,40.91 25.78,40.66 25.78,37.86 25.65,37.74 ; 2 cut-outs
1D2V_HDMI_R on BOTTOM: 26.54,37.74 26.42,37.86 26.42,40.15 25.53,41.04 23.39,41.04 23.24,41.19 23.24,42.06 23.62,42.44 24.77,42.44 25.02,42.18 26.67,42.18 26.92,41.93 27.58,41.93 27.81,41.7 27.81,39.77 28.32,39.26 28.32,37.86 28.19,37.74 ; 4 cut-outs
1D2V_HDMI_VDD on BOTTOM: 27.08,60.37 26.85,60.6 26.85,60.85 26.99,60.99 27.05,60.99 27.17,61.11 27.3,61.11 27.6,61.4 27.6,63.05 28.07,63.52 29.79,63.52 29.87,63.44 29.87,62.98 30.1,62.76 30.1,61.49 29.97,61.36 29.46,61.36 28.96,61.87 28.57,61.87 28.35,61.64 28.35,61 28.19,60.85 27.81,60.85 27.69,60.72 27.69,60.6 27.46,60.37 ; 2 cut-outs
1D2V_HDMI_VDDA on BOTTOM: 24.77,58.57 24.64,58.69 24.64,59.96 24.77,60.09 25.27,60.09 26.16,60.98 26.54,60.98 26.67,60.85 26.67,60.47 26.42,60.22 26.16,60.22 25.15,59.2 25.15,58.69 25.02,58.57
1D2V_HDMI_VDDRX on BOTTOM: 25.4,63.52 25.15,63.77 25.15,64.66 25.27,64.79 29.26,64.79 29.84,64.2 29.84,63.77 29.72,63.65 28.57,63.65 28.45,63.77 28.45,64.08 28.3,64.23 27.58,64.23 27.48,64.13 27.48,63.75 27.25,63.52 ; 3 cut-outs
1D2V_HDMI_VDDTX on BOTTOM: 26.16,58.06 26.04,58.18 26.04,58.57 26.16,58.69 26.67,58.69 26.89,58.91 26.89,59.29 27,59.4 28.96,59.4 28.99,59.37 28.96,59.33 29.08,59.2 29.08,58.69 28.96,58.57 28.96,58.18 28.83,58.06 ; 2 cut-outs
1D2V_HDMI_VIN on TOP: 25.12,34.33 24.56,34.89 24.56,36.62 25.1,37.15 26.54,37.15 26.7,37 26.7,34.74 26.29,34.33
1D2V_S3 on TOP: 50.56,31.39 50.18,31.78 50.18,38.14 51.05,39.01 51.05,42.82 50.93,42.94 49.78,42.94 49.28,43.45 49.28,44.45 50.18,45.36 50.43,45.6 50.43,45.62 53.34,48.53 53.47,48.53 53.51,48.49 61.17,48.49 65.01,52.32 85.29,52.32 86.28,51.33 86.53,51.33 88.14,49.73 88.14,48.53 89.96,46.71 89.96,40.74 89.45,40.23 86.96,40.23 86.56,40.64 85.34,40.64 84.14,39.45 84.14,39.12 80.94,35.92 80.94,34.27 81.58,33.63 83.61,33.63 84.12,33.12 84.12,31.6 83.91,31.39 ; 68 cut-outs
1D2V_S3 on TOP: outline of 90 points within 103.93,32.16 144.27,72.44 ; 69 cut-outs
1D2V_S3 on BOTTOM: 41.73,21.4 41.12,22.01 41.12,22.75 42.67,24.3 42.67,25.21 42.75,25.29 44.09,25.29 44.15,25.24 44.15,21.61 43.94,21.4 ; 4 cut-outs
1D2V_S3 on BOTTOM: 120.78,45.1 120.65,45.23 120.65,46.25 119.89,47.01 119.38,47.01 119.25,47.14 119.25,48.15 119.38,48.28 119.89,48.28 121.92,46.25 121.92,45.23 121.79,45.1
1D2V_S3 on BOTTOM: 113.79,44.34 113.03,45.1 113.03,48.02 113.16,48.15 113.79,48.15 113.92,48.02 113.92,46.12 114.68,45.36 114.68,44.47 114.55,44.34
1D2V_S3 on BOTTOM: 142.62,23.39 142.37,23.64 142.37,29.1 142.75,29.48 147.32,29.48 147.7,29.1 147.7,23.77 147.32,23.39 ; 8 cut-outs
1D2V_S3 on BOTTOM: 78.61,45.1 78.36,45.36 78.36,45.99 77.34,47.01 77.22,47.01 76.96,47.26 76.96,48.02 77.09,48.15 77.72,48.15 77.85,48.02 77.85,47.26 79.5,45.61 79.5,45.23 79.38,45.1
1D2V_S3 on BOTTOM: 95.76,31.51 95.5,31.77 95.5,34.44 95.54,34.47 95.54,35.77 95.76,35.98 96.57,35.98 96.65,35.91 96.65,31.77 96.39,31.51
1D2V_S3 on BOTTOM: 71.63,44.34 71.37,44.6 71.37,46.5 72.26,47.39 72.52,47.39 73.28,48.15 73.91,48.15 74.04,48.02 74.04,47.26 73.66,46.88 72.64,46.88 72.39,46.63 72.39,44.47 72.26,44.34
1D2V_S3 on BOTTOM: 131.06,44.98 130.81,45.23 130.81,46.37 129.92,47.26 129.92,47.9 130.05,48.02 130.81,48.02 132.08,46.75 132.08,45.1 131.95,44.98 ; 1 cut-out
1D2V_S3 on BOTTOM: 68.45,45.1 68.33,45.23 68.33,47.9 68.45,48.02 69.22,48.02 69.34,47.9 69.34,45.23 69.22,45.1 ; 1 cut-out
1D2V_S3 on BOTTOM: 151.26,60.98 150.88,61.36 150.11,61.36 148.84,62.63 148.84,63.52 148.97,63.65 149.48,63.65 149.86,63.26 151.13,63.26 151.38,63.52 152.4,63.52 152.53,63.39 152.53,62.76 152.78,62.5 153.8,62.5 153.8,60.98 ; 3 cut-outs
1D2V_S3 on BOTTOM: 88.65,44.98 88.39,45.23 88.39,45.99 87,47.39 87,48.02 87.12,48.15 87.63,48.15 87.88,47.9 87.88,47.39 89.66,45.61 89.66,45.1 89.53,44.98
1D2V_S3 on BOTTOM: 110.74,45.1 110.62,45.23 110.62,48.15 110.74,48.28 111.38,48.28 111.63,48.02 111.63,45.61 111.76,45.48 111.76,45.23 111.63,45.1
1D2V_S3 on BOTTOM: 61.09,44.34 60.71,44.72 60.71,47.26 61.72,48.28 62.36,48.28 62.48,48.15 62.48,47.39 62.36,47.26 61.72,47.26 61.34,46.88 61.34,45.99 61.85,45.48 62.1,45.48 62.23,45.36 62.23,45.23 62.1,45.1 62.1,44.47 61.98,44.34
1D2V_S3 on BOTTOM: 90.55,39.9 90.17,40.28 88.77,40.28 88.65,40.4 88.65,40.79 88.9,41.04 91.57,41.04 91.82,40.79 91.82,40.02 91.69,39.9 ; 1 cut-out
1D2V_S3 on BOTTOM: 90.55,33.55 90.17,33.93 88.77,33.93 88.65,34.05 88.65,34.31 88.9,34.56 89.41,34.56 89.92,35.07 90.42,35.07 90.81,34.69 91.41,34.69 91.67,34.94 91.67,35.4 91.97,35.71 92.91,35.71 93.09,35.53 93.09,33.8 92.84,33.55 ; 1 cut-out
1D2V_S3 on BOTTOM: 81.03,44.34 80.9,44.47 80.9,46.25 82.42,47.77 82.42,48.02 82.55,48.15 83.19,48.15 83.31,48.02 83.31,47.26 82.8,46.75 82.55,46.75 82.42,46.63 82.42,44.34 ; 1 cut-out
1D2V_S3 on BOTTOM: 144.15,42.31 143.76,42.69 141.48,42.69 141.22,42.94 141.22,43.83 141.35,43.96 142.75,43.96 143.38,44.6 143.38,45.89 143.48,45.99 144.25,45.99 144.27,45.97 144.27,43.58 144.91,42.94 145.16,42.94 145.29,42.82 145.29,42.44 145.16,42.31 ; 1 cut-out
1D2V_S3 on BOTTOM: 123.95,44.47 123.19,45.23 123.19,46.88 122.94,47.14 122.94,48.02 123.06,48.15 123.83,48.15 124.08,47.9 124.08,46.12 124.84,45.36 124.84,44.47 ; 1 cut-out
1D2V_S3 on L2SGND: 41.76,21.1 42.67,21.1 52.58,31.01 52.58,32.78 52.2,33.17 50.8,33.17 50.67,33.04 50.67,31.51 48.64,29.48 46.48,29.48 41.66,24.66 41.66,23.51 41.2,23.06 41.2,21.66
1D2V_S3 on L3SGND: 73.15,67.08 73.15,61.74 72.52,61.11 72.52,58.44 71.63,57.55 61.38,57.55 59.2,55.37 59.2,54.77 57.13,52.7 56.53,52.7 45.57,41.74 45.57,39.68 44.87,38.98 44.87,31.52 45.83,30.57 137.98,30.57 140.46,28.09 147.45,28.09 148.51,29.14 148.51,39.78 144.11,44.18 144.15,44.21 144.15,48.28 127.53,64.89 127.53,67.23 125.14,69.62 125.09,69.62 124.85,69.87 123.62,69.87 123.23,70.26 123.23,71.78 123.22,71.8 123.22,73.53 122.93,73.81 109.14,73.81 108.63,74.32 91.36,74.32 89.58,76.1 82.17,76.1
1D2V_VCCSFR_OC on BOTTOM: 151.66,59.17 151.54,59.3 151.54,59.61 151.42,59.72 151.37,59.72 150.75,60.34 150.11,60.34 149.99,60.47 149.99,60.98 150.11,61.11 150.62,61.11 151.13,60.6 153.03,60.6 153.16,60.47 153.16,59.96 153.09,59.89 152.3,59.89 152.15,59.73 152.15,59.28 152.04,59.17
1D8V_PWR on BOTTOM: 44.6,16.48 44.37,16.71 44.37,18.66 44.55,18.84 46.48,18.84 46.71,19.07 47.19,19.07 47.35,19.22 48.03,19.22 48.51,19.7 50.42,19.7 50.67,19.45 50.67,18.43 49.4,17.16 46.56,17.16 45.87,16.48 ; 7 cut-outs
1D8V_S5 on BOTTOM: 30.73,20.59 30.35,20.97 30.35,21.61 30.73,21.99 31.11,21.99 31.24,22.12 31.24,23.46 31.34,23.56 31.8,23.56 31.88,23.49 31.88,23.01 32,22.88 32.26,22.88 32.51,22.62 32.51,20.72 32.38,20.59 ; 2 cut-outs
1D8V_S5 on BOTTOM: 48.13,15.39 47.88,15.64 47.88,16.66 48.01,16.78 50.16,16.78 50.42,16.53 50.42,15.77 50.04,15.39
1D8V_VCCPRIM on TOP: 129.2,78.79 129.09,78.91 129.09,80.02 129.08,80.04 129.08,81.31 129.15,81.38 130.32,81.38 130.4,81.31 130.4,80.49 130.85,80.04 130.85,79.15 130.59,78.88 130.1,78.88 130.02,78.79 ; 3 cut-outs
1D8V_VCCPRIM on BOTTOM: 120.52,57.68 120.4,57.8 120.4,58.57 120.65,58.82 120.65,59.84 120.78,59.96 121.03,59.96 121.16,59.84 121.16,58.57 120.9,58.31 120.9,57.8 120.78,57.68
1D8V_VCCPRIM on L3SGND: 129.33,80.67 129.71,80.67 129.96,80.42 129.96,80.04 130.22,79.78 135.93,79.78 136.19,80.04 136.95,80.04 138.35,78.64 145.46,78.64 145.47,78.63 149.35,78.63 151.38,80.66 155.83,80.66 156.21,80.28 156.21,79.77 154.56,78.12 153.67,78.12 153.1,77.55 153.1,76.15 151.01,74.07 148.51,74.07 148,74.57 136.95,74.57 133.9,77.62 130.09,77.62 129.08,78.64 129.08,80.42
2D5V_S3 on BOTTOM: outline of 299 points within 50.08,29.74 143.3,50.56 ; 68 cut-outs
3D3V_1D8V_AVDD on BOTTOM: 26.06,12.97 25.79,13.24 25.79,14.99 25.4,15.39 25.4,18.31 25.63,18.53 26.67,18.53 27.28,17.93 28.45,17.93 28.57,17.8 28.57,16.4 27.91,15.74 27.91,13.71 27.18,12.97 ; 3 cut-outs
3D3V_CAMERA_S0 on TOP: 104.65,99.97 104.39,100.22 104.39,103.02 104.52,103.14 107.19,103.14 107.44,102.89 107.44,101.62 107.31,101.49 105.54,101.49 105.28,101.24 105.28,100.22 105.03,99.97 ; 2 cut-outs
3D3V_FLASH on BOTTOM: 18.77,54.5 18.59,54.68 18.59,55.97 17.27,57.3 17.27,57.68 17.4,57.8 18.16,57.8 18.29,57.93 19.05,57.93 19.3,57.68 19.81,57.68 19.94,57.55 19.94,57.3 19.3,56.66 19.3,54.63 19.18,54.5 ; 3 cut-outs
3D3V_FPR_VDD on TOP: 172.9,48.86 172.85,48.91 172.85,49.93 172.81,49.97 172.81,51.45 172.83,51.47 172.83,52.58 172.97,52.72 173.99,52.72 175.01,51.71 180.09,51.71 180.21,51.83 181.86,51.83 182.12,51.58 182.12,50.46 181.97,50.31 181.97,49.61 181.92,49.57 176.19,49.57 175.5,48.88 173.83,48.88 173.81,48.86 ; 1 cut-out
3D3V_FPR_VDD on BOTTOM: 175.13,50.31 175.01,50.44 175.01,51.58 175.13,51.71 175.9,51.71 176.66,50.95 176.66,50.56 176.4,50.31
3D3V_GSEN2 on TOP: 184.91,40.79 184.66,41.04 184.66,41.17 184.53,41.29 184.53,42.44 184.91,42.82 185.29,42.82 185.55,42.56 185.55,42.06 185.67,41.93 185.93,41.93 186.18,41.67 186.18,40.91 186.06,40.79 ; 1 cut-out
3D3V_GSEN2 on TOP: 178.31,47.14 178.18,47.26 178.18,47.9 178.31,48.02 179.45,48.02 179.96,48.53 180.47,48.53 180.59,48.41 180.59,48.28 180.97,47.9 180.97,47.26 180.85,47.14
3D3V_GSEN2 on L4SGND: 189.1,41.42 189.1,37.74 187.83,36.47 187.83,35.83 187.45,35.45 186.31,35.45 186.06,35.71 186.06,36.47 187.71,38.12 187.71,40.79 187.32,41.17 184.66,41.17 184.15,41.67 184.15,43.45 179.83,47.77 179.83,48.41 180.59,49.17 181.36,49.17
3D3V_HDMI_VDD on BOTTOM: 29.21,57.93 29.08,58.06 29.08,58.57 29.21,58.69 29.21,59.2 29.34,59.33 30.61,59.33 30.73,59.2 30.73,58.95 30.35,58.57 29.97,58.57 29.84,58.44 29.84,58.18 29.59,57.93
3D3V_HDMI_VDD on BOTTOM: 23.75,61.99 23.62,62.12 23.62,63.77 23.37,64.03 23.37,64.79 23.5,64.92 24.13,64.92 24.23,64.81 24.61,64.81 25.02,64.41 25.02,63.77 24.89,63.65 24.51,63.65 24.38,63.52 24.38,62.25 24.13,61.99 ; 1 cut-out
3D3V_HDMI_VDD on BOTTOM: 20.95,48.79 20.95,51.33 21.46,51.83 27.18,51.83 27.43,52.09 27.43,53.99 27.05,54.37 26.42,54.37 26.16,54.63 26.16,56.41 25.4,57.17 24.77,57.17 24.64,57.3 24.64,58.31 24.77,58.44 25.15,58.44 25.27,58.57 25.27,59.2 25.53,59.45 26.42,59.45 26.67,59.2 26.67,58.95 26.54,58.82 26.04,58.82 25.91,58.69 25.91,57.42 26.04,57.3 26.29,57.3 27.3,56.28 27.3,55.64 27.43,55.52 27.94,55.52 28.07,55.39 28.07,53.99 28.32,53.74 28.32,51.33 27.94,50.95 25.91,50.95 25.53,51.33 21.84,51.33 21.72,51.2 21.72,49.8 22.1,49.42 22.23,49.42 22.48,49.17 22.48,48.91 22.35,48.79 ; 3 cut-outs
3D3V_LCDVDD_R on BOTTOM: 121.79,101.62 121.67,101.75 121.67,102.89 121.41,103.14 119.76,103.14 119.38,102.76 119.38,102 119.25,101.87 116.08,101.87 115.95,102 115.95,103.14 116.08,103.27 117.98,103.27 118.24,103.52 122.17,103.52 122.56,103.14 122.56,101.75 122.43,101.62 ; 3 cut-outs
3D3V_LCDVDD_S0 on TOP: 101.85,99.97 101.66,100.16 101.66,101.88 101.6,101.95 101.6,105.17 101.73,105.3 103.12,105.3 103.38,105.05 103.38,104.79 103,104.41 103,101.24 103.63,100.6 103.63,100.22 103.38,99.97 ; 4 cut-outs
3D3V_LCDVDD_S0 on BOTTOM: 101.42,98.95 101.33,99.05 101.33,100.58 101.6,100.86 103.5,100.86 103.63,100.73 103.63,100.22 103.5,100.09 103.25,100.09 103.14,99.98 103.14,99.08 103.01,98.95
3D3V_LCDVDD_S0 on BOTTOM: 102.36,103.02 101.47,103.9 101.47,105.43 101.6,105.56 103.25,105.56 103.38,105.43 103.38,104.67 103.63,104.41 111.89,104.41 112.39,104.92 117.6,104.92 117.86,104.67 117.86,103.78 117.73,103.65 113.54,103.65 112.9,103.02
3D3V_MUX on BOTTOM: 40.51,87.52 39.62,88.41 39.62,88.92 40.77,88.92 40.89,88.79 42.16,88.79 42.29,88.66 42.29,87.65 42.16,87.52 ; 1 cut-out
3D3V_S0 on TOP: 126.36,86.12 126.24,86.25 126.24,86.34 126.28,86.39 126.28,88.92 126.66,89.3 127.42,89.3 127.55,89.17 127.55,86.64 127.53,86.61 127.53,86.14 127.51,86.12
3D3V_S0 on TOP: 54.86,90.95 54.74,91.08 54.74,93.87 55.63,94.76 57.4,94.76 57.53,94.63 57.53,92.09 57.28,91.84 56.13,91.84 55.88,91.59 55.88,91.2 55.63,90.95 ; 1 cut-out
3D3V_S0 on TOP: 131.32,6.11 131.06,6.37 131.06,7.89 131.19,8.02 132.72,8.02 132.84,7.89 132.84,6.5 132.46,6.11 ; 1 cut-out
3D3V_S0 on TOP: 172.03,35.68 171.78,35.93 171.78,38.7 172.34,39.26 172.97,39.26 173.3,38.93 173.3,35.81 173.18,35.68
3D3V_S0 on TOP: 177.19,38.58 176.91,38.85 176.91,39.18 176.76,39.34 175.92,39.34 175.84,39.41 175.84,40.4 175.9,40.45 177.16,40.45 177.32,40.61 177.32,41.65 177.42,41.75 178.05,41.75 178.23,41.57 178.23,40.56 178.33,40.45 178.33,38.8 178.1,38.58 ; 1 cut-out
3D3V_S0 on TOP: 105.92,103.52 105.79,103.65 105.79,105.05 105.8,105.06 105.8,105.31 105.89,105.4 107.21,105.4 107.57,105.05 107.57,104.79 107.44,104.67 107.44,103.78 107.19,103.52
3D3V_S0 on TOP: 150.24,89.43 149.99,89.68 149.99,91.59 151.23,92.83 152.48,92.83 152.73,92.58 152.73,91.56 151.54,91.56 151.38,91.41 151.38,89.68 151.13,89.43 ; 3 cut-outs
3D3V_S0 on TOP: 144.4,56.28 144.27,56.41 144.27,60.98 143.76,61.49 142.37,61.49 141.1,62.76 139.19,62.76 137.41,64.53 137.41,71.52 137.79,71.9 138.56,71.9 140.97,74.31 140.97,77.11 140.34,77.74 138.69,77.74 138.46,77.51 138.46,77.48 137.97,76.99 137.46,76.99 137.33,76.86 135.04,76.86 135.02,76.89 135.02,78 135.04,78.03 135.68,78.03 135.91,78.26 136.57,78.26 136.87,78.56 137.79,78.56 138.24,79.01 146.94,79.01 149.86,76.09 152.78,76.09 153.67,75.2 153.67,74.57 153.54,74.44 153.03,74.44 152.78,74.69 149.86,74.69 149.73,74.82 149.73,75.2 149.48,75.46 149.22,75.46 147.32,77.36 144.53,77.36 144.02,77.87 143.43,77.87 143.13,77.56 143.13,73.55 142.37,72.79 141.22,72.79 138.81,70.38 138.81,66.19 141.1,63.9 143.89,63.9 146.3,61.49 146.3,57.93 147.07,57.17 147.07,56.66 146.81,56.41 146.18,56.41 146.05,56.28 ; 4 cut-outs
3D3V_S0 on BOTTOM: 106.81,25.42 106.68,25.55 106.68,26.18 106.81,26.31 106.81,28.34 106.93,28.47 110.11,28.47 110.24,28.34 110.24,25.93 109.73,25.42
3D3V_S0 on BOTTOM: 26.21,51.91 26.16,51.96 25.02,51.96 24.89,52.09 24.89,52.6 25.02,52.72 25.4,52.72 25.78,53.1 25.78,53.49 26.29,53.99 27.18,53.99 27.3,53.87 27.3,52.06 27.15,51.91 ; 1 cut-out
3D3V_S0 on BOTTOM: 172.21,35.58 170.94,36.85 158.12,36.85 152.91,42.06 152.91,43.58 152.4,44.09 151,44.09 150.88,44.21 150.88,44.47 151,44.6 154.69,44.6 156.21,43.07 156.21,40.15 157.99,38.37 172.85,38.37 173.61,37.61 173.61,35.71 173.48,35.58
3D3V_S0 on BOTTOM: 40.01,12.85 39.75,13.1 39.75,13.89 39.9,14.04 41.07,14.04 41.15,13.96 41.15,12.9 41.1,12.85
3D3V_S0 on BOTTOM: 26.26,9.11 26.01,9.37 26.01,9.67 26.02,9.68 26.02,9.91 26.92,10.81 26.92,11.83 29.21,14.12 29.21,14.24 29.84,14.88 29.84,16.15 29.72,16.27 29.59,16.27 29.08,16.78 29.08,18.69 28.19,19.58 28.19,19.96 28.45,20.21 28.96,20.21 29.08,20.08 29.08,19.58 29.34,19.32 29.59,19.32 30.02,18.89 30.02,17.19 30.18,17.04 30.48,17.04 31.5,16.02 32.38,16.02 32.51,15.89 32.51,14.88 32,14.37 30.61,14.37 30.1,13.86 30.1,12.72 28.7,11.32 28.7,11.07 26.76,9.12 26.45,9.12 26.44,9.11 ; 1 cut-out
3D3V_S0 on BOTTOM: 164.34,50.56 164.21,50.69 164.21,51.71 164.34,51.83 165.86,51.83 166.12,51.58 166.12,50.69 165.99,50.56
3D3V_S0 on BOTTOM: 125.6,1.92 124.71,2.81 124.71,6.37 125.22,6.88 129.49,6.88 130.43,7.82 131.93,7.82 132.21,8.1 132.21,8.65 132.31,8.76 132.82,8.76 132.97,8.6 132.97,7.92 134.01,6.88 144.78,6.88 145.41,7.51 145.41,9.16 145.69,9.44 146.28,9.44 146.46,9.26 146.46,8.63 146.94,8.15 159.89,8.15 164.21,3.83 164.21,2.94 163.19,1.92 ; 2 cut-outs
3D3V_S0 on L2SGND: 113.26,27.48 113.26,18.64 113.23,18.61 124.56,7.28 128.3,7.28 128.83,6.75 128.83,4.59 128.42,4.18 121.26,4.18 106.22,19.22 106.22,22.88 104.93,24.17 104.93,26.46 106.93,28.47 112.27,28.47
3D3V_S0 on L3SGND: 151,85.74 151.26,85.74 153.8,83.2 153.8,82.19 154.69,81.3 156.34,81.3 156.84,80.79 156.84,79.14 153.03,75.33 153.03,74.44 153.29,74.19 158.62,74.19 159.89,75.46 159.89,78 159.26,78.63 159.26,79.27 160.27,80.28 160.27,83.08 155.96,87.39 151.51,87.39 150.88,86.76 150.88,85.87
3D3V_S0 on L3SGND: 148.08,59.84 149.73,61.49 154.69,61.49 155.32,60.85 155.32,57.8 154.18,56.66 150.5,56.66 149.61,55.77 149.61,52.72 154.94,47.39 154.94,45.87 155.19,45.61 155.19,44.09 162.69,36.59 162.69,20.47 160.15,17.93 160.15,8.02 154.18,2.05 124.46,2.05 122.43,4.08 122.43,5.99 123.83,7.38 129.92,7.38 132.21,5.1 150.5,5.1 152.78,7.38 152.78,14.62 152.84,14.69 152.84,15.45 158.37,20.97 158.37,33.04 150.88,40.53 149.22,40.53 144.53,45.23 144.53,50.31 142.62,52.22 142.62,58.31 144.15,59.84
3D3V_S0 on L3SGND: 165.48,51.96 165.99,51.96 166.88,51.07 166.88,49.04 170.94,44.98 170.94,39.26 172.97,37.23 172.97,35.71 172.85,35.58 171.07,35.58 169.54,37.1 169.54,44.47 165.23,48.79 165.23,51.71
3D3V_S0 on L3SGND: 106.55,106.32 106.55,104.41 107.7,103.27 125.35,103.27 125.65,102.96 125.65,101.95 131.95,95.65 131.95,94.63 132.84,93.74 138.3,93.74 139.32,94.76 139.32,96.28 138.94,96.67 138.56,96.67 138.18,96.28 138.18,95.9 137.79,95.52 134.62,95.52 132.33,97.81 132.33,97.83 132.28,97.83 129.13,100.98 129.13,103.02 126.59,105.56 112.01,105.56 111,106.57 106.81,106.57
3D3V_S0 on L4SGND: 144.27,95.52 145.67,94.13 148.21,94.13 149.86,92.47 149.86,86.51 150.62,85.74 151.51,85.74 151.64,85.87 151.64,92.73 146.94,97.43 138.68,97.43 138.3,97.05 138.3,96.03 138.81,95.52
3D3V_S5 on TOP: 80.01,12.46 79.38,13.1 79.38,13.23 79.25,13.35 78.87,13.35 78.74,13.48 78.74,14.24 79.12,14.62 79.12,17.67 79.76,17.67 82.3,20.21 83.44,20.21 83.57,20.08 83.57,19.45 83.31,19.2 82.68,19.2 81.03,17.54 81.03,15.13 80.52,14.62 80.52,12.59 80.39,12.46 ; 7 cut-outs
3D3V_S5 on TOP: 130.97,11.54 130.97,10.72 128.08,7.83 128.07,7.83 126.99,6.75 126.95,6.75 126.57,6.37 120.27,6.37 117.61,9.02 117.61,9.91 111.9,15.63 111.52,15.63 108.46,18.69 108.46,19.2 108.33,19.32 108.33,22.88 108.58,23.13 111.51,23.13 112.18,22.46 112.59,22.46 112.85,22.19 112.85,21.79 115.82,18.81 115.82,18.05 116.46,17.42 132.84,17.42 134.62,15.64 159,15.64 162.43,19.07 162.43,31.39 166.88,35.83 171.2,35.83 171.45,35.58 171.45,33.27 172.2,32.52 172.21,32.53 176.15,32.53 177.33,33.71 178.5,33.71 179.55,34.77 180.85,34.77 181.13,35.04 183.51,35.04 184.07,34.49 184.48,34.49 184.91,34.05 188.85,34.05 189.36,34.56 189.36,41.8 188.34,42.82 188.09,42.82 187.32,43.58 187.26,43.52 187.26,43.64 184.78,46.12 184.78,47.26 184.91,47.39 185.93,47.39 186.18,47.14 186.18,46.5 186.56,46.12 187.32,46.12 191.39,42.06 191.39,33.93 189.61,32.15 181.99,32.15 180.21,30.37 173.35,30.37 166.24,23.26 166.24,15.89 164.87,14.52 164.87,11.58 161.9,8.6 150.67,8.6 148.59,10.69 145.1,10.69 144.4,11.39 135.96,11.39 135.29,12.06 131.48,12.06 ; 13 cut-outs
3D3V_S5 on TOP: 36.58,3.19 36.45,3.32 36.45,8.27 40.39,12.21 40.39,14.24 39.62,15 39.62,16.15 39.75,16.27 42.8,16.27 43.31,15.77 43.31,12.46 39.37,8.53 39.37,7.26 37.72,5.61 37.72,3.45 37.47,3.19
3D3V_S5 on BOTTOM: 154.43,54.86 154.43,54.88 154.31,55.01 154.31,55.87 154.56,56.13 156.69,56.13 156.92,55.9 156.92,55.14 156.64,54.86
3D3V_S5 on BOTTOM: 132.97,15.64 132.72,15.89 132.72,16.4 135.64,19.32 136.4,19.32 137.41,20.34 137.41,21.1 137.67,21.35 137.67,22.75 137.41,23.01 134.37,23.01 134.11,23.26 134.11,25.67 134.37,25.93 138.43,25.93 139.32,25.04 139.32,23.51 140.08,22.75 140.08,21.23 139.57,20.72 139.57,20.08 137.16,17.67 136.53,17.67 134.49,15.64 ; 3 cut-outs
3D3V_S5 on BOTTOM: 154.43,71.01 154.18,71.27 154.18,73.3 154.31,73.42 156.84,73.42 156.97,73.3 156.97,71.52 156.72,71.27 155.45,71.27 155.19,71.01 ; 2 cut-outs
3D3V_S5 on BOTTOM: 166.24,42.56 166.12,42.69 166.12,44.09 166.24,44.21 166.88,44.21 167,44.09 167,42.82 166.75,42.56
3D3V_S5 on BOTTOM: 164.34,51.96 164.21,52.09 164.21,52.98 164.34,53.1 165.61,53.1 165.99,52.72 165.99,52.09 165.86,51.96
3D3V_S5 on BOTTOM: 39.78,14.8 39.32,15.26 39.32,17.21 39.45,17.34 40.87,17.34 41.17,17.65 41.17,20.62 41.27,20.72 44.09,20.72 44.22,20.59 44.22,16.2 44.53,15.89 44.53,15 44.32,14.8 ; 1 cut-out
3D3V_S5 on BOTTOM: 109.6,19.96 109.03,20.53 107.25,20.53 106.68,21.1 106.68,23.89 106.81,24.02 108.58,24.02 110.11,25.55 111.38,25.55 111.51,25.42 111.51,19.96
3D3V_S5 on BOTTOM: 157.48,95.52 153.67,99.33 145.16,99.33 144.91,99.08 138.56,99.08 138.3,99.33 132.82,99.33 132.33,98.85 131.8,98.85 131.19,99.46 130.56,99.46 130.43,99.33 129.29,99.33 125.86,102.76 125.86,103.78 125.48,104.16 123.7,104.16 123.32,103.78 121.41,103.78 120.9,104.29 120.9,105.68 121.28,106.06 123.06,106.06 123.57,106.57 127,106.57 127.7,105.87 127.7,104.29 127.76,104.29 130.43,101.62 131.83,101.62 132.21,101.24 132.84,101.24 132.97,101.36 138.43,101.36 138.94,100.86 144.02,100.86 144.27,101.11 156.08,101.11 158.88,98.32 158.88,96.16 158.24,95.52 ; 7 cut-outs
3D3V_S5 on L3SGND: 40.39,8.15 75.31,8.15 79.25,12.08 81.53,12.08 81.6,12.15 87.95,12.15 97.03,21.23 110.62,21.23 111.25,21.86 111.25,25.29 110.49,26.05 87.71,26.05 83.01,21.35 83.01,19.12 81.05,17.16 79.88,17.16 74.42,11.7 49.28,11.7 43.81,17.16 38.99,17.16 38.93,17.1 38.86,17.16 38.23,17.16 36.83,18.56 35.43,18.56 35.18,18.31 35.18,13.35
3D3V_S5 on L3SGND: 155.07,70.5 155.17,70.5 155.37,70.3 155.37,69.06 154.97,68.65 154.97,61.64 155.7,60.9 155.7,58.06 154.05,56.41 150.5,56.41 149.73,55.64 149.73,53.36 153.67,49.42 155.19,49.42 155.83,48.79 155.83,43.83 162.94,36.72 162.94,27.2 163.7,26.43 164.72,26.43 165.1,26.82 165.1,30.24 169.29,34.44 169.29,44.47 164.97,48.79 164.97,51.71 165.35,52.09 165.86,52.09 165.99,52.22 165.99,52.47 165.61,52.85 164.08,52.85 159.77,57.17 159.77,68.34 158.88,69.23 158.88,71.52 156.97,73.42 154.18,73.42 153.8,73.04 153.8,71.77
3D3V_S5 on L4SGND: 156.64,99.13 158.34,97.43 158.34,86.61 161.76,83.19 161.76,81.16 162.15,80.76 162.15,76.8 162.61,76.35 163.04,76.35 163.45,75.94 163.45,72.92 161.16,70.63 154.94,70.63 154.37,71.2 154.37,73.49 155.75,74.87 155.75,84.52 154.03,86.25 154.03,98.49 154.66,99.13
3D3V_S5 on L4SGND: 15.24,78.5 15.49,78.25 15.49,73.68 16.13,73.04 16.13,71.39 15.88,71.14 15.88,67.46 17.91,65.42 17.91,36.21 18.67,35.45 20.83,35.45 20.95,35.58 21.72,35.58 21.97,35.32 21.97,30.75 22.1,30.63 22.1,29.23 21.59,28.72 21.59,27.83 22.23,27.2 24.64,27.2 27.3,24.53 27.3,19.32 27.05,19.07 27.05,13.1 30.1,10.05 32.89,10.05 37.21,5.73 37.21,4.72 37.72,4.21 37.72,3.45 37.59,3.32 36.83,3.32 35.69,4.46 35.69,4.97 33.66,7 32.38,7 31.88,7.51 28.7,7.51 25.4,10.81 25.4,23.01 22.61,25.8 20.83,25.8 19.68,26.94 19.68,30.88 16.51,34.05 16.51,65.17 13.59,68.09 13.59,80.54 15.24,82.19 20.19,82.19 20.45,81.93 20.45,81.17 20.07,80.79 15.49,80.79 15.24,80.54
3D3V_S5_KBC on TOP: 40.01,1.92 39.75,2.18 39.75,3.19 39.88,3.32 63.37,3.32 63.75,2.94 63.75,2.69 63.88,2.56 64.52,2.56 64.77,2.81 64.77,3.83 64.9,3.96 65.91,3.96 66.29,3.57 66.29,2.05 66.17,1.92 ; 2 cut-outs
3D3V_S5_KBC on L3SGND: 64.39,3.96 64.39,2.05 64.9,1.54 94.49,1.54 96.9,3.96 96.9,5.73 96.52,6.11 94.23,6.11 93.6,5.48 93.6,3.7 93.22,3.32 67.31,3.32 66.42,4.21 64.64,4.21
3D3V_S5_PCH on TOP: 137.29,84.85 137.16,84.98 137.16,87.62 137.19,87.62 137.44,87.88 138.33,87.88 138.56,87.65 138.56,85.49 137.92,84.85
3D3V_S5_PCH on TOP: 134.47,80.38 134.34,80.51 134.34,81.22 134.39,81.27 135.61,81.27 135.64,81.3 135.64,83.46 135.76,83.58 136.85,83.58 137.25,83.18 137.25,82.27 137.36,82.17 138.05,82.17 138.57,82.7 140.57,82.7 141.1,82.17 142.44,82.17 142.56,82.04 142.56,81.33 142.44,81.2 138.6,81.2 138.47,81.33 137.28,81.33 137,81.61 136.45,81.61 136.26,81.43 136.25,81.43 136.14,81.32 136.14,80.51 136.02,80.38
3D3V_S5_PCH on BOTTOM: 154.69,69.74 154.31,70.12 154.31,70.63 154.43,70.76 157.1,70.76 157.23,70.63 157.23,69.87 157.1,69.74
3D3V_S5_PCH on L3SGND: 144.02,62.88 144.27,62.63 145.41,62.63 148.21,65.42 148.21,73.3 148.97,74.06 152.4,74.06 153.29,73.17 153.29,72.15 155.19,70.25 155.19,68.98 154.8,68.59 154.8,65.54 152.27,63.01 149.22,63.01 147.07,60.85 132.08,60.85 131.44,61.49 131.44,61.99 132.33,62.88
3D3V_S5_PCH on L4SGND: 137.03,87.65 137.03,85.11 141.1,81.04 142.24,81.04 145.29,84.09 151.26,84.09 152.15,83.2 152.15,73.04 152.53,72.66 152.53,71.14 152.65,71.01 152.65,70.38 153.67,69.36 154.69,69.36 155.07,69.74 155.07,70.38 154.18,71.27 154.18,75.84 153.67,76.35 153.67,76.73 154.81,77.87 154.81,81.68 155.32,82.19 155.32,82.82 152.78,85.36 140.84,85.36 138.3,87.9 137.29,87.9
3D3V_SEN_S0 on TOP: 58.04,90.95 57.78,91.2 57.78,94.51 58.04,94.76 58.93,94.76 59.56,94.13 59.56,91.2 59.31,90.95 ; 3 cut-outs
3D3V_SEN_S0 on BOTTOM: 60.71,89.43 59.75,90.38 58.86,90.38 57.28,91.97 56.52,91.97 56.39,92.09 56.39,92.88 56.49,92.98 57.53,92.98 58.55,91.97 59.31,91.97 59.69,91.59 59.69,91.2 59.94,90.95 61.21,90.95 61.47,90.7 61.47,89.55 61.34,89.43
3D3V_SSD on TOP: 167.26,4.08 167,4.34 167,4.97 167.13,5.1 167.77,5.1 167.89,5.23 167.89,5.61 168.28,5.99 168.28,6.37 168.78,6.88 169.8,6.88 170.31,7.38 172.09,7.38 172.47,7.77 172.47,18.81 171.58,19.7 171.58,25.93 171.96,26.31 175.13,26.31 175.77,25.67 175.77,24.28 176.28,23.77 176.28,5.48 174.88,4.08 ; 8 cut-outs
3D3V_SSD on BOTTOM: 165.1,3.57 160.4,8.27 147.19,8.27 147.18,8.29 147.03,8.29 146.76,8.55 146.76,10.64 147.07,10.94 162.05,10.94 165.23,7.77 170.18,7.77 171.07,6.88 171.07,4.46 170.69,4.08 169.54,4.08 169.04,3.57 ; 4 cut-outs
3D3V_TP_VDD on TOP: 134.75,7.13 134.62,7.26 134.62,7.64 134.24,8.02 132.97,8.02 132.72,8.27 130.05,8.27 129.79,8.53 129.79,9.16 130.68,10.05 130.81,10.05 131.06,9.8 131.06,9.54 131.32,9.29 134.24,9.29 134.49,9.54 135,9.54 135.25,9.29 135.25,7.38 135,7.13 ; 3 cut-outs
3D3V_TP_VDD on TOP: 140.39,9.34 140.21,9.52 140.21,9.54 139.8,9.95 139.27,9.95 139.06,9.75 139.06,9.64 138.96,9.54 138.51,9.54 138.43,9.62 138.43,11.02 138.56,11.14 141.02,11.14 141.1,11.07 141.1,9.44 141,9.34 ; 2 cut-outs
3D3V_TP_VDD on BOTTOM: 134.75,7.13 134.19,7.69 134.19,11.02 134.32,11.14 135.25,11.14 135.38,11.02 135.38,9.39 135.86,8.91 138.05,8.91 138.18,8.78 138.18,7.38 137.92,7.13
3D3V_TPAN_VDD on TOP: 72.14,90.82 72.01,90.95 72.01,93.24 72.26,93.49 73.15,93.49 73.28,93.36 73.28,91.08 73.03,90.82
3D3V_TPAN_VDD on BOTTOM: 70.99,89.05 70.66,89.38 70.66,90.57 70.79,90.7 71.75,90.7 72.14,91.08 72.14,91.46 72.26,91.59 73.56,91.59 73.91,91.94 73.91,92.6 74.17,92.86 74.78,92.86 75.11,92.52 75.11,89.27 74.88,89.05 ; 2 cut-outs
3D3V_TPM_VHIO on BOTTOM: 162.46,50.61 162.33,50.74 162.33,54.86 162.48,55.01 162.97,55.01 163.17,54.81 163.17,53.38 163.25,53.31 163.65,53.31 163.93,53.03 163.93,50.82 163.73,50.61 ; 2 cut-outs
3D3V_TPM_VHIO on BOTTOM: 159.51,60.6 159.26,60.85 159.26,62.12 159.12,62.26 158.03,62.26 157.73,62.55 157.73,63.52 157.86,63.65 159.13,63.65 159.51,63.26 160.27,63.26 160.4,63.14 160.4,62.25 160.15,61.99 160.15,60.98 160.27,60.85 160.27,60.72 160.15,60.6 ; 1 cut-out
3D3V_TPM_VSB on BOTTOM: 155.85,56.36 155.75,56.46 155.75,57.22 156.01,57.47 160.15,57.47 160.17,57.45 160.17,57.17 159.61,56.61 158.47,56.61 158.22,56.36 ; 5 cut-outs
3D3V_VCCDSW on BOTTOM: 126.24,60.34 125.48,61.11 125.48,61.74 126.24,62.5 127.64,62.5 127.76,62.38 127.76,61.61 127.38,61.23 127.38,60.6 127.13,60.34 ; 1 cut-out
3D3V_VCCPRIM on TOP: 136.65,72.15 136.16,72.64 135.65,72.64 135.4,72.9 135.4,72.92 135.25,73.06 135.25,73.55 135.38,73.68 135.53,73.68 135.76,73.91 135.76,74.31 135.65,74.42 132.28,74.42 131.82,74.88 128.01,74.88 127.04,75.84 127.04,75.86 126.66,76.24 123.88,76.24 123.36,76.76 123.36,77.24 124.12,78 124.5,78 125.14,77.37 128.44,77.37 128.82,77.75 129.84,77.75 129.96,77.62 129.96,77.37 130.73,76.61 130.73,76.2 130.78,76.15 131.79,76.15 132.11,75.83 132.44,75.83 133.09,75.18 135.58,75.18 136.02,75.62 136.02,75.84 136.14,75.96 136.78,75.96 136.91,75.84 136.91,74.95 136.74,74.78 136.39,74.78 136.26,74.65 136.26,73.61 136.92,72.95 136.92,72.92 137.16,72.68 137.16,72.28 137.03,72.15 ; 9 cut-outs
3D3V_VCCPRIM on BOTTOM: 128.44,76.23 128.31,76.35 128.31,77.37 128.44,77.5 129.84,77.5 129.96,77.37 129.96,76.35 129.84,76.23
3D3V_WLAN on TOP: 177.37,34.18 177.14,34.41 177.14,35.32 177.24,35.43 177.85,35.43 178.13,35.71 178.13,38.35 178.49,38.7 178.49,40.51 178.36,40.63 178.36,41.55 178.64,41.83 180.04,41.83 180.39,42.18 182.25,42.18 183.01,41.42 183.01,40.28 182.88,40.15 182.25,40.15 182.12,40.28 182.12,41.17 181.86,41.42 180.85,40.4 180.19,40.4 180.04,40.25 180.04,38.68 179.98,38.63 179.98,38.32 179.55,37.89 179.55,36.04 179.76,35.83 180.19,35.83 180.29,35.73 180.29,35.25 180.01,34.97 179.5,34.97 178.71,34.18 ; 8 cut-outs
3D3V_WLAN on BOTTOM: 167.79,42.49 167.64,42.64 167.64,44.47 167.89,44.72 168.91,44.72 169.54,44.09 169.93,44.09 169.93,42.94 170,42.87 170,42.64 169.85,42.49
3D3V_WLAN on L4SGND: 168.78,43.33 168.78,40.79 169.93,39.64 181.36,39.64 181.86,40.15 181.86,41.93 180.09,43.71 169.16,43.71
+DC_IN on TOP: 31.11,74.31 30.99,74.44 30.99,78.5 31.75,79.27 32.51,79.27 32.89,78.89 32.89,74.69 32.51,74.31
+DC_IN on BOTTOM: 30.48,74.82 30.48,77.49 30.73,77.74 31.75,77.74 31.88,77.87 31.88,79.9 32.38,80.41 32.64,80.41 32.89,80.16 32.89,79.14 34.04,78 34.04,75.96 33.78,75.71 33.15,75.71 32.89,75.46 32.89,74.95 32.77,74.82 ; 5 cut-outs
+DC_IN_C on TOP: 27.56,74.31 26.67,75.2 26.67,77.23 28.07,78.63 28.07,79.14 28.96,80.03 30.48,80.03 30.86,79.65 30.86,74.69 30.48,74.31 ; 3 cut-outs
+DC_IN_C on BOTTOM: 27.69,74.31 26.04,75.96 26.04,77.62 26.42,78 27.05,78 27.43,78.38 27.43,80.03 29.97,80.03 30.23,79.77 30.23,75.2 29.34,74.31 ; 2 cut-outs
+SDC_IN on TOP: 22.99,66.69 22.86,66.82 22.86,67.2 22.99,67.33 24.13,67.33 24.26,67.46 24.26,67.71 24.38,67.84 25.4,67.84 25.53,67.71 25.53,67.46 24.77,66.69 ; 1 cut-out
+SDC_IN on BOTTOM: 29.98,65.16 29.46,65.68 25.53,65.68 25.02,66.19 22.73,66.19 22.61,66.31 22.61,67.2 22.73,67.33 25.15,67.33 25.27,67.46 25.27,68.22 27.18,68.22 27.56,68.6 30.1,68.6 31.11,67.58 31.75,67.58 31.88,67.71 31.88,68.47 33.78,68.47 34.29,68.98 37.59,68.98 37.85,68.73 37.85,67.71 37.72,67.58 37.34,67.58 37.08,67.33 37.08,65.8 36.44,65.16 ; 2 cut-outs
AUD_AGND on TOP: 4.83,9.67 4.57,9.92 4.57,16.66 3.94,17.29 2.29,17.29 2.16,17.42 2.16,18.18 2.29,18.31 4.83,18.31 6.1,19.58 9.91,19.58 11.05,18.43 12.83,18.43 13.59,19.2 13.59,19.45 13.84,19.7 14.1,19.7 14.35,19.45 14.35,18.18 13.84,17.67 8.76,17.67 6.22,15.13 6.22,9.92 5.97,9.67 ; 1 cut-out
AUD_AGND on TOP: 18.8,24.28 18.54,24.53 18.54,26.31 18.29,26.56 17.53,26.56 17.14,26.94 17.14,27.07 15.49,28.72 15.37,28.72 13.97,30.12 5.59,30.12 5.33,30.37 5.33,31.39 14.61,31.39 16.64,29.36 17.27,29.36 19.18,27.45 19.18,25.8 19.68,25.29 19.68,24.4 19.56,24.28 ; 2 cut-outs
AUD_AGND on BOTTOM: 4.95,10.56 4.57,10.94 4.57,11.45 5.33,12.21 5.33,12.34 5.46,12.46 5.84,12.46 6.22,12.08 6.22,10.81 5.97,10.56
AUD_AGND on L2SGND: 5.46,31.39 14.61,31.39 16.64,29.36 17.27,29.36 19.18,27.45 19.18,25.8 19.68,25.29 22.23,25.29 22.99,24.53 22.99,24.4 23.11,24.28 23.11,21.35 22.86,21.1 21.21,21.1 20.95,20.85 20.95,16.15 21.46,15.64 22.23,15.64 22.48,15.39 22.48,14.75 21.21,13.48 21.21,11.7 20.95,11.45 18.67,11.45 18.41,11.7 18.41,14.37 17.02,15.77 16.76,15.77 14.99,17.54 8.89,17.54 6.22,14.88 6.22,10.18 5.97,9.92 4.83,9.92 4.57,10.18 4.57,16.53 3.81,17.29 2.29,17.29 2.03,17.54 2.03,19.32 2.41,19.7 13.72,19.7 14.22,20.21 14.22,21.35 13.84,21.74 13.84,26.43 14.22,26.82 14.22,27.83 13.46,28.59 13.46,29.1 12.95,29.61 6.1,29.61 5.33,30.37 5.33,31.26
AUD_AGND on L3SGND: 22.99,24.4 22.99,21.35 22.73,21.1 21.34,21.1 20.95,20.72 20.95,16.15 21.34,15.77 22.35,15.77 22.61,15.51 22.61,15 21.21,13.61 21.21,11.7 20.95,11.45 18.8,11.45 18.54,11.7 18.54,14.37 17.14,15.77 16.64,15.77 14.86,17.54 8.89,17.54 6.22,14.88 6.22,10.18 5.84,9.8 4.83,9.8 4.57,10.05 4.57,16.66 3.94,17.29 2.41,17.29 2.16,17.54 2.16,19.32 2.41,19.58 13.46,19.58 14.22,20.34 14.22,21.35 13.84,21.74 13.84,26.43 14.22,26.82 14.22,27.83 12.57,29.48 4.83,29.48 4.57,29.74 4.57,29.86 6.1,31.39 14.61,31.39 16.64,29.36 17.14,29.36 19.05,27.45 19.05,25.8 19.68,25.16 22.23,25.16
AUD_AGND on L5GND, L7GND: 4.78,9.73 4.51,10 4.51,16.61 3.89,17.23 1.96,17.23 1.96,19.74 13.15,19.74 14.12,20.49 13.66,21.62 13.66,26.43 14.12,27.56 13.15,28.31 2.76,28.31 2.76,29.99 4.2,29.99 4.91,30.29 5.21,31 5.21,31.45 14.65,31.45 16.69,29.42 17.32,29.42 19.24,27.5 19.24,25.85 19.73,25.35 22.27,25.35 23.05,24.58 23.05,21.18 22.91,21.04 21.38,21.04 21.02,20.67 21.02,16.2 21.38,15.83 22.53,15.83 22.67,15.69 22.67,14.83 21.27,13.43 21.27,11.55 21.02,11.38 18.75,11.38 18.35,11.78 18.35,14.32 17.1,15.58 16.72,15.58 14.68,17.61 9.07,17.61 6.29,14.83 6.29,10.13 5.89,9.73
AUD_RING on TOP: 15.9,19.78 15.75,19.93 15.75,20.49 15.9,20.64 16.28,20.64 16.38,20.54 17.25,20.54 17.32,20.47 17.32,19.98 17.27,19.93 16.46,19.93 16.31,19.78
AUD_RING on BOTTOM: 4.7,11.96 4.57,12.08 4.57,13.99 4.7,14.12 5.08,14.12 5.21,13.99 5.21,12.34 4.83,11.96
AUD_SELEEVE on TOP: 18.8,18.05 18.41,18.43 15.49,18.43 14.48,19.45 14.48,24.28 14.86,24.66 16.38,24.66 16.51,24.53 16.51,23.77 15.49,22.75 15.49,19.83 15.75,19.58 16.51,19.58 16.64,19.7 17.27,19.7 17.27,19.32 17.4,19.2 18.54,19.2 19.43,18.31 20.35,18.31 20.37,18.33 21.06,18.33 21.08,18.31 21.08,18.15 21.06,18.13 20.17,18.13 20.09,18.05
AUD_SELEEVE on BOTTOM: 15.37,23.39 15.24,23.51 15.24,26.05 15.49,26.31 16.51,26.31 16.64,26.18 16.64,25.67 16.26,25.29 16.26,23.51 16.13,23.39 ; 1 cut-out
AUD_SPK_L+ on TOP: 22.86,7.64 22.61,7.89 22.61,8.4 22.86,8.65 25.15,8.65 25.65,8.15 25.65,7.77 25.53,7.64 ; 2 cut-outs
AUD_SPK_R+ on TOP: 20.7,2.69 20.45,2.94 20.45,4.84 20.57,4.97 21.21,4.97 21.34,4.84 21.34,2.94 21.08,2.69 ; 2 cut-outs
AUD_SPK_R- on TOP: 18.16,2.56 18.03,2.69 18.03,4.72 18.29,4.97 19.43,4.97 19.56,4.84 19.56,2.81 19.3,2.56 ; 2 cut-outs
BT+ on TOP: 153.09,12.06 152.68,12.46 152.68,14.01 152.88,14.22 157.25,14.22 157.51,13.96 157.51,12.59 156.97,12.06
BT+ on BOTTOM: 153.42,12.21 151.64,13.99 149.48,13.99 149.33,14.14 149,14.14 148.97,14.12 148.41,14.12 148.26,14.27 147.14,14.27 146.86,13.99 145.16,13.99 144.91,14.24 144.91,18.69 145.16,18.94 156.08,18.94 156.34,18.69 156.34,12.59 155.96,12.21 ; 5 cut-outs
DCBATOUT on TOP: 110.11,102.76 109.98,102.89 109.98,104.16 110.87,105.05 111.12,105.05 111.51,104.67 111.51,102.89 111.38,102.76 ; 1 cut-out
DCBATOUT on TOP: outline of 94 points within 35.56,15.89 170.69,69.23 ; 31 cut-outs
DCBATOUT on BOTTOM: 53.34,87.01 52.7,87.65 52.7,90.57 56.39,90.57 56.52,90.44 56.52,89.17 56.26,88.92 55.24,88.92 54.86,88.54 54.86,87.27 54.61,87.01
DCBATOUT on BOTTOM: 136.4,14.5 136.27,14.62 136.27,17.16 136.65,17.54 137.29,17.54 139.19,19.45 141.22,19.45 141.35,19.32 141.35,15.64 140.21,14.5
DCBATOUT on BOTTOM: 168.15,51.2 167.64,51.71 167,51.71 166.62,52.09 166.62,54.25 167,54.63 167,58.18 168.02,59.2 168.91,59.2 169.16,58.95 169.16,57.3 168.28,56.41 168.28,52.85 168.4,52.72 168.66,52.72 169.04,52.34 169.04,51.33 168.91,51.2 ; 4 cut-outs
DCBATOUT on BOTTOM: 126.11,27.07 126.01,27.17 126.01,27.58 126.24,27.81 126.24,28.47 126.36,28.59 130.05,28.59 130.68,27.96 130.68,27.17 130.58,27.07 ; 1 cut-out
DCBATOUT on BOTTOM: 45.44,45.74 45.34,45.84 45.34,52.72 45.59,52.98 47.93,52.98 50.04,55.09 50.04,63.01 50.99,63.96 50.99,65.61 50.29,66.31 50.29,68.73 49.66,69.36 49.66,70.76 50.42,71.52 53.59,71.52 53.98,71.14 54.48,71.14 54.61,71.01 54.61,70 54.48,69.87 54.48,66.69 54.61,66.57 55.24,66.57 55.37,66.44 55.37,63.39 54.99,63.01 53.09,63.01 52.83,62.76 52.83,59.23 54.6,57.46 54.6,54.95 55.24,54.3 55.24,54.25 55.75,53.74 55.75,52.22 55.37,51.83 52.1,51.83 52.08,51.82 51.93,51.82 51.46,51.35 51.46,50.95 49.78,49.27 49.76,49.27 46.23,45.74 ; 7 cut-outs
DCBATOUT on BOTTOM: 156.97,29.86 156.84,29.99 156.84,31.9 157.23,32.28 158.37,32.28 158.75,31.9 158.75,29.99 158.62,29.86 ; 2 cut-outs
DCBATOUT on BOTTOM: 148.72,105.81 148.21,106.32 148.21,107.97 148.34,108.1 148.97,108.1 149.86,107.21 149.86,106.06 149.61,105.81
DCBATOUT on BOTTOM: 51.44,20.21 50.93,20.72 50.93,24.28 50.94,24.29 50.94,26.57 51.44,27.07 57.07,27.07 57.2,26.94 57.2,25.47 56.13,24.4 56.13,20.21 ; 2 cut-outs
DCBATOUT on L2SGND: 136.4,15.77 139.32,15.77 139.57,16.02 139.57,20.21 139.06,20.72 139.06,28.21 135.64,31.64 89.79,31.64 89.03,30.88 56.64,30.88 51.82,26.05 51.82,23.51 52.58,22.75 55.37,22.75 56.13,23.51 56.13,25.67 58.29,27.83 105.79,27.83 106.55,28.59 125.86,28.59 129.67,24.78 132.08,24.78 133.6,23.26 133.6,18.56
DCBATOUT on L4SGND: 54.23,87.78 54.86,87.78 54.99,87.65 54.99,80.03 54.74,79.77 54.23,79.77 53.98,80.03 53.98,87.52
DCBATOUT on L4SGND: 167.28,59.02 167.28,57.27 167.56,56.99 169.98,56.99 170.23,57.24 170.23,69.59 168.86,70.96 168.86,82.44 163.25,88.05 163.25,98.34 154.58,107 150.24,107 149.5,107.74 148.44,107.74 148.34,107.64 148.34,105.05 148.77,104.62 153.09,104.62 159.54,98.16 159.54,87.39 164.77,82.16 164.77,67.2 165.96,66.01 165.96,62.38 167.67,60.67 168.5,60.67 168.66,60.52 168.66,59.38 168.48,59.2 167.46,59.2
DCBATOUT_CAMERA on BOTTOM: 112.27,96.92 110.87,98.32 110.87,99.84 111.12,100.09 111.12,100.48 111.25,100.6 111.63,100.6 111.76,100.48 111.76,99.08 113.03,97.81 114.17,97.81 114.3,97.68 114.3,97.05 114.17,96.92
JGND on TOP: 25.15,75.2 24.51,75.84 22.35,75.84 22.23,75.96 22.23,77.62 23.5,78.89 26.8,78.89 26.92,78.76 26.92,77.87 26.42,77.36 26.42,75.33 26.29,75.2 ; 3 cut-outs
JGND on BOTTOM: 22.35,75.84 22.23,75.96 22.23,79.9 22.35,80.03 24.77,80.03 24.89,79.9 24.89,78.5 25.65,77.74 25.65,75.96 25.53,75.84 ; 2 cut-outs
PS_ID_R2 on TOP: 53.72,14.37 53.59,14.5 53.59,16.15 53.72,16.27 55.63,16.27 55.88,16.02 55.88,14.5 55.75,14.37 ; 3 cut-outs
PWR_1D0V_PH on BOTTOM: 174.88,54.5 174.75,54.63 174.75,55.14 174.88,55.26 174.88,57.42 174.75,57.55 173.99,57.55 173.74,57.8 173.74,65.04 174.75,66.06 178.31,66.06 178.56,65.8 178.56,61.49 178.44,61.36 176.91,61.36 176.4,60.85 176.4,59.96 176.28,59.84 175.39,59.84 175.13,59.58 175.13,58.57 175.39,58.31 175.77,58.31 175.9,58.18 175.9,54.76 175.64,54.5 ; 1 cut-out
PWR_2D5V on BOTTOM: 136.65,26.18 136.4,26.43 136.4,27.83 136.53,27.96 137.92,27.96 138.18,28.21 138.18,28.85 138.05,28.97 136.91,28.97 136.78,29.1 136.78,29.61 137.03,29.86 137.41,29.86 137.67,30.12 137.67,31.51 137.92,31.77 139.57,31.77 140.02,31.32 140.02,27.77 138.43,26.18 ; 6 cut-outs
PWR_3D3V on BOTTOM: 112.01,19.07 111.76,19.32 111.76,25.42 111.89,25.55 115.82,25.55 115.95,25.67 115.95,26.05 116.2,26.31 119,26.31 119.13,26.18 119.13,25.8 118.87,25.55 118.87,19.83 118.75,19.7 113.54,19.7 112.9,19.07 ; 12 cut-outs
PWR_3D3V_LDO on BOTTOM: 124.46,19.45 124.33,19.58 124.33,20.85 124.41,20.92 125.63,20.92 125.65,20.9 125.65,20.54 125.17,20.06 125.17,19.55 125.07,19.45
PWR_3D3V_PH on BOTTOM: 120.8,19.14 120.7,19.25 120.7,23.39 120.93,23.61 123.93,23.61 125.63,21.91 125.63,21.56 125.6,21.53 124.33,21.53 123.79,20.99 123.79,19.23 123.7,19.14
PWR_5V on TOP: 75.95,19.83 75.49,20.29 75.49,23.82 75.56,23.89 78.36,23.89 78.49,23.77 78.49,19.96 78.36,19.83
PWR_5V on BOTTOM: 71.63,19.2 71.5,19.32 71.5,23.77 73.41,25.67 79.12,25.67 79.12,25.16 78.99,25.04 78.61,25.04 78.49,24.91 78.49,19.45 78.23,19.2 ; 8 cut-outs
PWR_5V_LDO on BOTTOM: 64.31,21.94 64.26,21.99 64.26,24.02 63.75,24.53 63.75,25.29 63.88,25.42 64.64,25.42 64.9,25.16 64.9,25.09 65,24.99 65,23.21 64.54,22.75 64.54,22.04 64.44,21.94
PWR_5V_PH on BOTTOM: 66.04,18.46 64.34,20.16 64.34,20.52 64.36,20.54 65.63,20.54 66.18,21.09 66.18,22.84 66.27,22.93 69.16,22.93 69.27,22.83 69.27,18.69 69.04,18.46
PWR_5V_VCC on BOTTOM: 64.34,21.15 64.31,21.18 64.31,21.53 64.8,22.01 64.8,22.52 64.9,22.62 65.84,22.62 65.86,22.6 65.86,21.3 65.71,21.15
PWR_CHG_HG1_R on TOP: 42.55,62.63 42.42,62.76 42.42,65.3 42.55,65.42 43.31,65.42 43.43,65.3 43.43,62.88 43.18,62.63
PWR_CHG_HG2_R on TOP: 44.7,54.25 44.58,54.37 44.58,56.28 45.47,57.17 46.99,57.17 47.12,57.04 47.12,56.41 46.86,56.15 45.97,56.15 45.85,56.03 45.85,54.37 45.72,54.25
PWR_CHG_LGATE1 on TOP: 42.67,55.64 42.16,56.15 42.16,56.91 42.8,56.91 43.56,56.15 43.56,55.9 43.31,55.64
